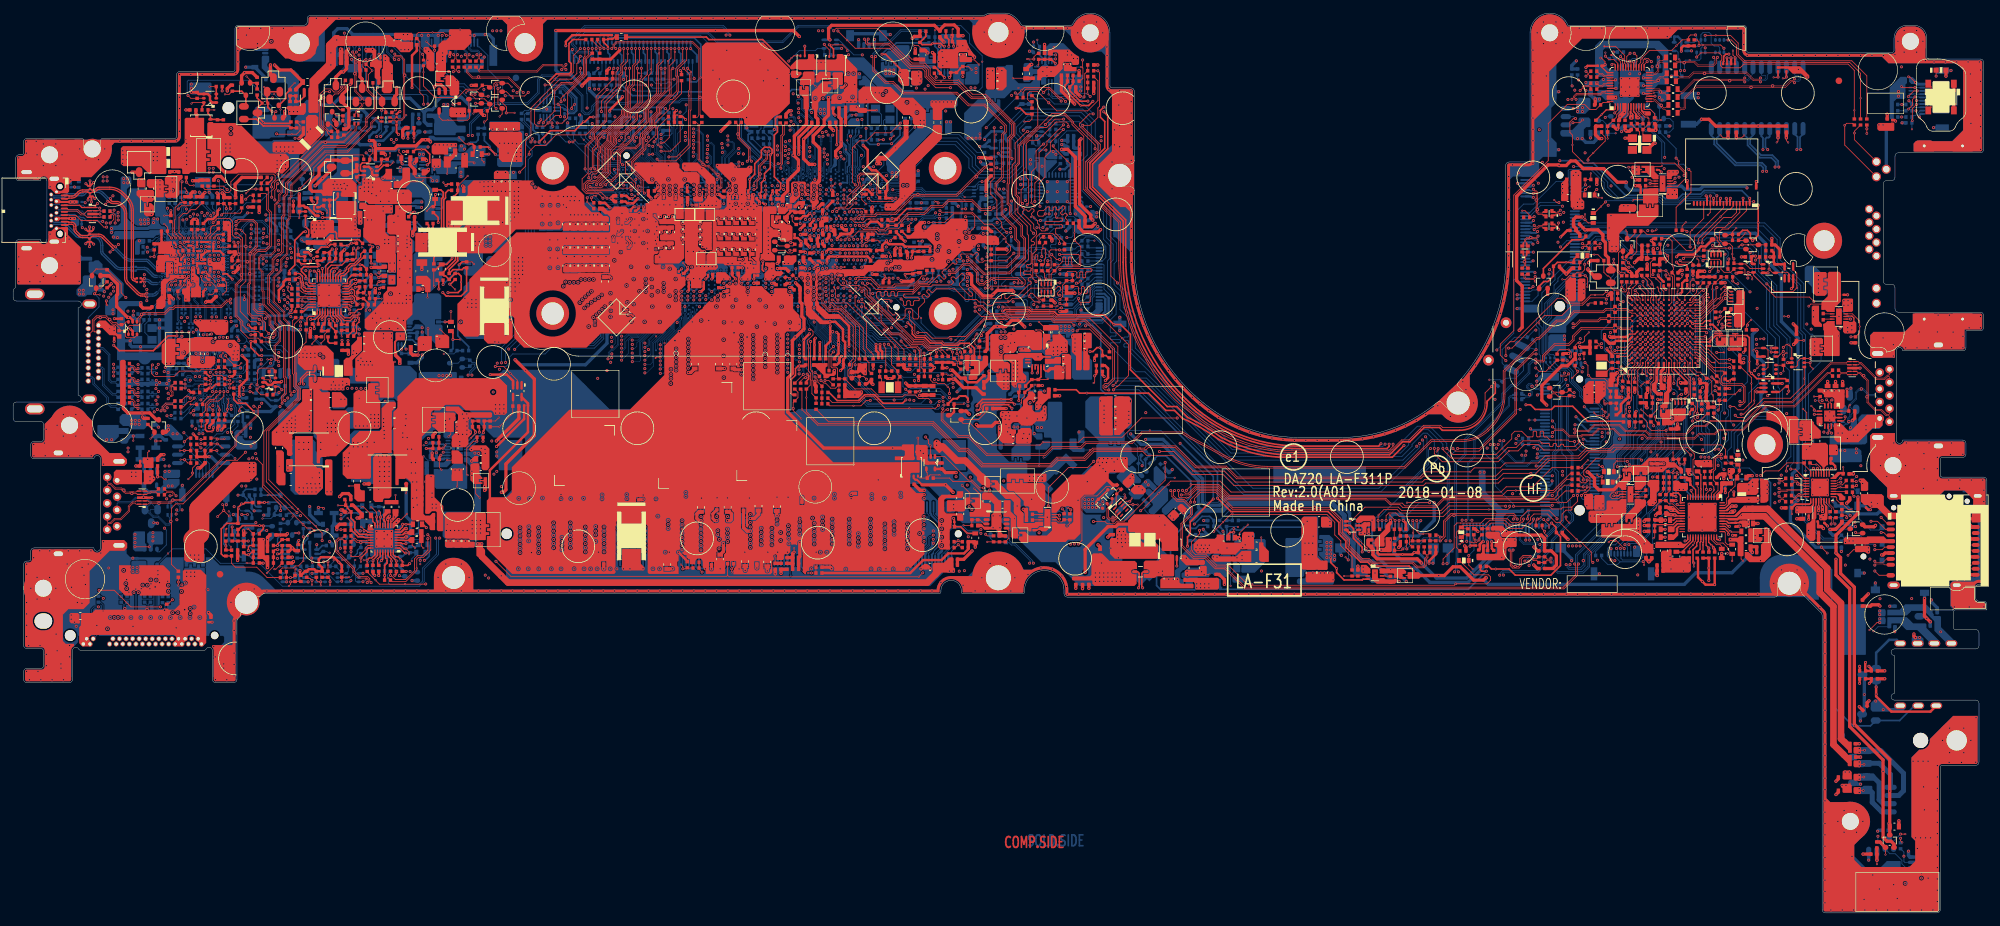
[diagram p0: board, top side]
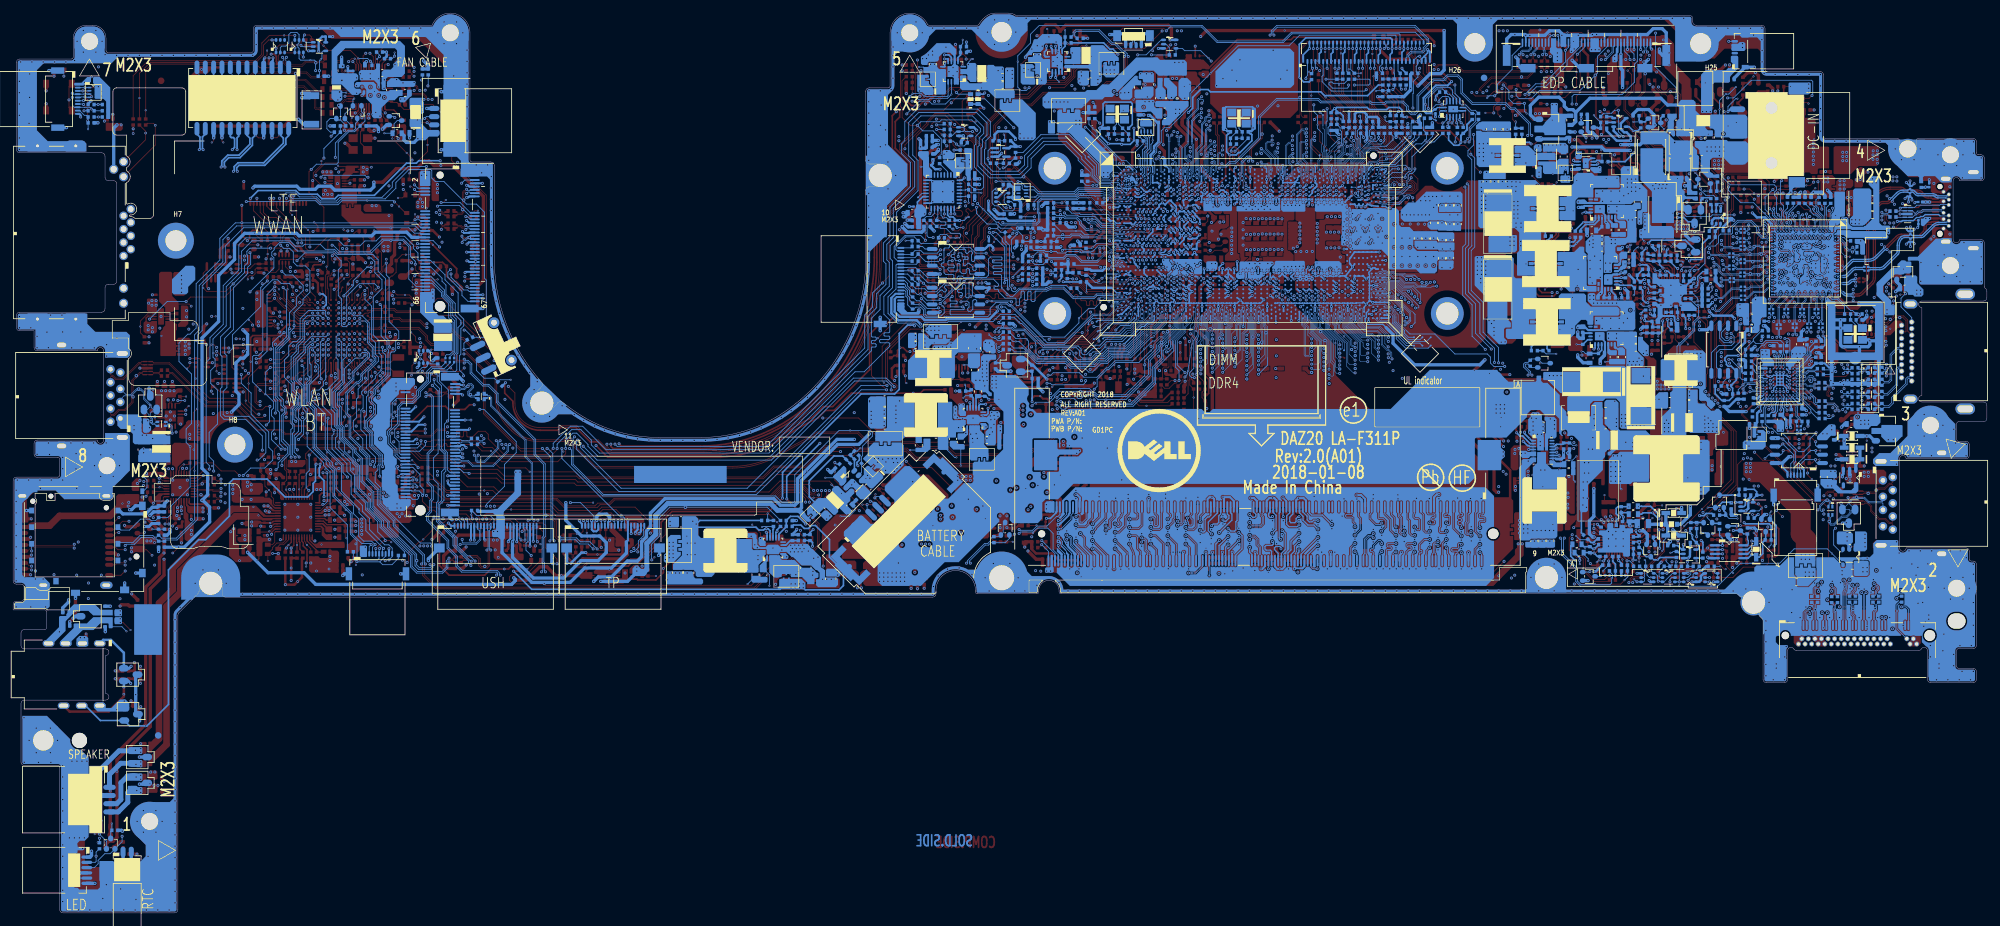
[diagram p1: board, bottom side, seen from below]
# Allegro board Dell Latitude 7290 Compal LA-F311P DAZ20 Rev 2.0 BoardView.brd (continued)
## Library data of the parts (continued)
PH601-PH605 PR1-PR8 PR10-PR12 PR14-PR18 PR24 PR27 PR28 PR30 PR102 PR103 PR107 PR108 PR113 PR116 PR117 PR204-PR207 PR209 PR212 PR302 PR306-PR308 PR310 PR311 PR403 PR404 PR407 PR408 PR410-PR422 PR424 PR427 PR428 PR501 PR505 PR506 PR514-PR517 PR601 PR604 PR605 PR608 PR610-PR613 PR615 PR617 PR618 PR621-PR623 PR626 PR628-PR636 PR638-PR653 PR656-PR658 PR666 PR668 PR670 PR671 PR673 PR675 PR677 PR678 PR681 PR686 PR689 PR692 PR918 PR919 PR925 PR927 PR930-PR934 PR940 PR944 PR945 PR948 PR950 PR953 PR961 PR1201-PR1203 PR1205-PR1210 PR1212-PR1214 PR1217 PR1219 PR1222 PR1224 PR1226-PR1237 PR1239 PR1240 PR1246-PR1249 PR1251-PR1255 PR1258-PR1262 RA5-RA9 RA12-RA14 RA17 RA18 RA44 RA45 RA50-RA53 RA57-RA61 RC1-RC7 RC10-RC12 RC14-RC17 RC19-RC23 RC25 RC27-RC32 RC39 RC42-RC48 RC50-RC52 RC54 RC56 RC57 RC59 RC60 RC65 RC67-RC69 RC71-RC75 RC77-RC84 RC86-RC96 RC109 RC110 RC112-RC115 RC120-RC124 RC126 RC128-RC141 RC152 RC153 RC157 RC161 RC163 RC165-RC168 RC175-RC178 RC183 RC184 RC186 RC187 RC189 RC190 RC211 RC214 RC215 RC217-RC220 RC222-RC225 RC227 RC234 RC237 RC239-RC241 RC243 RC267 RC268 RC272 RC278 RC279 RC282 RC283 RC287 RC288 RC291 RC292 RC297 RC298 RC311 RC313 RC316-RC319 RC323 RC324 RC330 RC331 RC338 RC344-RC349 RC362 RC363 RC366-RC369 RC371 RC372 RC387 RC400-RC403 RC405 RC407-RC415 RC417-RC420 RC431-RC433 RC436-RC438 RC440 RC442 RC443 RC445 RC550 RC553-RC556 RC560 RC561 RD4 RD6 RD8 RD11 RD14-RD19 RE5 RE8 RE10-RE12 RE20 RE21 RE25 RE26 RE31 RE33 RE35 RE37 RE38 RE43 RE48 RE51 RE55-RE58 RE60 RE63-RE65 RE67-RE75 RE77 RE79 RE83-RE86 RE91 RE92 RE94 RE95 RE274 RE280 RE288 RE292 RE300-RE304 RE306 RE308 RE312-RE314 RE324 RE340 RE342 RE343 RE349 RE350 RE362 RE365 RE375 RE505 RE507 RE508 RE526 RE532 RE539 RE541 RE543 RE546 RE547 RE549-RE551 RE560 RE561 RE565 RI13 RI14 RL1 RL2 RL4-RL6 RL9 RL11-RL20 RL29 RL30 RL70 RN37 RN100 RR3 RR4 RR19 RT1-RT8 RT10-RT39 RT41 RT42 RT50-RT53 RT64-RT69 RT71 RT74-RT76 RT81 RT82 RT84-RT86 RT89 RT90 RT95-RT98 RT100 RT101 RT103 RT106 RT107 RT110 RT111 RT124-RT129 RT336-RT339 RT371 RT372 RT377 RT391 RT393 RT400 RT401 RV1-RV8 RV10-RV23 RV26 RV29 RV32 RV35 RV324 RV326 RV400 RZ8-RZ10 RZ18-RZ23 RZ25 RZ28 RZ32 RZ38 RZ40 RZ43 RZ58-RZ60 RZ62 RZ63 RZ65 RZ69-RZ71 RZ76-RZ81 RZ114 RZ116 RZ117 RZ119 RZ132 RZ320 RZ326 RZ334 RZ335 RZ361-RZ364 RZ366 RZ367 RZ369 RZ380 RZ518 = R_0402
PJP1 PJP2 PJP4 PJP6 PJP7 PJP13 PJP15 PJP16 PJP18-PJP22 PJP35 PJP37 PJP38 PJP42 PJP201 PJP391 PJP403 PJP404 PJP501 PJP502 PJP505 PJP506 PJP603 = JUMP_43X39
PJP3 PJP8 PJP31 PJP39 PJP41 PJP102 PJP103 PJP200 PJP302 PJP601 PJP1202 = JUMP_43X118
PJP5 PJP14 PJP17 PJP36 PJP40 PJP100 PJP101 PJP202 PJP301 PJP401 PJP402 PJP602 = JUMP_43X79
PJP901 = JUMP_43X118-NPM
PJPDC1 = CVILU_CI0805M1HRC-NH_5P-T
PL1 PL2 PL4 = TAIYO_FBMJ4516HS720NT_2P
PL3 = MURAT_BLM15AG102SN1D_2P
PL100 PL101 = CYNTE_PCMC063T-1R5MN_2P
PL201 = CYNTE_PCMB063T-1R0MS_2P
PL301 = L_5X5X3_M_2P
PL402 PL404 PL501 = MAG_MLV-FY12N1R0M-O1L_2P
PL405 PL406 PL502 = 3A_Z120_0603_2P
PL602 = 9A_Z80_1812_2P-NPM
PL610 PL612 PL613 = L_7X7X3_M
PL614 = MAG_MMD05CZR47M_4P
PL901 = MAGLA_MMD-05CZ-1R0M-M7L_2P
PL902 = CYNTE_PCMB103T-2R2MS_2P
PQ1 PQ1201 PQ1204 PQ1209 PQ1214 QC2 QE2 QL1 QL2 QV3 QZ2 QZ7 = DMN65D8LDW-7_SOT363-6
PQ2 = FDV301N-G_SOT23-3
PQ3 = MMST3904-7-F_SOT323-3
PQ4 PQ9 PQ1202 PQ1206 PQ1213 = FDMC6679AZ_MLP8-5
PQ5 PQ1203 PQ1215 = NTR4502PT1G_SOT23-3
PQ6-PQ8 PQ909 PQ1205 PQ1212 PQ1216 = DMN65D8LW-7_SOT323-3
PQ614 = AON7934_DFN3X3A8-10
PQ904 = AON6970_DFN5X6D-8-7
PQ905 = AON6992_DFN5X6D-8-7
PQ906 = AON7409_DFN8-5
PQ1207 PQ1208 PQ1210 PQ1211 QT1 = DMN66D0LDW-7_SOT363-6
PR13 PR916 = R_0805
PR19-PR23 PR25 PR26 PR29 PR104 PR105 PR114 PR119 PR120 PR208 PR210 PR312 PR402 PR406 PR423 PR425 PR426 PR504 PR513 PR602 PR603 PR606 PR614 PR616 PR620 PR625 PR659 PR662 PR664 PR679 PR687 PR920 PR922 PR926 PR928 PR929 PR935 PR936 PR939 PR941 PR942 PR946 PR947 PR951 PR960 PR1211 PR1215 PR1216 PR1218 PR1220 PR1221 PR1223 PR1225 PR1238 PR1241-PR1245 PR1250 PR1257 RA35-RA39 RA48 RA54-RA56 RC33-RC38 RC40 RC41 RC62 RC170 RC171 RC173 RC212 RC221 RC228-RC231 RC235 RC244 RC290 RC296 RC300-RC308 RC325 RC328 RC337 RC373 RC374 RC376-RC378 RC439 RC441 RC444 RD5 RD7 RD9 RD12 RE30 RE32 RE59 RE90 RE275 RE290 RE318 RE506 RE536 RE548 RE552 RL3 RL7 RL34 RN99 RR5-RR10 RT9 RT40 RT54-RT60 RT63 RT70 RT72 RT73 RT83 RT87 RT88 RT92 RT93 RT99 RT104 RT105 RT108 RT109 RT120-RT123 RT341 RT342 RT392 RT394 RT402 RT403 RV323 RZ26 RZ29 RZ56 RZ61 RZ64 RZ85 RZ87 RZ89 RZ112 RZ120 RZ345-RZ347 RZ365 RZ368 = R0402_0OHM
PR100 PR111 PR203 PR304 RA3 RC143 RC169 RC216 RC299 RC309 RC310 RD10 RL8 RR274 = R0603_0OHM
PR106 PR112 PR202 PR303 PR627 PR663 PR669 PR676 PR923 PR924 = R_1206
PR405 PR409 PR502 PR619 PR624 PR660 PR661 PR665 PR667 PR672 PR674 PR680 PR688 PR691 PR909 PR910 PR914 PR915 PR921 PR937 PR938 PR943 RL71-RL78 RT48 RT49 RZ151 RZ370 = R_0603
PR682-PR684 = SOLDER_PREFORMS_0603
PR901 PR917 = R_1206_4P-D
PRP1 RPC1 RPC3 RPC4 RPE7 RPE9-RPE12 = RP_0804_8P4R
PT1 T1-T4 T9-T17 T50 T51 T88 T89 T113-T115 T120 T122 T123 T126 T127 T130 T132 T141-T144 T147 T219 T220 T225 T226 T258 T262 T264 T268 T269 T283 = TPC12
PU1 PU903 PU1200 UC7 UE3 UE5 UL2 UZ6 UZ10 UZ34 UZ35 = TC7SH08FU_SSOP5
PU2 UT8 = AP2204R-5P0TRG1_SOT89-3
PU100 = SY8288BRAC_QFN20_3X3
PU102 = SY8288CRAC_QFN20_3X3
PU200 = SY8210AQVC_QFN19_4X3
PU301 = SY8288RAC_QFN20_3X3
PU401 PU402 = SY8057QDC_QFN16_3X3
PU501 = RT8097ALGE_SOT23-6
PU503 = AP7361C-FGE-7_U-DFN3030-8_3X3
PU602 = ISL62883CHRTZ-T_TQFN40_5X5-S
PU610 PU612 PU613 = NCP302045MNTWG_PQFN33_5X5
PU614 = ISL95808HRZ-TS2378_DFN8_2X2-S
PU901 = ISL88738HRTZ-T_TQFN32_4X4
PU1201 = LM393DGKR_VSSOP8
QC6 QE11 QE12 QE17 QR1 QV2 QV4 QV5 QV7 QZ4 QZ15 = L2N7002WT1G_SC-70-3
QC7 QE15 QV8 QZ1 = LP2301ALT1G_SOT23-3
QE3-QE7 = MMBT3904WT1G_SC70-3
QV1 = AO6405_TSOP6
QZ3 = DDTA114EUA-7-F_SOT323-3
RE93 RZ128-RZ130 = R_0201
RI27-RI30 RI47-RI50 = R_0402-NPM
SHDCAN = SION_SUS304_1P-T
SW1 = SW_SS3-CMFTQR9_3P
SW3 = SW_SKRBAAE010_4P
TL1 = MHPC_NS692417_24P
UA1 = ALC3246-CG_MQFN48_6X6
UC1 = KBL-RU42_BGA_1356P-T
UC5 = W25Q128FVSIQ_SO8
UC6 = W25Q128FVSIQ_SO8-NPM
UC8 = 74CBTLV3126BQ_DHVQFN14_2P5X3-S
UC12 = 74AHC1G09GW_TSSOP5
UD1 UE4 UE6 = 74AUP1G07GW_TSSOP5
UE1 = MEC5105_WFBGA_169P
UI1 = SY6288D20AAC_SOT23-5
UI3 = SLGC55544CVTR_TQFN16_3X3
UL1 = WGI217LM-QPN9-A2_QFN48_6X6-S
UR1 = RTS5242-GR_QFN32_4X4-S
UT1 = ALPINE-RIDGE_BGA_337P
UT2 UT6 = W25Q80DVSSIG_SO8
UT5 = TPS65982_BGA_96P
UT7 = AP2112K-3P3TRG1_SOT23-5
UV2 = AP2330W-7_SC59-3
UV24 = G524B1T11U_SOT23-5
UZ2-UZ5 = TPS22966DPUR_SON14_2X3
UZ8 = AOZ1336_DFN8_2X2
UZ12 = NPCT650JB2YX_QFN32_5X5
UZ19 UZ21 UZ26 = TPS22961DNYR_WSON8
YC1 YC3 = Y_X3G024000DC1H_4P
YC2 = Y_9H03200042_2P
YE1 = Y_X1A000141000200_2P
YL1 YT1 = Y_7V25000034_4P

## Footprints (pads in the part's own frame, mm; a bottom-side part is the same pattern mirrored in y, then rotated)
1N4148WS-7-F_SOD323-2
  rect 1.346x0.66 smd: 1(0,0) 2(2.4,0)
3A_Z120_0603_2P
  rect 0.991x0.787 smd: 1(0,0) 2(1.6,0)
9A_Z80_1812_2P-NPM
  rect 1.803x3.404 smd: 1(0,0) 2(3.8,0)
74AHC1G09GW_TSSOP5
  oval 0.381x1.346 smd: 1(0,0) 2(0.65,0) 3(1.3,0) 4(1.3,1.79) 5(0,1.79)
74AUP1G07GW_TSSOP5
  oval 0.381x1.346 smd: 1(0,0) 2(0.65,0) 3(1.3,0) 4(1.3,1.79) 5(0,1.79)
74CBTLV3126BQ_DHVQFN14_2P5X3-S
  oval 1.041x0.254 smd: 1(0,0) 7(2.95,0) 8(2.95,0.5) 14(0,0.5)
  oval 0.254x1.041 smd: 2(0.475,-0.975) 3(0.975,-0.975) 4(1.475,-0.975) 5(1.975,-0.975) 6(2.475,-0.975) 9(2.475,1.475) 10(1.975,1.475) 11(1.475,1.475) 12(0.975,1.475) 13(0.475,1.475)
  rect 1.499x0.991 smd: 15(1.475,0.25)
ACES_50209-0060N-P01_6P
  oval 0.508x1.651 smd: 1(0,0) 2(0.8,0) 3(1.6,0) 4(2.4,0) 5(3.2,0) 6(4,0)
  rect 1.194x1.702 smd: 7(-1.3,-2.275) 8(5.3,-2.275)
ACES_50271-0020N-001_2P
  oval 0.787x1.6 smd: 1(0,0) 2(1.25,0)
  rect 2.108x2.997 smd: 3(3.8,-2.9) 4(-2.55,-2.9)
ACES_50271-0040N-001_4P
  oval 0.787x1.6 smd: 1(0,0) 2(-1.25,0) 3(-2.5,0) 4(-3.75,0)
  rect 2.108x2.997 smd: 5(2.55,-2.9) 6(-6.3,-2.9)
ACES_50278-0040N-001_4P
  oval 0.787x1.905 smd: 1(0,0) 2(1.25,0) 3(2.5,0) 4(3.75,0)
  rect 1.295x3.353 smd: 5(-2.85,-4.925) 6(6.6,-4.925)
ACES_50398-04041-001_40P
  oval 0.254x1.295 smd: 1(0,0) 2(0.5,0) 3(1,0) 4(1.5,0) 5(2,0) 6(2.5,0) 7(3,0) 8(3.5,0) 9(4,0) 10(4.5,0) 11(5,0) 12(5.5,0) 13(6,0) 14(6.5,0) 15(7,0) 16(7.5,0) 17(8,0) 18(8.5,0) 19(9,0) 20(9.5,0) 21(10,0) 22(10.5,0) 23(11,0) 24(11.5,0) 25(12,0) 26(12.5,0) 27(13,0) 28(13.5,0) 29(14,0) 30(14.5,0) 31(15,0) 32(15.5,0) 33(16,0) 34(16.5,0) 35(17,0) 36(17.5,0) 37(18,0) 38(18.5,0) 39(19,0) 40(19.5,0)
  rect 1.194x3.2 smd: 41(-2.4,1.95) 45(21.9,1.95)
  rect 2.311x1.295 smd: 42(0.85,3.9) 43(9.75,3.9) 44(18.65,3.9)
ACES_50506-00641-P01_6P
  oval 0.305x0.889 smd: 1(0,0) 2(0.5,0) 3(1,0) 4(1.5,0) 5(2,0) 6(2.5,0)
  rect 0.991x2.007 smd: 7(-2.1,-3.05) 8(4.6,-3.05)
ACES_50506-01041-P01_10P
  oval 0.305x0.889 smd: 1(0,0) 2(0.5,0) 3(1,0) 4(1.5,0) 5(2,0) 6(2.5,0) 7(3,0) 8(3.5,0) 9(4,0) 10(4.5,0)
  rect 0.991x2.007 smd: 11(-2.1,-3.05) 12(6.6,-3.05)
ACON_HMRBL-A41L0F_19P-T
  round 0.813 hole 0.559: 1(0,0) 2(0.5,1.55) 3(1,0) 4(1.5,1.55) 5(2,0) 6(2.5,1.55) 7(3,0) 8(3.5,1.55) 9(4,0) 10(4.5,1.55) 11(5,0) 12(5.5,1.55) 13(6,0) 14(6.5,1.55) 15(7,0) 16(7.5,1.55) 17(8,0) 18(8.5,1.55) 19(9,0)
  oval 1.397x2.21 hole 0.787x1.6: 20(11.75,0.2) 22(-2.75,0.2)
  oval 1.702x2.997 hole 1.092x2.388: 21(13.25,-8.15) 23(-4.25,-8.15)
ACON_TCRA2-9U1U93_9P-T
  round 1.295 hole 0.711: 1(0,0) 2(-2.5,0) 3(-4.5,0) 4(-7,0) 5(-7.5,-1.5) 6(-5.5,-1.5) 7(-3.5,-1.5) 8(-1.5,-1.5) 9(0.5,-1.5)
  oval 1.295x2.311 hole 0.711x1.702: 10(2.9,0.3) 12(-9.9,0.3)
  oval 1.295x2.007 hole 0.711x1.397: 11(4.2,-8.95) 13(-11.2,-8.95)
ALC3246-CG_MQFN48_6X6
  oval 0.889x0.203 smd: 1(0,0) 2(0,-0.4) 3(0,-0.8) 4(0,-1.2) 5(0,-1.6) 6(0,-2) 7(0,-2.4) 8(0,-2.8) 9(0,-3.2) 10(0,-3.6) 11(0,-4) 12(0,-4.4) 25(6.1,-4.4) 26(6.1,-4) 27(6.1,-3.6) 28(6.1,-3.2) 29(6.1,-2.8) 30(6.1,-2.4) 31(6.1,-2) 32(6.1,-1.6) 33(6.1,-1.2) 34(6.1,-0.8) 35(6.1,-0.4) 36(6.1,0)
  oval 0.203x0.889 smd: 13(0.85,-5.25) 14(1.25,-5.25) 15(1.65,-5.25) 16(2.05,-5.25) 17(2.45,-5.25) 18(2.85,-5.25) 19(3.25,-5.25) 20(3.65,-5.25) 21(4.05,-5.25) 22(4.45,-5.25) 23(4.85,-5.25) 24(5.25,-5.25) 37(5.25,0.85) 38(4.85,0.85) 39(4.45,0.85) 40(4.05,0.85) 41(3.65,0.85) 42(3.25,0.85) 43(2.85,0.85) 44(2.45,0.85) 45(2.05,0.85) 46(1.65,0.85) 47(1.25,0.85) 48(0.85,0.85)
  rect 4.394x4.394 smd: 49(3.05,-2.2)
ALPINE-RIDGE_BGA_337P
  round 0.254 smd: A1(0,0) A23(10.12,0) AA2(0.46,-9.2) AA22(9.66,-9.2) AB2(0.46,-9.66) AB3(0.92,-9.66) AB4(1.38,-9.66) AB5(1.84,-9.66) AB6(2.3,-9.66) AB7(2.76,-9.66) AB8(3.22,-9.66) AB9(3.68,-9.66) AB10(4.14,-9.66) AB11(4.6,-9.66) AB12(5.06,-9.66) AB13(5.52,-9.66) AB14(5.98,-9.66) AB15(6.44,-9.66) AB16(6.9,-9.66) AB17(7.36,-9.66) AB18(7.82,-9.66) AB19(8.28,-9.66) AB20(8.74,-9.66) AB21(9.2,-9.66) AB22(9.66,-9.66) AC1(0,-10.12) AC23(10.12,-10.12) B2(0.46,-0.46) B3(0.92,-0.46) B4(1.38,-0.46) B5(1.84,-0.46) B6(2.3,-0.46) B7(2.76,-0.46) B8(3.22,-0.46) B9(3.68,-0.46) B10(4.14,-0.46) B11(4.6,-0.46) B12(5.06,-0.46) B13(5.52,-0.46) B14(5.98,-0.46) B15(6.44,-0.46) B16(6.9,-0.46) B17(7.36,-0.46) B18(7.82,-0.46) B19(8.28,-0.46) B20(8.74,-0.46) B21(9.2,-0.46) B22(9.66,-0.46) C2(0.46,-0.92) C22(9.66,-0.92) D2(0.46,-1.38) D4(1.16,-1.16) D5(1.81,-1.16) D6(2.46,-1.16) D8(3.11,-1.16) D9(3.76,-1.16) D11(4.41,-1.16) D12(5.06,-1.16) D13(5.71,-1.16) D15(6.36,-1.16) D16(7.01,-1.16) D18(7.66,-1.16) D19(8.31,-1.16) D20(8.96,-1.16) D22(9.66,-1.38) E2(0.46,-1.84) E4(1.16,-1.81) E5(1.81,-1.81) E6(2.46,-1.81) E8(3.11,-1.81) E9(3.76,-1.81) E11(4.41,-1.81) E12(5.06,-1.81) E13(5.71,-1.81) E15(6.36,-1.81) E16(7.01,-1.81) E18(7.66,-1.81) E19(8.31,-1.81) E20(8.96,-1.81) E22(9.66,-1.84) F2(0.46,-2.3) F4(1.16,-2.46) F5(1.81,-2.46) F6(2.46,-2.46) F8(3.11,-2.46) F9(3.76,-2.46) F11(4.41,-2.46) F12(5.06,-2.46) F13(5.71,-2.46) F15(6.36,-2.46) F16(7.01,-2.46) F18(7.66,-2.46) F19(8.31,-2.46) F20(8.96,-2.46) F22(9.66,-2.3) G2(0.46,-2.76) G22(9.66,-2.76) H2(0.46,-3.22) H4(1.16,-3.11) H5(1.81,-3.11) H6(2.46,-3.11) H8(3.11,-3.11) H9(3.76,-3.11) H11(4.41,-3.11) H12(5.06,-3.11) H13(5.71,-3.11) H15(6.36,-3.11) H16(7.01,-3.11) H18(7.66,-3.11) H19(8.31,-3.11) H20(8.96,-3.11) H22(9.66,-3.22) J2(0.46,-3.68) J4(1.16,-3.76) J5(1.81,-3.76) J6(2.46,-3.76) J8(3.11,-3.76) J9(3.76,-3.76) J11(4.41,-3.76) J12(5.06,-3.76) J13(5.71,-3.76) J15(6.36,-3.76) J16(7.01,-3.76) J18(7.66,-3.76) J19(8.31,-3.76) J20(8.96,-3.76) J22(9.66,-3.68) K2(0.46,-4.14) K22(9.66,-4.14) L2(0.46,-4.6) L4(1.16,-4.41) L5(1.81,-4.41) L6(2.46,-4.41) L8(3.11,-4.41) L9(3.76,-4.41) L11(4.41,-4.41) L12(5.06,-4.41) L13(5.71,-4.41) L15(6.36,-4.41) L16(7.01,-4.41) L18(7.66,-4.41) L19(8.31,-4.41) L20(8.96,-4.41) L22(9.66,-4.6) M2(0.46,-5.06) M4(1.16,-5.06) M5(1.81,-5.06) M6(2.46,-5.06) M8(3.11,-5.06) M9(3.76,-5.06) M11(4.41,-5.06) M12(5.06,-5.06) M13(5.71,-5.06) M15(6.36,-5.06) M16(7.01,-5.06) M18(7.66,-5.06) M19(8.31,-5.06) M20(8.96,-5.06) M22(9.66,-5.06) N2(0.46,-5.52) N4(1.16,-5.71) N5(1.81,-5.71) N6(2.46,-5.71) N8(3.11,-5.71) N9(3.76,-5.71) N11(4.41,-5.71) N12(5.06,-5.71) N13(5.71,-5.71) N15(6.36,-5.71) N16(7.01,-5.71) N18(7.66,-5.71) N19(8.31,-5.71) N20(8.96,-5.71) N22(9.66,-5.52) P2(0.46,-5.98) P22(9.66,-5.98) R2(0.46,-6.44) R4(1.16,-6.36) R5(1.81,-6.36) R6(2.46,-6.36) R8(3.11,-6.36) R9(3.76,-6.36) R11(4.41,-6.36) R12(5.06,-6.36) R13(5.71,-6.36) R15(6.36,-6.36) R16(7.01,-6.36) R18(7.66,-6.36) R19(8.31,-6.36) R20(8.96,-6.36) R22(9.66,-6.44) T2(0.46,-6.9) T4(1.16,-7.01) T5(1.81,-7.01) T6(2.46,-7.01) T8(3.11,-7.01) T9(3.76,-7.01) T11(4.41,-7.01) T12(5.06,-7.01) T13(5.71,-7.01) T15(6.36,-7.01) T16(7.01,-7.01) T18(7.66,-7.01) T19(8.31,-7.01) T20(8.96,-7.01) T22(9.66,-6.9) U2(0.46,-7.36) U22(9.66,-7.36) V2(0.46,-7.82) V4(1.16,-7.66) V5(1.81,-7.66) V6(2.46,-7.66) V8(3.11,-7.66) V9(3.76,-7.66) V11(4.41,-7.66) V12(5.06,-7.66) V13(5.71,-7.66) V15(6.36,-7.66) V16(7.01,-7.66) V18(7.66,-7.66) V19(8.31,-7.66) V20(8.96,-7.66) V22(9.66,-7.82) W2(0.46,-8.28) W4(1.16,-8.31) W5(1.81,-8.31) W6(2.46,-8.31) W8(3.11,-8.31) W9(3.76,-8.31) W11(4.41,-8.31) W12(5.06,-8.31) W13(5.71,-8.31) W15(6.36,-8.31) W16(7.01,-8.31) W18(7.66,-8.31) W19(8.31,-8.31) W20(8.96,-8.31) W22(9.66,-8.28) Y2(0.46,-8.74) Y4(1.16,-8.96) Y5(1.81,-8.96) Y6(2.46,-8.96) Y8(3.11,-8.96) Y9(3.76,-8.96) Y11(4.41,-8.96) Y12(5.06,-8.96) Y13(5.71,-8.96) Y15(6.36,-8.96) Y16(7.01,-8.96) Y18(7.66,-8.96) Y19(8.31,-8.96) Y20(8.96,-8.96) Y22(9.66,-8.74)
  oval 0.178x0.33 smd: A2(0.46,0) A3(0.92,0) A4(1.38,0) A5(1.84,0) A6(2.3,0) A7(2.76,0) A8(3.22,0) A9(3.68,0) A10(4.14,0) A11(4.6,0) A12(5.06,0) A13(5.52,0) A14(5.98,0) A15(6.44,0) A16(6.9,0) A17(7.36,0) A18(7.82,0) A19(8.28,0) A20(8.74,0) A21(9.2,0) A22(9.66,0) AC2(0.46,-10.12) AC3(0.92,-10.12) AC4(1.38,-10.12) AC5(1.84,-10.12) AC6(2.3,-10.12) AC7(2.76,-10.12) AC8(3.22,-10.12) AC9(3.68,-10.12) AC10(4.14,-10.12) AC11(4.6,-10.12) AC12(5.06,-10.12) AC13(5.52,-10.12) AC14(5.98,-10.12) AC15(6.44,-10.12) AC16(6.9,-10.12) AC17(7.36,-10.12) AC18(7.82,-10.12) AC19(8.28,-10.12) AC20(8.74,-10.12) AC21(9.2,-10.12) AC22(9.66,-10.12)
  oval 0.33x0.178 smd: AA1(0,-9.2) AA23(10.12,-9.2) AB1(0,-9.66) AB23(10.12,-9.66) B1(0,-0.46) B23(10.12,-0.46) C1(0,-0.92) C23(10.12,-0.92) D1(0,-1.38) D23(10.12,-1.38) E1(0,-1.84) E23(10.12,-1.84) F1(0,-2.3) F23(10.12,-2.3) G1(0,-2.76) G23(10.12,-2.76) H1(0,-3.22) H23(10.12,-3.22) J1(0,-3.68) J23(10.12,-3.68) K1(0,-4.14) K23(10.12,-4.14) L1(0,-4.6) L23(10.12,-4.6) M1(0,-5.06) M23(10.12,-5.06) N1(0,-5.52) N23(10.12,-5.52) P1(0,-5.98) P23(10.12,-5.98) R1(0,-6.44) R23(10.12,-6.44) T1(0,-6.9) T23(10.12,-6.9) U1(0,-7.36) U23(10.12,-7.36) V1(0,-7.82) V23(10.12,-7.82) W1(0,-8.28) W23(10.12,-8.28) Y1(0,-8.74) Y23(10.12,-8.74)
AO6405_TSOP6
  oval 0.508x1.473 smd: 1(0,0) 2(0.95,0) 3(1.9,0) 4(1.9,2.35) 5(0.95,2.35) 6(0,2.35)
AON6970_DFN5X6D-8-7
  oval 0.66x0.635 smd: 1(0,0) 3(3.81,5.67) 4(2.54,5.67) 5(1.27,5.67) 6(0,5.67)
  custom 0.485x0.485 smd: 2(1.905,0.655)
  rect 3.988x2.667 smd: 7(1.905,3.62)
AON6992_DFN5X6D-8-7
  oval 0.66x0.635 smd: 1(0,0) 3(3.81,5.67) 4(2.54,5.67) 5(1.27,5.67) 6(0,5.67)
  custom 0.485x0.485 smd: 2(1.905,0.655)
  rect 3.988x2.667 smd: 7(1.905,3.62)
AON7409_DFN8-5
  oval 0.406x0.991 smd: 1(0,0) 2(0.66,0) 3(1.32,0) 4(1.98,0)
  custom 0.559x0.559 smd: 5(0.99,2.247)
AON7934_DFN3X3A8-10
  oval 0.457x0.508 smd: 1(0,0) 2(0.65,0) 3(1.3,0) 4(1.95,0) 5(1.95,2.76) 6(1.3,2.76) 7(0.65,2.76) 8(0,2.76)
  rect 2.54x1.041 smd: 9(0.975,1.813)
  rect 2.54x0.559 smd: 10(0.975,0.708)
AOZ1336_DFN8_2X2
  oval 0.254x0.787 smd: 1(0,0) 2(0.5,0) 3(1,0) 4(1.5,0) 5(1.5,2.2) 6(1,2.2) 7(0.5,2.2) 8(0,2.2)
  rect 1.499x0.889 smd: 9(0.75,1.1)
AP2112K-3P3TRG1_SOT23-5
  oval 0.508x0.965 smd: 1(0,0) 2(0.95,0) 3(1.9,0) 4(1.9,2.375) 5(0,2.375)
AP2204R-5P0TRG1_SOT89-3
  oval 0.889x1.295 smd: 1(0,0) 3(3,0)
  custom 0.433x0.433 smd: 2(1.5,1.775)
AP2330W-7_SC59-3
  oval 0.787x0.991 smd: 1(0,0) 2(-0.95,-2.4) 3(0.95,-2.4)
AP7361C-FGE-7_U-DFN3030-8_3X3
  oval 0.457x0.94 smd: 1(0,0) 2(0.65,0) 3(1.3,0) 4(1.95,0) 5(1.95,3.05) 6(1.3,3.05) 7(0.65,3.05) 8(0,3.05)
  rect 2.261x1.499 smd: 9(0.975,1.525)
AZ5125-01HPR7G_SOD523-2
  rect 0.61x0.787 smd: 1(0,0) 2(1.5,0)
AZC199-02SPR7G_SOT23-3
  oval 1.016x1.524 smd: 1(0,0) 2(0.965,2.083) 3(-0.965,2.083)
BAT54CW_SOT323-3
  oval 0.711x0.889 smd: 1(0,0) 2(-0.65,-1.9) 3(0.65,-1.9)
BELLW_80149-3221_67P
  round 1.092 hole 1.092 unplated: (-0.75,-5.275)
  round 1.6 hole 1.6 unplated: (19.25,-5.275)
  oval 0.305x1.549 smd: 1(0,0) 2(0.25,-7.55) 3(0.5,0) 4(0.75,-7.55) 5(1,0) 6(1.25,-7.55) 7(1.5,0) 8(1.75,-7.55) 9(2,0) 10(2.25,-7.55) 11(2.5,0) 12(4.75,-7.55) 13(5,0) 14(5.25,-7.55) 15(5.5,0) 16(5.75,-7.55) 17(6,0) 18(6.25,-7.55) 19(6.5,0) 20(6.75,-7.55) 21(7,0) 22(7.25,-7.55) 23(7.5,0) 24(7.75,-7.55) 25(8,0) 26(8.25,-7.55) 27(8.5,0) 28(8.75,-7.55) 29(9,0) 30(9.25,-7.55) 31(9.5,0) 32(9.75,-7.55) 33(10,0) 34(10.25,-7.55) 35(10.5,0) 36(10.75,-7.55) 37(11,0) 38(11.25,-7.55) 39(11.5,0) 40(11.75,-7.55) 41(12,0) 42(12.25,-7.55) 43(12.5,0) 44(12.75,-7.55) 45(13,0) 46(13.25,-7.55) 47(13.5,0) 48(13.75,-7.55) 49(14,0) 50(14.25,-7.55) 51(14.5,0) 52(14.75,-7.55) 53(15,0) 54(15.25,-7.55) 55(15.5,0) 56(15.75,-7.55) 57(16,0) 58(16.25,-7.55) 59(16.5,0) 60(16.75,-7.55) 61(17,0) 62(17.25,-7.55) 63(17.5,0) 64(17.75,-7.55) 65(18,0) 66(18.25,-7.55) 67(18.5,0)
  rect 1.194x2.743 smd: 68(-1.1,-0.775) 69(19.6,-0.775)
BZV55-B5V1_SOD80C2
  rect 0.889x1.6 smd: 1(0,0) 2(3.3,0)
C_0201
  rect 0.381x0.356 smd: 1(0,0) 2(0.584,0)
C_0402
  rect 0.508x0.559 smd: 1(0,0) 2(0.914,0)
C_0603
  rect 0.635x0.889 smd: 1(0,0) 2(1.397,0)
C_0805
  rect 0.813x1.397 smd: 1(0,0) 2(1.702,0)
C_1206
  rect 1.016x1.778 smd: 1(0,0) 2(2.667,0)
C_1808
  rect 1.041x2.311 smd: 1(0,0) 2(4.35,0)
C_B2
  rect 1.346x2.692 smd: 1(0,0) 2(-2.75,0)
C_D
  rect 2.388x2.896 smd: 1(0,0) 2(6.1,0)
C_D2
  rect 2.388x2.794 smd: 1(0,0) 2(6.4,0)
C_D3
  rect 2.388x2.794 smd: 1(0,0) 2(6.4,0)
C_D7
  rect 1.803x2.794 smd: 1(0,0) 2(6.5,0)
CLIP_7P7X4P2
  rect 7.696x4.191 smd: 1(0,0)
CLIP_14P0X2P6
  rect 13.995x2.591 smd: 1(0,0)
CVILU_CF4218FH0R0-05-NH_18P-T
  oval 0.305x0.787 smd: 1(0,0) 2(0.5,0) 3(1,0) 4(1.5,0) 5(2,0) 6(2.5,0) 7(3,0) 8(3.5,0) 9(4,0) 10(4.5,0) 11(5,0) 12(5.5,0) 13(6,0) 14(6.5,0) 15(7,0) 16(7.5,0) 17(8,0) 18(8.5,0)
  rect 0.406x0.787 smd: 19(-1,-2.5) 20(9.5,-2.5)
CVILU_CF5020FD0R0-05-NH_20P
  oval 0.305x1.092 smd: 1(0,0) 2(0.5,0) 3(1,0) 4(1.5,0) 5(2,0) 6(2.5,0) 7(3,0) 8(3.5,0) 9(4,0) 10(4.5,0) 11(5,0) 12(5.5,0) 13(6,0) 14(6.5,0) 15(7,0) 16(7.5,0) 17(8,0) 18(8.5,0) 19(9,0) 20(9.5,0)
  rect 0.991x2.007 smd: 21(-2.1,-3.15) 22(11.6,-3.15)
CVILU_CF5020FD0RK-05-NH_20P-T
  oval 0.305x0.94 smd: 1(0,0) 2(0.5,0) 3(1,0) 4(1.5,0) 5(2,0) 6(2.5,0) 7(3,0) 8(3.5,0) 9(4,0) 10(4.5,0) 11(5,0) 12(5.5,0) 13(6,0) 14(6.5,0) 15(7,0) 16(7.5,0) 17(8,0) 18(8.5,0) 19(9,0) 20(9.5,0)
  rect 1.651x1.397 smd: 21(-2.325,-3.375) 22(11.825,-3.375)
CVILU_CF5026FD0RK-05-NH_26P-T
  oval 0.305x0.94 smd: 1(0,0) 2(0.5,0) 3(1,0) 4(1.5,0) 5(2,0) 6(2.5,0) 7(3,0) 8(3.5,0) 9(4,0) 10(4.5,0) 11(5,0) 12(5.5,0) 13(6,0) 14(6.5,0) 15(7,0) 16(7.5,0) 17(8,0) 18(8.5,0) 19(9,0) 20(9.5,0) 21(10,0) 22(10.5,0) 23(11,0) 24(11.5,0) 25(12,0) 26(12.5,0)
  rect 1.651x1.397 smd: 27(14.825,-3.375) 28(-2.325,-3.375)
CVILU_CI0805M1HRC-NH_5P-T
  round 1.803 hole 1.803 unplated: (-0.2,5.2) (8.2,5.2)
  oval 0.889x2.388 smd: 1(0,0) 2(2,0) 3(4,0) 4(6,0) 5(8,0)
  rect 1.6x2.489 smd: 6(11.15,9.05) 7(-3.15,9.05)
CVILU_CI1804M1VRA-NH_4P
  oval 0.508x0.991 smd: 1(0,-0.05) 2(-0.8,-0.05) 3(-1.6,-0.05) 4(-2.4,-0.05)
  rect 1.194x1.702 smd: 5(-3.7,1.4) 6(1.3,1.4)
CYNTE_PCMB063T-1R0MS_2P
  rect 2.362x3.505 smd: 1(0,0) 2(6.05,0)
CYNTE_PCMB103T-2R2MS_2P
  rect 3.81x3.988 smd: 1(0,0) 2(9.2,0)
CYNTE_PCMC063T-1R5MN_2P
  rect 2.159x3.505 smd: 1(0,0) 2(5.85,0)
DB3J315E0L_SMINI3-F2-B3
  oval 0.889x0.787 smd: 1(0,0) 2(-0.65,-1.9) 3(0.65,-1.9)
DDTA114EUA-7-F_SOT323-3
  oval 0.813x0.914 smd: 1(0,0) 2(0.65,1.6) 3(-0.65,1.6)
DEREN_40-42251-01001RHF_10P-T
  oval 0.838x2.21 smd: 1(0,0.1) 2(1.5,0.1) 3(3,0.1) 4(4.5,0.1) 5(6,0.1) 6(7.5,0.1) 7(9,0.1) 8(10.5,0.1) 9(12,0.1) 10(13.5,0.1)
  custom 0.75x0.75 smd: 11(-3.4,-3.15) 12(16.9,-3.15)
DFLS160-7_POWERDI123-2
  rect 2.21x1.397 smd: 1(0,0)
  rect 0.889x1.397 smd: 2(-2.55,0)
DMN65D8LDW-7_SOT363-6
  oval 0.432x0.61 smd: 1(0,0) 2(0.65,0) 3(1.3,0) 4(1.3,1.9) 5(0.65,1.9) 6(0,1.9)
DMN65D8LW-7_SOT323-3
  oval 0.711x0.889 smd: 1(0,0) 2(-0.65,-1.9) 3(0.65,-1.9)
DMN66D0LDW-7_SOT363-6
  oval 0.432x0.61 smd: 1(0,0) 2(0.65,0) 3(1.3,0) 4(1.3,1.9) 5(0.65,1.9) 6(0,1.9)
E-T_4251K-F06N-40L_6P
  oval 0.406x0.991 smd: 1(0,0) 2(0.6,0) 3(1.2,0) 4(1.8,0) 5(2.4,0) 6(3,0)
  rect 0.711x1.041 smd: 7(3.95,-1.575) 8(-0.95,-1.575)
ESD8011MUT5G_X3DFN2-2-S
  rect 0.33x0.356 smd: 1(0,0) 2(0.43,0)
FDMC6679AZ_MLP8-5
  oval 0.432x0.711 smd: 1(0,0) 2(0.65,0) 3(1.3,0) 4(1.95,0)
  custom 0.537x0.537 smd: 5(0.975,2.075)
FDV301N-G_SOT23-3
  oval 1.016x1.524 smd: 1(0,0) 2(0.965,2.083) 3(-0.965,2.083)
FIDUCIAL_C40M80
  round 1.016 smd: 1(0,0)
G524B1T11U_SOT23-5
  oval 0.533x1.194 smd: 1(0,0) 2(0.95,0) 3(1.9,0) 4(1.9,3) 5(0,3)
H_1P0N
  round 0.991 hole 0.991 unplated: (0,0)
H_2P3N
  round 2.311 hole 2.311 unplated: (0,0)
H_2P3X2P7N
  oval 2.311x2.692 hole 2.311x2.692 unplated: (0,0)
H_2P6-G
  round 3.099 hole 2.591: 1(0,0)
H_3P1-G
  round 3.607 hole 3.099: 1(0,0)
H_3P2
  round 3.708 hole 3.2: 1(0,0)
H_3P4
  round 3.912 hole 3.404: 1(0,0)
H_3P5-G
  round 4.013 hole 3.505: 1(0,0)
H_3P8-G
  round 4.318 hole 3.81: 1(0,0)
HB_A531015-SCHR21_10P
  oval 0.305x0.889 smd: 1(0,0) 2(0.5,0) 3(1,0) 4(1.5,0) 5(2,0) 6(2.5,0) 7(3,0) 8(3.5,0) 9(4,0) 10(4.5,0)
  rect 0.991x2.007 smd: 11(6.6,-3.05) 12(-2.1,-3.05)
INPAQ_HCM1012GH900BP_4P
  rect 0.711x0.305 smd: 1(0,0) 2(1.25,0) 3(1.25,-0.5) 4(0,-0.5)
INPAQ_MCM1012B900F06BP_4P
  rect 0.711x0.305 smd: 1(0,0) 2(1.25,0) 3(1.25,-0.5) 4(0,-0.5)
ISL62883CHRTZ-T_TQFN40_5X5-S
  oval 0.203x0.991 smd: 1(0,0) 2(0.4,0) 3(0.8,0) 4(1.2,0) 5(1.6,0) 6(2,0) 7(2.4,0) 8(2.8,0) 9(3.2,0) 10(3.6,0) 21(3.6,4.95) 22(3.2,4.95) 23(2.8,4.95) 24(2.4,4.95) 25(2,4.95) 26(1.6,4.95) 27(1.2,4.95) 28(0.8,4.95) 29(0.4,4.95) 30(0,4.95)
  oval 0.991x0.203 smd: 11(4.275,0.675) 12(4.275,1.075) 13(4.275,1.475) 14(4.275,1.875) 15(4.275,2.275) 16(4.275,2.675) 17(4.275,3.075) 18(4.275,3.475) 19(4.275,3.875) 20(4.275,4.275) 31(-0.675,4.275) 32(-0.675,3.875) 33(-0.675,3.475) 34(-0.675,3.075) 35(-0.675,2.675) 36(-0.675,2.275) 37(-0.675,1.875) 38(-0.675,1.475) 39(-0.675,1.075) 40(-0.675,0.675)
  rect 3.505x3.505 smd: 41(1.8,2.475)
ISL88738HRTZ-T_TQFN32_4X4
  oval 0.889x0.203 smd: 1(0,0) 2(0,-0.4) 3(0,-0.8) 4(0,-1.2) 5(0,-1.6) 6(0,-2) 7(0,-2.4) 8(0,-2.8) 17(4.1,-2.8) 18(4.1,-2.4) 19(4.1,-2) 20(4.1,-1.6) 21(4.1,-1.2) 22(4.1,-0.8) 23(4.1,-0.4) 24(4.1,0)
  oval 0.203x0.889 smd: 9(0.65,-3.45) 10(1.05,-3.45) 11(1.45,-3.45) 12(1.85,-3.45) 13(2.25,-3.45) 14(2.65,-3.45) 15(3.05,-3.45) 16(3.45,-3.45) 25(3.45,0.65) 26(3.05,0.65) 27(2.65,0.65) 28(2.25,0.65) 29(1.85,0.65) 30(1.45,0.65) 31(1.05,0.65) 32(0.65,0.65)
  rect 2.692x2.692 smd: 33(2.05,-1.4)
ISL95808HRZ-TS2378_DFN8_2X2-S
  oval 0.254x0.787 smd: 1(0,0) 2(0.5,0) 3(1,0) 4(1.5,0) 5(1.5,2.2) 6(1,2.2) 7(0.5,2.2) 8(0,2.2)
  rect 1.549x0.889 smd: 9(0.75,1.1)
JAE_DX07B024XJ1R1300_24P
  round 0.787 hole 0.787 unplated: (-0.85,-0.66)
  oval 0.94x0.787 hole 0.94x0.787 unplated: (6.35,-0.66)
  oval 1.092x1.956 hole 0.61x1.448: 1(-2.05,-1.535) 2(7.55,-1.535)
  oval 1.092x2.388 hole 0.61x1.6: 3(-3.05,-5.76) 4(8.55,-5.76)
  oval 0.305x1.092 smd: A1(0,0) A2(0.5,0) A3(1,0) A4(1.5,0) A5(2,0) A6(2.5,0) A7(3,0) A8(3.5,0) A9(4,0) A10(4.5,0) A11(5,0) A12(5.5,0)
  round 0.61 hole 0.406: B1(5.55,-1.21) B2(5.15,-2.01) B3(4.35,-2.01) B4(4.1,-1.21) B5(3.55,-2.01) B6(3.15,-1.21) B7(2.35,-1.21) B8(1.95,-2.01) B9(1.4,-1.21) B10(1.15,-2.01) B11(0.35,-2.01) B12(-0.05,-1.21)
JAE_SF51S006V4DR1000Q_8P
  round 0.762 hole 0.762 unplated: (-2.19,-10.215)
  round 0.889 hole 0.889 unplated: (7.01,2.835)
  rect 0.991x0.838 smd: 1(10.765,-9.44)
  rect 0.889x0.61 smd: 2(-2.94,3.715)
  custom 0.311x0.311 smd: 3(-3.39,-13.165)
  rect 1.245x1.397 smd: 4(-3.39,-5.165)
  rect 1.295x1.016 smd: 5(-0.715,3.725) 6(9.535,3.725)
  rect 1.041x1.397 smd: 7(12.1,1.025)
  rect 0.94x1.397 smd: 8(12.55,-6.465)
  rect 1.219x1.143 smd: 9(10.795,-13.49)
  rect 0.889x0.762 smd: C1(0,0) C2(2.54,0) C3(5.08,0) C4(7.62,0) C5(0,-13.15) C6(2.54,-13.15) C7(5.08,-13.15) C8(7.62,-13.15)
JUMP_43X39
  custom 0.191x0.191 smd: 1(0,0) 2(0.914,0)
JUMP_43X79
  custom 0.188x0.188 smd: 1(0,0) 2(1.1,0)
JUMP_43X118
  custom 0.187x0.187 smd: 1(0,0) 2(1.1,0)
JUMP_43X118-NPM
  custom 0.187x0.187 smd: 1(0,0) 2(1.1,0)
JXT_FP270H-061G1AM_61P
  oval 0.305x0.787 smd: 1(0,0) 3(0.6,0) 5(1.2,0) 7(1.8,0) 9(2.4,0) 11(3,0) 13(3.6,0) 15(4.2,0) 17(4.8,0) 19(5.4,0) 21(6,0) 23(6.6,0) 25(7.2,0) 27(7.8,0) 29(8.4,0) 31(9,0) 33(9.6,0) 35(10.2,0) 37(10.8,0) 39(11.4,0) 41(12,0) 43(12.6,0) 45(13.2,0) 47(13.8,0) 49(14.4,0) 51(15,0) 53(15.6,0) 55(16.2,0) 57(16.8,0) 59(17.4,0) 61(18,0)
  oval 0.305x0.66 smd: 2(0.3,2.875) 4(0.9,2.875) 6(1.5,2.875) 8(2.1,2.875) 10(2.7,2.875) 12(3.3,2.875) 14(3.9,2.875) 16(4.5,2.875) 18(5.1,2.875) 20(5.7,2.875) 22(6.3,2.875) 24(6.9,2.875) 26(7.5,2.875) 28(8.1,2.875) 30(8.7,2.875) 32(9.3,2.875) 34(9.9,2.875) 36(10.5,2.875) 38(11.1,2.875) 40(11.7,2.875) 42(12.3,2.875) 44(12.9,2.875) 46(13.5,2.875) 48(14.1,2.875) 50(14.7,2.875) 52(15.3,2.875) 54(15.9,2.875) 56(16.5,2.875) 58(17.1,2.875) 60(17.7,2.875)
  rect 0.305x1.143 smd: 62(-0.65,0.375) 63(18.65,0.375)
KBL-RU42_BGA_1356P-T
  round 0.356 smd: A3(-0.965,0) A70(-40.166,0) B2(-0.483,0.483) B71(-40.629,0.462) BA1(0,22.166) BA71(-40.629,22.166) BB2(-0.462,22.628) BB70(-40.166,22.628) C1(0,0.965)
  round 0.33 smd: A4(-1.615,0) A69(-39.516,0) AY1(0,21.516) AY71(-40.629,21.516) B3(-1.118,0.635) B70(-39.999,0.63) BA2(-0.629,21.999) BA70(-39.999,21.999) BB3(-1.113,22.628) BB69(-39.516,22.628) C2(-0.635,1.118) C71(-40.629,1.113) D1(0,1.615)
  round 0.305 smd: A5(-2.266,0) A68(-38.866,0) AA2(-0.975,10.804) AA4(-1.951,10.804) AA63(-35.427,10.719) AA64(-36.077,10.719) AA65(-36.727,10.719) AA66(-37.377,10.719) AA67(-38.028,10.719) AA68(-38.678,10.719) AA69(-39.328,10.719) AA70(-39.978,10.719) AA71(-40.629,10.719) AB4(-1.951,11.467) AB6(-2.729,11.181) AB7(-3.379,11.181) AB8(-4.029,11.181) AB9(-4.679,11.181) AB10(-5.33,11.181) AB11(-5.98,11.181) AB12(-6.63,11.181) AB13(-7.28,11.181) AB15(-8.126,11.305) AB16(-8.776,11.305) AB17(-9.426,11.305) AB18(-10.077,11.305) AB19(-10.727,11.305) AB20(-11.377,11.305) AB21(-12.027,11.305) AB62(-34.958,11.176) AC3(-1.626,12.13) AC63(-35.427,11.633) AC64(-36.077,11.633) AC65(-36.727,11.633) AC66(-37.377,11.633) AC67(-38.028,11.633) AC68(-38.678,11.633) AC69(-39.328,11.633) AC70(-39.978,11.633) AC71(-40.629,11.633) AD4(-1.951,12.792) AD6(-2.729,12.248) AD7(-3.379,12.248) AD8(-4.029,12.248) AD9(-4.679,12.248) AD10(-5.33,12.248) AD11(-5.98,12.248) AD12(-6.63,12.248) AD13(-7.28,12.248) AD15(-8.126,12.143) AD16(-8.776,12.143) AD17(-9.426,12.143) AD18(-10.077,12.143) AD19(-10.727,12.143) AD20(-11.377,12.143) AD21(-12.027,12.143) AD62(-34.958,12.09) AE62(-34.958,13.005) AE63(-35.427,12.547) AE64(-36.077,12.547) AE65(-36.727,12.547) AE66(-37.377,12.547) AE67(-38.028,12.547) AE68(-38.678,12.547) AE69(-39.328,12.547) AF2(-0.975,13.455) AF4(-1.951,13.455) AF6(-2.729,13.315) AF7(-3.379,13.315) AF8(-4.029,13.315) AF9(-4.679,13.315) AF10(-5.33,13.315) AF11(-5.98,13.315) AF12(-6.63,13.315) AF13(-7.28,13.315) AF15(-8.126,12.982) AF16(-8.776,12.982) AF17(-9.426,12.982) AF18(-10.077,12.982) AF19(-10.727,12.982) AF20(-11.377,12.982) AF21(-12.027,12.982) AF63(-35.427,13.462) AF64(-36.077,13.462) AF65(-36.727,13.462) AF66(-37.377,13.462) AF67(-38.028,13.462) AF68(-38.678,13.253) AF69(-39.328,13.253) AG4(-1.951,14.118) AG15(-8.126,13.82) AG16(-8.776,13.82) AG17(-9.426,13.82) AG18(-10.077,13.82) AG19(-10.727,13.82) AG20(-11.377,13.82) AG21(-12.027,13.82) AG62(-34.958,13.919) AG69(-39.003,13.916) AH3(-1.626,14.781) AH6(-2.729,14.381) AH7(-3.379,14.381) AH8(-4.029,14.381) AH9(-4.679,14.381) AH10(-5.33,14.381) AH11(-5.98,14.381) AH12(-6.63,14.381) AH13(-7.28,14.381) AH63(-35.427,14.376) AH64(-36.077,14.376) AH65(-36.727,14.376) AH66(-37.377,14.376) AH67(-38.028,14.376) AJ4(-1.951,15.444) AJ15(-8.126,14.658) AJ16(-8.776,14.658) AJ17(-9.426,14.658) AJ18(-10.077,14.658) AJ19(-10.727,14.658) AJ20(-11.377,14.658) AJ21(-12.027,14.658) AJ62(-34.958,14.833) AK6(-2.729,15.321) AK7(-3.379,15.321) AK8(-4.029,15.321) AK9(-4.679,15.321) AK10(-5.33,15.321) AK11(-5.98,15.321) AK12(-6.63,15.321) AK13(-7.28,15.321) AK15(-8.126,15.496) AK16(-8.776,15.496) AK17(-9.426,15.496) AK18(-10.077,15.496) AK19(-10.727,15.496) AK20(-11.377,15.496) AK21(-12.027,15.496) AK22(-12.719,15.323) AK23(-13.633,15.323) AK25(-14.547,15.323) AK27(-15.462,15.323) AK28(-16.376,15.323) AK30(-17.291,15.323) AK32(-18.205,15.323) AK33(-19.119,15.323) AK35(-20.034,15.323) AK37(-20.948,15.323) AK38(-21.863,15.323) AK40(-22.777,15.323) AK42(-23.691,15.323) AK43(-24.606,15.323) AK45(-25.52,15.323) AK46(-26.435,15.323) AK48(-27.349,15.323) AK50(-28.263,15.323) AK52(-29.178,15.323) AK53(-30.092,15.323) AK55(-31.007,15.323) AK56(-31.921,15.323) AK58(-32.835,15.323) AK60(-33.75,15.323) AK62(-34.774,15.458) AK63(-35.427,15.291) AK64(-36.077,15.291) AK65(-36.727,15.291) AK66(-37.377,15.291) AK67(-38.028,15.291) AK68(-38.678,15.143) AK69(-39.653,15.143) AL2(-0.975,16.107) AL4(-1.951,16.107) AL23(-13.176,15.788) AL25(-14.09,15.788) AL27(-15.005,15.788) AL28(-15.919,15.788) AL30(-16.833,15.788) AL32(-17.748,15.788) AL33(-18.662,15.788) AL35(-19.577,15.788) AL37(-20.491,15.788) AL38(-21.405,15.788) AL40(-22.32,15.788) AL42(-23.234,15.788) AL43(-24.149,15.788) AL45(-25.063,15.788) AL46(-25.977,15.788) AL48(-26.892,15.788) AL50(-27.806,15.788) AL52(-28.721,15.788) AL53(-29.635,15.788) AL55(-30.549,15.788) AL56(-31.464,15.788) AL58(-32.378,15.788) AL60(-33.293,15.788) AL61(-34.207,15.788) AL63(-35.427,16.159) AL64(-36.077,16.159) AL65(-36.727,16.159) AL66(-37.377,16.159) AM4(-1.951,16.77) AM5(-2.66,16.261) AM7(-3.575,16.261) AM8(-4.489,16.261) AM10(-5.403,16.261) AM11(-6.318,16.261) AM13(-7.232,16.261) AM15(-8.147,16.261) AM16(-9.061,16.261) AM18(-9.975,16.261) AM20(-10.89,16.261) AM21(-11.804,16.261) AM22(-12.719,16.261) AM23(-13.633,16.261) AM25(-14.547,16.261) AM27(-15.462,16.261) AM28(-16.376,16.261) AM30(-17.291,16.261) AM32(-18.205,16.261) AM33(-19.119,16.261) AM35(-20.034,16.261) AM37(-20.948,16.261) AM38(-21.863,16.261) AM40(-22.777,16.261) AM42(-23.691,16.261) AM43(-24.606,16.261) AM45(-25.52,16.261) AM46(-26.435,16.261) AM48(-27.349,16.261) AM50(-28.263,16.261) AM52(-29.178,16.261) AM53(-30.092,16.261) AM55(-31.007,16.261) AM56(-31.921,16.261) AM58(-32.835,16.261) AM60(-33.75,16.261) AM61(-34.664,16.261) AM68(-38.353,16.37) AM69(-39.003,16.37) AN3(-1.626,17.433) AN5(-2.66,16.911) AN7(-3.575,16.911) AN8(-4.489,16.911) AN10(-5.403,16.911) AN11(-6.318,16.911) AN13(-7.232,16.911) AN15(-8.147,16.911) AN16(-9.061,16.911) AN18(-9.975,16.911) AN20(-10.89,16.911) AN21(-11.804,16.911) AN22(-12.719,16.911) AN23(-13.633,16.911) AN25(-14.547,16.911) AN27(-15.462,16.911) AN28(-16.376,16.911) AN30(-17.291,16.911) AN32(-18.205,16.911) AN33(-19.119,16.911) AN35(-20.034,16.911) AN37(-20.948,16.911) AN38(-21.863,16.911) AN40(-22.777,16.911) AN42(-23.691,16.911) AN43(-24.606,16.911) AN45(-25.52,16.911) AN46(-26.435,16.911) AN48(-27.349,16.911) AN50(-28.263,16.911) AN52(-29.178,16.911) AN53(-30.092,16.911) AN55(-31.007,16.911) AN56(-31.921,16.911) AN58(-32.835,16.911) AN60(-33.75,16.911) AN61(-34.664,16.911) AN63(-35.579,16.911) AN65(-36.493,16.911) AN66(-37.407,16.911) AN68(-38.678,17.033) AN69(-39.328,17.033) AP4(-1.951,18.096) AP5(-2.66,17.561) AP7(-3.575,17.561) AP8(-4.489,17.561) AP10(-5.403,17.561) AP11(-6.318,17.561) AP13(-7.232,17.561) AP15(-8.147,17.561) AP16(-9.061,17.561) AP18(-9.975,17.561) AP20(-10.89,17.561) AP21(-11.804,17.561) AP22(-12.719,17.561) AP23(-13.633,17.561) AP25(-14.547,17.561) AP27(-15.462,17.561) AP28(-16.376,17.561) AP30(-17.291,17.561) AP32(-18.205,17.561) AP33(-19.119,17.561) AP35(-20.034,17.561) AP37(-20.948,17.561) AP38(-21.863,17.561) AP40(-22.777,17.561) AP42(-23.691,17.561) AP43(-24.606,17.561) AP45(-25.52,17.561) AP46(-26.435,17.561) AP48(-27.349,17.561) AP50(-28.263,17.561) AP52(-29.178,17.561) AP53(-30.092,17.561) AP55(-31.007,17.561) AP56(-31.921,17.561) AP58(-32.835,17.561) AP60(-33.75,17.561) AP61(-34.664,17.561) AP63(-35.579,17.561) AP65(-36.493,17.561) AP66(-37.407,17.561) AP68(-38.353,17.646) AP70(-39.572,17.646) AR5(-2.66,18.211) AR7(-3.575,18.211) AR8(-4.489,18.211) AR10(-5.403,18.211) AR11(-6.318,18.211) AR13(-7.232,18.211) AR15(-8.147,18.211) AR16(-9.061,18.211) AR18(-9.975,18.211) AR20(-10.89,18.211) AR21(-11.804,18.211) AR22(-12.719,18.211) AR23(-13.633,18.211) AR25(-14.547,18.211) AR27(-15.462,18.211) AR28(-16.376,18.211) AR30(-17.291,18.211) AR32(-18.205,18.211) AR33(-19.119,18.211) AR35(-20.034,18.211) AR37(-20.948,18.211) AR38(-21.863,18.211) AR40(-22.777,18.211) AR42(-23.691,18.211) AR43(-24.606,18.211) AR45(-25.52,18.211) AR46(-26.435,18.211) AR48(-27.349,18.211) AR50(-28.263,18.211) AR52(-29.178,18.211) AR53(-30.092,18.211) AR55(-31.007,18.211) AR56(-31.921,18.211) AR58(-32.835,18.211) AR60(-33.75,18.211) AR61(-34.664,18.211) AR63(-35.579,18.211) AR65(-36.493,18.211) AR66(-37.407,18.211) AR68(-38.678,18.26) AR69(-39.328,18.26) AT2(-0.975,18.759) AT4(-1.951,18.759) AT5(-2.66,18.862) AT7(-3.575,18.862) AT8(-4.489,18.862) AT10(-5.403,18.862) AT11(-6.318,18.862) AT13(-7.232,18.862) AT15(-8.147,18.862) AT16(-9.061,18.862) AT18(-9.975,18.862) AT20(-10.89,18.862) AT21(-11.804,18.862) AT22(-12.719,18.862) AT23(-13.633,18.862) AT25(-14.547,18.862) AT27(-15.462,18.862) AT28(-16.376,18.862) AT30(-17.291,18.862) AT32(-18.205,18.862) AT33(-19.119,18.862) AT35(-20.034,18.862) AT37(-20.948,18.862) AT38(-21.863,18.862) AT40(-22.777,18.862) AT42(-23.691,18.862) AT43(-24.606,18.862) AT45(-25.52,18.862) AT46(-26.435,18.862) AT48(-27.349,18.862) AT50(-28.263,18.862) AT52(-29.178,18.862) AT53(-30.092,18.862) AT55(-31.007,18.862) AT56(-31.921,18.862) AT58(-32.835,18.862) AT60(-33.75,18.862) AT61(-34.664,18.862) AT63(-35.579,18.862) AT65(-36.493,18.862) AT66(-37.407,18.862) AT68(-38.353,18.823) AT69(-39.003,18.823) AU4(-1.951,19.422) AU5(-2.66,19.512) AU7(-3.575,19.512) AU8(-4.489,19.512) AU10(-5.403,19.512) AU11(-6.318,19.512) AU13(-7.232,19.512) AU15(-8.147,19.512) AU16(-9.061,19.512) AU18(-9.975,19.512) AU20(-10.89,19.512) AU21(-11.804,19.512) AU22(-12.719,19.512) AU23(-13.633,19.512) AU25(-14.547,19.512) AU27(-15.462,19.512) AU28(-16.376,19.512) AU30(-17.291,19.512) AU32(-18.205,19.512) AU33(-19.119,19.512) AU35(-20.034,19.512) AU37(-20.948,19.512) AU38(-21.863,19.512) AU40(-22.777,19.512) AU42(-23.691,19.512) AU43(-24.606,19.512) AU45(-25.52,19.512) AU46(-26.435,19.512) AU48(-27.349,19.512) AU50(-28.263,19.512) AU52(-29.178,19.512) AU53(-30.092,19.512) AU55(-31.007,19.512) AU56(-31.921,19.512) AU58(-32.835,19.512) AU60(-33.75,19.512) AU61(-34.664,19.512) AU63(-35.579,19.512) AU65(-36.493,19.512) AU66(-37.407,19.512) AV3(-1.626,20.113) AV68(-38.343,20.026) AV69(-39.328,20.215) AV70(-39.978,20.215) AW1(0,20.866) AW5(-2.534,20.226) AW6(-3.184,20.353) AW7(-3.75,20.678) AW8(-4.328,20.353) AW9(-4.898,20.678) AW10(-5.561,20.353) AW11(-6.171,20.678) AW12(-6.749,20.353) AW13(-7.319,20.678) AW14(-7.982,20.353) AW15(-8.592,20.678) AW16(-9.17,20.353) AW17(-9.74,20.678) AW18(-10.403,20.353) AW20(-11.012,20.678) AW21(-11.59,20.353) AW22(-12.16,20.678) AW23(-12.849,20.353) AW25(-13.486,20.678) AW26(-14.05,20.353) AW27(-14.713,20.678) AW28(-15.326,20.353) AW29(-15.94,20.678) AW30(-16.603,20.353) AW31(-17.167,20.678) AW32(-17.83,20.353) AW33(-18.467,20.678) AW34(-19.031,20.353) AW35(-19.694,20.678) AW36(-20.307,20.353) AW37(-20.921,20.678) AW38(-21.584,20.353) AW39(-22.148,20.678) AW41(-22.785,20.353) AW42(-23.423,20.678) AW43(-23.986,20.353) AW44(-24.649,20.678) AW45(-25.263,20.353) AW46(-25.876,20.678) AW47(-26.477,20.353) AW48(-27.041,20.678) AW49(-27.669,20.353) AW50(-28.298,20.678) AW51(-28.862,20.353) AW52(-29.463,20.678) AW53(-30.076,20.353) AW54(-30.69,20.678) AW55(-31.352,20.353) AW56(-31.916,20.678) AW57(-32.554,20.353) AW59(-33.191,20.678) AW60(-33.755,20.353) AW61(-34.418,20.678) AW62(-35.032,20.353) AW63(-35.645,20.678) AW64(-36.308,20.353) AW65(-36.872,20.678) AW66(-37.407,20.215) AW67(-38.332,20.685) AW68(-38.936,20.936) AW69(-39.581,20.85) AW70(-39.999,21.349) AW71(-40.629,20.866) AY2(-0.629,21.348) AY3(-1.286,21.342) AY4(-2.04,21.357) AY5(-2.649,21.003) AY8(-4.328,21.003) AY12(-6.749,21.003) AY16(-9.17,21.003) AY21(-11.59,21.003) AY26(-14.05,21.003) AY27(-14.713,21.328) AY29(-15.94,21.328) AY30(-16.603,21.003) AY34(-19.031,21.003) AY35(-19.694,21.328) AY37(-20.921,21.328) AY38(-21.584,21.003) AY43(-23.986,21.003) AY44(-24.649,21.328) AY46(-25.876,21.328) AY47(-26.477,21.003) AY51(-28.862,21.003) AY52(-29.463,21.328) AY54(-30.69,21.328) AY55(-31.352,21.003) AY60(-33.755,21.003) AY61(-34.418,21.328) AY63(-35.645,21.328) AY64(-36.308,21.003) AY66(-37.535,21.003) AY68(-38.85,21.581) B5(-2.266,0.65) B6(-2.847,0.975) B10(-5.325,0.975) B14(-7.803,0.975) B18(-10.281,0.975) B22(-12.759,0.975) B26(-15.237,0.975) B30(-17.715,0.975) B34(-20.194,0.975) B39(-22.672,0.975) B44(-25.15,0.975) B48(-27.628,0.975) B53(-30.106,0.975) B58(-32.584,0.975) B62(-35.062,0.975) B66(-37.54,0.975) B69(-39.349,0.63) BA3(-1.279,21.999) BA5(-2.599,21.94) BA8(-4.328,21.653) BA12(-6.749,21.653) BA16(-9.17,21.653) BA21(-11.59,21.653) BA23(-12.849,21.572) BA28(-15.326,21.572) BA32(-17.83,21.572) BA36(-20.307,21.572) BA41(-22.785,21.572) BA45(-25.263,21.572) BA49(-27.669,21.653) BA53(-30.076,21.572) BA57(-32.554,21.572) BA62(-35.032,21.572) BA68(-39.349,21.999) BB4(-1.763,22.628) BB68(-38.866,22.628) C4(-1.699,0.978) C5(-2.266,1.3) C7(-3.523,1.3) C8(-4.086,0.975) C9(-4.65,1.3) C11(-6.001,1.3) C12(-6.564,0.975) C13(-7.128,1.3) C15(-8.479,1.3) C16(-9.042,0.975) C17(-9.606,1.3) C19(-10.957,1.3) C20(-11.52,0.975) C21(-12.084,1.3) C23(-13.435,1.3) C24(-13.998,0.975) C25(-14.562,1.3) C27(-15.913,1.3) C28(-16.476,0.975) C29(-17.04,1.3) C31(-18.391,1.3) C32(-18.954,0.975) C33(-19.518,1.3) C36(-20.869,1.3) C37(-21.433,0.975) C38(-21.996,1.3) C40(-23.347,1.3) C41(-23.911,0.975) C42(-24.474,1.3) C45(-25.825,1.3) C46(-26.389,0.975) C47(-26.952,1.3) C50(-28.303,1.3) C51(-28.867,0.975) C52(-29.43,1.3) C54(-30.781,1.3) C55(-31.345,0.975) C56(-31.908,1.3) C59(-33.259,1.3) C60(-33.823,0.975) C61(-34.386,1.3) C63(-35.737,1.3) C64(-36.301,0.975) C65(-36.864,1.3) C67(-38.799,1.015) C68(-38.936,1.693) C70(-39.999,1.28) D3(-0.975,1.706) D4(-1.624,1.646) D5(-2.224,1.951) D6(-2.873,1.991) D7(-3.523,1.951) D8(-4.086,1.626) D9(-4.65,1.951) D10(-5.325,1.991) D11(-6.001,1.951) D12(-6.564,1.626) D13(-7.128,1.951) D14(-7.803,1.991) D15(-8.479,1.951) D16(-9.042,1.626) D17(-9.606,1.951) D18(-10.281,1.991) D19(-10.957,1.951) D20(-11.52,1.626) D21(-12.084,1.951) D22(-12.759,1.991) D23(-13.435,1.951) D24(-13.998,1.626) D25(-14.562,1.951) D26(-15.237,1.991) D27(-15.913,1.951) D28(-16.476,1.626) D29(-17.04,1.951) D30(-17.715,1.991) D31(-18.391,1.951) D32(-18.954,1.626) D33(-19.518,1.951) D34(-20.194,1.991) D36(-20.869,1.951) D37(-21.433,1.626) D38(-21.996,1.951) D39(-22.672,1.991) D40(-23.347,1.951) D41(-23.911,1.626) D42(-24.474,1.951) D44(-25.15,1.991) D45(-25.825,1.951) D46(-26.389,1.626) D47(-26.952,1.951) D48(-27.628,1.991) D50(-28.303,1.951) D51(-28.867,1.626) D52(-29.43,1.951) D53(-30.106,1.991) D54(-30.781,1.951) D55(-31.345,1.626) D56(-31.908,1.951) D58(-32.584,1.991) D59(-33.259,1.951) D60(-33.823,1.626) D61(-34.386,1.951) D62(-35.062,1.991) D63(-35.737,1.951) D64(-36.301,1.626) D65(-36.864,1.951) D66(-37.54,1.991) D67(-38.213,1.3) D68(-39.582,1.779) D69(-38.876,2.343) D71(-40.629,1.763) E1(0,2.274) E2(-0.65,2.274) E3(-1.3,2.274) E5(-2.66,2.723) E6(-3.575,2.723) E8(-4.489,2.723) E10(-5.403,2.723) E11(-6.318,2.723) E13(-7.232,2.723) E15(-8.147,2.723) E16(-9.061,2.723) E18(-9.975,2.723) E20(-10.89,2.723) E21(-11.804,2.723) E22(-12.719,2.723) E23(-13.633,2.723) E25(-14.547,2.723) E27(-15.462,2.723) E28(-16.376,2.723) E30(-17.291,2.723) E32(-18.205,2.723) E33(-19.119,2.723) E35(-20.034,2.723) E37(-20.948,2.723) E38(-21.863,2.723) E40(-22.777,2.723) E42(-23.691,2.723) E43(-24.606,2.723) E45(-25.52,2.723) E46(-26.435,2.723) E48(-27.349,2.723) E50(-28.263,2.723) E52(-29.178,2.723) E53(-30.092,2.723) E55(-31.007,2.723) E56(-31.921,2.723) E58(-32.835,2.723) E60(-33.75,2.723) E61(-34.664,2.723) E63(-35.629,2.659) E65(-36.645,2.659) E66(-37.661,2.659) E68(-38.213,1.951) F2(-0.975,2.848) F4(-1.951,2.848) F5(-2.66,3.373) F6(-3.575,3.373) F8(-4.489,3.373) F10(-5.403,3.373) F11(-6.318,3.373) F13(-7.232,3.373) F15(-8.147,3.373) F16(-9.061,3.373) F18(-9.975,3.373) F20(-10.89,3.373) F21(-11.804,3.373) F22(-12.719,3.373) F23(-13.633,3.373) F25(-14.547,3.373) F27(-15.462,3.373) F28(-16.376,3.373) F30(-17.291,3.373) F32(-18.205,3.373) F33(-19.119,3.373) F35(-20.034,3.373) F37(-20.948,3.373) F38(-21.863,3.373) F40(-22.777,3.373) F42(-23.691,3.373) F43(-24.606,3.373) F45(-25.52,3.373) F46(-26.435,3.373) F48(-27.349,3.373) F50(-28.263,3.373) F52(-29.178,3.373) F53(-30.092,3.373) F55(-31.007,3.373) F56(-31.921,3.373) F58(-32.835,3.373) F60(-33.75,3.373) F61(-34.664,3.373) F63(-35.629,3.31) F65(-36.645,3.31) F66(-37.661,3.31) F68(-38.876,2.994) G4(-1.951,3.511) G5(-2.66,4.023) G6(-3.575,4.023) G8(-4.489,4.023) G10(-5.403,4.023) G11(-6.318,4.023) G13(-7.232,4.023) G15(-8.147,4.023) G16(-9.061,4.023) G18(-9.975,4.023) G20(-10.89,4.023) G21(-11.804,4.023) G22(-12.719,4.023) G23(-13.633,4.023) G25(-14.547,4.023) G27(-15.462,4.023) G28(-16.376,4.023) G30(-17.291,4.023) G32(-18.205,4.023) G33(-19.119,4.023) G35(-20.034,4.023) G37(-20.948,4.023) G38(-21.863,4.023) G40(-22.777,4.023) G42(-23.691,4.023) G43(-24.606,4.023) G45(-25.52,4.023) G46(-26.435,4.023) G48(-27.349,4.023) G50(-28.263,4.023) G52(-29.178,4.023) G53(-30.092,4.023) G55(-31.007,4.023) G56(-31.921,4.023) G58(-32.835,4.023) G60(-33.75,4.023) G61(-34.664,4.023) G63(-35.629,3.96) G65(-36.645,3.96) G66(-37.661,3.96) G68(-38.678,3.655) G69(-39.328,3.655) H3(-1.626,4.174) H5(-2.66,4.674) H6(-3.575,4.674) H8(-4.489,4.674) H10(-5.403,4.674) H11(-6.318,4.674) H13(-7.232,4.674) H15(-8.147,4.674) H16(-9.061,4.674) H18(-9.975,4.674) H20(-10.89,4.674) H21(-11.804,4.674) H63(-35.629,4.61) H65(-36.645,4.61) H66(-37.661,4.61) H69(-39.003,4.218) J4(-1.951,4.837) J5(-2.66,5.324) J6(-3.575,5.324) J8(-4.489,5.324) J10(-5.403,5.324) J11(-6.318,5.324) J13(-7.232,5.324) J22(-13.176,4.488) J23(-14.09,4.488) J25(-15.005,4.488) J27(-15.919,4.488) J28(-16.833,4.488) J30(-17.748,4.488) J32(-18.662,4.488) J33(-19.577,4.488) J35(-20.491,4.488) J37(-21.405,4.488) J38(-22.32,4.488) J40(-23.234,4.488) J42(-24.149,4.488) J43(-25.063,4.488) J45(-25.977,4.488) J46(-26.892,4.488) J48(-27.806,4.488) J50(-28.721,4.488) J52(-29.635,4.488) J53(-30.549,4.488) J55(-31.464,4.488) J56(-32.378,4.488) J58(-33.293,4.488) J60(-34.207,4.488) J68(-38.676,4.794) K15(-8.126,5.438) K16(-8.776,5.438) K17(-9.426,5.438) K18(-10.077,5.438) K19(-10.727,5.438) K20(-11.377,5.438) K21(-12.027,5.438) K22(-12.719,4.952) K23(-13.633,4.952) K25(-14.547,4.952) K27(-15.462,4.952) K28(-16.376,4.952) K30(-17.291,4.952) K32(-18.205,4.952) K33(-19.119,4.952) K35(-20.034,4.952) K37(-20.948,4.952) K38(-21.863,4.952) K40(-22.777,4.952) K42(-23.691,4.952) K43(-24.606,4.952) K45(-25.52,4.952) K46(-26.435,4.952) K48(-27.349,4.952) K50(-28.263,4.952) K52(-29.178,4.952) K53(-30.092,4.952) K55(-31.007,4.952) K56(-31.921,4.952) K58(-32.835,4.952) K60(-33.75,4.952) K61(-34.664,4.952) K63(-35.447,5.26) K64(-36.097,5.26) K65(-36.747,5.26) K66(-37.398,5.26) K67(-38.048,5.26) K68(-38.666,5.468) K70(-39.653,5.57) L2(-0.975,5.5) L4(-1.951,5.5) L6(-2.729,5.974) L7(-3.379,5.974) L8(-4.029,5.974) L9(-4.679,5.974) L10(-5.33,5.974) L11(-5.98,5.974) L12(-6.63,5.974) L13(-7.28,5.974) L15(-8.126,6.276) L16(-8.776,6.276) L17(-9.426,6.276) L18(-10.077,6.276) L19(-10.727,6.276) L20(-11.377,6.276) L21(-12.027,6.276) L62(-34.958,5.689) L63(-35.427,6.147) L64(-36.077,6.147) L65(-36.727,6.147) L66(-37.377,6.147) L67(-38.028,6.147) L68(-38.678,6.147) L69(-39.328,6.147) L70(-39.978,6.147) L71(-40.629,6.147) M4(-1.951,6.163) M62(-34.958,6.604) N3(-1.626,6.826) N6(-2.729,6.914) N7(-3.379,6.914) N8(-4.029,6.914) N9(-4.679,6.914) N10(-5.33,6.914) N11(-5.98,6.914) N12(-6.63,6.914) N13(-7.28,6.914) N15(-8.126,7.114) N16(-8.776,7.114) N17(-9.426,7.114) N18(-10.077,7.114) N19(-10.727,7.114) N20(-11.377,7.114) N21(-12.027,7.114) N63(-35.427,7.061) N64(-36.077,7.061) N65(-36.727,7.061) N66(-37.377,7.061) N67(-38.028,7.061) N68(-38.678,7.061) N69(-39.328,7.061) N70(-39.978,7.061) N71(-40.629,7.061) P4(-1.951,7.489) P15(-8.126,7.952) P16(-8.776,7.952) P17(-9.426,7.952) P18(-10.077,7.952) P19(-10.727,7.952) P20(-11.377,7.952) P21(-12.027,7.952) P62(-34.958,7.518) R6(-2.729,7.981) R7(-3.379,7.981) R8(-4.029,7.981) R9(-4.679,7.981) R10(-5.33,7.981) R11(-5.98,7.981) R12(-6.63,7.981) R13(-7.28,7.981) R63(-35.427,7.975) R64(-36.077,7.975) R65(-36.727,7.975) R66(-37.377,7.975) R67(-38.028,7.975) R68(-38.678,7.975) R69(-39.328,7.975) R70(-39.978,7.975) R71(-40.629,7.975) T2(-0.975,8.152) T4(-1.951,8.152) T15(-8.126,8.791) T16(-8.776,8.791) T17(-9.426,8.791) T18(-10.077,8.791) T19(-10.727,8.791) T20(-11.377,8.791) T21(-12.027,8.791) T62(-34.958,8.433) U4(-1.951,8.815) U6(-2.729,9.047) U7(-3.379,9.047) U8(-4.029,9.047) U9(-4.679,9.047) U10(-5.33,9.047) U11(-5.98,9.047) U12(-6.63,9.047) U13(-7.28,9.047) U63(-35.427,8.89) U64(-36.077,8.89) U65(-36.727,8.89) U66(-37.377,8.89) U67(-38.028,8.89) U68(-38.678,8.89) U69(-39.328,8.89) U70(-39.978,8.89) U71(-40.629,8.89) V3(-1.626,9.478) V15(-8.126,9.629) V16(-8.776,9.629) V17(-9.426,9.629) V18(-10.077,9.629) V19(-10.727,9.629) V20(-11.377,9.629) V21(-12.027,9.629) V62(-34.958,9.347) W4(-1.951,10.141) W6(-2.729,10.114) W7(-3.379,10.114) W8(-4.029,10.114) W9(-4.679,10.114) W10(-5.33,10.114) W11(-5.98,10.114) W12(-6.63,10.114) W13(-7.28,10.114) W63(-35.427,9.804) W64(-36.077,9.804) W65(-36.727,9.804) W66(-37.377,9.804) W67(-38.028,9.804) W68(-38.678,9.804) W69(-39.328,9.804) W70(-39.978,9.804) W71(-40.629,9.804) Y15(-8.126,10.467) Y16(-8.776,10.467) Y17(-9.426,10.467) Y18(-10.077,10.467) Y19(-10.727,10.467) Y20(-11.377,10.467) Y21(-12.027,10.467) Y62(-34.958,10.261)
  oval 0.254x0.343 smd: A6(-2.847,0.325) A7(-3.523,0) A9(-4.65,0) A10(-5.325,0.325) A11(-6.001,0) A13(-7.128,0) A14(-7.803,0.325) A15(-8.479,0) A17(-9.606,0) A18(-10.281,0.325) A19(-10.957,0) A21(-12.084,0) A22(-12.759,0.325) A23(-13.435,0) A25(-14.562,0) A26(-15.237,0.325) A27(-15.913,0) A29(-17.04,0) A30(-17.715,0.325) A31(-18.391,0) A33(-19.518,0) A34(-20.194,0.325) A36(-20.869,0) A38(-21.996,0) A39(-22.672,0.325) A40(-23.347,0) A42(-24.474,0) A44(-25.15,0.325) A45(-25.825,0) A47(-26.952,0) A48(-27.628,0.325) A50(-28.303,0) A52(-29.43,0) A53(-30.106,0.325) A54(-30.781,0) A56(-31.908,0) A58(-32.584,0.325) A59(-33.259,0) A61(-34.386,0) A62(-35.062,0.325) A63(-35.737,0) A65(-36.864,0) A66(-37.54,0.325) A67(-38.215,0) AY7(-3.763,21.328) AY9(-4.898,21.328) AY11(-6.184,21.328) AY13(-7.319,21.328) AY15(-8.604,21.328) AY17(-9.74,21.328) AY20(-11.025,21.328) AY22(-12.16,21.328) AY25(-13.486,21.328) AY31(-17.167,21.328) AY33(-18.467,21.328) AY39(-22.148,21.328) AY42(-23.423,21.328) AY48(-27.103,21.328) AY50(-28.236,21.328) AY56(-31.916,21.328) AY59(-33.191,21.328) AY65(-36.872,21.328) AY67(-38.216,21.328) B7(-3.523,0.65) B9(-4.65,0.65) B11(-6.001,0.65) B13(-7.128,0.65) B15(-8.479,0.65) B17(-9.606,0.65) B19(-10.957,0.65) B21(-12.084,0.65) B23(-13.435,0.65) B25(-14.562,0.65) B27(-15.913,0.65) B29(-17.04,0.65) B31(-18.391,0.65) B33(-19.518,0.65) B36(-20.869,0.65) B38(-21.996,0.65) B40(-23.347,0.65) B42(-24.474,0.65) B45(-25.825,0.65) B47(-26.952,0.65) B50(-28.303,0.65) B52(-29.43,0.65) B54(-30.781,0.65) B56(-31.908,0.65) B59(-33.259,0.65) B61(-34.386,0.65) B63(-35.737,0.65) B65(-36.864,0.65) B67(-38.215,0.65) BA4(-1.948,22.004) BA6(-3.141,21.572) BA7(-3.705,21.978) BA9(-4.898,21.978) BA10(-5.561,21.572) BA11(-6.125,21.978) BA13(-7.319,21.978) BA14(-7.982,21.572) BA15(-8.546,21.978) BA17(-9.74,21.978) BA18(-10.403,21.572) BA20(-10.966,21.978) BA22(-12.16,21.978) BA25(-13.486,21.978) BA26(-14.149,21.653) BA27(-14.812,21.978) BA29(-15.841,21.978) BA30(-16.504,21.653) BA31(-17.167,21.978) BA33(-18.467,21.978) BA34(-19.13,21.653) BA35(-19.793,21.978) BA37(-20.822,21.978) BA38(-21.485,21.653) BA39(-22.148,21.978) BA42(-23.423,21.978) BA43(-24.086,21.653) BA44(-24.748,21.978) BA46(-25.777,21.978) BA47(-26.44,21.653) BA48(-27.103,21.978) BA50(-28.236,21.978) BA51(-28.899,21.653) BA52(-29.562,21.978) BA54(-30.59,21.978) BA55(-31.253,21.653) BA56(-31.916,21.978) BA59(-33.191,21.978) BA60(-33.854,21.653) BA61(-34.517,21.978) BA63(-35.546,21.978) BA64(-36.209,21.653) BA65(-36.872,21.978) BA66(-37.535,21.653) BA67(-38.216,21.978) BB5(-2.529,22.628) BB6(-3.141,22.303) BB7(-3.705,22.628) BB9(-4.898,22.628) BB10(-5.561,22.303) BB11(-6.125,22.628) BB13(-7.319,22.628) BB14(-7.982,22.303) BB15(-8.546,22.628) BB17(-9.74,22.628) BB18(-10.403,22.303) BB20(-10.966,22.628) BB22(-12.16,22.628) BB23(-12.849,22.222) BB25(-13.486,22.628) BB26(-14.149,22.303) BB27(-14.812,22.628) BB29(-15.841,22.628) BB30(-16.504,22.303) BB31(-17.167,22.628) BB32(-17.83,22.222) BB33(-18.467,22.628) BB34(-19.13,22.303) BB35(-19.793,22.628) BB37(-20.822,22.628) BB38(-21.485,22.303) BB39(-22.148,22.628) BB41(-22.785,22.222) BB42(-23.423,22.628) BB43(-24.086,22.303) BB44(-24.748,22.628) BB46(-25.777,22.628) BB47(-26.44,22.303) BB48(-27.103,22.628) BB50(-28.236,22.628) BB51(-28.899,22.303) BB52(-29.562,22.628) BB54(-30.59,22.628) BB55(-31.253,22.303) BB56(-31.916,22.628) BB57(-32.554,22.222) BB59(-33.191,22.628) BB60(-33.854,22.303) BB61(-34.517,22.628) BB63(-35.546,22.628) BB64(-36.209,22.303) BB65(-36.872,22.628) BB66(-37.535,22.303) BB67(-38.216,22.628)
  oval 0.343x0.254 smd: AA1(-0.325,10.804) AB1(0,11.467) AB2(-0.65,11.467) AB3(-1.3,11.467) AC1(-0.325,12.13) AC2(-0.975,12.13) AD1(0,12.792) AD2(-0.65,12.792) AD3(-1.3,12.792) AF1(-0.325,13.455) AF70(-39.978,13.154) AF71(-40.629,13.154) AG1(0,14.118) AG2(-0.65,14.118) AG3(-1.3,14.118) AG70(-39.653,13.817) AG71(-40.303,13.817) AH1(-0.325,14.781) AH2(-0.975,14.781) AH68(-38.678,14.48) AH69(-39.328,14.48) AH70(-39.978,14.48) AH71(-40.629,14.48) AJ1(0,15.444) AJ2(-0.65,15.444) AJ3(-1.3,15.444) AK70(-40.303,15.143) AL1(-0.325,16.107) AL68(-38.678,15.806) AL69(-39.328,15.806) AL70(-39.978,15.806) AL71(-40.629,15.806) AM1(0,16.77) AM2(-0.65,16.77) AM3(-1.3,16.77) AM70(-39.653,16.469) AM71(-40.303,16.469) AN1(-0.325,17.433) AN2(-0.975,17.433) AN70(-39.978,17.132) AN71(-40.629,17.132) AP1(0,18.096) AP2(-0.65,18.096) AP3(-1.3,18.096) AR70(-39.978,18.16) AR71(-40.629,18.16) AT1(-0.325,18.759) AT70(-39.653,18.823) AT71(-40.303,18.823) AU1(0,19.422) AU2(-0.65,19.422) AU3(-1.3,19.422) AU68(-38.678,19.461) AU69(-39.328,19.486) AU70(-39.978,19.486) AU71(-40.629,19.486) AV1(0,20.142) AV2(-0.95,20.113) AV71(-40.629,20.215) AW2(-0.625,20.677) AW3(-1.275,20.677) E70(-39.978,2.305) E71(-40.629,2.413) F1(-0.325,2.848) F70(-39.526,2.994) F71(-40.176,2.931) G1(0,3.511) G2(-0.65,3.511) G3(-1.3,3.511) G70(-39.978,3.555) G71(-40.629,3.555) H1(-0.325,4.174) H2(-0.975,4.174) H70(-39.653,4.218) H71(-40.303,4.218) J1(0,4.837) J2(-0.65,4.837) J3(-1.3,4.837) J69(-39.328,4.881) J70(-39.978,4.881) J71(-40.629,4.881) K71(-40.303,5.57) L1(-0.325,5.5) M1(0,6.163) M2(-0.65,6.163) M3(-1.3,6.163) N1(-0.325,6.826) N2(-0.975,6.826) P1(0,7.489) P2(-0.65,7.489) P3(-1.3,7.489) T1(-0.325,8.152) U1(0,8.815) U2(-0.65,8.815) U3(-1.3,8.815) V1(-0.325,9.478) V2(-0.975,9.478) W1(0,10.141) W2(-0.65,10.141) W3(-1.3,10.141)
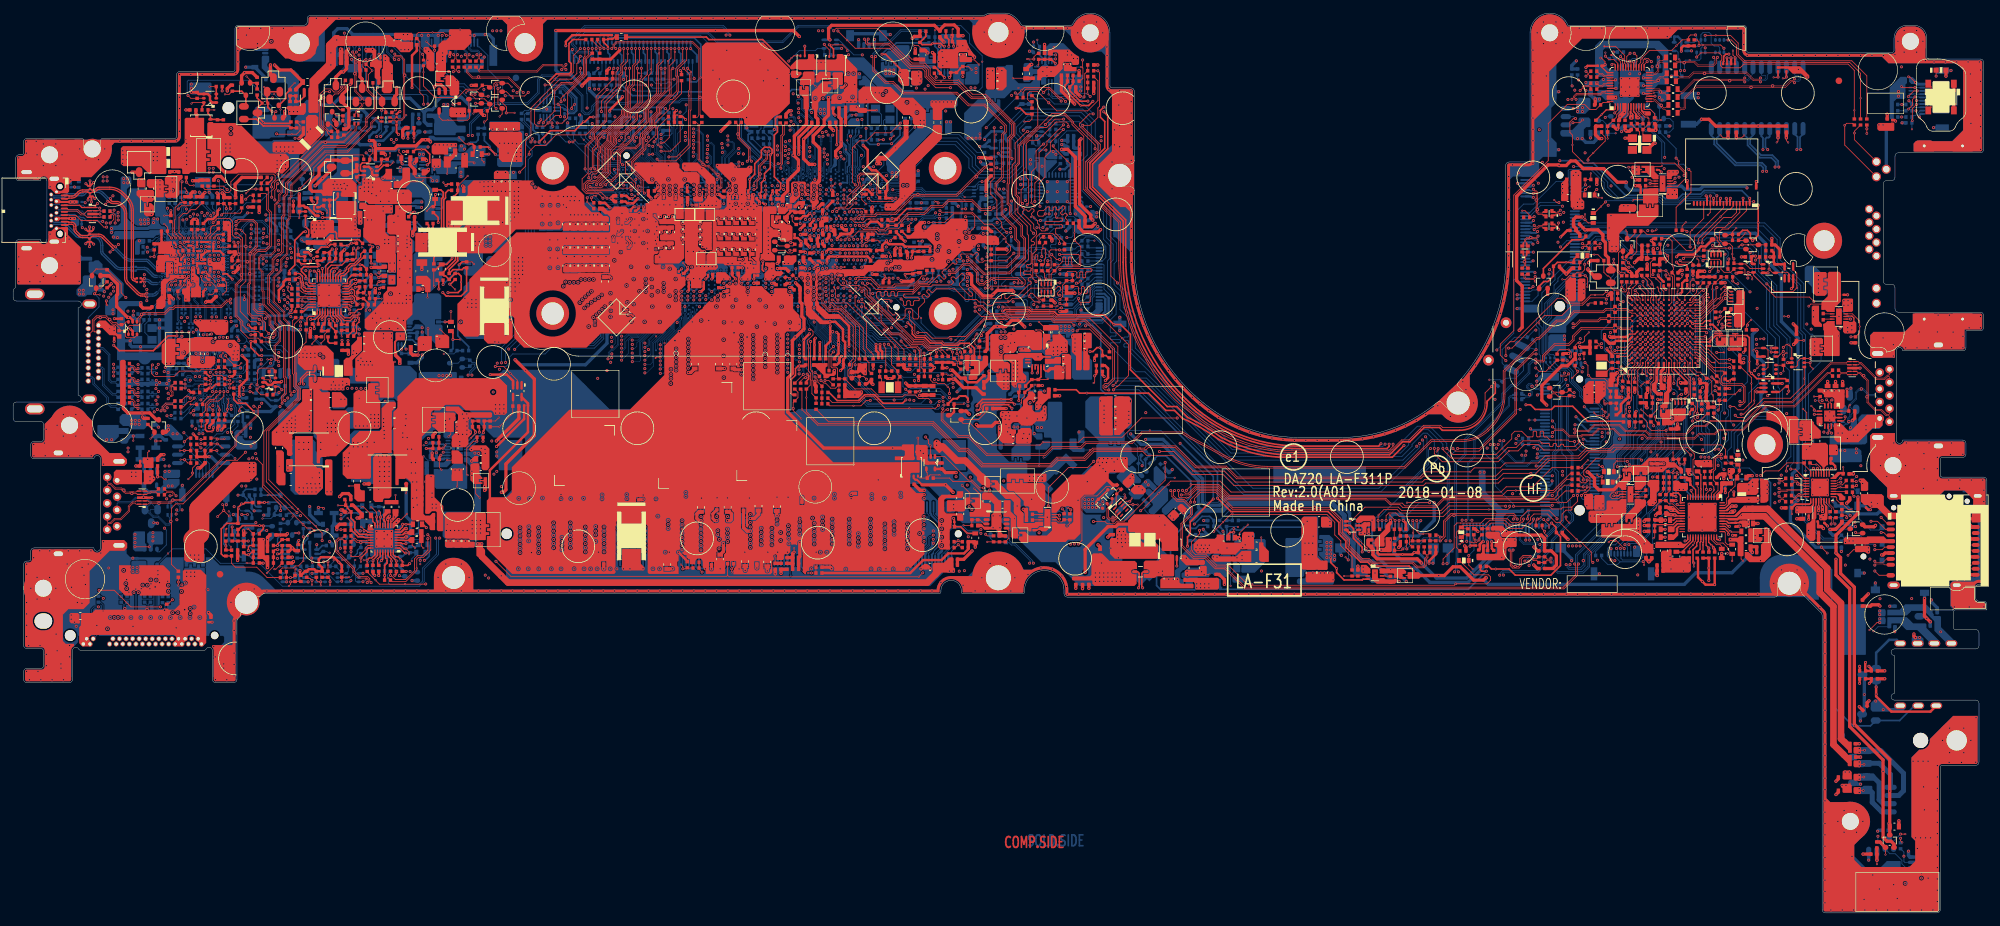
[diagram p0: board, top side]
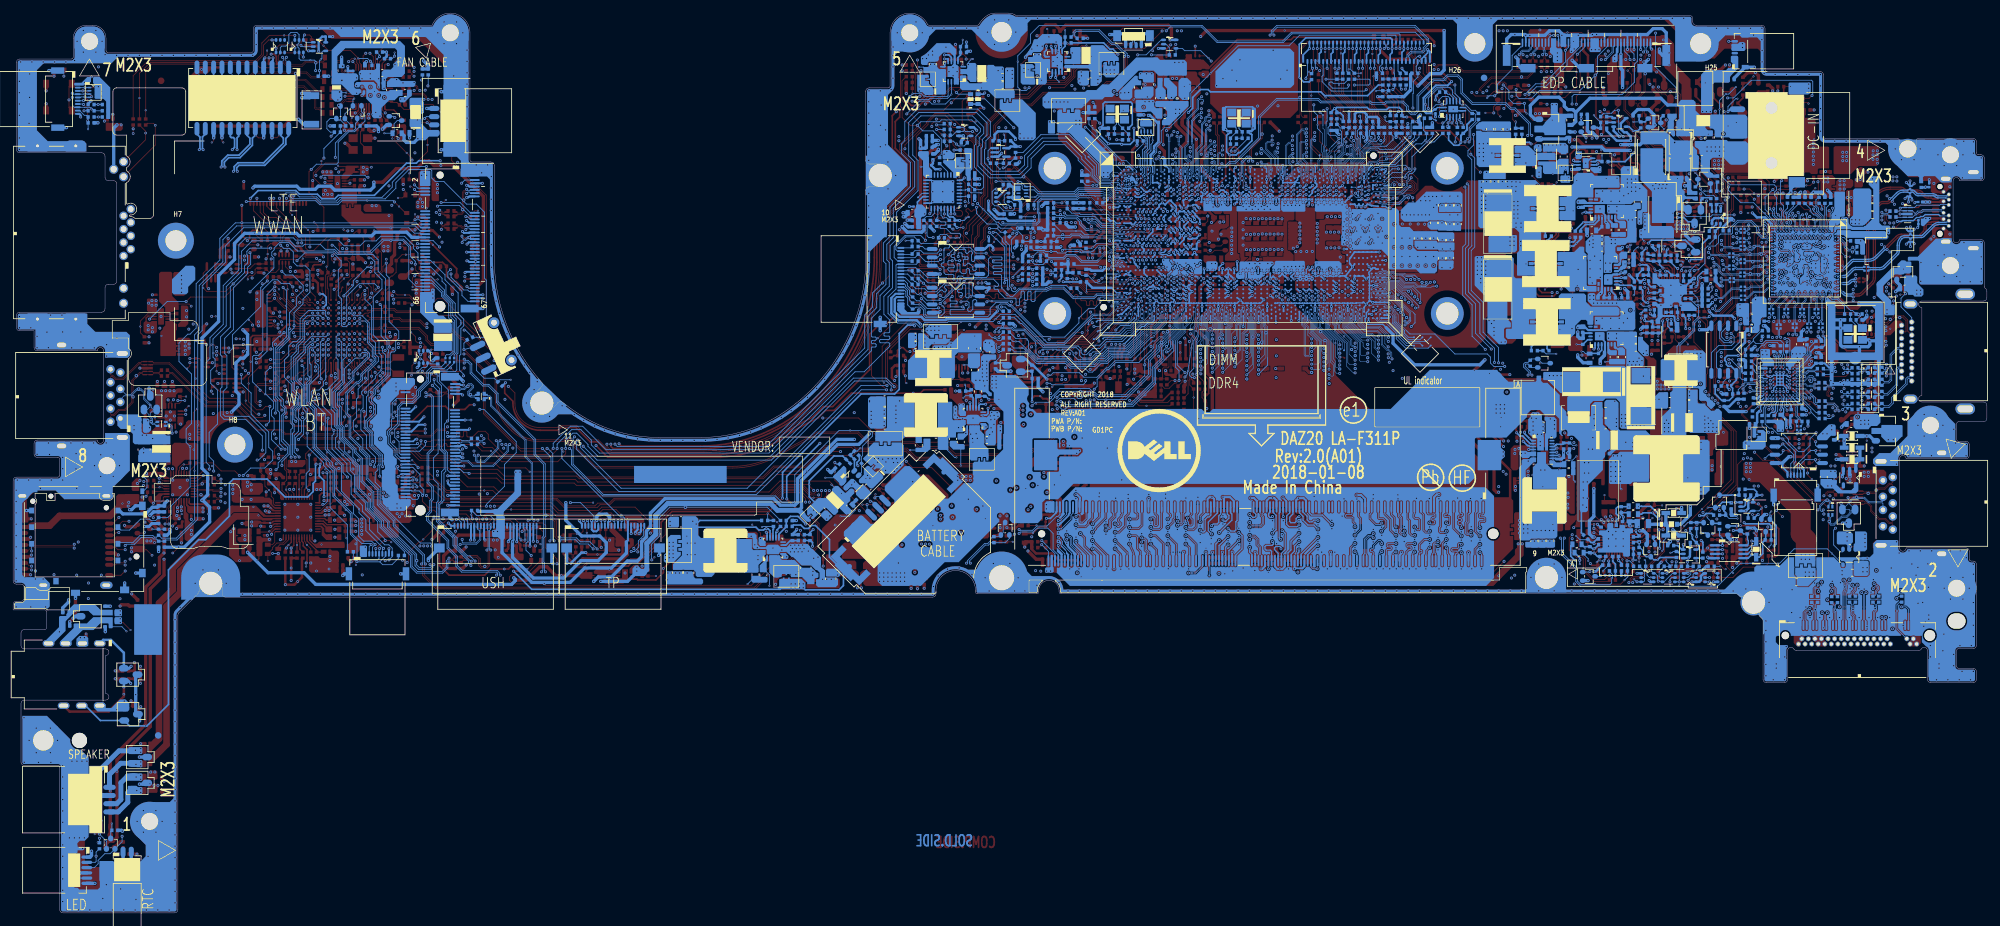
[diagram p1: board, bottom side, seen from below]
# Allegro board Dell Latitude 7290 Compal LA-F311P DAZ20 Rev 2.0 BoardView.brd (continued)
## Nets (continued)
SML0_SMBCLK: CC318.1 RC19.1 RC347.1 UC1.R9 UL1.28
SML0_SMBDATA: RC20.1 RC348.1 UC1.W2 UL1.31
SML1_SMBCLK: CC319.1 RC15.1 UC1.W3 UE1.D8
SML1_SMBDATA: RC17.1 UC1.V3 UE1.E11
SNB_+1VALWP: PC302.1 PR303.2
SNK0_CONFIG1: RT129.1 RT337.1 UT1.N4
SNU_DDR: PC204.1 PR202.2
SNUB_1.8VALW: PC506.1 PR502.2
SNUB_1V_PRIM: PC419.1 PR409.2
SNUB_1VS_VCCIO: PC401.1 PR405.2
SNUB_CHG1: PC940.1 PR923.2
SNUB_CHG2: PC941.1 PR924.2
SPKR: RA12.2 RC183.1 UC1.AW5
SPKR_R: CA27.1 CA72.1 RA12.1 RA51.1
SRTCRST#: CC24.1 RC56.1 UC1.AN18
SS_1V_PRIM: PC420.1 PR428.1 PU402.7
SS_1VS_VCCIO: PC410.1 PR427.1 PU401.7
SUSACK#: RC443.1 UE1.K12
SUSACK#_R: RC443.2 RC550.1 UC1.AP11
SUSCLK: RC48.1 RN99.2 RZ56.2 UC1.BA17
SUSCLK_R: JNGFF3.68 RN99.1
SW_+1VALWP: PL301.1 PR303.1 PR304.2 PU301.6 PU301.19 PU301.20
SW_USB20_N9: LI7.1 UI3.11
SW_USB20_P9: LI7.4 UI3.10
SYS_PWROK: RC129.1 RE56.1 RE548.1 UC1.B6
SYS_RESET#: CC302.1 JAPS1.13 RC224.2 RC291.1 UC1.B5
SYS_RESET#_R: RC224.1 RC290.2 UC12.4
SYSTEM_ID: CE47.1 RE300.1 UE1.J10
TACH_FAN1: JFAN1.3 RE51.2 UE1.E3
TBT_CIO_PLUG_EVENT#: RT371.1 RT391.1 UC1.AB12 UT1.W2
TBT_DP_RBIAS: RT35.1 UT1.N6
TBT_FORCE_PWR: RT27.1 UC1.B7 UT1.H4
TBT_I2C_SCL: RT19.1 UT1.U2 UT5.D2
TBT_I2C_SDA: RT18.1 UT1.U1 UT5.D1
TBT_JTAG_TCK: RT6.1 UT1.T4
TBT_JTAG_TDI: RT8.1 UT1.Y4
TBT_JTAG_TDO: RT5.1 UT1.W4
TBT_JTAG_TMS: RT7.1 UT1.V4
TBT_PCIE_RBIAS: RT34.1 UT1.N16
TBT_PWR_EN: T269.1(TP-1) UC1.D7
TBT_RBIAS: RT39.2 UT1.H6
TBT_RESET_N_EC: RE506.1 RT11.1 RT110.2 UT1.F4
TBT_RESET_N_EC_R: RE95.1 RE506.2 UE1.L8
TBT_ROM_CLK: UT1.AB4 UT2.6
TBT_ROM_CS#: RT2.1 UT1.AC3 UT2.1
TBT_ROM_DI: UT1.AB3 UT2.5
TBT_ROM_DO: RT3.1 UT1.AC4 UT2.2
TBT_ROM_HOLD#: RT1.1 UT2.7
TBT_ROM_WP#: RT4.1 UT1.V1 UT2.3
TBT_RSENSE: RT39.1 UT1.J6
TBT_SRC_CFG1: RT30.1 RT338.1 UT1.AA1
TBT_TMU_CLK_OUT: RT28.1 UT1.V2
TBTA_AUXN: CT81.1 UT1.W15
TBTA_AUXN_C: CT81.2 RT95.1 UT5.J2
TBTA_AUXP: CT80.1 UT1.Y15
TBTA_AUXP_C: CT80.2 RT96.1 UT5.J1
TBTA_BOT_N: RT122.2 UT5.L7
TBTA_BOT_N_R: DT40.2 DT40.8 JUSBC1.B7 RT122.1
TBTA_BOT_P: RT123.2 UT5.K7
TBTA_BOT_P_R: DT40.4 DT40.7 JUSBC1.B6 RT123.1
TBTA_CC1: CT86.1 DT39.1 DT39.9 JUSBC1.A5 RT104.2 UT5.L9
TBTA_CC2: CT85.1 DT40.5 DT40.6 JUSBC1.B5 RT105.2 UT5.L10
TBTA_DBG_CTL1: RT106.1 UT5.E4
TBTA_DBG_CTL2: RT107.1 UT5.D5
TBTA_DEBUG1: RT92.2 UT5.L2
TBTA_DEBUG2: RT93.2 UT5.K2
TBTA_DEBUG3: RT89.2 UT5.L3
TBTA_DEBUG4: RT90.2 UT5.K3
TBTA_HPD: RT23.1 RT73.1 UT1.M4
TBTA_HPD_R: RT73.2 UT5.C10
TBTA_I2C_INT: RT16.1 UT1.J4 UT5.C1
TBTA_LSRX: RT21.1 RT88.1 RT90.1 UT1.A4
TBTA_LSRX_R: RT88.2 UT5.K4
TBTA_LSTX: RT22.1 RT87.1 RT89.1 UT1.A5
TBTA_LSTX_R: RT87.2 UT5.L4
TBTA_MRESET: RT86.1 UT5.E11
TBTA_RESET_N_EC_R: RT110.1 UT5.F11
TBTA_ROM_CLK_PD: RT54.2 UT5.A3
TBTA_ROM_CLK_PD_R: JDB1.2 RT54.1 UT6.6
TBTA_ROM_CS#_PD: RT57.2 UT5.B3
TBTA_ROM_CS#_PD_R: JDB1.5 RT51.1 RT57.1 UT6.1
TBTA_ROM_DI_PD: RT55.2 UT5.B4
TBTA_ROM_DI_PD_R: JDB1.3 RT55.1 UT6.5
TBTA_ROM_DO_PD: RT56.2 UT5.A4
TBTA_ROM_DO_PD_R: JDB1.4 RT52.1 RT56.1 UT6.2
TBTA_ROM_HOLD#_PD: RT50.1 UT6.7
TBTA_ROM_WP#_PD: RT53.1 UT6.3
TBTA_ROSC: RT100.1 UT5.G2
TBTA_RX1N: DT14.1 JUSBC1.B10 UT1.A21
TBTA_RX1P: DT13.1 JUSBC1.B11 UT1.B21
TBTA_RX2N: DT9.1 JUSBC1.A10 UT1.B15
TBTA_RX2P: DT10.1 JUSBC1.A11 UT1.A15
TBTA_SBU1: DT39.5 DT39.6 JUSBC1.A8 RT108.2
TBTA_SBU1_R: RT108.1 UT5.K8
TBTA_SBU2: DT40.1 DT40.9 JUSBC1.B8 RT109.2
TBTA_SBU2_R: RT109.1 UT5.L8
TBTA_TOP_N: RT121.1 UT5.L6
TBTA_TOP_N_R: DT39.4 DT39.7 JUSBC1.A7 RT121.2
TBTA_TOP_P: RT120.1 UT5.K6
TBTA_TOP_P_R: DT39.2 DT39.8 JUSBC1.A6 RT120.2
TBTA_TX1N: CT96.1 UT1.B19
TBTA_TX1N_C: CT96.2 DT6.1 JUSBC1.A3
TBTA_TX1P: CT95.1 UT1.A19
TBTA_TX1P_C: CT95.2 DT5.1 JUSBC1.A2
TBTA_TX2N: CT98.1 UT1.B17
TBTA_TX2N_C: CT98.2 DT18.1 JUSBC1.B3
TBTA_TX2P: CT97.1 UT1.A17
TBTA_TX2P_C: CT97.2 DT17.1 JUSBC1.B2
TBTA_USB2_RBIAS: RT41.1 UT1.H19
TBTA_USB20_N: RT403.1 UT1.D20
TBTA_USB20_N_R: RT401.2 RT403.2 UT5.K5
TBTA_USB20_P: RT402.1 UT1.E20
TBTA_USB20_P_R: RT400.2 RT402.2 UT5.L5
TBTB_HPD: RT33.1 UT1.G2
TBTB_I2C_INT: RT17.1 UT1.E2
TBTB_LSRX: RT32.1 UT1.B5
TBTB_LSTX: RT31.1 UT1.B4
TBTB_USB2_RBIAS: RT42.1 UT1.F19
TDI_XDP: JXDP1.56 RC229.1 UC8.5
TDO_XDP: CC306.1 JXDP1.52 RC230.1 UC8.2
TDOCK_BATLOW#: RT20.1 UT1.F2
TEST_EN: RT36.1 UT1.E1
TEST_PWRGD: RT37.1 UT1.AB5
THERMDA: UT1.AB23 UT1.AC23
THERMTRIP1#: RE301.1 UE1.B12
THERMTRIP2#: CE36.1 QE4.1 RE69.2 UE1.H3
TOUCH_SCREEN_DET#: JEDP1.32 RV8.1 UC1.AY5
TOUCH_SCREEN_PD#: JEDP1.5 RC272.1 UC1.A7
TOUCHPAD_INTR#: JKBTP1.5 RC414.1 RE318.2 UC1.BA5
TP_LAN_JTAG_TCK: RL2.1 UL1.35
TP_LAN_JTAG_TDI: T88.1(TP-1) UL1.32
TP_LAN_JTAG_TDO: T89.1(TP-1) UL1.34
TP_LAN_JTAG_TMS: RL1.1 UL1.33
TPM_GPIO0: RZ112.2 UZ12.29
TPM_GPIO4: T283.1(TP-1) UZ12.13
TPM_LPM#: RZ363.2 UZ12.3
TPM_PIRQ#: RC560.1 RC561.1 RZ69.2 UZ12.18
TPM_PIRQ#_R: RC560.2 UC1.AP8
TPM_TYPE: RC349.1 UC1.AY7
TRST#_XDP: JXDP1.54 UC8.12
TYPEC_CON_SEL1: RC555.1 RC556.1 UC1.W4
TYPEC_CON_SEL2: RC553.1 RC554.1 UC1.AB3
TYPEC_ID: CE62.1 RE343.1 UE1.F2
UART_MISO: RT82.1 RT83.1 UT5.F2
UART_MOSI: RT81.1 RT83.2 UT5.E2
UG1_ISL9538: PQ905.1 PU901.11
UG2_ISL9538: PQ904.1 PU901.5
UIM_CLK: CZ38.1 JNGFF2.24 JSIM1.C3
UIM_DATA: CZ39.1 JNGFF2.26 JSIM1.C7 RZ335.2
UIM_RESET: CZ40.1 JNGFF2.22 JSIM1.C2
UPD1_SMBCLK: QT1.1 RE303.1 RT58.1 UE1.C3
UPD1_SMBCLK_Q: QT1.6 RT58.2 RT67.1 RT92.1 UT5.B5
UPD1_SMBDAT: QT1.4 RE302.1 RT59.1 UE1.B4
UPD1_SMBDAT_Q: QT1.3 RT59.2 RT66.1 RT93.1 UT5.A5
UPD1_SMBINT#: RE91.1 RT60.1 UE1.F10
UPD1_SMBINT#_R: RT60.2 RT68.1 UT5.B6
UPD2_SMBCLK: RPE12.3 UE1.D7
UPD2_SMBDAT: RPE12.4 UE1.E7
UPD2_SMBINT#: RE92.1 UE1.F5
USB2_ID: RC337.1 UC1.AG3
USB2_VBUSSENSE: RC338.1 UC1.AG4
USB3_PRX_DTX_N2: LI16.4 RI28.1 UC1.J6
USB3_PRX_DTX_N3: DI1.1 DI1.9 JUSB2.5 UC1.J10
USB3_PRX_DTX_N6: DI4.1 DI4.9 JUSB1.5 UC1.G11
USB3_PRX_DTX_P2: LI16.1 RI27.1 UC1.H6
USB3_PRX_DTX_P3: DI1.2 DI1.8 JUSB2.6 UC1.H10
USB3_PRX_DTX_P6: DI4.2 DI4.8 JUSB1.6 UC1.F11
USB3_PRX_L_DTX_N2: JNGFF2.21 LI16.3 RI28.2
USB3_PRX_L_DTX_P2: JNGFF2.23 LI16.2 RI27.2
USB3_PTX_C_DRX_N2: CI29.1 LI17.1 RI30.1
USB3_PTX_C_DRX_N3: CI5.1 DI1.4 DI1.7 JUSB2.8
USB3_PTX_C_DRX_N6: CI13.1 DI4.4 DI4.7 JUSB1.8
USB3_PTX_C_DRX_P2: CI30.1 LI17.4 RI29.1
USB3_PTX_C_DRX_P3: CI4.1 DI1.5 DI1.6 JUSB2.9
USB3_PTX_C_DRX_P6: CI16.1 DI4.5 DI4.6 JUSB1.9
USB3_PTX_DRX_N2: CI29.2 UC1.B13
USB3_PTX_DRX_N3: CI5.2 UC1.B15
USB3_PTX_DRX_N6: CI13.2 UC1.D16
USB3_PTX_DRX_P2: CI30.2 UC1.A13
USB3_PTX_DRX_P3: CI4.2 UC1.A15
USB3_PTX_DRX_P6: CI16.2 UC1.C16
USB3_PTX_L_DRX_N2: JNGFF2.27 LI17.2 RI30.2
USB3_PTX_L_DRX_P2: JNGFF2.29 LI17.3 RI29.2
USB20_N1: RT401.1 UC1.AB9
USB20_N2: LI3.1 UC1.AD6
USB20_N2_R: DI2.3 JUSB2.2 LI3.2
USB20_N4: LI8.1 RI48.1 UC1.AD9
USB20_N4_L: JNGFF2.9 LI8.2 RI48.2
USB20_N5: LZ1.1 UC1.AJ1
USB20_N5_R: DV8.1 JEDP1.12 LZ1.2
USB20_N7: LI9.1 RI50.1 UC1.AH1
USB20_N7_L: JNGFF1.5 LI9.2 RI50.2
USB20_N8: LV27.3 UC1.AF8
USB20_N8_R: DV4.2 JEDP1.2 LV27.4
USB20_N9: UC1.AG1 UI3.2
USB20_N9_R: DI5.2 JUSB1.2 LI7.2
USB20_N10: JUSH1.8 UC1.AH7
USB20_P1: RT400.1 UC1.AB10
USB20_P2: LI3.4 UC1.AD7
USB20_P2_R: DI2.2 JUSB2.3 LI3.3
USB20_P4: LI8.4 RI47.1 UC1.AD10
USB20_P4_L: JNGFF2.7 LI8.3 RI47.2
USB20_P5: LZ1.4 UC1.AJ2
USB20_P5_R: DV7.1 JEDP1.13 LZ1.3
USB20_P7: LI9.4 RI49.1 UC1.AH2
USB20_P7_L: JNGFF1.3 LI9.3 RI49.2
USB20_P8: LV27.2 UC1.AF9
USB20_P8_R: DV4.3 JEDP1.3 LV27.1
USB20_P9: UC1.AG2 UI3.3
USB20_P9_R: DI5.3 JUSB1.3 LI7.3
USB20_P10: JUSH1.9 UC1.AH8
USB_OC0#: RPC3.3 UC1.A9 UI3.13
USB_OC1#: RPC3.2 UC1.C9 UI1.3
USB_OC2#: RPC3.1 UC1.D9
USB_OC3#: RPC3.4 UC1.B9
USB_POWERSHARE_EN#: RPE11.2 UE1.J3 UI3.6
USB_POWERSHARE_VBUS_EN: RPE11.1 UE1.J2 UI3.5
USB_PWR_EN1#: RPE11.3 UE1.K3 UI1.4
USB_PWR_EN2#: RPE11.4 UE1.G5
USBCOMP: RC44.1 UC1.AB6
USH_DET#: DZ7.2 RE526.2 RZ87.1 UE1.C13
USH_DET#_R: DZ7.1 JUSH1.26 RZ87.2
USH_EXPANDER_SMBCLK: CZ62.1 JUSH1.11 RZ8.2 UE1.B3
USH_EXPANDER_SMBDAT: CZ63.1 JUSH1.12 RZ9.2 UE1.E5
USH_PWR_STATE#: JUSH1.22 RZ10.2 UE1.H2
USH_RST#_R: JUSH1.21 RZ114.2
VCI_IN1#: RE507.1 UE1.B5
VCI_IN2#: RE508.1 UE1.D4
VCT_LAN_R1: RL3.1 UL1.6
VGA_IDENTIFY: RE84.1 RE85.1 UE1.L9
VID0_PRIM_CORE: PR408.2 PR418.2 PR420.1 PU402.9
VID0_VCCIO: PR414.2 PR416.1 PU401.9
VID1_PRIM_CORE: PR411.2 PR417.2 PR419.1 PU402.8
VID1_VCCIO: PR413.2 PR415.1 PU401.8
VIDALERT_N: PR604.2 PR625.1 RC152.1 RC153.2
VIDALERT_N_B: PR625.2 PU602.36
VIDSCLK: CC321.1 PR601.2 PR618.1 UC1.A63
VIDSCLK_B: PR618.2 PU602.37
VIDSOUT: PR605.2 PR626.1 RC157.1 UC1.D64
VIDSOUT_B: PR626.2 PU602.35
VRALERT#: RC73.1 UC1.AM11
VSA_SEN+: PC640.2 PC650.1 PC652.1 PR649.2 RC168.2 UC1.H20
VSA_SEN-: PC649.1 PC650.2 PU602.26 RC166.1 UC1.H21
VSET_5105: CE38.1 RE77.1 UE1.C9
WIGIG_32KHZ: JNGFF1.50 RZ56.1
WLAN_COEX1: JNGFF1.48 RZ130.2
WLAN_COEX2: JNGFF1.46 RZ129.2
WLAN_COEX3: JNGFF1.44 RZ128.2
WLAN_PWR_EN: DZ9.1 RZ38.1 RZ70.2 RZ71.2 UZ2.3
WLAN_WIGIG60GHZ_DIS#: DZ1.1 RE8.1 UE1.L13
WLAN_WIGIG60GHZ_DIS#_R: DZ1.2 JNGFF1.56
WWAN_COEX1: JNGFF2.56 RZ130.1
WWAN_COEX2: JNGFF2.54 RZ129.1
WWAN_COEX3: JNGFF2.52 RZ128.1
WWAN_PWR_EN: CZ198.1 JNGFF2.6 RZ43.1
WWAN_RADIO_DIS#: DZ5.1 RE10.1 UE1.F12
WWAN_RADIO_DIS#_R: DZ5.2 JNGFF2.8
WWAN_WAKE#: JNGFF2.15 RE38.1 UE1.M13
XCLK_BIASREF: RC52.1 RC324.1 UC1.E42
XDP_DBRESET#: CC32.1 JXDP1.48 RC137.1 RC290.1 UC12.1
XDP_JTAGX: CC305.1 RC87.1 RC328.2 UC1.A59
XDP_OBS0: JXDP1.21 RC239.2
XDP_OBS0_R: RC239.1 UC1.C55
XDP_OBS1: JXDP1.23 RC240.2
XDP_OBS1_R: RC240.1 UC1.D55
XDP_OBS2_R: T10.1(TP-1) UC1.B54
XDP_OBS3_R: T11.1(TP-1) UC1.C56
XDP_PRSNT_PIN1: JXDP1.1 RC121.1 RC122.1
XDP_TMS: JXDP1.58 RC228.1 UC8.9
XTAL24_IN_U22: CC21.1 RC46.2 RC419.2 YC1.3
XTAL24_IN_U22_CPU: RC419.1 UC1.E37
XTAL24_IN_U42: CC334.1 RC415.2 RC417.2 YC3.3
XTAL24_IN_U42_CPU: RC417.1 UC1.E3
XTAL24_OUT_U22: CC22.1 RC46.1 RC420.2 YC1.1
XTAL24_OUT_U22_CPU: RC420.1 UC1.E35
XTAL24_OUT_U42: CC335.1 RC415.1 RC418.2 YC3.1
XTAL24_OUT_U42_CPU: RC418.1 UC1.C7
XTAL_25_IN: RT394.1 UT1.D22
XTAL_25_IN_R: CT21.1 RT394.2 YT1.1
XTAL_25_OUT: RT40.1 UT1.D23
XTAL_25_OUT_R: CT20.1 RT40.2 YT1.3
XTALI: CL14.1 RL11.2 UL1.10 YL1.1
XTALO: RL11.1 RL34.2 UL1.9
XTALO_R: CL13.1 RL34.1 YL1.3
Z2805: RL18.1 TL1.22
Z2806: RL16.1 TL1.16
Z2807: RL17.1 TL1.21
Z2808: RL15.1 TL1.15
N04748: PC939.1 PR929.1 PU901.3
N16399089: PD901.1 PD903.1 PD904.1 PR916.2
N16400770: PR901.3 PR910.1
N16404606: PD905.3 PR939.2 PR950.1
N16775301: PC208.2 PR204.2 PR206.1 PU200.16
N16775385: PC218.1 PU200.3
N16775517: PR203.1 PU200.12
N16776853: PC207.1 PU200.14
N16783014: PC111.1 PR104.1 PR105.1 PU100.16 PU100.17
N16783095: PC113.2 PR108.1
N16783134: PC127.2 PR117.1
N16783223: PC119.1 PU102.16 PU102.17
N16784595: PC102.1 PR100.2
N16784799: PC114.1 PR111.2
N17185092: PQ1204.6 PR1214.2 PR1218.2
N17188126: PR1211.2 PU1200.1
N17188417: PR1215.2 PU1200.2
N17275961: PR612.2 PR614.2 PU602.39
N17275988: PR616.2 PU602.40
N17335638: PC515.2 PR515.2 PR516.1 PU503.3
N17340170: PQ1205.1 PR1215.1 PR1226.2
N17370862: PC4.2 PQ4.4 PQ5.1 PR11.2 PR16.1
N17370885: PQ5.2 PR10.2 PR15.1
N17370921: PQ1.6 PR15.2
N17370927: PQ7.1 PR16.2
N17370961: PL3.1 PQ2.1 PR3.1 PR6.2
N17370983: PQ2.3 PR3.2 PR5.1
N17370995: PQ3.2 PR6.1 PR8.2
N17370999: PQ2.2 PQ3.1 PR7.2
N17371029: PC6.1 PQ9.4 PR12.2 PR18.1
N17371043: PQ6.1 PR18.2
N17371184: PR23.1 PU1.4
N17371207: PQ8.1 PR22.1 PR27.1
N17372066: PQ1.3 PR17.2 PR19.2
N17372074: PQ1.5 PR25.1
N17372833: PC1206.1 PR1201.2 PR1203.1 PR1219.1 PU1201.3
N17479322: PQ1215.2 PR1251.2 PR1252.1
N17494434: PC1211.1 PD1205.1 PQ1212.1 PR1238.1 PR1239.2 PR1246.1 PR1255.2 PU1201.5
N17509431: PC947.1 PR935.1 PR947.1 PU901.29
N17509921: PD905.2 PR941.2
N17509924: PD905.1 PR961.1 PU903.1
N17522701: PR942.2 PU903.2
N17670003: PR936.1 PR948.1 PU901.30
N17739728: PQ1205.3 PR1221.2 PR1224.1
N17747591: PQ8.3 PR26.2 PR28.1
N17765266: PR933.2 PR951.2 PU901.26
N17768164: PQ1210.5 PR1245.2
N17769037: PQ1207.6 PQ1211.4 PR1230.1 PR1258.2
N17769560: PQ1211.5 PR1233.1 PR1242.2
N17769738: PQ1211.2 PR1235.1 PR1257.2
N17770477: PQ1207.2 PQ1207.3 PR1232.1
N17771093: PQ1207.5 PR1241.2
N17771333: PQ1208.6 PQ1211.1 PR1234.1 PR1261.2
N17771663: PQ1208.2 PQ1208.3 PR1259.1
N17772624: PQ1208.5 PR1244.2 PR1260.2 PR1261.1
N17801240: PC1210.1 PQ1206.4 PR1228.2 PR1229.1
N17802718: PC1202.2 PQ1213.4 PQ1215.1 PR1205.2 PR1212.1
N17804163: PC1203.2 PQ1202.4 PQ1203.1 PR1207.2 PR1213.1
N17890941: PR1216.2 PU1200.4
N17892124: PQ1214.6 PR1252.2
N18265642: PQ1201.2 PR1216.1 PR1262.1
N18265900: PQ1201.5 PR1220.2
N18266224: PC1213.1 PD1205.2 PR1238.2 PR1240.2 PR1243.1 PU1201.7
N18266545: PC1214.1 PQ1209.5 PR1243.2
N18267253: PQ1212.2 PR1248.1 PR1249.1 PR1250.1
N18268286: PQ1205.2 PR1225.1
N18277029: PR404.2 PR425.2 PU401.14
N18277134: PR410.2 PR426.2 PU402.14
N18278782: PC930.1 PR914.1
N18278920: PR920.2 PU901.21
N18278998: PR922.2 PU901.22
N18288083: PR946.1 PU903.4
N18288371: PQ1204.5 PR1218.1
N18288510: PQ1204.2 PR1223.1
N18290420: PR423.1 PR424.1 PU402.5
N18325201: CL16.1 TL1.3
N18325205: CL17.1 TL1.4
N18325209: CL20.1 TL1.9
N18325213: CL21.1 TL1.10
N18490882: RI14.2 UI3.16
N18548164: PQ1.2 PR19.1
N18557857: PR21.2 PU1.1
N18557860: PR22.2 PU1.2
N18557997: PQ6.2 PR23.2 PR30.1
N18558082: PQ7.2 PR20.1
N18559343: PQ8.2 PR29.1
N18617275: PC313.1 PU301.16 PU301.17
N18617445: PC307.2 PR308.1
N18762046: CA33.1 RA17.2
N18762152: CZ127.1 UZ5.10
N18762172: CZ126.1 UZ5.12
N18762349: CA51.1 RA44.1 UA1.27
N18762353: CA53.1 UA1.7
N18762355: CA52.1 UA1.39
N18762401: RA53.1 RA54.1 UA1.20
N18762411: CA29.1 UA1.35
N18762416: CA29.2 UA1.37
N18762426: CA35.1 UA1.28
N18762428: CA49.1 UA1.34
N18762438: CA25.1 UA1.19
N18988038: PR681.2 PU612.17
N18988103: PL612.3 PR661.1
N18988170: PR665.2 PU612.5
N18988180: PC663.1 PR665.1
N18988186: PC663.2 PU612.7
N18988214: PR662.2 PU612.2
N18988216: PR664.2 PU612.1
N18989066: PR692.2 PU613.1
N18989073: PR671.2 PU613.2
N18989156: PC671.2 PU613.7
N18989158: PR672.2 PU613.5
N18989160: PC671.1 PR672.1
N18989202: PR689.2 PU613.17
N18989973: PR687.2 PU610.1
N18989995: PL610.4 PR663.1 PU610.11 PU610.12
N18989999: PR659.2 PU610.2
N18990006: PC655.2 PU610.7
N18990008: PR660.2 PU610.5
N18990010: PC655.1 PR660.1
N18990122: PR686.2 PU610.17
N20151644: PR901.2 PR909.1
N27076067: PC944.1 PR934.2
N27077001: PR917.2 PR937.2
N28424999: T113.1(TP-1) UC1.AW71
N28425002: T114.1(TP-1) UC1.AW70
N28489601: RC222.1 SW1.2
N28769860: PR421.2 PR422.1 PU401.5
N28810563: CZ110.1 UZ2.10
N28811129: CZ114.1 UZ3.10
N28856399: T16.1(TP-1) UC1.BA70
N28856402: T17.1(TP-1) UC1.BA68
N28857231: T12.1(TP-1) UC1.BB68
N28857234: T13.1(TP-1) UC1.BB69
N28857237: T14.1(TP-1) UC1.AK13
N28857240: T15.1(TP-1) UC1.AK12
N28861827: RC120.1 UC1.C64
N28938912: CC8.1 RC29.2
N28938914: CC7.1 RC28.2
N29708559: T126.1(TP-1) UC1.AY4
N29708561: T127.1(TP-1) UC1.BB3
N29708639: T130.1(TP-1) UC1.BB5
N31877076: JEDP1.21 LV1.1
N32590572: CZ117.1 UZ4.12
N32592963: CZ118.1 UZ4.10
N32594166: CZ109.1 UZ2.12
N32817808: CZ113.1 UZ3.12
N32818355: RZ64.2 RZ65.2 UZ3.3
N32819772: CZ121.1 UZ8.6
N33612393: CD31.2 RD18.1
N35551576: PQ1209.2 PQ1209.3 PR1236.1
N35551581: PQ1209.6 PR1229.2
N35551592: PC1212.1 PR1237.2 PR1247.1 PU1201.6
N35551655: PC1205.1 PR1208.2 PR1217.1 PU1201.2
N35551713: PQ1201.6 PR1212.2
N35551785: PQ1203.2 PR1202.2 PR1209.1
N35551806: PQ1204.3 PR1209.2
N35551822: PQ1201.3 PR1213.2
N36307052: RT97.2 RT98.1 RT99.2 UT5.F10
N36307117: RT85.1 UT5.G4
N36307119: RT84.1 UT5.F4
N36307669: RT63.1 UT5.F1
N36307918: RT105.1 UT5.K10
N36307920: RT104.1 UT5.K9
N36307926: RT103.1 UT5.L11
N36626863: CT90.1 RT111.2 UT7.3
N36736352: RT85.2 T220.1(TP-1)
N36736355: RT84.2 T219.1(TP-1)
N36827741: RZ120.2 UZ26.4 UZ34.4
N38312012: CT87.1 UT5.H7
N38327809: RT101.1 UT5.D6
N38749366: QV2.1 RV5.2
N38749387: QV7.1 RV6.1 RV400.1
N38749389: CV635.1 QV8.2 RV400.2
N39469798: PR679.1 PU614.7
N39469818: PC631.1 PR630.2
N39469863: PC632.1 PR636.1 PU602.28
N39469972: PR678.2 PU602.38
N39469996: PC611.2 PU614.2
N39470129: PC640.1 PR646.2
N39470145: PC601.1 PR652.2
N39470173: PC632.2 PR641.1
N39470189: PH604.1 PR642.2
N39470446: PC603.1 PR602.1 PU602.34
N39470448: PC604.1 PR603.1 PU602.33
N39470528: PR608.1 PU602.32
N39470532: PR611.1 PU602.31
N40478997: QV4.2 RV18.2
N41228182: JNGFF2.17 RZ326.1
N41307615: CZ38.2 RZ334.1
N44311288: QE11.3 RE70.1 RE90.2
N44311298: QE4.2 RE70.2
N44321726: RE318.1 UE1.G2
N44321953: CE57.1 RE350.2
N44725169: CZ197.1 RZ345.2 UZ8.3
N44905504: JDIMM1.162 T50.1(TP-1)
N44907662: JDIMM1.165 T51.1(TP-1)
N45108671: JNGFF2.59 T225.1(TP-1)
N45160305: JESPI.8 RE375.1 RE560.1
N45555545: QZ3.1 RZ25.1
N46398406: JNGFF2.50 RZ132.2
N46646690: CZ56.1 RZ63.1
N46814682: PH601.2 PR610.1 PR631.2
N46814700: PC627.1 PR632.2
N46814728: PH602.1 PR628.2
N46814746: PC627.2 PR638.2 PU602.8
N46814769: PC617.2 PR621.1
N46815156: PR620.2 PU602.1
N46815164: PC621.2 PR623.1
N46815166: PR621.2 PR622.2 PR623.2 PU602.5
N46815186: PC616.2 PR617.2 PU602.4
N46815188: PC614.2 PR617.1
N46815204: PR610.2 PU602.3
N46815214: PC613.2 PR613.2 PU602.2
N46816449: PC647.2 PR650.2
N46816463: PC629.2 PR639.1
N46816511: PH603.2 PR635.1 PR647.2
N46816791: PC630.1 PR640.1 PU602.20
N46816817: PC630.2 PR644.1
N46816821: PH605.1 PR657.2
N46816907: PC639.2 PR645.1
N47939817: RC436.2 UC1.F65 UC1.G65
N47967122: RC437.2 UC1.K52
N47967641: RC438.1 UC1.AK52
N47969720: QC6.1 RC433.2
N47969722: CC340.1 QC7.2 RC432.2 RC433.1
N47973654: QE12.1 RE94.1
N47976312: RZ62.1 UZ12.27
N48430893: CE64.1 DE2.1 QE15.2 RE541.2 RE543.2 RE565.1
N48430899: QE17.1 RE546.2
N48704005: PL614.3 PR624.1
N49436611: CZ200.1 QZ1.2 RZ380.2
N119328643: PC938.1 PR930.1 PR931.2 PU901.25
N132000604: PC934.1 PR921.2
N132005053: PR917.3 PR938.2
N4977333418: PR932.1 PU901.27

Pads without a net: CLIP1 1; CLIP2 1; FD1 1; FD2 1; FD3 1; FD4 1; JAPS1 16 17 18; JDIMM1 87 88 91 92 95 97 100 101 104 105; JEDP1 16 20; JHDMI1 14; JIR1 3; JKBTP1 10 17; JNGFF1 6 16 17 19 20 21 22 25 26 27 28 31 32 34 59 61 65 67 68 71 73; JNGFF2 10 12 14 16 20 33 35 36 38 39 40 41 44 45 47 48 51 53 55 57 60; JNGFF3 6 8 20 22 24 26 28 30 32 34 36 40 42 44 46 48 56 58 67; JSD1 16; JSIM1 1 C4 C6 C8; JSPI1 17; JUSH1 2 17; PBATT1 11 12; PD2 2; PRP1 4 5; PU100 10 15; PU102 10; PU200 18 19; PU301 9 10 12; PU401 4; PU402 4; PU503 2 6 7; PU610 6 13 16 19; PU612 6 13 16 19; PU613 6 13 16 19; PU901 13; QL2 3 4 5; QZ7 1 2 6; RC22 2; RC27 2; RC405 2; RPC4 2 7; RT69 2; RT74 2; RT75 2; RT339 2; RZ326 2; UA1 4 11 12 15 23 24 48; UC1 A3 A4 A11 A26 A27 A29 A31 A33 A36 A38 A45 A47 A52 A65 A69 AB4 AB13 AB62 AC63 AD3 AD4 AE62 AE63 AF6 AF7 AF11 AF12 AF13 AF64 AF65 AF66 AF67 AF68 AF69 AF70 AF71 AG62 AG69 AG70 AH3 AH9 AH10 AH11 AH12 AH65 AH66 AH68 AH69 AH70 AH71 AJ3 AJ62 AK6 AK7 AK9 AK10 AK62 AK64 AK65 AK66 AK67 AK70 AL25 AL27 AL61 AL63 AM1 AM2 AM3 AM4 AM5 AN1 AN2 AN3 AN21 AN22 AN25 AN27 AN43 AN45 AN46 AN48 AN50 AN52 AN53 AN55 AN56 AN60 AN61 AN65 AN66 AP1 AP2 AP3 AP4 AP13 AP21 AP22 AP25 AP27 AP30 AP33 AP37 AP40 AP43 AP45 AP46 AP48 AP50 AP52 AP53 AP55 AP56 AP60 AP61 AP65 AP66 AR21 AR22 AR25 AR27 AR30 AR32 AR33 AR37 AR38 AR40 AR56 AR60 AR61 AR65 AR66 AT5 AT21 AT22 AT25 AT27 AT30 AT32 AT33 AT37 AT38 AT40 AT60 AT61 AT65 AT66 AU5 AU21 AU22 AU25 AU27 AU30 AU33 AU37 AU40 AU56 AU58 AU60 AU61 AU63 AU65 AU66 AW1 AW13 AW20 AW42 AW44 AW46 AW48 AW68 AW69 AY1 AY2 AY20 AY21 AY42 AY43 AY44 AY46 AY47 AY48 B2 B3 B11 B26 B27 B29 B31 B33 B36 B38 B45 B47 B52 B69 B70 BA3 BA4 BA7 BA8 BA9 BA42 BA43 BA44 BA46 BA47 BA48 BB2 BB4 BB7 BB9 BB11 BB42 BB44 BB46 BB48 BB57 BB66 C2 C4 C8 C11 C12 C13 C15 C27 C28 C29 C31 C32 C33 C36 C37 C38 C41 C54 C70 C71 D1 D3 D4 D5 D12 D13 D15 D27 D28 D29 D31 D32 D33 D36 D37 D38 D41 D54 D71 E1 E2 E10 E61 F6 F10 F52 F60 F61 G8 G61 H8 H11 H63 J1 J4 J5 J68 J71 K45 K46 L6 M1 M2 M3 M4 N1 N2 N3 N9 N11 P1 P3 P62 U6 U7 V1 V2 V62 W7 W12; UD1 1; UE1 B8 B9; UE4 1; UE6 1; UI3 9 15; UR1 31; UT1 A7 A9 A11 A13 A23 B7 B9 B11 B13 B23 D19 E18 E19 V18 W16 W19 Y16 Y19; UT7 4; UV24 3; UZ12 2 4 5 6 7 10 11 12 15 25 26 28 30 31; YC1 2 4; YC3 2 4

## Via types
v1: diameter 0.305, hole 0.152, TOP to BOTTOM, 766 vias
v2: diameter 0.457, hole 0.203, TOP to BOTTOM, 5851 vias
v3: diameter 0.406, hole 0.203, TOP to BOTTOM, 160 vias
v4: diameter 0.508, hole 0.254, TOP to BOTTOM, 71 vias

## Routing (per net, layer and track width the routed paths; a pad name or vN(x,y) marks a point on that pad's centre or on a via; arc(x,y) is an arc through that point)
0.6V_DDR_VTT_ON: length 6.8
  TOP w0.127: PR210.1 v1(74.08,74.13) 76.13,76.18 RD19.1 76.17,77.31 UD1.4
1.8V_PRIM_PWRGD: length 126.5
  TOP w0.127: UE1.L7 v2(255.08,88.26)
  IN2 w0.122: v2(215.94,70.81) 215.94,70.55 216.47,70.01 220.29,70.01 221.36,71.08 221.36,71.77 222.25,72.66 226.41,72.66 230.16,76.41 234.19,76.41 235.61,77.83 237.93,77.83 238.42,78.32 240.75,78.32 241.33,78.9 243.68,78.9 244.79,80.01 256.29,80.01 257.16,79.14 259.65,79.14 259.82,79.32 259.82,81.69 256.86,84.66 256.23,84.66 255.5,85.39 255.5,87.84 v2(255.08,88.26)
  BOTTOM w0.127: PU501.5 171.44,67.17 PR517.1 171.44,69.57 171.28,69.73 171.28,71.19 169.8,72.67 169.8,73.26 170.1,73.57 v1(173.19,73.57) 174.86,73.57 181.62,66.81 181.62,62.74 181.76,62.61 183.57,62.61 184.54,63.58 210.87,63.58 215.63,68.33 215.63,70.58 215.86,70.81 v2(215.94,70.81)
2.5VSP: length 2.3
  TOP w0.127: 147.17,62.73 147.17,63.95 v1(146.42,64.7)
3.3V_ALW2: length 9
  TOP w0.127: RE57.1 245.72,76.16 v1(245.72,76.8) 245.72,77.35 RE58.1 246.57,78.2 246.57,82.66 247.48,83.58 UE1.B1
3.3V_CAM_EN#: length 159.6
  TOP w0.076: v2(123.88,94.16) 124.18,93.86 124.18,93.11 124.45,92.85
  TOP w0.127: v2(58.25,122.47) 57.84,122.06 RZ380.1 ; RC311.1 128.93,89.38 126.11,92.2 125.21,92.2 v1(125.12,92.29) 124.56,92.85 124.45,92.85
  IN2 w0.122: v2(58.25,122.47) 59.1,123.32 60.28,123.32 61.94,124.97 67.93,124.97 69.64,126.68 72.28,126.68 73.75,125.22 75.56,125.22 76.23,124.55 81.33,124.55 82.55,125.77 82.55,125.78 83.53,126.76 85.22,126.76 85.55,127.09 89.18,127.09 90.2,128.11 101,128.11 101.37,127.74 102.84,127.74 104.03,128.93 115.69,128.93 116.02,129.26 122,129.26 122.23,129.03 124.45,129.03 125.09,129.67 138.51,129.67 140,128.18 140,127.29 142.56,124.72 143.9,124.72 144.62,123.99 144.62,120.37 142.36,118.11 140.68,118.11 137.48,114.9 137.48,112.67 138.39,111.76 138.39,111.58 140.66,109.3 140.88,109.3 141.82,108.36 141.82,105.32 139.42,102.93 139.42,102.07 138.71,101.36 138.71,98.37 137.56,97.23 137.56,95.9 136.5,94.83 129.95,94.83 129.65,95.13 129.03,95.13 128.97,95.11 128.61,94.75 128.18,94.75 127.62,95.31 127.31,95.31 126.85,94.85 125.48,94.85 125.06,95.28 124.41,95.28 124.25,95.12 124.25,94.52 v2(123.88,94.16)
  BOTTOM w0.102: v2(123.88,94.16) 124.18,94.45 UC1.AT15
3.3V_TS_EN: length 309.9
  TOP w0.127: UE1.J7 v2(253.48,88.26) ; v2(47.34,124.31) 47.34,120.02 48.17,119.19 48.2,119.19 48.22,119.16 RV323.1 ; RE547.1 264.06,89.45 v2(264.23,89.63) 264.23,89.87 v1(264.77,90.4)
  IN2 w0.122: v2(253.48,88.26) 253.48,88.4 251.56,90.32 251.56,90.76 251.26,91.07 248.48,91.07 248.28,90.86 248.28,90.42 248.12,90.27 239.32,90.27 237.05,88 237.05,86.88 234.79,84.63 234.79,82.02 235.93,80.88 237.09,80.88 237.32,80.64 237.32,79.9 235.99,78.56 231.74,78.56 231.28,79.02 225.21,79.02 224.85,78.66 224.85,75.55 223,73.7 217.59,73.7 214.2,70.3 208.4,70.3 207.33,71.37 188.96,71.37 187.32,73.01 183.41,73.01 174.37,82.05 174.37,83.79 172.37,85.79 172.37,87.53 171.62,88.29 171.62,89.36 170.34,90.64 170.34,92.77 169.64,93.47 169.64,106.53 164.9,111.26 164.9,114.7 165.28,115.08 165.28,126.64 162.23,129.69 161.51,129.69 161.08,130.12 160.68,130.12 160.08,130.73 160.08,131.72 158.48,133.32 154.75,133.32 152.84,131.41 148.44,131.41 144.39,135.46 107.69,135.46 106.2,133.97 83.96,133.97 82.45,132.46 82.45,132.1 79.46,129.1 76.54,129.1 75.7,129.95 73.78,129.95 71.04,132.69 69.46,132.69 67.78,134.36 50.68,134.36 v2(50.47,134.15)
  IN4 w0.084: v2(253.48,88.26) 253.86,87.88 255.96,87.88 256.32,87.53 260.18,87.53 261.01,88.36 262.96,88.36 v2(264.23,89.63)
  BOTTOM w0.127: v2(47.34,124.31) 47.34,125.83 50.47,128.96 v2(50.47,134.15)
3.3V_TS_EN_R: length 5.4
  TOP w0.127: v1(51.5,119.46) 50.66,118.62 RV326.2 50.04,118.27 RV324.2 RV323.2 49.45,119.24 49.06,119.63 49.03,119.63 48.39,120.27 QV7.2
3.3V_WWAN_EN: length 46.9
  TOP w0.127: UE1.C6 v2(247.88,87.46) ; UZ4.5 280.22,91.34 281.32,90.24 v1(281.32,89.41) 281.32,88.47 RZ40.2 v2(280,87.84)
  IN1 w0.084: v2(265.58,87.46) 267.28,85.76 267.28,85.16 269.44,83.01 274.53,83.01 279.37,87.84 v2(280,87.84)
  IN4 w0.084: v2(265.58,87.46) 265.46,87.59 260.86,87.59 259.98,86.7 259.98,85.03 259.67,84.73 256.93,84.73 255.4,86.26 252.32,86.26 252,86.57 252,86.92 251.87,87.05 249.23,87.05 249.06,87.22 249.06,87.61 248.9,87.77 248.13,87.77 247.88,87.52 v2(247.88,87.46)
3V5V_EN: length 67.8
  TOP w0.254: v2(152.04,78.31) v1(150.51,78.31) 147.67,78.31 146.83,77.47 v2(146.83,77.3)
  IN4 w0.203: v2(184.32,58.19) 184,58.19 183.22,58.97 183.01,58.97 181.45,57.4 179.99,57.4 179.79,57.6 174.44,57.6 173.12,58.91 168.5,58.91 167.66,58.08 159.13,58.08 158.19,59.02 158.19,66.25 157.38,67.07 150.29,67.07 146.01,71.35 146.01,75.13 146.11,75.23 146.11,76.58 v2(146.83,77.3)
  BOTTOM w0.254: v2(152.04,78.31) 152.51,78.77 PR116.1 152.7,78.8 PC128.1 154.01,78.51 PU100.12 ; PU102.12 184.49,58.02 v2(184.32,58.19) 184.32,58.4 PR114.2
3V_FB: length 3.3
  BOTTOM w0.127: PC113.1 155.61,78.86 v1(155.94,78.54)
  BOTTOM w0.254: PC113.1 154.46,78.57 PU100.13
3V_SN: length 1.3
  BOTTOM w0.127: PC112.1 v1(164.07,70.58)
3V_VIN:
  vias: v1(154.49,71.77) v2(153.81,72.35) v2(153.98,73.07) v2(154.53,72.34) v2(154.82,73)
5V_FB: length 3.5
  BOTTOM w0.127: v1(186.59,58.85) 186.51,58.93 PC127.1
  BOTTOM w0.254: PU102.13 184.94,58.46 184.86,58.53 PC127.1
5V_SN: length 1.2
  TOP w0.127: PC125.1 v1(190.14,57.25)
5V_VIN: length 0.8
  TOP w0.127: v1(182.24,51.62) 182.21,51.58 v2(181.45,51.58)
  vias: v2(178.84,52.08) v2(178.9,51.5) v2(181.07,52.02)
+0.6V_DDR_VTT: length 78.6
  TOP w1.016: 140.54,51.65 139.25,50.37 75.4,50.37 v3(74.37,51.4) 71.4,54.37 71.4,55.19
  IN4 w1.016: 72.22,63.23 72.67,62.79 72.67,59.5 72.27,59.1 72.27,57.14
  vias: v2(70.78,56.27) v2(71.41,56.27) v2(71.82,65.02) v2(71.83,64.43) v2(142.64,52.12) v2(143.25,52.12)
+0.6VSP: length 2.9
  TOP w0.127: 70.47,65.95 70.47,63.92 v1(71.08,63.31)
  vias: v2(69.89,67.34) v2(69.89,66.7) v2(70.35,70.1) v2(70.92,70.05)
+0.9V_LAN: length 7.3
  TOP w0.127: v2(242.53,129.36) 242.53,129.8 241.98,130.35 v3(241.86,130.35)
  TOP w0.203: UL1.40 244.04,126.93 v2(244.14,127.03) ; UL1.43 v2(244.19,125.73) ; UL1.22 v2(248.37,127.33) ; UL1.16 248.42,124.93 v2(248.37,124.98) ; UL1.37 242.87,128.13 242,129 CL10.1
  TOP w0.356: v2(242.53,129.36) 242.34,129.17 CL10.1
  vias: v2(244.14,124.34) v2(247.56,121.25) v2(248.58,121.97)
+0.9V_TBT_CIO: length 2.8
  TOP w0.356: CT39.1 28.89,100.34 29.33,100.78 v2(29.33,100.95) 29.37,100.91 CT40.1
  TOP w0.381: CT38.1 28.72,99.62 v2(28.68,99.65) 28.68,100.31 CT39.1
+0.9V_TBT_DP: length 2.8
  TOP w0.305: v2(28.03,101.6) 28.04,101.61 CT25.1 ; CT26.1 27.49,101.49 v2(27.38,101.6) 27.24,101.74 CT30.1
  TOP w0.381: CT27.1 27.43,99.6 v2(27.38,99.65)
  vias: v1(31.94,98.92) v2(29.98,99.65) v2(29.98,99)
+0.9V_TBT_LVR_OUT: length 0.9
  TOP w0.305: CT62.1 25.59,99.77 26.08,100.26 v2(26.08,100.3)
  vias: v1(22.71,94.23) v2(25.44,97.05) v2(26.08,97.05) v2(26.74,99.65)
+0.9V_TBT_PCIE:
  vias: v1(28.01,96.33) v2(27.38,98.35) v2(27.38,97.7) v2(27.38,97.05) v2(27.38,96.4)
+0.9V_TBT_SVR:
  vias: v1(21.99,98.69) v2(19.4,105.66) v2(19.47,105.07) v2(20.01,105.67) v2(20.04,105.09) v2(20.57,105.7) v2(20.6,105.14) v2(24.78,99.65) v2(24.78,99) v2(24.78,98.35) v2(24.78,97.7) v2(26.74,100.3) v2(27.38,100.3)
+0.9V_TBT_USB: length 2.7
  TOP w0.127: v1(30.77,96.21) 30.77,96.34 29.97,97.14 CT32.1
  TOP w0.254: CT32.1 29.88,97.15 v2(29.33,97.7) 28.87,97.7 CT33.1
+1.0V_AMPHYPLL: length 23.3
  TOP w0.381: CC264.1 123.97,107.63 v2(123.97,107.47)
  IN2 w0.254: v2(123.97,107.47) 125.07,108.56 125.07,109.88 125.49,110.3 125.49,112.52 127.05,114.08 127.05,119.5 127.3,119.75 127.3,121.36 128.25,122.31 128.63,122.31 129.06,122.73 129.06,123.63 128.27,124.42 v2(127.89,124.42)
  BOTTOM w0.127: 129.3,124.41 129.61,124.41 v1(130.02,124)
  BOTTOM w0.254: UC1.L15 v2(123.97,107.47) UC1.K15
+1.0V_APLL: length 13.8
  TOP w0.127: v2(128.43,121.68) 127.81,121.68 v1(127.74,121.61)
  IN2 w0.508: 127.02,110.83 127.02,112.31 127.71,113 127.71,116.99 128.39,117.68 128.39,119.45 128.03,119.81 128.03,121.18 128.42,121.57 128.42,121.68 v2(128.43,121.68)
  BOTTOM w0.254: UC1.V15 124.59,103.99 v2(124.59,104.15)
  BOTTOM w0.508: LC2.2 v2(128.43,121.68)
+1.0V_APLLEBB: length 14.7
  TOP w0.254: RC310.2 v1(131.57,122.38)
  TOP w0.381: v2(122.01,105.76) 122.01,105.61 121.43,105.03 CC218.1
  IN2 w0.254: 124.54,114.34 124.54,116.93 125.22,117.62 125.57,117.62 126.32,118.37 126.32,121.53 127.65,122.87 v2(128.46,122.87)
  BOTTOM w0.254: UC1.N18 122.31,106.2 122.01,105.83 v2(122.01,105.76)
+1.0V_CLK1: length 10.7
  TOP w0.508: v2(125.54,115.17) 125.31,115.4 125.31,116.11 126.13,116.94 v1(126.13,117.56) 126.13,121.04 125.82,121.36 RC302.2
  BOTTOM w0.203: 125.09,113.93 124.61,113.45 124.61,113.1 124.61,113.1 UC1.A14
  BOTTOM w0.508: v2(125.54,115.17) 125.25,114.88 125.25,114.08 125.09,113.93
+1.0V_CLK2: length 15.1
  TOP w0.508: v2(124.23,124.33) 124.23,121.66 123.57,120.99 123.57,120.14 121.9,118.47 121.9,117.55 122.86,116.59 v1(122.86,113.02) 122.86,111.66 122.5,111.3
  BOTTOM w0.254: UC1.K19 121.69,107.78 v2(122.01,107.46)
+1.0V_CLK3: length 14.5
  TOP w0.127: v2(120.79,107.46) 120.8,107.46 121.17,107.83 v1(121.39,107.83)
  TOP w0.381: RC303.2 124.93,121.93 v2(125.22,121.64)
  IN2 w0.381: 121.28,112.15 122.67,113.54 122.67,114.74 121.98,115.43 121.98,118.82 124.81,121.64 v2(125.22,121.64)
  BOTTOM w0.254: v2(120.79,107.46) 120.78,107.46 120.7,107.46 120.39,107.06 UC1.L21
+1.0V_CLK4: length 0.6
  BOTTOM w0.229: UC1.N20 120.96,106.2 120.71,105.95 v2(120.71,105.74)
  vias: v1(121.42,126.36) v2(122.2,124.22)
+1.0V_CLK5: length 18.5
  TOP w0.127: v2(121.38,106.66) 121.69,106.36 v1(121.69,106.18)
  TOP w0.356: RC52.2 119.99,105.88 120.36,106.25 120.97,106.25 v2(121.38,106.66)
  IN2 w0.381: 122.91,111.59 122.91,113.08 123.21,113.39 123.21,114.91 122.76,115.36 122.76,116.77 124.02,118.03 125.21,118.03 125.75,118.58 125.75,124.15 v2(125.91,124.3)
  BOTTOM w0.254: UC1.L19 v2(121.38,106.66)
+1.0V_CLK6: length 10.1
  BOTTOM w0.203: UC1.A10 127.09,113.74 127.4,114.06
  BOTTOM w0.381: RC300.2 127.48,121.6 126.41,120.53 CC216.1 126.21,117.57 126.87,116.9 v1(126.87,116.41) 126.87,116.09 127.4,115.56 127.4,114.06
+1.0V_DTS: length 19.8
  IN4 w0.381: v2(133.91,105.9) 134.64,106.64 139.25,106.64 140.33,107.72 142.76,107.72 143.34,108.31 146.45,108.31 v2(148.13,106.63)
  BOTTOM w0.076: v2(133.91,105.9) v1(134.97,105.9)
  BOTTOM w0.203: UC1.T1 132.64,105.16 133.01,105.53 133.53,105.53
  BOTTOM w0.381: 133.53,105.53 v2(133.91,105.9)
  BOTTOM w0.508: RC301.2 148.19,106.56 v2(148.13,106.63)
+1.0V_MPHYAON: length 2.6
  TOP w0.508: CC203.1 123.2,108.1 122.66,107.56 v2(122.66,107.46)
  BOTTOM w0.254: v2(133.03,107.58) 132.32,107.58 UC1.L1 ; v2(122.66,107.46) UC1.K17
  vias: v1(135.43,108.93) v2(133.63,107.58)
+1.0V_MPHYGT: length 8.8
  BOTTOM w0.254: UC1.P16 123.64,105.47 v2(123.33,105.78) 122.99,106.12 UC1.N17 ; UC1.P15 124.6,105.67 v2(124.6,105.78) 124.6,105.89 UC1.N15 ; UC1.N16 v2(123.95,106.59)
  BOTTOM w2.032: 138.15,118.71 138.14,118.71 134.01,114.58 134.01,114.31
  vias: v1(137.53,123.21) v2(130.75,125.09) v2(131.35,125.06) v2(131.95,125.04) v2(133.92,112.87) v2(133.92,112.26) v2(134.56,112.87) v2(134.56,112.26) v2(138.21,120.83) v2(138.2,120.26) v2(138.78,120.83) v2(138.78,120.25)
+1.0V_PRIM: length 34.3
  TOP w0.254: CZ105.1 118.49,128.87 114.19,133.16 106,133.16 105.61,133.55 RC216.1
  TOP w0.508: v2(121.36,101.54) 120.74,102.16 CC206.1
  BOTTOM w0.254: UC1.P18 122.34,105.42 v2(122.67,105.76) ; UC1.AK20 v2(121.36,98.24) ; UC1.AB19 v2(121.36,101.54) UC1.AB20 ; v2(122.01,103.27) 122.34,102.94 UC1.Y18 122.34,102.66 UC1.AB17
  BOTTOM w0.508: RC301.1 150.54,106.56 v2(151.24,107.26)
  vias: v2(122.48,129.72) v2(123.09,129.68) v2(123.72,129.68) v2(127.06,123.71) v2(127.63,123.72) v2(128.26,123.69) v2(140.01,123.65) v2(140.6,123.65) v2(141.18,123.65) v2(141.77,123.65) v2(142.35,123.65) v2(142.93,123.65) v2(143.52,123.65) v2(159.65,89.45) v2(159.65,88.84) v2(160.29,89.45) v2(160.29,88.83) v2(160.9,89.4) v2(160.85,88.81) v2(161.45,88.8) v3(128.22,126.31)
+1.0V_PRIM_CORE: length 3.6
  TOP w0.127: v2(147.29,118.14) v3(147.29,118.81)
  TOP w0.457: CC205.1 121.88,100.62 v2(122.01,100.75)
  BOTTOM w0.254: UC1.AF19 121.69,100.43 v2(122.01,100.75) 122.01,100.66 UC1.AF18 ; UC1.V21 120.39,103.8 v2(120.69,104.11) 120.69,104.06 121.04,103.71 UC1.V20
  vias: v2(145.2,102.98) v2(145.48,118.14) v2(146.08,118.14) v2(146.27,102.97) v2(146.69,118.14) v2(147.07,101.71) v2(147.07,101.15)
+1.0V_PRIM_COREP: length 7.9
  IN4 w0.254: v2(155.46,132.79) 154.63,132.79 152.17,130.33 151.53,130.33 150.64,129.44 v2(150.64,128.43)
  BOTTOM w0.254: PR423.2 v2(155.46,132.79)
  vias: v1(153.16,125.79) v2(149.97,128.68) v2(149.96,127.96) v2(149.96,127.38)
+1.0V_PRIM_XDP: length 29.3
  TOP w0.254: v2(90.61,131.8) 90.61,132.11 89.95,132.77 RC115.2 90.55,133.17 CC28.1 CC29.1 91.36,133.26 91.65,133.55 RC216.2
  BOTTOM w0.254: RC138.2 103.25,126.71 104.08,126.71 v1(104.76,127.39) 104.76,132.43 103.78,133.42 90.87,133.42 90.61,133.16 JXDP1.44 v2(90.61,131.8) 90.61,131.16 90.91,130.86 JXDP1.43
+1.0V_SRAM: length 16.8
  TOP w0.381: CC217.1 120.59,100.83 v2(120.72,100.7)
  TOP w0.762: 131.72,115.07 132.85,115.07 v1(134.43,116.65) 136.04,118.27 RC309.2
  IN4 w0.762: 126.78,111.1 127.35,111.1 129.07,112.82 131.29,112.82 131.77,113.31 131.77,113.32
  BOTTOM w0.254: UC1.AF21 v2(120.72,100.7) UC1.AF20 ; UC1.T19 v2(121.33,104.08) UC1.T20
  vias: v2(131.57,114.23) v2(132.15,114.23)
+1.0V_VCCST: length 538.5
  TOP w0.254: v2(265.86,107.9) v3(265.86,105.24) 265.86,103.34 v2(265.02,102.5) 264.67,102.86 264.67,103.62 264.2,104.09 263.5,104.09 RE90.1 ; v2(253.41,99.22) 253.8,98.84 254.81,98.84 255.04,98.61 RE59.2
  TOP w0.381: v2(92.84,124.46) 92.84,124.35 90.89,122.41 v2(90.89,122.24)
  TOP w0.457: v2(119.98,107.5) 120.2,107.72
  TOP w0.508: CC202.1 119.68,108.24 CC341.1 120.2,107.72 ; RZ151.2 122.26,121.37 122.59,121.04 CC195.1 122.59,120.12 v2(120.44,117.97) 120.44,115 121.29,114.14 v2(122.13,114.14)
  IN1 w0.254: v2(161.11,56.22) 161.02,56.13 148.13,56.13 145.88,53.88 142.16,53.88 141.27,53 130.2,53 127.15,49.95 73.56,49.95 v2(72.44,51.06)
  IN1 w0.508: v2(54.33,116.27) 54.09,116.51 48.85,116.51 45.35,113.01 v2(45.35,112.7)
  IN2 w0.508: v2(63.21,116.79) 62.95,117.04 62.95,118.25 65.14,120.44 76.98,120.44 77.71,119.71 88.43,119.71 90.89,122.17 v2(90.89,122.24) 91.84,122.24 92.72,121.36 v2(94.5,121.36) 94.5,121.77 94.97,122.24 95.98,122.24 96.75,121.47 97.79,121.47 98.26,121.95 98.26,122.4 99.12,123.27 101.37,123.27 103.34,121.29 109.21,121.29 111.75,118.75 119.66,118.75 v2(120.44,117.97) ; v2(45.35,112.7) 45.35,112.67 44.33,111.65 44.33,108.42 42.27,106.36 42.27,102.26 43.09,101.43 43.09,97.67 42.81,97.4 42.81,96.44 43.32,95.93 v2(43.38,95.93)
  IN4 w0.254: v2(161.11,56.22) 161.11,56.62 161.46,56.98 165.18,56.98 166.56,55.6 173.02,55.6 173.59,56.17 177.78,56.17 178.16,56.55 183.95,56.55 185.24,57.84 185.24,58.31 185.5,58.57 195.43,58.57 196.25,57.75 198.65,57.75 199.11,57.29 199.11,54.32 200.1,53.33 203.86,53.33 203.86,53.33 210.18,53.33 210.56,52.94 213.23,52.94 213.94,52.23 218.62,52.23 219.48,53.1 224.34,53.1 224.95,52.49 227.97,52.49 230.49,49.97 247.72,49.97 250.16,52.41 250.16,56.2 249.2,57.16 249.2,62.44 250.75,63.99 254.61,63.99 255.3,63.3 262.13,63.3 263.42,64.59 263.42,67.5 264.06,68.13 264.06,69.43 263.79,69.7 263.79,72.72 265.91,74.84 269.82,74.84 270.74,73.92 278.15,73.92 280.63,76.4 280.63,80.34 275.68,85.29 275.68,93.27 274.47,94.47 274.47,96.23 270.98,99.72 270.98,102.78 v2(265.86,107.9) ; v2(253.41,99.22) 252.82,99.81 252.82,100.17 256.44,103.78 263.74,103.78 v2(265.02,102.5) ; v2(72.44,51.06) 72.44,51.83 71.91,52.36 70.99,52.36 68.78,54.57 65.33,54.57 62.28,51.52 60.88,51.52 60.17,50.81 55.45,50.81 55.24,51.01 52.93,51.01 52.01,50.09 49.77,50.09 48.62,51.24 45.16,51.24 44.85,50.94 43.2,50.94 42.41,51.74 37.83,51.74 31.27,58.3 31.27,66.41 34.82,69.97 34.82,70.45 36.77,72.4 36.77,75.55 38.36,77.14 38.36,81.47 39.85,82.96 39.85,85.49 42.82,88.46 44.11,88.46 44.32,88.67 44.32,89.21 44.31,89.22 44.31,91.29 43.38,92.21 v2(43.38,95.93)
  BOTTOM w0.152: UC1.A18 122.13,113.15 122.17,113.19 122.17,114.1 v2(122.13,114.14)
  BOTTOM w0.254: v2(119.98,107.5) 120.09,107.5 120.11,107.52 120.11,107.6 UC1.K21 120.5,107.98 120.88,107.98 120.98,107.88 UC1.K20
  BOTTOM w0.381: RC79.2 96.29,121.83 96.01,122.11 94.87,122.11 94.5,121.74 v2(94.5,121.36) ; RC120.2 RC157.2 92.67,120.65 RC152.2 92.66,121.07 92.95,121.36 v2(94.5,121.36) ; RC218.2 v2(92.84,124.46) ; RC71.2 v2(90.89,122.24) ; v2(94.5,121.36) RC80.2
  BOTTOM w0.508: v2(63.21,116.79) 58.72,116.79 58.2,116.27 v2(54.33,116.27) ; v2(43.38,95.93) 43.38,95.21 PR605.1 PR604.1 PR601.1 PC602.1
+1.0V_VCCSTG: length 79.6
  TOP w0.254: v2(80.13,117.55) 81.84,119.27 85.54,119.27 v3(86.91,120.64) 87.13,120.64 87.85,121.36 v2(88.38,121.36) ; v2(102.45,120.98) 101.99,121.44 RC130.2
  TOP w0.508: CC199.1 117.11,108.86 RC143.2 117.24,109.33 118.01,110.09 118.01,111.65 119.64,113.28 v2(119.64,113.86) 119.64,114.81 119.02,115.43 119.02,118.45 120.86,120.29 RZ151.1
  IN2 w0.254: v2(119.64,113.86) 120.45,114.67 120.45,116.87 119.12,118.21 111.61,118.21 109.01,120.81 102.62,120.81 v2(102.45,120.98) 101.05,120.98 v2(99.39,122.64)
  BOTTOM w0.203: v2(119.64,113.86) 119.65,113.84 UC1.A22
  BOTTOM w0.254: v2(99.39,122.64) 99.02,122.27 RC81.2 98.53,122.01 98.07,121.55 RC87.2 ; v2(99.39,122.64) 99.91,122.12 RC82.2 ; v2(99.39,122.64) 99.19,122.64 99.02,122.82 94.41,122.82 94.09,122.49 91.44,122.49 91.12,122.82 89.51,122.82 89.11,122.43 RC83.2 88.91,121.36 v2(88.38,121.36) ; RC135.2 82,117.85 81.2,117.05 80.48,117.05 80.13,117.41 v2(80.13,117.55)
  BOTTOM w0.305: v2(80.13,117.55) 80.13,118.52 RC134.2 79.74,118.87 79.21,119.4 79.21,120.19 RC131.2
+1.0V_VCCSTG_C: length 1
  TOP w0.127: v1(122.27,126.01) 121.91,126.37 CZ106.1
+1.0V_VCCSTG_R: length 0.5
  BOTTOM w0.254: v2(121.07,109.54) UC1.G20
  vias: v1(119.72,111.36)
+1.0VO_DSW: length 2.4
  TOP w0.127: v1(132.7,97.32) 132.87,97.15 v2(132.87,96.78)
  TOP w0.381: CC204.1 132.54,96.45 v2(132.87,96.78)
  BOTTOM w0.203: v2(132.87,96.78) 132.64,97.01 132.29,97.01 UC1.AL1
+1.0VS_VCCIO: length 248.2
  TOP w0.254: v2(166.15,122.87) 165.63,122.35 165.63,121.34 166.31,120.67 166.31,116.59 164.06,114.34 164.06,110.58 169.11,105.52 169.11,99.23 arc(169.54,94.27) 170.83,89.46 arc(173.59,83.84) 177.51,78.95 178.35,78.11 arc(186.44,72.7) 195.99,70.8 209.3,70.8 209.64,71.14 v2(209.64,71.47)
  TOP w0.381: v2(253.41,100.04) 253.76,100.38 256.03,100.38 256.84,101.18 256.84,101.31 257.15,101.62 257.85,101.62 QE11.1
  TOP w0.508: RC2.2 v2(102.75,107.96)
  IN1 w0.254: v2(132.96,125.27) 133.19,125.05 139.06,125.05 140.32,126.31 157.69,126.31 158.65,125.36 158.65,124.01 159.95,122.71 165.99,122.71 v2(166.15,122.87)
  IN2 w0.254: v2(209.64,71.47) 209.64,71.55 210.74,72.65 212.88,72.65 214.53,74.31 222.73,74.31 224.33,75.91 224.33,78.95 225.07,79.69 232.09,79.69 232.69,80.29 232.69,86.61 241.77,95.69 243.1,95.69 244.23,96.82 246.37,96.82 248.08,98.53 248.08,99.13 248.39,99.44 250.07,99.44 250.56,98.94 252.32,98.94 v2(253.41,100.04)
  IN4 w0.508: v2(102.75,107.96) 102.75,108.23 103.09,108.57 107.27,108.57 107.67,108.16 107.67,107.15 106.6,106.08 106.6,100.19 107.71,99.08 107.71,97.22 v2(108.27,96.66)
  BOTTOM w0.203: UC1.AK30 115.35,98.22 v2(115.58,98.22) ; v2(115.58,98.22) UC1.AL30 ; v2(115.58,98.22) 115.81,98.22 UC1.AK28 ; UC1.AL30 115.12,97.07 UC1.AM30 ; UC1.AL30 v2(115.58,96.66)
  BOTTOM w0.254: v2(114.67,96.66) UC1.AM30 ; v2(121.65,122.04) 120.99,122.7 120.99,124.35 119.8,125.54 118.64,125.54 118.3,125.2 101.48,125.2 100.89,124.61 94.34,124.61 92.72,126.24 RC132.2 ; UC1.AL42 v2(109.18,96.66) UC1.AM42 v2(108.27,96.66) ; UC1.AM28 v2(115.58,96.66)
  vias: v2(132.95,127.97) v2(132.96,128.54) v2(133.53,127.96) v2(133.58,128.53) v2(134.13,127.96) v2(134.18,128.53) v3(115.78,97.19)
+1.2V_DDR_B+: length 1.6
  TOP w0.127: PC200.1 66.67,73 v1(66.32,72.64)
  vias: v2(65.87,75.07) v2(65.87,74.43) v2(65.87,73.8) v2(66.51,75.32)
+1.2V_DDRP: length 22.5
  TOP w0.254: PR204.1 PC208.1 v2(62.94,70.81)
  TOP w0.508: v2(69.88,68.89) 70.21,69.23 PC209.1
  IN1 w0.254: v2(62.94,70.81) 62.94,60.2 64.31,58.83 65.47,58.83 v2(66,58.3)
  BOTTOM w1.016: 70.76,61.09 70.76,66.42
  vias: v1(66.13,59.24) v2(66.64,58.3) v2(67.27,58.3) v2(67.91,58.3) v2(68.54,58.3) v2(69.18,58.3) v2(69.94,59.83) v2(69.94,59.19) v2(69.94,58.56) v2(69.94,57.92) v2(70.57,59.83) v2(70.57,59.19) v2(70.57,58.56) v2(70.57,57.92) v2(71.21,59.83) v2(71.21,59.19) v2(71.21,58.56) v2(71.21,57.92)
+1.2V_LDO: length 0.8
  TOP w0.127: v2(275.77,60.59) 275.25,60.59 v1(275.02,60.81)
  vias: v2(271.78,61.73) v2(271.78,61.15) v2(275.41,60.11)
+1.2V_MEM: length 75
  TOP w0.381: 72.92,62.43 72.63,62.72 72.63,67.49 78.44,73.3 CD32.1 78.44,77.69 UD1.5
  BOTTOM w0.152: v2(114.59,90.14) 114.58,90.15 UC1.BB32
  BOTTOM w0.178: v2(105.97,90.33) UC1.BB47 ; v2(119.75,89.76) 119.61,89.9 119.61,91.05 UC1.BB23
  BOTTOM w0.203: v2(109.52,90.1) 109.52,90.99 UC1.BB41 ; v2(103.47,90.11) 103.52,90.16 UC1.BB51
  BOTTOM w0.254: UC1.AU35 v2(111.93,94.12) ; UC1.AU28 v2(115.58,94.15) ; JDIMM1.123 106.72,62.77 v2(107.25,63.3) ; UC1.AU23 v2(118.32,94.16) ; UC1.AU42 v2(109.17,94.12)
  BOTTOM w0.305: v2(132.97,52.46) 132.98,52.46 JDIMM1.220 ; JDIMM1.153 116.23,63.25 v2(116.37,63.39) 115.31,63.39 114.72,62.81 JDIMM1.147 ; JDIMM1.118 105.47,52.63 v2(105.47,52.46) 105.4,52.54 104.28,52.54 103.97,52.84 JDIMM1.112 ; JDIMM1.154 v2(116.48,55) ; JDIMM1.130 108.48,52.84 108.1,52.46 v2(107.72,52.46) 107.31,52.46 106.97,52.8 JDIMM1.124 ; JDIMM1.75 94.72,63.1 95.34,63.71 v2(95.98,63.71) ; v2(122.35,55) 122.47,54.87 JDIMM1.178 ; JDIMM1.111 103.72,62.87 104.1,63.24 v2(104.88,63.24) 104.92,63.24 105.22,62.94 JDIMM1.117 ; JDIMM1.159 117.72,63.12 117.99,63.38 v2(118.06,63.38) 118.44,63.38 118.72,63.1 JDIMM1.163 ; JDIMM1.141 111.22,62.82 111.66,63.26 v2(112.16,63.26) ; JDIMM1.135 109.72,62.86 109.31,63.27 v2(108.83,63.27) 108.58,63.27 108.22,62.92 JDIMM1.129 ; JDIMM1.96 v2(99.97,55) ; v2(111.48,55) JDIMM1.142 ; JDIMM1.241 138.23,62.83 138.17,62.88 138.17,63.31 138.63,63.78 v2(138.79,63.78) ; v2(127.68,63.18) 127.72,63.13 JDIMM1.199 ; JDIMM1.160 117.97,53.7 v2(117.97,55) ; v2(78.97,54.94) JDIMM1.12 ; JDIMM1.136 109.97,52.86 110.38,52.45 v2(110.59,52.45) ; v2(89.18,55) 89.18,54.85 89.47,54.55 JDIMM1.54 ; JDIMM1.148 v2(114.98,55) ; v2(83.47,63.8) 83.81,63.8 84.22,63.38 JDIMM1.33
  vias: v3(131.8,66.03)
+1.2V_MEM_CPUCLK: length 3.2
  TOP w0.127: v2(110.09,96.66) 109.96,96.66 v1(109.62,96.33)
  TOP w0.305: v2(110.09,96.66) 109.55,97.21 RC231.1 109.55,98.37 CC297.1
  BOTTOM w0.152: UC1.AM40 110.03,96.66 v2(110.09,96.66)
+1.8V_3.3V_ALW_VTR3: length 33.8
  TOP w0.254: v2(255.43,76.07) 255.43,76.39 RE549.1 ; RE340.2 270,81.45 265.66,81.45 v2(264.84,82.28) 264.51,82.61 v1(264.51,84.06) 264.51,87.7 264.18,88.03 PJP20.2 PJP21.2 259.37,88.03 258.53,87.2 CE21.1 258.52,87.06 UE1.N5
  IN4 w0.254: v2(264.84,82.28) 260.56,82.28 255.43,77.15 v2(255.43,76.07)
+1.8V_PGPPF: length 7.7
  TOP w0.381: v2(123.9,100.75) 123.9,100.86 124.26,101.22 124.82,101.22 124.86,101.19 v1(126.26,101.19) 126.31,101.19 126.34,101.16 130.5,101.16 RC304.2
  BOTTOM w0.254: UC1.AF16 123.89,100.59 123.89,100.68 123.87,100.7 123.87,100.72 v2(123.9,100.75)
+1.8V_PRIM: length 232.6
  TOP w0.381: RC304.1 131.56,101.05 CC212.1 132.42,101.8 133.06,102.43 v2(133.06,102.49) 133.08,102.47 133.08,102.32 133.43,101.96 135.51,101.96 135.88,101.59 139.62,101.59 v2(139.68,101.65) 139.7,101.64 139.7,100.87 RC234.1
  TOP w0.508: RC212.1 148.4,85.91 148.4,88.3 149.5,89.41 v3(149.93,89.41) 151.21,89.41 152.16,90.37 153.09,90.37 v2(154.12,89.34)
  IN1 w0.508: v2(154.12,89.34) 154.27,89.49 154.27,91.53 v2(155.5,92.76) ; v2(263.59,87.13) 263.59,86.69 266.83,83.45 266.83,79.36 v2(267.31,78.88)
  IN2 w0.508: v2(247.51,51.53) 245.54,49.57 212.14,49.57 v2(211.16,50.54)
  IN4 w0.508: v2(267.31,78.88) 267.31,78.19 261.02,71.9 261.02,69.44 262.17,68.29 262.17,66.32 261.26,65.41 260.26,65.41 259.84,65.83 251.39,65.83 247.29,61.72 247.29,60.72 246.85,60.27 246.85,57.62 248.23,56.24 248.23,54.31 247.51,53.59 v2(247.51,51.53) ; v2(139.68,101.65) 139.68,103.25 143.16,106.73 147.06,106.73 151.28,102.51 153.35,102.51 155,100.86 155,96.28 155.5,95.78 v2(155.5,92.76) ; v2(154.12,89.34) 155.32,88.14 162.4,88.14 162.96,88.71 163.47,88.71 166.95,85.23 166.95,82.11 171.16,77.9 171.16,73.94 v2(170.25,73.04)
  BOTTOM w0.203: UC1.AA1 132.11,102.49 133.06,102.49 v2(133.06,102.49)
  BOTTOM w0.508: v2(139.68,101.65) 139.53,101.8 RC313.1 ; 180.96,61.39 180.59,61.76 180.59,65.93 175.08,71.44 171.85,71.44 v2(170.25,73.04) ; 206.03,51.61 207.1,50.54 v2(211.16,50.54)
  BOTTOM w0.762: 204.53,51.98 204.16,52.35 204.16,56.33 202.8,57.7 202.8,60.6 200.98,62.42 185.3,62.42 184.27,61.39 180.96,61.39 180.36,60.79
  vias: v2(205.67,52.72) v2(205.68,52.12)
+1.8V_RUN: length 166.6
  TOP w0.254: 213.41,51.55 213.41,52.16 212.67,52.89 206.97,52.89 206.37,53.49 205.29,53.49 203.03,55.75 203.03,56.74 201.98,57.8 201.98,59.55 200.32,61.2 185.52,61.2 v2(183.48,63.24)
  TOP w0.508: v2(224.43,51.09) 224.35,51.09 224,50.73 222.51,50.73 220.47,52.77 219.37,52.77 218.03,51.44 v3(217.2,51.44) 213.93,51.44 ; CA66.1 CA65.1 264.76,55.83 RA3.2 264.69,55.28 v2(264.98,54.99)
  IN2 w0.254: v2(163.38,89.52) 163.38,89.9 162.38,90.9 158.66,90.9 158.32,91.23 150.49,91.23 149.51,92.21 149.51,92.98 150.19,93.66 150.19,96.44 148.91,97.72 147.6,97.72 146.4,98.92 142.91,98.92 141.35,97.36 v2(141.35,96.33)
  BOTTOM w0.254: v2(141.35,96.33) 141.35,96.43 140.98,96.8 RC362.2 RC363.2 ; v2(183.48,63.24) 183.48,67.16 171.52,79.12 166.4,79.12 165.7,79.82 165.7,88.36 164.43,89.63 163.48,89.63 v2(163.38,89.52)
  BOTTOM w0.508: v2(264.98,54.99) 261.86,51.87 256.37,51.87 254.6,50.09 224.75,50.09 224.19,50.66 224.19,50.85 v2(224.43,51.09)
+1.8V_RUN_AUDIO: length 7.8
  TOP w0.127: v1(263.54,53.69) 263.26,53.97 CA69.1
  TOP w0.203: UA1.36 259.53,56.99 259.61,56.91 v2(259.99,56.91) ; v2(261.47,58.94) 261.31,58.94 260.92,59.34 UA1.40
  IN2 w0.508: v2(261.67,56.96) 261.62,56.91 v2(259.99,56.91) 259.99,57.97 260.96,58.94 v2(261.47,58.94)
+1.8V_RUN_CARD: length 20.9
  TOP w1.016: 297.71,59.04 295.13,59.04 293.64,60.54 285.93,60.54 v1(284.05,62.42)
  IN2 w1.016: 276.27,61.56 281.61,61.56 281.98,61.92
  vias: v2(275.66,61.78) v2(275.66,61.2) v2(283.09,62.6) v2(283.17,62.03)
+1.8V_RUN_UZ8:
  vias: v1(209.85,52.36)
+1.8VALWP: length 12.4
  BOTTOM w0.254: PR501.1 PC503.1 174.31,69.66 175.65,69.66 179.41,65.9 v1(179.41,65.36) 179.41,63.45 178.2,62.24
  vias: v2(178.28,61) v2(178.75,61.42)
+1VALWP: length 25
  TOP w0.254: PR306.1 153.35,79.51 PC307.1 v2(153.21,78.11)
  IN1 w0.254: v2(161.78,86.26) 164.35,86.26 165.4,85.22 165.4,80.82 164.71,80.13 158.05,80.13 157.3,80.88 155.42,80.88 153.21,78.68 v2(153.21,78.11)
  vias: v1(161.4,87.93) v2(161.74,85.65) v2(161.78,87.51) v2(161.78,86.9)
+1VALWP_B+:
  vias: v1(154.2,87.96) v2(151.59,86.36) v2(151.96,86.89) v2(152.58,86.98)
+1VS_VCCIOP: length 12.1
  TOP w0.254: v2(132.37,130.93) 132.92,130.93 v1(134.52,129.33) 135.13,128.72 v2(135.13,128.14)
  BOTTOM w0.254: v2(132.37,130.93) 132.37,130.95 133.14,131.71 133.61,131.71 134.56,132.66 PR421.1
  vias: v2(135.11,127.55) v2(135.43,127.07) v2(135.44,126.5)
+2.5V_MEM: length 2.8
  TOP w0.127: v3(144.58,65.18) 145.74,64.02 PJP506.2
  vias: v2(143.28,62.24) v2(143.28,61.61)
+2.5V_VIN:
  vias: v1(152.58,60.11)
+3.3V_1.8V_PGPPA: length 32.1
  TOP w0.254: 146.28,84.71 146.45,84.88 146.45,86.08 145.67,86.85 144.24,86.85 143.95,86.56 141.75,86.56 141.42,86.89 139.73,86.89 138.88,87.74 137.51,87.74 136.99,88.26 v1(136.99,88.8) 136.99,89.29 v2(136.29,89.99)
  IN1 w0.254: v2(136.29,89.99) 135.65,90.64 129.48,90.64 127.02,93.09 127.02,96.46 127.02,96.46 127.02,96.92 126.13,97.8 125.28,97.8 v2(124.73,97.25)
  BOTTOM w0.254: UC1.AK15 124.73,97.38 v2(124.73,97.25)
+3.3V_1.8V_PGPPG: length 18.1
  TOP w0.254: RC234.2 137.9,100.85 RC235.2 137.02,100.86 CC326.1 137.01,100.33 136.87,100.19 v2(136.87,99.86)
  IN2 w0.254: v2(136.87,99.86) 136.87,99.39 135.15,97.68 132.39,97.68 130.4,99.67 130.01,100.06 125.25,100.06 v2(124.6,100.7)
  BOTTOM w0.254: UC1.AD15 124.29,101.12 124.6,100.8 v2(124.6,100.7)
+3.3V_ALW: length 386.6
  TOP w0.127: CE61.1 v3(272.81,87.3)
  TOP w0.254: RE561.2 261.79,81.38 v2(261.49,81.09) 261.14,81.09 RE37.2 ; 157.68,82.63 157.3,82.63 157.04,82.89 PU301.15 ; v2(258.8,81.71) RE43.2
  TOP w0.305: JAPS1.7 261.56,108.9 v2(261.62,108.96) ; JAPS1.3 v2(263.56,108.96)
  TOP w0.356: UZ10.5 265.72,84.83 CZ93.1 265.71,85.55 v2(265.62,85.63)
  TOP w0.381: RE12.2 v2(261.52,79.96) ; RC68.2 142.63,81.39 v2(143.2,81.39) ; UZ34.5 141.49,67.7 CZ104.1 ; RE84.2 249.99,102.07 v2(249.56,102.5) 249.87,102.81 RE79.2 ; QZ2.2 v2(270.34,83.89) ; RE25.1 258.42,96.98 RE35.2 RE38.2 RE8.2 ; PR933.1 54.82,51.74 v2(55.09,51.47) ; v2(246.28,97.8) 246.06,97.8 245.64,98.23 RE10.2 ; UE4.5 269.88,98.83 269.82,98.9 UE3.5 268.24,99.16 CE53.1 268.24,100.68 RE69.1 ; UE6.5 v2(269.52,80.73) ; UE5.5 264.99,98.96 264.83,99.12 CE52.1 264.96,100.15 v2(265.45,100.15) ; PR307.1 165.96,82.04 v2(166.21,81.78) ; RE91.2 RE83.2 ; PR1231.2 50.06,53.03 v2(49.62,53.48) 48.86,54.24 46.89,54.24 46.57,53.92 46.57,53.16 47.08,52.65 PR1233.2 PR1230.2 45.88,52.4 45.03,52.4 PR1232.2 44.47,52.09 PR1234.2 43.71,51.59 v2(43.71,52.21)
  TOP w0.508: CE53.1 v2(267.65,100.02) ; 157.68,82.63 158.04,82.99 PC312.1 ; v2(162.56,124.53) 161.89,125.2 PR417.1 ; v2(257.71,97.8) 257.66,97.85 RE300.2 256.63,97.66 RE8.2 ; RE303.2 RE68.2 ; RE303.2 RE302.2 ; RE303.2 238.77,86.24 v2(238.66,86.36) ; v2(140.05,131.19) 140.36,130.88 PR404.1 ; RC214.2 147.7,79.11 146.73,80.08 144.79,80.08 143.48,81.39 v2(143.2,81.39) ; PR4.2 44.22,118.74 v2(43.54,118.06) ; v2(124.44,133.12) 124.23,133.33 124.23,134.86 124.71,135.34 140.34,135.34 PR413.1 141.2,134.68 141.92,135.39 143.38,135.39 143.98,134.8 PR414.1 v2(144.71,133.75) ; 166.72,66.06 167.55,65.23 PR1.1 ; PR418.1 v2(157.14,132.43) ; v2(271.26,86.66) 271.69,87.09 CE61.1 ; PR410.1 v2(165.25,129.3) ; 228.85,57.92 229.17,57.61 232.81,57.61 233.32,57.1 RZ8.1 234.34,55.21 235.11,54.43 235.11,53.02 234.61,52.51 RZ9.1 ; v2(246.28,97.8) 246.59,97.48 RE21.2 RE301.2 247.36,97.69 247.8,98.13 RE5.2 ; CZ104.1 142.05,67.14 v2(143.66,67.14) ; v2(59.43,118.18) 59.35,118.27 59.35,119.35 59.71,119.71 PR28.2 ; RE526.1 221.33,55.75 v2(221.13,55.95) ; RC431.2 v2(151.27,76.91) ; v2(261.44,85.96) CE60.1 ; RE11.2 v2(247.04,79.41) ; v2(248.92,77.03) 248.8,77.14 RE343.2 248.75,77.79 RE362.1 ; RE83.2 250.85,99.67 RE63.2 251.63,99.75 v2(251.67,99.71)
  IN1 w0.381: v2(226.91,58.16) 226.17,57.41 222.36,57.41 222.03,57.75 220.77,57.75 220.05,57.03 220.05,56.27 220.37,55.95 v2(221.13,55.95)
  IN1 w0.508: v2(38.19,60.65) 39.31,61.78 39.31,73.76 42.07,76.52 46.49,76.52 47.29,75.72 49.04,75.72 51.98,72.78 54.35,72.78 55.42,71.71 v2(62.92,71.71) ; v2(144.71,133.75) 141.21,133.75 140.05,132.59 v2(140.05,131.19)
  IN2 w0.381: v2(49.62,53.48) 50.68,52.41 54.15,52.41 v2(55.09,51.47)
  IN2 w0.508: v2(137.22,78.13) 137.22,75.83 140.03,73.02 140.03,70.77 v2(143.66,67.14) ; v2(288.25,4.51) 288.25,6.96 285.32,9.89 285.32,23.4 277.98,30.74 277.98,52.74 278.94,53.71 278.94,54.11 283.18,58.35 283.92,58.35 285.24,59.68 285.24,60.57 284.23,61.58 284.23,62.84 282.58,64.49 282.58,70.15 281.15,71.58 279.85,71.58 279.12,72.32 275.61,72.32 272.41,75.52 272.41,79.08 270.76,80.73 v2(269.52,80.73)
  IN4 w0.508: v2(43.71,52.21) 43.71,52.24 42.98,52.97 40.28,52.97 39.44,53.8 39.44,59.4 v2(38.19,60.65) ; v2(162.24,62.91) 162.24,61.75 162.82,61.16 165.56,61.16 166.01,61.62 171,61.62 171.5,62.12 172.24,62.12 173.15,61.21 176.7,61.21 177.63,60.28 178.87,60.28 179.07,60.48 181.7,60.48 182.04,60.13 182.04,59.55 181.31,58.82 v2(181.31,58.5)
  BOTTOM w0.254: 65.59,69.2 65.7,69.31 PU200.13 ; RT68.2 37.09,82.29 37.32,82.52 37.32,83.23 v2(37.78,83.7)
  BOTTOM w0.305: 207.04,59.01 JKBTP1.15 ; 207.04,59.01 v2(207.04,59.89) ; 207.04,59.01 207.04,56.83 207.27,56.59
  BOTTOM w0.381: PR1259.2 42.77,52.84 43.41,52.21 v2(43.71,52.21) ; v2(143.2,81.39) 145.34,83.53 RC432.1 146.43,84.45 QC7.3 ; v2(124.44,133.12) 124.44,133.12 UZ35.5 ; v2(181.31,58.5) 181.31,58.39 181.96,57.74 PR113.1 181.1,57.68 PR107.1 ; PR1235.2 50.07,53.02 v2(49.62,53.48)
  BOTTOM w0.457: PR205.2 64.48,70.17 v2(64.49,70.15) PC206.1 64.79,69.2 65.59,69.2
  BOTTOM w0.508: PR1225.2 38.95,60.73 PR1224.2 v2(38.19,60.65) ; RE505.2 v2(252.63,127.58) ; 227.48,61.22 229.82,61.22 RE532.1 ; PR29.2 60.86,121.73 60.86,119.26 60.6,119.01 60.09,119.01 59.43,118.35 v2(59.43,118.18) ; RZ518.1 245.34,120 245.04,119.7 v2(245.04,119.13) ; 226.21,57.25 226.21,54.93 221.68,50.39 215.83,50.39 213.64,52.59 209.55,52.59 207.27,54.86 207.27,56.59 ; RE74.1 v2(287.78,120.47) ; JLED1.6 v2(288.25,4.51)
  BOTTOM w1.016: 226.46,61.35 223.82,63.99 223.82,66.33
  vias: v2(19.3,111.82) v2(19.89,111.8) v2(33.18,119.61) v2(33.18,118.8) v2(42.95,118.12) v2(63.28,72.35) v2(67.55,121.87) v2(68.16,121.87) v2(68.77,121.87) v2(155,114.84) v2(154.97,114.19) v2(159.93,82.54) v2(159.96,83.1) v2(165.3,68.73) v2(165.49,69.26) v2(165.54,68.2) v2(165.76,118.37) v2(165.76,117.74) v2(165.94,68.67) v2(166.04,67.73) v2(166.13,69.26) v2(166.45,67.31) v2(166.57,68.67) v2(166.76,69.26) v2(167.4,69.26) v2(167.73,68.76) v2(168.23,69.19) v2(168.88,69.29) v2(169.01,68.72) v2(169.45,69.29) v2(223.48,67.2) v2(224.12,67.2) v2(227.49,58.16) v2(252.14,109.56) v2(252.27,112.99) v2(252.78,109.56) v2(252.91,112.99) v2(253.13,110.17) v2(253.41,109.56) v2(253.52,112.99) v2(253.54,75.93) v2(254.13,75.93) v2(260.74,86.71) v2(263.32,90.12) v2(263.32,89.54) v2(263.56,94.52) v2(263.56,93.52) v2(278.92,93.36) v2(278.92,92.66) v2(279.55,93.36) v2(279.55,92.66) v2(280.06,92.97) v2(287.23,125.23) v2(287.23,124.53) v3(163.65,65.75) v3(167.78,67.47)
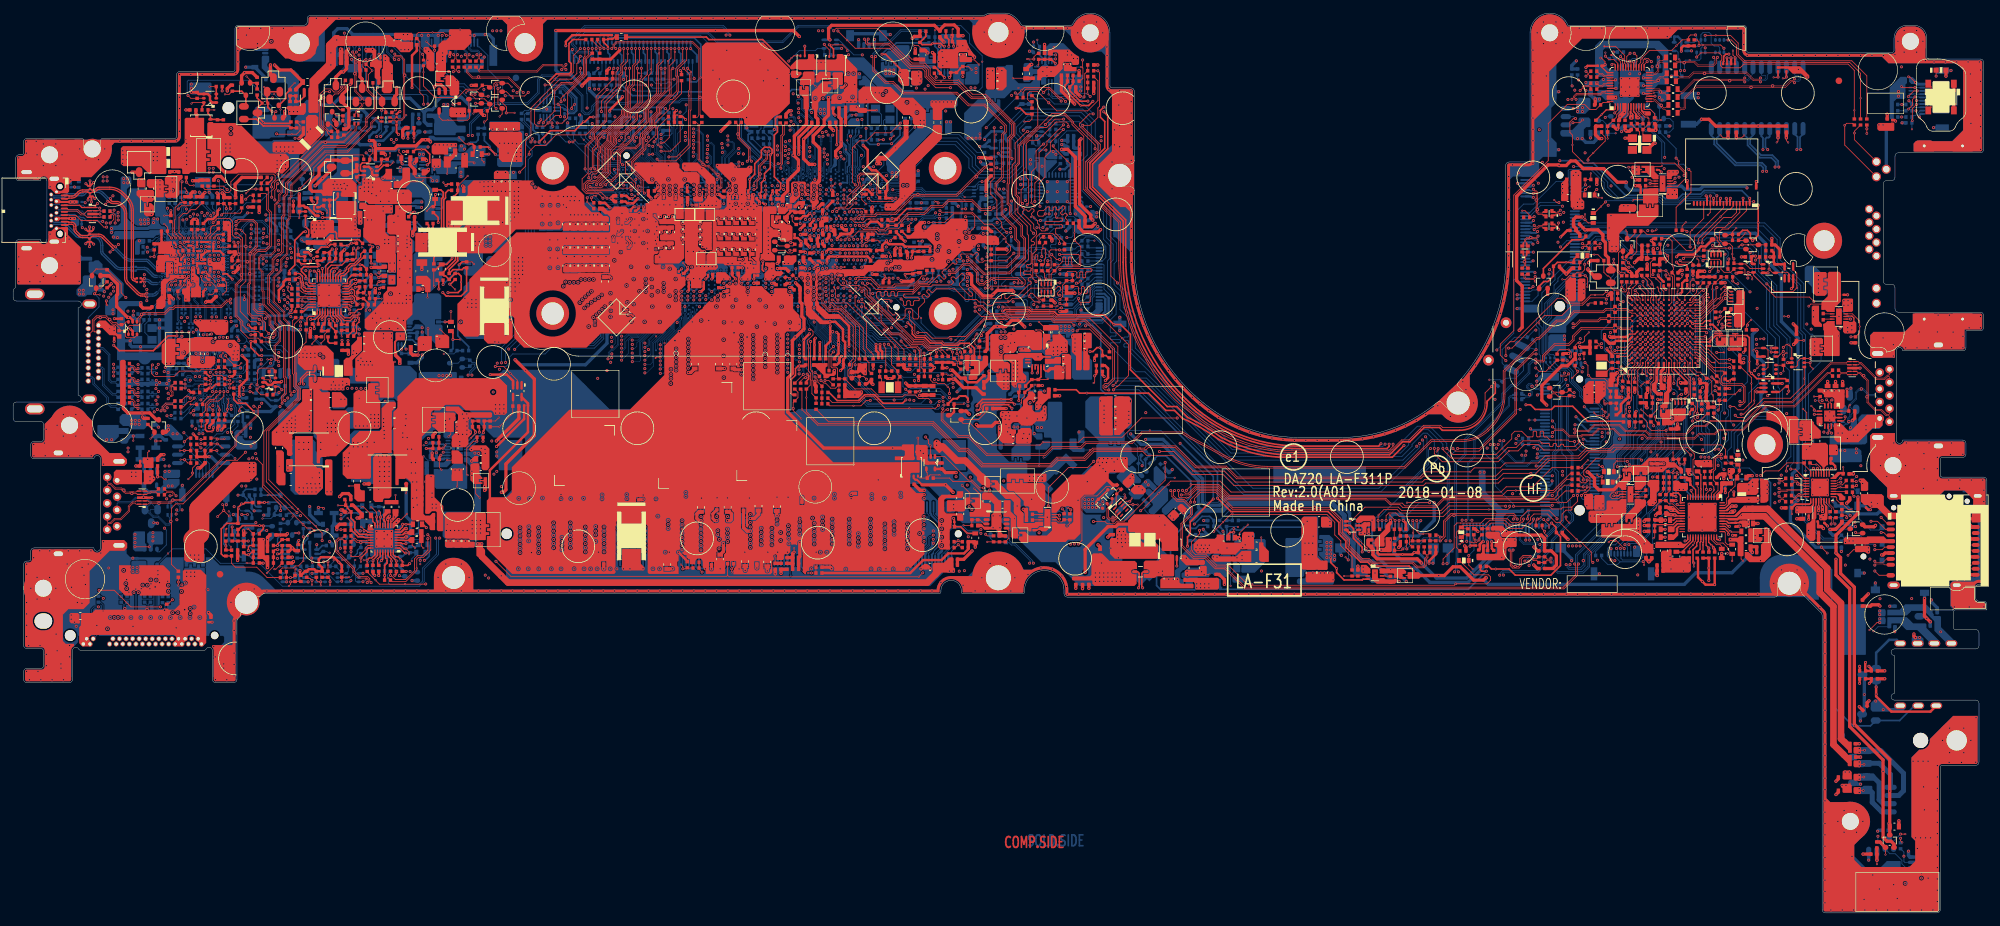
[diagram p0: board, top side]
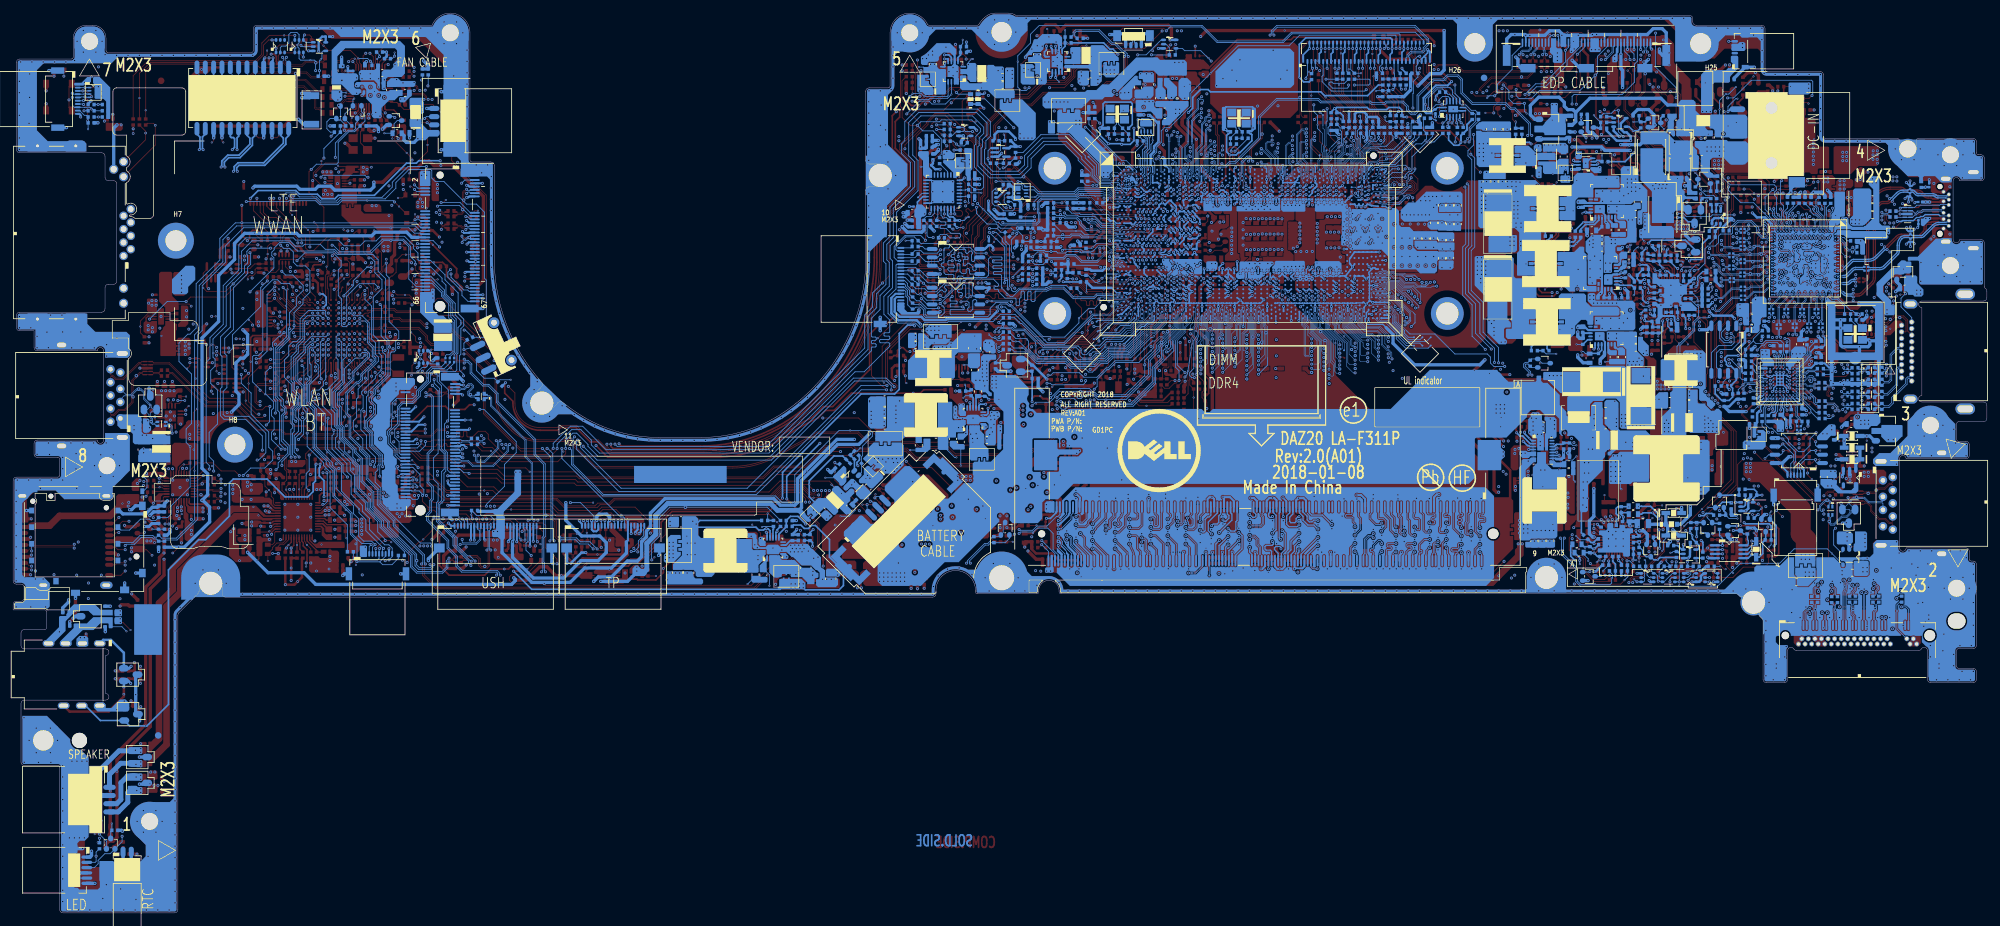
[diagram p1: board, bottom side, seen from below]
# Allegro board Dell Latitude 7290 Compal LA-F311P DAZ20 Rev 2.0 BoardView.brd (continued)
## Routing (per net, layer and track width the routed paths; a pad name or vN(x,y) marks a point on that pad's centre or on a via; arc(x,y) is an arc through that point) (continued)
+3.3V_ALW2: length 95.1
  TOP w0.254: v2(211.89,71.26) 210.12,69.48 192.94,69.48 arc(188.15,70.32) 183.67,72.2 arc(180.98,73.97) 178.11,75.43 176.93,76.61 175.62,76.61 172.97,79.26 v3(163.57,79.26) 162.48,79.26 161.97,79.77 PR104.2 ; v2(230.47,77.48) 231.18,77.48 231.89,76.77 234.36,76.77 234.84,77.25 237.59,77.25 239.87,74.97 245.23,74.97 RE57.2
  IN4 w0.254: v2(230.47,77.48) 225.4,77.48 220.24,72.32 216.43,72.32 214.76,70.66 212.49,70.66 v2(211.89,71.26)
+3.3V_ALW_DSW: length 187.9
  TOP w0.381: v2(127.34,86.37) 127.34,89.48 126.05,90.77 ; RC72.2 v2(131.02,82.94)
  TOP w0.508: RC214.1 147.9,81 RC440.1 148.19,81 148.7,81.51 v2(148.7,82.6) ; RC241.2 87.7,127.2 86.68,126.18 v2(86.68,126.09) ; v2(135.98,80.78) 136.41,80.35 RC67.2 RC243.2 137.51,80.36 CC279.1 CC280.1 ; v2(82.69,134.55) v1(106.98,134.55) 118.86,134.55 v2(119.77,133.63)
  IN1 w0.508: v2(119.77,133.63) 121,133.63 125.99,128.64 125.99,127.94 127.94,125.99 128.95,125.99 130.76,124.19 132.84,124.19 133.1,124.45 139.38,124.45 139.99,125.05 151.72,125.05 v2(152.12,124.65) ; v2(147.22,91.97) 147.22,94.14 146.91,94.46 146.91,99.8 148.13,101.03 v2(148.13,101.41) ; v2(135.98,80.78) 135.98,81.02 134.49,82.51 131.46,82.51 v2(131.02,82.94)
  IN2 w0.508: v2(127.34,86.37) 130.77,82.94 v2(131.02,82.94) 131.46,83.38 131.46,84.1 132.77,85.42 134.39,85.42 136.45,87.48 v2(142.87,87.48) 142.87,87.48 143.28,87.48 143.51,87.71 145.85,87.71 147.95,85.62 147.95,83.66 148.7,82.91 v2(148.7,82.6) ; v2(122.65,100.73) 122.66,100.71 v2(122.66,98.24) ; v2(148.13,101.41) 149.12,102.4 149.12,104.46 148.87,104.71 148.87,105.84 150.05,107.02 150.05,108.31 149.14,109.21 149.14,118.86 148.85,119.15 148.85,121.39 v2(152.12,124.65)
  IN4 w0.508: v2(142.87,87.48) 143.17,87.48 147.22,91.53 v2(147.22,91.97)
  BOTTOM w0.254: UC1.AJ17 122.66,98.33 v2(122.66,98.24) ; UC1.AD18 122.62,100.89 122.62,100.75 v2(122.65,100.73)
  BOTTOM w0.305: UC1.AD17 122.65,100.83 v2(122.65,100.73)
  BOTTOM w0.508: v2(82.69,134.55) 82.69,128.5 83.21,127.98 84.79,127.98 v2(86.68,126.09) ; v2(148.13,101.41) 147.8,101.74 RC323.2 ; v2(148.7,82.6) 148.7,82.59 150.67,82.59 RC439.1
+3.3V_ALW_DSW_R: length 3.3
  BOTTOM w0.127: v1(150.34,85) 150.34,84.76 151.03,84.07 RC439.2
  BOTTOM w0.254: QC7.1 149.65,83.87 RC439.2
+3.3V_ALW_PCH: length 340.7
  TOP w0.254: v2(138.31,107.39) 136.16,107.39 RC12.2 134.19,105.42 133.51,105.42 RC23.2 ; v2(136.01,78.22) 135.52,77.72 132.53,77.72 131.24,79.01 129.71,79.01 128.95,78.24 128.94,78.24 128.82,78.12 125.54,78.12 124.3,79.36 RC187.2 ; RC308.1 136.27,103.06 RC14.2 ; v2(225.7,80.84) 225.8,80.73 225.8,79.26 224.56,78.01 224.56,77.78 arc(223.33,74.81) 220.36,73.59 217.73,73.59 217.31,74.01 214.97,74.01 212.78,71.82 211.66,71.82 209.7,69.86 193.25,69.86 arc(188.53,70.73) 184.07,72.5 arc(181.57,74.15) 178.93,75.57 177.29,77.2 175.84,77.2 170.21,82.83 170.21,88.23 168.71,89.72 v3(167.69,89.72) 166.21,91.2 159.1,91.2 158.62,91.68 155.09,91.68 154.78,91.99 151.12,91.99 150.92,91.79 v2(150.71,91.79)
  TOP w0.305: JAPS1.1 v2(264.56,108.96)
  TOP w0.381: v2(142.29,83.15) 142.23,83.08 RC344.2 RC73.2 ; RC74.2 143.06,83.95 RC387.2 RC73.2 ; RC73.2 RC183.2 ; RC440.2 147.84,81.92 146.84,80.91 145.43,80.91 145.05,81.29 RC211.1
  TOP w0.457: CC209.1 121.39,102.8 v2(121.39,103.26)
  TOP w0.508: v2(142.8,82.76) 143.1,82.76 144.32,81.54 RC211.1
  TOP w1.016: 147.47,66.56 145.06,68.97 143.79,68.97 141.63,71.13
  IN2 w0.254: v2(235.63,114.69) 234.42,114.69 229.74,110.02 229.74,90.23 228.54,89.03 228.54,83.69 v2(225.7,80.84)
  IN2 w0.508: v2(152.11,108.55) 152.11,112.09 151.36,112.84 151.36,116.8 v2(153.9,119.34) ; v2(138.87,105.24) 138.87,107.02 138.5,107.39 v2(138.31,107.39) 138.31,107.39 136.84,108.87 136.84,111.12 135.91,112.04 135.91,115.67 142.08,121.83 v2(142.08,122.28)
  IN3 w0.508: v2(165.24,104.66) 166.06,105.48 166.06,108.23 163.88,110.41 163.88,113.7 166.65,116.46 166.65,119.3 166.05,119.89 163.64,119.89 160.9,117.15 v2(159.76,117.15)
  IN4 w0.508: v2(142.08,122.28) 141.81,122.01 138.38,122.01 138.35,122.03 v2(137.69,122.03) 137.69,123.29 136.71,124.27 133.35,124.27 133.04,123.96 130.43,123.96 129.92,123.45 129.92,120.75 129.52,120.34 128.96,120.34 128.67,120.64 v2(128.67,120.94) ; v2(153.9,119.34) 153.9,119.59 154.33,120.03 155.85,120.03 158.14,117.74 158.57,117.74 159.17,117.15 v2(159.76,117.15)
  BOTTOM w0.254: v2(119.8,99.02) 120.17,98.66 UC1.AJ21 ; UC1.AK17 123,97.8 123,97.36 v2(122.93,97.28) ; v2(264.56,108.96) 263.37,110.15 257.64,110.15 257.08,109.59 254.35,109.59 253.67,108.9 251.69,108.9 251.17,109.42 245.66,109.42 240.76,114.32 239.28,114.32 238.9,114.69 v2(235.63,114.69) ; v2(225.7,80.84) RC222.2 ; v2(121.39,103.26) 121.39,103.39 UC1.V19
  BOTTOM w0.305: 166.39,93.61 166.1,93.91 JSPI1.16
  BOTTOM w0.381: RC283.2 v2(144.11,101.48) RC347.2 ; 166.39,93.61 166.39,91.65 165.63,90.89 162.33,90.89 161.85,90.41 158.62,90.41 158.49,90.54 151.97,90.54 v2(150.71,91.79) ; UC7.5 154.34,119.79 v2(153.9,119.34) ; v2(145.08,105.56) 145.11,105.53 149.11,105.53 149.44,105.85 150.82,105.85 152.11,107.14 v2(152.11,108.55)
  BOTTOM w0.508: RC371.2 v2(138.31,107.39) RC400.2 ; RC331.2 RC330.2 146.91,100.44 146.36,100.99 v2(146.36,101.65) ; v2(165.24,104.66) 165.24,104.58 164.46,103.81 162.27,103.81 161.94,104.14 RZ69.1 ; RC346.2 v2(137.69,122.03) ; RC346.2 136.83,122.06 RT391.2 ; RC346.2 RC288.2 ; v2(159.76,117.15) 160.02,117.15 160.25,116.92 160.48,116.92 RZ368.1 ; RC553.2 144.02,104.38 v2(143.79,104.15) RC348.2 RC25.2 RC15.2 RC17.2 143.1,107.48 RC555.2
  vias: v2(136.6,78.22) v2(140.69,71.91) v2(140.69,71.31)
+3.3V_ALW_PCH_UZ3: length 6.8
  TOP w1.016: 150.46,64.59 151.41,63.64 152.17,63.64 152.96,62.85 v3(152.96,62.04) 152.96,61.2 153.44,60.72 153.44,59.51
+3.3V_ALW_UE1: length 42.2
  TOP w0.203: UE1.B7 247.08,88.26 246.26,88.26 245.97,87.97 ; CE13.1 257.8,90.3 257.36,89.86 v2(255.88,89.86)
  TOP w0.254: v2(254.28,84.23) 253.88,84.63 UE1.K2 ; UE1.H1 252.25,83.82 252.25,81.95 v2(252.22,81.93) ; UE1.G8 v2(251.08,89.86) ; UE1.M9 v2(255.88,89.86)
  TOP w0.356: v2(251.79,95.08) 251.46,95.41 CE19.1
  TOP w0.381: CE14.1 243.89,87.81 CE23.1 245.81,87.81 245.97,87.97
  TOP w0.508: CE14.1 243.37,87.78 v2(243.23,87.92)
  IN2 w0.381: v2(243.23,87.92) 245.36,87.92 246.32,88.88 250.69,88.88 251.08,89.27 v2(251.08,89.86)
  IN2 w0.457: v2(254.28,84.23) 254.28,83.98 v2(252.22,81.93)
  IN3 w0.457: v2(252.22,81.93) 252.22,84.42 252.09,84.54 252.09,89.01 ; v2(255.88,89.86) 255.04,89.01 252.09,89.01 ; v2(251.79,95.08) 251.79,90.56 v2(251.08,89.86) 251.93,89.01 252.09,89.01
  vias: v1(252.5,80.02)
+3.3V_ALW_UZ12:
  vias: v2(156.75,113.85)
+3.3V_ALWP: length 28.1
  IN1 w0.254: v2(166.2,76.66) 166.43,76.66 166.7,76.92 166.7,78.76 165.68,79.78 157.46,79.78 157.26,79.57 v2(157.11,79.57) ; v2(154.94,77.8) 154.94,78.53 155.19,78.78 157.73,78.78 158.29,79.34 165.53,79.34 166.34,78.53 166.34,77.43 v2(166.2,77.29)
  BOTTOM w0.254: PR108.2 v2(157.11,79.57) ; PU100.14 154.91,77.71 154.94,77.74 v2(154.94,77.8)
  vias: v2(166.2,76.02) v2(166.2,75.39) v2(166.2,74.75) v3(165.66,78.07)
+3.3V_CAM:
  vias: v2(56.7,130.58) v2(56.69,129.98) v3(57.68,127.97)
+3.3V_EC_PLL: length 1.8
  TOP w0.508: RE314.1 250.56,79.13 250.02,79.67 CE17.1
  vias: v1(250.4,81.99)
+3.3V_HDD_M2:
  vias: v2(26.44,51.95) v2(26.44,51.32) v2(27.07,51.95) v2(27.07,51.32) v2(27.65,51.95) v2(27.65,51.32) v3(12.75,43.83) v3(18.26,43.67) v3(24.84,43.47)
+3.3V_LAN: length 341
  TOP w0.127: v3(246.12,113.7) 246.65,113.7
  TOP w0.254: v2(166.15,122.16) 166.76,121.55 166.76,116.51 164.44,114.18 164.44,110.73 169.49,105.67 169.49,99.95 arc(169.56,97.97) 169.75,95.99 arc(172.6,86.64) 178.29,78.7 178.62,78.38 arc(186.59,73.05) 195.99,71.18 208.03,71.18 v2(208.39,71.54)
  TOP w0.381: v2(254.15,131.39) 254.15,131.9 254.46,132.21 RL29.1 RL30.1
  TOP w0.508: v2(242.03,118.07) 241.65,118.07 241.07,118.66 241.07,119.89 RL6.2 241.15,119.96 RL5.2 ; v2(241.03,124.09) 241.03,123.3 RL4.2
  IN1 w0.254: v2(146.55,125.8) 157.45,125.8 158.14,125.11 158.14,123.94 159.73,122.36 165.96,122.36 v2(166.15,122.16)
  IN2 w0.254: 241.17,119.42 v2(232.51,119.42) ; v2(144.11,102.37) 143.25,103.23 143.25,107.91 145.11,109.77 145.11,115.25 144.78,115.58 144.78,118.62 146.55,120.39 v2(146.55,125.8)
  IN2 w0.508: 253.34,129.12 253.34,126.22 251.81,124.7 251.81,123.01 251.12,122.31 251.12,116.19 250.29,115.36 250.29,109.75 251.06,108.98 256.44,108.98 257.8,107.62 262.24,107.62 264.82,105.04 267.08,105.04 274.12,98 275.34,98 276.72,96.62 276.72,86.13 277.53,85.32 280.45,85.32 281.9,86.76 281.9,88.66 285.29,92.05 285.29,93.83 JLOM1.9
  IN2 w1.016: 254.1,129.49 282.64,129.49 284.58,127.54 284.58,120.99
  IN4 w0.254: v2(208.39,71.54) 208.8,71.95 212.25,71.95 213.72,73.43 220.68,73.43 224.86,77.61 224.86,78.4 228.9,82.43 228.9,89.11 229.61,89.83 229.61,110.17 232.51,113.07 v2(232.51,119.42)
  BOTTOM w0.254: RC20.2 143.48,102.88 RC19.2 v2(144.11,102.37) RL70.2
  BOTTOM w0.356: v2(254.15,131.39) 254.15,133.09 253.62,133.61 CL15.1 253.07,133.58 UL2.5
  BOTTOM w0.381: RL2.2 243.8,130.58 v2(243.8,131.27) RL1.2
  BOTTOM w0.508: v2(284.88,120.15) 285.38,119.66 JLOM1.12
  vias: v2(241.67,124.09) v2(246.78,113.36) v2(247.36,113.68) v2(247.36,112.98) v2(284.25,120.15)
+3.3V_LAN_OUT: length 3.4
  TOP w0.203: UL1.29 246.89,128.92 v2(246.89,129.79) ; UL1.15 v2(250.14,124.53) ; UL1.19 v2(248.39,126.13)
  BOTTOM w0.508: v2(246.89,129.79) 247.14,129.54 247.14,129.22 CL29.1
  vias: v1(245.64,125.26) v2(244.82,121.49) v2(245.45,122.06)
+3.3V_LAN_UZ2: length 1.4
  TOP w0.127: v1(251.2,113.94) 251.05,113.79 249.84,113.79
+3.3V_M_TPM: length 26.5
  TOP w0.508: v2(162.69,118.02) 162.46,117.79 v3(162.46,116.81) 162.46,108.12 164.18,106.4 164.18,105.94 v2(164.48,105.64)
  IN4 w0.508: v2(162.69,118.02) 159.74,115.07 158.27,115.07 157.35,115.99 v2(157.35,116.32)
  BOTTOM w0.254: RZ369.2 v2(157.35,116.32)
  BOTTOM w0.508: v2(164.48,105.64) 163.8,105.64 RZ366.2 ; v2(162.69,118.02) 162.46,117.79 RZ367.1 161.72,116.6 RZ368.2 161.57,116.75 CZ59.1 CZ60.1
+3.3V_MMI_AUX:
  vias: v1(273.2,70.64)
+3.3V_MMI_IN: length 3.2
  TOP w0.127: 273.26,73.88 273.26,76.28 v1(272.67,76.86)
  vias: v2(273.54,58.33) v2(273.55,57.73) v2(273.8,72.97) v2(273.8,72.34)
+3.3V_PDA_VOUT: length 2.5
  BOTTOM w0.076: UT5.H2 30.27,78.72 30.27,77.86 30.09,77.68
  BOTTOM w0.112: 30.09,77.68 30.06,77.65
  BOTTOM w0.254: 30.06,77.65 29.81,77.39 CT83.1
+3.3V_PGPPB: length 8.4
  TOP w0.381: v2(123.98,99.08) 123.98,99.69 CC265.1 124.37,100.09 v1(125.58,100.09) 125.6,100.09 125.6,100.09 130.17,100.09 130.64,99.62 RC305.2
  BOTTOM w0.254: v2(123.98,99.08) 124.29,99.39 UC1.AG15
+3.3V_PGPPC: length 17.5
  TOP w0.457: v2(123.33,102.43) 123.33,101.95 CC207.1
  TOP w0.508: RC306.2 135.22,100.47 135.14,100.55 v2(135.14,101.35)
  IN4 w0.457: v2(123.33,102.43) 123.33,102.75 123.9,103.33 124.59,103.33 125.15,103.88 133.93,103.88 135.14,102.67 v2(135.14,101.35)
  BOTTOM w0.076: v2(135.14,101.35) 135.14,100.81 v1(135.1,100.77)
  BOTTOM w0.254: v2(123.33,102.43) 123.64,102.74 UC1.Y16
+3.3V_PGPPD: length 13.2
  TOP w0.508: RC307.2 134.33,101.18 134.53,101.38 v2(134.53,101.38)
  IN4 w0.457: v2(134.53,101.38) 134.53,102.45 133.68,103.29 125.39,103.29 v2(124.68,102.58)
  BOTTOM w0.254: UC1.Y15 124.41,102.85 v2(124.68,102.58)
+3.3V_PGPPE: length 16.6
  TOP w0.127: v2(136.42,104.66) 136.42,104.82 v1(136.78,105.18)
  TOP w0.508: CC208.1 123.33,103.46 v2(123.33,104.1) ; RC308.2 v2(136.42,104.66)
  IN2 w0.254: v2(123.33,104.1) 123.33,104.06 124,103.39 130.51,103.39 131.52,104.4 136.17,104.4 v2(136.42,104.66)
  BOTTOM w0.254: v2(123.33,104.1) 123.33,104.21 UC1.T16
+3.3V_RTC_LDO: length 193.4
  TOP w0.508: v2(277.71,53.92) 277.71,51.51 279.8,49.41 279.8,28.41 284.88,23.33 v3(284.88,21.56) 284.88,11.5 285.46,10.93 286.09,10.93 286.55,10.47 PD3.3 ; PR105.2 v2(159.43,78.85)
  IN1 w0.508: v2(241.38,53.78) 241.38,53.17 238.31,50.1 212.68,50.1 212.24,50.53 v2(212.24,50.54)
  IN2 w0.508: v2(241.38,53.78) 242.28,52.88 251.11,52.88 252.2,51.79 265.93,51.79 270.22,56.07 272.31,56.07 274.46,53.92 v2(277.71,53.92)
  IN4 w0.508: v2(159.43,78.85) 167.85,78.85 168.91,77.8 168.91,72.56 169.27,72.2 v2(172.54,72.2)
  BOTTOM w0.508: v2(212.24,50.54) 212.23,50.54 211.56,51.22 209.55,51.22 207.11,53.66 205.59,53.66 204.95,54.29 204.95,56.59 204.2,57.34 204.2,58.24 203.6,58.84 203.6,60.96 201.4,63.16 184.81,63.16 183.82,62.16 181.61,62.16 181.2,62.57 181.2,66.18 175.18,72.2 v2(172.54,72.2)
+3.3V_RUN: length 445.3
  TOP w0.254: v2(81.56,126.76) 82.73,127.93 84.69,127.93 85.01,128.25 85.01,129.53 84.69,129.85 84.69,132.56 85.29,133.17 RC137.2 ; RC282.2 145.9,85.96 v2(145.54,86.32) ; PR612.1 42.47,91.98 v2(42.3,91.81)
  TOP w0.356: CA7.1 55.97,130.71 v2(55.75,130.92) ; CZ72.1 224.66,55.31 CZ67.1 224.66,56.52 v2(224.62,56.56)
  TOP w0.381: QV3.5 18.22,90.39 17.79,90.81 v2(17.59,90.81) ; v2(60.77,125.84) 60.77,130.73 61.49,131.46 RV8.2 ; v2(17.85,89.06) 18.22,88.69 QV3.2 ; v2(133.91,108.98) 133.02,108.98 RC178.2 RC175.2 133.17,110.17 133.17,111.51 131.45,113.23 130.81,113.23 130.19,113.85 130.19,116.36 v2(129.5,117.05) ; RD8.1 136.68,51.83 138.64,53.8 141.44,53.8 142.45,54.81 144.87,54.81 145.52,55.46 RD6.1 ; RC413.2 134.55,103.76 135.28,103.03 RC287.2 135.28,102.92 135.77,102.42 v2(135.91,102.42) ; RC190.2 139.91,82.69 v2(140.36,83.13) 139.91,83.58 RC59.2
  TOP w0.457: RC186.2 RC414.2
  TOP w0.508: v2(214.55,53.35) 213.92,53.99 207.8,53.99 207.16,54.62 207.16,55.13 ; v2(58.44,125.86) 58.44,124.8 58.13,124.48 QZ1.3 ; RC414.2 135.72,83.12 135.96,82.88 v2(136.61,82.88) ; v2(159.74,116.43) 160.64,116.43 161.83,115.24 161.83,107.72 163.31,106.23 CZ76.1 CZ77.1 164.36,104.65 v2(164.85,105.13) ; RV18.1 19.91,75.4 v2(19.7,75.61) ; RV326.1 50.8,119.53 51.15,119.88 51.15,120.78 RV6.2 51.14,122.64 50.14,123.64 QV8.3 50.14,124.8 50.85,125.51 v2(50.85,125.93) ; v2(239.81,67.23) 239.95,67.23 240.92,66.25 240.92,65.16 241.57,64.51 243.85,64.51 244.56,65.23 244.56,65.41 ; v2(147.12,115.16) 148.1,115.16 148.17,115.09 RC177.2 ; RC176.2 148.23,111.63 v2(148.23,109.99) ; RD19.2 77.05,75.38 v2(73.62,71.96) ; v2(146.58,55.78) RD10.1 146.45,56.59 RD4.1 RD6.1 ; RE547.2 v2(265.69,88.91) ; QV5.2 14.3,97.16 RV20.2 14.63,97.15 15.91,95.88 15.91,94.33 15.78,94.2 15.78,92.45 17.41,90.81 v2(17.59,90.81)
  TOP w3.048: 27.46,56.92 28.36,57.82 28.36,61.56 33.9,67.1
  IN1 w0.305: v2(17.85,89.06) 17.85,90.55 v2(17.59,90.81)
  IN1 w0.508: v2(236.75,84.19) 237.56,83.38 237.56,80.95 239.01,79.5 239.01,78.52 239.98,77.55 239.98,74.37 241.73,72.62 v2(242.09,72.62) ; v2(144.77,99.41) 144,98.65 144,97.45 142.85,96.29 142.77,96.21 v2(142.57,96.21) ; v2(239.49,115.9) 239.83,115.9 241.28,117.34 241.28,122.34 242.64,123.7 242.64,125.04 241.46,126.21 241.46,128.82 240.37,129.92 v2(238.16,129.92) ; v2(19.7,75.61) 20.45,74.86 31,74.86 31.43,74.44 34.24,74.44 v2(36.16,72.52) ; v2(156.3,57.96) 155.21,56.87 147.67,56.87 v2(146.58,55.78)
  IN2 w0.508: 154.15,66.36 152.8,65.01 150.58,65.01 149.52,66.06 149.52,66.99 143.52,72.99 143.52,73.49 140.4,76.61 140.4,77.65 140.4,77.65 140.4,79.4 141.71,80.71 141.71,82.21 140.78,83.13 v2(140.36,83.13) ; v2(153.5,111.05) 153.61,111.05 155.62,113.06 155.62,113.58 156.82,114.78 158.97,114.78 159.74,115.55 v2(159.74,116.43)
  IN4 w0.381: v2(19.7,75.61) 19.07,75.61 17.14,77.54 17.14,88.35 v2(17.85,89.06)
  IN4 w0.508: v2(147.26,116.86) 150.11,116.86 150.72,116.25 150.72,114.43 151.86,113.29 152.95,113.29 154.07,112.16 154.07,111.62 v2(153.5,111.05) ; v2(236.75,84.19) 237.52,84.19 237.96,84.63 237.96,88.45 241.17,91.66 241.17,96.22 242.84,97.89 243.67,97.89 244.81,99.03 244.81,99.68 245.36,100.23 245.36,106.82 242.96,109.21 241.4,109.21 240.64,109.96 240.64,112.18 241.26,112.8 241.26,114.72 240.09,115.9 v2(239.49,115.9) ; v2(156.3,57.96) 156.3,64.01 156.79,64.49 v2(156.79,65.97) ; v2(224.62,56.56) 224.62,56.08 226.58,54.12 228.59,54.12 231.07,51.64 239.74,51.64 240.47,52.36 244.46,52.36 247.04,54.94 v2(247.04,55.76)
  BOTTOM w0.203: CC30.1 83.71,122.8 UC8.14
  BOTTOM w0.254: RC345.2 134.5,108.47 134.16,108.47 133.91,108.72 v2(133.91,108.98) ; JEDP1.10 v2(55.75,130.92) ; 149,110.98 149,110.8 150.7,109.1 QC2.2
  BOTTOM w0.305: CC30.1 84.2,122.51 84.78,121.93 85.43,121.93 85.83,122.34 85.83,124.28 83.93,126.18 82.13,126.18 v2(81.56,126.76) ; JUSH1.19 224.45,56.88 224.62,56.7 v2(224.62,56.56)
  BOTTOM w0.381: RC402.2 RC403.2 144.74,99.39 v2(144.77,99.41) ; RC291.2 v2(147.26,116.86) ; RC291.2 147.98,117.03 148.69,117.74 RC225.2 ; RC291.2 148.72,116.86 148.97,116.61 UC12.5 ; RC267.2 139.24,97.62 RC237.2 139.99,97.74 RC292.2 ; v2(42.3,91.81) 42.3,91.71 41.66,91.07 38.87,91.07 v2(38.46,90.66) ; v2(129.5,117.05) 129.45,117.1 RC272.2
  BOTTOM w0.457: v2(139.99,99.64) RC292.2 RC278.2
  BOTTOM w0.508: v2(267.45,76.36) 266.29,77.51 266.29,79.07 266.76,79.54 266.76,83.87 266.04,84.58 265.57,84.58 264.98,85.18 264.98,88.2 v2(265.69,88.91) ; RE67.2 236.32,84.62 v2(236.75,84.19) ; v2(238.16,129.92) 237.46,129.22 RE48.1 RE51.1 ; v2(164.85,105.13) 164.32,104.61 RZ365.2 ; v2(159.74,116.43) 159.74,116.24 160.25,115.73 RZ89.1 ; RC318.2 147.22,107.95 RC279.2 ; RZ362.1 154.19,111.08 153.53,111.08 v2(153.5,111.05) ; RC51.2 RC189.2 RC47.2 143.84,95.84 RC50.2 143.31,95.84 142.94,96.21 v2(142.57,96.21) ; v2(216.5,62.56) 216.5,59.87 214.1,57.47 211.34,57.47 210.34,56.46 210.34,54.95 211.58,53.71 214.2,53.71 v2(214.55,53.35) 216.85,51.06 221.44,51.06 224.62,54.24 v2(224.62,56.56) ; v2(55.5,125.84) 55.5,128.47 55.75,128.72 v2(55.75,130.92)
  vias: v2(24.23,112.03) v2(24.24,111.46) v2(24.8,112.05) v2(24.81,111.45) v2(27.01,54.56) v2(27.01,53.92) v2(27.65,54.56) v2(27.65,53.92) v2(28.28,54.56) v2(28.28,53.92) v2(29.88,113.53) v2(29.86,112.97) v2(30.49,113.53) v2(30.49,112.96) v2(36.03,68.54) v2(36.03,67.91) v2(36.03,67.27) v2(36.66,68.54) v2(36.66,67.91) v2(36.66,67.27) v2(148.23,109.36) v2(154.87,66.56) v2(154.88,65.97) v2(155.51,66.56) v2(155.52,65.97) v2(156.14,66.56) v2(156.15,65.97) v2(156.78,66.56) v2(268.1,76.29) v3(36.22,66.08)
+3.3V_RUN_AUDIO: length 0.8
  TOP w0.127: 250.47,69.02 v3(250.47,69.84)
  vias: v2(248.93,67.68) v2(251.08,67.77) v2(261.49,67.6) v2(261.45,67)
+3.3V_RUN_AUDIO_IO: length 4.4
  TOP w0.203: UA1.9 256.33,64.53 255.57,65.29 CA55.1
  TOP w0.356: CA55.1 255.52,65.82 CA56.1
  TOP w0.381: LA12.1 254.96,66.39 CA56.1
+3.3V_RUN_CARD: length 7.2
  IN2 w1.016: 278.85,56.84 276.19,56.84 274.52,58.51 274.52,60.67
  vias: v2(275.08,61.91) v2(275.08,61.33) v2(279.73,56.72) v2(280.31,56.72) v3(279.16,56.48)
+3.3V_RUN_DIMM1: length 7.7
  TOP w0.254: RD10.2 145.38,57.86 v1(145.32,57.91) 144.36,58.88 CD27.1 143.42,59.6 CD28.1 143.38,60.06 v2(143.28,60.16)
  BOTTOM w0.254: JDIMM1.255 141.73,61.18 141.81,61.09 141.81,61.01 142.66,60.16 v2(143.28,60.16)
+3.3V_RUN_UZ3:
  vias: v3(155.17,63.08)
+3.3V_SPI: length 78.3
  TOP w0.508: RC30.2 RC31.2 161.72,94.51 v2(161.75,94.48) ; v2(151.4,101.09) 151.28,101.22 RC41.1 ; v2(152.44,94.69) 152.2,94.93 149.92,94.93 v3(149.29,94.3) 149.06,94.07 147.79,94.07 146.03,95.83 146.03,97.18 145.74,97.46 v2(145.36,97.46)
  IN1 w0.508: v2(162.46,89.78) 162.46,90.29 161.48,91.28 161.48,94.2 v2(161.75,94.48)
  IN2 w0.508: v2(151.4,101.09) 151.4,100.78 153.32,98.87 160.2,98.87 161.22,97.85 161.22,95.81 161.75,95.27 v2(161.75,94.48)
  IN4 w0.254: v2(123.94,98.29) 124.29,97.94 131.06,97.94 132.7,96.3 134.38,96.3 134.76,95.92 139.26,95.92 140.14,96.8 144.47,96.8 145.14,97.46 v2(145.36,97.46)
  IN4 w0.508: v2(151.4,101.09) 151.47,101.03 151.47,95.66 v2(152.44,94.69)
  BOTTOM w0.254: v2(123.94,98.29) 123.64,98.59 UC1.AJ16
  BOTTOM w0.305: 166.9,93.77 166.26,94.41 JSPI1.15
  BOTTOM w0.356: v2(152.44,94.69) 151.98,95.15 CC10.1 152,95.32 UC5.8 ; v2(151.4,101.09) 151.4,101.48 151.75,101.83 CC9.1 152.64,101.23 UC6.8
  BOTTOM w0.381: 166.9,93.77 166.9,91.42 165.84,90.36 163.05,90.36 v2(162.46,89.78)
+3.3V_TBT: length 19.7
  TOP w0.127: RT11.2 v1(23.04,106.34)
  TOP w0.254: CT43.1 25.14,100.7 25.44,100.41 v2(25.44,100.3)
  TOP w0.381: v2(24.03,107.07) RT11.2 ; v2(31.44,107.33) 31.14,107.03 31.14,106.48 30.46,105.8 29.65,105.8 28.98,105.12 RT337.2
  TOP w0.508: RT336.2 34.26,98.15 33.76,97.64 v2(33.52,97.64) ; RT14.2 34.86,112.15 33.82,111.11 v2(33.82,110.42) 33.89,110.35 RT13.2 ; RT12.2 31.22,109.61 v2(31.06,109.77) ; RT15.2 v2(37.49,106.79)
  BOTTOM w0.203: v2(25.44,100.3) UT1.H9
  BOTTOM w0.381: v2(37.83,85.84) 37.83,85.99 36.85,86.97 36.85,88.54 LT2.2
  vias: v2(15.28,103.05) v2(15.88,102.97) v2(21.74,111.64) v2(21.74,111.01) v2(21.74,110.37) v2(22.38,111.64) v2(22.38,111.01) v2(22.38,110.37)
+3.3V_TBT_FLASH_R: length 22.5
  TOP w0.254: v2(35.84,89.67) 36.35,89.16 RT2.2 ; RT4.2 v2(36.22,87.13) 36.22,86.2 v1(36.9,85.52) 37.43,84.99 v2(37.88,84.99) ; RT3.2 v2(36.22,88.15)
  IN1 w0.254: v2(35.84,89.67) 36.22,89.29 v2(36.22,88.15) v2(36.22,87.13)
  BOTTOM w0.254: RT1.2 41.39,79.15 40.38,78.14 RT10.2 39.26,78.14 38.73,78.66 RT9.1 38.73,80.01 38.96,80.23 CT1.1 38.16,81.25 UT2.8 38.16,82.58 38.95,83.36 39.42,83.36 39.68,83.62 39.68,84.01 39.92,84.24 39.92,84.6 39.53,84.99 v2(37.88,84.99)
+3.3V_TBT_LC: length 45.5
  TOP w0.127: v1(36.42,106.72) 36.4,106.74 v2(35.72,106.74)
  TOP w0.254: v2(29.34,101.59) CT41.1
  IN3 w0.508: v2(40.5,79.35) 39.96,79.9 39.96,81.85 41.15,83.05 41.15,88.72 39.05,90.83 39.05,97.73 39.45,98.13 39.45,99.69 39.82,100.05 39.82,104.42 39.32,104.92 37.54,104.92 v2(35.72,106.74)
  IN4 w0.508: v2(32.77,104.88) 31.88,103.99 31.88,101.19 31.6,100.91 30.44,100.91 29.76,101.59 v2(29.34,101.59)
  BOTTOM w0.203: UT1.R6 v2(29.34,101.59)
  BOTTOM w0.381: v2(32.77,104.88) 32.77,105.02 33.8,106.05 35.03,106.05 v2(35.72,106.74)
  BOTTOM w0.508: RT9.2 40.27,79.12 v2(40.5,79.35)
+3.3V_TBT_S0: length 1.1
  TOP w0.127: v2(35.23,93.51) v1(35.23,94.15)
  BOTTOM w0.203: UT1.R13 29.02,98.67 v2(29.34,98.35)
+3.3V_TBT_SX: length 15.8
  TOP w0.127: v1(26.14,110.5) 26.43,110.2 v2(26.43,109.87)
  TOP w0.254: v2(24.78,101.6) 24.78,101.98 CT42.1
  TOP w0.508: RT371.2 v2(34.82,109.36) ; RT338.2 30.59,111.91 30.98,112.3 31.63,112.3 v2(32.38,111.55) ; v2(29.22,109.85) 28.85,109.49 RT16.2 RT372.2
  IN2 w0.508: v2(34.82,109.36) 34.82,110.34 33.62,111.55 v2(32.38,111.55)
  BOTTOM w0.203: UT1.F8 v2(24.78,101.6)
  BOTTOM w0.508: RT19.2 RT18.2 28.6,109.66 v2(28.37,109.89) ; RT17.2 24.68,109.39 25.2,109.9 26.4,109.9 v2(26.43,109.87) 26.78,109.52 RT20.2
  vias: v2(20.67,109.08) v2(21.26,109.08)
+3.3V_TBTA_FLASH: length 32.7
  TOP w0.254: v2(30.5,73.99) 30.5,73.61 v1(30.31,73.42) 29.55,73.42 29.28,73.69 29.28,74.42 29.55,74.69 RT106.2 ; RT107.2 33.62,78.28 34.19,77.71 35.42,77.71 v2(36.69,76.44)
  TOP w0.381: RT76.2 27.09,79.36 v2(26.75,79.7) ; RT52.2 RT51.2 27.99,69.56 CT70.1 ; CT70.1 29.23,70.48 RT50.2 ; CT70.1 v2(29.87,69.56) ; v2(27.42,73.03) 27.98,72.48 RT53.2
  BOTTOM w0.203: CT84.1 30.96,76.33 30.96,76.85 31.16,77.05 31.16,77.79 31.02,77.93 UT5.G1
  BOTTOM w0.305: 31.14,68.59 31.14,67.99 30.38,67.23 JDB1.1
  BOTTOM w0.381: RT10.1 39.26,77.23 38.15,78.34 RT66.2 RT67.2 ; RT95.2 v2(27.25,74.23) ; CT84.1 30.55,75.18 30.55,74.04 v2(30.5,73.99)
  BOTTOM w0.508: RT10.1 39.24,76.44 v2(36.69,76.44) ; v2(29.87,69.56) 30.17,69.56 31.14,68.59 UT6.8 ; RT98.2 33.29,89.02 33.79,89.52 v2(34.05,89.52)
+3.3V_TP: length 20.2
  TOP w0.381: 207.86,56.08 207.86,54.87 208.09,54.65 v1(211.68,54.65) 213.16,54.65 v2(213.45,54.94) RZ20.1 214.08,54.95 RZ116.1 ; v2(215.72,53.33) 215.72,53.66 216.76,54.7 RZ21.1 216.75,54.95 RZ117.1 ; RZ19.1 212.19,59.44 v2(211.78,59.85)
  BOTTOM w0.305: v2(209.82,59.84) 210.05,59.61 JKBTP1.9
  BOTTOM w0.381: v2(215.72,53.33) 214.11,54.94 v2(213.45,54.94)
  BOTTOM w0.508: v2(209.82,59.84) 209.82,60.34 210.28,60.8 211.42,60.8 211.78,60.44 v2(211.78,59.85)
+3.3V_TSP: length 5.4
  TOP w0.508: QV8.1 49.17,127.46 49.95,128.23 v3(50.32,128.23) 50.79,128.71 CV19.1
  BOTTOM w0.254: JEDP1.1 51.25,131.88 v2(51.08,131.71)
+3.3V_VCCHDA: length 19
  TOP w0.127: v2(135.89,97.37) 135.89,97.09 v1(136.12,96.86)
  TOP w0.254: CC313.1 122.41,98.82 122.01,98.42 v2(122.01,98.24) ; LC1.2 137.29,97.62 137.11,97.43 CC324.1 135.96,97.43 v2(135.89,97.37)
  IN2 w0.254: v2(122.01,98.24) 122.01,98.09 122.36,97.74 124.13,97.74 124.37,97.98 131,97.98 131.71,97.27 135.79,97.27 v2(135.89,97.37)
  BOTTOM w0.254: UC1.AJ19 v2(122.01,98.24)
+3.3V_VDD_DCIN: length 112.2
  TOP w0.508: PC12.1 38.76,57.26 v2(38.76,56.91) 38.75,56.89 PR1206.1 PR1208.1 ; v2(63.59,117.57) 63.27,117.89 v3(62.83,117.89) 62.29,117.89 61.36,116.96 58.55,116.96 58.13,116.53 55.31,116.53 55.19,116.42 ; 55.19,116.42 55.19,116.86 55.12,116.93 55.12,117.5 54.86,117.75 v2(54.27,117.75) ; 55.19,116.42 PC9.1 PR17.1
  IN2 w0.508: v2(54.27,117.75) 53.64,118.37 50.51,118.37 47.14,115 47.14,108.73 43.5,105.09 43.5,103.72 45.49,101.73 v2(45.49,101.18)
  IN4 w0.508: v2(38.76,56.91) 38.76,57.2 37.83,58.12 37.35,58.12 36.09,59.38 36.09,62.65 38.01,64.57 38.01,70.38 37.61,70.78 37.61,75.21 39.2,76.79 39.2,78.43 39.9,79.13 39.9,79.64 40.66,80.4 41.14,80.4 41.64,80.9 41.64,85.86 43.41,87.63 44.46,87.63 44.47,87.64 45.6,87.64 46.68,88.72 46.68,89.84 46.33,90.19 46.33,91.56 45.63,92.26 45.63,95.69 46.6,96.66 47.68,96.66 48.31,97.28 48.31,99.68 46.8,101.18 v2(45.49,101.18)
  BOTTOM w0.381: PU1.5 55.78,120.36 55.78,119.52 55.28,119.02 54.88,119.02 54.27,118.4 v2(54.27,117.75) 56.4,117.75 57.92,119.28 PR27.2
  BOTTOM w0.508: v2(38.76,56.91) 39.08,56.91 39.45,57.29 PD1801.3 ; PU2.3 64.2,118.02 63.98,118.24 PC10.1 v2(63.59,117.57)
+3.3V_VDD_PIC: length 93.5
  TOP w0.254: v2(45.31,99.41) 45.34,99.38 45.34,99.24 45.07,98.97 43.9,98.97 PR1253.1 ; PR1237.1 37.5,57.94 38.12,58.56 v2(38.12,59) 38.07,59.05 v3(37.54,59.05) 34.94,59.05 34.36,58.48 PR1254.2 PR1240.1 ; v2(31.85,125.33) PR1236.2
  TOP w0.381: QT1.5 38.43,80.91 38.82,80.52 39.36,80.52 39.76,80.91 QT1.2 40.78,80.91 v2(40.91,81.04)
  IN1 w0.254: v2(34.26,63.7) 34.26,62.08 35.99,60.34 37.3,60.34 38.12,59.51 v2(38.12,59)
  IN2 w0.254: v2(31.85,125.33) 31.27,125.33 26.98,121.05 26.98,113.82 25.72,112.56 23.76,112.56 23.22,112.02 23.22,109.31 v2(21.06,107.15)
  IN4 w0.254: v2(36.72,71.66) 37.13,72.07 37.13,75.41 38.71,76.99 38.71,81.32 39.16,81.77 40.31,81.77 40.91,81.18 v2(40.91,81.04) 40.98,81.11 40.98,86.09 42.99,88.11 44.25,88.11 44.69,88.54 44.69,95.16 45.11,95.58 45.11,96.16 46.13,97.18 47.15,97.18 47.6,97.63 47.6,99.04 47.36,99.28 45.44,99.28 v2(45.31,99.41)
  BOTTOM w0.254: PD1801.2 39.41,59 v2(38.12,59) ; PR1226.1 35.44,64.59 35.06,64.21 PC1204.1 ; PC1204.1 v2(34.26,63.7) ; PC1204.1 35.06,63.68 35.61,63.13 PU1200.5 ; v2(45.31,99.41) 45.08,99.64 43.53,99.64 43.34,99.82 43.34,102.02 PR1214.1
  vias: v2(21.06,106.49) v2(23.65,65.09) v2(24.23,65.1) v2(36.24,71.18)
+3.3V_VDD_PIC_PDA: length 12.1
  TOP w0.127: v1(34.81,77.18) 34.48,76.85 v2(34.48,76.53)
  IN1 w0.508: v2(34.48,76.53) 34.48,76.38 34.05,75.95 32.51,75.95 32.04,76.42 32.04,77.07 31.68,77.43 30.5,77.43 v2(30.43,77.35)
  BOTTOM w0.203: v2(30.43,77.35) 30.52,77.45 UT5.H1 ; UT5.B1 33.52,78.25 34.46,77.31 34.46,76.54 v2(34.48,76.53)
  BOTTOM w0.381: CT74.1 35,74.81 35,76.19 34.66,76.53 v2(34.48,76.53)
+3.3V_WLAN: length 14.4
  IN3 w2.032: 240.51,86.31 240.51,90.54 241.35,91.37 241.35,95.84 241.7,96.18 241.7,99.38 242.32,100
  vias: v2(241.63,61.73) v2(242.21,62.37) v2(242.21,61.73) v2(242.37,80.78) v2(242.37,80.2) v2(242.37,79.59) v2(243.58,101.63) v2(243.6,100.95) v2(244.22,101.63) v2(244.23,100.95) v3(243.15,104.44) v3(243.15,102.5) v3(243.43,106.32)
+3.3V_WLAN_UZ2: length 2.3
  TOP w0.127: v1(246.76,108.62) 246.91,108.77 249.02,108.77
+3.3V_WWAN:
  vias: v2(236.76,94.95) v2(236.76,94.35) v2(236.76,93.76) v2(237.7,112.47) v2(238.09,112.91) v2(238.34,108.34) v2(238.34,107.71) v2(238.47,112.47) v2(238.66,108.85) v2(239.04,108.34) v2(239.04,107.71) v2(275.04,97.17) v2(275.04,96.53) v2(275.04,95.9) v2(275.04,95.26) v2(275.04,94.63) v3(237.76,107.47)
+3.3V_WWAN_UZ4: length 2.3
  TOP w0.127: v3(273.57,92.52) 273.89,92.84 275.78,92.84
+5V_ALW: length 334.3
  TOP w0.127: v2(124.35,132.36) 126.34,132.36 127.09,131.62 v3(127.09,131.46)
  TOP w0.203: UZ3.4 159,60.34 159.29,60.04 v2(159.41,60.04) ; UZ4.4 279.49,90.94 279.55,91.01 280.15,91.01 280.44,90.71 280.44,90.12 ; UZ2.4 253.01,111.2 v2(253.2,111.39) ; v2(243.86,63.6) 244.57,63.6 244.81,63.83 UZ5.4
  TOP w0.254: UZ21.3 124.99,131.73 v2(124.35,132.36) ; UZ19.3 v2(120.6,132.16) ; v2(200.74,54.16) 200.74,53.43 v3(201.64,52.53) 201.64,51.89 202.77,50.76 205.54,50.76 205.66,50.89 UZ8.4
  TOP w0.305: 138.48,65.26 137.69,66.05 137.44,66.05 137.19,66.3 UZ26.3
  TOP w0.381: PR602.2 41.58,96.59 41.2,96.21 41.2,95.68 40.47,94.96 40.47,93.5 40.58,93.39 v2(40.58,93.23) ; v2(225.26,56.59) 225.28,56.56 CZ64.1 225.28,55.56 CZ69.1
  TOP w0.508: PR634.2 PR615.2 51.08,85.71 v2(51.08,85.19) ; v2(32.62,125.33) 32.62,125.7 33.13,126.21 PR7.1 ; PC685.1 62.78,114.95 v2(62.98,114.75) ; PR691.1 56.44,98.42 v2(54.54,98.42) ; v2(248.5,58.18) RA53.2 ; LED3.2 v2(294.47,127.59) ; v2(143.2,64.12) v3(142.06,65.26) 138.48,65.26 ; PR686.1 61.14,106.11 PC701.1 61.17,105.19 PC700.1 61.17,104.16 60.88,103.86 v2(60.88,103.26)
  IN1 w0.508: v2(54.33,91.91) 53.35,90.93 53.35,90.55 52.48,89.67 46.99,89.67 46.49,90.18 46.49,90.68 46.01,91.16 43.87,91.16 43.01,90.3 42.07,90.3 40.39,91.97 40.39,93.04 v2(40.58,93.23) ; v2(143.2,64.12) 144.6,64.12 147.32,61.4 152.17,61.4 152.62,60.95 158.16,60.95 159.07,60.04 v2(159.41,60.04)
  IN2 w0.508: v2(62.98,114.75) 62.75,114.75 61.59,113.59 61.59,108.22 v2(62.23,107.58) 62.23,105.84 60.88,104.49 v2(60.88,103.26) 61.56,102.59 61.56,95.71 61.11,95.26 ; v2(278.34,89.16) 277.33,90.18 277.33,96.87 275.59,98.61 274.37,98.61 267.33,105.65 265.74,105.65 263.07,108.32 258.12,108.32 255.88,110.56 255.88,111.05 ; v2(62.32,88.57) 62.31,88.56 61.77,88.56 61.17,89.17 61.17,95.19 61.11,95.26 ; v2(51.08,85.19) 51.08,85.74 53.71,88.37 53.71,91.29 v2(54.33,91.91) ; v2(57.5,94.41) 57.5,94.83 57.94,95.26 61.11,95.26 ; v2(41.14,60.06) 41.14,54.67 40.54,54.06 v2(40.27,54.06) ; 255.88,111.05 253.54,111.05 v2(253.2,111.39) ; 255.88,111.05 255.88,113.9 253.01,116.76 253.01,123.35 257.85,128.18 282.51,128.18 283.55,127.14 283.55,119.9 284.01,119.44 290.88,119.44 294.47,123.03 v2(294.47,127.59) ; v2(288.76,9.41) 287.04,9.41 285.98,10.48 285.98,23.76 278.64,31.1 278.64,52.53 v2(279.14,53.03)
  IN3 w0.508: v2(40.58,93.23) 40.58,91.58 42.68,89.48 42.68,80.59 43.52,79.76 43.52,78.8 ; v2(54.54,98.42) 56.02,98.42 56.68,97.76 56.68,95.57 57.5,94.74 v2(57.5,94.41) 56.89,93.8 56.22,93.8 v2(54.33,91.91)
  IN4 w0.508: v2(62.34,85.08) 62.34,88.43 62.32,88.44 v2(62.32,88.57)
  BOTTOM w0.254: v2(62.98,114.75) 62.79,114.56 PU614.6
  BOTTOM w0.305: v2(225.26,56.59) 225.26,56.75 224.95,57.06 JUSH1.18 ; PU612.15 61.39,88.4 61.51,88.53 PC668.1 ; v2(57.5,94.41) PR689.1 57.52,93.81 PC697.1 58.34,94.17 58.19,94.32 PU613.15 ; PU610.15 60.34,107.8 61.31,107.8 PC661.1
  BOTTOM w0.508: v2(62.32,88.57) 62.32,87.9 62.02,87.6 PR681.1 61.51,87.65 61.51,88.45 PC668.1 ; v2(60.88,103.26) 60.92,103.31 PR688.1 ; DT1.2 v2(22.95,69.16) ; v2(62.34,85.08) 62.34,84.72 61.5,83.88 PR680.1 ; v2(288.76,9.41) 288.76,8.77 289.03,8.51 JLED1.1 ; PC661.1 v2(62.23,107.58) ; JUART1.4 v2(131.21,133.19)
  vias: v2(18.25,52.65) v2(18.25,52.02) v2(18.88,52.65) v2(18.88,52.02) v2(23.39,83.79) v2(23.97,83.79) v2(73.05,134.5) v2(73.68,134.5) v2(74.32,134.5) v2(146.7,128.78) v2(146.7,128.14) v2(162.62,125.33) v2(162.66,125.94) v2(200.15,54.18) v2(200.15,56.49) v2(200.15,55.9) v2(200.15,55.32) v2(200.16,54.75) v2(200.73,56.49) v2(200.73,55.9) v2(200.73,55.32) v2(200.73,54.73) v2(201.32,54.51) v2(201.31,53.87) v2(275.18,74.53) v2(276.19,79.61) v2(276.82,79.61) v2(277.46,79.61) v2(278.09,79.61) v2(279.49,89.23) v2(279.49,88.59) v2(280.12,89.55) v2(280.12,88.91)
+5V_ALW2: length 3
  TOP w0.127: v2(185.96,58.04) v3(185.96,58.63)
  TOP w0.254: v2(185.96,58.04) 185.44,58.04 185.13,57.73 PC126.1
  BOTTOM w0.254: v2(185.96,58.04) 185.84,57.91 PU102.15
+5V_ALW_PDA: length 7.2
  IN4 w0.508: v2(30.05,82.43) 29.43,82.43 26.73,85.13 v2(26.73,87.11)
  BOTTOM w0.203: v2(30.05,82.43) 30.52,82.91 UT5.H10
  vias: v1(33.88,86.36) v2(33.51,85.11) v2(33.51,84.48) v2(33.67,85.68) v2(34.15,85.11) v2(34.15,84.48) v2(34.27,85.74)
+5V_ALWP: length 22.8
  BOTTOM w0.254: 196.52,58.81 187.52,58.81 187.09,58.38 186.37,58.38 186.19,58.56 185.67,58.56 185.39,58.28 PU102.14 ; PR117.2 196.08,59.84 v2(196.64,59.28)
  vias: v1(198.06,57.45) v2(196.81,56.38) v2(196.81,54.63) v2(197.15,59.71) v2(197.4,56.38) v2(197.4,54.63) v2(197.98,56.38) v2(197.98,54.63)
+5V_PD_VDD: length 6.1
  TOP w0.127: v2(20.5,69.16) 20.5,70.2 v1(20.7,70.41)
  BOTTOM w0.508: DT1.1 19.97,68.53 UT7.1 ; DT1.1 v2(20.5,69.16) ; DT1.1 DT2.1
+5V_RUN: length 147.6
  TOP w0.356: v2(206.54,57.83) 206.51,57.86 CZ92.1
  TOP w0.381: v2(223.99,56.59) 223.83,56.59 223.45,56.21 CZ66.1 223.45,55.5 CZ71.1
  IN1 w0.508: 223.99,55.17 218.41,55.17 217.78,55.8 214.04,55.8 213.24,56.61 210.61,56.61 210.25,56.25 208.13,56.25 v2(206.54,57.83) ; 223.99,55.17 224.6,54.56 226.76,54.56 228.97,52.36 232.46,52.36 233.05,52.95 233.05,54.22 236.6,57.77 239.65,57.77 240.31,58.43 v2(240.31,60.51) ; 223.99,55.17 v2(223.99,56.59)
  IN2 w1.016: 33.68,65.23 27.14,65.23 25.17,67.19 ; 17.55,71.77 17.55,71.82 14.18,75.2 14.18,91.46 ; 239.61,117.36 240.99,115.97 240.99,113.36 242.65,111.71 244.04,111.71 247.64,108.11 255.74,108.11 257.28,106.58 261.66,106.58 264.44,103.8 265.2,103.8 273.26,95.73 v2(273.26,89.79) 273.26,89.69 v2(273.94,89.01)
  IN4 w1.016: 18.31,70.62 20.95,70.62 21.8,69.76 21.8,68.91 22.31,68.4
  BOTTOM w0.305: JUSH1.20 223.95,56.63 v2(223.99,56.59) ; JKBTP1.16 206.55,57.97 206.54,57.96 v2(206.54,57.83)
  BOTTOM w0.508: RZ370.1 241.14,118.52 241.14,117.85 240.78,117.49 239.61,117.49 v2(239.04,118.06)
  BOTTOM w1.016: 13.14,97.86 14.25,97.86 16.31,95.81 16.31,94.4 15.07,93.17 15.07,92.42
  vias: v2(15.21,91.95) v2(15.21,91.36) v2(17.51,70.88) v2(17.5,70.3) v2(23.14,68.15) v2(23.77,68.15) v2(34.82,65.09) v2(35.46,65.09) v2(73.25,66.9) v2(73.68,67.32) v2(238.34,118.06) v2(240.89,60.51) v2(241.46,60.85) v2(241.83,60.42) v2(242.19,60.87) v2(273.9,86.75) v2(273.9,86.12) v2(274.47,87.07) v2(274.47,86.43) v2(274.47,85.8) v2(274.47,85.16) v3(243.61,61.75)
+5V_RUN_AUDIO:
  vias: v2(247.6,60.03) v2(247.6,59.44) v2(247.6,58.87) v2(247.6,58.3) v2(247.59,57.73) v2(264.43,65.28) v2(264.43,64.47) v2(265,65.67) v2(265,65.05) v3(248.49,56.27)
+5V_RUN_AUDIO_UZ5:
  vias: v1(248,61.58)
+5V_RUN_CHG: length 4.2
  BOTTOM w0.127: v1(244.15,118.88) RZ370.2 242.66,119.12 242.66,120.34 242.18,120.81 QZ4.1
+5V_RUN_PVDD_L:
  vias: v1(261.54,59.47) v2(264.44,63.05) v2(264.36,59.6) v2(264.36,59.02) v2(265.81,63.05)
+5V_RUN_UZ4:
  vias: v1(278.1,87.97)
+5V_TBT_VBUS: length 4.4
  TOP w0.127: v2(21.73,71.96) v1(22.49,71.96)
  BOTTOM w0.508: CT93.1 23.04,72.13 22.45,72.72 DT3.1 v2(21.73,71.96) DT2.2
+5V_TBTA_VBUS_D: length 3.4
  TOP w0.127: v2(18.3,72.72) v1(18.3,72.01)
  BOTTOM w0.508: UT8.3 17.12,71.98 17.85,72.72 v2(18.3,72.72) DT3.2
+5V_USB_CHG_PWR:
  vias: v2(278.03,73.16) v2(278.66,73.16) v2(280.38,72.85) v2(281.01,72.85) v2(282.28,74.31) v2(282.28,73.67) v3(279.45,72.32)
+GND_CHASSIS: length 15.7
  TOP w0.508: RL15.2 RL16.2 v3(265.86,119.98) 262.55,119.98 RL17.2 RL18.2 259.4,119.96 258.35,121.02 v2(257.22,121.02)
  BOTTOM w0.508: v2(257.22,121.02) 256.47,120.26 CL22.2
+VBUS_DC_SS: length 73.8
  IN4 w0.508: v2(52.68,103.99) 61.33,103.99 62.32,103.01 62.32,101.04 63.56,99.8 63.56,84.05 57.11,77.61 54.44,77.61 49.24,72.4 42.19,72.4 40.85,71.07 40.85,65.23 44.11,61.97 v2(45.18,61.97)
  BOTTOM w0.127: 52.47,103.06 52.47,102.69 v1(52.17,102.39)
  BOTTOM w0.508: PD903.2 46.63,59.26 45.18,60.71 v2(45.18,61.97)
  vias: v2(52.09,106.52) v2(52.09,105.93) v2(52.09,105.35) v2(52.09,104.77) v2(52.09,104.18) v2(52.68,103.41)
+VCC1V8A_TBTA_LDO: length 3.8
  TOP w0.127: v2(27.51,76.59) 27.43,76.59 v1(27.02,76.19)
  BOTTOM w0.203: 28.15,77.42 28.42,77.68 28.73,77.68 UT5.K1
  BOTTOM w0.457: v2(27.51,76.59) 27.77,76.86 CT73.1
  BOTTOM w0.508: 28.15,77.42 CT73.1
+VCC1V8D_TBTA_LDO: length 9.8
  TOP w0.381: v2(34.46,78.78) 34.46,80.23 34.78,80.54 34.79,80.54 35.09,80.85 35.09,80.86 35.65,81.41 v1(35.65,82.74) 35.65,84.2 v2(34.88,84.97)
  BOTTOM w0.203: UT5.A2 34.22,78.78 v2(34.46,78.78)
  BOTTOM w0.381: CT72.1 35.48,78.47 34.9,78.47 34.59,78.78 v2(34.46,78.78)
  BOTTOM w0.508: RT97.1 34.91,85.01 v2(34.88,84.97)
+VCC3V3_ANA_PCIE: length 1.4
  TOP w0.254: v2(26.74,97.05) 26.09,96.4 CT63.1
  BOTTOM w0.203: UT1.L16 v2(26.74,97.05)
+VCC3V3_ANA_USB2: length 1.1
  TOP w0.254: v2(26.74,97.7) 26.71,97.68 CT64.1
  BOTTOM w0.203: UT1.J16 26.43,97.37 26.74,97.68
+VCC_1P8: length 23.8
  TOP w0.127: v2(138.52,102.44) v1(137.87,102.44)
  TOP w0.457: v2(126.24,104.82) 126.24,104.53 126.62,104.15 CC222.1
  IN4 w0.254: 131.47,105.05 131.47,104.6 131.23,104.36 126.48,104.36 126.24,104.61 v2(126.24,104.82) 126.24,105.1 126.48,105.34 131.18,105.34 131.47,105.05
  IN4 w0.508: 131.47,104.85 134.81,104.85 136.25,103.41 137.55,103.41 v2(138.52,102.44)
  BOTTOM w0.254: v2(126.24,104.82) 126.24,104.63 126.43,104.44 UC1.U11 UC1.U12
  BOTTOM w0.508: v2(138.52,102.44) 138.12,102.04 RC313.2
+VCC_CORE: length 37.7
  TOP w0.381: PC1050.1 114.49,109.42 v2(114.69,109.62)
  TOP w0.508: RC140.2 109.14,120.53 v2(107.81,119.2)
  BOTTOM w0.127: 110.09,97.2 UC1.AL40 ; UC1.AL40 110.09,97.88 ; UC1.AL40 109.77,97.53 109.77,97.53 ; UC1.AL40 110.42,97.53 110.42,97.53 ; UC1.J33 113.14,108.83 ; UC1.J33 112.49,108.83 ; UC1.J33 112.84,108.5 ; UC1.J33 112.84,109.13 ; UC1.AL33 113.75,97.87 ; UC1.AL33 114.06,97.53 ; UC1.AL33 113.75,97.2 ; UC1.AL33 113.41,97.53 ; UC1.K38 110.55,108.68 ; UC1.K38 110.86,108.36 ; UC1.K38 110.55,108 ; 111.16,108.36 UC1.K37 ; UC1.K37 111.47,108.66 ; UC1.K37 111.47,108.02 ; UC1.J40 109.18,108.52 ; UC1.J40 108.86,108.83 ; UC1.J40 109.49,108.83 ; UC1.J40 109.18,109.16 ; 111.93,97.83 111.92,97.83 UC1.AL37 ; 107.81,107.94 107.81,107.95 UC1.K43 107.81,108.69 ; 109.33,108.36 UC1.K40 ; UC1.K40 109.64,108.68 ; UC1.K40 109.64,107.97 ; 110.55,97.65 110.55,97.65 UC1.AK38 ; 112.23,97.53 UC1.AL37 ; UC1.AL37 111.92,97.18 111.93,97.17 ; UC1.AL37 111.6,97.53 111.6,97.53 ; UC1.AK40 109.64,98.37 ; UC1.AK40 109.64,97.64 ; UC1.AK40 109.95,97.99 ; UC1.AK40 109.33,97.99 ; 112.38,107.97 UC1.K35 ; UC1.K35 112.69,108.36 ; UC1.K35 112.38,108.69 ; UC1.J37 111.01,109.16 ; UC1.J37 111.31,108.83 ; UC1.J37 111.01,108.52 ; UC1.J37 110.68,108.83 ; 108.67,108.74 108.72,108.69 UC1.K42 ; UC1.AK35 112.69,97.99 ; UC1.AK35 112.38,98.34 ; UC1.AK35 112.38,97.66 ; UC1.AK35 112.04,97.99 ; UC1.K33 113.29,107.92 ; UC1.K33 113.29,108.69 ; UC1.K33 112.99,108.36 ; 111.85,97.96 111.5,97.96 UC1.AK37 ; 110.55,98.4 UC1.AK38 ; UC1.AK38 110.23,97.99 ; 109.03,108.36 UC1.K42 ; UC1.K42 108.72,107.98 ; UC1.AK37 111.47,97.64 111.47,97.63 ; UC1.AK37 111.52,98.05 111.52,98.32 ; UC1.AK33 113.29,98.34 ; UC1.AK33 113.29,97.63 ; UC1.AK33 113.63,97.99 ; UC1.AK33 112.99,97.99 ; 114.67,109.12 UC1.J30 114.36,108.83
  BOTTOM w0.203: UC1.A39 109.74,113.49 v2(109.98,113.73) ; v2(112.22,113.7) UC1.A34 ; UC1.A30 114.7,113.45 v2(114.45,113.7) ; UC1.A44 107.26,113.93 v2(107.29,113.96)
  BOTTOM w0.254: UC1.G40 109.39,109.54 v2(109.17,109.54) 108.97,109.54 UC1.G42 ; UC1.AM35 v2(111.92,96.66) UC1.AM37 v2(111.01,96.66) UC1.AM38 ; UC1.G37 111.22,109.54 v2(111,109.54) 110.8,109.54 UC1.G38 ; UC1.G33 113.09,109.5 v2(112.83,109.5) 112.59,109.5 UC1.G35 ; UC1.G32 114.54,109.62 v2(114.69,109.62) 114.79,109.62 UC1.G30
  BOTTOM w0.508: PC1070.1 v2(81.81,106.44) ; PC1010.1 v2(81.81,109.29) ; PC1069.1 v2(80.61,106.44) ; PC1009.1 v2(83.02,109.29) ; PC1071.1 v2(80.61,109.29)
  vias: v2(69.7,105.18) v2(69.7,104.55) v2(70.34,105.18) v2(70.34,104.55) v2(70.38,102.37) v2(70.38,101.74) v2(70.97,105.18) v2(70.97,104.55) v2(71.02,102.37) v2(71.02,101.74) v2(71.46,108.48) v2(71.46,107.84) v2(71.46,107.21) v2(71.46,106.57) v2(71.46,105.94) v2(71.74,111.47) v2(71.73,110.74) v2(71.73,105.18) v2(71.73,104.55) v2(71.78,110.04) v2(72.04,108.47) v2(72.04,107.83) v2(72.04,107.2) v2(72.04,106.56) v2(72.04,105.93) v2(72.37,111.49) v2(72.36,110.76) v2(72.41,110.06) v2(72.54,105.29) v2(72.99,110.75) v2(73.07,111.53) v2(73.14,110.05) v2(73.18,105.29) v2(73.81,111.52) v2(73.78,110.05) v2(73.94,105.29) v2(74.45,111.52) v2(74.39,110.04) v2(74.57,105.29) v2(75.02,111.52) v2(75.01,110.02) v2(75.14,106.75) v2(75.14,106.12) v2(75.21,105.29) v2(75.6,111.5) v2(75.67,110) v2(75.75,106.75) v2(75.75,106.12) v2(75.82,105.52) v2(76.22,111.52) v2(76.35,110) v2(76.35,109.29) v2(76.35,108.66) v2(76.35,108.02) v2(76.35,107.39) v2(76.35,106.75) v2(76.38,106.1) v2(76.98,111.45) v2(77.02,110.62) v2(76.98,109.98) v2(76.99,109.29) v2(76.99,108.66) v2(76.99,108.02) v2(76.99,107.39) v2(76.99,106.75) v2(83.84,109.23) v2(83.84,107.96) v2(84.28,107.57) v2(84.43,109.24) v2(84.86,108.6) v2(84.94,106.44) v2(85.02,109.25) v2(85.49,108.6) v2(85.51,106.44) v2(85.62,109.23) v2(86.08,106.44) v2(86.26,108.6) v2(86.64,106.44) v2(87.27,106.44) v2(87.84,106.44) v2(88.42,106.44) v2(89.05,106.44) v2(108,105.85) v2(107.99,103.52) v2(107.98,101.16) v2(108.91,99.02) v2(109.18,108.14) v2(109.18,107.28) v2(109.21,105.86) v2(109.21,103.51) v2(109.19,101.17) v2(109.55,99.02) v2(109.62,107.71) v2(110.09,107.28) v2(110.4,105.87) v2(110.39,103.53) v2(110.39,101.17) v2(110.54,107.71) v2(110.77,99.02) v2(111.01,108.14) v2(111.01,107.28) v2(111.45,107.71) v2(111.5,99.02) v2(111.6,105.87) v2(111.59,103.5) v2(111.59,101.16) v2(111.92,107.28) v2(111.91,98.32) v2(112.34,99.02) v2(112.39,107.71) v2(112.84,108.14) v2(112.81,103.48) v2(112.81,101.14) v2(112.84,98.32) v2(112.85,107.28) v2(112.85,105.88) v2(113.31,107.71) v2(113.32,105.27) v2(113.31,104.16) v2(113.31,102.9) v2(113.31,101.82) v3(71.12,111.43)
+VCC_CORE_G0: length 1.1
  TOP w0.254: v2(114.62,108.07) 114.38,108.07 T122.1
  BOTTOM w0.254: UC1.K32 114.33,108.36 v2(114.62,108.07)
+VCC_CORE_G1: length 2.9
  TOP w0.254: v2(114.22,99.29) 114.22,98.84 114.12,98.74 114.12,98.08 T123.1
  BOTTOM w0.254: v2(114.22,99.29) 114.22,98.84 114.21,98.83 UC1.AK32
+VCC_GT: length 23.5
  BOTTOM w0.127: UC1.K56 100.49,108 ; UC1.K56 100.49,108.7 ; UC1.K56 100.19,108.36 ; UC1.K56 100.8,108.36 ; 97.29,105.34 UC1.R63 ; UC1.R63 96.68,105.34 ; UC1.R63 96.99,105.02 ; UC1.R63 96.99,105.68 ; UC1.K55 101.71,108.36 ; UC1.K55 101.41,108.67 ; UC1.K55 101.1,108.36 ; UC1.K55 101.41,108.01 101.4,108.01 ; 98.21,108.52 UC1.J60 98.55,108.83 ; 97.46,102.72 UC1.Y62 ; UC1.Y62 97.77,103.05 ; UC1.Y62 97.18,103.05 ; 100.95,108.52 UC1.J55 ; UC1.J55 100.58,108.83 ; UC1.J55 101.32,108.83 ; UC1.K58 99.58,107.99 ; UC1.K58 99.27,108.36 ; UC1.K58 99.88,108.36 ; UC1.K58 99.58,108.67 ; UC1.J53 101.56,108.83 ; UC1.J53 102.27,108.83 ; UC1.J53 101.86,108.52 ; 97.46,105.19 UC1.T62 ; UC1.T62 97.46,104.59 ; UC1.T62 97.17,104.88 ; UC1.T62 97.76,104.88 ; UC1.N63 96.69,106.25 ; UC1.N63 96.99,105.91 ; UC1.N63 97.27,106.25 ; UC1.N63 96.99,106.56 ; 102.02,108.36 UC1.K53 ; UC1.K53 102.32,108.7 ; UC1.K53 102.32,108.06 ; UC1.M62 97.46,107.02 ; UC1.M62 97.17,106.71 ; UC1.M62 97.77,106.71 ; UC1.M62 97.46,106.44 ; UC1.L63 96.68,107.17 ; UC1.L63 96.99,106.86 ; UC1.L63 96.99,107.46 ; UC1.L63 97.31,107.17 ; UC1.J56 99.69,108.83 99.69,108.83 ; UC1.J56 100.04,108.52 ; UC1.J56 100.37,108.83 ; 96.99,102.9 UC1.AA63 ; UC1.AA63 96.73,102.6 ; UC1.AA63 96.99,102.29 ; UC1.AA63 97.27,102.6 ; 98.76,108.8 98.79,108.83 UC1.J58 ; 98.66,108.01 UC1.K60 ; UC1.K60 98.36,108.36 ; UC1.K60 98.97,108.36 ; UC1.K60 98.66,108.67 ; UC1.J58 99.45,108.83 99.46,108.83 ; UC1.J58 99.12,108.52 ; 97.84,107.62 UC1.L62 97.46,107.95 97.48,107.97 ; 96.99,103.21 UC1.W63 ; UC1.W63 96.68,103.51 ; UC1.W63 97.27,103.51
  BOTTOM w0.203: v2(94.87,113.98) UC1.A66 ; v2(97.35,113.92) UC1.A62 ; v2(99.83,113.93) UC1.A58
  vias: v2(69.23,92.36) v2(69.29,92.99) v2(69.88,93.5) v2(69.88,92.92) v2(69.88,92.35) v2(70.52,93.5) v2(70.52,92.92) v2(70.51,92.35) v2(75.21,96.72) v2(75.21,96.09) v2(75.21,95.45) v2(75.21,94.82) v2(75.84,96.72) v2(75.84,96.09) v2(75.84,95.45) v2(75.84,94.82) v2(76.35,99.26) v2(76.35,98.63) v2(76.35,97.99) v2(76.35,97.36) v2(76.48,96.72) v2(76.48,96.09) v2(76.48,95.45) v2(76.48,94.82) v2(76.99,99.9) v2(76.99,99.26) v2(76.99,98.63) v2(76.99,97.99) v2(76.99,97.36) v2(77.11,96.72) v2(77.11,96.09) v2(77.62,99.9) v2(77.62,99.26) v2(77.62,98.63) v2(77.62,97.99) v2(77.62,97.36) v2(81.77,102.63) v2(81.81,99.87) v2(82.98,102.63) v2(82.96,99.84) v2(84.29,102.88) v2(84.29,100.09) v2(85.49,102.88) v2(85.49,100.09) v2(86.7,102.88) v2(86.7,100.09) v2(87.91,102.88) v2(87.91,100.09) v2(89.11,102.88) v2(89.11,100.09) v2(90.32,102.88) v2(90.32,100.09) v2(92.11,103.97) v2(92.11,102.14) v2(92.76,106.65) v2(92.76,104.88) v2(92.76,103.05) v2(93.41,105.8) v2(93.41,102.14) v2(94.06,104.88) v2(94.06,103.97) v2(94.06,103.05) v2(94.71,105.8) v2(94.71,102.14) v2(95.36,106.65) v2(95.36,104.88) v2(95.36,103.05) v2(96.01,103.97) v2(96.64,106.65) v2(96.61,105.78) v2(96.64,102.15) v2(96.66,101.26) v2(97.72,103.51) v2(97.91,105.38) v2(97.86,102.53) v2(98.01,101.99) v2(98.06,104.62) v2(98.07,104.03) v2(98.22,107.96) v2(98.2,103.05) v2(98.61,106.17) v2(98.71,101.41) v2(98.75,103.81) v2(99.13,107.96) v2(99.85,106.17) v2(99.95,101.41) v2(100.05,107.96) v2(99.99,103.8) v2(100.96,107.96) v2(101.88,107.96) v3(68.82,93.71)
+VCC_GT_+VCC_CORE: length 22.8
  BOTTOM w0.127: UC1.J46 105.52,108.52 ; UC1.J46 105.18,108.83 ; UC1.J46 105.9,108.83 105.91,108.83 ; UC1.AL50 104.28,97.53 ; UC1.AL50 104.61,97.86 ; UC1.AL50 104.61,97.18 ; UC1.AL50 104.95,97.53 ; UC1.J45 106.09,108.83 106.09,108.83 ; UC1.J45 106.44,108.52 ; UC1.J45 106.79,108.83 ; UC1.K50 104.15,108.05 ; UC1.K50 104.15,108.67 ; UC1.K50 103.85,108.36 ; UC1.K50 104.46,108.36 ; UC1.AL46 106.44,97.9 ; UC1.AL46 106.75,97.53 ; UC1.AL46 106.08,97.53 ; 104.96,108.83 UC1.J48 ; UC1.J48 104.61,108.52 ; UC1.J48 104.26,108.83 104.26,108.83 ; UC1.AK45 106.89,97.64 ; UC1.AK45 107.22,97.99 ; UC1.AK45 106.6,97.99 ; UC1.AK45 106.89,98.26 ; UC1.AM52 103.24,97.41 ; UC1.AM52 102.93,97.05 ; UC1.AM52 103.59,97.05 ; UC1.AK42 108.42,97.99 ; UC1.AK42 108.72,98.34 ; UC1.AK42 108.72,97.72 ; UC1.AK46 105.58,97.99 ; UC1.AK46 105.98,98.31 ; UC1.AK46 105.98,97.62 ; UC1.AK46 106.31,97.99 ; UC1.AK43 107.81,98.31 ; UC1.AK43 108.14,97.99 ; UC1.AK43 107.44,97.99 ; UC1.AK43 107.81,97.66 ; 103.35,108.83 UC1.J50 ; UC1.J50 103.69,108.52 ; UC1.J50 103.99,108.83 ; UC1.AK50 104.15,97.65 ; UC1.AK50 104.51,97.99 ; UC1.AK50 104.15,98.32 ; UC1.AM50 104.15,97.41 ; UC1.AM50 103.79,97.05 ; UC1.AM50 104.5,97.05 ; UC1.AK48 105.07,97.69 ; UC1.AK48 104.75,97.99 ; UC1.AK48 105.42,97.99 ; UC1.AK48 105.07,98.3 ; 107.05,108.83 UC1.J43 107.35,108.46 ; 104.76,108.36 UC1.K48 ; UC1.K48 105.07,108.63 ; UC1.K48 105.07,107.99 ; UC1.K48 105.37,108.36 ; 108.27,97.88 UC1.AL43 107.92,97.53 ; UC1.AM48 104.7,97.05 ; UC1.AM48 105.07,97.42 ; UC1.AM48 105.42,97.05 ; 102.78,108.52 UC1.J52 103.14,108.83
  BOTTOM w0.203: v2(104.93,113.47) 104.93,113.13 UC1.A48 ; v2(102.34,113.9) 102.31,113.88 UC1.A53
  vias: v1(107.15,108.52) v2(102.01,105.13) v2(102.01,103.92) v2(102.01,102.73) v2(102.77,100.86) v2(102.8,96.69) v2(103.63,100.85) v2(103.68,96.72) v2(104.16,98.61) v2(104.51,100.85) v2(104.59,96.69) v2(104.71,107.89) v2(104.66,105.17) v2(104.66,103.98) v2(104.66,102.77) v2(104.72,98.59) v2(105.33,107.89) v2(105.31,100.83) v2(105.31,98.56) v2(105.92,107.88) v2(105.92,98.56) v2(106.5,107.88) v2(106.5,98.54) v2(107.08,107.86) v2(107.07,98.54)
+VCC_GTUS: length 11.2
  BOTTOM w0.127: UC1.AK56 100.49,98.4 ; UC1.AK56 100.49,97.7 ; UC1.AK56 100.49,97.99 100.86,97.99 ; UC1.AL60 99.12,97.86 ; UC1.AL60 99.12,97.2 ; UC1.AL60 98.8,97.53 ; UC1.AL60 99.48,97.53 ; 101.41,97.64 UC1.AK55 ; UC1.AK55 101.05,97.99 101.05,97.99 ; UC1.AK55 101.41,98.35 ; UC1.AK53 102.32,98.31 ; UC1.AK53 102.65,97.99 ; UC1.AK53 102.32,97.66 ; 99.58,97.66 UC1.AK58 ; UC1.AK58 99.58,98.32 ; UC1.AK58 99.26,97.99 ; 98.66,97.62 UC1.AK60 ; UC1.AK60 98.99,97.99 ; UC1.AK60 98.37,97.99 ; 102.43,97.53 UC1.AL53 102.78,97.86 ; UC1.AL56 100.53,97.53 ; UC1.AL56 100.95,97.8 ; UC1.AL56 101.31,97.53 ; UC1.AL56 100.95,97.2 ; UC1.AM58 99.26,97.05 ; UC1.AM58 99.58,97.36 ; UC1.AM58 99.91,97.05 ; UC1.AM56 100.49,97.38 ; UC1.AM56 100.14,97.05 ; UC1.AM56 100.87,97.05 ; 101.96,97.05 UC1.AM53 102.32,97.38
  vias: v2(99.02,98.5)
+VCC_SA: length 25.6
  TOP w0.254: RC168.1 116.4,121.37 116.15,121.12 116.15,120.11 116.44,119.81 116.44,119.08 115.97,118.62 115.97,112.23 116.93,111.27 116.93,110.42 116.68,110.17 PC1147.1
  TOP w0.381: v2(116.52,109.57) 116.31,109.78 PC1147.1
  BOTTOM w0.127: UC1.J27 116.5,108.52 ; UC1.J27 116.19,108.83 ; UC1.J27 116.8,108.83 ; UC1.K27 116.95,108.67 ; UC1.K27 116.95,108.2 116.84,108.09 ; UC1.K27 116.65,108.36 ; 118.17,108.36 UC1.K25 ; UC1.K25 117.87,108.67 ; UC1.K25 117.87,108.06 ; UC1.AK25 117.87,98.34 ; UC1.AK25 118.22,97.99 118.22,97.99 ; UC1.AK25 117.56,97.99 117.55,98 ; 118.93,108.83 UC1.J22 119.24,108.52 ; UC1.K28 116.04,108.67 ; UC1.K28 116.04,108.06 ; UC1.K28 116.34,108.36 ; 118.78,98.36 118.78,98.36 UC1.AK23 118.44,97.99 118.43,97.99 ; UC1.K23 118.78,108.67 ; UC1.K23 118.78,108.06 ; UC1.K23 119.09,108.36 ; UC1.K23 118.48,108.36 ; 118.32,108.52 UC1.J23 ; UC1.J23 118.02,108.83 ; UC1.J23 118.63,108.83 ; 115.12,108.67 UC1.K30 115.12,108.06
  BOTTOM w0.203: UC1.G27 UC1.G25
  BOTTOM w0.254: UC1.G27 116.67,109.57 v2(116.52,109.57) 116.32,109.57 UC1.G28 ; UC1.G23 118.53,109.54 v2(118.3,109.54) 118.12,109.54 UC1.G25
  vias: v2(74.13,117.36) v2(74.83,117.36) v2(75.46,117.35) v2(76.06,117.35) v2(76.71,117.28) v2(76.71,116.58) v2(76.71,115.95) v2(76.71,115.31) v2(76.71,114.68) v2(77.34,117.28) v2(77.34,116.58) v2(77.34,115.95) v2(77.34,115.31) v2(116.61,107.97) v2(116.86,105.33) v2(117.08,102.74) v2(117.53,99.01) v2(117.87,107.64) v2(118.06,103.96) v2(118.1,99.01) v3(75.41,115.86)
+VCC_SFR_OC: length 42
  TOP w0.508: 135.74,70.88 v3(134,70.88) 123.49,70.88 118.01,76.36 118.01,81.56 118.71,82.26 118.71,87.26 120.48,89.04 120.48,90.63 120.17,90.94 120.17,92.9 119.89,93.18 CC288.1 119.89,95.39 v2(119.2,96.07)
  BOTTOM w0.254: v2(119.24,98.22) UC1.AL23
+VDDA_AVDD1: length 1.3
  TOP w0.203: 254.93,56.21 255.53,56.81 UA1.26
  vias: v1(253.72,56.17)
GND: length 3365.3
  TOP w0.127: v2(67.02,123.3) 67.02,123.33 67.09,123.4 CV17.2 ; CR18.1 280.39,55.38 v3(279.54,54.53) ; CC322.2 137.87,72.36 v3(137.83,72.4) ; v2(21.99,59.42) 21.92,59.5 v3(21.41,59.5)
  TOP w0.203: UZ2.11 249.45,111.2 v2(249.39,111.26) ; UZ3.11 v2(157.57,60.34) ; UZ4.11 v2(278.17,90.94) ; UZ5.11 v2(246.4,63.83)
  TOP w0.254: DT6.2 11.41,108.98 v2(11.41,108.7) ; DT6.2 12.13,109.27 v2(12.46,108.94) ; DT6.2 11.93,109.05 v2(11.93,108.41) ; v2(30.05,80.05) 30.3,80.05 30.85,80.59 RT101.2 ; DT5.2 11.74,110.84 v2(12.26,111.37) ; DT5.2 11.43,110.84 v2(11.08,111.19) ; DT5.2 v2(11.71,111.62) ; v2(29.33,97.05) 29.33,96.91 29.69,96.56 CT32.2 ; DT10.2 11.37,102.35 v2(11.06,102.04) ; DT10.2 11.89,102.35 v2(12.27,101.97) ; DT10.2 v2(11.64,101.59) ; UE1.A13 v2(246.28,93.86) ; v2(247.88,85.86) UE1.C4 ; v2(251.1,112.96) 250.77,113.29 CZ111.2 ; CT31.2 32.57,97.45 v2(33.39,96.63) ; v2(12.22,104.49) 12.22,104.19 11.95,103.92 DT9.2 ; v2(46.62,98.77) 46.39,98.53 44.3,98.53 43.91,98.14 43.91,97.83 44.6,97.14 v2(44.6,96.75) ; CC27.2 118.78,78.99 118.55,79.22 118.55,81.35 119.19,81.99 119.19,82.98 119.59,83.39 v2(119.78,83.39) ; v2(105.52,96.66) 105.85,96.99 PC1334.2 ; DT39.3 13.22,106.57 v2(13.22,106.56) ; v2(258.01,86.46) CE21.2 ; CT63.2 25.5,95.84 v2(25.42,95.75) ; RPE10.7 259.18,100.71 v2(258.96,100.93) 258.68,100.65 RPE10.8 ; UE1.E6 v2(249.48,87.46) ; DT9.2 v2(11.64,104.6) ; DT9.2 11.4,103.92 v2(11.06,104.25) ; v2(30.05,81.8) 29.88,81.8 CT87.2 ; CC332.2 120.85,81.07 121.19,81.41 121.19,81.93 v2(120.97,82.15) ; v2(39.41,112.08) 39.41,111.78 38.89,111.26 RT126.2 ; v2(261.39,130.95) 260.94,130.95 260.6,130.61 260.6,129.81 260.53,129.73 CL16.2 ; PD1.1 PD2.1 165.02,62.75 v2(165.02,62.42) ; PC1049.2 101.44,97.79 v2(101.86,98.22) ; PC1014.2 98.56,105.45 97.73,106.28 PC1329.2 ; CT64.2 25.43,97.73 CT48.2 26.04,98.3 v2(26.08,98.35) ; RPE10.6 259.68,100.74 v2(259.89,100.95) 260.18,100.66 RPE10.5 ; UI3.14 277.63,75.52 v2(277.38,75.77) ; PC1085.2 112.22,110.37 v2(112.22,111.85) 112.98,112.62 112.98,114.24 113.99,115.25 113.99,116.27 114.48,116.75 115.26,116.75 115.62,116.39 115.62,115.84 v2(115.35,115.57) 115.35,113.61 114.47,112.73 v2(114.47,111.82) 113.99,111.34 113.99,109.93 v2(113.66,109.6) ; UE1.A6 246.46,87.63 ; PC1088.2 112.94,99.23 112.51,99.67 PC1097.2 112.26,100.19 PC1004.2 ; UE1.H4 v2(252.68,85.86) ; v2(101.65,128.44) 101.82,128.27 RC436.1
  TOP w0.305: DV7.2 58.42,119.01 v2(58.72,118.71) ; DV8.2 58.83,122.19 v2(58.94,122.19) ; JAPS1.8 261.06,108.9 v2(261,108.96) ; v2(260.07,88.56) 258.91,89.71 CE13.2 ; CT30.2 26.16,102.33 v2(26.09,102.25) ; CT39.2 28.13,99.74 v2(28.03,99.65) ; CT62.2 26.17,99.09 v2(26.08,99) ; CC199.2 115.43,109.39 v2(115.67,109.63) 115.67,109.81 115.7,109.84 115.7,110.15 PC1147.2 ; CT25.2 29.93,102.3 v2(29.98,102.25) ; CT26.2 28.65,100.91 v2(28.68,100.95) ; JAPS1.12 v2(259.06,108.96) ; v2(270.91,95.18) 271.18,95.45 UE4.3 ; v2(260.12,108.96) 260.06,108.9 JAPS1.10 ; CT29.2 31.52,100.91 CT40.2 30.5,100.92 CT41.2 30.5,102.11 v2(30.63,102.25) ; v2(257.93,109.33) 258.06,109.21 JAPS1.14 ; PC1052.2 110.29,109.35 v2(110.09,109.54) 109.91,109.54 109.66,109.3 PC1053.2
  TOP w0.356: v2(239.61,128.92) 239.86,129.17 CL10.2 ; PC1056.2 94.92,107.05 95.34,107.47 v2(95.34,107.65) ; PC1043.2 92.19,105.77 v2(92.14,105.83) ; PC1098.2 111.09,99.68 v2(111.11,99.66) ; PC1328.2 94.09,107.23 94.51,107.65 v2(94.75,107.65) ; PC1044.2 92.34,103.43 92.76,103.85 v2(92.76,103.97) ; CA10.2 v2(260.86,64.07) ; CN61.2 v2(30.31,44.33) ; CR26.2 274.98,58.99 274.98,59.61 CR3.2 ; CE22.2 263.9,85.75 v2(263.64,85.48) ; v2(123.33,99.08) 123.15,99.08 122.82,99.4 CC313.2 ; v2(94.06,105.8) 94.06,105.7 93.56,105.2 PC1047.2 ; v2(221.95,55.92) 222.05,56.02 CZ66.2 ; CE14.2 244.22,87.22 CE23.2 246.05,87.22 246.46,87.63 ; CZ93.2 v2(265.71,83.7) ; CT36.2 CT35.2 28.96,94.74 v2(29.32,95.11) ; v2(244.43,119.52) 244.56,119.65 CL7.2 ; CE20.2 250.62,78.24 v2(250.54,78.32) ; v2(277.6,67.73) 277.6,68.13 277.19,68.54 CR2.2 276.9,69.23 CR1.2 ; CA47.2 v2(262.15,64.2) ; CZ109.2 247.95,110.72 CZ122.2 ; CZ119.2 v2(279.49,94.24) ; PC1055.2 94.06,101.69 v2(94.06,102.14) 94.06,102.22 93.52,102.76 PC1048.2 ; PC1152.2 PC1153.2 119.53,102.91 v2(120.03,102.4) ; v2(125.63,97.3) 125.72,97.22 CC223.2 ; v2(112.84,96.66) 112.89,96.72 PC1089.2 PC1087.2 ; CR7.2 275.96,59.46 v2(276.43,58.99) ; CT88.2 19.35,68.18 CT89.2 ; v2(29.98,97.7) 30.02,97.74 CT28.2 ; PC1045.2 v2(91.46,103.09) ; CC29.2 CC28.2 85.19,133.84 84.2,132.85 v2(84.2,132.22) ; CR6.2 v2(273.56,60.01) ; CR19.1 282.61,61.48 v2(282.95,61.48) ; CT38.2 28.05,99.03 CT27.2 28.01,98.37 v2(28.03,98.35) 28.19,98.19 CT33.2 ; v2(95.99,107.65) 96.04,107.61 PC1046.2 ; CE19.2 250.62,97.08 v2(250.62,97.27) ; CE25.2 v2(255.04,95.29)
  TOP w0.381: v2(112.18,105.85) 112.18,105.54 PC1082.2 ; UZ10.3 v2(267.84,86.13) ; PC1051.2 113.28,108.86 113.71,108.43 v2(113.71,108.14) ; PC1068.2 109.79,103.19 v2(109.79,103.5) ; v2(108.58,101.15) 108.58,100.84 PC1002.2 ; v2(108.59,103.5) 108.59,103.19 PC1073.2 ; v2(112.18,103.46) 112.18,103.15 PC1076.2 ; v2(132.07,86.69) 132.07,85.89 132.4,85.57 CC214.2 ; PC1330.2 PC1332.2 105.22,95.12 104.84,94.74 v2(104.61,94.74) ; DI1.3 v2(21.14,63.32) ; PQ1209.1 30.33,123.57 30,123.9 30,124.53 29.66,124.87 PQ1209.4 28.28,124.87 PC1214.2 v2(27.15,125.12) ; v2(116.27,105.37) 116.27,105.78 PC1140.2 ; CA45.2 262.7,58.9 262.77,58.98 v2(262.98,58.98) ; 280.19,83.07 v2(281.39,83.07) ; PC937.1 v2(59.88,52.07) ; RE93.2 245.75,100.11 QE12.3 v2(246.55,101.72) ; CC320.2 132.28,104.79 131.66,105.4 130.64,105.4 v2(130.08,104.85) ; v2(100.95,109.54) 100.93,109.53 PC1042.2 ; v2(125.54,102.65) 125.54,102.87 126.08,103.41 CC323.2 ; v2(14.95,95.93) 14.95,95.88 14.38,95.31 RV21.2 ; v2(32.99,81.8) 33.42,81.8 33.74,82.12 RT71.2 ; UZ6.3 203.11,58.42 v2(203.62,57.91) ; CE12.2 244.35,75.94 244.95,76.55 244.95,77.57 245.69,78.31 245.76,78.31 RE58.2 246.09,79.34 v2(246.14,79.39) ; PC1067.2 108.59,105.54 v2(108.59,105.85) ; PC1081.2 109.78,100.84 v2(109.78,101.15) ; PC1084.2 112.08,109.45 v2(111.97,109.56) 111.97,109.56 PC1085.2 ; 22.55,102.04 22.6,102.09 RT26.2 ; v2(261.71,130.38) 261.73,130.35 CL17.2 ; JAPS1.20 v2(255.06,111.67) ; PR302.2 164.75,84.69 v2(164.75,84.23) ; v2(126.8,126.26) 126.41,125.87 CZ101.2 ; RC349.2 v2(137.95,81.16) ; v2(31.71,73.64) 32.22,74.15 RT81.2 ; v2(45.37,100.3) 44.92,100.74 PQ1214.1 ; RT82.2 31.14,74.04 v2(31.14,73.61) ; PC1050.2 113.9,109.36 v2(113.66,109.6) ; v2(106.44,96.66) 106.58,96.8 CC250.2 ; v2(107.39,105.84) 107.39,105.53 PC1078.2 ; UE6.3 v2(265.65,79.43) ; PC1333.2 PC1331.2 102.94,94.94 v2(102.78,94.78) ; v2(107.39,103.5) 107.39,103.19 PC1003.2 ; v2(109.79,105.85) 109.79,105.54 PC1007.2 ; v2(110.99,105.85) 110.99,105.54 PC1077.2 ; v2(29.88,73.99) 29.88,74.19 30.44,74.75 RT100.2 ; CC251.2 108.23,95.34 v2(108.27,95.37) ; CE29.2 243.61,85.09 242.82,85.88 v2(242.82,86.03) ; UE3.3 v2(267.36,97.6) ; v2(73.64,71.11) 77.85,75.32 CD32.2 ; PC1004.2 112.18,100.82 v2(112.18,101.13) ; CE57.2 247.1,76.16 247.13,76.18 247.13,76.34 v2(247.27,76.49) ; PQ1.4 54.18,113.78 v2(54.68,113.28) 54.68,112.65 54.85,112.48 PQ1.1 ; PR932.2 55.71,51.46 v2(55.7,51.45) ; RE20.2 257.82,80.78 CE3.2 ; v2(262.48,97.55) 262.72,97.55 262.84,97.66 UE5.3 ; v2(30.05,80.05) 29.83,80.05 29.48,79.69 RT377.2 ; PC644.2 47.06,99.46 46.34,99.46 PQ1214.4 46.32,99.06 v2(46.62,98.77) ; v2(111.13,98.34) 111.07,98.4 CC297.2 ; CL19.2 286.62,120.89 286.78,120.73 v2(286.79,120.73) ; PR310.2 166.35,83.48 166.82,83.01 166.82,81.59 v2(166.41,81.18) ; CC202.2 118.92,107.03 PC1148.2 118.39,106.82 117.75,106.18 PC1060.2 ; v2(251.62,81.67) 251.64,81.66 CE15.2 ; v2(72.68,82.08) 75.22,82.08 76.17,81.13 UD1.3 ; JAPS1.19 v2(265.56,111.54) ; CC314.2 123.94,104.14 v2(123.98,104.1) ; v2(90.94,107.49) 90.15,108.28 RC163.2 ; PR1262.2 45.41,108.67 v2(45.72,108.37) ; RC86.2 CC308.2 100.75,122.05 v2(101.05,122.35) ; PC218.2 v2(71.59,71.91) ; v2(98.26,109.59) 97.81,109.14 PC1041.2 ; CI19.2 v2(279.4,79.86) ; PC1066.2 110.99,103.17 v2(110.99,103.48) ; v2(110.99,101.14) 110.99,100.83 PC1001.2 ; RC89.2 125.49,83.56 125.91,83.98 CC270.2 125.91,84.59 v2(126.19,84.87) ; CE63.2 236.78,104.07 v2(235.76,103.06) ; PQ1201.1 46.1,106.29 44.8,107.59 PQ1201.4 44.3,107.83 PR1222.2 ; v2(107.38,101.15) 107.38,100.84 PC1080.2 ; CD29.2 102.7,53.65 v2(101.35,55) ; PR311.2 v2(156.81,80.41) ; CV40.2 v2(15.39,87.14) ; v2(66.52,130.59) 66.52,130.92 66.58,130.99 CV12.2 ; CC204.2 v2(133.45,96.78) ; PC1040.2 v2(99.12,109.54)
  TOP w0.457: RC5.2 120.56,83.39 v2(119.78,83.39) ; RE56.2 236.21,85.29 v2(236.97,85.29) ; v2(118.32,95.37) 118.6,95.37 CC288.2 ; CE47.2 v2(255.93,97.23) ; v2(120.03,102.4) 120.03,101.82 CC217.2 ; v2(280.2,75.04) 280.58,75.42 RI14.1 ; CC208.2 124.31,103.07 123.98,102.74 v2(123.98,102.43) ; v2(63.84,70.11) 63.84,69.34 PC207.2 ; v2(251.48,68.48) CA68.2 CA67.2 ; CC179.2 112.86,96.04 v2(112.84,96.01) ; v2(267.94,102.86) CE36.2 268.45,101.86 269.15,101.17 CE53.2 ; CD14.2 106.6,60.86 106.6,60.12 106.92,59.8 v2(107.19,59.8) ; CC306.2 CC32.2 91.05,130.17 92.43,131.55 v2(92.43,131.8) ; CE52.2 v2(263.29,100.02) ; v2(31.27,95.75) 31.33,95.69 RT38.2 ; v2(24.41,93.61) 23.91,94.11 RT42.2 23.77,93.11 CT60.2 ; PC1060.2 117.75,105.66 v2(118.13,105.28) ; v2(115.58,96.01) 116,96.01 CC177.2 ; CC203.2 123.31,107.15 v2(123.31,106.57) ; v2(97.2,108.98) 96.77,109.41 RC114.2 ; CC323.2 126.15,103.52 127.47,103.52 127.86,103.91 CC222.2 ; v2(133.06,100.13) 133.05,100.13 132.43,100.13 CC212.2 ; CC26.2 133.2,81.48 v2(133.58,81.48) 133.93,81.48 CC23.2 ; v2(50.49,101.1) 50.45,101.1 49.97,100.61 PC652.2 ; v2(118.32,96.01) 117.85,96.01 CC176.2 ; RT23.2 27.2,105.48 27.49,105.77 v2(27.91,105.77) 28.09,105.59 RT129.2 ; CC207.2 122.67,101.96 122.53,102.11 CC209.2 122.53,102.77 122.7,102.94 v2(122.7,103.24) ; RC324.2 108.02,109.15 107.61,109.57 v2(107.33,109.57) ; CC265.2 123.28,99.94 v2(123.28,100.73) ; CC211.2 122.27,104.59 121.99,104.31 v2(121.99,104.08) ; PC1013.2 84.22,104.48 84.8,105.06 v2(84.95,105.06) ; v2(261.03,91.46) 261.25,91.46 261.71,91.92 RE95.2 ; RC316.2 160.36,91.69 v2(159.47,91.69) ; RC167.2 117.72,98.26 v2(116.42,98.26) ; CC213.2 120.55,98.35 v2(120.71,98.19) ; v2(223.16,58.15) 222.73,58.57 RZ10.1 ; CC195.2 121.68,120.21 119.68,118.22 v2(119.68,115.68) ; CC206.2 120,103.48 v2(119.92,103.4) ; v2(130.89,97.45) 130.99,97.34 CC224.2 ; CC218.2 119.9,104.26 v2(119.9,104.18) ; PC1212.2 v2(38.12,56.91) ; UV24.2 65.85,125.64 65.2,126.29 64.51,126.29 v2(64.16,125.93) ; PC1207.2 42.18,56.01 v2(42.54,55.64) 42.04,55.13 PC1206.2 ; RL9.2 244.23,119.52 v2(244.43,119.52) ; PR1219.2 v2(42.54,54.24) ; CC205.2 121.39,99.71 v2(122.03,99.08) ; v2(108.27,94.74) 108.74,94.74 CC178.2 ; CD13.2 95.87,62.99 v2(95.98,63.1) ; PR1227.2 v2(26.31,122.44)
  TOP w0.508: v2(136.26,99.87) 136.26,100.68 CC326.2 ; v2(254.28,97.98) 254.01,97.98 CE40.2 ; CD1.2 109.13,61.16 109.45,60.84 109.45,60.03 109.22,59.8 v2(108.83,59.8) ; RT32.2 22.53,102.02 22.55,102.04 ; CD10.2 v2(113.31,52.59) ; v2(29.74,45.79) 30.14,45.4 CN60.2 ; QC6.3 145.17,76.53 v2(145.67,76.03) ; CZ102.2 138.19,64.42 v2(138.8,64.42) ; v2(102.87,82.41) 103.25,82.41 CC294.2 ; CA19.2 278.08,20.45 v2(277.71,20.08) ; v2(28.15,67.86) 28.51,67.86 29.23,68.58 CT70.2 ; v2(108.21,56.29) 108.2,56.29 108.2,55.1 CD6.2 ; CD11.2 111.28,58.75 111.81,58.21 v2(112.31,58.21) ; v2(22.97,69.87) 22.53,69.87 22.01,69.35 RT393.2 ; v2(248.5,59.7) 248.5,59.73 248.73,59.95 RA37.2 ; PC1057.2 116.65,99.27 v2(116.41,99.03) ; JSD1.23 v2(298.04,51.55) ; PR1217.2 PC1205.2 v2(38.75,52.67) ; PC1130.2 v2(90.32,101.48) ; v2(161.72,123.33) 159.71,125.35 PC420.2 PR428.2 ; RA39.2 v2(281.27,31.43) ; v2(90.84,128.79) 90.44,128.39 CC269.2 ; v2(276.81,58.48) 277.64,58.48 278.62,59.46 CR21.2 ; PC685.2 61.45,114.65 v2(61.11,114.31) ; v2(260.63,66.2) CA61.2 260.04,66.88 RA52.1 ; v2(130.93,107.64) 130.83,107.54 RC1.2 ; JSD1.14 v2(297.94,60.08) ; PC3.2 v2(287.3,14.04) ; CR22.2 279.81,62.94 v2(279.34,62.47) ; PC1137.2 v2(85.49,101.48) ; CZ110.2 v2(247.17,111.77) ; SW3.3 v2(295.67,123.38) ; CD8.2 113.56,60.78 112.92,60.14 v2(112.31,60.14) ; RZ40.1 v2(280.01,86.93) ; CD9.2 89.98,52.46 v2(89.97,52.46) ; RC141.2 111.75,120.65 v2(111.75,121.28) ; CE60.2 RE342.2 263.28,83.89 v2(263.65,83.89) ; CZ62.2 232.28,55.21 v2(231.69,55.79) ; CD24.2 CD23.2 144.83,53.92 v2(146.09,55.18) ; v2(158.26,102.45) 158.26,102.74 CC7.2 ; v2(249.88,101.27) 249.88,100.75 RE85.2 ; v2(120.19,63.37) 120.18,63.36 CD16.2 ; v2(136.99,133.36) 137.28,133.65 PC410.2 138.15,133.65 PR427.2 ; QV4.3 23.27,73.29 v2(23.65,73.67) ; CR5.2 v2(271.74,60.09) ; QV2.3 41.38,121.49 v2(41.38,122.24) ; v2(29.33,93.12) 29.45,93.23 30.18,93.23 RT34.2 ; v2(54.51,97.29) 54.52,97.28 PC654.1 PC651.1 ; CZ76.2 CZ77.2 162.4,104.49 163.06,103.83 165.32,103.83 v2(165.67,104.18) ; JSD1.17 298.3,57.01 v2(298.04,57.27) ; CZ78.1 236.02,57.82 v2(236.89,56.95) ; CE54.2 v2(249.01,79.35) 248.8,79.14 CE62.2 ; PC1072.2 85.66,104.57 v2(85.66,105.01) ; CMOS1.2 128.68,82.49 CC25.2 ; PQ3.3 34.81,127.66 v2(35.28,128.13) 36.45,128.13 PR8.1 ; v2(255.42,66.85) 255.23,67.04 CA56.2 ; CD2.2 104.48,61.16 104.16,60.84 104.16,60.15 104.51,59.8 v2(104.79,59.8) ; PC12.2 41.59,57.63 v2(41.78,57.82) ; QE17.3 v2(233.78,94.32) ; v2(110.97,82.81) 109.95,82.81 CC296.2 ; CA78.2 248.77,53.99 v2(249.21,53.54) 249.64,53.97 CA64.2 ; CT59.2 20.97,92.22 19.79,92.22 19.45,92.56 v2(19.45,93.03) ; v2(64.32,73.19) 63.96,72.83 PR206.2 ; QR1.3 282.1,58.88 283.52,58.88 v2(283.73,59.09) ; PC1131.2 v2(89.11,101.48) ; v2(277.71,18.04) 278.08,18.41 CA24.2 ; RT128.2 33.35,99.94 v2(33.53,100.12) 33.81,100.4 RT35.2 RT29.2 ; v2(87.91,98.69) 87.92,98.68 PC1134.2 ; CC202.2 119.19,106.85 CC341.2 ; CE38.2 RE77.2 243.31,94.5 v2(242.94,94.12) ; PC678.2 v2(62.42,95.12) ; CT89.2 v2(18.69,68.15) ; v2(147.67,104.42) 148.49,104.42 148.99,103.91 CC215.2 ; JSD1.6 285.19,54.87 284.9,54.58 v2(284.67,54.58) ; CD4.2 v2(114.9,52.14) ; v2(166.78,57.3) 167.16,57.68 PC1.2 ; CD5.2 116.36,60.59 v2(116.39,60.56) ; CC8.2 158.33,93.43 v2(158.74,93.02) ; RD9.2 124.47,52.72 v2(124.71,52.48) ; DV4.1 53.17,127.14 52.84,127.47 CA6.2 52.75,128.62 v2(52.75,130.12) ; PC1136.2 v2(86.7,98.69) ; PC1129.2 v2(90.32,98.69) ; CV23.2 55.73,127.39 CZ200.2 ; CC264.2 124.86,110.05 v2(124.71,110.21) ; v2(27.71,109.92) 27.33,109.92 27.08,109.67 RT25.2 RT27.2 ; CC324.2 136.85,96.32 135.38,96.32 v2(135.28,96.41) ; v2(68.48,110.83) 68.65,110.67 PC696.1 ; v2(61.69,85.06) 60.89,85.06 60.58,85.38 PC670.2 ; PC133.2 183.74,51.62 184.53,50.83 v2(184.53,50.1) ; RV3.1 RV2.2 71.32,121.93 71.64,121.61 v2(71.82,121.61) ; DT4.1 v2(18.11,112.95) ; v2(39.2,129.3) 39.2,127.75 PD4.1 ; PR407.2 PC411.2 v2(164.63,124.94) ; CZ63.2 232.21,52.51 v2(231.67,53.05) ; PR960.1 49.72,59.26 49.33,58.86 v2(49.33,58.43) ; CC325.2 v2(126.82,120.15) ; CD7.2 v2(100.47,52.46) ; v2(91.02,96.79) 90.85,96.96 PC1029.2 ; v2(51.34,126.34) 51.54,126.53 CV635.2 ; v2(35.09,58.24) 35.14,58.2 PC1213.2 ; CZ104.2 139.14,68.6 ; PR945.2 50.49,61.14 50.19,61.44 v2(49.95,61.44) ; RC44.2 130.25,103.49 RC96.2 130.22,102.97 v2(129.96,102.71) ; v2(89.11,98.69) PC1132.2 ; CE14.2 243.16,86.87 242.46,87.56 v2(242.46,88.18) ; CL13.2 246.26,119.19 245.81,119.19 v2(245.71,119.3) 245.58,119.43 RL3.2 ; v2(260.31,54.81) 260.31,54.11 ; v2(124.99,119.29) 124.41,119.87 RC3.2 ; CD12.2 v2(106.4,52.45) ; PR953.2 42.94,55.24 v2(42.54,55.64) ; CC295.2 v2(108.35,83.01) ; CR25.2 CR4.2 v2(275.06,56.42) ; v2(240.01,99.14) 240.33,99.46 RE541.1 ; v2(56.73,115.59) 56.46,115.86 PC9.2 ; PC1133.2 v2(87.91,101.48) ; v2(138.31,52.47) 138.63,52.78 CD22.2 139.41,52.78 v2(139.72,52.46) ; QV7.3 49.25,120.51 v2(48.85,120.91) ; CA23.2 v2(281.27,25.79) ; v2(165.29,56.12) 165.59,55.81 PC137.2 ; v2(254.79,79.26) 254.86,79.34 CE31.2 ; RD16.2 CD25.2 CD26.2 119.85,54.35 v2(119.85,56.46) ; CA46.2 v2(265.83,59.38) ; v2(292.07,44.38) v2(291.55,44.91) 291.2,45.26 v2(291.2,47.95) ; CE61.2 271.69,89.06 271.7,89.08 271.7,89.32 v2(271.21,89.81) ; v2(27.33,111.64) 28.29,111.64 28.39,111.74 RT24.2 RT30.2 ; PC1064.2 v2(89.05,105.04) ; PC1027.2 v2(84.29,101.48) ; RT125.2 RT124.2 32.11,109.49 31.86,109.74 v2(31.86,109.77) ; v2(141.82,132.8) 141.2,133.41 PR415.2 ; YL1.4 249.72,117.15 249.76,117.15 249.96,117.36 v2(250.15,117.36) ; PC1217.2 v2(248.94,98.94) ; v2(34.2,53.74) PR1210.2 PR1249.2 ; v2(250.47,51.45) 250.47,51.51 250.46,51.52 RA36.2 RA35.2 ; v2(118.53,122.3) 118.24,122.3 117.75,121.82 RC166.2 ; v2(120.68,99.02) 120.41,99.3 PC1058.2 ; v2(246.14,79.39) 246.09,79.44 RE55.2 ; v2(285.52,121.78) CL18.2 ; CC331.2 122.31,79.46 CC333.2 122.15,80.48 v2(122.15,81.07) ; JSD1.20 298.18,54.28 v2(297.9,54.56) ; CE59.2 253.5,73.79 CE16.2 v2(253.58,74.55) ; CI34.2 v2(276.44,81.04) ; v2(264.95,66.67) 264.35,66.67 CA31.2 ; v2(280.36,66.97) 280.34,66.94 CR15.2 ; CI33.2 v2(277.65,81.04) ; PC140.2 v2(161.9,49.5) ; CE3.2 257.02,81.27 v2(256.89,81.39) ; PC1075.2 v2(86.64,105.04) ; PC621.1 45.26,88.33 45.29,88.37 v2(45.29,89.11) ; v2(211.1,55.74) 211.34,55.98 CZ81.2 ; PC139.2 v2(162.93,49.44) ; v2(247.01,99.15) 247.65,99.79 JTAG1.2 248.01,99.79 248.15,99.93 CE30.2 RE65.2 ; PC1208.2 23.93,113.04 v2(24.58,113.04) 25.17,113.04 PC1216.2 ; CR26.2 275.49,58.91 v2(275.79,58.61) ; v2(138.11,78.92) 138.83,78.92 CC279.2 CC280.2 ; CE8.2 v2(260.82,96.09) ; PC1012.2 v2(75.02,112.91) ; PC1008.2 v2(73.81,112.91) ; v2(49.74,63.47) 50.21,63.94 51.09,63.94 51.45,63.58 PC955.2 ; v2(39.83,129.28) 40.59,128.52 42.33,128.52 CV15.2 43.08,125.61 CV14.2 ; RD18.2 v2(116.1,51.7) ; CL14.2 249.32,119.35 v2(250.22,119.35) 250.26,119.39 250.26,120.15 RL13.2 ; YL1.2 v2(245.58,118.13) ; CE64.2 237.51,98.31 v2(236.62,97.42) 235.59,98.45 CE65.2 ; RC90.2 91.48,109.36 v2(91.1,108.98) 91.62,108.47 RC91.2 ; PC2.1 v2(281.84,8.96) ; RV1.2 v2(69.79,126.19) ; v2(282.64,48.64) 281.75,47.75 RA38.2 ; PC1065.2 v2(90.28,105) ; PC138.2 v2(163.89,49.48) ; PC647.1 v2(55.17,95.2) ; CZ198.2 v2(241.27,111.07) ; v2(43.6,109.64) PR1222.2 ; CI31.2 v2(278.73,81.04) ; v2(127.68,63.79) 127.86,63.97 CD15.2 ; PC401.2 v2(137.44,131.77) ; CD3.2 v2(111.53,52.21) ; RE20.2 258.01,79.58 CE4.2 RE313.2 257.94,78.04 v2(258.04,77.94) 258.22,77.76 RE550.2 258.31,77.13 CE66.2 ; PC652.2 PC649.2 ; CZ109.2 v2(247.17,110.88) ; CZ197.2 v2(204.87,52.87) ; PC1135.2 v2(86.7,101.48) ; PC1138.2 v2(85.49,98.69) ; RT127.2 v2(35.76,107.63) ; RR4.2 v2(269.39,61.76) ; CA22.2 v2(281.46,23.76) ; PC1011.2 v2(87.84,105.04) ; SW3.1 v2(295.67,125.35) ; PC1028.2 v2(84.29,98.69) ; PR419.2 v2(162.4,128.43)
  GND1 w0.203: 232.83,132.93 H9.1 ; H9.1 232.83,135.47 ; H9.1 235.83,134.2 ; H9.1 235.37,132.93 ; H9.1 232.37,134.2 ; H9.1 234.1,135.93 ; H9.1 235.37,135.47 ; H9.1 234.1,132.47 ; 1.62,76.85 JHDMI1.23 ; JHDMI1.23 4.98,75.82 ; JHDMI1.23 3.3,75.82 ; JHDMI1.23 1.62,75.82 ; JHDMI1.23 4.98,76.85 ; 16.13,68.02 JUSB2.10 ; JUSB2.10 16.13,69.68 ; JUSB2.10 17.47,68.85 ; JUSB2.10 14.8,68.85 ; JUSB2.10 17.47,68.02 ; JUSB2.10 17.47,69.68 ; JUSB2.10 14.8,69.68 ; JUSB2.10 14.8,68.02 ; 142,111.42 H2.1 ; H2.1 143.56,115.11 ; H2.1 144.13,113.55 ; H2.1 142,115.68 ; H2.1 140.44,115.11 ; H2.1 139.87,113.55 ; H2.1 140.44,111.99 ; H2.1 143.56,111.99 ; JUSBC1.4 3.27,100.63 ; JUSBC1.4 0.83,101.35 ; JUSBC1.4 3.27,102.07 ; JUSBC1.4 0.83,102.07 ; JUSBC1.4 3.27,101.35 ; JUSBC1.4 0.83,100.63 ; JUSBC1.4 2.05,100.63 ; JUSBC1.4 2.05,102.07 ; H3.1 142,93.53 ; H3.1 140.44,89.84 ; H3.1 142,89.27 ; H3.1 140.44,92.96 ; H3.1 144.13,91.4 ; H3.1 143.56,92.96 ; H3.1 143.56,89.84 ; H3.1 139.87,91.4 ; JUSB2.4 16.66,58.95 ; JUSB2.4 15.83,58.12 ; JUSB2.4 15.83,59.78 ; JUSB2.4 16.47,59.58 ; JUSB2.4 16.47,58.31 ; JUSB2.4 15.2,59.58 ; JUSB2.7 15.16,62.45 ; JUSB2.7 13.7,63.08 ; JUSB2.7 14.33,63.28 ; JUSB2.7 14.97,61.81 ; JUSB2.7 13.7,61.81 ; JUSB2.7 14.33,61.62 ; JUSB2.7 14.97,63.08 ; 285.37,49.25 JSD1.10 ; JSD1.10 287.63,49.25 ; JSD1.10 285.37,49.97 ; JSD1.10 286.5,49.25 ; JSD1.10 287.63,49.97 ; JSD1.10 287.63,50.7 ; JSD1.10 285.37,50.7 ; JSD1.10 286.5,50.7 ; 5.55,113.87 H14.1 ; H14.1 4.28,114.33 ; H14.1 7.28,115.6 ; H14.1 3.82,115.6 ; H14.1 5.55,117.33 ; H14.1 6.82,116.87 ; H14.1 6.82,114.33 ; H14.1 4.28,116.87 ; JHDMI1.21 4.98,94.35 ; JHDMI1.21 1.62,95.38 ; JHDMI1.21 4.98,95.38 ; JHDMI1.21 3.3,95.38 ; JHDMI1.21 1.62,94.35 ; JUSB1.10 284.06,73.33 ; JUSB1.10 285.4,72.5 ; JUSB1.10 282.73,72.5 ; JUSB1.10 282.73,71.67 ; JUSB1.10 284.06,71.67 ; JUSB1.10 285.4,71.67 ; JUSB1.10 285.4,73.33 ; JUSB1.10 282.73,73.33 ; JHDMI1.17 12.03,89.1 ; JHDMI1.17 10.99,89.56 ; JHDMI1.17 10.99,88.64 ; JHDMI1.17 11.91,89.56 ; JHDMI1.17 11.91,88.64 ; JHDMI1.17 10.87,89.1 ; 283.73,83.03 JUSB1.4 ; JUSB1.4 284.36,81.57 ; JUSB1.4 285,81.76 ; JUSB1.4 284.36,83.23 ; JUSB1.4 283.73,81.76 ; JUSB1.4 283.54,82.4 ; 296.1,24.32 H20.1 ; H20.1 296.1,28.28 ; H20.1 298.08,26.3 ; H20.1 294.12,26.3 ; H20.1 294.65,24.85 ; H20.1 297.55,24.85 ; H20.1 294.65,27.75 ; H20.1 297.55,27.75 ; 6.27,101.63 JUSBC1.2 ; JUSBC1.2 5.12,101.63 ; JUSBC1.2 7.43,101.63 ; JUSBC1.2 6.27,103.07 ; JUSBC1.2 7.43,102.35 ; 295.32,90.55 JLOM1.15 ; JLOM1.15 297,89.72 ; JLOM1.15 295.32,89.72 ; JLOM1.15 298.68,89.72 ; JLOM1.15 298.68,90.55 ; H1.1 83.76,111.99 ; H1.1 80.64,111.99 ; H1.1 84.33,113.55 ; H1.1 80.64,115.11 ; H1.1 80.07,113.55 ; H1.1 82.2,115.68 ; H1.1 82.2,111.42 ; H1.1 83.76,115.11 ; 148.65,132.85 H37.1 ; H37.1 148.12,134.3 ; H37.1 148.65,135.75 ; H37.1 152.08,134.3 ; H37.1 150.1,136.28 ; H37.1 151.55,135.75 ; H37.1 150.1,132.32 ; H37.1 151.55,132.85 ; 298.17,64.3 JSD1.12 ; JSD1.12 299.3,64.3 ; JSD1.12 299.3,62.85 ; JSD1.12 298.17,63.57 ; 5.55,96.97 H15.1 ; H15.1 5.55,100.43 ; H15.1 4.28,99.97 ; H15.1 4.28,97.43 ; H15.1 7.28,98.7 ; H15.1 6.82,99.97 ; H15.1 3.82,98.7 ; H15.1 6.82,97.43 ; H38.1 165.37,132.93 ; H38.1 162.83,132.93 ; H38.1 165.37,135.47 ; H38.1 165.83,134.2 ; H38.1 162.37,134.2 ; H38.1 164.1,135.93 ; H38.1 164.1,132.47 ; H38.1 162.83,135.47 ; JHDMI1.22 12.93,78.35 ; JHDMI1.22 10.37,79.23 ; JHDMI1.22 12.93,79.23 ; JHDMI1.22 11.65,79.23 ; JHDMI1.22 11.65,77.47 ; JHDMI1.22 10.37,77.47 ; JHDMI1.22 12.93,77.47 ; H33.1 287.67,66.93 ; H33.1 285.13,69.47 ; H33.1 288.13,68.2 ; H33.1 287.67,69.47 ; H33.1 284.67,68.2 ; H33.1 286.4,69.93 ; H33.1 285.13,66.93 ; H33.1 286.4,66.47 ; JSD1.11 286.5,64.3 ; JSD1.11 285.37,64.3 ; JSD1.11 287.63,62.85 ; JSD1.11 287.63,63.57 ; JSD1.11 287.63,64.3 ; JSD1.11 286.5,62.85 ; JSD1.11 285.37,62.85 ; JSD1.11 285.37,63.57 ; H10.1 151.8,49.4 ; H10.1 147.76,51.1 ; H10.1 148.4,52.8 ; H10.1 151.8,52.8 ; H10.1 148.4,49.4 ; H10.1 150.1,53.44 ; H10.1 152.44,51.1 ; H29.1 290.32,131.63 ; H29.1 290.32,134.17 ; H29.1 287.78,134.17 ; H29.1 290.78,132.9 ; H29.1 287.78,131.63 ; H29.1 289.05,134.63 ; H29.1 289.05,131.17 ; H29.1 287.32,132.9 ; 42.11,134.04 H25.1 ; H25.1 45.09,131.06 ; H25.1 41.57,132.55 ; H25.1 45.09,134.04 ; H25.1 45.63,132.55 ; H25.1 43.6,134.58 ; H25.1 42.11,131.06 ; H25.1 43.6,130.52 ; JUSB1.11 294.5,70.37 ; JUSB1.11 293.31,70.37 ; JUSB1.11 292.13,70.37 ; JUSB1.11 292.13,71.2 ; JUSB1.11 294.5,71.2 ; 10.99,83.56 JHDMI1.5 ; JHDMI1.5 12.03,83.1 ; JHDMI1.5 11.91,82.64 ; JHDMI1.5 11.91,83.56 ; JHDMI1.5 10.99,82.64 ; JHDMI1.5 10.87,83.1 ; 16.13,55.22 JUSB2.12 ; JUSB2.12 16.13,56.88 ; JUSB2.12 14.8,56.88 ; JUSB2.12 14.8,56.05 ; JUSB2.12 17.47,55.22 ; JUSB2.12 14.8,55.22 ; JUSB2.12 17.47,56.88 ; JUSB2.12 17.47,56.05 ; 274.41,101.01 H7.1 ; H7.1 275.9,100.47 ; H7.1 274.41,103.99 ; H7.1 273.87,102.5 ; H7.1 277.39,103.99 ; H7.1 277.39,101.01 ; H7.1 277.93,102.5 ; H7.1 275.9,104.53 ; JUSBC1.1 7.43,111.95 ; JUSBC1.1 5.12,112.67 ; JUSBC1.1 6.27,112.67 ; JUSBC1.1 7.43,112.67 ; JUSBC1.1 6.27,111.23 ; 76.51,131.06 H26.1 ; H26.1 76.51,134.04 ; H26.1 79.49,131.06 ; H26.1 75.97,132.55 ; H26.1 79.49,134.04 ; H26.1 78,134.58 ; H26.1 78,130.52 ; H26.1 80.03,132.55 ; 0.83,112.95 JUSBC1.3 ; JUSBC1.3 0.83,112.23 ; JUSBC1.3 2.05,112.23 ; JUSBC1.3 0.83,113.67 ; JUSBC1.3 3.27,112.95 ; JUSBC1.3 3.27,113.67 ; JUSBC1.3 3.27,112.23 ; JUSBC1.3 2.05,113.67 ; 8.6,72.62 H23.1 ; H23.1 7.33,75.62 ; H23.1 9.87,73.08 ; H23.1 8.6,76.08 ; H23.1 6.87,74.35 ; H23.1 7.33,73.08 ; H23.1 10.33,74.35 ; H23.1 9.87,75.62 ; JUSB1.7 286.5,79.54 ; JUSB1.7 285.87,79.73 ; JUSB1.7 285.04,78.9 ; JUSB1.7 285.87,78.07 ; JUSB1.7 285.23,78.27 ; JUSB1.7 285.23,79.54 ; JUSB1.7 286.5,78.27 ; H16.1 281.63,13.95 ; H16.1 279.9,12.22 ; H16.1 281.17,12.68 ; H16.1 278.17,13.95 ; H16.1 281.17,15.22 ; H16.1 278.63,15.22 ; H16.1 278.63,12.68 ; H16.1 279.9,15.68 ; JUSB1.12 285.4,85.3 ; JUSB1.12 282.73,84.47 ; JUSB1.12 285.4,86.13 ; JUSB1.12 284.06,84.47 ; JUSB1.12 284.06,86.13 ; JUSB1.12 285.4,84.47 ; JUSB1.12 282.73,85.3 ; JUSB1.12 282.73,86.13 ; JHDMI1.11 11.91,85.64 ; JHDMI1.11 10.99,85.64 ; JHDMI1.11 10.99,86.56 ; JHDMI1.11 10.87,86.1 ; JHDMI1.11 11.91,86.56 ; JHDMI1.11 12.03,86.1 ; JLOM1.16 291.15,117.78 ; JLOM1.16 292.83,117.78 ; JLOM1.16 292.83,116.95 ; 5.7,70.15 JUSB2.11 ; JUSB2.11 5.7,70.98 ; JUSB2.11 6.88,70.98 ; JUSB2.11 8.07,70.98 ; JUSB2.11 8.07,70.15 ; 12.42,81.6 JHDMI1.2 ; JHDMI1.2 13.46,81.14 ; JHDMI1.2 12.54,81.14 ; JHDMI1.2 13,81.02 ; JHDMI1.2 13.46,82.06 ; JHDMI1.2 13.58,81.6 ; JHDMI1.2 12.54,82.06 ; H4.1 82.2,93.53 ; H4.1 80.64,92.96 ; H4.1 82.2,89.27 ; H4.1 83.76,89.84 ; H4.1 80.07,91.4 ; H4.1 83.76,92.96 ; H4.1 80.64,89.84 ; H4.1 84.33,91.4 ; 12.54,84.14 JHDMI1.8 ; JHDMI1.8 13.46,84.14 ; JHDMI1.8 13.46,85.06 ; JHDMI1.8 13.58,84.6 ; JHDMI1.8 12.42,84.6 ; JHDMI1.8 12.54,85.06 ; JSD1.13 297.23,50.7 ; JSD1.13 296.1,50.7 ; JSD1.13 294.97,49.25 ; JSD1.13 297.23,49.25 ; JSD1.13 297.23,49.97 ; JSD1.13 294.97,49.97 ; JSD1.13 294.97,50.7 ; JSD1.13 296.1,49.25 ; 65.5,52.75 H28.1 ; H28.1 69.28,51.15 ; H28.1 68.7,52.75 ; H28.1 67.1,53.33 ; H28.1 68.7,49.55 ; H28.1 67.1,48.97 ; H28.1 64.92,51.15 ; H28.1 65.5,49.55 ; JHDMI1.20 11.65,93.73 ; JHDMI1.20 10.37,91.97 ; JHDMI1.20 12.93,92.85 ; JHDMI1.20 10.37,93.73 ; JHDMI1.20 12.93,93.73 ; JHDMI1.20 12.93,91.97 ; JHDMI1.20 11.65,91.97 ; 289.47,89.72 JLOM1.14 ; JLOM1.14 292.83,90.55 ; JLOM1.14 292.83,89.72 ; JLOM1.14 291.15,89.72 ; JLOM1.14 289.47,90.55 ; H24.1 5.87,48.23 ; H24.1 3.33,50.77 ; H24.1 2.87,49.5 ; H24.1 5.87,50.77 ; H24.1 4.6,47.77 ; H24.1 3.33,48.23 ; H24.1 6.33,49.5 ; H24.1 4.6,51.23 ; JUSB1.13 293.31,87.43 ; JUSB1.13 292.13,86.6 ; JUSB1.13 292.13,87.43 ; JUSB1.13 294.5,86.6 ; JUSB1.13 294.5,87.43 ; H8.1 266.9,73.43 ; H8.1 265.41,69.91 ; H8.1 268.93,71.4 ; H8.1 268.39,72.89 ; H8.1 264.87,71.4 ; H8.1 265.41,72.89 ; H8.1 266.9,69.37 ; H8.1 268.39,69.91 ; 295.32,116.95 JLOM1.17 ; JLOM1.17 297,117.78 ; JLOM1.17 298.68,117.78 ; JLOM1.17 298.68,116.95 ; JLOM1.17 295.32,117.78
  IN1 w0.203: JUSBC1.4 2.05,102.07 ; JUSBC1.4 3.27,102.07 ; JUSBC1.4 3.27,100.63 ; JUSBC1.4 0.83,101.35 ; JUSBC1.4 0.83,102.07 ; JUSBC1.4 0.83,100.63 ; JUSBC1.4 2.05,100.63 ; JUSBC1.4 3.27,101.35 ; 6.6,104.83 JUSBC1.B1 6.99,104.74 ; JUSBC1.2 7.43,102.35 ; JUSBC1.2 6.27,101.63 ; JUSBC1.2 5.12,101.63 ; JUSBC1.2 7.43,101.63 ; 6.6,109.47 JUSBC1.B12 ; JUSBC1.B12 7.08,109.95 ; JUSBC1.B12 6.99,109.56
  GND2 w0.203: 4.28,116.87 H14.1 ; H14.1 3.82,115.6 ; H14.1 5.55,117.33 ; H14.1 6.82,116.87 ; H14.1 6.82,114.33 ; H14.1 5.55,113.87 ; H14.1 4.28,114.33 ; H14.1 7.28,115.6 ; 13.7,61.81 JUSB2.7 ; JUSB2.7 14.33,63.28 ; JUSB2.7 14.97,63.08 ; JUSB2.7 13.7,63.08 ; JUSB2.7 15.16,62.45 ; JUSB2.7 14.33,61.62 ; JUSB2.7 14.97,61.81 ; H2.1 144.13,113.55 ; H2.1 142,115.68 ; H2.1 143.56,115.11 ; H2.1 140.44,111.99 ; H2.1 143.56,111.99 ; H2.1 140.44,115.11 ; H2.1 142,111.42 ; H2.1 139.87,113.55 ; H33.1 288.13,68.2 ; H33.1 286.4,66.47 ; H33.1 287.67,66.93 ; H33.1 287.67,69.47 ; H33.1 285.13,66.93 ; H33.1 284.67,68.2 ; H33.1 286.4,69.93 ; H33.1 285.13,69.47 ; H9.1 235.37,132.93 ; H9.1 232.37,134.2 ; H9.1 235.37,135.47 ; H9.1 232.83,132.93 ; H9.1 234.1,132.47 ; H9.1 234.1,135.93 ; H9.1 235.83,134.2 ; H9.1 232.83,135.47 ; 148.65,135.75 H37.1 ; H37.1 150.1,132.32 ; H37.1 148.12,134.3 ; H37.1 150.1,136.28 ; H37.1 151.55,132.85 ; H37.1 151.55,135.75 ; H37.1 148.65,132.85 ; H37.1 152.08,134.3 ; JSD1.11 286.5,64.3 ; JSD1.11 285.37,62.85 ; JSD1.11 287.63,62.85 ; JSD1.11 285.37,63.57 ; JSD1.11 285.37,64.3 ; JSD1.11 287.63,64.3 ; JSD1.11 287.63,63.57 ; JSD1.11 286.5,62.85 ; 278.17,13.95 H16.1 ; H16.1 279.9,12.22 ; H16.1 278.63,15.22 ; H16.1 278.63,12.68 ; H16.1 281.17,15.22 ; H16.1 279.9,15.68 ; H16.1 281.63,13.95 ; H16.1 281.17,12.68 ; JUSB1.7 286.5,79.54 ; JUSB1.7 285.87,79.73 ; JUSB1.7 285.87,78.07 ; JUSB1.7 285.23,79.54 ; JUSB1.7 285.04,78.9 ; JUSB1.7 285.23,78.27 ; JUSB1.7 286.5,78.27 ; 287.78,131.63 H29.1 ; H29.1 287.78,134.17 ; H29.1 290.32,131.63 ; H29.1 287.32,132.9 ; H29.1 290.78,132.9 ; H29.1 289.05,131.17 ; H29.1 290.32,134.17 ; H29.1 289.05,134.63 ; 4.28,99.97 H15.1 ; H15.1 3.82,98.7 ; H15.1 4.28,97.43 ; H15.1 6.82,97.43 ; H15.1 7.28,98.7 ; H15.1 6.82,99.97 ; H15.1 5.55,96.97 ; H15.1 5.55,100.43 ; 6.27,101.63 JUSBC1.2 ; JUSBC1.2 5.12,101.63 ; JUSBC1.2 6.27,103.07 ; JUSBC1.2 7.43,101.63 ; JUSBC1.2 7.43,102.35 ; JUSB2.11 6.88,70.98 ; JUSB2.11 5.7,70.15 ; JUSB2.11 8.07,70.15 ; JUSB2.11 5.7,70.98 ; JUSB2.11 8.07,70.98 ; 3.33,50.77 H24.1 ; H24.1 4.6,47.77 ; H24.1 4.6,51.23 ; H24.1 2.87,49.5 ; H24.1 5.87,48.23 ; H24.1 6.33,49.5 ; H24.1 3.33,48.23 ; H24.1 5.87,50.77 ; 10.99,88.64 JHDMI1.17 ; JHDMI1.17 12.03,89.1 ; JHDMI1.17 10.99,89.56 ; JHDMI1.17 11.91,88.64 ; JHDMI1.17 11.91,89.56 ; JHDMI1.17 10.87,89.1 ; JUSB1.13 294.5,87.43 ; JUSB1.13 292.13,87.43 ; JUSB1.13 292.13,86.6 ; JUSB1.13 293.31,87.43 ; JUSB1.13 294.5,86.6 ; 3.3,75.82 JHDMI1.23 ; JHDMI1.23 4.98,75.82 ; JHDMI1.23 1.62,76.85 ; JHDMI1.23 1.62,75.82 ; JHDMI1.23 4.98,76.85 ; 10.99,82.64 JHDMI1.5 ; JHDMI1.5 10.87,83.1 ; JHDMI1.5 12.03,83.1 ; JHDMI1.5 11.91,82.64 ; JHDMI1.5 10.99,83.56 ; JHDMI1.5 11.91,83.56 ; 148.4,49.4 H10.1 ; H10.1 150.1,53.44 ; H10.1 151.8,52.8 ; H10.1 147.76,51.1 ; H10.1 152.44,51.1 ; H10.1 151.8,49.4 ; H10.1 148.4,52.8 ; JSD1.10 287.63,50.7 ; JSD1.10 286.5,50.7 ; JSD1.10 285.37,49.97 ; JSD1.10 285.37,50.7 ; JSD1.10 285.37,49.25 ; JSD1.10 287.63,49.97 ; JSD1.10 287.63,49.25 ; JSD1.10 286.5,49.25 ; 5.12,112.67 JUSBC1.1 ; JUSBC1.1 7.43,111.95 ; JUSBC1.1 6.27,111.23 ; JUSBC1.1 7.43,112.67 ; JUSBC1.1 6.27,112.67 ; H26.1 79.49,134.04 ; H26.1 78,130.52 ; H26.1 76.51,134.04 ; H26.1 78,134.58 ; H26.1 76.51,131.06 ; H26.1 80.03,132.55 ; H26.1 79.49,131.06 ; H26.1 75.97,132.55 ; 283.54,82.4 JUSB1.4 ; JUSB1.4 283.73,83.03 ; JUSB1.4 283.73,81.76 ; JUSB1.4 285,81.76 ; JUSB1.4 284.36,81.57 ; JUSB1.4 284.36,83.23 ; JLOM1.16 292.83,117.78 ; JLOM1.16 292.83,116.95 ; JLOM1.16 291.15,117.78 ; JUSBC1.3 3.27,112.23 ; JUSBC1.3 0.83,112.95 ; JUSBC1.3 3.27,113.67 ; JUSBC1.3 0.83,113.67 ; JUSBC1.3 3.27,112.95 ; JUSBC1.3 2.05,113.67 ; JUSBC1.3 0.83,112.23 ; JUSBC1.3 2.05,112.23 ; 162.83,135.47 H38.1 ; H38.1 164.1,135.93 ; H38.1 165.37,132.93 ; H38.1 165.37,135.47 ; H38.1 162.37,134.2 ; H38.1 165.83,134.2 ; H38.1 164.1,132.47 ; H38.1 162.83,132.93 ; 15.83,58.12 JUSB2.4 ; JUSB2.4 15.83,59.78 ; JUSB2.4 16.66,58.95 ; JUSB2.4 15.2,59.58 ; JUSB2.4 16.47,59.58 ; JUSB2.4 16.47,58.31 ; 14.8,56.88 JUSB2.12 ; JUSB2.12 16.13,56.88 ; JUSB2.12 17.47,55.22 ; JUSB2.12 17.47,56.88 ; JUSB2.12 16.13,55.22 ; JUSB2.12 17.47,56.05 ; JUSB2.12 14.8,55.22 ; JUSB2.12 14.8,56.05 ; 42.11,134.04 H25.1 ; H25.1 42.11,131.06 ; H25.1 43.6,130.52 ; H25.1 45.63,132.55 ; H25.1 45.09,134.04 ; H25.1 43.6,134.58 ; H25.1 45.09,131.06 ; H25.1 41.57,132.55 ; JUSBC1.B12 7.08,109.95 ; JUSBC1.B12 6.99,109.56 ; JUSBC1.B12 6.21,110.34 ; JUSBC1.B12 6.6,109.47 ; 11.65,77.47 JHDMI1.22 ; JHDMI1.22 12.93,77.47 ; JHDMI1.22 10.37,77.47 ; JHDMI1.22 11.65,79.23 ; JHDMI1.22 12.93,78.35 ; JHDMI1.22 10.37,79.23 ; JHDMI1.22 12.93,79.23 ; 65.5,49.55 H28.1 ; H28.1 67.1,53.33 ; H28.1 64.92,51.15 ; H28.1 68.7,49.55 ; H28.1 65.5,52.75 ; H28.1 69.28,51.15 ; H28.1 67.1,48.97 ; H28.1 68.7,52.75 ; H23.1 9.87,73.08 ; H23.1 7.33,73.08 ; H23.1 9.87,75.62 ; H23.1 10.33,74.35 ; H23.1 8.6,72.62 ; H23.1 6.87,74.35 ; H23.1 8.6,76.08 ; H23.1 7.33,75.62 ; JHDMI1.2 13.58,81.6 ; JHDMI1.2 12.54,82.06 ; JHDMI1.2 12.42,81.6 ; JHDMI1.2 13.46,81.14 ; JHDMI1.2 13,81.02 ; JHDMI1.2 12.54,81.14 ; JHDMI1.2 13.46,82.06 ; 140.44,89.84 H3.1 ; H3.1 142,93.53 ; H3.1 144.13,91.4 ; H3.1 143.56,92.96 ; H3.1 140.44,92.96 ; H3.1 139.87,91.4 ; H3.1 143.56,89.84 ; H3.1 142,89.27 ; 292.13,71.2 JUSB1.11 ; JUSB1.11 294.5,71.2 ; JUSB1.11 292.13,70.37 ; JUSB1.11 293.31,70.37 ; JUSB1.11 294.5,70.37 ; 0.83,100.63 JUSBC1.4 ; JUSBC1.4 3.27,100.63 ; JUSBC1.4 0.83,101.35 ; JUSBC1.4 2.05,100.63 ; JUSBC1.4 0.83,102.07 ; JUSBC1.4 2.05,102.07 ; JUSBC1.4 3.27,101.35 ; JUSBC1.4 3.27,102.07 ; 80.07,113.55 H1.1 ; H1.1 80.64,111.99 ; H1.1 83.76,111.99 ; H1.1 84.33,113.55 ; H1.1 82.2,111.42 ; H1.1 83.76,115.11 ; H1.1 80.64,115.11 ; H1.1 82.2,115.68 ; JHDMI1.8 13.46,85.06 ; JHDMI1.8 12.42,84.6 ; JHDMI1.8 12.54,84.14 ; JHDMI1.8 12.54,85.06 ; JHDMI1.8 13.46,84.14 ; JHDMI1.8 13.58,84.6 ; JLOM1.15 298.68,90.55 ; JLOM1.15 298.68,89.72 ; JLOM1.15 295.32,90.55 ; JLOM1.15 295.32,89.72 ; JLOM1.15 297,89.72 ; 294.97,49.25 JSD1.13 ; JSD1.13 294.97,49.97 ; JSD1.13 297.23,49.97 ; JSD1.13 296.1,49.25 ; JSD1.13 296.1,50.7 ; JSD1.13 294.97,50.7 ; JSD1.13 297.23,49.25 ; JSD1.13 297.23,50.7 ; JUSB1.12 285.4,85.3 ; JUSB1.12 285.4,86.13 ; JUSB1.12 282.73,84.47 ; JUSB1.12 284.06,84.47 ; JUSB1.12 285.4,84.47 ; JUSB1.12 282.73,86.13 ; JUSB1.12 284.06,86.13 ; JUSB1.12 282.73,85.3 ; H7.1 275.9,104.53 ; H7.1 274.41,103.99 ; H7.1 275.9,100.47 ; H7.1 273.87,102.5 ; H7.1 277.39,103.99 ; H7.1 277.93,102.5 ; H7.1 274.41,101.01 ; H7.1 277.39,101.01 ; JUSBC1.B1 6.6,104.83 ; JUSBC1.B1 6.21,103.96 ; JUSBC1.B1 6.99,104.74 ; 10.99,85.64 JHDMI1.11 ; JHDMI1.11 11.91,86.56 ; JHDMI1.11 10.87,86.1 ; JHDMI1.11 12.03,86.1 ; JHDMI1.11 10.99,86.56 ; JHDMI1.11 11.91,85.64 ; 295.32,116.95 JLOM1.17 ; JLOM1.17 297,117.78 ; JLOM1.17 295.32,117.78 ; JLOM1.17 298.68,116.95 ; JLOM1.17 298.68,117.78 ; 284.06,71.67 JUSB1.10 ; JUSB1.10 282.73,71.67 ; JUSB1.10 284.06,73.33 ; JUSB1.10 282.73,72.5 ; JUSB1.10 282.73,73.33 ; JUSB1.10 285.4,73.33 ; JUSB1.10 285.4,71.67 ; JUSB1.10 285.4,72.5 ; 289.47,90.55 JLOM1.14 ; JLOM1.14 292.83,90.55 ; JLOM1.14 292.83,89.72 ; JLOM1.14 289.47,89.72 ; JLOM1.14 291.15,89.72 ; 298.17,64.3 JSD1.12 ; JSD1.12 299.3,64.3 ; JSD1.12 298.17,63.57 ; JSD1.12 299.3,62.85 ; 294.65,24.85 H20.1 ; H20.1 294.65,27.75 ; H20.1 296.1,28.28 ; H20.1 297.55,24.85 ; H20.1 294.12,26.3 ; H20.1 296.1,24.32 ; H20.1 298.08,26.3 ; H20.1 297.55,27.75 ; JUSB2.10 16.13,69.68 ; JUSB2.10 17.47,68.85 ; JUSB2.10 14.8,69.68 ; JUSB2.10 17.47,69.68 ; JUSB2.10 16.13,68.02 ; JUSB2.10 14.8,68.02 ; JUSB2.10 17.47,68.02 ; JUSB2.10 14.8,68.85 ; 265.41,72.89 H8.1 ; H8.1 264.87,71.4 ; H8.1 268.39,72.89 ; H8.1 266.9,73.43 ; H8.1 265.41,69.91 ; H8.1 268.39,69.91 ; H8.1 268.93,71.4 ; H8.1 266.9,69.37 ; 80.64,89.84 H4.1 ; H4.1 83.76,92.96 ; H4.1 83.76,89.84 ; H4.1 80.64,92.96 ; H4.1 80.07,91.4 ; H4.1 84.33,91.4 ; H4.1 82.2,93.53 ; H4.1 82.2,89.27 ; JHDMI1.21 3.3,95.38 ; JHDMI1.21 4.98,94.35 ; JHDMI1.21 1.62,95.38 ; JHDMI1.21 4.98,95.38 ; JHDMI1.21 1.62,94.35 ; JHDMI1.20 12.93,93.73 ; JHDMI1.20 11.65,91.97 ; JHDMI1.20 11.65,93.73 ; JHDMI1.20 12.93,91.97 ; JHDMI1.20 12.93,92.85 ; JHDMI1.20 10.37,91.97 ; JHDMI1.20 10.37,93.73
  IN2 w0.254: 129.13,111.31 129.73,111.31 130.78,110.25 v2(130.93,110.25) 131.18,110.5 v2(131.18,112.01) 131.18,113.68 v2(131.09,113.77) 131.09,114.59 133.79,117.29 v2(133.84,117.29) 134.22,117.68 134.22,118.49 133.82,118.89 132.63,118.89 131.81,118.07 v2(131.81,117.19) 129.53,114.9 v2(129.53,113.78) 129.53,112.77 128.81,112.05 128.81,111.63 129.13,111.31
  VCC w0.203: JSD1.13 296.1,50.7 ; JSD1.13 296.1,49.25 ; JSD1.13 294.97,49.97 ; JSD1.13 297.23,50.7 ; JSD1.13 297.23,49.25 ; JSD1.13 297.23,49.97 ; JSD1.13 294.97,50.7 ; JSD1.13 294.97,49.25 ; H23.1 9.87,73.08 ; H23.1 10.33,74.35 ; H23.1 9.87,75.62 ; H23.1 8.6,76.08 ; H23.1 6.87,74.35 ; H23.1 8.6,72.62 ; H23.1 7.33,75.62 ; H23.1 7.33,73.08 ; 298.17,63.57 JSD1.12 ; JSD1.12 299.3,64.3 ; JSD1.12 299.3,62.85 ; JSD1.12 298.17,64.3 ; 6.6,104.83 JUSBC1.B1 6.99,104.74 ; 14.8,55.22 JUSB2.12 ; JUSB2.12 16.13,56.88 ; JUSB2.12 14.8,56.05 ; JUSB2.12 16.13,55.22 ; JUSB2.12 14.8,56.88 ; 292.13,87.43 JUSB1.13 ; JUSB1.13 294.5,87.43 ; JUSB1.13 293.31,87.43 ; JUSB1.7 285.87,79.73 ; JUSB1.7 285.87,78.07 ; JUSB1.7 285.04,78.9 ; JUSB1.7 285.23,78.27 ; JUSB1.7 285.23,79.54 ; JHDMI1.2 13.46,81.14 ; JHDMI1.2 13.46,82.06 ; JHDMI1.2 12.54,82.06 ; JHDMI1.2 13.58,81.6 ; JHDMI1.2 13,81.02 ; JHDMI1.2 12.42,81.6 ; JHDMI1.2 12.54,81.14 ; 282.73,84.47 JUSB1.12 ; JUSB1.12 285.4,84.47 ; JUSB1.12 284.06,84.47 ; JUSB1.12 282.73,86.13 ; JUSB1.12 284.06,86.13 ; JUSB1.12 285.4,85.3 ; JUSB1.12 285.4,86.13 ; JUSB1.12 282.73,85.3 ; JHDMI1.20 12.93,93.73 ; JHDMI1.20 12.93,91.97 ; JHDMI1.20 11.65,91.97 ; JHDMI1.20 12.93,92.85 ; JHDMI1.20 11.65,93.73 ; 14.8,68.02 JUSB2.10 ; JUSB2.10 14.8,68.85 ; JUSB2.10 14.8,69.68 ; JUSB2.10 16.13,69.68 ; JUSB2.10 16.13,68.02 ; H15.1 6.82,99.97 ; H15.1 6.82,97.43 ; H15.1 4.28,97.43 ; H15.1 7.28,98.7 ; H15.1 5.55,96.97 ; H15.1 5.55,100.43 ; H15.1 3.82,98.7 ; H15.1 4.28,99.97 ; 285.13,66.93 H33.1 ; H33.1 287.67,69.47 ; H33.1 284.67,68.2 ; H33.1 285.13,69.47 ; H33.1 287.67,66.93 ; H33.1 286.4,69.93 ; H33.1 288.13,68.2 ; H33.1 286.4,66.47 ; JSD1.10 287.63,49.25 ; JSD1.10 286.5,49.25 ; JSD1.10 287.63,50.7 ; JSD1.10 285.37,50.7 ; JSD1.10 285.37,49.25 ; JSD1.10 287.63,49.97 ; JSD1.10 285.37,49.97 ; JSD1.10 286.5,50.7 ; H4.1 83.76,89.84 ; H4.1 80.07,91.4 ; H4.1 84.33,91.4 ; H4.1 80.64,89.84 ; H4.1 80.64,92.96 ; H4.1 82.2,93.53 ; H4.1 83.76,92.96 ; H4.1 82.2,89.27 ; 286.5,62.85 JSD1.11 ; JSD1.11 285.37,62.85 ; JSD1.11 285.37,64.3 ; JSD1.11 285.37,63.57 ; JSD1.11 286.5,64.3 ; JSD1.11 287.63,64.3 ; JSD1.11 287.63,63.57 ; JSD1.11 287.63,62.85 ; 294.65,27.75 H20.1 ; H20.1 296.1,24.32 ; H20.1 297.55,24.85 ; H20.1 296.1,28.28 ; H20.1 298.08,26.3 ; H20.1 297.55,27.75 ; H20.1 294.12,26.3 ; H20.1 294.65,24.85 ; 12.42,84.6 JHDMI1.8 ; JHDMI1.8 13.46,84.14 ; JHDMI1.8 12.54,84.14 ; JHDMI1.8 13.46,85.06 ; JHDMI1.8 13.58,84.6 ; JHDMI1.8 12.54,85.06 ; 278.63,12.68 H16.1 ; H16.1 278.63,15.22 ; H16.1 279.9,12.22 ; H16.1 281.17,15.22 ; H16.1 281.17,12.68 ; H16.1 279.9,15.68 ; H16.1 281.63,13.95 ; H16.1 278.17,13.95 ; 282.73,73.33 JUSB1.10 ; JUSB1.10 285.4,73.33 ; JUSB1.10 285.4,72.5 ; JUSB1.10 282.73,71.67 ; JUSB1.10 284.06,71.67 ; JUSB1.10 285.4,71.67 ; JUSB1.10 284.06,73.33 ; JUSB1.10 282.73,72.5 ; JHDMI1.5 11.91,82.64 ; JHDMI1.5 12.03,83.1 ; JHDMI1.5 11.91,83.56 ; 1.62,76.85 JHDMI1.23 ; JHDMI1.23 4.98,76.85 ; JHDMI1.23 4.98,75.82 ; 1.62,94.35 JHDMI1.21 ; JHDMI1.21 4.98,95.38 ; JHDMI1.21 1.62,95.38 ; JHDMI1.21 4.98,94.35 ; JHDMI1.21 3.3,95.38 ; JHDMI1.17 11.91,89.56 ; JHDMI1.17 12.03,89.1 ; JHDMI1.17 11.91,88.64 ; JLOM1.14 292.83,90.55 ; JLOM1.14 289.47,90.55 ; JLOM1.14 291.15,89.72 ; JLOM1.14 289.47,89.72 ; JLOM1.14 292.83,89.72 ; JUSB2.4 15.83,59.78 ; JUSB2.4 16.47,59.58 ; JUSB2.4 16.47,58.31 ; JUSB2.4 15.2,59.58 ; JUSB2.4 16.66,58.95 ; JUSB2.4 15.83,58.12 ; JHDMI1.22 12.93,77.47 ; JHDMI1.22 11.65,77.47 ; JHDMI1.22 11.65,79.23 ; JHDMI1.22 12.93,79.23 ; JHDMI1.22 12.93,78.35 ; 2.87,49.5 H24.1 ; H24.1 5.87,50.77 ; H24.1 3.33,50.77 ; H24.1 4.6,47.77 ; H24.1 4.6,51.23 ; H24.1 5.87,48.23 ; H24.1 6.33,49.5 ; H24.1 3.33,48.23 ; JUSB2.7 14.97,61.81 ; JUSB2.7 14.97,63.08 ; JUSB2.7 14.33,63.28 ; JUSB2.7 14.33,61.62 ; JUSB2.7 15.16,62.45 ; 283.73,81.76 JUSB1.4 ; JUSB1.4 285,81.76 ; JUSB1.4 284.36,81.57 ; JUSB1.4 283.73,83.03 ; JUSB1.4 283.54,82.4 ; JUSB1.4 284.36,83.23 ; JUSB2.11 8.07,70.98 ; JUSB2.11 6.88,70.98 ; JUSB2.11 5.7,70.98 ; JHDMI1.11 11.91,86.56 ; JHDMI1.11 12.03,86.1 ; JHDMI1.11 11.91,85.64 ; JUSB2.13 6.88,53.57 ; JUSB2.13 5.77,53.95 ; JUSB2.13 7.86,53.89 ; JUSBC1.2 7.43,102.35 ; JUSBC1.2 7.43,101.63 ; JUSBC1.2 6.27,101.63 ; JUSBC1.4 3.27,100.63 ; JUSBC1.4 3.27,101.35 ; JUSBC1.4 2.05,100.63 ; 295.32,90.55 JLOM1.15 295.32,89.72
  IN4 w0.203: JUSBC1.1 7.43,112.67 ; JUSBC1.1 6.27,112.67 ; JUSBC1.1 6.27,111.23 ; JUSBC1.1 7.43,111.95 ; JUSBC1.B1 6.99,104.74 ; JUSBC1.B1 6.21,103.96 ; JUSBC1.B1 6.6,104.83 ; JUSBC1.B12 6.99,109.56 ; JUSBC1.B12 7.08,109.95 ; JUSBC1.B12 6.21,110.34 ; JUSBC1.B12 6.6,109.47
  GND3 w0.203: H33.1 287.67,69.47 ; H33.1 288.13,68.2 ; H33.1 285.13,66.93 ; H33.1 285.13,69.47 ; H33.1 287.67,66.93 ; H33.1 286.4,66.47 ; H33.1 284.67,68.2 ; H33.1 286.4,69.93 ; JUSBC1.3 3.27,112.23 ; JUSBC1.3 0.83,112.95 ; JUSBC1.3 2.05,112.23 ; JUSBC1.3 3.27,112.95 ; JUSBC1.3 0.83,113.67 ; JUSBC1.3 0.83,112.23 ; JUSBC1.3 2.05,113.67 ; JUSBC1.3 3.27,113.67 ; 14.8,55.22 JUSB2.12 ; JUSB2.12 14.8,56.88 ; JUSB2.12 17.47,56.05 ; JUSB2.12 16.13,55.22 ; JUSB2.12 14.8,56.05 ; JUSB2.12 17.47,56.88 ; JUSB2.12 17.47,55.22 ; JUSB2.12 16.13,56.88 ; H15.1 6.82,99.97 ; H15.1 5.55,100.43 ; H15.1 5.55,96.97 ; H15.1 7.28,98.7 ; H15.1 6.82,97.43 ; H15.1 4.28,99.97 ; H15.1 3.82,98.7 ; H15.1 4.28,97.43 ; 295.32,89.72 JLOM1.15 ; JLOM1.15 298.68,90.55 ; JLOM1.15 298.68,89.72 ; JLOM1.15 297,89.72 ; JLOM1.15 295.32,90.55 ; 294.65,24.85 H20.1 ; H20.1 298.08,26.3 ; H20.1 294.65,27.75 ; H20.1 297.55,27.75 ; H20.1 294.12,26.3 ; H20.1 297.55,24.85 ; H20.1 296.1,28.28 ; H20.1 296.1,24.32 ; JHDMI1.22 12.93,77.47 ; JHDMI1.22 12.93,78.35 ; JHDMI1.22 10.37,77.47 ; JHDMI1.22 12.93,79.23 ; JHDMI1.22 11.65,77.47 ; JHDMI1.22 10.37,79.23 ; JHDMI1.22 11.65,79.23 ; 76.51,134.04 H26.1 ; H26.1 78,130.52 ; H26.1 79.49,131.06 ; H26.1 80.03,132.55 ; H26.1 76.51,131.06 ; H26.1 75.97,132.55 ; H26.1 79.49,134.04 ; H26.1 78,134.58 ; H29.1 290.32,131.63 ; H29.1 289.05,134.63 ; H29.1 287.32,132.9 ; H29.1 287.78,134.17 ; H29.1 287.78,131.63 ; H29.1 290.32,134.17 ; H29.1 289.05,131.17 ; H29.1 290.78,132.9 ; H28.1 69.28,51.15 ; H28.1 65.5,52.75 ; H28.1 67.1,48.97 ; H28.1 64.92,51.15 ; H28.1 68.7,49.55 ; H28.1 67.1,53.33 ; H28.1 65.5,49.55 ; H28.1 68.7,52.75 ; 12.54,82.06 JHDMI1.2 ; JHDMI1.2 12.42,81.6 ; JHDMI1.2 12.54,81.14 ; JHDMI1.2 13.46,81.14 ; JHDMI1.2 13.46,82.06 ; JHDMI1.2 13.58,81.6 ; JHDMI1.2 13,81.02 ; H8.1 268.39,72.89 ; H8.1 268.39,69.91 ; H8.1 265.41,72.89 ; H8.1 266.9,73.43 ; H8.1 268.93,71.4 ; H8.1 264.87,71.4 ; H8.1 266.9,69.37 ; H8.1 265.41,69.91 ; JHDMI1.5 12.03,83.1 ; JHDMI1.5 11.91,82.64 ; JHDMI1.5 10.87,83.1 ; JHDMI1.5 10.99,82.64 ; JHDMI1.5 10.99,83.56 ; JHDMI1.5 11.91,83.56 ; JHDMI1.20 12.93,92.85 ; JHDMI1.20 12.93,93.73 ; JHDMI1.20 10.37,91.97 ; JHDMI1.20 10.37,93.73 ; JHDMI1.20 11.65,93.73 ; JHDMI1.20 11.65,91.97 ; JHDMI1.20 12.93,91.97 ; 285.37,50.7 JSD1.10 ; JSD1.10 286.5,50.7 ; JSD1.10 285.37,49.97 ; JSD1.10 287.63,49.25 ; JSD1.10 285.37,49.25 ; JSD1.10 287.63,49.97 ; JSD1.10 286.5,49.25 ; JSD1.10 287.63,50.7 ; JHDMI1.21 3.3,95.38 ; JHDMI1.21 4.98,94.35 ; JHDMI1.21 1.62,94.35 ; JHDMI1.21 1.62,95.38 ; JHDMI1.21 4.98,95.38 ; H37.1 151.55,132.85 ; H37.1 150.1,136.28 ; H37.1 148.12,134.3 ; H37.1 150.1,132.32 ; H37.1 152.08,134.3 ; H37.1 148.65,135.75 ; H37.1 151.55,135.75 ; H37.1 148.65,132.85 ; JUSB1.10 285.4,73.33 ; JUSB1.10 285.4,71.67 ; JUSB1.10 282.73,71.67 ; JUSB1.10 282.73,73.33 ; JUSB1.10 285.4,72.5 ; JUSB1.10 282.73,72.5 ; JUSB1.10 284.06,71.67 ; JUSB1.10 284.06,73.33 ; H9.1 235.37,135.47 ; H9.1 235.37,132.93 ; H9.1 234.1,135.93 ; H9.1 232.83,132.93 ; H9.1 232.37,134.2 ; H9.1 235.83,134.2 ; H9.1 234.1,132.47 ; H9.1 232.83,135.47 ; 292.13,87.43 JUSB1.13 ; JUSB1.13 293.31,87.43 ; JUSB1.13 294.5,87.43 ; JUSB1.13 294.5,86.6 ; JUSB1.13 292.13,86.6 ; JUSBC1.2 7.43,102.35 ; JUSBC1.2 6.27,103.07 ; JUSBC1.2 7.43,101.63 ; JUSBC1.2 5.12,101.63 ; JUSBC1.2 6.27,101.63 ; H2.1 142,115.68 ; H2.1 144.13,113.55 ; H2.1 140.44,111.99 ; H2.1 143.56,111.99 ; H2.1 139.87,113.55 ; H2.1 140.44,115.11 ; H2.1 143.56,115.11 ; H2.1 142,111.42 ; 8.6,72.62 H23.1 ; H23.1 8.6,76.08 ; H23.1 7.33,73.08 ; H23.1 6.87,74.35 ; H23.1 9.87,75.62 ; H23.1 10.33,74.35 ; H23.1 9.87,73.08 ; H23.1 7.33,75.62 ; 5.7,70.98 JUSB2.11 ; JUSB2.11 8.07,70.15 ; JUSB2.11 8.07,70.98 ; JUSB2.11 6.88,70.98 ; JUSB2.11 5.7,70.15 ; 0.83,102.07 JUSBC1.4 ; JUSBC1.4 3.27,100.63 ; JUSBC1.4 3.27,102.07 ; JUSBC1.4 2.05,100.63 ; JUSBC1.4 3.27,101.35 ; JUSBC1.4 0.83,101.35 ; JUSBC1.4 2.05,102.07 ; JUSBC1.4 0.83,100.63 ; 14.8,68.85 JUSB2.10 ; JUSB2.10 14.8,69.68 ; JUSB2.10 17.47,68.02 ; JUSB2.10 14.8,68.02 ; JUSB2.10 16.13,69.68 ; JUSB2.10 17.47,69.68 ; JUSB2.10 16.13,68.02 ; JUSB2.10 17.47,68.85 ; JHDMI1.23 4.98,76.85 ; JHDMI1.23 3.3,75.82 ; JHDMI1.23 1.62,76.85 ; JHDMI1.23 4.98,75.82 ; JHDMI1.23 1.62,75.82 ; JLOM1.14 292.83,90.55 ; JLOM1.14 289.47,89.72 ; JLOM1.14 292.83,89.72 ; JLOM1.14 289.47,90.55 ; JLOM1.14 291.15,89.72 ; JSD1.11 286.5,64.3 ; JSD1.11 287.63,63.57 ; JSD1.11 285.37,62.85 ; JSD1.11 287.63,64.3 ; JSD1.11 285.37,64.3 ; JSD1.11 286.5,62.85 ; JSD1.11 287.63,62.85 ; JSD1.11 285.37,63.57 ; 162.83,135.47 H38.1 ; H38.1 164.1,135.93 ; H38.1 162.83,132.93 ; H38.1 165.37,132.93 ; H38.1 162.37,134.2 ; H38.1 164.1,132.47 ; H38.1 165.37,135.47 ; H38.1 165.83,134.2 ; H1.1 84.33,113.55 ; H1.1 83.76,111.99 ; H1.1 80.64,111.99 ; H1.1 80.07,113.55 ; H1.1 83.76,115.11 ; H1.1 80.64,115.11 ; H1.1 82.2,111.42 ; H1.1 82.2,115.68 ; 295.32,116.95 JLOM1.17 ; JLOM1.17 297,117.78 ; JLOM1.17 298.68,117.78 ; JLOM1.17 295.32,117.78 ; JLOM1.17 298.68,116.95 ; JHDMI1.8 13.58,84.6 ; JHDMI1.8 12.42,84.6 ; JHDMI1.8 12.54,84.14 ; JHDMI1.8 12.54,85.06 ; JHDMI1.8 13.46,85.06 ; JHDMI1.8 13.46,84.14 ; 273.87,102.5 H7.1 ; H7.1 274.41,101.01 ; H7.1 274.41,103.99 ; H7.1 275.9,100.47 ; H7.1 277.39,103.99 ; H7.1 277.93,102.5 ; H7.1 277.39,101.01 ; H7.1 275.9,104.53 ; JUSB2.4 16.66,58.95 ; JUSB2.4 15.2,59.58 ; JUSB2.4 16.47,59.58 ; JUSB2.4 16.47,58.31 ; JUSB2.4 15.83,59.78 ; JUSB2.4 15.83,58.12 ; JUSB2.7 14.33,63.28 ; JUSB2.7 13.7,63.08 ; JUSB2.7 13.7,61.81 ; JUSB2.7 15.16,62.45 ; JUSB2.7 14.97,61.81 ; JUSB2.7 14.97,63.08 ; JUSB2.7 14.33,61.62 ; H24.1 4.6,51.23 ; H24.1 3.33,48.23 ; H24.1 3.33,50.77 ; H24.1 6.33,49.5 ; H24.1 4.6,47.77 ; H24.1 5.87,50.77 ; H24.1 2.87,49.5 ; H24.1 5.87,48.23 ; H4.1 84.33,91.4 ; H4.1 83.76,92.96 ; H4.1 80.64,89.84 ; H4.1 80.64,92.96 ; H4.1 82.2,93.53 ; H4.1 83.76,89.84 ; H4.1 80.07,91.4 ; H4.1 82.2,89.27 ; JHDMI1.17 11.91,89.56 ; JHDMI1.17 10.87,89.1 ; JHDMI1.17 10.99,89.56 ; JHDMI1.17 12.03,89.1 ; JHDMI1.17 11.91,88.64 ; JHDMI1.17 10.99,88.64 ; H14.1 5.55,117.33 ; H14.1 6.82,114.33 ; H14.1 6.82,116.87 ; H14.1 4.28,114.33 ; H14.1 7.28,115.6 ; H14.1 5.55,113.87 ; H14.1 4.28,116.87 ; H14.1 3.82,115.6 ; JHDMI1.11 11.91,86.56 ; JHDMI1.11 10.99,85.64 ; JHDMI1.11 11.91,85.64 ; JHDMI1.11 10.87,86.1 ; JHDMI1.11 12.03,86.1 ; JHDMI1.11 10.99,86.56 ; 294.97,49.25 JSD1.13 ; JSD1.13 294.97,50.7 ; JSD1.13 297.23,49.97 ; JSD1.13 297.23,50.7 ; JSD1.13 296.1,50.7 ; JSD1.13 296.1,49.25 ; JSD1.13 297.23,49.25 ; JSD1.13 294.97,49.97 ; JUSB1.4 285,81.76 ; JUSB1.4 283.73,81.76 ; JUSB1.4 284.36,83.23 ; JUSB1.4 283.54,82.4 ; JUSB1.4 283.73,83.03 ; JUSB1.4 284.36,81.57 ; JUSB1.12 285.4,84.47 ; JUSB1.12 284.06,86.13 ; JUSB1.12 282.73,85.3 ; JUSB1.12 285.4,85.3 ; JUSB1.12 285.4,86.13 ; JUSB1.12 282.73,84.47 ; JUSB1.12 284.06,84.47 ; JUSB1.12 282.73,86.13 ; JUSB1.11 294.5,71.2 ; JUSB1.11 294.5,70.37 ; JUSB1.11 292.13,71.2 ; JUSB1.11 293.31,70.37 ; JUSB1.11 292.13,70.37 ; 147.76,51.1 H10.1 ; H10.1 152.44,51.1 ; H10.1 151.8,52.8 ; H10.1 148.4,52.8 ; H10.1 150.1,53.44 ; H10.1 148.4,49.4 ; H10.1 151.8,49.4 ; H3.1 143.56,92.96 ; H3.1 143.56,89.84 ; H3.1 142,89.27 ; H3.1 140.44,89.84 ; H3.1 139.87,91.4 ; H3.1 144.13,91.4 ; H3.1 142,93.53 ; H3.1 140.44,92.96 ; JUSB1.7 285.87,79.73 ; JUSB1.7 285.23,78.27 ; JUSB1.7 286.5,78.27 ; JUSB1.7 285.87,78.07 ; JUSB1.7 286.5,79.54 ; JUSB1.7 285.23,79.54 ; JUSB1.7 285.04,78.9 ; 278.63,12.68 H16.1 ; H16.1 281.63,13.95 ; H16.1 278.63,15.22 ; H16.1 279.9,15.68 ; H16.1 278.17,13.95 ; H16.1 279.9,12.22 ; H16.1 281.17,12.68 ; H16.1 281.17,15.22 ; 299.3,62.85 JSD1.12 ; JSD1.12 299.3,64.3 ; JSD1.12 298.17,63.57 ; JSD1.12 298.17,64.3 ; 6.27,111.23 JUSBC1.1 ; JUSBC1.1 7.43,112.67 ; JUSBC1.1 7.43,111.95 ; JUSBC1.1 5.12,112.67 ; JUSBC1.1 6.27,112.67 ; JLOM1.16 292.83,116.95 ; JLOM1.16 292.83,117.78 ; JLOM1.16 291.15,117.78 ; 42.11,131.06 H25.1 ; H25.1 45.09,134.04 ; H25.1 42.11,134.04 ; H25.1 45.63,132.55 ; H25.1 43.6,130.52 ; H25.1 43.6,134.58 ; H25.1 41.57,132.55 ; H25.1 45.09,131.06
  BOTTOM w0.127: v2(231.85,75.15) v3(230.95,75.15) ; v2(156.88,104.49) v3(155.96,104.49) ; v2(275.61,78.12) v3(274.55,78.12) ; UT1.A22 UT1.B22 ; v2(260.31,54.81) v3(261.17,54.81)
  BOTTOM w0.152: UT1.M1 UT1.M2 ; UT1.L22 UT1.L23 ; UT1.AC16 32.77,97.49 32.31,97.49 UT1.AB16 ; UT1.N22 UT1.N23 ; UT1.A18 UT1.B18 ; UT1.AC10 UT1.AB10 ; UT1.J23 UT1.J22 ; UT1.E22 UT1.E23 ; UT1.T2 29.55,103.93 29.55,104.38 UT1.T1 ; UT1.AB20 UT1.AC20 ; UT1.K2 UT1.K1 ; UT1.A8 UT1.B8 ; UT1.AC8 UT1.AB8 ; UT1.A10 UT1.B10 ; UT1.B22 UT1.C22 UT1.C23 ; UT1.H1 UT1.H2 ; UT1.AC12 32.77,99.33 32.31,99.33 UT1.AB12 ; UT1.AC1 UT1.AB1 32.31,103.93 UT1.AB2 UT1.AC2 ; UT1.A6 UT1.B6 ; UT1.A12 UT1.B12 ; UT1.G23 UT1.G22 ; UC1.AW8 128.05,92.99 126.89,92.99 UC1.AW10 ; UT1.R23 UT1.R22 ; UT1.B20 23.11,95.64 22.65,95.64 UT1.A20 ; UT1.AC18 UT1.AB18 ; UT1.U22 UT1.U23 ; UT1.W23 UT1.W22 ; UT1.AA22 UT1.AA23 ; UT1.AC22 UT1.AB22 ; UT1.B14 UT1.A14 ; UT1.AC14 UT1.AB14 ; UT1.P1 UT1.P2 ; UT1.B16 UT1.A16 ; UT1.AC6 UT1.AB6
  BOTTOM w0.178: UC1.BB30 115.91,90.36 115.91,89.97 v2(116.04,89.84) ; v2(91.01,94.49) 91.02,94.49 91.53,94.49 UC1.AT71 ; v2(96.21,90.13) 96.21,90.48 UC1.BB64 ; UC1.BB60 98.56,90.14 v2(98.52,90.1) ; v2(108.3,90.06) 108.33,90.08 UC1.BB43 ; v2(101.16,90.03) 101.16,90.62 UC1.BB55 ; UC1.H71 91.22,109.1 v2(91.1,108.98) ; UC1.BB26 118.26,90.61 118.26,90.1 v2(118.32,90.05) ; v2(91.02,96.79) 91.08,96.84 91.83,96.84 UC1.AM71 ; UC1.BB38 110.94,91 110.94,90.05 v2(110.97,90.03) ; UC1.BB34 113.28,90.74 113.28,89.43 v2(113.31,89.4)
  BOTTOM w0.203: v2(94.55,92.83) UC1.AY66 UC1.BA66 ; v2(94.55,92.83) 94.1,93.29 UC1.AV68 ; v2(94.55,92.83) 94.66,92.83 94.93,93.1 UC1.AW66 95.09,93.01 96.06,93.01 UC1.AW64 96.59,92.96 96.62,92.99 96.92,92.99 96.95,92.96 UC1.AW62 97.82,92.96 97.85,92.99 98.14,92.99 98.17,92.96 UC1.AW60 99.04,92.96 99.08,92.99 99.37,92.99 99.4,92.96 UC1.AW57 100.32,92.96 100.35,92.99 100.64,92.99 100.68,92.96 UC1.AW55 101.55,92.96 101.58,92.99 101.87,92.99 101.9,92.96 UC1.AW53 102.77,92.96 102.8,92.99 103.1,92.99 103.13,92.96 UC1.AW51 103.94,92.96 103.97,92.99 104.26,92.99 104.29,92.96 UC1.AW49 105.2,92.96 105.23,92.99 105.52,92.99 105.55,92.96 UC1.AW47 106.36,92.96 106.39,92.99 106.69,92.99 106.72,92.96 UC1.AW45 107.59,92.96 107.64,93.01 108.05,93.01 108.1,92.96 108.43,92.96 UC1.AW43 ; UC1.AL66 95.13,97.16 95.18,97.11 95.56,97.11 95.6,97.16 UC1.AL65 95.77,97.16 95.81,97.11 96.19,97.11 96.24,97.16 UC1.AL64 ; UC1.J28 115.61,108.8 115.61,108.14 v2(115.65,108.1) ; UC1.AF15 124.37,100.25 124.8,100.25 124.95,100.4 125.77,100.4 v2(125.99,100.62) 125.91,100.7 125.39,100.7 125.13,100.96 UC1.AD13 ; UC1.J32 113.75,108.17 v2(113.71,108.14) ; UC1.AV1 132.96,93.17 v2(133.05,93.09) ; UT5.F5 UT5.F6 ; UT5.F5 UT5.E5 ; UT5.F5 UT5.G5 ; UT5.F6 UT5.F7 ; UT5.F6 UT5.G6 ; UT5.F6 UT5.E6 ; UC1.D39 v2(109.74,111.85) UC1.B39 ; UT5.F7 UT5.E7 ; UT5.F7 UT5.F8 ; UT5.F7 UT5.G7 ; v2(111.92,108.14) UC1.J35 ; UT5.G7 UT5.G8 ; UT5.G7 UT5.G6 ; UT5.G8 31.02,82.35 v2(30.94,82.43) ; UT5.G8 UT5.H8 30.34,81.8 v2(30.05,81.8) ; UT5.G8 UT5.F8 ; UC1.AU10 126.99,93.7 v2(126.55,93.42) ; UT5.G6 UT5.G5 ; UT5.E5 32.49,80.01 32.49,79.69 v2(32.69,79.49) ; UT5.E5 UT5.E6 ; UC1.AG71 v2(91.59,99.5) ; v2(126.55,93.42) 126.1,92.96 UC1.AW12 125.27,92.96 125.24,92.99 124.95,92.99 124.92,92.96 UC1.AW14 124.25,93.14 v2(123.78,93.14) 123.6,92.97 UC1.AW16 123,92.96 122.95,93.01 122.06,93.01 UC1.AW18 121.58,92.96 121.55,92.99 121.25,92.99 121.22,92.96 UC1.AW21 120.43,92.96 120.4,92.99 120.11,92.99 120.08,92.96 UC1.AW23 119.11,92.96 119.08,92.99 118.78,92.99 118.75,92.96 UC1.AW26 117.88,92.96 117.85,92.99 117.55,92.99 117.52,92.96 UC1.AW28 116.65,92.96 116.62,92.99 116.33,92.99 116.3,92.96 UC1.AW30 115.43,92.96 115.39,92.99 115.1,92.99 115.07,92.96 UC1.AW32 114.24,92.96 v2(113.75,93.45) 113.38,93.09 UC1.AW34 112.9,92.96 112.87,92.99 112.57,92.99 112.54,92.96 UC1.AW36 111.67,92.96 111.64,92.99 111.35,92.99 111.32,92.96 UC1.AW38 110.65,92.96 v2(110.14,93.47) ; v2(126.55,93.42) 126.79,92.98 UC1.AW10 126.86,92.96 126.86,92.7 v2(126.86,92.47) 126.86,91.75 UC1.BA10 ; UC1.G43 107.61,109.29 v2(107.33,109.57) ; UC1.C1 132.98,112.35 v2(133.06,112.42) ; v2(110.09,108.14) UC1.J38 ; v2(132.58,110.54) 132.5,110.47 UC1.F1 ; v2(30.35,79.49) 30.52,79.66 UT5.H4 UT5.G5 ; UC1.D48 UC1.D47 105.85,111.36 105.88,111.33 106.17,111.33 106.2,111.36 106.58,111.36 UC1.D45 UC1.D44 ; UC1.J25 117.41,108.09 v2(117.23,107.91) ; UC1.AH63 97.09,99.04 97.09,99.75 UC1.AF63 ; UC1.F40 v2(110.09,109.54) UC1.F38 ; UT5.E8 32.02,82.35 v2(32.1,82.43) ; UT5.E8 UT5.E7 ; UT5.E8 UT5.D8 32.69,81.8 v2(32.99,81.8) 33.35,81.8 UT5.B8 ; UT5.E8 UT5.F8 ; UT5.E7 UT5.E6 ; UC1.BA2 131.96,91.32 132.35,91.21 UC1.BA1 ; UT5.A6 34.48,80.97 v2(34.57,81.06) ; UT5.F8 v2(31.52,82.43) ; UT5.A8 34.47,81.97 v2(34.64,81.8) 34.5,81.67 34.21,81.67 UT5.A7 UT5.B7 ; UC1.AM68 94.06,96.46 94.09,96.43 94.09,96.13 94.06,96.1 UC1.AP68 94.06,95.23 94.09,95.2 94.09,94.91 94.06,94.88 UC1.AT68 94.06,94.07 94.11,93.9 94.11,93.72 94.06,93.67 94.06,93.3 UC1.AV68 ; UC1.AM68 94.06,97.33 94.15,97.42 94.15,97.69 93.74,98.1 UC1.AK68 93.8,98.17 v2(94.14,98.51) 94.14,98.63 94.39,98.87 UC1.AH67 ; UC1.AM68 94.25,96.94 v2(94.55,96.64) ; UT5.H5 30.09,80.05 v2(30.05,80.05) ; UC1.AF1 132.23,100 132.94,100 v2(133.06,100.13) ; UC1.AV68 93.87,93.29 93.68,93.1 ; v2(34.45,78.17) 34.32,78.17 UT5.A1 ; v2(90.94,107.49) 91.36,107.49 91.61,107.74 UC1.K71 ; UC1.AL52 103.69,98.1 103.39,98.4 v2(103.39,98.49) ; UT5.L1 28.85,78.47 v2(28.6,78.22) ; UC1.P20 120.93,105.26 120.49,105.26 UC1.P21 ; v2(101.86,98.22) UC1.AL55 ; v2(100.04,98.22) UC1.AL58
  BOTTOM w0.254: v2(109.16,110.2) 108.98,110.2 UC1.F42 ; UC1.B53 v2(102.31,111.84) UC1.D53 102.1,111.11 102.1,110.79 102.29,110.59 UC1.E53 102.78,110.13 102.78,109.75 UC1.G52 ; DT9.2 11.95,103.92 12.22,104.19 v2(12.22,104.49) ; DT9.2 11.4,103.92 v2(11.06,104.25) ; DT9.2 v2(11.64,104.6) ; JEDP1.39 v2(70.25,133.81) ; JXDP1.7 101.71,131 101.43,131.29 v2(101.43,131.8) 101.41,131.82 JXDP1.8 ; v2(99.12,109.54) UC1.G58 ; v2(239.2,72.23) 239.43,72.23 239.76,71.9 JNGFF1.36 ; UC1.BB70 91.21,90.69 v2(91.01,90.88) 91.28,91.15 UC1.BA71 ; UC1.AW14 v2(124.43,92.44) UC1.BA14 ; UC1.R13 125.42,105.62 v2(125.42,105.85) 125.42,106.11 UC1.N13 ; v2(119.28,109.6) 119.58,109.29 UC1.G22 119.63,109.22 119.63,108.43 UC1.K22 ; v2(119.28,109.6) UC1.F22 ; v2(119.28,109.6) 119.13,109.6 UC1.F23 ; DT5.2 v2(11.71,111.62) ; DT5.2 11.43,110.84 v2(11.08,111.19) ; DT5.2 11.74,110.84 v2(12.26,111.37) ; UC1.AR45 v2(106.44,94.74) UC1.AR46 ; v2(104.82,90.33) 104.74,90.41 UC1.BA49 ; JXDP1.61 85.51,130.39 85.73,130.61 ; UC1.AW53 v2(102.34,92.45) UC1.BA53 ; PU200.4 v2(69.81,70.66) ; UC1.AN20 121.52,96.39 v2(121.08,95.94) 121.1,95.94 UC1.AP20 v2(121.98,95.37) ; UC1.D14 v2(124.61,111.81) UC1.B14 ; v2(96.38,96.01) 96.56,96.16 96.58,96.16 96.72,96.31 UC1.AN63 ; v2(96.01,105.8) UC1.N65 ; v2(129.94,119.64) 129.94,117.75 130.51,117.19 v2(131.81,117.19) 131.92,117.29 v2(133.84,117.29) 135.12,118.58 v2(135.12,119.66) 134.65,120.14 134.65,123.36 134.37,123.64 130.44,123.64 130.2,123.4 130.2,120.2 CC335.2 ; JXDP1.2 103.2,132.69 103.2,131.8 v2(103.21,131.79) 104.16,130.84 JXDP1.62 ; UC1.C25 117.69,111.86 117.29,111.86 ; UZ12.32 156.15,111.72 v2(155.79,112.08) ; UC1.AM60 98.52,97.05 98.45,97.12 97.82,97.12 UC1.AM61 ; UC1.D26 117.22,111.36 ; 117.22,111.36 117.29,111.44 117.29,111.86 ; 117.22,111.36 UC1.D25 ; UC1.AW6 129.27,92.92 v2(129.27,92.42) UC1.BA6 UC1.BB6 ; UC1.AB18 122.34,101.89 v2(122.01,101.57) 122.01,101.5 UC1.AD19 ; v2(121.99,104.08) 121.99,104.17 UC1.T18 122.34,104.71 UC1.P19 ; UC1.AL38 111.01,98.22 v2(111.13,98.34) ; v2(160.6,111.49) 160.83,111.72 UZ12.9 ; v2(122.04,90.09) 121.94,90.19 121.94,90.94 UC1.BB18 ; v2(127.47,110.18) UC1.F8 128.19,109.94 UC1.E6 ; UC1.F33 113.33,109.94 v2(113.66,109.6) 114,109.94 UC1.F32 ; UC1.D66 v2(94.87,111.84) UC1.B66 ; UC1.E71 91.24,110.9 v2(91.1,111.03) ; UC1.L4 130.64,107.64 v2(130.93,107.64) 131.26,107.64 UC1.L2 ; UC1.AL66 95.04,97.13 v2(94.55,96.64) ; UC1.B22 UC1.D22 v2(120.15,110.83) 120.35,110.83 120.59,110.59 UC1.E21 ; UC1.F68 UC1.D69 93.01,110.97 v2(93.01,110.97) ; UC1.E56 v2(100.03,110.81) ; UC1.AP70 v2(93.45,95.67) UC1.AP68 ; JXDP1.14 99.61,131.82 v2(99.63,131.8) 99.63,131.24 99.91,130.96 JXDP1.13 ; UC1.K70 UC1.K68 UC1.K67 v2(94.75,107.65) ; 114.67,92.45 114.58,92.54 UC1.AW32 ; 114.67,92.45 114.58,92.36 UC1.BA32 ; 114.67,92.45 v2(114.67,92.46) ; 85.73,130.61 86.11,130.23 JXDP1.59 ; 85.73,130.61 85.21,131.13 v2(85.21,131.65) ; UC1.G10 127.01,109.27 v2(127.47,108.81) ; UC1.AM61 UC1.AK63 v2(96.64,98.48) ; UC1.AM61 v2(97.29,96.66) ; UC1.AP18 122.41,95.73 v2(121.98,95.37) ; UC1.AR55 v2(100.95,94.78) ; UC1.AW41 v2(109.63,92.45) UC1.BA41 ; v2(94.06,102.14) UC1.AA68 ; UC1.F35 112.37,109.94 111.99,109.56 v2(111.97,109.56) 111.85,109.56 111.47,109.94 UC1.F37 ; v2(128.69,100.61) 128.69,100.65 128.38,100.96 UC1.AD8 128.38,101.18 128.7,101.49 v2(128.7,101.73) 128.7,101.85 128.41,102.13 UC1.AB8 ; UC1.K66 v2(95.34,107.65) UC1.K65 v2(95.99,107.65) UC1.K64 UC1.K63 ; UC1.AR63 v2(96.38,94.74) UC1.AT63 ; v2(55.73,97.6) 55.95,97.37 56.44,97.37 ; UC1.AF17 123.28,100.62 v2(123.28,100.73) 123.28,100.81 UC1.AD16 ; v2(114.67,98.22) UC1.AL32 ; RC4.2 138.1,96.2 140.67,96.2 v2(140.72,96.25) ; UC1.B62 97.35,111.85 v2(97.36,111.85) 97.36,111.33 UC1.D62 ; RC122.2 98.11,128.06 JXDP1.19 98.11,130.98 97.83,131.26 97.83,131.8 v2(97.83,131.8) 97.81,131.82 JXDP1.20 ; UC1.B18 v2(122.13,111.81) UC1.D18 ; JNGFF1.51 v2(232.04,68.15) ; CT67.2 33.28,90.23 v2(33.21,90.17) ; v2(122.03,110.86) 122.41,110.68 UC1.E18 ; UC1.B10 UC1.D10 UC1.D11 126.34,111.36 v2(125.99,111.12) 125.99,110.87 126.1,110.77 UC1.E11 ; UC1.AM55 101.41,97.02 100.99,96.66 v2(100.95,96.66) ; v2(100.95,109.54) UC1.G55 ; UC1.AB16 123.64,102.09 v2(123.98,102.43) 124.29,102.12 UC1.AB15 ; UC1.D30 114.47,111.55 v2(114.47,111.82) 114.47,112.11 UC1.B30 ; JXDP1.32 94.23,132.69 v2(94.23,131.8) 94.23,131.16 94.51,130.87 JXDP1.31 ; UC1.AU15 123.83,93.48 v2(123.78,93.14) ; UC1.U69 v2(92.76,103.97) UC1.U70 ; UC1.N6 129.69,106.09 v2(129.41,105.81) ; UC1.AW28 v2(117.09,92.45) UC1.BA28 ; v2(92.58,100.77) UC1.AE69 UC1.AE68 UC1.AE67 UC1.AE66 UC1.AE65 UC1.AE64 96.91,99.96 UC1.AF63 ; v2(61.11,114.31) 60.36,115.06 PU614.4 ; v2(111.78,119.7) 111.75,119.73 v2(111.75,121.28) 111.75,122.77 111.87,122.9 115.92,122.9 116.08,122.74 116.08,119.57 v2(115.97,119.47) ; UC1.AL28 116.5,98.19 v2(116.42,98.26) ; v2(110.14,93.47) 110.55,93.77 UC1.AU38 ; v2(104.61,109.54) UC1.G48 ; JEDP1.25 v2(63.25,133.81) ; v2(91.06,91.8) UC1.AY71 ; v2(99.12,96.01) UC1.AN58 ; 117.29,111.86 v2(117.29,111.86) ; CC33.2 89.11,128.67 v2(89.11,128.79) ; UC1.AT42 v2(108.27,94.74) UC1.AR42 ; DT6.2 12.13,109.27 v2(12.46,108.94) ; DT6.2 11.41,108.98 v2(11.41,108.7) ; DT6.2 11.93,109.05 v2(11.93,108.41) ; UC1.AW18 v2(122.01,92.27) UC1.BA18 ; UC1.AF2 UC1.AF1 ; v2(120.03,102.4) 120.39,102.05 UC1.AB21 ; UC1.V16 123.98,104.02 v2(123.98,104.1) 123.98,104.21 UC1.T15 ; UC1.AN37 v2(111.01,96.01) UC1.AN38 ; v2(112.84,96.01) UC1.AN33 ; v2(126.79,100.61) 126.79,100.3 UC1.AF10 ; UC1.AH63 v2(96.64,98.48) ; v2(96.64,98.48) UC1.AH64 ; PR506.2 171.76,69.64 171.76,69.07 172.14,68.69 172.14,68.33 v2(172,68.19) ; CC21.2 115.52,118.8 115.57,118.8 115.82,118.55 115.82,116.05 v2(115.35,115.57) 114.38,115.57 114.02,115.94 113.78,115.94 111.97,117.74 111.97,118.67 112.11,118.81 112.24,118.81 CC22.2 ; UC1.AM13 125.22,97.05 125.47,97.3 v2(125.63,97.3) 125.74,97.3 UC1.AK11 ; UC1.P17 UC1.T17 122.67,104.21 v2(122.67,104.08) ; UC1.E15 v2(124.71,110.21) UC1.F13 ; UC1.BA62 v2(97.38,92.45) UC1.AW62 ; v2(106.47,109.55) 106.63,109.55 UC1.G45 ; v2(103.69,111) 104.1,110.59 UC1.E50 ; v2(160.6,108.44) 160.83,108.22 UZ12.16 ; CT99.2 10.86,108.41 v2(10.98,108.29) ; UC1.AP38 v2(110.09,96.02) ; v2(119.92,103.4) 120.39,102.94 UC1.Y21 UC1.Y20 121.15,102.74 121.58,102.74 UC1.Y19 ; v2(100.04,94.1) UC1.AT56 ; UC1.A67 94.2,113.49 93.78,113.91 v2(93.78,114.09) ; v2(107.15,92.45) UC1.BA45 ; v2(129.28,98.47) 129.69,98.87 UC1.AH6 129.88,99.12 v2(129.88,99.54) 130.2,99.86 UC1.AF4 ; v2(118.32,96.01) UC1.AN23 ; UC1.U66 v2(94.71,103.97) UC1.U67 ; JXDP1.38 92.43,132.69 v2(92.43,131.8) 92.43,131.08 92.71,130.79 JXDP1.37 ; v2(232.1,80.48) 232.51,80.48 232.68,80.65 JNGFF1.1 ; 58.3,133.93 58.25,133.88 JEDP1.15 ; UC1.AK27 116.95,98.45 116.41,98.99 v2(116.41,99.03) ; DT10.2 11.89,102.35 v2(12.27,101.97) ; DT10.2 11.34,102.35 11.06,102.07 v2(11.06,102.04) ; DT10.2 v2(11.64,101.59) ; v2(111.92,96.01) UC1.AN35 ; UC1.V17 122.99,103.53 v2(122.7,103.24) ; UC1.G5 129.6,109.13 129,109.13 UC1.G6 128.4,109.52 v2(128.39,109.53) ; UC1.BA2 UC1.AY3 130.75,92.35 v2(130.66,92.35) ; UC1.G63 96.83,109.35 v2(97.2,108.98) 97.75,108.43 UC1.K61 ; JXDP1.50 88.83,132.69 v2(88.83,131.8) 88.83,131.51 89.11,131.22 JXDP1.49 ; UC1.AL48 105.98,97.07 UC1.AM46 105.98,96.97 105.62,96.66 v2(105.52,96.66) ; v2(232.23,78.97) 232.41,79.15 JNGFF1.7 ; v2(98.26,109.59) 98.36,109.59 UC1.G60 ; JXDP1.25 96.31,130.85 96.03,131.14 v2(96.03,131.8) 96.03,132.69 JXDP1.26 ; UC1.AT58 v2(99.12,94.74) UC1.AR58 ; UC1.AN28 v2(115.58,96.01) UC1.AN30 ; UC1.AR35 v2(111.92,94.74) UC1.AT35 ; UC1.AK68 93.56,98.35 93.25,98.35 93.07,98.17 UC1.AK69 ; UC1.F2 131.14,110.47 v2(130.93,110.25) 130.72,110.47 UC1.F4 ; UC1.AT4 130.59,94.43 v2(130.95,94.43) 131.08,94.56 UC1.AT2 ; UC1.AW57 v2(99.86,92.45) UC1.BA57 ; v2(106.44,96.66) UC1.AM45 106.96,97.05 107.35,97.45 ; UC1.AL2 131.2,97.45 v2(130.89,97.45) ; v2(104.61,94.74) UC1.AR48 ; UC1.AA65 v2(96.01,102.14) ; UC1.D34 v2(112.22,111.85) UC1.B34 ; UC1.AL4 130.65,97.21 v2(130.89,97.45) ; UC1.A5 130.6,113.77 v2(131.09,113.77) ; CT101.2 CT102.2 10.43,104.61 v2(10.55,104.49) ; v2(130.89,97.45) UC1.AJ4 ; UC1.U64 v2(96.66,103.97) UC1.U63 ; v2(94.24,109.54) UC1.G66 ; UC1.E46 105.73,110.84 105.6,110.84 v2(105.58,110.86) 105.58,110.99 105.46,111.11 UC1.D47 105.02,111.81 105.02,112.11 104.82,112.31 104.81,112.31 UC1.B48 ; UC1.B44 v2(107.26,111.84) UC1.D44 ; CZ54.2 157.25,104.86 v2(156.88,104.49) ; UC1.AN32 v2(114.67,96.02) ; v2(115.58,95.37) UC1.AP28 ; v2(113.75,93.45) UC1.AU32 ; v2(53.75,131.65) JEDP1.6 53.75,133.91 53.73,133.93 ; UC1.AL35 v2(112.84,96.66) ; UC1.V18 122.34,103.6 v2(122.7,103.24) ; UC1.AM8 128.38,97.51 UC1.AK8 128.38,98.19 v2(128.13,98.45) ; UC1.AP42 v2(108.27,95.37) UC1.AR43 ; v2(122.7,103.24) 122.99,102.95 UC1.Y17 ; UC1.W6 v2(129.96,102.71) 130.16,102.51 UC1.AA4 UC1.AA2 ; UC1.AT28 v2(115.58,94.74) UC1.AR28 ; v2(13.22,106.56) DT40.3 ; UZ12.23 v2(157.83,106.58) ; UC1.AW36 v2(112.11,92.45) UC1.BA36 ; v2(111.92,95.37) UC1.AP35 ; UC8.7 81.05,122.3 v2(81.3,122.55) ; UC1.L8 v2(128.67,106.86) ; v2(116.5,96.66) UC1.AM27 UC1.AM25 ; UC1.T21 120.25,104.52 v2(119.9,104.18) ; UC1.T2 UC1.T4 130.4,105.16 130.08,104.85 v2(130.08,104.85) UC1.R6 ; UC1.BA23 v2(119.57,92.45) UC1.AW23 ; UC1.AR53 v2(101.86,94.78) ; UC1.AR15 v2(123.81,94.74) 123.72,94.74 UC1.AR16 ; UC1.D58 v2(99.83,111.84) UC1.B58 ; v2(96.38,95.37) UC1.AP63 ; PU200.15 65.57,70.21 v2(65.53,70.25) ; 54.84,133.93 54.75,133.85 JEDP1.8 v2(54.75,131.65) ; v2(121.98,95.37) 121.8,95.37 UC1.AR20 v2(121.07,94.74) 121.35,94.45 UC1.AT20 UC1.AU20 121.52,93.02 121.55,92.99 ; UC1.B71 91.59,113.05 v2(91.59,113.37) 92.19,113.37 UC1.A70 ; v2(39.24,79.8) 39.54,80.1 CT1.2 ; RC136.2 83.99,124.54 v2(83.99,123.96) ; 107.35,97.45 107.35,97.43 107.72,97.05 UC1.AM43 ; 107.35,97.45 UC1.AL45 ; UC1.P20 121.08,105.36 121.35,105.63 v2(121.35,105.76) 121.69,106.09 UC1.N19 121.69,106.25 v2(122.02,106.67) 122.3,107.04 UC1.L18 122.43,106.94 122.89,106.94 UC1.L17 v2(123.31,106.57) UC1.L16 123.49,107.18 123.49,107.73 UC1.K16 124.27,108.51 UC1.H15 124.53,108.64 UC1.J13 125.18,108.01 v2(125.61,108.27) 126.07,107.99 UC1.J11 126.1,107.68 UC1.L11 126.71,107.07 v2(126.71,106.8) 127.08,106.43 UC1.N10 ; UC1.AP32 v2(114.67,95.37) ; v2(52.75,131.65) JEDP1.4 52.75,133.93 52.75,133.93 ; v2(95.26,110.81) UC1.E65 ; v2(120.15,96.81) 120.4,97.05 UC1.AM21 ; UC1.J42 v2(108.27,108.14) ; UC1.AR23 v2(118.32,94.74) UC1.AT23 ; v2(125.54,102.65) 125.54,102.79 UC1.W13 ; v2(91.06,92.92) 91.24,93.1 UC1.AV71 UC1.AV70 UC1.AV69 v2(93.57,93.1) 93.68,93.1 ; v2(94.06,105.8) UC1.N68 ; v2(119.91,105.1) 119.91,105.73 UC1.N21 120.59,106.41 120.59,106.54 121.04,106.98 UC1.L20 ; UC1.AR50 v2(103.71,94.78) UC1.AR52 v2(102.78,94.78) ; UC1.U10 127.08,103.85 UC1.W9 v2(128.07,102.7) ; v2(115.67,109.63) 115.67,109.69 115.93,109.94 UC1.F28 116.3,110.2 116.69,110.2 UC1.F27 ; UC1.AR11 126.24,95.25 v2(126.55,95.25) 127.01,95.63 UC1.AP10 127.33,95.44 127.59,95.44 UC1.AR8 ; JEDP1.23 v2(62.25,133.81) ; v2(127.47,108.23) UC1.J8 ; CZ53.2 v2(164.15,107.71) ; v2(99.12,95.37) UC1.AP58 ; v2(97.94,101.22) UC1.AD62 ; v2(121.92,108.93) UC1.H18 UC1.K18 ; v2(109.18,96.01) UC1.AN40 ; v2(129.3,94.74) UC1.AR5 ; v2(118.32,95.37) UC1.AP23 ; v2(108.27,96.01) UC1.AN42 ; v2(94.2,90.16) UC1.BB67
  BOTTOM w0.305: v2(231.55,101.97) 231.28,102.25 JNGFF2.31 ; JNGFF2.65 229.26,93.75 v2(229.14,93.62) ; v2(230.45,56.85) JUSH1.7 ; PR412.1 v2(136.99,133.36) ; v2(212.6,59.83) 212.55,59.78 JKBTP1.4 212.55,58.45 212.28,58.18 212.28,58.18 211.83,58.18 211.55,58.46 JKBTP1.6 ; v2(96.38,96.64) 96.34,96.69 UC1.AL64 ; v2(231.17,73.81) 231.33,73.65 JNGFF1.29 ; JNGFF3.51 16.45,44.63 16.63,44.81 v2(16.63,45.03) ; UC1.AB21 UC1.AD21 120.48,101.26 120.95,101.26 UC1.AD20 ; JNGFF1.24 238.85,74.9 v2(238.1,75.65) ; JNGFF2.43 231.22,99.25 231.39,99.43 v2(231.57,99.43) ; JNGFF3.9 v2(26.95,45.03) ; JDB1.6 27.88,67.59 v2(28.15,67.86) ; JNGFF1.18 240.14,76.4 v2(239.37,77.18) ; JNGFF1.63 234.14,65.15 234.47,65.48 v2(234.47,65.87) ; JNGFF3.21 v2(23.95,45.03) ; JXDP1.63 84.86,131.3 v2(85.21,131.65) ; JNGFF3.33 v2(20.95,45.03) ; JNGFF3.15 v2(25.45,45.03) ; JNGFF2.5 231.21,110.75 231.41,110.95 v2(231.61,110.95) ; v2(231.85,97.62) 231.72,97.75 JNGFF2.49 ; v2(221.95,55.92) 221.95,55.92 JUSH1.24 ; JNGFF2.11 231.21,109.25 231.35,109.1 v2(231.61,109.1) ; v2(232.17,69.4) 232.36,69.4 232.61,69.65 JNGFF1.45 ; JNGFF1.75 v2(234.49,62.15) ; JKBTP1.18 205.55,58.44 205.92,58.08 v2(205.92,57.87) ; v2(205.34,57.86) 205.05,58.15 JKBTP1.19 ; JNGFF3.1 28.95,44.73 28.64,45.03 v2(28.45,45.03) JNGFF3.3 ; JKBTP1.1 214.05,59.33 214.45,59.73 v2(214.45,59.82) ; v2(237.95,74.43) 238.97,74.43 240,73.4 JNGFF1.30 ; JNGFF2.3 v2(229.21,111.25) ; JUSH1.6 230.95,56.93 v2(231.04,56.85) ; JNGFF1.33 v2(234.5,72.65) ; JNGFF3.57 14.95,44.71 14.8,44.86 v2(14.8,45.03) ; JNGFF3.45 v2(17.95,45.03) ; JNGFF2.19 231.28,105.25 v2(231.61,105.57) ; v2(228.8,56.85) 228.95,57 JUSH1.10 ; JKBTP1.12 v2(208.55,59.84) ; JNGFF2.63 v2(229.14,94.25) ; JUSH1.25 v2(221.45,56.66) ; v2(243.45,55.54) JESPI.9 ; JNGFF3.27 v2(22.45,45.03) ; JNGFF3.39 v2(19.45,45.03) ; JNGFF2.37 v2(231.61,100.75) ; v2(231.68,70.96) 232.07,71.35 232.43,71.35 232.62,71.15 JNGFF1.39 ; JNGFF1.57 v2(234.5,66.65) ; v2(232.24,103.91) 232.02,103.69 231.26,103.69 231.2,103.75 JNGFF2.25 ; v2(290.41,121.36) 290.41,121.61 290.64,121.84 JDEG1.10 ; JNGFF1.23 v2(231.85,75.15) ; v2(234.49,63.65) JNGFF1.69
  BOTTOM w0.356: CC30.2 v2(84.01,121.38) ; CC9.2 152.04,103.04 v2(152.11,103.1) ; v2(8.77,111.8) 8.79,111.78 CT100.2 ; UL2.3 v2(255.7,131.44) ; CL15.2 v2(252,133.61) ; v2(152.51,96.14) 152.3,95.93 CC10.2 ; v2(159.47,113.4) 160.22,113.4 CZ50.2 160.56,114.27 CZ75.2
  BOTTOM w0.381: v2(247.55,124.66) 247.25,124.95 CL9.2 ; RT86.2 33.03,86.48 v2(33.08,86.52) ; PU1201.4 42.39,54.09 v2(42.54,54.24) ; RC227.2 151.18,117.98 151.18,118.67 150.68,119.16 149.02,119.16 148,118.15 v2(148,117.92) ; CC312.2 CC321.2 94.5,118.54 94.42,118.46 94.42,117.96 v2(94.7,117.68) ; v2(51.46,50.68) 51.25,50.48 PQ1210.4 ; PQ1207.4 v2(45.53,51.78) ; v2(288.82,123.84) 289.28,123.38 RE86.2 ; PR653.1 53.72,96.51 v2(54.51,97.29) ; PC602.2 42.35,92.53 v2(41.8,93.08) ; v2(150.08,115.84) 150.61,115.31 UC12.3 ; v2(55.99,118.39) 56.85,119.25 PU1.3 ; PC944.2 55.7,52.11 v2(55.7,51.45) ; v2(115.97,119.47) 115.71,119.2 115.33,119.2 CC21.2 ; PC677.2 55.23,97.6 v2(55.73,97.6) ; CL8.2 CL3.2 v2(249.71,129.04) ; PC949.1 45.25,54.35 v2(45.5,54.1) PU903.3 ; CT83.2 29.95,75.68 RT96.2 29.95,74.05 v2(29.88,73.99) ; v2(34.45,78.17) 34.98,77.63 CT72.2 ; v2(40.54,107.76) 40.54,107.05 PQ1204.1 ; PU1200.3 v2(36.73,61.3) 36.35,61.68 36.35,63.07 35.98,63.43 PC1204.2 ; RT37.2 40.18,104.6 39.16,105.62 v2(38.56,105.62) 38.87,105.94 41.51,105.94 41.89,105.57 PQ1204.4 ; v2(111.78,119.7) 111.78,119.49 112.08,119.2 112.43,119.2 CC22.2 ; PR948.2 58.61,53.03 59.57,52.07 v2(59.88,52.07) ; v2(44.94,50.48) PQ1207.1 43.83,50.48 43.56,50.75 43.56,51.37 43.15,51.78 PQ1208.4 ; RC268.2 136.63,98.13 136.42,97.93 134.76,97.93 134.42,98.28 v2(134.42,98.45) ; v2(40.32,95.6) 40.65,95.6 41.33,96.28 PC603.2 PC604.2 ; v2(97.18,122.14) CC305.2 ; PQ1208.1 v2(41.68,50.48) ; v2(236.97,85.29) 237.41,85.73 QE2.4 ; v2(239.15,83.15) 238.86,83.43 QE2.1 ; PQ1210.1 v2(53.3,51.78) ; UZ35.3 v2(126.23,131.82) ; CI7.2 v2(18.24,54.09)
  BOTTOM w0.406: UC7.3 v2(155.93,118.49)
  BOTTOM w0.457: PC1201.1 35.41,58.7 35.09,58.39 v2(35.09,58.24) ; CC318.2 141.21,101.47 v2(141.08,101.6) ; v2(50.49,101.1) 50.96,101.57 PC601.2 ; CC310.2 CC301.2 v2(90,118.25) ; v2(63.84,70.11) 63.59,70.37 PR207.1 ; v2(55.53,101.49) 55.8,101.22 PC679.2 ; RC65.2 156.25,117.73 155.93,118.04 v2(155.93,118.49) ; PR424.2 155.27,131.39 v2(154.84,131.39) ; v2(25.7,87.93) 25.7,87.88 25.21,87.38 CT85.2 ; UC5.4 159.65,91.51 v2(159.47,91.69) ; CC303.2 CC304.2 99.02,119 v2(98.71,118.69) ; v2(280.69,58.9) 280.03,58.9 279.56,59.37 CZ40.2 ; CT73.2 v2(27.52,75.94)
  BOTTOM w0.508: v2(168.6,88.78) JSPI1.22 v2(168.6,90.82) ; JFAN1.1 v2(237.68,122.66) ; JLED1.7 v2(290.11,9.81) ; PC1079.2 84.41,104.52 v2(84.95,105.06) ; PQ909.3 51.73,56.34 PR927.2 51.73,57.7 52.28,58.26 v2(52.88,58.26) ; v2(49.87,131.71) 49.87,131.23 49.39,130.75 JEDP1.41 48.85,134.22 49.46,134.83 50.84,134.83 51.74,133.93 v2(59.46,133.93) v2(60.09,133.93) 60.22,133.81 v2(62.25,133.81) v2(63.25,133.81) v2(64.75,133.81) 64.75,134.07 65.19,134.5 66.64,134.5 67.33,133.81 v2(70.25,133.81) 70.37,133.93 v2(71.91,133.93) 72.48,133.93 73.15,133.26 JEDP1.45 ; v2(232.13,81.07) 232.81,81.75 JNGFF1.77 ; v2(71.77,130.5) 71.45,130.18 71.45,129.31 70.93,128.8 JEDP1.44 ; CE32.2 v2(240.31,118.17) ; JRTC1.4 v2(286.5,4.3) ; PC1024.2 v2(83.01,98.39) ; v2(84.48,120.47) RC109.2 CC300.2 ; YT1.2 v2(22.29,89.18) ; v2(22.29,89.18) 22.29,86.59 22.03,86.33 v2(19.42,86.33) ; v2(22.29,89.18) 23.71,89.18 23.71,89.18 ; v2(22.29,89.18) 22.3,89.19 v2(22.3,90.42) ; PC1023.2 v2(81.77,98.37) ; v2(148.02,89.48) 148.4,89.86 CC316.2 ; v2(17.83,87.23) 17.83,86.6 18.1,86.33 v2(19.42,86.33) ; v2(17.83,87.23) 17.97,87.38 YT1.4 ; v2(17.83,87.23) 16.44,87.23 ; RT28.2 30.38,109.37 v2(29.87,109.88) 29.87,110.48 PJPDC1.6 ; v2(13.89,94.73) 13.42,95.2 CV41.2 13.23,95.72 13.74,96.22 UV2.2 ; CT20.2 v2(22.3,90.42) ; v2(22.3,90.42) 23.71,90.42 ; RC554.2 147.05,104.42 v2(147.67,104.42) ; v2(282.95,61.48) 282.66,61.48 282.07,62.07 JSIM1.5 ; RC139.2 87.8,127.83 v2(87.8,125.73) 87.8,125.48 88.82,124.46 RC219.2 ; PR103.2 v2(181.38,59.83) ; RT99.1 35.8,85.9 v2(35.33,86.37) ; PQ6.3 50.9,119.82 v2(50.57,120.15) 50.73,120.32 50.73,121.71 51.52,122.5 53.21,122.5 53.9,121.8 PR30.2 ; CZ3.2 38.49,127.29 JIR1.8 v2(35.43,128.95) ; v2(26,85.42) 25.55,85.42 25.23,85.1 CT86.2 ; v2(218.45,53.26) 218.62,53.44 JUSH1.27 ; DI5.1 279.8,79.27 279.98,79.45 v2(279.98,80.01) ; PC1070.2 v2(81.81,105.04) ; v2(256.73,124.29) 255.55,124.29 CL22.1 255.57,124.95 v2(256.74,124.95) ; JSIM1.6 v2(282.02,51.82) ; JEDP1.43 61.97,128.8 v2(63.18,130.01) ; v2(292.25,47.71) 292.25,47.41 293.14,46.52 CA13.1 ; PC1061.2 v2(76.22,112.91) ; DA6.1 v2(281.46,23.76) ; v2(18.3,91.14) 18.3,90.9 18.78,90.43 CT21.2 ; RC556.2 143.47,108.27 v2(143.99,107.75) ; RT33.2 v2(27.71,109.92) ; JESPI.11 250.21,51.7 v2(250.47,51.45) ; RC401.2 v2(138.36,108.28) RC372.2 ; v2(22.16,74.06) 21.68,74.55 CT94.2 ; v2(24.3,110.2) 23.79,109.68 RT36.2 ; PQ1212.3 34.35,60.26 33.87,60.74 v2(33.54,60.74) ; DA3.1 291.23,45.22 v2(291.55,44.91) ; v2(159.76,117.79) 160.48,117.79 CZ59.2 CZ60.2 ; RC110.2 RC112.2 86.32,120.42 RC113.2 86.56,121.42 v2(86.31,121.67) ; PC1009.2 v2(83.02,107.9) ; CZ56.2 160.96,104.56 v2(160.38,103.98) ; JDB1.7 v2(32.48,62.24) ; PC1071.2 v2(80.61,107.9) ; v2(83.02,105.21) 83.01,105.2 PC1006.2 ; RC338.2 RC337.2 v2(137.88,113.17) ; v2(244.43,119.52) 243.79,120.16 QZ4.3 ; v2(152.67,80.36) PR116.2 152.48,79.69 PC692.2 ; UT2.4 42.57,88.92 v2(43.78,88.92) ; v2(276.81,58.48) 276.81,58.02 277.24,57.59 RZ334.2 ; v2(20.85,66.5) 20.85,66.81 20.92,66.88 UT7.2 ; DI2.1 v2(21.99,59.42) ; JSIM1.C5 v2(298.67,61.35) ; v2(19.42,86.33) 19.42,84.9 ; v2(176.59,67.6) 176.17,67.19 PC505.2 PR505.2 ; JESPI.12 v2(241.67,51.7) ; v2(281.46,19.63) 280.95,19.63 280.76,19.82 DA7.1 ; PC690.2 57.43,70.04 56.72,70.75 56.72,70.83 ; RT103.2 27.57,87.39 28.47,87.39 28.47,87.74 28.27,87.95 28.27,88.56 v2(27.91,88.91) ; v2(147.37,114.51) 147.71,114.17 CC302.2 ; PC1069.2 v2(80.61,105.04) ; v2(63.84,70.11) 63.57,69.85 PC206.2 ; RT64.2 RT65.2 37,84.35 v2(37.81,84.35) ; JKBTP1.22 202.22,54.65 v2(202.36,54.51) ; v2(159.47,97.42) UC6.4 ; v2(153.45,111.93) CZ58.2 CZ57.2 ; JNGFF1.76 234.15,60.27 v2(233.83,59.95) ; JDEG1.12 v2(295.24,128.44) ; v2(165.11,106.76) CZ55.2 164.41,106.56 164.83,106.14 v2(165.09,106.14) ; CA12.2 v2(292.07,44.38) ; JUSH1.28 237.44,53.99 v2(237.44,53.7) ; v2(55.17,95.2) 54.71,94.73 PH601.1 ; CT74.2 v2(36.17,73.9) ; v2(135.12,119.66) 135.11,119.64 CC334.2 ; RC412.1 v2(146.09,107.33) ; v2(48.22,56.63) 48.63,56.22 PR961.2 ; PC1012.2 v2(75.02,112.91) ; CC340.2 144.54,80.18 v2(143.81,79.45) ; JSIM1.7 v2(283.71,50.3) ; JSIM1.8 v2(291.2,47.95) ; v2(291.75,5.29) JLED1.8 ; RZ25.2 284.19,12.58 v2(284.06,12.46) ; PQ1216.3 v2(60.77,50.67) ; JFAN1.5 v2(235.48,125.21) ; v2(62.74,119.07) 63.51,119.07 PC10.2 ; v2(278.53,55.1) CZ39.2 ; v2(281.43,29.27) 281.43,30.05 DA2.1 282.03,30.64 v3(282.03,33.28) 282.03,36.05 DA1.1 ; v2(216.3,53.33) 216.36,53.38 216.36,55.64 JKBTP1.21 ; JSIM1.4 v2(291.02,64.74) ; JFAN1.6 v2(235.48,116.36) ; v2(51.57,130.15) 52.1,129.62 JEDP1.42 ; JUART1.1 v2(128.81,133.15) ; JDEG1.11 v2(292.57,119.74) ; CC307.2 v2(93,127.09) ; JLED1.4 v2(290.73,6.11) ; CL4.2 v2(250.66,130.48) ; v2(138.87,104.58) 139.85,104.58 140.28,105.02 CC319.2 ; JSIM1.3 v2(296.54,64.74) ; v2(52.74,89) 52.4,89.34 PR658.1 ; JRTC1.3 v2(280.15,8.61) ; PC1008.2 v2(73.81,112.91) ; v2(279.87,60.58) 279.3,61.15 CZ37.2 CZ41.2 ; CN64.2 v2(29.68,49.29) ; RZ62.2 v2(154.21,108.64) ; JIR1.7 v2(35.55,133.85) ; v2(133.63,133.93) 132.69,133.93 JUART1.5 132.2,134.06 127.81,134.06 JUART1.6 ; PC1010.2 v2(81.81,107.9) ; JNGFF2.69 v2(229.13,92.15) ; JDB1.8 v2(25.78,65.2) ; JRTC1.2 v2(282.7,8.05) ; RZ38.2 v2(252.42,120)
  vias: v2(0.85,115.12) v2(0.84,98.21) v2(0.87,112.08) v2(0.86,102.22) v2(0.86,100.04) v2(0.86,96.24) v2(2.04,117.57) v2(2.03,115.85) v2(2.04,51.65) v2(2.07,53.16) v2(2.06,47.32) v2(2.06,45.59) v2(2.06,43.86) v2(2.06,42.14) v2(2.06,36.83) v2(2.37,40.75) v2(2.54,96.24) v2(2.49,35.55) v2(2.69,49.5) v2(3.14,71.41) v2(3.12,54.15) v2(3.16,69.71) v2(3.52,117.65) v2(3.49,102.22) v2(3.64,115.6) v2(3.64,98.7) v2(3.65,51.15) v2(3.65,47.85) v2(3.73,112.08) v2(3.78,36.83) v2(4.05,55.22) v2(4.1,96.23) v2(4.1,40.75) v2(4.21,35.55) v2(4.6,117.25) v2(4.6,113.95) v2(4.6,100.35) v2(4.6,97.05) v2(4.77,71.64) v2(4.89,69.71) v2(5.04,73.75) v2(5.05,39.42) v2(5.05,37.69) v2(5.64,110.72) v2(5.64,103.5) v2(5.57,55.21) v2(5.55,51.15) v2(5.55,47.85) v2(5.94,35.55) v2(6.5,117.25) v2(6.5,113.95) v2(6.5,100.35) v2(6.5,97.05) v2(6.5,49.5) v2(6.55,42.51) v2(6.69,74.35) v2(6.7,39.97) v2(7.29,37.96) v2(7.29,37.32) v2(7.45,115.6) v2(7.45,98.7) v2(7.65,76) v2(7.65,72.7) v2(7.67,35.55) v2(8.07,111.24) v2(8.08,103.16) v2(8.23,53.2) v2(8.44,69.71) v2(8.41,55.21) v2(8.53,102.74) v2(8.61,40.77) v2(8.61,39.04) v2(8.9,49.66) v2(8.85,45.41) v2(8.85,44.78) v2(8.99,53.22) v2(9.36,44.33) v2(9.55,76) v2(9.55,72.7) v2(9.61,43.7) v2(10.04,99.17) v2(10.14,116.5) v2(10.07,96.3) v2(10.13,55.21) v2(10.17,69.71) v2(10.5,74.35) v2(10.49,47.2) v2(10.79,51.48) v2(11.01,50.07) v2(11.1,114.85) v2(11.44,53.2) v2(11.9,69.71) v2(11.86,55.21) v2(13,114.85) v2(13.36,54.87) v2(13.77,68.43) v2(13.77,56.59) v2(13.95,116.5) v2(14.09,108.05) v2(14.18,105.2) v2(14.25,72.15) v2(14.78,100.77) v2(14.98,104.35) v2(15.01,103.77) v2(15.01,72.15) v2(15.21,109.34) v2(15.3,83.65) v2(15.31,81.88) v2(15.38,107.16) v2(16,105.65) v2(16.04,101.93) v2(16.27,117.66) v2(16.84,111.95) v2(16.86,111.34) v2(17.29,50.82) v2(17.42,111.92) v2(17.45,111.31) v2(17.64,48.91) v2(17.99,117.66) v2(18.69,49.37) v2(19.04,83.6) v2(19.03,79.96) v2(19.03,78.13) v2(19.23,102.47) v2(19.51,49.44) v2(19.72,117.66) v2(19.98,97.32) v2(19.98,95.61) v2(20.37,95.06) v2(20.37,93.35) v2(20.83,49.43) v2(20.85,65.9) v2(21,50.18) v2(21.3,57.99) v2(21.3,57.35) v2(21.3,56.72) v2(21.45,117.66) v2(21.44,105.85) v2(21.38,105.25) v2(21.42,66.24) v2(21.5,76.39) v2(21.75,79.94) v2(21.75,78.17) v2(22,105.79) v2(22.11,83.64) v2(22.06,52.17) v2(22.06,51.57) v2(22.33,80.89) v2(22.3,50.36) v2(23.14,67.32) v2(23.18,117.66) v2(23.39,63.13) v2(23.47,77.02) v2(23.65,74.27) v2(23.55,50.56) v2(23.77,81.18) v2(23.77,67.32) v2(24.13,101.6) v2(24.14,100.3) v2(24.14,99) v2(24.15,98.36) v2(24.14,97.7) v2(24.35,73.06) v2(24.78,100.3) v2(24.83,60.81) v2(24.9,117.73) v2(24.99,73.06) v2(25.35,127.82) v2(25.35,126.1) v2(25.35,124.37) v2(25.35,122.64) v2(25.35,120.91) v2(25.35,119.19) v2(26.14,90.2) v2(26.24,50.3) v2(26.31,93.58) v2(26.74,99) v2(26.74,98.35) v2(26.74,96.4) v2(26.74,95.75) v2(26.73,84.11) v2(27.07,127.82) v2(27.06,83.61) v2(27.15,126.38) v2(27.15,125.74) v2(27.38,102.25) v2(27.39,95.75) v2(27.56,46.64) v2(27.81,90.3) v2(28.52,90.3) v2(28.8,127.82) v2(29.33,103.53) v2(30.08,90.23) v2(30.23,88.27) v2(30.53,127.82) v2(30.64,97.06) v2(30.57,40.61) v2(30.8,39.04) v2(30.82,35.56) v2(30.9,90.21) v2(31.3,96.4) v2(32.09,37.96) v2(32.09,37.33) v2(32.26,127.82) v2(32.47,90.18) v2(32.55,35.56) v2(32.67,87.74) v2(33.19,47.35) v2(33.65,44.51) v2(33.67,43.06) v2(33.67,41.34) v2(33.67,39.61) v2(33.67,37.88) v2(33.67,36.16) v2(33.93,128) v2(34.24,131.49) v2(34.24,129.77) v2(34.28,134.88) v2(34.28,133.16) v2(34.37,49.4) v2(36,134.88) v2(36.1,101.57) v2(36.29,104.91) v2(36.73,49.4) v2(37.23,132.54) v2(37.23,131.96) v2(37.61,92.73) v2(37.61,92.14) v2(37.73,134.88) v2(37.87,77.72) v2(38.58,99.38) v2(38.66,103.1) v2(38.68,102.03) v2(38.66,49.08) v2(39.46,134.88) v2(40.09,116.79) v2(40.09,116.15) v2(40.32,99.48) v2(40.44,102.54) v2(40.46,85.44) v2(40.47,83.45) v2(40.73,116.79) v2(40.73,116.15) v2(40.66,77.21) v2(40.92,49.08) v2(41.18,134.88) v2(41.2,94.89) v2(41.15,74.03) v2(41.16,73.45) v2(41.36,116.79) v2(41.36,116.15) v2(41.73,74.58) v2(41.72,74.02) v2(41.77,99.77) v2(41.84,78.51) v2(41.79,73.45) v2(42,116.79) v2(42,116.15) v2(42.06,75.05) v2(42.25,101.29) v2(42.42,74.62) v2(42.38,74.03) v2(42.38,73.43) v2(42.46,75.46) v2(42.51,49.08) v2(42.63,116.79) v2(42.63,116.15) v2(42.98,75.74) v2(42.98,75.16) v2(42.99,74.56) v2(42.96,73.97) v2(42.96,73.41) v2(44.23,49.08) v2(45.12,75.87) v2(45.14,75.28) v2(45.12,74.7) v2(45.12,74.11) v2(45.12,73.52) v2(45.31,79.43) v2(45.3,78.86) v2(45.96,49.08) v2(46.19,136.41) v2(46.61,95.69) v2(46.61,94.17) v2(46.61,92.64) v2(47.69,49.08) v2(47.92,136.41) v2(48.13,95.69) v2(48.13,94.17) v2(48.13,92.64) v2(49.41,49.08) v2(49.64,136.41) v2(49.66,95.69) v2(49.66,94.17) v2(49.66,92.64) v2(49.95,78.31) v2(50.54,78.32) v2(50.47,69.41) v2(50.47,68.78) v2(50.47,68.14) v2(50.95,79.97) v2(51.06,69.41) v2(51.06,68.78) v2(51.06,68.14) v2(51.14,49.08) v2(51.37,136.41) v2(51.43,130.76) v2(51.63,80) v2(51.76,85.16) v2(51.84,71.7) v2(51.84,71.07) v2(51.89,85.71) v2(52.33,85.3) v2(52.3,79.98) v2(52.54,71.7) v2(52.54,71.07) v2(52.7,130.81) v2(52.95,105.78) v2(52.95,105.19) v2(52.87,49.08) v2(53.01,79.98) v2(53.1,136.41) v2(53.24,71.7) v2(53.24,71.07) v2(53.5,111.89) v2(53.5,111.3) v2(53.5,110.67) v2(53.5,110.03) v2(53.7,79.97) v2(53.94,71.7) v2(53.94,71.07) v2(54.14,111.89) v2(54.14,111.3) v2(54.14,110.67) v2(54.14,110.03) v2(54.63,109.68) v2(54.6,49.08) v2(54.82,136.41) v2(54.77,111.89) v2(54.77,111.3) v2(54.77,110.67) v2(54.76,90.67) v2(55.01,130.12) v2(55.21,91.45) v2(55.31,109.36) v2(55.36,89.97) v2(55.4,58.15) v2(55.4,57.04) v2(55.4,55.92) v2(55.96,110.07) v2(55.96,108.5) v2(56.01,90.67) v2(56.01,89.11) v2(56.32,49.08) v2(56.41,92.97) v2(56.43,75.34) v2(56.44,74.77) v2(56.44,74.19) v2(56.52,73.54) v2(56.53,72.93) v2(56.54,72.36) v2(56.52,58.15) v2(56.52,57.04) v2(56.52,55.92) v2(56.55,136.41) v2(57.05,92.97) v2(57.26,110.07) v2(57.26,108.5) v2(57.31,90.67) v2(57.31,89.11) v2(57.62,92.97) v2(57.64,58.15) v2(57.64,57.04) v2(57.64,55.92) v2(57.69,131.42) v2(57.75,96.52) v2(58.01,105.28) v2(58.05,49.08) v2(58.19,92.97) v2(58.28,136.41) v2(58.56,110.07) v2(58.56,108.5) v2(58.63,103.01) v2(58.63,102.35) v2(58.63,101.69) v2(58.61,90.67) v2(58.61,89.11) v2(58.75,130.11) v2(58.76,92.97) v2(58.94,107.36) v2(58.9,99.49) v2(58.9,98.2) v2(58.9,96.9) v2(58.89,94.44) v2(58.9,83.8) v2(58.99,87.97) v2(59.33,92.97) v2(59.41,109.72) v2(59.46,90.33) v2(59.75,100.14) v2(59.78,49.08) v2(59.9,94.12) v2(59.9,93.55) v2(59.9,92.97) v2(60.01,136.41) v2(60.03,103.2) v2(59.99,102.63) v2(59.99,102.06) v2(60.03,101.48) v2(60.11,96.05) v2(60.54,102.44) v2(60.54,101.86) v2(60.46,99.49) v2(60.46,98.2) v2(60.46,96.9) v2(60.48,94.12) v2(60.48,93.55) v2(61.5,49.08) v2(61.73,136.41) v2(62.25,108.41) v2(62.32,89.23) v2(62.86,131.74) v2(63.23,49.08) v2(63.3,131.37) v2(63.46,136.41) v2(63.52,102.94) v2(63.68,66.53) v2(63.83,64.01) v2(63.8,63.36) v2(63.85,62.32) v2(63.85,61.73) v2(64.29,117.1) v2(64.44,62.32) v2(64.44,61.73) v2(64.74,51.15) v2(64.92,117.1) v2(64.88,81.93) v2(65.19,136.41) v2(65.47,81.93) v2(65.61,123.25) v2(65.56,117.1) v2(65.92,53.2) v2(65.92,49.1) v2(66,56.69) v2(66.13,117.1) v2(66.05,81.93) v2(66.22,123.25) v2(66.35,104.74) v2(66.35,128.29) v2(66.39,105.34) v2(66.64,81.93) v2(66.58,56.69) v2(66.76,117.1) v2(66.91,136.41) v2(67.07,105.34) v2(67.08,104.76) v2(67.17,56.69) v2(67.4,117.1) v2(67.61,74.75) v2(67.61,74.14) v2(67.61,73.54) v2(67.84,72.97) v2(67.75,56.69) v2(68.04,71.85) v2(68.04,71.27) v2(68.29,130.62) v2(68.34,56.69) v2(68.28,53.2) v2(68.28,49.1) v2(68.46,76.06) v2(68.48,72.97) v2(68.64,136.41) v2(68.67,75.39) v2(68.92,56.69) v2(69.12,76.08) v2(69.14,74.88) v2(69.14,74.24) v2(69.14,73.61) v2(69.11,72.97) v2(69.37,75.45) v2(69.46,51.15) v2(69.66,73.31) v2(70.06,130.62) v2(70.37,136.41) v2(70.9,49.08) v2(71.31,70.83) v2(71.89,70.67) v2(71.92,70.06) v2(72.04,103.05) v2(72.04,102.42) v2(72.04,101.78) v2(72.1,136.41) v2(72.65,103.05) v2(72.65,102.42) v2(72.65,101.78) v2(72.63,49.08) v2(73.07,119.5) v2(73.39,87.07) v2(73.68,70.29) v2(73.68,69.66) v2(73.82,136.41) v2(73.92,119.49) v2(73.99,87.02) v2(74.36,49.08) v2(75.08,90.31) v2(75.09,89.26) v2(75.1,88.66) v2(75.08,88.09) v2(75.17,119.5) v2(75.16,93.49) v2(75.46,89.86) v2(75.55,136.41) v2(75.8,93.47) v2(75.84,90.31) v2(76.08,49.08) v2(76.19,125.36) v2(76.34,119.49) v2(77.04,63.2) v2(76.97,52.46) v2(77.23,58.1) v2(77.23,56.83) v2(77.23,55.56) v2(77.28,136.41) v2(77.81,49.08) v2(78.54,56.72) v2(78.47,52.46) v2(78.56,58.88) v2(78.67,63.18) v2(79.01,136.41) v2(79.54,49.08) v2(80.06,58.1) v2(80.06,56.83) v2(80.06,55.56) v2(80.07,52.45) v2(80.64,63.26) v2(80.73,136.41) v2(81.27,49.08) v2(81.75,101.24) v2(82,52.46) v2(82.35,58.85) v2(82.35,57.58) v2(82.35,56.31) v2(82.46,136.41) v2(82.95,101.24) v2(82.99,49.08) v2(83.48,63.15) v2(83.47,52.46) v2(83.58,128.59) v2(83.61,57.26) v2(83.61,55.35) v2(84.19,136.41) v2(84.17,96.2) v2(84.72,49.08) v2(84.94,63.19) v2(84.89,58.85) v2(84.89,57.58) v2(84.89,56.31) v2(85.47,52.46) v2(85.91,136.41) v2(86.05,96.15) v2(86.45,49.08) v2(86.9,63.22) v2(86.97,52.46) v2(87.17,93.94) v2(87.17,58.21) v2(87.17,56.94) v2(87.17,55.67) v2(87.64,136.41) v2(87.78,96.58) v2(87.97,52.46) v2(88.09,93.1) v2(88.17,49.08) v2(88.42,90.79) v2(88.75,58.91) v2(88.76,56.62) v2(88.97,52.46) v2(89.06,81.51) v2(89.2,93.81) v2(89.37,136.41) v2(89.71,92.01) v2(89.73,63.74) v2(89.72,63.13) v2(89.9,49.08) v2(90.02,58.21) v2(90.02,56.94) v2(90.02,55.67) v2(90.47,82.69) v2(91.03,83.96) v2(90.97,52.46) v2(91.1,136.41) v2(91.21,85.24) v2(91.63,49.08) v2(91.97,52.46) v2(92.21,58.81) v2(92.19,57.56) v2(92.19,55.74) v2(92.33,117.77) v2(92.7,86.73) v2(92.7,84.9) v2(92.82,136.41) v2(92.97,52.46) v2(93.36,49.08) v2(93.49,63.78) v2(93.5,63.14) v2(93.48,58.47) v2(93.48,56.57) v2(93.97,52.46) v2(94.33,86.68) v2(94.33,84.65) v2(94.55,136.41) v2(95.08,49.08) v2(95.43,94.78) v2(95.97,52.46) v2(96.24,84.97) v2(96.24,83) v2(96.28,136.41) v2(96.27,58.24) v2(96.27,56.97) v2(96.27,55.7) v2(96.78,85.91) v2(96.81,49.08) v2(97.31,95.42) v2(97.31,94.18) v2(97.47,52.46) v2(97.94,63.13) v2(98,136.41) v2(98.21,94.77) v2(98.22,60.5) v2(98.51,99.99) v2(98.47,52.46) v2(98.54,49.08) v2(98.59,85.35) v2(98.59,82.94) v2(99.25,106.16) v2(99.35,101.4) v2(99.35,55) v2(99.39,103.8) v2(99.73,136.41) v2(99.79,59.86) v2(99.79,58.59) v2(100.22,81.51) v2(100.19,80.72) v2(100.26,49.08) v2(100.49,106.16) v2(100.61,103.8) v2(100.58,101.4) v2(101.02,84.69) v2(101,82.75) v2(101.46,136.41) v2(101.91,59.16) v2(101.91,57.89) v2(101.91,56.62) v2(101.91,55.35) v2(102.03,104.54) v2(102.02,103.34) v2(102.02,102.14) v2(101.99,49.08) v2(102.42,118.98) v2(102.49,64.11) v2(102.5,63.51) v2(102.87,86.24) v2(102.87,84.34) v2(103.19,136.41) v2(103.65,118.37) v2(103.65,116.62) v2(103.72,49.08) v2(104.68,104.59) v2(104.68,103.39) v2(104.68,102.19) v2(104.79,58.53) v2(104.79,57.26) v2(104.79,55.99) v2(104.91,136.41) v2(105.06,101.59) v2(105.45,49.08) v2(105.72,114.54) v2(105.67,101.35) v2(105.79,118.45) v2(105.8,116.4) v2(106.64,136.41) v2(106.62,128.49) v2(107.17,49.08) v2(107.35,57.67) v2(107.6,127.15) v2(108,123.07) v2(107.98,117.29) v2(108.25,87.4) v2(108.25,84.93) v2(108.28,81.62) v2(108.37,136.41) v2(108.83,58.53) v2(108.83,57.26) v2(108.88,118.47) v2(108.9,49.08) v2(110.09,136.41) v2(110.63,49.08) v2(110.97,86.81) v2(110.97,84.84) v2(111.11,123.03) v2(111.12,114.23) v2(111.25,115.72) v2(111.82,136.41) v2(112.31,56.33) v2(112.36,49.08) v2(112.75,87.45) v2(112.75,85.48) v2(112.75,83.45) v2(112.75,81.41) v2(113.55,136.41) v2(113.97,58.66) v2(113.97,57.39) v2(113.97,56.12) v2(114.08,49.08) v2(114.58,86.43) v2(114.58,84.53) v2(115,128.51) v2(115.03,104.43) v2(115.03,103.81) v2(115.04,103.15) v2(115.04,101.15) v2(115.05,102.51) v2(115.06,101.82) v2(115.06,100.55) v2(115.28,136.41) v2(115.6,58.02) v2(115.6,56.75) v2(115.81,49.08) v2(116.39,127.22) v2(116.44,116.93) v2(116.42,86.88) v2(116.42,84.97) v2(116.42,83.07) v2(116.39,59.29) v2(116.68,103.5) v2(117,136.41) v2(117.35,126.15) v2(117.54,49.08) v2(117.65,116.25) v2(117.63,115.49) v2(118.01,87.51) v2(118.01,85.61) v2(118.01,83.7) v2(118.11,58.43) v2(118.17,57.11) v2(118.18,56.27) v2(118.3,117.73) v2(118.73,136.41) v2(118.9,120.18) v2(119.26,49.08) v2(119.4,127.83) v2(119.68,122.62) v2(119.78,85.29) v2(119.85,59) v2(119.85,57.73) v2(119.91,120.71) v2(120.46,136.41) v2(120.99,49.08) v2(121.36,116.73) v2(121.62,52.46) v2(121.98,97.28) v2(122.03,63.25) v2(122.04,59.42) v2(122.04,58.15) v2(122.04,56.88) v2(122.19,136.41) v2(122.72,49.08) v2(122.99,122.53) v2(123.01,121.92) v2(122.98,55) v2(123.29,118.99) v2(123.33,98.24) v2(123.32,60.37) v2(123.32,58.47) v2(123.44,127.24) v2(123.58,122.54) v2(123.6,121.9) v2(123.59,115.28) v2(123.91,136.41) v2(123.86,119.15) v2(123.98,55) v2(124.08,127.24) v2(124.08,115.59) v2(124.45,49.08) v2(124.78,59.42) v2(124.78,58.15) v2(124.78,56.88) v2(124.91,98.48) v2(125.12,82.69) v2(125.13,63.85) v2(125.13,63.23) v2(125.42,99.53) v2(125.64,136.41) v2(126.02,115.95) v2(126.17,49.08) v2(126.68,99.55) v2(126.85,52.43) v2(127.23,127.96) v2(127.37,136.41) v2(127.37,59.42) v2(127.37,58.15) v2(127.37,56.88) v2(127.9,49.08) v2(128.04,127.95) v2(128.77,57.82) v2(128.77,55.91) v2(128.93,127.95) v2(129.09,136.41) v2(129.26,79.44) v2(129.63,49.08) v2(129.82,82.92) v2(129.82,82.31) v2(130.62,59.42) v2(130.62,58.15) v2(130.62,56.88) v2(130.71,52.45) v2(130.82,136.41) v2(130.82,63.8) v2(130.82,63.19) v2(131.35,49.08) v2(131.95,52.41) v2(132.55,136.41) v2(132.74,63.23) v2(132.81,58.68) v2(132.81,57.41) v2(132.81,56.14) v2(133.08,49.08) v2(134.08,52.44) v2(134.21,59.64) v2(134.21,57.73) v2(134.28,136.41) v2(134.81,49.08) v2(135.21,64.01) v2(135.25,63.46) v2(136,136.41) v2(136.26,58.68) v2(136.26,57.41) v2(136.26,56.14) v2(136.29,52.43) v2(136.54,49.08) v2(137.73,136.41) v2(137.94,127.64) v2(137.96,128.22) v2(138.16,126.57) v2(138.23,70.47) v2(138.3,127.17) v2(138.26,49.08) v2(138.66,70.06) v2(138.79,63.19) v2(138.77,59.83) v2(138.77,58.56) v2(138.77,57.29) v2(139.46,136.41) v2(139.99,49.08) v2(140.19,58.24) v2(140.19,56.37) v2(141.01,129.8) v2(141.12,132.11) v2(141.18,136.41) v2(141.35,50.39) v2(141.46,59.2) v2(141.46,57.94) v2(141.46,56.65) v2(141.63,130.43) v2(141.63,129.18) v2(142.18,120.61) v2(142.25,129.8) v2(142.82,120.61) v2(142.91,136.41) v2(143.19,98.14) v2(143.91,132.15) v2(144.64,136.41) v2(144.68,132.24) v2(144.73,49.95) v2(145.5,131.71) v2(146.37,136.41) v2(146.45,130.49) v2(146.56,49.1) v2(147.59,51.1) v2(147.94,134.3) v2(148.12,49.08) v2(148.49,128.45) v2(148.49,127.86) v2(148.49,127.25) v2(148.84,53.28) v2(149.02,136.17) v2(149.02,132.43) v2(149.22,128.42) v2(149.3,60.54) v2(149.3,58.74) v2(150.31,74.12) v2(150.3,73.53) v2(150.34,60.54) v2(150.34,58.74) v2(150.66,75.72) v2(150.78,76.28) v2(151.14,75.27) v2(151.18,136.17) v2(151.18,132.43) v2(151.25,75.85) v2(151.36,53.28) v2(151.51,73.34) v2(151.61,76.32) v2(151.74,75.21) v2(151.72,73.97) v2(151.82,75.78) v2(151.91,72.93) v2(152,49.08) v2(152.26,134.3) v2(152.31,81.19) v2(152.36,84.11) v2(152.39,83.53) v2(152.38,82.96) v2(152.37,82.34) v2(152.36,81.77) v2(152.36,72.35) v2(152.61,51.1) v2(152.87,81.11) v2(153.03,84.09) v2(153.03,83.52) v2(153.03,82.92) v2(153.04,82.31) v2(153.04,81.74) v2(153.42,81.21) v2(153.71,134.91) v2(153.88,61.54) v2(154.03,81.21) v2(154.46,75.45) v2(154.62,51.6) v2(155.43,134.91) v2(155.49,78.14) v2(156.14,84.8) v2(156.58,52.6) v2(156.84,75.5) v2(156.88,128.28) v2(157.15,77.12) v2(157.12,76.53) v2(157.16,134.91) v2(157.22,75.93) v2(157.5,128.9) v2(157.5,127.66) v2(157.55,111.49) v2(157.55,109.97) v2(157.55,108.44) v2(158.13,128.28) v2(158.34,52.41) v2(158.45,116.09) v2(158.89,134.91) v2(158.86,115.67) v2(159.08,111.49) v2(159.08,109.97) v2(159.08,108.44) v2(159.78,51.37) v2(160.05,84.91) v2(160.01,84.33) v2(160.01,83.75) v2(160.49,49.77) v2(160.62,134.91) v2(160.64,131.39) v2(160.62,130.82) v2(160.6,109.97) v2(160.62,48.6) v2(161.25,130.82) v2(161.55,130.29) v2(162.14,130.25) v2(162.2,134.2) v2(162.34,48.6) v2(162.39,73.33) v2(162.69,91.93) v2(163.15,135.85) v2(163.15,132.55) v2(163.24,88.04) v2(163.25,87.45) v2(163.25,86.86) v2(163.27,63) v2(163.27,62.42) v2(163.27,61.83) v2(163.4,85.76) v2(163.85,63) v2(163.85,62.42) v2(163.85,61.83) v2(164.07,48.6) v2(164.44,63.05) v2(164.44,62.42) v2(164.44,61.83) v2(165.02,61.81) v2(165.05,135.85) v2(165.05,132.55) v2(165.58,62.24) v2(165.8,48.6) v2(166.01,134.2) v2(166.01,62.7) v2(166.24,112.45) v2(166.64,132.04) v2(166.66,130.73) v2(166.66,129) v2(166.66,127.28) v2(166.93,125.54) v2(167.42,114.5) v2(167.42,110.4) v2(167.52,48.6) v2(167.99,77.23) v2(167.99,76.64) v2(167.99,76.06) v2(167.99,75.47) v2(167.99,74.89) v2(167.99,74.31) v2(168.45,123.18) v2(168.58,125.35) v2(168.55,120.1) v2(168.58,116.83) v2(169.25,48.6) v2(169.98,76.46) v2(169.98,75.88) v2(169.98,75.25) v2(169.98,74.66) v2(170.31,125.35) v2(170.34,123.68) v2(170.34,121.96) v2(170.34,120.23) v2(170.34,118.5) v2(170.34,116.77) v2(170.34,114.74) v2(170.34,109.71) v2(170.36,107.81) v2(170.36,106.08) v2(170.36,104.35) v2(170.36,102.63) v2(170.36,100.9) v2(170.36,99.17) v2(170.46,97.43) v2(170.64,95.81) v2(170.93,94.12) v2(170.98,48.6) v2(171.3,92.56) v2(171.51,64.99) v2(171.73,91.04) v2(172.02,64.51) v2(172.26,89.53) v2(172.52,65.71) v2(172.71,48.6) v2(172.85,88.1) v2(172.93,65.27) v2(173.51,86.71) v2(174.26,85.33) v2(174.43,48.6) v2(175.18,83.86) v2(175.41,50.87) v2(176.01,82.68) v2(176.05,50.87) v2(176.16,48.6) v2(176.29,60.53) v2(176.74,50.87) v2(176.76,60.06) v2(177.05,81.35) v2(177.38,50.87) v2(177.89,48.6) v2(178.08,54.24) v2(178.28,79.98) v2(178.74,54.07) v2(179.61,48.6) v2(179.67,78.62) v2(180.2,55.56) v2(180.42,56.09) v2(180.51,55.07) v2(180.81,77.63) v2(180.81,55.54) v2(181.02,56.07) v2(181.1,55.05) v2(181.34,48.6) v2(181.39,55.54) v2(181.61,56.08) v2(181.69,55.05) v2(181.98,55.56) v2(182.17,76.58) v2(182.24,56.06) v2(182.27,55.05) v2(183.07,48.6) v2(183.68,75.55) v2(184.8,48.6) v2(184.94,55.64) v2(185.09,74.74) v2(186.52,48.6) v2(186.74,73.95) v2(187.32,55.69) v2(187.7,56.12) v2(188.26,57.42) v2(188.25,48.6) v2(188.35,73.32) v2(188.85,57.43) v2(190.04,72.81) v2(189.98,48.6) v2(191.7,48.6) v2(191.78,72.41) v2(193.43,48.6) v2(193.46,72.19) v2(195.21,72.05) v2(195.16,48.6) v2(196.94,72.05) v2(196.89,48.6) v2(198.02,51.83) v2(198.6,51.83) v2(198.61,48.6) v2(198.66,72.05) v2(199.19,51.83) v2(199.77,51.83) v2(200.34,48.6) v2(200.39,72.05) v2(200.36,51.83) v2(200.61,59.67) v2(200.61,59.07) v2(200.94,51.83) v2(202.09,72.06) v2(202.07,48.6) v2(203.83,72.11) v2(203.8,48.6) v2(205.52,48.6) v2(205.57,72.29) v2(207.25,48.6) v2(207.28,72.59) v2(207.48,51.83) v2(208.43,55.32) v2(208.98,73.04) v2(208.98,48.6) v2(209.83,56.84) v2(210.6,73.59) v2(210.7,48.6) v2(212.11,74.24) v2(212.43,48.6) v2(213.76,75.09) v2(214.16,48.6) v2(215.21,75.98) v2(215.89,48.6) v2(217.05,77.33) v2(217.61,48.6) v2(218.97,75.7) v2(219.34,48.6) v2(220.75,59.89) v2(220.85,81) v2(221.07,48.6) v2(221.33,79.8) v2(221.33,75.7) v2(221.99,82.42) v2(222.51,77.75) v2(222.81,83.54) v2(222.79,48.6) v2(223.79,85.06) v2(224.52,48.6) v2(224.56,70.88) v2(224.66,86.64) v2(225.45,88.3) v2(225.97,70.86) v2(226.1,89.97) v2(226.25,71.44) v2(226.25,48.6) v2(226.59,91.44) v2(226.94,56.85) v2(227.1,93.29) v2(227.25,55.34) v2(227.44,94.98) v2(227.53,56.85) v2(227.68,96.68) v2(227.85,112.28) v2(227.85,110.55) v2(227.85,108.82) v2(227.85,107.1) v2(227.85,105.37) v2(227.85,103.64) v2(227.85,101.92) v2(227.85,100.19) v2(227.81,98.45) v2(227.98,48.6) v2(228.42,114.06) v2(228.45,63.92) v2(229.32,112.85) v2(229.35,72.76) v2(229.7,48.6) v2(230.15,114.06) v2(230.49,70.42) v2(231.43,48.6) v2(231.54,131.56) v2(231.54,129.83) v2(231.54,128.1) v2(231.54,126.38) v2(231.54,124.65) v2(231.54,122.92) v2(231.54,121.19) v2(231.54,119.47) v2(231.54,117.74) v2(231.54,116.01) v2(231.54,114.29) v2(232.19,134.2) v2(233.15,135.85) v2(233.15,132.55) v2(233.16,48.6) v2(233.58,127.62) v2(234.88,48.6) v2(235.05,135.85) v2(235.05,132.55) v2(236,134.2) v2(236.05,111.07) v2(236.05,110.44) v2(236.05,109.8) v2(236.23,106.81) v2(236.18,105.32) v2(236.35,87.97) v2(236.35,87.41) v2(236.61,48.6) v2(236.87,124.03) v2(237.92,125.45) v2(238.34,122.2) v2(238.34,48.6) v2(238.36,122.79) v2(238.59,134.91) v2(239.1,122.78) v2(239.08,122.19) v2(239.27,96.1) v2(239.29,95.07) v2(239.29,94.5) v2(239.4,80.13) v2(239.55,63.65) v2(239.61,126.63) v2(239.75,62.09) v2(239.79,79.04) v2(240.07,48.6) v2(240.32,134.91) v2(241.79,48.6) v2(242.05,134.91) v2(242.28,127.07) v2(243.52,48.6) v2(243.77,134.91) v2(244.02,53.71) v2(244.4,82.36) v2(245.01,127.2) v2(245.01,125.93) v2(245.01,124.66) v2(245.25,48.6) v2(245.39,107.83) v2(245.5,134.91) v2(246.02,107.83) v2(246.3,127.95) v2(246.28,127.2) v2(246.28,125.93) v2(246.28,124.66) v2(246.98,48.6) v2(247.23,134.91) v2(247.55,127.2) v2(247.55,125.93) v2(247.8,127.95) v2(248.7,48.6) v2(248.96,134.91) v2(249.81,62.27) v2(250.19,62.72) v2(250.43,48.6) v2(250.68,134.91) v2(251.29,111.2) v2(252.16,48.6) v2(252.41,134.91) v2(253.86,64.57) v2(253.88,48.6) v2(254.14,134.91) v2(254.44,64.57) v2(255.36,62.3) v2(255.36,60.34) v2(255.36,58.37) v2(255.61,48.6) v2(255.87,134.91) v2(257.33,62.3) v2(257.33,60.34) v2(257.33,58.37) v2(257.34,48.6) v2(257.59,134.91) v2(257.65,68.81) v2(258.26,68.82) v2(259.07,48.6) v2(259.32,134.91) v2(259.29,62.3) v2(259.29,60.34) v2(259.29,58.37) v2(260.79,48.6) v2(261.05,134.91) v2(262.52,48.6) v2(262.77,134.91) v2(263.66,134.15) v2(263.66,132.42) v2(264.2,130.76) v2(264.25,48.6) v2(264.29,96.81) v2(265.76,48.6) v2(265.92,130.76) v2(267.1,58.56) v2(267.23,65.23) v2(267.23,64.59) v2(267.23,63.96) v2(267.55,58.11) v2(267.65,130.76) v2(268.24,50.25) v2(268.38,65.28) v2(268.4,63.89) v2(268.41,62.54) v2(269.38,130.76) v2(269.37,66.74) v2(269.42,52.3) v2(271.11,130.76) v2(271.78,52.3) v2(272.83,130.76) v2(272.96,50.25) v2(273.33,127.46) v2(274.15,65.99) v2(274.15,63.75) v2(274.28,91.83) v2(274.28,90.88) v2(274.56,130.76) v2(275.27,64.87) v2(275.26,46.57) v2(275.87,73.32) v2(276.03,44.71) v2(276.03,42.99) v2(276.03,41.26) v2(276.03,39.53) v2(276.03,37.81) v2(276.03,36.08) v2(276.03,34.35) v2(276.03,32.62) v2(276.03,30.9) v2(276.03,29.17) v2(276.03,27.44) v2(276.03,25.72) v2(276.03,23.99) v2(276.03,22.26) v2(276.03,20.53) v2(276.03,18.81) v2(276.03,17.08) v2(276.03,15.35) v2(276.03,13.63) v2(276.03,11.9) v2(276.03,10.17) v2(276.03,8.44) v2(276.03,6.72) v2(276.03,4.99) v2(276.03,3.26) v2(276.03,1.53) v2(276.13,75.77) v2(276.29,130.76) v2(276.39,65.99) v2(276.39,63.75) v2(276.76,76.39) v2(276.76,75.14) v2(276.93,0.44) v2(277.79,70.5) v2(278.01,130.76) v2(277.99,13.95) v2(278.42,70.5) v2(278.66,0.44) v2(278.95,15.6) v2(278.95,12.3) v2(279.06,70.5) v2(279.74,130.76) v2(279.92,73.98) v2(280.39,0.44) v2(280.82,70.75) v2(280.82,70.17) v2(280.85,15.6) v2(280.85,12.3) v2(281.39,65.92) v2(281.47,130.76) v2(281.77,65.48) v2(281.8,13.95) v2(281.99,2.04) v2(282.12,0.44) v2(282.66,55.66) v2(282.66,55.07) v2(282.88,53.95) v2(283.2,130.76) v2(283.31,5.78) v2(283.84,0.44) v2(284.33,3.64) v2(284.41,47.9) v2(284.49,68.2) v2(284.94,130.76) v2(284.88,87.67) v2(285.45,69.85) v2(285.45,66.55) v2(285.57,0.44) v2(286.46,86.64) v2(286.46,84.91) v2(286.52,71.66) v2(286.69,130.87) v2(287.04,2.2) v2(287.14,132.9) v2(287.26,51.5) v2(287.3,0.44) v2(287.35,69.85) v2(287.35,66.55) v2(288.1,134.55) v2(288.1,131.25) v2(288.33,86.16) v2(288.3,68.2) v2(288.43,71.65) v2(289.03,0.44) v2(289.22,50.3) v2(289.24,47.93) v2(289.46,23.12) v2(289.84,11.44) v2(290,134.55) v2(290,131.25) v2(290.05,86.16) v2(290.16,71.65) v2(290.22,23.12) v2(290.4,88.58) v2(290.6,11.44) v2(290.77,56.55) v2(290.75,0.44) v2(290.95,132.9) v2(291.02,51.5) v2(290.98,23.12) v2(291.11,70.04) v2(291.13,67.7) v2(291.06,19.21) v2(291.18,15.71) v2(291.34,129.97) v2(291.36,11.44) v2(291.74,23.12) v2(291.78,86.16) v2(291.89,71.65) v2(292.12,11.44) v2(292.48,0.44) v2(292.66,129.75) v2(293.17,88.58) v2(293.15,69.45) v2(293.15,67.73) v2(293.15,66) v2(293.15,22.45) v2(293.15,20.72) v2(293.15,19) v2(293.15,17.27) v2(293.15,15.54) v2(293.15,13.82) v2(293.15,12.09) v2(293.15,10.36) v2(293.15,8.63) v2(293.15,6.91) v2(293.15,5.18) v2(293.15,3.45) v2(293.15,1.73) v2(293.27,91.15) v2(293.94,26.3) v2(294.38,129.75) v2(294.47,51.57) v2(294.88,66) v2(294.99,91.15) v2(295.02,28.17) v2(295.02,24.43) v2(294.96,22.95) v2(295.16,69.9) v2(295.32,86.18) v2(295.31,71.65) v2(295.55,88.56) v2(295.74,46.65) v2(296.11,129.75) v2(296.12,50.91) v2(296.61,66) v2(296.84,22.95) v2(297.04,69.92) v2(297.05,87.91) v2(297.05,86.18) v2(297.18,28.17) v2(297.18,24.43) v2(297.29,52.14) v2(297.31,50.91) v2(297.84,129.75) v2(298,89.22) v2(298.02,46.65) v2(298.19,127.93) v2(298.19,124.34) v2(298.27,120.38) v2(298.33,66) v2(298.26,26.3) v2(299.05,29.77) v2(299.01,22.97) v2(299.57,129.75) v2(299.74,128.52) v2(299.74,126.8) v2(299.74,125.07) v2(299.74,123.34) v2(299.74,121.61) v2(299.74,119.89) v2(299.74,118.16) v2(299.74,116.43) v2(299.73,90.94) v2(299.73,89.22) v2(300.06,66) v2(300.24,64.45) v2(300.24,62.72) v2(300.24,61) v2(300.24,59.27) v2(300.24,57.54) v2(300.24,55.81) v2(300.24,54.09) v2(300.24,52.36) v2(300.24,50.63) v2(300.24,46.66) v3(9.78,47.33) v3(10.51,52.68) v3(14.57,52.59) v3(40.15,73.29) v3(40.76,115.47) v3(51.2,70.11) v3(52.88,110.45) v3(55.01,71.77) v3(56.68,78.03) v3(57.01,57.64) v3(58.63,106.25) v3(108.73,131.53) v3(113.8,130.09) v3(114.31,126.87) v3(128.24,78.98) v3(141.53,131.33) v3(142.9,133.58) v3(151.27,74.48) v3(152.93,75.77) v3(156.06,75.32) v3(158.59,132) v3(167.79,119.39) v3(167.79,117.1) v3(170.23,78.09) v3(170.23,77.94) v3(179.55,55.17) v3(183.59,55.34) v3(201.09,50.79) v3(226.8,54.21) v3(241.3,126.57) v3(266.22,53.71) v3(271.98,128.61)
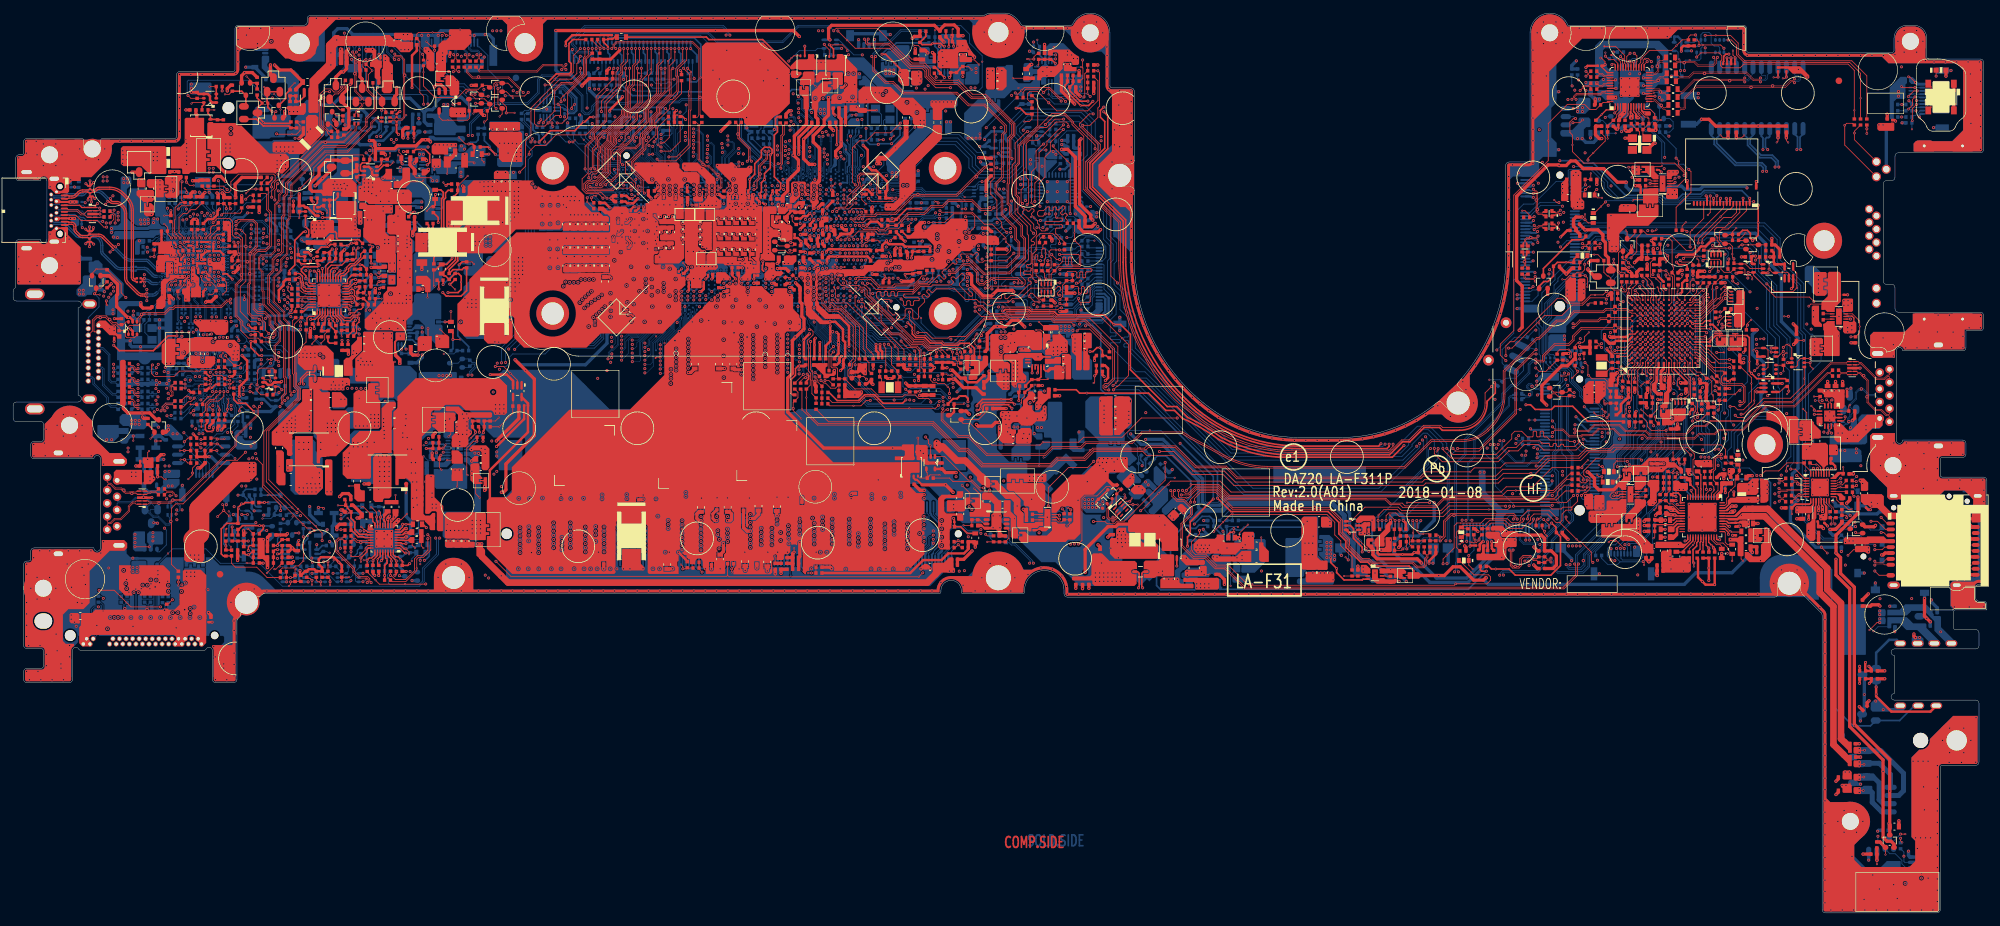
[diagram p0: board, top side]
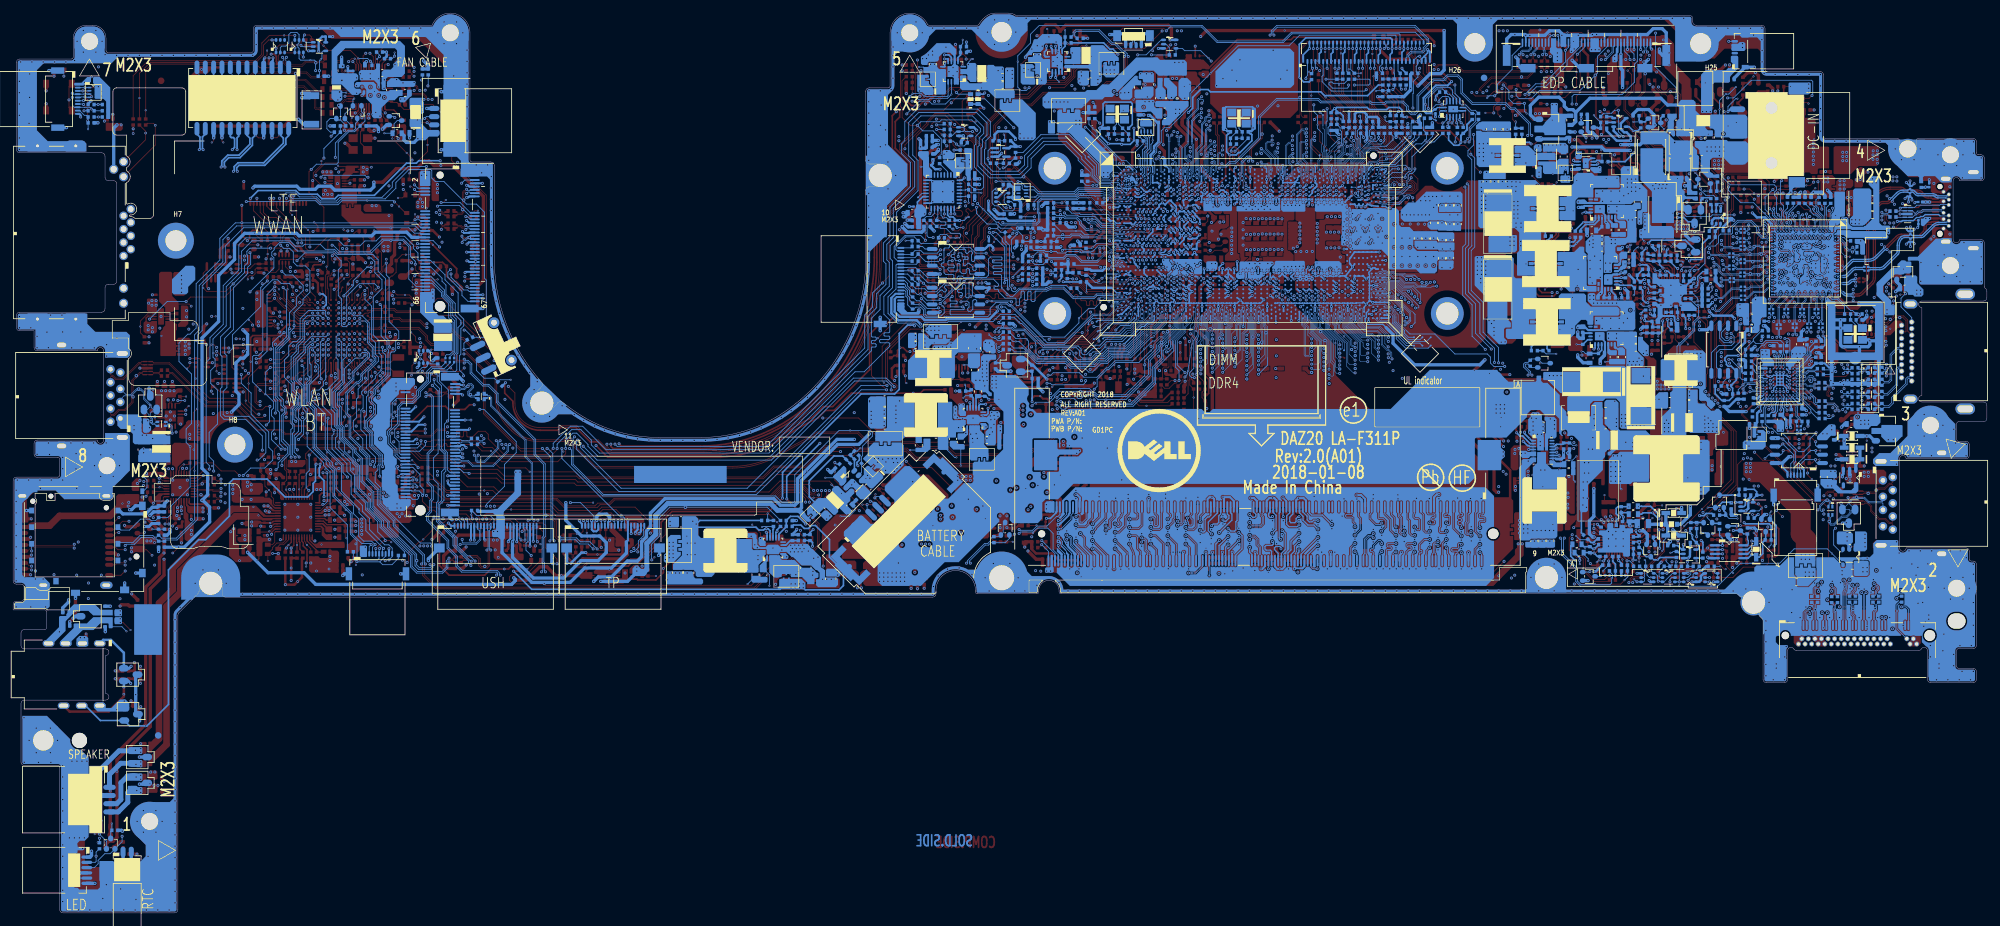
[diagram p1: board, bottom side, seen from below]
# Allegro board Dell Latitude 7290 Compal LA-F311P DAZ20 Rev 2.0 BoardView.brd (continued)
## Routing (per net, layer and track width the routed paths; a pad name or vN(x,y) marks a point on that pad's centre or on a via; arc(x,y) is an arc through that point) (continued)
GNDA: length 52.1
  TOP w0.203: v2(254.72,56.72) 254.93,56.72 255.13,56.92 UA1.25 ; v2(261.33,57.73) 261.33,58.01 260.8,58.54 UA1.38
  TOP w0.381: CA57.2 v2(261.96,57.58) ; v2(253.34,62.88) 252.7,62.88 CA41.2
  TOP w0.508: RA39.1 282.45,32.05 v2(282.74,32.33) ; CA3.2 v2(285.14,36.9) ; v2(289.84,41.97) 289.8,41.97 289.58,42.19 v3(289.58,42.53) ; RA37.1 250.16,59.89 CA25.2 v2(251.74,59.89) ; CA2.2 v2(285.14,35.7) ; RA38.1 282.98,46.79 283.17,46.98 284.21,46.98 v2(284.4,46.79)
  GND1 w0.203: 286.42,30.92 JHP1.5 ; JHP1.5 288.58,30.92 ; JHP1.5 287.5,30.92 ; JHP1.5 286.42,31.6 ; JHP1.5 288.58,31.6 ; JHP1.7 291.23,41.77 ; JHP1.7 289.07,41.1 ; JHP1.7 290.15,41.77 ; JHP1.7 291.23,41.1 ; JHP1.7 289.07,41.77
  GND2 w0.203: JHP1.5 288.58,30.92 ; JHP1.5 288.58,31.6 ; JHP1.5 287.5,30.92 ; JHP1.5 286.42,31.6 ; JHP1.5 286.42,30.92 ; JHP1.7 290.15,41.77 ; JHP1.7 289.07,41.77 ; JHP1.7 291.23,41.1 ; JHP1.7 289.07,41.1 ; JHP1.7 291.23,41.77
  VCC w0.203: JHP1.5 288.58,30.92 ; JHP1.5 286.42,30.92 ; JHP1.5 287.5,30.92 ; JHP1.7 290.15,41.77 ; JHP1.7 289.07,41.77 ; JHP1.7 291.23,41.77
  GND3 w0.203: 289.07,41.77 JHP1.7 ; JHP1.7 291.23,41.77 ; JHP1.7 289.07,41.1 ; JHP1.7 290.15,41.77 ; JHP1.7 291.23,41.1 ; 287.5,30.92 JHP1.5 ; JHP1.5 286.42,30.92 ; JHP1.5 288.58,30.92 ; JHP1.5 286.42,31.6 ; JHP1.5 288.58,31.6
  BOTTOM w0.508: CA1.1 286.66,43.58 v2(286.66,42.87) ; CA4.2 v2(285.9,46.76)
  vias: v2(252.44,54.37) v2(252.44,53.73) v2(255.36,53.35) v2(265.39,57.54) v2(265.39,56.91) v2(283.77,32.29) v2(284.91,30.97) v2(290.45,41.97) v3(252.58,52.44) v3(254.48,52.13)
VBAT1_ISL9538: length 4.3
  TOP w0.203: v2(58.38,53.67) 57.52,54.53 PU901.31
  TOP w0.254: PR940.2 v2(58.38,53.67)
  BOTTOM w0.127: v1(59.43,53.47) 59.23,53.67 v2(58.38,53.67)
  BOTTOM w0.203: v2(58.38,53.67) 58.19,53.86 58.19,54.23 PC950.2
VBUS1_ECOK: length 404.2
  TOP w0.127: UE1.M6 255.85,87.49 258.36,87.49 259.38,88.51 v2(259.43,88.51)
  TOP w0.254: PR1220.1 PR1222.1 42.7,107.85 v2(42.7,108.56)
  IN2 w0.122: v2(260.75,76.22) 260.67,76.14 258.77,76.14 257.51,77.4 252.59,77.4 251.86,76.66 249.14,76.66 248.25,75.77 245.94,75.77 244.51,77.2 241.4,77.2 240.71,76.51 237.52,76.51 234.69,73.69 234.22,73.69 233.83,73.3 228.98,73.3 228.25,72.58 228.25,71.25 226.72,69.71 226.08,69.71 225.78,69.41 225.08,69.41 225.07,69.4 222.07,69.4 221.11,68.44 207.76,68.44 206.41,69.8 188.18,69.8 186.54,71.44 182.41,71.44 172.78,81.08 172.78,83.17 170.78,85.16 170.78,86.9 170.01,87.68 170.01,88.76 168.17,90.59 168.17,92.72 167.16,93.74 167.16,106.63 163.27,110.52 163.27,117.19 163.74,117.66 163.74,120.36 161.05,123.05 161.05,126.7 156.61,131.14 155.22,131.14 154.53,130.45 147.83,130.45 145.28,133 143.13,133 141.69,134.44 136.17,134.44 135.13,133.4 132.36,133.4 131.56,134.2 127.11,134.2 126.51,133.6 123.96,133.6 123.25,132.89 115.89,132.89 115.03,132.03 109.37,132.03 109.12,132.28 86.12,132.28 85.75,131.91 85.75,131.42 85.49,131.16 83.76,131.16 80.06,127.47 75.74,127.47 75.11,128.1 69.25,128.1 68.05,126.9 61.85,126.9 61.75,126.8 47.61,126.8 46.17,125.36 41.52,125.36 39.63,123.47 36.02,123.47 31.37,118.82 31.37,114.04 32.46,112.96 36.32,112.96 39.48,109.79 39.84,109.79 40.06,109.58 41.68,109.58 v2(42.7,108.56) 41.23,107.09 41.23,101.2 40.5,100.47 40.25,100.47 39.34,99.55 39.34,91.39 40.66,90.07 40.66,86.78 39.76,85.88 39.76,81.04 38.79,80.06 38.79,79.04 38.03,78.27 37.03,78.27 36.07,77.32 36.07,75.57 35.37,74.87 35.37,71.06 35.92,70.52 v2(35.92,69.23)
  IN4 w0.084: v2(35.92,69.23) 35.39,68.71 35.39,67.13 35.96,66.57 35.96,64.27 34.26,62.57 34.26,59.71 36.32,57.64 36.32,55.7 39.98,52.04 42.48,52.04 43.27,51.26 44.41,51.26 45.49,52.33 46.12,52.33 v2(47.32,53.53)
  BOTTOM w0.127: v2(260.75,76.22) 260.68,76.3 260.68,78 261.02,78.34 261.02,86.24 261.17,86.39 261.17,86.94 260.16,87.94 259.99,87.94 v2(259.43,88.51) ; PR1257.1 47.38,53.47 v2(47.32,53.53)
VBUS2_ECOK: length 352.7
  TOP w0.127: v2(47.97,53.54) v1(47.97,53.02) PR1242.1 ; UE1.N3 256.55,85.46 256.73,85.28 256.92,85.28 259.03,83.17 v2(261.52,83.17)
  IN1 w0.084: v2(259.87,70.7) 260.35,70.7 260.95,70.1 260.95,69.82 262.04,68.73 262.04,66.92 261.55,66.42 261.26,66.42 261.11,66.58 259.97,66.58 259.82,66.43 251.76,66.43 250.25,64.92 248.24,64.92 241.65,58.32 241.65,55.57 237.6,51.53 228.39,51.53 226.74,53.18 219.5,53.18 218.31,52 210.44,52 209.29,50.85 187.57,50.85 185.5,52.92 185.5,55.96 184.92,56.54 173.81,56.54 169.43,60.92 167.5,60.92 166.33,59.76 165.22,59.76 164.91,60.07 161.89,60.07 160.48,61.48 160.48,61.75 160.18,62.06 159.05,62.06 158.52,61.53 157.38,61.53 156.92,61.98 147.59,61.98 144.52,65.05 141.71,65.05 140.37,66.39 73.65,66.39 72.59,65.33 72.59,63.4 73,63 73,56.55 72.04,55.59 69.99,55.59 69.46,56.13 64.04,56.13 62.85,54.93 62.37,54.93 61.19,53.75 61.19,52.85 60.99,52.64 59.56,52.64 59.31,52.39 48.88,52.39 47.97,53.31 v2(47.97,53.54)
  IN2 w0.122: v2(36.49,69.39) 36.42,69.45 36.42,70.33 35.6,71.16 35.6,74.66 38.44,77.5 38.44,78.29 39.66,79.51 39.66,80.08 40.03,80.44 40.03,85.73 40.91,86.62 40.91,90.19 39.61,91.49 39.61,99.46 40.4,100.24 40.59,100.24 41.53,101.18 41.53,106.61 43.1,108.18 43.1,108.91 41.92,110.09 v2(40.39,110.09)
  IN4 w0.084: v2(36.49,69.39) 36.49,69.31 37.2,68.6 37.2,67.01 36.27,66.08 36.27,64.05 35.33,63.11 35.33,59.09 36.68,57.74 36.68,55.7 40.12,52.27 42.62,52.27 43.37,51.51 44.31,51.51 45.38,52.59 45.71,52.59 47.05,53.93 47.58,53.93 v2(47.97,53.54)
  BOTTOM w0.127: PR20.2 40.43,110.06 v2(40.39,110.09) ; v2(261.52,83.17) 262.22,82.47 262.22,79.13 261.04,77.94 261.04,76.96 261.33,76.67 261.33,75.8 260.94,75.42 260.94,73.68 261.33,73.3 261.33,72.16 v2(259.87,70.7)
  BOTTOM w0.254: PR24.1 41.16,111.33 PR20.2
VBUS3_ECOK: length 2.2
  TOP w0.127: UE1.F13 250.92,93.7 250.92,94.57 250.68,94.8 250.68,95.22 T264.1
VCC_GT: length 4.3
  BOTTOM w0.127: v1(61.75,85.59) 61.45,85.59 61.13,85.28 PR680.2
  BOTTOM w0.254: PU612.3 58.69,85.8 PC669.1 60.49,85.32 PR680.2
VCC_GT_SENSE: length 62.6
  TOP w0.127: RC161.1 v1(87.47,108.39) v2(87.47,109.04)
  TOP w0.203: PC651.2 53.61,94.79 PC639.1 52.55,94.56 PR648.1 52.5,94.9 52.76,95.17 PC653.1 52.2,95.47 v2(52.12,95.39)
  IN1 w0.084: v2(87.47,109.04) 87.68,108.83 87.68,108.73 87.59,108.64 87.2,108.64 86.91,108.93 86.91,109.09 86.02,109.98 81.3,109.98 77.12,114.16 71.94,114.16 69.02,111.24 69.02,109.67 65.48,106.12 57.06,106.12 53.02,102.08 53.02,99.97 51.43,98.39 51.43,95.84 51.68,95.59 51.86,95.59 51.94,95.59 v2(52.12,95.39)
  BOTTOM w0.076: 90.4,108.28 91.35,108.28 91.46,108.17 91.97,108.17 92.15,108.29 92.29,108.43 UC1.J70
  BOTTOM w0.127: v2(87.47,109.04) 87.9,109.48 88.42,109.48 89.62,108.28 90.4,108.28
VCC_IA1: length 2.6
  BOTTOM w0.254: PR688.2 59.2,104.07 PC676.1 58.64,104.63 PU610.3
VCC_IA2: length 3.2
  TOP w0.127: v1(55.21,97.41) 55.21,97.38 v2(55.71,96.87)
  TOP w0.254: v2(55.71,96.87) 55.98,97.14 PR691.2
  BOTTOM w0.254: PU613.3 55.74,96.82 55.71,96.85 v2(55.71,96.87) 55.68,96.91 55.64,96.91 55.57,96.84 PC677.1
VCCDSW_EN: length 174.7
  TOP w0.127: CE66.1 v2(259.1,75.58) ; v2(160.33,123.74) 159.73,124.34 159.44,124.34 157.92,125.87 154.07,125.87 v1(153.6,125.39) 152.95,124.74 RC445.1 ; UE1.M7 v2(255.87,88.27)
  IN2 w0.122: v2(160.33,123.74) 160.33,123.45 163.52,120.27 163.52,117.75 163.04,117.27 163.04,110.44 166.89,106.59 166.89,93.57 167.94,92.51 167.94,90.51 169.34,89.11 169.34,88.01 170.53,86.81 170.53,85.1 172.55,83.07 172.55,80.97 182.31,71.22 186.44,71.22 188.08,69.58 206.31,69.58 207.68,68.22 221.81,68.22 222.49,68.89 225.61,68.89 226.2,69.48 227.49,69.48 230.51,72.5 233.55,72.5 233.84,72.21 234.81,72.21 235.63,73.03 235.63,74.31 237.61,76.29 241.02,76.29 241.71,76.97 244.34,76.97 245.81,75.5 248.3,75.5 249.24,76.44 252.03,76.44 252.76,77.17 257.13,77.17 258.72,75.58 v2(259.1,75.58) 260.67,75.58 262.15,77.06 262.15,78.15 260.42,79.88 260.42,81.49 256.85,85.06 256.48,85.06 255.85,85.69 255.85,88.26 v2(255.87,88.27)
VCCDSW_EN_GPIO: length 107.4
  TOP w0.127: v2(159.68,123.79) 157.85,125.61 157.5,125.61 v2(157,125.11) 156.49,125.61 154.33,125.61 153.86,125.15 RC445.2 ; RC431.1 148.34,76.47 147.09,75.23 QC6.2 144.43,74.93 144.73,74.64 145.82,74.64 149.13,71.33 156.44,71.33 v1(156.87,71.77) 162.33,71.77 163.09,72.52 168.94,72.52 171.88,75.46 v2(177.35,75.46)
  IN2 w0.122: v2(177.35,75.46) 177.2,75.61 177.2,75.9 172.3,80.81 172.3,82.95 170.31,84.94 170.31,86.61 169.09,87.83 169.09,88.97 167.72,90.35 167.72,92.42 166.66,93.47 166.66,106.4 162.81,110.25 162.81,117.44 163.09,117.71 163.09,118.83 162.49,119.42 162.49,120.73 159.68,123.54 v2(159.68,123.79)
  BOTTOM w0.127: v2(157,125.11) 156.73,124.84 DC1.2
VCCDSW_EN_Q: length 7.2
  TOP w0.127: RC442.1 155.22,121.04 154.85,120.67 v1(154.05,120.67)
  TOP w0.254: RC442.1 154.33,121.8 153.44,122.69 v2(152.8,122.69)
  BOTTOM w0.254: DC1.1 DC2.2 153.45,123.34 v2(152.8,122.69)
VCCIO_SENSE: length 101.1
  TOP w0.127: v2(130.81,130.59) 130.97,130.42 130.97,128.39 132.85,126.51 134,126.51 135.64,124.87 143.69,124.87 145.49,123.07 147.95,123.07 151.05,119.97 151.05,119.17 150.6,118.72 150.6,112.24 149.59,111.23 149.59,109.86 150.53,108.92 150.53,106.43 152.61,104.34 152.61,102.65 153.1,102.17 153.1,100.33 151.41,98.64 148.42,98.64 v2(148.26,98.8) ; RC165.1 118.14,96.89 v2(118.32,96.71)
  IN4 w0.084: v2(148.26,98.8) 148.11,98.65 146.53,98.65 146.19,99 145.03,99 144.87,98.84 142.93,98.84 142.72,98.63 142.12,98.63 141.32,97.83 137.88,97.83 137,96.94 135.71,96.94 135.01,97.64 132.74,97.64 131.39,98.99 130.4,98.99 130.27,99.13 125.12,99.13 124.26,99.99 119.17,99.99 118.54,99.36 118.54,97.55 118.73,97.37 118.73,96.88 118.55,96.71 v2(118.32,96.71)
  BOTTOM w0.076: UC1.AM23 v2(118.32,96.71)
  BOTTOM w0.127: PR422.2 139.22,133.86 139.22,134.28 138.84,134.65 135.2,134.65 133.22,132.67 132.75,132.67 131.42,131.34 131.29,131.34 130.97,131.02 130.97,130.75 v2(130.81,130.59)
VCCSA_B+: length 0.5
  TOP w0.127: v2(64.16,113.85) v1(64.16,113.31)
  vias: v2(64.77,113.85)
VCCSENSE: length 105.4
  TOP w0.127: RC140.1 110.42,120.2 v4(110.42,118.76) 110.42,118.11 112.02,116.51 112.02,114.79 v2(111.85,114.61)
  TOP w0.254: PC617.1 49.15,87.8 PC620.1 49.15,88.69 48.27,89.58 PR622.1 48.11,89.95 v2(48.11,90.51)
  IN1 w0.084: v2(111.85,114.61) 111.72,114.74 111.46,114.74 110.89,115.31 109.38,115.31 107.78,113.71 107.78,109.47 107.47,109.15 97.98,109.15 96.92,110.22 96.92,111.42 95.73,112.6 93.44,112.6 90.8,109.96 89.97,109.96 88.76,108.76 88.76,108.51 88.09,107.84 84.97,107.84 84.24,108.57 79.97,108.57 78.74,107.34 78.74,106.49 76.34,104.09 71.45,104.09 70.9,103.54 64.51,103.54 64.07,103.97 62.1,103.97 61.88,104.19 56.35,104.19 53.85,101.7 53.85,94.15 52.01,92.32 52.01,91.47 51.33,90.78 50.07,90.78 49.48,91.37 48.55,91.37 48.3,91.12 48.3,90.7 v2(48.11,90.51)
  BOTTOM w0.076: UC1.E32 113.71,111.09 113.71,111.52 113.78,111.6 113.78,111.84 113.68,111.94 113.68,112.09 113.78,112.19 113.78,112.53 113.61,112.71 113.61,112.94
  BOTTOM w0.127: 113.61,112.94 113.61,114.52 112.73,115.4 112.31,115.4 112.03,115.12 112.03,114.8 v2(111.85,114.61)
  BOTTOM w0.254: PC618.2 48.09,90.49 v2(48.11,90.51)
VCCST_PWRGD: length 335.4
  TOP w0.127: v2(267.18,95.91) 268.33,94.76 271.2,94.76 v1(271.74,95.3) 271.74,97.55 271.18,98.1 UE4.4 ; RE308.1 258.42,101.05 258.72,101.36 v2(261.49,101.36)
  IN1 w0.084: v2(74.38,65) 74.43,65.05 138.94,65.05 140.69,63.3 140.69,61.94 143.42,59.21 146.05,59.21 146.6,59.75 148.5,59.75 148.83,59.42 156.87,59.42 158.44,57.85 165.01,57.85 167.57,55.28 179.39,55.28 180.65,54.03 182.31,54.03 184.63,51.71 185.91,51.71 187.3,50.33 209.32,50.33 210.6,51.61 218.48,51.61 219.66,52.79 226.58,52.79 228.23,51.14 237.76,51.14 242.04,55.41 242.04,58.16 248.41,64.53 250.41,64.53 251.89,66 260.07,66 260.3,65.77 261.45,65.77 262.91,67.23 262.91,70.39 v2(262.73,70.56)
  IN4 w0.084: v2(74.38,65) 74.52,65.14 74.52,74.77 75.5,75.74 v2(75.5,85.97) ; v2(91.69,121.4) 91.64,121.4 88.86,118.62 88.86,118.34 87.63,117.1 80.77,117.1 78.64,114.97 78.64,111.69 v2(79.17,111.16)
  BOTTOM w0.127: v2(91.69,121.4) 91.69,120.88 91.45,120.65 RC71.1 RC123.1 CC301.1 RC78.1 ; v2(75.5,85.97) 77.91,88.38 77.91,92.88 79.43,94.4 79.43,101.35 78.94,101.84 78.94,110.93 v2(79.17,111.16) ; v2(261.49,101.36) 264.6,101.36 265.09,100.87 265.09,100.38 264.98,100.28 264.98,99.1 265.44,98.65 265.44,97.65 v2(267.18,95.91) 267.61,95.47 267.61,89.32 269.09,87.85 269.09,85.08 268.88,84.87 268.88,80.16 269.13,79.92 269.13,75.82 268.57,75.26 265.27,75.26 262.73,72.73 v2(262.73,70.56)
VCCST_PWRGD_CPU: length 10.2
  BOTTOM w0.076: 93.56,116.9 93.93,116.9 94.97,115.86 94.97,115 95.85,114.12 95.85,112.96 UC1.B65
  BOTTOM w0.112: 93.56,116.9 92.34,116.9
  BOTTOM w0.127: RC78.2 90.46,118.44 v1(90.46,117.93) 91.49,116.9 92.34,116.9
VCCST_PWRGD_EC: length 19.4
  TOP w0.127: UE1.K10 v2(254.28,91.46) ; v2(255.01,103.9) 254.81,104.09 RE552.2 254.27,104.74 v1(254.84,105.31) ; v2(254.47,99.78) 254.69,100 256.16,100 256.29,100.14 RE308.2
  IN1 w0.084: v2(255.01,103.9) 254.47,103.36 v2(254.47,99.78) 254.47,98.83 253.85,98.21 253.85,96.12 253.57,95.85 253.57,94.12 253.89,93.8 253.89,91.86 v2(254.28,91.46)
VCCSTG_EN: length 124.1
  TOP w0.127: UZ19.4 118.92,130.69 v1(118.57,130.34) 118.17,129.94 v2(118.17,129.88) ; v2(148.77,64.48) 148.62,64.33 147.39,64.33 145.94,65.78 143.17,65.78 142.64,66.3 RZ120.1
  IN1 w0.084: v2(138.68,96.67) 140.22,95.13 143.6,95.13 145.68,93.05 145.68,87.87 146.58,86.97 146.58,78.37 147.25,77.71 147.25,69.54 v2(150.91,65.87)
  IN2 w0.122: v2(118.17,129.88) 121.7,129.88 122.33,129.26 124.36,129.26 125,129.89 138.93,129.89 141.18,127.64 141.18,126.74 142.75,125.17 144.08,125.17 145.07,124.18 145.07,120.19 142.55,117.66 140.87,117.66 138.51,115.3 138.51,112.28 138.84,111.95 138.84,111.76 140.85,109.75 141.06,109.75 142.27,108.54 142.27,103.36 139.19,100.28 139.19,98.15 138.68,97.64 v2(138.68,96.67)
  IN4 w0.084: v2(148.77,64.48) 150.16,65.87 v2(150.91,65.87)
  BOTTOM w0.127: RZ320.2 123.53,130.93 UZ35.4 122.56,131.82 122.21,131.47 119.76,131.47 v2(118.17,129.88)
VDD_ISL9538: length 21.6
  TOP w0.127: v1(53.03,58.89) 53.47,58.45 v2(53.47,58.29) ; v2(49.93,58.43) 50.49,58.43 PR919.1
  TOP w0.203: PU901.18 54.02,58.04 53.77,58.29 v2(53.47,58.29)
  TOP w0.254: v2(62.95,58.75) 62.44,59.26 PR915.2
  IN1 w0.254: v2(49.93,58.43) 51.27,58.43 51.78,58.94 52.92,58.94 53.47,58.39 v2(53.47,58.29)
  IN2 w0.254: v2(53.47,58.29) 53.47,59.26 55.39,61.18 59.25,61.18 61.17,59.26 62.44,59.26 v2(62.95,58.75)
  BOTTOM w0.203: v2(53.47,58.29) 53.47,58.03 52.98,57.54 PR918.2
  BOTTOM w0.254: PR918.2 53.14,57.34 PC933.1
VDDP_ISL9538: length 3.6
  TOP w0.203: PU901.8 58.89,58.44 59.33,58.88 v2(59.33,59.26)
  TOP w0.254: PR915.1 v1(59.84,59.26) v2(59.33,59.26)
  BOTTOM w0.254: v2(59.33,59.26) 58.9,58.82 PC932.2
VIN_1.8VALW:
  vias: v1(170.78,66.24) v2(170.17,66.27) v2(170.54,66.7)
VIN_1V_PRIM: length 1.1
  BOTTOM w0.127: v1(162.68,128.97) 162.01,128.97 PC418.1
  vias: v2(160.3,129.4) v2(160.93,129.4)
VIN_1VS_VCCIO: length 2
  TOP w0.127: 145.47,130.08 146.44,130.08 v1(147.17,129.35)
  vias: v2(144.42,130.86) v2(145.06,130.86)
VSS_GT_SENSE: length 61.7
  TOP w0.127: RC163.1 88.1,108.64 v2(88.1,109.04) 88.42,109.36 v1(88.82,109.36)
  TOP w0.203: PU602.18 51.08,95.17 51.89,95.98 v2(52.15,95.98) 52.28,95.98 52.68,96.38 PC653.2 52.77,96.38 PC654.2
  IN1 w0.084: v2(52.15,95.98) 51.95,95.8 51.87,95.8 51.77,95.8 51.64,95.93 51.64,98.3 53.23,99.88 53.23,101.99 57.15,105.91 65.56,105.91 69.23,109.58 69.23,111.15 72.03,113.95 77.04,113.95 81.21,109.77 85.93,109.77 86.7,109 86.7,108.84 87.11,108.43 87.67,108.43 87.89,108.64 87.89,108.83 v2(88.1,109.04)
  BOTTOM w0.076: 90.48,108.04 91.3,108.04 91.34,108 92.07,108 92.33,108.17 92.62,108.17 92.88,108.43 UC1.J69
  BOTTOM w0.127: 90.48,108.04 89.5,108.04 89.44,108.1 89.44,108.1 88.5,109.04 v2(88.1,109.04)
VSSIO_SENSE: length 100.3
  TOP w0.127: v2(119.31,96.71) 118.8,97.22 RC167.1 ; v2(148.26,98.22) 148.42,98.38 151.51,98.38 153.35,100.22 153.35,102.27 152.87,102.76 152.87,104.45 150.78,106.53 150.78,109.03 149.84,109.97 149.84,111.12 150.86,112.13 150.86,118.62 151.3,119.07 151.3,120.08 148.06,123.32 145.6,123.32 143.8,125.13 135.74,125.13 134.1,126.77 132.96,126.77 131.23,128.5 131.23,130.42 v2(131.39,130.59)
  IN4 w0.084: v2(148.26,98.22) 148.09,98.39 146.42,98.39 146.08,98.73 145.14,98.73 144.98,98.58 143.04,98.58 142.83,98.37 142.23,98.37 141.43,97.56 137.99,97.56 137.1,96.68 135.61,96.68 134.9,97.38 132.63,97.38 131.28,98.73 130.29,98.73 130.16,98.87 125.02,98.87 124.15,99.73 119.28,99.73 118.8,99.26 118.8,97.66 118.99,97.48 118.99,96.85 119.12,96.71 v2(119.31,96.71)
  BOTTOM w0.076: UC1.AM22 v2(119.31,96.71)
  BOTTOM w0.127: PR412.2 138.96,133.73 138.96,134.18 138.74,134.4 135.3,134.4 133.32,132.42 132.85,132.42 131.52,131.08 131.4,131.08 131.23,130.91 131.23,130.75 v2(131.39,130.59)
VSSSENSE: length 105.4
  TOP w0.127: v2(112.48,114.62) 112.27,114.83 112.27,116.62 110.67,118.22 110.67,120.26 RC141.1
  TOP w0.203: PU602.6 48.33,90.97 48.7,90.61 v2(48.7,90.51) 48.7,90.3 49.02,89.98 49.02,89.69 PC620.2
  IN1 w0.084: v2(48.7,90.51) 48.51,90.7 48.51,91.03 48.63,91.16 49.4,91.16 49.99,90.57 51.41,90.57 52.22,91.38 52.22,92.23 54.06,94.07 54.06,101.61 56.44,103.98 61.79,103.98 62.02,103.76 63.99,103.76 64.42,103.33 70.98,103.33 71.53,103.88 76.43,103.88 78.95,106.4 78.95,107.25 80.06,108.36 84.15,108.36 84.89,107.63 88.18,107.63 88.98,108.42 88.98,108.67 90.05,109.75 90.94,109.75 93.55,112.36 95.63,112.36 96.67,111.31 96.67,110.12 97.88,108.91 107.58,108.91 107.99,109.33 107.99,113.62 109.47,115.09 110.8,115.09 111.68,114.22 112.08,114.22 v2(112.48,114.62)
  BOTTOM w0.076: 113.35,112.94 113.35,112.76 113.16,112.57 113.16,112.22 113.23,112.16 113.23,111.87 113.15,111.79 113.15,111.54 113.29,111.39 UC1.E33
  BOTTOM w0.127: 113.35,112.94 113.35,114.42 112.62,115.14 112.41,115.14 112.29,115.02 112.29,114.82 v2(112.48,114.62)
  BOTTOM w0.203: PC619.2 48.61,89.46 48.61,90.43 v2(48.7,90.51)
32KHZ_OUT: length 6.4
  TOP w0.127: v2(249.5,81.6) 249.5,81.42 CE54.1 248.55,80.92 v1(248.03,80.4) ; UE1.F3 v2(250.28,85.06)
  IN2 w0.122: v2(250.28,85.06) 250.28,82.38 v2(249.5,81.6)
+AC_IN: length 70.3
  TOP w0.254: PR1251.1 52.68,102.65 49.48,102.65 49.27,102.86 49.27,103.64 49.03,103.89 PQ1213.3
  IN4 w0.254: v2(36.98,59.51) 36.98,60 37.21,60.22 37.21,63.05 38.63,64.48 38.63,70.44 38.1,70.98 38.1,75.01 39.71,76.62 39.71,77.68 42.19,80.17 42.19,85.73 43.61,87.14 47.89,87.14 50.3,89.55 50.3,100.4 49.91,100.79 49.91,101.76 v2(47.37,104.3)
  BOTTOM w0.127: v1(33.17,55.83) 32.87,56.13 PR1255.1
  BOTTOM w0.254: v2(36.98,59.51) 36.79,59.32 33.17,59.32 32.87,59.02 PR1255.1
  BOTTOM w0.508: v2(45.9,103.8) 45.9,103.34 45.24,102.68 PQ1215.3
  vias: v2(32.41,117.23) v2(32.41,116.62) v2(32.41,116.03) v2(33.04,117.23) v2(33.04,116.62) v2(33.04,116.03) v2(40.22,114.69) v2(40.22,114.08) v2(40.22,113.49) v2(40.85,114.69) v2(40.85,114.08) v2(40.85,113.49) v2(41.49,114.69) v2(41.49,114.08) v2(41.49,113.49) v2(45.59,104.89) v2(45.59,104.3) v2(46.2,104.89) v2(46.2,104.3) v2(46.6,105.42) v2(46.79,104.89) v2(46.79,104.3) v2(47.19,105.42) v2(47.37,104.89)
+BL_PWR_SRC: length 14.2
  TOP w1.524: 56.92,133.11 56.77,132.96 49.45,132.96 v3(49.3,133.11) 48.41,132.22 v3(48.41,131.14) v3(48.41,129.3) 46.82,127.71
  vias: v2(59.09,131.62) v2(59.66,131.62) v2(60.23,131.62)
+CHARGER_SRC:
  vias: v1(49.37,71.31) v2(46.87,71.74) v2(46.87,70.67) v2(47.87,74.67) v2(47.9,74.02) v2(47.86,73.34) v2(48.49,74.63) v2(48.49,74) v2(48.49,73.36) v2(48.8,75.13) v2(49.12,74.63) v2(49.12,74) v2(49.12,73.36)
+COINCELL: length 3.8
  TOP w0.127: v2(283.95,8.03) v1(283.95,7.43)
  TOP w0.508: v2(283.95,8.03) 283.95,8.03 PC2.2 283.93,8.98 PR2.1
  BOTTOM w0.508: JRTC1.1 v2(283.95,8.03)
+DC_IN: length 97
  TOP w0.127: v2(32.08,61.35) v3(32.92,60.52) ; v2(32.08,61.35) 32.08,62.09 v3(31.92,62.25) ; v2(32.08,61.35) v3(31.15,60.42)
  TOP w0.508: v2(42.71,53.56) 42.5,53.35 PR1201.1
  IN1 w0.508: v2(32.08,61.35) 32.08,58.89 34.95,56.03 37.22,56.03 39.87,53.38 42.53,53.38 v2(42.71,53.56)
  IN3 w0.508: v2(44.84,119.08) 44.84,115.92 41.3,112.38 41.3,100.45 40.94,100.1 40.94,97.73 40.66,97.45 40.17,97.45 39.66,96.94 39.66,91.22 42.08,88.8 42.08,80.12 ; v2(32.08,61.35) 35.37,61.35
  BOTTOM w0.508: 62.63,122.06 63.05,122.47 63.84,122.47 64.38,123.01 64.38,123.59 65.17,124.38 68.27,124.38 69.55,123.1 69.55,121.71 68.86,121.02 PU2.1 ; 62.63,122.06 60.48,124.22 49.67,124.22 48.64,123.19 46.62,123.19 ; 62.63,122.06 62.63,120.66 63.14,120.15 PC11.1
  vias: v2(45.28,119.52) v2(46.51,119.52)
+DC_IN_SS: length 82.2
  TOP w0.127: v3(47.31,61.67) 47.16,61.82 v2(46.51,61.82)
  IN3 w0.508: v2(46.51,61.82) 46.86,62.17 56.46,62.17 59.19,64.9 59.19,70.41 58.37,71.24 58.37,78.37 63.82,83.83 63.82,89.47 67.74,93.38 67.74,96.63 65.76,98.6 65.76,106.48 61.92,110.33 60.31,110.33 55.79,114.85 v2(55.79,117.14)
  BOTTOM w0.508: PD904.2 v2(46.51,61.82) ; v2(55.79,117.14) 52.85,117.14 52,117.99
+DCIN_JACK: length 6.6
  BOTTOM w0.127: v1(38.25,125.93) 39.33,124.85 v1(39.77,124.85) 40.73,123.9 v1(40.73,122.5) 40.73,121.29 PL4.1
+DCPRTC: length 9
  TOP w0.381: CC214.1 131.81,85.39 131.47,85.74 v2(131.47,86.69)
  BOTTOM w0.203: v2(131.47,86.69) 128.74,89.42 128.37,89.42 127.81,89.98 127.23,89.98 126.85,90.35 UC1.BB10
+DDR_VREF_A_CA: length 6.3
  TOP w0.127: v1(118.97,55.61) v2(118.97,55)
  TOP w0.508: CD25.1 117.89,53.29 RD17.1 ; CD25.1 CD26.1 ; CD25.1 RD16.1 ; CD26.1 RD15.2 ; CD26.1 118.76,54.78 v2(118.97,55)
  BOTTOM w0.254: v2(118.97,55) 118.98,55 JDIMM1.164
+DDR_VREF_A_DQ: length 1.1
  TOP w0.254: T132.1 v2(93.09,91.98)
  BOTTOM w0.203: UC1.AY68 93.34,91.73 v2(93.09,91.98)
+DDR_VREF_B_DQ: length 1.4
  TOP w0.254: T226.1 94.21,91.22 v2(93.7,91.22)
  BOTTOM w0.203: UC1.BA67 93.81,91.34 v2(93.7,91.22)
+DDR_VREF_CA: length 102.3
  TOP w0.508: v2(76.48,84.34) v1(78.08,82.74) 79.4,81.42 79.4,72.78 75.08,68.46 75.08,64.53 74.7,64.15 v2(74.38,64.15) ; v2(116.99,51.76) CD31.1 RD17.2
  IN1 w0.508: v2(116.99,51.76) 116.99,53.22 116.36,53.86 77.24,53.86 76.54,54.56 76.54,61.99 v2(74.38,64.15)
  BOTTOM w0.203: UC1.AY67 94.2,91.85 94.55,91.51 94.55,90.8 94.72,90.63 94.72,90.05 94.4,89.74 92.01,89.74 91.53,89.25
  BOTTOM w0.508: 91.53,89.25 90.47,88.2 90.47,86.85 87.2,83.58 77.24,83.58 v2(76.48,84.34)
+EC_DEBUG_VCC: length 1.4
  TOP w0.127: v2(289.82,126.63) 288.96,127.48 v3(288.76,127.48)
+EDP_VDD:
  vias: v1(67.55,126.95)
+LCDVDD:
  vias: v2(65.43,131.13) v2(65.43,130.55) v2(65.43,129.98) v3(66.57,133.81) v3(68.1,134.63) v3(69.62,133.81)
+LINE1-VREFO-L: length 2.3
  TOP w0.203: RA57.1 v1(257.45,56.07) 257.45,56.47 257.53,56.55 UA1.31
+LINE1-VREFO-R: length 2.5
  TOP w0.203: RA58.1 257.01,55.46 257.01,56.5 257.13,56.61 UA1.30
+MIC2-VREFO: length 16.7
  TOP w0.127: v2(256.06,53.35) v1(256.06,52.82)
  TOP w0.203: 256.5,55.95 256.5,56.46 256.73,56.69 UA1.29
  TOP w0.254: 256.5,55.95 255.93,55.38 255.93,53.48 v2(256.06,53.35)
  TOP w0.508: v2(250.22,60.63) 250.56,60.97 RA6.1 RA5.1
  IN2 w0.508: v2(250.22,60.63) 250.22,60.06 251.08,59.19 251.86,59.19 252.82,58.24 252.82,57.22 256.06,53.99 v2(256.06,53.35)
+PBATT: length 126.7
  TOP w0.254: v2(58.15,51.48) 58.38,51.71 PR940.1
  TOP w0.508: v2(163.32,51.93) 163.32,55.42 166.81,58.91 167.97,58.91 168.35,59.28 170.75,59.28 171.16,58.88
  IN1 w0.508: v2(144.14,52.11) 144.16,51.96 144.76,51.47 145.54,51.47 148.68,54.61 159.27,54.61 161.95,51.93 v2(163.32,51.93)
  IN4 w0.508: v2(58.15,51.48) 58.15,51.9 58.92,52.68 62.57,52.68 64.95,55.06 69.18,55.06 71.22,53.02 72.06,53.02 74.8,50.28 138.99,50.28 141.5,52.79 143.46,52.79 v2(144.14,52.11)
  vias: v3(175.47,59.14)
+PECI_VREF: length 7.1
  TOP w0.254: UE1.J11 v2(253.48,92.26)
  TOP w0.356: v2(253.96,94.37) 254.26,94.67 254.26,96.02 254.68,96.44 CE25.1 254.99,96.49 254.99,97.17 RE59.1
  BOTTOM w0.254: v2(253.96,94.37) 253.49,94.37 253.01,93.89 253.01,92.73 v2(253.48,92.26)
+PWR_SRC: length 145.8
  TOP w0.254: v2(224.46,52.11) 223.72,52.11 223.53,52.3 RZ85.1
  IN2 w0.508: v2(61,61.84) 60.89,61.96 55.21,61.96 52.6,59.35 48.77,59.35 v2(47.84,58.42)
  IN2 w1.524: 43.74,120.95 46.62,120.95 47.99,122.32 52.92,122.32 55.29,119.95 56.51,119.95 57.17,119.29
  IN4 w1.27: 57.86,116.11 57.86,112.37 59.39,110.84 61.4,110.84 64.07,108.17 66.33,108.17 68.45,106.06 68.45,102.19 69.31,101.33 69.31,95.96 67.03,93.68 67.03,89.15 71.06,85.12 71.06,80.81
  BOTTOM w0.254: 61.57,61.45 61.78,61.25 61.78,57.95 PR929.2 ; 183.72,49.49 183.87,49.34 221.69,49.34 v2(224.46,52.11) ; PR102.2 181.8,59.14 180.69,59.14 180.17,58.62 179.52,58.62 179.08,59.07 178.46,59.07 176.33,56.94 176.33,54.25 174.21,52.12 174.21,49.91 174.86,49.26 180.01,49.26 v2(180.32,49.58)
  BOTTOM w0.508: v2(47.84,58.42) 46.96,57.54 PD901.2
  vias: v2(42.13,122.17) v2(42.73,122.17) v2(43.31,122.17) v2(57.62,117.93) v2(58,117.49) v2(58.38,117.93) v2(59.37,73.17) v2(59.37,72.52) v2(59.83,75.98) v2(59.75,74.32) v2(59.86,75.34) v2(60.03,72.47) v2(60.08,70.71) v2(60.72,70.71) v2(60.67,68.65) v2(60.67,67.07) v2(60.87,65.71) v2(60.88,63.22) v2(61.3,68.65) v2(61.3,67.07) v2(61.5,65.71) v2(61.48,64.48) v2(61.49,63.28) v2(61.55,62.2) v2(73.49,77.48) v2(73.49,76.85) v2(73.49,76.21) v2(74.13,77.48) v2(74.13,76.85) v2(74.13,76.21) v2(74.76,77.48) v2(74.76,76.85) v2(74.76,76.21) v2(150.94,81.76) v2(150.94,80.64) v2(150.93,80.07) v2(150.96,81.2) v2(151.52,81.74) v2(151.53,81.18) v2(151.57,80.62) v2(151.56,80.04) v2(164.89,51.83) v2(164.89,51.2) v2(164.89,50.56) v2(165.52,51.83) v2(165.52,51.2) v2(165.52,50.56) v2(166.16,51.83) v2(166.16,51.2) v2(166.16,50.56) v2(166.79,51.83) v2(166.79,51.2) v2(166.79,50.56) v2(167.43,51.83) v2(167.43,51.2) v2(167.43,50.56) v2(168.06,51.83) v2(168.06,51.2) v2(168.06,50.56) v2(168.7,51.83) v2(168.7,51.2) v2(168.7,50.56) v2(180.32,50.17) v2(180.9,50.17) v2(180.9,49.57) v2(181.54,50.17) v2(181.54,49.57) v2(182.17,50.17) v2(182.17,49.57) v3(165.82,53.35)
+PWR_SRC_AC:
  vias: v1(44.47,85.8) v2(43.58,85.29) v2(43.59,84.72) v2(44.15,85.31) v2(44.17,84.73) v2(44.74,84.7) v2(44.77,85.29) v2(45.33,85.33) v2(45.35,84.68) v2(45.97,85.33) v2(45.98,84.72)
+PWR_SRC_R: length 20.6
  TOP w0.254: v2(234.39,59.45) 235.06,58.78 235.06,58.04 CZ78.2 235.74,57.36 235.74,52.96 234.28,51.5 228.85,51.5 227.91,52.44 v3(225.88,52.44) 225.22,52.44 224.81,52.84 RZ85.2
  BOTTOM w0.305: v2(234.39,59.45) 233.97,59.02 JUSH1.1
+REGCTL_PNP10: length 1.5
  BOTTOM w0.127: LL1.1 v1(249.96,125.07)
  vias: v2(246.53,121.78) v2(246.53,121.2) v2(250.82,124.34) v2(251.23,123.95)
+RREF: length 4.4
  TOP w0.127: v1(270.99,60.82) RR4.1
  TOP w0.203: 273.68,62.32 273.87,62.5 UR1.9
  TOP w0.305: 273.68,62.32 271.55,62.32 RR4.1
+RSVD_VCC3P3_1: length 4
  TOP w0.203: UL1.1 244.08,122.64 243.87,122.44 242.71,122.44 v1(242.02,121.75) RL6.1
+RTC_CELL: length 298.7
  TOP w0.508: v2(281.06,63.41) 281.06,60.93 277.72,57.59 v2(277.72,54.88) 278.41,54.18 278.41,51.76 280.5,49.67 280.5,28.78 285.9,23.38 v3(285.9,18.58) PC3.1 PD3.1 ; RE508.2 RE507.2 237.78,84.39 236.82,83.42 235.93,83.42 232.9,80.4 232.9,78.17 v2(233.64,77.43) ; RE32.1 RE31.1 v2(245.07,78.64) ; RE324.2 v2(246.21,74.22) ; RE551.2 238.64,105 v2(239.48,104.16) 241.44,104.16 242.2,103.4 242.2,102.6 242.59,102.21 242.59,100.34 243.05,99.88 243.05,98.99 243.41,98.64 QE15.3 ; v2(248.5,59.07) RA54.2 ; v2(229.45,88.83) 229.91,89.29 229.91,95.57 229.06,96.41 229.06,109.27 233.86,114.06 235.43,114.06 v2(235.53,113.96) 236.6,113.96 237.28,114.65 238.04,114.65 239.2,113.48 242.34,113.48 244.41,111.42 v2(245.74,111.42)
  IN1 w0.508: v2(245.07,78.64) 245.07,76.5 246.21,75.36 v2(246.21,74.22) 244.61,74.22 243.64,73.24 243.64,71.92 242.96,71.25 242,71.25 240.18,73.07 239.24,73.07 238.73,73.58 238.73,76.52 237.82,77.43 v2(233.64,77.43) ; v2(225.77,78.31) 225.77,79.4 229.45,83.08 v2(229.45,88.83)
  IN2 w0.508: v2(233.64,77.43) 231.6,77.43 230.72,78.31 v2(225.77,78.31) ; v2(248.5,59.07) 248.63,59.07 250.5,57.19 250.5,54.38 252.46,52.42 264.66,52.42 268.95,56.7 272.58,56.7 274.4,54.88 v2(277.72,54.88) ; v2(235.35,102.27) 236.24,102.27 238.03,104.06 239.38,104.06 v2(239.48,104.16) ; v2(281.5,68.18) 280.3,68.18 279.66,67.55 279.66,65.1 280.19,64.57 280.7,64.57 281.06,64.21 v2(281.06,63.41)
  IN4 w0.508: v2(235.35,102.27) 235.1,102.27 233.62,103.76 233.62,112.05 v2(235.53,113.96) ; v2(264.16,110.55) 271.74,102.97 271.74,99.9 273.61,98.03 275.33,98.03 276.29,97.07 276.29,85.5 281.65,80.15 281.65,72.21 282.43,71.43 282.43,68.98 281.62,68.18 v2(281.5,68.18)
  BOTTOM w0.508: v2(264.16,110.55) 263.9,110.81 257.49,110.81 257.02,110.33 254.68,110.33 254.2,110.81 252.3,110.81 251.71,110.21 246.25,110.21 245.74,110.72 v2(245.74,111.42)
+RTC_CELL_PCH: length 196.1
  TOP w0.381: v2(124.43,90.14) 125.26,90.14 126.43,88.97 126.43,87.34 126.76,87.01 126.76,84.66 126.49,84.39 CC270.1 126.49,83.95 RC69.2 126.5,83.15 v2(126.04,82.69) ; RC57.2 130.08,80.66 RC56.2
  TOP w0.508: v2(130.99,80.59) 130.77,80.8 RC56.2 ; v2(150.22,74.78) 149.67,74.78 149.12,74.23 147,74.23 v2(146.75,74.47) ; v2(239.05,106.11) 238.11,106.11 237.72,105.72 RE551.1 237.72,104.73 238.11,104.34 CE63.1 238.69,103.5 RE546.1 ; v2(239.93,98.19) 239.93,98.06 240.95,97.04 QE15.1
  IN1 w0.508: v2(143.22,80.14) 140.55,80.14 137.77,77.36 132.45,77.36 130.77,79.04 130.77,80.37 v2(130.99,80.59) ; v2(239.93,98.19) 238.91,98.19 238.4,98.7 238.4,105.46 v2(239.05,106.11)
  IN2 w0.508: v2(146.75,74.47) 146.75,75.1 146.26,75.59 146.26,76.31 146.25,76.32 146.25,79.23 145.4,80.08 143.28,80.08 v2(143.22,80.14) ; v2(130.99,80.59) 128.79,80.59 126.69,82.69 v2(126.04,82.69)
  IN4 w0.508: v2(150.22,74.78) 150.61,74.78 150.9,74.48 150.9,71.63 151.75,70.78 161.37,70.78 165.53,66.62 166.62,66.62 167.37,67.37 175.03,67.37 175.65,66.75 181.36,66.75 183.02,65.09 188.01,65.09 188.52,64.58 232.02,64.58 232.65,65.21 234.91,65.21 235.27,65.57 235.27,67.83 237.57,70.13 239.5,70.13 240.52,71.14 240.52,73.48 240.07,73.93 240.07,75.53 237.84,77.77 236.86,77.77 234.46,80.17 234.46,89.27 237.25,92.05 237.25,93.1 238.51,94.37 238.51,97.25 239.46,98.19 v2(239.93,98.19)
  BOTTOM w0.203: UC1.BB14 v2(124.43,90.14)
  BOTTOM w0.254: UC1.AK19 v2(121.07,97.34)
  vias: v1(121.44,95.45)
+RTC_CELL_VBAT: length 5.3
  TOP w0.254: v2(246.18,84.28) 246.3,84.28 UE1.A2 ; v2(244.77,81.91) 244.47,81.61 CE11.1 244.47,80.69 RE32.2
  IN1 w0.254: v2(244.77,81.91) 244.91,82.04 244.91,82.47 246.18,83.74 v2(246.18,84.28)
+SDC_IN: length 15.8
  TOP w0.508: PR10.1 51.85,114.96 51.6,114.7 PQ5.3 49.54,114.7 49.46,114.78 47.8,114.78 46.61,113.59 46.61,112.56 45.24,111.19 45.24,110.37 45.58,110.03 46.99,110.03 PC1203.1 ; PR944.1 51.79,62.16 53.11,60.84 PR943.1 52.73,60.21 v2(52.4,60.21)
  vias: v2(48.46,80.49) v2(48.45,79.91) v2(48.76,111.06) v2(48.92,110.5) v2(49.01,111.57) v2(49.05,79.89) v2(49.08,80.46) v2(49.34,111.08) v2(49.5,110.5) v2(49.66,80.49) v2(49.65,79.9) v2(49.91,111.04) v2(50.07,110.48) v2(50.22,81.07) v2(50.22,80.49) v2(50.21,79.9) v2(50.43,111.23) v2(50.64,110.39) v2(50.82,80.72) v2(50.89,110.89) v3(48.79,80.97)
+SDREG2: length 1
  TOP w0.127: 278.81,66.97 v1(278.81,67.96)
+SIM_PWR: length 100
  TOP w0.127: v2(275.49,55.76) v3(276.38,54.87)
  IN4 w0.508: v2(277.21,62.81) 272.11,62.81 272.06,62.86 271.97,62.86 v2(271.92,62.91)
  BOTTOM w0.305: JNGFF2.28 239,103
  BOTTOM w0.508: 239,103 239.95,103 240.74,103.79 245.52,103.79 246.07,103.24 257.14,103.24 257.52,103.62 265.44,103.62 266.97,102.1 266.97,99.63 269.39,97.2 269.39,90.18 271.92,87.65 271.92,67.8 271.06,66.94 271.06,63.77 v2(271.92,62.91) 271.88,62.86 271.74,62.86 270.76,61.89 270.76,59.61 274.61,55.76 v2(275.49,55.76) RZ335.1 ; JSIM1.C1 284.51,61.35 284,60.84 280.5,60.84 279.48,61.86 278.74,61.86 CZ37.1 CZ41.1 277.65,62.38 v2(277.21,62.81)
+TBTA_LDO_BMC: length 3.4
  BOTTOM w0.203: CT71.1 32.8,76.34 32.43,76.34 32.21,76.57 32.21,77.61 32.02,77.79 UT5.E1
+TBTA_VBUS: length 1.2
  BOTTOM w0.356: CT100.1 9.33,110.67 v2(9.35,110.68)
  BOTTOM w0.381: v2(9.35,110.68) 9.41,110.62 CT189.1
  vias: v2(8.74,108.39) v2(8.74,105.88) v2(9.32,108.39) v2(9.3,105.89) v2(13.72,112.24) v2(13.71,111.6) v2(14.3,112.22) v2(14.32,111.62) v2(16.69,116.2) v2(16.73,115.62) v2(16.72,114.91) v2(17.32,116.2) v2(17.34,115.58) v2(17.35,114.91) v2(21.37,115.97) v2(21.37,115.34) v2(21.37,114.7) v2(21.95,115.97) v2(21.95,115.34) v2(21.95,114.7) v3(16.66,114.31)
+TBTA_VBUS_1: length 32
  TOP w0.381: PR1239.1 38.07,53.35 v2(38.1,53.32)
  TOP w0.508: PR1227.1 27.85,121.81 27.99,121.68 PQ1206.5
  IN1 w0.508: v2(38.1,53.32) 35.78,53.32 33.83,55.27 31.01,55.27 26.34,59.95 v2(24.94,59.95)
  IN2 w0.508: 21.27,71.23 21.27,68.13 22.64,66.75 22.64,61.86 24.55,59.95 v2(24.94,59.95)
  vias: v1(26.31,117.94) v2(18.03,75.11) v2(18.03,74.53) v2(18.6,75.11) v2(18.6,74.53) v2(19.2,75.07) v2(19.2,74.5) v2(26.44,117.3) v2(26.44,116.66) v2(26.44,116.03) v2(26.44,115.39) v2(26.44,114.76) v2(26.44,114.12) v2(27.86,85.28) v2(28.46,85.26) v2(28.88,84.64) v2(28.85,84.08) v2(29.03,85.23) v2(29.61,85.25) v2(34.66,83.09)
+USB_EX2_PWR: length 2.2
  TOP w0.127: v2(18.57,55.83) v3(20.75,55.83)
  vias: v2(18.06,67.19) v2(18.06,66.56) v2(18.57,57.73) v2(18.57,57.1) v2(18.57,56.46) v2(18.69,67.19) v2(18.69,66.56)
+UZ12_TPM: length 0.5
  BOTTOM w0.127: 161.92,113.76 v1(162.43,113.76)
+UZ12_VHIO: length 13.3
  IN2 w0.508: v2(161.82,106.57) 161.82,106.08 161.33,105.59 v2(156.49,105.59)
  BOTTOM w0.127: v1(155.09,106.12) 155.27,106.12 155.8,105.59 v2(156.49,105.59)
  BOTTOM w0.254: UZ12.14 162.1,109.22 162.93,108.39 CZ53.1 ; UZ12.22 158.33,106.4 158.05,106.12 157.5,106.12 157.25,105.87 CZ54.1
  BOTTOM w0.381: CZ54.1 v2(156.49,105.59)
+VCHGR:
  vias: v1(174.53,51.88) v2(175.1,52.11) v2(175.1,51.52)
+VHDMI_VCC: length 1.1
  TOP w0.381: RV22.2 v2(15.43,90.6)
  vias: v1(14.72,89.08) v2(10.09,94.94) v2(10.09,94.36) v2(10.68,94.94) v2(10.68,94.36) v2(15.38,89.36) v2(15.38,88.79)
+VR_CAP: length 26.5
  TOP w0.254: UE1.C10 v2(247.88,91.46) ; UE1.J1 253.08,82.87 254.86,81.09 CE31.1
  TOP w0.508: CE31.1 254.09,80.8 v2(254.02,80.86)
  IN2 w0.381: v2(249.5,82.76) 249.17,83.09 245.13,83.09 v2(244.97,83.26)
  IN4 w0.381: v2(244.97,83.26) 244.91,83.32 244.91,84.41 245.77,85.28 245.77,90.24 246.99,91.46 v2(247.88,91.46) ; v2(254.02,80.86) 254.33,81.16 254.33,82.08 253.52,82.89 249.63,82.89 v2(249.5,82.76)
+Z4012: length 2.8
  TOP w0.127: v1(285.25,8.89) PD3.2
  TOP w0.508: PD3.2 284.42,10.82 PR2.2
AC1_DISC#: length 62.9
  TOP w0.127: PR1244.1 40.71,52.3 41.01,52.59 42.7,52.59 43.01,52.91 43.46,52.91 v1(44.22,53.67) v2(44.22,57.35)
  IN1 w0.084: v2(44.22,57.35) 37.56,57.35 33.68,61.24 v2(33.68,61.95)
  IN2 w0.122: v2(33.68,61.95) 35.94,64.22 35.94,65.47 32.23,69.18 32.23,73.66 34.95,76.38 34.95,77.78 36.57,79.4 37.45,79.4 37.62,79.56 37.62,80.9 36.8,81.72 36.8,88.39 36.11,89.08 31.69,89.08 30.24,87.64 30.24,87.29 v2(30.45,87.09)
  BOTTOM w0.127: v2(30.45,87.09) 30.49,87.04 RT72.1
  BOTTOM w0.254: PR939.1 v2(44.22,57.35)
AC1_DISC#_R: length 2.3
  BOTTOM w0.076: 30.49,84.56 31.02,84.04 UT5.G11
  BOTTOM w0.127: RT72.2 30.49,84.56
AC_DIS: length 310.5
  TOP w0.127: RE83.1 v2(251.8,97.92) 252.25,97.47 252.25,97.27 252.4,97.12 252.65,97.12 252.82,96.95 252.82,95.25 252.7,95.13 252.7,93.08 UE1.H12 ; v2(270.46,90.96) v1(269.84,90.96)
  IN2 w0.122: v2(49.85,55.6) 52.38,55.6 53.16,54.82 58.42,54.82 59.29,53.95 60.53,53.95 62.15,55.57 69.27,55.57 70.25,54.59 71.29,54.59 74.8,51.08 138.65,51.08 142.24,53.87 146.67,53.87 148.14,55.35 158.82,55.35 160.87,53.3 169.92,53.3 173.28,49.95 178.94,49.95 179.95,50.95 182.52,50.95 184.02,49.45 208.88,49.45 210.63,51.2 213.3,51.2 214.17,50.33 237.41,50.33 239.77,52.68 239.77,54.17 240.16,54.57 246.93,54.57 247.45,55.08 247.45,56.53 246.75,57.23 246.75,60.19 249.95,63.39 250.47,63.39 251.25,64.17 254.71,64.17 255.2,63.68 257.07,63.68 257.36,63.39 260.95,63.39 261.47,63.92 261.47,64.98 263.8,67.31 269.15,67.31 271.27,69.43 271.27,76.95 267.99,80.24 267.99,83.61 266.94,84.66 266.94,86.55 270.46,90.08 v2(270.46,90.96)
  IN4 w0.084: v2(251.8,97.92) 253.61,97.92 258.55,102.86 263.22,102.86 264.16,101.92 266.83,101.92 268.37,100.37 268.37,98.94 270.46,96.86 v2(270.46,90.96)
  BOTTOM w0.203: PQ909.2 50.55,56.69 50.81,56.95 PR927.1 50.24,57.29 49.85,56.9 v2(49.85,55.6)
AC_DISC#: length 399.5
  TOP w0.127: v1(51.19,51.18) PR1231.1 v2(50.06,50.57) ; PC1217.1 248.94,96.95 249.66,96.23 v2(249.66,95.89) 249.88,95.68 UE1.E13 ; PR25.2 53.41,115.45 53.29,115.58 47.77,115.58 45.81,113.61 45.81,112.57 v2(43.65,110.41)
  IN2 w0.122: v2(50.06,50.57) 50.06,50.48 50.57,49.97 59.16,49.97 61.05,51.87 61.05,53.66 62.73,55.35 69.17,55.35 70.15,54.36 71.2,54.36 74.71,50.86 138.72,50.86 142.29,53.62 146.77,53.62 148.27,55.12 158.73,55.12 160.77,53.08 169.79,53.08 173.18,49.69 179.06,49.69 180.09,50.73 182.42,50.73 183.93,49.22 208.97,49.22 210.72,50.98 213.2,50.98 214.12,50.06 237.5,50.06 239.99,52.55 239.99,54.08 240.26,54.34 247.02,54.34 247.67,54.99 247.67,56.63 247.03,57.26 247.03,60.14 250.05,63.16 250.56,63.16 251.34,63.94 254.62,63.94 255.11,63.45 256.98,63.45 257.27,63.17 261.04,63.17 261.7,63.82 261.7,64.89 263.02,66.21 265.17,66.21 v2(265.65,66.69) ; v2(249.66,95.89) 249.72,95.84 250.97,95.84 251.77,96.65 254.68,96.65 256.95,98.92 257.53,98.92 257.7,99.09 258.85,99.09 259.15,98.79 259.15,94.74 260.57,93.32 261.49,93.32 262.85,91.96 262.85,89.22 264.43,87.64 264.43,86.55 264.77,86.21 264.77,83.54 265.24,83.07 265.63,83.07 265.94,82.75 v2(265.94,82.09) ; v2(43.65,110.41) 43.06,109.83 43.06,109.33 43.36,109.04 43.36,108.04 41.85,106.53 41.85,101.01 41.05,100.22 41.05,97.98 39.9,96.82 39.9,91.51 41.15,90.27 41.15,83.51 40.27,82.63 40.27,80.37 39.88,79.98 39.88,79.34 38.67,78.13 38.67,77.41 37.14,75.88 37.14,70.22 v2(36.95,70.03)
  IN4 w0.084: v2(50.06,50.57) 50.3,50.81 50.3,53.46 49.65,54.11 46.91,54.11 45.64,52.84 45.28,52.84 44.2,51.76 43.48,51.76 42.77,52.47 40.17,52.47 36.87,55.78 36.87,57.91 35.58,59.2 35.58,62.93 37.6,64.96 37.6,69.38 v2(36.95,70.03)
  BOTTOM w0.127: v2(265.94,82.09) 265.94,80.77 264.44,79.27 264.44,76.01 261.76,73.33 261.76,71 261.15,70.39 261.15,69.04 262.36,67.83 264.51,67.83 v2(265.65,66.69) ; PQ1211.6 47.89,51.78 49.19,50.48 PQ1211.3 49.52,50.57 v2(50.06,50.57) 50.19,50.7 50.19,51.42 50.55,51.78 PQ1210.6 51.07,52.08 PR1245.1 ; PR1223.2 41.66,109.41 42.81,109.41 43.65,110.25 v2(43.65,110.41)
AC_PRESENT: length 187.3
  TOP w0.127: v2(138.11,79.54) 137.6,79.54 RC243.1 ; UE1.K8 v2(254.28,89.86)
  IN2 w0.122: v2(257.13,69.51) 257.13,69.53 256.72,69.94 256.42,69.94 255.53,70.82 254.08,70.82 253.52,70.26 251.09,70.26 250.07,69.24 249.07,69.24 248.86,69.45 247.83,69.45 246.88,68.5 246.88,67.27 242.67,63.06 241.99,63.06 238.86,59.94 236.35,59.94 235.37,60.92 227.17,60.92 226.84,60.58 218.89,60.58 218.35,60.04 216.4,60.04 215.33,58.98 208.47,58.98 208.02,59.43 205.32,59.43 202.3,62.44 184.95,62.44 183.57,63.83 178.62,63.83 178.14,63.34 173.9,63.34 171.8,65.44 166.04,65.44 165.86,65.62 161,65.62 157.79,68.83 150.98,68.83 145.96,73.85 145.96,75.19 145.21,75.93 145.21,77.07 v2(145.47,77.32)
  BOTTOM w0.076: 125.42,87.3 123.44,89.28 123.44,91.14 123.55,91.25 123.55,91.53 UC1.AY15
  BOTTOM w0.127: v2(257.13,69.51) 257.88,70.27 257.88,72.77 257.21,73.45 257.21,75.12 257.64,75.55 257.64,76.64 256.96,77.32 256.96,78.95 257.82,79.81 257.82,81.01 257.95,81.14 257.95,84.68 257.26,85.37 257.26,86.43 256.29,87.4 256.29,90.07 256.1,90.26 254.69,90.26 v2(254.28,89.86) ; 125.42,87.3 v4(125.74,86.98) 126.26,86.46 126.26,85.88 127.72,84.42 127.72,82.08 131.05,78.75 135.58,78.75 135.93,79.1 136.18,79.1 136.62,79.54 v2(138.11,79.54) 141.31,79.54 142.07,78.78 142.07,78.56 142.77,77.86 144.93,77.86 v2(145.47,77.32)
ACAV_IN: length 253.7
  TOP w0.127: UE1.C7 v2(247.88,88.26)
  TOP w0.254: v2(43.52,56.78) 43.46,56.72 PR953.1
  IN2 w0.122: v2(230.32,53.64) 229.99,53.32 226.49,53.32 225.86,53.95 225.84,53.95 225.79,54 222.58,54 222.22,53.64 219.36,53.64 218.99,54.01 214.25,54.01 213.73,53.49 209.54,53.49 208.75,52.7 207.14,52.7 206.15,51.71 204.09,51.71 203.01,52.79 203.01,54.81 200.92,56.9 198.71,56.9 198.57,57.03 187.46,57.03 187,57.49 185.17,57.49 184.3,56.61 178.31,56.61 177.3,55.6 167.3,55.6 165.73,57.17 145.7,57.17 v2(145.52,57.35) ; v2(247.88,88.26) 246.97,88.26 246.24,87.53 242.92,87.53 242.73,87.71 242.13,87.71 241.27,88.57 238.58,88.57 237.72,87.72 237.72,86.6 236.36,85.24 v2(236.36,82.31)
  IN4 w0.084: v2(43.52,56.78) 44.54,56.78 44.98,57.22 50.33,57.22 53.03,54.52 58.61,54.52 59.07,54.06 60.63,54.06 62.48,55.92 69.77,55.92 71.83,53.86 72.62,53.86 75.26,51.22 135.79,51.22 138.63,54.06 143.86,54.06 145.52,55.72 v2(145.52,57.35)
  BOTTOM w0.127: v2(230.32,53.64) 231.11,54.43 231.47,54.43 233.05,56.02 233.05,57.18 235.71,59.84 235.71,62.25 235.07,62.9 235.07,67.06 234.78,67.34 234.78,70.12 235.42,70.76 235.42,80.36 236.1,81.03 236.1,82.04 v2(236.36,82.31)
  BOTTOM w0.254: v2(43.52,56.78) 43.27,56.53 v1(43.27,56.09) PR946.2
ACAV_IN1: length 8.7
  BOTTOM w0.203: PR925.1 53.72,56.58 PR918.1 PR928.1 52.87,55.71 52.45,55.29 52.45,54.85 51.91,54.31 PQ909.1 50.73,53.83
  BOTTOM w0.254: PR942.1 49.81,54.19 v1(50.16,53.83) 50.73,53.83
ACIN_ISL9538: length 9.2
  TOP w0.127: v1(49.48,62.14) 50.63,62.14 PR944.2
  TOP w0.203: 53.86,57.73 53.95,57.64 PU901.19
  TOP w0.254: PC955.1 50.66,62.9 PR944.2 50.93,61.9 50.93,61.73 51.48,61.17 PR945.1 51.48,60.18 52.06,59.61 52.06,58.41 52.73,57.73 53.86,57.73
ACOK_ISL9538: length 3.6
  TOP w0.127: v1(52.98,53.55) v2(52.98,54.11)
  TOP w0.203: v2(52.98,54.11) 53.91,55.04 53.91,55.42 54.13,55.64 PU901.24
  BOTTOM w0.203: PR928.2 v2(52.98,54.11)
ADP_ISL9538: length 3.8
  TOP w0.127: 54.51,60.59 54.51,60.78 53.35,61.94 v1(53.08,61.94)
  TOP w0.203: 54.51,60.59 54.79,60.31 54.79,59.73 55.12,59.39 PU901.16
ALW_PWRGD_3V_5V: length 125
  TOP w0.254: v2(178.91,55.9) 178.91,57.32 179.33,57.73 179.33,59.61 v1(182.16,62.44) v2(182.84,63.12) ; v2(205.54,55.05) 205.54,55.76 204.21,57.08 204.21,58.58 203.73,59.07 UZ6.2
  IN1 w0.254: v2(190.19,52.13) 190.77,51.55 195.9,51.55 197.23,52.88 203.49,52.88 205.54,54.93 v2(205.54,55.05)
  IN2 w0.254: v2(190.19,52.13) 189.87,52.45 183.96,52.45 183.31,53.1 182.9,53.1 181.82,54.18 179.97,54.18 178.91,55.24 v2(178.91,55.9) ; v2(152.68,125.03) 153.44,125.03 158.11,120.36 158.11,119.8 159.46,118.46 160.02,118.46 160.32,118.16 160.32,113.15 159.83,112.66 159.83,108.25 160.21,107.87 161.25,107.87 162.6,106.53 162.6,103.05 164.17,101.47 164.17,92.82 165.6,91.39 165.6,89.52 166.26,88.87 166.26,87.67 168.21,85.72 168.21,84.09 170.14,82.16 170.14,79.33 171.57,77.89 171.57,75.72 172.01,75.29 174.1,75.29 v2(177.79,71.6)
  BOTTOM w0.254: v2(182.84,63.12) 182.84,66.55 v2(177.79,71.6) ; PR120.2 179.31,56.78 PR119.2 179.2,56.77 178.91,56.48 v2(178.91,55.9) ; v2(152.68,125.03) 152.87,124.84 DC2.1
ALWON: length 104.6
  TOP w0.127: v2(203.4,53.82) v1(203,54.23) ; v2(244.43,86.25) 245.67,86.25 246.47,87.06 UE1.A5
  IN2 w0.122: v2(236.97,55.94) 236.7,55.94 235.5,54.74 233.51,54.74 232.8,54.04 229.95,54.04 229.46,53.54 226.58,53.54 225.95,54.18 225.93,54.18 225.89,54.22 222.49,54.22 222.13,53.86 219.45,53.86 219.08,54.23 214.16,54.23 214.07,54.14 214.06,54.14 213.63,53.71 209.45,53.71 208.66,52.92 207.05,52.92 206.95,52.83 206.12,52.83 205.84,53.11 205.51,53.11 205.28,52.88 205.28,52.73 205.04,52.48 204.28,52.48 203.4,53.35 v2(203.4,53.82)
  BOTTOM w0.127: PR114.1 185.83,61.87 200.67,61.87 202.26,60.29 202.26,57.41 203.46,56.21 203.46,53.88 v2(203.4,53.82) ; v2(236.97,55.94) 236.97,56.23 237.13,56.4 238.66,56.4 244.68,62.42 244.68,64.82 245.55,65.68 245.55,67.14 245.13,67.55 245.13,68.25 244.96,68.42 244.96,69.69 246.37,71.11 246.37,73.09 247.19,73.91 247.19,75.58 246.87,75.9 246.87,78.69 246.62,78.94 246.62,79.47 243.98,82.11 243.98,85.1 244.43,85.55 v2(244.43,86.25)
AR_DET#: length 7.7
  BOTTOM w0.076: RC401.1 RC400.1 136.47,107.2 v1(134.9,107.2) 134.11,107.2 133.25,106.34 132.44,106.34 131.99,106.12 130.76,106.12 UC1.P4
AR_DP1_CTRL_CLK: length 46.4
  TOP w0.127: RT13.1 RT125.1 33,107.46 v2(33.09,107.37) ; v2(33.14,93) 32.94,93.2 32.64,93.2 31.74,92.3 24.69,92.3 24.43,92.04 23.89,92.04 23.15,91.3 19.94,91.3 19.33,90.69 19.33,89.85 19.07,89.58 17.77,89.58 17.42,89.24 17.42,88.86 17.57,88.71 QV3.1
  IN2 w0.122: v2(33.14,93) 33.28,93.14 33.48,93.14 34.09,92.53 35.45,92.53 36.47,93.54 36.47,100.81 37.03,101.37 37.03,105.35 36.22,106.17 33.53,106.17 32.93,106.77 32.93,107.31 32.99,107.37 v2(33.09,107.37)
  BOTTOM w0.076: 32.02,105.53 32.02,105.51 32,105.49 32,105.09 31.63,104.72 31.63,104.17 UT1.Y2
  BOTTOM w0.127: v2(33.09,107.37) 32.64,106.92 32.64,106.33 32.02,105.71 32.02,105.53
AR_DP1_CTRL_DATA: length 42.5
  TOP w0.127: QV3.4 18.87,90.59 v4(19.55,91.28) 19.83,91.55 23.04,91.55 23.79,92.3 24.33,92.3 24.59,92.56 31.64,92.56 32.53,93.45 33.01,93.45 v2(33.14,93.58) ; RT12.1 RT124.1 32.48,107.79 v2(32.48,107.39)
  IN2 w0.122: v2(32.48,107.39) 32.6,107.39 32.68,107.31 32.68,106.66 33.42,105.92 36.11,105.92 36.78,105.25 36.78,101.48 36.22,100.91 36.22,93.65 35.35,92.78 34.19,92.78 33.58,93.39 33.34,93.39 v2(33.14,93.58)
  BOTTOM w0.076: UT1.Y1 31.44,104.44 31.44,104.82 31.8,105.18 31.8,105.49 31.78,105.51 31.78,105.53
  BOTTOM w0.127: v2(32.48,107.39) 32.52,107.34 32.52,107.17 32.38,107.03 32.38,106.41 31.78,105.81 31.78,105.53
AR_DP1_HPD: length 34.3
  TOP w0.127: QV5.3 12.01,97.49 v1(12.69,98.17) 14.21,98.17 RV20.1 16.46,95.92 16.46,94.55 v2(17.17,93.84)
  IN1 w0.084: v2(17.17,93.84) 17.27,93.84 19.02,92.08 21.74,92.08 23.12,93.46 23.12,94.14 23.28,94.31 23.28,102.89 25.21,104.81 25.21,106.16 26.38,107.33 v2(26.4,107.33)
  BOTTOM w0.076: UT1.G1 25.41,104.66 25.3,104.77 25.3,105.94 25.41,106.06
  BOTTOM w0.127: v2(26.4,107.33) 26.4,107.04 25.41,106.06
AR_DP1_N0: length 46.5
  IN2 w0.102: v2(21.94,77.58) 21.86,77.5 21.87,77.26 21.95,77.19 22.31,77.19 22.77,77.65 22.77,81.1 23.48,81.81 23.61,81.81 24.56,82.77 24.56,84.21 25.28,84.92 25.28,86.63 26.73,88.08 27.74,88.08 29.24,89.58 29.24,91.11 27.67,92.69 26.18,92.69 23.53,95.34 23.53,103.21 23.94,103.62 27.5,103.62 28.45,104.56 29.5,105.62 29.5,106.21 29.41,106.31 v2(29.14,106.31)
  BOTTOM w0.076: 29.13,105.43 29.13,105.41 29.17,105.37 29.17,104.76 29.09,104.69 28.94,104.69 28.87,104.62 28.87,104.25 28.93,104.19 29.02,104.19 29.09,104.27 UT1.R1
  BOTTOM w0.114: CV32.1 20.86,77.35 21.06,77.35 CT201.2 21.43,77.31 21.75,77.31 21.94,77.5 v2(21.94,77.58) ; v2(29.14,106.31) 29.35,106.31 29.46,106.2 29.46,106.02 29.13,105.69 29.13,105.43
AR_DP1_N1: length 43.4
  IN2 w0.102: v2(22.15,79.51) 22.15,79.18 22.07,79.1 21.1,79.1 20.01,80.19 20.01,84.12 22.93,87.04 22.93,90.87 21.04,92.76 21.04,100.19 21.3,100.45 21.3,104.2 23.5,106.4 26.32,106.4 27.24,107.32 27.97,107.32 28.34,106.95 28.34,106.51 28.27,106.44 v2(28.07,106.44)
  BOTTOM w0.076: UT1.N1 28.17,104.24 28.09,104.17 28,104.17 27.93,104.24 27.93,104.58 28.07,104.72 28.12,104.72 28.4,105 28.4,105.78 28.36,105.82 28.36,105.84
  BOTTOM w0.114: CV34.1 20.86,79.19 21.06,79.19 CT202.2 21.37,79.21 21.86,79.21 v2(22.15,79.51) ; 28.36,105.84 28.36,106.35 28.28,106.44 v2(28.07,106.44)
AR_DP1_N2: length 34.4
  IN2 w0.102: v2(21.82,83.13) 21.73,83.04 21.73,82.76 21.8,82.69 22.23,82.69 22.53,82.98 22.53,84.62 24.35,86.44 24.35,92.56 22.72,94.18 22.72,103.59 23.56,104.42 26.48,104.42 27.31,105.25 27.31,106.01 27.12,106.19 v2(26.98,106.19)
  BOTTOM w0.076: UT1.L1 27.25,104.23 27.19,104.17 27.07,104.17 27.01,104.23 27.01,104.56 27.29,104.85 27.29,105.43 27.25,105.47 27.25,105.49
  BOTTOM w0.114: v2(26.98,106.19) 27.15,106.19 27.25,106.09 27.25,105.49 ; CV36.1 20.86,82.8 21.06,82.8 CT203.2 21.36,82.83 21.74,82.83 21.82,82.9 v2(21.82,83.13)
AR_DP1_N3: length 34.8
  IN2 w0.102: v2(21.81,81.2) 21.81,81.06 21.61,80.87 21.33,80.87 20.81,81.38 20.81,83.77 23.73,86.69 23.73,92.19 22.11,93.82 22.11,103.84 23.35,105.08 26.07,105.08 26.27,105.27 26.27,105.6 v2(26.44,105.78)
  BOTTOM w0.076: UT1.J1 26.33,104.35 26.39,104.29 26.48,104.29 26.52,104.32 26.52,104.58 26.42,104.68 26.34,104.68 26.26,104.76 26.26,105.16 26.3,105.2 26.3,105.22
  BOTTOM w0.114: 26.3,105.22 26.3,105.63 v2(26.44,105.78) ; CV38.2 20.86,81.03 21.06,81.03 CT204.2 21.43,81 21.71,81 21.81,81.09 v2(21.81,81.2)
AR_DP1_P0: length 46.5
  IN2 w0.102: v2(21.97,76.75) 22.2,77 22.39,77 22.96,77.57 22.96,81.02 23.56,81.62 23.68,81.62 24.75,82.69 24.75,84.13 25.47,84.84 25.47,86.55 26.81,87.88 27.82,87.88 29.44,89.5 29.44,91.19 27.74,92.88 26.26,92.88 23.72,95.42 23.72,103.13 24.02,103.43 27.58,103.43 28.42,104.27 29.69,105.54 29.69,106.29 29.58,106.4 v2(29.58,106.68)
  BOTTOM w0.076: UT1.R2 29.09,103.98 29.33,104.22 29.33,105.37 29.37,105.41 29.37,105.43
  BOTTOM w0.114: v2(21.97,76.75) 21.65,77.07 21.36,77.07 CT201.1 21.06,77.1 20.86,77.1 CV31.1 ; v2(29.58,106.68) 29.58,106.42 29.7,106.3 29.7,105.92 29.37,105.59 29.37,105.43
AR_DP1_P1: length 43.4
  IN2 w0.102: v2(28.75,106.81) 28.05,107.51 27.16,107.51 26.24,106.59 23.42,106.59 21.11,104.28 21.11,100.53 20.85,100.27 20.85,92.68 22.74,90.79 22.74,87.12 19.82,84.2 19.82,80.11 21.03,78.91 21.84,78.91 v2(22.07,78.68)
  BOTTOM w0.076: 28.61,105.84 28.61,105.82 28.6,105.83 28.57,105.8 28.57,104.93 28.4,104.76 28.4,104.15 28.17,103.92 UT1.N2
  BOTTOM w0.114: CV33.1 20.86,78.94 21.06,78.94 CT202.1 21.42,78.97 21.78,78.97 v2(22.07,78.68) ; 28.61,105.84 28.61,106.67 v2(28.75,106.81)
AR_DP1_P2: length 34.4
  IN2 w0.102: v2(21.86,82.26) 22.1,82.5 22.31,82.5 22.72,82.9 22.72,84.55 24.54,86.36 24.54,92.64 22.92,94.26 22.92,103.51 23.64,104.23 26.56,104.23 27.5,105.17 v2(27.5,106.57)
  BOTTOM w0.076: UT1.L2 27.43,104.15 27.48,104.31 27.48,104.65 27.46,104.68 27.46,105.43 27.5,105.47 27.5,105.49
  BOTTOM w0.114: v2(21.86,82.26) 21.86,82.35 21.62,82.58 21.43,82.58 CT203.1 21.06,82.55 20.86,82.55 CV35.1 ; 27.5,105.49 v2(27.5,106.57)
AR_DP1_P3: length 34.8
  IN2 w0.102: v2(25.86,105.66) 26.08,105.45 26.08,105.35 25.99,105.27 23.27,105.27 21.92,103.92 21.92,93.74 23.54,92.11 23.54,86.77 20.62,83.85 20.62,81.3 21.25,80.68 21.7,80.68 v2(21.84,80.53)
  BOTTOM w0.076: UT1.J2 26.33,103.93 26.1,104.16 26.1,105.16 26.05,105.2 26.05,105.22
  BOTTOM w0.114: v2(21.84,80.53) 21.62,80.75 21.36,80.75 CT204.1 21.06,80.78 20.86,80.78 CV37.2 ; v2(25.86,105.66) 26.05,105.47 26.05,105.22
AUD_HP_NB_SENSE: length 73.7
  TOP w0.254: RA60.2 254.67,68.56 v2(254.54,68.43)
  BOTTOM w0.254: JHP1.6 289.67,31.6 287.41,29.34 DA2.3 282.94,28.51 v3(280.5,28.51) 280.31,28.51 277.04,31.79 277.04,52.31 272.44,56.91 271.35,56.91 267.74,60.51 267.74,65.57 267.16,66.15 262,66.15 259.28,63.43 255.8,63.43 254.99,64.25 254.99,65.49 254.63,65.85 254.63,68.33 v2(254.54,68.43)
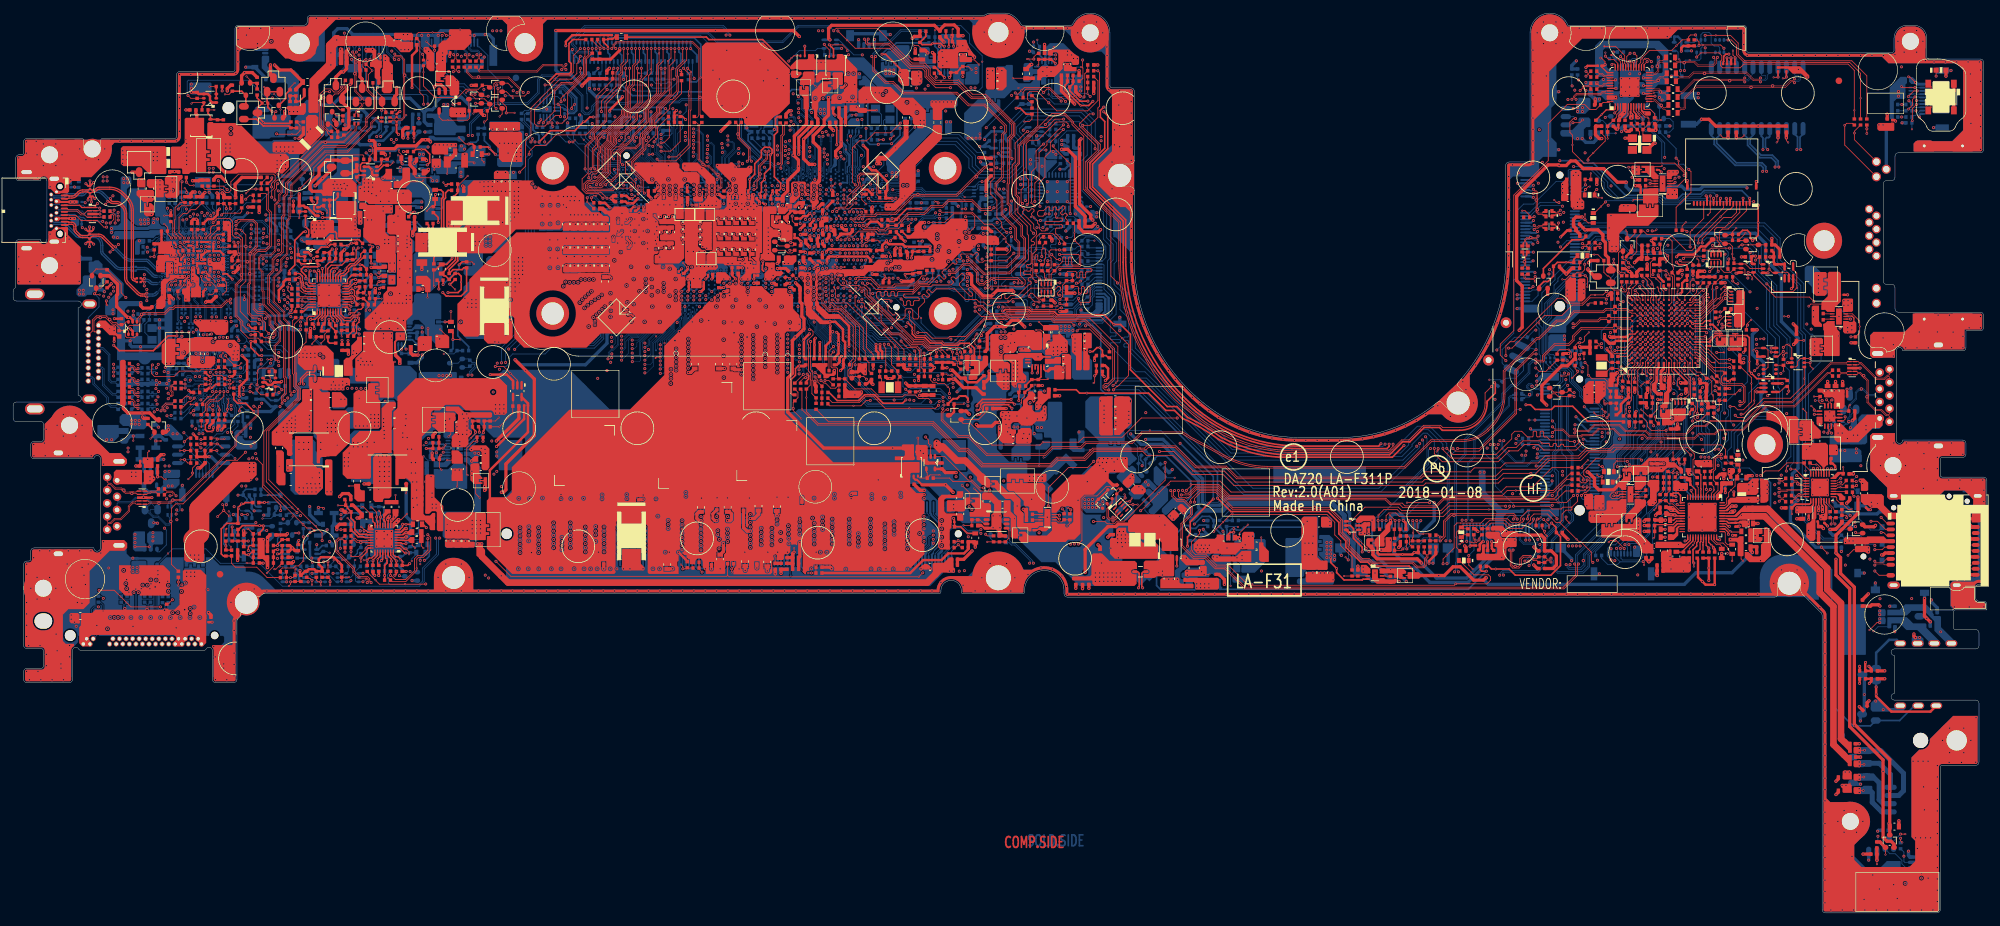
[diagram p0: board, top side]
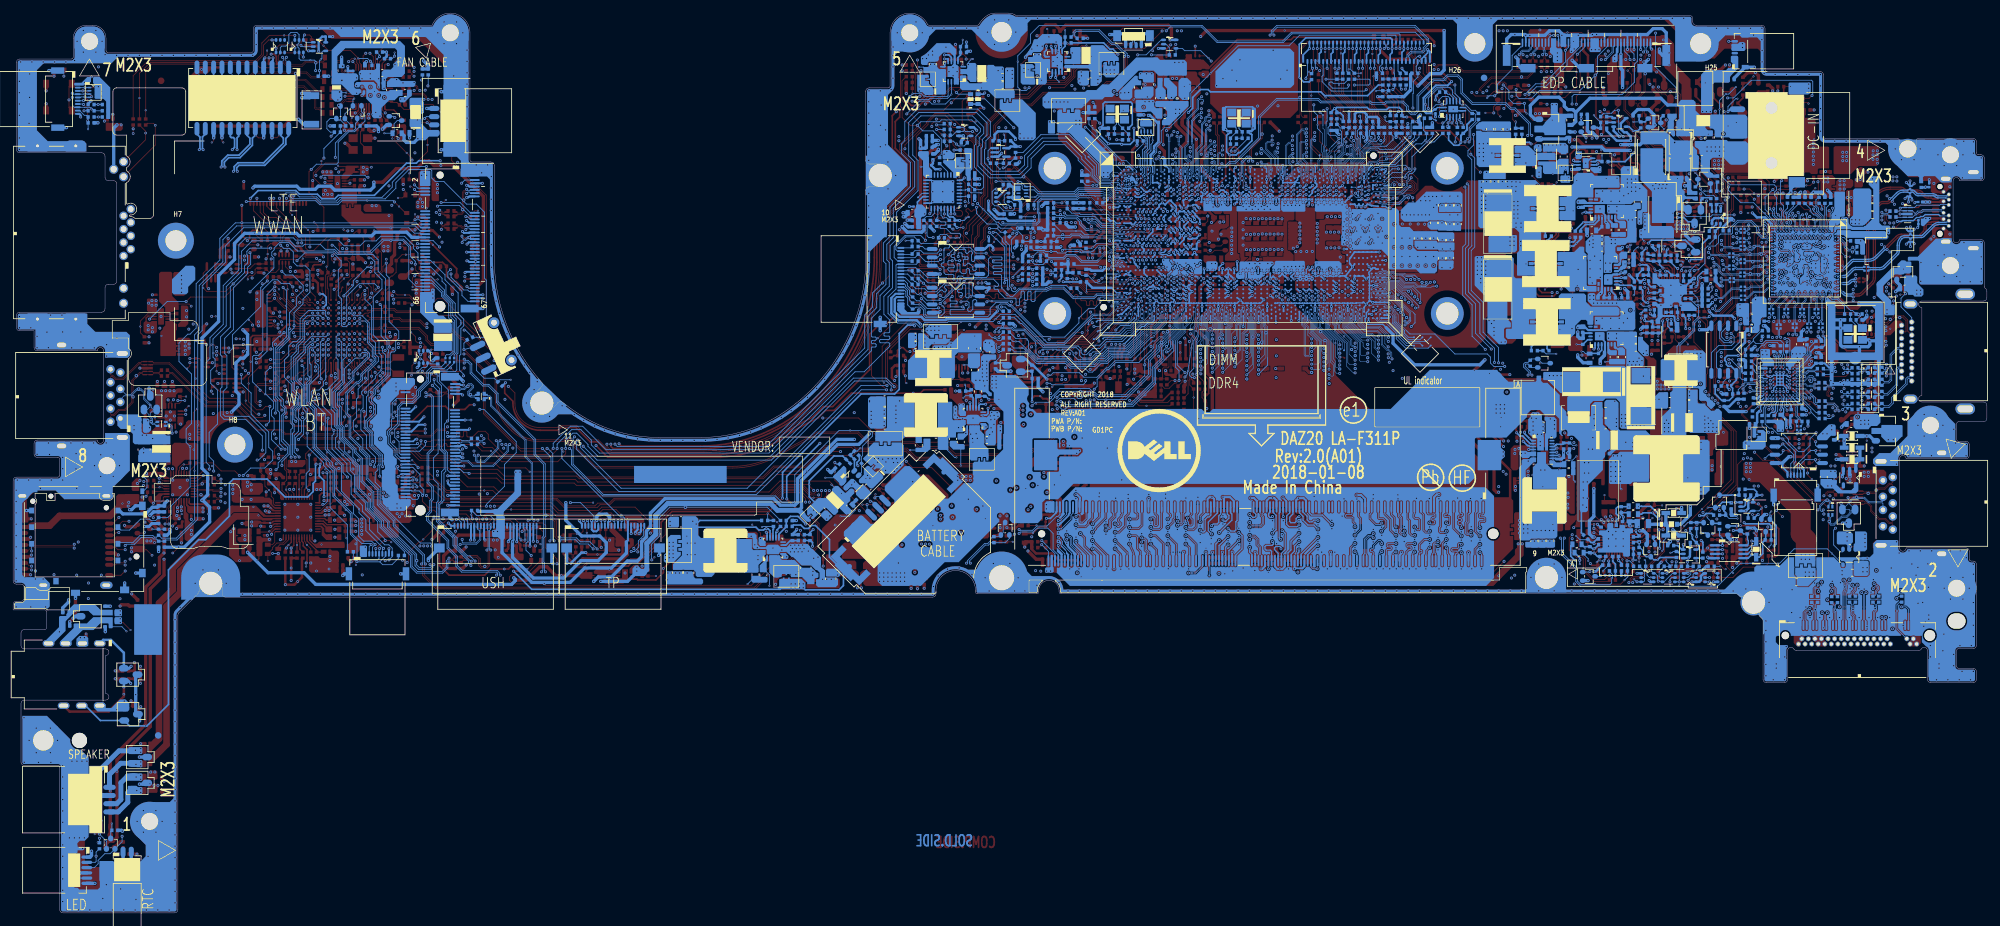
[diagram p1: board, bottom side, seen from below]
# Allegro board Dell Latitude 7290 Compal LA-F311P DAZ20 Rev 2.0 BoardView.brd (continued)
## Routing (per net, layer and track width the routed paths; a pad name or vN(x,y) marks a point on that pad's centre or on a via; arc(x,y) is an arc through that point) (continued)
AUD_HP_OUT_L: length 41.1
  TOP w0.381: RA55.1 v2(281.32,37.6) ; RA57.2 RA7.2 v3(258.34,52.59) v2(258.34,50.68)
  IN4 w0.381: v2(258.34,50.68) 265.25,50.68 269.12,54.56 272.07,54.56 281.32,45.31 v2(281.32,37.6)
AUD_HP_OUT_L1: length 11.4
  TOP w0.381: v3(282.23,38.21) 282.18,38.16 282.18,36.96 RA55.2 CA3.1 283.09,37.23 v2(282.73,37.6)
  BOTTOM w0.381: v2(282.73,37.6) 283.03,37.3 DA1.2 283.83,39.66 285.8,41.63 286.97,41.63 JHP1.1
AUD_HP_OUT_R: length 47.7
  TOP w0.381: RA8.2 v2(259.23,50.05) 257.83,50.05 v3(257.35,50.53) 256.69,51.19 256.69,53.97 RA58.2 ; RA56.1 v2(281.32,35)
  IN4 w0.381: v2(259.23,50.05) 265.57,50.05 269.44,53.92 271.75,53.92 280.6,45.07 280.6,35.71 v2(281.32,35)
AUD_HP_OUT_R1: length 15.7
  TOP w0.381: v2(283.83,34.45) v3(283.83,33.35) 283.83,33.02 286.15,30.69 292.1,30.69 JHP1.2 ; v2(282.79,35) 283.09,35.3 CA2.1 RA56.2
  BOTTOM w0.381: v2(283.83,34.45) DA1.3 283.16,35.37 v2(282.79,35)
AUD_PC_BEEP: length 5.8
  TOP w0.127: v1(250.02,61.43) 250.32,61.73 250.32,62.1 250.91,62.69 CA28.2 CA27.2 252.3,62.37 252.84,62.37 253.87,61.34 UA1.16
AUD_PWR_EN: length 174
  TOP w0.127: UZ5.5 244.89,63.43 244.63,63.17 243.6,63.17 243.33,63.43 v1(243.33,63.56) 243.33,63.82 243.56,64.04 244.24,64.04 v2(244.25,64.03) 244.45,64.23 UZ5.3
  IN2 w0.122: v2(248.18,72.34) 245.64,72.34 245.2,72.78 244.55,72.78 242.7,70.93 241.22,70.93 240.03,69.74 236.21,69.74 235.95,69.48 234.94,69.48 232.04,66.58 227.52,66.58 227.04,66.09 227.02,66.09 226.98,66.06 225.59,66.06 224.91,65.38 206.45,65.38 204.98,66.85 186.95,66.85 185.37,68.43 181.69,68.43 181.69,68.43 181.39,68.43 179.21,70.62 177.38,70.62 173.45,74.55 171.62,74.55 170.7,75.47 170.7,77.61 169.38,78.92 169.38,81.87 167.47,83.79 167.47,85.41 165.52,87.37 165.52,88.56 164.67,89.41 164.67,90.89 162.82,92.74 161.99,92.74 160.69,94.04 160.69,94.7 160.24,95.14 156.07,95.14 153.62,92.69 152.2,92.69 151.74,93.15 151.74,97.97 148.73,100.98 147.72,100.98 147.45,100.7 146.58,100.7 144.8,102.47 144.8,102.7 144.56,102.94 144.56,105.92 144.79,106.14 v2(145.1,106.14)
  IN4 w0.084: v2(128.67,102.71) 128.67,102.69 129.18,102.17 131.37,102.17 131.45,102.09 133.29,102.09 134.43,100.95 135.7,100.95 135.93,101.18 139.78,101.18 144.74,106.14 v2(145.1,106.14) ; v2(244.25,64.03) 244.25,64.05 247.26,67.06 247.26,69.83 248.18,70.75 v2(248.18,72.34)
  BOTTOM w0.076: v2(128.67,102.71) 128.38,102.99 UC1.W8
  BOTTOM w0.127: v2(145.1,106.14) 147.18,106.14 RC279.1
AUD_SENSE_A: length 11.8
  TOP w0.127: RA59.2 v1(252.89,70.22)
  TOP w0.203: 254.02,62.56 254.05,62.54 UA1.13
  TOP w0.254: v2(253.95,68.42) 253.76,68.61 RA60.1 RA59.2 ; v2(253.34,63.46) 253.19,63.61 252.86,63.61 CA41.1 252.93,64.02 253.67,64.02 254.02,63.66 254.02,62.56
  BOTTOM w0.254: v2(253.34,63.46) 253.34,65.92 254.07,66.65 254.07,67.84 253.95,67.96 v2(253.95,68.42)
AUD_SENSE_B: length 7.6
  TOP w0.127: UA1.14 253.67,62.14 v2(253.52,62.29) ; RA61.2 252.31,67.12 v2(252.91,67.12) 252.91,67.41 v1(253.13,67.64)
  BOTTOM w0.127: v2(253.52,62.29) 253.27,62.29 252.85,62.72 252.85,67.06 v2(252.91,67.12)
AUX_EN_WOWL: length 64.9
  TOP w0.127: v2(248.68,85.06) UE1.D3 ; v2(249.71,103.99) 250.16,103.99 v1(250.37,104.2)
  IN1 w0.084: v2(258.91,101.78) 258.92,101.77 259.17,101.77 259.37,101.58 259.37,96.87 259.06,96.56 259.06,88.83 258.99,88.76 258.99,88.15 260.2,86.94 260.2,84.99 259.39,84.17 v2(256.7,84.17) ; v2(249.71,103.99) 249.71,104.69 250.52,105.5 250.52,113.49 252.01,114.98 252.01,118.19 v2(252.25,118.44)
  IN2 w0.122: v2(249.71,103.99) 253.39,103.99 253.9,103.48 258.15,103.48 259,102.62 259,101.88 v2(258.91,101.78)
  IN4 w0.084: v2(248.68,85.06) 248.29,85.45 248.29,86.03 248.51,86.25 251.48,86.25 251.71,86.02 251.71,85.37 252.44,84.64 254.9,84.64 255.37,84.17 v2(256.7,84.17)
  BOTTOM w0.127: v2(252.25,118.44) 251.75,118.93 RZ70.1 252.37,119.05 252.9,119.58 252.9,120.63 252.41,121.12 DZ9.2
BAT1_LED#: length 134.7
  TOP w0.127: v1(287.81,10.74) 287.55,11 v2(287.55,11.38) ; UE1.D10 v2(248.68,91.46)
  IN2 w0.122: v2(255.97,94.94) 255.83,94.8 254.91,94.8 254.56,95.15 252.97,95.15 251.36,93.54 250.19,93.54 249.08,92.44 249.08,91.86 v2(248.68,91.46) ; v2(269.31,82.26) 270.46,82.26 273.05,79.66 273.05,75.79 274.93,73.92 278.46,73.92 279.39,72.99 279.39,72.96 280.12,72.23 281.41,72.23 283.27,70.37 283.27,64.72 285.16,62.83 285.16,61.56 285.94,60.77 285.94,58.25 284.49,56.79 282.61,56.79 280.32,54.5 280.32,52.11 279.34,51.13 279.34,32.3 288.14,23.51 288.14,13.36 287.04,12.27 287.04,11.89 v2(287.55,11.38)
  IN4 w0.084: v2(269.31,82.26) 268.88,82.69 268.88,97.65 265.3,101.23 264.41,101.23 264.11,100.93 260.73,100.93 259.94,100.14 258.9,100.14 256.46,97.7 256.46,95.44 v2(255.97,94.94)
  BOTTOM w0.127: RZ28.1 v2(287.55,11.38)
BAT2_LED#: length 57.2
  TOP w0.127: v2(269.7,86.23) 270.11,86.65 v1(270.47,86.65) 270.98,86.14 QZ2.1 ; RZ361.1 242.71,93 v2(242.73,92.98) ; UE1.D11 v2(248.68,92.26)
  IN2 w0.122: v2(248.68,92.26) 248.68,93.48 249.95,94.75 250.84,94.75 251.79,95.7 v2(255.96,95.7)
  IN4 w0.084: v2(242.73,92.98) 242.89,92.98 243.37,93.46 243.37,94.61 244.82,96.06 247.82,96.06 249.25,94.63 249.25,93.2 248.68,92.64 v2(248.68,92.26) ; v2(255.96,95.7) 255.37,96.29 255.37,98 258.71,101.35 260.46,101.35 260.95,101.84 262.63,101.84 263.09,101.38 264.11,101.38 264.31,101.59 265.35,101.59 269.15,97.79 269.15,86.78 v2(269.7,86.23)
BAT2_LED#_R: length 95.7
  TOP w0.127: v2(273.77,84.53) 273.76,84.54 QZ2.6 272.33,84.54 271.87,84.08 271.87,83.51 271.6,83.24 QZ2.3 ; v2(287.55,12.01) v1(288.28,12.01)
  IN2 w0.122: v2(273.77,84.53) 273.28,84.04 273.28,75.88 275.02,74.14 278.56,74.14 279.61,73.09 279.61,73.05 280.21,72.45 281.51,72.45 283.49,70.47 283.49,65.05 285.38,63.17 285.38,61.65 286.17,60.87 286.17,58.16 284.58,56.57 282.82,56.57 280.54,54.29 280.54,52.01 279.61,51.08 279.61,32.41 288.39,23.63 288.39,12.85 v2(287.55,12.01)
  BOTTOM w0.127: QZ3.2 286.49,10.95 v2(287.55,12.01)
BATT_WHITE#: length 166.8
  TOP w0.127: v2(239.93,92.72) 240.21,93 RZ361.2
  IN1 w0.084: v2(243.44,110.86) 243.58,110.73 243.58,107.86 241.38,105.66 241.38,94.26 239.93,92.81 v2(239.93,92.72)
  IN2 w0.122: v2(243.44,110.86) 243.93,110.86 247.67,107.11 255.06,107.11 256.51,105.67 259.36,105.67 261.91,103.12 263.61,103.12 270.14,96.59 270.14,93.35 272.06,91.43 272.06,89.72 271.45,89.11 270.15,89.11 267.42,86.39 267.42,85.37 268.56,84.24 268.56,80.87 269.11,80.32 270.59,80.32 271.99,78.91 271.99,75.35 275.44,71.9 278.94,71.9 279.68,71.17 280.97,71.17 282.17,69.97 282.17,64.23 283.74,62.66 283.74,61.58 281.61,59.44 281.61,57.37 281.17,56.93 278.52,54.28 278.52,53.88 277.56,52.91 277.56,30.57 284.9,23.23 284.9,11.97 284.61,11.68 v2(284.1,11.68)
  BOTTOM w0.127: v2(284.1,11.68) 284.1,10.84 QZ3.3 285.92,9.02 286.73,9.02 287.75,8.01 287.75,7.48 288.32,6.91 JLED1.3
BATT_YELLOW#: length 3.6
  BOTTOM w0.127: JLED1.2 288.19,7.71 288.06,7.84 v2(288.06,8.65) 288.06,9.27 RZ28.2
BBS_BIT6: length 12.8
  TOP w0.127: RC184.1 140.1,96.83 139.26,95.98 138.05,95.98 137.14,95.07 v1(134.54,95.07) 131.45,95.07 130.52,96 v2(130.16,96)
  BOTTOM w0.076: v2(130.16,96) 129.76,96.4 UC1.AN5
BC_CLK_ECE1117: length 76.1
  TOP w0.127: v2(248.31,96.29) 248.32,96.29 248.32,95.64 249.08,94.88 UE1.D13 ; v2(209.17,59.84) 209.17,60.56 209.6,60.98 210.65,60.98 211.18,60.46 217.9,60.46 218.96,61.51 v1(224.83,61.51) 227.71,61.51 228,61.8 v2(228,62.01)
  IN4 w0.084: v2(248.31,96.29) 248.03,96.57 243.96,96.57 242.19,94.8 242.19,91.18 240.38,89.37 240.38,80.96 241.01,80.34 241.01,79.48 241.89,78.6 241.89,75.43 242.58,74.75 242.58,72.63 243.17,72.04 243.17,71.32 238.63,66.79 238.33,66.79 235.67,64.13 233.31,64.13 232.5,63.31 229.3,63.31 v2(228,62.01)
  BOTTOM w0.127: v2(209.17,59.84) 209.05,59.72 JKBTP1.11
BC_DAT_ECE1117: length 79.4
  TOP w0.127: UE1.D12 248.64,93.1 248.64,94.44 247.81,95.27 v2(247.81,95.5) ; v2(227.39,62.01) 227.34,62.05 218.78,62.05 217.69,60.96 211.39,60.96 210.86,61.49 208.83,61.49 v1(208.04,60.7) 207.95,60.61 v2(207.95,59.84) 207.95,58.73 RE365.1
  IN4 w0.084: v2(247.81,95.5) 247.49,95.82 244.92,95.82 243.61,94.51 243.61,91.87 240.9,89.16 240.9,81.21 241.58,80.53 241.58,79.58 243.24,77.91 243.24,73.66 243.69,73.21 243.69,71.18 240.74,68.24 240.74,66.16 240.1,65.51 237.83,65.51 235.49,63.17 233.01,63.17 232.55,62.71 230.1,62.71 228.79,61.39 227.64,61.39 227.39,61.65 v2(227.39,62.01)
  BOTTOM w0.127: v2(207.95,59.84) 208.05,59.74 JKBTP1.13
BC_INT#_ECE1117: length 57.4
  TOP w0.127: UE1.E2 v2(249.48,84.26) ; v2(217.1,70.8) 217.1,70.56 v1(216.89,70.34)
  IN2 w0.122: v2(249.48,84.26) 248.88,83.65 244.76,83.65 243.85,82.74 243.85,79.63 243.35,79.13 241.18,79.13 240.61,78.57 238.33,78.57 237.88,78.12 236.21,78.12 236.2,78.12 235.56,78.12 234.11,76.67 230.1,76.67 226.34,72.91 218.34,72.91 217.1,71.68 v2(217.1,70.8)
  BOTTOM w0.127: JKBTP1.14 207.55,60.19 207.73,60.37 208.17,60.37 217.1,69.31 v2(217.1,70.8)
BCM5882_ALERT#: length 56.2
  TOP w0.127: v1(230.9,60.72) 230.71,60.53 v2(230.71,60.08) ; UE1.G10 v2(251.08,91.46)
  IN4 w0.084: v2(230.71,60.08) 230.71,60.15 231.95,61.38 236.29,61.38 237.65,60.03 238.96,60.03 242.08,63.15 242.08,63.76 243.76,65.44 243.76,68.38 245.57,70.19 245.57,73.51 244.61,74.48 244.61,79.95 245.25,80.59 245.25,82.06 245.11,82.2 245.11,82.69 245.72,83.3 245.72,84.59 246.13,85.01 246.13,89.73 247.46,91.06 250.68,91.06 v2(251.08,91.46)
  BOTTOM w0.127: JUSH1.13 227.45,60.03 228.03,60.6 230.11,60.6 RE532.2 230.86,60.23 v2(230.71,60.08)
BEEP: length 29.4
  TOP w0.127: UE1.H11 v2(252.66,92.23) ; v2(249.77,66.46) RA13.2
  IN1 w0.084: v2(252.66,92.23) 252.66,92.02 253.08,91.59 253.08,81.28 253.5,80.86 253.5,80.27 252.59,79.36 252.59,78.96 253.07,78.49 253.07,77.7 252.73,77.36 v2(252.73,75.44)
  BOTTOM w0.127: v2(249.77,66.46) 250.44,67.12 250.44,68.35 252.8,70.71 252.8,75.37 v2(252.73,75.44)
BEEP_R: length 2.9
  TOP w0.127: CA28.1 251.43,64.3 CA62.1 RA45.1 RA13.1
BGATE_ISL9538: length 128.9
  TOP w0.203: PC937.2 59.27,53.67 v1(59.03,53.91) 58.63,54.3 58.25,54.3 57.92,54.64 PU901.32
  TOP w0.254: PC937.2 60.13,52.98 v2(60.41,53.26) ; PQ906.4 v2(177.29,52.89)
  IN1 w0.254: v2(144.93,52.18) 145.57,52.18 148.53,55.15 159.72,55.15 161.54,53.33 176.85,53.33 v2(177.29,52.89)
  IN4 w0.254: v2(60.41,53.26) 62.71,55.56 69.59,55.56 71.61,53.54 72.35,53.54 75.05,50.84 136.02,50.84 138.78,53.6 143.52,53.6 v2(144.93,52.18)
BIA_PWM: length 14.8
  TOP w0.127: LV1.2 v1(62.52,128.2) 62.52,126.08 64.26,124.34 67.73,124.34 68.98,125.59 70.88,125.59 RV1.1 72.29,126.19 DV1.1
BIA_PWM_EC: length 243.3
  TOP w0.127: DV1.2 75.15,125.22 75.81,124.56 v1(76.05,124.56) 77.92,124.56 v2(78.47,125.11) ; UE1.N1 v2(256.68,83.46)
  IN2 w0.122: v2(78.47,125.11) 78.81,124.77 81.2,124.77 83.7,127.27 84.32,127.27 86.27,129.22 87.44,129.22 87.6,129.38 115.51,129.38 116.68,130.56 124.3,130.56 124.47,130.39 127.79,130.39 128.75,131.35 135.04,131.35 135.66,130.73 138.76,130.73 141.17,128.32 144.45,128.32 146,126.76 147.02,126.76 147.85,125.93 154.39,125.93 159.73,120.59 160.73,120.59 161.13,120.19 161.13,117.3 161.47,116.96 161.47,108.81 163.33,106.94 163.33,104.98 165.22,103.1 165.22,92.99 166.37,91.84 166.37,89.79 167.06,89.1 167.06,87.92 168.97,86.02 168.97,84.38 170.92,82.43 170.92,80.05 175.23,75.73 175.23,75.42 177.66,72.99 178.57,72.99 181.69,69.88 185.89,69.88 187.53,68.24 205.56,68.24 207.02,66.77 224.33,66.77 225.01,67.45 226.41,67.45 227.08,68.12 228.42,68.12 228.43,68.13 228.74,68.13 229.49,68.88 230.61,68.88 230.74,69.01 232.44,69.01 234.3,70.87 235.37,70.87 235.64,71.14 239.45,71.14 240.84,72.53 240.84,73.06 241.86,74.08 245.33,74.08 246.09,73.32 249.73,73.32 250.95,74.54 252.94,74.54 253.35,74.94 255.79,74.94 v2(255.85,75.01)
  BOTTOM w0.127: v2(255.85,75.01) 255.83,75.03 255.83,76.8 256.27,77.24 256.27,80.54 256.4,80.67 256.4,83.17 v2(256.68,83.46)
BL_PWR_SRC_ON: length 4.8
  TOP w0.254: CV13.1 RV5.1 CV14.1 RV4.1 43.57,123.72 44.35,124.5 QV1.3
BOARD_ID: length 11.1
  TOP w0.127: RE79.1 251.16,102.82 252.34,102.82 252.75,102.41 252.75,98.73 v1(252.94,98.54) 252.96,98.52 252.96,98.09 252.73,97.86 CE40.1 253.08,97.25 UE1.J13
BOOT1_ISL9538:
  vias: v1(56.53,60.16)
BOOT2_ISL9538: length 1.4
  TOP w0.127: v1(61.21,55.66) 60.79,56.08 PC934.2
BREATH_LED#: length 36.6
  TOP w0.127: QZ7.4 266.17,83.53 v1(265.75,83.11) v2(265.31,82.68) ; UE1.C11 v2(247.88,92.26)
  IN2 w0.122: v2(265.31,82.68) 264.55,83.44 264.55,86.12 264.21,86.46 264.21,87.55 262.62,89.13 262.62,91.86 261.41,93.08 260.49,93.08 258.9,94.67 258.9,98.64 258.67,98.87 257.99,98.87 257.73,98.61 257.2,98.61 256.61,98.03 256.61,96.56 256.22,96.16 251.92,96.16 250.8,95.03 249.92,95.03 247.88,93 v2(247.88,92.26)
BREATH_LED#_Q: length 2.1
  TOP w0.127: QZ7.3 268.59,83.5 RZ32.1 v1(269.71,82.59)
BREATH_WHITE_LED_SNIFF#: length 112
  TOP w0.127: LED3.1 v2(292.97,127.59) ; RZ32.2 v2(269.71,85.04) 270.03,85.35 v1(270.19,85.35)
  IN4 w0.084: v2(292.97,127.59) 292.97,122.27 290.6,119.9 286.73,119.9 286.28,120.34 286.28,121.99 285.84,122.44 285.84,128.15 285.18,128.81 259.02,128.81 251.67,121.45 251.67,118.12 257.28,112.51 257.28,106.59 258.95,104.91 266.57,104.91 269.09,102.4 269.09,99.05 272.21,95.92 272.21,86.21 271.04,85.04 v2(269.71,85.04)
BST_3V:
  vias: v2(155.56,73.1)
BST_5V: length 2.9
  BOTTOM w0.127: PR111.1 186.4,52.26 186.19,52.26 185.48,51.55 v1(185.48,49.87)
BST_+1VALWP: length 2.2
  TOP w0.127: v1(155.86,88.88) 156.56,88.88 157.5,87.94 PC304.1
BST_+1VALWP_C: length 1.6
  TOP w0.127: PC304.2 157.14,89.2 157.14,89.26 v1(156.28,90.12)
BST_DDR: length 2.8
  BOTTOM w0.127: v1(62.74,65.76) 63.02,66.04 PC205.1 PR203.2
BST_SA: length 5.7
  TOP w0.127: v1(63.7,112.1) 61.42,112.1 61.17,112.34 PR619.1
  TOP w0.508: PC611.1 60.46,115.01 60.46,114.06 61.17,113.34 PR619.1
BT_RADIO_DIS#: length 22.3
  TOP w0.127: DZ2.1 243.86,68.43 v1(244.31,68.88) 245.89,68.88 v2(245.92,68.85) ; RE11.1 v2(247.04,81.54) 247.04,82.73 247.88,83.57 247.88,84.26 UE1.C2
  IN4 w0.084: v2(247.04,81.54) 247.04,81.11 247.49,80.66 247.49,79.2 247.06,78.78 246.78,78.78 245.55,77.54 245.55,75.89 246.66,74.78 246.66,70.27 246.12,69.74 246.12,69.05 v2(245.92,68.85)
BT_RADIO_DIS#_R: length 3.2
  TOP w0.127: v1(241.57,68.33) 241.85,68.05 v2(242.11,68.05) 242.36,67.8 DZ2.2
  BOTTOM w0.127: JNGFF1.54 241.81,67.4 242.11,67.7 v2(242.11,68.05)
CAM_MIC_CBL_DET#: length 132.3
  TOP w0.127: RC413.1 133.28,103.49 v1(132.59,103.49) 131.8,103.49 131.32,103.97 128.81,103.97 127.91,103.07 127.19,103.07 v2(126.74,102.63)
  IN2 w0.122: v2(126.74,102.63) 127.15,102.22 132.21,102.22 133.09,103.11 136.48,103.11 137.13,103.76 137.13,105.01 136.83,105.32 135.86,105.32 135.38,105.8 135.38,110.17 134.94,110.61 134.94,111.15 135.23,111.44 135.23,116.52 136.66,117.94 136.66,124.03 133.86,126.83 130.86,126.83 129.15,128.55 125.55,128.55 124.88,127.87 120.83,127.87 120.24,127.29 117.18,127.29 115.96,126.07 97.97,126.07 97,125.1 93.73,125.1 93.34,125.49 91.59,125.49 91.08,124.97 82.74,124.97 81.59,123.82 74.46,123.82 72.73,125.55 v2(71.72,125.55)
  BOTTOM w0.102: UC1.AB11 v2(126.74,102.63)
  BOTTOM w0.127: v2(71.72,125.55) 71.72,124.61 71.26,124.16 69.4,124.16 68.14,125.42 61.97,125.42 59.31,128.08 59.31,130.63 57.75,132.19 JEDP1.14
CFG0: length 38
  TOP w0.127: v2(90.5,125.53) v1(89.42,124.46) 89.1,124.14 89.1,120.09 87.91,118.9 v2(87.91,118.25)
  IN2 w0.122: v2(94.55,125.53) 94.14,125.94 90.91,125.94 v2(90.5,125.53)
  BOTTOM w0.076: UC1.E68 94.42,111.69 94.49,111.96 94.53,112.22 94.58,112.4 94.61,112.49 94.63,112.55 94.63,112.59 94.63,112.6 94.63,112.71 94.63,112.77 94.61,112.85 94.6,112.94 94.6,113.1 94.63,113.17 94.63,113.69 94.38,113.93 94.38,114.3 94.07,114.62 92.9,114.62 92.12,115.4 91.72,115.4
  BOTTOM w0.127: 91.72,115.4 90.76,115.4 v2(87.91,118.25) 87.72,118.44 87.72,120.42 RC113.1 ; v2(90.5,125.53) 90.26,125.78 RC126.1 ; JXDP1.9 101.11,127.74 101.27,127.58 101.27,126.75 99.84,125.31 94.77,125.31 v2(94.55,125.53)
CFG1: length 31
  TOP w0.127: v2(92.85,114.08) 92.54,114.39 92.54,115.8 93.25,116.52 94.89,116.52 95.63,117.25 95.63,118.13 95.88,118.39 95.88,118.72 97.23,120.07 97.23,121.06 98.24,122.07 98.24,122.8 100.25,124.81 100.25,128.53 v2(100.51,128.79)
  BOTTOM w0.076: v2(92.85,114.08) 93.19,114.08 93.84,113.44 93.84,113.02 UC1.B67
  BOTTOM w0.127: JXDP1.11 v2(100.51,128.79) ; RC112.1 86.51,118.68 86.51,118.31 v1(86.94,117.88) 90.44,114.39 92.51,114.39 92.81,114.08 v2(92.85,114.08)
CFG2: length 25.5
  TOP w0.127: v2(91.62,115.86) 93,117.24 93.37,117.24 94.3,118.16 94.3,118.47 96.55,120.72 96.55,122.54 99.31,125.3 v1(99.31,128.13) v2(99.31,128.79)
  BOTTOM w0.076: UC1.D65 95.33,111.69 95.26,111.96 95.26,112.07 95.12,112.55 95.12,112.8 95.15,112.89 95.15,113.08 95.12,113.18 95.12,113.54 95.23,113.65 95.23,114.18 94.51,114.9 94.51,115.68 93.88,116.32 92.91,116.32 92.45,115.86 v2(91.62,115.86)
  BOTTOM w0.127: JXDP1.15 v2(99.31,128.79)
CFG3: length 31.2
  TOP w0.127: v2(98.71,128.79) v1(98.71,126.27) 98.71,125.02 96.32,122.63 96.32,121.07 94.82,119.58 94.38,119.58 93.24,118.44 93.24,117.8 92.24,116.8 91.87,116.8 91.21,116.13 91.21,115.23 v2(91.46,114.97)
  BOTTOM w0.076: UC1.D67 94.38,112.32 94.47,112.58 94.47,112.75 94.41,112.94 94.41,113.09 94.47,113.21 94.47,113.62 94.21,113.88 94.21,114.24 94,114.45 92.83,114.45 92.54,114.74 91.69,114.74 v2(91.46,114.97)
  BOTTOM w0.127: RC121.2 99.02,128.48 v2(98.71,128.79) JXDP1.17 ; RC110.1 87.21,118.2 90.44,114.97 v2(91.46,114.97)
CFG4: length 33.7
  TOP w0.127: v2(95.71,128.79) v1(95.71,127.6) 95.71,127.37 95.5,127.16 95.5,123.56 93.84,121.89 93.84,121.29 90.99,118.45 90.99,117.65 90.05,116.71 90.05,113.27 88.95,112.17 v2(88.62,112.17)
  BOTTOM w0.076: UC1.E70 92.16,111.01 91.96,111.21 91.63,111.21 91.34,111.49
  BOTTOM w0.112: 91.34,111.49 90.67,112.17 v2(88.62,112.17)
  BOTTOM w0.127: RC109.1 84.48,118.39 87.58,115.29 87.58,113.27 87.83,113.02 88.11,113.02 88.62,112.51 88.62,112.17 v2(88.62,112.17) ; JXDP1.27 v2(95.71,128.79)
CFG5: length 23.2
  TOP w0.127: v2(89.65,113.45) 89.72,113.52 v1(89.72,115.3) 89.72,116.71 90.77,117.76 90.77,118.54 93.61,121.38 93.61,121.99 95.11,123.49 v2(95.11,128.79)
  BOTTOM w0.076: 91.51,112.53 92.05,112.53 92.23,112.36 92.54,112.36 93.28,111.62 UC1.C68
  BOTTOM w0.127: 91.51,112.53 90.59,113.45 v2(89.65,113.45) ; JXDP1.29 v2(95.11,128.79)
CFG6: length 24
  TOP w0.127: v2(93.91,128.79) 93.91,126.23 93.57,125.89 93.57,122.92 92.92,122.27 92.92,121.67 90.38,119.12 89.92,119.12 89.03,118.22 89.03,116.76 v1(88.72,116.45) 88.47,116.2 88.47,113.6 v2(88.62,113.45)
  BOTTOM w0.076: UC1.D68 92.29,111.54 91.98,111.84 91.59,111.84
  BOTTOM w0.127: v2(88.62,113.45) 89.15,112.91 90.52,112.91 91.59,111.84 ; JXDP1.33 v2(93.91,128.79)
CFG7: length 25.9
  TOP w0.127: v2(93.31,128.79) 93.31,127.7 v1(93.45,127.57) 93.45,126.2 93.34,126.1 93.34,123.02 92.69,122.36 92.69,121.76 90.28,119.35 89.83,119.35 88.8,118.32 88.8,117.09 88.24,116.54 88.24,113.68 v2(88.01,113.45)
  BOTTOM w0.076: 91.77,113.85 92.17,113.85 92.57,113.45 92.57,113.11 92.73,112.95 92.73,112.54 92.97,112.3 UC1.C67
  BOTTOM w0.127: JXDP1.35 v2(93.31,128.79) ; 91.77,113.85 89.89,113.85 89.75,113.99 88.56,113.99 v2(88.01,113.45)
CFG8: length 29.6
  TOP w0.127: v2(90.27,111.03) 90.7,111.47 91.24,111.47 92.31,112.54 92.31,115.89 93.16,116.74 94.79,116.74 95.4,117.35 95.4,118.22 95.59,118.42 95.59,118.75 97,120.16 97,121.16 98.01,122.17 98.01,122.89 100.02,124.9 100.02,129.18 100.81,129.97 v1(100.81,131.28) v2(100.81,131.79)
  BOTTOM w0.076: v2(90.27,111.03) 90.27,110.88 90.7,110.45 92.17,110.45 UC1.F71
  BOTTOM w0.127: JXDP1.10 v2(100.81,131.79)
CFG9: length 34.7
  TOP w0.127: v2(87.88,110.75) 88,110.64 89.7,110.64 89.86,110.81 89.86,111.21 90.42,111.77 91.15,111.77 92.06,112.68 92.06,115.92 92.08,115.94 92.08,115.99 93.06,116.97 93.43,116.97 94.53,118.07 94.53,118.38 96.78,120.62 96.78,122.44 99.78,125.45 v1(99.78,129.89) 100.23,130.34 v2(100.23,131.8)
  BOTTOM w0.076: 89.9,109.62 91.5,109.62 91.63,109.49 91.89,109.49 92.01,109.55 92.15,109.55 92.38,109.48 92.51,109.48 92.73,109.56 92.98,109.56 UC1.G69
  BOTTOM w0.127: JXDP1.12 100.23,132.69 v2(100.23,131.8) ; 89.9,109.62 89.02,109.62 v2(87.88,110.75)
CFG10: length 30.5
  TOP w0.127: v2(99.03,131.8) 99.03,129.87 98.3,129.14 98.3,124.93 96.09,122.73 96.09,121.17 94.73,119.8 94.28,119.8 93.24,118.76 92.6,118.76 91.91,118.07 91.91,117.27 90.97,116.33 90.97,112.75 89.46,111.24 v2(89.46,111.03)
  BOTTOM w0.076: v2(89.46,111.03) 89.89,111.47 90.42,111.47 90.7,111.19 90.7,110.88 90.95,110.63 91.94,110.63 91.96,110.65 92.56,110.65 UC1.F70
  BOTTOM w0.127: JXDP1.16 99.01,131.82 v2(99.03,131.8)
CFG11: length 31.4
  TOP w0.127: v2(88.85,111.03) 90.74,112.92 90.74,116.42 91.68,117.37 91.68,118.16 92.51,118.99 93.14,118.99 95.12,120.97 95.12,122.08 98.04,125 98.04,129.3 98.41,129.67 v1(98.41,131.07) v2(98.41,131.8)
  BOTTOM w0.076: v2(88.85,111.03) 89.61,110.27 91.77,110.27 92.33,110.03 92.59,110.03 92.66,109.95 93.44,109.95 UC1.G68
  BOTTOM w0.127: JXDP1.18 v2(98.41,131.8)
CFG12: length 33.1
  TOP w0.127: v2(90.47,108.98) 89.55,109.9 87.44,109.9 86.94,110.4 86.94,111.16 87.48,111.69 87.91,111.69 88.16,111.95 88.16,112.52 88.32,112.68 88.8,112.68 89.25,113.13 89.25,115.73 89.48,115.96 89.48,116.8 90.54,117.86 90.54,118.64 93.38,121.48 93.38,122.08 94.03,122.73 94.03,125.64 94.64,126.25 94.64,129.07 v1(95.41,129.84) v2(95.41,131.8)
  BOTTOM w0.076: v2(90.47,108.98) 90.85,108.6 91.25,108.6 91.52,108.86 91.92,108.86 92.06,108.81 92.16,108.81 92.29,108.86 92.53,108.86 UC1.H70
  BOTTOM w0.127: JXDP1.28 v2(95.41,131.8)
CFG13: length 29.6
  TOP w0.127: v2(94.81,131.8) 94.81,129.62 94.38,129.2 94.38,126.38 93.8,125.79 93.8,122.83 93.15,122.18 93.15,121.57 90.47,118.89 90.09,118.89 89.61,118.41 89.61,118.26 v1(89.43,118.08) 89.25,117.9 89.25,116.06 89.02,115.83 89.02,113.29 88.74,113 88.12,113 87.7,112.58 v2(87.7,112.1)
  BOTTOM w0.076: UC1.G71 91.72,109.82 89.22,109.82 88.24,110.81 88.24,111.44 87.94,111.74
  BOTTOM w0.127: v2(87.7,112.1) 87.7,111.97 87.94,111.74 ; JXDP1.30 v2(94.81,131.8)
CFG14: length 32.9
  TOP w0.127: v2(89.86,108.98) 89.17,109.68 87.31,109.68 86.69,110.3 86.69,111.92 87.6,112.84 87.6,117.02 88.57,117.98 88.57,118.88 90.26,120.58 90.26,120.59 90.43,120.75 90.43,123.45 92.58,125.6 92.58,127.66 92.86,127.94 92.86,129.13 93.63,129.89 v1(93.63,130.99) v2(93.63,131.8)
  BOTTOM w0.076: v2(89.86,108.98) 90.28,109.39 91.45,109.39 91.52,109.33 91.93,109.33 92.04,109.37 92.16,109.37 92.37,109.31 92.52,109.31 92.68,109.37 93.14,109.37 UC1.H69
  BOTTOM w0.127: v2(93.63,131.8) 93.63,132.69 JXDP1.34
CFG15: length 29.5
  TOP w0.127: v2(87.15,113.45) 87.15,116.88 88.34,118.08 88.34,118.98 90.16,120.81 90.16,123.7 v1(91.44,124.98) 92.28,125.82 92.28,125.82 92.3,125.84 92.3,127.81 92.61,128.12 92.61,129.4 93.03,129.82 v2(93.03,131.8)
  BOTTOM w0.076: UC1.G70 92.29,109.76 92.15,109.9 92.14,109.9 92.14,109.91 91.84,110.05 91.48,110.05 91.46,110.02 89.27,110.02 88.44,110.86 88.44,111.62 88.16,111.9
  BOTTOM w0.127: JXDP1.36 93.03,132.69 v2(93.03,131.8) ; 88.16,111.9 88.16,112.48 87.91,112.74 87.55,112.74 87.15,113.14 v2(87.15,113.45)
CFG16: length 28.9
  TOP w0.127: v2(102.01,131.8) v1(102.01,129.96) 102.01,129.81 100.95,128.75 100.95,127.6 101.11,127.44 101.11,125.35 98.47,122.7 98.47,121.98 97.46,120.97 97.46,119.97 96.12,118.63 96.12,118.3 95.86,118.04 95.86,116.67 93.81,114.62 93.53,114.62 93.27,114.36 93.27,112.86 94.84,111.29 94.84,110.61 v2(95.22,110.23)
  BOTTOM w0.102: v2(95.22,110.23) 95.32,110.33 95.87,110.33 96.2,110.65 UC1.E63
  BOTTOM w0.127: JXDP1.6 v2(102.01,131.8)
CFG17: length 30.1
  TOP w0.127: v2(95.22,109.63) 95.65,110.07 95.65,111.7 94.18,113.17 94.18,114.58 96.08,116.48 96.08,117.94 96.35,118.21 96.35,118.5 97.69,119.84 97.69,120.87 98.7,121.88 98.7,122.61 100.11,124.02 100.41,124.02 v1(100.74,124.35) 101.19,124.8 101.19,125.1 101.34,125.25 101.34,127.54 101.21,127.68 101.21,128.63 102.61,130.03 v2(102.61,131.79)
  BOTTOM w0.102: UC1.F63 96.78,109.79 96.05,109.05 95.65,109.05 95.22,109.48 v2(95.22,109.63)
  BOTTOM w0.127: JXDP1.4 v2(102.61,131.79)
CFG18: length 34.8
  TOP w0.127: v2(94.14,110.81) 93.83,110.5 91.78,110.5 91.41,110.13 87.56,110.13 87.2,110.5 87.2,111.06 87.6,111.47 88.14,111.47 88.35,111.67 88.8,111.67 90.28,113.15 90.28,116.61 91.22,117.56 91.22,118.35 92.68,119.81 92.85,119.81 v1(93.41,120.36) 94.06,121.02 94.06,121.8 95.86,123.59 95.86,127.09 96.61,127.84 v2(96.61,131.8)
  BOTTOM w0.102: UC1.E66 v2(94.14,110.81)
  BOTTOM w0.127: JXDP1.24 v2(96.61,131.8)
CFG19: length 36.5
  TOP w0.127: v2(97.21,131.8) v1(97.21,128.64) 97.21,128.06 96.82,127.67 96.82,124.1 94.89,122.18 94.89,121.06 93.05,119.22 92.41,119.22 91.45,118.26 91.45,117.46 90.51,116.52 90.51,113.02 88.92,111.44 88.53,111.44 88.31,111.21 87.73,111.21 87.45,110.93 87.45,110.58 87.67,110.36 91.2,110.36 92.23,111.39 94.19,111.39 94.54,111.05 94.54,110.6 v2(94.14,110.21)
  BOTTOM w0.102: UC1.F66 v2(94.14,110.21)
  BOTTOM w0.127: JXDP1.22 v2(97.21,131.8)
CFG_RCOMP: length 2.2
  TOP w0.127: v1(97.92,111.34) 98.18,111.07 v2(98.18,110.89)
  TOP w0.381: v2(98.18,110.89) 98.18,110.59 RC114.1
  BOTTOM w0.254: v2(98.18,110.89) 98.26,110.85 98.26,110.8 98.66,110.61 UC1.E60
CLK_ITPXDP_N: length 13.1
  TOP w0.104: RC297.1 104.55,120.15 104.55,114.94 104.89,114.6 104.91,114.6 105.45,114.06 105.45,114.04 105.54,113.96 106.01,113.96 v4(107.37,112.6) 107.99,111.98 107.99,110.65 107.75,110.41 107.55,110.41 v2(107.38,110.25)
  BOTTOM w0.089: UC1.F43 107.69,109.94 v2(107.38,110.25)
CLK_ITPXDP_N_R: length 26.1
  TOP w0.104: v2(91.2,131.8) 91.38,131.98 91.38,132.37 91.85,132.84 103.55,132.84 104.65,131.75 v4(104.65,124.36) 104.65,121.71 RC297.2
  BOTTOM w0.104: v2(91.2,131.8) 91.42,132.02 91.42,132.32 91.21,132.52 JXDP1.42
CLK_ITPXDP_P: length 13.1
  TOP w0.104: v2(107.38,110.83) 107.38,110.75 107.53,110.6 107.67,110.6 107.8,110.73 107.8,111.9 107.51,112.19 107.49,112.19 107,112.68 107,112.7 105.93,113.76 105.46,113.76 v4(105.1,114.12) 104.36,114.86 104.36,120.26 104.1,120.52 RC298.1
  BOTTOM w0.089: UC1.E43 107.62,110.59 v2(107.38,110.83)
CLK_ITPXDP_P_R: length 26.1
  TOP w0.104: RC298.2 103.93,121.29 104.19,121.29 104.46,121.55 104.46,124.03 104.43,124.07 104.43,124.65 104.46,124.68 104.46,131.67 103.47,132.65 91.93,132.65 91.58,132.29 91.58,131.96 91.73,131.8 v2(91.81,131.8)
  BOTTOM w0.104: v2(91.81,131.8) 91.61,132 91.61,132.35 91.81,132.55 JXDP1.40
CLK_PCIE_N0: length 235.7
  TOP w0.104: v2(269.03,64.13) 269.18,64.28 270.25,64.28 270.34,64.37 272.76,64.37 272.86,64.27 UR1.6
  IN1 w0.094: v2(229.85,69.8) 229.85,70.99 231.11,72.25 232.48,72.25 234.48,70.24 243.71,70.24 246.66,73.19 249.67,73.19 250.77,74.29 253.29,74.29 253.42,74.16 254.11,74.16 254.7,74.75 254.7,76.4 255.21,76.91 258.95,76.91 260.53,78.49 262.37,78.49 262.55,78.67 264.11,78.67 265.74,77.04 270.38,77.04 271.53,75.89 271.53,67.45 270.86,66.79 270.86,65.03 269.97,64.13 v2(269.03,64.13) ; v2(227.09,72) 226.89,71.8 226.89,70.59 225.88,69.58 186.19,69.58 171.23,84.54 171.23,87.2 169.82,88.61 169.82,91.32 168.77,92.36 168.77,105.76 160.62,113.92 158.98,113.92 157.88,115.01 156.38,115.01 150.34,121.06 140.6,121.06 138.63,119.08 129.57,119.08 129.29,119.36 126.68,119.36 125.61,120.43 122.21,120.43 119.9,118.12 111.1,118.12 108.94,115.96 v2(108.06,115.96)
  BOTTOM w0.076: v2(108.06,115.96) 108.06,116.06 108.15,116.15 108.33,116.15 108.44,116.04 108.44,115.8 107.9,115.26 107.9,114.09 107.66,113.86 107.66,113.72 107.51,113.56 107.51,113.18 107.55,113.06 107.55,112.91 107.51,112.8 107.51,112.55 107.65,112.07 107.65,111.8 UC1.D42
  BOTTOM w0.104: v2(229.85,69.8) 230.04,69.6 230.04,68.99 229.94,68.89 228.93,68.89 226.9,70.93 226.9,71.81 v2(227.09,72)
CLK_PCIE_N1: length 170.1
  IN1 w0.094: v2(108.9,117.84) 109.17,117.57 109.35,117.57 110.67,118.89 119.5,118.89 121.83,121.22 126.8,121.22 127.66,120.36 130.06,120.36 130.47,119.95 134.26,119.95 134.5,120.19 134.5,120.8 135.14,121.44 137.93,121.44 138.36,121.87 150.77,121.87 156.86,115.78 158.21,115.78 159.12,114.87 161.05,114.87 169.56,106.37 169.56,92.74 170.6,91.7 170.6,89.01 172.04,87.57 172.04,84.95 186.59,70.4 224.83,70.4 225.24,70.81 225.24,71.23 v2(225.06,71.42)
  BOTTOM w0.076: v2(108.9,117.84) 109.1,117.64 109.61,117.64 109.86,117.38 109.86,116.39 108.51,115.03 108.51,113.98 108.21,113.68 108.21,112.93 UC1.B42
  BOTTOM w0.104: JNGFF1.49 232.58,68.65 232.45,68.78 231.41,68.78 230.7,68.07 227.54,68.07 225.25,70.35 225.25,71.22 v2(225.06,71.42)
CLK_PCIE_N3: length 158.6
  IN1 w0.094: v2(43.78,89.52) 43.97,89.71 45.84,89.71 46.67,88.88 51.04,88.88 54.24,85.68 57.03,85.68 57.35,85.36 60.09,85.36 60.9,86.17 70.1,86.17 73.22,89.28 73.22,99.26 79.93,105.97 79.93,106.51 80.26,106.84 88.67,106.84 90.21,108.38 91.46,108.38 93.64,110.56 93.64,110.88 94.01,111.26 95.45,111.26 95.75,110.96 95.75,110.46 95.6,110.31 95.6,109.44 96.64,108.4 107.91,108.4 108.66,109.15 108.66,113.02 109.76,114.11 110.36,114.11 v2(110.56,113.9)
  IN4 w0.094: v2(15.99,45.06) 15.8,45.26 15.8,46.63 16.36,47.19 23.05,47.19 24.25,48.39 24.25,54.04 29.37,59.15 29.37,65.38 34.24,70.26 34.24,70.84 35.67,72.27 35.67,74.18 36.25,74.76 36.25,77.67 37.87,79.28 37.87,82.93 38.59,83.66 38.59,84.94 43.38,89.73 43.57,89.73 v2(43.78,89.52)
  BOTTOM w0.076: UC1.D40 109.28,111.69 109.36,111.96 109.36,112.07 109.49,112.53 109.5,112.55 109.5,112.8 109.45,112.93 109.45,113 109.5,113.2 109.5,113.98 109.63,114.12 110.35,114.12 v2(110.56,113.9)
  BOTTOM w0.104: JNGFF3.53 15.95,44.5 15.8,44.65 15.8,44.87 v2(15.99,45.06)
CLK_PCIE_N4: length 228.3
  TOP w0.104: UL1.45 242.66,124.93 242.55,125.03 242.15,125.03 241.85,124.74 238.21,124.74 237.89,124.42 237.89,124.27 v2(238.11,124.05)
  IN1 w0.094: v2(110.55,116.55) 110.81,116.29 112.97,116.29 114.31,114.95 116.75,114.95 117.79,113.91 118.54,113.91 120.56,115.93 120.56,117.28 123.17,119.89 125.35,119.89 127.37,117.87 130.81,117.87 131.6,118.67 138.97,118.67 139.85,119.55 147.66,119.55 149,118.2 152.55,118.2 156.19,114.56 157.35,114.56 159.02,112.89 161.06,112.89 167.69,106.27 167.69,92.73 169.37,91.05 169.37,88.33 170.72,86.98 170.72,84.33 185.98,69.08 226.55,69.08 227.68,70.21 227.68,72.19 226.23,73.63 226.23,77.61 227.23,78.61 227.23,79.77 230.78,83.31 230.78,97.61 233.32,100.16 233.32,113.99 233.44,114.11 233.44,122.31 235.98,124.84 237.57,124.84 237.87,124.54 237.87,124.27 238.09,124.05 v2(238.11,124.05)
  BOTTOM w0.076: v2(110.55,116.55) 110.35,116.35 110.21,116.35 108.94,115.09 108.94,113.69 108.81,113.55 108.81,113.16 109.07,112.91 UC1.B40
CLK_PCIE_N5: length 118.5
  IN1 w0.076: 108.48,107.26 108.5,107.26 108.51,107.27 108.63,107.27 108.8,107.44 108.8,108.39 109.27,108.86 110.27,108.86 110.63,109.22 110.63,109.81 110.76,109.94 110.76,110.38 110.53,110.61 110.3,110.61 v2(110.09,110.81)
  IN1 w0.094: v2(29.33,95.75) 29.34,95.75 29.59,95.51 29.59,95.4 29.71,95.28 29.71,94.95 29.28,94.52 28.02,94.52 25.01,91.51 25.01,90.09 25.69,89.42 32.86,89.42 33.45,88.83 34.22,88.83 36.54,91.15 39.45,91.15 42.31,88.28 50.75,88.28 53.95,85.09 56.74,85.09 57.06,84.77 60.5,84.77 61.3,85.57 70.36,85.57 73.91,89.13 73.91,98.99 80.65,105.73 89.21,105.73 89.94,106.46 90.83,106.46 92.59,108.23 96.1,108.23 96.69,107.64 97.49,107.64 97.88,107.26 108.48,107.26
  BOTTOM w0.076: UC1.E40 v2(110.09,110.81)
  BOTTOM w0.094: v2(29.33,95.75) UT1.T19
CLK_PCIE_P0: length 235.7
  TOP w0.104: v2(269.03,64.72) 269.27,64.48 270.17,64.48 270.26,64.57 272.74,64.57 272.85,64.67 UR1.5
  IN1 w0.094: v2(226.51,72) 226.71,71.81 226.71,70.66 225.8,69.76 186.27,69.76 171.41,84.62 171.41,87.27 170,88.69 170,91.39 168.95,92.44 168.95,105.84 160.69,114.1 159.06,114.1 157.96,115.2 156.46,115.2 150.41,121.24 140.53,121.24 138.55,119.27 129.64,119.27 129.37,119.54 126.75,119.54 125.68,120.61 122.14,120.61 119.83,118.3 111.03,118.3 108.87,116.14 108.45,116.14 108.06,116.53 v2(108.06,116.67) ; v2(269.03,64.72) 269.03,64.71 269.42,64.32 269.89,64.32 270.68,65.11 270.68,66.86 271.34,67.53 271.34,75.81 270.3,76.86 265.67,76.86 264.04,78.49 262.63,78.49 262.45,78.31 260.6,78.31 259.03,76.73 255.29,76.73 254.88,76.33 254.88,74.68 254.18,73.98 253.35,73.98 253.22,74.1 250.84,74.1 249.75,73.01 246.73,73.01 243.79,70.06 234.41,70.06 232.4,72.07 231.18,72.07 230.03,70.91 230.03,70.2 v2(230.43,69.8)
  BOTTOM w0.076: v2(108.06,116.67) 107.96,116.57 107.96,116.43 108.08,116.31 108.4,116.31 108.61,116.11 108.61,115.73 108.06,115.19 108.06,114.02 107.83,113.79 107.83,113.65 107.67,113.49 107.67,113.21 107.72,113.08 107.72,112.88 107.68,112.77 107.68,112.57 107.8,112.14 UC1.C42
  BOTTOM w0.104: v2(226.51,72) 226.7,71.81 226.7,70.85 228.85,68.7 230.02,68.7 230.24,68.91 230.24,69.6 v2(230.43,69.8)
CLK_PCIE_P1: length 170
  IN1 w0.094: v2(108.9,117.08) 108.9,117.12 109.17,117.39 109.43,117.39 110.75,118.7 119.58,118.7 121.91,121.03 126.72,121.03 127.58,120.18 129.99,120.18 130.4,119.77 134.33,119.77 134.68,120.12 134.68,120.72 135.21,121.25 138.01,121.25 138.44,121.69 150.7,121.69 156.78,115.6 158.13,115.6 159.04,114.69 160.97,114.69 169.37,106.29 169.37,92.67 170.42,91.62 170.42,88.93 171.86,87.49 171.86,84.87 186.51,70.22 224.91,70.22 225.43,70.74 225.43,71.2 v2(225.64,71.42)
  BOTTOM w0.076: UC1.A42 108.04,113.42 108.04,113.75 108.34,114.05 108.34,115.1 109.7,116.45 109.7,117.31 109.54,117.47 108.66,117.47 108.58,117.4 108.58,117.22 108.72,117.08 v2(108.9,117.08)
  BOTTOM w0.104: JNGFF1.47 232.63,69.15 232.45,68.97 231.33,68.97 230.62,68.26 227.62,68.26 225.45,70.43 225.45,71.22 v2(225.64,71.42)
CLK_PCIE_P3: length 158.6
  IN1 w0.094: v2(43.78,90.1) 43.99,89.89 45.91,89.89 46.74,89.06 51.12,89.06 54.31,85.87 57.1,85.87 57.43,85.54 60.02,85.54 60.83,86.35 70.03,86.35 73.03,89.36 73.03,99.34 79.74,106.05 79.74,106.58 80.19,107.03 88.59,107.03 90.13,108.56 91.38,108.56 93.46,110.64 93.46,110.96 93.94,111.44 95.52,111.44 95.93,111.03 95.93,110.38 95.79,110.24 95.79,109.52 96.72,108.59 107.84,108.59 108.48,109.23 108.48,113.09 109.68,114.29 110.37,114.29 v2(110.56,114.48)
  IN4 w0.094: v2(43.78,90.1) 43.59,89.91 43.3,89.91 38.41,85.01 38.41,83.73 37.68,83.01 37.68,79.36 36.07,77.74 36.07,74.84 35.48,74.25 35.48,72.34 34.06,70.92 34.06,70.33 29.18,65.45 29.18,59.23 24.07,54.11 24.07,48.46 22.97,47.37 16.28,47.37 15.61,46.7 15.61,45.27 v2(15.41,45.06)
  BOTTOM w0.076: UC1.C40 109.24,112.26 109.33,112.57 109.33,112.58 109.33,112.77 109.33,112.77 109.28,112.9 109.28,113.02 109.33,113.22 109.33,114.05 109.56,114.28 110.41,114.28 110.42,114.28 110.5,114.28 110.56,114.35 v2(110.56,114.48)
  BOTTOM w0.104: v2(15.41,45.06) 15.61,44.86 15.61,44.65 15.45,44.5 JNGFF3.55
CLK_PCIE_P4: length 228.2
  TOP w0.104: v2(237.48,124.05) 237.7,124.27 237.7,124.5 238.13,124.93 241.77,124.93 242.07,125.23 242.55,125.23 242.66,125.33 UL1.44
  IN1 w0.094: v2(110.51,115.79) 110.82,116.1 112.89,116.1 114.23,114.76 116.67,114.76 117.71,113.73 118.62,113.73 120.75,115.86 120.75,117.2 123.25,119.71 125.28,119.71 127.29,117.69 130.88,117.69 131.68,118.49 139.05,118.49 139.93,119.36 147.58,119.36 148.93,118.02 152.48,118.02 156.12,114.38 157.27,114.38 158.94,112.71 160.99,112.71 167.5,106.19 167.5,92.66 169.19,90.97 169.19,88.25 170.54,86.9 170.54,84.26 185.9,68.9 226.63,68.9 227.86,70.13 227.86,72.26 226.41,73.71 226.41,77.53 227.42,78.54 227.42,79.69 230.96,83.23 230.96,97.54 233.5,100.08 233.5,113.92 233.63,114.04 233.63,122.23 236.05,124.66 237.5,124.66 237.69,124.47 237.69,124.27 v2(237.48,124.05)
  BOTTOM w0.076: UC1.A40 109.07,113.57 109.11,113.62 109.11,115.02 110.28,116.19 110.76,116.19 110.83,116.11 110.83,115.82 110.76,115.74 110.56,115.74 v2(110.51,115.79)
CLK_PCIE_P5: length 117.8
  IN1 w0.076: 108.48,107.44 108.5,107.44 108.51,107.43 108.56,107.43 108.64,107.51 108.64,108.45 109.21,109.02 110.2,109.02 110.46,109.28 110.46,109.88 110.6,110.01 110.6,110.31 110.46,110.44 110.36,110.44 v2(110.09,110.18)
  IN1 w0.094: v2(29.98,95.75) 29.77,95.54 29.77,95.48 29.89,95.35 29.89,94.87 29.36,94.34 28.1,94.34 25.2,91.43 25.2,90.17 25.76,89.6 32.94,89.6 33.53,89.01 34.14,89.01 36.46,91.33 39.52,91.33 42.39,88.47 50.83,88.47 54.03,85.27 56.82,85.27 57.14,84.95 60.42,84.95 61.23,85.75 70.28,85.75 73.73,89.2 73.73,99.07 80.57,105.91 89.13,105.91 89.87,106.64 90.75,106.64 92.52,108.41 96.18,108.41 96.76,107.82 97.57,107.82 97.95,107.44 108.48,107.44
  BOTTOM w0.076: UC1.E38 v2(110.09,110.18)
  BOTTOM w0.094: v2(29.98,95.75) 30.02,95.75 30.31,96.04 UT1.V19
CLK_TP_SIO_I2C_DAT: length 82.4
  TOP w0.127: RZ346.1 213.09,55.81 212.72,56.18 212.72,57.24 212.48,57.48 RZ23.2 CZ81.1 212.25,55.57 v2(212.33,55.5) ; UE1.E10 v2(249.48,91.46) ; v2(217.41,56.72) 217.51,56.72 218.16,57.37 218.16,59.64 219.15,60.63 v4(219.51,60.63) 228.54,60.63 228.68,60.49 228.68,60.16 v2(228.57,60.05)
  IN4 w0.084: v2(249.48,91.46) 249.08,91.87 248.52,91.87 248.26,92.13 248.26,93.25 248.69,93.68 248.69,94.56 248.28,94.97 247.7,94.97 247.29,95.39 245.87,95.39 244.04,93.55 244.04,91.62 241.26,88.84 241.26,85.88 241.71,85.43 243.09,85.43 243.18,85.34 243.18,81.32 243.6,80.9 243.6,73.75 243.99,73.36 243.99,71.05 241.05,68.11 241.05,65.99 240.28,65.23 240.28,64.71 240.12,64.54 237.56,64.54 235.78,62.76 233.44,62.76 232.97,62.29 231.08,62.29 229.43,60.64 228.99,60.64 228.76,60.41 228.76,60.25 v2(228.57,60.05)
  BOTTOM w0.127: v2(212.33,55.5) 213.08,56.25 214.37,56.25 215.02,56.9 217.23,56.9 v2(217.41,56.72)
CLK_TP_SIO_R: length 3.3
  TOP w0.127: RZ23.1 211.28,57.54 RZ19.2 211.15,58.62 v2(211.15,59.85)
  BOTTOM w0.127: JKBTP1.7 211.05,59.75 v2(211.15,59.85)
CLKDET#: length 9.8
  BOTTOM w0.076: UC1.AY8 127.79,92.01 127.79,90.92 128.57,90.13 129.11,90.13 130.46,88.78 130.96,88.78 131.11,88.63
  BOTTOM w0.112: 134.46,87.76 T258.1
  BOTTOM w0.127: 131.11,88.63 131.98,87.76 134.46,87.76
CLKREQ_PCIE#0: length 231.6
  TOP w0.127: v2(146.56,92.37) 146.6,92.41 147.57,92.41 148.82,91.16 151.18,91.16 151.5,91.47 154.57,91.47 154.88,91.16 158.4,91.16 158.88,90.68 164.01,90.68 168.3,86.39 168.3,81.12 v1(168.05,80.86) 167.6,80.41 v2(167.57,80.41) ; v2(271.72,66.69) 271.82,66.69 272.65,65.87 UR1.2
  IN1 w0.084: v2(232.98,114.45) 232.86,114.33 232.86,101.85 232.17,101.16 232.17,100.56 229.86,98.25 229.86,92.15 228.87,91.16 228.87,86.59 227.98,85.7 227.44,85.7 226.53,84.78 226.53,83.6 223.98,81.05 223.98,75.88 221.37,73.27 216.7,73.27 215.53,72.11 v2(214.7,72.11)
  IN2 w0.122: v2(271.72,66.69) 271.5,66.91 271.5,77.05 268.21,80.33 268.21,83.7 267.16,84.75 267.16,86.45 270.05,89.34 271.35,89.34 271.69,89.67 271.69,91.49 269.92,93.25 269.92,96.39 263.42,102.9 261.82,102.9 259.27,105.44 256.41,105.44 254.97,106.89 247.53,106.89 245.41,109 244.4,109 240.32,113.08 240.32,114.95 240.09,115.18 233.71,115.18 v2(232.98,114.45) ; v2(147.6,96.99) 147.99,96.6 147.99,96.15 146.97,95.13 146.97,92.78 v2(146.56,92.37)
  BOTTOM w0.127: v2(167.57,80.41) 171.53,80.41 187.7,64.24 208.4,64.24 214.84,70.69 214.84,71.96 v2(214.7,72.11) ; v2(147.6,96.99) 147.17,97.42 RC373.1
CLKREQ_PCIE#0_R: length 24.8
  TOP w0.127: v1(127.95,94.51) 127.6,94.87 v2(127.49,94.87)
  IN4 w0.084: v2(145.38,96.85) 144.15,95.63 132.04,95.63 130.34,97.32 127.56,97.32 127.09,96.85 127.09,95.88 127.49,95.48 v2(127.49,94.87)
  BOTTOM w0.102: UC1.AR10 127.26,95.1 v2(127.49,94.87)
  BOTTOM w0.127: RC373.2 145.95,97.42 v2(145.38,96.85) 144.81,97.42 RC189.1
CLKREQ_PCIE#1: length 112.6
  TOP w0.127: v2(231.23,67) 231.21,67.02 227.04,67.02 226.09,66.07 215.04,66.07 214.66,65.7 186.19,65.7 184.52,67.36 v1(179.81,67.36) 176.84,70.34 v2(174.65,70.34)
  IN2 w0.122: v2(147.6,96.4) 145.59,94.4 145.59,91.2 149.57,87.22 151.46,87.22 152.24,88 162.05,88 162.18,87.87 162.18,86.96 162.95,86.19 164.09,86.19 165.49,84.79 165.49,79.95 167.09,78.36 167.09,73.86 169.97,70.98 172.84,70.98 173.48,70.34 v2(174.65,70.34)
  BOTTOM w0.127: v2(147.6,96.4) 147.47,96.53 RC374.1 ; JNGFF1.53 232.56,67.65 232.03,67.12 231.34,67.12 231.23,67.01 v2(231.23,67)
CLKREQ_PCIE#1_R: length 20.3
  IN2 w0.122: v2(129.31,93.55) 129.56,93.79 133.93,93.79 134.56,93.16 135.53,93.16 137.31,94.94 144.05,94.94 v2(145.37,96.27)
  BOTTOM w0.097: v2(129.31,93.55) 129.31,93.98 UC1.AT7
  BOTTOM w0.127: RC47.1 144.83,96.53 145.11,96.53 v2(145.37,96.27) 145.64,96.53 RC374.2
CLKREQ_PCIE#2_R: length 22.5
  IN2 w0.122: v2(145.38,95.66) 145.3,95.66 144.31,94.67 140.22,94.67 137.97,92.41 136.79,92.41 135.61,91.24 129.8,91.24 128.02,93.02 128.02,93.52 v2(127.51,94.03)
  BOTTOM w0.076: UC1.AT8 127.93,94.45 v2(127.51,94.03)
  BOTTOM w0.127: RC50.1 144.76,95.78 144.88,95.66 v2(145.38,95.66)
CLKREQ_PCIE#3: length 180.1
  TOP w0.127: v2(139.74,85.29) RC376.1
  IN1 w0.084: v2(14.37,43.32) 12.48,45.21 12.48,46.99 12.9,47.41 21.14,47.41 22.07,48.34 30.21,48.34 33.54,51.66 40.12,51.66 40.61,52.16 43.04,52.16 43.79,52.91 45.88,52.91 47.07,54.1 48,54.1 48.39,53.71 48.39,53.28 49.09,52.58 59.17,52.58 59.42,52.83 60.91,52.83 61,52.92 61,53.82 62.29,55.11 62.77,55.11 63.97,56.31 69.53,56.31 70.02,55.82 72.01,55.82 72.78,56.59 72.78,62.95 72.35,63.39 72.35,65.35 73.85,66.85 140.17,66.85 141.71,65.31 145.28,65.31 v2(145.36,65.23)
  IN4 w0.084: v2(139.74,85.29) 139.94,85.08 139.94,80.59 140.28,80.25 140.28,76.88 143.36,73.8 143.36,70.61 145.36,68.61 v2(145.36,65.23)
  IN4 w0.135: JNGFF3.52 14.68,43.32 v2(14.37,43.32)
CLKREQ_PCIE#3_R: length 19.9
  TOP w0.127: RC59.1 RC376.2 138.82,85.3 v2(138.77,85.35)
  IN4 w0.084: v2(138.77,85.35) 138.52,85.35 133.56,90.31 128.17,90.31 126.07,92.4 126.07,93.59 v2(126.57,94.08)
  BOTTOM w0.097: v2(126.57,94.08) 126.94,94.45 UC1.AT10
CLKREQ_PCIE#4: length 167.1
  TOP w0.127: v2(227.42,84.21) 226.57,85.06 226.57,86.73 228.63,88.79 228.63,109.45 233.88,114.71 v1(233.88,117.74) 233.88,120.38 236.78,123.28 239.41,123.28 240.18,122.52 241.16,122.52 RL4.1 242.23,123.58 243.15,123.58 UL1.48 ; v2(166.46,80.23) 166.66,80.23 167.79,81.36 167.79,86.06 163.39,90.45 158.79,90.45 158.31,90.93 154.78,90.93 154.47,91.25 151.59,91.25 151.28,90.93 147.51,90.93 146.68,91.76 v2(146.56,91.76)
  IN1 w0.084: v2(213.85,71.16) 215.8,71.16 217.06,72.43 222.08,72.43 224.84,75.19 224.84,80.68 227.42,83.26 v2(227.42,84.21)
  IN2 w0.122: v2(146.56,91.76) 146.81,91.5 147.5,91.5 147.68,91.69 147.68,95.51 148.22,96.04 148.22,96.73 v2(148.38,96.9)
  BOTTOM w0.127: v2(148.38,96.9) 148.38,97.02 147.09,98.31 RC377.1 ; v2(213.85,71.16) 211.73,69.04 185.19,69.04 172.68,81.54 167.68,81.54 166.46,80.33 v2(166.46,80.23)
CLKREQ_PCIE#4_R: length 26.4
  IN2 w0.122: v2(127.48,93.4) 127.48,93.13 129.75,90.86 136.74,90.86 140.31,94.44 144.76,94.44 145.85,95.52 145.85,97.77 145.54,98.08 v2(145.36,98.08)
  BOTTOM w0.097: v2(127.48,93.4) 127.48,93.41 127.87,93.8 UC1.AU8
  BOTTOM w0.127: RC51.1 145.13,98.31 v2(145.36,98.08) 145.6,98.31 RC377.2
CLKREQ_PCIE#5: length 145.2
  TOP w0.127: RC378.1 139.74,81.28 140.1,80.91 140.68,80.91 140.87,80.72 141.9,80.72 v1(142.39,80.23) 142.64,79.97 v2(142.64,79.2)
  IN1 w0.084: v2(142.64,79.2) 142.79,79.2 143.08,78.91 143.08,76.49 141.81,75.22 84.49,75.22 80.1,79.6 73.76,79.6 73.57,79.79 71.87,79.79 71.69,79.6 55.55,79.6 54.48,80.68 52.22,80.68 47.74,85.16 46.8,85.16 v2(46.76,85.12) ; v2(42.29,90.94) 42.88,90.94 44.51,92.56 44.51,93.83 43.53,94.81 43.53,95.41 44.02,95.9 44.02,97.27 44.6,97.85 v2(44.6,97.93)
  BOTTOM w0.076: UT1.AC5 33.33,102.54 33.59,102.8 33.7,102.8
  BOTTOM w0.127: v2(46.76,85.12) 46.76,86.52 44.54,88.74 44.54,89.94 43.73,90.74 42.49,90.74 v2(42.29,90.94) ; v2(44.6,97.93) 44.48,98.06 43.96,98.06 42.97,99.05 42.97,101.24 42.53,101.68 41.39,101.68 40.9,102.18 40.9,103.19 40.58,103.52 38.89,103.52 38.74,103.66 38.74,104.49 37.89,105.34 35.98,105.34 35.12,104.48 35.12,103.7 34.22,102.8 33.7,102.8
CLKREQ_PCIE#5_R: length 17.8
  TOP w0.127: RC378.2 RC190.1 138.33,83.18 138.33,85.84 137.74,86.42 136.75,86.42 135.02,88.15 133.82,88.15 133.17,88.8 133.17,88.99 v1(129.91,92.25) 129.68,92.48 129.68,92.89 129.46,93.11 128.95,93.11 v2(128.78,93.28)
  BOTTOM w0.076: v2(128.78,93.28) 128.84,93.33 UC1.AU7
CLKRUN#: length 15.3
  TOP w0.127: v2(136.61,85.1) RC27.1
  BOTTOM w0.076: UC1.AW11 126.24,92.46 126.56,92.15 126.56,90.22 127.05,89.72 127.71,89.72 128.47,88.96 128.62,88.96
  BOTTOM w0.112: 131.32,86.27 v1(134.34,86.27)
  BOTTOM w0.127: v1(134.34,86.27) 135.06,85.55 136.17,85.55 v2(136.61,85.1) ; 128.62,88.96 131.32,86.27
CMOUT: length 13.8
  IN2 w0.122: v2(53.3,50.49) 53.56,50.76 59.18,50.76 v2(60.48,52.06)
  BOTTOM w0.127: v2(60.48,52.06) 60.56,51.97 PQ1216.2 ; 52.28,51.13 52.16,51 52.16,50.62 52.3,50.48 PQ1210.3 53.28,50.48 v2(53.3,50.49) 53.38,50.49 v1(53.73,50.85) ; 52.28,51.13 52.16,51.26 52.16,52.09 PR951.1 ; 52.28,51.13 PQ1210.2
COMP_GT: length 3.6
  TOP w0.203: v2(51.55,94.55) 51.36,94.55 51.18,94.37 PU602.16
  BOTTOM w0.127: v1(51.64,95.24) 51.55,95.15 v2(51.55,94.55)
  BOTTOM w0.203: PC636.2 50.12,94.55 PR639.2 v2(51.55,94.55)
COMP_ISL9538: length 2.9
  TOP w0.203: PU901.28 56.32,53.95 v2(56.09,53.72)
  BOTTOM w0.254: PC943.1 56.12,53.74 v2(56.09,53.72) 55.66,53.29 PR934.1
COMP_VSA: length 3.4
  TOP w0.203: v2(48.96,97.85) 48.73,97.63 PU602.24
  BOTTOM w0.203: PC628.1 47.99,97.23 PR630.1
  BOTTOM w0.229: PC628.1 48,97.26 48.59,97.85 v2(48.96,97.85)
CONTACTLESS_DET#: length 167.9
  TOP w0.127: v2(180.75,58.33) 180.75,57.79 179.53,56.57 179.53,55.23 180.15,54.61 181.76,54.61 183.32,53.04 185.12,53.04 188.21,49.96 219.56,49.96 v3(219.78,50.18) 224.53,50.18 225.08,50.72 225.08,51.25 224.78,51.54 222.55,51.54 220.37,53.73 DZ8.2
  IN1 w0.084: v2(142.49,99.31) 141.77,98.59 140.13,98.59 137.01,101.71 135.99,101.71 134.82,102.88 131.62,102.88 130.96,102.22 127.99,102.22 127.56,102.65 v2(127.38,102.65)
  IN2 w0.122: v2(180.75,58.33) 179.61,58.33 179.02,58.91 178.69,58.91 178.03,58.26 174.9,58.26 173.81,59.35 172.47,59.35 172.34,59.48 171.06,59.48 170.02,60.52 169.73,60.52 169.22,61.02 167.47,61.02 166.31,59.87 165.97,59.87 165.77,60.07 159.98,60.07 159.57,59.65 151.98,59.65 146.68,64.95 146.68,68.07 142.16,72.59 142.16,73.31 138.97,76.5 138.97,78.39 139.08,78.5 139.08,80.06 139.21,80.19 139.21,80.51 139.24,80.54 139.24,81.06 140.08,81.9 v2(140.89,81.9)
  IN4 w0.084: v2(140.89,81.9) 141.2,82.21 141.2,83.27 141.77,83.85 144.36,83.85 144.9,84.39 144.9,88.17 148.47,91.74 148.47,92.51 149.26,93.3 149.26,94.37 148.72,94.92 148.72,95.33 148.89,95.5 149.02,95.63 149.02,99.12 148.61,99.54 148.06,99.54 147.81,99.29 147.33,99.29 146.83,99.79 146.26,99.79 145.61,100.45 145.21,100.45 144.57,99.81 144.27,99.51 142.69,99.51 v2(142.49,99.31)
  BOTTOM w0.076: v2(127.38,102.65) 126.96,102.93 UC1.W11
  BOTTOM w0.127: v2(142.49,99.31) 142.12,98.94 RC278.1
CONTACTLESS_DET#_R: length 7.4
  TOP w0.127: v2(221.77,54.5) DZ8.1 221.77,53.04 v1(222.35,52.45)
  BOTTOM w0.127: JUSH1.23 222.45,58.55 222.27,58.37 222.27,56.64 222.57,56.34 222.57,55.3 v2(221.77,54.5)
CORE_VID0: length 74.4
  TOP w0.127: PR408.1 156.06,131.07 155.51,130.51 v2(155.51,130.19) v1(154.48,130.19)
  IN1 w0.084: v2(155.51,130.19) 155.44,130.12 155.06,130.12 151.57,126.63 139.88,126.63 v2(139.4,126.15)
  IN2 w0.122: v2(139.4,126.15) 138.86,126.15 138.09,125.38 138.09,124.33 139.48,122.94 142.96,122.94 143.3,122.59 143.3,120.31 141.99,119 140.16,119 136.56,115.4 136.56,112.31 137.48,111.39 137.48,110.1 139.63,107.95 139.63,106.06 140.13,105.55 140.13,104.6 138.76,103.23 138.52,103.23 137.91,102.63 137.91,98.72 136.8,97.61 136.8,96.28 136.04,95.51 131.61,95.51 130.04,97.09 127.13,97.09 127.01,96.97 127.01,96.56 v2(126.5,96.05)
  BOTTOM w0.102: UC1.AN11 126.45,96.05 v2(126.5,96.05)
CORE_VID1: length 87
  TOP w0.076: 125.2,96.84 125.2,96.45 v2(124.8,96.06)
  TOP w0.127: v2(162.93,130.05) 162.93,128.87 162.98,128.83 162.98,127.27 162.54,126.83 PR411.1 ; v1(125.2,96.92) 125.2,96.84
  IN1 w0.084: v2(162.93,130.05) 160.26,132.73 158.71,132.73 156.6,130.62 155.06,130.62 151.29,126.85 139.06,126.85 137.99,125.78 v2(137.62,125.78)
  IN2 w0.122: v2(124.8,96.06) 125.82,96.06 126.1,96.34 126.1,97.05 126.44,97.39 130.05,97.39 131.71,95.74 135.88,95.74 136.55,96.4 136.55,97.74 137.69,98.88 137.69,102.72 138.42,103.46 138.67,103.46 139.91,104.69 139.91,105.46 139.4,105.96 139.4,107.86 137.26,110.01 137.26,111.29 136.33,112.22 136.33,115.49 142.7,121.87 142.7,122.48 142.47,122.72 139.38,122.72 137.62,124.48 v2(137.62,125.78)
  BOTTOM w0.102: v2(124.8,96.06) 125.14,96.4 UC1.AN13
CPU_B+: length 20.2
  TOP w0.254: v2(44.54,103.87) 44.25,103.87 42.91,102.53 42.91,98.77 42.08,97.94 PR603.2
  IN2 w0.254: v2(44.54,103.87) 44.54,103.82 45.5,102.87 56.41,102.87 v2(56.62,102.65)
  vias: v1(52.73,78.47) v2(52.22,74.24) v2(52.79,74.24) v2(53.36,74.24) v2(53.94,74.24) v2(54.02,105.66) v2(54.51,75.96) v2(54.51,75.39) v2(54.51,74.81) v2(54.51,74.24) v2(54.6,105.66) v2(55.08,75.96) v2(55.08,75.39) v2(55.08,74.81) v2(55.08,74.24) v2(55.65,75.96) v2(55.65,75.39) v2(55.65,74.81) v2(55.65,74.24) v2(56.37,107.7) v2(56.37,107.02) v2(56.62,102.07) v2(57.21,102.65) v2(57.21,102.07) v2(57.42,99.08) v2(57.42,97.87) v2(57.59,107.7) v2(57.59,107.02) v2(58.09,99.08) v2(58.09,97.87) v2(63.91,111.64) v2(64.55,111.64)
CPU_DP1_AUXN: length 105.9
  IN1 w0.094: v2(38.18,104.3) 38.18,104.18 38,104 37.84,104 37.71,104.13 37.71,105.61 37.08,106.24 37.08,107.64 37.71,108.27 37.71,121.55 39.29,123.13 47.75,123.13 49.77,125.15 51.31,125.15 52.5,126.34 68.62,126.34 68.99,126.71 71.15,126.71 74.02,123.84 75.88,123.84 76.24,123.48 79.06,123.48 79.84,124.26 81.68,124.26 83.64,126.23 85.4,126.23 85.99,126.82 90.88,126.82 91.25,126.45 93.88,126.45 94.25,126.82 97.48,126.82 99.69,124.61 99.97,124.61 102.12,122.46 102.12,121.89 101.56,121.33 101.56,120.61 101.82,120.35 101.82,117.53 102.26,117.08 102.26,114.91 103.1,114.07 103.1,110.12 103.29,109.93 103.75,109.93 103.83,109.85 103.83,109.66 v2(103.71,109.54)
  BOTTOM w0.102: UC1.G50 104.1,109.47 103.89,109.59 v2(103.71,109.54)
  BOTTOM w0.104: CT19.1 37.69,104.1 37.98,104.1 v2(38.18,104.3)
CPU_DP1_AUXN_C: length 9.7
  IN2 w0.076: v2(30.63,100.3) 30.87,100.54 30.87,100.65 31.05,100.83 32.27,100.83 32.29,100.85 32.31,100.85
  IN2 w0.119: 32.31,100.85 33.8,100.85 34.83,101.88 34.83,103.6 35.32,104.09 36.06,104.09 v2(36.27,104.3)
  BOTTOM w0.104: v2(30.63,100.3) 30.96,99.98 UT1.W11 ; v2(36.27,104.3) 36.27,104.23 36.42,104.08 36.75,104.08 36.91,104.24 CT19.2
CPU_DP1_AUXP: length 105.9
  IN1 w0.094: v2(103.71,110.3) 103.52,110.11 103.37,110.11 103.28,110.2 103.28,114.15 102.44,114.99 102.44,117.16 102,117.6 102,120.43 101.75,120.68 101.75,121.25 102.3,121.81 102.3,122.54 100.04,124.8 99.76,124.8 97.56,127 94.17,127 93.8,126.63 91.33,126.63 90.96,127 85.91,127 85.32,126.41 83.57,126.41 81.6,124.44 79.77,124.44 78.98,123.66 76.32,123.66 75.96,124.02 74.09,124.02 71.23,126.89 68.91,126.89 68.55,126.53 52.42,126.53 51.23,125.33 49.69,125.33 47.67,123.31 39.22,123.31 37.53,121.62 37.53,108.35 36.89,107.72 36.89,106.17 37.53,105.53 37.53,104.05 37.76,103.81 37.96,103.81 v2(38.15,103.62)
  BOTTOM w0.102: UC1.F50 103.75,110.16 103.7,110.29 v2(103.71,110.3)
  BOTTOM w0.104: CT18.1 37.68,103.9 37.87,103.9 v2(38.15,103.62)
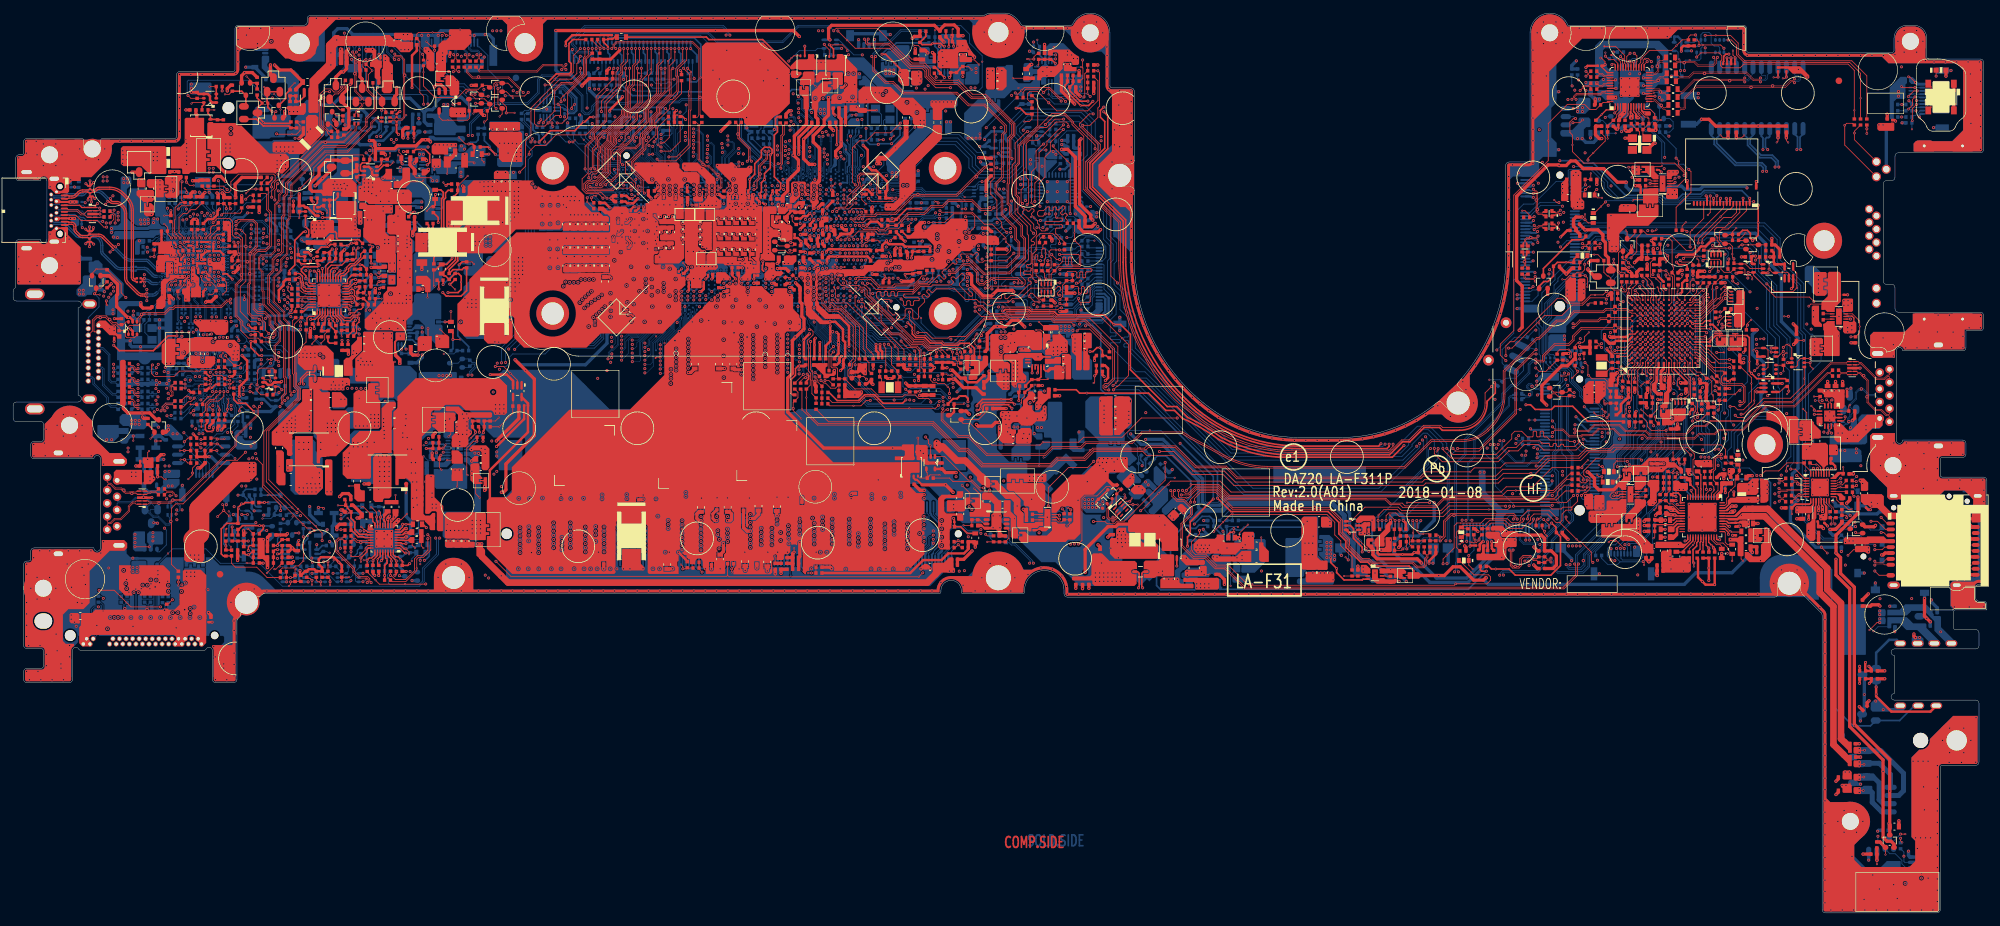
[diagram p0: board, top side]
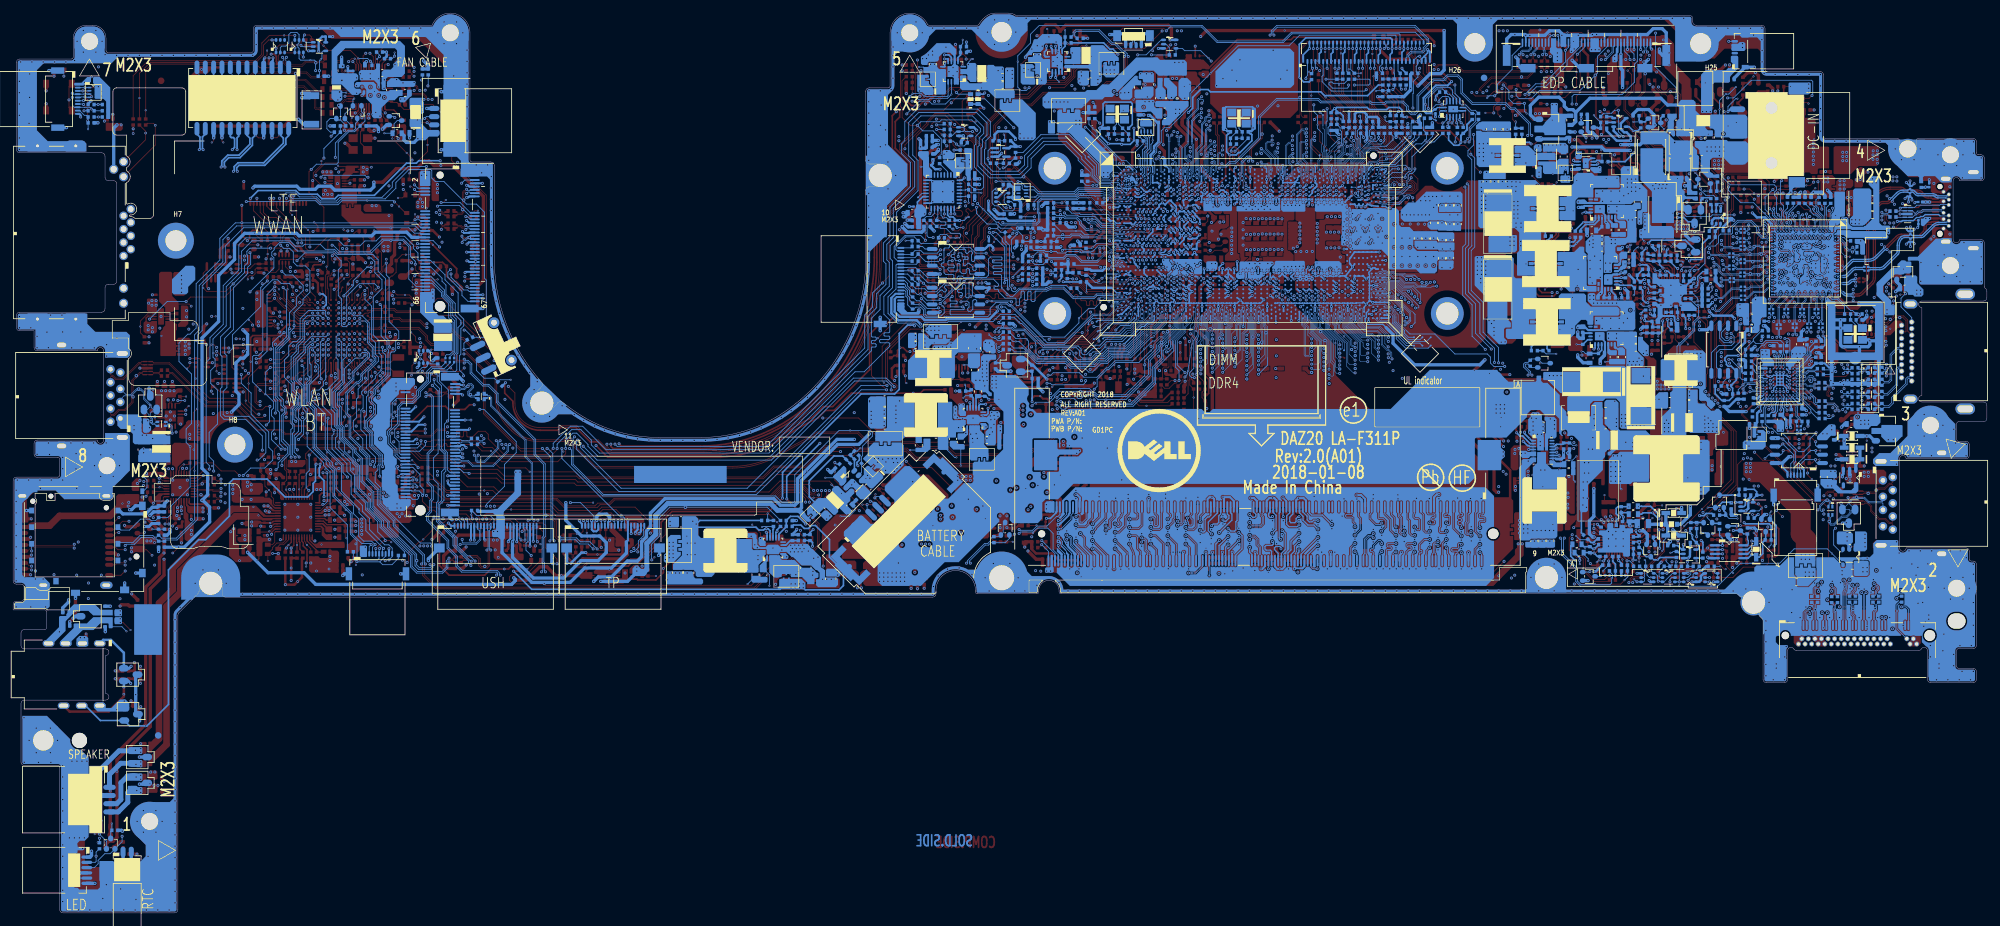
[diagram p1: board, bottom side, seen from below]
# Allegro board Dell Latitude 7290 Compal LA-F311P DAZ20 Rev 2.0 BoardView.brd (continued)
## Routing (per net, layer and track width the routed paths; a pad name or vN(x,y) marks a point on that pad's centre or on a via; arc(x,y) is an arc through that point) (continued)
CPU_DP1_AUXP_C: length 9.7
  IN2 w0.076: 32.31,100.64 32.29,100.64 32.27,100.66 31.12,100.66 31.04,100.58 31.04,100.49 31.23,100.3 v2(31.28,100.3)
  IN2 w0.119: v2(36.28,103.55) 36.28,103.82 36.21,103.88 35.41,103.88 35.04,103.52 35.04,101.8 33.89,100.64 32.31,100.64
  BOTTOM w0.104: UT1.Y11 v2(31.28,100.3) ; CT18.2 36.75,103.89 36.52,103.89 36.28,103.64 v2(36.28,103.55)
CPU_DP1_CTRL_CLK: length 143.4
  TOP w0.127: v2(124.82,106.94) v1(125.35,107.47) 125.69,107.47 125.83,107.61 126.8,107.61 127.06,107.87 127.06,109.19 128.8,110.92 128.8,111.3 128.67,111.43 128.67,112.39 129.09,112.8 131.33,112.8 131.84,112.29 131.84,110.07 131.97,109.94 RC175.1 ; v2(39.6,87.74) 39.71,87.74 40.03,88.06 40.03,88.96 39.26,89.73 39.26,90.82 38.41,91.67 37.28,91.67 36.81,92.15 36.81,100.4 37.28,100.86 38.51,100.86 39.33,101.68 39.33,106.87 38.87,107.33 38.87,110.21 RT341.1
  IN1 w0.084: v2(39.6,87.74) 39.79,87.94 40.24,87.94 41.09,87.08 48.12,87.08 52.36,82.84 58.87,82.84 59.12,83.1 67.02,83.1 68.13,84.21 71.32,84.21 73.17,86.05 73.95,86.05 75.57,87.68 87.88,87.68 90.2,90 91.18,90 91.78,90.6 97.93,90.6 98.69,91.36 98.69,93.37 100.57,95.25 106.01,95.25 107.69,96.92 107.69,98.71 109.24,100.26 114.27,100.26 114.59,99.94 115.47,99.94 119.19,103.66 119.19,104.91 120.6,106.32 120.6,106.45 121.49,107.35 121.49,107.6 121.78,107.89 124.42,107.89 125.01,107.3 125.01,107.13 v2(124.82,106.94)
  BOTTOM w0.127: UC1.L13 v2(124.82,106.94)
CPU_DP1_CTRL_DATA: length 143.5
  TOP w0.127: RT342.1 37.78,109.7 38.49,109.7 38.62,109.57 38.62,107.22 39.08,106.76 39.08,101.79 38.4,101.12 37.17,101.12 36.56,100.5 36.56,92.04 37.18,91.42 38.3,91.42 39,90.72 39,89.62 39.77,88.85 39.77,88.5 v2(39.6,88.32) ; v2(125.47,106.94) 125.88,107.35 127.3,107.35 127.95,108 127.95,109.64 128.32,110.01 128.34,110.01 v1(128.39,110.06) 128.57,110.24 129.05,110.73 129.05,111.41 128.92,111.54 128.92,112.28 129.19,112.55 131.22,112.55 131.59,112.19 131.59,109.5 RC178.1
  IN1 w0.084: v2(39.6,88.32) 39.77,88.15 40.33,88.15 41.18,87.3 48.2,87.3 52.44,83.05 58.78,83.05 59.03,83.31 66.93,83.31 68.04,84.42 71.24,84.42 73.08,86.27 73.86,86.27 75.48,87.89 87.79,87.89 90.11,90.21 91.09,90.21 91.69,90.81 97.84,90.81 98.48,91.45 98.48,93.46 100.48,95.46 105.93,95.46 107.48,97.01 107.48,98.79 109.15,100.47 114.36,100.47 114.68,100.15 115.39,100.15 118.98,103.75 118.98,104.99 120.39,106.4 120.39,106.54 121.28,107.44 121.28,107.69 121.69,108.1 124.51,108.1 125.27,107.35 125.27,107.15 v2(125.47,106.94)
  BOTTOM w0.102: UC1.L12 v2(125.47,106.94)
CPU_DP1_HPD: length 163.3
  TOP w0.127: RT24.1 28.81,110.71 29.23,110.3 v1(31.63,110.3) 31.92,110.3 32.38,109.85 32.86,109.85 33.17,110.16 33.17,111.47 34.36,112.66 39.67,112.66 39.92,112.41 39.92,111.76 39.35,111.19 v2(39.35,110.7)
  IN2 w0.122: v2(128.04,106.88) 128.53,106.39 129.41,106.39 129.75,106.73 129.75,110.52 129.6,110.68 129.01,110.68 128.85,110.51 128.18,110.51 127.92,110.77 127.92,111.97 128.55,112.6 128.55,116.78 129.81,118.04 129.81,118.78 129.49,119.1 129.49,119.81 130.16,120.48 130.16,122.03 129.79,122.4 129.79,124.28 128.53,125.55 126.08,125.55 125.93,125.69 121.06,125.69 121.04,125.67 118.97,125.67 117.69,124.4 99.24,124.4 97.94,123.1 89.4,123.1 88.32,122.03 87.73,122.03 86.87,121.17 85.32,121.17 84.63,121.86 82.45,121.86 81.89,121.3 77.1,121.3 76.89,121.08 73.06,121.08 72.04,122.1 71.03,122.1 69.24,123.89 62.3,123.89 59.51,121.09 55.87,121.09 53.56,123.4 47.5,123.4 46.91,122.81 41.25,122.81 40.94,122.51 40.94,121.02 42.49,119.47 43.71,119.47 45.33,117.84 45.33,115.07 40.91,110.64 39.41,110.64 v2(39.35,110.7)
  BOTTOM w0.076: 33.04,105.8 32.61,105.37 32.54,105.37 32.38,105.21 32.38,104.94 32.07,104.63 32.07,104.15 UT1.AA2 ; v2(128.04,106.88) UC1.L9
  BOTTOM w0.127: v2(39.35,110.7) 39.35,110.17 37.47,108.29 35.53,108.29 33.04,105.8
CPU_DP1_N0: length 102
  IN1 w0.076: v2(100.94,110.86) 100.77,110.69 100.66,110.69 100.56,110.79 100.56,111.39 100.64,111.46 100.64,111.88 100.65,111.89 100.65,111.9
  IN1 w0.094: 100.65,111.9 100.65,112.34 101.18,112.87 101.18,116.64 100.71,117.11 100.71,119.76 95.38,125.1 87.95,125.1 87.76,124.91 83.76,124.91 82.01,123.17 80.16,123.17 79.4,122.41 75.63,122.41 75.29,122.76 74.7,122.76 74.18,122.24 73.11,122.24 70.98,124.37 69.58,124.37 69.37,124.58 52.38,124.58 51.74,123.94 50.06,123.94 47.03,120.91 39.6,120.91 38.73,120.04 38.73,108.36 39.85,107.25 39.85,101.46 40.03,101.27 40.24,101.27 v2(40.43,101.08)
  BOTTOM w0.076: v2(100.94,110.86) 101,110.67 101.26,110.54 UC1.E55
  BOTTOM w0.104: v2(40.43,101.08) 40.12,101.39 38.83,101.39 38.73,101.29 37.67,101.29 CT11.1
CPU_DP1_N0_C: length 5.4
  BOTTOM w0.076: 34.13,101.44 34.11,101.44 34.1,101.46 33.81,101.46 33.76,101.51 33.06,101.51 32.94,101.39 32.63,101.39 32.56,101.46 32.56,101.54 32.64,101.62 UT1.AC7
  BOTTOM w0.104: CT11.2 36.73,101.32 36.68,101.32 36.31,100.95 35.85,100.95 35.56,101.24 35.51,101.24 35.13,101.62 34.69,101.62 34.51,101.44 34.13,101.44
CPU_DP1_N1: length 94.7
  IN1 w0.076: 98.04,111.52 98.02,111.5 98.01,111.5 97.81,111.3 97.81,110.63 98.02,110.42 98.55,110.42 98.8,110.67 98.94,110.67 v2(99.12,110.86)
  IN1 w0.094: v2(42.38,99.9) 42.17,100.11 41.95,100.11 41.65,100.41 41.65,111.37 42.4,112.12 42.4,114.28 47.88,119.76 48.86,119.76 51.6,122.49 52.38,122.49 52.97,123.08 58.92,123.08 59.34,122.66 69.23,122.66 69.56,122.33 70.31,122.33 71.79,120.85 79.52,120.85 79.89,121.21 81.83,121.21 82.91,122.3 83.81,122.3 85.18,123.67 90.92,123.67 91.69,122.9 94.1,122.9 95.14,121.86 95.14,121.3 97.06,119.37 98.96,119.37 99.43,118.91 99.43,112.91 98.04,111.52
  BOTTOM w0.089: UC1.E58 99.39,110.59 v2(99.12,110.86)
  BOTTOM w0.104: CT13.1 39.39,100.15 40.74,100.15 40.82,100.24 42.04,100.24 v2(42.38,99.9)
CPU_DP1_N1_C: length 6.8
  BOTTOM w0.076: 33.91,100.43 33.87,100.43 33.54,100.76 33.19,100.76 33.09,100.66 33.09,100.57 32.99,100.47 32.73,100.47 32.68,100.52 32.68,100.62 UT1.AC9
  BOTTOM w0.104: CT13.2 38.63,100.07 38.53,100.17 37.77,100.17 37.63,100.31 36.43,100.31 36.4,100.27 35.81,100.27 35.78,100.31 34.76,100.31 34.64,100.43 v4(34.38,100.43) 33.91,100.43
CPU_DP1_N2: length 105.7
  IN1 w0.076: 101.82,111.9 101.82,111.89 101.81,111.88 101.81,111.21 101.5,110.91 101.5,110.14 101.59,110.05 101.71,110.05 v2(101.88,110.22)
  IN1 w0.094: 101.82,111.9 101.82,116.91 101.36,117.37 101.36,120.03 95.2,126.18 94.29,126.18 94.08,125.97 91.01,125.97 90.58,126.41 87.67,126.41 86.88,125.62 83.62,125.62 81.85,123.85 80,123.85 79.16,123.01 76.13,123.01 75.72,123.43 72.8,123.43 70.82,125.41 52.25,125.41 51.59,124.75 49.98,124.75 46.79,121.55 39.32,121.55 38.12,120.36 38.12,107.82 39.08,106.86 39.08,101.86 37.31,100.08 37.31,99.42 37.54,99.19 37.84,99.19 v2(38.09,98.94)
  BOTTOM w0.076: UC1.F53 101.9,110.16 v2(101.88,110.22)
  BOTTOM w0.104: v2(38.09,98.94) 38.09,99.13 37.96,99.26 37.67,99.26 CT15.1
CPU_DP1_N2_C: length 5.1
  BOTTOM w0.076: UT1.AC11 32.63,99.78 32.56,99.71 32.56,99.61 32.61,99.56 32.92,99.56 33.09,99.72 33.17,99.72 33.6,99.29 34.58,99.29 34.59,99.28 34.61,99.28
  BOTTOM w0.104: CT15.2 36.73,99.28 v4(35.67,99.28) 34.61,99.28
CPU_DP1_N3: length 102.6
  IN1 w0.076: v2(100.04,110.23) 99.86,110.06 99.73,110.06 99.64,110.15 99.64,111.19 99.35,111.48 99.35,111.59 99.36,111.6 99.36,111.62
  IN1 w0.094: v2(40.15,98.06) 39.93,98.28 39.7,98.28 39.41,98.58 39.41,99.73 39.79,100.11 40.43,100.11 41.04,100.73 41.04,111.09 39.46,112.67 39.46,119.5 40.12,120.16 47.12,120.16 50.22,123.25 51.97,123.25 52.67,123.95 68.99,123.95 69.95,122.99 71.46,122.99 72.96,121.49 79.34,121.49 79.75,121.9 81.65,121.9 82.64,122.88 83.54,122.88 84.94,124.29 91.31,124.29 92.05,123.55 95.02,123.55 98.4,120.17 99.4,120.17 100.07,119.49 100.07,116.84 100.54,116.37 100.54,113.1 99.36,111.93 99.36,111.62
  BOTTOM w0.076: v2(100.04,110.23) 100.03,110.21 100.06,110.09 100.41,109.91 UC1.F56
  BOTTOM w0.104: v2(40.15,98.06) 39.88,98.34 39.42,98.34 CT17.1
CPU_DP1_N3_C: length 7
  BOTTOM w0.076: 33.54,98.74 33.52,98.74 33.51,98.75 33.17,98.75 33.05,98.64 32.61,98.64 32.56,98.69 32.56,98.79 32.63,98.86 UT1.AC13
  BOTTOM w0.104: 33.54,98.74 33.83,98.74 34.14,98.43 34.78,98.43 34.82,98.47 35.46,98.47 35.87,98.07 38.07,98.07 38.33,98.33 38.44,98.33 CT17.2
CPU_DP1_P0: length 102
  IN1 w0.076: v2(100.92,110.18) 100.92,110.41 100.82,110.52 100.59,110.52 100.4,110.72 100.4,111.45 100.47,111.53 100.47,111.88 100.46,111.89 100.46,111.9
  IN1 w0.094: v2(40.46,101.95) 40.46,101.62 40.29,101.46 40.11,101.46 40.03,101.53 40.03,107.32 38.91,108.44 38.91,119.96 39.68,120.73 47.11,120.73 50.13,123.75 51.81,123.75 52.46,124.4 69.3,124.4 69.51,124.19 70.9,124.19 73.04,122.05 74.25,122.05 74.78,122.58 75.21,122.58 75.56,122.23 79.48,122.23 80.23,122.98 82.09,122.98 83.83,124.73 87.84,124.73 88.03,124.91 95.3,124.91 100.53,119.68 100.53,117.03 101,116.56 101,112.95 100.46,112.41 100.46,111.9
  BOTTOM w0.076: UC1.F55 101.35,110.11 101.11,110.24 v2(100.92,110.18)
  BOTTOM w0.104: v2(40.46,101.95) 40.09,101.58 38.75,101.58 38.65,101.48 37.72,101.48 CT10.1
CPU_DP1_P0_C: length 5.4
  BOTTOM w0.076: UT1.AB7 32.53,101.84 33.04,101.84 33.21,101.67 33.83,101.67 33.88,101.62 34.1,101.62 34.11,101.64 34.13,101.64
  BOTTOM w0.104: CT10.2 36.73,101.51 36.6,101.51 36.23,101.14 35.93,101.14 v4(35.47,101.61) 35.26,101.82 34.61,101.82 34.43,101.64 34.13,101.64
CPU_DP1_P1: length 94.7
  IN1 w0.076: 97.91,111.64 97.89,111.63 97.89,111.62 97.64,111.37 97.64,110.56 97.95,110.25 98.61,110.25 98.87,110.51 99.05,110.51 99.21,110.35 99.21,110.23 v2(99.12,110.13)
  IN1 w0.094: 97.91,111.64 99.25,112.98 99.25,118.83 98.89,119.19 96.98,119.19 94.95,121.22 94.95,121.78 94.02,122.71 91.61,122.71 90.84,123.48 85.25,123.48 83.88,122.11 82.99,122.11 81.9,121.03 79.96,121.03 79.6,120.66 71.71,120.66 70.23,122.14 69.48,122.14 69.15,122.47 59.26,122.47 58.84,122.89 53.05,122.89 52.46,122.31 51.67,122.31 48.94,119.58 47.95,119.58 42.58,114.21 42.58,112.04 41.83,111.29 41.83,100.48 42.03,100.29 42.27,100.29 42.41,100.43 v2(42.41,100.72)
  BOTTOM w0.076: v2(99.12,110.13) 99.31,109.94 UC1.F58
  BOTTOM w0.104: CT12.1 39.42,100.35 40.66,100.35 40.74,100.43 42.12,100.43 42.12,100.43 v2(42.41,100.72)
CPU_DP1_P1_C: length 6.7
  BOTTOM w0.076: 34.13,100.66 33.91,100.66 33.65,100.92 32.53,100.92 UT1.AB9
  BOTTOM w0.104: 34.13,100.66 34.69,100.66 34.84,100.5 v4(36.1,100.5) 37.71,100.5 37.85,100.36 38.44,100.36 CT12.2
CPU_DP1_P2: length 105.7
  IN1 w0.076: 101.64,111.9 101.64,111.89 101.65,111.88 101.65,111.28 101.34,110.97 101.34,110.07 101.52,109.89 101.75,109.89 101.95,109.69 101.95,109.63 v2(101.86,109.54)
  IN1 w0.094: v2(38.09,99.75) 38.19,99.65 38.19,99.48 38.08,99.37 37.62,99.37 37.49,99.5 37.49,100 39.27,101.78 39.27,106.94 38.3,107.9 38.3,120.28 39.4,121.37 46.86,121.37 50.05,124.56 51.67,124.56 52.33,125.23 70.75,125.23 72.72,123.25 75.64,123.25 76.06,122.83 79.24,122.83 80.07,123.67 81.93,123.67 83.69,125.43 86.96,125.43 87.75,126.22 90.5,126.22 90.94,125.79 94.15,125.79 94.36,126 95.13,126 101.17,119.95 101.17,117.3 101.64,116.83 101.64,111.9
  BOTTOM w0.076: v2(101.86,109.54) 101.9,109.55 102.31,109.32 UC1.G53
  BOTTOM w0.104: v2(38.09,99.75) 38.09,99.58 37.96,99.45 37.72,99.45 CT14.1
CPU_DP1_P2_C: length 5.1
  BOTTOM w0.076: UT1.AB11 32.32,99.78 32.56,100.02 32.95,100.02 33.07,99.89 33.24,99.89 33.67,99.46 34.58,99.46 34.59,99.47 34.61,99.47
  BOTTOM w0.104: 34.61,99.47 35.34,99.47 35.38,99.51 35.97,99.51 36.01,99.47 36.73,99.47 CT14.2
CPU_DP1_P3: length 102.6
  IN1 w0.076: 99.18,111.62 99.18,111.6 99.19,111.59 99.19,111.41 99.48,111.12 99.48,110.08 99.67,109.89 99.92,109.89 100.04,109.78 v2(100.04,109.54)
  IN1 w0.094: v2(40.2,98.91) 40.2,98.53 40.13,98.47 39.78,98.47 39.59,98.65 39.59,99.66 39.86,99.93 40.5,99.93 41.23,100.65 41.23,111.17 39.65,112.75 39.65,119.42 40.2,119.97 47.2,119.97 50.29,123.07 52.05,123.07 52.74,123.77 68.91,123.77 69.87,122.8 71.39,122.8 72.88,121.31 79.42,121.31 79.82,121.72 81.73,121.72 82.71,122.7 83.61,122.7 85.02,124.11 91.23,124.11 91.97,123.37 94.94,123.37 98.32,119.98 99.32,119.98 99.89,119.42 99.89,116.76 100.36,116.3 100.36,113.18 99.18,112 99.18,111.62
  BOTTOM w0.076: v2(100.04,109.54) 100.2,109.59 100.45,109.46 UC1.G56
  BOTTOM w0.104: v2(40.2,98.91) 39.82,98.53 39.4,98.53 CT16.1
CPU_DP1_P3_C: length 7
  BOTTOM w0.076: 33.54,98.93 33.52,98.93 33.51,98.92 33.18,98.92 33,99.1 32.56,99.1 32.32,98.86 UT1.AB13
  BOTTOM w0.104: 33.54,98.93 33.91,98.93 34.18,98.66 v4(34.49,98.66) 35.54,98.66 35.95,98.26 37.99,98.26 38.25,98.52 38.44,98.52 CT16.2
CPU_DP2_AUXN: length 110.7
  IN1 w0.094: v2(38.11,102.18) 37.89,102.4 37.48,102.4 36.85,103.03 36.85,105.19 36.29,105.75 36.29,108.07 36.85,108.63 36.85,109.32 36.19,109.99 36.19,111.23 36.85,111.89 36.85,122.83 38.93,124.91 46.53,124.91 48.75,127.13 68.01,127.13 68.41,127.53 71.43,127.53 73.73,125.22 75.6,125.22 76.4,124.42 78.88,124.42 79.53,125.07 81.4,125.07 83.41,127.08 84.94,127.08 85.53,127.67 98.19,127.67 100.7,125.16 101.75,125.16 103.58,123.32 103.58,120.45 103.05,119.92 103.05,115.3 104.23,114.11 104.23,110.72 104.31,110.65 104.44,110.65 v2(104.61,110.81)
  BOTTOM w0.076: v2(104.61,110.81) UC1.E48
  BOTTOM w0.104: CT175.1 37.74,102.46 37.95,102.46 38.11,102.3 v2(38.11,102.18)
CPU_DP2_AUXN_C: length 9.7
  IN2 w0.119: v2(36.2,102.15) 36.01,102.34 35.79,102.34 35.68,102.24 35.68,101.18 33.36,98.86 31.05,98.86 30.83,99.09 30.83,99.45 v2(30.62,99.66)
  BOTTOM w0.104: UT1.W12 v2(30.62,99.66) ; v2(36.2,102.15) 36.5,102.45 36.79,102.45 CT175.2
CPU_DP2_AUXP: length 110.6
  IN1 w0.094: v2(104.61,110.18) 104.61,110.34 104.48,110.47 104.23,110.47 104.05,110.65 104.05,114.04 102.87,115.22 102.87,120 103.4,120.53 103.4,123.25 101.67,124.98 100.62,124.98 98.11,127.49 85.61,127.49 85.01,126.89 83.48,126.89 81.48,124.89 79.6,124.89 78.95,124.24 76.33,124.24 75.52,125.04 73.66,125.04 71.35,127.34 68.48,127.34 68.09,126.95 48.82,126.95 46.6,124.73 39.01,124.73 37.03,122.75 37.03,111.81 36.37,111.15 36.37,110.06 37.03,109.4 37.03,108.56 36.47,107.99 36.47,105.82 37.03,105.26 37.03,103.11 37.56,102.59 38.13,102.59 38.21,102.66 38.21,102.86 v2(38.07,102.99)
  BOTTOM w0.076: v2(104.61,110.18) UC1.F48
  BOTTOM w0.104: CT169.1 37.74,102.66 37.91,102.66 38.07,102.82 v2(38.07,102.99)
CPU_DP2_AUXP_C: length 9.7
  IN2 w0.119: v2(36.19,102.92) 36.19,102.67 36.08,102.55 35.7,102.55 35.47,102.32 35.47,101.27 33.28,99.07 31.14,99.07 31.04,99.17 31.04,99.6 31.1,99.66 v2(31.27,99.66)
  BOTTOM w0.104: CT169.2 36.76,102.64 36.47,102.64 v2(36.19,102.92) ; UT1.Y12 v2(31.27,99.66)
CPU_DP2_CTRL_CLK: length 24.2
  TOP w0.127: v2(128.83,105.85) 129.17,106.19 131.39,106.19 131.67,106.48 134.43,106.48 137.25,109.29 143.78,109.29 v4(146.73,112.24) 148.1,113.61 148.28,113.61 148.59,113.31 RC176.1
  BOTTOM w0.102: v2(128.83,105.85) 128.87,105.85 129.04,106.01 UC1.N7
CPU_DP2_CTRL_DATA: length 24.8
  TOP w0.127: v2(128.24,105.83) 128.86,106.45 131.21,106.45 131.5,106.73 134.33,106.73 134.59,107 137.15,109.55 v4(137.85,109.55) 143.68,109.55 146.57,112.44 148,113.87 148.28,113.87 148.59,114.17 RC177.1
  BOTTOM w0.076: UC1.N8 128.38,105.97 v2(128.24,105.83)
CPU_DP2_HPD: length 173.3
  TOP w0.127: RT29.1 32.71,101.48 v1(31.95,101.48) 31.41,101.48 v2(31.29,101.61)
  IN1 w0.084: v2(31.29,101.61) 30.63,101.61 29.56,100.54 28.08,100.54 27.62,101 23.9,101 23.6,101.31 23.6,102.94 25.39,104.73 25.39,106.04 26.23,106.88 26.87,106.88 26.96,106.97 26.96,109.12 27.13,109.29 27.13,110.48 27.94,111.29 30.26,111.29 31.16,112.19 31.16,125.75 31.72,126.31 35.48,126.31 37.72,128.55 44.32,128.55 51.06,135.29 71.14,135.29 74.4,132.03 74.4,131.41 76.6,129.22 79.19,129.22 81.72,131.75 81.72,132.93 83.43,134.64 105.61,134.64 110.06,130.18 114.18,130.18 118.85,125.51 v2(118.85,124.9)
  IN2 w0.122: v2(129.28,106.84) 128.83,107.29 128.83,109.64 128.56,109.92 128.39,109.92 127.69,110.61 127.69,112.06 128.29,112.66 128.29,116.84 129.57,118.12 129.57,118.56 129.21,118.93 129.21,119.85 129.94,120.58 129.94,121.94 129.57,122.3 129.57,124.07 128.32,125.32 125.98,125.32 125.84,125.47 121.15,125.47 121.11,125.43 119.38,125.43 v2(118.85,124.9)
  BOTTOM w0.102: UC1.L7 129.04,107.09 v2(129.28,106.84)
  BOTTOM w0.127: v2(31.29,101.61) 31.6,101.92 UT1.Y6
CPU_DP2_N0: length 103.3
  IN4 w0.094: v2(41.59,98.62) 41.8,98.83 42.16,98.83 43.01,99.68 43.01,101.32 42.33,102.01 42.33,107.91 42.21,108.03 42.21,112.35 44.16,114.3 44.16,116.85 46,118.69 46,119.61 48.55,122.16 49.83,122.16 52.4,124.72 68.9,124.72 69.74,123.88 70.78,123.88 71.53,123.13 75.6,123.13 75.73,123 81.87,123 83.75,124.88 90.99,124.88 91.89,125.78 93.43,125.78 94.33,124.88 97.72,124.88 99.82,122.78 99.82,122.46 103.13,119.14 103.47,119.14 v2(103.65,118.96)
  BOTTOM w0.076: 104.42,114.07 104.41,114.06 104.41,114.05 104.37,114.01 104.37,114 104.27,113.9 104.27,113.78 104.28,113.78 arc(104.3,113.62) 104.36,113.48 arc(104.41,113.34) 104.38,113.2 arc(104.34,113) 104.38,112.79 arc(104.39,112.69) 104.39,112.59 arc(104.35,112.49) 104.29,112.41 arc(104.29,112.4) 104.28,112.4 104.25,112.37 104.06,112.37 104.02,112.32 104.02,112.18 103.99,112.15 103.99,112.09 104.07,112.01 UC1.C50
  BOTTOM w0.089: v2(103.65,118.96) 103.63,118.93 103.63,118.83 103.73,118.72 103.92,118.72 104.01,118.81 104.01,119.27 104.1,119.35 104.29,119.35 104.98,118.66 104.98,114.63 104.42,114.07
  BOTTOM w0.104: CT176.1 37.72,97.26 40.32,97.26 40.83,97.76 40.83,98.41 41.24,98.82 41.39,98.82 v2(41.59,98.62)
CPU_DP2_N0_C: length 5.1
  BOTTOM w0.076: UT1.AC15 32.66,97.84 32.66,97.84 32.66,97.76 32.71,97.7 32.93,97.7 33.25,98.02 33.71,98.02 34.13,97.61 34.13,97.59 34.14,97.57
  BOTTOM w0.104: 34.14,97.57 34.44,97.27 v4(34.77,97.27) 35.71,97.27 35.75,97.24 36.33,97.24 36.37,97.27 36.74,97.27 CT176.2
CPU_DP2_N1: length 99.3
  IN4 w0.094: v2(102.42,118.39) 102.2,118.18 102.07,118.18 101.51,118.74 101.51,119.86 97.31,124.05 94.5,124.05 93.22,125.33 92.16,125.33 90.89,124.05 84.68,124.05 83.45,122.82 82.61,122.82 81.71,121.92 76.13,121.92 75.41,122.63 74.37,122.63 73.96,122.23 70.48,122.23 68.72,123.98 52.51,123.98 50.15,121.62 48.71,121.62 47.23,120.14 47.23,119.31 44.6,116.67 44.6,114.17 42.92,112.5 42.92,109.37 43.18,109.11 43.18,108.18 42.74,107.74 42.74,102.18 43.42,101.5 43.42,99.49 40.98,97.05 40.98,96.72 40.81,96.55 40.71,96.55 v2(40.48,96.78)
  BOTTOM w0.076: UC1.C52 103.09,112.12 103.09,112.3 103.04,112.36 102.81,112.36 102.77,112.4 102.72,112.58 102.72,112.75 102.78,112.94 102.78,113.12 102.73,113.16 102.73,113.47 103,113.74 103,114.67 103.01,114.68 103.01,114.7
  BOTTOM w0.089: 103.01,114.7 103.01,117.9 102.76,118.15 102.49,118.15 102.39,118.25 102.39,118.36 v2(102.42,118.39)
  BOTTOM w0.104: v2(40.48,96.78) 40.29,96.58 39.33,96.58 CT171.1
CPU_DP2_N1_C: length 6.8
  BOTTOM w0.076: 34.6,96.56 34.58,96.56 34.56,96.55 34.45,96.55 33.76,97.24 33.24,97.24 33.15,97.16 33.05,97.16 32.94,97.27 32.67,97.27 32.59,97.19 32.59,97.12 32.68,97.02 UT1.AC17
  BOTTOM w0.104: 34.6,96.56 38.47,96.56 38.56,96.66 CT171.2
CPU_DP2_N2: length 103.4
  IN4 w0.094: v2(103.65,117.79) 102.99,117.79 102.45,117.25 101.81,117.25 100.39,118.67 100.39,119.98 96.9,123.47 86.81,123.47 85.46,122.12 82.86,122.12 81.95,121.2 70.36,121.2 68.91,122.66 60.33,122.66 59.74,123.25 52.78,123.25 49.76,120.23 49.12,120.23 45.24,116.35 45.24,113.92 44.28,112.97 44.28,108.17 43.33,107.22 43.33,102.58 44,101.91 44,99.22 41.87,97.09 41.87,96.75 41.23,96.1 41.23,95.78 40.61,95.16 40.61,93.92 40.81,93.72 41.17,93.72 v2(41.39,93.51)
  BOTTOM w0.076: UC1.A50 104.11,113.12 104.03,113.05 103.96,113.05 103.84,113.17 103.84,113.79 104.66,114.61 104.66,117.45 104.47,117.64 103.79,117.64 v2(103.65,117.79)
  BOTTOM w0.104: v2(41.39,93.51) 41.22,93.67 40.23,93.67 38.8,95.1 37.66,95.1 CT168.1
CPU_DP2_N2_C: length 5.2
  BOTTOM w0.076: UT1.AC19 32.77,96.1 32.63,96.1 32.58,96.05 32.58,95.95 32.66,95.88 32.96,95.88 33.13,96.05 33.68,96.05 34.09,95.64 34.09,95.62 34.1,95.6
  BOTTOM w0.104: CT168.2 36.69,95.1 36.24,95.1 35.94,95.4 34.31,95.4 34.1,95.6
CPU_DP2_N3: length 101.8
  IN4 w0.094: v2(41.77,92.14) 41.77,92.47 41.81,92.52 42.21,92.52 42.52,92.82 42.79,93.1 42.79,96.88 44.77,98.86 44.77,102.23 44.11,102.89 44.11,106.72 45.15,107.76 45.15,110.97 46.15,111.97 46.15,116.09 49.01,118.95 50.62,118.95 52.67,121 59.89,121 60.46,120.43 78.88,120.43 79.77,119.55 85.26,119.55 88.42,122.7 95.27,122.7 99.52,118.45 99.52,117.98 101.75,115.75 103.26,115.75 v2(103.63,115.37)
  BOTTOM w0.076: v2(103.63,115.37) 103.86,115.6 104.03,115.6 104.12,115.52 104.12,114.99 103.44,114.31 103.44,114.14 103.3,114 103.3,112.98 103.47,112.8 103.47,112.72 103.27,112.51 103.27,112.1 103.55,111.82 UC1.D51
  BOTTOM w0.104: v2(41.77,92.14) 41.35,91.72 40.72,91.72 38.74,93.7 37.66,93.7 CT170.1
CPU_DP2_N3_C: length 5.3
  BOTTOM w0.076: 33.48,94.98 33.47,95 33.47,95.02 33.25,95.24 33.15,95.24 33.08,95.17 33.08,95.06 32.98,94.96 32.72,94.96 32.68,95 32.68,95.09 UT1.AC21
  BOTTOM w0.104: 33.48,94.98 33.87,94.6 35.48,94.6 36.38,93.7 36.64,93.7 CT170.2
CPU_DP2_P0: length 103.3
  IN4 w0.094: v2(103.65,119.54) 103.43,119.32 103.21,119.32 100,122.53 100,122.86 97.8,125.07 94.4,125.07 93.5,125.97 91.82,125.97 90.92,125.07 83.68,125.07 81.8,123.19 75.81,123.19 75.67,123.32 71.6,123.32 70.85,124.07 69.82,124.07 68.98,124.91 52.32,124.91 49.75,122.34 48.47,122.34 45.82,119.69 45.82,118.77 43.98,116.93 43.98,114.37 42.03,112.42 42.03,107.95 42.14,107.84 42.14,101.93 42.83,101.24 42.83,99.76 42.09,99.01 41.78,99.01 v2(41.59,99.2)
  BOTTOM w0.076: 104.55,113.94 104.45,113.83 104.45,113.78 arc(104.46,113.67) 104.5,113.57 arc(104.57,113.36) 104.54,113.14 arc(104.51,112.99) 104.53,112.85 arc(104.56,112.7) 104.55,112.56 arc(104.53,112.49) 104.51,112.43 arc(104.51,112.43) 104.51,112.43 arc(104.5,112.41) 104.49,112.39 104.49,112.36 104.49,112.36 arc(104.49,112.36) 104.49,112.35 104.49,112.35 104.49,112.35 104.49,112.14 UC1.D50
  BOTTOM w0.089: v2(103.65,119.54) 104.36,119.54 105.16,118.74 105.16,114.56 104.55,113.95 104.55,113.94
  BOTTOM w0.104: v2(41.59,99.2) 41.39,99.01 41.16,99.01 40.63,98.49 40.63,97.84 40.24,97.45 37.72,97.45 CT177.1
CPU_DP2_P0_C: length 5.1
  BOTTOM w0.076: 34.28,97.71 34.26,97.72 34.24,97.72 33.78,98.18 32.55,98.18 32.49,98.13 UT1.AB15
  BOTTOM w0.104: 34.28,97.71 34.48,97.5 35.06,97.5 35.1,97.47 v4(36.04,97.47) 36.72,97.47 36.9,97.64 CT177.2
CPU_DP2_P1: length 99.3
  IN4 w0.094: v2(102.42,117.79) 102.2,118 102,118 101.33,118.66 101.33,119.78 97.24,123.87 94.42,123.87 93.15,125.15 92.24,125.15 90.96,123.87 84.76,123.87 83.52,122.64 82.69,122.64 81.78,121.73 76.05,121.73 75.34,122.45 74.44,122.45 74.04,122.04 70.4,122.04 68.65,123.8 52.59,123.8 50.23,121.44 48.79,121.44 47.42,120.07 47.42,119.23 44.78,116.6 44.78,114.09 43.11,112.42 43.11,109.44 43.37,109.18 43.37,108.11 42.92,107.66 42.92,102.26 43.6,101.58 43.6,99.41 41.16,96.97 41.16,96.64 40.89,96.37 40.66,96.37 v2(40.48,96.2)
  BOTTOM w0.076: 102.83,114.7 102.83,114.68 102.84,114.67 102.84,113.81 102.56,113.53 102.56,113.1 102.61,113.05 102.61,112.97 102.55,112.77 102.55,112.55 102.69,112.07 102.69,111.96 102.77,111.69 UC1.D52
  BOTTOM w0.089: 102.83,114.7 102.83,117.82 102.68,117.97 102.56,117.97 102.42,117.82 v2(102.42,117.79)
  BOTTOM w0.104: v2(40.48,96.2) 40.29,96.39 39.33,96.39 CT172.1
CPU_DP2_P1_C: length 6.8
  BOTTOM w0.076: UT1.AB17 32.38,97.02 32.59,96.81 33.04,96.81 33.31,97.08 33.69,97.08 34.38,96.39 34.56,96.39 34.58,96.37 34.6,96.37
  BOTTOM w0.104: CT172.2 38.39,96.37 34.6,96.37
CPU_DP2_P2: length 103.4
  IN4 w0.094: v2(41.28,94.3) 41.42,94.3 41.46,94.26 41.46,94.05 41.32,93.9 40.89,93.9 40.79,94 40.79,95.08 41.41,95.7 41.41,96.03 42.06,96.67 42.06,97.02 44.19,99.15 44.19,101.99 43.52,102.66 43.52,107.15 44.47,108.1 44.47,112.89 45.42,113.85 45.42,116.28 49.19,120.05 49.84,120.05 52.85,123.06 59.66,123.06 60.25,122.47 68.84,122.47 70.29,121.02 82.03,121.02 82.94,121.93 85.54,121.93 86.89,123.29 96.83,123.29 100.21,119.91 100.21,118.6 101.74,117.07 102.52,117.07 103.06,117.6 103.25,117.6 v2(103.65,117.2)
  BOTTOM w0.076: v2(103.65,117.2) 103.65,117.3 103.83,117.48 104.4,117.48 104.5,117.38 104.5,114.68 103.68,113.86 103.68,113.1 UC1.B50
  BOTTOM w0.104: CT174.1 37.66,95.29 38.88,95.29 40.31,93.86 40.84,93.86 v2(41.28,94.3)
CPU_DP2_P2_C: length 5.2
  BOTTOM w0.076: 34.24,95.74 34.23,95.75 34.21,95.75 33.75,96.21 33.1,96.21 32.96,96.35 32.55,96.35 32.45,96.24 UT1.AB19
  BOTTOM w0.104: CT174.2 36.69,95.29 36.32,95.29 36.02,95.59 34.39,95.59 34.24,95.74
CPU_DP2_P3: length 101.8
  IN4 w0.094: v2(41.35,92.55) 41.58,92.55 41.74,92.7 42.13,92.7 42.61,93.17 42.61,96.96 44.59,98.94 44.59,102.15 43.93,102.82 43.93,106.79 44.97,107.83 44.97,111.05 45.97,112.05 45.97,116.17 48.94,119.13 50.54,119.13 52.59,121.18 59.97,121.18 60.54,120.61 78.96,120.61 79.84,119.73 85.18,119.73 88.34,122.88 95.34,122.88 99.7,118.52 99.7,118.05 101.82,115.93 103.57,115.93 v2(103.63,116)
  BOTTOM w0.076: v2(103.63,116) 103.86,115.77 104.1,115.77 104.28,115.59 104.28,114.92 103.61,114.24 103.61,114.07 103.46,113.93 103.46,113.05 103.85,112.66 103.85,112.31 103.73,112.18 103.62,112.18 103.55,112.25 UC1.C51
  BOTTOM w0.104: v2(41.35,92.55) 41.35,92 41.27,91.91 40.8,91.91 38.82,93.9 37.66,93.9 CT173.1
CPU_DP2_P3_C: length 5.4
  BOTTOM w0.076: 33.62,95.12 33.61,95.13 33.59,95.13 33.32,95.4 32.6,95.4 32.39,95.18 UT1.AB21
  BOTTOM w0.104: 33.62,95.12 33.95,94.79 35.56,94.79 36.46,93.9 36.64,93.9 CT173.2
CPU_DP3_AUXN: length 1.1
  TOP w0.127: T1.1 105.42,109.41 v2(105.6,109.6)
  BOTTOM w0.102: v2(105.6,109.6) 105.68,109.6 105.98,109.29 UC1.G46
CPU_DP3_AUXP: length 1
  TOP w0.127: v2(105.58,110.23) 105.46,110.35 T2.1
  BOTTOM w0.102: v2(105.58,110.23) 105.69,110.23 UC1.F46
CPU_POPIRCOMP: length 11.9
  TOP w0.381: RC88.1 123.79,86.46 124.48,87.16 v1(124.48,88.07) v2(124.48,89.52)
  IN2 w0.254: v2(122.86,94.25) 122.67,94.25 122.44,94.02 122.44,92.67 122.83,92.28
  IN2 w0.381: v2(124.48,89.52) 124.26,89.52 123.77,90 123.77,91.34 122.83,92.28
  BOTTOM w0.254: UC1.AT16 v2(122.86,94.25)
CPU_XDP_PRDY#: length 21.2
  TOP w0.127: v2(102.13,128.79) 103.05,127.87 103.05,125.5 102.93,125.39 v1(102.93,124.63) 102.96,124.59 102.96,122.47 102.89,122.4 102.89,117.1 101.07,115.28 v2(99.9,115.28)
  BOTTOM w0.076: v2(99.9,115.28) 99.9,114.82 100.22,114.5 100.22,113.69 100.07,113.54 100.07,113.17 100.11,113.1 100.11,112.89 100.06,112.75 100.06,112.61 100.21,112.07 100.21,111.96 100.29,111.69 UC1.D56
  BOTTOM w0.127: v2(102.13,128.79) 102.31,128.97 JXDP1.5
CPU_XDP_PREQ#: length 24
  TOP w0.127: v2(102.74,128.79) v1(103.27,128.26) 103.27,122.44 103.15,122.31 103.15,116.85 100.97,114.67 98.36,114.67 v2(98.1,114.93)
  BOTTOM w0.076: v2(98.1,114.93) 98.32,114.71 98.32,112.48 98.3,112.46 98.3,112.22 98.32,112.2 98.32,111.83 98.3,111.81 98.3,111.63 UC1.D61
  BOTTOM w0.127: JXDP1.3 102.91,128.96 v2(102.74,128.79) 102.74,128.13 RC138.1
CPU_XDP_TCLK: length 26.6
  IN1 w0.084: v2(96.8,118.27) 96.8,118.46 93.45,121.8 91.04,121.8 90.71,121.48 89.47,121.48 88.22,122.73 v2(87.45,122.73)
  BOTTOM w0.076: v2(96.8,118.27) 97.06,118.01 97.06,117.81 96.48,117.24 96.48,116.81 96.85,116.44 96.85,115.38 97.94,114.29 97.94,113.64 97.76,113.47 97.76,113.21 97.82,113.09 97.82,112.87 UC1.B61
  BOTTOM w0.112: v2(96.8,118.27) 96.8,118.68 RC328.1
  BOTTOM w0.127: JXDP1.57 86.71,129.34 86.94,129.11 86.94,128.28 RC139.1 86.69,127.46 87.38,126.77 87.38,124.98 87.45,124.92 v2(87.45,122.73)
CPU_XDP_TDI: length 28.6
  TOP w0.127: v2(80.1,120.48) 80.39,120.77 v3(80.39,120.95)
  IN1 w0.084: v2(97.45,116.88) 97.16,116.6 96.29,116.6 95.59,117.3 95.59,118.33 93.57,120.36 88.96,120.36 88.54,120.77 86.95,120.77 86.21,120.04 80.54,120.04 v2(80.1,120.48)
  BOTTOM w0.076: v2(97.45,116.88) 97.76,116.57 97.76,116.01 98.66,115.11 98.66,112.68 98.88,112.46 98.88,112.22 98.59,111.93 UC1.D60
  BOTTOM w0.127: RC134.1 79.78,120.23 80.03,120.48 v2(80.1,120.48) 80.1,120.54 80.3,120.75 UC8.6
CPU_XDP_TDO: length 23.7
  TOP w0.127: v2(82.09,120.45) 82.09,120.05 v3(82.23,119.91)
  IN1 w0.084: v2(82.09,120.45) 82.6,120.96 88.74,120.96 89.13,120.58 93.66,120.58 95.81,118.42 95.81,117.46 96.24,117.03 v2(96.87,117.03)
  BOTTOM w0.076: UC1.A61 98.11,113.4 98.11,114.37 97.05,115.43 97.05,116.84 v2(96.87,117.03)
  BOTTOM w0.127: RC135.1 82,120.37 v2(82.09,120.45) 82.09,120.52 81.8,120.8 UC8.3
CPU_XDP_TMS: length 30.5
  TOP w0.127: v2(97.43,115.69) 97.38,115.63 v3(96.88,115.63)
  IN1 w0.084: v2(97.43,115.69) 95.55,115.69 94.83,116.4 84.89,116.4 84.4,116.9 80.16,116.9 v2(79.51,117.55)
  BOTTOM w0.076: UC1.C60 98.5,112.43 98.5,115.04 97.85,115.69 v2(97.43,115.69)
  BOTTOM w0.127: UC8.8 79.44,122.8 78.53,121.9 RC131.1 78.07,121.9 77.93,121.77 77.93,120.65 78.87,119.71 78.87,118.25 79.51,117.61 v2(79.51,117.55)
CPU_XDP_TRST#: length 39.7
  TOP w0.127: v2(97.65,117.57) 97.65,117.68 98.16,118.18 98.16,119.74 99.83,121.41 CC308.1 ; v2(85.1,122.66) 85.1,122.85 v3(85.55,123.3)
  IN1 w0.084: v2(85.1,122.66) 86.63,122.66 87.16,122.13 88.16,122.13 89.53,120.76 93.73,120.76 96.05,118.45 96.05,118.2 v2(96.48,117.78) 96.69,117.57 v2(97.65,117.57)
  BOTTOM w0.076: v2(97.65,117.57) 97.65,117.21 98,116.86 98,116 98.83,115.18 98.83,112.99 UC1.B59 ; UC1.C61 98.03,112.08 97.63,112.47 97.63,113.08 97.61,113.14 97.6,113.17 97.6,113.54 97.77,113.71 97.77,114.2 96.67,115.3 96.67,116.34 96.19,116.83 96.19,117.49 v2(96.48,117.78)
  BOTTOM w0.127: UC8.11 81.3,124.27 81.86,124.83 82.13,124.83 RC136.1 82.93,125.63 83.71,125.63 85.1,124.24 v2(85.1,122.66)
CSI2_COMP: length 11.3
  TOP w0.127: v2(124.71,110.84) 124.86,110.84 v1(125.25,111.22)
  TOP w0.254: v2(125.48,117.13) 125.48,119.77 125.32,119.92 RC3.1
  IN2 w0.254: v2(124.71,110.84) 125.07,111.2 125.07,116.72 v2(125.48,117.13)
  BOTTOM w0.254: UC1.E13 v2(124.71,110.84)
CSIN_ISL9538: length 7.4
  TOP w0.127: v2(55.97,60.36) 55.97,61.1 v1(55.74,61.33)
  TOP w0.203: v2(55.97,60.36) 55.92,60.31 PU901.14
  BOTTOM w0.254: PC927.1 56.45,59.88 v2(55.97,60.36) 56.48,60.87 56.48,61.67 56.21,61.94 PC925.2 54.65,61.94 PR910.2
CSIP_ISL9538: length 6
  TOP w0.127: v2(55.38,60.37) 55.38,61.07 v1(54.56,61.9)
  TOP w0.203: PU901.15 55.52,59.68 55.38,59.82 v2(55.38,60.37)
  BOTTOM w0.254: PC926.1 55.38,59.8 v2(55.38,60.37) 55.38,60.42 55.71,60.75 PC925.1 54.77,61.02 PR909.2
CSON_ISL9538: length 5.9
  TOP w0.203: PU901.1 58.89,55.64 59.65,54.87 v2(59.84,54.87)
  BOTTOM w0.127: v1(60.73,53.67) 60.73,54 61.35,54.62 61.35,54.86 PR938.1
  BOTTOM w0.254: PR938.1 60.49,54.94 PC945.1 60.43,54.87 v2(59.84,54.87) 59.32,54.35 PC946.1
CSOP_ISL9538: length 5.7
  TOP w0.127: v1(60.34,54.68) 60.34,55.01 v2(59.84,55.51)
  TOP w0.203: v2(59.84,55.51) 59.52,55.51 59,56.04 PU901.2
  BOTTOM w0.254: PC942.1 59.79,55.51 v2(59.84,55.51) 60.03,55.51 60.36,55.84 PC945.2 61.38,55.84 PR937.1
CV2_ON: length 35.1
  TOP w0.127: v1(234,58.75) 234,59.17 v2(233.17,59.99) ; RE539.2 245.22,79.72 v2(245.08,79.58)
  IN4 w0.084: v2(245.08,79.58) 245.56,79.1 245.56,78.29 245.08,77.81 245.08,74.34 245.81,73.61 245.81,70.09 244,68.28 244,65.34 242.6,63.94 242.6,60.43 242.01,59.84 236.32,59.84 235.59,60.57 233.74,60.57 v2(233.17,59.99)
  BOTTOM w0.127: v2(233.17,59.99) 232.85,59.99 232.45,59.59 JUSH1.3
CV2_ON_R: length 31.5
  TOP w0.127: RE539.1 245.22,82.01 245.56,82.35 v2(245.56,82.43) ; RPE10.1 258.68,98.65 v2(258.47,98.44) ; UE1.H8 v2(252.68,89.86)
  IN2 w0.122: v2(252.68,89.86) 252.2,90.35 252.2,93.8 253.2,94.8 254.39,94.8 254.81,94.38 256.11,94.38 256.55,94.82 256.55,95.82 257.12,96.39 257.12,97.98 257.46,98.31 258.35,98.31 v2(258.47,98.44)
  IN4 w0.084: v2(252.68,89.86) 252.28,90.26 247.29,90.26 246.37,89.33 246.37,84.75 246.68,84.44 246.68,83.34 245.76,82.43 v2(245.56,82.43)
DAT_TP_SIO_I2C_CLK: length 78
  TOP w0.127: v2(247.12,94.9) 247.65,94.37 247.65,93.89 247.86,93.67 247.86,93.08 UE1.C12 ; v2(211.73,55.5) 211.52,55.28 CZ80.1 RZ22.2 ; v2(229.15,60.05) 228.93,60.27 228.93,60.59 228.64,60.88 219.05,60.88 218.72,60.56 217.91,59.75 217.91,57.48 217.74,57.3 v2(217.42,57.3) 217.12,57.61 RZ347.1
  IN4 w0.084: v2(247.12,94.9) 246.96,95.06 245.85,95.06 244.25,93.47 244.25,91.54 241.47,88.75 241.47,85.96 241.79,85.64 243.18,85.64 243.39,85.43 243.39,81.41 243.81,80.99 243.81,73.84 244.2,73.45 244.2,70.96 241.26,68.02 241.26,65.91 240.49,65.14 240.49,64.62 240.21,64.33 237.65,64.33 235.87,62.55 233.53,62.55 233.06,62.08 231.17,62.08 229.52,60.43 229.08,60.43 228.97,60.33 228.97,60.23 v2(229.15,60.05)
  BOTTOM w0.127: v2(211.73,55.5) 212.83,56.59 214.27,56.59 214.86,57.18 217.3,57.18 v2(217.42,57.3)
DAT_TP_SIO_R: length 4.7
  TOP w0.127: v1(209.74,60.64) v2(210.55,59.83) 210.55,58.63 RZ18.2 210.41,57.16 RZ22.1
  BOTTOM w0.127: JKBTP1.8 v2(210.55,59.83)
DCIN1_EN: length 288
  TOP w0.127: UE1.K4 v2(254.28,85.86) ; v2(266.72,87.54) v1(266.17,87.54)
  IN2 w0.122: v2(266.72,87.54) 266.49,87.3 266.49,84.47 267.53,83.42 267.53,80.06 270.82,76.77 270.82,69.62 268.96,67.76 263.62,67.76 259.69,63.84 257.54,63.84 256.52,64.86 255.03,64.86 254.69,65.2 253.53,65.2 252.94,64.61 251.06,64.61 250.28,63.83 249.75,63.83 246.25,60.33 246.25,57.85 244.46,56.06 241.02,56.06 239.32,54.36 239.32,52.91 237.18,50.77 225.62,50.77 224.83,51.56 223.94,51.56 223.23,50.84 214.3,50.84 213.48,51.66 210.44,51.66 208.69,49.9 187.38,49.9 186.46,50.82 183.28,50.82 182.7,51.4 182.27,51.4 181.15,52.52 178.64,52.52 178.13,52.01 176.35,52.01 174.6,53.76 161.05,53.76 159.01,55.8 147.94,55.8 146.5,54.35 142.12,54.35 141.17,53.64 140.64,53.25 114.97,53.25 113.27,51.54 74.99,51.54 71.48,55.04 70.44,55.04 69.45,56.03 61.93,56.03 60.33,54.43 59.46,54.43 58.56,55.33 53.29,55.33 51.22,57.4 47.17,57.4 46.65,57.92 46.65,58.68 44.75,60.58 v2(43.78,60.58)
  IN4 w0.084: v2(254.28,85.86) 254.28,85.83 254.65,85.46 255.93,85.46 256.85,84.54 259.92,84.54 260.26,84.88 260.26,85.66 261.27,86.67 264.86,86.67 265.26,87.08 266.26,87.08 v2(266.72,87.54)
  BOTTOM w0.254: PR1221.1 41.88,60.91 42.76,60.91 43.09,60.58 v2(43.78,60.58)
DCIN2_EN: length 372.3
  TOP w0.127: v2(257.54,94.9) 257.25,94.9 255.93,93.58 255.93,93.27 255.75,93.1 255.12,93.1 UE1.L12 ; v2(40.76,61.35) v1(40.76,61.92) 40.76,62.17 37.97,64.96 37.97,68.38 v2(37.1,69.25)
  TOP w0.254: PR26.1 v2(60.15,118.12)
  IN2 w0.122: v2(37.1,69.25) 37.38,69.52 37.38,75.8 38.94,77.36 38.94,78.08 40.11,79.25 40.11,79.89 40.49,80.28 40.49,81.33 41.68,82.52 41.68,89.45 44.45,92.22 44.45,94.93 47.54,98.02 47.54,98.54 46.9,99.19 45.85,99.19 45.68,99.01 44.9,99.01 44.24,99.68 44.24,101.31 42.86,102.69 42.86,106.26 44.75,108.14 44.75,110.77 46.5,112.52 46.5,115.27 50.45,119.22 54.47,119.22 54.95,118.74 54.95,118.25 55.29,117.91 56.24,117.91 57.43,116.71 58.99,116.71 60.15,117.87 v2(60.15,118.12) ; v2(40.76,61.35) 41.12,61.71 43.93,61.71 46.99,58.66 46.99,57.9 47.27,57.62 51.97,57.62 53.09,56.51 58.56,56.51 59.15,55.91 60.46,55.91 60.8,56.25 69.55,56.25 70.53,55.27 72.53,55.27 76.04,51.77 102.55,51.77 104.3,53.52 140.55,53.52 142.02,54.62 146.44,54.62 147.85,56.03 159.12,56.03 161.15,53.99 174.69,53.99 176.44,52.23 178.04,52.23 178.55,52.74 181.25,52.74 182.36,51.63 182.79,51.63 183.37,51.05 186.55,51.05 187.47,50.13 208.56,50.13 210.32,51.88 213.58,51.88 213.92,51.54 223.08,51.54 224.2,52.66 225.24,52.66 225.93,51.96 229.45,51.96 229.67,51.74 237.83,51.74 239.1,53.01 239.1,54.45 240.95,56.3 244.25,56.3 246.02,58.07 246.02,60.42 249.66,64.06 250.19,64.06 250.97,64.84 252.85,64.84 253.44,65.43 254.78,65.43 255.13,65.08 256.61,65.08 257.64,64.06 259.6,64.06 263.53,67.99 268.87,67.99 270.6,69.72 270.6,76.67 267.3,79.97 267.3,83.34 266.24,84.4 266.24,89.24 265.7,89.78 v2(265.7,92.18)
  IN4 w0.084: v2(265.7,92.18) 261.2,92.18 258.48,94.9 v2(257.54,94.9)
DCIN3_EN: length 8.6
  TOP w0.127: v2(253.77,81.43) 253.58,81.24 253.58,80.43 253.87,80.14 T262.1 ; UE1.J6 v2(253.48,87.46)
  BOTTOM w0.127: v2(253.48,87.46) 253.48,87.43 253.88,87.03 253.88,81.54 v2(253.77,81.43)
DCIN_ISL9538: length 2.1
  BOTTOM w0.508: PR916.1 53.61,59.7 PC931.2 54.44,59.13 v2(54.33,59.02)
DDR_A_ACT#: length 44.4
  IN4 w0.076: v2(98.59,84.15) 98.41,84.15 97.71,83.44 97.71,81.21 95.94,79.45 95.94,77.35
  IN4 w0.132: v2(101.91,57.26) 101.68,57.49 100.7,57.49 100.24,57.95 100.24,60.05 99.31,60.98 99.31,64.4 96.63,67.08 96.63,67.73 95.94,68.42 95.94,77.35
  BOTTOM w0.076: v2(98.59,84.15) 99.25,84.81 v1(99.25,86.88) 99.25,87.35 100.8,88.9 100.8,89.86 100.79,89.88 100.79,90.27 100.93,90.41 100.93,90.82 100.88,90.96 100.88,91.07 100.93,91.2 100.93,91.43 UC1.BA55
  BOTTOM w0.196: JDIMM1.114 104.47,54.7 v2(101.91,57.26)
DDR_A_ALERT#: length 53.1
  IN4 w0.076: 98.65,81.16 98.96,81.48 98.96,82.58 100.4,84.01 100.4,94.14 100.67,94.41 103.92,94.41 104.21,94.12 104.21,92.78 v2(104.56,92.42)
  IN4 w0.132: v2(104.79,55.35) 104.31,54.87 102.9,54.87 102.72,55.06 102.72,60.86 101.58,62 101.58,64.39 98.04,67.92 98.04,68.31 97.33,69.02 97.33,79.85 98.65,81.16
  BOTTOM w0.076: v2(104.56,92.42) 104.35,92.64 UC1.AW50
  BOTTOM w0.196: JDIMM1.116 104.97,54.86 104.79,55.04 v2(104.79,55.35)
DDR_A_BA0: length 45.6
  IN4 w0.076: 107.11,78.5 107.11,78.68 106.15,79.64 106.15,87.73 104.11,89.76 104.11,91.58 102.78,92.91 v2(102.78,93.46)
  IN4 w0.132: v2(113.97,56.75) 113.96,56.75 113.06,57.65 113.06,64.98 107.11,70.93 107.11,78.5
  BOTTOM w0.076: UC1.AU52 102.78,93.47 v2(102.78,93.46)
  BOTTOM w0.196: JDIMM1.150 115.48,55.25 v2(113.97,56.75)
DDR_A_BA1: length 45.8
  IN4 w0.076: v2(104.61,94.1) 104.91,94.1 104.98,94.04 104.98,93.1 107.16,90.92 107.16,80.53 108.95,78.74 108.95,78.38
  IN4 w0.132: v2(115.6,58.66) 115.6,58.97 114.95,59.62 114.95,65.74 108.95,71.74 108.95,78.38
  BOTTOM w0.076: v2(104.61,94.1) UC1.AT48
  BOTTOM w0.196: v2(115.6,58.66) 115.16,58.22 114.6,58.22 114.42,58.4 114.42,59.64 114.22,59.84 114.22,61.9 JDIMM1.145
DDR_A_BG0: length 46.7
  IN4 w0.076: v2(98.6,83.57) 98.6,83.7 98.52,83.78 98.28,83.78 97.87,83.38 97.87,81.14 96.41,79.67 96.41,77.35
  IN4 w0.132: 96.41,77.35 96.41,68.62 97.1,67.93 97.1,67.27 99.77,64.59 99.77,61.17 100.92,60.03 100.92,59.4 100.7,59.18 100.7,58.22 100.95,57.98 101.36,57.98 101.91,58.53 v2(101.91,58.53)
  BOTTOM w0.076: v2(98.6,83.57) 98.6,83.44 98.84,83.2 99.16,83.2 99.24,83.28 99.24,84.14 99.58,84.48 99.58,87.43 101.53,89.39 101.53,90.19 101.39,90.33 101.39,90.83 101.4,90.86 101.44,90.94 101.44,91.06 101.37,91.28 101.37,91.42 101.43,91.58 101.43,91.76 101.4,91.83 101.27,91.96 101.08,91.96 100.99,92.05 100.99,92.24 UC1.AY55
  BOTTOM w0.196: JDIMM1.115 104.72,61 104.18,60.45 104.18,59.88 103.44,59.14 102.52,59.14 v2(101.91,58.53)
DDR_A_BG1: length 45.2
  IN4 w0.076: v2(98.6,82.27) 98.58,82.28 98.17,82.28 98.07,82.19 98.07,81.02 96.87,79.81 96.87,77.35
  IN4 w0.132: 96.87,77.35 96.87,68.81 97.56,68.12 97.56,67.55 100.24,64.87 100.24,64.27 100.42,64.09 100.93,64.09 101.12,63.9 101.12,63.54 100.93,63.36 100.42,63.36 100.24,63.17 100.24,62.81 100.42,62.62 100.93,62.62 101.12,62.44 101.12,62.08 100.93,61.89 100.42,61.89 100.24,61.71 100.24,61.43 100.67,61 100.93,61 101.32,61.39 101.58,61.39 101.82,61.15 101.82,60.89 101.41,60.49 101.41,60.3 v2(101.91,59.8)
  BOTTOM w0.076: UC1.AY54 101.62,91.89 101.62,91.63 101.55,91.41 101.55,91.28 101.61,91.05 101.61,90.91 101.56,90.79 101.56,90.45 101.7,90.31 101.7,89.31 99.79,87.4 99.79,84.21 99.4,83.82 99.4,82.62 99.04,82.27 v2(98.6,82.27)
  BOTTOM w0.196: JDIMM1.113 104.22,61.16 103.55,60.49 103.55,59.95 103.23,59.62 102.8,59.62 102.54,59.89 102,59.89 v2(101.91,59.8)
DDR_A_CKE0: length 46
  IN4 w0.076: 95.48,77.35 95.48,79.47 97.27,81.26 97.27,84.86 98.39,85.98 v2(98.6,85.98)
  IN4 w0.132: v2(99.79,59.23) 99.63,59.23 99.35,58.95 99.35,57.75 99.16,57.57 98.48,57.57 98.3,57.75 98.3,59.94 98.85,60.49 98.85,64.23 96.17,66.9 96.17,67.54 95.48,68.23 95.48,77.35
  BOTTOM w0.076: v2(98.6,85.98) 98.28,85.98 98.21,86.05 98.21,87.04 100.31,89.13 100.31,89.69 100.29,89.7 100.29,90.42 100.23,90.49 100.23,90.79 100.23,90.79 100.35,91.04 100.35,91.04 100.36,91.05 100.5,91.19 UC1.BA56
  BOTTOM w0.196: JDIMM1.109 103.22,61.01 102.88,60.67 101.23,60.67 99.79,59.23 v2(99.79,59.23)
DDR_A_CKE1: length 45
  IN4 w0.076: 95.02,77.35 95.02,79.33 97.11,81.42 97.11,85.14 v2(98.59,86.62)
  IN4 w0.132: v2(101.91,55.99) 99.11,55.99 97.78,57.33 97.78,60.96 98.39,61.57 98.39,64.07 95.71,66.75 95.71,67.35 95.02,68.04 95.02,77.35
  BOTTOM w0.076: UC1.BB56 100.46,90.65 100.46,89.76 100.47,89.75 100.47,89.05 98.59,87.17 v2(98.59,86.62)
  BOTTOM w0.196: v2(101.91,55.99) 102.08,55.99 103.47,54.6 JDIMM1.110
DDR_A_CKE2: length 9.7
  TOP w0.107: v2(98.58,84.75) 98,84.75 T3.1
  BOTTOM w0.076: v2(98.58,84.75) 98.97,85.14 98.97,87.31 100.64,88.98 100.64,89.8 100.62,89.82 100.62,90.35 100.76,90.49 100.76,90.79 100.71,90.9 100.71,91.12 100.76,91.23 100.76,91.44 100.73,91.52 100.73,91.8 100.74,91.8 100.76,91.86 100.76,92.17 100.71,92.22 100.71,92.42 UC1.AW56
DDR_A_CKE3: length 7.3
  BOTTOM w0.076: T4.1 97.89,85.84 97.89,86.95 100.13,89.19 100.13,89.62 100.07,89.68 100.07,90.82 100.09,90.87 100.09,90.87 100.23,91.23 100.23,91.52 100.5,91.78 UC1.AY56
DDR_A_CLK0: length 47.4
  IN4 w0.076: 102.82,89.86 102.81,89.88 102.81,89.89 102.35,90.35 102.35,90.6 102.65,90.9 102.65,91.01 102.43,91.22 102.32,91.22 102.02,90.92 101.78,90.92 101.51,91.19 101.51,93.69 v2(101.86,94.04)
  IN4 w0.094: 102.82,89.86 105.12,87.57 105.12,78.99 105.71,78.4 105.71,70.47 111.47,64.71 111.47,64.25 111.33,64.1 111.33,63.39 111.5,63.22 111.5,62.54 111.33,62.36 111.33,61.74 111.48,61.59 111.48,60.13 111.31,59.95 111.31,59.32 111.53,59.11 112.05,59.11 v2(112.31,58.85)
  BOTTOM w0.076: UC1.AT53 102.04,94.45 101.86,94.28 v2(101.86,94.04)
  BOTTOM w0.104: JDIMM1.137 110.22,61.06 110.39,60.89 110.39,60.62 110.19,60.42 110.19,59.31 110.65,58.85 v2(112.31,58.85)
DDR_A_CLK1: length 47.5
  IN4 w0.076: v2(100.95,94.04) 100.95,94.04 101.31,93.69 101.31,92.83 101.11,92.63 101.11,90.98 102.32,89.77 102.33,89.77 102.34,89.76
  IN4 w0.094: 102.34,89.76 104.69,87.41 104.69,78.65 105.12,78.23 105.12,69.98 110.8,64.31 110.8,58.27 111.55,57.52 112.26,57.52 v2(112.31,57.58)
  BOTTOM w0.076: UC1.AT55 100.95,94.1 v2(100.95,94.04)
  BOTTOM w0.104: JDIMM1.138 110.48,54.48 110.65,54.65 110.65,55.78 111.03,56.16 111.03,56.96 111.54,57.47 112.21,57.47 v2(112.31,57.58)
DDR_A_CLK#0: length 47.4
  IN4 w0.076: 102.95,89.99 102.94,90.01 102.93,90.01 102.51,90.42 102.51,90.53 102.81,90.83 102.81,91.07 102.5,91.39 102.26,91.39 101.96,91.09 101.85,91.09 101.67,91.26 101.67,92.86 101.81,93 102.14,93 102.21,93.07 102.21,93.38 102.14,93.46 v2(101.86,93.46)
  IN4 w0.094: v2(112.31,59.53) 112.07,59.29 111.6,59.29 111.49,59.4 111.49,59.88 111.67,60.05 111.67,61.66 111.51,61.82 111.51,62.29 111.69,62.46 111.69,63.29 111.51,63.47 111.51,64.03 111.65,64.17 111.65,64.78 105.89,70.55 105.89,78.48 105.31,79.06 105.31,87.64 102.95,89.99
  BOTTOM w0.076: v2(101.86,93.46) 101.86,93.43 102.02,93.28 102.26,93.28 102.42,93.44 102.42,93.7 UC1.AU53
  BOTTOM w0.104: JDIMM1.139 110.72,61.03 110.58,60.89 110.58,60.54 110.38,60.34 110.38,59.39 110.73,59.04 111.93,59.04 112.31,59.42 v2(112.31,59.53)
DDR_A_CLK#1: length 47.5
  IN4 w0.076: 102.21,89.63 102.2,89.64 102.2,89.65 100.95,90.91 100.95,92.7 101.14,92.9 101.14,93.04 101.08,93.1 100.87,93.1 100.79,93.18 100.79,93.41 100.85,93.47 100.94,93.47 v2(100.95,93.46)
  IN4 w0.094: v2(112.31,56.94) 112.31,57.04 112.01,57.34 111.47,57.34 110.62,58.19 110.62,64.23 104.94,69.91 104.94,78.15 104.51,78.58 104.51,87.33 102.21,89.63
  BOTTOM w0.076: UC1.AU55 101.23,93.8 100.95,93.6 v2(100.95,93.46)
  BOTTOM w0.104: v2(112.31,56.94) 112.31,57 112.03,57.28 111.62,57.28 111.23,56.88 111.23,56.08 110.84,55.7 110.84,54.65 110.97,54.52 JDIMM1.140
DDR_A_CS#0: length 50.3
  IN4 w0.076: 110.34,78.37 110.34,78.79 107.83,81.3 107.83,91.13 105.88,93.09 105.88,93.98 105.99,94.09 106.36,94.09 106.44,94.02 v2(106.44,93.47)
  IN4 w0.132: 110.34,78.37 110.34,72.31 116.82,65.83 116.82,65.55 116.64,65.37 116.52,65.37 116.34,65.18 116.34,64.82 116.52,64.64 116.64,64.64 116.82,64.45 116.82,62.95 116.64,62.77 116.52,62.77 116.34,62.58 116.34,62.22 116.52,62.03 116.64,62.03 116.82,61.85 116.82,61.41 117.35,60.89 117.35,59.15 117.67,58.83 117.67,57.98 117.48,57.79 117.15,57.79 v2(116.94,58)
  BOTTOM w0.076: v2(106.44,93.47) 106.32,93.47 106.26,93.53 106.26,93.89 106.44,94.07 106.71,94.07 106.89,93.89 UC1.AU45
  BOTTOM w0.196: v2(116.94,58) 116.9,58 115.02,59.88 115.02,60.82 115.22,61.02 115.22,61.9 JDIMM1.149
DDR_A_CS#1: length 52
  IN4 w0.076: v2(107.35,93.46) 107.35,93.46 109.17,91.64 109.17,80.78 111.27,78.68 111.27,78.34
  IN4 w0.132: 111.27,78.34 111.27,72.7 117.75,66.22 117.75,64.48 119.29,62.94 119.29,60.42 118.59,59.72 118.59,57.63 119.12,57.09 119.12,55.94 118.92,55.74 117.92,55.74 117.71,55.95 117.71,57.37 v2(118.11,57.77)
  BOTTOM w0.102: UC1.AU43 v2(107.35,93.46)
  BOTTOM w0.196: v2(118.11,57.77) 118.62,58.27 118.62,59.58 117.22,60.97 117.22,61.9 JDIMM1.157
DDR_A_D0: length 62.9
  IN4 w0.084: v2(77.23,57.47) 76.82,57.88 76.82,59.28 76.49,59.61 76.37,59.61 75.81,59.06 75.69,59.06 75.48,59.27 75.48,59.39 76.04,59.94 76.04,60.06 75.63,60.47 75.63,66.34 76.42,67.13 76.42,67.59 76.34,67.67 75.72,67.67 75.63,67.76 75.63,68.05 75.72,68.14 76.74,68.14 76.83,68.22 76.83,83.8 77.29,84.26 77.29,93.75 81.02,97.48 88.13,97.48 88.42,97.2 v2(88.42,96.58)
  BOTTOM w0.076: 89.14,97.14 90.14,97.14 90.49,97.49 91.76,97.49 UC1.AL71
  BOTTOM w0.127: v2(77.23,57.47) 77.93,58.17 77.93,60.97 77.73,61.17 JDIMM1.7 ; v2(88.42,96.58) 88.98,97.14 89.14,97.14
DDR_A_D1: length 64.2
  IN4 w0.084: v2(83.82,95.57) 82.38,95.57 81.75,94.94 79.94,94.94 78.29,93.28 78.29,76.33 77.83,75.87 77.83,64.57 76.63,63.37 76.63,62.9 76.74,62.78 77.25,62.78 77.34,62.7 77.34,60.17 77.93,59.58 77.93,56.25 78.01,56.17 79.18,56.17 79.26,56.08 79.26,55.8 79.17,55.7 78.01,55.7 77.93,55.62 77.93,53.98 77.79,53.84 77.37,53.84 77.23,53.98 v2(77.23,54.93)
  BOTTOM w0.076: 84.24,95.57 84.5,95.57 84.75,95.32 86.93,95.32 87.33,95.71 88.71,95.71 89.43,96.43 91.23,96.43 91.41,96.61 91.93,96.61 91.96,96.6 92.04,96.57 92.16,96.57 92.37,96.63 92.52,96.63 92.68,96.58 92.86,96.58 93.04,96.67 93.53,96.67 93.69,96.83 93.69,97.46 UC1.AL68
  BOTTOM w0.127: 84.24,95.57 v2(83.82,95.57) ; v2(77.23,54.93) 76.97,54.67 JDIMM1.4
DDR_A_D2: length 64.8
  IN4 w0.084: v2(88.11,94.77) 87.97,94.92 87.28,94.92 87.19,95 87.19,96.04 87.11,96.12 86.82,96.12 86.73,96.03 86.73,95 86.64,94.92 86.31,94.92 85.23,93.83 85.23,93.36 85.14,93.28 84.05,93.28 83.96,93.19 83.96,92.91 84.06,92.81 84.74,92.81 84.83,92.73 84.83,89.95 83.95,89.08 83.84,89.08 83.45,89.46 83.34,89.46 83.13,89.26 83.13,89.13 83.51,88.75 83.51,88.63 83.07,88.19 82.95,88.19 81.84,89.3 81.73,89.3 81.51,89.09 81.51,88.97 82.62,87.86 82.62,87.75 82.41,87.54 82.29,87.54 81.19,88.63 81.08,88.63 80.87,88.43 80.87,88.3 81.96,87.21 81.96,87.09 79.86,84.99 79.86,74.87 79.39,74.4 79.39,63.29 78.91,62.81 78.91,60.94 80.06,59.79 v2(80.06,58.74)
  BOTTOM w0.076: UC1.AN68 93.74,96.36 93.64,96.46 93.49,96.46 93.39,96.36 93.39,96.14 93.19,95.93 93.09,95.93 93.01,95.96 92.91,95.99 92.8,96.01 92.63,95.96 92.43,95.75 91.49,95.75 91.49,95.75 89.83,95.75 88.98,94.91 88.24,94.91 v2(88.11,94.77)
  BOTTOM w0.127: JDIMM1.17 80.22,61.02 80.13,60.93 80,60.93 79.88,60.82 79.88,60.64 80,60.53 80.43,60.53 80.54,60.42 80.54,60.24 80.43,60.13 80.17,60.13 80.06,60.01 80.06,59.8 80.17,59.69 80.43,59.69 80.54,59.58 80.54,59.35 80.43,59.24 80.17,59.24 80.06,59.13 v2(80.06,58.74)
DDR_A_D3: length 63.8
  IN4 w0.084: v2(86.35,93.05) 86.35,92.44 85.89,91.98 85.89,89.61 81.21,84.93 81.21,74.17 81.09,74.05 80.87,74.05 80.76,73.93 80.76,73.7 80.87,73.58 81.09,73.58 81.21,73.46 81.21,73.23 81.09,73.11 80.87,73.11 80.76,73 80.76,72.76 80.87,72.65 81.09,72.65 81.21,72.53 81.21,72.3 81.09,72.18 80.87,72.18 80.76,72.06 80.76,71.83 80.87,71.71 81.09,71.71 81.21,71.59 81.21,71.36 81.09,71.24 80.87,71.24 80.76,71.13 80.76,70.89 80.87,70.78 81.09,70.78 81.21,70.66 81.21,70.43 81.09,70.31 80.87,70.31 80.76,70.19 80.76,69.96 80.87,69.84 81.09,69.84 81.21,69.73 81.21,69.49 81.09,69.37 80.87,69.37 80.76,69.26 80.76,69.02 80.87,68.91 81.09,68.91 81.21,68.79 81.21,68.56 81.09,68.44 80.87,68.44 80.76,68.32 80.76,68.09 80.87,67.97 81.09,67.97 81.21,67.86 81.21,67.62 81.09,67.51 80.87,67.51 80.76,67.39 80.76,67.15 80.87,67.04 81.09,67.04 81.21,66.92 81.21,66.7 80.76,66.25 80.76,64.1 81.43,63.43 81.43,55.47 82.94,53.96 82.94,53.58 82.69,53.34 79.74,53.34 79.37,53.71 79.37,54.77 79.53,54.93 v2(80.06,54.93)
  BOTTOM w0.076: UC1.AN69 92.98,96.38 92.73,96.38 92.51,96.46 92.38,96.46 92.15,96.39 92.05,96.39 92.04,96.39 92.03,96.39 92.01,96.39 91.89,96.45 91.49,96.45 91.29,96.24 89.5,96.24 88.79,95.53 87.44,95.53
  BOTTOM w0.102: 87.44,95.53 86.26,94.35 86.26,93.14 v2(86.35,93.05)
  BOTTOM w0.127: v2(80.06,54.93) 79.97,54.84 JDIMM1.16
DDR_A_D4: length 64.2
  IN4 w0.084: v2(77.23,58.74) 77.23,59.34 75.96,60.61 75.96,66.01 76.27,66.32 76.95,66.32 77.16,66.53 77.16,77.44 77.28,77.56 77.5,77.56 77.62,77.67 77.62,77.91 77.5,78.02 77.28,78.02 77.16,78.14 77.16,78.37 77.28,78.49 77.5,78.49 77.62,78.61 77.62,78.84 77.5,78.96 77.28,78.96 77.16,79.07 77.16,79.31 77.28,79.43 77.5,79.43 77.62,79.54 77.62,79.78 77.5,79.89 77.28,79.89 77.16,80.01 77.16,80.24 77.28,80.36 77.5,80.36 77.62,80.48 77.62,80.71 77.5,80.83 77.28,80.83 77.16,80.94 77.16,81.18 77.28,81.29 77.5,81.29 77.62,81.41 77.62,81.64 77.5,81.76 77.28,81.76 77.16,81.88 77.16,82.11 77.28,82.23 77.5,82.23 77.62,82.35 77.62,82.56 77.5,82.68 77.28,82.68 77.16,82.8 77.16,83.03 77.28,83.15 77.5,83.15 77.62,83.27 77.62,93.57 80.52,96.47 80.64,96.47 81.06,96.05 81.18,96.05 81.39,96.26 81.39,96.38 80.97,96.8 80.97,96.92 81.15,97.1 87.06,97.1 87.15,97.02 v2(87.15,96.58)
  BOTTOM w0.076: 88.47,97.01 88.81,97.36 90.1,97.36 90.4,97.65 91.51,97.65 91.63,97.78 91.87,97.78 91.99,97.74 92.11,97.68 92.29,97.51 UC1.AL70
  BOTTOM w0.127: 88.47,97.01 87.58,97.01 v2(87.15,96.58) ; JDIMM1.3 76.73,60.92 76.83,60.82 77.2,60.82 77.3,60.72 77.3,60.36 77.2,60.26 76.59,60.26 76.48,60.15 76.48,59.77 76.59,59.65 77.2,59.65 77.3,59.55 77.3,58.81 v2(77.23,58.74)
DDR_A_D5: length 64.5
  IN4 w0.084: v2(77.23,56.2) 77.4,56.03 77.52,56.03 77.61,56.11 77.61,59.43 76.29,60.75 76.29,60.94 76.38,61.03 76.79,61.03 76.88,61.11 76.88,61.41 76.79,61.49 76.38,61.49 76.29,61.57 76.29,61.87 76.38,61.96 76.79,61.96 76.88,62.04 76.88,62.34 76.79,62.42 76.38,62.42 76.29,62.5 76.29,63.51 76.92,64.13 76.92,64.51 76.82,64.6 76.41,64.6 76.29,64.72 76.29,64.95 76.41,65.07 77.37,65.07 77.49,65.19 77.49,65.41 77.37,65.52 76.41,65.52 76.29,65.64 76.29,65.87 76.41,65.99 77.38,65.99 77.49,66.11 77.49,76.49 77.95,76.95 77.95,93.42 79.84,95.31 81.33,95.31 82.8,96.78 86.31,96.78 v2(86.51,96.58)
  BOTTOM w0.076: UC1.AL69 92.88,97.51 92.62,97.78 92.45,97.78 92.26,97.85 92.26,97.85 92.13,97.89 92.05,97.9 91.98,97.91 91.92,97.93 91.85,97.95 91.55,97.95 91.41,97.82 90.33,97.82 90.03,97.53 88.67,97.53 88.39,97.24
  BOTTOM w0.127: JDIMM1.8 77.97,55.46 v2(77.23,56.2) ; 88.39,97.24 87.17,97.24 v2(86.51,96.58)
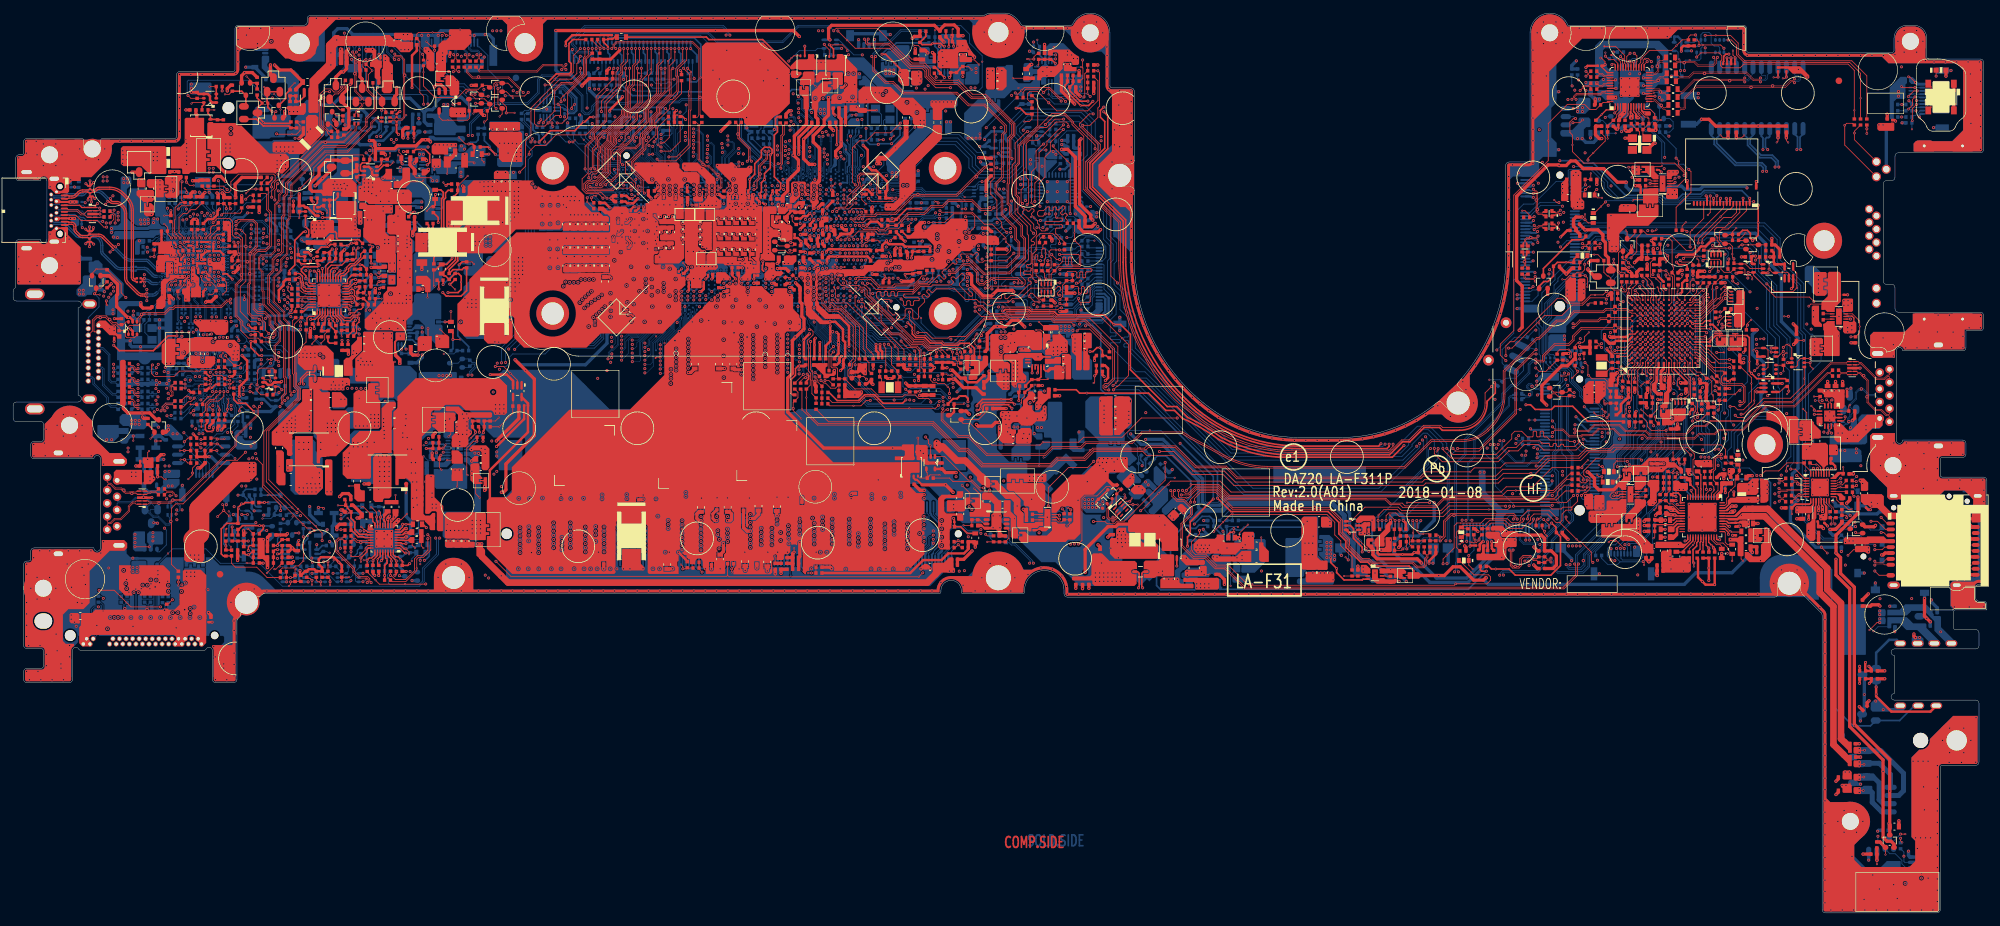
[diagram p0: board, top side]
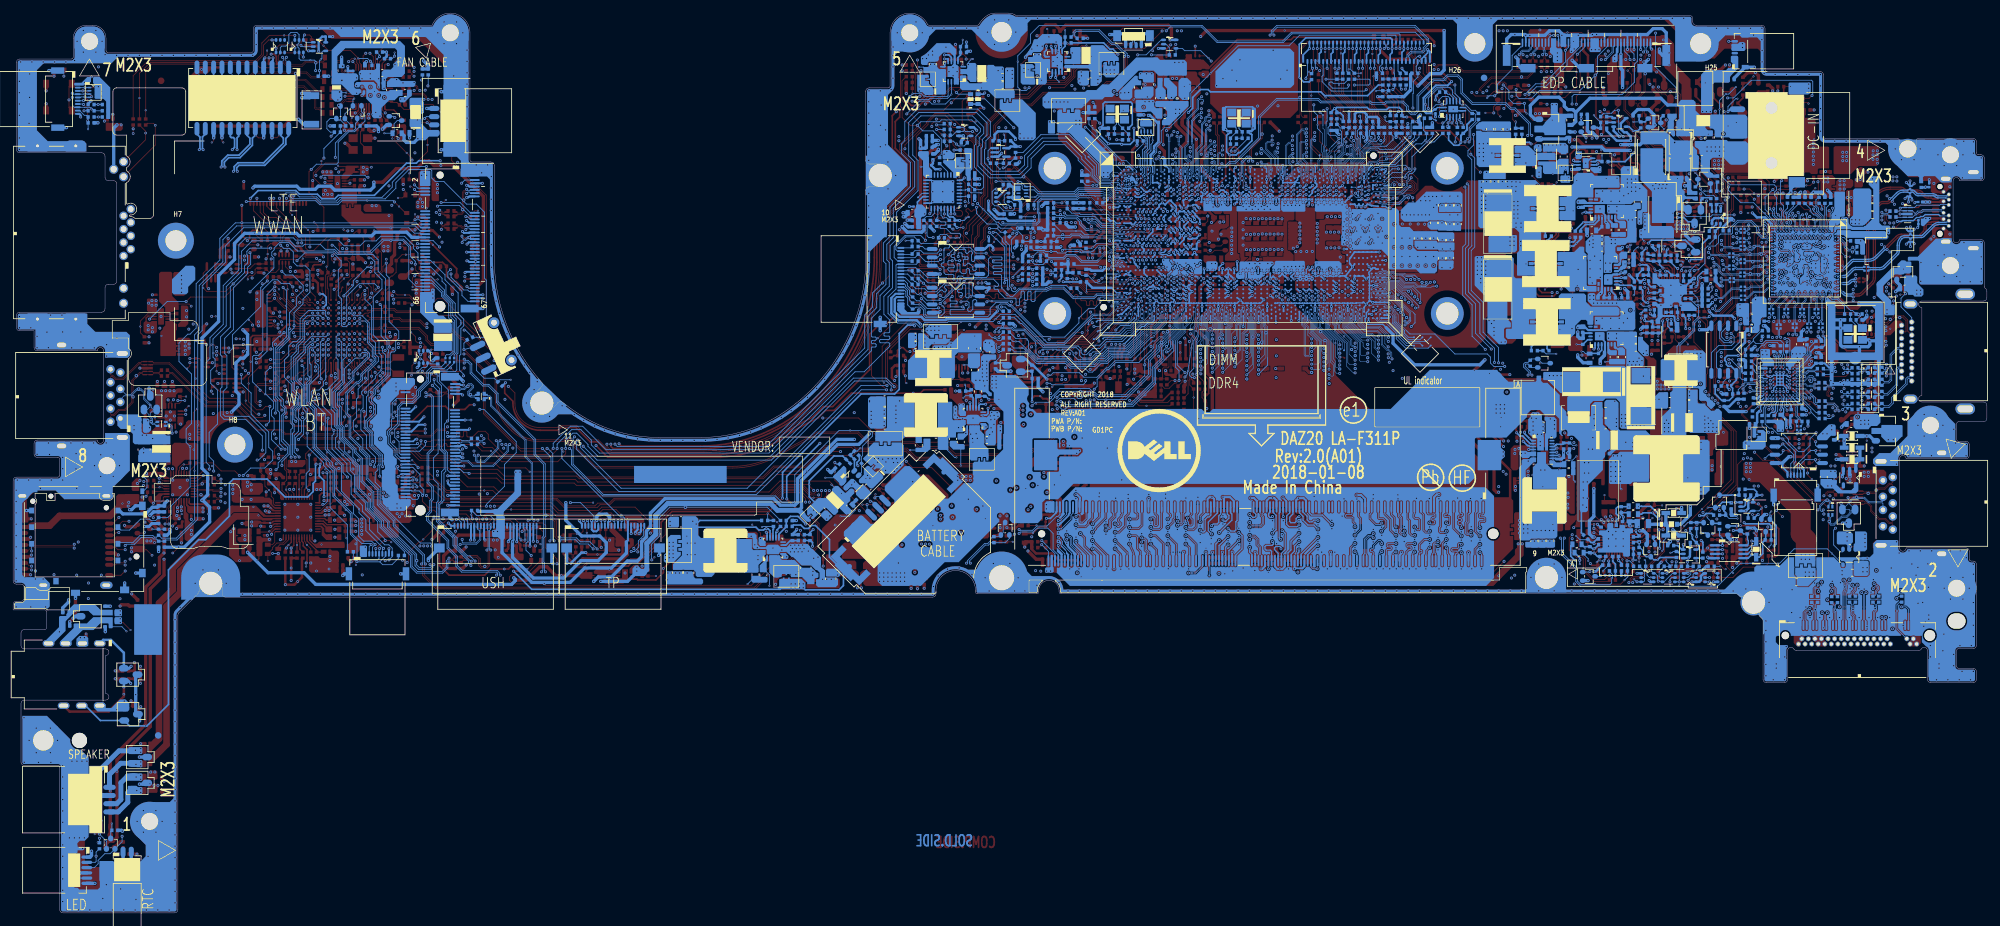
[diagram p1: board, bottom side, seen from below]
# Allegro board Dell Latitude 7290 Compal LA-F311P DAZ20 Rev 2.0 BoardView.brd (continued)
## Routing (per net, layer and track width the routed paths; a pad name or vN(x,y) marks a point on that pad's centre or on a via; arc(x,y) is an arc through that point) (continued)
DDR_A_D6: length 63.2
  IN4 w0.084: v2(80.06,57.47) 80.48,57.05 80.68,57.05 80.77,57.13 80.77,57.66 80.68,57.74 80.54,57.74 80.46,57.83 80.46,58.12 80.54,58.21 80.68,58.21 80.77,58.29 80.77,58.59 80.68,58.67 80.54,58.67 80.46,58.76 80.46,59.05 80.54,59.14 80.68,59.14 80.77,59.22 80.77,59.6 80.09,60.28 80.09,61.03 80.01,61.11 79.32,61.11 79.23,61.2 79.23,61.49 79.32,61.58 80.01,61.58 80.09,61.66 80.09,61.96 80.01,62.04 79.32,62.04 79.23,62.13 79.23,62.42 79.32,62.51 80.01,62.51 80.09,62.59 80.09,63.36 80.01,63.45 79.82,63.45 79.74,63.53 79.74,63.83 79.82,63.91 80.01,63.91 80.09,63.99 80.09,64.29 80.01,64.38 79.82,64.38 79.74,64.46 79.74,64.76 79.82,64.84 80.01,64.84 80.09,64.92 80.09,65.22 80.01,65.3 79.82,65.3 79.74,65.39 79.74,65.69 79.82,65.77 80.01,65.77 80.09,65.85 80.09,66.15 80.01,66.23 79.82,66.23 79.74,66.32 79.74,66.62 79.82,66.7 80.01,66.7 80.09,66.78 80.09,67.08 80.01,67.16 79.82,67.16 79.74,67.25 79.74,67.54 79.82,67.63 80.01,67.63 80.09,67.71 80.09,68.01 80.01,68.09 79.82,68.09 79.74,68.18 79.74,68.47 79.82,68.56 80.01,68.56 80.09,68.64 80.09,68.94 80.01,69.02 79.82,69.02 79.74,69.11 79.74,69.4 79.82,69.49 80.01,69.49 80.09,69.57 80.09,69.87 80.01,69.95 79.82,69.95 79.74,70.04 79.74,70.33 79.82,70.42 80.01,70.42 80.09,70.5 80.09,70.8 80.01,70.88 79.82,70.88 79.74,70.97 79.74,71.26 79.82,71.35 80.01,71.35 80.09,71.43 80.09,71.73 80.01,71.81 79.82,71.81 79.74,71.9 79.74,72.19 79.82,72.28 80.01,72.28 80.09,72.36 80.09,72.66 80.01,72.74 79.82,72.74 79.74,72.83 79.74,73.12 79.82,73.21 80.01,73.21 80.09,73.29 80.09,73.59 80.01,73.67 79.82,73.67 79.74,73.76 79.74,74.05 79.82,74.14 80.01,74.14 80.09,74.22 80.09,74.49 80.41,74.81 80.41,85.06 85.16,89.81 85.16,92.22 85.56,92.62 85.56,93.41 86.75,94.6 87.4,94.6 v2(87.63,94.37)
  BOTTOM w0.076: UC1.AN70 92.17,95.92 91.43,95.92 91.42,95.91 89.75,95.91 88.97,95.13 87.86,95.13 87.63,94.91
  BOTTOM w0.102: 87.63,94.91 v2(87.63,94.37)
  BOTTOM w0.127: v2(80.06,57.47) 81.22,58.63 JDIMM1.21
DDR_A_D7: length 62.3
  IN4 w0.084: v2(86.71,93.51) 86.18,93.51 85.9,93.22 85.9,92.43 85.54,92.07 85.54,89.73 80.88,85.06 80.88,74.73 80.42,74.28 80.42,64.01 81.1,63.34 81.1,62.81 81.02,62.73 80.51,62.73 80.43,62.65 80.43,62.35 80.51,62.27 81.02,62.27 81.1,62.18 81.1,61.88 81.02,61.8 80.51,61.8 80.43,61.72 80.43,61.42 80.51,61.34 81.02,61.34 81.1,61.25 81.1,60.95 81.02,60.87 80.51,60.87 80.43,60.79 80.43,60.49 80.51,60.41 81.02,60.41 81.1,60.32 81.1,55.24 82.02,54.32 82.02,54.06 81.94,53.98 80.59,53.98 80.48,54.09 80.48,56.27 80.39,56.36 80.22,56.36 v2(80.06,56.2)
  BOTTOM w0.076: UC1.AN71 91.46,96.18 91.36,96.08 89.61,96.08 88.87,95.34 87.65,95.34 86.71,94.4 v2(86.71,93.51)
  BOTTOM w0.127: v2(80.06,56.2) 80.19,56.33 80.39,56.33 80.52,56.2 80.52,55.68 80.65,55.55 81.42,55.55 81.53,55.44 81.53,55.28 81.42,55.17 80.79,55.17 80.69,55.07 80.69,54.86 80.79,54.76 80.9,54.76 80.97,54.69 JDIMM1.20
DDR_A_D8: length 49.9
  IN4 w0.084: v2(87.55,92.67) 87.55,91.36 87.43,91.24 87.43,90.47 86.92,89.97 86.92,89.3 82.17,84.54 82.17,63.95 82.39,63.73 82.39,61.87 82.47,61.79 82.73,61.79 82.81,61.7 82.81,61.41 82.73,61.32 82.47,61.32 82.39,61.24 82.39,60.94 82.47,60.86 82.73,60.86 82.81,60.77 82.81,60.48 82.73,60.39 82.47,60.39 82.39,60.31 82.39,60.07 82.73,59.73 82.73,58.59 v2(82.35,58.21)
  BOTTOM w0.076: 88.82,94.45 89.05,94.45 90.02,95.42 91.63,95.42 91.63,95.42 92.02,95.42 92.29,95.15 UC1.AR70
  BOTTOM w0.102: v2(87.55,92.67) 87.55,93.18 88.82,94.45
  BOTTOM w0.127: v2(82.35,58.21) 82.57,57.99 83.26,57.99 83.41,58.14 83.41,58.72 83.22,58.91 JDIMM1.29
DDR_A_D9: length 50.8
  IN4 w0.084: v2(82.35,59.48) 82.05,59.78 82.05,63.65 81.84,63.86 81.84,64.3 81.75,64.39 81.44,64.39 81.36,64.47 81.36,64.77 81.44,64.85 81.75,64.85 81.84,64.94 81.84,65.24 81.75,65.32 81.44,65.32 81.35,65.41 81.35,65.69 81.45,65.79 81.75,65.79 81.84,65.87 81.84,84.67 86.51,89.34 86.51,90.31 86.78,90.58 86.78,90.89 86.51,91.16 86.51,91.7 v2(87.04,92.24)
  BOTTOM w0.076: 88.64,94.65 89.02,94.65 89.95,95.58 91.56,95.58 91.56,95.59 92.43,95.59 92.71,95.35 92.86,95.32 92.92,95.33 93.03,95.38 93.09,95.39 93.18,95.38 93.21,95.35 93.21,95.34 93.33,95.21 93.48,95.21 93.59,95.33 93.72,95.33 93.81,95.24 93.81,95.12 UC1.AR68
  BOTTOM w0.102: v2(87.04,92.24) 87.03,92.25 86.62,92.25 86.54,92.33 86.54,92.55 88.64,94.65
  BOTTOM w0.127: JDIMM1.25 82.22,60.9 82.33,60.8 82.51,60.8 82.61,60.7 82.61,60.51 82.53,60.43 81.9,60.43 81.83,60.36 81.83,59.36 81.96,59.23 82.17,59.23 82.35,59.41 v2(82.35,59.48)
DDR_A_D10: length 48.1
  IN4 w0.084: v2(84.89,59.48) 85.38,59.48 85.49,59.59 85.49,59.87 85.41,59.95 85.19,59.95 85.11,60.04 85.11,60.33 85.19,60.42 85.42,60.42 85.51,60.5 85.51,60.8 85.42,60.88 85.19,60.88 85.11,60.97 85.11,61.26 85.19,61.35 85.42,61.35 85.51,61.43 85.51,61.73 85.42,61.81 85.19,61.81 85.11,61.9 85.11,62.19 85.19,62.28 85.42,62.28 85.51,62.36 85.51,63.64 84.63,64.53 84.63,64.98 84.37,65.24 84.37,65.65 84.63,65.91 84.63,66.46 84.38,66.7 84.38,67.22 84.63,67.47 84.63,68.01 84.4,68.24 84.4,68.69 84.63,68.92 84.63,69.35 84.35,69.62 84.35,70.07 84.63,70.34 84.63,70.99 84.37,71.25 84.37,71.65 84.63,71.91 84.63,72.56 84.38,72.81 84.38,73.2 84.63,73.45 84.63,73.95 84.42,74.16 84.42,74.67 84.63,74.88 84.63,75.35 84.46,75.51 84.44,75.57 84.44,76.18 84.63,76.37 84.63,83.63 89.96,88.96 89.96,90.09 v2(88.85,91.2)
  BOTTOM w0.076: v2(88.85,91.2) 88.85,92.05 90.57,93.76 91.72,93.76 UC1.AU71
  BOTTOM w0.127: JDIMM1.37 85.22,60.96 85.1,60.83 84.22,60.83 84.09,60.7 84.09,60.43 84.22,60.3 84.41,60.3 84.56,60.15 84.56,59.94 84.42,59.79 84.25,59.79 84.13,59.67 84.13,59.44 84.25,59.31 84.71,59.31 v2(84.89,59.48)
DDR_A_D11: length 49.8
  IN4 w0.084: v2(87.69,89.41) 87.69,89.16 82.83,84.3 82.83,64.13 83.06,63.91 83.06,62.99 83.55,62.49 83.55,57.8 83.13,57.38 83.13,57.04 82.98,56.89 82.98,56.3 v2(82.35,55.67)
  BOTTOM w0.076: 87.38,91.53 87.61,91.76 87.77,91.76 90.85,94.84 91.39,94.84 91.51,94.72 91.93,94.72 91.96,94.74 92.04,94.77 92.16,94.77 92.37,94.7 92.52,94.7 92.68,94.76 93.07,94.74 93.16,94.74 93.39,94.83 93.63,94.69 93.72,94.59 93.74,94.2 UC1.AU68
  BOTTOM w0.127: v2(87.69,89.41) 87.12,89.98 87.12,91.27 87.38,91.53 ; JDIMM1.24 81.97,54.62 82.17,54.82 82.17,55.49 v2(82.35,55.67)
DDR_A_D12: length 48.6
  IN4 w0.084: v2(82.35,56.94) 82.74,57.34 82.74,57.48 83.22,57.96 83.22,62.11 82.72,62.6 82.72,63.82 82.5,64.04 82.5,84.39 87.29,89.18 87.29,89.78 87.92,90.4 87.92,91.04 88.64,91.77 88.64,91.93 88.56,92.01 88.01,92.01 87.92,92.09 87.92,92.38 88.02,92.47 88.56,92.47 88.64,92.56 v2(88.64,93.48)
  BOTTOM w0.076: UC1.AR71 91.69,95.25 90.16,95.25 89.13,94.22
  BOTTOM w0.102: v2(88.64,93.48) 88.64,93.89 88.97,94.22 89.13,94.22
  BOTTOM w0.127: v2(82.35,56.94) 82.97,56.32 JDIMM1.28
DDR_A_D13: length 49.6
  IN4 w0.084: v2(84.89,55.67) 86.02,55.67 86.49,56.14 86.49,63.93 85.62,64.8 85.62,83.36 91.45,89.18 91.45,91.96 91.07,92.34 90.83,92.34 89.7,93.47 v2(89.7,94.23)
  BOTTOM w0.076: v2(89.7,94.23) 90.55,95.09 91.43,95.09 91.63,94.89 91.89,94.89 92.01,94.94 92.03,94.94 92.04,94.95 92.05,94.94 92.15,94.94 92.38,94.88 92.51,94.88 92.73,94.95 92.98,94.95 UC1.AR69
  BOTTOM w0.127: JDIMM1.38 85.47,54.62 85.34,54.75 85.34,55.22 v2(84.89,55.67)
DDR_A_D14: length 48.4
  IN4 w0.084: v2(84.89,58.21) 85.22,58.21 85.3,58.13 85.3,57.34 85.42,57.22 85.68,57.22 85.82,57.37 85.82,63.75 84.96,64.62 84.96,83.54 90.35,88.93 90.35,90.55 v2(89.32,91.58)
  BOTTOM w0.076: UC1.AU70 92.18,93.57 90.64,93.57 89.32,92.25 v2(89.32,91.58)
  BOTTOM w0.127: v2(84.89,58.21) 85.05,58.05 85.5,58.05 85.79,58.34 85.79,60.72 86.22,61.15 JDIMM1.41
DDR_A_D15: length 48.9
  IN4 w0.084: v2(90.14,92.44) 90.52,92.07 90.52,90.8 90.68,90.64 90.68,88.84 85.29,83.45 85.29,64.71 86.16,63.84 86.16,56.49 86.03,56.37 85.71,56.37 85.14,56.94 v2(84.89,56.94)
  BOTTOM w0.076: v2(90.14,92.44) 90.14,92.62 90.93,93.41 92.42,93.41 92.84,93.83 UC1.AU69
  BOTTOM w0.127: JDIMM1.42 86.47,54.79 86.37,54.89 86.18,54.89 86.08,54.99 86.08,55.19 86.18,55.29 86.37,55.29 86.47,55.4 86.47,56.16 85.69,56.94 v2(84.89,56.94)
DDR_A_D16: length 45.2
  IN4 w0.084: v2(87.17,56.31) 87.92,57.05 87.92,59.55 87.99,59.62 87.99,64.12 86.89,65.22 86.89,75.03 87.22,75.36 87.22,83.19 90.33,86.31 v2(91.21,86.31)
  BOTTOM w0.076: v2(91.21,86.31) 91.72,86.82 91.72,88.17 92.65,89.1 94.74,89.1 95.48,89.84 95.48,90.62 UC1.BB65
  BOTTOM w0.127: v2(87.17,56.31) 88.26,56.31 88.37,56.2 88.37,55.93 88.25,55.82 87.82,55.82 87.72,55.72 87.72,55.51 87.82,55.41 88.05,55.41 88.47,54.98 JDIMM1.50
DDR_A_D17: length 46.7
  IN4 w0.084: v2(87.17,55.04) 87.38,55.04 88.22,55.87 88.22,59.36 88.32,59.46 88.32,64.21 87.19,65.35 87.19,74.78 87.52,75.12 87.52,83.07 90.35,85.89 91.46,85.89 91.91,86.34 91.91,87.16 v2(92.7,87.95)
  BOTTOM w0.076: v2(92.7,87.95) 93.19,87.95 93.64,88.39 94.98,88.39 96.62,90.02 96.62,90.27 96.44,90.45 96.44,90.83 96.48,90.94 96.48,91.06 96.42,91.28 96.42,91.42 96.47,91.58 96.47,91.81 96.44,91.85 96.44,92.45 96.25,92.64 UC1.AW65
  BOTTOM w0.127: JDIMM1.46 87.47,54.74 v2(87.17,55.04)
DDR_A_D18: length 47.8
  IN4 w0.084: v2(90.02,55.04) 90.02,54.66 90.65,54.03 91.15,54.03 91.23,54.11 91.23,54.38 91.32,54.46 91.5,54.46 91.58,54.54 91.58,54.84 91.5,54.92 91.32,54.92 91.23,55.01 91.23,55.31 91.32,55.39 91.5,55.39 91.58,55.47 91.58,55.77 91.5,55.85 91.32,55.85 91.23,55.94 91.23,56.24 91.32,56.32 91.5,56.32 91.58,56.4 91.58,56.7 91.5,56.78 91.32,56.78 91.15,56.95 91.15,64.28 90.8,64.62 90.8,65.22 90.23,65.79 90.23,80.24 92.16,82.17 92.63,82.64 92.63,84.22 v2(92.7,84.29)
  BOTTOM w0.076: UC1.AW63 96.77,92.44 97.08,92.13 97.08,92.13 97.09,92.12 97.09,91.95 97.06,91.83 97.06,91.7 97.08,91.56 97.3,91.34 97.3,89.7 95.33,87.73 94.19,87.73 93.74,87.29 93.74,85.32 92.71,84.29 v2(92.7,84.29)
  BOTTOM w0.127: v2(90.02,55.04) 90.19,55.04 90.47,54.75 JDIMM1.58
DDR_A_D19: length 46.1
  IN4 w0.084: v2(90.02,58.85) 90.09,58.92 90.09,60.15 89.91,60.33 89.91,60.56 90.03,60.68 90.03,60.68 90.15,60.8 90.15,61.03 90.03,61.15 90.03,61.15 89.91,61.26 89.91,61.5 90.03,61.61 90.03,61.61 90.15,61.73 90.15,61.96 90.03,62.08 90.03,62.08 89.91,62.2 89.91,62.43 90.03,62.55 90.03,62.55 90.15,62.67 90.15,63.91 89.84,64.22 89.84,64.91 88.72,66.03 88.72,68.15 88.83,68.26 89.11,68.26 89.23,68.38 89.23,68.61 89.11,68.73 88.83,68.73 88.72,68.85 88.72,69.08 88.83,69.2 89.11,69.2 89.23,69.31 89.23,69.53 89.11,69.65 88.84,69.65 88.72,69.77 88.72,70 88.84,70.12 89.11,70.12 89.23,70.23 89.23,70.47 89.11,70.58 88.84,70.58 88.72,70.7 88.72,70.94 88.84,71.05 89.11,71.05 89.23,71.17 89.23,71.4 89.11,71.52 88.84,71.52 88.72,71.64 88.72,71.87 88.84,71.99 89.11,71.99 89.23,72.1 89.23,72.27 89.12,72.38 88.81,72.38 88.7,72.49 88.7,72.73 88.78,72.81 88.94,72.81 89.11,72.98 89.11,73.49 88.92,73.67 88.92,74.12 89.11,74.31 89.11,80.53 91.62,83.04 91.62,85.58 92.24,86.21 92.24,86.88 v2(92.7,87.34)
  BOTTOM w0.076: v2(92.7,87.34) 92.84,87.34 93.73,88.23 95.05,88.23 96.78,89.96 96.78,90.37 96.6,90.55 96.6,90.79 96.66,90.91 96.66,91.05 96.59,91.28 96.59,91.41 96.67,91.63 96.67,91.89 UC1.AY63
  BOTTOM w0.127: v2(90.02,58.85) 90.13,58.85 90.28,59 90.28,60.29 90.72,60.73 JDIMM1.59
DDR_A_D20: length 45.5
  IN4 w0.084: v2(91.18,87.13) 90.74,87.13 86.67,83.07 86.67,82.33 86.92,82.09 86.92,81.41 86.62,81.11 86.62,80.4 86.92,80.1 86.92,75.77 86.52,75.37 86.52,65.16 87.66,64.03 87.66,59.72 87.59,59.66 87.59,57.5 87.5,57.42 87.33,57.42 v2(87.17,57.58)
  BOTTOM w0.076: UC1.BA65 95.54,91.19 95.4,91.05 95.4,91.04 95.39,91.04 95.29,90.82 95.29,89.88 94.67,89.27 92.53,89.27 91.54,88.27 91.54,87.49 v2(91.18,87.13)
  BOTTOM w0.127: JDIMM1.49 88.22,60.1 87.95,59.82 87.95,57.91 87.62,57.58 v2(87.17,57.58)
DDR_A_D21: length 46.2
  IN4 w0.084: v2(87.17,58.85) 87.17,59.65 87.32,59.8 87.32,60.11 87.09,60.35 87.09,60.57 87.32,60.81 87.32,61.04 87.09,61.28 87.09,61.5 87.32,61.74 87.32,61.97 87.09,62.21 87.09,62.43 87.32,62.67 87.32,63.94 86.22,65.04 86.22,76.35 86.36,76.49 86.37,76.49 86.51,76.63 86.51,76.82 86.37,76.95 86.36,76.95 86.22,77.09 86.22,77.28 86.36,77.42 86.37,77.42 86.51,77.55 86.51,77.75 86.37,77.88 86.36,77.88 86.22,78.02 86.22,78.21 86.36,78.35 86.37,78.35 86.51,78.48 86.51,78.68 86.37,78.81 86.36,78.81 86.22,78.95 86.22,79.14 86.36,79.28 86.37,79.28 86.51,79.41 86.51,79.61 86.37,79.74 86.36,79.74 86.22,79.88 86.22,83.09 90.9,87.77 v2(91.16,87.77)
  BOTTOM w0.076: v2(91.16,87.77) 91.16,88.17 92.44,89.46 94.6,89.46 95.12,89.98 95.12,90.85 95.15,90.92 95.15,92.14 95.23,92.21 95.47,92.21 95.54,92.14 UC1.AY65
  BOTTOM w0.127: JDIMM1.45 87.22,60.89 87.31,60.8 87.31,60.35 87.1,60.14 86.64,60.14 86.4,59.9 86.4,58.52 86.52,58.4 86.73,58.4 v2(87.17,58.85)
DDR_A_D22: length 46.3
  IN4 w0.084: v2(92.7,85.51) 92.28,85.09 92.28,82.76 89.89,80.37 89.89,65.7 90.5,65.09 90.5,64.5 90.81,64.19 90.81,56.89 90.85,56.85 90.85,55.59 90.77,55.5 90.49,55.5 90.41,55.59 90.41,55.92 v2(90.02,56.31)
  BOTTOM w0.076: UC1.BA63 96.87,91.12 97.13,90.86 97.13,89.8 95.23,87.9 94.1,87.9 93.35,87.15 93.35,86.16 v2(92.7,85.51)
  BOTTOM w0.127: v2(90.02,56.31) 91.24,56.31 91.36,56.19 91.36,55.92 91.26,55.82 90.85,55.82 90.73,55.7 90.73,55.53 90.85,55.41 91.37,55.41 91.47,55.31 JDIMM1.62
DDR_A_D23: length 45.2
  IN4 w0.084: v2(90.02,57.58) 90.02,57.49 90.28,57.23 90.4,57.23 90.48,57.32 90.48,64.05 90.17,64.36 90.17,65 89.56,65.61 89.56,66.29 89.44,66.41 89.17,66.41 89.05,66.53 89.05,66.76 89.17,66.88 89.44,66.88 89.56,67 89.56,67.23 89.44,67.35 89.17,67.35 89.05,67.46 89.05,67.7 89.17,67.81 89.44,67.81 89.56,67.93 89.56,80.51 91.95,82.9 91.95,85.44 92.62,86.12 v2(92.7,86.12)
  BOTTOM w0.076: v2(92.7,86.12) 92.81,86 92.96,86 93.19,86.23 93.19,87.45 93.8,88.06 95.13,88.06 96.95,89.88 96.95,90.61 UC1.BB63
  BOTTOM w0.127: v2(90.02,57.58) 90.1,57.58 90.9,58.38 90.9,59.99 91.72,60.82 JDIMM1.63
DDR_A_D24: length 43.6
  IN4 w0.084: v2(94.32,86.04) 93.9,85.62 93.9,85.29 93.59,84.97 93.59,82.24 91.13,79.79 91.13,66.15 91.7,65.59 91.7,64.99 92.1,64.58 92.1,61.97 92.22,61.85 92.81,61.85 92.93,61.73 92.93,61.5 92.81,61.38 92.22,61.38 92.1,61.27 92.1,61.05 92.22,60.93 92.81,60.93 92.93,60.82 92.93,60.58 92.81,60.46 92.22,60.46 92.1,60.35 92.1,60.13 92.23,60.01 92.74,60.01 92.93,59.83 92.93,59.61 92.59,59.27 92.36,59.27 v2(92.19,59.44)
  BOTTOM w0.076: UC1.BA61 97.9,91.11 97.63,90.85 97.63,89.52 95.03,86.92 95.03,86.42 94.65,86.04 v2(94.32,86.04)
  BOTTOM w0.127: v2(92.19,59.44) 92.41,59.22 93.09,59.22 93.98,60.11 93.98,60.77 93.72,61.02 JDIMM1.71
DDR_A_D25: length 45.2
  IN4 w0.084: v2(94.32,87.34) 93.56,86.58 93.56,85.43 93.25,85.12 93.25,82.38 90.83,79.95 90.83,66.03 91.4,65.46 91.4,64.87 91.77,64.49 91.77,57.37 92.2,56.94 v2(92.2,56.32)
  BOTTOM w0.076: v2(94.32,87.34) 95.19,87.34 97.46,89.61 97.46,91.37 97.7,91.6 97.7,91.61 97.7,91.61 97.7,91.83 97.68,91.95 97.68,92.19 98,92.51 UC1.AW61
  BOTTOM w0.127: v2(92.2,56.32) 92.2,56.57 92.41,56.78 92.69,56.78 93.47,55.99 93.47,55.62 93.59,55.51 93.81,55.51 93.92,55.4 93.92,55.19 93.8,55.06 93.59,55.06 93.47,54.95 JDIMM1.70
DDR_A_D26: length 44
  IN4 w0.084: v2(96.25,84.28) 96.3,84.28 96.87,83.7 96.87,81.58 94.36,79.06 94.36,67.54 95.05,66.85 95.05,66.42 97.06,64.41 97.06,64.07 97.18,63.95 97.52,63.95 97.64,63.83 97.64,63.6 97.52,63.48 97.18,63.48 97.06,63.36 97.06,63.13 97.18,63.01 97.34,63.01 97.46,62.9 97.46,62.66 97.34,62.55 97.24,62.55 97.12,62.43 97.12,57.57 96.94,57.39 96.49,57.39 v2(96.27,57.61)
  BOTTOM w0.076: UC1.BB59 99.32,90.58 99.32,89.88 99.08,89.64 99.08,89.04 v1(97.95,87.91) 97.17,87.13 97.17,85.2 v2(96.25,84.28)
  BOTTOM w0.127: v2(96.27,57.61) 95.4,58.48 95.4,60.15 95.72,60.47 JDIMM1.79
DDR_A_D27: length 46.1
  IN4 w0.084: v2(96.25,85.58) 96.25,85.57 95.82,85.14 95.82,81.74 93.36,79.27 93.36,66.93 93.86,66.43 93.86,65.83 95.09,64.6 95.09,56.38 95.2,56.27 95.64,56.27 95.76,56.15 95.76,55.91 95.64,55.8 95.2,55.8 95.09,55.68 95.09,54.65 95.34,54.4 95.6,54.4 v2(96.27,55.07)
  BOTTOM w0.076: v2(96.25,85.58) 95.86,85.97 95.86,87.01 98.13,89.28 98.13,90.26 98.33,90.46 98.33,90.82 98.33,90.82 98.29,90.91 98.29,91.11 98.33,91.2 98.33,91.2 98.33,91.2 98.34,91.21 98.34,91.44 98.29,91.57 98.29,91.82 98.37,91.92 98.37,92.14 98.33,92.17 98.33,92.45 98.52,92.64 UC1.AW59
  BOTTOM w0.127: v2(96.27,55.07) 95.97,54.77 JDIMM1.80
DDR_A_D28: length 43.5
  IN4 w0.084: v2(92.23,58.2) 92.37,58.05 92.53,58.05 92.63,58.15 92.63,58.8 93.24,59.41 93.24,62.09 93.15,62.18 92.52,62.18 92.44,62.27 92.44,62.44 92.66,62.66 92.66,62.83 92.44,63.05 92.44,63.25 92.55,63.36 92.62,63.36 92.74,63.48 92.74,63.77 92.62,63.88 92.55,63.88 92.44,64 92.44,64.67 92,65.12 92,65.71 91.47,66.23 91.47,79.66 93.92,82.1 93.92,84.83 94.32,85.22 v2(94.32,85.36)
  BOTTOM w0.076: UC1.BB61 97.8,90.58 97.8,89.45 95.42,87.08 95.42,85.1 95.34,85.02 94.65,85.02 v2(94.32,85.36)
  BOTTOM w0.127: JDIMM1.67 92.72,60.25 92.6,60.12 91.97,60.12 91.56,59.71 91.56,58.87 v2(92.23,58.2)
DDR_A_D29: length 44.6
  IN4 w0.084: v2(92.19,55.1) 93.48,55.1 93.69,55.31 93.69,55.78 92.94,56.52 92.94,58.61 93.57,59.24 93.57,62.63 93.47,62.73 93.19,62.73 93.07,62.84 93.07,64.46 92.3,65.24 92.3,65.83 91.79,66.34 91.79,79.51 94.33,82.05 v2(94.33,84.05)
  BOTTOM w0.076: UC1.AY61 98.1,91.89 98.1,91.62 98.13,91.52 98.13,91.52 98.16,91.44 98.16,91.23 98.13,91.14 98.13,90.88 98.16,90.79 98.16,90.53 97.96,90.33 97.96,89.38 95.59,87.01 95.59,84.23 95.41,84.05 v2(94.33,84.05)
  BOTTOM w0.127: v2(92.19,55.1) 92.47,54.81 JDIMM1.66
DDR_A_D30: length 45.2
  IN4 w0.084: v2(96.27,58.88) 96.61,58.88 96.73,58.99 96.73,61.24 96.61,61.36 95.87,61.36 95.75,61.47 95.75,61.71 95.87,61.82 96.61,61.82 96.73,61.94 96.73,62.17 96.61,62.29 96.21,62.29 96.1,62.41 96.1,62.64 96.21,62.76 96.61,62.76 96.73,62.88 96.73,63.29 96.61,63.4 96.51,63.4 96.39,63.52 96.39,63.75 96.51,63.87 96.61,63.87 96.73,63.99 96.73,64.27 94.72,66.28 94.72,66.42 93.96,67.18 93.96,79.04 96.67,81.75 96.67,83.21 v2(96.25,83.63)
  BOTTOM w0.076: v2(96.25,83.63) 97.08,83.63 97.36,83.91 97.36,86.93 99.25,88.81 99.25,89.57 99.49,89.81 99.49,90.78 99.43,90.93 UC1.BA59
  BOTTOM w0.127: JDIMM1.83 96.72,61.9 96.72,60.85 96.83,60.74 97.58,60.74 97.7,60.63 97.7,60.46 97.58,60.34 96.69,60.34 96.57,60.22 96.57,59.63 96.27,59.33 v2(96.27,58.88)
DDR_A_D31: length 45.6
  IN4 w0.084: v2(96.27,56.34) 96.04,56.34 95.78,56.6 95.55,56.6 95.42,56.73 95.42,59.39 95.54,59.51 96.17,59.51 96.29,59.62 96.29,59.86 96.17,59.97 95.54,59.97 95.42,60.09 95.42,60.32 95.54,60.44 96.17,60.44 96.29,60.56 96.29,60.79 96.17,60.91 95.54,60.91 95.42,61.02 95.42,64.83 94.27,65.98 94.27,66.45 93.66,67.06 93.66,79.12 96.25,81.71 v2(96.25,82.34)
  BOTTOM w0.076: UC1.AY59 99.22,91.78 99.49,91.52 99.49,91.32 99.62,90.89 99.65,90.82 99.65,89.74 99.41,89.5 99.41,88.71 97.56,86.85 97.56,83.37 96.53,82.34 v2(96.25,82.34)
  BOTTOM w0.127: JDIMM1.84 96.97,55.63 v2(96.27,56.34)
DDR_A_D32: length 47.8
  IN4 w0.084: v2(110.98,82.13) 110.98,80.53 113.05,78.46 113.05,73.45 118.98,67.52 119.21,67.52 119.69,67.99 119.82,67.99 121.23,66.59 121.23,66.15 120.9,65.83 120.9,65.66 121.23,65.33 121.23,59.92 121.31,59.84 121.54,59.84 121.63,59.75 121.63,59.46 121.54,59.37 121.31,59.37 121.23,59.29 121.23,58.02 121.31,57.93 121.56,57.93 121.65,58.02 121.65,58.7 121.73,58.78 v2(122.04,58.78)
  BOTTOM w0.076: 109.59,84.62 109.59,89.36 109.91,89.68 109.91,90.35 109.83,90.43 109.83,90.83 109.9,90.96 109.9,90.98 110,91.23 110,91.52 110.27,91.78 UC1.AY39
  BOTTOM w0.127: v2(122.04,58.78) 121.67,58.41 120.89,58.41 120.47,58.83 120.47,60.74 120.22,60.99 120.22,61.9 JDIMM1.169 ; v2(110.98,82.13) 109.59,83.51 109.59,84.62
DDR_A_D33: length 45.3
  IN4 w0.084: v2(122.04,56.24) 120.58,57.7 120.58,64.97 112.39,73.17 112.39,78.38 110.29,80.48 110.29,87.4 v2(110.98,88.09)
  BOTTOM w0.076: v2(110.98,88.09) 111.36,88.48 111.36,90.25 111.17,90.44 111.17,90.78 111.2,90.89 111.19,91.11 111.17,91.18 111.17,91.5 111.19,91.56 111.21,91.85 111.21,92.35 110.92,92.64 UC1.AW39
  BOTTOM w0.127: JDIMM1.174 121.47,55.68 v2(122.04,56.24)
DDR_A_D34: length 47.8
  IN4 w0.084: v2(124.78,60.05) 124.78,60.82 125.19,61.23 125.19,61.34 125.04,61.5 124.13,61.5 124.03,61.6 124.03,61.86 124.13,61.96 124.86,61.96 124.98,62.08 124.98,62.37 124.86,62.48 124.47,62.48 124.35,62.6 124.35,64.68 124.47,64.8 124.91,64.8 125.02,64.91 125.02,65.14 124.89,65.27 124.15,65.27 124.03,65.38 124.03,65.62 124.15,65.73 125.01,65.73 125.13,65.85 125.13,66.08 125.01,66.2 124.47,66.2 124.35,66.32 124.35,66.85 121.2,70 119.13,70 114.93,74.21 114.93,77.88 111.99,80.81 111.99,87.71 111.87,87.83 111.37,87.83 v2(110.98,87.44)
  BOTTOM w0.076: UC1.AY37 111.39,91.89 111.39,91.63 111.34,91.48 111.34,91.24 111.38,91.08 111.38,90.96 111.34,90.76 111.34,90.51 111.53,90.32 111.53,88.31 111.35,88.14 111.35,87.82 v2(110.98,87.44)
  BOTTOM w0.127: v2(124.78,60.05) 124.37,60.47 124.37,60.72 124.72,61.07 JDIMM1.187
DDR_A_D35: length 48.6
  IN4 w0.084: v2(112.75,84.19) 112.32,84.19 112.18,84.05 112.18,81.02 115.26,77.93 115.26,74.36 119.23,70.39 121.3,70.39 125.46,66.23 125.46,65.96 125.58,65.85 125.79,65.85 125.9,65.73 125.9,65.44 125.73,65.26 125.43,65.26 125.32,65.15 125.32,64.43 125.16,64.26 124.79,64.26 124.69,64.16 124.69,62.95 124.82,62.81 125.11,62.81 125.29,62.63 125.29,61.81 125.42,61.68 125.64,61.68 125.73,61.59 125.73,61.29 125.09,60.65 125.09,60.33 125.38,60.04 125.38,58.48 125.29,58.39 125.08,58.39 124.78,58.69 v2(124.78,58.78)
  BOTTOM w0.076: v2(112.75,84.19) 112.02,84.92 112.02,90.32 112.02,91.34 111.8,91.56 111.8,92.11 111.49,92.42 UC1.AW37
  BOTTOM w0.127: JDIMM1.183 123.72,60.19 123.99,59.93 123.99,59.58 v2(124.78,58.78)
DDR_A_D36: length 46.2
  IN4 w0.084: v2(110.98,84.19) 111.31,84.19 111.39,84.11 111.39,80.46 113.38,78.46 113.38,73.54 118.61,68.31 119.92,68.31 121.53,66.7 121.53,66.17 121.62,66.08 122.41,66.08 122.5,65.99 122.5,65.7 122.42,65.62 121.62,65.62 121.53,65.54 121.53,65.24 121.62,65.16 122.41,65.16 122.5,65.06 122.5,64.77 122.42,64.69 121.62,64.69 121.53,64.61 121.53,64.31 121.62,64.23 122.41,64.23 122.5,64.13 122.5,63.84 122.42,63.76 121.62,63.76 121.53,63.68 121.53,60.47 v2(121.79,60.21)
  BOTTOM w0.076: UC1.BB39 110.25,90.66 110.25,89.43 110.06,89.24 110.06,85.11 v2(110.98,84.19)
  BOTTOM w0.127: JDIMM1.173 121.23,61.11 121.11,60.99 121.11,60.82 121.39,60.54 121.39,60.28 121.08,59.97 121.08,59.27 121.22,59.13 121.51,59.13 121.64,59.26 121.64,59.59 121.79,59.75 v2(121.79,60.21)
DDR_A_D37: length 46.4
  IN4 w0.084: v2(122.04,57.51) 121.7,57.17 121.58,57.17 120.92,57.84 120.92,65.11 120.34,65.68 120.34,65.88 120.49,66.02 120.49,66.21 120.35,66.35 120.16,66.35 120.02,66.2 119.82,66.2 119.69,66.34 119.69,66.48 119.97,66.76 119.97,66.95 119.83,67.09 119.64,67.09 119.41,66.86 119.17,66.86 112.72,73.31 112.72,78.44 110.6,80.56 110.6,83.16 v2(110.98,83.54)
  BOTTOM w0.076: UC1.BA39 110.27,91.19 110.13,91.05 110.12,91.04 110.12,91.04 110,90.79 110,90.5 110.08,90.42 110.08,89.54 109.83,89.29 v4(109.83,88.45) 109.83,84.69 v2(110.98,83.54)
  BOTTOM w0.127: JDIMM1.170 120.47,56.25 121.73,57.51 v2(122.04,57.51)
DDR_A_D38: length 47.2
  IN4 w0.084: v2(112.75,82.76) 112.39,82.4 112.39,81.12 115.6,77.92 115.6,74.51 119.29,70.81 121.35,70.81 126.24,65.92 126.24,65.3 125.64,64.7 125.64,62.19 126.04,61.8 126.04,61.13 125.69,60.78 125.69,57.76 125.3,57.38 124.92,57.38 v2(124.78,57.51)
  BOTTOM w0.076: v2(112.75,82.76) 111.86,83.66 111.86,87.43 111.82,87.46 v4(111.82,87.81) 111.82,88.1 111.86,88.14 111.86,90.39 111.86,90.39 111.86,90.86 111.59,91.12 UC1.BA37
  BOTTOM w0.127: v2(124.78,57.51) 123.47,56.21 JDIMM1.182
DDR_A_D39: length 46.2
  IN4 w0.084: v2(124.78,56.24) 124.95,56.08 125.46,56.08 125.99,56.61 125.99,60.61 126.37,60.99 126.37,61.93 125.97,62.33 125.97,64.57 126.57,65.16 126.57,66.08 121.43,71.22 119.39,71.22 115.93,74.68 115.93,77.98 113.11,80.81 113.11,81.7 v2(112.75,82.05)
  BOTTOM w0.076: 112.39,82.42 111.69,83.11 111.69,87.3 111.64,87.35 111.64,88.18 111.69,88.23 111.69,90.39 111.59,90.49 UC1.BB37
  BOTTOM w0.127: JDIMM1.186 124.47,55.94 v2(124.78,56.24) ; 112.39,82.42 v2(112.75,82.05)
DDR_A_D40: length 49.4
  IN4 w0.084: v2(112.75,86.14) 113.14,86.52 113.36,86.52 113.48,86.4 113.48,81.26 116.87,77.86 116.87,75.11 119.78,72.2 121.78,72.2 127.6,66.38 127.6,64.84 126.93,64.17 126.93,62.74 127.63,62.04 127.63,61.62 127.46,61.44 127.46,61.13 127.63,60.96 127.63,60.63 127.44,60.44 127.18,60.44 126.93,60.2 126.93,59.23 v2(127.37,58.78)
  BOTTOM w0.076: v2(112.75,86.14) 112.75,85.98 112.99,85.75 113.23,85.75 113.31,85.83 113.31,88.34 112.68,88.97 112.68,90.01 112.89,90.22 112.89,90.79 112.85,90.88 112.85,90.89 112.85,91.14 112.89,91.23 112.89,91.44 112.86,91.52 112.82,91.62 112.82,91.89 UC1.AY35
  BOTTOM w0.127: v2(127.37,58.78) 127.02,58.43 126.08,58.43 125.72,58.79 JDIMM1.191
DDR_A_D41: length 50
  IN4 w0.084: v2(112.75,84.84) 113.3,84.29 113.3,81.04 116.54,77.81 116.54,74.95 119.65,71.84 121.66,71.84 127.19,66.3 127.19,64.9 126.6,64.31 126.6,62.59 126.99,62.19 126.99,60.73 126.6,60.34 126.6,58.48 126.72,58.36 126.81,58.36 126.92,58.24 126.92,58.01 126.81,57.89 126.72,57.89 126.6,57.78 126.6,57.18 126.72,57.06 126.92,57.06 v2(127.37,57.51)
  BOTTOM w0.076: v2(112.75,84.84) 112.19,85.41 112.19,90.25 112.19,90.25 112.19,91.37 112.4,91.58 112.4,92.1 112.72,92.42 UC1.AW35
  BOTTOM w0.127: JDIMM1.190 125.47,56.34 126.65,57.51 v2(127.37,57.51)
DDR_A_D42: length 49.7
  IN4 w0.084: v2(130.62,58.78) 130.21,59.2 130.21,64.28 130.33,64.4 130.73,64.4 130.85,64.52 130.85,64.75 130.73,64.87 130.32,64.87 130.21,64.98 130.21,65.21 130.33,65.33 130.76,65.33 130.87,65.44 130.87,65.67 130.74,65.8 130.33,65.8 130.21,65.92 130.21,66.15 130.33,66.27 130.66,66.27 130.77,66.38 130.77,66.62 130.66,66.73 130.33,66.73 130.21,66.85 130.21,67.43 122.83,74.81 120.89,74.81 119.49,76.22 119.49,77.23 115.02,81.69 115.02,83.45 v2(114.58,83.89)
  BOTTOM w0.076: UC1.AY33 113.95,91.78 114.22,91.51 114.22,91.17 114.27,91.06 114.38,90.83 114.38,90.46 114.25,90.34 114.25,90.34 114.2,90.28 114.2,89.96 114.5,89.66 114.5,88.86 115.04,88.32 115.04,84.36 v2(114.58,83.89)
  BOTTOM w0.127: JDIMM1.203 128.72,59.1 129.25,58.58 130.42,58.58 v2(130.62,58.78)
DDR_A_D43: length 48.4
  IN4 w0.084: v2(130.62,56.24) 130.25,56.62 130.25,58.48 129.77,58.95 129.77,67.39 122.69,74.48 120.71,74.48 119.22,75.96 119.22,77.19 114.58,81.83 v2(114.58,83.26)
  BOTTOM w0.076: UC1.AW33 113.29,92.64 113.09,92.43 113.09,91.92 113.02,91.82 113.02,91.57 113.06,91.44 113.06,91.21 113.06,91.2 113.05,91.2 113.05,91.2 113.02,91.11 113.02,90.91 113.05,90.82 113.05,90.82 113.05,90.15 112.96,90.05 112.96,88.93 113.48,88.41 113.48,84.36 v2(114.58,83.26)
  BOTTOM w0.127: v2(130.62,56.24) 129.97,54.83 129.97,53.7 JDIMM1.208
DDR_A_D44: length 47.6
  IN4 w0.076: v2(112.75,86.79) 113.04,86.79 113.12,86.87 113.12,87.56 113.2,87.63 113.47,87.63
  IN4 w0.084: 113.47,87.63 113.55,87.56 113.55,86.84 113.65,86.74 113.65,81.41 117.2,77.85 117.2,75.26 119.89,72.58 121.91,72.58 127.96,66.53 127.96,64.32 127.85,64.22 127.46,64.22 127.27,64.03 127.27,62.88 127.97,62.18 127.97,59.83 127.85,59.71 127.72,59.71 v2(127.37,60.05)
  BOTTOM w0.076: v2(112.75,86.79) 113.03,86.79 113.15,86.91 113.15,88.27 112.52,88.9 112.52,90.12 112.52,90.12 112.52,90.58 UC1.BB35
  BOTTOM w0.127: v2(127.37,60.05) 127.17,60.26 126.99,60.26 126.84,60.1 126.84,59.18 126.71,59.05 126.5,59.05 126.34,59.21 126.34,60.5 126.72,60.89 JDIMM1.195
DDR_A_D45: length 48.4
  IN4 w0.084: v2(127.37,56.24) 127.37,55.64 127.5,55.51 127.96,55.51 128.09,55.64 128.09,58.2 128.27,58.38 128.27,66.73 122.06,72.93 120.04,72.93 117.54,75.44 117.54,77.89 113.82,81.61 113.82,87.63 113.36,88.09 v2(112.75,88.09)
  BOTTOM w0.076: UC1.BA35 112.62,91.11 112.35,90.85 112.35,90.19 112.35,90.18 112.35,88.49 v2(112.75,88.09)
  BOTTOM w0.127: v2(127.37,56.24) 126.47,55.34 JDIMM1.194
DDR_A_D46: length 48.3
  IN4 w0.084: v2(114.58,87.7) 115.54,86.75 115.54,81.83 120.01,77.36 120.01,76.84 121.35,75.5 123.11,75.5 131.7,66.91 131.7,62.8 132.01,62.49 132.01,60.51 131.04,59.53 131.04,57.6 130.95,57.51 v2(130.62,57.51)
  BOTTOM w0.076: v2(114.58,87.7) 114.32,87.96 114.32,89.6 114.04,89.89 114.04,90.35 114.21,90.53 114.21,90.79 114.1,91.04 114.09,91.04 114.09,91.05 113.95,91.19 UC1.BA33
  BOTTOM w0.127: v2(130.62,57.51) 129.63,57.51 129.41,57.3 129.41,55.56 128.97,55.12 128.97,53.7 JDIMM1.204
DDR_A_D47: length 47.5
  IN4 w0.084: v2(114.58,87.07) 115.27,86.38 115.27,81.77 119.69,77.35 119.69,76.51 121.04,75.16 122.97,75.16 131.37,66.76 131.37,62.83 131.27,62.72 130.75,62.72 130.62,62.6 130.62,62.38 130.74,62.26 131.54,62.26 131.68,62.12 131.68,61.91 131.56,61.8 130.74,61.8 130.62,61.68 130.62,61.45 130.74,61.33 131.56,61.33 131.68,61.21 131.68,60.65 131.34,60.3 131.22,60.3 131.11,60.41 131.11,60.85 131.01,60.95 130.75,60.95 130.62,60.83 v2(130.62,60.05)
  BOTTOM w0.076: UC1.BB33 113.95,90.54 113.87,90.46 113.87,89.82 114.12,89.57 114.12,87.53 v2(114.58,87.07)
  BOTTOM w0.127: JDIMM1.207 129.72,61.18 129.35,60.81 129.35,60.24 129.54,60.05 v2(130.62,60.05)
DDR_A_D48: length 50.6
  IN4 w0.084: v2(132.81,59.32) 132.81,59.2 133.01,59 133.19,59 133.28,59.09 133.28,60.23 133.36,60.31 133.83,60.31 133.95,60.44 133.95,60.59 133.84,60.7 133.42,60.7 133.3,60.82 133.3,61.06 133.42,61.17 133.82,61.17 133.9,61.26 133.9,61.56 133.82,61.64 133.42,61.64 133.3,61.76 133.3,61.99 133.42,62.11 133.8,62.11 133.93,62.24 133.93,62.46 133.82,62.58 133.6,62.58 133.49,62.69 133.49,63.44 132.89,64.04 132.89,64.4 133.04,64.54 133.04,64.85 132.89,65 132.89,65.43 133.04,65.57 133.04,65.82 132.89,65.96 132.89,66.17 133.04,66.32 133.04,66.62 132.89,66.76 132.89,66.99 133.03,67.12 133.03,67.47 132.7,67.8 132.57,67.8 132.29,68.07 132.29,68.21 131.87,68.64 131.71,68.64 131.4,68.95 131.4,69.11 131.13,69.37 131,69.37 130.63,69.74 130.63,69.87 123.66,76.85 121.73,76.85 121.28,77.29 121.28,77.36 119.5,79.15 119.24,79.15 116.42,81.97 v2(116.42,82.43)
  BOTTOM w0.076: v2(116.42,82.43) 115.3,83.55 115.3,89.09 114.99,89.41 114.99,90.29 114.82,90.46 114.82,90.82 114.98,91.23 114.98,91.52 115.25,91.78 UC1.AY31
  BOTTOM w0.127: v2(132.81,59.32) 132.41,58.92 132.23,58.92 131.93,59.22 131.93,59.4 132.32,59.79 132.32,60 131.9,60.43 131.9,60.63 131.72,60.8 JDIMM1.215
DDR_A_D49: length 51
  IN4 w0.084: v2(116.42,88.15) 115.74,87.47 115.74,81.98 119.07,78.65 119.32,78.65 120.44,77.54 120.44,77.03 121.33,76.13 123.37,76.13 132.29,67.21 132.29,63.09 132.64,62.75 132.64,60.25 131.66,59.28 131.66,56.77 131.85,56.58 132.62,56.58 v2(132.81,56.78)
  BOTTOM w0.076: UC1.AW31 115.94,92.64 116.16,92.42 116.16,91.85 116.18,91.83 116.18,91.57 116.12,91.42 116.12,91.28 116.19,91.06 116.19,90.94 116.15,90.86 116.14,90.83 116.14,90.3 116.4,90.05 116.4,88.17 v2(116.42,88.15)
  BOTTOM w0.127: JDIMM1.212 130.97,53.7 130.97,54.94 v2(132.81,56.78)
DDR_A_D50: length 50
  IN4 w0.084: v2(116.42,87.51) 117.42,86.51 117.42,82.21 119.28,80.35 119.84,80.35 121.39,78.79 124.32,78.79 135.35,67.75 135.35,64.46 135.82,63.99 135.82,55.61 135.98,55.45 136.21,55.45 v2(136.26,55.51)
  BOTTOM w0.076: UC1.AY29 116.37,91.89 116.37,91.63 116.3,91.41 116.3,91.28 116.36,91.05 116.36,90.91 116.31,90.79 116.31,90.37 116.56,90.11 116.56,88.51 116.79,88.28 116.79,88.01 116.42,87.64 v2(116.42,87.51)
  BOTTOM w0.127: v2(136.26,55.51) 135.88,55.51 134.97,54.61 134.97,53.7 JDIMM1.228
DDR_A_D51: length 50.8
  IN4 w0.084: v2(136.26,59.32) 136.41,59.46 136.41,64.36 136.29,64.47 135.81,64.47 135.69,64.6 135.69,64.8 135.8,64.92 136.29,64.92 136.41,65.04 136.41,65.27 136.29,65.39 135.83,65.39 135.69,65.53 135.69,65.74 135.8,65.86 136.29,65.86 136.41,65.97 136.41,66.22 136.29,66.33 135.85,66.33 135.74,66.45 135.74,66.68 135.85,66.8 136.29,66.8 136.41,66.92 136.41,67.18 136.24,67.35 135.8,67.35 135.69,67.46 135.69,67.89 124.41,79.16 121.35,79.16 119.91,80.61 119.3,80.61 117.63,82.28 117.63,83.96 v2(118.01,84.34)
  BOTTOM w0.076: UC1.AW29 116.47,92.42 116.59,92.3 116.61,92.3 116.79,92.12 116.79,91.95 116.77,91.83 116.77,91.58 117.01,91.34 117.01,90.39 117.1,90.3 117.1,88.98 117.3,88.77 117.3,85.05 v2(118.01,84.34)
  BOTTOM w0.127: v2(136.26,59.32) 135.23,60.36 JDIMM1.229
DDR_A_D52: length 48.9
  IN4 w0.084: v2(116.42,84.34) 116.08,84.34 115.92,84.19 115.92,82.13 119.14,78.91 119.37,78.91 120.89,77.4 120.89,77.17 121.56,76.49 123.43,76.49 132.59,67.33 132.59,63.91 133.12,63.39 133.12,63.02 132.97,62.87 132.97,60.11 132,59.14 132,57.69 132.12,57.56 132.32,57.56 v2(132.81,58.05)
  BOTTOM w0.076: UC1.BB31 115.32,90.61 115.32,89.54 115.63,89.23 115.63,85.13 v2(116.42,84.34)
  BOTTOM w0.127: JDIMM1.211 130.72,60.89 131.27,60.34 131.27,58.97 132.19,58.05 v2(132.81,58.05)
DDR_A_D53: length 49.7
  IN4 w0.084: v2(116.42,83.7) 116.84,83.28 116.84,81.89 119.38,79.35 119.67,79.35 121.82,77.2 123.73,77.2 133.34,67.59 133.34,64.02 133.79,63.57 133.79,63.08 134.27,62.6 134.27,60.28 133.59,59.61 133.59,57.3 133.68,57.21 134.5,57.21 134.58,57.13 134.58,56.7 134.5,56.62 133.64,56.62 133.56,56.54 133.56,56.26 v2(132.81,55.51)
  BOTTOM w0.076: UC1.BA31 115.25,91.19 115.11,91.05 115.1,91.04 115.1,91.04 114.98,90.79 114.98,90.53 115.15,90.36 115.15,89.47 115.47,89.16 115.47,84.66 v2(116.42,83.7)
  BOTTOM w0.127: v2(132.81,55.51) 131.97,54.67 131.97,53.7 JDIMM1.216
DDR_A_D54: length 49.7
  IN4 w0.084: v2(118.01,83.07) 118.72,82.36 118.72,81.86 119.41,81.16 120.04,81.16 121.42,79.78 124.75,79.78 137.07,67.46 137.07,57.59 v2(136.26,56.78)
  BOTTOM w0.076: v2(118.01,83.07) 117.14,83.94 117.14,88.7 116.93,88.91 116.93,90.21 116.84,90.3 116.84,90.84 116.57,91.11 UC1.BA29
  BOTTOM w0.127: JDIMM1.224 133.97,53.7 133.97,54.49 v2(136.26,56.78)
DDR_A_D55: length 48.7
  IN4 w0.084: v2(136.26,58.05) 136.45,57.87 136.65,57.87 136.74,57.95 136.74,67.32 124.59,79.47 121.35,79.47 120.01,80.81 119.41,80.81 118.4,81.82 118.4,82.05 v2(118.01,82.43)
  BOTTOM w0.076: UC1.BB29 116.57,90.34 116.73,90.18 116.73,88.58 116.97,88.33 116.97,87.96 116.91,87.9 v4(116.91,87.63) 116.91,83.53 v2(118.01,82.43)
  BOTTOM w0.127: JDIMM1.225 134.23,60.2 135.77,58.66 135.77,58.54 v2(136.26,58.05)
DDR_A_D56: length 52.9
  IN4 w0.076: 121.05,80.7 121.06,80.68 121.56,80.68
  IN4 w0.084: 121.05,80.7 120.07,81.67 119.63,81.67 119.19,82.12 119.19,85.9 118.85,86.24 v2(118.01,86.24) ; 121.56,80.68 125.22,80.68 138.03,67.87 138.03,60.35 138.15,60.24 138.22,60.24 138.34,60.12 138.34,59.89 138.22,59.77 138.15,59.77 138.03,59.65 138.03,59.43 138.15,59.32 138.24,59.32 138.36,59.2 138.36,58.97 138.24,58.85 138.15,58.85 138.03,58.73 138.03,58.45 138.12,58.35 138.39,58.35 138.57,58.17 138.57,57.92 138.4,57.75 138.21,57.75 v2(138.11,57.85)
  BOTTOM w0.076: v2(118.01,86.24) 118.57,86.81 118.57,88.5 117.76,89.31 117.76,90.42 117.87,90.53 117.87,90.79 117.83,90.89 117.83,91.14 117.87,91.23 117.87,91.44 117.8,91.62 117.8,91.89 UC1.AY27
  BOTTOM w0.127: JDIMM1.232 135.98,54.48 137.44,55.94 137.44,57.17 v2(138.11,57.85)
DDR_A_D57: length 53.8
  IN4 w0.084: v2(138.77,56.65) 138.89,56.54 138.89,55.99 138.76,55.86 138.02,55.86 137.7,56.19 137.7,67.72 125.04,80.38 121.1,80.38 120.06,81.42 119.53,81.42 118.95,82 118.95,84.36 118.34,84.97 v2(118.01,84.97)
  BOTTOM w0.076: v2(118.01,84.97) 117.59,85.39 117.59,88.72 117.26,89.04 117.26,90.37 117.17,90.46 117.17,91.37 117.38,91.58 117.38,91.59 117.41,91.61 117.41,91.83 117.38,91.95 117.38,92.13 117.7,92.45 UC1.AW27
  BOTTOM w0.127: JDIMM1.236 136.98,54.58 138.77,56.38 v2(138.77,56.65)
DDR_A_D58: length 53.3
  IN4 w0.084: v2(138.77,60.46) 138.47,60.46 138.37,60.56 138.37,61.23 138.46,61.31 138.81,61.31 138.89,61.4 138.89,61.69 138.81,61.78 138.46,61.78 138.37,61.86 138.37,62.16 138.46,62.24 138.81,62.24 138.89,62.33 138.89,62.62 138.81,62.71 138.46,62.71 138.37,62.79 138.37,64.87 138.46,64.95 138.86,64.95 138.94,65.03 138.94,65.33 138.86,65.41 138.46,65.41 138.37,65.5 138.37,65.8 138.46,65.88 138.81,65.88 138.89,65.96 138.89,66.25 138.81,66.34 138.46,66.34 138.37,66.43 138.37,66.73 138.46,66.81 138.74,66.81 138.83,66.89 138.83,67.19 138.74,67.27 138.46,67.27 138.37,67.36 138.37,68.01 125.32,81.06 124.41,81.06 123.35,82.13 123.23,82.13 122.9,81.79 122.78,81.79 122.57,82 122.57,82.12 122.9,82.45 122.9,82.57 122.68,82.79 121.94,82.79 121.69,82.54 120.19,82.54 119.84,82.19 v2(119.75,82.19)
  BOTTOM w0.076: v2(119.75,82.19) 120.23,82.68 120.23,86.99 119.77,87.45 119.77,89.23 119.37,89.63 119.37,90.49 119.37,90.49 119.37,90.81 119.29,90.99 119.2,91.17 119.2,91.51 118.93,91.78 UC1.AY25
  BOTTOM w0.127: v2(138.77,60.46) 138.52,60.72 138.29,60.72 138.17,60.59 138.17,59.7 138.04,59.58 137.77,59.58 137.22,60.12 137.22,61.9 JDIMM1.237
DDR_A_D59: length 54.2
  IN4 w0.084: v2(119.73,82.8) 119.98,82.8 120.25,83.08 120.25,83.43 120.33,83.51 120.63,83.51 120.72,83.43 120.72,82.99 120.83,82.88 120.99,82.88 121.24,83.13 122.82,83.13 124.54,81.4 125.41,81.4 126.34,80.47 126.56,80.47 127.09,79.94 127.09,79.72 138.77,68.03 138.77,67.67 138.86,67.58 139.22,67.58 139.44,67.36 139.44,67 139.21,66.76 139.21,66.44 139.44,66.21 139.44,65.95 139.26,65.77 139.26,65.55 139.44,65.37 139.44,64.93 139.28,64.77 139.28,64.5 139.44,64.34 139.44,64.04 139.22,63.81 139.22,63.41 139.44,63.18 139.44,63 139.22,62.77 139.22,62.49 139.44,62.27 139.44,62.09 139.34,61.99 139.34,61.61 139.44,61.5 139.44,61.3 139.22,61.07 139.22,60.77 139.44,60.54 139.44,60.2 139.24,60 139.24,59.88 139.44,59.68 139.44,59.42 139.09,59.07 138.9,59.07 v2(138.77,59.19)
  BOTTOM w0.076: v2(119.73,82.8) 118.76,83.78 118.76,88.65 v4(118.34,89.07) 117.96,89.45 117.96,90.39 118.02,90.44 118.02,90.45 118.03,90.46 118.03,90.81 118,90.92 118,91.11 118.03,91.2 118.03,91.46 118.01,91.53 118.01,92.35 118.29,92.64 UC1.AW25
  BOTTOM w0.127: v2(138.77,59.19) 138.45,58.87 137.32,58.87 136.91,59.28 136.91,59.56 136.23,60.24 JDIMM1.233
DDR_A_D60: length 51.9
  IN4 w0.084: v2(141.47,57.29) 141.86,57.68 141.86,58.44 142.22,58.79 142.22,67.7 139.86,70.05 139.86,70.39 126.36,83.89 125.46,83.89 123.6,85.76 121.81,85.76 120.59,86.98 118.1,86.98 v2(118.01,86.88)
  BOTTOM w0.076: v2(118.01,86.88) 118.37,87.25 118.37,88.46 117.59,89.24 117.59,90.68 UC1.BB27
  BOTTOM w0.127: v2(141.47,57.29) 140.82,56.64 140.82,56.19 139.47,54.84 JDIMM1.246
DDR_A_D61: length 51.8
  IN4 w0.084: v2(141.47,56.02) 142.43,56.98 142.43,58.35 142.58,58.5 142.58,67.8 140.2,70.19 140.2,70.53 126.48,84.25 125.61,84.25 123.77,86.09 121.94,86.09 120.7,87.34 118.82,87.34 v2(118.01,88.15)
  BOTTOM w0.076: UC1.BA27 117.6,91.11 117.34,90.85 117.34,90.53 117.43,90.44 117.43,89.17 118.01,88.59 v2(118.01,88.15)
  BOTTOM w0.127: v2(141.47,56.02) 141.47,55.75 140.47,54.75 JDIMM1.250
DDR_A_D62: length 51.7
  IN4 w0.084: v2(119.78,86.56) 120.44,86.56 120.6,86.4 120.6,86.23 120.39,86.03 120.39,85.86 120.56,85.7 120.72,85.7 120.98,85.95 121.14,85.95 121.67,85.43 121.88,85.43 121.99,85.31 121.99,85.09 122.11,84.97 122.57,84.97 122.69,85.09 122.69,85.31 122.8,85.43 123.04,85.43 123.15,85.31 123.15,85.09 123.27,84.97 123.88,84.97 125.31,83.54 126.25,83.54 139.53,70.25 139.53,69.91 141.33,68.12 141.33,67.84 141.44,67.73 141.7,67.73 141.82,67.61 141.82,67.34 141.7,67.22 141.43,67.22 141.33,67.12 141.33,66.89 141.48,66.74 141.77,66.74 141.89,66.62 141.89,66.28 141.65,66.05 141.65,65.88 141.89,65.64 141.89,58.97 v2(141.47,58.56)
  BOTTOM w0.076: UC1.BA25 118.93,91.19 119.08,91.04 119.14,90.91 119.14,90.91 119.2,90.77 119.2,89.47 119.57,89.1 119.57,87.27 119.78,87.06 v2(119.78,86.56)
  BOTTOM w0.127: v2(141.47,58.56) 141.03,58.56 139.53,60.06 139.53,60.64 139.23,60.95 JDIMM1.245
DDR_A_D63: length 50.7
  IN4 w0.084: v2(141.47,59.83) 141.11,59.83 140.99,59.94 140.99,60.35 141.11,60.46 141.44,60.46 141.55,60.58 141.55,60.81 141.44,60.93 141.11,60.93 140.99,61.05 140.99,61.28 141.11,61.4 141.44,61.4 141.55,61.51 141.55,61.75 141.44,61.86 141.11,61.86 140.99,61.98 140.99,62.21 141.11,62.33 141.44,62.33 141.55,62.45 141.55,62.68 141.44,62.8 141.11,62.8 140.99,62.92 140.99,63.15 141.11,63.27 141.44,63.27 141.55,63.38 141.55,63.62 141.44,63.73 141.11,63.73 140.99,63.85 140.99,64.08 141.11,64.2 141.41,64.2 141.53,64.32 141.53,64.55 141.41,64.67 141.11,64.67 140.99,64.79 140.99,65.02 141.11,65.14 141.41,65.14 141.53,65.25 141.53,65.49 141.41,65.6 141.11,65.6 140.99,65.72 140.99,65.95 141.11,66.07 141.21,66.07 141.33,66.19 141.33,66.42 141.21,66.54 141.11,66.54 140.99,66.65 140.99,67.98 139.2,69.77 139.2,70.12 126.13,83.18 125.14,83.18 123.67,84.65 121.75,84.65 121.11,85.29 120.42,85.29 v2(119.78,85.93)
  BOTTOM w0.076: v2(119.78,85.93) 119.4,86.31 119.4,88.96 119.04,89.33 119.04,90.57 UC1.BB25
  BOTTOM w0.127: v2(141.47,59.83) 141.13,59.83 140.23,60.74 JDIMM1.249
DDR_A_DQS0: length 64.1
  IN4 w0.114: v2(85.42,96.15) 85.3,96.04 85.3,94.8 84.5,94 80.3,94 79.2,92.9 79.2,89.97 79.32,89.85 80.22,89.85 80.51,89.57 80.51,88.94 80.22,88.66 79.32,88.66 79.2,88.54 79.2,87.91 79.28,87.83 80.46,87.83 80.75,87.54 80.75,86.93 80.46,86.63 79.28,86.63 79.2,86.55 79.2,75.8 78.74,75.34 78.74,64.11 78.23,63.59 78.23,60.66 79.39,59.5 79.39,57.97 79.11,57.68 78.65,57.68 78.63,57.66 78.63,57.66 v2(78.56,57.59)
  BOTTOM w0.076: UC1.AM69 93.16,97.16 92.91,97.28 92.62,97.28 92.54,97.24 92.33,97.24 92.22,97.3 92,97.3 91.89,97.24 91.63,97.24 91.55,97.32 90.73,97.32 90.25,96.84 89.36,96.84 88.6,96.09 87.1,96.09 86.73,95.71 86.21,95.71 86.18,95.74 86.16,95.74
  BOTTOM w0.124: v2(85.42,96.15) 85.39,96.12 85.39,95.94 85.59,95.74 86.16,95.74 ; JDIMM1.13 79.22,60.99 79.25,60.97 79.25,59.68 79.42,59.5 79.42,57.91 79.18,57.67 78.64,57.67 v2(78.56,57.59)
DDR_A_DQS1: length 49.6
  IN4 w0.114: v2(83.62,56.62) 83.8,56.44 84.06,56.44 84.17,56.56 84.17,63.71 83.45,64.44 83.45,83.83 89.05,89.43 89.05,89.6 88.94,89.72 88.71,89.72 v2(88.64,89.65)
  BOTTOM w0.076: 87.78,90.75 87.78,90.77 87.81,90.8 87.81,91.52 88.77,92.48 88.77,92.48 90.38,94.09 91.27,94.09 91.43,94.26 91.92,94.26 92.06,94.21 92.16,94.21 92.29,94.26 92.57,94.26 92.65,94.22 92.87,94.22 92.98,94.28 93.01,94.31 93.01,94.47 92.94,94.54 92.81,94.54 UC1.AT70
  BOTTOM w0.124: v2(88.64,89.65) 88.47,89.83 88.22,89.83 87.78,90.26 87.78,90.75 ; v2(83.62,56.62) 83.62,56.49 83.68,56.42 84.12,56.42 84.33,56.22 84.33,54.87 84.47,54.72 JDIMM1.34
DDR_A_DQS2: length 46.2
  IN4 w0.114: v2(90.63,84.48) 90.52,84.58 90.31,84.58 90,84.26 90,83.26 89.58,82.84 88.59,82.84 88.42,82.67 88.42,74.67 88.09,74.34 88.09,65.77 89.22,64.64 89.22,60.13 89.45,59.9 89.45,58.02 89.19,57.77 88.88,57.77 v2(88.75,57.64)
  BOTTOM w0.076: v2(90.63,84.48) 90.63,84.48 90.66,84.51 90.66,85.45 91.16,85.95 91.36,85.95 92.1,86.7 92.1,88.1 92.84,88.83 94.79,88.83 95.66,89.71 95.66,90.4 95.8,90.54 95.8,90.79 95.76,90.89 95.76,91.12 95.81,91.23 95.81,91.44 95.77,91.52 95.77,91.81 95.86,92 95.88,92.03 96.11,92.26 UC1.AY64
  BOTTOM w0.124: JDIMM1.55 89.72,61.08 89.66,61.01 89.66,60.46 89.38,60.18 89.38,58.58 89.52,58.44 89.52,58.03 89.24,57.75 88.86,57.75 v2(88.75,57.64)
DDR_A_DQS3: length 44.9
  IN4 w0.114: v2(93.48,57.84) 93.76,57.56 94.08,57.56 94.19,57.67 94.19,64.21 92.93,65.47 92.93,66.06 92.45,66.54 92.45,79.28 94.97,81.79 94.97,86.25 95.31,86.59 95.96,86.59 v2(96.25,86.88)
  BOTTOM w0.076: v2(96.25,86.88) 96.25,86.73 96.47,86.51 96.64,86.51 96.75,86.62 96.75,87.39 98.64,89.28 98.64,89.66 98.95,89.97 98.95,90.3 98.79,90.46 98.79,90.82 98.84,90.96 98.84,91.07 98.79,91.2 98.79,91.61 98.69,91.71 98.61,91.71 UC1.BA60
  BOTTOM w0.124: JDIMM1.76 94.97,54.59 94.82,54.75 94.82,56.98 94.23,57.57 93.69,57.57 93.48,57.78 v2(93.48,57.84)
DDR_A_DQS4: length 46.9
  IN4 w0.076: v2(110.98,85.49) 110.98,85.66 111.15,85.83 111.48,85.83 111.62,85.69 111.62,80.57 114.09,78.11 114.09,77.43 114.03,77.37 114.03,77.35
  IN4 w0.114: 114.03,77.35 114.03,73.77 118.7,69.09 120.78,69.09 121.18,68.69 121.18,67.95 121.62,67.51 122.41,67.51 123.13,66.79 123.13,62.38 122.96,62.21 122.43,62.21 122.16,61.93 122.16,61.19 122.44,60.91 123.45,60.91 123.88,60.48 123.88,59.59 123.77,59.48 123.5,59.48 123.32,59.65 v2(123.32,59.74)
  BOTTOM w0.076: v2(110.98,85.49) 110.98,85.63 110.74,85.87 110.6,85.87 110.32,86.15 110.32,86.76 110.27,86.81 110.27,87.3 110.32,87.34 110.32,88.59 110.42,88.69 110.42,90.32 110.53,90.43 110.53,90.79 110.48,90.9 110.48,91.12 110.53,91.23 110.53,91.44 110.5,91.52 110.5,91.8 110.54,91.91 110.63,92.05 UC1.AY38
  BOTTOM w0.124: JDIMM1.179 122.72,60.94 122.66,60.88 122.66,59.6 122.79,59.48 123.14,59.48 123.32,59.66 v2(123.32,59.74)
DDR_A_DQS5: length 49.2
  IN4 w0.076: v2(114.58,85.16) 114.38,85.36 114.24,85.36 114.17,85.29 114.17,81.81 118.38,77.61 118.38,77.43 118.44,77.36 118.44,77.35
  IN4 w0.114: v2(128.77,56.55) 128.85,56.63 129.32,56.63 129.64,56.95 129.64,58.23 129.17,58.7 129.17,67.11 122.45,73.83 120.44,73.83 118.44,75.84 118.44,77.35
  BOTTOM w0.076: UC1.BA34 113.28,91.87 113.35,91.93 113.43,91.93 113.47,91.91 113.52,91.83 113.55,91.77 113.55,91.55 113.52,91.47 113.52,91.2 113.57,91.07 113.57,90.96 113.57,90.94 113.51,90.83 113.51,89.71 113.72,89.5 113.72,85.82 114.05,85.49 114.25,85.49 v2(114.58,85.16)
  BOTTOM w0.124: v2(128.77,56.55) 128.77,56.61 128.57,56.81 128.35,56.81 128.25,56.71 128.25,55.3 127.84,54.89 127.84,54.67 127.98,54.54 JDIMM1.200
DDR_A_DQS6: length 49.7
  IN4 w0.076: 122.11,77.89 122.09,77.89 122.03,77.96 121.48,77.96 119.61,79.82 119.27,79.82 117.03,82.06 117.03,84.16 116.96,84.23 116.96,85.22 117.03,85.29 117.03,85.75 116.87,85.91 116.53,85.91 116.42,85.79 v2(116.42,85.61)
  IN4 w0.114: 122.11,77.89 123.89,77.89 134.43,67.36 134.43,66.76 133.94,66.28 133.94,65.76 134.44,65.26 134.44,64.88 134.14,64.58 134.14,64.08 134.54,63.67 134.54,63.2 134.93,62.81 134.93,58.83 134.81,58.72 134.43,58.72 134.21,58.94 v2(134.21,59)
  BOTTOM w0.076: v2(116.42,85.61) 116.13,85.9 116.05,85.9 115.85,86.1 115.85,89.25 115.48,89.61 115.48,90.15 115.51,90.18 115.51,90.79 115.46,90.9 115.46,91.07 arc(115.47,91.12) 115.48,91.16 115.5,91.2 arc(115.51,91.23) 115.51,91.26 115.51,91.8 115.81,92.1 UC1.AY30
  BOTTOM w0.124: v2(134.21,59) 134.01,58.8 133.83,58.8 133.7,58.92 133.7,59.84 133.05,60.5 133.05,60.97 133.23,61.15 JDIMM1.221
DDR_A_DQS7: length 53
  IN4 w0.114: v2(119.78,84.02) 120.13,84.37 120.73,84.37 121.36,83.74 123.07,83.74 124.8,82.01 125.67,82.01 126.52,81.16 126.81,81.16 127.77,80.19 127.77,79.9 140.06,67.62 140.06,59.14 139.21,58.29 139.21,57.51 139.49,57.23 139.99,57.23 140.19,57.03 v2(140.19,56.96)
  BOTTOM w0.076: UC1.BA26 118.26,91.87 118.32,91.93 118.41,91.93 118.45,91.91 118.5,91.83 118.53,91.77 118.53,91.55 118.49,91.47 118.49,91.19 118.54,91.09 118.54,91.08 118.54,90.94 118.54,90.93 118.49,90.83 118.49,90.43 118.7,90.22 118.7,89.04 118.92,88.82 118.92,84.52 119.18,84.25 119.55,84.25 v2(119.78,84.02)
  BOTTOM w0.124: v2(140.19,56.96) 139.95,57.21 139.77,57.21 139.64,57.08 139.64,56.04 138.35,54.74 138.35,54.59 138.47,54.47 JDIMM1.242
DDR_A_DQS#0: length 64.1
  IN4 w0.114: v2(78.59,58.18) 78.59,58.11 78.73,57.97 78.99,57.97 79.11,58.09 79.11,59.38 77.95,60.54 77.95,63.71 78.46,64.22 78.46,75.46 78.92,75.92 78.92,86.67 79.16,86.92 80.34,86.92 80.46,87.05 80.46,87.42 80.34,87.54 79.16,87.54 78.92,87.79 78.92,88.66 79.2,88.95 80.1,88.95 80.22,89.06 80.22,89.45 80.1,89.57 79.2,89.57 78.92,89.85 78.92,93.02 80.19,94.29 84.38,94.29 85.02,94.92 85.02,96.03 84.9,96.15 v2(84.78,96.15)
  BOTTOM w0.076: 86.16,95.52 86.18,95.52 86.21,95.55 86.79,95.55 87.17,95.92 88.67,95.92 89.43,96.68 90.32,96.68 90.8,97.16 91.48,97.16 91.56,97.08 91.92,97.08 92.06,97.13 92.16,97.13 92.29,97.08 92.57,97.08 92.65,97.11 92.87,97.11 92.98,97.06 93.01,97 93.01,96.92 92.94,96.84 UC1.AM70
  BOTTOM w0.124: v2(84.78,96.15) 84.86,96.15 85.49,95.52 86.16,95.52 ; v2(78.59,58.18) 78.87,57.89 79.08,57.89 79.2,58.01 79.2,59.41 79.02,59.59 79.02,60.8 78.89,60.92 78.84,60.92 78.73,61.03 JDIMM1.11
DDR_A_DQS#1: length 49.6
  IN4 w0.114: v2(83.62,55.99) 83.63,55.99 83.8,56.16 84.18,56.16 84.46,56.44 84.46,63.83 83.74,64.56 83.74,83.71 89.34,89.31 89.34,89.72 89.06,90 88.87,90 v2(88.64,90.23)
  BOTTOM w0.076: 88.01,90.75 88.01,90.77 87.98,90.8 87.98,91.45 88.89,92.36 90.46,93.93 91.34,93.93 91.5,94.09 91.89,94.09 92,94.04 92.22,94.04 92.33,94.09 92.54,94.09 92.62,94.06 92.91,94.06 93.1,94.15 93.1,94.15 93.41,94.46 UC1.AT69
  BOTTOM w0.124: JDIMM1.32 83.97,54.74 84.1,54.87 84.1,56.13 84.03,56.2 83.83,56.2 v2(83.62,55.99) ; 88.01,90.75 88.01,90.35 88.31,90.05 88.47,90.05 v2(88.64,90.23)
DDR_A_DQS#2: length 46.2
  IN4 w0.114: v2(88.75,58.22) 88.91,58.05 89.07,58.05 89.16,58.14 89.16,59.78 88.93,60.01 88.93,64.52 87.8,65.66 87.8,74.46 88.13,74.79 88.13,82.79 88.47,83.13 89.46,83.13 89.71,83.38 89.71,84.38 90.19,84.87 90.97,84.87 v2(91.18,84.65)
  BOTTOM w0.076: UC1.BA64 96.21,91.68 96.13,91.76 96.01,91.71 95.94,91.63 95.94,91.55 95.98,91.47 95.98,91.19 95.93,91.08 95.93,90.93 95.97,90.83 95.97,90.47 95.83,90.33 95.83,89.64 94.86,88.66 92.91,88.66 92.27,88.03 92.27,86.63 91.43,85.78 91.23,85.78 90.83,85.38 90.83,84.9 91.07,84.65 v2(91.18,84.65)
  BOTTOM w0.124: JDIMM1.53 89.22,61 89.29,60.94 89.34,60.94 89.43,60.84 89.43,60.55 89.31,60.43 89.15,60.27 89.15,58.48 89.29,58.35 89.29,58.12 89.15,57.98 88.99,57.98 v2(88.75,58.22)
DDR_A_DQS#3: length 44.9
  IN4 w0.114: v2(93.48,57.2) 93.55,57.27 94.19,57.27 94.48,57.55 94.48,64.33 93.22,65.59 93.22,66.18 92.74,66.66 92.74,79.16 95.25,81.68 95.25,86.13 95.43,86.31 96.17,86.31 v2(96.25,86.23)
  BOTTOM w0.076: v2(96.25,86.23) 96.36,86.35 96.71,86.35 96.91,86.55 96.91,87.32 98.8,89.21 98.8,89.59 99.12,89.9 99.12,90.37 98.96,90.53 98.96,90.79 99.01,90.9 99.01,91.12 98.96,91.23 98.96,91.68 98.66,91.98 UC1.AY60
  BOTTOM w0.124: JDIMM1.74 94.47,54.63 94.59,54.75 94.59,56.89 94.14,57.34 93.63,57.34 v2(93.48,57.2)
DDR_A_DQS#4: length 46.9
  IN4 w0.076: 114.32,77.35 114.32,77.37 114.25,77.43 114.25,78.17 111.79,80.64 111.79,85.76 111.55,86 111.12,86 v2(110.98,86.14)
  IN4 w0.114: 114.32,77.35 114.32,73.89 118.82,69.38 120.9,69.38 121.47,68.81 121.47,68.07 121.74,67.8 122.53,67.8 123.42,66.91 123.42,62.26 123.08,61.92 122.55,61.92 122.44,61.81 122.44,61.31 122.56,61.2 123.57,61.2 124.17,60.6 124.17,59.47 123.89,59.19 123.41,59.19 v2(123.32,59.1)
  BOTTOM w0.076: UC1.BA38 110.93,91.68 arc(110.8,91.81) 110.66,91.68 110.66,91.57 arc(110.67,91.55) 110.67,91.53 110.68,91.5 arc(110.69,91.47) 110.7,91.44 110.7,91.2 110.64,91.07 110.64,90.96 110.7,90.82 110.7,90.79 110.7,90.36 110.59,90.25 110.59,88.62 110.49,88.52 v4(110.49,87.03) 110.49,86.22 110.67,86.04 110.87,86.04 v2(110.98,86.14)
  BOTTOM w0.124: JDIMM1.177 122.23,61.13 122.44,60.91 122.44,59.51 122.69,59.25 123.17,59.25 v2(123.32,59.1)
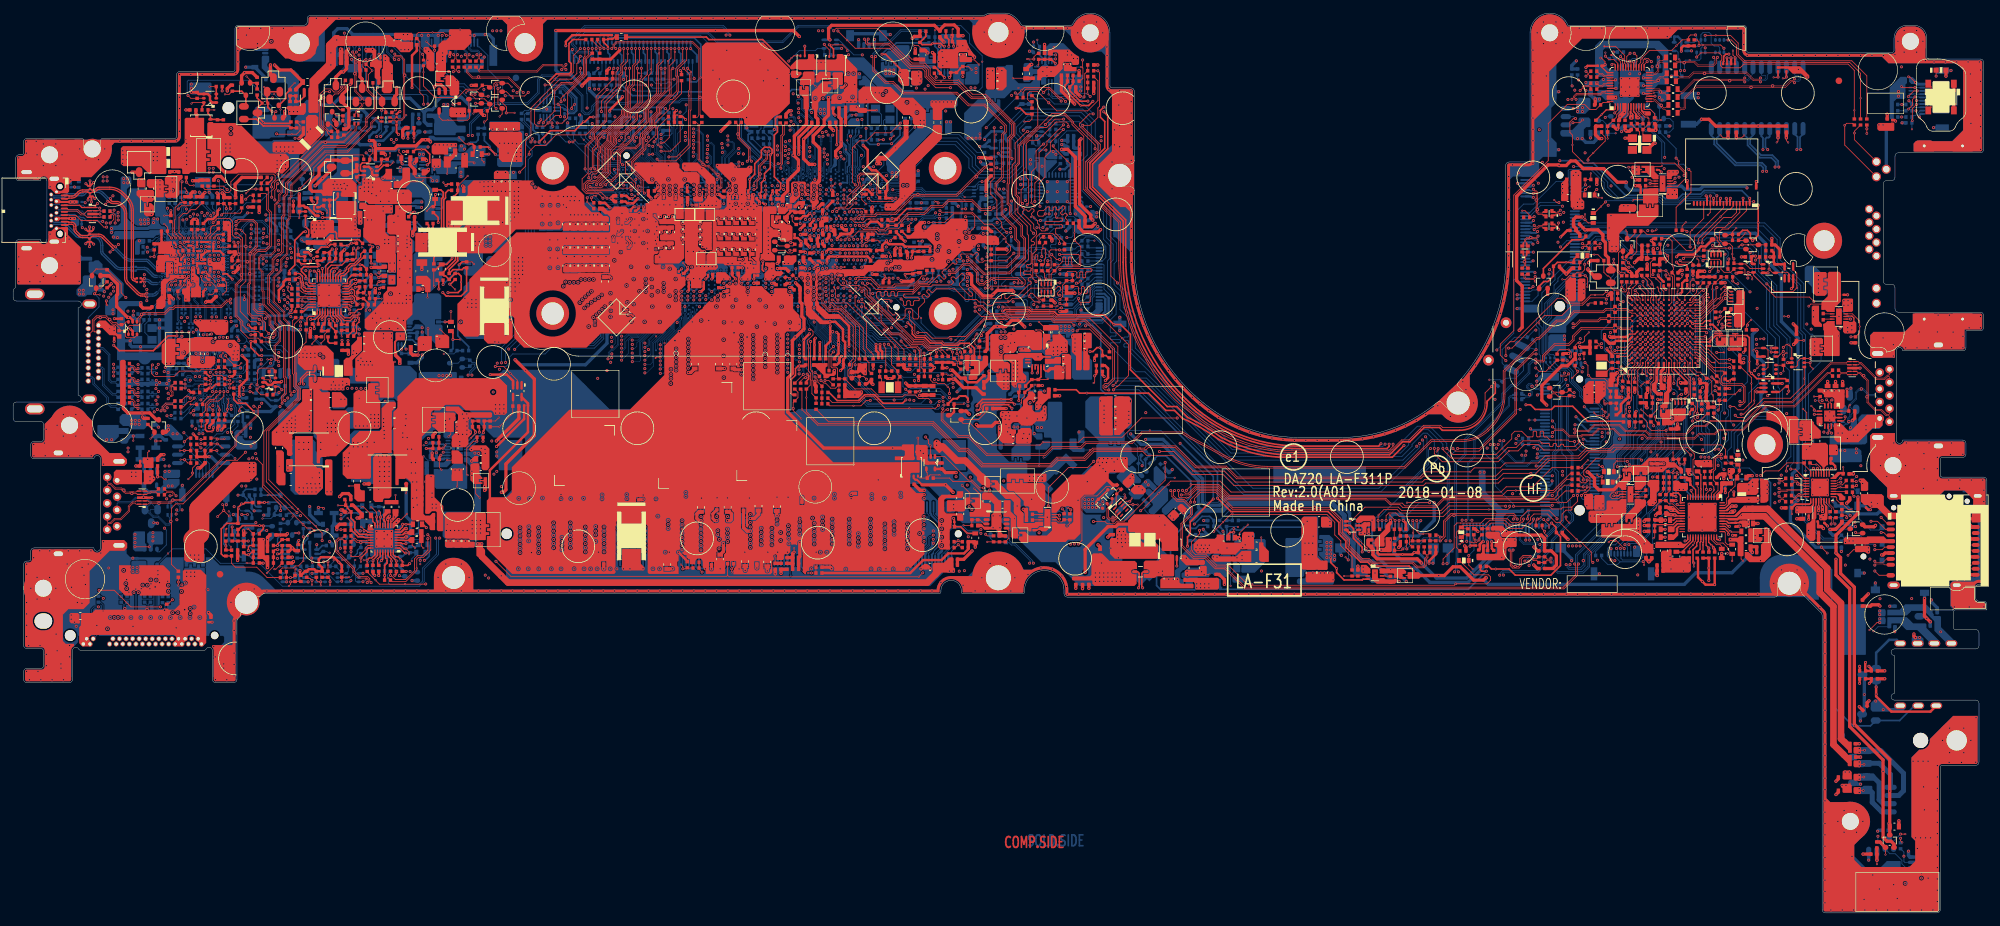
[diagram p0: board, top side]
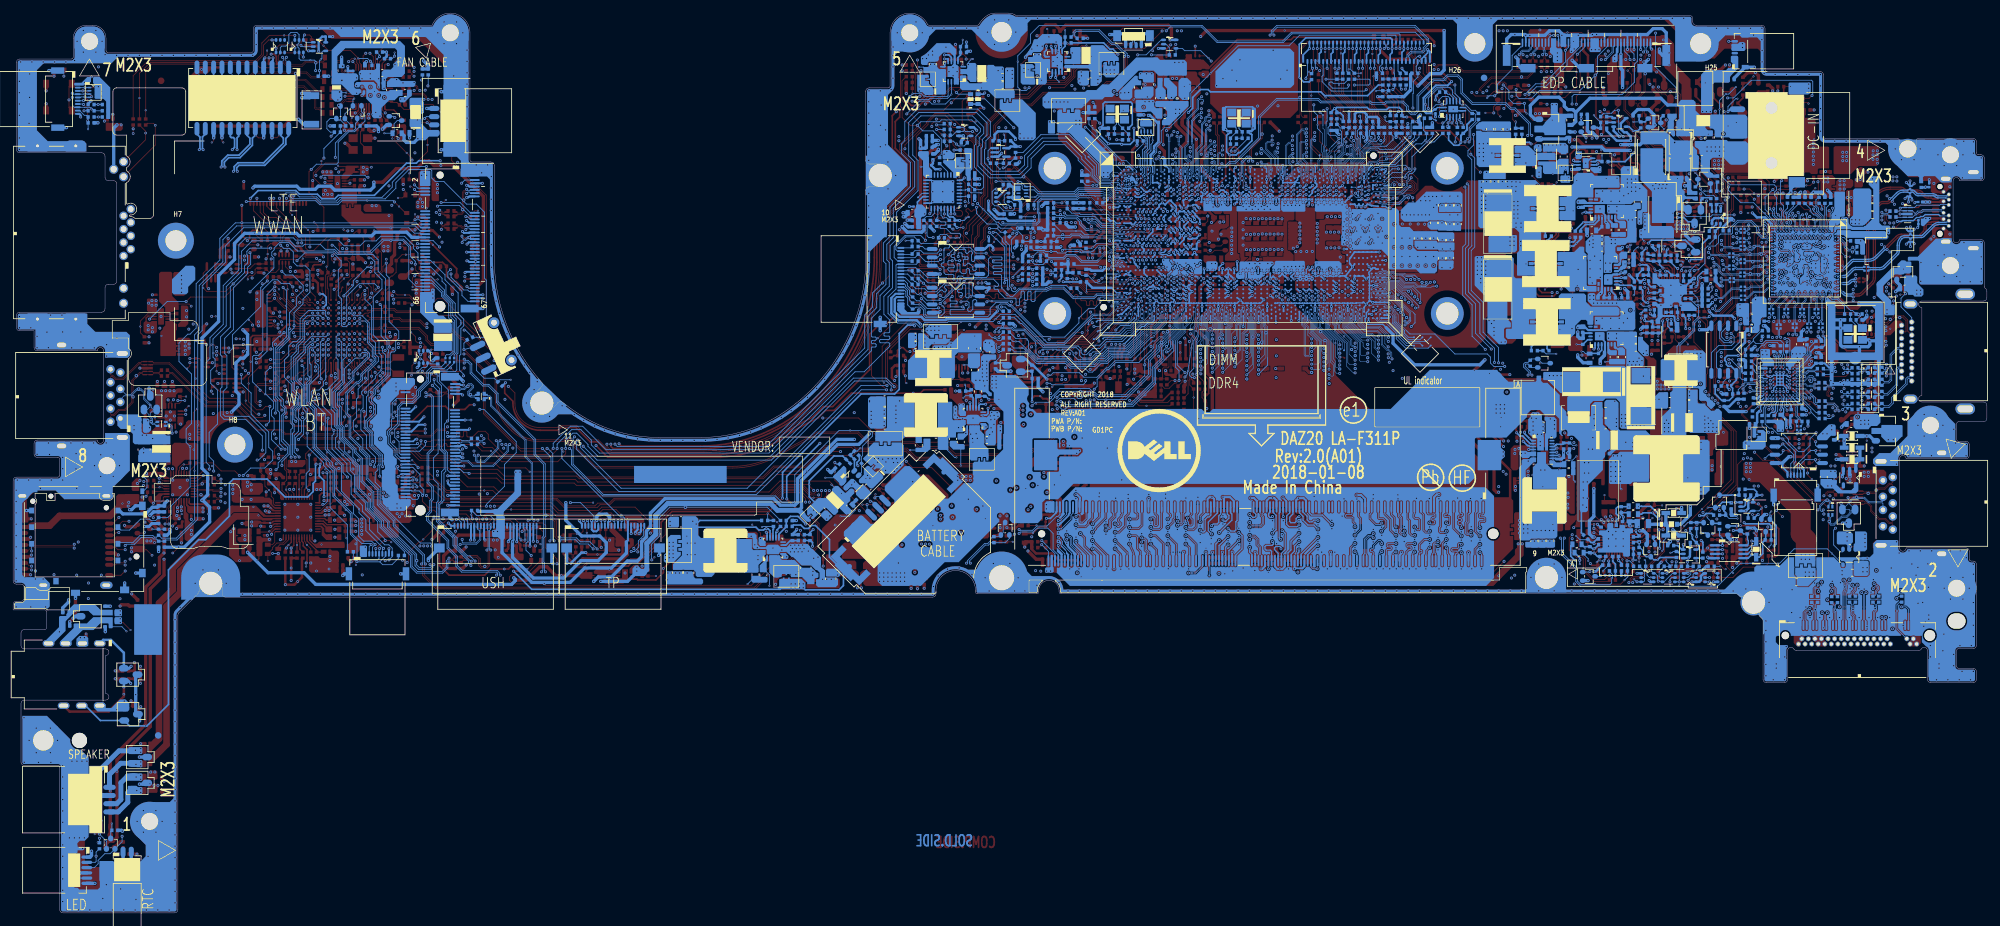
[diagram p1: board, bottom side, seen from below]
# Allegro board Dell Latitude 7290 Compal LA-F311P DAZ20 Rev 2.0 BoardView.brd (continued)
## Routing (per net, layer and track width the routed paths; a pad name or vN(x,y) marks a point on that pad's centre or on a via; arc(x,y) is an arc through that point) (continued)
DDR_A_DQS#5: length 49.2
  IN4 w0.076: 118.15,77.35 118.15,77.37 118.21,77.43 118.21,77.54 114,81.75 114,85.35 114.18,85.53 114.31,85.53 v2(114.58,85.8)
  IN4 w0.114: v2(128.77,57.18) 129.04,56.92 129.2,56.92 129.35,57.06 129.35,58.11 128.88,58.58 128.88,67 122.33,73.54 120.32,73.54 118.15,75.72 118.15,77.35
  BOTTOM w0.076: v2(114.58,85.8) 114.44,85.66 114.12,85.66 113.89,85.89 113.89,89.56 113.68,89.78 113.68,90.79 113.73,90.9 113.73,91.12 113.68,91.23 113.68,91.44 113.72,91.52 113.72,91.8 113.67,91.91 113.59,92.05 113.46,92.1 113.4,92.1 113.38,92.12 UC1.AY34
  BOTTOM w0.124: JDIMM1.198 127.47,54.53 127.47,54.53 127.62,54.67 127.62,54.99 127.81,55.18 128.02,55.39 128.02,56.81 128.25,57.04 128.63,57.04 v2(128.77,57.18)
DDR_A_DQS#6: length 49.8
  IN4 w0.076: 122.11,78.18 122.09,78.18 122.03,78.12 121.54,78.12 119.68,79.99 119.33,79.99 117.19,82.13 117.19,84.23 117.12,84.3 117.12,85.15 117.19,85.22 117.19,85.81 116.94,86.07 116.59,86.07 v2(116.42,86.24)
  IN4 w0.114: 122.11,78.18 124.01,78.18 134.72,67.48 134.72,66.64 134.23,66.16 134.23,65.88 134.73,65.38 134.73,64.76 134.42,64.46 134.42,64.2 134.83,63.79 134.83,63.32 135.21,62.93 135.21,58.71 134.93,58.43 134.27,58.43 v2(134.21,58.37)
  BOTTOM w0.076: v2(116.42,86.24) 116.41,86.24 116.26,86.09 116.09,86.09 116.02,86.17 116.02,89.31 115.65,89.68 115.65,90.08 115.68,90.11 115.68,90.83 115.63,90.94 115.63,90.96 115.63,91.07 115.68,91.2 115.68,91.56 115.78,91.66 UC1.BA30
  BOTTOM w0.124: v2(134.21,58.37) 134.07,58.5 134.04,58.5 133.97,58.57 133.74,58.57 133.48,58.83 133.48,59.75 132.82,60.41 132.82,61.04 132.72,61.14 JDIMM1.219
DDR_A_DQS#7: length 53
  IN4 w0.114: v2(119.78,84.66) 120.85,84.66 121.48,84.03 123.19,84.03 124.92,82.3 125.78,82.3 126.64,81.45 126.93,81.45 128.06,80.31 128.06,80.02 140.34,67.74 140.34,59.02 139.49,58.17 139.49,57.63 139.61,57.52 140.11,57.52 v2(140.19,57.6)
  BOTTOM w0.076: v2(119.78,84.66) 119.55,84.42 119.25,84.42 119.09,84.59 119.09,87.49 119.14,87.54 v4(119.14,87.82) 119.14,88.13 119.1,88.17 119.1,88.89 118.87,89.11 118.87,90.29 118.66,90.5 118.66,90.79 118.7,90.86 118.71,90.91 118.71,91.11 118.69,91.16 118.66,91.23 118.66,91.44 118.7,91.52 118.7,91.8 118.65,91.91 118.57,92.05 118.44,92.1 118.38,92.1 118.36,92.12 UC1.AY26
  BOTTOM w0.124: JDIMM1.240 137.98,54.46 138.12,54.6 138.12,54.83 138.81,55.52 139.42,56.13 139.42,57.18 139.68,57.43 140.03,57.43 v2(140.19,57.6)
DDR_A_MA0: length 43.1
  IN4 w0.076: v2(102.87,87.51) 104.19,86.19 104.19,77.35
  IN4 w0.132: 104.19,77.35 104.19,69.62 109.93,63.88 109.93,57.88 112.09,55.72 v2(112.31,55.72)
  BOTTOM w0.076: v2(102.87,87.51) 103.46,88.1 103.46,89.21 104.04,89.79 104.04,90.42 103.91,90.54 103.91,90.79 103.94,90.87 103.95,90.88 103.97,90.91 103.97,91.05 103.9,91.28 103.9,91.41 103.98,91.63 104.18,91.83 UC1.AY50
  BOTTOM w0.196: v2(112.31,55.72) 112.31,55 111.97,54.67 JDIMM1.144
DDR_A_MA1: length 43.2
  IN4 w0.076: v2(102.87,86.88) 103.27,86.88 103.86,86.29 103.86,80.27 103.73,80.14 103.73,77.39
  IN4 w0.132: v2(108.83,60.43) 108.83,60.41 109.02,60.22 109.29,60.22 109.47,60.4 109.47,61.09 109.29,61.27 108.79,61.27 108.61,61.45 108.61,61.82 108.79,62 109.29,62 109.47,62.18 109.47,62.63 109.27,62.83 108.57,62.83 108.39,63.01 108.39,63.46 108.99,64.06 108.99,64.17 103.73,69.42 103.73,77.39
  BOTTOM w0.076: v2(102.87,86.88) 102.87,86.75 103.22,86.39 103.22,85.08 103.3,85 103.76,85 103.85,85.09 103.85,89.35 104.26,89.77 104.26,90.6 UC1.BB50
  BOTTOM w0.196: v2(108.83,60.43) 108.96,60.3 109.22,60.3 109.43,60.51 109.43,60.89 109.22,61.09 JDIMM1.133
DDR_A_MA2: length 45.3
  IN4 w0.076: 103.27,77.35 103.27,80.4 103.48,80.6 103.48,85 v2(102.87,85.61)
  IN4 w0.132: v2(108.86,56.63) 109.34,57.1 109.34,59.1 109.15,59.28 108.33,59.28 108.14,59.47 108.14,62.5 107.92,62.72 107.92,64.58 103.27,69.23 103.27,77.35
  BOTTOM w0.076: UC1.AY51 103.78,92.08 103.78,91.58 103.73,91.42 103.73,91.28 103.79,91.06 103.79,90.94 103.75,90.83 103.75,90.48 103.87,90.35 103.87,89.91 103.29,89.33 103.29,88.44 102.06,87.2 102.06,86.42 v2(102.87,85.61)
  BOTTOM w0.196: JDIMM1.132 108.97,55.12 109.16,55.31 109.81,55.31 109.99,55.49 109.99,55.86 109.81,56.04 108.9,56.04 108.72,56.22 108.72,56.48 v2(108.86,56.63)
DDR_A_MA3: length 43.9
  IN4 w0.076: v2(102.87,84.97) 103.25,84.59 103.25,81.12 102.79,80.66 102.79,77.35
  IN4 w0.132: v2(108.83,57.89) 108.83,57.89 108.33,57.39 107.99,57.39 107.81,57.57 107.81,59.15 107.68,59.28 107.68,62.22 106.8,63.1 106.8,63.48 107.26,63.94 107.26,64.59 102.79,69.06 102.79,77.35
  BOTTOM w0.076: UC1.BA50 104.43,91.08 104.43,89.67 104.01,89.25 104.01,85 103.81,84.8 103.05,84.8 v2(102.87,84.97)
  BOTTOM w0.196: JDIMM1.131 108.72,61.06 108.28,60.62 108.28,58.45 108.83,57.9 v2(108.83,57.89)
DDR_A_MA4: length 44.2
  IN4 w0.076: v2(101,85.32) 101.44,85.32 101.62,85.14 101.62,82.31 101.14,81.82 101.14,78.67 100.73,78.27 100.73,77.35
  IN4 w0.132: 100.73,77.35 100.73,76.56 99.69,75.52 99.69,69.94 100.36,69.28 100.36,68.88 104.43,64.8 104.43,62.74 105.55,61.62 105.55,57.12 107.15,55.52 v2(107.54,55.52)
  BOTTOM w0.076: UC1.BB52 102.75,90.59 102.75,88.63 101.36,87.24 101.36,85.69 v2(101,85.32)
  BOTTOM w0.196: v2(107.54,55.52) 107.54,55.68 107.73,55.86 108.35,55.86 108.53,55.68 108.53,55.39 107.97,54.84 JDIMM1.128
DDR_A_MA5: length 46.3
  IN4 w0.076: v2(102.87,83.68) 102.31,83.68 102.06,83.43 102.06,78.53 101.7,78.17 101.7,77.35
  IN4 w0.132: v2(107.36,58.28) 107.28,58.2 106.66,58.2 106.47,58.39 106.47,58.71 106.58,58.81 106.73,58.81 106.93,59.02 106.93,59.29 106.75,59.47 106.66,59.47 106.47,59.66 106.47,62.06 105.88,62.65 105.88,64.66 102.33,68.21 102.33,68.21 101.81,68.73 101.81,69.88 101.6,70.09 100.86,70.09 100.64,70.31 100.64,70.99 100.87,71.22 100.87,71.72 100.64,71.95 100.64,72.45 100.87,72.68 100.87,73.18 100.64,73.41 100.64,73.91 100.87,74.14 100.87,74.65 100.64,74.87 100.64,75.16 101.7,76.22 101.7,77.35
  BOTTOM w0.076: UC1.BA51 103.29,91.44 103.29,91.21 103.29,91.2 103.28,91.2 103.28,91.2 103.25,91.11 103.25,90.91 103.28,90.82 103.28,90.46 103.09,90.26 103.09,88.49 101.71,87.11 101.71,83.88 101.9,83.68 v2(102.87,83.68)
  BOTTOM w0.196: v2(107.36,58.28) 107.31,58.28 106.9,57.88 106.9,55.39 107.47,54.82 JDIMM1.126
DDR_A_MA6: length 44.7
  IN4 w0.076: v2(101.01,86.02) 101.88,85.15 101.88,82.03 101.6,81.75 101.6,78.5 101.22,78.12 101.22,77.35
  IN4 w0.132: 101.22,77.35 101.22,76.39 100.18,75.35 100.18,70.11 100.82,69.47 100.82,69.07 105.36,64.53 105.36,62.49 106.01,61.84 106.01,57.98 106.75,57.25 107.3,57.25 v2(107.59,56.96)
  BOTTOM w0.076: v2(101.01,86.02) 101.01,87.12 102.59,88.69 102.59,91.07 UC1.BA52
  BOTTOM w0.196: v2(107.59,56.96) 107.82,57.18 107.82,60.95 107.72,61.04 JDIMM1.127
DDR_A_MA7: length 46
  IN4 w0.076: v2(101.01,84.02) 100.76,84.02 100.64,83.9 100.64,82.74 100.37,82.48 100.06,82.48 99.46,81.88 99.46,80.89 98.26,79.69 98.26,77.35
  IN4 w0.132: v2(104.79,57.89) 104.37,57.47 104.05,57.47 103.87,57.66 103.87,61.34 103.04,62.16 103.04,64.23 98.97,68.3 98.97,68.7 98.26,69.42 98.26,77.35
  BOTTOM w0.076: v2(101.01,84.02) 100.61,84.41 100.61,87.06 v4(100.83,87.27) 102.42,88.86 102.42,91.37 102.63,91.58 102.63,92.24 UC1.AW52
  BOTTOM w0.196: JDIMM1.122 106.47,54.9 106.02,55.36 106.02,56.67 v2(104.79,57.89)
DDR_A_MA8: length 45
  IN4 w0.076: 102.18,77.35 102.18,78.09 102.34,78.24 102.34,83.17 102.44,83.27 102.77,83.27 102.87,83.18 v2(102.87,83.04)
  IN4 w0.132: 102.18,77.35 102.18,75.76 101.98,75.56 101.63,75.56 101.43,75.35 101.43,74.99 101.61,74.8 102.14,74.8 102.32,74.62 102.32,74.25 102.14,74.07 101.43,74.07 101.27,73.91 101.27,73.54 101.46,73.36 102.11,73.36 102.29,73.18 102.29,72.89 102.11,72.71 101.45,72.71 101.26,72.53 101.26,72.16 101.45,71.98 102.09,71.98 102.27,71.8 102.27,71.43 102.11,71.27 101.5,71.27 101.31,71.09 101.31,70.73 101.47,70.57 102.06,70.57 102.27,70.36 102.27,68.92 106.8,64.39 106.8,64.13 106.34,63.67 106.34,62.88 107.22,62 107.22,61.61 106.98,61.37 106.98,60.93 107.2,60.7 107.2,60.44 v2(107.19,60.43)
  BOTTOM w0.076: UC1.AY52 103.18,91.99 103.26,91.91 103.26,91.69 103.15,91.59 103.15,91.58 103.12,91.55 103.12,91.23 103.08,91.14 103.08,90.88 103.12,90.79 103.12,90.53 102.92,90.33 102.92,88.56 101.54,87.18 101.54,83 101.65,82.89 102.72,82.89 v2(102.87,83.04)
  BOTTOM w0.196: v2(107.19,60.43) 107.22,60.47 JDIMM1.125
DDR_A_MA9: length 43.5
  IN4 w0.076: 99.18,79.9 99.18,80.04 99.74,80.61 99.74,81.88 99.97,82.1 v2(100.22,82.1)
  IN4 w0.132: v2(104.79,59.16) 104.51,59.16 104.33,59.35 104.33,61.53 103.5,62.36 103.5,64.42 99.43,68.49 99.43,68.9 98.73,69.6 98.73,78.6 98.95,78.82 99.89,78.82 100.07,79 100.07,79.37 99.89,79.55 99.36,79.55 99.18,79.74 99.18,79.9
  BOTTOM w0.076: v2(100.22,82.1) 99.97,81.85 99.64,81.85 99.57,81.93 99.57,83.55 99.99,83.98 99.99,87.37 101.93,89.3 101.93,90.34 101.82,90.44 UC1.BB54
  BOTTOM w0.196: v2(104.79,59.16) 104.79,59.16 105.07,58.88 106.3,58.88 106.68,59.27 106.68,60.53 106.22,60.99 JDIMM1.121
DDR_A_MA10: length 46.2
  IN4 w0.076: v2(103.69,94.04) 103.31,93.66 103.31,92.74 104.34,91.71 104.34,89.85 106.4,87.79 106.4,79.86 107.57,78.69 107.57,78.46
  IN4 w0.132: v2(113.97,58.02) 113.88,58.02 113.52,58.38 113.52,65.19 107.57,71.15 107.57,78.46
  BOTTOM w0.076: UC1.AT50 104.15,94.41 103.69,94.07 v2(103.69,94.04)
  BOTTOM w0.196: JDIMM1.146 114.48,54.5 113.47,55.51 113.47,57.52 v2(113.97,58.02)
DDR_A_MA11: length 44.7
  IN4 w0.076: 97.79,77.35 97.79,79.81 99.2,81.21 99.2,81.89 v2(100.22,82.91)
  IN4 w0.132: v2(104.79,56.62) 104.79,56.62 104.03,55.86 103.59,55.86 103.41,56.04 103.41,61.14 102.04,62.51 102.04,64.58 98.51,68.11 98.51,68.51 97.79,69.23 97.79,77.35
  BOTTOM w0.076: UC1.BA54 101.82,91.12 102.09,90.86 102.09,89.21 v4(101.51,88.62) 100.22,87.34 100.22,82.9 v2(100.22,82.91)
  BOTTOM w0.196: v2(104.79,56.62) 105.5,55.92 105.5,55.13 105.97,54.65 JDIMM1.120
DDR_A_MA12: length 45
  IN4 w0.076: v2(101.01,83.37) 101.38,83 101.38,82.54 100.67,81.83 100.67,78.82 100.49,78.64 100.49,78.61
  IN4 w0.132: 100.49,78.61 100.21,78.33 99.24,78.33 99.06,78.14 99.06,77.78 99.24,77.6 100.06,77.6 100.24,77.41 100.24,77.15 100.01,76.92 99.36,76.92 99.21,76.77 99.21,69.77 99.9,69.09 99.9,68.68 103.97,64.61 103.97,62.55 105.09,61.43 105.09,60.61 104.9,60.42 v2(104.79,60.42)
  BOTTOM w0.076: v2(101.01,83.37) 100.9,83.37 100.39,83.88 100.39,87.15 102.26,89.02 102.26,91.34 102.03,91.56 102.03,92.23 101.95,92.32 101.43,92.32 101.33,92.42 101.33,92.56 101.4,92.64 UC1.AW54
  BOTTOM w0.196: v2(104.79,60.42) 104.94,60.42 105.24,60.12 105.24,59.68 105.42,59.49 106.02,59.49 106.21,59.69 106.21,60.34 105.72,60.83 JDIMM1.119
DDR_A_MA13: length 48.1
  IN4 w0.076: v2(105.52,93.52) 105.52,93.2 107.64,91.09 107.64,81.05 109.88,78.81 109.88,78.41
  IN4 w0.132: v2(116.94,56.78) 116.94,56.07 116.76,55.89 116.33,55.89 116.05,56.17 116.05,58.32 116.88,59.15 116.88,60.7 115.88,61.7 115.88,66.12 109.88,72.12 109.88,78.41
  BOTTOM w0.076: UC1.AU46 105.7,93.52 v2(105.52,93.52)
  BOTTOM w0.196: JDIMM1.158 117.47,56.24 v2(116.94,56.78)
DDR_A_MA14: length 44.7
  IN4 w0.076: v2(105.52,94.1) 105.23,94.1 105.15,94.03 105.15,93.2 107.39,90.97 107.39,80.8 109.42,78.77 109.42,78.59
  IN4 w0.132: v2(116.39,59.93) 116.39,59.92 115.99,59.53 115.69,59.53 115.42,59.81 115.42,60.25 115.6,60.43 115.76,60.43 115.94,60.61 115.94,60.98 115.76,61.16 115.6,61.16 115.42,61.34 115.42,65.93 109.42,71.93 109.42,78.59
  BOTTOM w0.076: v2(105.52,94.1) 105.52,94.05 105.58,93.99 105.78,93.99 106.04,94.26 106.04,94.39 UC1.AT46
  BOTTOM w0.196: v2(116.39,59.93) 116.39,59.9 116.2,59.71 115.94,59.71 115.48,60.18 115.48,60.59 115.72,60.83 JDIMM1.151
DDR_A_MA15: length 45.6
  IN4 w0.076: v2(104.61,93.47) 104.61,93.06 105.48,92.19 105.48,89.87 106.91,88.45 106.91,80.36 108.49,78.78 108.49,78.49
  IN4 w0.132: 108.49,78.49 108.49,71.53 114.48,65.55 114.48,59.44 115.1,58.82 115.1,57.59 115.3,57.39 v2(115.6,57.39)
  BOTTOM w0.076: v2(104.61,93.47) UC1.AU48
  BOTTOM w0.196: JDIMM1.156 116.98,56.01 115.6,57.38 v2(115.6,57.39)
DDR_A_MA16: length 45.4
  IN4 w0.076: 108.03,78.52 108.03,78.75 106.65,80.12 106.65,88.35 105.26,89.75 105.26,91.15 103.98,92.42 103.98,93.17 v2(103.69,93.46)
  IN4 w0.132: v2(115.6,56.12) 115.59,56.12 114.47,57.24 114.47,58.79 113.95,59.31 113.95,65.43 108.03,71.34 108.03,78.52
  BOTTOM w0.076: UC1.AU50 103.69,93.47 v2(103.69,93.46)
  BOTTOM w0.196: JDIMM1.152 115.97,55.74 v2(115.6,56.12)
DDR_A_ODT0: length 50
  IN4 w0.076: 110.8,78.29 110.8,78.75 108.74,80.82 108.74,91.48 106.91,93.3 106.91,93.75 v2(107.33,94.17)
  IN4 w0.132: 110.8,78.29 110.8,72.51 117.28,66.03 117.28,63.11 117.47,62.93 118.64,62.93 118.82,62.74 118.82,62.38 118.64,62.2 117.47,62.2 117.28,62.01 117.28,61.61 117.6,61.28 118.64,61.28 118.82,61.1 118.82,60.61 118.55,60.34 117.99,60.34 117.81,60.15 117.81,59.34 v2(118.11,59.04)
  BOTTOM w0.076: v2(107.33,94.17) 107.53,94.37 107.53,94.92 107.42,95.03 107.21,95.03 106.89,94.71 UC1.AT45
  BOTTOM w0.196: JDIMM1.155 116.72,60.83 117.02,60.53 117.02,59.55 117.27,59.3 117.85,59.3 v2(118.11,59.04)
DDR_A_ODT1: length 52.5
  IN4 w0.076: v2(108.26,94.04) 108.72,93.58 109.39,93.58 111.8,91.17 111.8,90.12 110.97,89.29 109.9,89.29 109.66,89.06 109.66,80.68 111.77,78.57 111.77,78.31
  IN4 w0.132: v2(119.85,58.37) 119.38,57.9 119.19,57.9 119.05,58.05 119.05,59.53 119.75,60.23 119.75,64.79 119.6,64.94 119.24,64.94 119.12,64.83 119.12,64.48 118.94,64.3 118.57,64.3 118.39,64.48 118.39,66.23 111.77,72.85 111.77,78.31
  BOTTOM w0.102: UC1.AT43 107.75,94.39 107.76,94.24 107.99,94.03 v2(108.26,94.04)
  BOTTOM w0.196: v2(119.85,58.37) 119.57,58.08 119.29,58.08 119.09,58.28 119.09,59.99 118.72,60.37 118.51,60.37 118.22,60.66 118.22,61.9 JDIMM1.161
DDR_A_PARITY: length 42.8
  IN4 w0.076: 106.59,78.5 105.84,79.25 105.84,87.7 103.86,89.68 103.86,91.5 103.5,91.86 103.07,91.86 102.91,92.02 102.91,92.45 102.39,92.97 102.39,94.09 102.47,94.17 102.65,94.17 v2(102.78,94.04)
  IN4 w0.132: 106.59,78.5 106.59,70.85 112.64,64.8 112.64,64.37 112.32,64.05 112.32,63.73 112.64,63.41 112.64,62.8 112.32,62.48 112.32,61.93 112.64,61.61 112.64,60.92 112.48,60.75 v2(112.31,60.75)
  BOTTOM w0.076: v2(102.78,94.04) 102.89,93.93 102.97,93.93 103.31,94.27 103.31,94.38 UC1.AT52
  BOTTOM w0.196: JDIMM1.143 111.72,61.14 111.37,60.78 111.37,60.5 111.56,60.3 111.84,60.3 112.29,60.75 v2(112.31,60.75)
DDR_DRAMRST#: length 91.4
  TOP w0.127: RD11.2 RD12.2 104.49,52.44 v2(104.96,51.97)
  IN1 w0.084: v2(137.31,82.12) 137.31,83.2 134.33,86.18 134.33,87.07 133.06,88.34 129.88,88.34 125.25,92.97 125.25,93.69 v2(124.8,94.13)
  IN4 w0.084: v2(104.96,51.97) 104.96,53 105.68,53.71 137.38,53.71 138.35,54.69 142.27,54.69 143.13,55.55 143.13,58.18 143.68,58.73 143.68,64.28 143.22,64.74 143.22,68.07 141.41,69.87 141.41,73.11 137.82,76.7 137.82,78.57 137.62,78.76 137.62,79.64 136.8,80.47 136.8,81.61 v2(137.31,82.12)
  BOTTOM w0.076: v2(124.8,94.13) 124.86,94.13 UC1.AT13
DDR_DRAMRST#_R: length 4.4
  TOP w0.127: v1(101.76,53.12) 102.03,52.85 v2(102.03,52.46) 102.54,52.46 CD29.1 102.74,52.59 RD12.1
  BOTTOM w0.127: v2(102.03,52.46) 102.65,52.46 102.97,52.78 JDIMM1.108
DDR_VTT_CTRL: length 31
  TOP w0.127: UD1.2 76.82,81.22 v1(75.79,82.25) 74.72,83.32 v2(73.46,83.32)
  BOTTOM w0.084: UC1.AW67 93.77,92.63 93.67,92.73 93.03,92.73 92.97,92.8 91.7,92.8 91.43,92.53 90.76,92.53 90.18,91.95 90.18,91.73 89.7,91.25 89.7,90.07 88.41,88.78
  BOTTOM w0.127: v2(73.46,83.32) 75.1,83.32 75.64,83.86 75.64,84.76 76.11,85.23 81.05,85.23 84.1,88.28 87.91,88.28 88.41,88.78
DDR_XDP_WAN_SMBCLK: length 168.8
  IN1 w0.084: v2(150.26,110.37) 150.46,110.18 150.46,107 152.74,104.72 152.74,101.39 154.21,99.92 154.21,95.85 153.58,95.22 153.58,90.15 152.89,89.45 152.63,89.45 v2(152.46,89.61)
  IN4 w0.084: v2(152.46,89.61) 152.3,89.45 152.14,89.45 151.65,89.94 151.65,90.5 151.17,90.99 149.78,90.99 148.83,90.04 148.83,88.7 147.3,87.17 147.3,86.19 146.16,85.05 146.16,80.08 144.75,78.67 144.75,75.71 145.15,75.31 145.15,71.1 147.31,68.94 147.31,65.83 147.13,65.65 147.13,62.86 147.98,62.01 147.98,58.52 147.75,58.29 147.6,58.29 v2(147.44,58.45) ; v2(150.26,110.37) 150.31,110.37 150.5,110.19 150.5,109.98 150.41,109.89 149.29,109.89 148.49,110.69 146.85,110.69 146.4,110.25 139.85,110.25 134.52,115.58 129.91,115.58 127.26,112.92 123.22,112.92 122.76,113.39 122.76,117.41 122.31,117.86 122.31,120.4 122.47,120.56 122.47,123.34 122.84,123.71 122.84,126.26 115.87,133.23 109.28,133.23 109.01,133.5 109.01,133.66 v2(109.2,133.85)
  BOTTOM w0.127: v2(147.44,58.45) 147.33,58.34 145.37,58.34 144.72,58.98 143.21,58.98 141.75,60.44 141.53,60.44 141.23,60.74 JDIMM1.253 ; RC319.1 149.86,110.77 v2(150.26,110.37) 150.88,109.75 QC2.1 ; JXDP1.53 87.91,130.35 88.08,130.52 88.08,130.7 87.65,131.13 85.92,131.13 85.62,131.43 85.62,131.81 85.04,132.39 85.04,133.28 87.07,135.31 108.21,135.31 109.02,134.49 109.02,134.05 109.2,133.87 v2(109.2,133.85)
DDR_XDP_WAN_SMBDAT: length 177.4
  IN1 w0.084: v2(150.9,110.37) 150.67,110.14 150.67,107.08 152.95,104.81 152.95,101.48 154.42,100.01 154.42,95.76 153.79,95.13 153.79,90.06 152.97,89.24 152.67,89.24 v2(152.46,89.03)
  IN4 w0.084: v2(147.44,57.87) 147.6,58.03 147.86,58.03 148.24,58.41 148.24,62.12 147.39,62.96 147.39,65.54 147.57,65.72 147.57,69.05 145.41,71.21 145.41,75.42 145.01,75.82 145.01,78.56 146.42,79.97 146.42,84.94 147.56,86.08 147.56,87.06 149.09,88.59 149.09,89.93 149.89,90.73 151.06,90.73 151.39,90.4 151.39,89.83 152.03,89.19 152.3,89.19 v2(152.46,89.03) ; v2(150.9,110.37) 150.71,110.19 150.71,109.89 150.5,109.68 149.21,109.68 148.4,110.48 146.93,110.48 146.49,110.03 139.76,110.03 134.43,115.36 130,115.36 127.34,112.71 123.13,112.71 122.55,113.3 122.55,117.32 122.1,117.77 122.1,120.48 122.26,120.65 122.26,123.42 122.63,123.79 122.63,126.17 115.78,133.02 109.19,133.02 108.8,133.41 108.8,133.66 v2(108.62,133.85)
  BOTTOM w0.127: JXDP1.51 88.51,130.35 88.34,130.52 88.34,130.81 87.76,131.39 86.02,131.39 85.87,131.54 85.87,131.92 85.29,132.5 85.29,133.17 87.18,135.05 108.1,135.05 108.77,134.39 108.77,134 v2(108.62,133.85) ; JDIMM1.254 141.47,54.59 142.26,55.38 142.26,57.86 143.08,58.67 144.67,58.67 145.26,58.08 147.22,58.08 v2(147.44,57.87) ; v2(150.9,110.37) 151.15,110.37 151.53,109.99 151.53,108.21 151.14,107.82 150.56,107.82 149.79,107.04 148.44,107.04 148.12,107.36 RC318.1 148.61,108.45 QC2.4
DEBUG_TX: length 3.8
  BOTTOM w0.127: JDEG1.9 290.57,122.34 289.85,121.61 289.53,121.61 RE30.2 RE74.2 v1(289.28,119.49)
DGPU_PWROK: length 4.7
  TOP w0.127: UE1.M4 255.49,86.26 255.88,85.86 256.83,85.86 258.78,83.91 T147.1
DIMM1_SA0: length 5.3
  TOP w0.127: RD5.1 143.8,56.59 v2(143.98,56.77) 144.16,56.59 RD4.2
  BOTTOM w0.127: v2(143.98,56.77) 141.98,54.76 JDIMM1.256
DIMM1_SA1: length 4.5
  TOP w0.127: RD7.1 143.55,55.7 v2(143.99,56.14) 144.44,55.7 RD6.2
  BOTTOM w0.127: JDIMM1.260 142.98,55.13 v2(143.99,56.14)
DIMM1_SA2: length 5.5
  TOP w0.127: RD9.1 RD8.2 v2(121.63,51.83) v1(121.12,51.83)
  BOTTOM w0.127: JDIMM1.166 119.47,52.88 120.53,51.83 v2(121.63,51.83)
DISP_ON: length 18.6
  TOP w0.127: v1(71.77,120.51) 72.24,120.98 RV2.1 72.61,122.68 DV2.1 71.81,124.13 70.45,124.13 v2(69.77,124.82)
  BOTTOM w0.127: JEDP1.22 61.75,132.21 63.96,130.01 63.96,129.26 67.24,125.97 68.61,125.97 v2(69.77,124.82)
DMIC0: length 316.3
  TOP w0.127: UA1.2 259.13,63.81 259.74,64.42 259.74,65.28 RA52.2 259.07,65.95 259.07,67.36 259.36,67.65 259.36,69.23 259.63,69.51 260.07,69.51 v2(260.25,69.33) ; v2(40.98,77.71) 40.98,77.98 40.87,78.09 40.87,78.77 41.36,79.26 41.36,81.48 41.19,81.66 41.19,89.46 40.39,90.26 40.39,91.29 38.8,92.88 38.8,97.23 39.46,97.89 39.46,99.68 40.33,100.55 40.58,100.55 40.9,100.87 40.9,106.17 41.14,106.41 41.14,109.32 41.5,109.68 41.5,111.28 47.23,117 50.66,117 53.66,120.01 53.66,121.13 55.03,122.5 55.03,124.23 53.87,125.39 53.87,128.33 53.76,128.45 CA6.1 53.29,129 53.29,129.86 53.55,130.12 v2(53.76,130.12)
  IN1 w0.084: v2(40.98,77.71) 41.25,77.71 41.35,77.61 47.38,77.61 47.95,77.04 51.14,77.04 51.39,77.29 71.18,77.29 79.8,68.67 145.26,68.67 147.06,66.87 147.06,64.71 148.17,63.61 156.62,63.61 156.87,63.85 161.18,63.85 161.4,63.62 165.87,63.62 167.77,61.72 170.02,61.72 174.05,57.69 181.45,57.69 182.55,58.79 195.17,58.79 196.21,57.75 202.08,57.75 202.78,58.45 206.74,58.45 207.03,58.16 222.62,58.16 223.25,58.78 227.69,58.78 228.02,58.45 228.02,56.46 229.77,54.72 232.5,54.72 236.05,58.27 236.05,60.99 237.87,62.81 242.16,62.81 247.35,68 248.34,68 249.03,68.69 249.95,68.69 251.83,70.56 255.86,70.56 256.47,69.95 258.94,69.95 259.36,69.54 260.04,69.54 v2(260.25,69.33)
  BOTTOM w0.127: v2(53.76,130.12) 53.76,130.96 54.25,131.45 JEDP1.7
DMIC_CLK0: length 313.5
  TOP w0.127: v2(41.4,78.13) 41.2,78.13 41.12,78.2 41.12,78.66 41.61,79.15 41.61,81.59 41.44,81.76 41.44,89.56 40.64,90.36 40.64,91.4 39.05,92.98 39.05,97.12 39.72,97.79 39.72,99.57 40.44,100.29 40.68,100.29 41.15,100.76 41.15,106.06 41.39,106.3 41.39,109.21 41.76,109.58 41.76,111.17 47.33,116.75 50.76,116.75 53.92,119.9 53.92,121.02 55.29,122.39 55.29,124.33 54.13,125.49 54.13,127.83 v1(54.73,128.44) 54.01,129.15 54.01,129.16 CA5.1 53.76,129.51 v2(54.37,130.12) ; RA14.1 CA54.1 258.6,67.43 258.77,67.6 258.95,67.6 259.11,67.75 259.11,69.34 259.53,69.76 260.1,69.76 v2(260.25,69.91)
  IN1 w0.084: v2(260.25,69.91) 260.09,69.75 259.44,69.75 259.03,70.17 256.56,70.17 255.95,70.77 251.74,70.77 249.87,68.9 248.94,68.9 248.25,68.21 247.26,68.21 242.07,63.02 237.78,63.02 235.84,61.08 235.84,58.36 232.41,54.93 229.86,54.93 228.24,56.55 228.24,58.53 227.77,58.99 223.16,58.99 222.53,58.37 207.12,58.37 206.82,58.66 202.69,58.66 201.99,57.96 196.3,57.96 195.26,59 182.47,59 181.36,57.9 174.14,57.9 170.11,61.93 167.86,61.93 165.95,63.84 161.49,63.84 161.26,64.06 156.78,64.06 156.53,63.82 148.25,63.82 147.27,64.8 147.27,66.95 145.34,68.88 79.89,68.88 71.27,77.5 51.31,77.5 51.05,77.25 48.04,77.25 47.47,77.82 41.44,77.82 41.4,77.86 v2(41.4,78.13)
  BOTTOM w0.127: v2(54.37,130.12) 54.48,130.23 54.48,130.66 55.25,131.44 JEDP1.9
DMIC_CLK_CODEC: length 2.4
  TOP w0.127: RA14.2 259.1,64.96 v1(259.1,64.55) 259.1,64.37 258.73,63.99 UA1.3
DPSNK0_DDC_CLK: length 18.9
  TOP w0.127: RT14.1 38.68,112.15 RT126.1 RT341.2 v2(36.98,110.37) 36.14,110.37 v1(35.48,109.71)
  IN2 w0.122: v2(36.98,110.37) 36.98,109.27 35.87,108.16 31.47,108.16 31.04,107.72 31.04,107.17 31.3,106.9 31.3,104.23 31.77,103.76 31.77,102.76 31.29,102.27 v2(31.29,102.25)
  BOTTOM w0.127: v2(31.29,102.25) 31.61,102.57 UT1.Y5
DPSNK0_DDC_DATA: length 15.9
  TOP w0.127: v1(28.36,103.3) 28.68,102.97 v2(28.68,102.9) ; RT15.1 RT127.1 36.6,109.41 RT342.2 36.03,109.42 v2(35.43,108.82)
  IN2 w0.122: v2(28.68,102.9) 28.68,103.5 29.33,104.15 30.03,104.15 31.04,105.15 31.04,106.84 30.67,107.21 30.67,107.94 31.32,108.59 35.2,108.59 v2(35.43,108.82)
  BOTTOM w0.127: UT1.R4 v2(28.68,102.9)
DPSNK1_DDC_CLK: length 11.6
  TOP w0.127: v2(34.27,102.24) 34.29,102.23 34.29,99.48 RT128.1 33.35,98.54 RT336.1
  IN2 w0.122: v2(29.99,100.29) 30.72,101.02 31.72,101.02 32.27,101.57 33.6,101.57 v2(34.27,102.24)
  BOTTOM w0.127: v2(29.99,100.29) 29.99,100.74 30.24,100.99 31.33,100.99 31.61,101.27 UT1.Y8
DPSNK_RBIAS: length 4.1
  TOP w0.127: v1(31.96,94.31) 32.5,94.84 32.5,96.14 RT38.1 31.59,97.05 v2(31.29,97.05)
  BOTTOM w0.127: UT1.Y18 v2(31.29,97.05)
EC_FPM_EN: length 47.2
  TOP w0.127: v2(248.68,87.39) 248.69,87.39 249.08,87.78 UE1.D6 ; v1(231.08,59.27) 231.15,59.27 231.64,59.76 v2(231.64,60.06)
  IN4 w0.084: v2(248.68,87.39) 248.44,87.39 248.11,87.06 247.67,87.06 247.48,86.87 247.48,82.77 247.45,82.74 247.45,81.14 247.76,80.82 247.76,79.12 247.14,78.5 246.89,78.5 245.79,77.4 245.79,75.98 246.91,74.86 246.91,70.19 246.78,70.06 246.78,67.45 242.97,63.64 242.97,60.27 241.6,58.9 234.22,58.9 233.77,59.36 232.95,59.36 232.74,59.57 232.74,60.33 232.6,60.46 232.05,60.46 v2(231.64,60.06)
  BOTTOM w0.127: v2(231.64,60.06) 231.45,59.86 JUSH1.5
EDP_AUXN: length 63.7
  TOP w0.104: CV1.1 67.18,128.74 67.18,128.74 67.33,128.58 67.33,128.33 67.27,128.27 v2(67.06,128.27)
  IN1 w0.076: v2(106.48,110.86) 106.48,110.58 106.43,110.53 106.17,110.53 106.11,110.58 106.11,111.85 106.12,111.86 106.12,111.88
  IN1 w0.094: v2(67.06,128.27) 67.29,128.5 67.29,128.85 67.54,129.11 71.97,129.11 74.71,126.37 80.31,126.37 84.12,130.19 103.6,130.19 107.27,126.52 107.27,114.69 106.12,113.54 106.12,111.88
  BOTTOM w0.089: v2(106.48,110.86) 106.75,110.59 UC1.E45
EDP_AUXN_C: length 3.2
  TOP w0.104: v2(67.11,130.86) 67.29,130.67 67.29,130.22 CV1.2
  BOTTOM w0.104: JEDP1.33 67.25,132.12 67.41,131.96 67.41,131.59 67.3,131.47 67.3,131.05 v2(67.11,130.86)
EDP_AUXP: length 63.7
  TOP w0.104: CV2.1 67.52,128.65 67.52,128.45 67.7,128.27 v2(67.9,128.27)
  IN1 w0.076: 105.94,111.88 105.94,111.86 105.94,111.85 105.94,110.51 106.1,110.36 106.28,110.36 v2(106.47,110.17)
  IN1 w0.094: v2(67.9,128.27) 67.69,128.06 67.59,128.06 67.47,128.18 67.47,128.77 67.62,128.92 71.9,128.92 74.63,126.19 80.38,126.19 84.2,130 103.52,130 107.08,126.44 107.08,114.77 105.94,113.62 105.94,111.88
  BOTTOM w0.089: v2(106.47,110.17) 106.7,109.94 UC1.F45
EDP_AUXP_C: length 3.2
  TOP w0.104: CV2.2 67.49,130.24 67.49,130.66 v2(67.69,130.86)
  BOTTOM w0.104: v2(67.69,130.86) 67.49,131.06 67.49,131.39 67.6,131.51 67.6,131.98 67.75,132.13 JEDP1.34
EDP_BIA_PWM: length 98.9
  TOP w0.127: v1(75.94,125.96) 75.39,126.52 DV1.3 74.35,126.68 73.5,126.68 73.24,126.41 73.24,126.07 73.34,125.97 73.34,122.91 v2(73.58,122.67)
  IN2 w0.122: v2(126.85,105.85) 126.85,105.71 127.21,105.35 127.21,104.54 127.36,104.4 130.34,104.4 131.5,105.56 131.5,111.41 132.06,111.97 132.06,113.07 134.11,115.12 134.11,115.31 134.11,115.31 134.11,116.98 134.66,117.53 134.66,119.82 134.75,119.9 134.75,121.18 134.88,121.32 134.88,124.1 133.75,125.24 133.75,125.24 133.29,125.69 130.21,125.69 129.24,126.67 125.67,126.67 125.15,126.14 120.87,126.14 120.86,126.13 118.79,126.13 117.51,124.85 99.05,124.85 97.76,123.56 85.13,123.56 84,122.43 82.17,122.43 81.5,121.75 76.81,121.75 76.59,121.53 74.72,121.53 v2(73.58,122.67)
  BOTTOM w0.102: v2(126.85,105.85) 126.85,105.75 UC1.R11
EDP_COMP: length 1.6
  TOP w0.381: RC2.1 102.7,110.03 v2(102.7,110.93)
  BOTTOM w0.254: UC1.E52 103.04,110.59 v2(102.7,110.93)
EDP_HPD: length 106.1
  TOP w0.127: v2(64.21,131.53) RV7.1 63.66,132.15 v1(62.96,132.86) ; v2(127.4,106.88) 127.91,107.39 129.45,107.39 RC1.1
  IN2 w0.122: v2(127.4,106.88) 127.27,106.75 127.27,105.61 127.52,105.36 129.6,105.36 130.11,105.87 130.11,108.1 130.75,108.74 130.75,109.25 130.4,109.6 130.4,110.23 129.61,111.02 129.01,111.02 128.52,111.51 128.52,112.23 128.77,112.48 128.77,115.67 130.39,117.28 130.39,122.12 130.02,122.49 130.02,124.37 128.62,125.77 126.17,125.77 126.02,125.92 120.96,125.92 120.95,125.9 118.88,125.9 117.6,124.62 99.14,124.62 97.85,123.33 89.23,123.33 88.16,122.25 85.46,122.25 85.32,122.11 82.18,122.11 81.59,121.52 76.9,121.52 76.68,121.3 74.31,121.3 70.81,124.8 v2(70.37,124.8)
  BOTTOM w0.076: v2(127.4,106.88) UC1.L10
  BOTTOM w0.127: JEDP1.26 63.75,131.99 v2(64.21,131.53) 64.21,129.75 67.54,126.42 68.75,126.42 v2(70.37,124.8)
EDP_TXN0: length 55.4
  TOP w0.104: v2(77.71,125.1) 77.33,125.48 77.33,125.66 75.52,127.47 v4(70.9,127.47) 70.01,127.47 69.27,128.2 69.27,128.71 69.53,128.97 CV4.1
  IN1 w0.094: v2(105.73,115.14) 105.73,115.26 105.56,115.43 105.23,115.43 104.42,116.24 104.42,123.28 101.71,126 100.57,126 98.42,128.15 85.23,128.15 84.68,127.59 83.25,127.59 81.25,125.59 77.23,125.59 77.13,125.5 77.13,125.23 77.38,124.99 77.6,124.99 v2(77.71,125.1)
  BOTTOM w0.076: UC1.C47 105.73,112.28
  BOTTOM w0.089: 105.73,112.28 105.73,113.88 106.18,114.34 106.18,115.29 106.03,115.45 105.81,115.45 105.73,115.37 v2(105.73,115.14)
EDP_TXN0_C: length 3.5
  TOP w0.104: CV4.2 69.28,130.22 69.28,130.67 v2(69.47,130.86)
  BOTTOM w0.104: JEDP1.36 68.75,132.14 68.6,131.99 68.6,131.87 69.26,131.22 69.26,131.07 v2(69.47,130.86)
EDP_TXN1: length 55.2
  TOP w0.104: v2(84.21,129.36) 84.21,129.08 84.13,129 83.98,129 83.62,129.36 80.7,129.36 79.74,128.4 71.18,128.4 71.05,128.52 71.05,128.78 71.24,128.97 CV6.1
  IN1 w0.094: v2(105.81,116.99) 106.02,117.2 106.24,117.2 106.49,117.45 106.49,119.34 105.36,120.48 105.36,127.23 103.14,129.46 85.6,129.46 85.29,129.14 84.43,129.14 v2(84.21,129.36)
  BOTTOM w0.076: v2(105.81,116.99) 106.17,117.35 106.3,117.35 106.66,116.99 106.66,113.82 106.86,113.62 106.86,113.22 106.81,113.08 106.81,112.86 106.87,112.72 106.87,112.64 106.77,112.32 106.74,112.29 106.47,112.29 106.31,112.13 106.31,111.97 UC1.D46
EDP_TXN1_C: length 4.4
  TOP w0.104: CV6.2 71.04,130.24 71.04,130.66 v2(71.25,130.86)
  BOTTOM w0.104: JEDP1.38 69.75,132.17 69.59,132.01 69.59,131.81 69.85,131.55 70.8,131.55 71.05,131.3 71.05,131.06 v2(71.25,130.86)
EDP_TXP0: length 55.4
  TOP w0.104: CV3.1 69.08,128.62 69.08,128.12 69.93,127.28 70.57,127.28 70.61,127.24 71.19,127.24 71.23,127.28 75.44,127.28 77.14,125.58 77.14,125.46 v2(76.76,125.08)
  IN1 w0.094: v2(105.73,115.8) 105.55,115.62 105.31,115.62 104.61,116.32 104.61,123.36 101.79,126.18 100.64,126.18 98.49,128.33 85.16,128.33 84.6,127.78 83.17,127.78 81.17,125.78 77.15,125.78 76.95,125.58 76.95,125.27 v2(76.76,125.08)
  BOTTOM w0.089: v2(105.73,115.8) 105.91,115.62 106.1,115.62 106.36,115.36 106.36,114.27 105.9,113.81 105.9,112.72 105.97,112.65 106.23,112.65 106.34,112.54 106.34,112.4 106.21,112.28 106.09,112.28 UC1.C46
EDP_TXP0_C: length 3.5
  TOP w0.104: CV3.2 69.08,130.23 69.08,130.66 v2(68.88,130.86)
  BOTTOM w0.104: JEDP1.35 68.25,132.14 68.41,131.98 68.41,131.79 69.06,131.14 69.06,131.04 v2(68.88,130.86)
EDP_TXP1: length 55.2
  TOP w0.104: v2(84.21,128.6) 84,128.81 83.9,128.81 83.54,129.17 80.78,129.17 79.82,128.21 71.1,128.21 70.86,128.44 70.86,128.62 CV5.1
  IN1 w0.094: v2(105.79,117.83) 105.79,117.5 105.9,117.39 106.17,117.39 106.31,117.53 106.31,119.27 105.18,120.4 105.18,127.16 103.06,129.27 85.68,129.27 85.36,128.96 84.27,128.96 84.21,128.9 v2(84.21,128.6)
  BOTTOM w0.076: v2(105.79,117.83) 106.11,117.52 106.37,117.52 106.83,117.06 106.83,113.89 107.02,113.69 107.02,113.19 106.98,113.05 106.98,112.89 107.03,112.75 107.03,112.62 106.88,112.11 106.88,112.11 106.88,111.94 106.77,111.83 106.67,111.83 106.59,111.91 UC1.C45
EDP_TXP1_C: length 4.3
  TOP w0.104: CV5.2 70.85,130.22 70.85,130.67 v2(70.66,130.86)
  BOTTOM w0.104: JEDP1.37 69.25,132.16 69.4,132.01 69.4,131.73 69.77,131.36 70.72,131.36 70.85,131.22 70.85,131.05 v2(70.66,130.86)
EDRAM_OPIO_RCOMP: length 3
  TOP w0.127: v1(94.76,109.33) 94.32,108.89 v2(94.24,108.89)
  TOP w0.381: v2(94.24,108.89) 93.89,108.89 93.43,109.36 RC90.1
  BOTTOM w0.254: v2(94.24,108.89) 94.44,108.7 UC1.H66
EMMC_RCOMP: length 7.4
  BOTTOM w0.127: RC4.1 v1(137.17,94.63)
  BOTTOM w0.203: UC1.AT1 132.58,94.56 133.35,95.32
  BOTTOM w0.381: 133.35,95.32 136.28,95.32 RC4.1
EN_0.6V: length 7.6
  TOP w0.127: PC222.1 73.47,75 v1(74,75.54)
  TOP w0.254: PC222.1 PR212.1 71.77,74.99 PR210.2 71.77,73.66 71.64,73.53 v2(71.64,73.21)
  BOTTOM w0.254: PU200.2 69.57,71.56 70.73,72.72 71.15,72.72 v2(71.64,73.21)
EN_1.0V_PRIM_COREP: length 11.5
  TOP w0.127: PR406.2 PR407.1 PC411.1 163.71,124.87 v2(164.09,124.49)
  BOTTOM w0.127: v2(164.09,124.49) v1(163.65,124.93) 162.33,124.93 161.89,124.49 158.4,124.49 158.25,124.64 PU402.13
EN_1.2V: length 6
  TOP w0.127: v1(69.71,72.39) 70.44,73.12 v2(70.44,73.3)
  TOP w0.254: v2(70.44,73.3) 70.44,73.48 69.99,73.94 PR208.2 70,74.14 PC221.1 PR209.1
  BOTTOM w0.254: PU200.1 69.35,72.01 70.44,73.1 v2(70.44,73.3)
EN_1.8VALW: length 1.6
  BOTTOM w0.127: v1(176.97,66.35) 175.62,66.35 175.42,66.54 PC505.1
EN_1VS_VCCIO: length 5.7
  TOP w0.127: PR402.2 145.56,129.06 v1(146.05,128.57)
  TOP w0.254: v2(142.64,127.39) 142.84,127.58 PC402.1 PR403.1 144.27,128.69 144.27,128.79 144.54,129.06 PR402.2
  BOTTOM w0.254: v2(142.64,127.39) 142.38,127.66 PU401.13
EN_2.5V: length 5.2
  TOP w0.127: v1(148.41,56.58) PR513.2 PC513.1 PR514.1 151.71,57.14 151.71,58.3 PU503.5
EN_+1VALWP: length 24.2
  TOP w0.254: PU301.11 v2(155.24,82.35) ; PR312.2 166.85,84.64 166.51,84.99 PR302.1 165.96,85.76 v1(165.53,86.19) 165.12,86.19 164.52,85.59 v2(164.07,85.59)
  IN4 w0.254: v2(155.24,82.35) 155.24,80.28 156.5,79.02 157.76,79.02 158.54,79.8 164.35,79.8 165.35,80.81 165.35,84.67 164.43,85.59 v2(164.07,85.59)
EN_INVPWR: length 274.9
  TOP w0.127: RE55.1 246.09,81.6 246.11,81.63 246.11,81.81 v2(246.09,81.84) 246.09,82.62 247.06,83.6 247.06,84.24 UE1.B2 ; v2(40.03,122.18) 39.82,121.98 QV2.2 ; v1(242.07,76.83) v2(242.54,76.36)
  IN1 w0.084: v2(246.09,81.84) 243.25,79 243.25,77.47 242.54,76.76 v2(242.54,76.36)
  IN2 w0.122: v2(40.03,122.18) 40.03,122.89 41.76,124.61 46.38,124.61 47.61,125.85 48.86,125.85 50.14,124.57 60.86,124.57 61.75,125.46 67.66,125.46 69.34,127.14 74.62,127.14 75.06,126.7 80.28,126.7 83.7,130.12 87.07,130.12 87.32,130.36 115.05,130.36 116.2,131.51 124.69,131.51 126.01,132.82 127.96,132.82 128.53,132.26 135.13,132.26 135.79,132.92 139.74,132.92 141.25,131.41 143.2,131.41 144.74,129.87 154.58,129.87 155.33,130.62 156.5,130.62 158.97,128.15 158.97,123.62 159.54,123.04 159.54,123.04 162.04,120.54 162.04,117.66 162.37,117.33 162.37,110.05 166.12,106.29 166.12,93.38 167.27,92.24 167.27,90.16 167.96,89.47 167.96,88.29 169.86,86.39 169.86,84.75 171.85,82.77 171.85,80.58 176.67,75.76 176.67,75.25 177.49,74.42 178.47,74.42 182.12,70.77 186.26,70.77 187.9,69.13 206.06,69.13 207.44,67.75 222.1,67.75 222.76,68.41 225.83,68.41 226.45,69.03 227.67,69.03 230.67,72.03 233.39,72.03 233.66,71.76 235,71.76 236.08,72.84 236.08,73.99 237.29,75.21 240.66,75.21 241.81,76.36 v2(242.54,76.36)
EN_LCDPWR: length 8.9
  TOP w0.127: UV24.4 64.9,121.35 65.38,120.87 v1(66.22,120.87) 69.23,120.87 69.56,121.2 69.56,122.24 RV3.2 69.43,122.36 DV3.1
EN_PD_HV_1: length 82.8
  TOP w0.127: PR1260.1 38.7,51.13 37.11,52.72 33.87,52.72 33.29,53.3 PR1210.1 ; PQ1214.5 46.05,100.09 v2(45.77,99.81)
  TOP w0.203: PR1250.2 32.42,54.43 PR1210.1
  TOP w0.254: PR1250.2 32.04,54.42 31.71,54.75 31.71,58.56 32.55,59.4 PR1254.1 v1(34.25,61.8) v2(34.82,62.37) 35.14,62.37 35.33,62.56 PR1211.1
  IN1 w0.084: v2(37.12,66.15) 36.77,65.79 36.77,64.31 v2(34.82,62.37)
  IN2 w0.122: v2(33.27,73.28) 33.27,68.5 36.2,65.58 36.2,63.74 v2(34.82,62.37) ; v2(45.77,99.81) 46.07,100.11 46.49,100.11 47.76,98.83 47.76,97.93 44.68,94.84 44.68,92.07 41.91,89.3 41.91,80.18 39.38,77.65 39.38,77.49 37.6,75.71 37.6,66.63 v2(37.12,66.15)
  BOTTOM w0.127: RT70.1 34.25,74.25 v2(33.27,73.28)
EN_PD_HV_1#: length 2.7
  TOP w0.127: PR1253.2 v1(43.44,101.31)
  TOP w0.254: PQ1214.3 PQ1214.2 43.7,100.09 PR1253.2
EN_PD_HV_1_R: length 3.6
  BOTTOM w0.076: UT5.C2 33.27,78.72 33.27,78.14 33.88,77.53 33.88,77.44
  BOTTOM w0.127: RT70.2 34.06,76.03 34.06,77 33.88,77.18 33.88,77.44
ENABLE_DS#: length 12.7
  TOP w0.127: RE550.1 258.05,76.12 256.98,75.04 256.45,75.04 256.07,75.42 256.07,76.23 256.28,76.44 256.28,77.2 RE549.2 255.56,77.93 255.56,81.6 v1(255.41,81.74) 255.14,82.02 255.14,83.98 254.68,84.44 UE1.L2
ENLDO_3V5V: length 65.3
  TOP w0.254: v2(146.85,76.66) 147.1,76.66 v1(147.38,76.93) 147.38,77.51 147.71,77.83 152.27,77.83 v2(152.54,77.56)
  IN4 w0.203: v2(179.96,59.29) 179.44,58.78 179.44,58.31 179.06,57.92 174.7,57.92 173.35,59.27 168.35,59.27 167.54,58.46 159.36,58.46 159.25,58.56 159.18,58.56 158.52,59.22 158.52,66.41 157.55,67.37 150.42,67.37 146.32,71.47 146.32,74.99 146.41,75.08 146.41,76.21 v2(146.85,76.66)
  BOTTOM w0.254: v2(179.96,59.29) 181.13,60.46 182.28,60.46 PR103.1 PR102.1 182.92,58.86 184.04,57.74 PU102.11 ; v2(152.54,77.56) 153.39,77.56 153.56,77.39 PU100.11
ENVDD_PCH: length 100
  TOP w0.127: v2(72.37,124.52) 71.55,124.52 DV3.3 71.25,124.74 70.62,125.36 69.31,125.36 v1(69.01,125.07)
  IN2 w0.122: v2(125.07,104.81) 125.07,104.71 126.1,103.68 130.26,103.68 131.95,105.37 131.95,111.23 132.51,111.79 132.51,112.88 134.56,114.93 134.56,115.12 134.56,115.13 134.56,116.79 135.94,118.17 135.94,121.52 135.35,122.11 135.35,124.36 133.57,126.14 130.54,126.14 129.57,127.11 125.19,127.11 124.66,126.59 118.55,126.59 117.27,125.31 98.87,125.31 97.57,124.01 84.83,124.01 83.7,122.88 82.55,122.88 82.32,123.11 73.79,123.11 v2(72.37,124.52)
  BOTTOM w0.102: v2(125.07,104.81) 125.13,104.75 UC1.U13
EOPIO_RCOMP: length 3.6
  TOP w0.381: RC91.1 93.29,108.47 93.56,108.2 v1(93.99,108.2) 94.48,108.2 v2(95.19,108.91)
  BOTTOM w0.254: UC1.H65 95.4,108.7 v2(95.19,108.91)
ESPI_ALERT#: length 182.9
  TOP w0.127: UE1.H7 v2(252.68,88.26) ; RC21.1 144.53,85.33 v2(144.32,85.53)
  IN2 w0.122: v2(257.4,70.6) 257.4,70.39 257.17,70.17 256.61,70.17 255.61,71.17 254.12,71.17 253.43,70.48 251,70.48 249.98,69.46 249.17,69.46 248.96,69.67 247.74,69.67 246.61,68.54 246.61,67.32 243.13,63.84 241.05,63.84 240.19,62.98 236.35,62.98 234.74,61.37 226.54,61.37 226.4,61.23 218.9,61.23 218.16,60.49 214.86,60.49 214.38,60.97 204.52,60.97 202.6,62.89 185.13,62.89 183.41,64.62 179.67,64.62 178.92,65.37 173.88,65.37 173.06,66.19 170.86,66.19 170.56,65.88 166.22,65.88 165.78,66.33 161.55,66.33 158.16,69.72 150.72,69.72 147.92,72.53 147.92,79.56 144.32,83.15 v2(144.32,85.53)
  BOTTOM w0.076: UC1.AY11 125.97,91.53 125.86,91.42 125.86,90.27 126.94,89.19 127.61,89.19 128.4,88.4 128.46,88.4
  BOTTOM w0.112: 131.05,85.81 133.87,85.81
  BOTTOM w0.127: v2(252.68,88.26) 252.68,88.22 253.05,87.86 255.27,87.86 256.4,86.74 256.4,85.71 257.63,84.48 257.63,81.16 256.73,80.26 256.73,77.21 257.21,76.73 257.21,75.49 256.76,75.03 256.76,73.37 257.66,72.47 257.66,70.85 v2(257.4,70.6) ; 128.46,88.4 131.05,85.81 ; 133.87,85.81 134.64,85.04 135.66,85.04 136.36,84.34 138.45,84.34 139.22,85.1 139.22,85.44 139.72,85.95 140.78,85.95 140.9,85.83 v1(141.42,85.83) 141.69,85.83 141.81,85.95 143.9,85.95 v2(144.32,85.53)
ESPI_CLK: length 29
  BOTTOM w0.076: UC1.AW9 127.34,92.36 127.18,91.84 127.18,91.73 127.07,91.42 127.07,91.28 127.13,91.06 127.13,90.94 127.08,90.83 127.08,90.46 127.34,90.21 127.94,90.21 128.42,89.72 128.83,89.72
  BOTTOM w0.127: 128.83,89.72 130.58,87.97 130.86,87.97 131.72,87.11 134.11,87.11 135.16,86.05 136.24,86.05 137.17,85.12 137.69,85.12 138,85.43 138,85.79 138,85.8 138,85.99 138.44,86.43 143.59,86.43 147.03,89.87 147.27,89.87 v1(147.48,90.08) 148.15,90.75 RC16.1
ESPI_CLK_5105: length 174.2
  TOP w0.127: UE1.G7 v2(251.08,88.26) ; RE350.1 248.98,74.79 248.98,74.17 249.58,73.57 v1(250.7,73.57) 251.81,73.57 v2(251.83,73.59)
  IN4 w0.084: v2(150.54,90.02) 150.53,90.02 149.59,89.08 149.59,88.38 148.73,87.52 148.73,85.89 147.41,84.57 147.41,78.43 147.76,78.09 147.76,71.2 150.68,68.28 160.14,68.28 164.71,63.71 166.02,63.71 166.87,62.87 169.6,62.87 169.95,63.22 170.23,63.22 170.65,62.8 172.56,62.8 173.47,61.89 178.9,61.89 179.24,61.54 212.55,61.54 213.8,60.3 223.38,60.3 225.68,57.99 225.68,56.25 227.11,54.82 229.14,54.82 229.62,54.35 231.36,54.35 233.39,52.31 239.46,52.31 240.19,53.04 242.64,53.04 v2(243.44,53.83)
  BOTTOM w0.127: v2(251.08,88.26) 251.48,87.86 251.48,84.67 251.2,84.39 251.2,81.47 252.89,79.78 253.16,79.78 253.51,79.42 253.51,77.27 252.22,75.97 252.22,73.98 v2(251.83,73.59) 251.83,73.04 252.11,72.76 252.11,70.75 249.85,68.49 249.85,67.28 249.2,66.63 249.2,63.83 247.5,62.13 247.5,61.25 246.4,60.16 246.4,58.44 244.09,56.12 243.45,56.12 242.95,55.62 JESPI.10 242.95,54.32 v2(243.44,53.83) ; CC316.1 150.38,89.86 v2(150.54,90.02) 149.84,90.73 RC16.2
ESPI_CS#: length 194.7
  TOP w0.127: UE1.H6 v2(252.68,87.46)
  IN4 w0.084: v2(150.52,88.59) 149.25,87.32 149.25,85.68 147.88,84.31 147.88,78.62 148.25,78.25 148.25,71.37 150.88,68.74 160.34,68.74 164.9,64.18 166.22,64.18 166.62,63.78 170.33,63.78 170.84,63.26 172.82,63.26 173.67,62.42 179.02,62.42 179.43,62.01 212.74,62.01 213.3,61.45 223.03,61.45 226.2,58.29 226.2,56.94 227,56.13 228.65,56.13 229.97,54.82 234.97,54.82 235.59,54.2 242.88,54.2 v2(244.27,55.59)
  BOTTOM w0.076: 129.13,87.36 127.51,88.99 126.88,88.99 125.69,90.18 125.69,91.63 UC1.BA12
  BOTTOM w0.127: 129.13,87.36 130.91,85.58 133.72,85.58 134.52,84.78 135.53,84.78 136.23,84.08 139.15,84.08 139.9,84.84 144.39,84.84 144.88,85.33 144.88,86.5 v1(144.92,86.54) 144.92,87.03 146.68,88.78 148.31,88.78 148.61,89.08 150.25,89.08 150.52,88.81 v2(150.52,88.59) ; JESPI.7 244.45,55.41 v2(244.27,55.59) 246.96,58.28 246.96,59.97 248,61.01 248,61.65 250.67,64.31 250.67,68.22 253.15,70.7 253.15,76.1 255.28,78.23 255.28,79.45 255.01,79.72 254.1,79.72 253.43,80.39 253.43,81.02 253.08,81.37 253.08,87.06 v2(252.68,87.46)
ESPI_IO0: length 161.2
  TOP w0.127: UE1.K5 v2(254.28,86.66)
  IN4 w0.084: v2(246.15,56.16) 245.13,57.18 243.33,57.18 241.08,54.94 236.15,54.94 234.72,56.36 233.7,56.36 232.14,57.92 228.92,57.92 223.53,63.31 187.14,63.31 186.56,63.89 181.21,63.89 180.24,64.86 175.01,64.86 174.16,64.01 171.15,64.01 170.64,64.52 166.93,64.52 166.51,64.94 165.48,64.94 160.86,69.56 151.24,69.56 148.99,71.81 148.99,79.68 149.47,80.16 149.47,84.4 150.51,85.44 v2(150.51,85.6)
  BOTTOM w0.127: RC366.2 150.14,85.6 v2(150.51,85.6) 150.51,85.69 150.91,86.09 v1(150.91,86.7) ; JESPI.3 246.45,55.86 v2(246.15,56.16) 246.31,56.32 247.57,56.32 249.07,57.81 249.07,60.97 251.74,63.64 251.74,67.57 252.45,68.29 252.45,68.65 254.77,70.96 254.77,76.86 255.81,77.9 255.81,80.58 255.31,81.09 255.31,83.59 255.52,83.81 255.52,86.04 255.31,86.26 254.68,86.26 v2(254.28,86.66)
ESPI_IO0_R: length 30.7
  BOTTOM w0.076: UC1.AY13 125.09,91.83 124.99,91.72 124.89,91.61 124.82,91.4 124.82,91.28 124.88,91.05 124.88,90.91 124.83,90.79 124.83,90.52 124.95,90.39 124.95,89.89 v1(126.94,87.9) 127.1,87.74
  BOTTOM w0.127: RC366.1 148.5,85.9 148.15,85.55 146.54,85.55 144.77,83.77 140.35,83.77 139.65,83.07 137.44,83.07 136.83,82.46 136.27,82.46 134.96,83.77 134.01,83.77 133.13,84.64 130.43,84.64 127.33,87.74 127.1,87.74
ESPI_IO1: length 162.9
  TOP w0.127: UE1.L4 v2(255.08,85.86)
  IN4 w0.084: v2(245.55,56.16) 245.41,56.31 243.19,56.31 241.45,54.57 235.89,54.57 235.17,55.29 230.92,55.29 224.39,61.82 213.45,61.82 212.85,62.43 181.34,62.43 180.42,63.35 178.59,63.35 178.19,62.95 173.8,62.95 173.12,63.63 171,63.63 170.48,64.15 166.78,64.15 166.37,64.55 165.05,64.55 160.49,69.12 151.16,69.12 148.62,71.65 148.62,78.41 148.25,78.78 148.25,84.01 149.81,85.57 149.81,86.4 v2(151.11,87.71)
  BOTTOM w0.127: JESPI.4 245.95,55.76 v2(245.55,56.16) 246.08,56.68 247.29,56.68 248.05,57.44 248.05,60.08 248.84,60.87 248.84,62.07 251.48,64.71 251.48,67.67 252.08,68.28 252.08,68.67 254.52,71.11 254.52,76.93 255.59,78 255.59,80.48 254.21,81.86 254.21,83.53 254.68,83.99 254.68,85.45 v2(255.08,85.86) ; RC367.2 150.22,87.3 150.71,87.3 v2(151.11,87.71) 151.56,87.71 v1(152.05,88.2)
ESPI_IO1_R: length 29.4
  BOTTOM w0.076: UC1.BA13 125.09,91.13 125.36,90.87 125.36,90 126.83,88.53 127.29,88.53 128.65,87.17
  BOTTOM w0.127: RC367.1 148.38,87.13 v1(147.94,87.13) 147.46,87.13 144.64,84.32 140.15,84.32 139.41,83.58 135.98,83.58 135.28,84.28 134.26,84.28 133.41,85.13 130.69,85.13 128.65,87.17
ESPI_IO2: length 159.7
  TOP w0.127: v1(243.09,56.53) 243.34,56.78 v2(244.01,56.78) 244.23,56.78 v2(245.45,55.56) ; UE1.G6 v2(251.08,87.46)
  IN4 w0.084: v2(244.01,56.78) 243.96,56.74 243.25,56.74 241.27,54.75 236.07,54.75 234.65,56.18 233.62,56.18 232.14,57.66 230.31,57.66 230.19,57.53 230.19,57.23 230.06,57.1 229.59,57.1 229.47,57.23 229.47,57.53 229.34,57.66 228.81,57.66 224.47,62.01 213.53,62.01 212.87,62.67 181.56,62.67 180.69,63.54 178.33,63.54 178.1,63.31 173.78,63.31 173.27,63.82 171.07,63.82 170.56,64.33 166.85,64.33 166.45,64.74 165.13,64.74 160.57,69.3 151.24,69.3 148.8,71.73 148.8,81.74 149.28,82.21 149.28,84.7 150.04,85.47 150.04,85.79 v2(150.51,86.26)
  BOTTOM w0.127: v2(150.51,86.26) 149.98,86.79 RC368.2 ; v2(251.08,87.46) 250.69,87.06 250.69,81.26 252.25,79.71 252.25,76.79 251.71,76.25 251.71,74.19 251.32,73.8 251.32,72.7 251.57,72.45 251.57,70.93 249.34,68.7 249.34,67.49 248.69,66.84 248.69,64.17 246.99,62.47 246.99,61.47 245.16,59.64 245.16,58.1 244.01,56.95 v2(244.01,56.78) ; JESPI.5 v2(245.45,55.56)
ESPI_IO2_R: length 28.7
  BOTTOM w0.076: UC1.BB13 125.09,90.5 125.19,90.4 125.19,89.92 126.81,88.3 127.15,88.3 128.45,87.01
  BOTTOM w0.127: 128.45,87.01 130.55,84.9 133.26,84.9 134.14,84.02 135.15,84.02 135.85,83.32 139.53,83.32 140.26,84.05 144.69,84.05 146.78,86.13 v1(147.04,86.13) 148.26,86.13 RC368.1
ESPI_IO3: length 165.6
  TOP w0.127: UE1.L5 v2(255.08,86.66)
  IN4 w0.084: v2(150.51,87.71) 150.46,87.71 149.53,86.78 149.53,85.62 148.06,84.16 148.06,78.7 148.43,78.33 148.43,71.53 151.04,68.93 160.41,68.93 164.98,64.36 166.3,64.36 166.7,63.96 170.41,63.96 170.92,63.45 172.97,63.45 173.75,62.67 178.17,62.67 178.67,63.17 180.34,63.17 181.32,62.19 212.82,62.19 213.38,61.64 223.3,61.64 226.43,58.51 226.43,58.09 226.98,57.55 227.5,57.55 229.99,55.05 235.07,55.05 235.74,54.38 241.64,54.38 243.22,55.96 244.48,55.96 v2(244.85,55.59)
  BOTTOM w0.127: v2(150.51,87.71) 150.51,87.9 RC369.2 ; v2(244.85,55.59) 244.95,55.49 JESPI.6 244.95,54.07 245.21,53.81 247.86,53.81 248.31,54.25 248.31,56.73 249.32,57.75 249.32,60.87 251.97,63.52 251.97,67.41 253,68.44 253,68.87 255,70.88 255,76.65 256.04,77.69 256.04,80.78 255.59,81.24 255.59,81.75 255.8,81.97 255.8,86.23 255.37,86.66 v2(255.08,86.66)
ESPI_IO3_R: length 31.1
  BOTTOM w0.076: 128.88,87.27 127.39,88.76 126.86,88.76 125.53,90.09 125.53,91.23 125.36,91.39 125.36,91.82 125.66,92.12 UC1.AY12
  BOTTOM w0.127: RC369.1 147.93,87.57 146.38,87.57 v1(146.26,87.45) 146.01,87.2 146.01,86.01 144.57,84.57 140.02,84.57 139.28,83.83 136.1,83.83 135.41,84.53 134.39,84.53 133.56,85.35 130.8,85.35 128.88,87.27
ESPI_RESET#: length 199.7
  TOP w0.127: UE1.K6 v2(254.28,87.46)
  IN2 w0.122: v2(257.22,72.2) 257.13,72.29 253.21,72.29 252.72,71.8 v2(251.06,71.8) 249.69,71.8 248.9,71.01 245.72,71.01 244.75,70.04 243.92,70.04 243.33,69.45 242.04,69.45 241.21,68.63 236.68,68.63 236.41,68.36 235.4,68.36 232.5,65.46 231.32,65.46 231.31,65.46 228.02,65.46 227.5,64.94 226.05,64.94 225.22,64.12 205.7,64.12 204.09,65.73 186.41,65.73 184.83,67.31 180.65,67.31 178.45,69.5 176.92,69.5 173.3,73.11 171.55,73.11 171.08,72.64 169.91,72.64 168.77,73.78 168.77,77.95 168.26,78.46 168.26,81.42 166.28,83.39 166.28,85.02 164.4,86.9 164.4,88.1 163.6,88.9 163.02,88.9 162.54,89.38 162.23,89.38 162.05,89.56 162.05,89.89 161.55,90.39 158.44,90.39 158.2,90.63 152.14,90.63 151.13,89.62 v2(151.13,88.58)
  BOTTOM w0.076: 128.53,88.68 128.45,88.68 127.66,89.47 126.91,89.47 126.02,90.36 126.02,91.07 UC1.BA11
  BOTTOM w0.112: 131.17,86.04 134.02,86.04
  BOTTOM w0.127: v2(151.13,88.58) 151.13,88.81 v1(150.88,89.07) 150.64,89.31 148.51,89.31 148.22,89.01 146.58,89.01 143.75,86.18 138.71,86.18 138.23,85.7 138.23,85 137.82,84.59 136.49,84.59 135.79,85.29 134.77,85.29 134.02,86.04 ; 128.53,88.68 131.17,86.04 ; v2(257.22,72.2) 256.44,72.98 256.44,75.11 256.06,75.49 256.06,76.39 256.5,76.84 256.5,80.42 257.33,81.25 257.33,84.24 256.13,85.44 256.13,86.32 255.38,87.07 254.66,87.07 254.28,87.44 v2(254.28,87.46) ; RE560.2 241.09,55.08 244.8,58.79 244.8,59.64 246.76,61.6 246.76,62.56 248.46,64.27 248.46,68.05 249.03,68.62 249.03,68.91 251.06,70.95 v2(251.06,71.8)
FB_1.8VALW: length 4.7
  BOTTOM w0.127: v1(171.63,70.88) 172.09,70.41 PR506.1
  BOTTOM w0.254: PU501.6 172.52,67.43 PR501.2 PC503.2 172.55,70.41 PR506.1
FB_+1VALWP: length 6
  TOP w0.127: v1(157.66,81.45) 157.53,81.33 PR311.1
  TOP w0.254: PR306.2 154.26,80.45 155.14,81.32 PR308.2 155.19,81.33 PR311.1 156.59,81.74 PU301.14
FB_GT: length 6.2
  TOP w0.127: v1(53.72,91.79) 53.72,91.97 54.11,92.37 PR650.1
  TOP w0.203: PU602.17 51.12,94.77 51.42,95.06 51.82,95.06 51.99,94.89 51.99,94.2 PR648.2 53.36,93.7 PR645.2
  TOP w0.254: PR650.1 54.11,92.94 PR645.2
FB_VSA: length 5.6
  TOP w0.203: v2(49.33,98.31) 48.69,98.31 48.33,97.96 PU602.25
  BOTTOM w0.254: v2(49.33,98.31) 49.87,98.85 PR652.1 PR646.1 51.4,99.38 PR649.1
FCCM_GT: length 5.5
  TOP w0.203: PR662.1 53.42,100.02 52.07,98.67 51.54,98.67 51.13,98.26 51.13,97.87 50.42,97.16 50.05,97.16 49.93,97.04 PU602.21
FCCM_IA: length 25.8
  TOP w0.203: v2(51.3,91.94) 50.87,92.37 PU602.11
  TOP w0.254: v2(55.79,95.19) 55.98,95.38 PR671.1
  IN3 w0.254: v2(63.5,101.67) 63.35,101.83 62.08,101.83 60.92,100.66 56.55,100.66 55.76,99.88 54.63,99.88 54.05,99.3 54.05,96.06 54.3,95.81 55.45,95.81 55.79,95.46 v2(55.79,95.19) 55.79,95.12 55.11,94.44 54.42,94.44 51.93,91.94 v2(51.3,91.94)
  BOTTOM w0.254: PR659.1 61.88,102.74 v1(62.55,102.07) 62.95,101.67 v2(63.5,101.67)
FCCM_VSA: length 34.6
  TOP w0.203: v2(46.5,97.97) 46.73,97.74 PU602.29
  TOP w0.254: PR679.2 v2(59.47,116.09)
  IN1 w0.254: v2(46.5,97.97) 46.05,98.42 46.05,98.85 47.18,99.98 47.18,102.44 47.73,102.99 48.27,102.99 48.87,103.59 48.87,107.31 47.38,108.8 47.38,113.35 49.34,115.31 54.6,115.31 55.37,116.09 v2(59.47,116.09)
  BOTTOM w0.127: v1(45.17,98.49) 46.25,98.49 46.5,98.24 v2(46.5,97.97)
FIVR_EN: length 2.8
  BOTTOM w0.127: v1(93.05,125.3) 92.98,125.37 RC218.1 RC219.1 RC217.1
FIVR_EN_R: length 4.5
  BOTTOM w0.127: JXDP1.45 v1(90.31,128.09) 90.24,128.03 90.24,127.16 RC126.2 RC217.2 RC132.1
GPIO011: length 8.1
  TOP w0.127: T143.1 v2(259.54,85.46) ; UE1.K7 253.88,88.65 v2(254.25,88.29)
  IN1 w0.084: v2(254.25,88.29) 254.26,88.29 254.71,87.84 255.72,87.84 258.11,85.46 v2(259.54,85.46)
GPIO051: length 2.2
  TOP w0.127: UE1.D1 249.08,83.42 248.72,83.06 248.72,82.03 T141.1
GPIO054: length 5
  TOP w0.127: T142.1 257.88,93.85 257.67,93.64 257.67,92.73 257.15,92.22 255.04,92.22 UE1.L11
GPIO100: length 2.7
  TOP w0.127: T144.1 256.38,81.92 255.48,82.81 UE1.M1
GPP_B23: length 13.6
  TOP w0.127: RC317.1 139.22,97.37 138.98,97.13 138.45,97.13 138.23,96.91 138.23,96.8 137.32,95.9 134.26,95.9 133.95,95.58 132.01,95.58 130.69,96.91 v1(128.87,96.91) 128.57,96.91 v2(128.35,96.69)
  BOTTOM w0.102: UC1.AM7 128.71,97.05 v2(128.35,96.69)
GPP_C5: length 10.5
  BOTTOM w0.076: UC1.W1 132.79,103.29 135.33,103.29 135.51,103.47 136.85,103.47
  BOTTOM w0.127: 136.85,103.47 137.47,103.47 137.98,103.98 v1(138.76,103.98) 141.12,103.98 RC25.1
GPP_C8: length 5.2
  BOTTOM w0.076: UC1.AB1 132.46,101.89 133.74,101.89 133.89,102.05 135.54,102.05
  BOTTOM w0.127: 135.54,102.05 135.68,102.05 v1(136.26,101.47) 136.38,101.34 RC405.1
GPP_E23: length 1.3
  TOP w0.127: v2(126.15,105.81) 126.15,105.89 T120.1
  BOTTOM w0.102: v2(126.15,105.81) 126.15,106.04 UC1.N12
GPS_DISABLE#: length 70.1
  TOP w0.127: UE1.H5 v2(252.68,86.66) ; DZ6.1 240.9,106.71 v1(241.9,107.71) v2(242.59,108.41) ; v2(259.29,80.32) 259.55,80.32 RE12.1
  IN1 w0.084: v2(265.17,108.47) 264.11,107.41 264.11,99.29 263.41,98.59 263.41,96.49 262.72,95.79 262.72,86.1 262.24,85.62 262.24,81.13 261.57,80.45 259.47,80.45 259.39,80.37 259.35,80.37 259.31,80.32 v2(259.29,80.32)
  IN2 w0.122: v2(259.29,80.32) 259.27,80.32 258.41,81.19 258,81.19 254.53,84.66 253.84,84.66 253.67,84.49 252.47,84.49 252.2,84.77 252.2,86.17 v2(252.68,86.66)
  BOTTOM w0.127: v2(265.17,108.47) 258.79,108.47 258.66,108.6 254.6,108.6 253.99,107.99 251.2,107.99 250.59,108.6 242.78,108.6 v2(242.59,108.41)
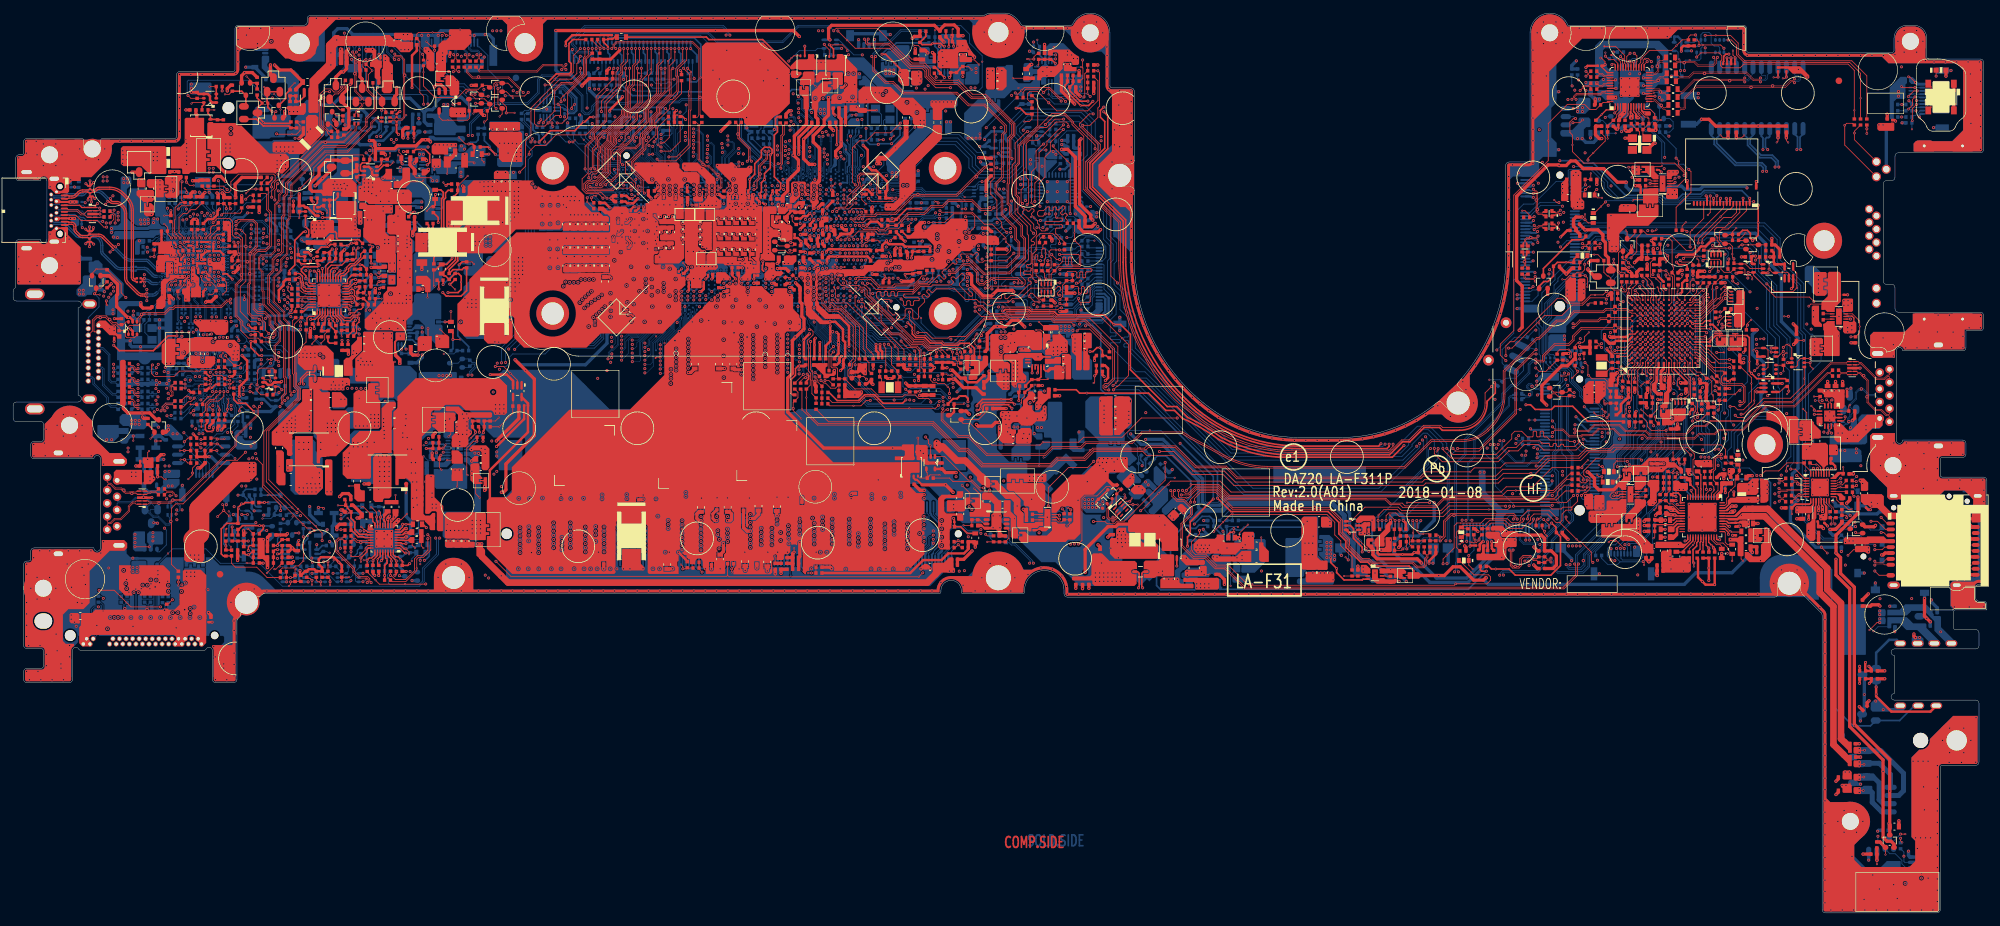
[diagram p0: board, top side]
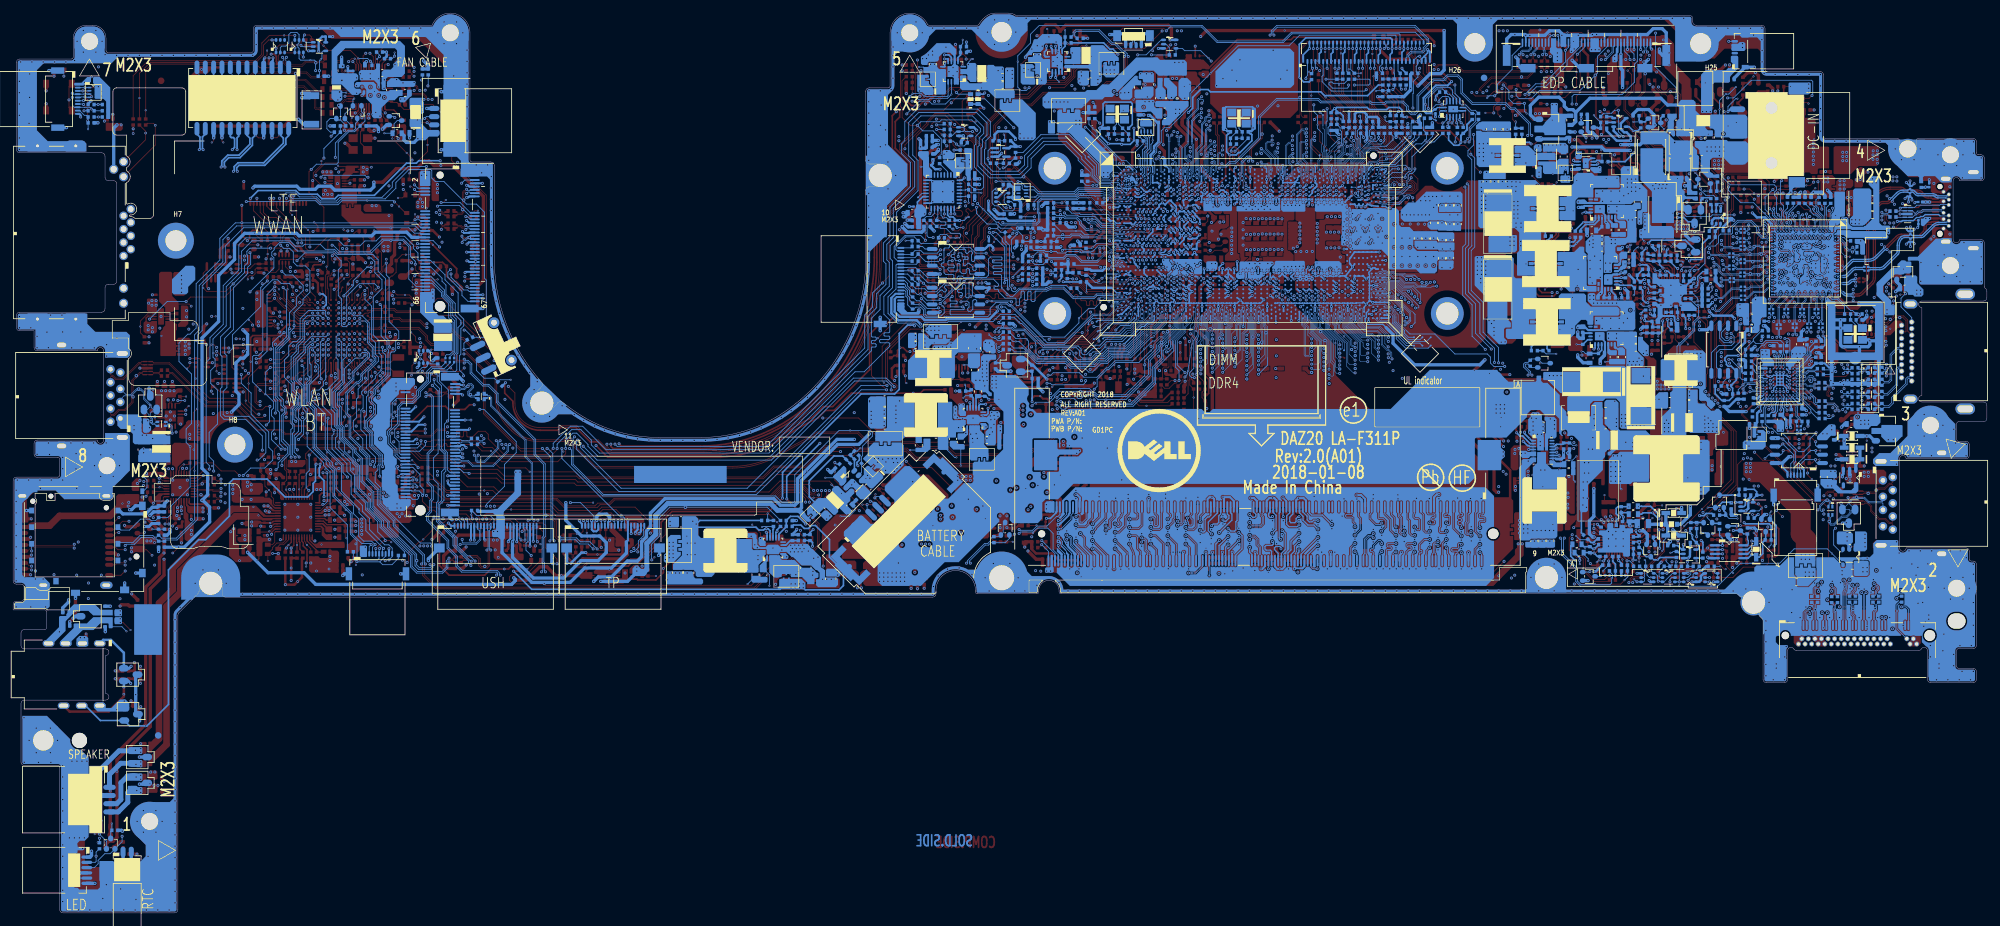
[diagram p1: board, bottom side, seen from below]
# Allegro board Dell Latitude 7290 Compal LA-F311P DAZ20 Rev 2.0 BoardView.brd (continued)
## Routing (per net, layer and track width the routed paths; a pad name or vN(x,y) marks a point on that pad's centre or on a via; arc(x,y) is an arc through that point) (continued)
GPS_DISABLE#_R: length 3.9
  TOP w0.127: DZ6.2 239.96,105.21 v2(239.47,105.7) v1(239.47,106.51)
  BOTTOM w0.127: JNGFF2.18 238.64,105.5 238.84,105.7 v2(239.47,105.7)
GPU_B+:
  vias: v2(52.55,84.21) v2(52.93,83.58) v2(52.99,84.58) v2(53.28,84.08) v2(53.51,83.55) v2(53.86,84.08) v2(54.09,83.55) v2(54.45,84.08) v2(54.7,83.54) v2(56.42,88.3) v2(56.42,87.63) v2(57.64,88.3) v2(57.64,87.63) v3(52.32,81.85)
GPU_PWR_LEVEL: length 5.7
  TOP w0.127: UE1.E12 249.48,93.06 249.48,93.76 249.63,93.91 249.63,95.2 v1(249.08,95.75) 249.03,95.8 249.03,96.31 248.52,96.82 248.18,96.82 248.05,96.95 248.05,97.15 RE5.1
GPU_SMCLK: length 18.5
  TOP w0.127: RPE12.1 260.64,90.93 v2(259.83,90.13) 259.83,89.74 v1(259.7,89.61) ; UE1.F7 v2(250.31,88.28)
  IN4 w0.084: v2(259.83,90.13) 259.5,90.46 257.62,90.46 256.25,89.09 248.58,89.09 248.26,88.77 248.26,88.09 248.4,87.95 248.98,87.95 249.06,87.87 249.9,87.87 v2(250.31,88.28)
GPU_SMDAT: length 17.2
  TOP w0.127: v2(247.11,87.48) 247.48,87.85 UE1.B6 ; RPE12.2 261.05,90.43 v2(260.87,90.25)
  IN4 w0.084: v2(247.11,87.48) 247.11,88.7 247.69,89.27 256.17,89.27 257.55,90.65 259.82,90.65 259.91,90.56 260.56,90.56 v2(260.87,90.25)
GT_SNUB: length 2.1
  TOP w0.127: PR669.2 v3(63.21,89.1)
GT_SW: length 2.3
  TOP w0.127: PR669.1 65.87,88.15 v1(65.05,88.97)
  vias: v2(64.57,87.95) v2(64.98,87.51)
H_CATERR#: length 9.1
  BOTTOM w0.076: UC1.D63 96.89,111.69 96.97,111.96 96.97,112.07 97.11,112.55 97.11,112.8 97.07,112.89 97.07,113.08 97.11,113.18 97.11,113.54 96.94,113.71 96.94,114.76 96.44,115.26 96.44,116.25 95.95,116.74
  BOTTOM w0.102: RC79.1 96.16,119.63 96.16,118.15 v1(96.01,118) 95.95,117.94 95.95,116.74
H_CPU_SVIDALRT#: length 8.2
  BOTTOM w0.076: UC1.B63 96.36,112.98 96.36,113.48 96.44,113.56 96.44,114.41 95.6,115.25 95.6,116.23 94.98,116.85
  BOTTOM w0.127: RC153.1 93.22,118.53 93.22,118.06 v1(93.31,117.96) 93.42,117.85 93.99,117.85 94.98,116.85
H_CPUPWRGD: length 13.5
  BOTTOM w0.127: UC1.A68 93.19,113.67 92.66,113.67 92.22,114.11 90.13,114.11 86.98,117.26 86.12,117.26 v1(85.58,117.79) 85.37,118.01 CC300.1 85.84,119.35 85.84,121.02 RC77.2
H_CPUPWRGD_R: length 1
  BOTTOM w0.127: RC77.1 84.47,121.17 84.24,120.94 84.04,120.94 T9.1
H_THERMTRIP#: length 343.6
  TOP w0.127: v2(264.63,100.67) 264.54,100.67 QE4.3 ; RD14.2 108.85,51.48 ; 108.85,51.48 109.07,51.26 v1(137.98,51.26) v2(138.58,51.85) ; 108.85,51.48 108.85,51.45 108.72,51.32 75.84,51.32 v2(73.56,53.6)
  IN1 w0.084: v2(263.52,69.05) 263.42,68.95 263.42,67.14 261.62,65.34 260.09,65.34 259.88,65.56 252.04,65.56 250.56,64.07 248.55,64.07 242.54,58.06 242.54,53.3 238.72,49.47 186.88,49.47 185.42,50.94 184.1,50.94 181.98,53.06 178.07,53.06 176.94,54.19 161.53,54.19 160.08,55.64 148.33,55.64 145.96,53.27 142.31,53.27 140.89,51.85 v2(138.58,51.85)
  IN4 w0.084: v2(79.53,110.69) 79.73,110.89 79.73,111.69 79.14,112.28 79.14,114.82 80.92,116.6 87.78,116.6 89.3,118.12 89.3,118.45 90.31,119.45 93.5,119.45 v2(95.55,121.5) ; v2(76.41,85.93) 75.94,85.45 75.94,75.46 74.96,74.48 74.96,59.69 74.07,58.8 74.07,54.12 v2(73.56,53.6)
  BOTTOM w0.076: 96.08,116.33 96.26,116.14 96.26,115.15 96.77,114.64 96.77,113.64 96.94,113.47 96.94,113.21 96.89,113.09 96.89,112.94 96.94,112.75 96.94,112.58 96.86,112.32 UC1.C63
  BOTTOM w0.127: v2(95.55,121.5) 95.41,121.36 RC80.1 CC312.1 95.91,119.28 95.91,118.39 95.65,118.13 95.65,116.75 96.08,116.33 ; v2(264.63,100.67) 264.51,100.56 264.51,98.9 264.97,98.44 264.97,97.49 267.14,95.31 267.14,88.93 268.47,87.6 268.47,85.31 268.13,84.97 268.13,80.08 268.69,79.52 268.69,76 268.42,75.72 264.78,75.72 262.2,73.14 262.2,70.15 263.31,69.05 v2(263.52,69.05) ; v2(79.53,110.69) 79.39,110.56 79.39,102 79.86,101.53 79.86,94.16 78.43,92.73 78.43,87.94 v2(76.41,85.93)
H_VCCST_PWRGD_XDP: length 115.9
  TOP w0.127: RC124.2 124.27,81.18 v2(123.69,81.18) ; v2(89.62,122.2) v1(89.62,122.71) 89.62,123.77 91.84,125.99 91.84,128.2 92.11,128.47 v2(92.11,128.79)
  IN1 w0.084: v2(75.02,83.94) 75.79,83.17 80.47,83.17 85.71,77.93 116.92,77.93 117.98,78.99 121.83,78.99 123.69,80.84 v2(123.69,81.18)
  IN4 w0.084: v2(89.62,122.2) 89.62,121.87 88.58,120.83 88.07,120.83 85.91,118.67 78.21,118.67 v2(78.19,118.69)
  BOTTOM w0.127: RC123.2 90,121.82 v2(89.62,122.2) ; v2(78.19,118.69) 78.19,117.09 79.06,116.23 79.06,115.44 78.47,114.86 78.47,101.69 78.99,101.18 78.99,94.68 77.24,92.93 77.24,88.33 75.02,86.11 v2(75.02,83.94) ; JXDP1.39 92.11,129.41 92.54,128.98 92.54,128.48 CC307.1 92.09,128.76 v2(92.11,128.79)
HDA_BIT_CLK: length 12.1
  TOP w0.127: v2(120.38,82.1) 119.09,80.81 RC93.2
  BOTTOM w0.076: 120.11,87.99 120.11,90.09 119.83,90.36 119.83,90.94 119.98,91.09 119.98,91.4 120.05,91.61 120.15,91.72 120.25,91.83 UC1.AY22
  BOTTOM w0.127: v2(120.38,82.1) 120.46,82.19 120.46,87.1 v1(120.39,87.29) 120.11,87.99
HDA_BIT_CLK_R: length 176.4
  TOP w0.127: RC93.1 119.57,79.39 119.57,78.56 CC27.1 118.85,77.84 v2(118.85,76.92) 118.85,76.59 v1(120.07,75.37) ; v2(257.96,64.58) 257.96,65.26 257.76,65.47 RA17.1 257.53,65.29 UA1.6
  IN2 w0.122: v2(118.85,76.92) 120.67,76.92 124.48,80.73 127.14,80.73 130.58,77.29 134.5,77.29 135.89,78.69 136.79,78.69 136.93,78.83 137.51,78.83 137.92,78.42 137.92,76.12 140.73,73.31 140.73,72.57 144.41,68.89 144.41,65.29 148.15,61.55 148.15,59.29 149.27,58.18 154.97,58.18 155.29,58.49 166.85,58.49 167.1,58.74 168.05,58.74 168.38,59.07 170.05,59.07 170.65,58.47 171.92,58.47 172.05,58.34 173.39,58.34 174.58,57.16 184.02,57.16 185.38,58.53 194.81,58.53 195.81,57.53 198.78,57.53 198.92,57.4 201.13,57.4 203.51,55.02 203.51,54.66 204.57,53.61 208.63,53.61 209.3,54.28 213.47,54.28 213.69,54.49 213.7,54.49 214,54.79 219.93,54.79 220.09,54.95 222.05,54.95 222.27,54.73 226.28,54.73 226.8,54.21 229.41,54.21 229.74,54.54 232.59,54.54 233.44,55.38 235.27,55.38 236.4,56.52 237.43,56.52 237.7,56.78 240.82,56.78 241.07,57.03 243.46,57.03 245.51,59.09 245.51,60.62 249.45,64.56 249.98,64.56 250.76,65.34 252.63,65.34 253.24,65.95 254.97,65.95 255.33,65.59 256.95,65.59 v2(257.96,64.58)
HDA_RST#: length 15.7
  TOP w0.127: v2(121.5,87.13) 121.46,87.09 121.46,82.85 v1(121.67,82.65) 121.74,82.58 121.74,81.22 121.69,81.18 121.69,79.16 CC331.1 RC95.2
  BOTTOM w0.076: UC1.AW22 120.54,92.18 120.54,90.59 120.67,90.34 120.67,89.56 120.95,89.28 120.95,87.97 v2(121.5,87.13)
HDA_RST#_R: length 148.6
  TOP w0.127: RA50.1 260.88,70.7 260.21,71.37 243.82,71.37 243.23,70.78 239.57,70.78 238.49,69.7 233.43,69.7 232.34,68.61 227.32,68.61 226.56,67.85 222.6,67.85 v1(222.01,67.25) 215.15,67.25 214.35,66.46 186.5,66.46 184.83,68.13 180.22,68.13 177.14,71.21 172.7,71.21 172.35,70.86 164.46,70.86 163.08,69.48 158.98,69.48 158.02,68.52 147.77,68.52 145.45,70.84 144.28,70.84 140.24,74.88 124.23,74.88 RC95.1
HDA_SDIN0: length 164.7
  TOP w0.127: v2(121.33,88.94) 121.59,88.94 121.87,88.66 121.87,88.14 121.05,87.32 121.05,86.75 121.19,86.62 121.19,82.55 121.5,82.24 121.5,81.31 121.43,81.25 121.43,80.46 CC332.1 v1(120.85,78.58) 120.85,76.45 122.67,74.63 140.13,74.63 144.17,70.59 145.34,70.59 147.66,68.27 158.13,68.27 159.09,69.22 163.19,69.22 164.57,70.61 172.59,70.61 172.94,70.95 177.03,70.95 180.11,67.87 184.73,67.87 186.4,66.2 214.45,66.2 214.85,66.6 225.86,66.6 226.9,67.64 232.13,67.64 233.83,69.34 238.59,69.34 239.77,70.52 243.38,70.52 243.86,71 255.13,71 256.13,69.99 256.13,69.3 255.93,69.1 255.93,66.94 256.49,66.38 RA9.1
  BOTTOM w0.076: UC1.BA21 120.82,90.51 121.03,90.31 121.03,89.9 121.33,89.6 v2(121.33,88.94)
HDA_SDIN0_R: length 2.1
  TOP w0.127: RA9.2 256.56,65.01 256.73,64.85 UA1.8
HDA_SDOUT: length 13.9
  TOP w0.127: RC94.2 RC223.2 RC187.1 123.23,79.37 CC333.1 122.6,80.94 122.6,81.22 122.17,81.65 v2(122.17,81.72)
  BOTTOM w0.076: UC1.BB22 120.48,90.23 120.48,89.46 120.76,89.18 120.76,87.86 121.08,87.35 121.08,86.85
  BOTTOM w0.102: 122.03,81.86 122.03,81.86
  BOTTOM w0.127: 122.03,81.86 121.79,82.21 v1(121.19,86.13) 121.08,86.85 ; 122.03,81.86 v2(122.17,81.72)
HDA_SDOUT_R: length 162.9
  TOP w0.127: v2(130.59,78.14) 129.97,78.14 129.16,77.32 v1(128.03,77.32) 124.44,77.32 RC94.1 ; UA1.5 257.93,63.93 v2(258.57,64.58)
  IN2 w0.122: v2(258.57,64.58) 258.57,64.68 257.16,66.09 255.54,66.09 255.18,66.45 252.8,66.45 252.19,65.84 250.55,65.84 249.77,65.06 249.24,65.06 245.01,60.83 245.01,59.29 243.25,57.53 240.83,57.53 240.69,57.39 236.56,57.39 235.06,55.88 233.23,55.88 232.38,55.04 229.53,55.04 229.2,54.71 227,54.71 226.48,55.23 222.48,55.23 222.26,55.45 219.88,55.45 219.72,55.29 215.83,55.29 215.49,55.63 213.14,55.63 212.29,54.78 209.09,54.78 208.42,54.11 204.77,54.11 204.02,54.87 204.02,55.23 201.34,57.9 199.12,57.9 198.99,58.04 196.02,58.04 195.02,59.03 184.57,59.03 183.2,57.67 174.78,57.67 173.6,58.84 172.26,58.84 172.13,58.97 170.86,58.97 170.26,59.57 168.17,59.57 167.84,59.24 166.89,59.24 166.67,59.03 151.26,59.03 150.71,59.57 149.65,59.57 148.66,60.56 148.66,61.75 146.12,64.29 146.12,65.3 144.91,66.51 144.91,69.1 141.23,72.78 141.23,73.1 141.23,73.52 138.47,76.28 138.47,78.6 138.58,78.71 138.58,79.68 138.09,80.16 137.15,80.16 136.24,79.26 135.67,79.26 135.47,79.06 132.67,79.06 131.75,78.14 v2(130.59,78.14)
HDA_SYNC: length 12.3
  TOP w0.127: v2(120.74,81.61) 120.5,81.61 119.98,81.09 RC92.2
  BOTTOM w0.076: 120.34,88 120.27,88.19 120.27,88.56 v1(120.46,88.75) 120.46,89.16 120.27,89.35 120.27,90.2 120,90.48 120,90.85 120.25,91.11 UC1.BA22
  BOTTOM w0.127: 120.34,88 120.83,87.26 120.83,83.01 121.44,82.4 121.44,81.9 121.16,81.61 v2(120.74,81.61)
HDA_SYNC_R: length 154.9
  TOP w0.127: v2(255.6,69.81) 254.68,70.73 244.24,70.73 243.78,70.27 240.08,70.27 238.81,68.99 233.99,68.99 231.29,66.29 227.03,66.29 226.28,65.54 215.23,65.54 214.87,65.19 185.98,65.19 184.31,66.86 179.6,66.86 176.69,69.77 172.69,69.77 172.11,70.35 164.68,70.35 163.29,68.97 159.19,68.97 158.23,68.01 147.56,68.01 145.23,70.33 144.07,70.33 140.03,74.37 122.56,74.37 v1(120.18,76.76) 120.18,79.67 RC92.1 ; v2(255.65,64.43) 255.65,64.19 255.93,63.92 UA1.10
  BOTTOM w0.127: v2(255.6,69.81) 255.6,67.45 256.06,66.99 256.06,64.83 v2(255.65,64.43)
HDMI_CEC: length 42.6
  TOP w0.127: v1(27.51,110.93) 26.89,110.93 v2(26.39,111.43)
  TOP w0.254: RV19.1 26.38,111.44 v2(26.39,111.43)
  IN1 w0.254: JHDMI1.13 12.2,87.85 12.2,90.03 13.12,90.95 13.12,95.05 14.78,96.71 15.49,96.71 18.15,94.05 18.15,93.67 19.28,92.54 21.55,92.54 22.66,93.65 22.66,94.33 22.83,94.5 22.83,103.08 24.6,104.85 24.6,108.72 26.39,110.51 v2(26.39,111.43)
HDMI_CLKN: length 3.8
  TOP w0.114: v2(19.03,81.17) 18.86,81.01 18.73,81.01 18.58,81.16 18.58,81.44 18.36,81.66 18.04,81.66 RV17.1
  BOTTOM w0.114: LV38.1 18.04,81.35 LV12.1 18.36,81.03 18.88,81.03 v2(19.03,81.17) 19.45,81.17 CV38.1
HDMI_CLKP: length 3.8
  TOP w0.114: v2(19.03,80.59) 18.86,80.76 18.63,80.76 18.33,81.05 18.33,81.34 18.26,81.41 18.04,81.41 RV16.1
  BOTTOM w0.114: CV37.1 19.5,80.59 v2(19.03,80.59) 18.83,80.78 18.36,80.78 LV12.2 18.04,80.47 LV37.1
HDMI_CTRL_CLK: length 9.1
  TOP w0.127: JHDMI1.15 12.06,88.71 12.06,90.41 12.68,91.03 14.19,91.03 v4(14.72,90.5) 15.19,90.03 15.68,90.03 16.02,89.69 RV22.1 16.77,89.69 17.2,90.12 QV3.6
HDMI_CTRL_DATA: length 11.1
  TOP w0.127: JHDMI1.16 12.4,88.6 12.32,88.68 12.32,90.31 12.79,90.78 v4(13.27,90.78) 14.08,90.78 15.09,89.78 15.58,89.78 16.16,89.19 16.16,88.77 RV23.1 16.7,88.77 17.1,88.37 17.1,87.96 17.35,87.7 18.47,87.7 18.87,88.1 QV3.3
HDMI_HPD: length 9.1
  TOP w0.127: RV21.1 13.35,95.26 QV5.1 12.66,94.68 v2(12.39,94.41) 12.53,94.27 v1(13.18,94.27)
  BOTTOM w0.127: v2(12.39,94.41) 13.08,93.72 13.08,92.41 11.45,90.78 JHDMI1.19
HDMI_L_CLKN: length 9.1
  BOTTOM w0.114: JHDMI1.12 13.38,86.22 13.67,86.22 14.74,85.15 14.74,81.32 15.02,81.05 15.68,81.05 RV35.1 16.33,81.03 16.66,81.03 16.81,81.18 LV12.4 17.12,81.35 LV38.2
HDMI_L_CLKP: length 9.1
  BOTTOM w0.114: JHDMI1.10 13.38,85.98 13.57,85.98 14.5,85.05 14.5,81.22 14.91,80.8 15.64,80.8 RV35.2 16.33,80.78 16.67,80.78 16.82,80.63 LV12.3 17.12,80.47 LV37.2
HDMI_L_TX_N0: length 11.2
  IN4 w0.094: JHDMI1.9 11.84,84.71 12.11,84.71 12.34,84.48 12.34,81.24 12.65,80.94 13.8,80.94 14.22,81.35 14.22,82.35 14.74,82.87 15.11,82.87 v2(15.3,83.06)
  BOTTOM w0.114: v2(15.3,83.06) 15.49,82.87 15.66,82.87 RV32.1 16.33,82.87 16.68,82.87 16.83,83.02 LV9.4 17.12,83.19 LV36.2
HDMI_L_TX_N1: length 7.8
  BOTTOM w0.114: JHDMI1.6 13.38,83.22 13.59,83.22 13.85,82.95 13.85,80.54 15.19,79.21 15.68,79.21 RV29.1 16.33,79.19 16.69,79.19 16.84,79.34 LV6.4 17.12,79.5 LV34.2
HDMI_L_TX_N2: length 8.9
  BOTTOM w0.114: JHDMI1.3 11.83,81.72 12.09,81.72 12.39,81.42 12.39,80.72 14.5,78.61 14.5,77.81 14.98,77.33 15.64,77.33 RV26.1 16.33,77.35 16.8,77.35 LV3.4 17.12,77.66 LV32.2
HDMI_L_TX_P0: length 11.2
  IN4 w0.094: v2(15.3,82.47) 15.13,82.64 14.83,82.64 14.45,82.25 14.45,81.26 13.9,80.71 12.55,80.71 12.11,81.15 12.11,84.39 12.02,84.49 11.84,84.49 JHDMI1.7
  BOTTOM w0.114: v2(15.3,82.47) 15.46,82.63 15.66,82.63 RV32.2 16.33,82.63 16.67,82.63 16.82,82.47 LV9.3 17.12,82.31 LV35.2
HDMI_L_TX_P1: length 7.8
  BOTTOM w0.114: LV33.2 17.12,78.63 LV6.3 16.8,78.79 16.65,78.94 16.33,78.94 RV29.2 15.64,78.96 15.09,78.96 13.61,80.44 13.61,82.85 13.48,82.98 13.38,82.98 JHDMI1.4
HDMI_L_TX_P2: length 8.9
  BOTTOM w0.114: LV31.2 17.12,76.79 LV3.3 16.81,77.1 16.33,77.1 RV26.2 15.68,77.08 14.88,77.08 14.26,77.71 14.26,78.51 12.15,80.62 12.15,81.32 11.99,81.48 11.83,81.48 JHDMI1.1
HDMI_OB: length 7
  TOP w0.508: QV4.1 21.85,75.19 20.8,76.24 v1(19.63,76.24) 17.46,76.24 16.8,76.89 RV10.2
HDMI_TX_N0: length 3.9
  TOP w0.114: v2(19.03,83.02) 18.86,82.85 18.67,82.85 18.58,82.94 18.58,83.18 18.32,83.44 18.04,83.44 RV15.1
  BOTTOM w0.114: LV36.1 18.04,83.19 LV9.1 18.36,82.87 18.88,82.87 v2(19.03,83.02) 19.21,82.83 19.47,82.83 19.63,82.99 CV36.2
HDMI_TX_N1: length 4.2
  TOP w0.114: RV13.1 18,79.93 18.33,79.93 18.57,79.69 18.57,79.29 18.7,79.16 18.86,79.16 v2(19.03,79.33)
  BOTTOM w0.114: CV34.2 19.63,79.3 19.49,79.16 19.2,79.16 v2(19.03,79.33) 18.86,79.16 18.38,79.16 LV6.1 18.04,79.5 LV34.1
HDMI_TX_N2: length 4.2
  TOP w0.114: v2(19.03,77.49) 18.86,77.32 18.7,77.32 18.57,77.45 18.57,77.96 18.26,78.27 18.06,78.27 RV11.1
  BOTTOM w0.114: LV32.1 18.04,77.66 LV3.1 18.36,77.35 18.88,77.35 v2(19.03,77.49) 19.18,77.34 19.29,77.34 CV32.2
HDMI_TX_P0: length 4
  TOP w0.114: RV14.1 18.04,83.19 18.22,83.19 18.33,83.08 18.33,82.84 18.57,82.6 18.86,82.6 v2(19.03,82.43)
  BOTTOM w0.114: CV35.2 19.63,82.41 19.45,82.59 19.18,82.59 v2(19.03,82.43) 18.84,82.62 18.35,82.62 LV9.2 18.04,82.31 LV35.1
HDMI_TX_P1: length 4.1
  TOP w0.114: v2(19.03,78.75) 18.86,78.92 18.59,78.92 18.32,79.19 18.32,79.59 18.23,79.68 18,79.68 RV12.1
  BOTTOM w0.114: CV33.2 19.63,78.8 19.51,78.92 19.2,78.92 v2(19.03,78.75) 18.86,78.92 18.33,78.92 LV6.2 18.04,78.63 LV33.1
HDMI_TX_P2: length 4.2
  TOP w0.114: v2(19.03,76.91) 18.86,77.08 18.59,77.08 18.32,77.35 18.32,77.86 18.16,78.02 17.95,78.02 RV10.1
  BOTTOM w0.114: CV31.2 19.32,77.09 19.21,77.09 v2(19.03,76.91) 18.84,77.1 18.36,77.1 LV3.2 18.04,76.79 LV31.1
HOST_DEBUG_TX: length 104.6
  TOP w0.127: UE1.G11 v2(251.08,92.26) ; v1(236.03,96.59) 236.53,96.59 237.16,97.22 RZ132.1 238.26,97.69 239.05,97.69 239.43,98.07 v2(239.43,98.91)
  IN1 w0.084: v2(291.68,124.34) 290.48,124.34 286.41,128.41 258.71,128.41 251.9,121.59 251.9,119.76 252.63,119.03 252.63,115.2 250.7,113.28 250.7,104.94 252.11,103.54 v2(252.11,101.81) 252.11,101.47 250.72,100.08 250.72,98.95 251.31,98.36 251.31,96.02 251.17,95.88 251.17,93.75 251.51,93.41 251.51,92.91 251.08,92.49 v2(251.08,92.26)
  BOTTOM w0.127: v2(252.11,101.81) 251.93,101.81 250.99,100.88 246.29,100.88 244.43,102.74 241.25,102.74 240.14,101.64 240.14,100.07 239.43,99.35 v2(239.43,98.91) ; v2(291.68,124.34) 291.68,123.16 291.36,122.84 JDEG1.8 289.84,122.84 289.78,122.78 288.84,122.78 RE306.2 RE73.2
HOST_SD_WP#: length 204.7
  TOP w0.127: v2(280.69,58.02) 280.81,57.91 QR1.2
  IN1 w0.084: v2(280.69,58.02) 279.7,58.02 277.65,60.08 276.5,60.08 275.63,59.21 270.97,59.21 266.67,63.52 266.67,67.43 263.93,70.17 263.93,70.45 261.37,73.02 v2(260.89,73.02)
  IN2 w0.122: v2(147.62,99.69) 147.81,99.5 148.47,99.5 150.98,96.99 150.98,92.91 151.92,91.97 158,91.97 158.76,91.2 162.53,91.2 163.87,89.85 163.87,89.26 164.85,88.28 164.85,87.09 166.8,85.13 166.8,83.51 168.71,81.6 168.71,78.65 169.22,78.14 169.22,74.55 169.94,73.82 173.23,73.82 177.1,69.95 178.64,69.95 180.83,67.75 185.1,67.75 186.67,66.18 204.59,66.18 206.14,64.63 225.1,64.63 225.87,65.39 227.3,65.39 227.81,65.91 231.5,65.91 232.32,65.91 235.22,68.81 236.23,68.81 236.49,69.07 240.3,69.07 241.36,70.13 242.86,70.13 243.58,70.86 244.58,70.86 245.18,71.46 248.65,71.46 249.6,72.41 250.09,72.41 250.42,72.75 256.21,72.75 256.57,73.11 258.05,73.11 258.14,73.02 v2(260.89,73.02) ; v2(124.76,101.76) 125.37,101.15 130.07,101.15 130.55,100.67 130.55,99.92 130.69,99.79 131.84,98.64 133.88,98.64 134.18,98.94 134.66,98.94 135,98.6 v2(135,98.45)
  IN4 w0.084: v2(135,98.45) 135.06,98.5 140.98,98.5 142.22,99.75 144.17,99.75 145.11,100.68 145.71,100.68 146.36,100.03 147.28,100.03 v2(147.62,99.69)
  BOTTOM w0.076: 135.54,98.75 135.31,98.75 v2(135,98.45) ; UC1.W10 126.79,103.49 124.99,103.49 124.84,103.34 124.84,103.06 125.09,102.81 125.09,102.53 124.76,102.11 v2(124.76,101.76)
  BOTTOM w0.127: RC292.1 138.89,98.75 135.54,98.75
HP_OUT_L: length 11.4
  TOP w0.203: v2(258.34,55.64) 257.93,56.05 UA1.32
  TOP w0.381: v2(258.34,55.64) RA7.1 ; CA43.2 v2(251.69,57.29)
  IN1 w0.381: v2(258.34,55.64) 257.83,55.64 257.58,55.38 253.59,55.38 v2(251.69,57.29)
  BOTTOM w0.127: v2(258.34,55.64) v1(258.34,54.87)
HP_OUT_R: length 12.7
  TOP w0.203: 259.04,55.78 v1(258.76,56.06) 258.33,56.5 UA1.33
  TOP w0.381: RA8.1 259.23,55.45 v2(259.04,55.64) 259.04,55.78 ; CA44.2 v2(251.69,58.49)
  IN1 w0.381: v2(259.04,55.64) 259.04,56.09 258.66,56.47 257.65,56.47 257.2,56.02 253.9,56.02 251.69,58.23 v2(251.69,58.49)
HV_GATE1_A: length 3
  BOTTOM w0.076: 35.11,82.29 35.04,82.22 33.77,82.22 UT5.B9
  BOTTOM w0.127: 35.11,82.29 35.38,82.56 35.38,82.74 RT64.1
HV_GATE2_A: length 2.9
  BOTTOM w0.076: UT5.A9 34.84,82.47 35.11,82.75
  BOTTOM w0.127: 35.11,82.75 35.11,83.37 RT65.1
HW_ACAVIN_NB: length 373.4
  TOP w0.127: UE1.N6 257.73,87.86 v2(257.79,87.92)
  TOP w0.203: PC1207.1 PR1203.2 40.28,56.22 v2(40.28,56.02) PR1206.2
  IN2 w0.122: v2(257.79,87.92) 257.4,87.53 257.4,86.45 257.75,86.1 257.75,85.84 262.6,80.99 262.6,76.78 260.63,74.81 258.6,74.81 256.77,76.64 253.28,76.64 251.67,75.03 241.51,75.03 241.46,74.98 237.39,74.98 236.3,73.9 236.3,72.75 235.09,71.54 233.56,71.54 233.3,71.81 230.76,71.81 227.76,68.81 226.63,68.81 226.01,68.18 222.91,68.18 222.25,67.52 207.31,67.52 205.93,68.91 187.81,68.91 186.17,70.55 181.96,70.55 178.38,74.13 177.47,74.13 176.39,75.21 176.39,75.66 171.62,80.43 171.62,82.68 169.64,84.66 169.64,86.3 167.73,88.2 167.73,89.38 167.04,90.07 167.04,92.15 165.9,93.29 165.9,103.37 164.01,105.26 164.01,107.22 162.14,109.08 162.14,117.24 161.81,117.58 161.81,120.46 159.45,122.82 158.03,124.24 157.07,124.24 154.71,126.6 148.32,126.6 147.44,127.49 146.46,127.49 144.68,129.27 144.68,129.27 142.77,131.18 141.15,131.18 139.68,132.66 135.91,132.66 135.28,132.02 128.45,132.02 127.87,132.6 126.1,132.6 124.73,131.23 116.25,131.23 115.1,130.08 87.36,130.08 87.17,129.89 83.8,129.89 80.38,126.47 74.93,126.47 74.5,126.91 69.43,126.91 67.76,125.24 61.85,125.24 60.15,123.54 57.3,123.54 v2(56.15,122.39)
  IN4 w0.084: v2(55.4,118.37) 55.1,118.08 55.1,116.27 51.46,112.63 51.46,104.09 53.06,102.49 53.06,101.1 50.67,98.72 50.67,89.54 47.92,86.79 43.76,86.79 42.55,85.58 42.55,80.03 40.06,77.54 40.06,76.47 38.47,74.87 38.47,71.11 39.02,70.56 39.02,60.75 40.28,59.48 v2(40.28,56.02) 40.74,56.02 41.96,54.8 43.6,54.8 44.92,53.48 v2(45.6,53.48)
  BOTTOM w0.127: PR1241.1 PR1258.1 v2(45.6,53.48) ; v2(55.4,118.37) 56.15,119.12 v2(56.15,122.39) 56.73,122.39 57.19,121.93 58.38,121.93 58.55,121.77 58.84,121.47 PR21.1
  BOTTOM w0.203: PU1201.1 40.31,56.04 v2(40.28,56.02) 40.28,57.11 v1(40.61,57.44) 40.73,57.55 PR941.1
I2C1_SCK_TP: length 143.8
  TOP w0.127: v2(179.97,62.63) 179.97,63.18 180.93,64.13 183.17,64.13 185.75,61.55 200.5,61.55 202.27,59.78 202.27,57.98 203.35,56.9 203.35,55.88 205.45,53.79 206.52,53.79 207.05,53.25 213.17,53.25 213.79,52.63 214.93,52.63 215.27,52.97 215.27,53.91 215.54,54.17 215.54,54.63 RZ21.2 215.85,55.8 RZ29.1
  IN1 w0.084: v2(179.97,62.63) 179.81,62.8 179.81,64.25 177.44,66.61 176,66.61 171.5,71.11 164.04,71.11 163.42,70.49 151.61,70.49 151.05,71.05 151.05,74.78 150.27,75.56 150.27,84.33 151.18,85.24 151.18,86.69 151.75,87.25 151.75,90.13 153.08,91.47 153.08,95.03 152.06,96.05 152.06,101.62 151.72,101.96 151.72,102.85 150.84,103.72 150.84,105.28 149.85,106.27 149.34,106.27 146.2,109.41 137.95,109.41 135.51,106.97 132.26,106.97 130.73,105.44 128.22,105.44 127.65,104.86 127.63,104.86 v2(127.61,104.84)
  BOTTOM w0.076: v2(127.61,104.84) 127.61,104.39 UC1.U9
I2C1_SCK_TP_R: length 6.6
  TOP w0.127: v2(213.84,59.83) 213.88,59.79 213.88,58.16 214.25,57.8 v1(214.81,57.8) 215.66,57.8 RZ347.2 215.85,56.74 RZ29.2 RZ117.2
  BOTTOM w0.127: v2(213.84,59.83) 213.55,59.54 JKBTP1.2
I2C1_SDA_TP: length 142.8
  TOP w0.127: RZ26.1 214.98,55.8 RZ20.2 215.3,54.63 215.3,54.27 215.03,54.01 215.03,53.07 214.83,52.87 213.89,52.87 213.27,53.49 207.15,53.49 206.61,54.02 205.55,54.02 203.59,55.98 203.59,57 202.51,58.08 202.51,59.88 200.6,61.79 198.64,61.79 198.59,61.84 v4(198.28,61.84) 198,61.84 197.95,61.79 185.85,61.79 183.27,64.37 180.72,64.37 179.39,63.04 v2(179.39,62.63)
  IN1 w0.084: v2(128.32,104.84) 128.71,105.23 130.82,105.23 132.35,106.76 135.59,106.76 138.04,109.2 146.11,109.2 149.25,106.06 149.76,106.06 150.63,105.19 150.63,103.64 151.5,102.76 151.5,101.88 151.85,101.54 151.85,95.91 152.83,94.92 152.83,91.52 151.53,90.22 151.53,87.34 150.97,86.78 150.97,85.33 150.06,84.42 150.06,75.47 150.84,74.69 150.84,70.96 151.56,70.24 163.52,70.24 164.14,70.86 171.45,70.86 175.91,66.4 177.35,66.4 179.56,64.19 179.56,62.8 v2(179.39,62.63)
  BOTTOM w0.076: v2(128.32,104.84) 128.38,104.77 UC1.U8
I2C1_SDA_TP_R: length 5.8
  TOP w0.127: v2(213.23,59.82) 213.3,59.75 v1(213.3,57.96) 213.3,57.3 213.19,57.2 RZ346.2 RZ116.2 RZ26.2
  BOTTOM w0.127: v2(213.23,59.82) 213.05,59.63 JKBTP1.3
I_ADP: length 242.9
  TOP w0.127: PR935.2 57.74,50.51 59.82,50.51 61.49,52.18 v1(61.49,52.54) 61.49,53.94 61.77,54.21 62.51,54.21 63.63,55.33 63.63,57.21 v2(63.18,57.66) ; UE1.B11 v2(247.08,92.26)
  IN2 w0.122: v2(247.08,92.26) 246.39,91.57 238.5,91.57 233.84,86.91 233.84,82.3 235.71,80.44 v2(236.83,80.44) ; v2(63.18,57.66) 63.34,57.83 69.36,57.83 69.8,57.39 71.69,57.39 75.74,53.34 102.77,53.34 103.89,54.46 140.16,54.46 141.71,55.64 144.6,55.64 145.89,56.93 159.5,56.93 161.53,54.89 178.48,54.89 179.74,53.64 181.63,53.64 182.68,52.58 183.1,52.58 183.75,51.94 186.92,51.94 187.4,51.46 196.98,51.46 198.04,52.52 201.55,52.52 203.04,51.03 208.12,51.03 209.87,52.79 214.02,52.79 214.31,52.49 218.42,52.49 219.12,53.19 222.41,53.19 222.77,53.55 225.61,53.55 225.69,53.47 225.69,53.47 225.76,53.4 225.77,53.4 226.3,52.87 230.86,52.87 v2(230.96,52.96)
  BOTTOM w0.127: v2(230.96,52.96) 231.34,53.34 231.34,53.66 233.69,56.01 233.69,57.17 236.19,59.67 236.19,62.56 235.96,62.8 235.96,65.43 236.65,66.12 236.65,69.4 235.96,70.09 235.96,79.56 v2(236.83,80.44)
I_BATT: length 232
  TOP w0.127: v2(256.59,76.18) 256.59,76.28 256.63,76.32 256.63,78 256.12,78.51 RE64.2
  IN2 w0.122: v2(64.37,57.15) 64.79,56.73 65.12,56.73 65.75,57.36 69.19,57.36 69.64,56.91 71.53,56.91 75.56,52.88 103.02,52.88 104.12,53.97 140.34,53.97 141.87,55.13 144.83,55.13 146.18,56.48 159.31,56.48 161.35,54.44 176.66,54.44 177.91,53.19 181.44,53.19 181.94,52.68 181.94,52.68 182.55,52.07 182.98,52.07 183.56,51.49 186.74,51.49 187.65,50.58 208.34,50.58 210.1,52.33 213.83,52.33 214.15,52.02 218.66,52.02 219.38,52.74 222.59,52.74 222.95,53.11 225.42,53.11 225.5,53.03 225.51,53.03 226.12,52.42 229.63,52.42 229.83,52.22 234.47,52.22 238.14,55.9 v2(238.14,55.96)
  IN4 w0.084: v2(238.14,55.96) 239.92,57.73 241.41,57.73 244.83,61.15 244.83,62.15 245.67,62.99 245.67,64.73 247.77,66.83 247.77,67.32 250.35,69.91 250.35,71.92 251.34,72.9 252.49,72.9 254.07,74.48 256.03,74.48 256.23,74.69 256.23,75.21 256.09,75.35 256.09,75.69 v2(256.59,76.18)
  BOTTOM w0.127: PR947.2 57.5,52.06 57.05,51.6 57.05,51.17 v1(57.16,51.05) 57.16,50.3 57.41,50.05 61.82,50.05 62.35,50.58 62.35,52.56 64.49,54.7 64.49,57.03 v2(64.37,57.15)
I_BATT_R: length 8
  TOP w0.127: UE1.J4 v2(253.48,85.86) ; RE64.1 256.11,79.92 CE3.1 256.11,81.28 v2(255.98,81.41)
  IN1 w0.084: v2(255.98,81.41) 255.98,82.64 254.68,83.93 254.68,85.28 254.51,85.46 253.88,85.46 v2(253.48,85.86)
I_SYS: length 279.2
  TOP w0.127: v2(256.6,75.54) 256.6,75.61 257.26,76.27 RE312.2 ; v2(47.08,56.77) 47.08,57.92 v1(43.42,61.58) 38.96,66.04 38.96,73.53 43.75,78.32 43.75,79.93 43.2,80.49 43.2,82.27 43.09,82.38 43.09,85.49 44.63,87.04 PR620.1 ; PR936.2 v2(57.49,51.45) 57.62,51.45 58.24,50.82 59.8,50.82 61.14,52.16 61.14,53.99 61.62,54.47 62.36,54.47 63.18,55.29 v2(63.18,57.06)
  IN2 w0.122: v2(63.18,57.06) 63.74,56.5 65.21,56.5 65.85,57.13 69.09,57.13 70.73,55.49 72.63,55.49 76.13,51.99 102.45,51.99 104.21,53.75 140.44,53.75 141.94,54.87 144.96,54.87 146.33,56.25 159.21,56.25 161.25,54.21 174.78,54.21 176.54,52.46 177.94,52.46 178.45,52.96 181.34,52.96 182.46,51.85 182.89,51.85 183.47,51.27 186.64,51.27 187.56,50.35 208.47,50.35 210.22,52.11 213.74,52.11 214.05,51.79 218.79,51.79 219.49,52.49 222.65,52.49 223.05,52.88 225.33,52.88 226.02,52.19 229.54,52.19 229.76,51.97 234.74,51.97 v2(238.73,55.95)
  IN4 w0.084: v2(57.49,51.45) 56.58,52.36 51.66,52.36 48.75,55.27 47.71,55.27 47.08,55.9 v2(47.08,56.77) ; v2(256.6,75.54) 256.6,74.62 256.2,74.22 254.15,74.22 250.59,70.67 250.59,69.87 248.02,67.29 248.02,66.7 245.92,64.6 245.92,62.91 245.06,62.05 245.06,61.05 241.39,57.37 240.15,57.37 v2(238.73,55.95)
I_SYS_R: length 12.3
  TOP w0.127: v2(257.39,80.15) 257.02,79.78 CE4.1 RE313.1 257.26,78.38 RE312.1 ; UE1.J5 v2(253.48,86.66)
  IN1 w0.084: v2(253.48,86.66) 253.89,86.25 255.35,86.25 255.61,85.99 255.61,83.51 257.39,81.74 v2(257.39,80.15)
IA1N: length 7.6
  TOP w0.127: v1(69.25,112.38) 68.01,111.14 PR677.1
  TOP w0.254: v2(67.16,109.23) 67.73,109.8 PR666.1 PR677.1
  BOTTOM w0.254: PL610.2 67.89,107.39 67.16,108.13 v2(67.16,109.23)
IA1P: length 7.1
  TOP w0.127: PR668.1 63.68,107.69 v1(63.03,107.05)
  TOP w0.254: v2(64.35,109.55) 64.29,109.48 PR667.2 64.29,107.96 PR668.1
  BOTTOM w0.254: PL610.3 65.26,107.39 65.53,107.66 65.53,109.25 65.19,109.59 64.44,109.59 64.4,109.55 v2(64.35,109.55)
IA2N: length 8.8
  TOP w0.127: PR673.1 69.89,99.27 v1(70.2,98.96)
  TOP w0.254: v2(67.95,98.81) 68.42,99.27 PR673.1 ; PR670.2 v2(65.51,95.82)
  BOTTOM w0.254: v2(65.51,95.82) 67.95,98.27 v2(67.95,98.81) 68.15,99.01 PL613.2
IA2P: length 8.4
  TOP w0.127: PR675.1 64.1,95.62 v1(64.2,95.51)
  TOP w0.254: v2(66.88,99.85) 66.88,99.71 66.05,98.88 PR674.2 65.17,98.88 64.34,98.04 PR675.1
  BOTTOM w0.254: v2(66.88,99.85) 66.04,99.01 PL613.3
IA_SNUB1: length 2.8
  TOP w0.127: v1(62.48,111.68) 62.28,111.48 59.82,111.48
IA_SNUB2: length 1.3
  TOP w0.127: PC678.1 v1(63.13,93.85)
IA_SW2: length 1
  TOP w0.508: PR676.1 v2(62.27,98.12)
  vias: v1(62.4,95.65)
ILIM_SEL: length 3.1
  TOP w0.127: UI3.4 276.01,77.62 275.92,77.71 275.35,77.71 275.1,77.96 275.1,78.44 275.3,78.64 RI13.1 v1(274.36,78.74)
ILMT_+1VALWP: length 17.5
  TOP w0.127: v1(164.62,80.79) 164.77,80.94 v2(164.77,81.89)
  TOP w0.254: v2(164.77,81.89) 165.04,82.16 PR307.2 165.03,82.58 PR310.1 ; v2(156.04,82.32) 156.14,82.43 PU301.13
  IN2 w0.254: v2(156.04,82.32) 156.04,79.74 156.72,79.06 157.52,79.06 157.83,79.37 163.78,79.37 164.77,80.36 v2(164.77,81.89)
ILMT_DDR: length 4.1
  BOTTOM w0.127: PR207.2 63.46,71.65 63.1,71.3 v1(62.55,71.3)
  BOTTOM w0.254: PU200.17 65.91,71.11 65.68,71.33 65.67,71.33 65.56,71.45 64.62,71.45 PR205.1 PR207.2
IMON_GT: length 2.8
  TOP w0.203: PU602.14 51.45,93.57 v2(51.51,93.62)
  BOTTOM w0.203: PR629.2 50.35,93.42 PC625.2 51.4,93.73 v2(51.51,93.62)
IMON_VSA: length 4.1
  TOP w0.203: PU602.23 49.13,97.26 v2(49.8,97.93)
  BOTTOM w0.127: v2(49.8,97.93) 50.31,97.93 v1(50.65,98.26)
  BOTTOM w0.203: v2(49.8,97.93) 49.8,97.27 PC643.1 PR651.1
IMVP_VR_ON: length 324.7
  TOP w0.127: UE4.2 270.53,97.48 270.34,97.67 268.58,97.67 UE3.4 268.08,97.6 v2(267.52,98.16) 267.52,98.93 267,99.45 RE304.1 ; PR616.1 43.86,90.78 42.84,89.77 42.84,82.3 42.97,82.17 42.97,80.36 43.52,79.81 43.52,78.42 38.57,73.47 38.57,65.74 v1(40.85,63.47) v2(43.25,61.07)
  IN2 w0.122: v2(267.52,98.16) 268.18,97.5 268.18,88.22 266.71,86.74 266.71,84.56 267.76,83.51 267.76,80.15 271.05,76.86 271.05,69.53 269.05,67.53 263.71,67.53 259.79,63.61 257.45,63.61 257.17,63.9 255.29,63.9 255.12,64.07 255.12,64.46 254.6,64.98 253.63,64.98 253.04,64.39 251.15,64.39 250.37,63.61 249.84,63.61 246.47,60.24 246.47,56.63 246.69,56.41 246.69,56.06 245.48,54.85 240.13,54.85 239.54,54.26 239.54,52.82 237.28,50.55 214.27,50.55 213.8,51.01 213.8,51.02 213.39,51.43 210.54,51.43 208.78,49.68 187.29,49.68 186.37,50.6 183.19,50.6 182.61,51.18 179.78,51.18 178.86,50.26 175.04,50.26 171.77,53.53 160.96,53.53 158.92,55.57 148.04,55.57 146.59,54.13 142.19,54.13 140.72,53.02 115.07,53.02 113.36,51.31 74.89,51.31 71.39,54.82 70.34,54.82 69.36,55.8 62.02,55.8 60.43,54.21 59.37,54.21 58.47,55.1 53.2,55.1 51.13,57.17 47.08,57.17 46.41,57.85 46.41,58.54 44.99,59.95 43.65,59.95 43.25,60.35 v2(43.25,61.07)
IMVP_VR_ON_EC: length 24.9
  TOP w0.127: UE1.N7 257.82,88.66 v2(258.01,88.47) ; RPE10.2 259.18,98.52 v2(258.47,97.8) ; v2(265.45,99.54) 265.48,99.54 265.96,100.02 RE304.2 266.09,98.99 266.19,98.9 UE3.1
  IN1 w0.084: v2(258.01,88.47) 258.01,88.51 257.52,89 257.52,93.74 256.38,94.88 256.38,95.72 v2(258.47,97.8)
  IN4 w0.084: v2(258.47,97.8) 258.92,97.8 261.28,100.16 262.46,100.16 263.08,99.54 v2(265.45,99.54)
INT_SPK_L+: length 43.2
  TOP w1.016: 278.82,24.17 277.33,25.66 277.33,46.75 275.23,48.84 275.23,52.08 266.85,60.46 264.95,60.46
  vias: v1(263.32,60.62)
INT_SPK_L-: length 42.7
  TOP w1.016: 278.92,26.11 278.47,26.55 278.47,47.22 276.38,49.32 276.38,52.55 267.32,61.61 264.95,61.61
  vias: v1(264.08,61.91)
INT_SPK_R+: length 47.5
  IN1 w1.016: 278.47,22.68 278.47,50.18 266.46,62.19 263.47,62.19
  vias: v1(261.49,61.71) v2(261.87,62.06) v2(262.48,62.06) v2(279.11,21.47) v2(279.74,21.47)
INT_SPK_R-: length 48.7
  IN1 w1.016: 263.14,61 266.03,61 277.33,49.7 277.33,21.73 278.66,20.39
  vias: v1(279.86,19.7) v2(261.69,61.15) v2(262.28,61.3) v2(278.64,19.44) v2(279.23,19.44)
INT_SPKR_L+: length 6.8
  TOP w0.127: 281.46,22.64 v3(281.99,22.64)
  BOTTOM w0.762: 282.38,22.81 284.31,22.81 286.02,21.1 JSPK1.1
  vias: v2(281.25,23.01) v2(281.25,22.43)
INT_SPKR_L-: length 12.6
  TOP w0.127: 281.41,24.8 v3(282.07,24.8)
  BOTTOM w0.762: JSPK1.2 287.28,17.9 288,18.62 288,21.28 284.57,24.71 282.38,24.71
  vias: v2(281.25,25.07) v2(281.25,24.48)
INT_SPKR_R+: length 7.4
  TOP w0.127: 281.46,20.71 v3(281.96,20.71)
  BOTTOM w0.762: JSPK1.3 284.91,16.65 284.28,17.28 284.28,19.84 283.34,20.79 DA7.2
  vias: v2(281.25,20.97) v2(281.25,20.38)
INT_SPKR_R-: length 6.4
  TOP w0.127: 281.43,18.65 v3(281.86,18.65)
  BOTTOM w0.762: JSPK1.4 284.69,15.4 283.23,16.85 283.23,18.33 282.7,18.86 DA7.3
  vias: v2(281.25,18.93) v2(281.25,18.35)
INTRUDER#: length 15.6
  TOP w0.076: 123.28,92.71 123.19,92.79 123.19,93.4 123.25,93.45 123.25,94.95 v2(122.92,95.28)
  TOP w0.127: 123.28,92.71 124.24,91.74 125.67,91.74 127.99,89.42 v1(127.99,88.06) 127.99,84.48 127.42,83.91 RC69.1
  BOTTOM w0.102: v2(122.92,95.28) 123.35,95.72 UC1.AP16
IR_CAM_DET#: length 187.6
  TOP w0.127: v2(153.77,108.16) 153.56,108.37 153.56,110.27 153.92,110.63 153.92,117.23 156.46,119.77 157.48,119.77 158.74,121.03 v2(160.04,121.03)
  IN1 w0.084: v2(39.33,132.9) 39.33,130.67 40.93,129.07 44.31,129.07 50.97,135.73 71.29,135.73 74.93,132.09 74.93,131.46 76.77,129.63 79.07,129.63 81.35,131.91 81.35,134.28 82.23,135.16 84.47,135.16 84.62,135.01 105.81,135.01 110.17,130.65 114.33,130.65 121.56,123.42 126.33,123.42 126.5,123.25 128.79,123.25 128.99,123.45 134.91,123.45 135.24,123.11 138.83,123.11 139.85,124.13 156.29,124.13 157.53,122.89 158.19,122.89 v2(160.04,121.03)
  BOTTOM w0.076: 136.75,109.04 136.37,109.04 RC345.1 135.16,107.83 134.14,107.83 133.91,108.06 132.21,108.06 132.06,108.16 130.23,108.16 UC1.H5
  BOTTOM w0.127: JIR1.6 v2(39.33,132.9) ; 136.75,109.04 138.3,109.04 138.59,108.75 144,108.75 144.44,108.31 144.44,106.84 144.27,106.68 144.27,105.37 144.76,104.88 150.17,104.88 150.61,105.32 150.94,105.32 v1(152.89,107.28) v2(153.77,108.16)
ISEN1_IA: length 48.7
  TOP w0.203: PC635.2 51.89,88.05 52.31,88.47 52.31,89.72 v1(52.73,90.14) 52.73,90.6 v2(52.63,90.7) 52.49,90.84 51.9,90.84 51.37,90.31 50.45,90.31 49.53,91.23 PU602.9
  TOP w0.254: PR668.2 64.76,106.04 v2(64.76,105.28) ; v2(64.86,95.13) 64.84,95.15 64.84,96.23 PR670.1 ; PR634.1 v2(50.11,87.3)
  IN2 w0.203: v2(64.86,95.13) 64.67,95.32 64.67,100.85 64.98,101.17 64.98,105.06 v2(64.76,105.28)
  IN2 w0.254: v2(50.11,87.3) 50.11,89.03 52.05,90.97 52.36,90.97 v2(52.63,90.7)
  IN3 w0.203: v2(64.86,95.13) 64.78,95.13 60.29,90.64 60.29,87.37 59.6,86.68 58.99,86.68 58,85.69 54.93,85.69 53.54,87.08 53.54,90.03 52.87,90.7 v2(52.63,90.7)
ISEN2_IA: length 52.5
  TOP w0.127: v2(65.95,110.91) 65.54,111.31 v1(65.54,111.39)
  TOP w0.203: PU602.10 49.93,91.33 50.52,90.74 51.34,90.74 51.75,91.15 52.52,91.15 v2(52.72,91.34)
  TOP w0.254: v2(65.95,110.91) 66.18,111.14 PR677.2 ; PR675.2 64.1,99.96 64.41,100.28 v2(64.41,101.42) ; PR615.1 v2(51.02,87.28)
  IN2 w0.254: v2(51.02,87.28) 51.02,88.41 53.15,90.54 53.15,90.91 v2(52.72,91.34) ; v2(64.41,101.42) 64.6,101.61 64.6,104.55 64.3,104.85 64.3,107.51 65.95,109.16 v2(65.95,110.91)
  IN3 w0.203: v2(52.72,91.34) 53.85,90.21 53.85,87.29 55.13,86 57.85,86 58.84,86.99 59.47,86.99 59.98,87.5 59.98,90.76 64.34,95.12 64.34,101.34 v2(64.41,101.42)
  BOTTOM w0.254: PC638.2 52.17,91.93 52.72,91.38 v2(52.72,91.34)
ISH_I2C2_SCL: length 182.3
  TOP w0.127: v2(153.1,96.05) 153.17,96.11 153.17,96.38 152.95,96.6 v4(149.43,96.6) 149.05,96.6 148.63,96.18 148.34,96.18 148.27,96.11 147.9,95.73 147.2,95.73 146.76,96.17 146.76,97.61 145.62,98.75 144.81,98.75 143.55,97.49 142.79,97.49 v2(142.62,97.32) ; RZ76.1 241.34,101.86 241.61,101.86 v2(241.78,102.03)
  IN1 w0.084: v2(142.62,97.32) 142.45,97.49 140.52,97.49 136.8,101.2 135.84,101.2 135.14,101.9 132.18,101.9 131.33,101.05 126.79,101.05 v2(126.13,101.71)
  IN4 w0.084: v2(153.1,96.05) 153.33,95.82 153.33,92.14 154.99,90.48 163.03,90.48 168.01,85.5 168.01,82.55 174.54,76.03 174.54,73.49 179.39,68.63 180.98,68.63 183.81,65.8 188.7,65.8 189.23,65.27 231.75,65.27 237.35,70.86 239.28,70.86 239.81,71.39 239.81,73.23 239.39,73.65 239.39,75.25 237.56,77.09 236.58,77.09 233.78,79.89 233.78,93.18 237.67,97.07 237.67,97.52 238.49,98.34 238.49,99.76 239.52,100.79 242.1,100.79 242.44,101.14 242.44,101.52 242.15,101.82 242,101.82 v2(241.78,102.03)
  BOTTOM w0.102: v2(126.13,101.71) 125.78,101.37 UC1.AD12
  BOTTOM w0.127: v2(142.62,97.32) 142.44,97.49 142.22,97.49 RC362.1
ISH_I2C2_SCL_R: length 2.4
  TOP w0.127: RZ76.2 239.75,101.85 239.3,101.85 v2(239.1,102.06)
  BOTTOM w0.127: v2(239.1,102.06) 239.05,102 JNGFF2.32
ISH_I2C2_SDA: length 181.2
  TOP w0.127: RZ77.1 241.31,101.61 241.62,101.61 v2(241.78,101.45) ; v2(153.69,96.05) 153.69,96.22 153.05,96.85 148.97,96.85 148.53,96.42 148.25,96.42 148.11,96.28 147.8,95.97 147.29,95.97 147,96.27 147,97.71 145.72,98.99 144.72,98.99 143.45,97.73 142.79,97.73 v2(142.62,97.9)
  IN1 w0.084: v2(142.62,97.9) 142.41,97.7 140.61,97.7 136.89,101.42 135.93,101.42 135.23,102.11 132.1,102.11 131.25,101.26 126.88,101.26 126.77,101.38 v2(126.77,101.71)
  IN4 w0.084: v2(241.78,101.45) 241.94,101.61 242.06,101.61 242.23,101.44 242.23,101.22 242.01,101 239.43,101 238.28,99.85 238.28,98.43 237.46,97.6 237.46,97.15 233.57,93.27 233.57,79.8 236.5,76.88 237.47,76.88 239.18,75.17 239.18,73.56 239.6,73.14 239.6,71.48 239.19,71.07 237.26,71.07 231.66,65.48 189.32,65.48 188.79,66.01 183.9,66.01 181.06,68.84 179.48,68.84 174.75,73.57 174.75,76.12 168.22,82.64 168.22,85.59 163.12,90.69 155.08,90.69 153.54,92.23 153.54,95.9 v2(153.69,96.05)
  BOTTOM w0.102: UC1.AD11 126.43,101.39 126.75,101.71 v2(126.77,101.71)
  BOTTOM w0.127: v2(142.62,97.9) 142.44,97.73 142.22,97.73 RC363.1
ISH_I2C2_SDA_R: length 2.4
  TOP w0.127: RZ77.2 239.78,101.62 239.3,101.62 v2(239.1,101.42)
  BOTTOM w0.127: v2(239.1,101.42) 239.02,101.5 JNGFF2.34
ISH_UART0_CTS#: length 150.2
  TOP w0.127: RZ80.1 236.35,65.23 v1(235.74,64.61) 235.3,64.18 235.3,63.72 234.78,63.21 217.83,63.21 216.68,62.06 212.05,62.06 211.63,62.48 209.87,62.48 209.15,63.21 185.14,63.21 183.52,64.82 180.23,64.82 179.13,63.73 v2(177.98,63.73)
  IN1 w0.084: v2(177.98,63.73) 175.17,63.73 172.66,66.24 171.05,66.24 170.36,65.55 167.55,65.55 167.03,66.06 163.77,66.06 161.52,68.31 151.02,68.31 148.38,70.95 148.38,77.99 147.64,78.72 147.64,85.66 147.99,86 147.99,88.14 147.53,88.6 147.53,90.34 148.49,91.31 148.49,92.47 150.18,94.16 150.18,99.42 149.5,100.1 149.5,101.65 148.07,103.08 147.79,103.08 146.23,104.64 141.14,104.64 140,105.78 v2(137.51,105.78)
  BOTTOM w0.076: 136.85,105.11 136.8,105.07 135.89,105.07 134.97,104.15 133.02,104.15 132.89,104.02 132.46,104.02 132.15,104.11 132.14,104.11 131.77,104.11 131.65,104.23 130.73,104.23 UC1.U4
  BOTTOM w0.127: 136.85,105.11 v2(137.51,105.78)
ISH_UART0_CTS#_R: length 2.9
  TOP w0.127: RZ80.2 238.67,64.97 239.19,64.97 v2(239.2,64.96)
  BOTTOM w0.127: v2(239.2,64.96) 239.2,65.19 239.42,65.4 JNGFF1.62
ISH_UART0_RTS#: length 153
  TOP w0.127: v2(177.54,64.4) 177.54,63.49 177.72,63.31 v1(178.76,63.31) 179.05,63.31 180.34,64.6 183.41,64.6 185.02,62.98 209.05,62.98 209.78,62.25 211.27,62.25 211.7,61.83 216.78,61.83 217.93,62.98 235.12,62.98 236.48,64.34 RZ81.1
  IN1 w0.084: v2(177.54,64.4) 177.54,64.92 176.87,65.59 175.6,65.59 171.04,70.15 164.53,70.15 163.85,69.48 151.33,69.48 149.4,71.41 149.4,81.87 149.24,82.03 149.24,90.36 149.91,91.03 150.97,91.03 151.18,91.25 151.18,99.87 150.52,100.53 150.52,102.8 150.01,103.31 150.01,103.7 147.29,106.42 147.29,107.24 146.06,108.47 144.05,108.47 143.03,107.45 140.92,107.45 140.53,107.06 v2(140.53,106.74)
  BOTTOM w0.076: UC1.U3 131.46,104.84 132.71,104.84
  BOTTOM w0.127: 132.71,104.84 133.03,105.17 134.87,105.17 135.88,106.17 138.31,106.17 138.51,106.37 140.17,106.37 v2(140.53,106.74)
ISH_UART0_RTS#_R: length 2.9
  TOP w0.127: RZ81.2 238.53,64.45 v1(239.46,64.45) 239.79,64.78 v2(239.79,64.96)
  BOTTOM w0.127: JNGFF1.64 239.85,64.9 v2(239.79,64.96)
ISH_UART0_RXD: length 150.4
  TOP w0.127: RZ78.1 237.23,67 234.63,64.41 v1(228.93,64.41) 227.62,64.41 226.88,63.66 185.34,63.66 183.68,65.33 179.65,65.33 v2(178.74,64.43)
  IN1 w0.084: v2(136.35,105.78) 136.35,105.8 137.01,106.47 139.42,106.47 140.77,107.82 142.88,107.82 143.9,108.84 146.22,108.84 147.66,107.39 147.66,106.57 150.38,103.85 150.38,103.57 150.96,102.99 150.96,100.71 151.62,100.05 151.62,91.04 151.25,90.66 150.1,90.66 149.64,90.2 149.64,85.5 149.84,85.3 149.84,71.6 151.5,69.94 163.63,69.94 164.28,70.59 171.29,70.59 175.8,66.08 177.21,66.08 178.74,64.56 v2(178.74,64.43)
  BOTTOM w0.076: 133.38,104.84 133.02,104.84 132.68,104.5 UC1.U1
  BOTTOM w0.127: v2(136.35,105.78) 135.79,105.78 134.85,104.84 133.38,104.84
ISH_UART0_RXD_R: length 3.3
  TOP w0.127: RZ78.2 238.56,67 239.21,66.36 v2(239.21,66.01)
  BOTTOM w0.127: JNGFF1.58 240.06,66.4 240,66.46 239.65,66.46 v2(239.21,66.01)
ISH_UART0_TXD: length 151.1
  TOP w0.127: v2(178.15,64.43) 178.59,63.99 179.06,63.99 180.14,65.08 183.61,65.08 185.25,63.43 233.5,63.43 v1(233.84,63.78) 234.13,64.06 234.67,64.06 236.72,66.11 RZ79.1
  IN1 w0.084: v2(178.15,64.43) 178.15,64.66 176.98,65.83 175.7,65.83 171.16,70.37 164.42,70.37 163.75,69.71 151.42,69.71 149.62,71.51 149.62,81.91 149.45,82.08 149.45,90.3 150,90.85 151.04,90.85 151.4,91.21 151.4,99.96 150.74,100.62 150.74,102.9 150.2,103.44 150.2,103.77 147.48,106.49 147.48,107.31 146.14,108.65 143.97,108.65 142.95,107.63 140.84,107.63 139.42,106.21 137.31,106.21 136.93,105.83 v2(136.93,105.78)
  BOTTOM w0.076: UC1.U2 131.99,104.28 132.17,104.28 132.2,104.27 132.4,104.21 132.76,104.21 132.99,104.44
  BOTTOM w0.127: 132.99,104.44 133.09,104.54 134.96,104.54 135.79,105.37 136.52,105.37 v2(136.93,105.78)
ISH_UART0_TXD_R: length 3.1
  TOP w0.127: v2(239.8,66.01) 239.8,65.8 239.59,65.58 238.95,65.58 RZ79.2
  BOTTOM w0.127: v2(239.8,66.01) 239.91,65.9 JNGFF1.60
ISUMN_GT: length 45.2
  TOP w0.254: v2(52.87,98.82) 53.21,98.82 PR644.2 PR640.2 ; PR656.2 63.97,104.46 v2(63.93,104.42)
  IN2 w0.254: v2(63.93,104.42) 63.93,104.02 62.76,102.85 62.76,101.36 63.75,100.37 63.75,95.06 68.18,90.62 v2(68.18,90.12)
  IN3 w0.254: v2(52.87,98.82) 52.87,99.73 53.5,100.35 53.5,102.15 55.92,104.57 58.91,104.57 59.35,105 63.43,105 63.93,104.5 v2(63.93,104.42)
  BOTTOM w0.254: v2(52.87,98.82) 51.82,98.82 51.56,98.55 PC646.2 51.54,98.12 PC645.1 PC642.2 ; PL612.2 v2(68.18,90.12) 67.74,89.68 67.74,88 69.4,86.35 PH605.2
ISUMN_IA: length 57.2
  TOP w0.203: PC635.1 51.82,88.79 PR632.1 PR638.1
  TOP w0.254: v2(65.46,94.59) 66,94.04 v1(66.27,94.04) 68.25,94.04 69.09,94.88 PR673.2 68.67,98.36 68.39,98.08 67.02,98.08 66.43,97.5 ; 66.43,97.5 66.43,98.11 67.75,99.43 67.75,100.52 67.21,101.07 67.21,102.24 v2(66.92,102.53) 66.53,102.53 65.62,103.44 65.62,108.76 65.87,109.01 65.87,109.78 66.27,110.18 PR666.2 ; 66.43,97.5 PR633.2 ; PR638.1 51.82,90.04 v2(52.15,90.37)
  IN3 w0.254: v2(65.46,94.59) 64.72,94.59 61.2,91.07 61.2,86.14 60.42,85.36 54.68,85.36 53.21,86.84 53.21,89.89 52.87,90.23 52.28,90.23 v2(52.15,90.37)
  BOTTOM w0.254: v2(66.92,102.53) 66.35,103.1 PH602.2 ; PC638.1 52.12,90.87 52.12,90.4 v2(52.15,90.37) 51.97,90.19 PC641.1 50.92,90.08 PC624.2 50.04,89.33 PC626.2
ISUMN_VSA: length 50.9
  TOP w0.254: PR643.1 72.36,116.79 v3(72.62,116.52) v2(73.46,115.68) ; PC637.2 48.17,100.68 PC644.1 ; PC637.2 PC633.2 ; PC637.2 48.23,100.84 v2(48.62,101.23)
  IN1 w0.254: v2(48.62,101.23) 48.62,102.15 49.94,103.47 49.94,108.33 51.85,110.23 51.85,112.57 54.05,114.77 57.36,114.77 58.19,115.6 60.05,115.6 60.54,116.09 60.54,116.71 61.64,117.81 62.26,117.81 62.95,118.5 68.38,118.5 69,117.88 70.06,117.88 70.58,117.36 72.62,117.36 73.46,116.51 v2(73.46,115.68)
  BOTTOM w0.254: PL614.2 73.64,115.5 v2(73.46,115.68) 72.68,116.46 72.68,116.85 71.79,117.74 PH604.2 ; v2(48.62,101.23) 48.8,101.05 48.8,100.47 PR636.2 48.97,100.28 PR641.2
ISUMP_GT: length 46.9
  TOP w0.127: v2(67,87.44) v1(68.1,87.44)
  TOP w0.203: PU602.19 51.04,95.57 51.34,95.87 51.34,96.22 51.7,96.58 v2(52.15,96.58)
  TOP w0.254: PR656.1 63.29,104.87 v2(63.29,104.4) ; PR661.2 67,88.42 v2(67,87.44)
  IN2 w0.254: v2(67,87.44) 67,91.18 63.39,94.79 63.39,100.22 62.38,101.23 62.38,103.01 63.29,103.92 v2(63.29,104.4)
  IN3 w0.254: v2(52.15,96.58) 52.79,96.58 53.34,97.13 53.34,99.69 53.88,100.23 53.88,102.03 56.07,104.21 59.06,104.21 59.5,104.65 63.04,104.65 v2(63.29,104.4)
  BOTTOM w0.254: v2(52.15,96.58) 52.32,96.58 52.69,96.21 PR653.2 53.27,96.68 PC642.1 52.47,98.04 PC646.1 ; v2(67,87.44) 67,86.03 PR657.1
ISUMP_IA: length 53.1
  TOP w0.203: PU602.7 48.73,91.13 49.32,90.55 49.32,90.36 v2(49.4,90.28)
  TOP w0.254: v2(66.24,94.59) 67.78,94.59 68.26,95.07 v1(68.26,96.2) 68.26,97.08 67.84,97.5 PR628.1 67.33,97.48 PR633.1 65.88,97.13 65.66,97.13 PR674.1 67.4,99.58 67.4,100.38 66.84,100.93 66.84,101.68 65.26,103.26 65.26,108.91 65.52,109.16 65.52,109.89 65.16,110.25 PR667.1
  IN3 w0.254: v2(66.24,94.59) 65.72,94.07 64.72,94.07 61.56,90.9 61.56,85.99 60.57,85.01 54.54,85.01 52.72,86.82 v2(52.72,88.27)
  BOTTOM w0.254: v2(49.4,90.28) 49.4,88.77 49.74,88.42 PC626.1 50.04,88.42 PC624.1 51.78,88.42 PR658.2 52.56,88.43 v2(52.72,88.27)
ISUMP_VSA: length 45.2
  TOP w0.127: v2(69.43,117.25) 68.9,117.25 v1(67.9,118.25)
  TOP w0.203: PC633.1 48.64,99.25 48.64,99.24 48.61,99.22 48.17,99.22 47.63,98.67 47.63,97.45 47.53,97.36 PU602.27
  TOP w0.254: v2(49.25,101.24) 49.14,101.13 PC637.1 PC633.1 ; PR624.2 70.24,115.95 PR643.2 70.24,116.99 69.99,117.25 v2(69.43,117.25)
  IN1 w0.254: v2(69.43,117.25) 69.42,117.26 69.08,117.26 68.22,118.12 63.14,118.12 62.39,117.37 61.7,117.37 60.89,116.56 60.89,115.87 60.24,115.22 58.35,115.22 57.51,114.38 54.29,114.38 52.25,112.34 52.25,110.1 50.32,108.17 50.32,103.32 49,102 49,101.49 v2(49.25,101.24)
  BOTTOM w0.254: PR642.1 70.84,117.85 70.48,117.5 69.68,117.5 v2(69.43,117.25)
ITP_PMODE: length 56.7
  TOP w0.127: v2(90.01,131.82) 89.04,132.79 RC115.1
  BOTTOM w0.076: 126.77,112.79 126.9,112.66 127.28,112.66 127.4,112.53 127.4,111.11 UC1.E8
  BOTTOM w0.127: 126.77,112.79 126.77,114.38 127.02,114.64 127.02,115.46 126.48,116.01 126.48,116.8 125.78,117.49 125.78,119.25 125.3,119.72 124.55,119.72 121.28,122.99 121.28,125.01 v1(118.29,128.01) 114.08,132.22 106.31,132.22 104.71,133.82 90.14,133.82 90.01,133.7 JXDP1.46 v2(90.01,131.82)
JDIMM1_EVENT#: length 2.7
  TOP w0.127: RD14.1 109.76,52.75 v2(109.47,52.46) v1(109.47,51.9)
  BOTTOM w0.127: v2(109.47,52.46) 109.47,53.7 JDIMM1.134
JTAG_CLK: length 83.4
  TOP w0.127: UE1.C8 v2(247.88,89.86)
  IN1 w0.084: v2(247.88,89.86) 247.48,90.26 247.48,94.16 247.62,94.3 247.62,95.03 247.08,95.57 247.08,98.58 247.44,98.93 247.44,104.19 248.82,105.57 248.82,113.92 250.95,116.05 250.95,122.21 258.16,129.42 287.27,129.42 v2(287.69,129) 289.09,127.61 289.43,127.61 291.68,125.36 v2(291.68,124.98)
  BOTTOM w0.127: RPE7.3 289.5,124.86 289.53,124.88 289.93,124.88 289.98,124.84 JDEG1.4 291.54,124.84 v2(291.68,124.98)
JTAG_RST#: length 10.8
  TOP w0.127: UE1.G13 251.48,94.73 250.95,95.26 250.95,96.07 v1(250.3,96.72) 250.12,96.9 249.55,96.9 249.43,97.02 249.43,99.16 RE63.1 249,99.75 JTAG1.1 248.97,100.8 CE30.1 RE65.1
JTAG_TDI: length 79.6
  TOP w0.127: UE1.E9 v2(249.48,90.66) ; v2(289.74,125.84) 287.85,125.84 v3(287.7,125.98)
  IN1 w0.084: v2(289.74,125.84) 286.92,128.66 258.58,128.66 251.71,121.79 251.71,115.89 250.13,114.31 250.13,105.83 248.16,103.86 248.16,97.03 248.85,96.34 248.85,95.6 249.09,95.36 249.09,91.05 v2(249.48,90.66)
  BOTTOM w0.127: RPE7.1 289.72,125.86 v2(289.74,125.84) JDEG1.2
JTAG_TDO: length 83
  TOP w0.127: UE1.F6 v2(250.28,87.46) ; v3(288.76,122.56) 289.38,123.19 289.38,124.05 v2(289.75,124.42)
  IN1 w0.084: v2(289.75,124.42) 286.02,128.15 258.84,128.15 252.83,122.14 252.83,114.16 251.84,113.17 251.84,112 252.17,111.67 252.17,110.45 251.69,109.97 251.69,109.08 252.73,108.03 252.73,96.86 252.22,96.35 252.22,92.77 251.97,92.52 251.97,88.35 251.47,87.86 250.68,87.86 v2(250.28,87.46)
  BOTTOM w0.127: JDEG1.5 290.43,124.34 290.35,124.42 v2(289.75,124.42) 289.68,124.36 RPE7.4
JTAG_TMS: length 85.2
  TOP w0.127: UE1.C5 v2(247.88,86.66) ; v2(290.08,125.34) 289.59,125.34 v3(288.72,124.47)
  IN1 w0.084: v2(247.88,86.66) UE1.C5 248.28,93.74 248.57,94.03 248.57,95.29 247.58,96.28 247.58,98.37 247.94,98.73 247.94,103.98 249.85,105.9 249.85,114.29 251.46,115.9 251.46,121.95 258.42,128.92 286.98,128.92 289.65,126.24 289.95,126.24 290.24,125.94 290.24,125.51 v2(290.08,125.34)
  BOTTOM w0.127: JDEG1.3 v2(290.08,125.34) 289.1,125.34 RPE7.2
KB_DET#: length 168
  TOP w0.127: v2(149.47,119.72) 149.46,119.71 149.46,112.02 148.94,111.49 148.94,109.6 149.87,108.67 149.87,106.05 150.61,105.31 v1(150.61,104.56) v2(151.39,103.77) ; v2(135.16,120.42) 133.69,118.95 131.25,118.95 130.02,117.73 128.92,117.73 127.86,116.67 127.86,111.45 v2(128.31,111.01)
  IN2 w0.122: v2(206.54,55.12) 206.04,55.12 205.57,55.58 204.7,55.58 201.6,58.68 199.54,58.68 199.46,58.76 196.32,58.76 195.09,59.98 183.93,59.98 183.68,60.23 179.98,60.23 179.38,59.63 178.45,59.63 177.76,58.93 175.17,58.93 174.09,60.02 172.75,60.02 172.59,60.17 171.38,60.17 170.37,61.19 170.01,61.19 169.5,61.7 166.23,61.7 165.93,61.4 165.27,60.75 160.82,60.75 160.5,61.07 160.5,62.61 159.02,64.09 150.41,64.09 148.41,66.09 148.41,67.2 142.88,72.73 142.88,73.22 139.42,76.69 139.42,78.21 139.53,78.32 139.53,79.88 140.94,81.29 v2(140.94,81.32)
  IN4 w0.084: v2(135.16,120.42) 136,121.26 148.26,121.26 149.47,120.06 v2(149.47,119.72) ; v2(149.12,95.14) 149.5,94.76 149.5,93.08 148.93,92.51 148.93,91.84 145.16,88.07 145.16,84.28 144.46,83.59 141.89,83.59 141.46,83.15 141.46,81.83 v2(140.94,81.32)
  BOTTOM w0.076: v2(128.31,111.01) 128.31,111.67 UC1.D8
  BOTTOM w0.127: v2(149.12,95.14) 149.22,95.24 149.22,96.46 149.42,96.66 149.42,101.8 149.95,102.33 149.95,102.79 150.93,103.77 v2(151.39,103.77) ; RC288.1 135.85,121.12 v2(135.16,120.42) ; v2(206.54,55.12) 206.04,55.12 205.98,55.18 205.45,55.71 205.45,56.73 204.69,57.49 204.69,58.44 204.55,58.57 JKBTP1.20
LAN_ACTLED_YEL#: length 35.5
  TOP w0.127: v2(257.79,133.81) v1(259.41,133.81) 261.64,133.81 262.81,132.64 262.81,130.92 263.8,129.93 280.12,129.93 282.41,127.65 RL14.1
  BOTTOM w0.127: QL1.6 v2(257.79,133.81)
LAN_ACTLED_YEL_R#: length 107
  TOP w0.127: RL14.2 v2(282.41,119.56) v3(282.41,118.84)
  IN4 w0.084: v2(282.41,119.56) 282.41,127.71 281.54,128.57 259.12,128.57 251.87,121.32 251.87,118.24 258.75,111.36 264.04,111.36 272.16,103.24 272.16,100.07 273.78,98.45 275.51,98.45 276.72,97.25 276.72,85.68 277.49,84.9 280.63,84.9 281.47,85.74 281.47,90.55 JLOM1.10
LAN_DISABLE#_R: length 5.7
  TOP w0.127: UL1.3 244.88,122.29 244.31,121.72 244.31,121.37 RL9.1 242.92,119.99 RL5.1 RL7.2 v1(242.92,118.08)
LAN_MDIN0: length 3.7
  TOP w0.089: UL1.14 249.89,124.13 249.98,124.04 250.2,124.04 v4(251.1,123.14) 251.45,122.79 251.77,122.79 RL72.1
LAN_MDIN0_L: length 23.9
  TOP w0.089: RL72.2 254.05,122.73 254.49,122.73 254.58,122.82 254.58,124.32 256.36,126.1 v4(268.06,126.1) 269.93,126.1 270.78,126.96 271.16,126.96 v2(271.38,127.17)
  BOTTOM w0.089: v2(271.38,127.17) 271.56,127 271.95,127 272.09,127.13 272.09,127.56 271.95,127.7 271.51,127.7 271.42,127.79 TL1.11
LAN_MDIN1: length 3.4
  TOP w0.089: UL1.18 249.89,125.73 249.98,125.64 250.8,125.64 251.32,125.12 251.69,125.12 RL74.1
LAN_MDIN1_L: length 14.3
  TOP w0.089: v2(263.81,127.3) 263.62,127.11 256.11,127.11 254.19,125.19 254.02,125.19 254.01,125.2 253.99,125.2 RL74.2
  BOTTOM w0.089: TL1.5 263.8,127.79 263.89,127.7 264.35,127.7 264.46,127.59 264.46,127.28 264.27,127.09 264.03,127.09 v2(263.81,127.3)
LAN_MDIN2: length 3.2
  TOP w0.089: UL1.21 249.89,126.93 249.98,126.84 250.2,126.84 250.46,127.1 250.9,127.54 251.44,127.54 RL76.1
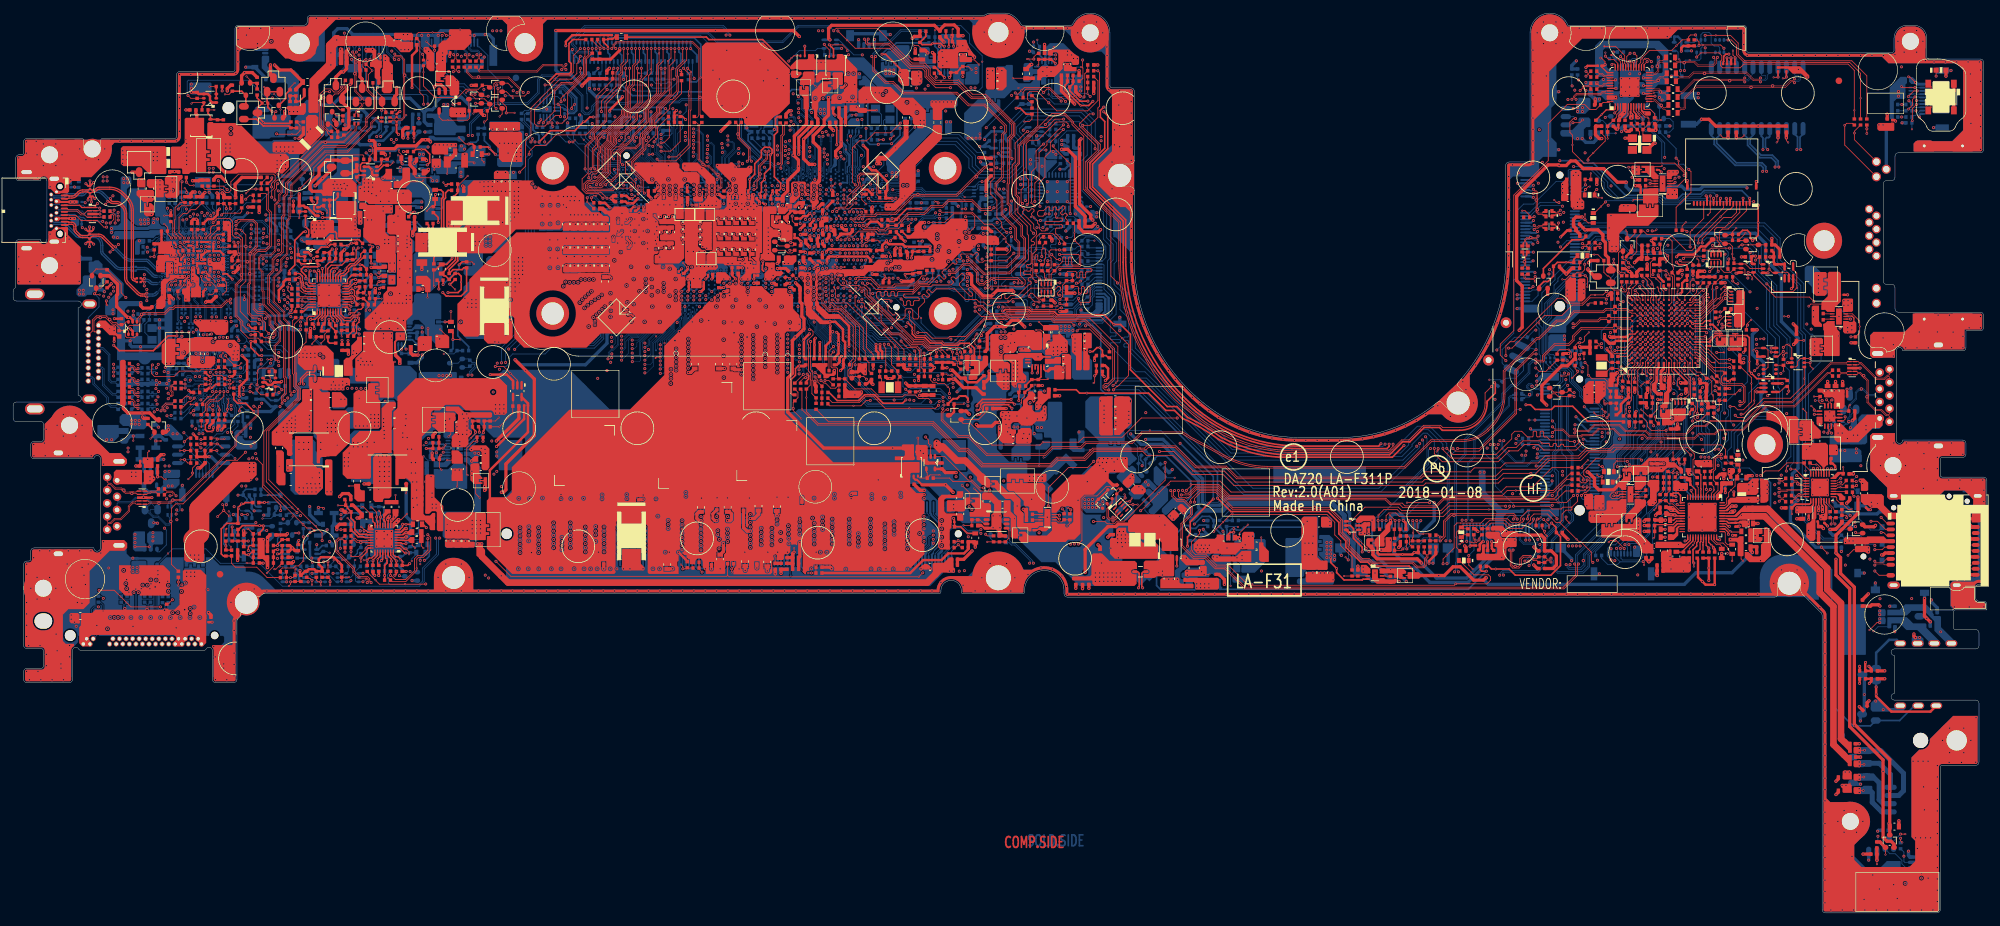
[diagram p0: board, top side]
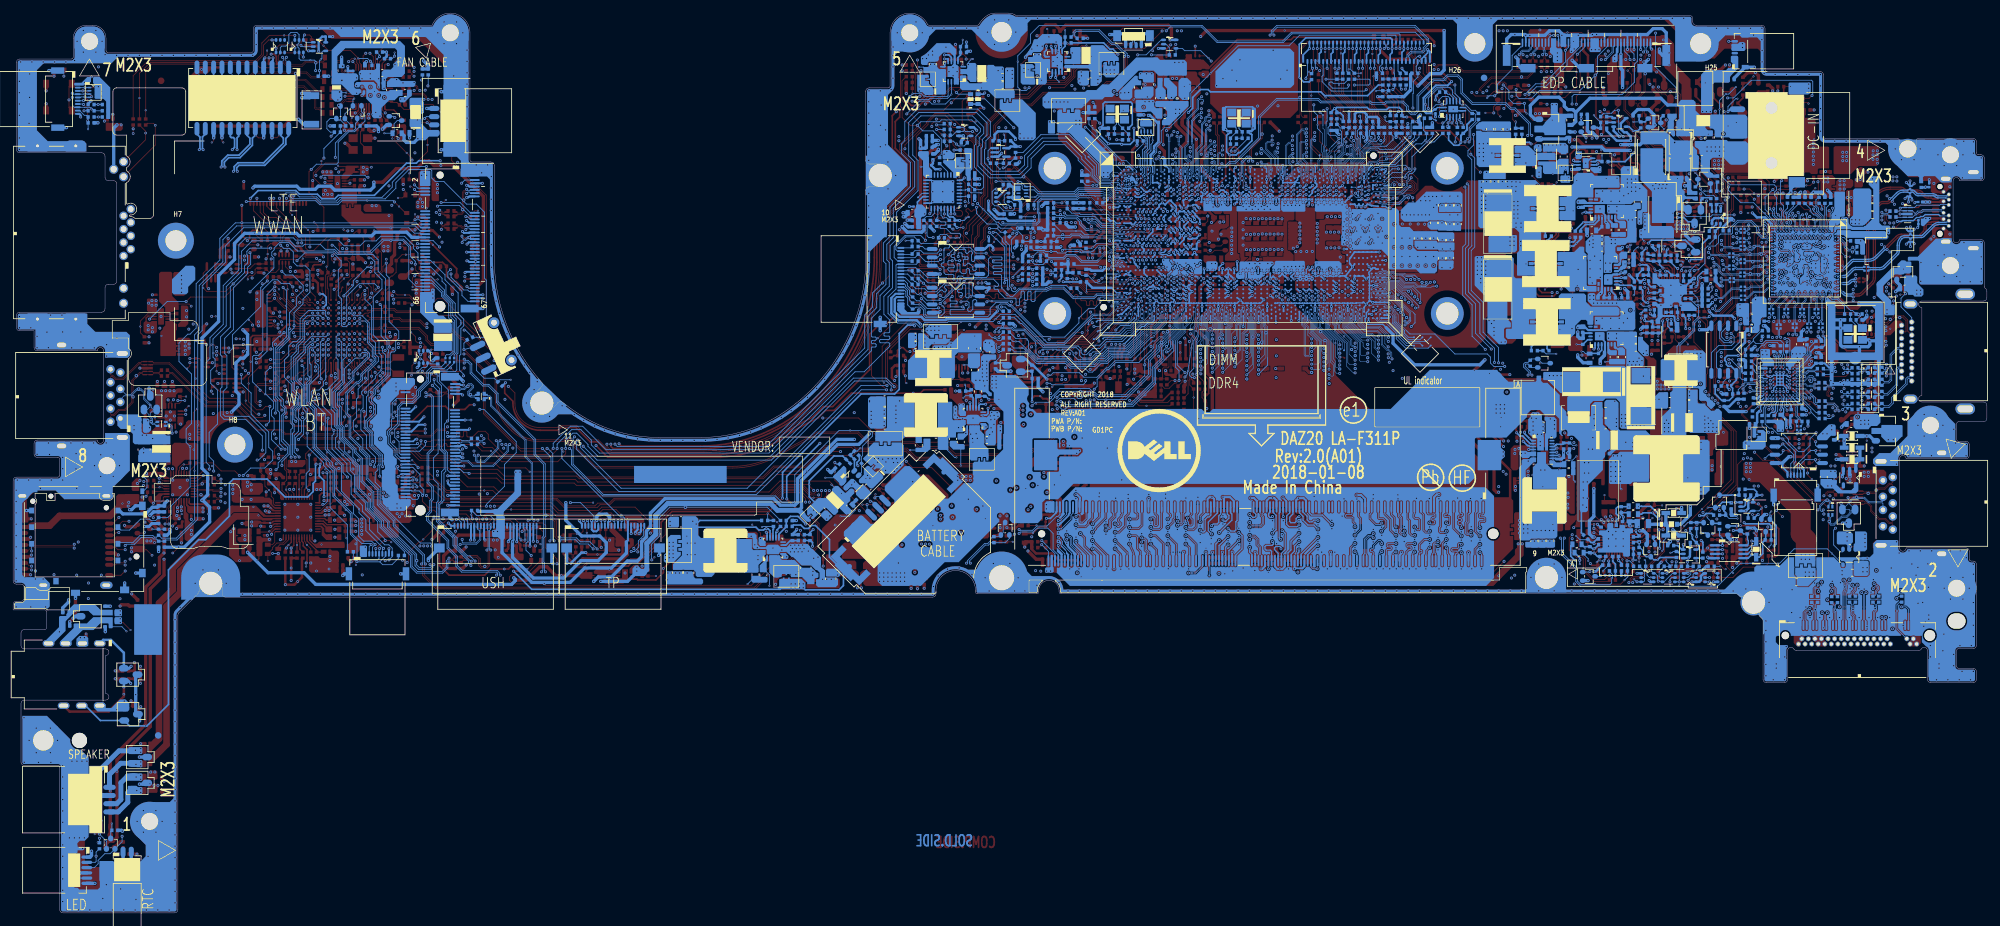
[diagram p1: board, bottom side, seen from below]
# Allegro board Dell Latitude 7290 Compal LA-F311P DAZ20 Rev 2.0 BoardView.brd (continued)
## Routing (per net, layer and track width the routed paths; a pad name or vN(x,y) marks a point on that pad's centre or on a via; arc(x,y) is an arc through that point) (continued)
LAN_MDIN2_L: length 17.1
  TOP w0.089: RL76.2 253.82,127.54 255.27,127.54 255.96,128.23 264.09,128.23 265.19,127.13 266.03,127.13 v2(266.21,127.31)
  BOTTOM w0.089: TL1.7 266.34,127.79 266.43,127.7 266.94,127.7 267.03,127.61 267.03,127.28 266.88,127.12 266.39,127.12 v2(266.21,127.31)
LAN_MDIN3: length 4.3
  TOP w0.089: UL1.24 249.89,128.13 249.98,128.04 250.16,128.04 250.49,128.38 v4(250.49,129.11) 250.49,129.61 250.83,129.95 251.31,129.95 RL78.1
LAN_MDIN3_L: length 9.6
  TOP w0.089: RL78.2 253.2,130.04 253.38,129.86 256.2,129.86 256.75,129.3 258.93,129.3 259.27,129.64 259.27,130.26 v2(259.07,130.46)
  BOTTOM w0.089: TL1.1 258.72,129.55 259.27,130.1 259.27,130.25 v2(259.07,130.46)
LAN_MDIP0: length 3.7
  TOP w0.089: UL1.13 249.89,123.73 249.98,123.82 250.11,123.82 251.36,122.57 251.61,122.57 RL71.1
LAN_MDIP0_L: length 23.9
  TOP w0.089: v2(271.38,126.59) 271.24,126.73 270.87,126.73 270.02,125.88 v4(264.77,125.88) 256.46,125.88 254.81,124.23 254.81,122.73 254.59,122.51 254.09,122.51 RL71.2
  BOTTOM w0.089: v2(271.38,126.59) 271.57,126.77 272.05,126.77 272.31,127.04 272.31,127.74 272.69,128.12 272.69,128.94
LAN_MDIP1: length 3.4
  TOP w0.089: UL1.17 249.89,125.33 249.98,125.42 250.71,125.42 v4(250.96,125.17) 251.23,124.9 251.69,124.9 RL73.1
LAN_MDIP1_L: length 14.3
  TOP w0.089: RL73.2 254.14,124.97 254.28,124.97 256.21,126.89 v4(261.52,126.89) 263.64,126.89 v2(263.81,126.72)
  BOTTOM w0.089: TL1.6 265.07,127.95 264.68,127.56 264.68,127.18 264.36,126.86 263.96,126.86 v2(263.81,126.72)
LAN_MDIP2: length 3.2
  TOP w0.089: UL1.20 249.89,126.53 249.98,126.62 250.29,126.62 v4(250.62,126.94) 250.99,127.32 251.43,127.32 RL75.1
LAN_MDIP2_L: length 17
  TOP w0.089: v2(266.21,126.72) 266.03,126.9 265.09,126.9 264,128 v4(257.68,128) 256.05,128 255.36,127.31 253.82,127.31 RL75.2
  BOTTOM w0.089: v2(266.21,126.72) 266.38,126.9 266.97,126.9 267.26,127.18 267.26,127.75 267.61,128.1 TL1.8
LAN_MDIP3: length 4.3
  TOP w0.089: UL1.23 249.89,127.73 249.98,127.82 250.25,127.82 250.72,128.28 250.72,129.51 250.93,129.72 251.31,129.72 RL77.1
LAN_MDIP3_L: length 9.6
  TOP w0.089: RL77.2 253.6,129.63 v4(254.58,129.63) 256.1,129.63 256.66,129.08 259.02,129.08 259.49,129.55 259.49,130.3 v2(259.65,130.46)
  BOTTOM w0.089: v2(259.65,130.46) 259.5,130.3 259.5,130.05 259.99,129.55 TL1.2
LAN_TEST_EN: length 3.8
  TOP w0.127: v2(246.27,129.86) 246.48,129.66 UL1.30
  BOTTOM w0.127: v1(248.14,130.29) 246.7,130.29 v2(246.27,129.86) 246.04,129.63 RL12.1
LAN_WAKE#: length 257.3
  TOP w0.127: UL1.2 244.48,122.45 v2(244.01,121.98) ; UE1.L3 v2(255.08,85.06) ; v2(139.48,105.28) v1(140.17,105.28) 141.89,105.28 142.37,105.75 142.44,105.75 143.29,106.6 146.06,106.6 146.5,106.16 146.5,104.57 v2(145.64,103.72) ; v2(164.84,116.52) 164.84,117.1 161.55,120.38 161.55,120.62 160.28,121.88 158.25,121.88 153.32,116.96 153.32,114.24 152.87,113.79 152.87,109.53 153.33,109.06 153.33,107.95 153.7,107.58 v2(153.94,107.58)
  IN1 w0.084: v2(244.01,121.98) 243.8,121.77 243.8,111.44 243.86,111.38 243.86,107.74 242.8,106.69 242.8,103.73 242.63,103.55 242.63,99.41 241.9,98.67 241.9,92.56 243.39,91.07 243.39,88.53 v2(243.35,88.49)
  IN2 w0.122: v2(164.84,116.52) 164.64,116.32 164.64,111.21 169.42,106.43 169.42,93.38 170.12,92.67 170.12,90.55 171.39,89.27 171.39,88.19 172.13,87.46 172.13,85.72 174.15,83.69 174.15,81.87 183.24,72.79 187.09,72.79 188.73,71.14 207.24,71.14 208.31,70.08 214.29,70.08 217.62,73.41 223.05,73.41 225.07,75.44 225.07,78.52 225.31,78.76 231.24,78.76 231.65,78.34 236.11,78.34 237.74,79.97 237.74,80.98 236.92,81.8 236.04,81.8 235.24,82.6 235.24,84.45 237.5,86.7 237.5,87.81 238.55,88.86 242.98,88.86 v2(243.35,88.49) 243.39,88.53 243.56,88.53 244.26,89.23 250.36,89.23 250.69,89.56 250.69,90.05 250.91,90.26 251.3,90.26 253.08,88.48 253.08,85.66 253.29,85.46 254.63,85.46 255.03,85.06 v2(255.08,85.06) ; v2(124.74,96.66) 125.2,97.12 125.2,97.57 125.32,97.69 130.07,97.69 131.8,95.96 135.73,95.96 136.29,96.53 136.29,97.86 137.46,99.03 137.46,102.81 138.33,103.68 138.58,103.68 139.48,104.58 v2(139.48,105.28)
  BOTTOM w0.102: v2(124.74,96.66) 124.66,96.66 UC1.AM15
  BOTTOM w0.127: v2(145.64,103.72) RL70.1 RC323.1 146.89,103.24 147.64,103.99 148.21,103.99 148.62,104.4 150.26,104.4 150.89,105.04 152.31,105.04 153.94,106.67 v2(153.94,107.58)
LCD_CBL_DET#: length 108.9
  TOP w0.127: RC287.1 134.13,102.96 v2(133.65,102.49)
  IN2 w0.122: v2(133.65,102.49) 134.05,102.88 136.57,102.88 137.93,104.24 137.93,106.39 135.63,108.68 135.63,110.27 135.19,110.72 135.19,111.08 135.46,111.35 135.46,116.4 136.89,117.83 136.89,124.11 133.95,127.05 130.96,127.05 129.24,128.77 125.46,128.77 124.82,128.14 121.77,128.14 121.54,128.37 116.57,128.37 114.58,126.38 99.08,126.38 98.75,126.71 95.67,126.71 95.3,126.35 93.44,126.35 93.27,126.17 90.46,126.17 89.49,125.2 82.65,125.2 81.55,124.1 75.47,124.1 v2(74.98,124.6)
  BOTTOM w0.076: v2(133.65,102.49) 133.28,102.11 131.58,102.11 131.43,101.95 131.43,101.66 130.95,101.18 UC1.AC3
  BOTTOM w0.127: JEDP1.40 70.75,132.14 70.84,132.05 71.02,132.05 72.33,130.74 72.33,128.61 74.57,126.36 74.57,125 v2(74.98,124.6) 75.79,124.6 v1(76.13,124.26)
LCD_TST: length 263.9
  TOP w0.127: UE1.M2 255.86,84.28 255.86,83.12 256.53,82.45 257.07,82.45 RE20.1 258.33,81.51 258.79,81.05 258.79,79.1 v1(258.98,78.91) 259.01,78.87 v2(259.01,77.89)
  IN2 w0.122: v2(259.01,77.89) 258.52,78.38 257.59,78.38 257.06,77.86 251.92,77.86 251.23,77.16 250.07,77.16 249.13,78.11 244.88,78.11 244.54,78.45 241.56,78.45 240.98,77.86 238.63,77.86 238.1,77.33 235.8,77.33 234.37,75.9 230.47,75.9 227.58,73.01 227.58,71.58 226.38,70.39 225.8,70.39 225.5,70.08 221.79,70.08 221.09,69.38 207.9,69.38 206.8,70.47 188.46,70.47 186.81,72.11 182.84,72.11 173.47,81.48 173.47,83.42 171.46,85.44 171.46,87.18 170.69,87.95 170.69,89.03 169.45,90.27 169.45,92.4 167.84,94 167.84,107.02 163.95,110.91 163.95,116.92 164.41,117.38 164.41,120.64 162.87,122.18 162.87,123.64 161.72,124.79 161.72,127.18 159.85,129.05 159.85,130.31 159.85,130.31 159.85,131.02 158.86,132.01 156.82,132.01 156.5,132.33 154.19,132.33 153.04,131.18 148.35,131.18 144.31,135.23 107.77,135.23 106.29,133.74 84.05,133.74 82.67,132.36 82.67,132 79.55,128.88 76.45,128.88 75.6,129.73 73.64,129.73 71.14,132.23 66.94,132.23 v2(65.37,133.81)
  BOTTOM w0.127: v2(65.37,133.81) 65.25,133.69 JEDP1.29
LCD_VCC_TEST_EN: length 245.3
  TOP w0.127: DV3.2 v2(70.46,123.44) ; v2(249.5,82.18) 249.3,82.18 249.02,82.46 249.02,82.99 UE1.E1
  IN1 w0.084: v2(248.44,74.23) 248.44,75.11 250.01,76.68 250.01,81.88 249.71,82.18 v2(249.5,82.18)
  IN2 w0.122: v2(73.68,126.25) 80.47,126.25 81.94,127.72 84.14,127.72 86.09,129.67 87.26,129.67 87.42,129.83 115.17,129.83 116.34,131 124.82,131 126.19,132.38 127.78,132.38 128.35,131.8 132.2,131.8 132.2,131.8 135.43,131.8 136.04,132.41 139.57,132.41 141.02,130.96 142.67,130.96 146.37,127.26 147.28,127.26 148.16,126.38 154.62,126.38 156.98,124.02 157.94,124.02 159.36,122.6 161.58,120.37 161.58,117.49 161.92,117.15 161.92,108.99 163.78,107.13 163.78,105.17 165.67,103.28 165.67,93.2 166.82,92.05 166.82,89.98 167.51,89.29 167.51,88.11 169.41,86.2 169.41,84.57 171.39,82.59 171.39,80.32 176.03,75.69 176.03,75.25 177.55,73.73 178.46,73.73 181.87,70.33 186.07,70.33 187.71,68.69 205.8,68.69 207.21,67.28 222.33,67.28 222.99,67.93 226.11,67.93 226.76,68.58 227.85,68.58 230.85,71.58 233.21,71.58 233.47,71.32 235.19,71.32 236.64,72.77 238.23,72.77 239.19,73.73 240.53,73.73 241.57,74.77 246.26,74.77 246.8,74.23 v2(248.44,74.23)
  BOTTOM w0.127: v2(73.68,126.25) 72.82,125.38 72.82,124.11 72.15,123.44 v2(70.46,123.44) 70.46,122.24 v1(70.12,121.89)
LED_10_GRN#: length 30.8
  TOP w0.127: v2(261.26,133.1) 261.77,133.1 262.56,132.32 262.56,130.82 263.7,129.68 279.8,129.68 281.46,128.03 v1(281.46,124.24) RL19.1
  BOTTOM w0.127: QL2.6 v2(261.26,133.1)
LED_10_GRN_R#: length 7.4
  TOP w0.127: JLOM1.11 280.52,117.9 v3(280.52,118.91) 280.52,119.2 RL19.2
LED_100_ORG#: length 35.1
  TOP w0.127: RL20.1 v1(280.5,122.39) 280.5,128.47 279.55,129.42 263.68,129.42 263.12,128.87 260.45,128.87 260.12,129.2 260.12,129.86 260.31,130.06 260.31,130.72 259.89,131.14 257.13,131.14 v2(256.49,130.5)
  BOTTOM w0.127: QL1.3 v2(256.49,130.5)
LED_100_ORG_R#: length 11.5
  TOP w0.127: JLOM1.13 279.04,117.08 v3(279.04,120.1) 279.33,120.39 280.25,120.39 RL20.2
LED_MASK#: length 105.4
  TOP w0.127: v2(269.7,85.63) 268.89,84.83 UZ10.1 ; UE1.A12 246.53,92.66 245.87,93.32 245.87,94.3 v2(246.07,94.5) 246.15,94.58 246.15,95.4 246.59,95.85 RE21.1
  IN1 w0.084: v2(246.64,112.17) 246.64,110.65 246.94,110.36 246.94,106.36 245.49,104.92 245.49,96.4 246.07,95.82 v2(246.07,94.5)
  IN2 w0.122: v2(253.8,112.18) 254.08,112.46 254.08,114.94 251.83,117.18 251.83,121.97 252.53,122.66 252.53,124.24 254.62,126.34 v2(254.62,128.43)
  IN4 w0.084: v2(253.8,112.18) 253.8,112.56 254.25,113.02 255.01,113.02 256.92,111.11 256.92,106.39 258.82,104.48 265.71,104.48 266.93,103.26 266.93,103.25 268.81,101.37 268.81,98.92 271.91,95.82 271.91,86.59 270.95,85.63 v2(269.7,85.63)
  BOTTOM w0.127: QL2.2 259.99,131.95 259.78,132.17 259.15,132.17 258.7,132.62 258.7,133.93 258.39,134.24 257.45,134.24 257.14,133.92 QL1.5 257.14,132.66 257.33,132.47 257.33,132.03 257.14,131.84 QL1.2 257.14,130.27 256.9,130.03 v1(255.42,130.03) 254.78,130.03 254.62,129.87 v2(254.62,128.43) ; v2(253.8,112.18) 253.51,112.48 247.1,112.48 246.79,112.17 v2(246.64,112.17)
LG1_ISL9538: length 24.3
  TOP w0.127: v2(58.75,59.95) 59.11,59.95 v1(60.01,60.86)
  IN4 w1.016: 42.16,70.2 42.54,69.81 48.8,69.81 49.28,69.32 49.28,67.82 52.7,64.4 57.04,64.4 59.23,62.21 59.23,60.78
  vias: v2(41.86,68.19) v2(41.87,67.57) v2(58.37,59.52)
LG2_ISL9538: length 12.3
  TOP w0.508: PQ904.6 v2(53.47,65.42)
  IN1 w0.508: v2(59.87,58.61) 60,58.74 60,60.02 59.63,60.39 59.63,61.58 56.15,65.06 53.82,65.06 v2(53.47,65.42)
  BOTTOM w0.127: v2(59.87,58.61) v1(59.87,59.19)
LID_CL#: length 118.3
  TOP w0.127: v3(262.76,95.95) 262.39,95.95 v2(261.97,96.37) RE26.1 ; UZ10.2 267.87,85.48 v2(267.84,85.51)
  IN2 w0.122: v2(267.84,85.51) 268.78,84.57 268.78,82.19 269.2,81.78 270.53,81.78 272.83,79.48 272.83,75.69 275.79,72.74 279.29,72.74 280.03,72 281.32,72 283,70.32 283,64.67 284.93,62.74 284.93,61.47 285.72,60.68 285.72,58.34 284.4,57.02 282.46,57.02 280.04,54.59 280.04,52.14 279.08,51.18 279.08,32.21 287.88,23.4 287.88,13.55 286.73,12.39 286.73,11.23 287.93,10.02 288.9,10.02 289.33,9.59 289.33,6.7 v2(290.73,5.31)
  BOTTOM w0.127: v2(267.84,85.51) 267.29,86.06 267.29,88.15 262.98,92.47 262.98,95.36 v2(261.97,96.37) ; JLED1.5 v2(290.73,5.31)
LID_CL#_PCH: length 10.4
  BOTTOM w0.076: UC1.AW7 128.66,92.45 128.98,92.14 128.98,90.82 130.47,89.32 131.39,89.32 131.54,89.17
  BOTTOM w0.127: 131.54,89.17 132.23,88.48 134.9,88.48 135.89,87.49 T268.1
LID_CL_SIO#: length 8.2
  TOP w0.127: UE1.N11 257.2,91.86 258.9,93.56 v1(258.9,95.1) 258.9,95.71 CE8.1 259.31,96.09 RE25.2 RE26.2
LM393_P: length 16
  IN1 w0.254: v2(38.63,58.3) 39.01,58.68 44.54,58.68 v2(45.24,57.99)
  BOTTOM w0.203: PU1201.8 36.58,56.04 36.35,56.27 36.35,56.78 36.47,56.91 PC1201.2 37.03,57.78 PD1801.1
  BOTTOM w0.254: PR950.2 45.24,58.48 v2(45.24,57.99) 44.87,57.62 v1(44.87,57.5) 44.87,57.06 PC949.2 43.86,56.06 43.86,55.59 44.05,55.4 PU903.5 ; PD1801.1 v2(38.63,58.3)
LOM_ACTLED_YEL#: length 14.3
  TOP w0.127: UL1.26 248.08,129.36 248.35,129.63 248.35,130.03 248.56,130.25 v1(248.66,130.25) 249.13,130.25 v2(249.58,129.8)
  IN1 w0.084: v2(249.58,129.8) 249.58,131.71 250.59,132.73 256.96,132.73 v2(257.79,131.9)
  BOTTOM w0.127: QL1.1 v2(257.79,131.9)
LOM_CABLE_DETECT#: length 58.3
  TOP w0.127: UE1.D2 249.08,84.45 248.69,84.05 248.69,83.35 248.19,82.86 v2(248.19,82.2)
  IN1 w0.084: v2(248.19,82.2) 249.88,83.9 249.88,88.44 250.6,89.16 250.97,89.16 251.69,89.88 251.69,92.64 251.81,92.77 251.81,93.76 251.42,94.16 251.42,95.55 251.67,95.81 251.67,96.52 252.5,97.35 252.5,107.88 251.41,108.98 251.41,110.15 251.89,110.63 251.89,111.54 251.53,111.9 v2(251.53,113.49)
  IN2 w0.122: v2(251.53,113.49) 250.9,114.12 250.9,115.29 251.53,115.92 251.53,121.98 252.23,122.68 252.23,124.38 254.04,126.19 v2(254.04,128.43)
  BOTTOM w0.127: UL2.4 253.45,131.44 253.66,131.24 253.66,130.31 v1(253.83,130.14) 254.04,129.93 v2(254.04,128.43) 254.04,127.77 RE505.1
LOM_SPD10LED_GRN#: length 23.7
  TOP w0.127: v2(248.94,129.8) 248.48,129.34 UL1.25 ; RL30.2 256.55,133.12 256.84,132.83 v2(256.84,132.28) 256.91,132.34 v1(257.43,132.34) 260.14,132.34 v2(260.64,131.84)
  IN1 w0.084: v2(260.64,131.84) 259.38,133.11 250.53,133.11 248.94,131.52 v2(248.94,129.8)
  BOTTOM w0.127: UL2.2 256.65,132.09 v2(256.84,132.28) ; QL2.1 v2(260.64,131.84)
LOM_SPD100LED_ORG#: length 14
  TOP w0.127: UL1.27 247.68,129.37 247.96,129.66 247.96,130.17 249.31,131.52 252.69,131.52 v1(253.41,132.24) 254.29,133.12 RL29.2 255.23,133.55 255.55,133.87 v2(256.31,133.87)
  BOTTOM w0.127: UL2.1 256.12,132.74 QL1.4 256.49,133.69 v2(256.31,133.87)
LPS_PROTECT#: length 1
  TOP w0.127: PT1.1 32.41,58.48 PR1248.2
LPSS_UART2_RXD: length 77.4
  TOP w0.127: v2(145.38,100.05) 145.58,99.84 145.7,99.84 147.98,97.56 148.52,97.56 148.67,97.71 151.74,97.71 153.99,99.96 153.99,102.76 153.54,103.21 153.54,104.7 151.78,106.46 151.78,107.77 151.43,108.11 151.43,111.23 151.52,111.33 151.52,118.17 152.13,118.78 152.13,120.17 148.14,124.16 145.98,124.16 143.81,126.33 140.41,126.33 139.18,127.56 139.18,128.49 138.63,129.04 136.73,129.04 133.42,132.34 130.15,132.34 129.87,132.62 129.87,133.05 v2(129.69,133.23)
  BOTTOM w0.076: 135.53,99.52 135.51,99.54 135.49,99.54 134.33,100.7 132.71,100.7 132.53,100.52 132.42,100.52 UC1.AD1
  BOTTOM w0.127: JUART1.2 129.61,132.51 129.87,132.78 129.87,133.05 v2(129.69,133.23) ; 135.53,99.52 135.6,99.45 137.88,99.45 138.83,100.4 140.25,100.4 140.71,99.94 142.93,99.94 RC402.1 143.76,100.77 144.66,100.77 v2(145.38,100.05) 145.83,100.05 RC330.1
LPSS_UART2_TXD: length 78.7
  TOP w0.127: v2(145.38,99.45) 145.51,99.59 145.6,99.59 147.88,97.31 148.63,97.31 148.78,97.46 151.84,97.46 154.24,99.86 154.24,102.86 153.79,103.31 153.79,104.81 152.03,106.56 152.03,107.87 151.68,108.22 151.68,111.13 151.78,111.22 151.78,118.07 152.39,118.68 152.39,120.27 148.25,124.42 146.08,124.42 143.91,126.59 140.51,126.59 139.43,127.67 139.43,128.59 138.73,129.29 136.83,129.29 133.52,132.6 130.25,132.6 130.13,132.73 130.13,133.05 130.28,133.2 v2(130.28,133.23)
  BOTTOM w0.076: UC1.AD2 132.05,100.24 132.54,100.24 132.79,100.49 134.24,100.49 135.34,99.39 135.34,99.37 135.36,99.35
  BOTTOM w0.127: JUART1.3 130.41,132.49 130.13,132.78 130.13,133.09 v2(130.28,133.23) ; 135.36,99.35 135.5,99.21 137.98,99.21 138.93,100.17 140.15,100.17 140.61,99.71 142.95,99.71 RC403.1 143.78,98.88 145.05,98.88 145.38,99.21 v2(145.38,99.45) 145.87,99.45 RC331.1
LX1_ISL9538: length 13
  IN1 w1.016: 47.92,66.74 49.43,66.74 53,63.18 56.59,63.18 58.5,61.27 58.5,61.07
  vias: v1(45.57,66.34) v2(43.54,71.74) v2(43.55,70.67) v2(43.58,64.84) v2(43.56,64.2) v2(44.21,64.79) v2(44.22,64.19) v2(44.28,71.74) v2(44.28,70.67) v2(44.76,65.44) v2(44.87,64.79) v2(44.88,64.19) v2(45.01,71.73) v2(45.01,70.67) v2(45.35,65.44) v2(45.51,64.79) v2(45.52,64.19) v2(46.01,65.42) v2(46.14,64.79) v2(46.15,64.19) v2(46.65,67.09) v2(46.69,66.36) v2(46.67,65.44) v2(46.76,64.81) v2(57.71,59.9) v2(58.09,60.36)
LX2_ISL9538: length 11.1
  IN1 w0.508: v2(59.87,57.97) 60.24,57.97 60.7,58.43 60.7,60.19 60.24,60.64 60.24,61.84 57.28,64.81 v2(57.28,65.82)
  BOTTOM w0.127: v1(55.69,64.59) 55.85,64.76 v2(55.85,65.82)
  vias: v2(55.68,69.68) v2(55.85,68.77) v2(55.85,68.03) v2(55.85,67.3) v2(55.85,66.56) v2(56.28,69.68) v2(56.56,68.77) v2(56.56,68.03) v2(56.56,67.3) v2(56.56,66.56) v2(56.56,65.82) v2(56.89,69.68) v2(57.28,68.77) v2(57.28,68.03) v2(57.28,67.3) v2(57.28,66.56)
LX_1.8VALW: length 2.1
  BOTTOM w0.127: PL501.1 v1(176.03,65.31)
LX_1V_PRIM: length 2.2
  TOP w0.508: PR409.1 155.03,129.36 v2(155.18,129.36)
  BOTTOM w0.127: v2(155.18,129.36) 155.18,129.69 v1(154.68,130.19)
LX_1VS_VCCIO: length 2.7
  TOP w0.127: PR405.1 138.52,131.64 137.89,132.27 v1(137.18,132.27)
  TOP w0.508: v2(139.34,131.14) 138.96,131.52 PR405.1
LX_3V: length 2.9
  BOTTOM w0.127: PR106.1 158.78,70.98 157.26,69.45 v1(156.99,69.45)
  vias: v2(152.47,74.1) v2(153.06,74.08) v2(156.06,74) v2(156.67,74)
LX_5V:
  vias: v2(182.85,54.29) v2(183.41,54.24) v2(187.22,54.47) v2(187.22,53.86) v3(186.46,54.15)
LX_DDR: length 1.4
  TOP w0.127: PR202.1 v1(67.65,64.98)
  vias: v2(67.33,67.52) v2(67.97,67.52)
M2280_DEVSLP: length 223.4
  TOP w0.127: v2(24.26,47.74) 23.58,47.07 RN37.2 ; v2(130.32,108.96) 130.81,108.47 133.98,108.47 v2(134.49,108.98)
  IN1 w0.084: v2(146.07,61.48) 145.01,61.48 143.74,62.75 142.75,62.75 139.51,65.98 73.87,65.98 73.08,65.19 73.08,63.61 73.56,63.13 73.56,56.12 72.4,54.96 69.8,54.96 69.06,55.71 65.19,55.71 60.94,51.46 59.42,51.46 58.93,51.95 54.76,51.95 54.13,51.32 42.83,51.32 42.45,51.7 40.92,51.7 40.37,51.15 33.72,51.15 30.31,47.74 v2(24.26,47.74) 22.86,47.74 19.7,44.58 JNGFF3.38 ; v2(134.49,108.98) 134.52,108.98 134.62,108.88 136.92,108.88 137.66,109.62 147.22,109.62 147.97,108.88 148.76,108.88 149.86,107.78 149.86,106.92 151.41,105.37 151.41,104.34 v2(151.98,103.77)
  IN4 w0.084: v2(149.66,96.08) 149.97,95.76 149.97,92.88 149.47,92.38 149.47,91.61 146.33,88.47 146.33,86.04 145.65,85.36 145.65,80.22 143.99,78.56 143.99,75.78 144.66,75.11 144.66,70.9 146.56,69 146.56,68.99 146.69,68.86 146.69,66.1 146.43,65.84 146.43,61.84 v2(146.07,61.48)
  BOTTOM w0.102: UC1.J3 130.95,108.48 130.47,108.96 v2(130.32,108.96)
  BOTTOM w0.127: v2(149.66,96.08) 149.66,101.51 v1(150.91,102.77) 150.97,102.77 v2(151.98,103.77)
M2280_PCIE_SATA#: length 228.4
  IN1 w0.084: v2(12.99,46.66) 13.41,47.08 21.12,47.08 22.18,48.13 30.32,48.13 33.59,51.41 40.24,51.41 40.72,51.89 42.53,51.89 42.86,51.55 44.19,51.55 44.85,52.21 59.38,52.21 59.63,52.46 61.06,52.46 61.37,52.77 61.37,53.67 62.29,54.58 62.92,54.58 64.27,55.93 69.15,55.93 69.89,55.18 72.24,55.18 73.3,56.25 73.3,63 72.82,63.48 72.82,65.29 73.73,66.2 139.62,66.2 142.82,63 143.89,63 144.94,61.95 v2(145.66,61.95)
  IN2 w0.122: v2(147.8,103.6) 147.8,103.61 148.45,104.26 148.45,106.3 148.66,106.51 148.66,106.93 148.24,107.36 148.24,107.9 148.73,108.4 148.73,110.4 v2(147.62,111.51)
  IN4 w0.084: v2(148.36,100.05) 149.26,99.15 149.26,95.72 149.74,95.24 149.74,92.98 149.19,92.44 149.19,91.73 146.02,88.56 146.02,86.12 145.39,85.49 145.39,80.23 143.73,78.57 143.73,75.78 144.48,75.03 144.48,70.81 146.51,68.78 146.51,66.18 146.18,65.85 146.18,62.08 146.05,61.95 v2(145.66,61.95)
  BOTTOM w0.076: 135.23,110.55 135.08,110.7 133.75,110.7 133.59,110.54 133.59,110.34 132.71,109.46 131.18,109.46 130.71,109.67 130.71,109.68 UC1.G4
  BOTTOM w0.127: v2(12.99,46.66) 12.31,46.66 11.95,46.29 JNGFF3.69 ; 135.23,110.55 138.47,110.55 139.05,109.97 144.49,109.97 145.26,110.74 RPC4.4 146.42,110.74 147.19,111.51 v2(147.62,111.51) ; v2(147.8,103.6) 147.8,103.42 148.61,102.61 148.61,100.81 v1(148.36,100.56) v2(148.36,100.05)
M3042_DEVSLP: length 179.3
  IN1 w0.084: v2(235.73,101.54) 235.33,101.14 235.33,94.51 238.48,91.36 238.48,88.62 237.84,87.98 237.84,84.39 238.71,83.53 239.36,83.53 239.86,83.02 239.86,81.84 240.73,80.97 240.73,75.5 242.53,73.7 242.53,72.02 v2(242.72,71.83)
  IN2 w0.122: v2(149.92,105.28) 150.37,104.84 150.37,100.77 155.52,95.62 160.4,95.62 161.13,94.88 161.13,94.23 162.09,93.27 162.92,93.27 165.12,91.07 165.12,89.59 165.97,88.75 165.97,87.55 167.92,85.6 167.92,83.97 169.84,82.05 169.84,79.11 171.14,77.8 171.14,75.66 171.81,75 173.63,75 177.57,71.07 179.45,71.07 181.63,68.88 185.55,68.88 187.14,67.29 205.16,67.29 206.63,65.83 224.72,65.83 225.4,66.51 226.8,66.51 227.1,66.81 227.12,66.81 227.48,67.18 228.81,67.18 228.82,67.19 229.13,67.19 229.65,67.7 231.55,67.7 231.62,67.63 231.76,67.48 232.11,67.48 232.31,67.48 234.75,69.92 235.76,69.92 236.03,70.19 239.84,70.19 241.48,71.83 v2(242.72,71.83)
  BOTTOM w0.076: 134.86,109.33 133.7,109.33 133.45,109.08 133.45,108.6 133.08,108.22 132.27,108.22 131.91,108.48 UC1.J2
  BOTTOM w0.127: 134.86,109.33 v1(135.84,109.33) 135.89,109.38 138.28,109.38 138.69,108.98 144.09,108.98 144.66,108.41 144.66,106.74 144.5,106.58 144.5,105.47 144.8,105.17 149.8,105.17 v2(149.92,105.28) ; JNGFF2.30 236.69,102.5 v2(235.73,101.54)
M3042_PCIE#_SATA: length 196.4
  TOP w0.127: v1(144.52,107.35) v2(145.11,107.35) ; v2(253.48,93.06) UE1.J12
  IN2 w0.122: v2(145.11,107.35) 144.24,106.49 144.24,102.91 144.55,102.6 144.55,102.4 146.48,100.47 147.55,100.47 147.8,100.72 148.56,100.72 151.48,97.79 151.48,93.08 152.1,92.46 153.71,92.46 156.17,94.92 160.09,94.92 160.46,94.55 160.46,93.95 161.95,92.46 162.78,92.46 164.44,90.8 164.44,89.32 165.3,88.47 165.3,87.27 167.25,85.32 167.25,83.69 169.16,81.78 169.16,78.83 170.47,77.52 170.47,75.38 171.58,74.27 173.41,74.27 177.29,70.4 179.07,70.4 181.26,68.21 185.28,68.21 186.86,66.62 204.78,66.62 206.31,65.09 224.93,65.09 225.68,65.84 227.1,65.84 227.62,66.35 232.13,66.35 235.03,69.25 236.04,69.25 236.31,69.52 240.12,69.52 241.31,70.71 242.79,70.71 243.49,71.41 244.48,71.41 244.99,71.92 248.4,71.92 249.34,72.86 249.91,72.86 251.14,74.09 252.81,74.09 253.03,73.87 254.33,73.87 254.34,73.87 257.93,73.87 258.33,73.47 260.15,73.47 262.12,75.44 262.61,75.44 262.82,75.66 262.82,76.35 263.49,77.01 263.49,80.15 262.98,80.66 262.98,82.72 261.99,83.71 261.99,86.23 261.01,87.21 259.61,87.21 258.52,88.3 258.52,88.54 257.98,89.08 257.65,89.08 257.21,89.51 257.21,90.88 255.42,92.67 254.07,92.67 253.69,93.06 v2(253.48,93.06)
  BOTTOM w0.076: 134.85,109.69 134.64,109.69 134.54,109.59 133.7,109.59 132.87,108.75 132.33,108.75 132.19,108.71 131.94,108.71 131.85,108.74 131.19,108.74 UC1.H3
  BOTTOM w0.127: 134.85,109.69 138.3,109.69 138.78,109.21 144.4,109.21 145.17,108.43 RC412.2 145.11,107.9 v2(145.11,107.35)
MASK_BASE_LEDS#: length 5.9
  TOP w0.127: QZ7.5 267.04,82.88 267.36,83.2 267.36,85.8 267.03,86.13 UZ10.4 265.49,86.13 v1(265.13,85.78)
MASK_SATA_LED#: length 27.9
  TOP w0.127: UE1.L6 v2(255.07,87.47) ; v1(274.19,82.99) 273.77,83.4 v2(273.77,83.89) QZ2.5
  IN4 w0.084: v2(273.77,83.89) 271.44,81.57 268.95,81.57 267.41,83.11 267.41,87.68 267.17,87.92 260.83,87.92 260.1,87.19 255.35,87.19 v2(255.07,87.47)
ME_FWP: length 46.3
  TOP w0.127: UE1.G12 v2(251.08,93.06)
  IN1 w0.084: v2(251.08,93.06) 250.81,93.33 250.81,96.29 251.12,96.6 251.12,97.87 250.09,98.9 250.09,100.76 250.51,101.18 v2(250.51,101.31)
  IN2 w0.122: v2(231.98,88.87) 232.51,89.39 232.51,94.17 233.35,95.01 236.13,95.01 236.75,95.63 239.75,95.63 243.69,99.58 245.39,99.58 246.68,100.86 250.13,100.86 250.51,101.24 v2(250.51,101.31)
  BOTTOM w0.127: v2(231.98,88.87) 231.78,88.87 RC221.1 228.73,87.77 226.85,85.89 226.85,83.87 227.04,83.61 SW1.1
ME_FWP_PCH: length 148.5
  TOP w0.127: v2(232.02,85.89) 231.95,85.89 228.8,82.73 228.8,76.2 223.42,70.82 v2(220.07,70.82) ; v2(140.98,77.4) 140.52,76.94 v1(136.54,76.94) 132.85,76.94 131.07,78.72 129.83,78.72 129.07,77.95 129.06,77.95 128.94,77.83 124.79,77.83 RC223.1
  IN2 w0.122: v2(140.98,77.4) 140.87,77.29 140.87,76.73 144.06,73.54 144.06,73.22 150.26,67.02 157.06,67.02 160.32,63.77 164.86,63.77 164.98,63.65 168.5,63.65 170.29,61.86 170.66,61.86 171.67,60.84 172.87,60.84 173.03,60.69 174.37,60.69 175.45,59.6 177.48,59.6 178.18,60.3 179.1,60.3 179.71,60.9 183.96,60.9 184.21,60.65 201.54,60.65 204.35,57.84 204.35,57.8 204.35,57.61 205.06,56.9 208.82,56.9 209.52,56.2 210.29,56.2 211.12,57.03 215.82,57.03 216.56,56.29 218.5,56.29 v2(218.93,56.72)
  BOTTOM w0.127: SW1.3 229.93,86.46 v2(232.02,85.89) 232.02,86.88 231.51,87.38 ; v2(220.07,70.82) 218.76,69.51 218.76,56.89 v2(218.93,56.72)
ME_RESET#: length 4.5
  BOTTOM w0.127: UC12.2 150.58,115.96 150.26,116.28 150.26,117.5 RC227.1 RC225.1 149.64,118.57 v1(149.77,118.69)
ME_SUS_PWR_ACK: length 158.7
  TOP w0.127: v1(142.29,85.85) 142.79,85.85 v2(143.13,85.52) 143.13,84.79 RC74.1 143.83,84.08 143.83,83.4 144.02,83.22 144.02,83.21 144.06,83.18 144.06,83.18 144.32,82.92 RC444.1 ; v2(247.1,94.31) 247.37,94.04 247.37,93.57 UE1.B13
  IN2 w0.122: v2(143.13,85.52) 143.29,85.68 143.83,85.68 144.11,85.96 144.51,85.96 145.23,85.25 145.23,82.57 148.14,79.65 148.14,72.62 150.82,69.95 158.25,69.95 161.65,66.55 165.87,66.55 166.25,66.17 168.64,66.17 169.67,67.21 172.36,67.21 173.93,65.64 178.97,65.64 179.77,64.84 183.5,64.84 185.22,63.12 203.06,63.12 204.96,61.21 214.53,61.21 215.03,60.71 218.06,60.71 218.81,61.46 226.31,61.46 226.45,61.59 234.65,61.59 236.26,63.21 240.1,63.21 240.96,64.06 243.04,64.06 246.22,67.25 v2(246.22,68.33)
  BOTTOM w0.127: v2(247.1,94.31) 247.1,93.55 246.09,92.53 246.09,87.51 245.49,86.91 245.49,85.16 245.06,84.73 245.06,84.09 246.63,82.52 246.63,81.39 248.14,79.89 248.14,78.61 248.39,78.36 248.39,75.53 248.87,75.05 248.87,73.72 247.43,72.28 247.43,70.71 246.36,69.64 246.36,68.47 v2(246.22,68.33)
ME_SUS_PWR_ACK_R: length 26.8
  TOP w0.127: RC444.2 144.08,84.12 144.08,84.97 v2(143.79,85.26) v1(143.79,85.82)
  IN4 w0.084: v2(143.79,85.26) 143.79,85.7 143.47,86.02 142.97,86.02 142.18,86.82 137.69,86.82 133.75,90.75 129.14,90.75 126.99,92.9 126.99,94.37 126.78,94.58 125.04,94.58 v2(124.78,94.84)
  BOTTOM w0.076: UC1.AR13 125.05,95.1 v2(124.78,94.84)
MEC_XTAL1: length 5.6
  TOP w0.127: UE1.A1 246.36,83.86 245.19,82.69 244.8,82.69 v1(244.62,82.86) 244.47,83.02 CE28.1 243.25,83.02 242.44,82.2 YE1.1
MEC_XTAL2: length 2.8
  TOP w0.127: RE290.2 CE29.1 243.18,83.95 242.42,84.7 YE1.2
MEC_XTAL2_R: length 2.4
  TOP w0.127: UE1.A3 246.09,84.86 RE290.1
MEDIACARD_IRQ#: length 177.4
  TOP w0.127: v2(266.24,66.7) 266.93,67.39 269,67.39 270.23,68.62 v1(271.73,68.62) RR19.1 272.85,68.36 273.87,67.34 UR1.32
  IN1 w0.084: v2(266.24,66.7) 266.24,67.6 263.74,70.09 263.74,70.38 261.75,72.37 v2(260.64,72.37)
  IN2 w0.122: v2(148.5,95.72) 148.5,95.44 148.65,95.29 148.65,94.97 149,94.63 149,92.18 150.33,90.85 158.3,90.85 158.54,90.61 162.24,90.61 162.97,89.88 162.97,89.27 163.12,89.12 163.69,89.12 164.63,88.19 164.63,86.99 166.51,85.11 166.51,83.49 168.48,81.51 168.48,78.56 168.99,78.05 168.99,74.46 169.85,73.6 173.13,73.6 177.01,69.72 178.55,69.72 180.74,67.53 184.93,67.53 186.5,65.95 204.18,65.95 205.73,64.41 225.2,64.41 225.96,65.17 227.39,65.17 227.91,65.68 231.41,65.68 232.41,65.68 235.31,68.58 236.32,68.58 236.59,68.85 241.12,68.85 241.95,69.68 243.24,69.68 243.83,70.27 244.65,70.27 245.62,71.24 248.75,71.24 249.7,72.19 250.23,72.19 250.56,72.52 256.3,72.52 256.43,72.65 257.63,72.65 258.29,71.99 259.37,71.99 259.74,72.37 v2(260.64,72.37)
  IN4 w0.084: v2(127.51,96.71) 127.89,97.09 130.24,97.09 131.94,95.39 144.75,95.39 144.92,95.22 146.35,95.22 146.85,95.72 v2(148.5,95.72)
  BOTTOM w0.076: UC1.AN8 127.81,96.4 v2(127.51,96.71)
MEM_INTERLEAVED: length 9.8
  BOTTOM w0.076: 133.73,106.34 133.48,106.08 132.3,106.08 UC1.P2
  BOTTOM w0.127: RC372.1 RC371.1 139.42,106.69 138.26,106.69 138.09,106.51 v1(136.17,106.51) 133.91,106.51 133.73,106.34
MEM_SMBCLK: length 26
  TOP w0.127: v2(129.5,104.85) 129.89,104.45 131.75,104.45 131.97,104.23 132.7,104.23 CC320.1 133.31,104.84 RC12.1 134.59,104.84 135.15,105.4 135.15,105.57 136.34,106.76 138.74,106.76 139.83,107.85 141.55,107.85 142.43,108.73 146.15,108.73 147.51,107.37 148.6,107.37 148.79,107.56 v2(148.79,107.56)
  BOTTOM w0.102: v2(129.5,104.85) 129.16,105.31 UC1.R7
  BOTTOM w0.127: QC2.6 149.36,109.75 149.7,109.41 149.7,108.33 149.32,107.95 149.06,107.95 148.79,107.67 v2(148.79,107.56)
MEM_SMBDATA: length 26.5
  TOP w0.127: v2(149.41,107.52) 149.01,107.12 147.4,107.12 146.04,108.47 142.54,108.47 141.65,107.59 139.93,107.59 138.85,106.51 136.45,106.51 135.41,105.47 RC14.1 134.89,104.32 133.26,104.32 132.92,103.98 131.87,103.98 131.65,104.2 129.55,104.2 v2(128.91,104.83)
  BOTTOM w0.102: v2(128.91,104.83) 128.5,105.32 UC1.R8
  BOTTOM w0.127: v2(149.41,107.52) 149.6,107.52 150.53,108.45 QC2.3
MPHYP_PWR_EN: length 22.1
  TOP w0.127: v2(126.5,96.7) 127,96.2 127,95.92 127.27,95.65 128.82,95.65 v1(128.94,95.53) 129.06,95.41 129.64,95.41 130.11,94.94 130.11,94.26 130.33,94.05 130.33,94.05 137.19,87.18 137.19,87.18 137.22,87.16 138.69,87.16 139.62,86.23 141.21,86.23 142.45,84.98 RC387.1
  BOTTOM w0.102: UC1.AM10 126.89,97.05 126.53,96.7 v2(126.5,96.7)
MSCLK: length 87
  TOP w0.127: UE1.H10 v2(252.68,91.46)
  IN4 w0.084: v2(252.68,91.46) 251.92,92.22 251.92,93.66 250.52,95.06 250.52,95.96 248.55,97.94 248.55,111.95 250.36,113.76 250.36,116.31 251.15,117.11 251.15,122.03 258.74,129.61 285.28,129.61 286.4,128.49 286.4,123.22 287.17,122.45 287.17,121.89 v2(287.7,121.36) 289.16,122.82 290.16,122.82 290.41,123.07 290.41,123.43 v2(289.98,123.86)
  BOTTOM w0.127: RE72.2 v2(287.7,121.36) RE30.1 ; JDEG1.6 290,123.84 v2(289.98,123.86)
MSDATA: length 88
  TOP w0.127: v3(289.34,120.8) 289.34,122.64 v2(289.96,123.26) ; UE1.G9 v2(251.08,90.66)
  IN4 w0.084: v2(251.08,90.66) 251.66,91.23 251.66,93.55 250.26,94.95 250.26,95.85 248.28,97.83 248.28,112.05 250.05,113.82 250.05,116.37 250.89,117.21 250.89,122.14 258.63,129.88 285.39,129.88 286.66,128.6 286.66,123.33 286.98,123.01 287.49,123.01 v2(287.74,123.26) v2(289.96,123.26)
  BOTTOM w0.127: JDEG1.7 290.04,123.34 v2(289.96,123.26) ; RE75.2 v2(287.74,123.26) RE86.1
NB_MUTE#: length 74.3
  TOP w0.127: UE1.A4 245.75,85.32 243.88,85.32 243.43,85.77 243.43,86.1 243.35,86.19 v2(243.35,86.28) ; RA48.1 261.95,69.49 262.33,69.11 v2(262.4,69.11) 262.77,69.47 DA8.1
  IN2 w0.122: v2(262.4,69.11) 262.26,69.26 262.26,71.09 266.09,74.92 266.09,78.35 266.82,79.07 266.82,83.18 265.22,84.77 265.22,86.4 264.88,86.74 264.88,94.43 v2(264.61,94.7)
  BOTTOM w0.127: v2(243.35,86.28) 243.35,86.47 243.43,86.56 243.43,87.27 243.95,87.78 243.95,96.7 245.09,97.84 245.09,99.59 245.88,100.38 251.29,100.38 251.83,100.92 257.38,100.92 258.66,102.2 260.1,102.2 260.93,101.37 260.93,101.11 261.29,100.75 261.29,100.21 260.97,99.89 260.97,98.34 v2(264.61,94.7)
NB_PSID: length 9.6
  TOP w0.254: PD4.3 PD4.2 38.7,123.59 PL3.2 38.8,122.83 v2(39.44,122.18)
  BOTTOM w0.127: v1(38,124.15) 38.25,124.15 39.44,122.96 v2(39.44,122.18)
  BOTTOM w0.254: v2(39.44,122.18) 39.08,122.55 PJPDC1.1
NGFF_CONFIG_0: length 52.4
  TOP w0.127: v2(235.49,108.32) 235.18,108.32 v1(234.78,108.71) ; RPE9.4 261.34,93.24 v2(260.87,93.71) 259.36,92.2 259.12,92.2 257.17,90.26 UE1.N9
  IN2 w0.122: v2(235.49,108.32) 236.84,109.66 240.2,109.66 244.81,105.05 255.53,105.05 256.04,104.54 258.52,104.54 260.84,102.23 260.84,101.06 261.22,100.67 261.22,100.1 260.99,99.87 260.99,99.29 261.54,98.74 261.54,96.05 261.75,95.85 261.75,94.24 261.21,93.71 v2(260.87,93.71)
  BOTTOM w0.127: JNGFF2.13 231.03,106.75 232.6,108.32 v2(235.49,108.32)
NGFF_CONFIG_1: length 50.6
  TOP w0.127: UE1.M10 255.88,90.66 257.19,90.66 v1(259.12,92.58) 259.42,92.58 260.4,93.56 260.4,93.86 260.83,94.3 v2(260.86,94.3) 261,94.3 261.55,93.74 RPE9.3
  IN2 w0.122: v2(233.99,97.43) 233.99,96.9 235.28,95.61 236.39,95.61 237.48,96.7 240.08,96.7 243.39,100.01 245.51,100.01 248.47,102.97 254.66,102.97 257.82,99.81 259.13,99.81 260.18,98.75 260.18,97.43 259.95,97.2 259.95,94.77 260.42,94.3 v2(260.86,94.3)
  BOTTOM w0.127: v2(233.99,97.43) 233.99,96.92 232.05,94.98 231.45,94.98 231.22,94.75 JNGFF2.61
NGFF_CONFIG_2: length 52.1
  TOP w0.127: RPE9.2 261.5,94.24 v2(260.86,94.88) 260.74,94.88 260.17,94.31 260.17,93.86 v1(259.98,93.67) 259.71,93.67 257.09,91.06 UE1.N10
  IN2 w0.122: v2(260.86,94.88) 260.53,94.88 260.22,95.18 260.22,97.06 260.48,97.32 260.48,98.94 259.36,100.06 257.89,100.06 254.7,103.25 247.41,103.25 244.53,100.37 243.4,100.37 240.79,97.76 238.1,97.76 236.25,95.91 235.46,95.91 234.96,96.41 234.96,97.2 v2(234.08,98.08)
  BOTTOM w0.127: v2(234.08,98.08) 234.47,97.69 234.47,96.94 232.33,94.8 232.33,94.16 231.41,93.25 JNGFF2.67
NGFF_CONFIG_3: length 76.6
  TOP w0.127: UE1.F4 v2(250.28,85.86) ; RPE9.1 261.57,94.74 v2(260.84,95.46) 260.58,95.46 v1(260.2,95.08)
  IN2 w0.122: v2(232.37,111.26) 234.11,109.52 234.11,106.28 234.32,106.07 236.95,106.07 238.05,107.17 241.81,107.17 244.44,104.54 255.39,104.54 255.85,104.09 258.21,104.09 260.34,101.96 260.34,99.51 261.26,98.59 261.26,95.88 v2(260.84,95.46)
  IN4 w0.084: v2(250.28,85.86) 250.68,85.46 250.68,84.78 251.76,83.7 254.75,83.7 255.41,83.04 258.81,83.04 260.65,84.88 260.65,85.79 261.29,86.43 261.77,86.43 263.66,84.53 v2(263.66,84.5)
  BOTTOM w0.127: v2(260.84,95.46) 262.01,94.29 262.01,85.62 263.14,84.5 v2(263.66,84.5) ; v2(232.37,111.26) 231.88,111.75 JNGFF2.1
NRB_BIT: length 13.6
  TOP w0.127: v2(128.4,94.02) 128.27,93.89 128.27,92.62 v1(134.28,86.61) 134.83,86.05 RC186.1
  BOTTOM w0.076: UC1.AR7 128.84,95.1 128.4,94.66 v2(128.4,94.02)
NTC_GT: length 2.7
  TOP w0.203: PR635.2 52.37,92.96 51.99,93.34 51.99,93.39 51.99,93.39 51.99,93.78 51.69,94.08 51.32,94.08 51.21,93.97 PU602.15
NVME_LED#: length 11.4
  TOP w0.127: RN100.1 v2(25.17,50.44) v1(25.17,49.9)
  IN4 w0.084: v2(25.17,50.44) 25.17,46.99 25.93,46.23 25.93,43.55 26.7,42.78 JNGFF3.10
ONE_DIMM#: length 11.3
  BOTTOM w0.076: 135.54,96.1 135.47,96.02 134.87,96.02 134.69,96.2 130.96,96.2 130.78,96.38 130.78,96.71 130.63,96.86 130.22,96.86 130.1,96.73 129.56,96.73 129.12,96.29 129.12,96.29 128.96,96.12 128.95,96.12 128.84,96.01 UC1.AP7
  BOTTOM w0.127: RC267.1 137.92,97.22 RC268.1 136.94,97.22 135.84,96.11 135.55,96.11 135.54,96.1
OTGEN/CMIN: length 5.5
  TOP w0.127: v1(50.95,60.2) 51.47,59.68 PR960.2
  TOP w0.203: PU901.20 53.5,57.24 53.39,57.35
  TOP w0.254: PR960.2 PR919.2 51.54,58.37 52.55,57.35 53.39,57.35
PANEL_BKEN_EC: length 263
  TOP w0.127: UE1.J9 v2(253.48,90.66) ; v2(73.86,125.69) 73.86,123.32 DV2.2 74.51,121.83 v1(74.12,121.44)
  IN2 w0.122: v2(73.86,125.69) 74.19,126.02 80.21,126.02 80.59,125.65 81.76,125.65 83.61,127.49 84.23,127.49 86.18,129.45 87.35,129.45 87.51,129.61 115.42,129.61 116.59,130.78 125.91,130.78 126.81,131.68 126.81,131.89 127.07,132.15 127.69,132.15 128.26,131.57 135.13,131.57 135.69,131.02 138.8,131.02 141.27,128.54 144.61,128.54 146.14,127.01 147.15,127.01 148.01,126.16 154.52,126.16 158.31,122.37 159.26,122.37 161.36,120.28 161.36,117.4 161.7,117.06 161.7,108.9 163.56,107.04 163.56,105.07 165.45,103.19 165.45,93.08 166.59,91.93 166.59,89.89 167.28,89.2 167.28,88.02 169.19,86.11 169.19,84.48 171.17,82.5 171.17,80.2 175.67,75.7 175.67,75.3 177.59,73.37 178.51,73.37 181.78,70.1 185.98,70.1 187.62,68.46 205.66,68.46 207.08,67.05 222.49,67.05 223.11,67.68 226.31,67.68 226.99,68.36 228.65,68.36 229.4,69.11 230.52,69.11 230.99,69.58 230.99,70.95 231.4,71.36 233.11,71.36 233.38,71.09 235.28,71.09 236.73,72.55 238.32,72.55 239.28,73.51 240.87,73.51 241.67,74.31 245.42,74.31 246.18,73.54 248.39,73.54 249.65,74.81 252.78,74.81 253.2,75.23 255.48,75.23 255.68,75.43 256.11,75.43 256.57,74.97 v2(257.63,74.97)
  BOTTOM w0.127: v2(257.63,74.97) 257.92,75.25 257.92,76.68 257.19,77.42 257.19,78.76 258.06,79.63 258.06,80.81 258.35,81.1 258.35,84.82 257.57,85.59 257.57,86.58 256.55,87.6 256.55,90.39 255.88,91.06 253.88,91.06 v2(253.48,90.66)
PANEL_BKLEN: length 95.1
  TOP w0.127: v1(76.4,121.99) v2(75.13,121.99) 75.17,122.03 75.17,122.89 74.51,123.55 DV2.3
  IN2 w0.122: v2(125.65,104.8) 125.65,104.54 126.29,103.9 130.16,103.9 131.72,105.46 131.72,111.32 132.28,111.88 132.28,112.97 134.33,115.02 134.33,115.22 134.34,115.22 134.34,116.88 135.72,118.26 135.72,121.43 135.11,122.04 135.11,124.2 133.38,125.92 130.3,125.92 129.33,126.89 125.58,126.89 125.06,126.36 120.78,126.36 120.78,126.36 118.7,126.36 117.42,125.08 98.96,125.08 97.67,123.79 85.03,123.79 83.89,122.65 82.08,122.65 81.42,121.99 v2(75.13,121.99)
  BOTTOM w0.076: UC1.R12 125.65,105.2 v2(125.65,104.8)
PBAT_CHARGER_SMBCLK: length 283.6
  TOP w0.127: PR922.1 50.24,56.91 49.68,56.91 49.35,56.58 49.35,55.21 52.03,52.54 52.03,52.08 52.8,51.31 53.98,51.31 54.34,50.95 54.34,50.56 v2(54.54,50.37) ; v2(263.08,77.98) 263.25,77.8 263.4,77.8 263.6,78 263.6,80.15 263.32,80.43 260.43,80.43 260.02,80.84 260.02,81.39 259.55,81.86 RE43.1 259.55,81.9 256.88,84.57 256.87,84.57 256.87,84.57 256.54,84.57 256.54,84.57 256.37,84.57 UE1.N2 ; PRP1.3 168.26,60.7 168.26,60.24 167.95,59.93 167.74,59.93 v2(167.57,59.76) 167.41,59.92 166.99,59.92 166.65,60.26 166.65,61.66 166.84,61.85 166.84,62.03 166.67,62.2 PD2.3
  IN1 w0.084: v2(167.57,59.76) 167.37,59.96 167.25,59.96 166.15,58.86 158.1,58.86 157.06,59.9 149.07,59.9 148.76,60.21 146.41,60.21 145.86,59.67 144.84,59.67 143.65,60.85 142.53,60.85 141.26,62.13 141.26,63.5 139.23,65.53 74.13,65.53 73.55,64.95 73.55,63.76 74.03,63.28 74.03,55.91 72.65,54.53 69.62,54.53 68.9,55.25 65.3,55.25 61.11,51.06 60.36,51.06 59.97,50.67 55.18,50.67 54.97,50.87 54.46,50.87 54.34,50.75 54.34,50.54 54.51,50.37 v2(54.54,50.37)
  IN4 w0.084: v2(167.57,59.76) 167.73,59.92 174.36,59.92 175.39,58.89 178.81,58.89 179.64,59.72 180.26,59.72 180.46,59.52 180.46,59.05 180.09,58.68 180.09,58.11 180.48,57.72 181.42,57.72 182.92,59.22 195.7,59.22 196.52,58.4 200.93,58.4 203.38,55.95 210.17,55.95 210.74,56.53 216.55,56.53 217.11,55.96 217.38,55.96 218.12,55.22 222.27,55.22 223.23,54.26 224.28,54.26 225.39,53.14 228.56,53.14 230.77,50.93 244.25,50.93 247.76,54.44 247.76,55.94 246.28,57.42 246.28,60.4 246.56,60.68 246.56,61.59 252.47,67.5 252.47,70.42 254.48,72.43 256.41,72.43 256.88,72.9 259.69,72.9 261.68,74.9 262.87,74.9 263.83,75.85 263.83,77.24 263.09,77.98 v2(263.08,77.98)
PBAT_CHARGER_SMBDAT: length 285.9
  TOP w0.127: v2(53.95,50.37) 54.08,50.5 54.08,50.84 53.87,51.05 52.69,51.05 51.77,51.98 51.77,52.44 49.1,55.11 49.1,56.69 49.57,57.16 50.24,57.16 PR920.1 ; v2(263.08,77.39) 263.23,77.55 263.5,77.55 263.86,77.9 263.86,80.25 263.42,80.69 260.54,80.69 260.28,80.95 260.28,81.78 RE37.1 260.51,82.62 259.25,82.62 257.04,84.83 256.75,84.83 256.53,85.06 255.88,85.06 UE1.M3 ; PRP1.2 168.16,61.3 168,61.15 168,60.35 167.86,60.2 167.71,60.2 v2(167.57,60.34) 167.39,60.17 167.09,60.17 166.9,60.36 166.9,61.55 167.1,61.75 167.1,62.18 167.42,62.51 PD1.2
  IN1 w0.084: v2(53.95,50.37) 54.13,50.54 54.13,50.84 54.37,51.08 55.06,51.08 55.26,50.88 59.88,50.88 60.28,51.27 61.02,51.27 65.21,55.46 68.99,55.46 69.71,54.74 72.56,54.74 73.82,56 73.82,63.19 73.34,63.67 73.34,65.04 74.04,65.74 139.31,65.74 141.47,63.59 141.47,62.22 142.62,61.06 143.74,61.06 144.92,59.88 145.78,59.88 146.32,60.42 148.84,60.42 149.16,60.11 157.15,60.11 158.19,59.07 166.07,59.07 167.17,60.17 167.39,60.17 v2(167.57,60.34)
  IN4 w0.084: v2(263.08,77.39) 262.78,77.1 262.78,75.42 262.64,75.28 261.76,75.28 259.6,73.11 256.79,73.11 256.32,72.64 254.39,72.64 252.21,70.46 252.21,67.61 246.29,61.69 246.29,60.79 246.02,60.51 246.02,57.35 247.5,55.87 247.5,54.54 244.14,51.19 230.81,51.19 228.64,53.35 225.48,53.35 224.31,54.52 223.34,54.52 222.38,55.48 218.23,55.48 217.49,56.23 217.22,56.23 216.66,56.79 210.64,56.79 210.06,56.21 203.49,56.21 201.04,58.66 196.56,58.66 195.79,59.43 182.83,59.43 181.33,57.93 180.56,57.93 180.3,58.2 180.3,58.59 180.67,58.97 180.67,59.61 180.35,59.93 179.55,59.93 178.73,59.11 175.47,59.11 174.4,60.18 167.73,60.18 v2(167.57,60.34)
PBAT_PRES#: length 265.9
  TOP w0.127: v2(162.3,56.25) 162.84,56.78 162.84,63.13 163.28,63.57 165.1,63.57 166.54,65.01 167.09,65.01 167.52,64.58 168.21,64.58 168.41,64.78 168.62,64.78 PR1.2 168.81,64.56 PD1.3 168.04,63.79 168.04,61.9 PRP1.1 ; v2(62.85,50.15) 62.83,50.13 v1(59.71,50.13) 55.8,50.13 53.94,51.99 PR931.1 ; UE1.F9 v2(250.28,90.66)
  IN1 w0.084: v2(162.3,56.25) 161.57,56.98 158.09,56.98 156.61,58.46 151.37,58.46 150.78,57.87 148.86,57.87 147.82,58.91 147.06,58.91 146.42,58.26 146.42,56.74 144.73,55.05 142.16,55.05 140.89,53.78 129.79,53.78 126.52,50.51 73.99,50.51 71.93,52.57 70.08,52.57 68.4,54.25 65.77,54.25 62.85,51.33 v2(62.85,50.15)
  IN2 w0.122: v2(250.28,90.66) 249.88,90.25 249.88,89.61 249.73,89.46 247.08,89.46 246.6,89.94 239.31,89.94 237.27,87.9 237.27,86.79 235.01,84.54 235.01,82.33 236.03,81.32 v2(236.55,81.32) ; v2(230.9,53.63) 230.37,53.09 226.4,53.09 225.76,53.73 225.75,53.73 225.7,53.78 222.67,53.78 222.31,53.42 219.27,53.42 218.94,53.74 214.3,53.74 213.81,53.25 209.61,53.25 208.84,52.47 207.23,52.47 206.24,51.48 203.23,51.48 201.74,52.97 197.85,52.97 196.79,51.91 191.71,51.91 190.88,52.74 184.08,52.74 183.43,53.39 183.02,53.39 181.94,54.47 180.09,54.47 179.31,55.26 179.31,56.06 179.08,56.29 178.37,56.29 177.43,55.35 163.2,55.35 v2(162.3,56.25)
  BOTTOM w0.127: v2(236.55,81.32) 236.55,80.78 235.71,79.94 235.71,70.7 235.02,70.02 235.02,67.67 235.42,67.28 235.42,62.9 235.94,62.38 235.94,59.75 233.4,57.21 233.4,56.04 230.99,53.63 v2(230.9,53.63)
PBAT_PRES#_C: length 3.6
  TOP w0.127: v1(169.32,63.82) 169.42,63.72 v2(169.42,63.28) 168.62,62.49 168.62,62.48
  BOTTOM w0.127: PBATT1.6 168.5,63.49 169.21,63.49 v2(169.42,63.28)
PBAT_SMBCLK_C: length 4
  TOP w0.127: v1(171.31,62.25) v2(170.6,62.25) 169.81,62.25 PRP1.6
  BOTTOM w0.127: v2(170.6,62.25) 170.6,61.34 PBATT1.4
PBAT_SMBDAT_C: length 3.6
  TOP w0.127: v1(170.44,63.21) 170.34,63.12 170.34,62.99 v2(170.11,62.76) 169.61,62.76 PRP1.7
  BOTTOM w0.127: PBATT1.5 169.9,62.76 v2(170.11,62.76)
PBATT+_C:
  vias: v2(168.27,57.62) v2(168.27,57.04) v2(168.27,56.46) v2(168.56,58.16) v2(168.85,57.62) v2(168.85,57.04) v2(168.85,56.46) v2(169.14,58.16) v2(169.44,57.62) v2(169.44,57.04) v2(169.44,56.46) v2(170.02,57.62) v2(170.02,57.04) v2(170.02,56.46) v2(170.61,57.62) v2(170.61,57.04) v2(170.61,56.46) v2(171.19,57.04) v2(171.24,56.42) v3(167.23,55.61) v3(168.38,54.14) v3(168.97,55.84)
PCH_3.3V_TS_EN: length 179.1
  TOP w0.127: v2(129.39,96.05) 129.79,95.64 129.94,95.64 v1(130.55,95.03) 130.55,94.14 137.28,87.41 138.77,87.41 139.72,86.47 141.41,86.47 141.65,86.22 144.37,86.22 RC282.1 ; RV324.1 47.9,118.91 47.9,119.14 46.94,120.1 46.94,124.56 47.6,125.22 v2(48.21,125.22)
  IN2 w0.122: v2(48.21,125.22) 49.16,124.26 53.68,124.26 56.16,121.78 59.08,121.78 62.05,124.75 68.02,124.75 69.07,125.79 70.55,125.79 70.72,125.97 72.67,125.97 73.65,124.99 75.47,124.99 76.14,124.32 81.42,124.32 83.5,126.4 85.39,126.4 85.8,126.81 89.48,126.81 90.55,127.88 100.91,127.88 101.27,127.52 102.93,127.52 103.29,127.88 115.03,127.88 116.19,129.04 121.86,129.04 122.09,128.81 124.55,128.81 125.18,129.44 138.42,129.44 139.78,128.08 139.78,127.19 142.51,124.46 143.84,124.46 144.4,123.9 144.4,120.46 142.27,118.33 140.59,118.33 137.24,114.98 137.24,112.58 138.16,111.67 138.16,111.49 140.57,109.08 140.78,109.08 141.59,108.27 141.59,105.42 139.2,103.02 139.2,102.17 138.46,101.43 138.46,98.51 137.31,97.36 137.31,96.02 136.35,95.06 130.37,95.06 v2(129.39,96.05)
  BOTTOM w0.076: v2(129.39,96.05) 129.68,95.75 UC1.AP5
PCH_ALW_ON: length 155
  TOP w0.127: v2(259.77,97.83) 259.68,97.92 RPE10.3 ; v1(160.65,61.77) 160.82,61.77 v2(161.14,61.45) 161.14,61 RZ65.1 ; v2(258.61,89.07) 255.86,89.07 255.48,89.44 UE1.M8
  IN2 w0.122: v2(161.14,61.45) 161.34,61.25 165.08,61.25 165.67,61.85 165.74,61.85 165.97,62.08 165.97,62.15 165.97,62.15 169.68,62.15 170.19,61.64 170.55,61.64 171.57,60.62 172.78,60.62 172.93,60.46 174.28,60.46 175.36,59.38 177.57,59.38 178.27,60.08 179.2,60.08 179.8,60.68 183.87,60.68 184.12,60.43 201.24,60.43 202.3,59.37 202.3,58.68 203.23,57.75 203.23,57.75 203.46,57.52 203.46,57.52 204.4,56.58 208.82,56.58 209.43,55.98 210.2,55.98 210.39,55.98 211.21,56.8 215.73,56.8 216.47,56.07 219.01,56.07 220.69,57.74 221.51,57.74 222.28,56.97 222.28,56.68 222.94,56.02 226.1,56.02 226.38,56.3 228.89,56.3 230.64,58.04 232.27,58.04 233.02,57.29 235.4,57.29 236.24,58.14 240.22,58.14 240.5,58.41 242.83,58.41 244.23,59.81 244.23,61.09 247.1,63.96 247.1,64.02 249.13,66.06 249.13,66.38 249.61,66.86 251.61,66.86 252.5,67.74 255.86,67.74 256.72,66.89 259.95,66.89 v2(260.65,67.58)
  BOTTOM w0.127: v2(260.65,67.58) 260.32,67.91 260.32,68.62 258.88,70.07 258.88,71 259.84,71.97 259.84,75.85 259.35,76.35 259.35,76.88 259.9,77.44 259.9,78.1 260.5,78.69 260.5,85.94 258.77,87.67 258.77,88.91 v2(258.61,89.07) 258.61,91.49 257.53,92.58 257.53,93.89 256.51,94.91 256.51,95.68 258.09,97.27 259.21,97.27 v2(259.77,97.83)
PCH_BATLOW#: length 13.2
  TOP w0.127: v2(124.79,93.47) 124.98,93.47 125.45,93.01 127.05,93.01 127.84,92.22 127.86,92.22 130.01,90.07 130.01,86.18 v1(130.64,85.55) 131.02,85.16 RC72.1
  BOTTOM w0.076: UC1.AU13 124.85,93.47 v2(124.79,93.47)
PCH_CL_CLK1: length 176.5
  TOP w0.127: v2(237.89,71.88) 237.11,71.88 236.89,72.1 v1(235.82,72.1) 234.15,72.1 233.66,72.58 233.3,72.58 233.17,72.71 233.17,73.32 233.04,73.45 232.77,73.45 232.64,73.32 232.64,72.71 232.51,72.58 232.23,72.58 232.11,72.71 232.11,73.32 231.98,73.45 231.7,73.45 231.57,73.32 231.57,72.71 231.44,72.58 230.69,72.58 229.83,73.44 228.77,73.44 228.31,72.98 228.31,72.29 225.92,69.9 219.35,69.9 v2(218.42,70.83)
  BOTTOM w0.127: UC1.G3 131.28,109.8 131.76,110.29 131.76,110.58 132.1,110.93 132.1,111.17 132.28,111.35 133.3,111.35 133.37,111.42 134.93,111.42 136,112.49 136,113.76 137.36,115.12 137.36,115.45 140.07,118.16 143.91,118.16 146.63,115.44 146.63,114.04 147.57,113.09 151.47,113.09 152.71,114.33 152.71,116.39 152.5,116.6 152.5,117.74 151.82,118.42 151.82,120.66 153.73,122.57 162.94,122.57 164.86,120.65 164.86,117.74 165.38,117.23 165.38,115.83 163.98,114.44 163.98,110.8 167.12,107.66 167.12,103.15 168.12,102.14 168.12,99.38 167.73,98.99 167.73,95.82 169.14,94.41 169.14,92.28 170.46,90.96 170.46,85.92 185.75,70.63 210.36,70.63 213.93,74.21 215.8,74.21 218.42,71.6 v2(218.42,70.83) ; JNGFF1.42 238.77,70.4 237.89,71.28 v2(237.89,71.88)
PCH_CL_DATA1: length 175.3
  TOP w0.127: v2(217.82,70.8) 217.82,70.63 219.1,69.35 226.09,69.35 227.7,70.96 228.99,70.96 230.01,71.98 232.56,71.98 v1(232.95,71.59) 233.96,71.59 234.09,71.46 234.09,71.24 234.21,71.11 234.49,71.11 234.62,71.24 234.62,71.46 234.75,71.59 235.03,71.59 235.15,71.46 235.15,71.24 235.28,71.11 235.56,71.11 235.69,71.24 235.69,71.34 235.81,71.46 236.13,71.46 236.22,71.37 236.22,71.24 236.35,71.11 237.91,71.11 238.57,71.76 v2(238.57,72)
  BOTTOM w0.127: v2(238.57,72) 238.57,71.46 239.13,70.9 JNGFF1.40 ; v2(217.82,70.8) 217.82,71.47 215.61,73.69 214.21,73.69 212.62,72.1 212.62,71.36 211.37,70.12 185.54,70.12 169.95,85.71 169.95,86.16 169.82,86.28 169.35,86.28 169.22,86.41 169.22,86.66 169.35,86.79 169.82,86.79 169.95,86.92 169.95,87.17 169.82,87.3 169.33,87.3 169.2,87.43 169.2,87.68 169.33,87.81 169.82,87.81 169.95,87.93 169.95,90.67 168.63,91.99 168.63,94.13 167.22,95.54 167.22,99.2 167.59,99.57 167.59,101.95 166.61,102.94 166.61,107.45 163.35,110.71 163.35,114.52 164.26,115.43 164.26,120.53 162.73,122.06 153.94,122.06 152.33,120.45 152.33,118.63 153.01,117.95 153.01,116.81 153.22,116.6 153.22,114.12 151.68,112.58 147.36,112.58 146.12,113.83 146.12,115.23 143.7,117.65 140.28,117.65 137.9,115.27 137.9,114.94 136.31,113.35 136.31,112.42 135.07,111.19 133.53,111.19 132.99,110.65 132.99,110.4 132.74,110.15 132.1,110.15 131.76,109.81 UC1.G2
PCH_CL_RST1#: length 175.6
  TOP w0.127: v2(239.1,71.56) 238.12,70.58 233.19,70.58 232.34,71.43 230.26,71.43 229.27,70.45 v1(227.91,70.45) 226.26,68.8 217.73,68.8 216.52,70.01 v2(216.52,70.82)
  BOTTOM w0.076: UC1.G1 132.8,109.8 133.4,110.4 133.4,110.73 133.6,110.93 135.1,110.93 136.57,112.41 136.57,112.89 136.84,113.16
  BOTTOM w0.127: v2(216.52,70.82) 216.52,72.05 215.42,73.15 214.84,73.15 213.12,71.44 213.12,71.15 211.58,69.61 185.33,69.61 172.43,82.51 171.05,82.51 167.15,86.4 167.15,86.81 167.27,86.94 168.57,86.94 168.69,87.06 168.69,87.32 168.57,87.44 167.27,87.44 167.15,87.57 167.15,87.82 167.27,87.95 167.9,87.95 168.03,88.08 168.03,88.33 167.9,88.46 167.27,88.46 167.15,88.59 167.15,90.4 168.04,91.29 168.04,94 166.71,95.33 166.71,99.41 167.09,99.78 167.09,101.74 166.1,102.73 166.1,106.86 162.84,110.12 162.84,114.73 163.64,115.54 163.64,120.3 162.41,121.53 154.55,121.53 152.84,119.81 152.84,118.84 153.52,118.16 153.52,117.02 153.73,116.81 153.73,113.91 151.89,112.08 147.15,112.08 145.61,113.62 145.61,115.02 143.49,117.14 140.49,117.14 138.44,115.1 138.44,114.76 136.84,113.16 ; v2(239.1,71.56) 239.26,71.4 JNGFF1.38
PCH_DPWROK: length 198.7
  TOP w0.127: v2(123.07,81.18) 123.13,81.18 123.52,80.78 123.78,80.78 124.57,80 125.27,80 125.79,80.52 RC215.1 125.8,80.5 CC266.1 RC220.1 ; RE536.1 245.03,97.14 244.36,97.81 244.36,98.56 v2(243.85,99.08) v3(243.85,99.68)
  IN1 w0.084: v2(123.07,81.18) 123.07,81.65 125.46,84.04 131.51,84.04 v2(132.23,83.32)
  IN2 w0.122: v2(132.23,83.32) 133.75,84.85 134.4,84.85 134.56,85 134.56,85 136.62,87.06 142.69,87.06 143.45,87.06 143.69,87.3 145.54,87.3 146.86,85.98 146.86,82.67 149.37,80.16 149.37,73.14 151.26,71.26 158.68,71.26 159.93,70 172.12,70 174.04,68.08 174.04,68.08 174.08,68.04 178.3,68.04 180.28,66.07 184.18,66.07 185.9,64.35 203.57,64.35 205.47,62.44 215.04,62.44 215.54,61.94 216.77,61.94 217.51,62.68 225.8,62.68 226.42,63.3 229.72,63.3 230.53,64.12 235.06,64.12 236.32,65.37 241.21,65.37 241.28,65.31 242.46,65.31 243.51,66.36 243.51,67.14 v2(244.41,68.03)
  BOTTOM w0.076: 123.59,87.26 122.22,88.63 122.22,89.37 121.56,90.03 121.56,90.57 UC1.BB20
  BOTTOM w0.127: v2(243.85,99.08) 243.85,97.27 243.42,96.84 243.42,90.18 241.95,88.7 241.95,87.61 242.42,87.14 242.42,85.77 242.65,85.54 243.05,85.54 243.25,85.34 243.25,82 245.49,79.76 245.49,79.14 246.1,78.52 246.1,78.01 245.5,77.4 245.5,76.09 246.71,74.88 246.71,74.08 245.91,73.28 245.91,71.32 244.43,69.84 244.43,68.06 v2(244.41,68.03) ; 123.59,87.26 123.59,83.2 123.07,82.68 v2(123.07,81.18)
PCH_DPWROK_EC: length 12.1
  TOP w0.127: RE536.2 245.07,95.39 v2(245.07,95.39) 245.4,95.06 v1(245.48,95.06) ; UE1.F8 v2(250.28,89.86)
  BOTTOM w0.127: v2(245.07,95.39) 245.62,95.93 247.97,95.93 249.88,94.02 249.88,90.26 v2(250.28,89.86)
PCH_JTAG_TCK: length 62.5
  TOP w0.127: v2(77.17,112.95) 78.07,113.85 78.07,117.7 78.89,118.53 78.89,122.74 83.28,127.13 85.02,127.13 85.88,127.99 85.88,129.49 v3(86.3,129.91) 86.3,130.51 v2(86.41,130.62) ; RC86.1 99.97,120.39 99.97,118.25 99.15,117.42 v2(98.71,117.42)
  IN4 w0.084: v2(98.71,117.42) 98.49,117.42 97.04,118.87 91.48,118.87 90.28,117.66 89.64,117.66 88.01,116.04 86.08,116.04 85.27,115.23 85.27,112.28 83.49,110.5 80.35,110.5 79.99,110.14 79.27,110.14 78.07,111.35 78.07,112.05 v2(77.17,112.95)
  BOTTOM w0.076: UC1.B56 100.3,112.87 100.3,113.09 100.24,113.21 100.24,113.47 100.42,113.65 100.42,114.53 100.28,114.68 100.28,115.53 99.91,115.9 99.91,116.22 v2(98.71,117.42)
  BOTTOM w0.127: JXDP1.55 87.31,130.02 86.71,130.62 v2(86.41,130.62)
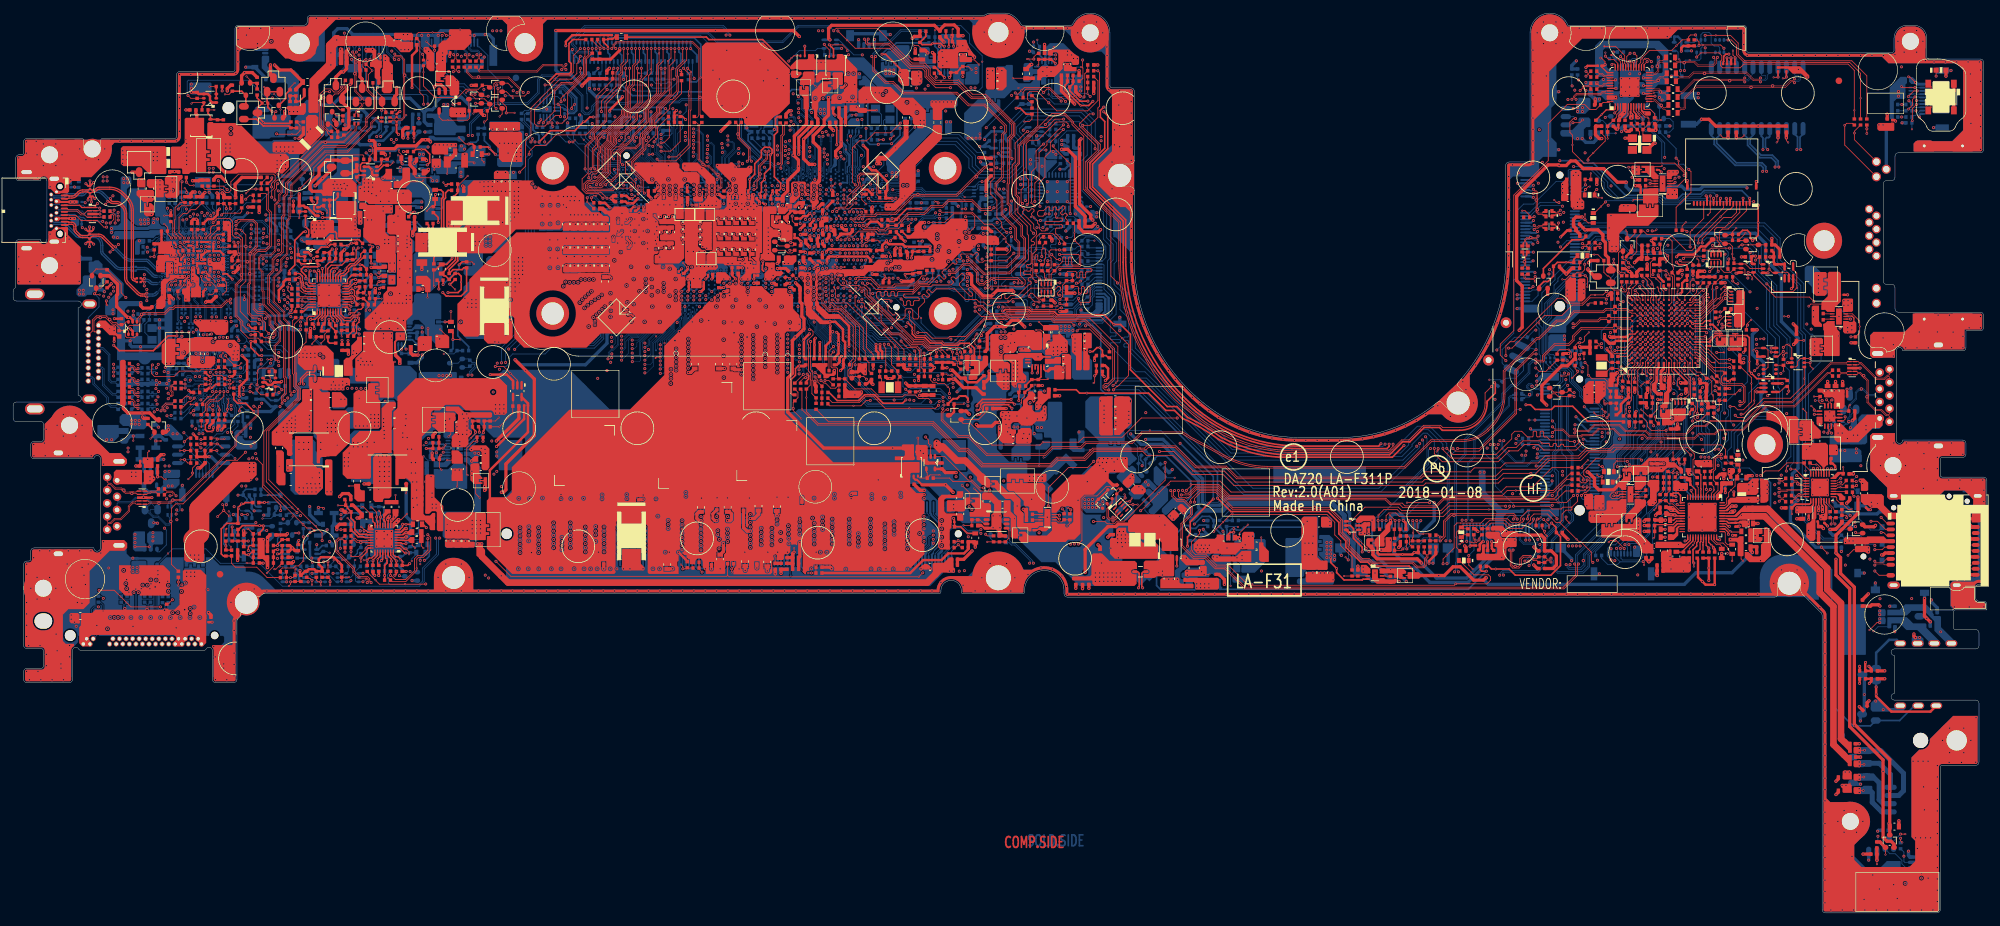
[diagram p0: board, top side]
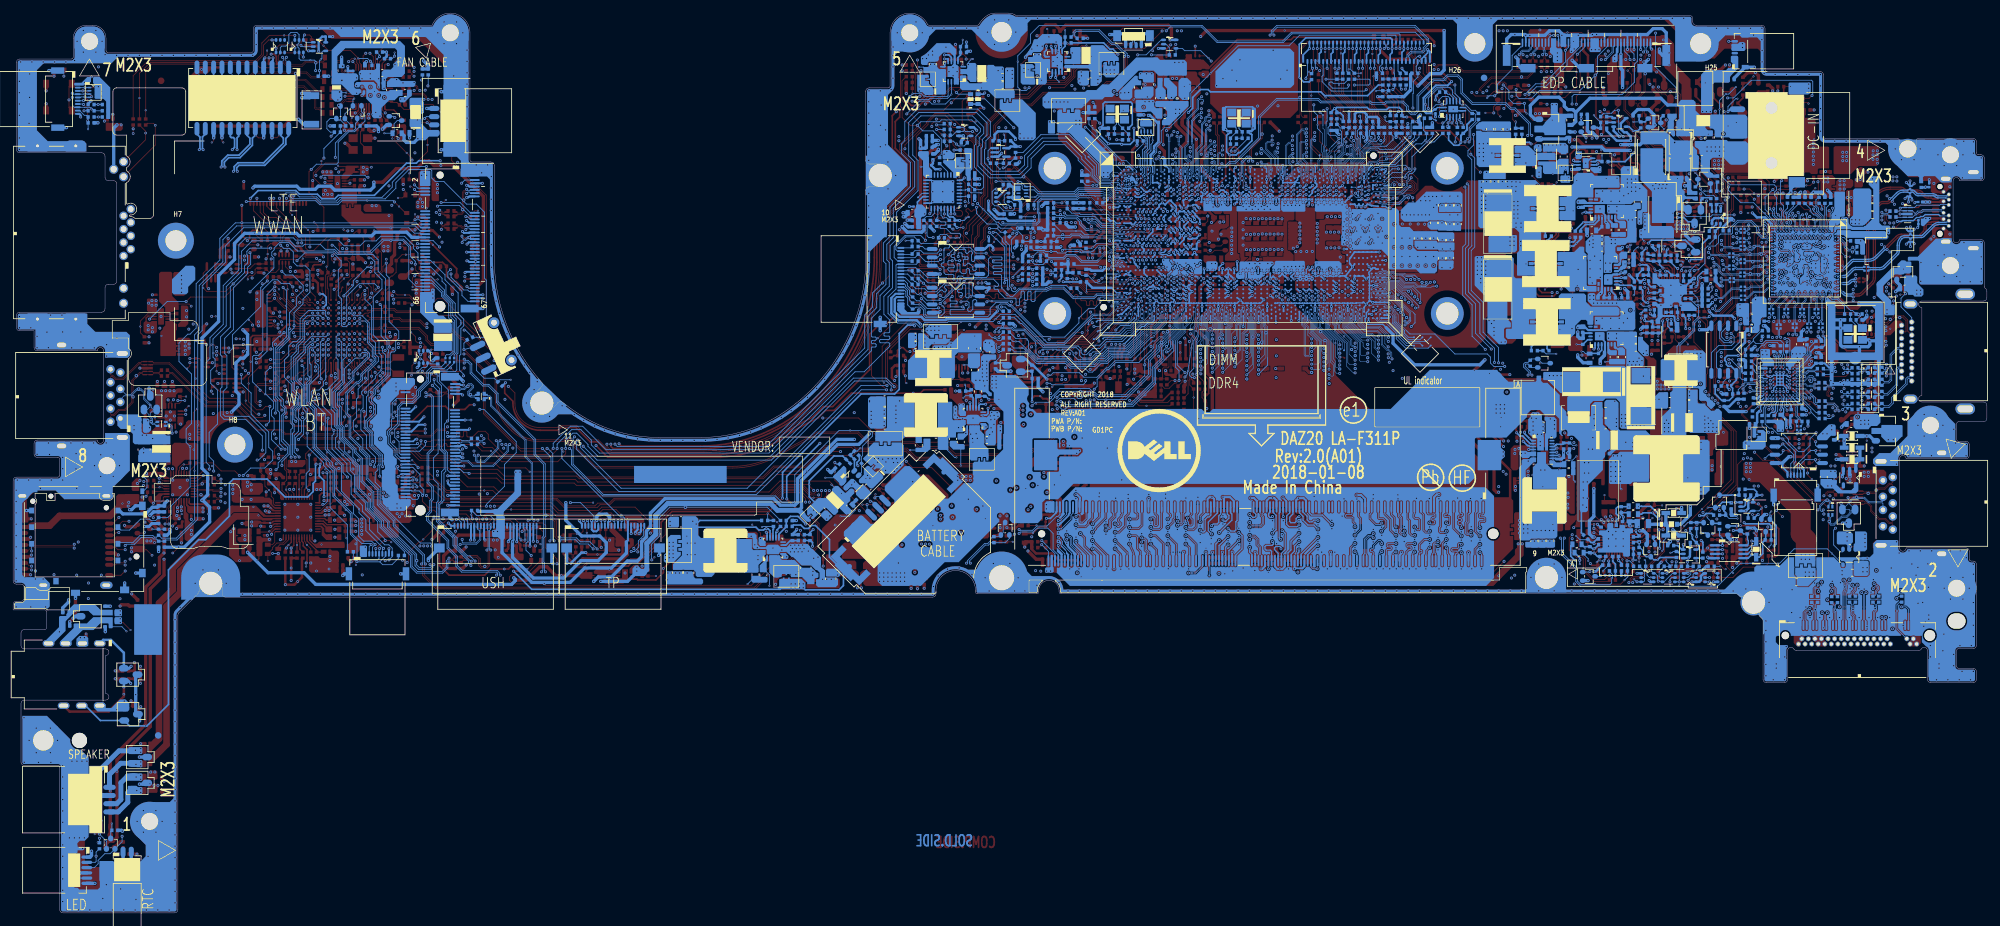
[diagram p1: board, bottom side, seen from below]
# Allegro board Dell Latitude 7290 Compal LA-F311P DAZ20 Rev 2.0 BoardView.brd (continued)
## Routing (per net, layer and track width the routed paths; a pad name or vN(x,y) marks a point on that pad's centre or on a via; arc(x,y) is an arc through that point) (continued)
PCH_JTAG_TDI: length 31.3
  TOP w0.127: v2(98.71,116.79) 98.57,116.79 v3(98.25,117.11)
  IN1 w0.084: v2(98.71,116.79) 98.03,116.1 95.59,116.1 95.05,116.65 84.99,116.65 84.55,117.1 81.44,117.1 v2(80.99,117.55)
  BOTTOM w0.076: v2(98.71,116.79) 99.43,116.07 99.43,113.7 99.59,113.54 99.59,113.18 99.55,113.08 99.55,112.89 99.59,112.8 99.59,112.55 99.57,112.51 99.53,112.35 99.45,112.07 99.45,111.96 99.37,111.69 UC1.D59
  BOTTOM w0.127: v2(80.99,117.55) 80.99,118.25 80.67,118.57 RC229.2 ; RC81.1 CC304.1 98.54,119.75 98.54,119.36 98.31,119.13 98.31,117.18 v2(98.71,116.79)
PCH_JTAG_TDO: length 28.5
  TOP w0.127: v2(84.73,117.55) v3(85.29,117.55)
  IN1 w0.084: v2(84.73,117.55) 85.39,116.9 95.15,116.9 95.69,116.35 97.7,116.35 98.31,116.95 98.31,117.65 v2(98.71,118.06)
  BOTTOM w0.076: 99.85,116.83 100.16,116.53 100.16,116.03 100.44,115.75 100.44,114.75 100.61,114.58 100.61,113.41 UC1.A56
  BOTTOM w0.127: v2(84.73,117.55) 84.21,117.55 RC230.2 ; 99.85,116.83 98.71,117.98 v2(98.71,118.06) 99.22,118.57 100.1,118.57 100.37,118.84 100.37,119.77 CC303.1 RC82.1
PCH_JTAG_TMS: length 39.5
  TOP w0.127: RC130.1 101.62,117.61 100.16,116.15 v2(98.71,116.15) ; v2(78.89,117.55) 79.11,117.78 v3(79.11,118.06)
  IN1 w0.084: v2(98.71,116.15) 98.71,114.07 97.99,113.35 92.38,113.35 89.57,116.16 84.79,116.16 84.3,116.65 79.79,116.65 v2(78.89,117.55)
  BOTTOM w0.076: v2(98.71,116.15) 99.25,115.61 99.25,113.64 99.42,113.47 99.42,113.21 99.36,113.09 99.36,112.94 99.42,112.75 99.42,112.58 99.34,112.32 UC1.C59
  BOTTOM w0.127: v2(78.89,117.55) 78.89,117.61 78.63,117.87 78.63,119.57 77.46,120.74 RC228.2
PCH_PCIE_WAKE#: length 188.6
  TOP w0.127: v2(259.29,79.64) 259.85,79.08 RE274.2 ; RC67.1 136.4,79.44 v2(135.99,79.84) ; UE1.L1 254.68,83.3 v2(254.63,83.25)
  IN1 w0.084: v2(254.63,83.25) 254.74,83.25 255.45,82.54 255.45,80.58 256.39,79.64 v2(259.29,79.64)
  IN2 w0.122: v2(135.99,79.84) 136.47,80.33 136.47,81.39 136.12,81.75 136.12,83.27 136.83,83.98 140.77,83.98 142.45,82.3 142.45,79.94 144.25,78.15 144.25,76.27 145.44,75.07 145.44,73.74 150.8,68.38 157.61,68.38 160.84,65.15 165.38,65.15 165.54,64.99 170.62,64.99 172.72,62.89 178.32,62.89 178.81,63.38 181.24,63.38 182.12,62.5 184.26,62.5 184.77,62 202.11,62 205.13,58.97 207.83,58.97 208.27,58.53 216.12,58.53 216.98,59.38 233.79,59.38 234.16,59 235.21,59 235.69,59.48 239.67,59.48 239.94,59.75 242.27,59.75 242.89,60.37 242.89,61.64 244.89,63.65 244.89,64.57 247.51,67.18 247.51,67.56 248.73,68.79 250.25,68.79 251.28,69.81 255.01,69.81 255.43,69.39 256.23,69.39 257.29,68.33 258.43,68.33 258.72,68.62 258.72,69.1 v2(258.34,69.48)
  BOTTOM w0.076: UC1.BB15 123.79,90.6 123.79,89.41 125.46,87.73 125.86,87.73 126.92,86.66
  BOTTOM w0.127: v2(135.99,79.84) 135.56,80.27 135.56,81.34 134.09,82.81 133.82,82.81 132.7,83.93 129.18,83.93 v1(127.38,85.74) 126.92,86.19 126.92,86.66 ; v2(258.34,69.48) 258.39,69.53 258.39,73.67 258.11,73.95 258.11,74.36 258.38,74.62 258.38,76.96 257.64,77.7 257.64,78.18 259.1,79.64 v2(259.29,79.64)
PCH_PLTRST#: length 62.2
  TOP w0.127: v2(148.11,95.26) 148.64,95.26 148.96,95.58 v1(151.18,95.58) 152.6,95.58 152.7,95.48 153.77,95.48 154.18,95.89 154.18,96.47 153.47,97.19 153.47,98.47 154.67,99.68 154.67,103.34 154.49,103.52 154.49,104.73 152.64,106.59 152.64,108.83 152.21,109.25 152.21,114.06 152.66,114.52 152.66,117.38 154.42,119.14 v2(154.54,119.14)
  IN4 w0.084: v2(148.11,95.26) 147.01,95.26 146.53,94.78 144.71,94.78 144.61,94.88 134.01,94.88 131.86,94.88 130.28,96.45 129.13,96.45 128.87,96.2 128.87,95.87 128.67,95.67 127.89,95.67 v2(127.48,96.07)
  BOTTOM w0.102: UC1.AN10 127.34,96.07 v2(127.48,96.07)
  BOTTOM w0.127: 155.79,119.32 155.61,119.14 v2(154.54,119.14) ; 155.79,119.32 155.98,119.14 UC7.2 157.02,119.14 157.59,118.57 RC60.1 RC62.1 RC244.1 ; 155.79,119.32 155.79,119.68 155.91,119.79 UC7.1
PCH_PLTRST#_5105: length 25.5
  TOP w0.127: UE1.K1 253.88,83.34 254.56,82.66 v2(254.63,82.66) ; v1(270.27,79.11) 270.51,79.35 v2(270.51,79.56) 270.51,80.03 RE340.1 269.98,80.26 269.15,79.43 UE6.4
  IN1 w0.084: v2(270.51,79.56) 269.2,78.26 266.1,78.26 264.09,80.27 262.66,80.27 261.88,79.49 259.94,79.49 259.51,79.07 256.18,79.07 255.01,80.24 255.01,82.28 v2(254.63,82.66)
PCH_PLTRST#_AND: length 611.2
  TOP w0.127: 235.65,59.51 235.98,59.84 235.98,60.8 236.58,61.41 237.36,61.41 237.48,61.52 237.48,61.85 237.46,61.87 ; 235.65,59.51 235.65,59.51 v1(238.21,56.95) 238.57,56.59 238.84,56.59 240.43,55 240.43,53.67 v2(240.67,53.44) ; 235.65,59.51 235.08,59.51 233.76,60.82 231.69,60.82 231.18,60.32 231.18,59.91 229.89,58.62 227.91,58.62 227.09,59.44 225.18,59.44 224.67,58.93 CZ61.1 RZ114.1 ; v2(13.11,49.19) 15.41,49.19 17.94,46.66 v2(22.46,46.66) ; 237.46,61.87 238.33,62.73 v2(238.33,63.65) ; 237.46,61.87 236.14,61.87 235.87,61.59 234.44,61.59 234.03,62.01 v2(228.59,62.01) ; v2(157,117.23) 156.9,117.23 155.84,116.18 155.84,113.67 155.14,112.97 155.14,108.25 v2(155.59,107.8) ; v2(270.81,67.66) 271.51,67.66 272.91,66.27 UR1.1
  IN1 w0.084: v2(229.6,76.78) 229.6,79.43 v2(232.08,81.9) ; v2(13.11,49.19) 12.86,49.19 11.86,48.19 11.86,45.16 14.14,42.87 15.94,42.87 16.7,42.11 JNGFF3.50 ; v2(240.67,53.44) 237.93,50.7 226.18,50.7 225.36,51.53 224.08,51.53 223.49,50.93 217.92,50.93 217.63,51.22 210.76,51.22 209.4,49.86 187.21,49.86 185.75,51.32 184.47,51.32 182.24,53.55 180.43,53.55 179.19,54.79 167.43,54.79 164.81,57.41 158.27,57.41 156.79,58.89 151.2,58.89 150.61,58.29 149.06,58.29 148.02,59.33 146.88,59.33 145.93,58.38 145.93,57 144.52,55.59 141.96,55.59 140.61,54.24 129.59,54.24 126.29,50.94 74.17,50.94 72.11,52.99 70.26,52.99 68.52,54.73 65.6,54.73 60.76,49.9 41.25,49.9 40.48,50.66 33.92,50.66 30.28,47.02 22.83,47.02 v2(22.46,46.66) ; v2(228.59,62.01) 227.49,63.11 184.28,63.11 173.73,73.66 173.73,75.84 166.69,82.89 166.69,85.58 164.66,87.61 164.66,90.25 163.41,91.5 163.41,100.06 161.01,102.46 161.01,103.18 160.67,103.52 160.28,103.52 158.81,104.99 157.7,104.99 156.58,106.11 156.58,106.12 156.2,106.49 156.2,106.79 155.59,107.4 v2(155.59,107.8)
  IN4 w0.084: v2(13.11,49.19) 13.11,49.6 18.06,54.55 19.63,54.55 20.2,55.12 20.2,63.57 23.38,66.75 23.95,66.75 24.76,67.56 24.76,70.71 21.51,73.96 21.51,74.42 20.14,75.79 20.14,78.75 19.76,79.14 19.76,85.06 18.26,86.56 18.26,90.52 19.2,91.46 21.74,91.46 24.39,94.11 24.73,94.11 25.94,95.32 27.7,95.32 28.19,95.82 28.19,97.37 28.81,97.99 28.81,98.79 29.13,99.11 29.13,99.86 28.33,100.67 27.61,100.67 26.74,101.54 v2(26.74,102.9)
  BOTTOM w0.127: JNGFF1.66 240.05,64.4 239.99,64.34 238.83,64.34 238.33,63.83 v2(238.33,63.65) 238.12,63.86 238.12,64.56 238.71,65.15 238.71,66.84 239.77,67.9 JNGFF1.52 ; v2(270.81,67.66) 270.81,68.22 271.29,68.69 271.29,83.96 270.71,84.53 270.71,87.71 268.69,89.72 268.69,95.64 266.32,98.02 266.32,101.85 265.24,102.93 258.01,102.93 257.66,102.59 251.15,102.59 250.29,101.73 247.83,101.73 247.1,102.46 245.4,102.46 244.69,103.17 241.07,103.17 239.71,101.82 239.71,101.31 239.02,100.62 239.02,99.63 238.9,99.5 JNGFF2.42 237.11,99.5 234.9,97.3 234.9,96.54 232.91,94.54 232.91,91.4 232.05,90.54 232.05,89.51 232.49,89.07 232.49,85.18 232.68,84.99 232.68,82.74 232.08,82.14 v2(232.08,81.9) ; v2(229.6,76.78) 228.96,76.78 224.05,71.87 224.05,70.18 225.85,68.39 225.85,65.04 228.59,62.29 v2(228.59,62.01) ; RC325.1 157.44,117.68 v2(157,117.23) 156.72,116.95 155.8,116.95 RC65.1 155.33,118.38 155.22,118.49 UC7.4 ; UT1.L4 v2(26.74,102.9)
PCH_PLTRST#_EC: length 183.7
  TOP w0.127: UE6.2 265.74,80.08 265.26,79.6 v1(265.26,78.12) 265.26,77.67 263.63,76.04 v2(263.26,76.04) ; v2(160.02,120.16) 157.5,117.65 157.5,117.1 156.3,115.9 156.3,111.92 155.66,111.28 v2(155.66,108.46)
  IN1 w0.084: v2(263.26,76.04) 262.47,75.25 261.68,75.25 260.7,74.27 259.44,74.27 258.77,73.61 256.35,73.61 v2(255.9,73.16) 255.19,72.45 250.84,72.45 249.69,71.29 246.58,71.29 244.33,69.05 235.53,69.05 229.87,63.38 228.62,63.38 228.47,63.54 184.41,63.54 174.12,73.82 174.12,76 167.08,83.05 167.08,85.74 165.05,87.77 165.05,90.41 163.8,91.66 163.8,101.34 159.75,105.38 157.86,105.38 156.59,106.65 156.59,106.95 156.02,107.53 156.02,108.1 v2(155.66,108.46)
  BOTTOM w0.127: v2(255.9,73.16) 255.9,71.13 253.43,68.66 253.43,68.26 252.41,67.24 252.41,61.81 249.78,59.18 RE375.2 ; v2(160.02,120.16) 159.03,120.16 RC244.2
PCH_POPIRCOMP: length 11.1
  TOP w0.381: RC89.1 125.12,84.66 125.75,85.29 v1(125.75,86.57) 125.75,88.25 v2(125.47,88.53)
  IN2 w0.381: v2(125.47,88.53) 125.47,90.59 123.21,92.85 123.21,93.33 v2(122.89,93.66)
  BOTTOM w0.254: UC1.AU16 v2(122.89,93.66)
PCH_PRIM_EN: length 151.5
  TOP w0.127: v2(164.59,59.68) 166.34,59.68 166.68,59.34 167.79,59.34 168.18,59.73 169.28,59.73 175.52,65.98 v1(175.52,67.29) v2(175.52,68.69) ; RC442.2 RC441.2 154.9,123.68 154.54,124.04 154.54,124.92 154.89,125.28 156.03,125.28 v2(157.78,123.53) 159.01,122.3 163.7,122.3 165.28,123.87 165.28,126.87 PR406.1 ; v2(162.1,88.75) 162.36,89.02 164.01,89.02 167.02,86 PR312.1 ; v2(147.85,64.81) 147.24,64.81 146.04,66.01 145.51,66.01 141.91,69.6 UZ34.1 ; v2(160.74,119.91) 160.74,120.3 160.44,120.6 158.91,120.6 156.12,117.81 154.83,117.81 154.35,117.33 154.35,112.16 154.71,111.81 154.71,108.23 v2(154.47,108) ; v2(159.84,61.61) 160.11,61.34 RZ64.1
  IN1 w0.084: v2(157.78,123.53) 158.13,123.53 160.74,120.92 v2(160.74,119.91) ; v2(164.59,59.68) 161.77,59.68 v2(159.84,61.61) ; v2(154.47,108) 154.47,107.13 155,106.6 155,101.66 155.43,101.23 155.43,95.52 156.73,94.23 156.73,91.46 v2(154.96,89.69)
  IN2 w0.122: v2(147.85,64.81) 149.14,63.52 158.53,63.52 159.84,62.2 v2(159.84,61.61)
  IN4 w0.084: v2(175.52,68.69) 174.92,68.69 173.95,69.66 173.95,75.67 167.35,82.28 167.35,85.39 163.63,89.11 162.81,89.11 162.45,88.75 v2(162.1,88.75) 162.1,89.34 162,89.44 162,89.83 161.84,89.99 155.26,89.99 v2(154.96,89.69)
  BOTTOM w0.127: v2(175.52,68.69) 175.27,68.44 PR504.1
PCH_PWROK: length 163.6
  TOP w0.127: RC411.1 122.24,82.38 v2(122.16,82.38) ; v2(45.87,58.3) 45.49,58.68 44.73,58.68 v3(44.17,59.24) 38.2,65.22 38.2,73.41 43.29,78.51 43.29,79.69 42.74,80.25 42.74,82.06 42.58,82.22 42.58,90.31 PR614.1
  IN1 w0.084: v2(73.76,83.82) 74.3,84.36 75.71,84.36 76.51,83.56 80.67,83.56 85.89,78.35 116.8,78.35 117.82,79.38 119.86,79.38 121.36,80.87 121.36,81.58 v2(122.16,82.38)
  IN4 w0.084: v2(45.87,58.3) 46.32,57.86 50.15,57.86 53.21,54.8 58.71,54.8 59.19,54.32 60.48,54.32 62.36,56.2 69.95,56.2 70.53,55.61 73.23,55.61 73.63,56.02 73.63,65.37 74.08,65.81 74.08,74.35 72.79,75.63 72.79,78.12 74.7,80.02 74.7,82.88 v2(73.76,83.82)
  BOTTOM w0.076: 123.34,87.13 123.34,87.26 122.04,88.56 122.04,89.32 121.39,89.97 121.39,90.31 121.18,90.51 121.18,91.07 UC1.BA20
  BOTTOM w0.127: 123.34,87.13 123.34,83.56 v2(122.16,82.38)
PCH_RSMRST#: length 82.7
  TOP w0.127: v2(237.74,63.65) 236.66,62.57 v1(235.35,62.57) 218.76,62.57 217.53,61.34 211.55,61.34 211.02,61.87 205.95,61.87 203.8,59.72 UZ6.1 ; RE342.1 261.9,84.37 v2(261.49,84.37) 259.86,84.37 258.26,85.97 257.83,85.97 257.13,86.67 255.87,86.67 UE1.M5
  IN1 w0.084: v2(244.75,72.27) 245.08,72.27 246.58,73.77 248.76,73.77 249.74,74.75 252.73,74.75 253.16,75.18 253.16,75.74 253.08,75.82 253.08,76.96 253.44,77.32 253.44,78.64 253.01,79.07 v2(253.01,79.18)
  IN4 w0.084: v2(261.49,84.37) 261.42,84.3 261.42,84.11 259.47,82.15 258.33,82.15 256.31,80.14 253.96,80.14 v2(253.01,79.18) ; v2(237.74,63.65) 238.15,63.24 239.89,63.24 243.05,66.41 243.05,68.51 244.75,70.21 v2(244.75,72.27)
PCH_RSMRST#_AND: length 114
  TOP w0.127: RC215.2 RC75.1 128.24,79.9 130.77,79.9 131.97,78.7 135.48,78.7 135.76,78.98 137.41,78.98 137.97,78.43 139.46,78.43 139.81,78.08 v2(139.81,77.89) ; RC215.2 RC124.1 ; RC215.2 125.6,81.65 125.6,82.99 125.47,83.11 124.77,83.11 124.61,83.27 124.61,85.16 v2(124.99,85.55) ; v2(206.14,55.57) 206.14,55.74 v1(204.87,57.01) 204.54,57.34 204.54,58.23 204.73,58.42 UZ6.4
  IN2 w0.122: v2(139.81,77.89) 139.81,76.61 143.1,73.32 143.1,72.82 148.74,67.18 148.74,66.07 150.47,64.34 159.15,64.34 160.73,62.76 160.73,61.22 160.98,60.97 165.18,60.97 165.83,61.63 165.84,61.63 166.14,61.93 169.59,61.93 170.1,61.41 170.46,61.41 171.48,60.4 172.68,60.4 172.84,60.24 174.18,60.24 175.27,59.15 177.66,59.15 178.36,59.85 179.29,59.85 179.89,60.46 183.78,60.46 184.02,60.21 201.15,60.21 202.08,59.28 202.08,58.58 203,57.66 203,57.65 203.36,57.29 203.37,57.29 204.76,55.9 205.81,55.9 v2(206.14,55.57)
  BOTTOM w0.076: 124.1,87.19 124.1,87.31 122.6,88.81 122.6,90.34 122.41,90.53 122.41,90.79 122.46,90.91 122.46,91.05 122.4,91.28 122.4,91.4 122.47,91.61 122.57,91.72 122.67,91.83 UC1.AY17
  BOTTOM w0.127: v2(124.99,85.55) 124.67,85.55 124.1,86.12 124.1,87.19
PCH_RTCRST#: length 221
  TOP w0.076: v2(123.86,96.7) 123.86,96.69 123.37,96.2 123.37,95.39 123.45,95.31 123.45,93.39 123.37,93.31 123.37,92.94 123.52,92.79
  TOP w0.127: v2(246.49,99.87) 246.49,99.94 247.36,100.8 247.36,102.93 247.99,103.57 RE94.2 248.38,103.97 248.89,103.46 250.51,103.46 250.54,103.44 252.47,103.44 254.89,101.01 255.77,101.01 256.14,101.39 256.14,103.09 260.56,107.51 JAPS1.9 ; RC57.1 128.9,80.68 CC25.1 ; CC25.1 129.58,81.8 v2(130,81.38) ; CC25.1 128.06,81.8 CMOS1.1 127.57,81.53 127.2,81.89 127.2,82.74 127.49,83.03 127.66,83.03 127.9,83.27 127.9,83.82 128.36,84.28 v1(128.36,86.03) 128.36,89.61 126.01,91.96 125.78,91.96 125.76,91.97 124.34,91.97 123.52,92.79
  IN2 w0.122: v2(245.68,68.01) 245.65,68.01 244.36,66.73 244.36,66.1 242.83,64.57 240.74,64.57 240.24,64.07 236.27,64.07 234.96,62.75 230.2,62.75 230.02,62.58 226.72,62.58 226.1,61.96 217.81,61.96 217.07,61.22 215.24,61.22 214.74,61.72 205.17,61.72 203.26,63.62 185.49,63.62 183.77,65.34 179.97,65.34 179.17,66.14 174.14,66.14 172.57,67.71 169.46,67.71 168.48,66.72 166.41,66.72 166.05,67.08 161.83,67.08 158.46,70.45 151.02,70.45 148.65,72.83 148.65,79.86 145.73,82.77 145.73,85.48 144.74,86.47 143.89,86.47 143.63,86.2 136.86,86.2 132.04,81.38 131.9,81.38 131.9,81.38 v2(130,81.38)
  BOTTOM w0.102: UC1.AM16 123.5,97.05 v2(123.86,96.7)
  BOTTOM w0.127: v2(245.68,68.01) 245.68,68.42 245.49,68.61 245.49,69.49 246.88,70.88 246.88,72.85 247.72,73.69 247.72,76.63 247.38,76.97 247.38,78.89 247.6,79.11 247.6,79.46 245.51,81.54 245.51,81.84 244.55,82.8 244.55,84.94 244.96,85.35 244.96,87.27 245.83,88.14 245.83,93.86 244.51,95.18 244.51,96.54 245.6,97.63 245.6,99.31 246.16,99.87 v2(246.49,99.87)
PCH_RTCX1: length 25.3
  TOP w0.127: YC2.1 134.81,81.45 CC23.1 134.78,82.05 RC54.2 133.83,83.58 v1(133.83,84.54) 133.83,86.22 v2(133.35,86.7)
  IN1 w0.084: v2(121.99,96.64) 122.43,96.2 122.43,93.31 124.03,91.7 125.45,91.7 129.41,87.74 132.52,87.74 133.35,86.91 v2(133.35,86.7)
  BOTTOM w0.102: v2(121.99,96.64) 122.4,97.05 UC1.AM18
PCH_RTCX2: length 23.2
  TOP w0.127: v2(132.71,86.7) 132.71,86.32 132.94,86.09 v1(132.94,83.58) RC296.1 RC54.1
  IN1 w0.084: v2(132.71,86.7) 132.2,87.22 129.06,87.22 124.98,91.3 123.59,91.3 121.54,93.35 121.54,96.29 121.07,96.75 v2(121.07,96.76)
  BOTTOM w0.102: UC1.AM20 121.37,97.05 v2(121.07,96.76)
PCH_RTCX2_R: length 2.6
  TOP w0.127: RC296.2 CC26.1 132.31,81.45 YC2.2
PCH_SMB_ALERT#: length 6
  TOP w0.127: RC23.1 132.23,105.79 v1(130.43,105.79) 130.1,105.79 129.6,105.29 128.21,105.29 v2(127.66,105.85)
  BOTTOM w0.102: UC1.R10 127.14,105.33 v2(127.66,105.85)
PCH_SPI_CLK: length 48
  TOP w0.127: v2(133.29,92.55) 133.29,91.91 134.03,91.17 134.21,91.17 134.48,91.44 134.66,91.44 134.84,91.26 134.84,91.08 134.57,90.81 134.57,90.63 134.75,90.46 135.41,90.46 135.9,90.94 135.9,91.9 136.12,92.12 136.79,92.12 137.06,91.85 137.06,90.76 137.26,90.57 137.76,90.57 137.92,90.73 137.92,92.21 138.87,93.16 138.87,93.54 138.48,93.93 138.48,94.11 138.65,94.29 138.83,94.29 139.23,93.9 139.41,93.9 139.59,94.08 139.59,94.26 139.19,94.65 139.19,94.83 139.37,95.01 139.55,95.01 139.95,94.62 140.11,94.62 140.65,95.16 143.43,95.16 145.06,93.53 146.79,93.53 147.18,93.14 147.87,93.14 148.41,92.6 v1(148.84,92.6) 149.13,92.6 149.63,93.1 151.66,93.1 152.22,93.66 153.45,93.66 155.05,95.26 158.18,95.26 159,96.07 v2(159.47,96.07)
  BOTTOM w0.076: v2(133.29,92.55) 133.05,92.55 132.69,92.91 132.25,92.91 131.95,93.2 UC1.AV2
  BOTTOM w0.127: JSPI1.8 163.76,97.91 RC35.1 163.74,97.66 163.37,97.29 162.53,97.29 161.31,96.07 v2(159.47,96.07)
PCH_SPI_CLK_0_R: length 12.7
  TOP w0.127: v2(156.3,93.17) 155.62,93.17 v3(154.79,94) 154.79,94.26 155.01,94.48 155.28,94.48 156.17,93.6 156.51,93.6 156.66,93.45 RC29.1 157.14,93.63 RPC1.6
  BOTTOM w0.127: v2(156.3,93.17) 156.19,93.27 155.29,93.27 155.07,93.06 155.07,92.38 155.27,92.18 155.27,91.89 155.1,91.72 154.83,91.72 154.5,92.05 154.5,93.33 154.32,93.51 154.04,93.51 153.89,93.36 153.89,92.9 153.78,92.78 UC5.6
PCH_SPI_CLK_1_R: length 13.8
  TOP w0.127: 156.88,101.31 156.88,101.81 RC28.1 ; 156.88,101.31 156.71,101.14 v2(156.71,100.09) ; 156.88,101.31 157.14,101.31 157.3,101.15 v1(157.3,100.6) 157.3,99.86 157.1,99.66 157.1,98.94 156.99,98.83 RC408.2
  BOTTOM w0.127: v2(156.71,100.09) 156.71,100.55 156.62,100.64 156.23,100.64 156.13,100.55 156.13,100.15 156.02,100.05 155.32,100.05 155.21,99.94 155.21,99.73 155.32,99.62 155.86,99.62 155.93,99.55 155.93,98.78 155.84,98.69 155.63,98.69 155.25,99.07 155.04,99.07 154.49,98.52 154.49,98.1 154.37,97.98 154.1,97.98 153.99,98.09 153.99,98.6 153.89,98.69 UC6.6
PCH_SPI_CLK_2_R: length 12.8
  BOTTOM w0.127: RZ60.2 159.72,103.16 159.42,103.46 158.48,103.46 157.95,102.93 v1(157.12,102.93) 156.53,102.93 156.35,103.11 156.35,103.42 156.56,103.63 157.82,103.63 158.53,104.34 159.34,104.34 159.47,104.47 159.47,104.72 159.34,104.85 158.72,104.85 158.6,104.98 158.6,105.23 158.72,105.36 159.34,105.36 159.59,105.6 RZ63.2 159.99,105.95 159.83,106.12 UZ12.19
PCH_SPI_CLK_R1: length 20.8
  TOP w0.127: RPC1.3 157.14,96.42 v2(157.38,96.66) 157.13,96.91 157.13,97.53 RC408.1
  BOTTOM w0.127: JSPI1.7 164.53,98.41 164.5,98.44 163.22,98.44 162.83,98.04 RC35.2 162.44,97.93 161.36,96.85 158.52,96.85 158.33,96.66 v2(157.38,96.66) 157.38,97.2 157.52,97.34 158.62,97.34 158.88,97.61 158.88,98.45 159.01,98.58 159.17,98.58 159.3,98.71 159.3,98.96 159.17,99.09 159.01,99.09 158.88,99.22 158.88,101.26 158.76,101.38 158.19,101.38 158.05,101.53 158.05,101.78 158.16,101.89 158.76,101.89 158.88,102.02 158.88,102.86 RZ60.1
PCH_SPI_CS#0: length 53.7
  BOTTOM w0.076: UC1.AU3 131.42,94.2 131.99,94.2 132.07,94.28 132.28,94.33 133.03,94.33 133.08,94.37
  BOTTOM w0.127: JSPI1.10 164.82,96.91 RC36.1 163.74,95.76 163.16,95.17 161.81,95.17 161.34,94.71 160.05,94.71 158.68,96.08 157.13,96.08 156.87,96.34 156.87,96.91 156.68,97.1 156.11,97.1 155.9,96.9 152.44,96.9 152.09,97.25 152.09,99.73 151.79,100.02 150.15,100.02 150.04,99.91 150.04,99.68 150.15,99.57 151.4,99.57 151.51,99.46 151.51,99.24 151.4,99.12 150.15,99.12 150.04,99.01 150.04,98.79 150.15,98.68 151.32,98.68 151.43,98.57 151.43,98.34 151.32,98.23 150.15,98.23 150.04,98.12 150.04,97.9 150.15,97.78 151.25,97.78 151.36,97.67 151.36,97.45 151.25,97.34 150.25,97.34 150.13,97.22 150.13,95.33 v1(150.04,95.24) 148.77,93.97 148.43,93.97 147.36,95.04 143.33,95.04 142.52,95.42 140.63,95.42 139.16,93.94 136.07,93.94 135.64,94.37 133.08,94.37
PCH_SPI_CS#0_R1: length 3.3
  BOTTOM w0.127: JSPI1.9 164.43,97.41 RC37.1 163.74,96.67 163.35,96.28 163.22,96.28 162.83,95.88 RC36.2
PCH_SPI_CS#0_R2: length 3.5
  TOP w0.127: v3(162.65,96.34) 162.32,96.02 v2(162.01,96.02)
  BOTTOM w0.127: RC37.2 162.71,96.72 v2(162.01,96.02) 161.31,95.32 UC5.1
PCH_SPI_CS#1: length 57.4
  TOP w0.127: v2(159.41,102.06) 159.41,102.56 158.4,103.57 156.41,103.57 155.88,103.03 v1(155.88,101.26) 155.88,101 155.34,100.47 155.34,96.76 v2(155.84,96.27)
  BOTTOM w0.076: 133.27,94.16 132.31,94.16 132.22,94.13 131.98,93.89 UC1.AU2
  BOTTOM w0.127: 133.27,94.16 133.28,94.14 135.54,94.14 136.03,93.66 139.2,93.66 140.66,95.12 142.58,95.12 143.24,94.81 144.87,94.81 145.01,94.67 145.01,93.39 145.16,93.24 145.46,93.24 145.62,93.4 145.62,94.68 145.75,94.81 145.98,94.81 146.13,94.66 146.13,93.52 146.26,93.39 146.52,93.39 146.64,93.51 146.64,94.67 146.77,94.81 147.01,94.81 147.14,94.67 147.14,93.87 147.4,93.61 147.4,92.72 147.52,92.59 147.78,92.59 147.91,92.72 147.91,93.61 148.03,93.74 149.57,93.74 150.58,94.75 150.58,94.98 150.7,95.09 151.15,95.09 151.26,95.2 151.26,95.41 151.13,95.54 150.7,95.54 150.58,95.65 150.58,95.87 151.37,96.65 155.45,96.65 v2(155.84,96.27) ; JSPI1.2 165.98,100.91 166.22,101.14 166.22,101.57 164.71,103.08 163.4,103.08 RC32.2 162.38,102.06 v2(159.41,102.06)
PCH_SPI_CS#1_R1: length 3.7
  BOTTOM w0.127: v1(164.73,102.5) RC32.1 RC42.1 163.94,101.41 JSPI1.1
PCH_SPI_CS#1_R2: length 2.3
  BOTTOM w0.127: UC6.1 161.77,101.23 162.15,101.61 RC42.2
PCH_SPI_CS#2: length 66
  TOP w0.127: v2(157.51,104.27) 157.22,103.99 156.71,103.99 156.33,104.38 156.33,104.92 156.08,105.16 156.08,105.5 v1(155.57,106.01) 155.14,106.44 155.14,106.62 155.54,107.01 155.54,107.19 155.36,107.37 155.18,107.37 154.78,106.98 154.6,106.98 154.38,107.2 154.04,107.2 153.8,106.95 153.8,106.69 155.49,105 155.49,104.38 155.92,103.95 155.92,103.45 155.1,102.63 155.1,102.49 155.23,102.36 155.47,102.36 155.59,102.23 155.59,101.98 155.47,101.85 155.23,101.85 155.1,101.72 155.1,99.01 154.98,98.88 154.5,98.88 154.37,98.75 154.37,98.5 154.49,98.37 154.98,98.37 155.1,98.25 155.1,97.99 154.98,97.86 154.07,97.86 153.92,97.72 153.92,97.47 154.04,97.36 154.98,97.36 155.1,97.23 155.1,96.98 154.98,96.85 154.78,96.85 154.65,96.72 154.65,96.46 154.77,96.34 154.98,96.34 155.1,96.21 155.1,95.98 154.97,95.84 154.79,95.84 153.11,94.17 151.99,94.17 151.48,93.65 151.22,93.65 151.1,93.78 151.1,94.28 150.97,94.4 150.71,94.4 150.59,94.28 150.59,93.78 150.46,93.65 147.62,93.65 145.93,95.34 145.68,95.34 145.52,95.19 145.52,95.03 146.18,94.37 146.18,94.17 146.06,94.04 145.79,94.04 144.18,95.65 144.18,96 144.97,96.78 144.97,97.18 144.67,97.48 144.47,97.48 143.74,96.75 143.56,96.75 143.33,96.97 143.05,96.97 142.89,96.82 142.89,96.62 143.24,96.28 143.24,96.09 142.91,95.76 140.11,95.76 139.87,95.53 138.24,95.53 137.08,94.37 135.82,94.37 135.66,94.21 135.66,93.98 135.79,93.86 137.84,93.86 138.04,93.66 138.04,93.45 137.94,93.35 137.31,93.35 137.19,93.23 137.19,92.73 137.1,92.64 136.78,92.64 136.68,92.74 136.68,93.23 136.55,93.35 136.3,93.35 136.13,93.19 136.13,92.75 136.02,92.64 135.77,92.64 135.63,92.78 135.63,93.26 v2(135.28,93.61)
  BOTTOM w0.076: UC1.AU1 133.77,93.89
  BOTTOM w0.102: 133.77,93.89 135,93.89 v2(135.28,93.61)
  BOTTOM w0.127: RZ61.1 157.65,104.27 v2(157.51,104.27)
PCH_SPI_CS#2_R: length 2.6
  BOTTOM w0.127: RZ61.2 158.47,106 v1(158.97,106) 159.33,106.36 UZ12.20
PCH_SPI_D0: length 53.8
  TOP w0.127: v2(152.46,100.59) v1(151.31,99.44) RC10.2 147.96,99.44 147.74,99.22 147.21,99.22 146.67,99.77 146.67,99.95 147.06,100.34 147.06,100.52 146.88,100.7 146.7,100.7 146.31,100.31 146.13,100.31 145.97,100.47 144.49,100.47 144.36,100.34 144.36,100.16 144.52,100.01 144.52,99.83 144.34,99.65 144.16,99.65 144,99.8 143.82,99.8 143.64,99.63 143.64,99.45 143.8,99.29 143.8,99.11 143.62,98.93 143.44,98.93 143.28,99.09 143.1,99.09 142.09,98.07 141.83,98.07 141.53,97.77 141.53,97.59 142.1,97.01 142.1,96.83 141.92,96.65 141.74,96.65 141.17,97.23 140.99,97.23 139.51,95.76 138.15,95.76 137.16,94.77 134.88,94.77 134.75,94.64 134.75,94.15 134.63,94.02 134.37,94.02 134.25,94.15 134.25,94.64 134.12,94.77 133.86,94.77 133.74,94.64 133.74,94.15 133.61,94.02 133.36,94.02 133.23,94.15 133.23,94.64 133.1,94.77 132.85,94.77 132.72,94.64 132.72,94.15 132.59,94.02 132.34,94.02 132.21,94.15 132.21,94.64 132.09,94.77 131.75,94.77 131.52,94.54 131.52,93.92 131.91,93.52 133.52,93.52 v2(133.75,93.29) ; v2(159.41,99.64) 158.95,99.64 v2(158.23,100.36)
  BOTTOM w0.076: UC1.AV3 131.04,93.46 133.59,93.46 v2(133.75,93.29)
  BOTTOM w0.127: JSPI1.4 163.31,99.91 162.83,100.39 RC33.1 161.68,99.32 159.73,99.32 v2(159.41,99.64) ; v2(158.23,100.36) 158.23,100.41 157.2,101.43 154.88,101.43 154.04,100.59 152.46,100.59 v2(152.46,100.59)
PCH_SPI_D0_0_R: length 14.2
  TOP w0.127: v2(157.63,93.99) 157.64,94 RPC1.7
  BOTTOM w0.127: UC5.5 154.16,91.51 154.47,91.21 157.84,91.21 157.95,91.31 157.95,91.89 157.87,91.98 155.9,91.98 155.8,92.07 155.8,92.29 155.92,92.4 v2(156.03,92.4) 157.87,92.4 157.92,92.45 157.92,92.82 157.87,92.88 156.99,92.88 156.88,92.98 156.88,93.2 156.99,93.3 157.85,93.3 157.96,93.41 157.96,93.76 157.85,93.86 157.76,93.86 v2(157.63,93.99)
PCH_SPI_D0_1_R: length 12.8
  TOP w0.127: RC409.2 v2(157.63,99.45)
  BOTTOM w0.127: v2(157.63,99.45) 158.16,99.45 158.29,99.32 158.29,98.9 158.18,98.79 157.43,98.79 157.33,98.69 157.33,98.47 157.43,98.37 158.18,98.37 158.29,98.26 158.29,98.08 158.06,97.85 156.98,97.85 156.87,97.96 156.87,98.91 156.78,99 156.57,99 156.44,98.88 156.44,97.8 156.13,97.49 155.61,97.49 155.5,97.6 155.5,98.1 155.34,98.26 155.15,98.26 155,98.11 155,97.57 154.85,97.42 UC6.5
PCH_SPI_D0_2_R: length 12.7
  TOP w0.127: v2(158.83,106.58) 158.83,106.08 158.96,105.95 159.74,105.95 159.87,105.83 159.87,105.57 159.74,105.45 157.34,105.45 157.22,105.32 157.22,105.07 157.35,104.94 159.74,104.94 159.87,104.81 159.87,104.56 159.74,104.43 158.96,104.43 158.83,104.3 158.83,103.63 v1(159.5,102.96) 160.17,102.28 RZ59.2
  BOTTOM w0.127: UZ12.21 v2(158.83,106.58)
PCH_SPI_D0_R1: length 14.6
  TOP w0.127: RPC1.2 157.64,96.22 157.82,96.4 157.82,97.72 RC409.1 158.14,98.42 158.14,99.82 157.83,100.13 157.83,100.84 158.09,101.1 v1(158.9,101.1) v2(159.41,101.1) 159.42,101.09 RZ59.1
  BOTTOM w0.127: JSPI1.3 163.8,100.41 RC33.2 163.74,100.56 163.32,100.98 162.39,100.98 162.01,100.59 159.92,100.59 v2(159.41,101.1)
PCH_SPI_D1: length 54
  BOTTOM w0.076: UC1.AW3 131.5,92.28 131.98,92.28 132.14,92.12 132.54,92.12 133.59,91.07 135.54,91.07
  BOTTOM w0.127: RC34.1 162.83,99.19 163.11,98.91 JSPI1.6 166.07,98.91 166.19,98.78 166.19,95.13 167.41,93.91 167.41,91.4 165.94,89.93 163.22,89.93 162.62,89.33 162.29,89.33 162.05,89.57 162.05,89.78 161.8,90.03 158.37,90.03 158.24,90.16 151.41,90.16 v1(151.04,90.53) 150.3,91.27 148.07,91.27 143.49,86.69 140.52,86.69 136.14,91.07 135.54,91.07
PCH_SPI_D1_0_R: length 12.8
  TOP w0.127: v2(159.47,94.18) 159.2,94.18 159.08,94.3 159.08,94.47 159.58,94.97 159.58,95.38 159.42,95.54 159.19,95.54 158.69,95.04 158.69,94.13 158.55,93.99 158.31,93.99 158.14,94.15 RPC1.8
  BOTTOM w0.127: UC5.2 160.27,94.05 159.35,94.98 159.17,94.98 158.88,94.69 158.7,94.69 158.52,94.87 158.52,95.05 158.81,95.34 158.81,95.52 158.6,95.73 157.85,95.73 157.66,95.54 157.66,95.05 158.87,93.84 159.13,93.84 v2(159.47,94.18)
PCH_SPI_D1_1_R: length 13.8
  TOP w0.127: v2(159.41,100.4) 162.3,100.4 162.43,100.28 162.43,98.94 162.27,98.79 161.36,98.79 161.25,98.9 v1(161.25,99.12) 161.25,99.9 161.14,100.01 160.91,100.01 160.8,99.9 160.8,98.9 160.69,98.79 160.47,98.79 160.35,98.9 160.35,99.9 160.24,100.01 160.02,100.01 159.91,99.9 159.91,99.34 159.4,98.83 RC410.2
  BOTTOM w0.127: v2(159.41,100.4) 159.85,99.96 UC6.2
PCH_SPI_D1_2_R: length 12.7
  TOP w0.127: v2(157.24,106.59) 156.9,106.24 156.28,106.24 156.06,106.46 156.06,106.84 156.31,107.09 156.99,107.09 157.56,107.65 157.81,107.65 157.94,107.53 157.94,107.19 158.06,107.06 158.32,107.06 158.45,107.19 158.45,107.53 158.57,107.65 158.83,107.65 158.95,107.53 158.95,107.32 159.08,107.19 159.27,107.19 v1(159.61,107.53) 159.88,107.8 160.06,107.8 160.24,107.62 160.24,107.44 159.61,106.81 159.61,106.63 159.79,106.45 159.97,106.45 160.22,106.69 160.4,106.69 160.58,106.51 160.58,106.33 160.33,106.09 160.33,105.91 160.6,105.64 RZ58.2
  BOTTOM w0.127: UZ12.24 157.33,106.67 v2(157.24,106.59)
PCH_SPI_D1_R1: length 24
  TOP w0.127: RPC1.1 158.14,97.41 RC410.1 159.26,98.53 162.5,98.53 162.66,98.68 162.66,101.6 v2(161.69,102.56) v1(161.69,103.72) 161.69,104.99 RZ58.1
  BOTTOM w0.127: RC34.2 163.76,99.41 JSPI1.5 165.95,99.41 166.47,99.93 166.47,101.64 164.8,103.3 162.44,103.3 v2(161.69,102.56)
PCH_SPI_D2: length 42.5
  TOP w0.127: v2(159.72,92.26) 159.44,92.26 159.16,91.97 155.22,91.97 154.81,92.38 150.79,92.38 v2(150.78,92.38)
  BOTTOM w0.076: UC1.AW2 131.89,92.74 132.54,92.74 132.88,92.4 132.88,92.01 133.59,91.3 135.54,91.3
  BOTTOM w0.127: 135.54,91.3 136.27,91.3 140.62,86.94 143.16,86.94 v1(143.58,87.36) 148.77,92.56 149.02,92.56 149.31,92.84 150.32,92.84 v2(150.78,92.38) 150.72,92.38 150.09,91.75 RC11.2 ; v2(159.72,92.26) 159.82,92.15 161.44,92.15 162.62,93.33 163.07,93.33 163.65,93.91 RC38.1 163.73,93.91 164.13,94.32 164.13,94.93 164.73,95.53 164.73,95.72 164.92,95.91 JSPI1.12
PCH_SPI_D2_0_R: length 13
  TOP w0.127: v2(162.33,93.67) 162.33,93.31 162.53,93.1 163.97,93.1 164.08,93.21 164.08,95.39 163.97,95.5 163.76,95.5 163.65,95.39 163.65,94.53 163.53,94.42 163.31,94.42 163.2,94.53 163.2,95.39 163.09,95.5 162.86,95.5 162.75,95.39 162.75,94.53 162.64,94.42 v3(162.42,94.42) 162.3,94.53 162.3,95.39 162.19,95.5 RC39.2
  BOTTOM w0.127: v2(162.33,93.67) 161.44,92.78 UC5.3
PCH_SPI_D2_1_R: length 14.1
  TOP w0.127: v2(159.47,98.12) 159.61,98.26 164.18,98.26 164.3,98.15 v1(164.3,98.05) 164.3,97.87 164.18,97.76 163.51,97.76 163.4,97.64 163.4,96.95 163.29,96.84 163.07,96.84 162.95,96.95 162.95,97.64 162.84,97.76 162.62,97.76 162.51,97.64 162.51,96.95 162.4,96.84 162.17,96.84 162.06,96.95 162.06,97.64 161.88,97.83 160.66,97.83 160.48,97.64 RC43.2
  BOTTOM w0.127: v2(159.47,98.12) 160.04,98.69 UC6.3
PCH_SPI_D2_R1: length 12.5
  TOP w0.127: v2(159.47,93.55) 159.89,93.97 159.89,95.72 160.25,96.07 160.25,96.18 RC30.1 RC39.1 161.39,96.43 RC43.1
  BOTTOM w0.127: v2(159.47,93.55) 159.6,93.42 161.5,93.42 162.39,94.3 v1(162.59,94.3) 162.96,94.3 163.49,94.83 RC38.2 164.46,95.63 164.46,95.98 164.89,96.41 JSPI1.11
PCH_SPI_D3: length 45.1
  BOTTOM w0.076: 135.54,92.58 134.43,93.69 132.73,93.69 132.66,93.63 130.91,93.63 130.65,93.89 UC1.AU4
  BOTTOM w0.127: JSPI1.14 164.87,94.91 164.69,94.73 164.69,94.02 164.41,93.74 164.41,92.71 163.78,92.07 RC40.1 163.46,92.07 163.17,92.37 162.43,92.37 162.01,91.95 162.01,91.13 161.64,90.77 159,90.77 158.82,90.94 152.2,90.94 151.85,91.29 151.85,92.18 150.96,93.07 149.21,93.07 148.93,92.78 148.68,92.78 143.76,87.87 142.7,87.87 142.64,87.8 140.49,87.8 138.33,89.97 v1(138.33,90.7) 136.84,92.19 135.94,92.19 135.54,92.58
PCH_SPI_D3_0_R: length 12.7
  TOP w0.127: RPC1.5 156.64,94.06 156.58,93.99 v2(156.31,93.99)
  BOTTOM w0.127: v2(156.31,93.99) 156.25,94.05 156.21,94.05 156.09,94.18 156.09,94.46 156.21,94.59 156.68,94.59 156.81,94.72 156.81,94.97 156.68,95.1 156.21,95.1 156.09,95.22 156.09,95.67 155.97,95.79 155.72,95.79 155.58,95.65 155.58,93.93 155.44,93.79 155.19,93.79 155.07,93.91 155.07,96.07 154.95,96.19 154.7,96.19 154.56,96.06 154.56,94.18 154.43,94.05 UC5.7
PCH_SPI_D3_1_R: length 12.8
  TOP w0.127: v2(156.52,99.45) 156.23,99.45 156.1,99.58 156.1,100.24 155.98,100.36 155.79,100.36 155.71,100.27 155.71,99.92 v1(155.69,99.9) 155.66,99.87 155.66,99.03 155.85,98.84 RC407.2
  BOTTOM w0.127: v2(156.52,99.45) 157.07,99.45 157.24,99.62 157.24,99.82 157.37,99.95 157.67,99.95 157.8,100.07 157.8,100.25 157.67,100.38 157.37,100.38 157.24,100.5 157.24,101.02 157.11,101.15 155.65,101.15 155.56,101.06 155.56,100.7 155.43,100.56 155.29,100.56 154.94,100.92 154.72,100.92 154.51,100.71 154.51,100.53 154.7,100.33 154.7,99.46 154.57,99.32 154.35,99.32 154.2,99.47 154.2,99.86 154.09,99.96 UC6.7
PCH_SPI_D3_R1: length 20.8
  TOP w0.127: RPC1.4 156.64,96.44 v2(156.42,96.66) 155.85,97.23 RC407.1 ; v2(159.47,92.91) 159.65,92.73 RC316.1 RC31.1
  BOTTOM w0.127: v2(156.42,96.66) 156.42,95.96 v2(159.47,92.91) 158.85,92.29 158.85,91.5 159.36,90.99 161.49,90.99 161.76,91.26 161.76,92.09 162.46,92.78 v1(162.66,92.78) 163.46,92.78 RC40.2 164.16,93.48 164.16,93.86 164.44,94.14 164.44,94.88 164.97,95.41 JSPI1.13
PCH_SPI_DO2_XDP: length 122.2
  IN2 w0.122: v2(145.92,125.83) 145.92,120.4 142.73,117.21 141.05,117.21 138.96,115.12 138.96,112.51 139.29,112.18 139.29,111.94 141.03,110.2 141.25,110.2 142.75,108.7 142.75,101.74 141.88,100.87 141.88,100.39 142.14,100.14 143.53,100.14 143.91,100.52 145.67,100.52 147.24,98.94 147.75,98.94 148.06,99.25 148.4,99.25 150.72,96.93 150.72,92.98 v2(150.13,92.39)
  BOTTOM w0.127: v2(150.13,92.39) 149.57,92.39 RC11.1 ; v2(145.92,125.83) 146.35,125.4 147.13,125.4 147.64,125.91 v1(147.64,129.79) 147.64,130.7 145.72,132.62 145.72,133.97 144.37,135.32 119.56,135.32 117.19,132.95 107.29,132.95 105.96,134.28 87.09,134.28 85.81,133 JXDP1.60
PCH_SPI_DO_XDP: length 101.6
  TOP w0.127: v2(141.2,107.08) 141.44,106.83 146.15,106.83 147.97,105.01 149.12,105.01 151.25,102.88 v1(151.25,102.31) 151.96,101.6 151.96,101 151.31,100.35 RC10.1 RC133.1
  IN2 w0.122: v2(141.2,107.08) 141.15,107.08 137.93,110.29 137.93,111.57 137.01,112.5 137.01,115.21 140.35,118.55 142.17,118.55 144.18,120.56 144.18,123.81 143.75,124.24 142.41,124.24 139.55,127.1 139.55,127.99 138.32,129.22 125.27,129.22 124.64,128.58 122,128.58 121.77,128.81 116.39,128.81 115.23,127.66 104.15,127.66 104.15,127.65 103.38,127.65 103.02,127.29 101.18,127.29 100.82,127.65 90.65,127.65 v2(88.6,125.61)
  BOTTOM w0.127: RC128.1 88.48,125.73 v2(88.6,125.61)
PCI_CLK_LPC1: length 14.9
  TOP w0.127: RC22.1 137.5,85.55 v2(137.36,85.69)
  BOTTOM w0.076: UC1.AY9 127.31,91.61 127.24,91.4 127.24,91.28 127.3,91.05 127.3,90.91 127.25,90.79 127.25,90.53 127.4,90.38 128.04,90.38 128.5,89.93 128.98,89.93 130.4,88.51 130.81,88.51 130.95,88.36
  BOTTOM w0.127: v2(137.36,85.69) 136.49,86.56 135.13,86.56 134.22,87.47 131.84,87.47 130.95,88.36
PCIE_PRX_C_DTX_N1: length 2.7
  TOP w0.104: CR14.2 271.32,63.06 271.47,63.06 271.69,63.28 271.69,63.37 271.86,63.54 272.39,63.54 272.42,63.57 272.71,63.57 272.81,63.47 UR1.8
PCIE_PRX_C_DTX_N4: length 2.4
  TOP w0.104: UL1.39 242.85,127.33 242.73,127.46 242.39,127.46 242.05,127.8 241.61,127.8 CL2.2
PCIE_PRX_C_DTX_N5: length 5.3
  BOTTOM w0.076: UT1.F22 25.17,94.5 25.17,94.06 25.04,93.93 25.04,93.56 25.18,93.41 25.18,92.31 25.2,92.3 25.2,92.28
  BOTTOM w0.104: 25.2,92.28 25.2,90.49 25.43,90.26 25.43,89.99 CT130.1
PCIE_PRX_C_DTX_N6: length 5.2
  BOTTOM w0.076: UT1.K22 27.01,94.5 27.01,94.06 26.89,93.94 26.89,93.12 27.15,92.86 27.15,92.31 27.17,92.3 27.17,92.28
  BOTTOM w0.104: CT128.1 27.17,90.02 27.17,92.28
PCIE_PRX_C_DTX_N7: length 5.4
  BOTTOM w0.076: 29.39,92.27 29.39,92.29 29.38,92.31 29.38,92.5 28.79,93.09 28.79,93.91 28.86,93.98 28.86,94.49 UT1.P22
  BOTTOM w0.104: 29.39,92.27 29.39,89.98 CT9.1
PCIE_PRX_C_DTX_N8: length 5.8
  BOTTOM w0.076: 31.62,92.28 31.62,92.3 31.64,92.31 31.64,92.45 30.43,93.66 30.43,93.92 30.25,94.1 30.25,94.5 UT1.V22
  BOTTOM w0.104: CT7.1 31.62,89.89 31.62,92.28
PCIE_PRX_C_DTX_P1: length 2.7
  TOP w0.104: UR1.7 272.82,63.87 272.72,63.76 v4(272.08,63.76) 271.81,63.76 271.5,63.45 271.5,63.36 271.39,63.26 271.32,63.26 CR13.2
PCIE_PRX_C_DTX_P4: length 2.4
  TOP w0.104: CL1.2 241.63,127.99 242.13,127.99 242.47,127.65 242.75,127.65 242.83,127.73 UL1.38
PCIE_PRX_C_DTX_P5: length 5.3
  BOTTOM w0.076: UT1.F23 24.95,94.38 24.87,94.46 24.78,94.46 24.72,94.4 24.72,94.09 24.87,93.93 24.87,93.49 25.02,93.34 25.02,92.31 25.01,92.3 25.01,92.28
  BOTTOM w0.104: CT129.1 25.24,90.04 25.24,90.18 25.01,90.41 25.01,92.28
PCIE_PRX_C_DTX_P6: length 5.2
  BOTTOM w0.076: UT1.K23 26.79,94.38 26.71,94.46 26.63,94.46 26.56,94.39 26.56,94.09 26.72,93.92 26.72,93.05 26.99,92.79 26.99,92.31 26.97,92.3 26.97,92.28
  BOTTOM w0.104: 26.97,92.28 26.97,90.01 CT127.1
PCIE_PRX_C_DTX_P7: length 5.4
  BOTTOM w0.076: 29.2,92.27 29.2,92.29 29.21,92.31 29.21,92.44 28.63,93.02 28.63,93.91 28.55,93.98 28.49,93.98 28.39,94.09 28.39,94.32 28.47,94.41 28.58,94.41 28.63,94.36 UT1.P23
  BOTTOM w0.104: 29.2,92.27 29.2,90.03 CT8.1
PCIE_PRX_C_DTX_P8: length 5.8
  BOTTOM w0.076: UT1.V23 30.47,94.41 30.54,94.48 30.65,94.48 30.7,94.42 30.7,94.1 30.59,93.99 30.59,93.73 31.8,92.52 31.8,92.3 31.8,92.29 31.81,92.3 31.81,92.28
  BOTTOM w0.104: 31.81,92.28 31.81,89.89 CT6.1
PCIE_PRX_DTX_N1: length 203.5
  TOP w0.104: CR14.1 269.67,63.06 269.35,63.06 v2(269.07,62.78)
  IN1 w0.094: v2(269.07,62.78) 268.78,63.07 268.05,63.07 267.66,63.46 267.66,66.93 269.87,69.13 269.87,72.58 268.08,74.37 263.41,74.37 262.71,73.67 259.69,73.67 258.97,72.94 256.99,72.94 255.55,71.51 251.72,71.51 250.92,70.71 247.03,70.71 244.78,68.46 235.76,68.46 232.53,65.22 232.53,63.82 230.06,61.35 227.06,61.35 226.39,62.02 219.41,62.02 219.04,61.65 215.6,61.65 214.81,62.45 181.65,62.45 180.71,63.38 180.71,65.63 171.1,75.25 171.1,77.52 166.08,82.54 166.08,85.27 163.93,87.42 163.93,89.69 162.1,91.51 162.1,92.53 162.74,93.17 162.74,99.57 158.82,103.48 157.08,103.48 155.59,104.98 155.59,106.58 154.89,107.29 154.89,109.11 154.41,109.58 152.37,109.58 151.08,110.88 146.44,110.88 145.57,110.01 140.2,110.01 136.3,113.92 133.4,113.92 131.91,112.42 128.16,112.42 126.16,110.43 126.16,109.33 125.96,109.13 125.7,109.13 125.63,109.06 v2(125.63,108.86)
  BOTTOM w0.076: UC1.H13 125.41,108.64 v2(125.63,108.86)
PCIE_PRX_DTX_N3: length 150.3
  IN1 w0.094: v2(122.98,108.92) 123.19,109.13 123.37,109.13 123.55,108.96 124.29,108.96 125.35,110.02 125.35,111.78 126.72,113.15 131.91,113.15 133.37,114.6 138.68,114.6 140.72,116.64 143.28,116.64 147.82,112.11 151.42,112.11 153.12,110.41 155.57,110.41 157.05,108.94 158.11,108.94 158.41,108.64 158.41,107.99 164.58,101.82 164.58,91.99 165.83,90.73 165.83,88.14 167.86,86.11 167.86,83.37 174.9,76.33 174.9,75.19 185.45,64.64 227.2,64.64 231.72,69.15 231.72,70.14 231.93,70.36 232.1,70.36 232.26,70.2 232.26,70.03 v2(232.21,69.98)
  BOTTOM w0.089: v2(122.98,108.92) 122.98,108.93 123.21,108.93 123.35,108.79 UC1.H16
  BOTTOM w0.104: v2(232.21,69.98) 232.5,70.27 232.63,70.27 232.75,70.15 JNGFF1.43
PCIE_PRX_DTX_N4: length 217
  TOP w0.104: CL2.1 239.98,127.84 239.88,127.84 v2(239.62,127.58)
  IN1 w0.094: v2(123.83,109.61) 123.64,109.8 123.53,109.8 123.35,109.99 123.35,112.08 122.87,112.56 122.87,114.68 122.61,114.94 122.61,116.86 122.96,117.22 124.35,117.22 124.96,116.61 126.3,116.61 127.82,115.08 130.06,115.08 131.03,116.04 138.01,116.04 140.08,118.11 143.94,118.11 145.97,116.09 148.29,116.09 150.17,114.21 153.02,114.21 154.56,112.67 157.24,112.67 160.88,109.03 161.57,109.03 163.63,106.97 163.63,105.04 166.1,102.56 166.1,92.5 167.19,91.4 167.19,88.74 169.26,86.67 169.26,84.04 176.51,76.79 176.51,75.64 185.61,66.55 226.74,66.55 228.99,68.8 228.99,71.04 232.31,74.36 232.31,77.6 234.27,79.56 234.27,96.2 234.57,96.5 234.57,113.19 234.79,113.41 234.79,119.18 237.39,121.78 239.35,121.78 240.31,122.74 240.31,127.72 240.09,127.93 239.74,127.93 239.62,127.81 v2(239.62,127.58)
  BOTTOM w0.076: v2(123.83,109.61) 124.15,109.29 UC1.G15
PCIE_PRX_DTX_N5: length 159.6
  IN4 w0.094: v2(25.71,88.59) 25.47,88.59 25.31,88.75 25.31,89.18 25.64,89.51 26.32,89.51 27.29,90.48 27.29,90.95 27.68,91.34 33.48,91.34 34.68,92.55 34.68,94.15 34.93,94.4 34.93,102.66 35.17,102.9 35.17,106.37 35.3,106.5 35.3,108.19 34.4,109.1 34.4,109.52 35.29,110.42 35.29,123.59 39.79,128.09 41.04,128.09 42.05,129.09 44.79,129.09 49.18,133.48 52.05,133.48 52.89,134.31 70.42,134.31 71.7,133.04 72.28,133.04 76.2,129.12 79.66,129.12 84.61,134.07 107.14,134.07 108.81,132.41 113.33,132.41 121,124.73 121,120.99 121.51,120.48 121.51,117.48 121.84,117.15 121.84,115.11 121.4,114.67 121.4,113.4 122.65,112.15 122.65,111.55 122.41,111.32 122.41,110.75 122.58,110.57 122.82,110.57 122.97,110.43 v2(122.97,110.26)
  BOTTOM w0.076: UC1.F16 123.35,109.98 v2(122.97,110.26)
  BOTTOM w0.104: v2(25.71,88.59) 25.41,88.89 25.41,89.06 CT130.2
PCIE_PRX_DTX_N6: length 155.8
  IN4 w0.094: v2(121.98,109.52) 121.98,109.85 121.91,109.93 121.69,109.93 121.47,110.14 121.47,111.83 120.72,112.59 120.72,117.64 120.9,117.82 120.9,119.81 120.4,120.3 120.4,124.28 112.94,131.74 108.11,131.74 106.37,133.47 84.86,133.47 79.9,128.52 75.89,128.52 72.17,132.24 70.79,132.24 70.16,132.86 49.42,132.86 45.01,128.45 44.09,128.45 42.34,126.7 39.49,126.7 35.88,123.09 35.88,109.53 36.4,109.02 36.4,106.33 35.75,105.69 35.75,102.66 35.59,102.5 35.59,94.23 35.85,93.97 35.85,92.89 33.85,90.88 33.85,89.97 33.42,89.54 27.51,89.54 27.18,89.2 27.18,88.64 27.27,88.55 v2(27.44,88.55)
  BOTTOM w0.076: UC1.G18 122.21,109.52 v2(121.98,109.52)
  BOTTOM w0.104: CT128.2 27.2,89.08 27.2,88.79 v2(27.44,88.55)
PCIE_PRX_DTX_N7: length 150.7
  IN4 w0.094: v2(29.56,88.15) 29.3,88.4 29.3,88.56 29.39,88.65 34.01,88.65 34.77,89.41 34.77,90.85 36.45,92.52 36.45,100.65 36.99,101.19 36.99,109.31 36.49,109.81 36.49,121.95 40.58,126.04 44.56,126.04 47.46,128.95 47.46,130.03 49.69,132.26 69.64,132.26 70.28,131.61 71.85,131.61 75.53,127.93 80.21,127.93 83.89,131.61 84.43,131.61 85.57,132.75 105.92,132.75 107.62,131.04 110.49,131.04 118.95,122.57 118.95,120.72 119.42,120.25 119.42,117.51 120.1,116.83 120.1,112.3 120.53,111.88 120.53,110.78 120.72,110.58 120.99,110.58 121.07,110.51 v2(121.07,110.18)
  BOTTOM w0.089: UC1.F20 121.52,110.01 121.36,110.18 v2(121.07,110.18)
  BOTTOM w0.104: v2(29.56,88.15) 29.35,88.35 29.35,89.02 CT9.2
PCIE_PRX_DTX_N8: length 144.9
  IN4 w0.094: v2(120.23,109.57) 120.05,109.75 119.87,109.75 119.59,110.03 119.59,110.52 119.55,110.57 119.55,111.49 118.81,112.22 118.81,117.77 116.78,119.8 116.78,122.56 112.01,127.34 109.75,127.34 105.94,131.14 86.33,131.14 85.8,130.61 83.79,130.61 80.19,127.01 75.56,127.01 73.25,129.32 48.79,129.32 44.89,125.42 41.95,125.42 40.03,123.5 39.17,123.5 37.07,121.4 37.07,111.16 37.62,110.61 37.62,107.65 38.1,107.17 38.1,105.8 37.62,105.32 37.62,100.98 37.05,100.41 37.05,92.1 35.41,90.46 35.41,89.19 34.42,88.21 34.42,88.21 34.04,87.82 33.64,87.82 32.8,86.99 31.91,86.99 31.64,87.26 31.64,87.55 v2(31.42,87.77)
  BOTTOM w0.076: v2(120.23,109.57) 120.41,109.57 120.61,109.37 UC1.G21
  BOTTOM w0.104: CT7.2 31.59,88.95 31.59,87.94 v2(31.42,87.77)
PCIE_PRX_DTX_N9: length 145.3
  IN2 w0.089: 118.84,108.29 118.84,108.32 118.85,108.33 118.85,109.1 118.71,109.24 118.71,109.72 118.62,109.8 118.62,110.4 118.9,110.69 119.07,110.69 119.16,110.77 v2(119.16,110.93)
  IN2 w0.119: 118.84,108.29 118.84,107.68 119.23,107.29 119.23,101.06 118.58,100.41 118.58,98.15 117.52,97.09 117.52,92.1 116.43,91.01 113.91,91.01 111.64,88.73 90.53,88.73 80.68,78.88 72.65,78.88 71.91,78.14 60.09,78.14 58.78,76.83 51.59,76.83 51.34,76.58 47.77,76.58 47.43,76.92 43.07,76.92 40,73.85 40,57.3 34.82,52.12 31.1,52.12 27.96,48.98 27.96,46.45 27.54,46.03 27.2,46.03 26.98,46.26 v2(26.98,46.42)
  BOTTOM w0.102: UC1.E22 119.5,110.59 v2(119.16,110.93)
  BOTTOM w0.104: JNGFF3.5 27.95,44.61 27.87,44.69 27.87,45.79 27.43,46.23 27.17,46.23 v2(26.98,46.42)
PCIE_PRX_DTX_N10: length 145.1
  IN2 w0.089: v2(117.38,110.3) 117.38,110.41 117.26,110.53 117.11,110.53 116.95,110.37 116.95,110.04 117.08,109.91 117.08,109.06 116.23,108.21 116.23,107.75 116.16,107.68 116.16,107.37 116.18,107.35 116.18,107.33
  IN2 w0.119: v2(25.09,45.78) 24.9,45.78 24.7,45.98 24.7,46.97 25,47.27 25,49.24 24.74,49.5 24.74,53.61 27.71,56.58 35.06,56.58 38.92,60.43 38.92,74.61 42.42,78.12 48.4,78.12 48.83,77.69 50.84,77.69 51.14,77.98 58.26,77.98 59.84,79.56 71.41,79.56 72.56,80.72 80.94,80.72 90.42,90.19 93.58,90.19 94.84,91.45 112.69,91.45 114.4,93.17 114.4,94.84 114.16,95.08 114.16,98.34 115.72,99.9 115.72,105.8 116.18,106.26 116.18,107.33
  BOTTOM w0.076: v2(117.38,110.3) 117.74,109.94 UC1.F25
  BOTTOM w0.104: JNGFF3.17 24.95,44.53 24.77,44.71 24.77,45.46 v2(25.09,45.78)
PCIE_PRX_DTX_N11: length 178.6
  IN4 w0.094: v2(115.63,110.89) 115.97,110.89 116.07,110.99 116.07,111.69 115.64,112.12 115.64,114.23 112.44,117.42 111.5,117.42 102.71,126.21 98.81,126.21 97.23,127.79 87.52,127.79 86.93,127.21 83.79,127.21 81.07,124.49 76.09,124.49 75.45,125.13 74.45,125.13 74.27,124.94 73.75,124.94 72.07,126.63 64.96,126.63 64.62,126.96 52.81,126.96 49.3,123.46 47.01,123.46 43.97,120.41 40.58,120.41 39.54,119.37 39.54,112.85 40.07,112.32 40.07,111.82 39.75,111.5 39.75,111.2 39.95,111 39.95,109.88 40.57,109.26 40.57,108.47 40.09,107.99 40.09,107.53 40.54,107.09 40.54,103.26 41.06,102.74 41.06,100.67 40.72,100.33 40.35,100.33 39.74,99.72 39.74,98.61 38.89,97.76 38.89,94.34 39.42,93.81 39.42,91.87 39.86,91.43 39.86,90.08 36.95,87.17 36.95,86.89 36.63,86.57 36.63,85.01 35.68,84.05 35.68,78.84 35.07,78.23 35.07,75.79 34.49,75.21 34.49,72.74 32.48,70.73 32.48,70.14 28.03,65.69 28.03,59.87 21.35,53.19 21.35,50.91 21.52,50.75 v2(21.79,50.75)
  BOTTOM w0.102: v2(115.63,110.89) 115.86,110.89 116.04,110.72 UC1.E28
  BOTTOM w0.104: v2(21.79,50.75) 21.63,50.75 21.5,50.62 21.5,50.5 21.64,50.36 v4(21.64,49.7) 21.64,49.13 21.8,48.98 21.8,44.67 21.95,44.52 JNGFF3.29
PCIE_PRX_DTX_N12: length 176.7
  IN4 w0.094: v2(18.4,48.83) 18.59,48.83 18.68,48.74 18.68,48.35 19.07,47.97 21.17,47.97 22.95,49.74 22.95,53.86 28.68,59.59 28.68,65.52 33.07,69.9 33.07,70.49 35.07,72.49 35.07,72.63 35.09,72.64 35.09,74.51 35.65,75.08 35.65,77.97 36.7,79.01 36.7,84.05 37.33,84.68 37.33,86.08 37.64,86.38 39.21,86.38 40.54,87.72 40.54,91.61 40.07,92.08 40.07,94.08 39.85,94.3 39.85,96.88 41.05,98.07 41.05,99.71 41.66,100.32 41.66,107.43 41.52,107.57 41.52,112.63 43.4,114.52 43.4,117.08 44.17,117.85 44.17,119.59 47.43,122.85 49.52,122.85 53.01,126.33 64.4,126.33 65.31,125.43 70.52,125.43 72.11,123.84 81.3,123.84 83.98,126.51 94.51,126.51 95.48,125.55 102.4,125.55 111.15,116.8 112.19,116.8 115.03,113.95 115.03,110.67 114.95,110.59 114.78,110.59 114.64,110.73 v2(114.64,110.84)
  BOTTOM w0.102: UC1.E30 114.89,110.59 v2(114.64,110.84)
  BOTTOM w0.104: v2(18.4,48.83) 18.46,48.83 18.62,48.67 18.62,44.68 18.45,44.51 JNGFF3.43
PCIE_PRX_DTX_P1: length 203.5
  TOP w0.104: CR13.1 269.64,63.26 269.33,63.26 v2(269.05,63.54)
  IN1 w0.094: v2(125.58,109.56) 125.58,109.41 125.68,109.31 125.89,109.31 125.98,109.4 125.98,110.51 128.08,112.61 131.83,112.61 133.32,114.1 136.37,114.1 140.28,110.2 145.5,110.2 146.37,111.06 151.15,111.06 152.45,109.77 154.48,109.77 155.07,109.18 155.07,107.36 155.77,106.66 155.77,105.05 157.16,103.67 158.9,103.67 162.92,99.64 162.92,93.1 162.29,92.46 162.29,91.59 164.11,89.76 164.11,87.49 166.26,85.34 166.26,82.62 171.28,77.6 171.28,75.32 180.9,65.71 180.9,63.46 181.72,62.63 214.88,62.63 215.68,61.84 218.97,61.84 219.33,62.2 226.47,62.2 227.13,61.53 229.98,61.53 232.34,63.89 232.34,65.3 235.69,68.64 244.7,68.64 246.96,70.9 250.85,70.9 251.65,71.7 255.48,71.7 256.91,73.13 258.89,73.13 259.61,73.85 262.63,73.85 263.33,74.55 268.15,74.55 270.05,72.65 270.05,69.06 267.84,66.85 267.84,63.54 268.13,63.25 268.75,63.25 v2(269.05,63.54)
  BOTTOM w0.076: v2(125.58,109.56) 125.31,109.29 UC1.G13
PCIE_PRX_DTX_P3: length 150.3
  IN1 w0.094: v2(122.92,109.66) 122.92,109.47 123.07,109.32 123.45,109.32 123.63,109.14 124.21,109.14 125.17,110.1 125.17,111.86 126.64,113.33 131.84,113.33 133.29,114.79 138.6,114.79 140.64,116.83 143.36,116.83 147.89,112.29 151.5,112.29 153.2,110.59 155.65,110.59 157.12,109.12 158.18,109.12 158.59,108.72 158.59,108.07 164.76,101.9 164.76,92.06 166.01,90.81 166.01,88.22 168.04,86.19 168.04,83.45 175.09,76.4 175.09,75.26 185.53,64.82 227.13,64.82 231.53,69.22 231.53,70.22 231.85,70.54 232.04,70.54 v2(232.24,70.74)
  BOTTOM w0.076: UC1.G16 123.29,109.29 v2(122.92,109.66)
  BOTTOM w0.104: v2(232.24,70.74) 232.51,70.47 232.63,70.47 232.81,70.65 JNGFF1.41
PCIE_PRX_DTX_P4: length 216.9
  TOP w0.104: v2(239.62,128.32) 239.91,128.03 240.05,128.03 CL1.1
  IN1 w0.094: v2(123.91,110.27) 123.91,110.07 123.83,109.99 123.61,109.99 123.54,110.06 123.54,112.15 123.05,112.64 123.05,114.75 122.79,115.02 122.79,116.78 123.04,117.03 124.27,117.03 124.88,116.42 126.22,116.42 127.75,114.9 130.14,114.9 131.1,115.86 138.09,115.86 140.15,117.93 143.87,117.93 145.89,115.91 148.21,115.91 150.09,114.03 152.94,114.03 154.48,112.49 157.16,112.49 160.8,108.85 161.5,108.85 163.45,106.9 163.45,104.96 165.92,102.49 165.92,92.42 167.01,91.33 167.01,88.66 169.08,86.59 169.08,83.96 176.33,76.71 176.33,75.56 185.53,66.36 226.81,66.36 229.17,68.72 229.17,70.96 232.5,74.29 232.5,77.53 234.46,79.49 234.46,96.12 234.75,96.42 234.75,113.12 234.97,113.33 234.97,119.1 237.47,121.6 239.43,121.6 240.49,122.66 240.49,127.79 240.17,128.11 239.83,128.11 v2(239.62,128.32)
  BOTTOM w0.076: UC1.F15 124.16,109.94 123.91,110.19 v2(123.91,110.27)
PCIE_PRX_DTX_P5: length 159.5
  IN4 w0.094: v2(24.94,88.57) 25.13,88.76 25.13,89.26 25.56,89.69 26.24,89.69 27.11,90.56 27.11,91.03 27.61,91.53 33.4,91.53 34.5,92.62 34.5,94.22 34.75,94.47 34.75,102.74 34.98,102.97 34.98,106.44 35.12,106.58 35.12,108.11 34.21,109.02 34.21,109.6 35.11,110.49 35.11,123.66 39.71,128.27 40.97,128.27 41.97,129.27 44.72,129.27 49.1,133.66 51.98,133.66 52.81,134.5 70.5,134.5 71.77,133.22 72.36,133.22 76.28,129.3 79.58,129.3 84.53,134.25 107.22,134.25 108.89,132.59 113.4,132.59 121.18,124.81 121.18,121.07 121.69,120.56 121.69,117.56 122.02,117.23 122.02,115.04 121.58,114.59 121.58,113.48 122.83,112.23 122.83,111.48 122.59,111.24 122.59,110.82 122.66,110.76 122.84,110.76 122.97,110.88 v2(122.97,110.92)
  BOTTOM w0.076: v2(122.97,110.92) 123.35,110.64 UC1.E16
  BOTTOM w0.104: v2(24.94,88.57) 25.22,88.85 25.22,89.05 CT129.2
PCIE_PRX_DTX_P6: length 155.8
  IN4 w0.094: v2(26.78,88.56) 26.99,88.78 26.99,89.28 27.44,89.72 33.34,89.72 33.66,90.04 33.66,90.95 35.67,92.96 35.67,93.9 35.41,94.16 35.41,102.58 35.57,102.74 35.57,105.76 36.21,106.41 36.21,108.94 35.7,109.45 35.7,123.17 39.41,126.88 42.26,126.88 44.01,128.63 44.93,128.63 49.35,133.05 70.24,133.05 70.86,132.42 72.24,132.42 75.96,128.7 79.83,128.7 84.78,133.66 106.45,133.66 108.18,131.92 113.01,131.92 120.58,124.35 120.58,120.38 121.08,119.88 121.08,117.74 120.9,117.57 120.9,112.66 121.65,111.91 121.65,110.22 121.76,110.11 121.92,110.11 v2(122.08,110.27)
  BOTTOM w0.076: UC1.F18 122.32,109.94 122.08,110.19 v2(122.08,110.27)
  BOTTOM w0.104: v2(26.78,88.56) 26.87,88.56 27,88.7 27,89.03 CT127.2
PCIE_PRX_DTX_P7: length 150.6
  IN4 w0.094: v2(28.97,88.15) 29.12,88.29 29.12,88.64 29.31,88.83 33.93,88.83 34.59,89.49 34.59,90.92 36.27,92.6 36.27,100.73 36.8,101.27 36.8,109.23 36.3,109.73 36.3,122.03 40.5,126.22 44.48,126.22 47.28,129.03 47.28,130.11 49.61,132.44 69.71,132.44 70.36,131.79 71.93,131.79 75.61,128.11 80.13,128.11 83.81,131.79 84.35,131.79 85.49,132.93 105.99,132.93 107.7,131.22 110.57,131.22 119.14,122.65 119.14,120.8 119.61,120.33 119.61,117.59 120.28,116.91 120.28,112.38 120.71,111.95 120.71,110.85 120.8,110.77 120.88,110.77 v2(121.09,110.97)
  BOTTOM w0.089: UC1.E20 121.51,110.59 121.13,110.97 v2(121.09,110.97)
  BOTTOM w0.104: CT8.2 29.16,89.06 29.16,88.33 v2(28.97,88.15)
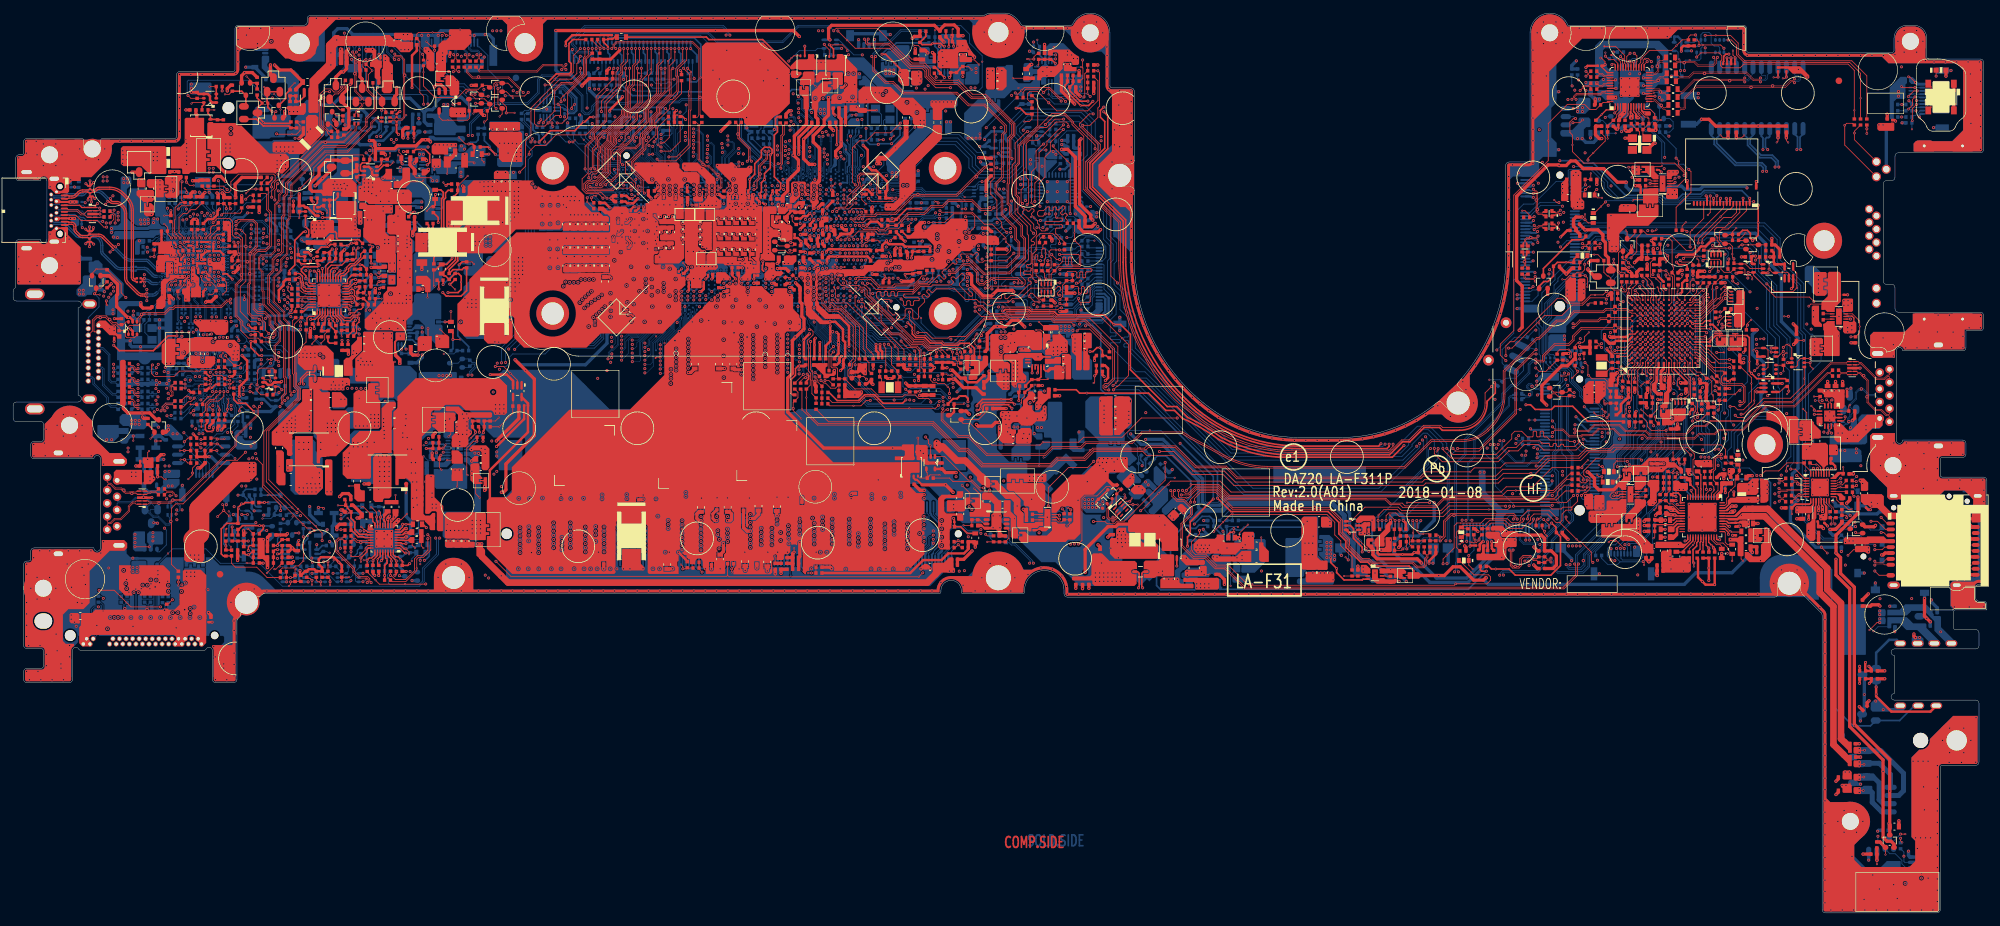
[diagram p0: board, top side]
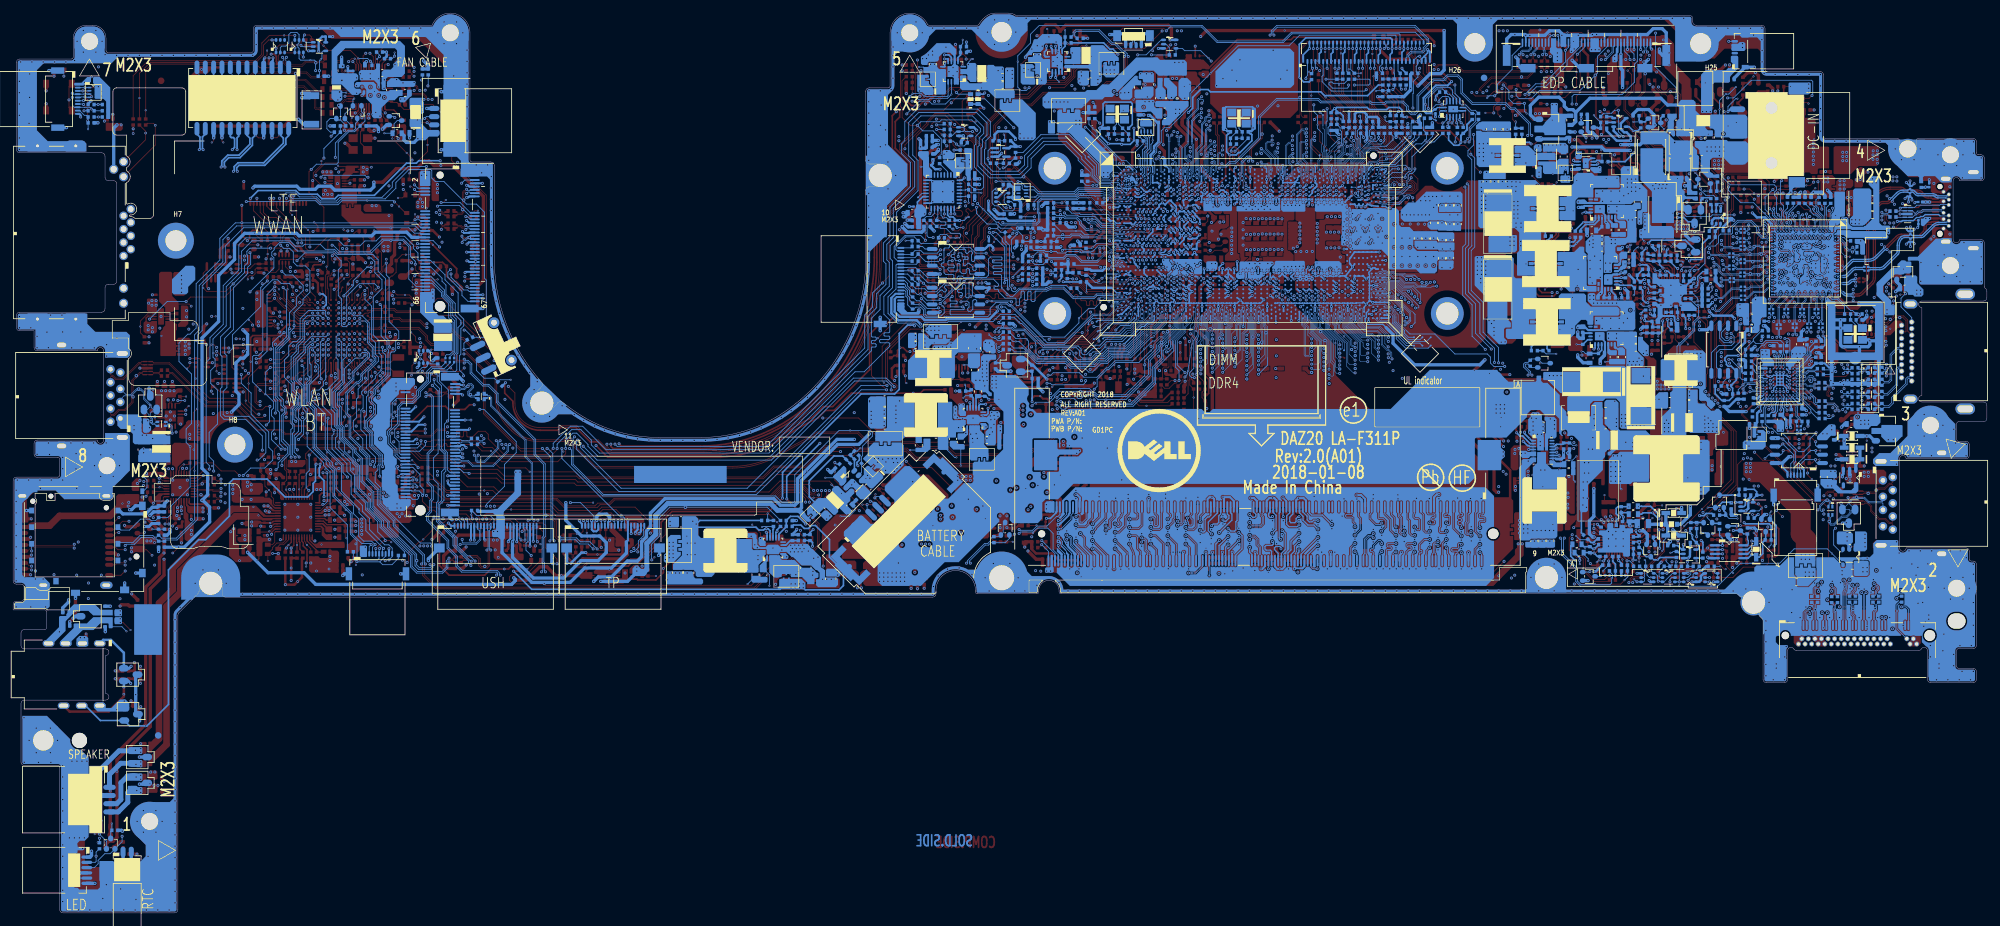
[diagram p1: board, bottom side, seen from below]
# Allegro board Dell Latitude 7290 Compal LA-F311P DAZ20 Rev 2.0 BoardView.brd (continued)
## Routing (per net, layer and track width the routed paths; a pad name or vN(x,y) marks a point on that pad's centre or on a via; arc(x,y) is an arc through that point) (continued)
PCIE_PRX_DTX_P8: length 144.9
  IN4 w0.094: v2(32.01,87.77) 31.88,87.77 31.83,87.72 31.83,87.33 31.99,87.17 32.73,87.17 33.56,88.01 33.96,88.01 35.22,89.27 35.22,90.53 36.86,92.17 36.86,100.49 37.43,101.06 37.43,105.39 37.91,105.88 37.91,107.1 37.43,107.58 37.43,110.53 36.89,111.08 36.89,121.48 39.09,123.69 39.95,123.69 41.87,125.6 44.81,125.6 48.71,129.51 73.32,129.51 75.63,127.2 80.12,127.2 83.71,130.79 85.73,130.79 86.25,131.32 106.02,131.32 109.82,127.52 112.08,127.52 116.97,122.64 116.97,119.87 119,117.84 119,112.3 119.73,111.57 119.73,110.65 119.77,110.6 119.77,110.1 119.95,109.93 120.12,109.93 120.17,109.98 v2(120.17,110.25)
  BOTTOM w0.076: UC1.F21 120.31,110.25 v2(120.17,110.25)
  BOTTOM w0.104: v2(32.01,87.77) 31.78,87.99 31.78,88.9 CT6.2
PCIE_PRX_DTX_P9: length 145.3
  IN2 w0.089: v2(119.21,110.19) 119.21,110.43 119.13,110.51 118.98,110.51 118.8,110.33 118.8,109.88 118.89,109.79 118.89,109.32 119.03,109.17 119.03,108.33 119.05,108.32 119.05,108.29
  IN2 w0.119: v2(26.98,45.62) 27.18,45.83 27.63,45.83 28.17,46.37 28.17,48.89 31.19,51.91 34.91,51.91 40.21,57.21 40.21,73.76 43.16,76.71 47.34,76.71 47.69,76.37 51.42,76.37 51.68,76.62 58.87,76.62 60.18,77.93 71.99,77.93 72.73,78.67 80.77,78.67 90.62,88.52 111.72,88.52 114,90.8 116.51,90.8 117.72,92.01 117.72,97 118.79,98.07 118.79,100.33 119.44,100.98 119.44,107.38 119.05,107.77 119.05,108.29
  BOTTOM w0.102: v2(119.21,110.19) 119.21,110.29 118.91,110.59 UC1.E23
  BOTTOM w0.104: v2(26.98,45.62) 26.98,45.89 27.13,46.04 27.35,46.04 27.68,45.71 27.68,44.7 27.45,44.47 JNGFF3.7
PCIE_PRX_DTX_P10: length 145.1
  IN2 w0.089: 115.97,107.33 115.97,107.35 115.98,107.37 115.98,107.76 116.05,107.82 116.05,108.28 116.9,109.14 116.9,109.84 116.77,109.97 116.77,110.45 117.04,110.71 117.22,110.71 v2(117.39,110.89)
  IN2 w0.119: v2(24.3,45.78) 24.49,45.97 24.49,47.05 24.79,47.35 24.79,49.15 24.53,49.41 24.53,53.7 27.62,56.79 34.98,56.79 38.71,60.52 38.71,74.7 42.33,78.33 48.48,78.33 48.92,77.89 50.75,77.89 51.05,78.19 58.17,78.19 59.75,79.77 71.32,79.77 72.47,80.92 80.85,80.92 90.33,90.4 93.49,90.4 94.75,91.66 112.61,91.66 114.2,93.25 114.2,94.75 113.96,94.99 113.96,98.43 115.51,99.98 115.51,105.89 115.97,106.34 115.97,107.33
  BOTTOM w0.076: UC1.E25 117.61,110.59 117.39,110.81 v2(117.39,110.89)
  BOTTOM w0.104: JNGFF3.19 24.45,44.52 24.58,44.65 24.58,45.5 v2(24.3,45.78)
PCIE_PRX_DTX_P11: length 178.7
  IN4 w0.094: v2(20.97,50.78) 21.17,50.98 21.17,53.27 27.84,59.94 27.84,65.76 32.3,70.22 32.3,70.81 34.31,72.81 34.31,75.28 34.89,75.86 34.89,78.31 35.49,78.91 35.49,84.13 36.45,85.08 36.45,86.65 36.77,86.97 36.77,87.25 39.67,90.15 39.67,91.36 39.24,91.79 39.24,93.73 38.71,94.26 38.71,97.84 39.56,98.68 39.56,99.8 40.27,100.51 40.65,100.51 40.88,100.74 40.88,102.66 40.35,103.19 40.35,107.01 39.91,107.45 39.91,108.06 40.39,108.54 40.39,109.18 39.77,109.8 39.77,110.93 39.57,111.12 39.57,111.58 39.89,111.9 39.89,112.25 39.36,112.78 39.36,119.45 40.5,120.6 43.89,120.6 46.94,123.64 49.23,123.64 52.74,127.15 64.7,127.15 65.03,126.81 72.14,126.81 73.83,125.13 74.19,125.13 74.38,125.31 75.53,125.31 76.17,124.67 80.99,124.67 83.71,127.39 86.86,127.39 87.44,127.97 97.31,127.97 98.89,126.39 102.79,126.39 111.57,117.61 112.52,117.61 115.82,114.3 115.82,112.2 116.26,111.77 116.26,111.08 v2(116.46,110.88)
  BOTTOM w0.102: UC1.E27 116.67,110.88 v2(116.46,110.88)
  BOTTOM w0.104: v2(20.97,50.78) 21.28,50.47 21.28,50.44 21.45,50.28 21.45,50.04 21.41,50.01 21.41,49.35 21.45,49.31 21.45,49.05 21.6,48.9 21.6,44.71 21.45,44.55 JNGFF3.31
PCIE_PRX_DTX_P12: length 176.8
  IN4 w0.094: v2(19.08,48.84) 18.86,48.63 18.86,48.43 19.14,48.15 21.1,48.15 22.77,49.82 22.77,53.94 28.5,59.66 28.5,65.59 32.88,69.98 32.88,70.57 34.89,72.57 34.89,72.7 34.9,72.72 34.9,74.59 35.47,75.16 35.47,78.04 36.51,79.09 36.51,84.13 37.15,84.76 37.15,86.15 37.56,86.56 39.13,86.56 40.36,87.79 40.36,91.53 39.89,92 39.89,94.01 39.67,94.23 39.67,96.96 40.86,98.15 40.86,99.78 41.47,100.39 41.47,107.35 41.34,107.49 41.34,112.71 43.22,114.59 43.22,117.16 43.99,117.93 43.99,119.67 47.35,123.03 49.44,123.03 52.93,126.52 64.48,126.52 65.39,125.61 70.6,125.61 72.19,124.02 81.22,124.02 83.9,126.7 94.59,126.7 95.55,125.73 102.48,125.73 111.23,116.98 112.26,116.98 115.21,114.03 115.21,110.59 115.03,110.41 114.87,110.41 v2(114.67,110.2)
  BOTTOM w0.102: v2(114.67,110.2) 114.93,109.94 UC1.F30
  BOTTOM w0.104: v2(19.08,48.84) 18.82,48.58 18.82,44.7 18.95,44.56 JNGFF3.41
PCIE_PTX_C_DRX_N1: length 2.7
  TOP w0.104: UR1.4 272.81,65.07 272.71,65.17 272.15,65.17 v4(271.9,65.42) 271.64,65.68 271.36,65.68 CR12.2
PCIE_PTX_C_DRX_N3: length 2.7
  BOTTOM w0.104: JNGFF1.37 232.48,71.65 232.32,71.8 231.23,71.8 CZ13.2
PCIE_PTX_C_DRX_N4: length 2.3
  TOP w0.104: UL1.42 242.83,126.13 242.72,126.23 242.41,126.23 242.12,125.95 241.61,125.95 CL6.2
PCIE_PTX_C_DRX_N5: length 3
  BOTTOM w0.076: UT1.H22 26.09,94.5 26.09,94.06 25.94,93.91 25.94,93.38 26.05,93.27 26.05,93.09 26.06,93.07 26.06,93.05
  BOTTOM w0.104: 26.06,93.05 26.06,92.22 CT126.2
PCIE_PTX_C_DRX_N6: length 3.2
  BOTTOM w0.076: 27.65,93.2 27.64,93.22 27.64,93.24 27.49,93.38 27.49,93.63 27.63,93.76 27.63,93.94 27.49,94.08 27.49,94.51 UT1.M22
  BOTTOM w0.104: 27.65,93.2 28.05,92.8 28.05,92.24 CT124.2
PCIE_PTX_C_DRX_N7: length 3.3
  BOTTOM w0.076: UT1.T22 29.55,94.65 29.32,94.43 29.32,94.06 29.43,93.95 29.43,93.65 29.88,93.2 29.88,93.18 29.9,93.16
  BOTTOM w0.104: CT5.2 30.47,92.24 30.47,92.59 29.9,93.16
PCIE_PTX_C_DRX_N8: length 3.4
  BOTTOM w0.076: UT1.Y22 31.62,94.5 31.62,93.86 31.71,93.77 31.75,93.77 32.04,93.48 32.06,93.48 32.07,93.47
  BOTTOM w0.104: CT3.2 32.95,92.24 32.95,92.59 32.07,93.47
PCIE_PTX_C_DRX_N9: length 3.7
  BOTTOM w0.104: CN65.1 26.33,46.99 26.33,46.57 26.36,46.53 26.36,45.95 26.33,45.91 26.33,44.64 26.45,44.51 JNGFF3.11
PCIE_PTX_C_DRX_N10: length 3.7
  BOTTOM w0.104: CN67.1 23.26,46.92 23.26,46.49 23.3,46.45 23.3,45.87 23.26,45.83 23.26,44.72 23.45,44.53 JNGFF3.23
PCIE_PTX_C_DRX_N11: length 3.9
  BOTTOM w0.104: JNGFF3.35 20.45,44.54 20.3,44.69 20.3,45.2 20.59,45.49 20.59,45.94 20.63,45.98 20.63,46.56 20.59,46.6 20.59,47.06 CN69.1
PCIE_PTX_C_DRX_N12: length 3.9
  BOTTOM w0.104: CN71.1 17.02,47.04 v4(17.02,46.4) 17.02,46.14 17.3,45.86 17.3,44.74 17.45,44.58 JNGFF3.47
PCIE_PTX_C_DRX_P1: length 2.7
  TOP w0.104: CR11.2 271.35,65.87 271.77,65.87 272.28,65.36 272.71,65.36 272.82,65.47 UR1.3
PCIE_PTX_C_DRX_P3: length 2.7
  BOTTOM w0.104: CZ12.2 231.21,72 231.51,72 231.55,72.03 232.13,72.03 232.17,72 232.32,72 232.48,72.15 JNGFF1.35
PCIE_PTX_C_DRX_P4: length 2.3
  TOP w0.104: UL1.41 242.83,126.53 242.73,126.43 242.33,126.43 242.04,126.14 241.63,126.14 CL5.2
PCIE_PTX_C_DRX_P5: length 3
  BOTTOM w0.076: 25.87,93.05 25.87,93.07 25.88,93.09 25.88,93.2 25.78,93.31 25.78,93.95 25.64,94.09 25.64,94.39 25.71,94.46 25.81,94.46 25.87,94.4 UT1.H23
  BOTTOM w0.104: 25.87,93.05 25.87,92.22 CT125.2
PCIE_PTX_C_DRX_P6: length 3.2
  BOTTOM w0.076: 27.79,93.34 27.77,93.35 27.75,93.35 27.66,93.45 27.66,93.56 27.79,93.69 27.79,93.95 27.94,94.1 27.94,94.39 27.88,94.45 27.75,94.45 27.71,94.4 UT1.M23
  BOTTOM w0.104: 27.79,93.34 28.25,92.88 28.25,92.24 CT123.2
PCIE_PTX_C_DRX_P7: length 3.3
  BOTTOM w0.076: UT1.T23 29.55,94.33 29.66,94.44 29.72,94.44 29.79,94.38 29.79,94.09 29.6,93.9 29.6,93.72 30,93.31 30.02,93.31 30.03,93.3
  BOTTOM w0.104: CT4.2 30.66,92.24 30.66,92.67 30.03,93.3
PCIE_PTX_C_DRX_P8: length 3.5
  BOTTOM w0.076: 31.93,93.33 31.92,93.35 31.92,93.37 31.68,93.6 31.64,93.6 31.16,94.09 31.16,94.33 31.24,94.42 31.36,94.42 31.39,94.4 UT1.Y23
  BOTTOM w0.104: 31.93,93.33 32.75,92.51 32.75,92.24 CT2.2
PCIE_PTX_C_DRX_P9: length 3.7
  BOTTOM w0.104: JNGFF3.13 25.95,44.53 26.13,44.71 v4(26.13,46.24) 26.13,47.01 CN66.1
PCIE_PTX_C_DRX_P10: length 3.6
  BOTTOM w0.104: JNGFF3.25 22.95,44.55 23.07,44.67 v4(23.07,46.16) 23.07,46.99 CN68.1
PCIE_PTX_C_DRX_P11: length 3.9
  BOTTOM w0.104: JNGFF3.37 19.95,44.55 20.1,44.7 20.1,45.28 20.4,45.57 v4(20.4,46.27) 20.4,47.01 CN70.1
PCIE_PTX_C_DRX_P12: length 3.9
  BOTTOM w0.104: JNGFF3.49 16.95,44.53 17.1,44.68 17.1,45.78 16.79,46.1 16.79,46.69 16.82,46.73 16.82,47.03 CN72.1
PCIE_PTX_DRX_N1: length 203.8
  TOP w0.104: v2(269.03,65.56) 269.22,65.74 269.6,65.74 CR12.1
  IN1 w0.094: v2(269.03,65.56) 268.87,65.72 268.63,65.72 268.43,65.91 268.43,66.84 270.47,68.88 270.47,72.8 268.3,74.97 266.04,74.97 264.56,76.46 261.85,76.46 260.33,74.94 258.73,74.94 258.05,74.26 255.9,74.26 254.5,72.86 250.62,72.86 249.45,71.69 246.38,71.69 244.15,69.47 234.17,69.47 232.28,71.35 231.52,71.35 231.1,70.93 231.1,69.43 227.36,65.69 185.3,65.69 175.62,75.37 175.62,76.54 168.47,83.68 168.47,86.35 166.42,88.41 166.42,91.05 165.18,92.29 165.18,102.07 162.53,104.72 162.53,106.48 161.64,107.37 160.78,107.37 157.77,110.39 156.67,110.39 155.57,111.49 154.49,111.49 153.03,112.95 147.83,112.95 143.53,117.25 140.45,117.25 138.39,115.19 131.93,115.19 130.96,114.22 125.35,114.22 124.47,115.11 124.47,115.74 124.14,116.07 123.61,116.07 123.56,116.02 v2(123.56,115.89)
  BOTTOM w0.076: UC1.B17 122.81,112.8 122.88,112.88 123.06,112.88 123.28,113.09 123.28,113.66 123.16,113.78 123.16,116.03 123.24,116.1 123.35,116.1 v2(123.56,115.89)
PCIE_PTX_DRX_N3: length 150.5
  IN4 w0.094: v2(122.79,118.41) 122.98,118.23 122.98,117.89 124.47,116.39 124.47,115.29 125.43,114.33 126.98,114.33 128.06,115.42 128.06,116.45 129.13,117.52 129.95,117.52 130.92,118.49 134.6,118.49 135.51,117.58 143.33,117.58 147.96,112.95 150.18,112.95 153.2,109.94 156.74,109.94 158.85,107.83 162.11,107.83 163.39,106.56 163.39,105.6 167.13,101.86 167.13,93.24 169.27,91.1 169.27,90.55 170.22,89.6 170.22,87.68 171.51,86.39 171.51,83.57 185.73,69.35 226.88,69.35 227.95,70.42 227.95,71.44 228.28,71.77 228.75,71.77 v2(228.94,71.58)
  BOTTOM w0.076: 123.03,117.61 123.03,117.59 123.04,117.58 123.04,117.2 122.51,116.66 122.51,113.77 122.38,113.65 122.38,113.14 122.41,113.09 122.41,112.9 122.38,112.8 122.38,112.8 122.38,112.55 122.53,112.03 122.53,111.91 122.59,111.69 UC1.D17
  BOTTOM w0.104: v2(122.79,118.41) 123.03,118.18 123.03,117.61 ; v2(228.94,71.58) 229.16,71.8 229.61,71.8 CZ13.1
PCIE_PTX_DRX_N4: length 212.3
  TOP w0.104: v2(239.61,125.41) 239.49,125.41 239.25,125.66 239.25,125.9 239.32,125.97 240.26,125.97 240.36,125.87 CL6.1
  IN1 w0.094: v2(121.36,115.31) 121.36,115.48 121.55,115.66 121.76,115.66 122.07,115.98 122.07,117 122.75,117.68 126.11,117.68 127.34,116.45 129.73,116.45 129.88,116.6 137.99,116.6 140.04,118.65 144.04,118.65 145.41,117.28 150.9,117.28 154.96,113.23 157.49,113.23 158.61,112.11 160.54,112.11 166.77,105.88 166.77,92.42 167.66,91.52 167.66,88.84 169.68,86.82 169.68,84.18 185.57,68.29 226.88,68.29 228.53,69.94 228.53,72.61 227.04,74.1 227.04,77.25 228.09,78.31 228.09,79.41 231.12,82.44 232.2,82.44 232.83,83.07 232.83,94.54 233.42,95.12 233.42,98.91 234.11,99.6 234.11,113.62 234.26,113.76 234.26,121.84 235.68,123.26 238.9,123.26 239.4,123.76 239.4,125.19 239.61,125.41 v2(239.61,125.41)
  BOTTOM w0.076: UC1.B19 121.46,112.88 121.2,113.14 121.2,114.56 121.75,115.11 121.75,115.36 121.61,115.5 121.55,115.5 v2(121.36,115.31)
PCIE_PTX_DRX_N5: length 157.3
  IN1 w0.094: v2(26.55,90.77) 26.15,90.77 26.01,90.92 26.01,91.27 28.28,93.54 31.59,93.54 32.99,94.95 32.99,100.97 32.63,101.33 32.63,103.81 32.28,104.16 32.28,105.42 32.45,105.6 32.45,106.68 32.05,107.09 32.05,107.6 30.62,109.03 30.62,110.15 31.96,111.49 31.96,111.87 32.76,112.67 33.19,112.67 34.47,113.95 34.47,124.08 37.7,127.32 45.68,127.32 48.21,129.85 48.21,130.74 52.18,134.7 70.27,134.7 76.33,128.63 79.42,128.63 82.49,131.7 82.49,132.88 83.66,134.05 105.32,134.05 110,129.38 113.26,129.38 118.79,123.85 119.4,123.85 119.6,123.65 v2(119.6,123.48)
  BOTTOM w0.076: 121.65,117.61 121.65,117.59 121.66,117.58 121.66,117.16 122.11,116.71 122.11,114.98 121.6,114.48 121.6,113.69 121.75,113.54 121.78,113.35 121.7,113.19 121.7,112.87 121.71,112.83 121.71,112.52 121.61,112.33 121.45,112.33 121.38,112.27 121.38,112.09 UC1.C19
  BOTTOM w0.104: 121.65,117.61 121.65,121.01 120.12,122.54 120.12,123.9 119.98,124.04 119.45,124.04 119.34,123.93 119.34,123.74 v2(119.6,123.48) ; CT126.1 26.09,91.29 26.09,91.08 26.39,90.77 v2(26.55,90.77)
PCIE_PTX_DRX_N6: length 149.8
  IN1 w0.094: v2(119.66,122.03) 119.44,121.82 119.25,121.82 119.14,121.93 119.14,122.93 113.18,128.89 109.75,128.89 105.01,133.63 83.9,133.63 83.01,132.75 83.01,131.66 79.58,128.23 76.11,128.23 71.28,133.06 62.44,133.06 58.75,129.37 48.36,129.37 45.86,126.87 37.91,126.87 34.91,123.87 34.91,113.64 33.41,112.14 33.41,110.86 33.23,110.68 33.23,108.91 33.51,108.63 33.51,107.2 33.15,106.83 33.15,105.62 33.36,105.4 33.36,104.44 33.03,104.1 33.03,101.7 34,100.73 34,95.37 31.15,92.51 28.62,92.51 28.06,91.96 28.06,91.14 v2(27.82,90.89)
  BOTTOM w0.076: 121.2,117.61 121.2,117.59 121.18,117.58 121.18,117.24 121,117.06 121,113.08 121.18,112.89 121.18,112.23 UC1.D20
  BOTTOM w0.104: v2(27.82,90.89) 28.06,91.13 28.06,91.27 CT124.1 ; 121.2,117.61 121.2,120.8 120.16,121.83 119.86,121.83 v2(119.66,122.03)
PCIE_PTX_DRX_N7: length 144.3
  IN1 w0.094: v2(30.29,90.86) 30.54,91.11 30.54,91.42 30.72,91.6 31.7,91.6 32.53,92.44 33.29,92.44 33.76,92.91 33.76,93.84 34.72,94.8 34.72,105.37 34.52,105.57 34.52,107.63 34.23,107.92 34.23,111.97 35.56,113.3 35.56,123.53 38.25,126.22 46.07,126.22 48.28,128.43 58.66,128.43 62.59,132.37 70.94,132.37 75.7,127.61 79.79,127.61 83.62,131.45 83.62,132.49 84.03,132.9 104.5,132.9 109.15,128.25 112.5,128.25 117.58,123.16 117.58,121.63 117.8,121.42 118.25,121.42 v2(118.51,121.68)
  BOTTOM w0.076: UC1.B21 120.61,113.19 120.61,116.33 119.66,117.28 119.66,117.58 119.67,117.59 119.67,117.61
  BOTTOM w0.104: v2(118.51,121.68) 118.74,121.46 118.94,121.46 119.16,121.24 119.16,120.8 119.67,120.29 119.67,117.61 ; v2(30.29,90.86) 30.48,91.05 30.48,91.25 CT5.1
PCIE_PTX_DRX_N8: length 139.3
  IN1 w0.094: v2(118.38,119.36) 118.38,119.54 118.32,119.59 117.36,119.59 116.74,120.22 116.74,122.57 111.83,127.48 108.74,127.48 105.16,131.06 84.32,131.06 80.11,126.85 75.01,126.85 72.26,129.6 66.85,129.6 64.89,127.63 48.57,127.63 46.33,125.39 38.73,125.39 36.35,123 36.35,112.65 35.52,111.83 35.52,109.87 36.12,109.27 36.12,108.65 35.3,107.83 35.3,106.2 35.56,105.95 35.56,94.47 34.62,93.54 34.62,92.58 33.61,91.56 33.03,91.56 32.86,91.39 32.86,90.84 32.94,90.76 v2(33.16,90.76)
  BOTTOM w0.076: UC1.D21 120.11,111.69 120.04,111.96 120.04,112.07 119.9,112.55 119.9,112.8 119.93,112.89 119.93,113.1 119.91,113.18 119.91,113.59 120.06,113.74 120.06,115.91 118.86,117.1 118.86,117.58 118.85,117.59 118.85,117.61
  BOTTOM w0.104: 118.85,117.61 118.85,119.36 118.66,119.55 118.52,119.55 118.38,119.41 v2(118.38,119.36) ; CT3.1 32.92,91.25 32.92,90.82 32.98,90.76 v2(33.16,90.76)
PCIE_PTX_DRX_N9: length 151.1
  IN2 w0.119: v2(25.71,50.02) 25.71,49.54 25.88,49.36 26.9,49.36 33.45,55.91 36.11,55.91 37.91,57.71 38.84,57.71 39.34,58.21 39.34,74.4 42.6,77.66 47.95,77.66 48.38,77.23 51.02,77.23 51.25,77.47 58.44,77.47 60,79.03 71.69,79.03 72.9,80.25 81.1,80.25 90.39,89.53 111.33,89.53 113.44,91.65 114.72,91.65 116.89,93.81 116.89,101.51 117.75,102.37 117.75,103.13 117.29,103.6 117.29,104.75 117.47,104.92 117.47,106.36 118.29,107.19 118.29,108.3 117.56,109.02 117.56,109.78 118.1,110.32 118.1,111.14 118.75,111.78 118.75,115.75 118.5,116 118.27,116 118.15,115.88 v2(118.15,115.76)
  BOTTOM w0.076: v2(118.15,115.76) 118.39,115.99 118.55,115.99 118.62,115.92 118.62,115.24 118.67,115.19 118.67,113.74 118.52,113.59 118.52,113.12 118.73,112.91 118.92,112.91 118.98,112.86 UC1.B23
  BOTTOM w0.104: CN65.2 26.34,48.61 26.34,49.47 26.14,49.67 25.92,49.67 25.71,49.88 v2(25.71,50.02)
PCIE_PTX_DRX_N10: length 156
  IN2 w0.089: v2(117.67,117.6) 117.51,117.43 117.2,117.43 116.94,117.17 116.94,115.44 115.02,113.52 115.02,110.47 115.11,110.39 115.11,109.42 115.05,109.37 115.05,109.08 115.04,109.07 115.04,109.04
  IN2 w0.119: 115.04,109.04 115.04,106.52 114.32,105.8 114.32,100.56 113.38,99.62 113.38,94.97 111.47,93.06 99.11,93.06 98.46,93.71 90.06,93.71 77.93,81.58 72.19,81.58 71.03,80.42 59.35,80.42 58.01,79.08 48.15,79.08 47.1,80.13 42.46,80.13 39.94,77.61 39.94,77.4 38.04,75.5 38.04,64.69 37.65,64.31 37.65,61.65 33.52,57.51 27.3,57.51 22.79,53.01 22.79,49.52 23.11,49.21 23.49,49.21 v2(23.66,49.04)
  BOTTOM w0.076: UC1.D23 119.18,111.77 119.26,111.93 119.26,112.31 119.3,112.35 arc(119.37,112.45) 119.4,112.58 119.4,112.88 119.33,112.95 119.33,113.02 119.4,113.09 119.4,113.57 119.26,113.71 119.26,116.26 118.12,117.41 117.87,117.41 v2(117.67,117.6)
  BOTTOM w0.104: v2(23.66,49.04) 23.66,49.38 23.55,49.49 23.4,49.49 23.27,49.35 23.27,48.6 CN67.2
PCIE_PTX_DRX_N11: length 179
  IN4 w0.094: v2(20.45,49.97) 20.21,49.97 20.16,50.03 20.16,50.79 20.76,51.4 20.76,53.7 27.34,60.29 27.34,65.94 31.81,70.4 31.81,70.88 33.87,72.95 33.87,78.9 34.19,79.22 34.19,83.4 36,85.21 36,86.57 35.74,86.83 35.74,87.27 36,87.54 36.47,87.54 39.15,90.21 39.15,91.22 38.83,91.54 38.83,93.47 38.27,94.02 38.27,98.16 39.15,99.04 39.15,100.06 39.94,100.86 39.94,106.75 39.38,107.31 39.38,107.69 38.92,108.15 38.92,110.98 38.36,111.54 38.36,119.41 40.71,121.75 40.71,122.19 41.58,123.07 44.61,123.07 49.58,128.04 64.85,128.04 65.22,127.67 72.87,127.67 74.77,125.77 79.83,125.77 80.19,125.41 81.13,125.41 83.58,127.86 86.34,127.86 88.02,129.53 96.7,129.53 98.67,127.57 102.21,127.57 111.64,118.15 113.82,118.15 115.78,116.19 115.78,115.28 116.19,114.88 117.14,114.88 117.38,114.63 118.01,114.63 118.06,114.57 v2(118.06,114.39)
  BOTTOM w0.076: UC1.D24 118.42,111.94 118.69,112.22 118.69,112.51 118.3,112.91 118.3,113.62 117.68,114.24 117.68,114.51 117.77,114.6 117.95,114.6 118.06,114.49 v2(118.06,114.39)
  BOTTOM w0.104: v2(20.45,49.97) 20.21,49.74 20.21,49.27 20.57,48.91 20.57,48.64 CN69.2
PCIE_PTX_DRX_N12: length 184.3
  IN4 w0.094: v2(116.44,116.34) 116.44,116.08 116.58,115.94 116.86,115.94 116.95,116.03 116.95,117.12 115.2,118.87 111.79,118.87 110.84,119.82 110.84,121.37 101.73,130.48 87.32,130.48 86.64,129.8 83.98,129.8 80.6,126.43 74.99,126.43 72.72,128.69 49.23,128.69 45.3,124.76 42.18,124.76 40.28,122.86 39.48,122.86 37.71,121.09 37.71,111.35 38.28,110.77 38.28,107.9 38.79,107.4 38.79,107.01 39.25,106.54 39.25,101.69 37.63,100.07 37.63,93.65 38.21,93.07 38.21,91.9 37.73,91.42 37.34,91.42 36.43,90.52 36.43,89.21 35.08,87.86 35.08,86.96 34.67,86.55 33.92,86.55 33.09,85.72 33.09,83.45 33.61,82.93 33.61,79.56 32.12,78.08 32.12,75.04 32.27,74.9 32.27,73.25 31.88,72.86 30.96,72.86 30.51,72.42 30.51,71.05 26.62,67.16 26.62,60.58 20.05,54.01 20.05,51.65 18.39,49.99 17.52,49.99 17.31,49.77 v2(17.31,49.43)
  BOTTOM w0.076: UC1.A25 117.85,113.25 117.78,113.17 117.65,113.17 117.57,113.25 117.57,113.81 117.19,114.19 117.19,115.77 116.96,115.99 116.74,115.99 116.44,116.29 v2(116.44,116.34)
  BOTTOM w0.104: v2(17.31,49.43) 17.31,49.54 17.13,49.71 16.77,49.71 16.7,49.65 16.7,49.4 16.98,49.12 16.98,48.4 17.09,48.3 CN71.2
PCIE_PTX_DRX_P1: length 203.8
  TOP w0.104: v2(269.03,66.14) 269.24,65.93 269.73,65.93 CR11.1
  IN1 w0.094: v2(123.56,116.48) 123.78,116.26 124.21,116.26 124.65,115.82 124.65,115.18 125.43,114.41 130.89,114.41 131.85,115.37 138.32,115.37 140.38,117.43 143.6,117.43 147.91,113.13 153.11,113.13 154.56,111.67 155.64,111.67 156.75,110.57 157.84,110.57 160.85,107.56 161.71,107.56 162.71,106.56 162.71,104.79 165.36,102.15 165.36,92.36 166.6,91.13 166.6,88.48 168.66,86.43 168.66,83.76 175.8,76.61 175.8,75.45 185.38,65.87 227.28,65.87 230.92,69.51 230.92,71.01 231.44,71.53 232.36,71.53 234.24,69.65 244.07,69.65 246.3,71.88 249.38,71.88 250.54,73.04 254.42,73.04 255.83,74.45 257.97,74.45 258.65,75.12 260.25,75.12 261.77,76.64 264.63,76.64 266.12,75.16 268.38,75.16 270.66,72.88 270.66,68.81 268.62,66.77 268.62,65.99 268.7,65.9 268.79,65.9 269.03,66.14 v2(269.03,66.14)
  BOTTOM w0.076: UC1.A17 122.81,113.12 122.88,113.04 122.99,113.04 123.12,113.16 123.12,113.59 123,113.71 123,116.09 123.17,116.27 123.35,116.27 v2(123.56,116.48)
PCIE_PTX_DRX_P3: length 150.5
  IN4 w0.094: v2(123.38,118.41) 123.33,118.41 123.16,118.24 123.16,117.96 124.65,116.47 124.65,115.37 125.51,114.52 126.9,114.52 127.88,115.49 127.88,116.52 129.06,117.7 129.88,117.7 130.85,118.67 134.68,118.67 135.59,117.76 143.41,117.76 148.04,113.14 150.26,113.14 153.28,110.12 156.82,110.12 158.92,108.01 162.19,108.01 163.57,106.63 163.57,105.68 167.32,101.93 167.32,93.32 169.46,91.18 169.46,90.62 170.4,89.68 170.4,87.76 171.7,86.46 171.7,83.65 185.81,69.53 226.8,69.53 227.77,70.5 227.77,71.52 228.21,71.96 228.79,71.96 228.99,72.15 v2(228.99,72.31)
  BOTTOM w0.076: UC1.C17 122.88,111.94 123.01,111.94 123.13,112.06 123.13,112.18 122.98,112.32 122.68,112.32 122.59,112.42 122.54,112.58 122.54,112.77 122.57,112.87 122.57,113.13 122.55,113.18 122.55,113.58 122.67,113.7 122.67,116.59 123.21,117.13 123.21,117.58 123.22,117.59 123.22,117.61
  BOTTOM w0.104: CZ12.1 229.61,71.99 229.19,71.99 228.99,72.2 v2(228.99,72.31) ; v2(123.38,118.41) 123.22,118.26 123.22,117.61
PCIE_PTX_DRX_P4: length 212.3
  TOP w0.104: v2(238.74,125.4) 239.06,125.72 239.06,125.98 239.24,126.16 240.02,126.16 CL5.1
  IN1 w0.094: v2(121.36,116.13) 121.36,115.94 121.46,115.85 121.68,115.85 121.89,116.06 121.89,117.08 122.67,117.86 126.18,117.86 127.42,116.63 129.66,116.63 129.81,116.78 137.91,116.78 139.96,118.83 144.12,118.83 145.48,117.47 150.98,117.47 155.03,113.41 157.57,113.41 158.69,112.29 160.62,112.29 166.95,105.96 166.95,92.49 167.85,91.6 167.85,88.91 169.86,86.9 169.86,84.26 185.65,68.47 226.8,68.47 228.35,70.02 228.35,72.53 226.86,74.02 226.86,77.33 227.91,78.38 227.91,79.49 231.04,82.62 232.13,82.62 232.65,83.14 232.65,94.61 233.23,95.2 233.23,98.98 233.93,99.68 233.93,113.69 234.07,113.84 234.07,121.91 235.6,123.44 238.82,123.44 239.21,123.84 239.21,125.34 239.15,125.4 v2(238.74,125.4)
  BOTTOM w0.076: UC1.A19 121.36,113.41 121.36,114.49 121.92,115.04 121.92,115.42 121.68,115.66 121.43,115.66 121.36,115.73 v2(121.36,116.13)
PCIE_PTX_DRX_P5: length 157.2
  IN1 w0.094: v2(119.63,124.45) 119.63,124.31 119.35,124.03 118.86,124.03 113.34,129.56 110.08,129.56 105.4,134.23 83.59,134.23 82.3,132.95 82.3,131.78 79.34,128.81 76.41,128.81 70.34,134.88 52.1,134.88 48.03,130.81 48.03,129.93 45.6,127.5 37.63,127.5 34.28,124.15 34.28,114.02 33.12,112.86 32.68,112.86 31.78,111.95 31.78,111.57 30.43,110.23 30.43,108.95 31.87,107.52 31.87,107.01 32.27,106.61 32.27,105.67 32.09,105.49 32.09,104.09 32.45,103.73 32.45,101.25 32.81,100.89 32.81,95.02 31.51,93.72 28.2,93.72 25.83,91.35 25.83,90.95 v2(25.63,90.75)
  BOTTOM w0.076: UC1.D19 121.67,111.82 121.78,111.99 121.79,112.3 121.88,112.47 121.88,112.85 121.87,112.89 121.87,113.15 121.96,113.33 121.91,113.62 121.77,113.76 121.77,114.41 122.27,114.91 122.27,116.78 121.83,117.23 121.83,117.58 121.84,117.59 121.84,117.61
  BOTTOM w0.104: CT125.1 25.89,91.23 25.89,90.84 25.81,90.75 v2(25.63,90.75) ; 121.84,117.61 121.84,121.09 120.31,122.62 120.31,123.98 120.06,124.23 119.85,124.23 v2(119.63,124.45)
PCIE_PTX_DRX_P6: length 149.7
  IN1 w0.094: v2(28.53,90.91) 28.25,91.19 28.25,91.88 28.7,92.33 31.23,92.33 34.19,95.29 34.19,100.8 33.21,101.78 33.21,104.03 33.55,104.36 33.55,105.47 33.33,105.69 33.33,106.76 33.69,107.12 33.69,108.7 33.41,108.99 33.41,110.6 33.59,110.78 33.59,112.07 35.09,113.56 35.09,123.79 37.99,126.69 45.94,126.69 48.44,129.19 58.82,129.19 62.51,132.88 71.2,132.88 76.03,128.05 79.66,128.05 83.19,131.58 83.19,132.67 83.97,133.45 104.93,133.45 109.68,128.71 113.1,128.71 118.96,122.85 118.96,121.85 119.17,121.64 119.58,121.64 119.68,121.54 v2(119.68,121.25)
  BOTTOM w0.076: 121.01,117.61 121.01,117.59 121.02,117.58 121.02,117.31 120.83,117.13 120.83,113.01 121.02,112.82 121.02,112.7 120.98,112.67 120.68,112.67 120.58,112.57 120.58,112.4 120.71,112.27 120.82,112.27 UC1.C20
  BOTTOM w0.104: 121.01,117.61 121.01,120.72 120.08,121.64 119.78,121.64 119.6,121.46 119.6,121.33 v2(119.68,121.25) ; v2(28.53,90.91) 28.41,90.91 28.25,91.07 28.25,91.28 CT123.1
PCIE_PTX_DRX_P7: length 144.3
  IN1 w0.094: v2(118.51,120.71) 118.51,121.04 118.32,121.23 117.72,121.23 117.4,121.55 117.4,123.09 112.43,128.06 109.08,128.06 104.42,132.72 84.11,132.72 83.81,132.42 83.81,131.37 79.87,127.43 75.62,127.43 70.87,132.18 62.67,132.18 58.73,128.25 48.36,128.25 46.14,126.04 38.33,126.04 35.74,123.45 35.74,113.23 34.41,111.89 34.41,108 34.7,107.71 34.7,105.65 34.91,105.44 34.91,94.72 33.94,93.76 33.94,92.83 33.36,92.26 32.61,92.26 31.77,91.42 30.8,91.42 30.72,91.35 30.72,91.14 v2(30.99,90.88)
  BOTTOM w0.076: 119.48,117.61 119.48,117.59 119.49,117.58 119.49,117.21 120.44,116.26 120.44,113.65 120.25,113.46 120.25,113.39 UC1.A21
  BOTTOM w0.104: 119.48,117.61 119.48,120.21 118.96,120.72 118.96,121.16 118.86,121.26 118.24,121.26 118.17,121.2 118.17,121.05 v2(118.51,120.71) ; CT4.1 30.68,91.29 30.68,91.19 v2(30.99,90.88)
PCIE_PTX_DRX_P8: length 139.3
  IN1 w0.094: v2(118.34,120.01) 118.11,119.78 117.44,119.78 116.92,120.29 116.92,122.64 111.9,127.66 108.82,127.66 105.24,131.24 84.24,131.24 80.03,127.03 75.09,127.03 72.34,129.78 66.78,129.78 64.82,127.82 48.49,127.82 46.25,125.57 38.66,125.57 36.16,123.08 36.16,112.73 35.34,111.9 35.34,109.79 35.94,109.2 35.94,108.72 35.12,107.91 35.12,106.13 35.38,105.87 35.38,94.55 34.44,93.61 34.44,92.66 33.53,91.75 32.96,91.75 32.67,91.46 32.67,91.08 v2(32.36,90.77)
  BOTTOM w0.076: 119.04,117.61 119.04,117.59 119.03,117.58 119.03,117.17 120.23,115.97 120.23,113.68 120.07,113.52 120.07,113.21 120.09,113.15 120.1,113.14 120.1,112.86 120.06,112.75 120.06,112.58 120.13,112.38 120.18,112.33 120.37,112.33 120.51,112.19 120.51,112.08 120.44,112.01 120.33,112.01 UC1.C21
  BOTTOM w0.104: 119.04,117.61 119.04,119.44 118.74,119.75 118.57,119.75 118.34,119.97 v2(118.34,120.01) ; CT2.1 32.73,91.29 32.73,91.14 v2(32.36,90.77)
PCIE_PTX_DRX_P9: length 151.1
  IN2 w0.119: v2(118.21,116.42) 118.42,116.21 118.59,116.21 118.96,115.84 118.96,111.7 118.31,111.05 118.31,110.23 117.77,109.7 117.77,109.11 118.5,108.38 118.5,107.11 117.67,106.28 117.67,104.83 117.5,104.66 117.5,103.68 117.96,103.22 117.96,102.29 117.09,101.42 117.09,93.73 114.81,91.44 113.53,91.44 111.41,89.32 90.47,89.32 81.19,80.04 72.99,80.04 71.77,78.82 60.09,78.82 58.52,77.26 51.34,77.26 51.1,77.02 48.3,77.02 47.87,77.45 42.69,77.45 39.55,74.31 39.55,58.12 38.92,57.5 38,57.5 36.2,55.7 33.53,55.7 26.98,49.15 25.8,49.15 v2(25.65,49.01)
  BOTTOM w0.076: v2(118.21,116.42) 118.21,116.34 118.4,116.15 118.62,116.15 118.83,115.94 v4(118.83,115.53) 118.83,113.67 118.69,113.52 118.69,113.18 118.79,113.08 118.9,113.08 118.98,113.15 UC1.A23
  BOTTOM w0.104: CN66.2 26.14,48.61 26.14,49.39 26.06,49.48 25.75,49.48 25.65,49.38 v2(25.65,49.01)
PCIE_PTX_DRX_P10: length 156
  IN2 w0.089: 115.25,109.04 115.25,109.07 115.23,109.08 115.23,109.3 115.28,109.35 115.28,110.46 115.19,110.55 115.19,113.45 117.12,115.37 117.12,117.1 117.28,117.26 117.46,117.26 117.67,117.04 v2(117.67,116.84)
  IN2 w0.119: 115.25,109.04 115.25,106.43 114.53,105.72 114.53,100.48 113.59,99.53 113.59,94.89 111.56,92.86 99.02,92.86 98.38,93.5 90.15,93.5 78.02,81.37 72.28,81.37 71.12,80.21 59.44,80.21 58.1,78.88 48.06,78.88 47.01,79.92 42.55,79.92 40.15,77.53 40.15,77.31 38.24,75.41 38.24,64.61 37.86,64.22 37.86,61.56 33.6,57.3 27.38,57.3 23,52.92 23,49.61 23.19,49.42 23.47,49.42 23.64,49.59 v2(23.64,49.97)
  BOTTOM w0.076: UC1.C23 118.86,112.13 118.86,112.3 118.92,112.36 119.08,112.36 119.19,112.47 arc(119.22,112.52) 119.23,112.58 119.23,112.81 119.17,112.88 119.17,113.09 119.23,113.16 119.23,113.5 119.09,113.64 119.09,116.2 118.05,117.24 117.53,117.24 117.38,117.1 117.38,116.99 117.54,116.84 v2(117.67,116.84)
  BOTTOM w0.104: v2(23.64,49.97) 23.64,49.83 23.49,49.68 23.32,49.68 23.07,49.43 23.07,48.54 CN68.2
PCIE_PTX_DRX_P11: length 179
  IN4 w0.094: v2(19.75,49.99) 19.98,50.22 19.98,50.87 20.58,51.47 20.58,53.78 27.16,60.36 27.16,66.02 31.62,70.48 31.62,70.95 33.69,73.02 33.69,78.98 34.01,79.29 34.01,83.47 35.82,85.29 35.82,86.49 35.55,86.76 35.55,87.35 35.93,87.72 36.4,87.72 38.96,90.29 38.96,91.15 38.64,91.47 38.64,93.4 38.09,93.95 38.09,98.24 38.96,99.11 38.96,100.14 39.76,100.93 39.76,106.67 39.19,107.24 39.19,107.62 38.74,108.07 38.74,110.9 38.18,111.46 38.18,119.48 40.52,121.83 40.52,122.27 41.5,123.25 44.53,123.25 49.51,128.22 64.93,128.22 65.3,127.85 72.94,127.85 74.85,125.95 79.91,125.95 80.26,125.6 81.06,125.6 83.5,128.04 86.27,128.04 87.94,129.72 96.78,129.72 98.74,127.75 102.29,127.75 111.71,118.33 113.9,118.33 115.96,116.27 115.96,115.36 116.26,115.06 117.21,115.06 117.46,114.81 117.81,114.81 v2(118.06,115.06)
  BOTTOM w0.076: UC1.C24 118.42,112.29 118.34,112.22 118.21,112.22 118.13,112.29 118.13,112.47 118.27,112.61 118.27,112.7 118.13,112.84 118.13,113.55 117.51,114.18 117.51,114.58 117.7,114.77 117.88,114.77 118.06,114.95 v2(118.06,115.06)
  BOTTOM w0.104: CN70.2 20.37,48.64 20.37,48.83 20.02,49.19 20.02,49.72 v2(19.75,49.99)
PCIE_PTX_DRX_P12: length 184.3
  IN4 w0.094: v2(116.46,115.55) 116.66,115.76 116.94,115.76 117.13,115.95 117.13,117.2 115.28,119.05 111.87,119.05 111.03,119.9 111.03,121.44 101.8,130.67 87.24,130.67 86.56,129.99 83.9,129.99 80.52,126.61 75.06,126.61 72.8,128.88 49.16,128.88 45.22,124.94 42.11,124.94 40.21,123.04 39.4,123.04 37.53,121.17 37.53,111.27 38.1,110.7 38.1,107.83 38.6,107.32 38.6,106.93 39.07,106.47 39.07,101.76 37.45,100.14 37.45,93.57 38.03,92.99 38.03,91.98 37.65,91.6 37.26,91.6 36.25,90.59 36.25,89.28 34.9,87.93 34.9,87.03 34.6,86.73 33.85,86.73 32.91,85.79 32.91,83.37 33.42,82.85 33.42,79.63 31.94,78.15 31.94,74.97 32.09,74.82 32.09,73.33 31.8,73.05 30.88,73.05 30.33,72.49 30.33,71.13 26.43,67.23 26.43,60.65 19.87,54.09 19.87,51.72 18.31,50.17 17.21,50.17 v2(17.17,50.21)
  BOTTOM w0.076: UC1.B25 117.85,112.73 117.4,113.18 117.4,113.74 117.02,114.12 117.02,115.7 116.89,115.83 116.73,115.83 v2(116.46,115.55)
  BOTTOM w0.104: CN72.2 16.79,48.61 16.79,49.04 16.51,49.32 16.51,49.73 16.69,49.91 16.87,49.91 v2(17.17,50.21)
PCIE_RCOMPN: length 3.2
  TOP w0.127: v1(129.96,108.08) 129.29,108.75 v2(129.29,109.68)
  TOP w0.381: RC45.1 129.38,109.58 v2(129.29,109.68)
  BOTTOM w0.254: v2(129.29,109.68) 129.49,109.68 UC1.F5
PCIE_RCOMPP: length 3.3
  TOP w0.127: v2(129.3,110.28) 129.3,110.76 v1(129.56,111.02)
  TOP w0.356: v2(129.3,110.28) 130.19,110.28 130.49,109.98 130.49,109.96 RC45.2
  BOTTOM w0.254: UC1.E5 129.44,110.28 v2(129.3,110.28)
PCIE_WAKE#: length 482
  TOP w0.127: RE275.2 RE274.1 259.93,76.86 v2(259.74,76.67) ; v2(238.94,63.65) 239.39,64.11 239.64,64.11 240.23,64.7 240.23,66.18 239.86,66.55 239.53,66.55 239.28,66.8 239.28,67.42 241.12,69.25 247.89,69.25 v2(248.11,69.03)
  IN1 w0.084: v2(32.68,73.26) 32.68,70.21 23.7,61.22 23.7,56.06 19.11,51.47 13.7,51.47 11.39,49.16 11.39,45.03 13.99,42.43 15.45,42.43 15.7,42.18 JNGFF3.54
  IN2 w0.122: v2(259.74,76.67) 258.56,76.67 257.59,77.63 252.02,77.63 251.27,76.88 250.03,76.88 249.07,77.85 244.79,77.85 244.42,78.22 241.65,78.22 241.07,77.64 238.73,77.64 238.19,77.11 236.61,77.11 v2(234.52,75.01) 233.79,75.01 233.33,74.55 229.45,74.55 227.8,72.9 227.8,71.47 226.49,70.16 225.89,70.16 225.59,69.86 221.88,69.86 220.95,68.92 207.97,68.92 206.64,70.25 188.36,70.25 186.72,71.89 182.68,71.89 173.25,81.32 173.25,83.33 171.23,85.34 171.23,87.09 170.46,87.86 170.46,88.94 169.22,90.17 169.22,92.3 167.61,93.92 167.61,106.93 163.72,110.82 163.72,117.01 164.19,117.48 164.19,120.55 162.65,122.09 162.65,123.55 161.5,124.7 161.5,127.08 159.6,128.98 159.6,130.95 158.8,131.75 156.7,131.75 156.37,132.08 154.32,132.08 153.17,130.93 148.23,130.93 144.21,134.95 127.06,134.95 126.19,134.07 123.8,134.07 123.15,133.42 121.81,133.42 121.15,134.07 115.88,134.07 114.4,132.6 109.69,132.6 109.54,132.75 85.38,132.75 84.27,131.65 83.6,131.65 79.89,127.94 75.98,127.94 75.33,128.59 69.03,128.59 67.88,127.43 61.67,127.43 61.54,127.31 47.46,127.31 46.05,125.89 40.79,125.89 40.44,125.54 37,125.54 35.49,124.03 31.65,124.03 29.44,121.82 29.44,112.69 30.49,111.64 v2(31.27,111.64) 31.28,111.64 31.69,112.05 36.18,112.05 37.98,110.26 37.98,106.43 37.32,105.77 37.32,101.3 36.69,100.68 36.69,92.48 36.41,92.2 36.41,89.24 37.02,88.63 37.02,81.99 37.85,81.16 37.85,79.45 37.57,79.17 36.66,79.17 35.17,77.68 35.17,76.28 32.68,73.8 v2(32.68,73.26)
  IN4 w0.084: v2(259.74,76.67) 256.4,76.67 255.94,76.21 255.94,75.97 255.28,75.3 253.57,75.3 252.95,74.68 252.33,74.68 250.03,72.38 250.03,70.19 248.87,69.03 v2(248.11,69.03)
  BOTTOM w0.076: 31.27,105.53 31.27,105.37 31.09,105.19 31.09,104.77 30.93,104.61 UT1.W1
  BOTTOM w0.127: JNGFF1.70 240.2,63.4 239.85,63.05 239.13,63.05 238.94,63.25 v2(238.94,63.65) ; JNGFF2.46 237.08,98.5 235.36,96.77 235.36,96.32 234.76,95.72 234.76,94.34 233.35,92.93 233.35,91.2 232.49,90.33 v1(232.49,89.9) 232.49,89.7 232.93,89.25 232.93,85.35 233.11,85.17 233.11,82.78 233.34,82.54 235.63,82.54 235.76,82.41 235.76,81.11 234.35,79.7 234.35,75.18 v2(234.52,75.01) 234.97,74.55 234.97,70.64 234.55,70.22 234.55,67.55 234.14,67.15 JNGFF1.55 ; 31.27,105.53 31.27,106.95 30.99,107.23 30.99,107.82 31.46,108.29 31.46,111.45 v2(31.27,111.64)
PCIE_WAKE#_R: length 28.8
  TOP w0.127: RE275.1 v1(262.33,79.08) 262.93,79.69 v2(263.07,79.69) ; UE1.N13 256.73,93.46 258.09,94.81 v2(258.09,95.45) 258.41,95.77 RE35.1
  BOTTOM w0.127: v2(258.09,95.45) 258.63,95.99 259.86,95.99 260.4,96.53 261.19,96.53 262.66,95.06 262.66,85.64 263.29,85.01 264.03,85.01 264.21,84.83 264.21,80.96 263.07,79.82 v2(263.07,79.69)
PD1_GPIO0: length 3.4
  BOTTOM w0.076: UT5.B2 33.77,78.72 33.77,78.32 34.65,77.44 34.69,77.44
  BOTTOM w0.127: RT69.1 35.58,76.54 34.69,77.44
PD1_GPIO2: length 5.4
  TOP w0.127: v2(32.38,84.97) 32.38,84.82 RT71.1 34.4,83.46 v1(34.77,83.83)
  BOTTOM w0.076: 32.27,84.63 32.27,83.22 UT5.D10
  BOTTOM w0.127: v2(32.38,84.97) 32.38,84.97 32.27,84.86 32.27,84.63
PD1_GPIO5: length 3.7
  TOP w0.127: v1(31.95,85.34) 31.57,84.96 v2(31.57,84.92) 32.21,84.28 RT74.1
  BOTTOM w0.076: UT5.E10 31.77,83.22 31.77,84.63
  BOTTOM w0.127: v2(31.57,84.92) 31.77,84.72 31.77,84.63
PD1_GPIO6: length 11.6
  TOP w0.127: v2(34.38,87.27) 34.38,87.55 v1(34.05,87.88)
  IN1 w0.084: v2(30.77,87.58) 30.77,87.83 31.3,88.36 33.28,88.36 34.37,87.27 v2(34.38,87.27)
  BOTTOM w0.076: UT5.G10 30.77,83.22 30.77,83.95 30.01,84.7 30.01,84.97
  BOTTOM w0.127: v2(34.38,87.27) 34.2,87.45 RT75.1 ; v2(30.77,87.58) 30.27,87.58 30.01,87.32 30.01,84.97
PD1_GPIO7: length 3.5
  TOP w0.127: v1(30.45,82.1) 30.61,81.95 31.76,81.95 RT339.1 32.5,81.21 v2(32.99,81.21)
  BOTTOM w0.076: UT5.D7 32.78,81.21 v2(32.99,81.21)
PD1_GPIO8: length 3.5
  TOP w0.127: RT76.1 28.28,79.5 v1(28.28,80.31) 28.57,80.61 RT377.1 30.02,80.61 v2(30.05,80.63)
  BOTTOM w0.076: UT5.H6 30.18,80.63 v2(30.05,80.63)
PD#: length 9.6
  TOP w0.127: UA1.47 260.79,62.14 261.02,62.36 261.02,63.16 261.36,63.51 261.36,64.11 v1(261.72,64.46) 262.34,65.09 262.34,66.05 CA31.1 262.66,66.8 262.99,67.13 RA18.1 262.99,68.12 DA8.2 262.53,68.58 RA48.2 RA50.2
PECI_EC: length 235.8
  TOP w0.127: v2(254.28,97.37) 254.28,96.98 253.97,96.67 RE60.2
  IN2 w0.122: v2(102.54,123.22) 102.82,123.5 118.87,123.5 119.31,123.06 122.3,123.06 v2(123.4,124.16)
  IN3 w0.122: v2(123.4,124.16) 124.44,125.19 128.9,125.19 131.36,122.73 149.79,122.73 152.97,119.55 152.97,101.67 155.98,98.66 160.37,98.66 167.53,91.5 167.53,87.77 187.53,67.78 226.15,67.78 234.63,76.26 234.63,88.99 238.42,92.77 238.42,102.21 240.38,104.18 245.87,104.18 246.47,103.58 253.16,103.58 254.93,101.81 254.93,98.02 v2(254.28,97.37)
  BOTTOM w0.076: UC1.A54 101.74,113.42 101.74,114.64 101.22,115.16 101.22,115.87 101.37,116.03 101.37,117.11 101.18,117.3 101.18,118.82 101.53,119.17
  BOTTOM w0.127: v2(102.54,123.22) 102.54,122.19 101.97,121.62 v1(101.97,120.17) 101.97,119.61 101.53,119.17
PECI_EC_R: length 2.5
  TOP w0.127: RE60.1 253.64,94.83 253.52,94.7 253.52,93.83 UE1.K13
PGOOD_3V: length 56.9
  TOP w0.254: v2(152.17,76.94) v1(151.75,77.35) 151.63,77.47 148.01,77.47 147.79,77.26 147.79,76.77 147.75,76.73 147.75,76.45 147.25,75.94 v2(146.85,75.94)
  IN4 w0.203: v2(146.85,75.94) 147.23,75.56 147.23,70.99 150.54,67.68 157.78,67.68 158.85,66.61 158.85,59.4 159.49,58.76 167.34,58.76 168.21,59.63 173.81,59.63 174.99,58.44 v2(178.82,58.44)
  BOTTOM w0.254: PU100.9 152.42,75.9 152.17,76.15 v2(152.17,76.94) ; PR107.2 179.31,57.67 PR119.1 179.29,57.97 v2(178.82,58.44)
PGOOD_5V: length 2.6
  BOTTOM w0.254: PR120.1 181.09,56.77 PR113.2 182.28,56.77 182.96,56.09 PU102.9
PLTRST_LAN#: length 204.5
  TOP w0.127: v2(160,119.45) v1(159.22,118.67) 158.02,117.47 158.02,116.07 157.2,115.26 157.2,112.21 156.4,111.41 156.4,107.78 v2(156.44,107.73) ; v2(243.56,129.35) 243.67,129.46 243.91,129.46 244.08,129.29 UL1.36
  IN1 w0.084: v2(156.44,107.73) 157.48,107.73 158.29,106.92 158.29,106.39 158.91,105.77 159.96,105.77 164.18,101.55 164.18,91.82 165.44,90.57 165.44,87.96 167.47,85.93 167.47,83.21 174.51,76.17 174.51,73.98 184.57,63.92 227.06,63.92 227.49,64.36 229.2,64.36 v2(229.69,63.87)
  IN4 w0.084: v2(229.69,63.87) 232.39,63.87 233.12,64.59 235.48,64.59 238.03,67.15 238.03,67.79 239.01,68.76 239.95,68.76 241.68,70.5 241.68,74.97 241.43,75.23 241.43,78.39 240.29,79.53 240.29,80.3 239.73,80.87 239.73,83.15 239.36,83.52 236.51,83.52 235.86,84.17 235.86,88.87 239.18,92.19 239.18,92.82 240.42,94.06 240.42,96.48 244.73,100.79 244.73,104.88 240.04,109.56 240.04,113.12 238.81,114.35 238.81,116.83 239.61,117.63 239.61,122.09 240.41,122.9 240.41,127.57 241.31,128.47 242.68,128.47 v2(243.56,129.35)
  BOTTOM w0.127: RC62.2 v2(160,119.45)
PLTRST_TPM#: length 14.1
  TOP w0.127: v2(161.05,106.62) 161.05,114.22 v1(160.6,114.67) 158.45,116.82 v2(158.45,116.96)
  BOTTOM w0.127: v2(158.45,116.96) 158.85,117.36 RC325.2 RC60.2 ; v2(161.05,106.62) 160.83,106.84 UZ12.17
PM_LANPHY_ENABLE: length 241.7
  TOP w0.127: RL7.1 242.01,118.84 242.55,118.3 242.55,117.7 v1(240.74,115.89) 239.93,115.08 v2(239.93,114.79)
  IN2 w0.122: v2(141.82,77.44) 142.62,77.44 143.07,76.99 143.07,76.18 144.51,74.74 144.51,73.4 150.44,67.47 157.25,67.47 160.47,64.25 165.01,64.25 165.17,64.09 170.25,64.09 172.35,62 178.84,62 179.23,61.61 183.89,61.61 184.4,61.1 201.73,61.1 204.8,58.03 204.8,57.8 205.25,57.35 208.76,57.35 208.95,57.54 216.41,57.54 216.42,57.55 216.42,57.55 216.85,57.98 222.1,57.98 222.33,57.75 228.11,57.75 228.84,58.49 232.45,58.49 233.2,57.74 235.21,57.74 236.06,58.58 240.03,58.58 240.31,58.86 242.64,58.86 243.78,60 243.78,61.27 245.79,63.28 245.79,64.2 248.39,66.8 248.92,66.8 249.45,67.33 251.42,67.33 252.94,68.85 254.7,68.85 255.08,68.47 255.77,68.47 256.91,67.33 259.44,67.33 260.49,68.38 260.58,68.38 261.99,69.79 261.99,71.15 265.86,75.02 265.86,78.45 266.59,79.18 266.59,82.42 265.72,83.29 265.34,83.29 265,83.63 265,86.3 264.66,86.64 264.66,87.74 263.79,88.6 263.79,92.02 262.91,92.9 262.91,94.61 264.81,96.51 264.81,97.81 262.81,99.81 262.81,101.71 262.15,102.37 261.9,102.37 259.05,105.22 256.32,105.22 254.93,106.61 245.98,106.61 244.69,107.9 244.69,108.39 239.93,113.15 v2(239.93,114.79)
  BOTTOM w0.076: UC1.AW17 122.53,92.5 122.28,91.67 122.28,91.58 122.23,91.42 122.23,91.28 122.29,91.06 122.29,90.94 122.24,90.83 122.24,90.46 122.44,90.27 122.44,88.7 123.87,87.26 123.87,87.16
  BOTTOM w0.127: 123.87,87.16 123.87,85.71 126.64,82.94 126.64,80.69 130.08,77.25 139.97,77.25 140.42,76.8 140.95,76.8 141.59,77.44 v2(141.82,77.44)
PME#: length 2.8
  TOP w0.127: v2(125.66,93.44) 125.27,93.84 125.27,95.07 125.08,95.26 T115.1
  BOTTOM w0.076: v2(125.66,93.44) 125.66,93.5 125.97,93.8 UC1.AU11
POA_WAKE#: length 43.3
  TOP w0.127: v2(246.25,76.49) 246.21,76.45 RE324.1 ; UE1.E4 v2(249.48,85.86) ; RZ364.1 232.94,58.57 v2(233.32,58.2) 233.32,57.86 v1(233.69,57.49)
  IN4 w0.084: v2(249.48,85.86) 249.08,85.46 249.08,84 247.69,82.6 247.69,81.24 248.06,80.86 248.06,78.84 246.67,77.44 246.67,76.91 v2(246.25,76.49) 246.25,76.03 247.19,75.09 247.19,70.11 247.02,69.94 247.02,67.35 243.21,63.54 243.21,60.18 241.23,58.2 v2(233.32,58.2)
POA_WAKE#_R: length 2.8
  TOP w0.127: RZ364.2 232.03,59.83 v2(232.26,60.06) 232.5,60.06 v1(232.74,60.3)
  BOTTOM w0.127: v2(232.26,60.06) 231.95,59.75 JUSH1.4
POWER_SW#_MB: length 132.8
  TOP w0.127: v2(239.48,83.91) 239.93,83.46 239.93,82.05 v3(240,81.98) 240.54,81.44 242.5,81.44 242.85,81.1 242.85,80.06 CE10.1 RE33.2 ; JAPS1.11 v2(259.56,109.36) ; SW3.2 292.19,126.02 v2(292.19,123.96) 292.19,122.78 SW3.4
  IN1 w0.084: v2(239.48,83.91) 238.68,83.91 238.11,84.48 238.11,87.94 238.7,88.53 238.7,93.1 240.54,94.94 240.54,111.98 238.71,113.8 v2(237.74,113.8) ; v2(292.19,123.96) 290.98,122.76 289.65,122.76 289.25,123.15 289.25,124.55 285.9,127.9 258.96,127.9 253.05,121.98 253.05,117.26 259.56,110.75 v2(259.56,109.36)
  BOTTOM w0.127: v2(259.56,109.36) 259.13,109.79 257.7,109.79 257.09,109.18 254.47,109.18 253.83,108.55 251.47,108.55 250.91,109.1 244.5,109.1 242.94,110.66 242.94,111.42 240.55,113.8 v2(237.74,113.8)
POWER_SW_IN#: length 15.4
  TOP w0.127: CE12.1 RE31.2 RE33.1 242.66,77.72 v2(242.53,77.6) 242.35,77.77 v1(242.35,78.13) ; UE1.D5 v2(248.68,86.66)
  IN1 w0.084: v2(248.68,86.66) 248.28,86.26 248.28,84.58 242.53,78.83 v2(242.53,77.6)
PROCHOT#: length 411.5
  TOP w0.127: RE288.2 252.07,96.67 251.8,96.94 v2(251.8,97.27) ; v2(242.72,94.74) 242.21,94.23 v1(241,94.23) 240.35,94.23 239.09,92.97 236.8,92.97 236.05,93.72 235.26,93.72 228.64,87.1 228.07,87.1 227.42,86.45 v2(227.42,84.97) ; PR926.1 v2(50.56,55.01) ; v2(137.83,88.49) 139.19,88.49 140.04,87.64 142.43,87.64 142.68,87.88 142.76,87.9 145.14,87.9 147.95,90.7 151.37,90.7 151.69,91.02 154.38,91.02 154.69,90.7 158.21,90.7 158.69,90.22 163.25,90.22 167.51,85.96 167.51,81.43 166.8,80.72 166.35,80.72 166.05,80.42 166.05,80.05 166.36,79.74 v2(166.93,79.74)
  IN1 w0.084: v2(88.23,120.37) 87.14,120.37 86.38,119.61 80.1,119.61 79.59,120.12 71.24,120.12 71.1,120.26 71.1,120.29 70.05,121.34 62.76,121.34 62.58,121.52 60.63,121.52 60.45,121.34 52.61,121.34 50.31,119.04 48.28,119.04 43.12,113.88 43.12,111.66 42.69,111.23 42.69,109.36 43.12,108.93 43.12,108.16 42.44,107.48 42.44,102.24 43.38,101.31 43.38,99.78 40.83,97.24 40.36,97.24 39.88,96.76 39.88,94.54 40.99,93.44 40.99,93.05 40.79,92.85 40.79,92.14 41.54,91.39 42.63,91.39 43.9,92.66 v2(44,92.66) ; v2(137.83,88.49) 139.22,87.1 139.22,86.43 140.6,85.04 141.31,85.04 143.84,82.51 143.84,80.2 143.26,79.63 143.26,76.42 141.88,75.04 84.41,75.04 80.03,79.42 v2(73.14,79.42) 55.48,79.42 54.4,80.5 52.14,80.5 47.9,84.74 v2(47.2,84.74) ; v2(214.28,71.56) 215.62,71.56 216.9,72.85 221.9,72.85 224.41,75.36 224.41,80.85 226.97,83.41 226.97,84.53 v2(227.42,84.97) ; v2(72.92,71.96) 72.92,67.85 70.91,65.84 70.91,63.3 71.77,62.44 71.77,57.84 71.41,57.48 69.72,57.48 69.35,57.84 65.86,57.84 65.58,58.13 62.91,58.13 62.51,57.74 62.51,56.65 60.11,54.25 54.21,54.25 52.97,55.48 51.03,55.48 v2(50.56,55.01)
  IN2 w0.122: v2(242.72,94.74) 243.16,94.74 244.37,95.95 247.15,95.95 249.06,97.86 251.21,97.86 v2(251.8,97.27)
  IN4 w0.084: v2(72.92,71.96) 72.92,74.88 72.46,75.33 72.46,78.15 73.14,78.83 v2(73.14,79.42)
  BOTTOM w0.127: v2(166.93,79.74) 166.93,80.39 167.64,81.11 172.5,81.11 188.86,64.75 208.08,64.75 214.28,70.95 v2(214.28,71.56) ; RC83.1 CC310.1 RC84.1 v2(88.23,120.37) ; PC605.2 PR678.1 45.08,93.48 44.26,92.66 v2(44,92.66) 43.92,92.57 43.92,90.9 44.77,90.05 44.77,88.83 47.2,86.4 v2(47.2,84.74)
PROCHOT#_ISL9538: length 16.4
  TOP w0.127: PR926.2 v2(51.47,55.08) v1(51.47,54.42) 51.54,54.35 52.67,54.35 53.62,55.31 53.62,55.61 54.04,56.04 PU901.23
  IN2 w0.122: v2(51.47,55.08) 51.95,54.6 58.1,54.6 58.85,53.85 v2(58.85,51.42)
  BOTTOM w0.127: v2(58.85,51.42) 58.95,51.32 PQ1216.1
PROCHOT#_R: length 12.3
  BOTTOM w0.076: UC1.C65 95.37,112.32 95.28,112.58 95.28,112.75 95.34,112.94 95.34,113.09 95.28,113.21 95.28,113.47 95.4,113.58 95.4,114.29 94.74,114.95 94.74,115.78
  BOTTOM w0.127: 94.74,115.78 93.9,116.62 92.68,116.62 92.49,116.43 90.36,116.43 v1(89.05,117.74) 88.23,118.57 RC84.2
PROCHOT#_R1: length 2.3
  TOP w0.127: UE1.H13 252.28,95.72 RE288.1
PS_ID: length 314.7
  TOP w0.127: UE1.J8 v2(253.48,89.86) ; v2(40.14,118.79) 40.2,118.73 v1(42.44,118.73) 43.17,118.73 43.71,119.27 43.71,120.08 43.2,120.59 PR5.2 PR4.1
  IN2 w0.122: v2(253.48,89.86) 254.22,89.13 256.01,89.13 256.85,88.28 256.85,86.59 257.52,85.92 257.52,85.42 260.7,82.24 260.7,79.92 262.38,78.24 262.38,76.91 260.53,75.07 258.72,75.07 256.85,76.94 252.91,76.94 252.18,76.21 249.33,76.21 248.38,75.27 245.73,75.27 244.25,76.75 241.83,76.75 241.14,76.06 237.84,76.06 235.86,74.09 235.86,72.94 234.91,71.99 233.75,71.99 233.48,72.26 230.58,72.26 227.58,69.26 226.29,69.26 225.7,68.67 222.58,68.67 221.9,67.99 207.53,67.99 206.17,69.36 187.99,69.36 186.35,71 182.21,71 178.39,74.82 177.41,74.82 176.95,75.28 176.95,75.81 172.07,80.69 172.07,82.86 170.08,84.85 170.08,86.52 168.18,88.42 168.18,89.57 167.49,90.25 167.49,92.33 166.4,93.42 166.4,106.33 162.59,110.15 162.59,117.43 162.27,117.75 162.27,120.64 159.2,123.7 159.2,128.23 156.59,130.84 155.24,130.84 154.52,130.12 147.84,130.12 145.19,132.78 143.04,132.78 141.88,133.93 136.42,133.93 134.97,132.48 128.62,132.48 128.06,133.05 125.91,133.05 124.63,131.76 116.07,131.76 115.4,131.09 86.05,131.09 85.56,130.61 83.87,130.61 80.19,126.93 75.19,126.93 74.75,127.37 69.21,127.37 68.25,126.41 62.34,126.41 60.77,124.84 50.19,124.84 48.96,126.07 47.52,126.07 46.28,124.84 41.63,124.84 39.74,122.95 39.37,122.95 39.01,122.59 39.01,119.92 v2(40.14,118.79)
PWM1_IA: length 22.9
  TOP w0.203: v2(51.46,92.51) 51.2,92.77 PU602.12
  IN3 w0.254: v2(51.46,92.51) 51.81,92.51 53.69,94.39 53.69,99.54 54.43,100.28 55.65,100.28 56.4,101.03 60.78,101.03 61.94,102.18 63.37,102.18 v2(63.5,102.31)
  BOTTOM w0.127: v1(52.77,92.9) 52.38,92.51 v2(51.46,92.51)
  BOTTOM w0.254: v2(63.5,102.31) 62.95,102.31 62.71,102.55 PR687.1
PWM2_IA: length 4
  TOP w0.203: v2(51.66,93.06) 51.55,93.17 PU602.13
  BOTTOM w0.254: v2(51.66,93.06) 52,93.06 52.44,93.49 v1(52.44,94.23) 52.44,94.93 PR692.1
PWM_FAN1: length 59.4
  TOP w0.127: UE1.L10 v2(255.08,91.46) ; v2(238.03,121.11) 237.69,121.11 237.17,120.59 237.17,118.99 237.56,118.6 v1(237.56,117.1) 237.56,116.08 239.31,114.33 253.14,114.33 254.57,112.9 v2(254.57,112.45)
  IN2 w0.122: v2(238.03,121.11) 238,121.11 236.4,122.72 236.4,125.58 236.93,126.1 v2(237.51,126.1)
  IN4 w0.084: v2(254.57,112.45) 254.57,111.72 254.13,111.28 254.13,106.14 251.22,103.24 251.22,96.79 252.15,95.87 253.11,95.87 254.7,94.27 254.7,92.89 254.71,92.89 254.71,91.83 v2(255.08,91.46)
  BOTTOM w0.127: v2(238.03,121.11) 237.73,121.41 JFAN1.2 ; RE48.2 237.46,126.15 v2(237.51,126.1)
PWM_GT: length 6.5
  TOP w0.203: PU602.22 49.53,97.11 49.92,97.5 50.19,97.5 v1(50.53,97.84) 50.83,98.13 50.83,98.45 51.35,98.97 51.94,98.97 52.95,99.98 52.95,100.46 53.4,100.91 PR664.1
PWM_SA: length 2.5
  BOTTOM w0.127: PR606.2 v1(58.63,115.52)
  BOTTOM w0.254: PR606.2 58.88,114.55 59.06,114.73 59.44,114.73 59.61,114.56 PU614.3
PWM_VSA: length 31.6
  TOP w0.203: PU602.30 46.33,97.52 46.02,97.83 45.89,97.83 v2(45.86,97.86)
  IN1 w0.254: v2(53.78,115.89) 49.41,115.89 47,113.48 47,108.62 48.49,107.13 48.49,103.71 48.13,103.35 47.55,103.35 46.8,102.6 46.8,100.11 45.69,99 45.69,98.27 45.86,98.1 v2(45.86,97.86)
  BOTTOM w0.254: PR606.1 55.12,114.55 v2(53.78,115.89)
REM_DIODE1_N: length 208.6
  TOP w0.127: UE1.A8 246.41,89.18 245.01,89.18 244.86,89.33 244.35,89.33 CE24.1 243.7,89.26 238.87,89.26 237.55,87.95 237.55,87.4 236.94,86.78 234.8,86.78 233.01,84.99 233.01,84.29 232.99,84.26 232.14,84.26 v2(231.98,84.43) ; v2(118.33,101.03) 118.34,101.05 CE35.1 118.66,100.63 118.05,100.63 117.64,101.03 116.04,101.03 QE3.3
  IN4 w0.127: v2(118.33,101.03) 117.93,101.44 117.75,101.44 115.96,99.64 114.95,99.64 114.55,100.05 113.77,100.05 113.45,99.73 113.45,99.03 113.88,98.61 113.88,94.76 115.26,93.37 120.08,93.37 121.78,91.68 125.77,91.68 129.23,88.22 132.79,88.22 139.29,81.71 139.29,78.5 138.94,78.15 138.94,76.91 142.34,73.5 142.34,70.31 144.72,67.93 144.72,66.01 144.25,65.54 144.25,65.07 144.68,64.65 144.68,59.76 145.05,59.38 145.47,59.38 146.63,58.22 146.63,57.33 148.85,55.1 159.54,55.1 160.06,54.58 174.3,54.58 174.82,55.1 178.8,55.1 179.93,53.97 181.89,53.97 183.4,52.46 185.81,52.46 187.44,50.83 209.31,50.83 210.23,51.75 212.88,51.75 213.41,51.22 219.5,51.22 219.78,51.49 219.78,51.84 v2(219.61,52.01)
  BOTTOM w0.127: v2(219.61,52.01) 219.74,52.14 219.74,53.41 219.85,53.52 219.85,57.16 219.63,57.38 219.63,68.48 221.09,69.94 221.09,72.22 226.82,77.95 226.82,79.2 228.22,80.59 229.03,80.59 230.82,82.38 230.82,83.7 231.36,84.25 231.79,84.25 v2(231.98,84.43)
REM_DIODE1_P: length 209.6
  TOP w0.127: QE3.2 116.68,101.69 QE3.1 118.81,101.69 CE35.2 118.81,102.23 v2(118.47,102.23) ; v2(231.98,83.84) 232.14,84.01 233.09,84.01 233.27,84.18 233.27,84.89 234.91,86.53 237.04,86.53 237.81,87.3 237.81,87.84 238.98,89.01 243.75,89.01 CE24.2 244.42,89.08 244.76,89.08 244.91,88.93 246.41,88.93 UE1.A7
  IN4 w0.127: v2(118.47,102.23) 117.93,101.69 117.65,101.69 115.85,99.9 115.06,99.9 114.65,100.3 113.67,100.3 113.2,99.84 113.2,98.93 113.63,98.5 113.63,94.65 115.16,93.12 119.98,93.12 121.68,91.42 125.66,91.42 129.12,87.96 132.68,87.96 139.03,81.61 139.03,78.61 138.68,78.26 138.68,76.8 142.09,73.39 142.09,70.21 144.47,67.83 144.47,66.12 144,65.65 144,64.96 144.42,64.54 144.42,59.65 144.95,59.13 145.36,59.13 146.37,58.11 146.37,57.22 148.75,54.85 159.43,54.85 159.95,54.33 174.4,54.33 174.92,54.85 178.69,54.85 179.83,53.72 181.78,53.72 183.29,52.21 185.7,52.21 187.34,50.57 209.41,50.57 210.34,51.5 212.77,51.5 213.31,50.96 219.61,50.96 220.03,51.39 220.03,51.85 v2(220.19,52.01)
  BOTTOM w0.127: v2(220.19,52.01) 220,52.2 220,53.31 220.1,53.42 220.1,57.27 219.89,57.48 219.89,68.37 221.34,69.83 221.34,72.11 227.08,77.85 227.08,79.09 228.32,80.34 229.13,80.34 231.07,82.28 231.07,83.6 231.47,83.99 231.83,83.99 v2(231.98,83.84)
REM_DIODE2_N: length 151.4
  TOP w0.127: v2(237.82,78.73) 237.68,78.87 CE37.2 237.01,78.75 235.38,78.75 234.98,79.15 234.5,79.15 QE5.3 ; UE1.A10 246.41,90.78 243.4,90.78 CE26.1 242.75,90.73 241.77,90.73 241.44,90.4 238.66,90.4 237.93,89.67 237.82,89.67 v2(237.66,89.84)
  IN1 w0.127: v2(237.66,89.84) 237.5,89.67 236.11,89.67 235.09,88.65 235.09,80.03 236.22,78.9 237.65,78.9 v2(237.82,78.73)
  IN4 w0.127: v2(227.06,51.51) 226.89,51.33 226.89,50.16 226.21,49.49 186.62,49.49 185.1,51.01 183.24,51.01 181.41,52.83 178.49,52.83 177.59,53.73 175.66,53.73 174.99,53.06 159.18,53.06 158.38,53.87 155.57,53.87 155.3,53.6 155.3,53.47 v2(155.45,53.33)
  BOTTOM w0.127: v2(237.82,78.73) 237.69,78.86 237.17,78.86 236.91,78.6 236.91,70.8 237.63,70.08 237.63,65.59 236.93,64.89 236.93,63.17 237.21,62.89 237.21,61.26 237.72,60.75 237.72,59.86 234.59,56.72 234.59,55.59 233.25,54.25 233.25,52.85 232.36,51.96 227.05,51.96 226.89,51.81 226.89,51.68 v2(227.06,51.51) ; v2(155.45,53.33) 155.28,53.49 155.28,53.74 152.68,56.34 152.21,56.34 151.81,56.74 151.81,57.01 151.46,57.36 CE46.2 150.47,57.36 QE7.2 149.86,57.98 149.86,59.23 QE7.1
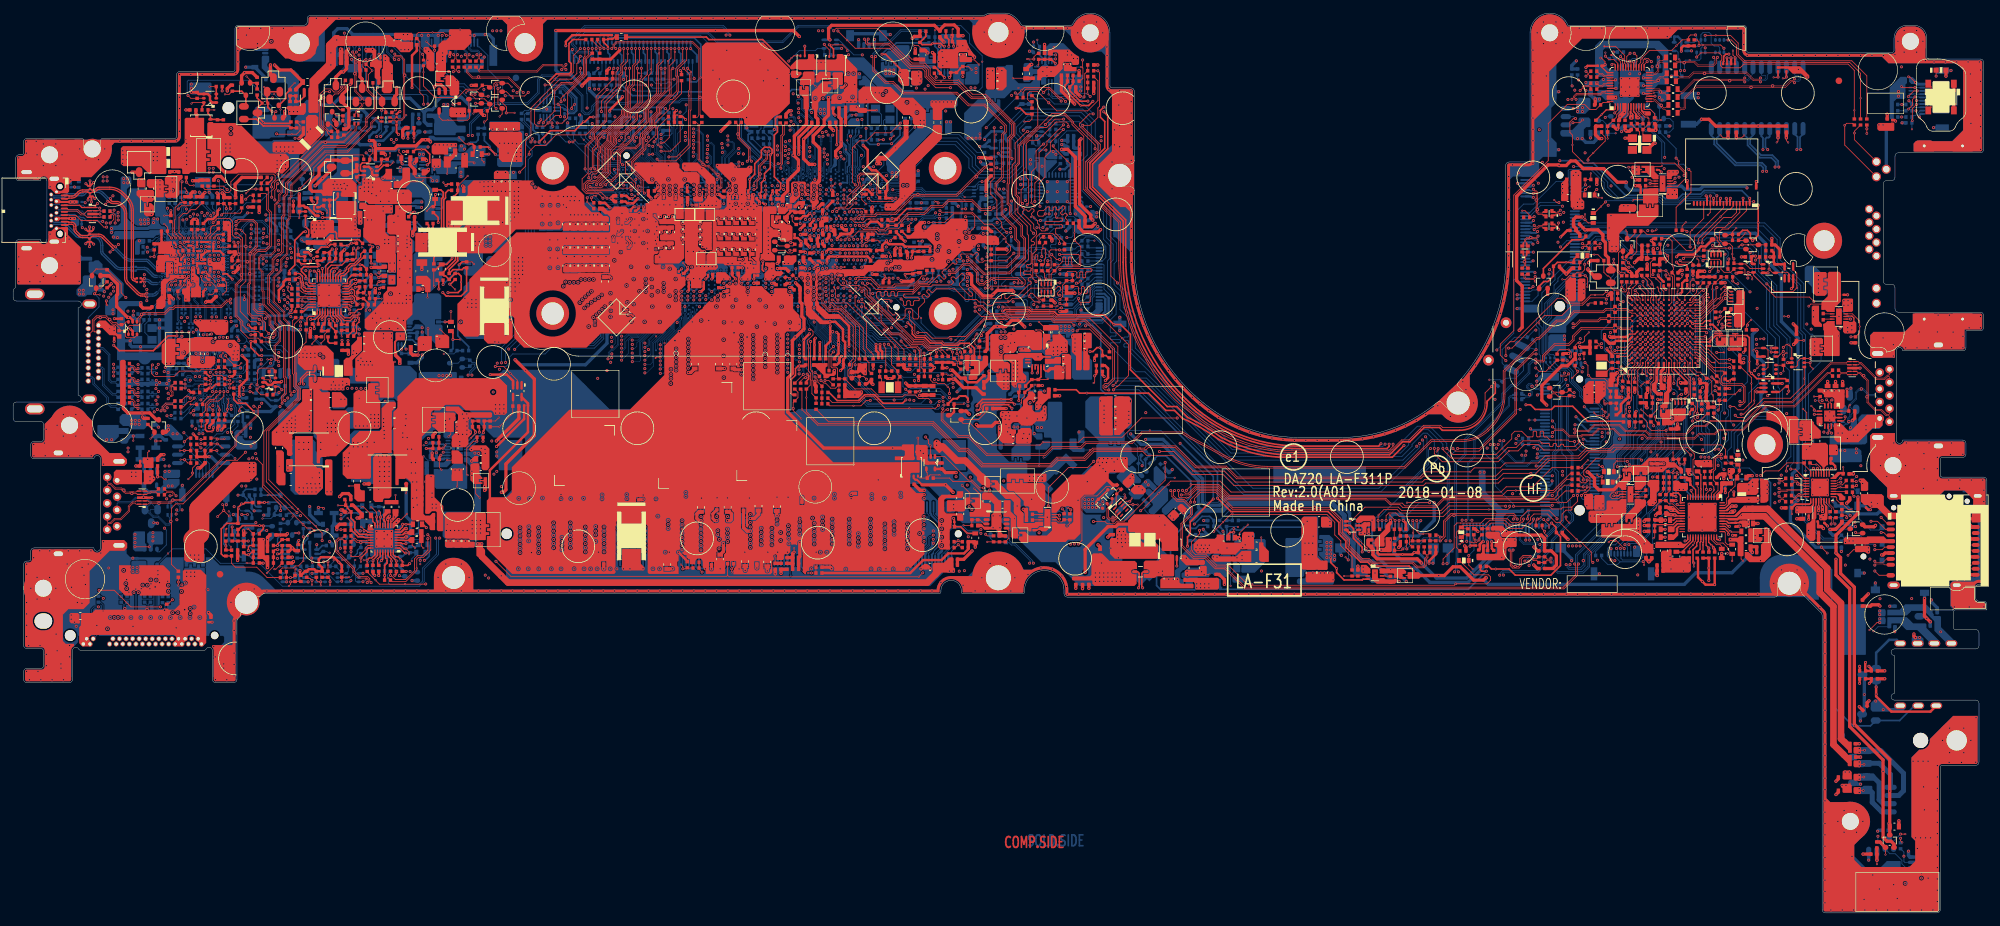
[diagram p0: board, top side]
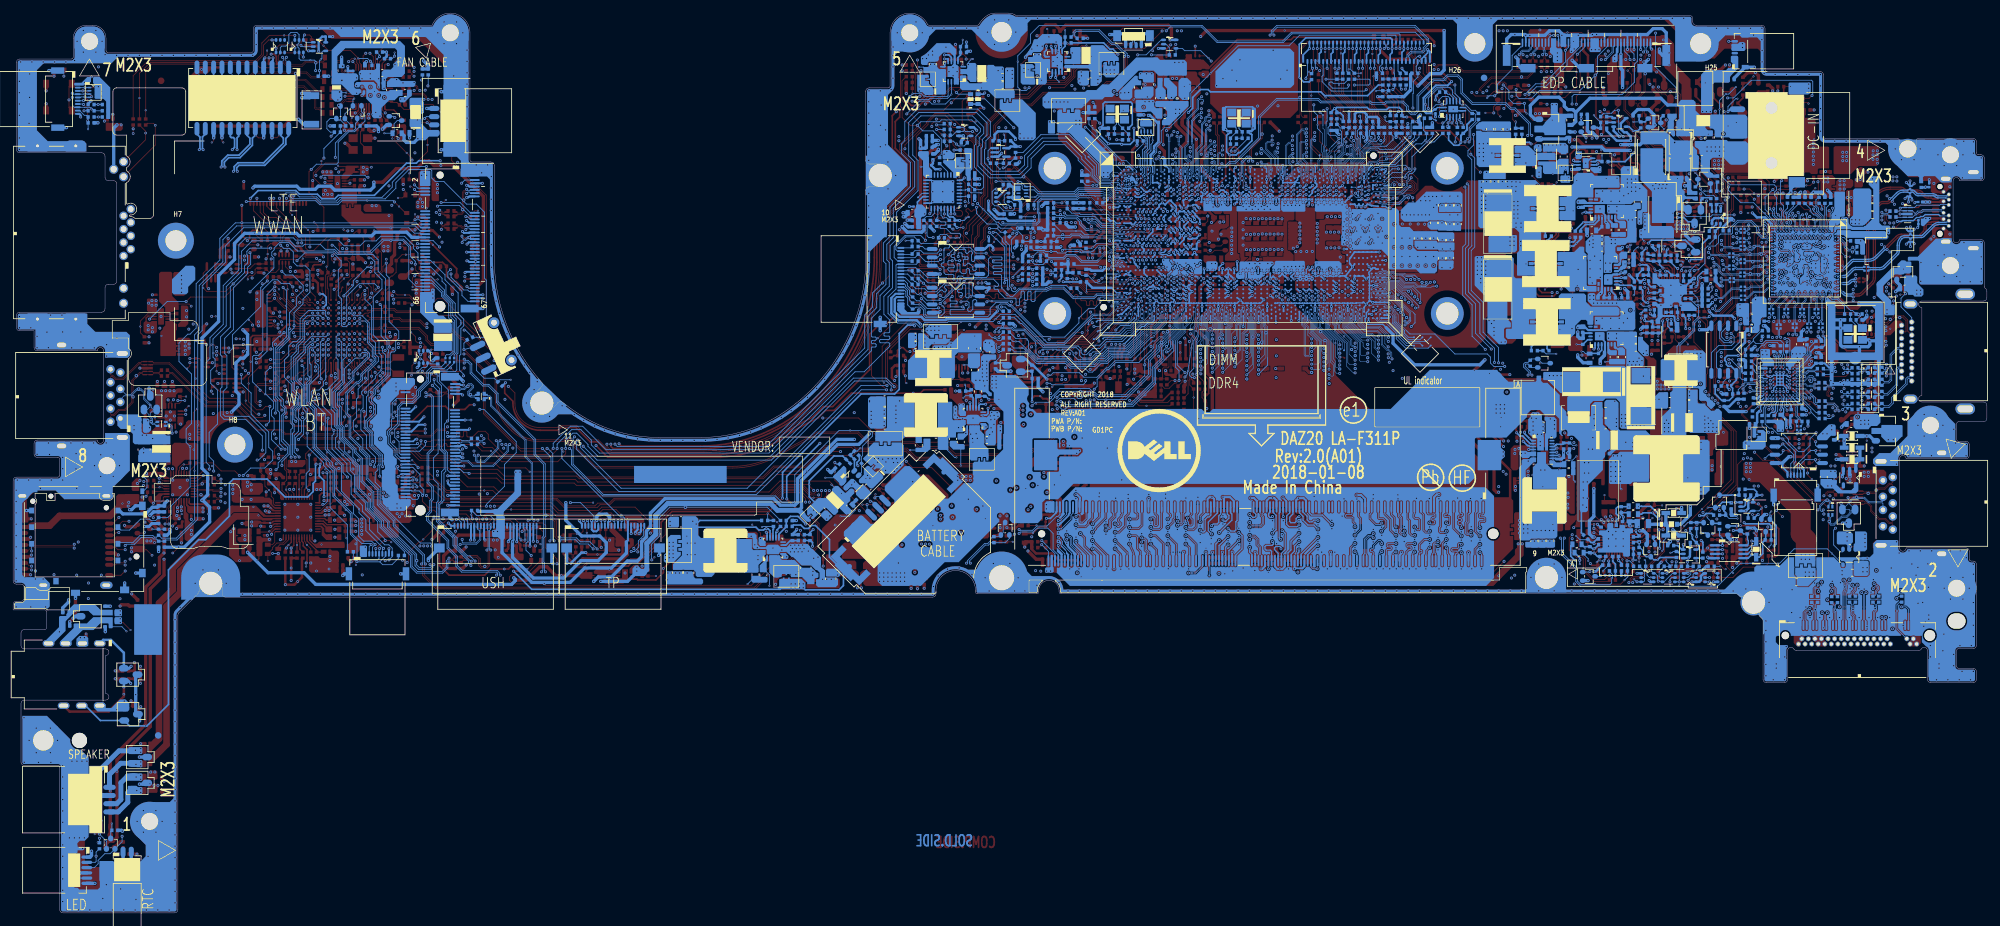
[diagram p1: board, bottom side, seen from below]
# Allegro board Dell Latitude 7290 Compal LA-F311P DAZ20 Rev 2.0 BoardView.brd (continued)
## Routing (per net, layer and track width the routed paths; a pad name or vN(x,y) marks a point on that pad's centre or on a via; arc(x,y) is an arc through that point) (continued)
REM_DIODE2_P: length 150.2
  TOP w0.127: QE5.2 234.72,79.4 235.09,79.4 235.1,79.39 QE5.1 236.74,79.39 CE37.1 237.59,79.32 v2(237.82,79.32) ; UE1.A9 246.41,90.53 243.46,90.53 CE26.2 242.79,90.48 241.88,90.48 241.54,90.15 238.76,90.15 238.03,89.42 237.82,89.42 v2(237.66,89.25)
  IN1 w0.127: v2(237.66,89.25) 237.49,89.42 236.22,89.42 235.34,88.54 235.34,80.13 236.32,79.15 237.65,79.15 v2(237.82,79.32)
  IN4 w0.127: v2(226.48,51.5) 226.63,51.34 226.63,50.27 226.11,49.74 186.72,49.74 185.21,51.26 183.34,51.26 181.52,53.08 178.6,53.08 177.7,53.99 175.56,53.99 174.89,53.31 159.29,53.31 158.48,54.12 155.46,54.12 155.05,53.71 155.05,53.51 v2(154.86,53.33)
  BOTTOM w0.127: QE7.3 148.92,57.1 149.57,56.45 CE46.1 151.74,56.45 152.1,56.09 152.57,56.09 155.03,53.63 155.03,53.49 v2(154.86,53.33) ; v2(226.48,51.5) 226.64,51.66 226.64,51.91 226.94,52.21 232.26,52.21 233,52.95 233,54.36 234.33,55.7 234.33,56.83 237.47,59.96 237.47,60.65 236.96,61.16 236.96,62.78 236.67,63.07 236.67,64.99 237.38,65.7 237.38,69.97 236.66,70.69 236.66,78.71 237.06,79.11 237.61,79.11 v2(237.82,79.32)
REM_DIODE4_N: length 206
  TOP w0.127: UE1.A11 246.26,91.86 245.95,92.16 244.37,92.16 CE27.1 243.74,92.16 242.6,92.16 242.22,91.78 237.76,91.78 236.36,90.38 235.1,90.38 232.46,87.74 232.1,87.74 227.02,82.66 227.02,79.09 arc(226.55,76.43) 225.07,74.18 224.66,73.78 arc(224.63,73.74) 224.59,73.7 arc(222.8,72.54) 220.71,72.14 216.02,72.14 211.96,68.08 191.13,68.08 arc(187.68,68.53) 184.45,69.84 arc(181.99,71.19) 179.51,72.51 178.21,73.33 171.9,73.33 170.4,71.82 163.34,71.82 162.62,71.1 158.26,71.1 157.15,69.99 148.41,69.99 145.64,72.77 144.08,72.77 141.65,75.2 141.65,76.28 142.12,76.75 v2(142.38,76.75)
  IN1 w0.127: v2(69.31,82) 69.47,81.84 69.47,81.08 70.15,80.4 80.22,80.4 84.68,75.95 141.58,75.95 v2(142.38,76.75)
  BOTTOM w0.127: QE6.3 69.38,83.17 CE39.1 69.9,83.69 70.23,83.69 70.32,83.6 70.32,83.32 69.51,82.51 69.51,82.19 v2(69.31,82)
REM_DIODE4_P: length 208.9
  TOP w0.127: v2(141.63,76.88) 141.63,76.62 141.4,76.39 141.4,75.1 143.98,72.52 145.53,72.52 148.31,69.74 157.26,69.74 158.36,70.85 162.73,70.85 163.45,71.57 170.5,71.57 172.01,73.08 178.14,73.08 178.76,72.68 178.76,72.68 179.39,72.29 arc(181.87,70.97) 184.33,69.62 arc(187.62,68.28) 191.13,67.83 212.07,67.83 216.12,71.88 220.71,71.88 arc(222.9,72.31) 224.77,73.52 224.77,73.52 225.25,74 arc(226.79,76.34) 227.28,79.1 227.28,82.56 232.21,87.49 232.56,87.49 235.21,90.13 236.46,90.13 237.86,91.53 242.33,91.53 242.71,91.91 243.71,91.91 CE27.2 244.4,91.91 245.85,91.91 246.15,91.6 246.41,91.6 246.56,91.45 247.09,91.45 UE1.B10
  IN1 w0.127: v2(69.9,82) 69.72,81.83 69.72,81.19 70.26,80.66 80.33,80.66 84.78,76.2 141.48,76.2 141.73,76.45 141.73,76.78 v2(141.63,76.88)
  BOTTOM w0.127: v2(69.9,82) 69.76,82.14 69.76,82.41 70.57,83.22 70.57,83.7 70.33,83.95 69.9,83.95 CE39.2 69.38,84.47 QE6.2 67.78,83.82 QE6.1
RES_BIAS: length 4
  TOP w0.127: UL1.12 248.48,122.61 248.59,122.49 249.47,122.49 250.09,121.88 RL13.1 250.44,120.89 v1(251.05,120.89)
RESET_IN#: length 5.6
  TOP w0.127: UE1.C1 248.28,83.53 247.52,82.76 v1(247.52,81.85) 247.52,79.11 RE362.2
RESET_OUT: length 21.7
  TOP w0.127: v2(237.23,84.77) 237.39,84.93 237.39,85.5 v1(237,85.89) 235.63,85.89 235.23,85.48 RE548.2 ; UE1.G4 v2(251.08,85.86)
  IN2 w0.122: v2(237.23,84.77) 237.95,85.49 237.95,87.62 238.65,88.32 241.2,88.32 242.05,87.47 242.65,87.47 242.82,87.3 246.49,87.3 247.53,86.26 250.68,86.26 v2(251.08,85.86)
RESET_OUT#_R: length 3.7
  BOTTOM w0.127: RC128.2 RC129.2 89.38,127.16 CC33.1 89.71,128.36 JXDP1.47
RING2: length 41.4
  IN4 w1.016: 254.02,60.65 254.02,57.86 253.83,57.67 253.83,56.34 254.6,55.57 256.94,55.57 259.61,52.91 264.23,52.91 268.13,56.81 273.06,56.81 283.51,46.36
  vias: v1(252.86,61.81) v2(252.58,61.35) v2(253.16,61.35) v2(284.38,46.05) v2(284.38,45.48)
RING2_R:
  vias: v3(293.65,42.86)
RJ45_MDIN0: length 28
  IN4 w0.241: v2(271.75,116.39) 271.88,116.51 271.88,116.99 272.26,117.37 273.72,117.37 280.39,110.7 280.39,101.47 281.3,100.56 282.57,100.56 282.77,100.76 JLOM1.2
  BOTTOM w0.267: TL1.14 271.42,118.76 271.86,118.32 271.86,116.49 v2(271.75,116.39)
RJ45_MDIN1: length 32.1
  IN1 w0.241: v2(268.43,113.73) 268.57,113.87 268.57,114.21 268.96,114.6 275.64,114.6 279.79,110.45 279.79,105.45 281.09,104.15 282.47,104.15 282.92,104.6 282.92,105.14 JLOM1.6
  BOTTOM w0.267: TL1.20 263.8,118.59 264.25,118.15 264.25,117.05 266.13,115.16 267.85,115.16 268.53,114.48 268.53,113.83 v2(268.43,113.73)
RJ45_MDIN2: length 32.4
  IN4 w0.241: v2(266.58,116.39) 266.58,117.52 268.15,119.09 273.79,119.09 281.58,111.29 281.58,104.71 281.89,104.4 282.92,104.4 283.06,104.26 JLOM1.5
  BOTTOM w0.267: v2(266.58,116.39) 266.58,118.18 266.34,118.43 TL1.18
RJ45_MDIN3: length 36.7
  IN1 w0.241: v2(266.55,113.07) 266.67,113.2 266.67,114.42 268.11,115.85 276.11,115.85 280.96,110.99 280.96,107.38 281.66,106.68 282.62,106.68 282.77,106.83 JLOM1.8
  BOTTOM w0.267: v2(266.55,113.07) 266.65,113.17 266.65,113.63 266.28,113.99 262.36,113.99 259.15,117.2 259.15,118.1 258.72,118.53 TL1.24
RJ45_MDIP0: length 27.9
  IN4 w0.241: JLOM1.1 281.14,100.18 280.01,101.31 280.01,110.54 273.56,116.99 272.42,116.99 272.26,116.83 272.26,116.46 v2(272.34,116.39)
  BOTTOM w0.267: 272.69,119.57 272.69,118.76 272.24,118.3 272.24,116.49 v2(272.34,116.39)
RJ45_MDIP1: length 32.1
  IN1 w0.241: JLOM1.3 282.48,102.22 279.41,105.29 279.41,110.29 275.48,114.22 269.12,114.22 268.95,114.05 268.95,113.87 269.01,113.8 v2(269.01,113.73)
  BOTTOM w0.267: TL1.19 265.07,118.58 264.63,118.13 264.63,117.21 266.29,115.54 268.01,115.54 268.91,114.64 268.91,113.83 v2(269.01,113.73)
RJ45_MDIP2: length 32.4
  IN4 w0.241: v2(267.31,116.39) 266.97,116.73 266.97,117.36 268.31,118.71 273.63,118.71 281.2,111.14 281.2,104.55 281.73,104.02 282.76,104.02 283.13,103.66 283.13,103.41 282.95,103.24 JLOM1.4
  BOTTOM w0.267: v2(267.31,116.39) 266.97,116.73 266.97,118.04 267.14,118.22 267.46,118.22 267.61,118.37 TL1.17
RJ45_MDIP3: length 36.6
  IN1 w0.241: JLOM1.7 281.5,106.3 280.58,107.22 280.58,110.84 275.95,115.47 268.26,115.47 267.05,114.26 267.05,113.15 v2(267.13,113.07)
  BOTTOM w0.267: TL1.23 259.99,118.6 259.54,118.15 259.54,117.36 262.52,114.37 266.44,114.37 267.03,113.78 267.03,113.17 v2(267.13,113.07)
RTCRST_ON: length 17.8
  TOP w0.127: v1(246.72,98.5) 246.11,99.11 v2(246.11,99.13) 245.65,99.59 245.39,99.59 245.16,99.82 RE93.1 245.25,100.07 QE12.2 244.82,100.91 244.59,100.69 244.59,97.93 244.91,97.61 245.45,97.61 245.83,97.23 RE565.2 ; UE1.F11 v2(250.28,92.26)
  IN4 w0.084: v2(246.11,99.13) 246.55,98.69 247.06,98.69 248.95,96.81 248.95,95.64 249.63,94.95 249.63,93.61 250.28,92.96 v2(250.28,92.26)
RTCRST_ON_R: length 9.3
  TOP w0.254: QE17.2 232.48,95.56 233.2,96.28 233.83,96.28 234.68,97.12 CE65.1 235.27,99.2 v1(236.59,99.2) RE543.1 237.77,99.66 DE2.2
RTD3_CIO_PWR_EN: length 190.2
  TOP w0.127: v2(125.65,134.48) v1(127.03,133.1) 128.29,131.84 133.51,131.84 136.62,128.73 138.53,128.73 138.92,128.34 138.92,127.47 140.56,125.83 v2(142.8,125.83) ; v2(25.15,107.31) 25.67,107.83 27,107.83 27.08,107.91 RT25.1 RT372.1
  IN2 w0.122: v2(142.8,125.83) 143.23,125.4 144.21,125.4 145.3,124.32 145.3,120.09 142.64,117.44 140.96,117.44 138.73,115.21 138.73,112.41 139.06,112.08 139.06,111.85 140.94,109.97 141.16,109.97 142.52,108.61 142.52,102.3 141.25,101.03 v2(140.85,101.03) ; v2(125.65,134.48) 125.21,134.92 124.33,134.92 123.15,133.74 121.83,133.74 121.06,134.51 108.21,134.51 106.68,132.99 84.25,132.99 83.49,132.23 83.49,131.86 79.79,128.16 76.09,128.16 75.44,128.81 62.73,128.81 61.48,127.56 47.39,127.56 46.23,126.4 40.89,126.4 40.38,125.89 36.95,125.89 35.3,124.25 31.56,124.25 28.16,120.85 28.16,113.3 28.05,113.19 28.05,111.22 27.34,110.5 25.55,110.5 24.63,109.57 24.63,107.83 v2(25.15,107.31)
  BOTTOM w0.076: 135.54,101.54 135.33,101.75 134.03,101.75 133.4,101.12 132.93,101.12 132.64,101.41 132.28,101.41 132.19,101.44 132.13,101.47 131.7,101.47 131.44,101.21 UC1.AC2
  BOTTOM w0.127: v2(140.85,101.03) 140.69,101.19 138.05,101.19 137.74,100.89 136.19,100.89 135.54,101.54 ; v2(25.15,107.31) 25.15,107.78 RT392.2
RTD3_CIO_PWR_EN_R: length 5.5
  BOTTOM w0.076: 24.98,106.32 24.91,106.25 24.91,104.69 24.95,104.65 UT1.F1
  BOTTOM w0.127: 24.98,106.32 25.64,106.97 25.64,107.46 26.04,107.87 26.04,108.74 25.67,109.12 RT392.1
RTD3_USB_PWR_EN: length 3.1
  TOP w0.127: v1(23.04,105.04) 23.52,104.56 RT26.1 23.52,103.52 v2(24.13,102.9)
  BOTTOM w0.127: UT1.D4 v2(24.13,102.9)
RUN_ON: length 342.8
  TOP w0.127: v2(182.9,58.18) 182.92,58.18 v1(184.33,59.58) 185.49,60.75 200.16,60.75 201.35,59.56 201.35,57.64 202.27,56.72 202.27,55.99 203.99,54.28 RZ345.1 ; v2(264.33,97.66) UE5.4 265.13,97.24 268.47,93.9 273.67,93.9 v2(274.34,93.23) ; UZ3.5 159.3,60.74 v2(159.41,60.63) ; UZ4.3 v2(279.91,90.54) ; v2(261.38,99.71) 261.4,99.69 261.4,99.22 RE280.2 RE292.1 ; v2(157.71,62.06) 157.71,64.84 160.77,67.9 163.68,67.9 v2(164.64,68.85) ; PR402.1 v2(144.68,127.53)
  IN1 w0.084: v2(242.97,73.16) 242.97,73.6 241.04,75.53 241.04,81.24 240.25,82.03 240.25,84 239.79,84.47 v2(238.67,84.47) 239.54,85.33 239.54,92.97 241.19,94.62 241.19,105.74 242.26,106.81 242.26,107.15 v2(243.01,107.9) ; v2(144.68,127.53) 144.31,127.9 141.66,127.9 140.8,127.04 140.24,127.04 138.33,128.95 130.38,128.95 128.48,130.85 v2(127.28,130.85)
  IN2 w0.122: v2(157.71,62.06) 157.97,62.06 v2(159.41,60.63) 159.8,60.63 160.13,60.3 165.46,60.3 166.41,61.25 169.32,61.25 169.82,60.74 170.12,60.74 171.16,59.7 172.43,59.7 172.56,59.57 173.9,59.57 174.99,58.48 177.94,58.48 178.64,59.18 179.26,59.18 179.68,58.77 180.11,58.77 180.46,59.12 181.96,59.12 v2(182.9,58.18) ; v2(243.01,107.9) 243.92,107.9 246.51,105.31 255.59,105.31 256.13,104.77 258.68,104.77 261.06,102.38 261.06,101.15 261.45,100.76 261.45,99.77 v2(261.38,99.71) 261.38,99.63 263.35,97.66 v2(264.33,97.66) ; v2(144.68,127.53) 144.68,127.47 145.61,126.54 146.87,126.54 147.69,125.71 154.26,125.71 158.98,120.99 158.98,119.66 159.67,118.97 160.23,118.97 160.87,118.34 160.87,117.25 161.25,116.87 161.25,108.7 163.11,106.84 163.11,104.89 165,103 165,92.9 166.15,91.74 166.15,89.7 166.84,89.01 166.84,87.83 168.74,85.93 168.74,84.29 170.69,82.34 170.69,79.95 172.56,78.09 v2(172.56,76.28) 173.87,76.28 177.46,72.69 178.56,72.69 181.59,69.66 185.79,69.66 187.44,68.02 205.46,68.02 206.93,66.55 224.42,66.55 225.1,67.23 226.5,67.23 227.17,67.9 228.51,67.9 228.52,67.91 228.84,67.91 229.59,68.66 230.7,68.66 230.83,68.78 232.54,68.78 234.4,70.65 235.46,70.65 235.73,70.91 239.54,70.91 241.2,72.57 241.2,73.1 241.96,73.85 242.29,73.85 v2(242.97,73.16)
  IN4 w0.084: v2(164.64,68.85) 164.64,69.2 165.15,69.71 171.13,69.71 173.29,71.87 173.29,75.55 v2(172.56,76.28)
  BOTTOM w0.127: v2(238.67,84.47) 238.47,84.47 238.21,84.21 QE2.2 ; UZ35.2 125.07,132.47 124.56,131.96 RZ320.1 127.25,130.82 v2(127.28,130.85) ; v2(274.34,93.23) 277.23,93.23 v2(279.91,90.54)
RUN_ON#: length 42.4
  TOP w0.127: v2(238.61,85.1) 238.66,85.1 238.89,85.33 RE68.1 v1(239.32,84.46)
  IN1 w0.084: v2(238.61,85.1) 238.71,85.1 239.16,85.55 239.16,92.98 241.01,94.82 241.01,108.53 242.85,110.37 242.85,121.2 242.76,121.28 v2(242.56,121.28)
  BOTTOM w0.127: QZ4.2 242.74,121.46 v2(242.56,121.28) ; QE2.5 238.21,85.47 238.58,85.1 v2(238.61,85.1) 238.66,85.1 238.86,85.31 QE2.6
RUN_ON_EC: length 30.7
  TOP w0.127: UE1.E8 v2(249.48,89.86) ; v1(264.95,96.61) 264.95,96.94 264.68,97.2 264.09,97.2 263.84,97.46 263.84,98.11 263.64,98.31 UE5.2 262.29,98.31 RE292.2 261.66,97.67 260.67,97.67 260.18,98.16 RPE10.4 260.18,99.43 259.95,99.66 257.66,99.66 v2(257.45,99.45)
  BOTTOM w0.127: v2(257.45,99.45) 256.26,100.65 251.94,100.65 250.73,99.44 250.73,98.51 251.16,98.08 251.16,94.12 250.68,93.64 250.68,89.61 250.47,89.39 249.95,89.39 v2(249.48,89.86)
RUNPWROK: length 270.3
  TOP w0.127: v2(83.4,121.42) 83.4,121.47 ; 83.4,121.47 83.27,121.6 82.65,121.6 v2(81.5,120.45) 81.03,119.98 79.8,119.98 79.45,120.33 79.45,122.57 83.49,126.62 85.23,126.62 86.42,127.81 v1(86.42,128.18) v2(86.42,128.79) ; 83.4,121.47 83.4,122.93 v2(83.02,123.31) ; UE1.G3 v2(251.08,85.06)
  IN1 w0.084: v2(242.09,73.23) 242.09,73.76 240.48,75.36 240.48,80.79 239.55,81.73 239.55,81.99 v2(239.04,82.5)
  IN2 w0.122: v2(251.08,85.06) 250.68,85.46 250.09,85.46 249.88,85.25 249.88,84.88 249.66,84.66 249.31,84.66 248.54,83.88 244.26,83.88 243.5,83.12 243.5,81.9 243.03,81.43 240.11,81.43 v2(239.04,82.5) ; v2(86.42,128.79) 87.34,127.87 89.36,127.87 89.81,128.33 101.09,128.33 101.46,127.97 102.63,127.97 103.82,129.15 115.6,129.15 116.78,130.33 124.12,130.33 124.34,130.11 139.03,130.11 141.05,128.09 143.09,128.09 144.89,126.29 146.73,126.29 147.53,125.49 154.1,125.49 158.68,120.9 158.68,119.64 159.58,118.75 160.14,118.75 160.64,118.25 160.64,117.16 161.02,116.78 161.02,108.61 162.89,106.75 162.89,104.8 164.73,102.95 164.73,92.84 165.92,91.65 165.92,89.61 166.61,88.92 166.61,87.74 168.52,85.83 168.52,84.2 170.46,82.25 170.46,79.86 172.16,78.16 172.16,75.98 172.29,75.86 173.98,75.86 177.57,72.27 178.56,72.27 181.4,69.43 185.7,69.43 187.34,67.79 205.37,67.79 206.84,66.33 224.52,66.33 225.2,67.01 226.59,67.01 227.16,67.58 227.18,67.58 227.27,67.68 228.6,67.68 228.61,67.69 228.93,67.69 229.68,68.44 230.8,68.44 230.92,68.56 232.44,68.56 232.44,68.56 232.63,68.56 234.49,70.42 235.56,70.42 235.82,70.69 239.63,70.69 241.42,72.48 241.42,73 241.65,73.23 v2(242.09,73.23)
  BOTTOM w0.127: UC8.1 83.21,122.3 83.4,122.12 v2(83.4,121.42) ; RE67.1 237.05,83.7 237.18,83.83 QE2.3 237.56,83.42 237.82,83.16 238.38,83.16 v2(239.04,82.5) ; UC8.13 82.3,123.41 82.41,123.31 v2(83.02,123.31) 83.09,123.24 83.92,123.24 84.9,122.26 85.3,122.26 85.52,122.47 85.52,124.15 83.8,125.86 81.8,125.86 81.42,125.48 81.42,124.8 80.8,124.19 UC8.10 ; UC8.4 81.3,120.65 v2(81.5,120.45)
SA_LGATE: length 4.9
  IN4 w0.762: 63.12,115.53 64.9,115.53 65.53,116.16 67.79,116.16
  vias: v2(61.92,115.67) v2(62.49,115.67) v2(68.3,116.94) v2(68.75,116.46)
SA_SNUB: length 1.8
  TOP w0.127: PR627.2 v1(66.13,112.71)
SA_SW: length 8.6
  TOP w0.127: PR627.1 70.09,114.5 v3(70.24,114.35)
  IN4 w0.508: v2(68.81,115.68) 68.81,114.79 67.26,113.24 63.4,113.24 v2(63.27,113.37)
SA_UGATE: length 7.9
  IN4 w0.762: 60.02,113.14 60.71,112.45 67.63,112.45
  vias: v1(58.93,113.07) v2(58.98,113.64) v2(68.22,112.94) v2(68.23,112.32)
SATAGP0: length 15.9
  BOTTOM w0.076: 134.84,109.99 134.83,109.99 134.62,109.99 134.42,109.79 133.63,109.79 132.76,108.93 132.32,108.93 132.16,108.87 131.99,108.87 131.83,108.92 131.66,108.92 UC1.H2
  BOTTOM w0.127: 134.84,109.99 138.33,109.99 138.85,109.46 144.65,109.46 v1(144.96,109.15) 145.96,109.15 146.05,109.24 RPC4.1
SATALED#: length 389.8
  TOP w0.127: QZ2.4 v1(272.88,81.48) 272.88,80.57 270.78,78.47 266.69,78.47 263.77,75.55 262.68,75.55 v2(262.36,75.87) ; v2(40.31,111.19) 40.12,111 40.12,110.43 39.86,110.17 v2(39.86,108.71) ; RN100.2 24.13,53.14 24.13,61.72 24.78,62.37 25.88,62.37 32.52,69.01 34.16,69.01 v2(35.39,70.24)
  IN2 w0.122: v2(134.01,110.27) 134.01,111.4 133.48,111.92 133.48,113.54 134.78,114.83 134.78,115.03 134.78,115.03 134.78,116.7 136.18,118.09 136.18,121.61 135.61,122.18 135.61,124.42 133.67,126.36 130.64,126.36 129.66,127.34 125.04,127.34 124.52,126.82 117.44,126.82 116.24,125.61 98.27,125.61 97.28,124.62 93.45,124.62 93.06,125 91.82,125 91.21,124.4 82.88,124.4 81.82,123.33 74.26,123.33 72.65,124.95 72.08,124.95 71.98,124.85 71.19,124.85 70.75,125.3 69.28,125.3 68.28,124.3 62.28,124.3 59.31,121.32 55.96,121.32 53.65,123.63 47.24,123.63 46.65,123.04 41.15,123.04 40.71,122.6 40.71,120.86 42.34,119.24 43.61,119.24 45.11,117.74 45.11,115.22 41.12,111.23 40.36,111.23 v2(40.31,111.19) ; v2(262.36,75.87) 262.17,75.87 259.99,73.7 258.42,73.7 258.03,74.09 253.13,74.09 252.9,74.32 251.05,74.32 249.82,73.09 244.54,73.09 242.62,71.18 241.14,71.18 239.93,69.97 236.12,69.97 235.86,69.7 234.85,69.7 232.41,67.26 232.02,67.26 231.67,67.26 231.46,67.47 229.74,67.47 229.23,66.96 228.91,66.96 228.9,66.96 227.58,66.96 227.21,66.59 227.2,66.59 226.89,66.28 225.49,66.28 224.81,65.61 206.54,65.61 205.07,67.07 187.04,67.07 185.46,68.66 181.49,68.66 179.3,70.84 177.47,70.84 173.54,74.77 171.71,74.77 170.92,75.56 170.92,77.71 169.61,79.02 169.61,81.96 167.7,83.88 167.7,85.51 165.74,87.46 165.74,88.65 164.89,89.51 164.89,90.99 162.83,93.05 162,93.05 160.91,94.14 160.91,94.79 160.34,95.36 155.13,95.36 150.06,100.44 150.06,104.57 149.53,105.11 149.53,105.6 150.69,106.76 150.69,108.37 151.51,109.2 151.51,110.99 v2(150.96,111.54) ; v2(35.39,70.24) 35.15,70.48 35.15,74.97 35.85,75.66 35.85,77.41 36.93,78.5 37.85,78.5 38.55,79.2 38.55,86.44 38.3,86.69 38.3,88.74 38.06,88.97 38.06,96.96 37.36,97.67 37.36,100.02 38.53,101.19 38.84,101.19 39.41,101.76 39.41,108.26 v2(39.86,108.71)
  BOTTOM w0.076: UC1.H1 132.15,109.21 132.78,109.21 133.84,110.27 v2(134.01,110.27)
  BOTTOM w0.127: v2(134.01,110.27) 138.42,110.27 138.98,109.71 144.61,109.71 145.14,110.24 RPC4.3 146.75,110.24 146.97,110.46 146.97,110.96 147.11,111.09 148.08,111.09 148.56,111.57 150.93,111.57 v2(150.96,111.54)
SBIOS_TX: length 239.7
  TOP w0.127: v2(167.64,79.76) 168.15,80.27 168.27,80.27 169.92,81.92 169.92,86.67 v1(168.96,87.62) 165.67,90.91 158.98,90.91 158.5,91.39 154.97,91.39 154.66,91.7 151.4,91.7 151.09,91.39 148.91,91.39 147.66,92.64 146.9,92.64 v2(146.56,92.97) ; v2(227.82,86.12) 228.36,86.12 233.35,91.11 235.97,91.11 237.53,92.67 239.12,92.67 240.23,93.79 242.52,93.79 v2(242.73,93.57)
  IN1 w0.084: v2(289.9,122.31) 291.23,122.31 292.63,123.71 292.63,125.17 287.87,129.93 257.94,129.93 249.57,121.57 249.57,119.11 249.78,118.91 249.78,115.53 248.38,114.13 246.89,114.13 246.17,113.42 246.17,110.43 246.58,110.02 246.58,106.32 245.27,105.01 245.27,96.54 244.16,95.43 244.16,94.4 243.33,93.57 v2(242.73,93.57) ; v2(133.03,101.53) 133.87,100.7 136.57,100.7 140.42,96.85 141.44,96.85 141.97,96.32 141.97,96.21 142.42,95.76 143.87,95.76 146.56,93.08 v2(146.56,92.97) ; v2(227.82,86.12) 227.23,86.12 226.02,84.91 226.02,83.79 223.57,81.34 223.57,76.27 221.06,73.75 216.34,73.75 v2(215.18,72.59)
  BOTTOM w0.076: v2(133.03,101.53) 132.99,101.57 132.31,101.57 132.26,101.59 UC1.AB2
  BOTTOM w0.127: v2(167.64,79.76) 171.5,79.76 187.45,63.8 210.77,63.8 215.4,68.43 215.4,72.38 v2(215.18,72.59) ; RE306.1 v2(289.9,122.31)
SD/MMCCD#: length 27.2
  TOP w0.127: UR1.30 274.67,67.39 v2(274.27,67.79) ; v2(283.63,52.13) 284.28,51.47 JSD1.9
  IN1 w0.084: v2(274.27,67.79) 274.88,67.18 274.88,63.4 279.83,58.44 280.89,58.44 282.8,56.54 285.48,56.54 285.7,56.32 285.7,54.21 v2(283.63,52.13)
SD/MMCCLK: length 3.8
  TOP w0.127: v1(280.08,61.61) 279.98,61.51 279.59,61.51 278.68,62.41 RR5.1 278.39,62.41 277.82,62.97 277.82,63.31 277.66,63.47 UR1.17
SD/MMCCLK_R: length 11.7
  TOP w0.127: RR5.2 278.61,60.64 CR21.1 279.28,60.63 279.35,60.56 v2(279.35,60.26) ; JSD1.5 285.12,55.77 284.73,55.38 v2(283.63,55.38)
  IN4 w0.084: v2(279.35,60.26) 279.35,58.72 281.77,56.29 282.67,56.29 283.58,55.38 v2(283.63,55.38)
SD/MMCCMD: length 2
  TOP w0.127: RR6.1 279.18,64.27 UR1.19
SD/MMCCMD_R: length 12.2
  TOP w0.127: v2(280.46,63.53) 280.22,63.76 RR6.2 ; JSD1.3 285.42,57.57 284.99,58 v2(284.6,58)
  IN4 w0.084: v2(280.46,63.53) 280.46,61.56 282.13,59.88 282.13,59.69 281.41,58.97 281.41,58.78 281.6,58.59 281.79,58.59 282.51,59.31 282.7,59.31 284.05,57.96 284.56,57.96 v2(284.6,58)
SD/MMCDAT0/RCLK+: length 2.1
  TOP w0.089: RR10.1 277.28,61.6 277.28,61.78 276.67,62.39 UR1.16
SD/MMCDAT0/RCLK+_R: length 14
  TOP w0.089: JSD1.7 285.39,53.97 284.84,53.42 283.82,53.42 v2(283.63,53.62) ; v2(277.56,59.3) 277.3,59.55 277.3,60.17 277.39,60.26 RR10.2
  IN1 w0.084: v2(277.56,59.3) 277.53,59.27 277.53,57.32 281.47,53.37 283.38,53.37 v2(283.63,53.62)
SD/MMCDAT1/RCLK-: length 2.1
  TOP w0.089: RR9.1 277.06,61.41 277.06,61.69 276.27,62.47 UR1.15
SD/MMCDAT1/RCLK-_R: length 14
  TOP w0.089: JSD1.8 285.08,53.07 284.96,53.2 283.79,53.2 v2(283.63,53.03) ; RR9.2 277.08,60 277.08,59.41 v2(276.97,59.3)
  IN1 w0.084: v2(276.97,59.3) 277.19,59.08 277.19,57.18 281.33,53.03 v2(283.63,53.03)
SD/MMCDAT2: length 2.4
  TOP w0.127: UR1.21 277.74,65.07 277.94,65.26 278.69,65.26 279.27,65.84 RR8.1
SD/MMCDAT2_R: length 13.1
  TOP w0.127: RR8.2 280.33,65.78 v2(280.79,65.78) ; v2(284.59,60.3) 285.51,59.37 JSD1.1
  IN4 w0.084: v2(280.79,65.78) 280.92,65.78 281.81,64.89 282.1,64.89 282.82,65.61 283.01,65.61 283.2,65.42 283.2,65.23 282.48,64.51 282.48,64.32 282.87,63.93 283.06,63.93 283.38,64.24 283.57,64.24 283.76,64.05 283.76,63.86 283.44,63.55 283.44,63.36 283.81,62.99 283.81,61.08 v2(284.59,60.3)
SD/MMCDAT3: length 2.2
  TOP w0.127: RR7.1 279.14,64.84 278.47,64.84 v1(278.4,64.91) 278.03,64.91 277.79,64.67 UR1.20
SD/MMCDAT3_R: length 11.9
  TOP w0.127: JSD1.2 285.27,58.47 284.04,59.71 v2(283.04,59.71) ; v2(280.84,65.17) 280.7,65.02 RR7.2
  IN4 w0.084: v2(283.04,59.71) 283.04,59.99 281.87,61.16 281.87,61.93 281.73,62.07 281.16,62.07 281.02,62.2 281.02,62.47 281.16,62.61 281.73,62.61 281.87,62.74 281.87,64.15 v2(280.84,65.17)
SD_GPIO: length 2.9
  TOP w0.127: UR1.28 275.47,67.41 275.37,67.5 275.37,67.89 274.89,68.38 v1(274.7,68.38) 274,68.38 RR3.2
SD_RCOMP: length 2
  TOP w0.203: v2(129.3,102.71) 129.3,102.25 v1(129.25,102.2)
  TOP w0.381: RC96.1 129.3,103.46 v2(129.3,102.71)
  BOTTOM w0.254: v2(129.3,102.71) 129.3,102.4 UC1.AB7
SD_UHS2_D0N: length 33.6
  TOP w0.089: JSD1.19 298.47,55.19 297.87,55.79 291.55,55.79 v2(291.39,55.63) ; UR1.25 276.67,67.39 v2(277.01,67.73)
  IN1 w0.084: v2(277.01,67.73) 276.91,67.73 276.81,67.82 276.81,68.05 276.98,68.21 280,68.21 282.19,66.02 282.19,59.1 283.25,58.04 284.07,58.04 284.47,58.44 286.04,58.44 288.68,55.8 291.33,55.8 291.39,55.75 v2(291.39,55.63)
SD_UHS2_D0P: length 33.7
  TOP w0.089: JSD1.18 298.03,56.1 297.94,56.02 291.58,56.02 v2(291.39,56.21) ; UR1.26 276.27,67.58 v2(276.41,67.73)
  IN1 w0.084: v2(291.39,56.21) 291.32,56.14 288.82,56.14 286.18,58.78 284.33,58.78 283.93,58.38 283.39,58.38 282.53,59.24 282.53,66.16 280.14,68.55 276.84,68.55 276.47,68.19 276.47,67.79 v2(276.41,67.73)
SD_UHS2_D1N: length 32.2
  TOP w0.089: v2(278.44,66.27) 278.29,66.27 277.89,65.87 UR1.23 ; v2(297.89,52.87) 297.96,52.94 298.27,52.94 298.7,53.37 JSD1.21
  IN1 w0.084: v2(297.89,52.87) 297.83,52.81 297.64,52.81 297.47,52.97 290.31,52.97 285.89,57.39 283,57.39 281.44,58.96 281.44,61.43 279.46,63.41 278.84,63.41 278.66,63.59 278.66,63.99 278.81,64.14 279.42,64.14 279.76,64.49 279.76,65.54 279.12,66.19 278.52,66.19 v2(278.44,66.27)
SD_UHS2_D1P: length 32.1
  TOP w0.089: JSD1.22 298.07,52.46 v2(297.89,52.28) ; v2(278.44,65.67) 278,65.67 277.8,65.47 UR1.22
  IN1 w0.084: v2(278.44,65.67) 278.44,65.74 278.55,65.85 278.98,65.85 279.43,65.4 279.43,64.63 279.28,64.48 278.67,64.48 278.32,64.13 278.32,63.45 278.7,63.07 279.32,63.07 281.1,61.29 281.1,58.82 282.86,57.05 285.75,57.05 290.17,52.63 297.33,52.63 297.5,52.47 297.79,52.47 297.89,52.37 v2(297.89,52.28)
SDWP: length 14
  TOP w0.127: UR1.29 275.07,67.61 v2(274.89,67.79) ; v2(280.63,59.59) 279.87,58.83 QR1.1
  IN1 w0.084: v2(280.63,59.59) 280.63,60.59 278.85,62.37 276.92,62.37 275.66,63.62 275.66,67.02 v2(274.89,67.79)
SIM_DET: length 90
  TOP w0.127: v2(270.15,67.37) 270.15,67.92 v1(270.41,68.17)
  IN4 w0.084: v2(270.15,67.37) 270.15,68.01 270.74,68.59 279.89,68.59 280.86,67.63 v2(280.86,66.53)
  BOTTOM w0.127: v2(270.15,67.37) 270.15,68.89 270.83,69.58 270.83,73.27 269.57,74.53 269.57,79.72 270.6,80.74 270.6,82.71 269.93,83.37 269.93,84.42 270.25,84.74 270.25,87.5 268.24,89.51 268.24,95.49 265.89,97.84 265.89,100.9 264.31,102.47 258.48,102.47 257.67,101.67 256.58,101.67 256.29,101.95 253.91,101.95 253.14,101.19 251.73,101.19 251.16,100.62 246.13,100.62 244.24,102.51 241.34,102.51 240.42,101.59 240.42,96.65 239.28,95.5 JNGFF2.58 ; v2(280.86,66.53) 280.31,65.98 280.31,64.86 280.87,64.29 JSIM1.2
SIO_EXT_SCI#: length 26.5
  TOP w0.127: v2(128.36,96.08) 128.85,96.57 v1(130.12,96.57) 130.64,96.57 131.89,95.32 134.19,95.32 134.47,95.6 137.35,95.6 137.96,96.21 138.81,96.21 v2(139.26,96.66)
  IN3 w0.122: v2(148.39,103.64) 148.39,103.48 147.22,102.31 146.2,102.31 143.79,99.9 142.5,99.9 v2(139.26,96.66)
  BOTTOM w0.076: v2(128.36,96.08) 128.52,96.08 UC1.AN7
  BOTTOM w0.127: v2(148.39,103.64) 148.9,103.13 RC561.2 ; RC237.1 139.31,96.71 v2(139.26,96.66)
SIO_EXT_SMI#: length 11.5
  BOTTOM w0.102: 131.1,114.7 129.57,113.17 UC1.A6
  BOTTOM w0.127: RC346.1 136.8,120.24 v1(136.16,119.6) 135.56,119 135.56,118.48 131.79,114.7 131.1,114.7
SIO_EXT_WAKE#: length 189.7
  TOP w0.127: UE1.M12 255.69,92.66 256.13,93.1 v2(257.05,93.1)
  IN2 w0.122: v2(142.57,100.85) 142.65,100.77 145.82,100.77 146.38,100.21 147.65,100.21 147.92,100.48 148.48,100.48 151.2,97.76 151.2,93.04 152.05,92.19 153.76,92.19 156.26,94.69 159.95,94.69 160.24,94.4 160.24,93.67 162.38,91.53 162.58,91.53 164.1,90 164.1,89.35 165.07,88.37 165.07,87.18 167.03,85.23 167.03,83.6 168.93,81.69 168.93,78.74 169.44,78.23 169.44,74.64 170.04,74.05 173.32,74.05 177.19,70.17 178.85,70.17 181.05,67.98 185.19,67.98 186.77,66.4 204.68,66.4 206.23,64.86 225.02,64.86 225.77,65.61 227.2,65.61 227.72,66.13 231.59,66.13 232.22,66.13 235.13,69.03 236.13,69.03 236.4,69.3 240.21,69.3 241.4,70.49 242.89,70.49 243.27,70.88 243.28,70.88 243.49,71.09 244.48,71.09 245.09,71.69 248.53,71.69 249.48,72.64 250,72.64 250.54,73.18 252.31,73.18 252.78,73.64 257.84,73.64 258.23,73.24 260.3,73.24 262.18,75.12 263.17,75.12 263.86,75.81 263.86,80.16 263.2,80.83 263.2,82.83 262.21,83.81 262.21,86.35 261.07,87.49 259.8,87.49 258.9,88.39 258.9,88.65 259.19,88.94 259.19,90.96 v2(257.05,93.1)
  BOTTOM w0.076: 135.54,100.5 135.54,100.49 134.76,100.49 134.39,100.86 133.81,100.86 133.72,100.95 132.87,100.95 132.63,101.18 UC1.AC1
  BOTTOM w0.127: 135.54,100.5 136.39,100.5 136.55,100.66 138.01,100.66 v1(138.2,100.85) 140.13,100.85 140.36,100.62 141.54,100.62 141.77,100.85 v2(142.57,100.85) 143.44,100.85 143.59,101 145.16,101 RC283.1
SIO_PWRBTN#: length 317.3
  TOP w0.127: v2(78.62,115.69) 78.62,116.11 79.54,117.02 81.09,117.02 82.7,118.63 87.3,118.63 88.82,120.15 88.82,124.52 v1(90.39,126.09) 91.35,127.05 RC241.1 CC269.1 91.35,128.63 v2(91.51,128.79) ; UE1.K11 v2(254.28,92.26)
  IN1 w0.084: v2(128.29,83.58) 123.32,78.6 118.14,78.6 117.05,77.5 85.52,77.5 80.33,82.69 75.59,82.69 v2(74.4,83.88)
  IN2 w0.122: v2(254.28,92.26) 254.06,92.26 253.66,92.66 253.28,92.66 253.09,92.85 253.09,93.51 253.21,93.64 254.18,93.64 254.4,93.86 258.47,93.86 259.72,92.62 261.18,92.62 262.13,91.67 262.13,87.48 262.92,86.68 262.92,84.07 263.87,83.12 263.87,82.19 264.54,81.52 264.54,74.66 260.27,70.39 260.14,70.39 259.82,70.08 259.82,69.36 258.56,68.1 257.2,68.1 256.13,69.17 255.33,69.17 254.91,69.59 251.37,69.59 250.35,68.57 248.83,68.57 247.73,67.47 247.73,67.09 245.12,64.48 245.12,63.56 243.11,61.55 243.11,60.28 242.36,59.53 240.03,59.53 239.76,59.26 235.79,59.26 235.31,58.78 234.07,58.78 233.69,59.16 217.07,59.16 216.21,58.3 208.19,58.3 207.74,58.75 205.04,58.75 202.01,61.77 184.67,61.77 184.17,62.28 182.02,62.28 181.14,63.15 178.9,63.15 178.42,62.67 172.62,62.67 170.53,64.76 165.44,64.76 165.29,64.92 160.74,64.92 157.52,68.15 150.71,68.15 145.18,73.68 145.18,75.01 144.02,76.18 144.02,77.2 v2(142.65,78.57)
  BOTTOM w0.076: 126.54,86.6 125.57,87.56 125.39,87.56 123.6,89.36 123.6,91.07 UC1.BA15
  BOTTOM w0.127: v2(78.62,115.69) 78.03,115.09 78.03,101.53 78.56,101 78.56,94.92 76.75,93.11 76.75,88.55 74.4,86.2 v2(74.4,83.88) ; v2(142.65,78.57) 142.6,78.57 141.21,79.96 136.71,79.96 136.08,79.33 135.83,79.33 135.51,79 131.24,79 128.29,81.95 v2(128.29,83.58) 128.29,84.26 126.54,86.01 126.54,86.6 ; JXDP1.41 v2(91.51,128.79)
SIO_SLP_A#: length 224.5
  TOP w0.127: v2(256.74,102.16) 256.74,102.78 v1(260.14,106.17) 261.21,107.25 261.55,107.25 262.06,107.76 JAPS1.6 ; UE1.M11 255.92,91.43 257.1,91.43 259.45,93.77 259.45,95.25 v2(259.56,95.36)
  IN1 w0.084: v2(259.56,95.36) 260.42,96.22 260.42,102.31 259.74,102.98 257.12,102.98 256.74,102.6 v2(256.74,102.16)
  IN2 w0.076: v2(122.9,95.92) 123.35,95.46 123.35,95.16 123.26,95.07 123.26,93.86 123.53,93.6 123.84,93.6 125.41,92.03
  IN2 w0.122: v2(259.28,70.7) 258.88,71.1 256.58,71.1 256.28,71.39 253.98,71.39 253.29,70.71 250.91,70.71 249.88,69.69 249.26,69.69 249.05,69.9 246.3,69.9 244.98,68.57 244.98,68.06 243.86,66.93 243.86,66.39 242.56,65.08 240.46,65.08 239.95,64.57 236.06,64.57 234.75,63.26 229.99,63.26 229.81,63.08 226.51,63.08 225.89,62.46 217.6,62.46 216.86,61.72 215.45,61.72 214.95,62.22 205.38,62.22 203.47,64.12 185.8,64.12 184.08,65.84 180.18,65.84 179.01,67.02 174.77,67.02 172.04,69.75 159.87,69.75 158.58,71.04 151.15,71.04 149.15,73.03 149.15,80.07 146.64,82.58 146.64,85.88 145.45,87.07 143.78,87.07 143.54,86.84 142.6,86.84 136.79,86.84 131.83,81.88 129.53,81.88 129.29,82.12 129.29,83.45 126.63,86.1 126.63,90.8 125.41,92.03
  BOTTOM w0.102: UC1.AN16 123.35,96.35 v2(122.9,95.92)
  BOTTOM w0.127: v2(259.56,95.36) 259.03,94.84 259.03,87.84 260.76,86.12 260.76,78.56 260.38,78.18 260.38,76.59 260.12,76.33 260.12,71.54 v2(259.28,70.7)
SIO_SLP_LAN#: length 219.8
  TOP w0.127: v2(253.2,112.02) 252.77,111.6 UZ2.5 ; UE1.H9 v2(252.68,90.66) ; v2(143.03,81.99) 142.35,81.99 142.17,82.17 RC344.1 141.57,81.74 141.62,81.68 RC68.1
  IN2 w0.122: v2(143.03,81.99) 142.68,81.64 142.68,80.03 144.55,78.16 144.55,76.28 145.7,75.13 145.7,73.8 150.89,68.6 157.7,68.6 160.91,65.39 165.45,65.39 165.63,65.21 170.71,65.21 172.81,63.12 178.23,63.12 178.72,63.6 181.33,63.6 182.21,62.72 184.35,62.72 184.86,62.22 202.2,62.22 205.22,59.2 207.92,59.2 208.37,58.75 215.42,58.75 216.49,59.82 218.44,59.82 218.98,60.36 226.93,60.36 227.27,60.7 235.27,60.7 236.26,59.71 239.27,59.71 239.56,60 242.2,60 242.66,60.46 242.66,61.74 244.67,63.74 244.67,64.75 247.28,67.36 247.28,67.66 248.64,69.02 250.16,69.02 251.18,70.04 253.62,70.04 254.18,70.6 255.44,70.6 256.92,69.12 257.38,69.12 v2(257.73,69.48)
  IN4 w0.084: v2(253.2,112.02) 253.85,111.37 253.85,106.13 251.04,103.31 251.04,95.27 253.08,93.23 253.08,91.05 v2(252.68,90.66)
  BOTTOM w0.076: 126.76,87.21 126.07,87.89 125.53,87.89 125.21,88.21 125.21,88.26 v4(124.85,88.62) 123.98,89.5 123.98,90.37 124.13,90.53 124.13,91.97 UC1.AW15
  BOTTOM w0.127: v2(252.68,90.66) 253.09,91.06 253.09,91.72 253.22,91.85 255.72,91.85 256.98,90.59 256.98,87.64 257.47,87.15 258.03,87.15 258.71,86.47 258.71,84.98 259.36,84.34 259.36,81.64 258.32,80.61 258.32,79.34 257.41,78.43 257.41,77.55 258.15,76.81 258.15,74.73 257.88,74.46 257.88,73.38 258.14,73.12 258.14,69.89 v2(257.73,69.48) ; 126.76,87.21 127.1,87.21 130.12,84.19 132.83,84.19 133.91,83.1 134.15,83.1 135.58,81.67 137.56,81.67 138.26,82.37 142.24,82.37 142.62,81.99 v2(143.03,81.99)
SIO_SLP_S0#: length 300
  TOP w0.127: v2(140.63,127.42) 140.63,127.63 140.35,127.91 PR425.1 ; JAPS1.15 257.56,105.9 v1(255.8,104.13) 255.49,103.82 v2(255.49,101.55) ; v2(210.24,71.47) 210.24,71.16 209.52,70.45 195.45,70.45 arc(190.13,71.05) 185.09,72.83 arc(180.35,75.78) 176.33,79.64 arc(175.04,81.21) 173.81,82.81 arc(172.35,85.21) 171.12,87.72 arc(171.08,87.82) 171.03,87.92 arc(170.69,88.78) 170.37,89.64 arc(169.14,94.39) 168.71,99.27 168.71,105.34 163.68,110.37 163.68,114.39 165.63,116.34 165.63,117.19 162.95,119.87 v2(162.95,120.09) 164.06,120.09 165.26,121.29 165.26,122.74 165.5,122.98 165.5,128.15 v2(165.25,128.41) PR426.1
  IN1 w0.084: v2(129.37,130.83) 129.37,130.52 130.61,129.28 138.37,129.28 140.24,127.42 v2(140.63,127.42) 141.8,128.59 145.31,128.59 146.72,130 148.09,130 149.02,130.92 156.4,130.92 158.65,133.17 160.49,133.17 v2(165.25,128.41)
  IN2 w0.122: v2(140.63,127.42) 140.63,126.97 142.66,124.95 143.99,124.95 144.85,124.09 144.85,120.28 142.45,117.88 140.77,117.88 138.28,115.39 138.28,112.18 138.61,111.86 138.61,111.67 140.75,109.53 140.97,109.53 142.04,108.45 142.04,103.46 140,101.42 140,101.41 138.96,100.37 138.96,98.25 137.82,97.1 137.82,95.77 136.07,94.02 129.14,94.02 128.7,94.46 126.07,94.46 v2(125.7,94.09) ; v2(210.24,71.47) 211.18,71.47 212.05,72.34 212.98,72.34 214.56,73.92 222.91,73.92 224.62,75.64 224.62,78.75 225.26,79.38 232.34,79.38 233.21,80.26 233.21,86.68 238.46,91.92 240.48,91.92 242.02,93.47 242.02,94.71 242.7,95.38 243.2,95.38 244.2,96.38 246.91,96.38 248.86,98.33 249.22,98.33 249.45,98.56 254.21,98.56 255.23,99.58 255.23,101.29 v2(255.49,101.55)
  BOTTOM w0.127: RZ362.2 155.07,111.1 154.59,110.62 154.51,110.62 154.21,110.33 RZ112.1 153.23,110.28 152.88,110.62 152.88,112.35 154.24,113.7 154.24,117.02 154.03,117.23 154.03,118.42 153.34,119.11 153.34,119.6 154.66,120.91 159.28,120.91 159.56,120.64 162.4,120.64 v2(162.95,120.09) 162.11,119.24 160.53,119.24 159.3,118.01 159.3,115.67 159.55,115.42 RZ363.1 ; v2(129.37,130.83) 128.08,130.83 125.79,133.12 UZ35.1
  BOTTOM w0.254: UC1.AT11 126.07,94.45 125.71,94.09 v2(125.7,94.09)
SIO_SLP_S3#: length 423.3
  TOP w0.127: UE3.2 264.63,98.25 263.91,98.96 UE5.1 262.28,98.96 RE280.1 v2(262.16,99.73) 261.92,99.97 v1(261.92,100.45) 261.92,101.64 261.52,102.04 QE11.2 260.55,102.04 259.94,102.65 259.94,103.83 260.39,104.28 261.29,104.28 264.06,107.05 JAPS1.2 ; UE1.K9 v2(254.28,90.66)
  IN1 w0.084: v2(138.93,125.61) 138.72,125.4 133.47,125.4 129.04,129.83 127.51,129.83 125.58,131.75 125.58,132.83 123.91,134.5 v2(123.34,134.5)
  IN2 w0.076: v2(123.81,95.34) 123.45,94.98 123.45,93.97 123.66,93.77 123.94,93.77 125.21,92.5 125.73,92.5
  IN2 w0.122: v2(23.52,107.45) 23.52,107.57 24.4,108.45 24.4,109.67 25.46,110.73 27.25,110.73 27.83,111.31 27.83,120.99 31.32,124.47 35.1,124.47 36.96,126.33 40.33,126.33 40.66,126.66 45.97,126.66 47.13,127.81 61.37,127.81 62.6,129.04 75.54,129.04 76.15,128.43 79.73,128.43 83.12,131.82 83.12,132.18 84.16,133.21 106.52,133.21 108.08,134.77 121.83,134.77 122.53,134.07 122.91,134.07 v2(123.34,134.5) ; 125.73,92.5 125.96,92.5 130.56,87.9 143.11,87.9 143.34,88.13 146.03,88.13 146.93,87.23 147.93,87.23 148.72,86.44 148.72,83.91 149.6,83.04 149.6,73.23 151.35,71.48 158.81,71.48 160.03,70.26 172.18,70.26 174.17,68.27 178.39,68.27 180.37,66.29 184.27,66.29 185.96,64.6 186.33,64.6 203.63,64.6 205.56,62.67 215.14,62.67 215.63,62.17 216.67,62.17 217.41,62.91 225.6,62.91 226.22,63.53 228.68,63.53 229.49,64.34 230.85,64.34 234.97,64.34 236.22,65.59 241.31,65.59 241.37,65.53 242.37,65.53 243.04,66.2 243.04,67.58 244.6,69.14 245.13,69.14 245.64,69.64 245.64,69.64 246.11,70.12 249.14,70.12 249.35,69.91 249.79,69.91 250.82,70.94 253.2,70.94 253.88,71.62 256.37,71.62 256.67,71.32 260.88,71.32 264.31,74.76 264.31,81.38 263.65,82.05 263.65,83.02 262.69,83.98 262.69,86.58 261.9,87.37 261.9,91.57 261.09,92.39 259.03,92.39 v2(258.06,93.36) ; v2(123.81,95.34) 124.02,95.54 125.13,95.54 125.36,95.78 126.03,95.78 126.16,95.65 128.62,95.65 128.83,95.86 128.83,96.16 129.21,96.54 130.22,96.54 131.48,95.29 136.19,95.29 137.06,96.15 137.06,97.48 138.21,98.64 138.21,101.5 138.97,102.26 138.97,103.12 140.36,104.51 140.36,105.64 139.86,106.15 139.86,108.05 137.71,110.19 137.71,111.48 136.78,112.4 136.78,115.31 139.61,118.13 139.61,118.13 140.26,118.78 142.08,118.78 143.53,120.22 143.53,122.69 143.05,123.16 139.57,123.16 138.93,123.8 v2(138.93,125.61)
  IN4 w0.084: v2(262.16,99.73) 262.16,99.38 259.7,96.91 259,96.91 257.09,95.01 257.09,94.33 v2(258.06,93.36) 258.06,92.86 255.45,90.26 254.68,90.26 v2(254.28,90.66)
  BOTTOM w0.076: UT1.D2 24.27,104.17 24.27,105.44 23.89,105.83 23.89,106.06
  BOTTOM w0.102: v2(123.81,95.34) 124.23,95.75 UC1.AP15
  BOTTOM w0.127: 23.89,106.06 23.89,106.62 23.52,106.99 v2(23.52,107.45)
SIO_SLP_S4#: length 500
  TOP w0.127: v2(50.04,125.93) 50.04,125.72 49.49,125.17 48.88,125.17 48.41,125.64 47.52,125.64 46.71,124.83 46.71,120.01 47.36,119.35 47.36,118.67 40.44,111.75 40.23,111.75 39.8,111.31 39.8,110.52 39.39,110.11 v2(39.39,109.13) ; v2(123.59,132.43) 123.59,132.36 124.34,131.61 UZ21.4 ; PR513.1 148.41,57.49 v2(148.17,57.73) ; v2(258.15,94.32) 257.99,94.32 257.44,93.77 257.44,92.94 257.39,92.89 257.39,92.89 257.16,92.66 UE1.N12 ; UZ34.2 v1(139.79,71.26) 139.46,71.59 139.46,72.11 139.02,72.54 v2(139.02,72.57) ; JAPS1.5 262.56,106.79 261.79,106.02 260.57,106.02 257.32,102.77 v2(257.32,102.15)
  TOP w0.254: v2(71.03,73.3) 71.03,74 PR208.1
  IN1 w0.084: v2(143.66,66.51) 143.64,66.51 142.29,67.85 78.71,67.85 73.95,72.62 71.31,72.62 71.03,72.89 v2(71.03,73.3) 70.98,73.35 70.98,75.35 69.7,76.64 52.21,76.64 51.75,76.18 47.39,76.18 46.66,76.92 41.91,76.92 40.95,75.96 40.24,75.96 39.58,76.62 39.58,78.69 38.74,79.52 38.74,82.36 39.21,82.83 v2(39.21,83.82) ; v2(258.15,94.32) 258.15,94.5 258.75,95.1 258.75,97.32 258.93,97.5 258.93,99.32 257.32,100.93 v2(257.32,102.15)
  IN2 w0.122: v2(148.17,57.73) 148.17,58.49 147.14,59.52 145.46,59.52 144.07,60.92 144.07,64.58 143.66,64.98 v2(143.66,66.51) 139,71.17 139,72.54 v2(139.02,72.57) ; v2(50.04,125.93) 50.91,125.06 54.08,125.06 55.37,126.35 61.94,126.35 62.23,126.64 68.13,126.64 69.09,127.6 74.88,127.6 75.32,127.15 80.1,127.15 83.82,130.87 85.51,130.87 85.96,131.32 115.09,131.32 116.36,132.59 123.43,132.59 v2(123.59,132.43) ; v2(39.21,83.82) 38.89,84.14 38.89,85.74 40.17,87.02 40.17,89.77 38.29,91.65 38.29,97.06 37.58,97.76 37.58,99.92 38.63,100.97 38.93,100.97 39.64,101.67 39.64,107.63 40.35,108.34 40.35,108.99 40.21,109.13 v2(39.39,109.13) ; v2(141.68,78.61) 141.79,78.61 142.26,78.14 142.72,78.14 143.67,77.2 143.67,76.21 144.96,74.92 144.96,73.59 150.62,67.93 157.43,67.93 160.65,64.7 165.19,64.7 165.35,64.54 170.44,64.54 172.53,62.45 179.03,62.45 179.42,62.05 184.08,62.05 184.58,61.55 201.91,61.55 204.94,58.52 207.64,58.52 208.13,58.04 216.27,58.04 216.66,58.42 216.66,58.43 217.17,58.94 233.6,58.94 233.98,58.56 235.4,58.56 235.88,59.04 239.86,59.04 240.13,59.3 242.46,59.3 243.33,60.18 243.33,61.46 245.34,63.46 245.34,64.38 248.03,67.07 248.03,67.45 248.92,68.35 250.44,68.35 251.46,69.37 254.82,69.37 255.24,68.95 256.04,68.95 257.11,67.88 258.7,67.88 259.67,68.85 260.41,68.85 260.73,69.16 260.73,70.52 264.77,74.56 264.77,81.64 264.09,82.31 264.09,85.83 262.35,87.57 262.35,91.76 261.27,92.84 260.01,92.84 258.43,94.42 258.26,94.42 v2(258.15,94.32)
  IN4 w0.084: v2(139.02,72.57) 139,72.57 134.23,77.34 v2(134.23,78.2)
  BOTTOM w0.076: 125.18,87.13 125.18,87.28 123.27,89.19 123.27,91.63 UC1.BA16
  BOTTOM w0.127: v2(141.68,78.61) 141.23,79.05 139.06,79.05 138.45,78.45 137.97,78.45 137.55,78.87 136.02,78.87 135.42,78.27 134.29,78.27 v2(134.23,78.2) 134.16,78.27 131.15,78.27 127.47,81.95 127.47,84.25 126.01,85.71 126.01,86.31 125.18,87.13
SIO_SLP_S5#: length 215.3
  TOP w0.127: v2(257.9,89.55) 257.74,89.39 257.26,89.39 257.2,89.46 UE1.N8 ; JAPS1.4 263.06,106.81 v1(261.5,105.25) 260.78,104.53 259.57,104.53 259.23,104.19 259.23,103.45 259.61,103.06 259.61,102.5 259.94,102.18 v2(259.94,101.8)
  IN2 w0.122: v2(141.68,78.01) 141.86,78.01 142.09,77.78 142.63,77.78 143.45,76.97 143.45,76.12 144.74,74.83 144.74,73.5 150.53,67.7 157.34,67.7 160.56,64.47 165.1,64.47 165.26,64.32 170.34,64.32 172.44,62.22 178.93,62.22 179.33,61.83 183.98,61.83 184.49,61.33 201.82,61.33 204.87,58.28 207.34,58.28 207.85,57.76 216.32,57.76 217.27,58.71 233.5,58.71 233.88,58.33 235.49,58.33 235.97,58.81 239.95,58.81 240.22,59.08 242.55,59.08 243.56,60.09 243.56,61.37 245.56,63.37 245.56,64.29 248.3,67.02 248.83,67.02 249.75,67.95 250.36,67.95 251.55,69.14 254.73,69.14 255.15,68.72 255.95,68.72 257.02,67.66 258.79,67.66 259.37,68.24 v2(259.76,68.24)
  BOTTOM w0.076: 124.93,87.07 124.93,87.28 123.11,89.1 123.11,91.23 122.94,91.39 122.94,91.82 123.24,92.12 UC1.AY16
  BOTTOM w0.127: 124.93,87.07 124.93,87.01 125.75,86.18 125.75,84.59 127.15,83.2 127.15,80.94 130.38,77.72 138.36,77.72 139.1,78.46 141.24,78.46 v2(141.68,78.01) ; v2(259.76,68.24) 259.76,68.8 258.65,69.91 258.65,71.28 259.56,72.19 259.56,75.81 259.12,76.25 259.12,77.02 259.54,77.44 259.54,78.27 260.17,78.91 260.17,85.89 258.55,87.52 258.55,88.55 257.9,89.2 v2(257.9,89.55) 257.9,91.51 256.54,92.87 256.54,93.58 255.48,94.64 255.48,97.97 256.16,98.65 257.44,98.65 258.01,99.22 258.01,100.79 258.55,101.33 259.46,101.33 v2(259.94,101.8)
SIO_SLP_SUS#: length 225.8
  TOP w0.127: RC441.1 155.28,124.6 156.11,123.77 156.11,120.06 153.09,117.05 153.09,114.34 152.64,113.89 152.64,109.43 153.07,109 153.07,106.77 155.03,104.8 155.03,104.07 v2(155.47,103.63) ; RE349.1 263.25,83.2 264.83,81.62 v1(264.83,80.72) 264.83,77.93 263.61,76.72 262.74,76.72 262.23,77.23 v2(261.58,77.23) ; v2(161.62,89.62) 161.25,90 158.6,90 158.12,90.48 154.48,90.48 154.17,90.79 151.78,90.79 151.47,90.47 148.04,90.47 144.84,87.28 144.23,87.28 143.82,86.87 141.88,86.87 141.54,87.2 139.86,87.2 139.01,88.05 137.64,88.05 137.37,88.31 137.37,89.69 136.54,90.52 v2(136.54,91.61)
  IN1 w0.084: v2(155.47,103.63) 157.44,101.66 159.76,101.66 160.94,100.49 160.94,90.9 161.49,90.35 161.49,89.75 v2(161.62,89.62)
  IN2 w0.122: v2(161.62,89.62) 162.09,89.16 162.45,89.16 162.93,88.67 163.51,88.67 164.17,88.01 164.17,86.82 166.06,84.93 166.06,83.3 168.03,81.33 168.03,78.37 168.55,77.86 168.55,73.53 169.65,72.42 171.17,72.42 171.64,72.89 173.16,72.89 176.77,69.28 178.36,69.28 180.55,67.08 184.74,67.08 186.32,65.51 203.99,65.51 205.61,63.89 225.31,63.89 226.14,64.72 227.59,64.72 228.11,65.24 231.22,65.24 234.6,65.24 235.08,65.72 235.08,67.72 235.42,68.06 236.43,68.06 236.77,68.4 241.31,68.4 242.08,69.18 243.56,69.18 244.2,69.82 244.84,69.82 245.82,70.79 249.02,70.79 249.62,71.39 252.63,71.39 253.3,72.07 256.56,72.07 256.85,71.77 260.61,71.77 262.13,73.29 v2(262.13,74.39)
  IN4 w0.084: v2(123.82,96.1) 124.12,96.1 125.37,94.84 126.92,94.84 127.31,94.46 127.68,94.46 127.96,94.17 127.96,92.74 129.44,91.26 136.19,91.26 v2(136.54,91.61)
  BOTTOM w0.102: v2(123.82,96.1) 123.96,96.1 UC1.AN15
  BOTTOM w0.127: v2(262.13,74.39) 261.63,74.9 261.63,77.18 v2(261.58,77.23)
SIO_SLP_SUS#_R: length 8
  TOP w0.127: RE561.1 262.16,83.17 RE349.2 261.53,83.81 v1(260.89,83.81) 259.88,83.81 258.25,85.44 257.82,85.44 257,86.26 UE1.N4
SIO_SLP_WLAN#: length 230
  TOP w0.127: v2(219.36,70.83) 219.78,70.41 223.34,70.41 229.05,76.13 229.05,82.66 231.62,85.22 v2(232.02,85.22) ; UE1.D9 v2(248.68,90.66)
  IN1 w0.084: v2(248.68,90.66) UE1.D9 249.66,90.26 249.87,90.48 249.87,92.53 249.38,93.02 249.38,95.41 249.24,95.56 249.24,96.76 248.38,97.62 248.38,103.38 v2(249.04,104.04) 249.04,104.48 250.32,105.76 250.32,113.85 251.61,115.14 v2(251.61,115.2)
  IN2 w0.122: v2(218.28,56.74) 218.28,57.36 217.89,57.75 216.94,57.75 216.44,57.25 211.03,57.25 210.2,56.42 209.61,56.42 208.91,57.12 205.16,57.12 204.58,57.7 204.58,57.94 201.64,60.88 184.3,60.88 184.06,61.13 179.61,61.13 179.01,60.52 177.78,60.52 177.39,60.91 176.46,60.91 176.45,60.92 176.13,60.92 176.12,60.91 173.12,60.91 170.16,63.87 165.07,63.87 164.95,63.99 160.41,63.99 157.16,67.24 150.35,67.24 144.29,73.31 144.29,73.63 141.17,76.74 141.17,77.01 141.43,77.27 141.43,77.64 v2(141.09,77.98) ; v2(249.04,104.04) 248.8,104.28 244.31,104.28 241.74,106.85 238.05,106.85 237.01,105.8 234.28,105.8 233.56,105.09 233.56,102.06 230.48,98.97 230.48,86.77 v2(232.02,85.22)
  BOTTOM w0.076: UC1.BB17 122.78,90.58 122.78,88.87 124.36,87.29 124.36,87.13
  BOTTOM w0.127: 124.36,87.13 124.36,86.31 124.67,85.99 125.25,85.99 125.5,85.74 125.5,84.47 126.87,83.09 126.87,80.87 130.25,77.49 140.34,77.49 140.83,77.98 v2(141.09,77.98) ; v2(218.28,56.74) 218.49,56.94 218.49,70.07 219.25,70.83 v2(219.36,70.83) ; v2(251.61,115.2) 251.61,117.39 249.66,119.34 248.79,119.34 248.54,119.59 248.54,120.38 248.28,120.64 QZ15.1
SLEEVE: length 44.9
  TOP w0.127: v1(282.81,43.13) 283.96,44.27 v2(284.38,44.27)
  IN4 w1.016: 283.36,44.66 272.49,55.54 268.71,55.54 264.81,51.64 259.04,51.64 256.37,54.3 254.02,54.3 252.56,55.76 252.56,58.43 252.75,58.62 252.75,59.89
  vias: v2(252.58,60.69) v2(253.16,60.67) v2(284.38,44.84)
SLEEVE_R: length 2.7
  BOTTOM w0.127: 285.84,43.64 284.12,43.64 v1(283.42,42.94)
SLP_WLAN#_GATE: length 26
  TOP w0.127: v2(255.28,113.37) 255.62,113.03 255.62,109.85 253.36,107.59 v1(253.36,105.22) RE552.1
  BOTTOM w0.127: QZ15.2 247.63,122.15 247.1,121.62 247.1,120.74 RZ518.2 247.84,119.97 248.69,119.11 249.56,119.11 251.18,117.5 251.18,114.4 251.41,114.16 254.49,114.16 v2(255.28,113.37)
SLP_WLAN#_M: length 5.2
  BOTTOM w0.127: RZ71.1 250.16,121.06 DZ9.3 250.16,121.83 QZ15.3 248.93,123.99 v1(248.75,124.18)
SM_RCOMP0: length 12.6
  TOP w0.381: v2(121.31,88.3) 120.48,87.48 v1(120.48,85.53) 120.48,84.73 RC5.1
  IN2 w0.305: v2(121.31,88.3) 121.23,88.3 120.29,89.25 120.29,93.26 121.76,94.74 v2(121.98,94.74)
  BOTTOM w0.254: v2(121.98,94.74) 122.41,95.08 UC1.AR18
SM_RCOMP1: length 11.7
  TOP w0.381: v2(122.22,87.64) 122.07,87.49 v1(122.07,86.6) 122.07,84.54 RC6.1
  IN2 w0.305: v2(121.98,94.1) 121.75,94.1 120.84,93.2 120.84,92.65 120.84,91.03 121.23,90.64 121.23,89.78 122.45,88.56 122.45,87.87 v2(122.22,87.64)
  BOTTOM w0.254: v2(121.98,94.1) 122.41,94.43 UC1.AT18
SM_RCOMP2: length 10.9
  TOP w0.381: RC7.1 v1(122.9,85.46) 122.9,86.98 v2(122.9,86.99)
  IN2 w0.305: v2(121.97,93.47) 121.76,93.47 121.45,93.16 121.45,91.97 122.55,90.87 122.55,89.81 123.42,88.94 123.42,87.5 v2(122.9,86.99)
  BOTTOM w0.254: UC1.AU18 122.24,93.66 v2(121.97,93.47)
SML0_SMBCLK: length 245.1
  TOP w0.127: UL1.28 247.28,129.71 247.38,129.82 247.38,130.67 v2(246.98,131.07)
  IN1 w0.084: v2(236.05,66.75) 235.81,66.75 235.66,66.9 235.44,66.9 235.22,66.67 235.22,65.29 230.56,60.63 226.77,60.63 226.05,61.35 219.82,61.35 219.36,60.89 215.4,60.89 214.58,61.71 179.24,61.71 178.86,62.09 175.14,62.09 171.82,65.41 170.99,65.41 170.6,65.03 167.29,65.03 166.75,65.56 163.49,65.56 161.22,67.83 150.54,67.83 147.87,70.5 147.87,77.77 147.06,78.58 147.06,87.2 146.21,88.05 146.21,89.93 147.96,91.68 147.96,93.4 149.57,95.01 149.57,95.26 149.02,95.81 149.02,101.48 147.92,102.58 147.64,102.58 146.03,104.18 144.64,104.18 143.96,103.5 142.17,103.5 141.72,103.04 140.96,103.04 140.79,102.88 v2(140.79,102.84)
  IN4 w0.084: v2(236.05,66.75) 236.21,66.9 236.39,66.9 238.71,69.23 239.76,69.23 241.22,70.69 241.22,73.89 240.86,74.26 240.86,76.86 239.09,78.63 239.09,79.03 238.17,79.94 236.31,79.94 235.3,80.94 235.3,89.1 238.68,92.47 238.68,93.03 239.91,94.27 239.91,96.72 243.14,99.95 243.14,105.6 236.83,111.91 236.83,122.97 236.37,123.43 236.37,124.7 236.83,125.16 236.83,126.83 239.92,129.92 245.37,129.92 246,130.55 246.38,130.55 246.9,131.07 v2(246.98,131.07)
  BOTTOM w0.076: 136.85,102.93 136.83,102.93 136.81,102.96 135.69,102.96 135.58,102.84 132.88,102.84 132.76,102.72 132.32,102.72 131.96,102.88 130.99,102.88 130.78,103.08 130.78,103.34 130.2,103.92 128.33,103.92 128.11,104.15 128.11,104.29 127.96,104.43 127.96,105.1 UC1.R9
  BOTTOM w0.127: 136.85,102.93 137.89,102.93 138.21,103.26 139.4,103.26 139.65,103 140.63,103 v2(140.79,102.84) 140.97,103.02 141.49,103.02 141.69,102.82 CC318.1 142.56,102.39 RC19.1 RC347.1
SML0_SMBDATA: length 238
  TOP w0.127: v2(246.34,131.07) 245.83,130.57 245.83,129.68 246.08,129.43 UL1.31
  IN1 w0.084: v2(236.05,67.33) 235.88,67.33 235.66,67.11 235.35,67.11 235.01,66.76 235.01,65.38 230.47,60.84 226.86,60.84 226.14,61.56 219.73,61.56 219.28,61.11 215.49,61.11 214.67,61.92 179.33,61.92 178.95,62.3 175.23,62.3 171.91,65.62 170.9,65.62 170.51,65.24 167.38,65.24 166.84,65.77 163.58,65.77 161.31,68.04 150.63,68.04 148.08,70.59 148.08,77.86 147.27,78.67 147.27,87.28 146.42,88.14 146.42,89.84 148.17,91.59 148.17,93.31 149.78,94.92 149.78,95.34 149.23,95.89 149.23,101.56 148.01,102.79 147.72,102.79 146.12,104.39 144.55,104.39 143.87,103.71 142.09,103.71 141.63,103.26 140.96,103.26 v2(140.79,103.42)
  IN4 w0.084: v2(246.34,131.07) 246.34,130.81 246.29,130.77 245.91,130.77 245.28,130.14 239.83,130.14 236.62,126.92 236.62,125.25 236.16,124.79 236.16,123.34 236.62,122.88 236.62,111.83 242.93,105.51 242.93,100.04 239.7,96.81 239.7,94.36 238.47,93.12 238.47,92.56 235.09,89.18 235.09,80.85 236.22,79.73 238.06,79.73 238.88,78.91 238.88,78.54 240.65,76.77 240.65,74.17 241.01,73.81 241.01,70.78 239.67,69.44 238.63,69.44 236.34,67.16 236.22,67.16 v2(236.05,67.33)
  BOTTOM w0.076: 136.85,103.19 136.83,103.19 136.81,103.16 135.61,103.16 135.49,103.04 132.8,103.04 132.67,102.92 132.28,102.92 132.04,103.03 UC1.W2
  BOTTOM w0.127: 136.85,103.19 137.78,103.19 138.11,103.51 139.5,103.51 139.76,103.26 140.62,103.26 v2(140.79,103.42) 140.95,103.26 RC20.1 RC348.1
SML1_SMBCLK: length 212.1
  TOP w0.127: v2(176.36,64.4) 176.53,64.23 176.53,63.52 177.27,62.78 178.32,62.78 179.39,61.7 179.39,60.83 177.92,59.36 177.92,55.92 179.78,54.05 181.56,54.05 183.13,52.48 184.54,52.48 187.61,49.41 236.27,49.41 238.32,51.46 238.32,53.04 v2(238.48,53.2) ; UE1.D8 v2(248.68,89.86)
  IN1 w0.084: v2(141.14,105.91) 141.3,106.07 143.49,106.07 144.12,106.7 146.18,106.7 149.28,103.59 149.28,103.34 150.01,102.6 150.01,100.3 150.72,99.59 150.72,94 149.11,92.39 149.11,91.25 148.77,90.91 148.77,86.13 148.11,85.46 148.11,79.14 148.88,78.37 148.88,71.26 151.31,68.83 161.76,68.83 163.99,66.6 169.48,66.6 169.99,67.12 172.46,67.12 174.72,64.86 176.32,64.86 176.53,64.65 176.53,64.57 v2(176.36,64.4)
  BOTTOM w0.076: 136.85,104.05 136.83,104.05 136.81,104.08 135.61,104.08 135.21,103.67 133.15,103.67 133.05,103.57 132.75,103.57 132.19,103.4 131.94,103.4 131.85,103.44 131.66,103.44 131.65,103.44 131.57,103.4 131.34,103.4 UC1.W3
  BOTTOM w0.127: v2(248.68,89.86) 248.29,90.25 247.07,90.25 246.71,89.88 246.71,86.93 245.99,86.21 245.99,84.82 245.69,84.53 245.69,84.19 247.73,82.15 247.73,81.38 248.15,80.96 248.4,80.96 250.01,79.35 250.01,76.05 249.51,75.56 249.51,72.53 247.95,70.98 247.95,70.52 246.91,69.47 246.91,66.14 245.21,64.44 245.21,62.24 242.79,59.81 242.79,59 238.29,54.51 238.29,53.39 v2(238.48,53.2) ; v2(141.14,105.91) 141.2,105.86 CC319.1 ; v2(141.14,105.91) 141.01,106.04 140.65,106.04 140.46,105.85 138.71,105.85 138.23,105.37 138.23,105.02 137.26,104.05 136.85,104.05 ; v2(141.14,105.91) 141.3,106.07 142.05,106.07 RC15.1
SML1_SMBDATA: length 213.5
  TOP w0.127: v2(237.89,53.2) 238.06,53.03 238.06,51.56 236.16,49.66 187.72,49.66 184.65,52.74 183.23,52.74 181.67,54.3 179.89,54.3 178.17,56.02 178.17,59.25 179.64,60.72 179.64,61.81 178.42,63.03 177.38,63.03 176.77,63.64 176.77,64.23 v2(176.94,64.4) ; UE1.E11 v2(249.48,92.26)
  IN1 w0.084: v2(176.94,64.4) 176.74,64.6 176.74,64.74 176.41,65.07 174.81,65.07 172.55,67.33 169.9,67.33 169.39,66.81 164.08,66.81 161.85,69.04 151.39,69.04 149.09,71.34 149.09,78.46 148.32,79.23 148.32,85.38 148.98,86.04 148.98,90.83 149.32,91.16 149.32,92.3 150.93,93.91 150.93,99.68 150.22,100.39 150.22,102.69 149.49,103.42 149.49,103.68 146.26,106.91 144.03,106.91 143.4,106.28 141.36,106.28 v2(141.14,106.49)
  BOTTOM w0.076: UC1.V3 131.23,103.57 131.53,103.57 131.63,103.62 131.83,103.62 131.99,103.57 132.16,103.57 132.29,103.61 132.75,103.74 132.97,103.74 133.1,103.88 135.12,103.88 135.53,104.28 136.81,104.28 136.83,104.31 136.85,104.31
  BOTTOM w0.127: RC17.1 142.1,106.7 141.72,106.32 141.31,106.32 v2(141.14,106.49) 141.11,106.49 140.92,106.3 140.55,106.3 140.35,106.1 138.6,106.1 137.97,105.47 137.97,105.13 137.15,104.31 136.85,104.31 ; v2(237.89,53.2) 238.03,53.34 238.03,54.61 242.53,59.11 242.53,59.91 244.96,62.34 244.96,64.55 246.66,66.24 246.66,69.58 247.7,70.62 247.7,71.08 249.26,72.64 249.26,75.66 249.75,76.16 249.75,79.25 248.29,80.71 248.05,80.71 247.48,81.28 247.48,82.04 245.44,84.09 245.44,84.63 245.73,84.93 245.73,86.31 246.45,87.03 246.45,89.99 247.52,91.06 248.85,91.06 249.09,91.3 249.09,91.86 v2(249.48,92.26)
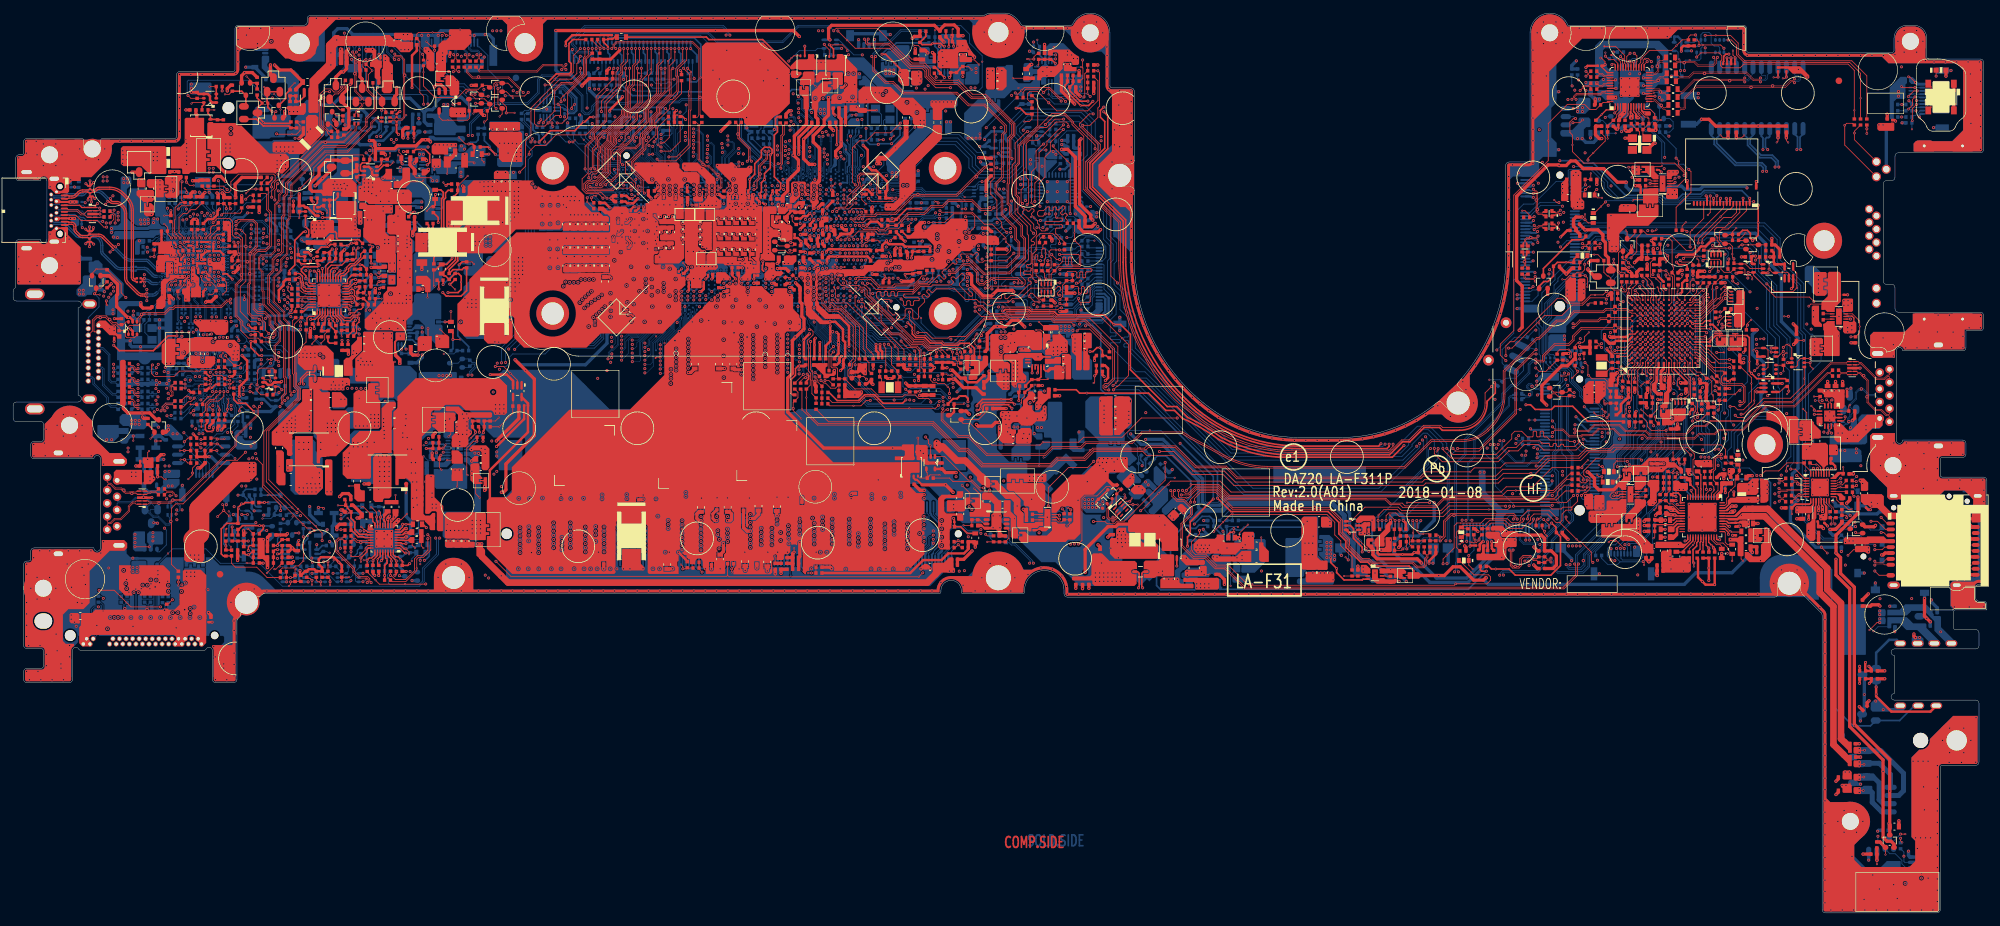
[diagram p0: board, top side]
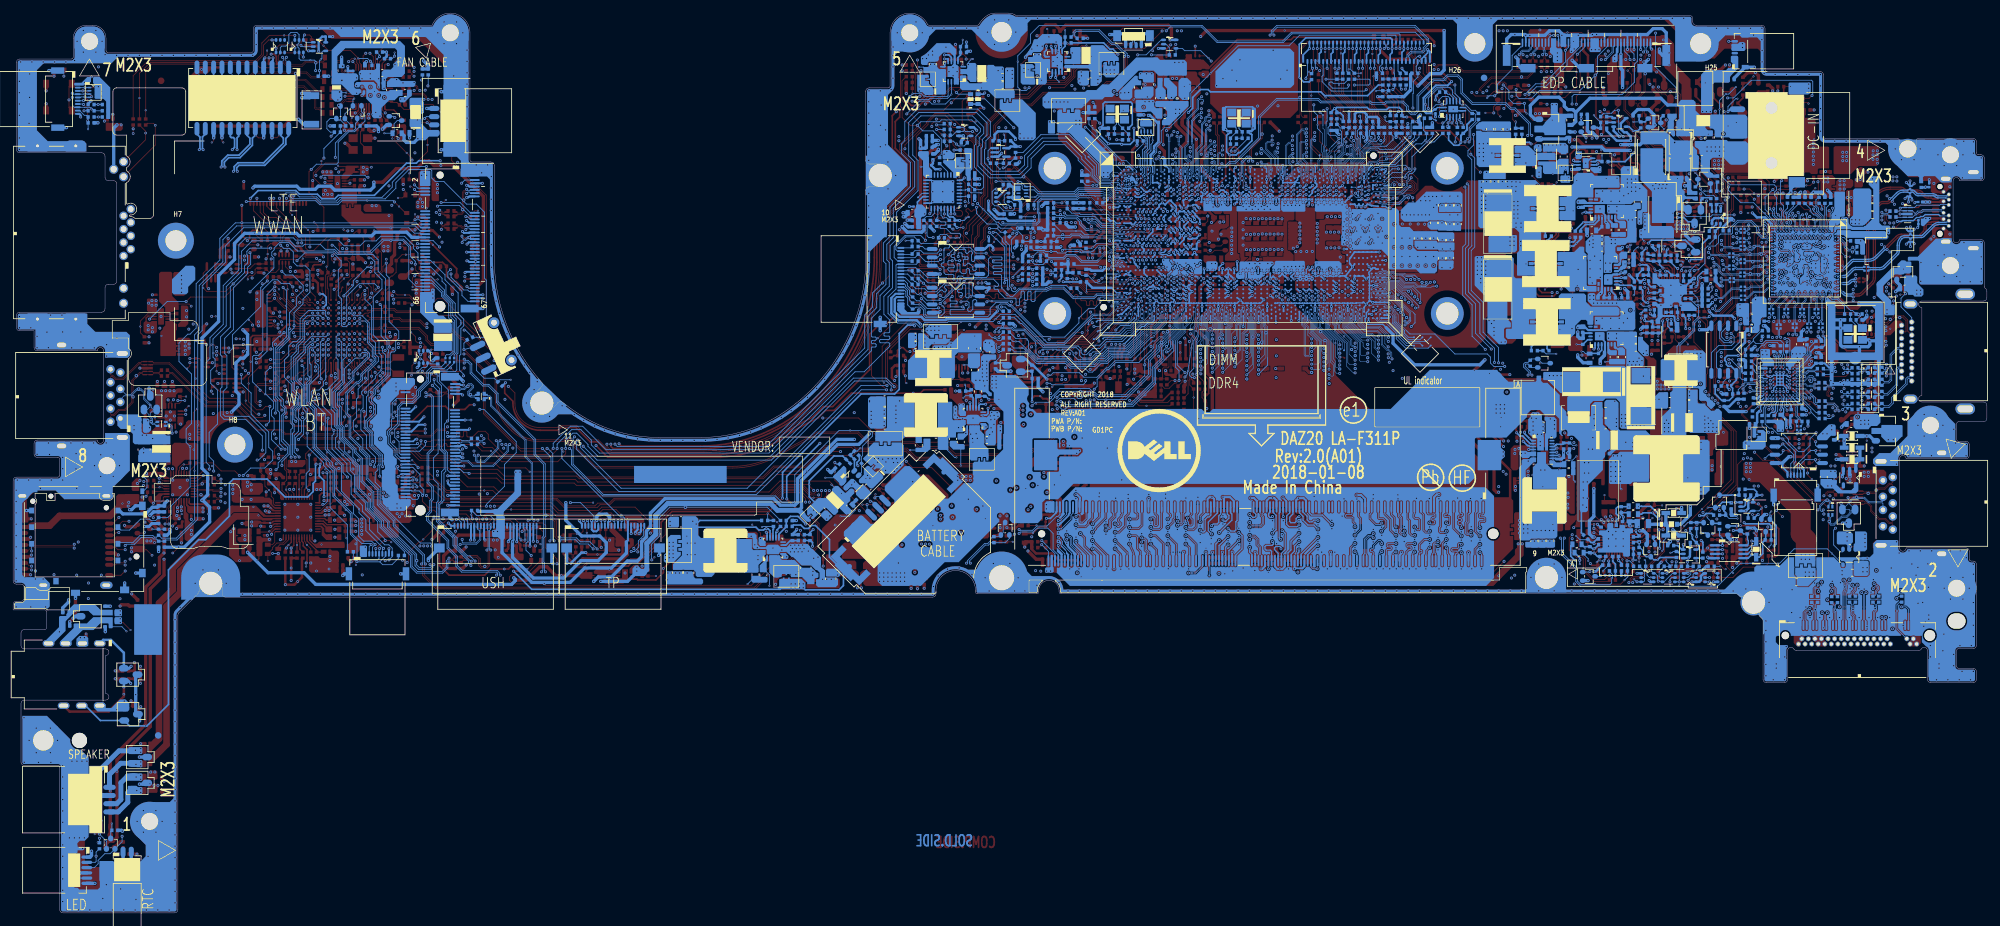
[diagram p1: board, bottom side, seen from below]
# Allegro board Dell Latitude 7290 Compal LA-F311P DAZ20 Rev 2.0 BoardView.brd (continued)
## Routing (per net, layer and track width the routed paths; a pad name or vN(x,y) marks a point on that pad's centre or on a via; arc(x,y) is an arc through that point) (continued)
SNB_+1VALWP: length 1
  BOTTOM w0.127: 154.87,83.56 v1(155.88,83.56)
SNK0_CONFIG1: length 2.8
  TOP w0.127: v2(28.03,102.9) 27.87,103.06 27.87,103.99 RT129.1 RT337.1
  BOTTOM w0.127: UT1.N4 v2(28.03,102.9)
SNU_DDR: length 1.5
  TOP w0.127: PR202.2 v1(66.12,69.04)
SNUB_1.8VALW: length 4.6
  BOTTOM w0.127: v1(174.64,60.48) 173.33,60.48 172.43,61.38 172.43,61.82 PR502.2
  BOTTOM w0.508: PC506.1 172.83,62.39 PR502.2
SNUB_1V_PRIM: length 3.1
  TOP w0.127: PR409.2 v1(152.3,127.26)
  TOP w0.508: PC419.1 PR409.2
SNUB_1VS_VCCIO: length 2.2
  TOP w0.127: PC401.1 136.9,130.17 v1(136.47,130.61)
  TOP w0.508: PC401.1 138.01,130.17 138.06,130.12 PR405.2
SNUB_CHG1:
  vias: v1(40.54,68.09)
SNUB_CHG2: length 1.3
  TOP w0.127: PC941.1 v1(51.15,65.1)
SPKR: length 148.7
  TOP w0.127: RA12.2 253.49,66.74 v2(253.49,67.12) ; RC183.1 v2(140.68,85.51) 140.43,85.75 139.42,85.75 138.52,86.65 136.9,86.65 135.15,88.4 133.89,88.4 133.4,88.9 133.4,89.08 132.23,90.25 132.23,91.25 131.06,92.42 131.06,92.53 130.73,92.86 v2(130.36,92.86) ; v2(236.58,60.36) 236.58,59.97 v1(237.09,59.46)
  IN1 w0.084: v2(253.49,67.12) 253.06,66.69 251.42,66.69 250.16,65.42 247.16,65.42 242.99,61.25 240.25,61.25 238.9,59.9 237.04,59.9 v2(236.58,60.36)
  IN2 w0.122: v2(140.68,85.51) 141.35,84.83 142.26,84.83 147.7,79.39 147.7,72.43 150.63,69.5 158.06,69.5 161.46,66.1 165.69,66.1 166.13,65.66 171.89,65.66 172.68,64.88 173.8,64.88 174.07,65.15 178.83,65.15 179.58,64.39 183.32,64.39 185.04,62.67 202.46,62.67 204.39,60.75 214.29,60.75 214.77,60.27 218.25,60.27 218.91,60.92 226.53,60.92 226.76,61.15 235.8,61.15 236.58,60.36 v2(236.58,60.36)
  BOTTOM w0.076: UC1.AW5 130.14,93.09 v2(130.36,92.86)
SPKR_R: length 2.9
  TOP w0.127: CA27.1 252.3,64.27 CA72.1 RA51.1 RA12.1
SRTCRST#: length 20.2
  TOP w0.076: 124.55,93.08 124.39,93.23 124.39,94.52 124.32,94.6 124.32,96.91 124.13,97.1 123.58,97.1 v1(123.39,96.91) 123.16,96.68 v2(122.91,96.68)
  TOP w0.127: 124.55,93.08 124.83,93.08 125.38,92.53 126.17,92.53 129.51,89.18 129.51,85.98 129.82,85.67 CC24.1 130.39,83.91 130.39,82.64 RC56.1
  BOTTOM w0.102: v2(122.91,96.68) 122.63,96.4 UC1.AN18
SS_1V_PRIM: length 22
  TOP w0.254: v2(164.5,123.75) 163.87,123.12 v1(162.64,123.12) 160.25,125.5 160.25,126.21 160.62,126.58 PC420.1 PR428.1
  IN1 w0.254: v2(164.5,123.75) 165.34,124.59 165.34,125.09 163.93,126.49 160.49,126.49 159.83,127.15 159.83,130.07 159.07,130.83 v2(158.82,130.83)
  BOTTOM w0.254: PU402.7 157.75,130.44 158.15,130.83 v2(158.82,130.83)
SS_1VS_VCCIO: length 7
  TOP w0.254: PR427.1 139.07,133.65 PC410.1 138.5,132.39 139.87,132.39 v1(140.06,132.58) 141.31,132.58 141.74,132.15 v2(141.88,132.15)
  BOTTOM w0.254: PU401.7 v2(141.88,132.15)
SUSACK#: length 168.8
  TOP w0.127: RC443.1 147.23,87.72 v2(147.55,88.04) 147.55,88.3 v1(147.84,88.59) ; UE1.K12 v2(254.3,93.08)
  IN2 w0.122: v2(254.3,93.08) 254.77,93.55 257.16,93.55 258.62,92.09 261.05,92.09 261.66,91.48 261.66,87.25 262.47,86.45 262.47,83.88 263.42,82.93 263.42,81.95 264.09,81.29 264.09,74.85 260.78,71.54 256.76,71.54 256.46,71.84 253.39,71.84 252.72,71.17 249.71,71.17 249.11,70.57 245.92,70.57 244.95,69.59 244.4,69.59 242.58,67.77 242.58,66.37 242.22,66.01 241.69,66.01 240.87,66.83 236.83,66.83 234.79,64.79 231.04,64.79 228.36,64.79 227.84,64.27 226.33,64.27 225.43,63.37 205.5,63.37 203.82,65.05 186.14,65.05 184.33,66.86 180.46,66.86 178.27,69.05 176.68,69.05 175.96,69.77 173.33,69.77 172.39,70.71 160.29,70.71 159.08,71.93 151.75,71.93 150.89,72.79 150.89,74.87 150.11,75.65 150.11,83.16 149.2,84.07 149.2,86.9 148.07,88.04 v2(147.55,88.04)
SUSACK#_R: length 30.7
  TOP w0.127: RC550.1 147.26,84.78 147.26,86.26 RC443.2 146.97,86.29 146.52,86.75 146.52,87.94 v2(146.85,88.27)
  IN1 w0.084: v2(133.82,89.23) 133.45,89.61 129.06,89.61 126.14,92.53 126.14,94.84 v2(125.66,95.32)
  IN2 w0.122: v2(133.82,89.23) 134.14,88.91 136.93,88.91 137.18,89.16 138.41,89.16 139.23,88.35 142.87,88.35 143.1,88.57 143.11,88.58 146.54,88.58 v2(146.85,88.27)
  BOTTOM w0.102: UC1.AP11 v2(125.66,95.32)
SUSCLK: length 298.4
  TOP w0.127: RZ56.2 234.44,67.89 231.52,64.96 227.46,64.96 226.67,64.17 185.56,64.17 183.89,65.84 176.36,65.84 v1(174.49,63.97) 171.84,61.33 v2(171.78,61.33) ; v2(124.99,86.37) 124.29,85.67 124.29,82.7 RC48.1
  IN1 w0.084: v2(137.31,81.16) 136.87,81.16 136.1,81.93 136.1,83.32 133.88,85.55 126.96,85.55 126.13,86.37 v2(124.99,86.37) ; v2(13.74,47.97) 20.84,47.97 22.98,50.1 22.98,50.8 23.31,51.13 24.55,51.13 24.78,50.9 32.06,50.9 33.33,52.16 39.58,52.16 40.04,52.62 42.85,52.62 45.02,54.8 47.96,54.8 48.86,53.9 48.86,53.58 49.39,53.04 58.97,53.04 59.31,53.38 59.9,53.38 62.48,55.96 62.65,55.96 63.75,57.06 63.75,57.2 64.12,57.57 65.48,57.57 65.71,57.34 69.15,57.34 69.51,56.98 71.62,56.98 72.27,57.63 72.27,62.7 71.42,63.56 71.42,65.64 73.61,67.83 77.14,67.83 77.62,67.35 141.35,67.35 142.77,65.92 143.94,65.92 144.46,66.44 v2(145.83,66.44) 145.86,66.44 145.91,66.39 145.91,64.41 147.87,62.45 157.43,62.45 157.59,62.61 160.62,62.61 162.66,60.56 165.86,60.56 v2(166.14,60.29)
  IN4 w0.084: v2(145.83,66.44) 145.92,66.54 145.92,68.71 143.83,70.8 143.83,73.99 143.11,74.71 143.11,79.39 142.73,79.77 142.73,80.29 v2(143.19,80.76)
  IN4 w0.135: v2(166.14,60.29) 166.77,60.91 171.37,60.91 v2(171.78,61.33)
  BOTTOM w0.076: 124.56,87.32 122.94,88.94 122.94,90.87 122.67,91.13 UC1.BA17
  BOTTOM w0.127: v2(143.19,80.76) 142.68,80.76 142.46,80.53 137.69,80.53 137.31,80.91 v2(137.31,81.16) ; v2(124.99,86.37) 124.67,86.69 124.67,87.21 124.56,87.32 ; RN99.2 13.41,48.3 v2(13.74,47.97)
SUSCLK_R: length 6.7
  BOTTOM w0.127: JNGFF3.68 13.71,43.31 v1(13.71,46.03) 13.71,46.97 13.29,47.38 RN99.1
SW_+1VALWP:
  vias: v1(160.37,86.91) v2(153.36,85.85) v2(153.92,86.01) v2(157.81,86.86) v2(157.86,86.28) v2(158.49,86.25) v2(158.47,85.68) v2(158.49,85.11) v2(159.1,86.32) v2(159.13,85.7) v2(159.15,85.14) v2(159.71,86.23) v2(159.76,85.61) v2(160.36,86.23) v2(160.42,85.61)
SW_USB20_N9: length 3.5
  TOP w0.104: UI3.11 277.01,73.91 276.76,73.66 276.76,73.44 277.05,73.15 v2(277.05,73.15)
  BOTTOM w0.104: v2(277.05,73.15) 276.66,73.54 276.66,74.16 276.97,74.46 277.14,74.46 277.34,74.26 LI7.1
SW_USB20_P9: length 3.5
  TOP w0.104: v2(276.46,73.15) 276.47,73.15 276.57,73.26 276.57,73.79 276.51,73.86 UI3.10
  BOTTOM w0.104: v2(276.46,73.15) 276.46,74.24 276.89,74.66 277.11,74.66 277.32,74.86 LI7.4
SYS_PWROK: length 219.9
  TOP w0.127: v2(225.26,80.29) 224.26,79.28 224.26,77.75 arc(223.16,75.11) 220.53,74.02 217.79,74.02 217.46,74.34 214.88,74.34 212.66,72.12 211.54,72.12 209.62,70.19 195.42,70.19 arc(187.33,71.58) 180.17,75.6 178.5,76.95 arc(175.52,79.88) 173.13,83.32 172.26,84.87 arc(169.42,91.92) 168.45,99.46 168.45,105.27 163.42,110.3 163.42,114.51 165.26,116.35 165.26,117.2 162.48,119.98 162.48,120.35 163.96,121.83 v2(164.55,121.83) ; v2(231.97,83.09) 232.5,82.56 233.5,82.56 v3(234.03,83.09) RE548.1 RE56.1
  IN2 w0.122: v2(225.26,80.29) 229.3,80.29 231.97,82.96 v2(231.97,83.09) ; v2(137.36,119.81) 137.56,120.01 137.56,121.23 137.18,121.62 137.18,124.19 134.09,127.28 131.05,127.28 129.33,129 125.37,129 124.73,128.36 121.87,128.36 121.64,128.59 116.48,128.59 114.52,126.63 99.16,126.63 98.83,126.96 95.59,126.96 95.24,126.6 93.27,126.6 93.14,126.48 90.08,126.48 v2(89.2,125.59)
  IN4 w0.084: v2(148.25,119.73) 142.09,119.73 141.89,119.53 137.64,119.53 v2(137.36,119.81)
  BOTTOM w0.076: 131.85,113.22 131.62,112.99 130.02,112.99 129.57,112.54 UC1.B6
  BOTTOM w0.127: v2(148.25,119.73) 152.66,124.13 157.85,124.13 158.64,123.34 160.71,123.34 161.15,123.78 162.62,123.78 164.55,121.85 v2(164.55,121.83) ; RC129.1 89.37,125.76 v2(89.2,125.59) ; 131.85,113.22 132.66,114.03 132.66,115.25 137.22,119.81 v2(137.36,119.81)
SYS_RESET#: length 217.7
  TOP w0.127: v2(157.25,120.22) 158.69,121.65 160.19,121.65 161.32,120.52 161.32,120.2 163.11,118.41 163.11,110.29 167.24,106.16 167.24,97.1 168.24,96.1 v2(168.24,96.05) ; v1(258.19,106.42) 258.56,106.8 JAPS1.13 v2(258.56,109.33)
  IN1 w0.084: v2(209.01,71.48) 209.54,72 210.09,72 210.54,72.44 212.84,72.44 214.36,73.97 220.97,73.97 223.35,76.34 223.35,81.44 225.79,83.89 225.79,85.58 v2(226.05,85.84)
  IN2 w0.122: v2(157.25,120.22) 156.97,120.51 150.49,120.51 150.01,120.02 150.01,116.74 149.56,116.3 149.56,113.91 v2(149.86,113.61)
  BOTTOM w0.076: 135.31,112.75 135.31,112.45 134.68,111.83 133.65,111.83 133.43,112.05 133.43,112.57 133.13,112.87 132.4,112.87 132.06,112.52 131.64,112.52 131.5,112.38 131.17,112.38 130.89,112.66 UC1.B5
  BOTTOM w0.127: v2(168.24,96.05) 169.76,94.54 169.76,92.38 170.97,91.17 170.97,86.13 185.96,71.14 208.67,71.14 v2(209.01,71.48) ; v2(258.56,109.33) 258.13,108.9 254.52,108.9 253.88,108.27 251.31,108.27 250.7,108.88 244.02,108.88 242.39,110.5 242.39,111.36 240.39,113.36 237.08,113.36 236.92,113.2 236.92,112.06 236.38,111.52 235.06,111.52 231.63,108.08 230.12,108.08 228.88,106.85 228.88,96.77 228.61,96.5 228.61,88.41 v2(226.05,85.84) ; v2(149.86,113.61) 149.61,113.61 RC224.2 148.14,115.09 CC302.1 RC291.1 146.84,115.95 144.12,118.67 139.78,118.67 135.31,114.19 135.31,112.75
SYS_RESET#_R: length 3.3
  BOTTOM w0.127: v1(150.38,113.43) 150.9,113.95 RC290.2 RC224.1 149.83,114.85 UC12.4
SYSTEM_ID: length 13.6
  TOP w0.127: UE1.J10 v2(253.48,91.46) ; v2(253.96,99.48) 254.21,99.24 255.7,99.24 255.93,99.01 CE47.1 RE300.1 256.82,99.52 v1(256.56,99.77)
  IN1 w0.084: v2(253.96,99.48) 254.05,99.4 254.05,98.74 253.54,98.23 253.54,96.35 253.26,96.07 253.26,93.56 253.06,93.36 253.06,91.88 v2(253.48,91.46)
TACH_FAN1: length 62.1
  TOP w0.127: v2(237.63,120.5) 238.69,120.5 v3(239.11,120.91) ; UE1.E3 v2(249.48,85.06)
  IN1 w0.084: v2(238.76,87.56) 238.76,88.12 238.92,88.29 238.92,93 240.75,94.83 240.75,113.11 237.18,116.68 237.18,119.4 237.63,119.85 v2(237.63,120.5)
  IN2 w0.122: v2(249.48,85.06) 249.36,85.06 248.89,84.59 246.84,84.59 246.58,84.85 246.58,85.38 245.14,86.83 242.96,86.83 242.41,86.28 242.41,85.96 242.26,85.81 240.5,85.81 v2(238.76,87.56) ; v2(237.63,120.5) 237.55,120.5 236.04,122 236.04,125.73 237.32,127.01 v2(238.49,127.01)
  BOTTOM w0.127: RE51.2 238.35,127.15 v2(238.49,127.01) ; v2(237.63,120.5) 237.3,120.16 JFAN1.3
TBT_CIO_PLUG_EVENT#: length 175
  TOP w0.127: v2(31.77,106.44) 32.03,106.69 v1(33.81,106.69) 34.57,106.69 34.82,106.94 RT371.1
  IN2 w0.122: v2(40.37,112.62) 40.71,112.28 41.81,112.28 44.88,115.35 44.88,117.64 43.53,118.98 42.21,118.98 40.46,120.74 40.46,122.69 41.07,123.3 46.42,123.3 46.99,123.87 53.75,123.87 54.27,123.35 54.27,123.33 56.05,121.55 59.21,121.55 61.94,124.28 61.94,124.32 62.14,124.52 68.12,124.52 69.16,125.57 70.84,125.57 71.23,125.17 71.3,125.11 71.89,125.11 71.96,125.17 72.75,125.17 74.36,123.56 81.72,123.56 82.87,124.72 91.18,124.72 91.72,125.26 93.22,125.26 93.62,124.85 97.1,124.85 98.09,125.84 116.11,125.84 117.31,127.04 120.38,127.04 120.98,127.65 126.36,127.65 126.46,127.56 129.82,127.56 130.78,126.59 133.75,126.59 136.18,124.17 v2(136.18,123.61) 136.4,123.38 136.4,118 135.01,116.61 135.01,111.54 134.68,111.21 134.68,110.49 135.15,110.02 135.15,105.65 135.71,105.09 136.67,105.09 136.88,104.89 136.88,103.86 136.38,103.36 132.99,103.36 132.73,103.1 126.45,103.1 126.13,102.79 v2(126.13,102.63)
  BOTTOM w0.076: UT1.W2 31.15,104.14 31.15,104.57 31.27,104.68 31.27,105.07 31.52,105.32 31.52,105.53 ; v2(126.13,102.63) UC1.AB12
  BOTTOM w0.127: RT391.1 135.91,123.34 v2(136.18,123.61) ; v2(40.37,112.62) 40.37,112.29 39.1,111.02 32.4,111.02 32.06,110.68 32.06,110.21 32.32,109.94 32.32,109.37 32.06,109.11 32.06,106.72 v2(31.77,106.44) 31.52,106.18 31.52,105.53
TBT_DP_RBIAS: length 7
  TOP w0.127: RT35.1 33.81,102.1 v2(33.63,102.28)
  IN2 w0.122: v2(33.63,102.28) 32.66,102.28 31.61,101.23 30.34,101.23 29.53,102.05 29.13,102.05 v2(28.68,101.6)
  BOTTOM w0.127: UT1.N6 v2(28.68,101.6)
TBT_FORCE_PWR: length 156.1
  TOP w0.127: v2(25.74,111.48) 25.68,111.42 25.68,108.65 26.03,108.3 ; 26.03,108.3 25.46,108.3 24.66,107.49 24.66,105.73 24.58,105.65 24.58,103.75 v1(24.77,103.57) v2(25.44,102.9) ; 26.03,108.3 RT27.1
  IN1 w0.084: v2(132.52,124.78) 132.52,125.25 128.7,129.07 126.36,129.07 123.09,132.34 123.09,134.12 v2(122.71,134.5)
  IN2 w0.122: v2(25.74,111.48) 25.74,111.62 27.52,113.4 27.52,121.06 31.19,124.73 34.9,124.73 36.83,126.66 40.26,126.66 40.56,126.96 45.79,126.96 46.9,128.07 61.27,128.07 62.5,129.3 75.67,129.3 76.31,128.65 79.64,128.65 82.9,131.91 82.9,132.27 84.12,133.49 106.42,133.49 107.93,135 122.21,135 v2(122.71,134.5) ; v2(132.52,124.78) 133.89,124.78 134.66,124.01 134.66,121.41 134.5,121.25 134.5,120.03 134.25,119.79 131.47,119.79 130.61,118.93 130.61,116.88 v2(129.25,115.52)
  BOTTOM w0.112: v2(129.25,115.52) 128.93,115.2 128.93,113.8 128.6,113.47 128.6,112.96 UC1.B7
  BOTTOM w0.127: UT1.H4 v2(25.44,102.9)
TBT_I2C_SCL: length 52.7
  IN1 w0.084: v2(30.58,106.7) 30.58,106.36 31.22,105.72 31.22,104.11 31.95,103.38 31.95,100.78 32.23,100.51 32.23,95.49 31.7,94.97 30.98,94.97 30.61,95.35 30.61,95.97 30.18,96.4 28.94,96.4 27.61,95.07 27.06,95.07 24.53,92.54 24.53,87.84 24.86,87.51 25.94,87.51 26.22,87.79 27.57,87.79 28.32,87.04 29.46,87.04 30.79,85.71 30.79,84.44 31.47,83.76 32.71,83.76 34.2,82.27 34.2,79.55 32.9,78.26 32.9,77.61 33.14,77.38 v2(33.22,77.38)
  BOTTOM w0.076: 33.16,77.44 33.02,77.58 33.02,77.89 32.77,78.14 32.77,78.72 UT5.D2 ; 30.03,105.13 30.23,104.93 30.23,104.15 UT1.U2
  BOTTOM w0.127: 30.03,105.13 30.03,105.38 30.53,105.88 30.53,106.66 v2(30.58,106.7) 30.52,106.7 29.49,107.74 RT19.1 ; 33.16,77.44 v2(33.22,77.38)
TBT_I2C_SDA: length 53.6
  IN1 w0.084: v2(30.11,106.33) 30.31,106.33 31.01,105.63 31.01,104.03 31.74,103.29 31.74,100.69 32.02,100.42 32.02,95.58 31.62,95.18 31.07,95.18 30.82,95.43 30.82,96.06 30.27,96.61 28.85,96.61 27.53,95.29 26.97,95.29 24.32,92.63 24.32,87.76 24.77,87.3 26.03,87.3 26.31,87.58 27.48,87.58 28.24,86.83 29.38,86.83 30.58,85.62 30.58,84.35 31.39,83.55 32.62,83.55 33.99,82.19 33.99,79.64 32.69,78.34 32.69,77.32 v2(33.22,76.8)
  BOTTOM w0.076: UT5.D1 32.52,78 32.79,77.73 32.79,77.44 ; 29.83,105.05 30.03,104.85 30.03,104.77 29.96,104.7 29.88,104.7 29.78,104.6 29.78,104.27 29.84,104.2 29.95,104.2 30.01,104.27 UT1.U1
  BOTTOM w0.127: 32.79,77.44 32.79,77.23 v2(33.22,76.8) ; RT18.1 30.11,106.7 v2(30.11,106.33) 30.28,106.17 30.28,105.99 29.77,105.49 29.77,105.1 29.83,105.05
TBT_JTAG_TCK: length 3.8
  TOP w0.127: v2(29.33,102.9) 30.07,103.64 30.07,104.44 v1(30.15,104.52) 30.41,104.79 30.81,104.79 31.26,105.23 RT6.1
  BOTTOM w0.127: UT1.T4 v2(29.33,102.9)
TBT_JTAG_TDI: length 1.3
  TOP w0.127: RT8.1 31.62,102.56 v2(31.29,102.9)
  BOTTOM w0.127: v2(31.29,102.9) 31.61,103.22 UT1.Y4
TBT_JTAG_TDO: length 2.1
  TOP w0.127: v2(30.63,102.9) 30.63,102.98 v1(31.01,103.35) 31.11,103.45 RT5.1
  BOTTOM w0.127: UT1.W4 v2(30.63,102.9)
TBT_JTAG_TMS: length 2.4
  TOP w0.127: RT7.1 29.98,103.07 v2(29.98,102.9)
  BOTTOM w0.127: UT1.V4 v2(29.98,102.9)
TBT_PCIE_RBIAS: length 5.5
  TOP w0.127: v2(28.68,97.05) 28.7,97.03 28.7,96.53 29.06,96.17 30.2,96.17 30.9,95.47 RT34.1 30.34,94.31 v1(29.83,94.31)
  BOTTOM w0.112: UT1.N16 v2(28.68,97.05)
TBT_PWR_EN: length 11.4
  BOTTOM w0.076: UC1.D7 129.33,110.93 130.11,110.93 130.29,110.75 131.23,110.75 131.42,110.94 131.42,111.12 132.29,111.99 132.3,111.99 132.72,111.99 133.07,111.64 134.77,111.64 135.67,112.53
  BOTTOM w0.127: 135.67,112.53 135.67,114.09 T269.1
TBT_RBIAS: length 2.3
  TOP w0.127: RT39.2 26.77,100.97 25.49,102.25 v2(25.43,102.25)
  BOTTOM w0.127: UT1.H6 v2(25.43,102.25)
TBT_RESET_N_EC: length 408.9
  TOP w0.127: RT11.1 24.32,105.13 24.32,103.36 v2(24.78,102.9) ; RE506.1 259.82,90.71 v2(260.08,90.98) ; v2(235.21,60.09) 235.21,60.17 234.05,61.32 230.71,61.32 229.68,60.29 229.68,59.8 229.38,59.5 228.27,59.5 227.66,60.11 224.28,60.11 223.62,59.44 220.53,59.44 220.53,59.45 219.97,59.45 219.54,59.02 219.54,55.65 v1(218.4,54.51) 217.85,53.96 v2(217.85,53.24)
  IN1 w0.084: v2(27.81,73.82) 27.56,73.82 26.94,73.19 26.94,64.76 23.51,61.33 23.51,57.49 19.4,53.38 17.88,53.38 16.84,52.34 v2(16.84,52.22) ; v2(71.93,51.5) 72.64,51.5 73.86,50.28 126.87,50.28 129.94,53.35 141.12,53.35 142.47,54.7 146.28,54.7 148.02,56.44 160.44,56.44 160.68,56.68 161.36,56.68 161.69,56.35 v2(161.69,56.25)
  IN2 w0.122: v2(161.69,56.25) 162.82,55.12 178.61,55.12 179.87,53.86 181.73,53.86 182.78,52.81 183.19,52.81 183.84,52.16 187.02,52.16 187.49,51.69 196.89,51.69 197.95,52.75 201.65,52.75 203.14,51.26 206.33,51.26 207.3,52.22 208.98,52.22 209.78,53.02 214.15,53.02 214.43,52.74 217.36,52.74 v2(217.85,53.24) ; v2(27.81,73.82) 29.95,75.96 30.59,75.96 31,76.37 31,76.86 34.08,79.94 34.08,81.93 34.47,82.32 34.7,82.32 35.4,83.02 35.4,85.42 v2(34.99,85.83)
  IN4 w0.084: v2(16.84,52.22) 14.32,49.7 14.32,44.73 15.1,43.95 19.04,43.95 20.79,45.71 22.91,45.71 24.66,47.45 24.66,50.53 24.99,50.86 29.98,50.86 31.07,51.95 37.01,51.95 39.17,49.79 61.06,49.79 65.51,54.24 68.5,54.24 71.25,51.5 v2(71.93,51.5) ; v2(260.08,90.98) 257.62,90.98 256.09,89.46 247.61,89.46 246.61,88.45 246.61,84.85 246.91,84.54 246.91,83.12 246.55,82.76 246.55,78.9 245.31,77.66 245.31,74.44 246.04,73.71 246.04,69.99 244.83,68.78 244.83,67.68 244.4,67.24 244.4,65.4 242.78,63.79 242.78,60.35 241.89,59.46 235.91,59.46 235.28,60.09 v2(235.21,60.09) ; v2(24.78,102.9) 24.87,102.9 26.37,104.4 28.04,104.4 29.35,105.7 31.29,105.7 31.6,106.02 32.97,106.02 33.56,105.42 33.56,104.39 32.65,103.48 32.65,101.44 32.97,101.11 32.97,94.86 31.64,93.53 27.72,93.53 26.18,91.99 25.41,91.99 24.59,91.17 24.59,90.21 23.96,89.58 23.96,86.16 24.81,85.32 24.81,75.83 26.82,73.82 v2(27.81,73.82)
  BOTTOM w0.127: RT110.2 31.92,86.96 33.55,86.96 33.93,86.57 34.25,86.57 v2(34.99,85.83) ; UT1.F4 v2(24.78,102.9)
TBT_RESET_N_EC_R: length 7.9
  TOP w0.127: UE1.L8 v2(255.08,89.86) ; RE95.1 260.3,91.63 v2(260.08,91.63) RE506.2
  IN4 w0.084: v2(260.08,91.63) 257.09,91.63 255.32,89.86 v2(255.08,89.86)
TBT_ROM_CLK: length 30.2
  TOP w0.127: v2(37.48,89.83) 37.35,89.83 37.03,90.15 36.16,90.15 34.61,91.7 34.61,95.47 35.45,96.31 35.45,103.39 v1(34.8,104.04) 34.58,104.25 v2(33.96,104.25)
  BOTTOM w0.076: 33.7,104.12 33.48,103.9 33.48,103.65 33.06,103.24 32.54,103.24 32.31,103.01 UT1.AB4
  BOTTOM w0.127: v2(33.96,104.25) 33.83,104.25 33.7,104.12 ; UT2.6 40.7,82.7 41.18,83.18 41.18,85.39 40.65,85.92 38.8,85.92 37.63,87.1 37.63,89.68 v2(37.48,89.83)
TBT_ROM_CS#: length 24.9
  TOP w0.127: RT2.1 38.03,89.38 38.03,90.02 37.56,90.5 v2(37.49,90.5) 37.28,90.7 v1(36.51,90.7) 36.47,90.7 35.75,91.42 35.75,95.9 35.96,96.11 35.96,100.64 36.99,101.67 36.99,105.03 36.52,105.5 34.62,105.5 v2(33.96,104.84)
  BOTTOM w0.076: 33.58,104.69 33.53,104.63 33.53,104.43 33.27,104.18 33.27,103.8 32.94,103.46 UT1.AC3
  BOTTOM w0.127: UT2.1 38.16,90.02 37.68,90.5 v2(37.49,90.5) ; 33.58,104.69 33.73,104.84 v2(33.96,104.84)
TBT_ROM_DI: length 34.7
  TOP w0.127: v2(38.96,88.36) 38.46,88.86 38.46,89.96 38.01,90.41 38.01,90.77 v1(37.82,90.97) 37.73,91.06 36.43,91.06 35.98,91.51 35.98,95.8 36.19,96.01 36.19,100.55 37.22,101.57 37.22,105.12 36.61,105.73 34.27,105.73 v2(33.96,105.42)
  BOTTOM w0.076: 33.38,104.92 33.3,104.84 33.3,104.48 33.09,104.28 33.09,103.85 32.93,103.7 32.54,103.7 UT1.AB3
  BOTTOM w0.127: UT2.5 41.97,85.4 40.85,86.52 38.92,86.52 38.51,86.93 38.51,87.91 v2(38.96,88.36) ; v2(33.96,105.42) 33.88,105.42 33.38,104.92
TBT_ROM_DO: length 25.5
  TOP w0.127: v2(33.96,103.64) 34.22,103.64 34.94,102.93 34.94,96.59 34.1,95.75 34.1,91.06 34.99,90.17 34.99,89.57 v1(35.55,89.02) 35.91,88.66 37.31,88.66 RT3.1 38.26,87.71 v2(38.98,87.71)
  BOTTOM w0.076: UT1.AC4 33.24,103 33.7,103.46
  BOTTOM w0.127: v2(33.96,103.64) 33.88,103.64 33.7,103.46 ; v2(38.98,87.71) 39.4,87.28 39.87,87.28 40.41,87.82 40.41,88.54 UT2.2
TBT_ROM_HOLD#: length 2.4
  BOTTOM w0.127: UT2.7 39.43,81.69 40.19,80.93 40.19,80.63 RT1.1
TBT_ROM_WP#: length 31.4
  TOP w0.127: v2(39.01,87.07) 37.88,87.07 RT4.1 37.31,87.64 35.86,87.64 34.7,88.81 34.7,90.1 33.83,90.97 33.83,95.81 34.71,96.68 34.71,102.64 34.35,103 v1(34,103) 33.79,103 33.42,103.37 33.42,105.45 33,105.87 31.09,105.87 v2(30.47,105.25)
  BOTTOM w0.076: UT1.V1 v2(30.47,105.25)
  BOTTOM w0.127: UT2.3 40.7,87.62 40.03,86.95 39.13,86.95 v2(39.01,87.07)
TBT_RSENSE: length 1.9
  TOP w0.127: v2(25.43,101.62) 25.86,101.19 RT39.1
  BOTTOM w0.127: v2(25.43,101.62) 26.1,101.62 UT1.J6
TBT_SRC_CFG1: length 10.3
  TOP w0.127: v2(32.6,110.29) 32.07,110.83 RT338.1 RT30.1
  BOTTOM w0.076: UT1.AA1 31.85,104.66 32.19,105 32.19,105.3 32.41,105.53
  BOTTOM w0.127: v2(32.6,110.29) v1(33.79,109.1) 33.79,107.27 33.13,106.6 33.13,106.24 32.41,105.53
TBT_TMU_CLK_OUT: length 4.8
  BOTTOM w0.076: UT1.V2 30.7,104.16 30.7,104.66 30.91,104.87 30.91,105.53
  BOTTOM w0.127: RT28.1 30.38,107.46 31.01,106.82 31.01,106.27 30.91,106.17 30.91,105.53
TBTA_AUXN: length 42.5
  IN4 w0.094: v2(28.33,73.07) 28.33,72.8 28.11,72.58 24.07,72.58 22.96,73.69 22.96,74.14 20.97,76.13 20.97,79.09 20.58,79.48 20.58,84.31 23,86.73 23,91.21 26.28,94.5 31.01,94.5 31.92,95.42 31.92,98.38 31.7,98.61 31.18,98.61 30.85,98.28 30.85,97.92 v2(30.63,97.69)
  BOTTOM w0.102: UT1.W15 30.96,98.02 v2(30.63,97.69)
  BOTTOM w0.114: CT81.1 28.47,73.51 28.47,73.21 v2(28.33,73.07)
TBTA_AUXN_C: length 5.6
  BOTTOM w0.076: UT5.J2 29.77,78.72 29.77,78.22 28.89,77.35 28.89,77.16 28.85,77.12 28.85,77.1
  BOTTOM w0.114: CT81.2 28.17,74.39 RT95.1 28.48,75.25 28.48,75.46 28.85,75.83 28.85,77.1
TBTA_AUXP: length 42.8
  IN4 w0.094: v2(28.91,73.07) 28.2,72.36 23.98,72.36 22.73,73.6 22.73,74.05 20.74,76.04 20.74,79 20.36,79.39 20.36,84.4 22.77,86.82 22.77,91.31 26.19,94.73 30.91,94.73 31.7,95.51 31.7,98.29 31.6,98.38 31.27,98.38 31.08,98.19 31.08,97.9 v2(31.29,97.69)
  BOTTOM w0.102: UT1.Y15 31.35,98.02 31.29,97.96 v2(31.29,97.69)
  BOTTOM w0.114: CT80.1 28.72,73.43 28.72,73.26 v2(28.91,73.07)
TBTA_AUXP_C: length 5
  BOTTOM w0.076: 29.1,77.1 29.1,77.12 29.06,77.16 29.06,77.28 29.93,78.15 29.93,78.4 30.01,78.47 UT5.J1
  BOTTOM w0.114: 29.1,77.1 29.1,75.73 28.73,75.35 28.73,75.25 RT96.1 29.03,74.33 CT80.2
TBTA_BOT_N: length 40.5
  IN1 w0.094: v2(18.33,91.76) 18.14,91.94 18.14,92.12 17.81,92.45 17.2,92.45 16.8,92.05 16.8,86.94 18.03,85.71 21.21,85.71 21.47,85.97 23.44,85.97 23.82,85.59 24.21,85.59 26.98,82.82 27.52,82.82 28.01,82.33 28.01,82.04 v2(27.76,81.78)
  IN2 w0.102: v2(18.33,91.76) 18.11,91.97 18.11,92.35 17.78,92.68 17.78,105.7 16.68,106.81 16.02,106.81 v2(16,106.83)
  BOTTOM w0.076: 27.96,81.58 27.98,81.58 28.16,81.4 28.61,81.4 28.68,81.47 UT5.L7
  BOTTOM w0.112: 27.96,81.58 v2(27.76,81.78)
  BOTTOM w0.114: RT122.2 15.09,106.67 15.84,106.67 v2(16,106.83)
TBTA_BOT_N_R: length 7.8
  BOTTOM w0.114: JUSBC1.B7 6.88,107.27 9.75,107.27 10.01,107.02 10.54,107.02 10.89,106.67 10.96,106.67 11.35,107.06 DT40.8 11.97,107.06 11.98,107.06 12.51,107.06 DT40.2 13.32,107.06 13.38,107.01 RT122.1
TBTA_BOT_P: length 40.5
  IN1 w0.094: v2(17.49,91.76) 17.64,91.6 17.8,91.6 17.92,91.72 17.92,92.02 17.71,92.23 17.3,92.23 17.03,91.96 17.03,87.03 18.12,85.94 21.12,85.94 21.37,86.19 23.53,86.19 23.91,85.81 24.31,85.81 27.08,83.04 27.62,83.04 28.24,82.42 28.24,81.94 v2(28.4,81.77)
  IN2 w0.102: v2(16,106.24) 16.37,106.61 16.6,106.61 17.59,105.62 17.59,92.6 17.92,92.27 17.92,91.7 17.82,91.6 17.64,91.6 v2(17.49,91.76)
  BOTTOM w0.076: v2(28.4,81.77) 28.4,81.86 28.48,81.94 28.66,81.94 28.88,81.72 29.12,81.72 29.37,81.47 UT5.K7
  BOTTOM w0.114: RT123.2 15.07,106.43 15.81,106.43 v2(16,106.24)
TBTA_BOT_P_R: length 7.8
  BOTTOM w0.114: RT123.1 13.79,106.06 DT40.4 DT40.7 11.33,106.06 10.97,106.43 10.79,106.43 10.44,106.77 9.9,106.77 9.65,107.03 6.88,107.03 JUSBC1.B6
TBTA_CC1: length 47.1
  TOP w0.203: JUSBC1.A5 10.13,107.9 10.46,107.57 DT39.1 DT39.9 12.51,107.82 v2(12.84,108.15) ; v2(14.21,93.32) 14.21,92.76 v1(14.29,92.68)
  IN1 w0.305: v2(23.18,83.19) 22.88,83.49 22.88,83.92 22.53,84.28 22.02,84.28 21.84,84.1 16.27,84.1 14.34,86.03 14.34,90.68 14.05,90.96 14.05,93.16 v2(14.21,93.32)
  IN2 w0.305: v2(12.84,108.15) 12.21,107.52 12.21,105.8 12.94,105.07 12.94,93.92 13.55,93.32 v2(14.21,93.32)
  BOTTOM w0.152: 28.01,82.78 28.14,82.78 28.39,82.53 28.5,82.53 28.51,82.53 28.97,82.53 UT5.L9
  BOTTOM w0.305: v2(23.18,83.19) 23.22,83.16 24.05,83.16 24.7,83.81 CT86.1 RT104.2 26.74,83.12 27.67,83.12 28.01,82.78
TBTA_CC2: length 46.9
  TOP w0.254: v2(15.33,86.56) 16.16,85.72 21.36,85.72 v1(21.79,86.15) 23.62,87.98 v2(24.95,87.98)
  IN1 w0.254: v2(15.33,86.56) 14.72,87.17 14.72,90.84 14.44,91.12 14.44,92.85 14.69,93.1 14.69,93.75 v2(14.57,93.88)
  IN2 w0.305: v2(14.57,93.88) 14.37,94.07 14.37,95.51 13.65,96.24 v2(13.65,105.43)
  BOTTOM w0.127: 7.14,106.27 5.88,106.27 JUSBC1.B5
  BOTTOM w0.203: v2(24.95,87.98) 24.69,87.72 24.69,86.56 24.99,86.26 CT85.1 ; RT105.2 26.16,86.26 26.8,85.61 26.8,85.03 27.35,84.49 27.35,84.36 28.74,82.97 UT5.L10 ; 7.14,106.27 7.35,106.49 9.39,106.49 9.69,106.19 10.1,106.19 10.26,106.03 10.72,106.03 11.18,105.56 DT40.6 DT40.5 12.86,105.56 12.99,105.43
  BOTTOM w0.254: v2(13.65,105.43) 12.99,105.43 ; CT85.1 RT105.2
TBTA_DBG_CTL1: length 5.8
  TOP w0.127: v2(32.1,79.49) 32.1,78.83 31.32,78.04 30.11,78.04 29.54,77.47 29.54,75.98 RT106.1
  BOTTOM w0.076: v2(32.1,79.49) 32.02,79.57 UT5.E4
TBTA_DBG_CTL2: length 1.3
  TOP w0.127: RT107.1 33.6,80.05 v2(32.99,80.05)
  BOTTOM w0.076: UT5.D5 32.95,80.05 v2(32.99,80.05)
TBTA_DEBUG1: length 4.7
  BOTTOM w0.076: UT5.L2 28.95,78.9 28.44,78.9 27.96,78.42 27.96,78.24 27.71,77.99
  BOTTOM w0.127: RT92.2 26,76.27 27.71,77.99
TBTA_DEBUG2: length 5.8
  BOTTOM w0.076: 27.96,77.86 28.22,78.12 28.22,78.4 28.55,78.72 29.27,78.72 UT5.K2
  BOTTOM w0.127: 27.96,77.86 26.82,76.72 26.82,76.4 25.81,75.39 RT93.2
TBTA_DEBUG3: length 4.3
  TOP w0.127: v2(26.98,78.5) 26.73,78.75 v1(26.46,78.75) 26.26,78.75 RT89.2
  BOTTOM w0.076: 27.96,79.26 28.7,79.26 28.84,79.4 28.95,79.4 UT5.L3
  BOTTOM w0.127: v2(26.98,78.5) 27.73,79.26 27.96,79.26
TBTA_DEBUG4: length 6.1
  TOP w0.127: v1(25.59,76.05) 25.56,76.07 RT90.2 25.94,77.16 26.73,77.95 27.06,77.95 27.58,78.47 v2(27.58,78.5)
  BOTTOM w0.076: UT5.K3 29.27,79.22 28.92,79.22 28.77,79.08 28.37,79.08 28.13,78.84 27.92,78.84 27.84,78.75
  BOTTOM w0.127: 27.84,78.75 v2(27.58,78.5)
TBTA_HPD: length 51.1
  TOP w0.127: v2(21.22,83.55) 21.11,83.44 21.11,82.22 21.54,81.79 24.52,81.79 25.34,82.61 v1(27.94,82.61) 28.4,82.61 28.62,82.83 30.9,82.83 RT73.1 ; RT23.1 27.38,104.02 v2(27.38,102.9)
  IN4 w0.084: v2(21.22,83.55) 21.22,84.02 23.59,86.4 23.59,90.95 25.02,92.37 25.72,92.37 27.25,93.9 31.39,93.9 32.52,95.04 32.52,101.04 32.28,101.28 32.28,103.63 33.19,104.55 33.19,105.27 32.81,105.65 31.76,105.65 30.57,104.47 28.79,104.47 27.38,103.06 v2(27.38,102.9)
  BOTTOM w0.127: UT1.M4 v2(27.38,102.9)
TBTA_HPD_R: length 1.6
  TOP w0.127: v2(33.02,82.5) 32.3,83.22 RT73.2
  BOTTOM w0.102: UT5.C10 v2(33.02,82.5)
TBTA_I2C_INT: length 73
  TOP w0.127: RT16.1 27.78,107.22 27.08,107.22 v1(26.87,107.01) 26.49,106.63 25.89,106.63 25.28,106.02 25.28,103.71 v2(26.08,102.9)
  IN4 w0.084: v2(26.08,102.9) 26.08,102.91 27.39,104.21 28.12,104.21 28.6,104.7 30.55,104.7 31.68,105.83 32.89,105.83 33.38,105.35 33.38,104.47 32.46,103.56 32.46,101.36 32.78,101.04 32.78,94.94 31.57,93.72 27.65,93.72 26.1,92.17 25.24,92.17 23.78,90.71 23.78,86.09 24.62,85.24 24.62,74.61 v2(26.01,73.22)
  BOTTOM w0.076: 33.64,77.44 33.64,77.52 33.02,78.14 UT5.C1
  BOTTOM w0.127: 33.64,77.44 33.64,77.06 33.77,76.93 33.77,74.53 33.16,73.91 32.76,73.91 31.89,73.04 31.03,73.04 30.2,72.21 30.2,71.82 28.71,70.33 27.89,70.33 26.95,71.28 26.95,72.28 v2(26.01,73.22) ; UT1.J4 v2(26.08,102.9)
TBTA_LSRX: length 42.4
  TOP w0.114: v2(23.12,76.55) 22.95,76.72 22.95,77.11 23.33,77.48 24.33,77.48 RT90.1
  IN2 w0.102: v2(20.43,101.51) 20.15,101.23 19.93,101.23 18.44,99.74 18.44,92.96 18.93,92.47 18.93,91.12 17.23,89.42 17.23,85.68 18.35,84.56 18.35,76.68 18.92,76.11 20.55,76.11 20.88,75.78 22.53,75.78 22.91,76.16 22.91,76.35 v2(23.12,76.55)
  BOTTOM w0.114: v2(23.12,76.55) 22.93,76.74 22.93,77.07 23.34,77.48 24.33,77.48 RT88.1 ; RT21.1 19.8,101.42 20.02,101.2 20.19,101.2 20.43,101.44 v2(20.43,101.51) 20.75,101.18 21.06,101.18 21.5,101.62 21.5,102.13 22.26,102.88 22.53,102.88 UT1.A4
TBTA_LSRX_R: length 5.6
  BOTTOM w0.076: UT5.K4 29.5,79.97 29.25,79.72 28.79,79.72 28.71,79.81 27.68,79.81 26.91,79.04 26.91,78.99 26.9,78.97
  BOTTOM w0.114: RT88.2 25.92,77.52 26.12,77.52 26.37,77.78 26.37,78.45 26.9,78.97
TBTA_LSTX: length 42
  TOP w0.114: RT89.1 24.33,77.73 23.22,77.73 22.7,77.21 22.7,76.72 v2(22.53,76.55)
  IN2 w0.102: v2(20.47,100.77) 20.2,101.04 20.01,101.04 18.63,99.66 18.63,93.04 19.12,92.55 19.12,91.04 17.42,89.34 17.42,85.76 18.54,84.64 18.54,76.76 19,76.3 20.63,76.3 20.96,75.97 22.45,75.97 22.72,76.24 22.72,76.37 v2(22.53,76.55)
  BOTTOM w0.114: UT1.A5 22.56,102.64 22.36,102.64 21.74,102.02 21.74,101.52 21.16,100.94 20.65,100.94 v2(20.47,100.77) 20.28,100.96 20.08,100.96 RT22.1 ; v2(22.53,76.55) 22.69,76.71 22.69,77.18 23.24,77.73 24.33,77.73 RT87.1
TBTA_LSTX_R: length 4.9
  BOTTOM w0.076: 26.72,79.15 26.74,79.16 26.8,79.16 27.61,79.97 UT5.L4
  BOTTOM w0.114: RT87.2 25.85,77.76 26.01,77.76 26.13,77.88 26.13,78.55 26.72,79.15
TBTA_MRESET: length 2.6
  BOTTOM w0.076: UT5.E11 32.02,84.63
  BOTTOM w0.127: RT86.1 32.07,85.57 31.96,85.46 31.96,84.86 32.02,84.8 32.02,84.63
TBTA_RESET_N_EC_R: length 2.4
  BOTTOM w0.076: UT5.F11 31.52,84.39 31.31,84.61
  BOTTOM w0.127: RT110.1 31.45,85.37 31.14,85.07 31.14,84.78 31.31,84.61
TBTA_ROM_CLK_PD: length 17.2
  TOP w0.127: v2(28.61,71.54) 28.64,71.51 RT54.2 ; v2(36.09,79.47) 36.36,79.47 v1(36.6,79.23)
  IN2 w0.122: v2(28.61,71.54) 28.77,71.54 29.64,72.41 29.64,73.25 29.18,73.71 29.18,74.22 30.12,75.17 32.81,75.17 33.76,76.12 33.76,78.64 34.59,79.47 v2(36.09,79.47)
  BOTTOM w0.127: v2(36.09,79.47) UT5.A3
TBTA_ROM_CLK_PD_R: length 9
  TOP w0.127: v1(31.9,70.86) 31.25,71.51 v2(31.09,71.51) RT54.1
  BOTTOM w0.127: JDB1.2 29.88,68.51 29.42,68.96 29.42,69.85 v2(31.09,71.51) 31.47,71.13 32.29,71.13
TBTA_ROM_CS#_PD: length 21.9
  TOP w0.127: v1(26.69,66.14) 27.32,66.78 v2(27.32,67.07) 27.32,67.82 27.98,68.48 RT57.2
  IN2 w0.122: v2(27.32,67.07) 27.32,67.89 29.89,70.46 29.89,73.31 29.4,73.81 29.4,74.13 30.22,74.95 32.9,74.95 33.98,76.02 33.98,77.13 35.05,78.2 v2(35.05,79.06)
  BOTTOM w0.076: UT5.B3 33.77,79.22 34.89,79.22 v2(35.05,79.06)
TBTA_ROM_CS#_PD_R: length 8.6
  TOP w0.127: RT51.1 RT57.1 26.63,68.59 v2(26.11,69.11) v1(25.51,69.11)
  BOTTOM w0.127: JDB1.5 28.38,67.49 28.56,67.67 28.56,68.25 27.7,69.11 v2(26.11,69.11) 26.11,68.82 25.88,68.59 UT6.1
TBTA_ROM_DI_PD: length 17.3
  TOP w0.127: RT55.2 29,72.18 v2(28.61,72.18) ; v1(36.32,80.67) 36.08,80.43 v2(36.08,80.13)
  IN2 w0.122: v2(36.08,80.13) 35.66,79.71 34.49,79.71 32.19,77.41 32.19,76.06 31.65,75.51 30.13,75.51 28.95,74.33 28.95,73.62 29.4,73.17 29.4,72.74 28.84,72.18 v2(28.61,72.18)
  BOTTOM w0.076: UT5.B4 33.77,79.72 35.11,79.72 35.13,79.71
  BOTTOM w0.127: 35.13,79.71 35.66,79.71 v2(36.08,80.13)
TBTA_ROM_DI_PD_R: length 9.8
  TOP w0.127: v1(32.21,72.31) 32.15,72.25 v2(31.09,72.25) 30.94,72.4 RT55.1
  BOTTOM w0.127: UT6.5 31.23,72.4 31.09,72.26 v2(31.09,72.25) 29.17,70.33 29.17,68.78 29.38,68.57 JDB1.3
TBTA_ROM_DO_PD: length 16.2
  TOP w0.127: RT56.2 28.07,71.45 v2(28.61,70.91) ; v2(35.08,80.1) v1(35.08,79.57)
  IN2 w0.122: v2(35.08,80.1) 34.57,80.1 31.97,77.5 31.97,76.15 31.56,75.74 30.04,75.74 28.54,74.23 28.54,73.9 27.88,73.23 27.88,71.65 v2(28.61,70.91)
  BOTTOM w0.102: UT5.A4 34.32,79.97 34.41,80.06
  BOTTOM w0.127: v2(35.08,80.1) 35.03,80.1 34.99,80.06 34.41,80.06
TBTA_ROM_DO_PD_R: length 9.5
  TOP w0.127: v1(25.4,70.5) v2(26.07,70.5) RT52.1 RT56.1
  BOTTOM w0.127: UT6.2 25.87,69.86 26.07,70.06 v2(26.07,70.5) 26.85,70.5 28.88,68.47 JDB1.4
TBTA_ROM_HOLD#_PD: length 4.3
  TOP w0.127: v2(31.03,70.5) RT50.1
  BOTTOM w0.127: v2(31.03,70.5) 31.09,70.44 31.09,70.15 31.38,69.86 UT6.7 33.23,69.86 v3(33.81,69.29)
TBTA_ROM_WP#_PD: length 2.9
  TOP w0.127: RT53.1 26.64,72.4 v2(26.08,71.84)
  BOTTOM w0.127: 25.04,71.13 25.91,71.13 26.08,71.31 v2(26.08,71.84)
TBTA_ROSC: length 4
  TOP w0.127: v1(29.92,77.13) 29.98,77.13 v2(30.44,76.66) RT100.1
  BOTTOM w0.076: UT5.G2 30.77,78.72 30.77,77.8 30.86,77.71 30.86,77.44
  BOTTOM w0.127: 30.86,77.44 30.86,77.19 30.44,76.77 v2(30.44,76.66)
TBTA_RX1N: length 31.3
  TOP w0.203: v2(20.37,93.91) arc(20.21,94.02) 20.03,94.05 19.72,94.05 arc(19.6,94.06) 19.48,94.07 arc(19.44,94.08) 19.41,94.09 arc(19.14,94.2) 18.91,94.37 17.37,95.91 arc(17.09,96.33) 16.99,96.82 16.99,106.68 arc(16.89,107.18) 16.6,107.61 16.19,108.02 arc(16.02,108.13) 15.83,108.17 15.19,108.17 arc(14.94,108.22) 14.74,108.36 14.67,108.42 arc(14.55,108.49) v2(14.41,108.5)
  BOTTOM w0.076: UT1.A21 22.75,95.18 arc(22.87,95.11) 22.84,94.97 arc(22.81,94.95) 22.78,94.95 22.45,94.95 arc(22.42,94.94) 22.38,94.92 22.09,94.62 22.09,94.53 22.07,94.51
  BOTTOM w0.203: 22.07,94.51 21.83,94.28 arc(21.58,94.11) 21.29,94.05 20.7,94.05 arc(20.52,94.02) v2(20.37,93.91) ; JUSBC1.B10 5.94,108.89 arc(6.09,108.99) 6.28,109.03 7.48,109.03 arc(7.72,109.08) 7.92,109.21 8,109.29 arc(8.06,109.33) 8.14,109.35 10.5,109.35 arc(10.69,109.39) 10.86,109.5 11.21,109.85 arc(11.27,109.89) 11.33,109.9 11.53,109.9 arc(11.66,109.85) 11.71,109.73 11.71,109.7 DT14.1 arc(11.9,109.85) 12.14,109.9 12.74,109.9 arc(13.17,109.82) 13.54,109.57 14.24,108.88 arc(14.36,108.71) v2(14.41,108.5)
TBTA_RX1P: length 31.3
  TOP w0.203: v2(14.83,108.92) arc(14.81,108.77) 14.88,108.64 14.95,108.57 arc(15.06,108.5) 15.19,108.47 15.83,108.47 arc(16.14,108.41) 16.4,108.24 16.82,107.82 arc(17.17,107.3) 17.29,106.68 17.29,96.82 arc(17.37,96.45) 17.58,96.13 19.12,94.59 arc(19.29,94.46) 19.48,94.39 arc(19.6,94.36) 19.72,94.36 20.03,94.36 arc(20.21,94.39) v2(20.37,94.5)
  BOTTOM w0.076: 21.85,94.73 21.87,94.75 21.96,94.75 22.24,95.03 arc(22.29,95.1) 22.33,95.17 arc(22.36,95.26) 22.42,95.33 arc(22.49,95.39) 22.59,95.4 22.69,95.4 arc(22.87,95.37) 23.03,95.26 UT1.B21
  BOTTOM w0.203: JUSBC1.B11 5.96,109.39 arc(6.02,109.35) 6.1,109.33 7.48,109.33 arc(7.6,109.36) 7.7,109.43 7.78,109.51 arc(7.95,109.62) 8.14,109.66 10.5,109.66 arc(10.58,109.67) 10.64,109.71 11,110.07 arc(11.15,110.17) 11.33,110.21 11.53,110.21 arc(11.66,110.26) 11.71,110.38 DT13.1 arc(11.9,110.26) 12.14,110.21 12.74,110.21 arc(13.29,110.1) 13.76,109.79 14.48,109.06 arc(14.64,108.96) v2(14.83,108.92) ; 21.85,94.73 21.62,94.49 arc(21.47,94.39) 21.29,94.36 20.7,94.36 arc(20.52,94.39) v2(20.37,94.5)
TBTA_RX2N: length 18.9
  TOP w0.203: JUSBC1.A10 8.3,105.4 arc(8.36,105.39) 8.41,105.35 arc(8.45,105.33) 8.48,105.31 arc(8.5,105.31) 8.52,105.31 8.92,105.31 arc(9.37,105.12) 9.56,104.68 9.56,104.27 arc(9.59,104.09) 9.7,103.93 10.2,103.42 arc(10.36,103.32) 10.54,103.29 11.31,103.29 arc(11.43,103.31) 11.53,103.37 DT9.1 13.03,103.49 arc(13.44,103.41) 13.79,103.18 13.84,103.13 15.14,101.83 arc(15.36,101.66) v2(15.61,101.56)
  BOTTOM w0.076: UT1.B15 22.99,98.06 arc(22.87,98.15) 22.73,98.17 22.56,98.17 arc(22.48,98.16) 22.41,98.11 22.4,98.1 arc(22.34,98.06) 22.26,98.04 22.09,98.04 arc(22.06,98.05) 22.03,98.07 21.82,98.28 21.82,98.37 21.79,98.39
  BOTTOM w0.203: 21.79,98.39 20.68,99.51 arc(20.52,99.62) 20.32,99.66 18.04,99.66 arc(17.47,99.77) 16.98,100.09 15.68,101.4 arc(15.63,101.47) v2(15.61,101.56)
TBTA_RX2P: length 18.9
  TOP w0.203: v2(15.2,101.14) 15.21,101.24 arc(15.2,101.35) 15.14,101.44 15.06,101.5 arc(14.99,101.55) 14.93,101.61 13.62,102.91 13.58,102.96 arc(13.33,103.13) 13.03,103.19 12.18,103.19 arc(12.02,103.15) 11.89,103.06 11.68,102.85 arc(11.65,102.82) DT10.1 11.53,102.89 arc(11.43,102.96) 11.32,102.98 10.54,102.98 arc(10.24,103.04) 9.99,103.21 9.48,103.72 arc(9.31,103.97) 9.25,104.27 9.25,104.68 arc(9.16,104.91) 8.92,105.01 8.49,105.01 arc(8.42,104.99) 8.36,104.95 arc(8.3,104.91) 8.23,104.9 JUSBC1.A11
  BOTTOM w0.076: 21.58,98.18 21.6,98.16 21.69,98.16 21.9,97.94 arc(21.99,97.88) 22.09,97.86 22.31,97.86 arc(22.34,97.86) 22.37,97.84 22.41,97.8 arc(22.49,97.74) 22.59,97.72 22.61,97.72 arc(22.66,97.73) 22.71,97.76 arc(22.75,97.87) UT1.A15
  BOTTOM w0.203: v2(15.2,101.14) 15.36,101.14 arc(15.49,101.12) 15.6,101.05 16.76,99.88 arc(17.35,99.49) 18.04,99.35 20.32,99.35 arc(20.4,99.33) 20.47,99.29 21.58,98.18
TBTA_SBU1: length 40.3
  TOP w0.127: JUSBC1.A8 8.52,106.4 8.58,106.34 9.6,106.34 10.37,105.57 DT39.5 DT39.6 12.83,105.57 13.83,104.57 v2(14.24,104.57)
  IN1 w0.084: v2(23.03,82.54) 23.03,82.11 22.76,81.84 18.11,81.84 14.01,85.93 14.01,90.58 13.76,90.84 13.76,93.46 14.17,93.88 14.17,94.12 14.43,94.37 v2(14.88,94.37)
  IN2 w0.122: v2(14.88,94.37) 14.81,94.45 14.81,95.52 14.24,96.09 v2(14.24,104.57)
  BOTTOM w0.127: v2(23.03,82.54) 23.29,82.8 24.72,82.8 RT108.2
TBTA_SBU1_R: length 4.1
  BOTTOM w0.076: UT5.K8 29.27,82.22 28.89,82.22 28.78,82.33 28.21,82.33 28.1,82.43 27.93,82.43
  BOTTOM w0.127: 27.93,82.43 27.55,82.43 27.23,82.75 26.06,82.75 RT108.1
TBTA_SBU2: length 43.3
  IN1 w0.084: v2(13.79,94.05) 13.57,93.84 13.57,90.76 13.83,90.51 13.83,85.85 18.03,81.65 22.85,81.65 v2(23.6,82.4)
  IN2 w0.122: v2(13.79,94.05) 13.26,94.59 13.26,105.39 12.78,105.86 12.78,107.04 v2(13.19,107.46)
  BOTTOM w0.127: RT109.2 23.9,82.1 v2(23.6,82.4) ; v2(13.19,107.46) 13.08,107.56 DT40.1 DT40.9 11.01,107.56 10.66,107.91 7.19,107.91 7.07,108.02 5.87,108.02 JUSBC1.B8
TBTA_SBU2_R: length 3.6
  BOTTOM w0.076: UT5.L8 28.88,81.97 28.71,82.14 28.14,82.14 28.1,82.18 27.93,82.18
  BOTTOM w0.127: 27.93,82.18 27.45,82.18 27.11,82.52 26.25,82.52 RT109.1
TBTA_TOP_N: length 41.4
  TOP w0.114: RT121.1 14.76,106.36 14.91,106.51 15.14,106.51 15.3,106.34 15.3,105.71 v2(14.79,105.19)
  IN1 w0.094: v2(15.3,95.4) 15.43,95.27 15.71,95.27 15.99,94.99 15.99,91.72 16.19,91.52 16.19,86.15 17.24,85.1 21.52,85.1 21.64,85.21 23.1,85.21 23.72,84.6 24.35,84.6 26.99,81.95 v2(26.99,81.24)
  IN2 w0.102: v2(14.79,105.19) 15,105.19 15.2,104.99 15.2,104.7 16.6,103.3 16.6,96.04 15.7,95.13 15.56,95.13 v2(15.3,95.4)
  BOTTOM w0.076: UT5.L6 28.98,81.02 28.84,81.02 28.82,81.04 27.75,81.04 27.08,81.71 27.04,81.71 27.01,81.68 26.99,81.68
  BOTTOM w0.114: 26.99,81.68 26.67,81.68 26.6,81.61 26.6,80.97 26.68,80.89 26.92,80.89 26.99,80.96 v2(26.99,81.24)
TBTA_TOP_N_R: length 6.5
  TOP w0.114: JUSBC1.A7 8.25,106.9 8.35,107 9.74,107 10.32,106.43 10.9,106.43 11.27,106.07 DT39.4 DT39.7 13.22,106.07 13.27,106.12 RT121.2
TBTA_TOP_P: length 41.4
  TOP w0.114: RT120.1 15.01,106.76 15.24,106.76 15.55,106.44 v2(15.55,105.19)
  IN1 w0.094: v2(26.21,81.29) 26.47,81.29 26.77,81.59 26.77,81.86 24.26,84.37 23.63,84.37 23.01,84.99 21.73,84.99 21.62,84.87 17.15,84.87 15.96,86.06 15.96,91.42 15.76,91.63 15.76,94.9 15.62,95.04 15.53,95.04 v2(15.3,94.81)
  IN2 w0.102: v2(15.55,105.19) 15.39,105.03 15.39,104.78 16.79,103.38 16.79,95.96 15.78,94.94 15.43,94.94 v2(15.3,94.81)
  BOTTOM w0.076: UT5.K6 29.27,81.22 28.84,81.22 28.82,81.2 27.81,81.2 27.15,81.87 27.07,81.87 27.01,81.92 26.99,81.92
  BOTTOM w0.114: v2(26.21,81.29) 26.35,81.44 26.35,81.71 26.57,81.92 26.99,81.92
TBTA_TOP_P_R: length 6.5
  TOP w0.114: RT120.2 13.3,107.01 13.24,107.07 DT39.8 DT39.2 11.3,107.07 10.9,106.67 10.42,106.67 9.84,107.25 8.38,107.25 8.23,107.4 JUSBC1.A6
TBTA_TX1N: length 4.1
  TOP w0.203: v2(19.98,96.17) arc(19.9,96.29) 19.76,96.34 19.66,96.34 arc(19.53,96.3) CT96.1
  BOTTOM w0.076: 21.9,95.81 21.93,95.81 22,95.88 22.73,95.88 arc(22.87,95.91) 22.99,95.99 UT1.B19
  BOTTOM w0.203: v2(19.98,96.17) 20.12,96.31 20.31,96.31 arc(20.5,96.28) 20.66,96.17 20.82,96.01 arc(21.04,95.86) 21.3,95.81 21.9,95.81
TBTA_TX1N_C: length 23.9
  TOP w0.203: JUSBC1.A3 8.29,108.9 arc(8.35,108.91) 8.39,108.94 arc(8.45,108.98) 8.53,109 8.94,109 arc(9.33,109.07) 9.66,109.3 10.09,109.72 arc(10.32,109.88) 10.59,109.93 11.33,109.93 arc(11.34,109.93) 11.34,109.93 arc(11.47,109.9) 11.58,109.83 DT6.1 11.78,109.77 arc(11.93,109.87) 12.11,109.91 arc(12.12,109.91) 12.13,109.91 12.13,109.91 arc(12.45,109.97) 12.72,110.15 12.79,110.22 arc(12.94,110.32) 13.1,110.35 14.71,110.35 arc(15.74,110.14) 16.6,109.56 17.23,108.94 arc(17.81,108.07) 18.01,107.04 18.01,96.92 arc(18.05,96.73) 18.16,96.56 18.25,96.47 arc(18.27,96.46) 18.28,96.45 arc(18.42,96.37) 18.57,96.34 arc(18.73,96.3) CT96.2
TBTA_TX1P: length 4.2
  TOP w0.203: CT95.1 arc(19.54,96.68) 19.67,96.65 19.77,96.65 arc(19.89,96.68) v2(19.98,96.76)
  BOTTOM w0.076: UT1.A19 22.71,96.1 arc(22.77,96.13) 22.79,96.19 22.79,96.27 arc(22.78,96.3) 22.77,96.32 arc(22.74,96.34) 22.72,96.34 22.45,96.34 arc(22.41,96.34) 22.37,96.31 22.35,96.29 arc(22.33,96.25) 22.33,96.21 arc(22.32,96.16) 22.29,96.11 22.28,96.1 arc(22.23,96.07) 22.18,96.06 22.07,96.06 21.99,96.06 21.93,96.12 21.9,96.12
  BOTTOM w0.203: v2(19.98,96.76) 20.12,96.62 20.31,96.62 arc(20.62,96.56) 20.88,96.38 21.03,96.23 arc(21.16,96.15) 21.3,96.12 21.9,96.12
TBTA_TX1P_C: length 23.9
  TOP w0.203: JUSBC1.A2 8.33,109.4 arc(8.39,109.39) 8.45,109.35 arc(8.5,109.31) 8.56,109.3 8.94,109.3 arc(9.22,109.36) 9.45,109.51 9.87,109.94 arc(10.2,110.16) 10.59,110.24 11.45,110.24 arc(11.52,110.25) 11.59,110.29 DT5.1 11.85,110.27 arc(11.92,110.23) 11.99,110.21 12.13,110.21 arc(12.34,110.25) 12.51,110.37 12.58,110.44 arc(12.82,110.6) 13.1,110.65 14.71,110.65 arc(15.85,110.43) 16.82,109.78 17.44,109.16 arc(18.09,108.19) 18.32,107.04 18.32,96.92 arc(18.33,96.84) 18.38,96.78 18.47,96.69 arc(18.52,96.65) 18.58,96.64 18.61,96.64 arc(18.75,96.67) CT95.2
TBTA_TX2N: length 5
  BOTTOM w0.076: 21.9,97.21 21.93,97.21 22,97.14 22.3,97.14 arc(22.36,97.15) 22.42,97.19 arc(22.49,97.24) 22.57,97.25 22.73,97.25 arc(22.87,97.22) 22.99,97.14 UT1.B17
  BOTTOM w0.203: 21.9,97.21 21.69,97.21 arc(21.54,97.23) 21.42,97.32 21.32,97.41 20.56,98.18 arc(20.32,98.34) 20.04,98.41 arc(20.01,98.41) 19.98,98.41 19.01,98.41 arc(18.83,98.44) CT98.1
TBTA_TX2N_C: length 16.2
  BOTTOM w0.203: CT98.2 arc(17.92,98.42) 17.75,98.38 16.33,98.38 arc(16,98.45) 15.72,98.63 13.76,100.6 arc(13.68,100.71) 13.66,100.84 13.66,101.78 arc(13.52,102.45) 13.14,103.02 13.14,103.02 arc(12.85,103.22) 12.51,103.29 11.97,103.29 arc(11.86,103.31) 11.76,103.38 DT18.1 11.61,103.49 11.49,103.38 arc(11.39,103.31) 11.28,103.29 9.95,103.29 arc(9.86,103.3) 9.79,103.35 8.26,104.89 arc(7.81,105.18) 7.28,105.29 6.43,105.29 arc(6.09,105.36) JUSBC1.B3
TBTA_TX2P: length 5
  BOTTOM w0.076: 21.9,96.9 21.93,96.9 22,96.96 22.25,96.96 arc(22.25,96.96) 22.25,96.96 arc(22.31,96.95) 22.36,96.92 22.41,96.87 arc(22.5,96.81) 22.62,96.78 22.64,96.78 arc(22.65,96.79) 22.66,96.79 arc(22.74,96.81) 22.79,96.87 arc(22.78,97) UT1.A17
  BOTTOM w0.203: 21.9,96.9 21.69,96.9 arc(21.42,96.95) 21.2,97.1 20.34,97.96 arc(20.19,98.06) 20.02,98.11 arc(20,98.11) 19.98,98.11 18.99,98.11 arc(18.8,98.06) CT97.1
TBTA_TX2P_C: length 16.2
  BOTTOM w0.203: JUSBC1.B2 5.9,104.85 arc(6.05,104.95) 6.23,104.98 7.28,104.98 arc(7.69,104.9) 8.04,104.67 9.58,103.14 arc(9.75,103.02) 9.94,102.98 11.32,102.98 arc(11.43,102.96) 11.53,102.89 DT17.1 11.76,102.89 arc(11.86,102.96) 11.97,102.98 12.51,102.98 arc(12.73,102.94) 12.93,102.81 12.93,102.81 arc(13.24,102.34) 13.35,101.78 13.35,100.84 arc(13.4,100.59) 13.54,100.38 15.5,98.42 arc(15.88,98.17) 16.33,98.08 17.76,98.08 arc(17.93,98.04) CT97.2
TBTA_USB2_RBIAS: length 3.1
  TOP w0.127: v2(26.08,95.75) 26,95.75 25.09,94.84 RT41.1 25.09,93.9 v1(25.33,93.66)
  BOTTOM w0.112: UT1.H19 v2(26.08,95.75)
TBTA_USB20_N: length 27.7
  IN1 w0.094: v2(23.41,80.71) 23.41,80.51 23.53,80.39 25.01,80.39 26.15,79.25 27.63,79.25 29.17,80.79 29.17,82.81 26.93,85.06 26.93,85.26 25.71,86.48 24.41,86.48 23.5,87.4 23.5,92.99 23.71,93.21 23.71,93.89 24.39,94.57 24.39,95.68 24.31,95.75 v2(24.14,95.75)
  BOTTOM w0.114: v2(23.41,80.71) 23.66,80.46 24.29,80.46 RT403.1 ; UT1.D20 v2(24.14,95.75)
TBTA_USB20_N_R: length 5
  TOP w0.114: v2(26.19,80.64) 25.79,80.64 RT401.2
  BOTTOM w0.076: 26.95,80.47 26.97,80.47 27.01,80.43 27.32,80.43 27.61,80.72 29.27,80.72 UT5.K5
  BOTTOM w0.114: 26.95,80.47 26.36,80.47 v2(26.19,80.64) 25.79,80.64 RT401.2
TBTA_USB20_P: length 27.8
  IN1 w0.094: v2(23.4,80) 23.56,80.17 24.91,80.17 26.06,79.02 27.72,79.02 29.4,80.7 29.4,82.91 27.15,85.15 27.15,85.35 25.8,86.71 24.51,86.71 23.72,87.49 23.72,92.9 23.94,93.12 23.94,93.8 24.61,94.47 24.61,95.58 v2(24.79,95.75)
  BOTTOM w0.114: RT402.1 24.68,80 24.48,80.21 23.6,80.21 v2(23.4,80) ; UT1.E20 v2(24.79,95.75)
TBTA_USB20_P_R: length 4.9
  TOP w0.114: RT400.2 25.68,80.04 v2(26.2,80.04)
  BOTTOM w0.076: UT5.L5 29.07,80.43 29.07,80.28 29.02,80.23 28.77,80.23 28.72,80.27 28.72,80.5 28.66,80.56 27.68,80.56 27.39,80.26 27.01,80.26 26.97,80.22 26.95,80.22
  BOTTOM w0.114: RT400.2 25.68,80.04 v2(26.2,80.04) 26.38,80.22 26.95,80.22
TBTB_HPD: length 5.5
  BOTTOM w0.076: 25.73,106.06 25.5,105.83 25.5,104.8 25.63,104.68 25.63,104.15 25.41,103.93 UT1.G2
  BOTTOM w0.127: 25.73,106.06 26.1,106.43 26.36,106.43 26.86,106.92 26.86,107.33 RT33.1
TBTB_I2C_INT: length 4.4
  BOTTOM w0.076: 24.7,106.37 24.7,105.59 24.72,105.57 24.72,104.15 UT1.E2
  BOTTOM w0.127: RT17.1 24.7,108.17 24.7,106.37
TBTB_LSRX: length 5.1
  TOP w0.127: RT32.1 v2(21.49,100.06) v1(20.89,100.06)
  BOTTOM w0.076: UT1.B5 23.11,102.54 22.88,102.31 22.44,102.31 22.15,102.02 22.15,100.72 v2(21.49,100.06)
TBTB_LSTX: length 2.8
  BOTTOM w0.076: UT1.B4 22.88,103.24 22.29,103.24 22.03,102.98
  BOTTOM w0.127: 22.03,102.98 21.75,102.98 21.24,102.47 RT31.1
TBTB_USB2_RBIAS: length 2.7
  TOP w0.127: v2(24.79,96.4) 24.63,96.25 v1(24.28,96.25) 24.03,96.25 23.62,95.84 23.62,95.17 RT42.1
  BOTTOM w0.112: UT1.F19 v2(24.79,96.4)
TDI_XDP: length 17.5
  TOP w0.127: v2(87.03,131.8) 87.12,131.71 87.12,130.63 86.91,130.42 86.91,127.97 85.33,126.39 83.59,126.39 82.51,125.31 v1(82.51,122.28) 80.77,120.54 v2(80.77,120.48)
  BOTTOM w0.127: v2(87.03,131.8) 87.03,132.69 JXDP1.56 ; RC229.1 80.67,120.37 v2(80.77,120.48) 80.77,120.54 80.8,120.57 UC8.5
TDO_XDP: length 16.8
  TOP w0.127: v2(82.89,120.45) 82.93,120.41 83.65,120.41 84.48,121.24 v1(84.48,121.82) 84.48,124.89 87.36,127.78 87.36,130.22 CC306.1 v2(88.23,131.8)
  BOTTOM w0.127: JXDP1.52 88.23,132.69 v2(88.23,131.8) ; UC8.2 82.3,120.93 82.72,120.52 82.83,120.52 v2(82.89,120.45) RC230.1
TDOCK_BATLOW#: length 5.1
  BOTTOM w0.076: 25.31,106.32 25.12,106.13 25.12,104.71 25.17,104.67 25.17,104.14 UT1.F2
  BOTTOM w0.127: RT20.1 26.31,107.71 26.21,107.71 25.92,107.41 25.92,106.93 25.31,106.32
TEST_EN: length 4.1
  BOTTOM w0.076: UT1.E1 24.49,105.46 24.43,105.52 24.43,106.36
  BOTTOM w0.127: 24.43,106.36 24.43,107.55 RT36.1
TEST_PWRGD: length 9.5
  BOTTOM w0.076: UT1.AB5 32.54,102.78 33.32,102.78 33.74,103.2 34.13,103.2
  BOTTOM w0.127: RT37.1 39.27,104.33 37.99,105.6 35.87,105.6 34.76,104.5 v1(34.76,104.14) 34.76,103.67 34.29,103.2 34.13,103.2
THERMDA: length 0.5
  BOTTOM w0.127: UT1.AC23 UT1.AB23
THERMTRIP1#: length 4.2
  TOP w0.127: RE301.1 247.36,95.88 v1(246.76,95.29) 246.59,95.12 246.59,94.19 247.08,93.69 247.08,93.06 UE1.B12
THERMTRIP2#: length 35.9
  TOP w0.127: v1(262.89,101.56) 263.19,101.86 v2(263.42,101.86) QE4.1 CE36.1 RE69.2 ; UE1.H3 v2(252.68,85.06)
  IN1 w0.084: v2(263.42,101.86) 261.01,104.28 254.84,104.28 253,102.44 253,98.95 253.11,98.84 253.11,96.61 252.73,96.23 252.73,92.87 252.22,92.37 252.22,85.52 v2(252.68,85.06)
TOUCH_SCREEN_DET#: length 197.6
  TOP w0.127: v2(66,133.81) 65.56,134.25 v1(63.9,134.25) 61.75,134.25 61.49,134 RV8.1 61.96,132.84 61.96,125.09 62.55,124.51 v2(62.55,123.31)
  IN1 w0.084: v2(74.09,82.89) 74.71,82.27 80.4,82.27 85.39,77.28 117.09,77.28 118.22,78.41 123.44,78.41 126.89,81.86 131.13,81.86 131.47,81.52 131.47,79.03 131.72,78.78 135.71,78.78 137.46,80.53 137.95,80.53 138.39,80.97 138.39,81.61 138.26,81.74 138.26,87.2 v2(136.04,89.42)
  IN2 w0.122: v2(74.09,82.89) 72.83,82.89 72.49,83.23 61.6,83.23 60.3,81.92 51.38,81.92 44.49,88.82 44.49,91.54 44.9,91.95 44.9,94.74 47.99,97.83 47.99,99.01 46.24,100.76 45.11,100.76 44.46,101.41 44.46,101.84 43.09,103.21 43.09,106.16 45.02,108.1 45.02,110.73 46.72,112.43 46.72,115.18 50.42,118.87 54.49,118.87 54.72,118.64 54.72,118.16 55.19,117.69 56.09,117.69 57.33,116.45 59.04,116.45 60.13,117.54 61.27,117.54 62,118.27 62,119.39 63.78,121.17 63.78,122.08 v2(62.55,123.31)
  BOTTOM w0.076: 135.54,89.42 135.02,89.42 134.38,90.06 130.83,90.06 130.3,90.59 130.3,90.97 130.15,91.12 130.15,91.63 129.76,92.01 UC1.AY5
  BOTTOM w0.127: 135.54,89.42 v2(136.04,89.42) ; v2(66,133.81) 66.32,133.81 66.75,133.37 JEDP1.32
TOUCH_SCREEN_PD#: length 99.7
  IN2 w0.122: v2(63.19,123.34) 64.41,122.12 64.41,121.98 65.54,120.86 76.98,120.86 77.07,120.95 87.1,120.95 87.94,121.79 88.41,121.79 89.47,122.86 98.01,122.86 99.3,124.15 118.68,124.15 119.57,125.04 121.03,125.04 121.24,125.25 125.74,125.25 125.89,125.1 128.22,125.1 129.35,123.98 129.35,122.21 129.71,121.84 129.71,120.67 128.93,119.88 128.93,118.63 v2(129.14,118.42)
  BOTTOM w0.102: 129.69,115.37 129.15,114.83 129.15,113.74 128.89,113.49 UC1.A7
  BOTTOM w0.112: RC272.1 128.54,117.25 129.69,116.1 129.69,115.37
  BOTTOM w0.127: v2(63.19,123.34) 63.19,124.5 62.89,124.8 55.55,124.8 53.69,126.66 53.69,129.42 53.25,129.86 JEDP1.5 ; v2(129.14,118.42) 128.54,117.81 RC272.1
TOUCHPAD_INTR#: length 165
  TOP w0.127: RC414.1 135.72,85.86 v2(132.7,88.88) ; v2(215.8,62.56) v1(212.34,62.56) ; RE318.2 249.93,74.45 v2(249.93,74.28)
  IN2 w0.122: v2(249.52,70.3) 249.47,70.34 246.02,70.34 245.04,69.37 244.49,69.37 242.81,67.68 242.81,66.29 242.28,65.75 241.63,65.75 240.78,66.61 236.92,66.61 234.88,64.56 230.94,64.56 228.45,64.56 227.94,64.05 226.42,64.05 225.5,63.13 216.37,63.13 v2(215.8,62.56) 215.46,62.89 205.66,62.89 203.72,64.83 186.24,64.83 186.05,64.83 184.24,66.64 180.37,66.64 178.18,68.83 176.59,68.83 175.87,69.55 173.24,69.55 173.11,69.68 173.11,69.68 172.3,70.48 160.18,70.48 158.96,71.71 151.44,71.71 149.82,73.33 149.82,83.13 148.98,83.98 148.98,86.64 148.17,87.45 147.02,87.45 146.12,88.35 143.25,88.35 143.02,88.12 139.14,88.12 138.65,88.61 138.64,88.61 138.35,88.91 137.31,88.91 137.06,88.66 132.93,88.66 v2(132.7,88.88)
  IN4 w0.084: v2(249.93,74.28) 249.85,74.28 249.52,73.94 v2(249.52,70.3)
  BOTTOM w0.127: v2(215.8,62.56) 214.27,62.56 212.2,60.49 212.2,59.65 212.05,59.5 JKBTP1.5 ; UC1.BA5 129.58,91.14 129.58,90.52 130.52,89.58 132.01,89.58 v2(132.7,88.88)
TP_LAN_JTAG_TCK: length 4.3
  TOP w0.127: v2(242.58,130.64) 243.1,130.12 243.88,130.12 244.48,129.52 UL1.35
  BOTTOM w0.127: v1(242.58,131.18) v2(242.58,130.64) 242.97,130.25 RL2.1
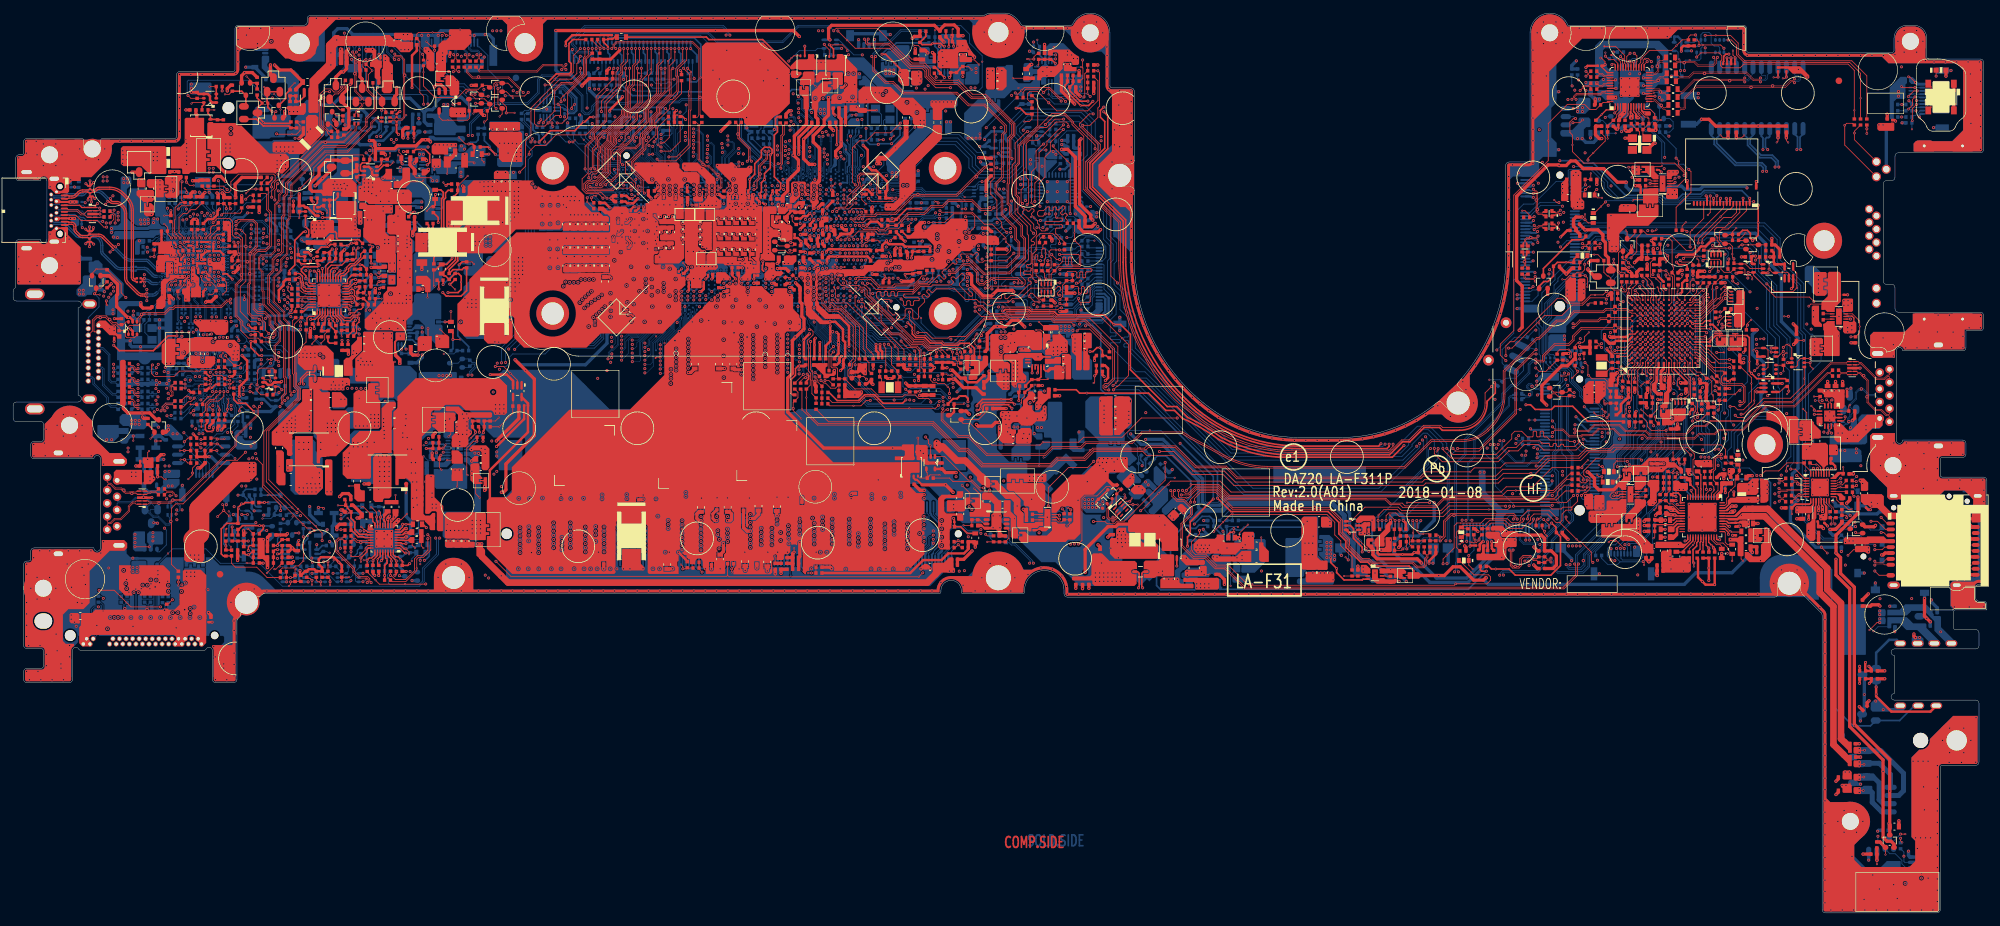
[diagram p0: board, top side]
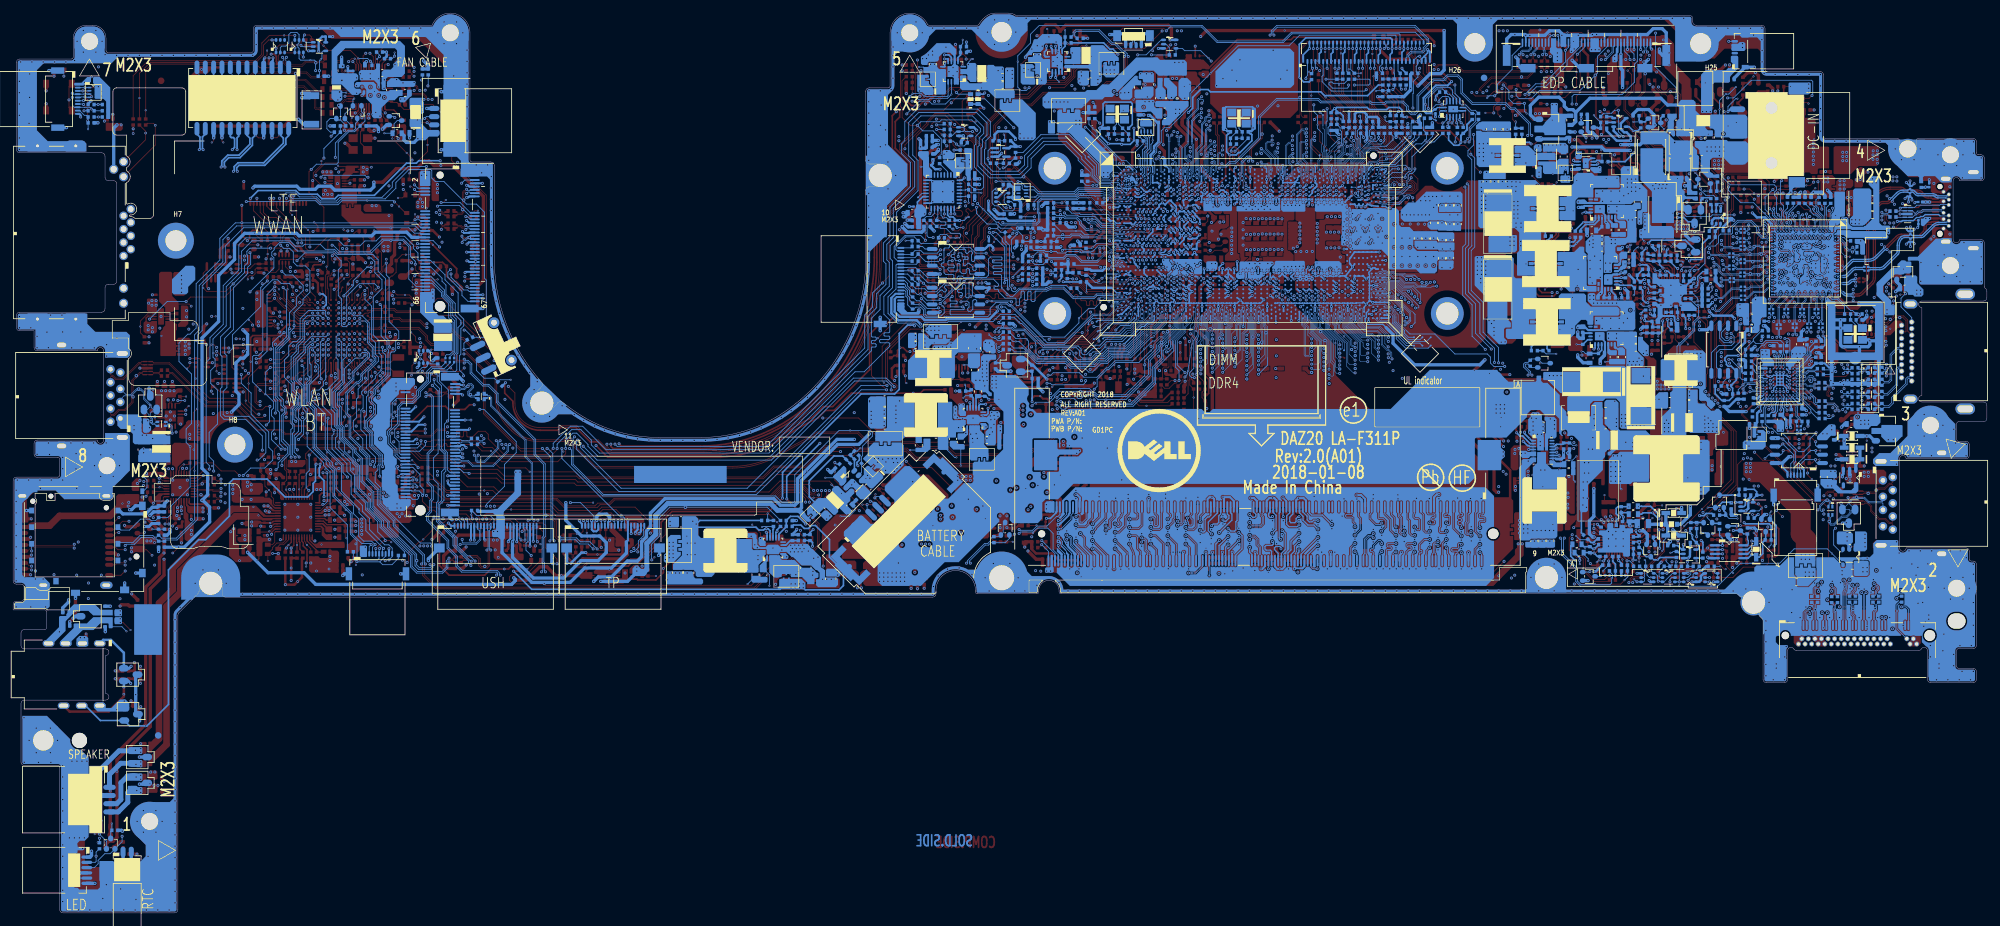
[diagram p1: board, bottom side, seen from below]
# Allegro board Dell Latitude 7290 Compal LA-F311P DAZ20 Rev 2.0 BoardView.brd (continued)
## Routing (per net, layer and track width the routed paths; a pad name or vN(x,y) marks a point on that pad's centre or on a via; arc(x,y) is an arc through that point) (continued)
TP_LAN_JTAG_TDI: length 5.6
  TOP w0.127: T88.1 244.14,132.13 245.51,130.76 245.51,129.55 245.68,129.39 UL1.32
TP_LAN_JTAG_TDO: length 2.7
  TOP w0.127: UL1.34 244.88,129.78 243.85,130.81 T89.1
TP_LAN_JTAG_TMS: length 3.2
  TOP w0.127: UL1.33 245.28,129.41 245.2,129.49 245.2,130.25 v2(244.88,130.57)
  BOTTOM w0.127: RL1.1 244.88,130.81 v2(244.88,130.57) v1(245.25,130.2)
TPM_GPIO0: length 3.6
  BOTTOM w0.127: v1(153.2,109.8) 154.77,109.8 155.13,110.16 RZ112.2 155.55,110.28 155.6,110.22 155.6,110.22 155.61,110.22 UZ12.29
TPM_GPIO4: length 1.5
  BOTTOM w0.127: UZ12.13 162.22,109.72 T283.1
TPM_LPM#: length 2.2
  BOTTOM w0.127: RZ363.2 158.33,113.03 UZ12.3
TPM_PIRQ#: length 37.6
  IN4 w0.084: v2(151.96,104.35) 152.16,104.35 153.31,103.2 155.81,103.2 156.31,103.71 159.14,103.71 159.88,102.97 v2(160.53,102.97)
  BOTTOM w0.127: RC560.1 139.85,95.26 140.24,95.65 142.57,95.65 143.2,95.35 143.34,95.35 143.43,95.26 147.45,95.26 147.99,94.73 148.35,94.73 148.59,94.97 148.59,95.23 148.9,95.55 148.9,101.79 v1(149.43,102.32) 149.57,102.46 RC561.1 150.21,103.78 150.79,104.35 v2(151.96,104.35) ; v2(160.53,102.97) 161.2,102.97 161.47,103.23 161.47,105.13 RZ69.2 161.94,105.81 161.56,106.18 160.82,106.18 160.33,106.67 UZ12.18
TPM_PIRQ#_R: length 11.7
  IN4 w0.084: v2(128.38,95.26) 130.89,95.26 131.71,94.44 137.99,94.44 v2(138.03,94.48)
  BOTTOM w0.076: v2(128.38,95.26) 127.93,95.71 UC1.AP8
  BOTTOM w0.127: v2(138.03,94.48) 138.03,94.52 138.63,95.12 RC560.2
TPM_TYPE: length 16.6
  TOP w0.127: v2(135.28,87.2) 135.28,87.13 v1(135.96,86.45) 136.22,86.19 137.57,86.19 138.01,85.76 138.01,85.75 138.07,85.69 138.07,82.83 RC349.1
  BOTTOM w0.076: UC1.AY7 128.42,91.76 128.42,90.56 128.65,90.33 129.21,90.33 130.45,89.09 131.16,89.09 131.35,88.91
  BOTTOM w0.127: v2(135.28,87.2) 135.28,87.76 134.81,88.23 132.03,88.23 131.35,88.91
TRST#_XDP: length 13.5
  TOP w0.127: v2(83.47,123.68) 83.47,124.21 v1(83.8,124.54) 87.13,127.88 87.13,130.32 87.63,130.81 v2(87.63,131.8)
  BOTTOM w0.127: v2(87.63,131.8) 87.63,132.69 JXDP1.54 ; UC8.12 81.8,124.21 82.09,124.5 82.93,124.5 83.47,123.95 v2(83.47,123.68)
TYPEC_CON_SEL1: length 23.4
  TOP w0.127: v2(140.92,108.27) 140.73,108.46 v1(140.38,108.46)
  IN1 w0.084: v2(140.92,108.27) 140.38,108.8 137.9,108.8 135.67,106.57 132.43,106.57 130.8,104.94 130.8,104.85 130.41,104.46 127.46,104.46 127.09,104.82 v2(126.82,104.82)
  BOTTOM w0.076: v2(126.82,104.82) 126.93,104.82 127.44,104.32 127.44,104.06 127.75,103.76 129.82,103.76 130.4,103.17 UC1.W4
  BOTTOM w0.127: v2(140.92,108.27) RC556.1 RC555.1
TYPEC_CON_SEL2: length 20.3
  TOP w0.127: v2(145.03,103.78) 145.15,103.78 v1(145.6,104.23)
  IN4 w0.084: v2(145.03,103.78) 144.92,103.67 142.53,103.67 139.85,101 136.01,101 135.78,100.77 134.35,100.77 134.04,101.08 131.76,101.08 131.13,101.71 v2(129.96,101.71)
  BOTTOM w0.076: v2(129.96,101.71) 130.11,101.56 130.83,101.56 UC1.AB3
  BOTTOM w0.127: v2(145.03,103.78) 145.03,104.04 RC553.1 145.39,104.39 RC554.1
TYPEC_ID: length 8.5
  TOP w0.127: UE1.F2 250.28,84.25 250.28,83.45 249.96,83.13 249.96,81.23 249.5,80.77 249.5,78.84 CE62.1 RE343.1 249.72,76.9 v1(249.61,76.79)
UART_MISO: length 4.7
  TOP w0.127: RT82.1 31.32,75.16 RT83.1 31.42,76.12 v2(31.42,76.69) 31.42,77.04 v1(31.19,77.27)
  BOTTOM w0.076: UT5.F2 31.27,78.72 31.27,78.06 31.47,77.86 31.47,77.44
  BOTTOM w0.127: 31.47,77.44 31.47,76.74 v2(31.42,76.69)
UART_MOSI: length 5.8
  TOP w0.127: RT81.1 32.23,75.16 RT83.2 32.64,76.43 v2(32.64,76.8) 32.64,77.49 32.78,77.63 v1(32.78,78.31)
  BOTTOM w0.076: 32.58,77.44 32.58,77.64 32.27,77.95 32.27,78.72 UT5.E2
  BOTTOM w0.127: v2(32.64,76.8) 32.64,77.02 32.58,77.08 32.58,77.44
UG1_ISL9538: length 9
  IN1 w1.016: 49.22,64.35 50.23,64.35 52.64,61.94 56.18,61.94 56.89,61.22
  vias: v1(48.31,65.76) v2(47.83,64.21) v2(48.42,64.2) v2(57.07,59.98) v2(57.35,60.49)
UG2_ISL9538: length 9.5
  TOP w0.127: v2(59.88,64.68) v1(59.88,63.98)
  TOP w0.508: PQ904.1 v2(59.88,64.68)
  BOTTOM w0.508: v2(59.88,64.68) 59.88,60.45 60.55,59.78 60.55,57.8 60.07,57.31 v2(59.84,57.31)
UIM_CLK: length 90.3
  BOTTOM w0.127: JSIM1.C3 284.52,56.49 282.43,56.49 281.39,57.53 279.4,57.53 279.16,57.29 278.84,57.29 CZ38.1 278.08,57.14 275.85,57.14 273.07,59.91 v1(273.07,67.42) 273.07,88.14 272.35,88.86 272.35,95.67 268.74,99.28 268.74,102.66 266.66,104.75 239.44,104.75 238.69,104 JNGFF2.24
UIM_DATA: length 104.3
  IN4 w0.084: v2(297.88,55.18) 288.33,55.18 287.5,56.02 v2(283.63,56.02)
  BOTTOM w0.127: v2(283.63,56.02) 283.44,56.21 282.23,56.21 281.18,57.26 279.54,57.26 279.29,57.01 278.87,57.01 CZ39.1 RZ335.2 277.46,56.86 275.73,56.86 272.58,60.01 v1(272.58,74.43) 272.58,88.12 271.89,88.8 271.89,95.65 268.37,99.17 268.37,101.69 265.59,104.47 240.41,104.47 239.58,103.64 238.66,103.64 238.51,103.5 JNGFF2.26 ; v2(297.88,55.18) 297.88,55.19 JSIM1.C7
UIM_RESET: length 89.4
  BOTTOM w0.127: JSIM1.C2 284.29,58.37 282.96,58.37 281.29,60.04 279.9,60.04 279.69,59.83 278.99,59.83 CZ40.1 277.16,60.29 276.63,60.82 276.63,62.06 273.73,64.96 v3(273.73,71.12) 274.34,71.72 274.34,73.8 273.52,74.61 273.52,82.17 275.44,84.08 275.44,86.9 274.09,88.25 273.74,88.25 272.81,89.17 272.81,95.94 269.21,99.55 269.21,102.86 266.85,105.21 239.28,105.21 238.57,104.5 JNGFF2.22
UPD1_SMBCLK: length 273.7
  TOP w0.127: RE303.1 241.38,86.48 241.74,86.48 v2(242,86.22) ; RT58.1 39.91,79.32 39.91,80.21 QT1.1 40.44,80.26 v2(40.94,79.77) ; v2(247.88,85.06) UE1.C3
  IN1 w0.084: v2(242,86.22) 242.19,86.4 242.48,86.4 242.86,86.78 245.08,86.78 246.42,85.43 247.51,85.43 v2(247.88,85.06) ; v2(236.61,53.11) 236.8,53.3 236.8,53.64 236.6,53.83 236.22,53.83 234.12,51.73 228.46,51.73 226.81,53.37 219.42,53.37 218.24,52.19 210.37,52.19 209.21,51.03 187.65,51.03 185.68,52.99 185.68,56.14 184.92,56.9 173.88,56.9 169.67,61.11 162.88,61.11 160.84,63.14 157.26,63.14 157.1,62.98 148.02,62.98 146.44,64.56 146.44,66.62 144.95,68.11 79.51,68.11 70.8,76.82 51.91,76.82 51.63,76.54 47.53,76.54 46.94,77.13 41.7,77.13 40.85,76.28 40.26,76.28 40.01,76.53 40.01,78.14 41.18,79.31 41.18,79.52 v2(40.94,79.77)
  BOTTOM w0.127: v2(236.61,53.11) 236.76,52.96 236.76,52.65 237.03,52.38 238.93,52.38 239.48,52.93 239.48,54.57 243.67,58.77 243.67,59.57 246.01,61.91 246.01,64.07 247.71,65.77 247.71,69.19 248.72,70.2 248.72,70.66 250.53,72.48 250.53,73.98 250.96,74.41 250.96,77.03 251.27,77.35 251.27,79.2 249.04,81.44 249.04,82.46 246.67,84.82 246.67,85.23 246.91,85.46 247.5,85.46 247.88,85.07 v2(247.88,85.06)
UPD1_SMBCLK_Q: length 38.2
  TOP w0.127: RT58.2 37.74,79 37.15,79.6 v2(37.15,79.88) 37.21,79.88 37.59,80.26 QT1.6
  IN2 w0.122: v2(37.15,79.88) 37.15,79.88 35.88,81.15 35.88,86.55 34.62,87.81 33.65,87.81 32.82,86.98 31.74,86.98 31.13,86.36 29.95,86.36 29.37,86.93 27.8,86.93 26.71,85.85 26.71,84.86 25.68,83.82 25.68,82.38 24.46,81.16 24.46,77.03 23.88,76.46 23.88,75.99 24.01,75.86 v2(24.06,75.86)
  BOTTOM w0.076: UT5.B5 33.77,80.22 34.21,80.22 34.42,80.43 34.91,80.43 35.04,80.56 35.33,80.56
  BOTTOM w0.127: 35.33,80.56 36.53,80.56 37.15,79.93 v2(37.15,79.88) 37,79.72 RT67.1 ; RT92.1 24.23,75.86 v2(24.06,75.86)
UPD1_SMBDAT: length 274.5
  TOP w0.127: RE302.1 241.54,86.74 241.94,86.74 v2(242,86.8) ; UE1.B4 v2(247.08,85.86) ; RT59.1 39,81.81 39.18,81.63 39.18,81.12 v2(39.2,81.1) 39.16,81.1 38.97,81.29 38.33,81.29 QT1.4
  IN1 w0.084: v2(39.2,81.1) 39.21,81.08 39.73,81.08 40.51,80.3 40.95,80.3 41.39,79.86 41.39,79.22 40.22,78.05 40.22,76.62 40.34,76.49 40.76,76.49 41.61,77.35 47.03,77.35 47.62,76.75 51.54,76.75 51.82,77.03 70.89,77.03 79.6,68.32 145.04,68.32 146.66,66.7 146.66,64.64 148.1,63.2 157.01,63.2 157.17,63.35 160.93,63.35 162.97,61.32 169.76,61.32 173.96,57.11 185.01,57.11 185.89,56.23 185.89,53.08 187.73,51.24 209.12,51.24 210.28,52.4 218.15,52.4 219.33,53.58 226.9,53.58 228.54,51.94 234.03,51.94 236.14,54.04 236.69,54.04 237.01,53.73 237.01,53.3 v2(237.19,53.11) ; v2(247.08,85.86) 246.87,85.64 246.51,85.64 245.17,86.99 242.77,86.99 242.4,86.62 242.19,86.62 v2(242,86.8)
  BOTTOM w0.127: v2(247.08,85.86) 246.93,85.86 246.4,85.33 246.4,84.73 248.79,82.35 248.79,81.33 251.02,79.1 251.02,77.45 250.71,77.14 250.71,74.52 250.28,74.09 250.28,72.58 248.46,70.77 248.46,70.31 247.45,69.3 247.45,65.88 245.76,64.18 245.76,62.01 243.42,59.67 243.42,58.87 239.22,54.68 v4(239.22,53.71) 239.22,53.07 238.79,52.64 237.13,52.64 237.01,52.76 237.01,52.93 v2(237.19,53.11)
UPD1_SMBDAT_Q: length 42.5
  TOP w0.127: QT1.3 39.91,81.61 RT59.2 39.91,82.74 39.58,83.07 37.59,83.07 37.21,82.69 v1(37.21,82.33) 37.21,80.57 v2(37.15,80.51)
  IN2 w0.122: v2(37.15,80.51) 36.87,80.51 36.13,81.26 36.13,86.66 34.73,88.06 33.55,88.06 32.72,87.23 31.64,87.23 31.02,86.61 30.05,86.61 29.48,87.18 27.7,87.18 26.47,85.95 26.47,84.96 25.43,83.92 25.43,82.49 24.21,81.27 24.21,77.14 23.63,76.56 23.63,76.01 v2(23.44,75.81)
  BOTTOM w0.076: 35.33,80.82 35,80.82 34.83,80.65 34.33,80.65 34.16,80.47 UT5.A5
  BOTTOM w0.127: 35.33,80.82 36.9,80.82 37.15,80.57 v2(37.15,80.51) 37.89,79.78 RT66.1 ; v2(23.44,75.81) 23.44,75.73 23.79,75.39 RT93.1
UPD1_SMBINT#: length 350.1
  TOP w0.127: RE91.1 249.79,97.75 249.79,97.35 v2(249.82,97.32) ; v2(39.32,84.4) v1(38.75,84.4) ; UE1.F10 v2(250.28,91.46)
  IN1 w0.084: v2(246.25,77.07) 247.47,78.29 247.47,82.28 249.08,83.89 249.08,88.57 249.53,89.01 250.16,89.01 250.68,89.53 UE1.F10 v2(250.28,91.46) 250.69,91.87 250.69,92.75 249.82,93.62 249.82,94.79 250.12,95.08 250.12,96.8 249.79,97.12 249.79,97.29 v2(249.82,97.32)
  IN2 w0.122: v2(246.25,77.07) 245,77.07 244.08,77.99 241.83,77.99 240.61,76.76 236.93,76.76 234.76,74.59 233.7,74.59 233.42,74.32 229.68,74.32 228.03,72.67 228.03,71.34 226.62,69.93 225.99,69.93 225.69,69.63 221.98,69.63 221.02,68.67 207.89,68.67 206.54,70.03 188.27,70.03 186.63,71.67 182.52,71.67 173.02,81.17 173.02,83.24 171.01,85.25 171.01,87 170.23,87.77 170.23,88.85 169,90.08 169,92.21 167.38,93.83 167.38,106.75 163.49,110.64 163.49,117.1 163.97,117.57 163.97,120.46 162.42,122 162.42,123.46 161.28,124.61 161.28,126.99 159.35,128.92 159.35,130.89 158.75,131.48 156.59,131.48 156.25,131.82 154.44,131.82 153.32,130.7 147.9,130.7 145.37,133.22 143.22,133.22 141.75,134.69 127.29,134.69 126.42,133.82 123.87,133.82 123.16,133.11 115.46,133.11 114.7,132.34 109.5,132.34 109.31,132.53 85.47,132.53 84.36,131.42 83.7,131.42 79.99,127.71 75.85,127.71 75.21,128.36 69.15,128.36 67.97,127.18 61.77,127.18 61.65,127.05 47.54,127.05 46.1,125.61 41.45,125.61 39.57,123.73 35.92,123.73 31.12,118.92 31.12,113.91 32.32,112.71 36.16,112.71 39.33,109.54 39.78,109.54 39.96,109.35 40.3,109.35 41.01,108.64 41.01,107.55 39.86,106.4 39.86,101.58 39.12,100.83 39.12,91.14 40.39,89.86 40.39,86.89 39.32,85.82 v2(39.32,84.4)
  BOTTOM w0.127: v2(39.32,84.4) 39.05,84.4 37.61,82.95 37.61,81.62 37.31,81.33 RT60.1
UPD1_SMBINT#_R: length 3.5
  BOTTOM w0.076: UT5.B6 33.77,81.22 34.17,81.22 34.38,81.43 34.9,81.43 35.01,81.33
  BOTTOM w0.127: 35.01,81.33 RT60.2 RT68.1
UPD2_SMBCLK: length 14.6
  TOP w0.127: RPE12.3 261.31,89.93 261.19,89.81 260.97,89.81 260.75,89.59 260.5,89.59 v2(260.33,89.76) ; v2(248.68,88.33) 249.01,88.66 UE1.D7
  IN4 w0.084: v2(248.68,88.33) 249.25,88.9 256.39,88.9 257.67,90.19 259.03,90.19 259.63,89.59 260.16,89.59 v2(260.33,89.76)
UPD2_SMBDAT: length 13.8
  TOP w0.127: UE1.E7 v2(249.48,88.26) ; RPE12.4 261.33,89.43 261.21,89.55 261.07,89.55 260.85,89.33 260.49,89.33 v2(260.33,89.18)
  IN4 w0.084: v2(260.33,89.18) 260.13,89.38 259.54,89.38 258.95,89.98 257.76,89.98 256.48,88.69 249.92,88.69 v2(249.48,88.26)
UPD2_SMBINT#: length 13.5
  TOP w0.127: RE92.1 250.19,75.08 v2(250.19,75.63) ; UE1.F5 v2(250.28,86.66)
  IN1 w0.084: v2(250.19,75.63) 251.05,76.49 251.05,80.34 250.68,80.71 250.68,86.26 v2(250.28,86.66)
USB2_ID: length 20.2
  TOP w0.127: v1(133.39,100.72) 133.65,100.45 v2(133.65,100.05)
  IN2 w0.122: v2(133.65,100.05) 133.68,100.08 135.13,100.08 136.7,101.64 136.7,102.37 138.39,104.06 138.39,106.57 136.19,108.77 v2(136.19,110.94)
  BOTTOM w0.076: 136.85,110.94 v2(136.19,110.94) ; v2(133.65,100.05) 133.37,99.77 132.4,99.77 132.32,99.69 arc(132.26,99.63) 132.17,99.6 132.05,99.6 131.93,99.48 131.57,99.48 131.29,99.2 UC1.AG3
  BOTTOM w0.127: RC337.1 137.25,110.94 136.85,110.94
USB2_VBUSSENSE: length 19.9
  IN2 w0.122: v2(130.99,100.05) 131.62,100.69 135.43,100.69 136.47,101.73 136.47,102.46 138.16,104.15 138.16,106.48 135.91,108.73 135.91,110.53 135.61,110.83 v2(135.61,110.94)
  BOTTOM w0.076: v2(135.61,110.94) 136.23,111.57 136.85,111.57 ; UC1.AG4 130.99,99.72 v2(130.99,100.05)
  BOTTOM w0.127: 136.85,111.57 RC338.1
USB3_PRX_DTX_N2: length 174.1
  TOP w0.104: RI28.1 234.44,105.14 LI16.4 234.88,104.96 235.03,104.81 235.34,104.81 235.44,104.91 v2(235.44,105.2)
  IN4 w0.094: v2(128.4,108.24) 128.61,108.46 129.15,108.46 130.15,109.46 147.18,109.46 148.01,108.63 150.6,108.63 153.43,105.79 155.55,105.79 155.94,106.18 156.76,106.18 157.14,105.79 158.75,105.79 159.35,105.19 160.82,105.19 165.6,100.4 165.6,90.58 170.19,85.99 170.19,83.22 185.43,67.98 228.68,67.98 229.34,68.63 232.28,68.63 235.38,71.73 235.38,74.97 231.15,79.21 231.15,89.23 232.46,90.54 232.46,94.72 236.6,98.86 236.6,104.31 235.9,105.01 235.64,105.01 v2(235.44,105.2)
  BOTTOM w0.076: UC1.J6 128.58,107.99 128.4,108.18 v2(128.4,108.24)
USB3_PRX_DTX_N3: length 156.1
  TOP w0.104: v2(37.54,77.2) 37.38,77.04 37.38,75.92 34.27,72.81 34,72.54 34,71.26 25.59,62.85 24.47,62.85 24.09,62.47 v4(22.22,62.47) 20.7,62.47 20.55,62.32 DI1.1 DI1.9 18.74,62.32 18.59,62.47 18.26,62.47 17.73,61.95 17.73,61.24 16.43,59.94 15.48,59.94 14.9,59.35 14.44,59.35 14.33,59.25 JUSB2.5
  IN1 w0.094: v2(37.54,77.2) 37.48,77.14 37.25,77.14 37.06,77.33 37.06,78.31 36.68,78.69 36.68,86.12 37.75,87.19 37.75,88.14 38.68,89.07 40.47,89.07 41.85,87.69 48.56,87.69 49.85,86.4 51.79,86.4 53.7,84.49 56.44,84.49 56.74,84.18 66.84,84.18 67.49,84.83 70.46,84.83 74.54,88.9 74.54,98.7 80.24,104.4 89.44,104.4 89.83,104.78 89.83,105.28 90.31,105.77 91.18,105.77 92.49,107.08 96.89,107.08 97.27,106.7 115.07,106.7 115.8,105.97 118.08,105.97 118.38,105.68 119.02,105.68 119.43,106.09 119.43,107.76 120.01,108.34 124.66,108.34 125.32,107.68 125.88,107.68 126.16,107.96 126.16,108.31 126.25,108.39 126.39,108.39 v2(126.55,108.23)
  BOTTOM w0.102: UC1.J10 v2(126.55,108.23)
USB3_PRX_DTX_N6: length 200.6
  TOP w0.104: v2(237.91,73.78) 238.09,73.59 239.97,73.59 240.84,74.46 244.77,74.46 245.68,73.56 248.78,73.56 249.29,73.05 254.77,73.05 256.06,74.34 257.8,74.34 258.56,75.1 263.94,75.1 266.8,77.97 270.96,77.97 276.89,83.89 279.28,83.89 279.46,84.07 DI4.1 DI4.9 281.09,84.07 281.24,83.92 281.56,83.92 283.93,81.54 285.08,81.54 285.53,82 285.76,82 285.87,82.1 JUSB1.5
  IN4 w0.076: 130.49,108.46 130.47,108.46 130.46,108.45 130.23,108.45 129.61,107.83 126.35,107.83 126.18,108 126.18,109.78 126.25,109.85 126.68,109.85 126.75,109.78 126.75,109.67 v2(126.55,109.47)
  IN4 w0.094: v2(237.91,73.78) 237.66,73.53 236.46,73.53 236.03,73.09 236.03,71.57 232.18,67.73 229.14,67.73 228.08,66.67 190.5,66.67 189.74,67.43 184.4,67.43 176.52,75.31 176.52,76.23 169.69,83.05 169.69,85.85 165.1,90.45 165.1,100.16 160.56,104.7 159.14,104.7 158.7,105.14 152.64,105.14 149.58,108.2 147.59,108.2 146.75,109.03 135.59,109.03 135.01,108.46 130.49,108.46
  BOTTOM w0.076: v2(126.55,109.47) 126.5,109.51 126.23,109.51 126.1,109.38 UC1.G11
USB3_PRX_DTX_P2: length 174.1
  TOP w0.104: v2(235.46,104.23) 235.46,104.5 235.34,104.62 235.04,104.62 234.88,104.46 LI16.1 234.44,104.29 RI27.1
  IN4 w0.094: v2(235.46,104.23) 235.46,104.69 235.59,104.83 235.82,104.83 236.41,104.23 236.41,98.93 232.28,94.8 232.28,90.62 230.97,89.31 230.97,79.13 235.2,74.9 235.2,71.81 232.21,68.81 229.26,68.81 228.61,68.16 185.51,68.16 170.38,83.29 170.38,86.06 165.79,90.65 165.79,100.48 160.89,105.37 159.43,105.37 158.82,105.98 157.22,105.98 156.83,106.36 155.86,106.36 155.47,105.98 153.51,105.98 150.67,108.81 148.09,108.81 147.26,109.64 130.08,109.64 129.07,108.64 128.47,108.64 128.36,108.75 v2(128.36,108.91)
  BOTTOM w0.076: v2(128.36,108.91) 128.64,108.64 UC1.H6
USB3_PRX_DTX_P3: length 156.2
  TOP w0.104: v2(36.66,77.25) 36.83,77.25 37.19,76.9 37.19,76 33.81,72.62 33.81,71.34 25.51,63.04 24.39,63.04 24.01,62.66 22.55,62.66 22.51,62.7 21.93,62.7 21.89,62.66 20.7,62.66 20.54,62.82 DI1.2 DI1.8 18.74,62.82 18.59,62.67 18.18,62.67 17.54,62.03 17.54,61.32 16.35,60.13 15.4,60.13 14.82,59.55 14.44,59.55 14.33,59.65 JUSB2.6
  IN1 w0.094: v2(36.66,77.25) 36.88,77.46 36.88,78.23 36.49,78.62 36.49,86.2 37.56,87.27 37.56,88.21 38.61,89.26 40.54,89.26 41.93,87.87 48.64,87.87 49.93,86.58 51.87,86.58 53.78,84.67 56.51,84.67 56.82,84.36 66.77,84.36 67.41,85.01 70.38,85.01 74.35,88.98 74.35,98.78 80.16,104.58 89.37,104.58 89.64,104.86 89.64,105.36 90.24,105.95 91.1,105.95 92.41,107.26 96.97,107.26 97.34,106.88 115.15,106.88 115.87,106.16 118.16,106.16 118.45,105.87 118.95,105.87 119.25,106.17 119.25,107.83 119.94,108.52 124.74,108.52 125.4,107.86 125.8,107.86 125.98,108.04 125.98,108.39 126.17,108.58 126.39,108.58 126.55,108.74 v2(126.55,108.88)
  BOTTOM w0.102: UC1.H10 v2(126.55,108.88)
USB3_PRX_DTX_P6: length 200.6
  TOP w0.104: JUSB1.6 285.87,81.7 285.76,81.8 285.61,81.8 285.16,81.35 283.85,81.35 281.48,83.72 281.24,83.72 281.09,83.57 DI4.8 DI4.2 279.48,83.57 279.35,83.7 276.97,83.7 271.04,77.77 266.88,77.77 264.02,74.91 258.64,74.91 257.88,74.15 256.14,74.15 254.85,72.86 249.21,72.86 248.7,73.37 245.6,73.37 244.69,74.27 240.92,74.27 240.05,73.4 238.11,73.4 v2(237.91,73.19)
  IN4 w0.076: v2(126.59,110.24) 126.36,110.01 126.18,110.01 126.01,109.84 126.01,107.93 126.28,107.66 129.68,107.66 130.3,108.28 130.46,108.28 130.47,108.27 130.49,108.27
  IN4 w0.094: v2(237.91,73.19) 237.75,73.35 236.54,73.35 236.21,73.02 236.21,71.49 232.26,67.54 229.21,67.54 228.15,66.48 190.42,66.48 189.66,67.24 184.32,67.24 176.33,75.23 176.33,76.16 169.51,82.98 169.51,85.78 164.92,90.37 164.92,100.08 160.49,104.51 159.06,104.51 158.62,104.96 152.56,104.96 149.5,108.02 147.51,108.02 146.68,108.85 135.66,108.85 135.09,108.27 130.49,108.27
  BOTTOM w0.076: UC1.F11 126.29,109.94 v2(126.59,110.24)
USB3_PRX_L_DTX_N2: length 3.6
  TOP w0.104: RI28.2 233.53,105.12 LI16.3 233.1,104.96 232.94,104.81 232.44,104.81 232.23,104.6 231.98,104.6 v2(231.74,104.84)
  BOTTOM w0.104: v2(231.74,104.84) 231.52,104.63 231.26,104.63 231.13,104.75 JNGFF2.21
USB3_PRX_L_DTX_P2: length 3.7
  TOP w0.104: RI27.2 233.53,104.3 LI16.2 233.09,104.46 232.94,104.62 232.52,104.62 232.31,104.41 231.94,104.41 v2(231.74,104.21)
  BOTTOM w0.104: v2(231.74,104.21) 231.51,104.43 231.26,104.43 231.07,104.25 JNGFF2.23
USB3_PTX_C_DRX_N2: length 2.7
  TOP w0.104: CI29.1 230.23,98.65 v4(230.23,99.29) 230.23,100.07 230.08,100.21 LI17.1 229.91,100.77 RI30.1
USB3_PTX_C_DRX_N3: length 9.5
  TOP w0.104: JUSB2.8 14.33,65.2 14.46,65.33 14.8,65.33 15.53,64.6 16.45,64.6 16.5,64.56 16.5,64.51 16.91,64.09 16.96,64.09 17.08,63.97 v4(18.09,63.97) 18.74,63.97 18.89,63.82 DI1.7 DI1.4 20.36,63.82 20.52,63.97 20.93,63.97 21.07,64.11 21.79,64.11 CI5.1
USB3_PTX_C_DRX_N6: length 13.5
  TOP w0.104: JUSB1.8 285.87,76.1 285.76,76 285.43,76 284.64,76.78 283.74,76.78 282.62,77.9 282.62,78.36 282.66,78.4 282.66,78.98 282.62,79.01 282.62,81.22 v4(281.93,81.91) 281.43,82.42 281.03,82.42 280.88,82.57 DI4.7 DI4.4 279.5,82.57 279.34,82.4 278.45,82.4 CI13.1
USB3_PTX_C_DRX_P2: length 2.8
  TOP w0.104: CI30.1 230.42,98.69 230.42,98.95 230.46,98.98 230.46,99.58 230.42,99.62 230.42,100.05 230.58,100.22 LI17.4 230.76,100.77 RI29.1
USB3_PTX_C_DRX_P3: length 9.5
  TOP w0.104: JUSB2.9 14.33,65.69 14.5,65.52 14.88,65.52 15.61,64.79 16.53,64.79 v4(16.86,64.46) 17.16,64.17 17.76,64.17 17.8,64.2 18.38,64.2 18.42,64.17 18.7,64.17 18.85,64.32 DI1.6 DI1.5 20.35,64.32 20.51,64.17 20.85,64.17 20.99,64.31 21.79,64.31 CI4.1
USB3_PTX_C_DRX_P6: length 13.5
  TOP w0.104: JUSB1.9 285.87,75.7 285.76,75.8 285.35,75.8 284.56,76.59 283.66,76.59 282.43,77.82 v4(282.43,78.69) 282.43,81.14 282.03,81.54 281.98,81.54 281.56,81.95 281.56,82 281.35,82.22 281.04,82.22 280.89,82.07 DI4.6 DI4.5 279.47,82.07 279.33,82.21 278.45,82.21 CI16.1
USB3_PTX_DRX_N2: length 169
  TOP w0.104: v2(231.91,96.34) 231.69,96.56 230.42,96.56 230.16,96.82 230.16,97.14 CI29.2
  IN4 w0.094: v2(126.55,114.97) 126.55,115.32 126.86,115.62 126.86,116.77 129.17,119.08 135.19,119.08 136.02,118.26 143.89,118.26 144.32,118.69 150.14,118.69 153.62,115.21 153.62,114.23 155.22,112.63 155.22,111.7 155.59,111.33 156.76,111.33 159.23,108.86 164.33,108.86 168.72,104.47 168.72,92.6 170.01,91.31 170.01,90.67 170.9,89.78 170.9,87.92 172.22,86.6 172.22,83.76 186.03,69.95 220.31,69.95 226.16,75.8 229.78,75.8 231.26,77.29 231.26,77.91 230.33,78.84 230.33,95.82 231.13,96.63 231.72,96.63 231.91,96.44 v2(231.91,96.34)
  BOTTOM w0.076: v2(126.55,114.97) 126.26,114.97 125.96,114.66 125.96,113.08 125.74,112.86 125.48,112.86 UC1.B13
USB3_PTX_DRX_N3: length 194.6
  TOP w0.104: CI5.2 23.4,64.11 24.18,64.11 24.35,63.94 24.35,63.71 24.24,63.6 v2(23.91,63.6)
  IN4 w0.094: v2(23.91,63.6) 24.1,63.8 24.1,64.38 25.61,65.89 25.61,67.32 29.52,71.23 29.52,73.45 28.11,74.86 27.31,74.86 25.31,76.86 25.31,86.08 24.36,87.04 24.36,89.42 25.04,90.1 25.04,91.05 25.53,91.54 26.65,91.54 27.45,92.34 33.17,92.34 33.76,92.93 33.76,94.49 33.94,94.66 33.94,100.97 33.04,101.87 33.04,102.69 33.54,103.18 34.13,103.18 34.37,103.42 34.37,106.66 34.53,106.83 34.53,107.57 33.23,108.88 33.23,111.02 34.49,112.29 34.49,124.02 39.33,128.86 40.65,128.86 41.66,129.87 44.45,129.87 49.76,135.18 71.52,135.18 76.79,129.92 79.34,129.92 84.36,134.93 115.09,134.93 124.85,125.17 124.85,122.34 124.43,121.91 124.43,119.22 124.66,119 124.66,118.81 v2(124.86,118.6)
  BOTTOM w0.076: UC1.B15 124.09,112.82 124.19,112.82 124.35,112.98 124.35,113.59 124.65,113.88 124.65,117.58 124.66,117.59 124.66,117.61
  BOTTOM w0.104: 124.66,117.61 124.66,118.4 v2(124.86,118.6)
USB3_PTX_DRX_N6: length 196.4
  TOP w0.104: v2(234.51,74.12) 234.86,73.77 236.14,73.77 237.15,72.76 238.84,72.76 239.03,72.95 240.56,72.95 241.47,73.86 243.92,73.86 244.84,72.95 248.53,72.95 249.03,72.45 256.11,72.45 256.77,73.11 259.18,73.11 259.79,73.71 263.41,73.71 267.04,77.34 271.33,77.34 276.41,82.42 276.86,82.42 CI13.2
  IN4 w0.094: v2(234.51,74.12) 234.61,74.02 234.61,73.85 234.39,73.62 232.69,73.62 227.87,68.8 185.7,68.8 171.02,83.48 171.02,86.26 169.73,87.55 169.73,88.9 166.57,92.06 166.57,101.81 162.35,106.03 160.69,106.03 159.47,107.25 158.19,107.25 156.16,109.27 153.18,109.27 151.34,111.12 150.45,111.12 149.27,112.3 147.89,112.3 143.64,116.55 129.33,116.55 128.55,115.77 128.55,115.19 126.95,113.59 123.79,113.59 123.43,113.96 123.43,114.34 123.56,114.47 124,114.47 124.06,114.41 v2(124.06,114.19)
  BOTTOM w0.076: v2(124.06,114.19) 123.85,114.39 123.71,114.39 123.66,114.35 123.66,112.15 123.37,111.85 UC1.D16
USB3_PTX_DRX_P2: length 169
  TOP w0.104: v2(231.88,97.02) 231.88,96.9 231.74,96.76 230.5,96.76 230.36,96.9 230.36,97.27 230.49,97.41 CI30.2
  IN4 w0.094: v2(231.88,97.02) 231.67,96.81 231.06,96.81 230.15,95.9 230.15,78.77 231.08,77.83 231.08,77.37 229.7,75.99 226.09,75.99 220.24,70.13 186.11,70.13 172.4,83.84 172.4,86.67 171.09,87.99 171.09,89.85 170.19,90.75 170.19,91.39 168.91,92.67 168.91,104.54 164.4,109.05 159.31,109.05 156.84,111.52 155.67,111.52 155.41,111.77 155.41,112.7 153.8,114.3 153.8,115.29 150.22,118.87 144.24,118.87 143.81,118.44 136.09,118.44 135.27,119.26 129.09,119.26 126.67,116.84 126.67,115.69 126.36,115.38 v2(126.14,115.38)
  BOTTOM w0.076: v2(126.14,115.38) 126.14,115.08 125.79,114.73 125.79,113.15 125.67,113.02 125.4,113.02 125.29,113.14 UC1.A13
USB3_PTX_DRX_P3: length 194.6
  TOP w0.104: v2(24.83,63.61) 24.54,63.89 24.54,64.02 24.26,64.31 23.4,64.31 CI4.2
  IN4 w0.094: v2(24.83,63.61) 24.42,63.61 24.29,63.73 24.29,64.3 25.79,65.81 25.79,67.25 29.7,71.15 29.7,73.52 28.19,75.04 27.39,75.04 25.5,76.93 25.5,86.16 24.54,87.11 24.54,89.35 25.22,90.02 25.22,90.97 25.6,91.35 26.72,91.35 27.53,92.16 33.25,92.16 33.94,92.85 33.94,94.41 34.12,94.59 34.12,101.05 33.22,101.95 33.22,102.61 33.61,103 34.2,103 34.55,103.35 34.55,106.59 34.72,106.75 34.72,107.64 33.41,108.95 33.41,110.95 34.67,112.21 34.67,123.94 39.41,128.68 40.72,128.68 41.73,129.69 44.53,129.69 49.84,135 71.45,135 76.72,129.73 79.42,129.73 84.43,134.75 115.02,134.75 124.67,125.1 124.67,122.41 124.25,121.99 124.25,119.15 124.47,118.92 124.47,118.71 124.38,118.62 v2(124.16,118.62)
  BOTTOM w0.076: 124.47,117.61 124.47,117.59 124.48,117.58 124.48,113.95 124.19,113.66 124.19,113.05 124.13,112.99 124,112.99 123.93,113.05 UC1.A15
  BOTTOM w0.104: 124.47,117.61 124.47,118.31 v2(124.16,118.62)
USB3_PTX_DRX_P6: length 196.4
  TOP w0.104: v2(234.51,73.24) 234.86,73.58 236.06,73.58 237.07,72.57 238.92,72.57 239.11,72.76 240.64,72.76 241.55,73.67 243.84,73.67 244.76,72.75 248.45,72.75 248.95,72.25 256.19,72.25 256.85,72.91 259.26,72.91 259.87,73.52 263.49,73.52 267.12,77.15 271.41,77.15 276.49,82.23 276.82,82.23 CI16.2
  IN4 w0.094: v2(234.51,73.24) 234.31,73.44 232.77,73.44 227.94,68.62 185.62,68.62 170.84,83.4 170.84,86.18 169.54,87.47 169.54,88.82 166.39,91.98 166.39,101.74 162.27,105.85 160.61,105.85 159.39,107.07 158.11,107.07 156.09,109.09 153.1,109.09 151.26,110.93 150.37,110.93 149.19,112.11 147.82,112.11 143.57,116.37 129.41,116.37 128.73,115.69 128.73,115.11 127.03,113.41 123.72,113.41 123.24,113.88 123.24,114.41 123.49,114.66 123.81,114.66 v2(124.03,114.88)
  BOTTOM w0.076: v2(124.03,114.88) 124.03,114.78 123.81,114.56 123.64,114.56 123.5,114.41 123.5,112.75 123.43,112.68 123.23,112.68 123.14,112.58 123.14,112.46 123.26,112.34 UC1.C16
USB3_PTX_L_DRX_N2: length 5.9
  TOP w0.104: RI30.2 229.93,101.69 LI17.2 230.08,102.18 230.23,102.33 230.23,102.62 230.6,102.99 v4(231.2,102.99) 232.12,102.99 v2(232.32,103.19)
  BOTTOM w0.104: v2(232.32,103.19) 232.32,102.96 232.09,102.73 231.84,102.73 231.47,103.1 231.2,103.1 231.04,103.25 JNGFF2.27
USB3_PTX_L_DRX_P2: length 5.9
  TOP w0.104: v2(232.28,102.22) 232.29,102.23 232.29,102.61 232.11,102.8 231.53,102.8 231.49,102.76 230.9,102.76 230.87,102.8 230.68,102.8 230.43,102.54 230.43,102.33 230.58,102.18 LI17.3 230.74,101.69 RI29.2
  BOTTOM w0.104: JNGFF2.29 231.05,102.75 231.2,102.9 231.39,102.9 231.76,102.54 232.14,102.54 232.28,102.4 v2(232.28,102.22)
USB20_N1: length 135.5
  TOP w0.104: v2(23.62,79.23) 23.95,78.91 24.09,78.91 24.18,79 24.18,79.35 23.91,79.62 23.91,80.28 24.12,80.49 24.27,80.49 24.33,80.49 RT401.1
  IN1 w0.076: v2(128.04,101.73) 127.77,101.99 127.77,102.09 127.6,102.27 126.99,102.27 126.97,102.25 125.73,102.25 125.29,101.81 125.29,101.29 125.28,101.29 125.28,101.27
  IN1 w0.094: 125.28,101.27 125.28,100.84 124.73,100.29 117.69,100.29 116.81,99.4 116.81,97.18 116.96,97.02 116.96,94.71 115.74,93.48 114.51,93.48 112.97,91.93 101.35,91.93 98.79,89.38 90.37,89.38 88.02,87.03 75.67,87.03 74.2,85.56 73.58,85.56 71.74,83.72 68.42,83.72 67.2,82.5 60.53,82.5 60.29,82.26 52.27,82.26 47.94,86.6 37.74,86.6 37.08,85.94 37.08,81.83 37.57,81.35 37.57,78.88 38.41,78.03 38.41,76.84 36.8,75.23 31.99,75.23 31.19,76.02 28.94,76.02 27.27,77.7 25.8,77.7 24.5,79.01 23.85,79.01 v2(23.62,79.23)
  BOTTOM w0.089: UC1.AB9 128.04,101.83 v2(128.04,101.73)
USB20_N2: length 139.5
  IN1 w0.094: v2(129.99,100.62) 129.8,100.42 129.8,100.27 129.52,99.99 125.34,99.99 124.86,99.52 119.43,99.52 119.17,99.25 119.17,98.72 117.7,97.26 117.7,93.96 114.57,90.83 108.06,90.83 105.67,88.45 90.94,88.45 87.27,84.78 73.96,84.78 72.11,82.93 68.86,82.93 67.19,81.26 52.19,81.26 47.62,85.83 40.16,85.83 38.6,84.28 38.6,83.06 38.35,82.81 38.35,79.35 39.18,78.51 39.18,76.53 38.03,75.37 38.03,71.97 35.65,69.59 34.1,69.59 26.93,62.43 25.74,62.43 25.35,62.03 25.35,61.63 25.53,61.45 v2(25.74,61.45)
  BOTTOM w0.076: v2(129.99,100.62) 129.69,100.92 UC1.AD6
  BOTTOM w0.104: v2(25.74,61.45) 25.51,61.68 25.51,62.08 24.64,62.95 v4(24.33,62.95) 24.01,62.95 23.71,62.65 23.71,62.42 23.54,62.25 LI3.1
USB20_N2_R: length 14.7
  BOTTOM w0.104: LI3.2 23.54,60.56 23.8,60.3 23.8,59.41 23.7,59.31 23.34,59.31 22.14,60.51 21.38,60.51 20.86,61.03 20.86,61.4 20.97,61.5 DI2.3 21.13,62.38 21.13,62.59 20.34,63.38 v4(19.86,63.38) 18.64,63.38 17.97,62.71 15.95,62.71 15.83,62.83 JUSB2.2
USB20_N4: length 182.1
  TOP w0.104: RI48.1 234.44,106.18 LI8.1 234.89,106.37 235.06,106.53 235.24,106.53 235.43,106.72 235.48,106.72 v2(235.72,106.49)
  IN4 w0.094: v2(128.11,100.61) 127.87,100.84 127.87,100.96 127.95,101.03 130.99,101.03 131.52,100.5 133.78,100.5 134.15,100.14 135.96,100.14 136.18,100.36 140.07,100.36 140.25,100.17 140.98,100.17 141.62,100.81 141.62,100.92 143.57,102.88 144.38,102.88 144.9,102.35 149.07,102.35 149.69,101.72 152.19,101.72 154.18,99.73 154.18,92.39 155.49,91.09 163.31,91.09 168.86,85.54 168.86,82.69 175.66,75.89 175.66,74.93 184.04,66.56 189.16,66.56 189.85,65.88 231.48,65.88 237.17,71.57 237.17,72.03 237.48,72.34 238.25,72.34 238.74,72.82 238.74,74.59 238.22,75.11 237.31,75.11 233.09,79.33 233.09,94.45 237.33,98.69 237.33,105.14 236.55,105.92 235.1,105.92 234.71,106.31 234.71,106.79 234.88,106.96 235.24,106.96 v2(235.72,106.49)
  BOTTOM w0.089: v2(128.11,100.61) 128.11,100.69 UC1.AD9
USB20_N4_L: length 6.8
  TOP w0.104: RI48.2 233.53,106.22 LI8.2 233.14,106.37 232.99,106.52 232.32,106.52 232.04,106.8 232.04,106.9 232,106.93 232,107.52 232.04,107.55 v4(232.04,108.7) 232.04,109.83 231.96,109.92 231.82,109.92 v2(231.61,109.71)
  BOTTOM w0.104: v2(231.61,109.71) 231.39,109.92 231.18,109.92 231.01,109.75 JNGFF2.9
USB20_N5: length 186.9
  TOP w0.104: v2(42.36,78.96) 42.36,79.17 42.11,79.42 42.11,81.81 41.94,81.99 41.94,89.78 41.2,90.52 41.2,91.55 39.61,93.14 39.61,96.9 40.75,98.04 40.75,99.66 41.66,100.56 41.66,105.59 42.01,105.94 42.01,108.99 42.29,109.28 42.29,111.01 47.48,116.19 50.91,116.19 54.48,119.76 54.48,120.5 55.26,121.28 LZ1.1
  IN1 w0.094: v2(134.82,96.77) 134.6,96.55 134.6,96.26 138.17,92.7 138.17,89.87 145.01,83.03 145.01,78.89 144.44,78.32 144.44,75.95 142.36,73.87 83.39,73.87 79.22,78.05 51.07,78.05 50.74,77.72 48.34,77.72 47.78,78.29 43.31,78.29 42.64,78.96 v2(42.36,78.96)
  BOTTOM w0.076: v2(134.82,96.77) 134.73,96.77 134.44,97.07 134.44,97.22 134.13,97.52 132.41,97.52 132.28,97.66 132.28,97.73 UC1.AJ1
USB20_N5_R: length 16.7
  TOP w0.104: LZ1.2 57.59,121.28 57.8,121.06 58.13,121.06 DV8.1 58.71,121.06 59.18,121.06 59.47,121.35 59.47,127.41 59.43,127.44 59.43,128.03 59.47,128.06 59.47,130.06 58.99,130.53 57.99,130.53 57.91,130.45 57.91,130.24 58.03,130.12 v2(58.13,130.12)
  BOTTOM w0.104: v2(58.13,130.12) 57.93,130.31 57.8,130.31 56.91,131.2 56.91,132.08 56.75,132.24 JEDP1.12
USB20_N7: length 145.8
  IN1 w0.094: v2(132.99,98.17) 133.18,98.35 133.18,98.51 133.43,98.76 133.89,98.76 134.19,99.06 135.37,99.06 137.94,96.49 137.94,96.47 139.73,94.67 143.41,94.67 145.22,92.86 145.22,87.65 146.19,86.68 146.19,76.46 146.33,76.32 146.33,69.8 150.75,65.38 162.08,65.38 162.38,65.08 166.51,65.08 167.11,64.48 170.98,64.48 174.09,61.38 176.73,61.38 177.66,60.45 178.87,60.45 179.06,60.64 179.62,61.19 214.33,61.19 215.22,60.31 219.59,60.31 220.05,60.77 221.71,60.77 222.01,60.47 222.01,60.1 v2(222.24,59.87)
  BOTTOM w0.076: v2(132.99,98.17) 133.25,98.17 133.39,98.31 133.39,98.47 133.31,98.55 132.51,98.55 132.29,98.76 132.13,98.81 132.03,98.81 131.8,98.72 131.74,98.67 131.74,98.51 131.83,98.42 131.98,98.42 UC1.AH1
  BOTTOM w0.104: RI50.1 228.93,78.32 LI9.1 228.53,78.5 228.38,78.65 228.15,78.65 227.98,78.48 227.98,77.29 222.73,72.05 222.73,69.52 221.77,68.55 221.77,60.01 221.9,59.87 v2(222.24,59.87)
USB20_N7_L: length 6.6
  BOTTOM w0.104: RI50.2 229.84,78.34 LI9.2 230.23,78.5 230.38,78.65 230.97,78.65 231.06,78.74 231.2,78.74 231.4,78.94 231.4,79.08 231.43,79.12 231.43,79.48 230.76,80.15 230.76,80.32 230.94,80.5 231.2,80.5 v4(231.41,80.29) 231.91,79.8 232.48,79.8 232.63,79.65 JNGFF1.5
USB20_N8: length 190.9
  TOP w0.104: v2(40.46,84.06) 40.27,84.25 39.94,84.25 39.75,84.44 39.75,86.47 40.53,87.25 40.53,89.17 39.76,89.94 39.76,91.04 38.05,92.75 38.05,94.67 37.88,94.83 37.88,97.7 37.35,98.23 37.35,99.94 37.76,100.35 39.19,100.35 39.83,100.98 39.83,108.05 40.46,108.68 40.46,109.55 40.81,109.91 40.81,111.51 46.97,117.66 47.24,117.66 47.28,117.7 47.86,117.7 47.9,117.66 50.34,117.66 52.08,119.41 52.08,120.06 52,120.14 LV27.3
  IN1 w0.094: v2(40.46,84.06) 40.73,84.32 40.89,84.32 41.14,84.07 41.14,81.84 43.11,79.88 47.39,79.88 48.52,78.74 79.68,78.74 83.97,74.46 142.12,74.46 143.85,76.19 143.85,78.55 144.42,79.12 144.42,82.77 137.47,89.71 137.47,92.34 134.69,95.12 132.28,95.12 129.86,97.54 128.08,97.54 127.62,98 127.62,98.66 127.87,98.91 127.87,99.39 v2(128.05,99.57)
  BOTTOM w0.089: UC1.AF8 128.25,100 128.05,99.8 v2(128.05,99.57)
USB20_N8_R: length 13.7
  TOP w0.104: v2(51.72,131.27) 51.82,131.17 51.82,130.73 52.05,130.5 52.05,130.08 52.01,130.05 52.01,129.46 52.05,129.43 v4(52.05,127.96) 52.05,125.26 53.11,124.2 53.11,124.04 52.98,123.91 52.44,123.91 DV4.2 52.41,123.48 52.97,123.48 53.09,123.36 53.09,123.14 52.2,122.25 52.2,121.96 52,121.76 LV27.4
  BOTTOM w0.104: v2(51.72,131.27) 51.9,131.46 51.9,131.9 51.75,132.05 JEDP1.2
USB20_N9: length 202.6
  TOP w0.104: UI3.2 277.01,77.61 276.84,77.78 276.84,78.12 276.93,78.22 v2(277.09,78.22)
  IN4 w0.094: v2(277.09,78.22) 276.86,77.98 276.86,77.79 276.59,77.52 275.27,77.52 274.51,78.29 269.25,78.29 267.42,80.12 265.25,80.12 263.88,78.75 263.05,78.75 262.19,77.88 262.19,76.5 260.63,74.94 258.72,74.94 257.4,73.63 254.53,73.63 251.43,70.52 251.43,69.19 249.16,66.93 249.16,65.27 245.69,61.79 245.69,60.78 240.24,55.34 236.56,55.34 234.87,57.03 233.63,57.03 232.23,58.43 229.14,58.43 223.87,63.71 187.74,63.71 187.17,64.28 182.4,64.28 180.77,65.91 174.17,65.91 173.83,66.24 171.39,66.24 170.7,65.54 168.1,65.54 167.83,65.81 165.22,65.81 161.08,69.95 151.43,69.95 149.41,71.97 149.41,79.55 150.01,80.15 150.01,83.46 150.95,84.39 150.95,86.75 153.07,88.87 153.07,91.18 150.66,93.59 150.66,99.21 149.37,100.49 146.6,100.49 145.82,101.27 144.88,101.27 143.78,100.17 141.99,100.17 140.79,98.98 136.66,98.98 136.44,99.19 134.6,99.19 134.28,98.87 133.73,98.87 133.51,99.08 v2(133.23,99.08)
  BOTTOM w0.076: UC1.AG1 132.41,99.11 132.64,98.88 132.76,98.88 132.85,98.97 132.85,99.14 132.73,99.25 132.73,99.25 132.73,99.35 132.82,99.44 133.28,99.44 133.37,99.35 133.37,99.23 v2(133.23,99.08)
USB20_N9_R: length 11.9
  BOTTOM w0.104: JUSB1.2 284.36,78.28 283.8,78.85 282.7,78.85 281.88,79.66 281.2,79.66 280.84,79.3 280.84,78.34 279.87,77.38 279.87,77.13 280.24,76.76 DI5.2 280,75.99 280,75.68 279.68,75.36 v4(279.68,74.92) 279.68,74.66 279.48,74.46 279.08,74.46 278.87,74.26 LI7.2
USB20_N10: length 142.8
  IN1 w0.094: v2(129.25,99.53) 129.11,99.53 129.03,99.45 129.03,99.16 129.13,99.06 130.8,99.06 132.09,97.77 134.72,97.77 136.6,95.88 136.6,95.34 138.93,93.01 138.93,90.17 142.73,86.37 144.62,86.37 145.6,85.4 145.6,78.65 145.06,78.11 145.06,70.21 150.49,64.78 161.76,64.78 162.05,64.5 166.24,64.5 166.87,63.88 170.52,63.88 174.86,59.54 178.83,59.54 179.73,60.44 194.89,60.44 196.69,58.64 201.53,58.64 202.27,59.39 207.04,59.39 207.33,59.09 222.32,59.09 222.96,59.73 228.14,59.73 229.18,58.69 229.18,57.46 230.32,56.32 231.11,56.32 231.24,56.45 232.31,56.45 232.47,56.61 232.47,56.76 v2(232.29,56.94)
  BOTTOM w0.076: v2(129.25,99.53) 129.25,99.52 129.04,99.31 UC1.AH7
  BOTTOM w0.104: JUSH1.8 229.95,58.5 229.84,58.4 229.71,58.4 229.64,58.33 229.64,56.95 230.18,56.42 232.16,56.42 232.29,56.54 v2(232.29,56.94)
USB20_P1: length 135.6
  TOP w0.104: v2(23.63,78.4) 23.94,78.72 24.17,78.72 24.37,78.92 24.37,79.43 24.1,79.7 24.1,80.2 24.2,80.3 24.33,80.3 RT400.1
  IN1 w0.076: 125.47,101.27 125.47,101.29 125.46,101.29 125.46,101.74 125.8,102.08 127.04,102.08 127.06,102.1 127.53,102.1 127.61,102.02 127.61,101.93 v2(127.4,101.73)
  IN1 w0.094: 125.47,101.27 125.47,100.77 124.81,100.1 117.77,100.1 116.99,99.32 116.99,97.25 117.15,97.1 117.15,94.63 115.81,93.3 114.59,93.3 113.04,91.75 101.43,91.75 98.87,89.19 90.45,89.19 88.1,86.84 75.74,86.84 74.28,85.38 73.65,85.38 71.81,83.54 68.5,83.54 67.28,82.31 60.6,82.31 60.37,82.08 52.2,82.08 47.86,86.42 37.82,86.42 37.27,85.86 37.27,81.91 37.75,81.42 37.75,78.95 38.6,78.11 38.6,76.77 36.87,75.04 31.91,75.04 31.12,75.84 28.87,75.84 27.19,77.52 25.73,77.52 24.42,78.82 23.7,78.82 23.63,78.75 v2(23.63,78.4)
  BOTTOM w0.089: UC1.AB10 127.08,102.04 v2(127.4,101.73)
USB20_P2: length 139.5
  IN1 w0.094: v2(129.28,100.61) 129.51,100.61 129.61,100.51 129.61,100.35 129.44,100.18 125.26,100.18 124.79,99.7 119.36,99.7 118.98,99.32 118.98,98.8 117.52,97.34 117.52,94.04 114.49,91.01 107.98,91.01 105.6,88.63 90.86,88.63 87.19,84.96 73.88,84.96 72.03,83.11 68.78,83.11 67.12,81.44 52.27,81.44 47.7,86.01 40.09,86.01 38.42,84.35 38.42,83.14 38.16,82.88 38.16,79.27 39,78.43 39,76.6 37.85,75.45 37.85,72.05 35.57,69.78 34.02,69.78 26.86,62.61 25.67,62.61 25.16,62.11 25.16,61.68 v2(24.93,61.44)
  BOTTOM w0.076: UC1.AD7 129.28,100.82 v2(129.28,100.61)
  BOTTOM w0.104: LI3.4 24.14,62.17 23.9,62.4 23.9,62.57 24.06,62.72 24.6,62.72 25.32,62 25.32,61.31 25.23,61.22 25.06,61.22 24.93,61.35 v2(24.93,61.44)
USB20_P2_R: length 14.7
  BOTTOM w0.104: LI3.3 24.14,60.55 24.03,60.44 v4(24.03,59.7) 24.03,59.36 23.78,59.11 23.26,59.11 22.06,60.31 21.3,60.31 20.67,60.95 20.67,61.34 20.51,61.5 DI2.2 20.94,62.36 20.94,62.51 20.29,63.15 19.57,63.15 19.53,63.19 18.72,63.19 18.05,62.52 15.95,62.52 15.83,62.41 JUSB2.3
USB20_P4: length 182.2
  TOP w0.104: RI47.1 234.44,107.05 LI8.4 234.87,106.87 235.01,106.73 235.16,106.73 235.35,106.91 235.48,106.91 v2(235.71,107.15)
  IN4 w0.094: v2(235.71,107.15) 234.81,107.15 234.53,106.87 234.53,106.24 235.03,105.74 236.47,105.74 237.15,105.07 237.15,98.77 232.9,94.53 232.9,79.25 237.23,74.93 238.14,74.93 238.55,74.51 238.55,72.9 238.17,72.52 237.4,72.52 236.99,72.11 236.99,71.65 231.4,66.06 189.92,66.06 189.24,66.74 184.11,66.74 175.85,75.01 175.85,75.96 169.04,82.77 169.04,85.61 163.38,91.27 155.56,91.27 154.37,92.47 154.37,99.8 152.27,101.9 149.77,101.9 149.14,102.53 144.98,102.53 144.45,103.06 143.5,103.06 141.44,101 141.44,100.89 140.91,100.36 140.33,100.36 140.15,100.54 136.11,100.54 135.89,100.32 134.22,100.32 133.85,100.69 131.59,100.69 131.07,101.21 127.87,101.21 127.67,101.01 127.67,100.88 v2(127.4,100.61)
  BOTTOM w0.089: UC1.AD10 127.4,100.75 v2(127.4,100.61)
USB20_P4_L: length 6.8
  TOP w0.104: RI47.2 233.53,107.01 LI8.3 233.12,106.87 232.97,106.71 232.4,106.71 232.23,106.88 v4(232.23,107.22) 232.23,108.37 232.27,108.41 232.27,108.99 232.23,109.03 232.23,109.91 232.04,110.11 231.84,110.11 v2(231.61,110.34)
  BOTTOM w0.104: JNGFF2.7 231.05,110.25 231.18,110.12 231.39,110.12 231.61,110.33 v2(231.61,110.34)
USB20_P5: length 186.9
  TOP w0.104: LZ1.4 55.82,120.68 55.76,120.74 55.76,120.98 55.65,121.09 55.34,121.09 54.67,120.42 54.67,119.68 50.99,116 47.56,116 42.49,110.93 42.49,109.2 42.2,108.91 42.2,105.86 41.85,105.51 41.85,100.48 40.94,99.58 40.94,97.96 39.8,96.82 39.8,93.22 41.4,91.63 41.4,90.6 42.13,89.86 42.13,82.07 42.3,81.89 42.3,79.5 42.44,79.36 42.69,79.36 v2(42.83,79.51)
  IN1 w0.094: v2(134.06,96.78) 134.34,96.78 134.42,96.71 134.42,96.19 137.99,92.62 137.99,89.79 144.82,82.96 144.82,78.96 144.25,78.39 144.25,76.02 142.28,74.06 83.47,74.06 79.29,78.23 50.99,78.23 50.67,77.91 48.42,77.91 47.85,78.47 43.38,78.47 42.73,79.13 42.73,79.4 v2(42.83,79.51)
  BOTTOM w0.076: v2(134.06,96.78) 134.06,96.79 134.27,97 134.27,97.15 134.06,97.36 132.35,97.36 131.83,97.87 UC1.AJ2
USB20_P5_R: length 16.7
  TOP w0.104: LZ1.3 57.58,120.68 57.77,120.87 58.19,120.87 DV7.1 58.65,120.87 59.26,120.87 59.66,121.27 v4(59.66,127.73) 59.66,130.14 59.07,130.73 58.25,130.73 58.14,130.83 v2(58.14,130.95)
  BOTTOM w0.104: JEDP1.13 57.25,132.24 57.1,132.09 57.1,131.28 57.88,130.51 58.01,130.51 58.14,130.64 v2(58.14,130.95)
USB20_P7: length 145.8
  IN1 w0.094: v2(221.35,59.87) 221.72,59.87 221.83,59.98 221.83,60.4 221.64,60.59 220.13,60.59 219.66,60.13 215.14,60.13 214.26,61.01 179.69,61.01 178.95,60.27 177.58,60.27 176.66,61.19 174.01,61.19 170.91,64.3 167.04,64.3 166.44,64.9 162.31,64.9 162.01,65.2 150.68,65.2 146.15,69.73 146.15,76.25 146.01,76.39 146.01,86.61 145.04,87.58 145.04,92.78 143.34,94.49 139.66,94.49 137.76,96.39 137.76,96.41 135.29,98.88 134.27,98.88 133.96,98.58 133.5,98.58 133.36,98.43 133.36,98.27 133.44,98.19 v2(133.81,98.19)
  BOTTOM w0.076: UC1.AH2 131.57,98.67 131.57,98.74 131.7,98.87 132.01,98.97 132.16,98.97 132.37,98.91 132.57,98.71 133.38,98.71 133.56,98.54 133.56,98.32 133.68,98.19 v2(133.81,98.19)
  BOTTOM w0.104: v2(221.35,59.87) 221.58,60.09 221.58,68.63 222.54,69.6 222.54,72.13 227.78,77.37 227.78,78.56 228.07,78.84 228.33,78.84 228.48,79 LI9.4 228.93,79.17 RI49.1
USB20_P7_L: length 6.5
  BOTTOM w0.104: RI49.2 229.84,79.15 LI9.3 230.23,79 230.38,78.85 230.84,78.85 v4(231.03,79.04) 231.24,79.25 231.24,79.4 230.57,80.07 230.57,80.4 230.86,80.69 231.33,80.69 231.78,80.25 231.78,80.19 231.99,79.99 232.48,79.99 232.64,80.15 JNGFF1.3
USB20_P8: length 190.8
  TOP w0.104: v2(40.46,84.83) 40.46,84.59 40.32,84.44 40.02,84.44 39.94,84.52 39.94,86.39 40.72,87.17 40.72,89.25 39.96,90.02 39.96,91.12 38.24,92.83 38.24,94.75 38.08,94.91 38.08,97.78 37.55,98.31 37.55,99.86 37.84,100.16 39.27,100.16 40.02,100.9 40.02,107.97 40.65,108.6 40.65,109.47 41.01,109.83 41.01,111.43 47.05,117.47 v4(47.57,117.47) 50.42,117.47 52.27,119.33 52.27,119.91 52.6,120.24 LV27.2
  IN1 w0.094: v2(40.46,84.83) 40.79,84.51 40.96,84.51 41.32,84.15 41.32,81.92 43.18,80.06 47.46,80.06 48.6,78.93 79.76,78.93 84.04,74.64 142.05,74.64 143.67,76.26 143.67,78.63 144.24,79.2 144.24,82.69 137.29,89.64 137.29,92.27 134.62,94.94 132.2,94.94 129.79,97.35 128.01,97.35 127.44,97.92 127.44,98.73 127.69,98.98 127.69,99.41 127.53,99.57 v2(127.26,99.57)
  BOTTOM w0.089: UC1.AF9 127.7,100 v2(127.26,99.57)
USB20_P8_R: length 13.7
  TOP w0.104: LV27.1 52.6,121.73 52.39,121.94 52.39,122.17 53.28,123.06 53.28,123.33 53.43,123.48 53.94,123.48 DV4.3 53.91,123.91 53.39,123.91 53.3,124 53.3,124.28 52.24,125.34 52.24,127.64 52.28,127.67 52.28,128.25 52.24,128.29 v4(52.24,129.75) 52.24,130.58 52.02,130.81 52.02,130.99 v2(52.3,131.27)
  BOTTOM w0.104: JEDP1.3 52.25,132.04 52.1,131.89 52.1,131.48 v2(52.3,131.27)
USB20_P9: length 202.6
  TOP w0.104: v2(276.28,78.24) 276.65,77.87 276.65,77.7 276.51,77.56 UI3.3
  IN4 w0.094: v2(133.71,99.47) 133.59,99.35 133.59,99.26 133.8,99.05 134.2,99.05 134.52,99.37 136.52,99.37 136.73,99.16 140.72,99.16 141.92,100.36 143.7,100.36 144.8,101.45 145.89,101.45 146.68,100.67 149.45,100.67 150.84,99.28 150.84,93.67 153.26,91.25 153.26,88.8 151.13,86.67 151.13,84.31 150.19,83.38 150.19,80.07 149.59,79.47 149.59,72.04 151.5,70.13 161.16,70.13 165.3,65.99 167.91,65.99 168.18,65.73 170.62,65.73 171.32,66.42 173.91,66.42 174.24,66.09 180.85,66.09 182.47,64.47 187.24,64.47 187.82,63.89 223.94,63.89 229.21,58.62 232.3,58.62 233.71,57.21 234.94,57.21 236.64,55.52 240.17,55.52 245.5,60.85 245.5,61.87 248.98,65.35 248.98,67 251.25,69.27 251.25,70.6 254.46,73.81 257.33,73.81 258.64,75.12 260.55,75.12 262,76.57 262,77.95 262.98,78.93 263.8,78.93 265.17,80.3 267.5,80.3 269.33,78.47 274.58,78.47 275.34,77.71 276.51,77.71 276.67,77.87 276.67,78.24 276.58,78.34 276.38,78.34 v2(276.28,78.24)
  BOTTOM w0.076: UC1.AG2 132.01,99.2 132.26,99.45 132.59,99.45 132.75,99.6 133.35,99.6 133.48,99.47 v2(133.71,99.47)
USB20_P9_R: length 12
  BOTTOM w0.104: LI7.3 278.93,74.86 279.13,74.66 279.4,74.66 279.45,74.7 279.45,75.4 279.81,75.76 279.81,76.2 279.48,76.52 279.07,76.52 DI5.3 279.32,76.76 279.68,77.11 279.68,77.46 280.64,78.42 280.64,79.38 281.16,79.89 v4(281.57,79.89) 281.92,79.89 282.78,79.04 283.51,79.04 JUSB1.3
USB20_P10: length 142.8
  IN1 w0.094: v2(128.66,99.56) 128.84,99.38 128.84,99.09 129.06,98.87 130.73,98.87 132.02,97.58 134.65,97.58 136.42,95.81 136.42,95.26 138.75,92.93 138.75,90.09 142.65,86.19 144.55,86.19 145.42,85.32 145.42,78.73 144.88,78.19 144.88,70.14 150.42,64.6 161.69,64.6 161.97,64.32 166.17,64.32 166.79,63.69 170.45,63.69 174.78,59.36 178.91,59.36 179.8,60.26 194.81,60.26 196.61,58.46 201.6,58.46 202.35,59.2 206.96,59.2 207.25,58.91 222.4,58.91 223.03,59.55 228.07,59.55 229,58.62 229,57.39 230.24,56.14 231.19,56.14 231.31,56.27 232.51,56.27 v2(232.6,56.17)
  BOTTOM w0.076: UC1.AH8 128.38,99.28 v2(128.66,99.56)
  BOTTOM w0.104: JUSH1.9 229.45,56.87 230.1,56.22 232.55,56.22 v2(232.6,56.17)
USB_OC0#: length 259.6
  TOP w0.127: v2(279.11,75.64) 279.11,75.28 278.84,75.02 UI3.13
  IN2 w0.122: v2(270.2,76.13) 270.2,69.64 268.77,68.21 261.47,68.21 261.07,67.81 261.07,67.26 260.79,66.98 260.36,66.98 260.04,66.66 256.63,66.66 255.77,67.52 252.73,67.52 251.85,66.63 250.63,66.63 249.77,65.77 249.23,65.77 244.45,61 244.45,59.72 242.92,58.19 240.59,58.19 240.31,57.91 236.33,57.91 235.49,57.07 232.92,57.07 232.18,57.82 230.73,57.82 228.98,56.07 226.47,56.07 226.19,55.8 222.85,55.8 222.06,56.59 222.06,56.87 221.41,57.52 220.78,57.52 219.06,55.8 216.04,55.8 215.29,56.55 211.27,56.55 210.48,55.75 210.11,55.75 210.11,55.75 208.31,55.75 207.17,54.62 204.98,54.62 204.52,55.08 204.52,55.44 201.5,58.46 199.37,58.46 199.29,58.54 196.22,58.54 195.01,59.75 182.17,59.75 181.85,59.44 180.99,59.44 180.67,59.75 179.85,59.75 179.5,59.4 178.55,59.4 177.85,58.71 175.08,58.71 174,59.79 172.65,59.79 172.5,59.95 171.29,59.95 170.27,60.97 169.91,60.97 169.41,61.47 166.32,61.47 165.37,60.52 160.72,60.52 160.27,60.97 160.27,62.44 158.89,63.82 150.85,63.82 150.8,63.87 150.32,63.87 148.19,66 148.19,66.88 142.39,72.68 142.39,73.4 139.19,76.6 139.19,78.3 139.31,78.41 139.31,79.97 139.44,80.1 139.44,80.42 v2(140.36,81.34) ; v2(152.35,93.18) 151.99,93.54 151.99,98.12 149.76,100.36 149.76,104.56 149.3,105.01 149.3,105.69 150.46,106.85 150.46,108.47 151.29,109.29 151.29,110.54 150.52,111.31 150.52,112.41 150.94,112.84 150.94,119.32 v2(150.52,119.75)
  IN4 w0.084: v2(148.59,93.18) 148.19,92.77 148.19,91.83 144.71,88.36 144.71,84.57 144.25,84.11 141.65,84.11 140.94,83.39 140.94,82.55 140.36,81.98 v2(140.36,81.34) ; v2(270.2,76.13) 271.02,75.32 275.23,75.32 276.06,74.5 277.96,74.5 v2(279.11,75.64) ; v2(150.52,119.75) 148.74,121.53 135.14,121.53 134.58,120.97 134.58,120.28 134.33,120.03 129.76,120.03 129.51,119.78 129.03,119.78 127.69,118.43 v2(127.56,118.43)
  BOTTOM w0.102: 128.1,114.66 128.09,114.65 128.09,113.96 127.76,113.63 UC1.A9
  BOTTOM w0.127: RPC3.3 127.85,118.73 v2(127.56,118.43) 127.6,118.39 127.6,116.47 128.1,115.97 128.1,114.66 ; v2(152.35,93.18) 152.23,93.3 v1(151.59,93.3) 148.71,93.3 v2(148.59,93.18)
USB_OC1#: length 220.6
  IN1 w0.084: v2(23.06,58.66) 23.06,59.05 19.36,62.75 19.36,71.1 13.64,76.82 13.64,90.43 13.39,90.69 13.39,94.94 14.74,96.29 14.77,96.29 14.91,96.43 15.39,96.43 17.88,93.94 17.88,93.51 19.13,92.27 21.67,92.27 22.93,93.53 22.93,94.22 23.1,94.38 23.1,102.96 24.97,104.83 24.97,106.22 25.87,107.13 25.87,107.59 26.34,108.06 26.34,108.76 26.94,109.37 26.94,110.56 27.86,111.48 30.19,111.48 30.97,112.26 30.97,125.83 31.64,126.5 35.41,126.5 37.72,128.81 44.31,128.81 51.05,135.54 71.17,135.54 74.71,132 74.71,131.37 76.67,129.41 79.12,129.41 81.54,131.83 81.54,134.11 82.4,134.97 84.4,134.97 84.55,134.82 105.68,134.82 110.08,130.43 114.24,130.43 121.44,123.22 125.7,123.22 126.73,122.19 128.85,122.19 129.31,121.73 v2(129.31,120.99)
  BOTTOM w0.102: 128.37,114.64 128.37,113.91 128.09,113.63 128.09,112.55 127.76,112.22 UC1.C9
  BOTTOM w0.127: 128.37,114.64 128.37,116.04 127.89,116.53 127.89,117.37 127.91,117.39 127.91,117.64 127.89,117.66 127.89,118.15 128.35,118.62 RPC3.2 128.35,119.53 128.52,119.7 129.28,119.7 129.44,119.85 129.44,120.86 v2(129.31,120.99) ; v2(23.06,58.66) 23.34,58.38 23.34,56.09 22.3,55.05 22.01,55.05 21.92,55.14 UI1.3
USB_OC2#: length 9.1
  BOTTOM w0.076: UC1.D9 127.76,111.61 128.19,112.03 128.42,112.03 128.67,112.28 128.67,112.42
  BOTTOM w0.127: RPC3.1 128.85,118.81 128.1,118.06 128.1,117.75 128.12,117.73 128.12,117.3 128.1,117.28 128.1,116.89 v1(128.25,116.73) 128.65,116.34 128.65,113.88 128.34,113.57 128.34,112.76 128.67,112.44 128.67,112.42
USB_OC3#: length 7.3
  BOTTOM w0.102: 127.87,114.04 127.45,113.62 127.45,112.98 UC1.B9
  BOTTOM w0.127: 127.87,114.04 127.87,115.7 127.35,116.21 127.35,117.17 127.08,117.44 v1(127.08,117.8) 127.08,118.66 127.35,118.93 RPC3.4
USB_POWERSHARE_EN#: length 31.7
  TOP w0.127: UI3.6 v2(274.41,76.02) ; UE1.J3 v2(253.48,85.06) ; v2(254.09,78.43) 254.21,78.31 RPE11.2
  IN1 w0.084: v2(253.48,85.06) 253.48,82.5 254.41,81.58 254.41,80.39 253.79,79.76 253.79,78.78 254.09,78.48 v2(254.09,78.43) 254.53,77.99 254.98,77.99 255.36,78.37 259.81,78.37 260.36,78.92 262.12,78.92 262.29,79.09 264.46,79.09 265.96,77.58 271.21,77.58 272.39,76.4 274.03,76.4 v2(274.41,76.02)
USB_POWERSHARE_VBUS_EN: length 30.9
  TOP w0.127: UI3.5 274.55,76.52 v2(274.41,76.66) 274.41,76.85 v1(273.96,77.29) ; UE1.J2 253.52,84.22 253.52,83.08 255.33,81.27 255.33,79.06 v2(254.71,78.43) RPE11.1
  IN1 w0.084: v2(254.71,78.43) 254.9,78.62 259.62,78.62 260.1,79.1 262.04,79.1 262.21,79.27 264.54,79.27 266,77.81 271.36,77.81 272.52,76.66 v2(274.41,76.66)
USB_PWR_EN1#: length 274.8
  TOP w0.127: RPE11.3 253.71,78.18 253.64,78.24 253.64,78.79 253.91,79.07 v2(254.18,79.07) ; UE1.K3 v2(254.28,85.06)
  IN1 w0.084: v2(254.18,79.07) 254.18,79.83 254.59,80.24 254.59,81.65 253.77,82.48 253.77,84.53 254.28,85.04 v2(254.28,85.06)
  IN2 w0.122: v2(64.98,57.15) 65.42,57.59 69.28,57.59 69.73,57.14 71.63,57.14 75.65,53.11 102.9,53.11 104.01,54.23 140.26,54.23 141.79,55.38 144.7,55.38 146.02,56.7 159.4,56.7 161.44,54.67 176.75,54.67 178,53.41 181.53,53.41 182.58,52.36 183.01,52.36 183.65,51.72 186.83,51.72 187.74,50.81 208.21,50.81 209.97,52.56 213.92,52.56 214.24,52.24 218.53,52.24 219.25,52.97 222.5,52.97 222.86,53.33 225.51,53.33 225.6,53.25 225.6,53.25 225.69,53.16 225.69,53.16 226.21,52.64 229.73,52.64 229.9,52.47 234.36,52.47 237.56,55.67 v2(237.56,55.95)
  IN4 w0.084: v2(237.56,55.95) 239.6,57.99 241.34,57.99 244.59,61.25 244.59,62.24 245.41,63.07 245.41,64.86 247.51,66.96 247.51,69.72 248.97,71.18 248.97,75.58 249.91,76.52 251.59,76.52 254.14,79.07 v2(254.18,79.07)
  BOTTOM w0.127: v2(64.98,57.15) 64.82,56.99 64.82,54.64 62.63,52.45 62.63,50.54 61.91,49.82 41.02,49.82 37.53,53.31 31.56,53.31 29.36,55.51 24.31,55.51 v1(23.6,54.8) 21.92,53.12 UI1.4
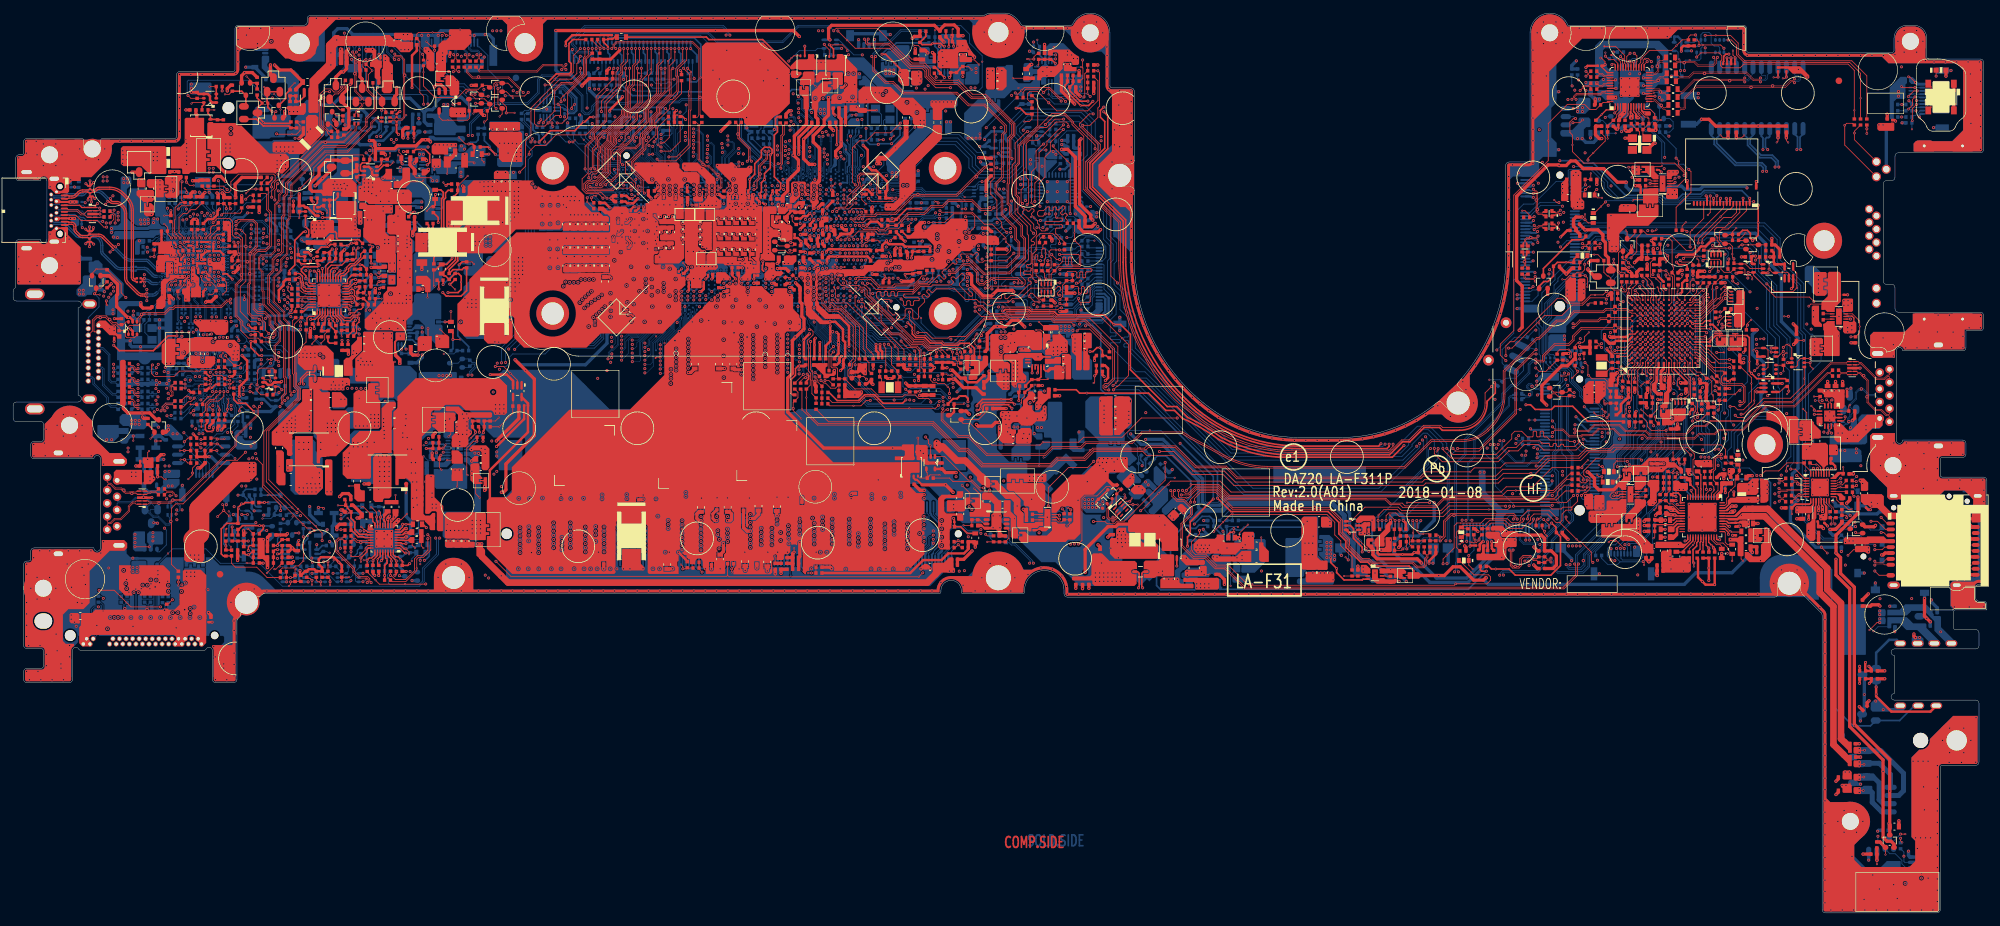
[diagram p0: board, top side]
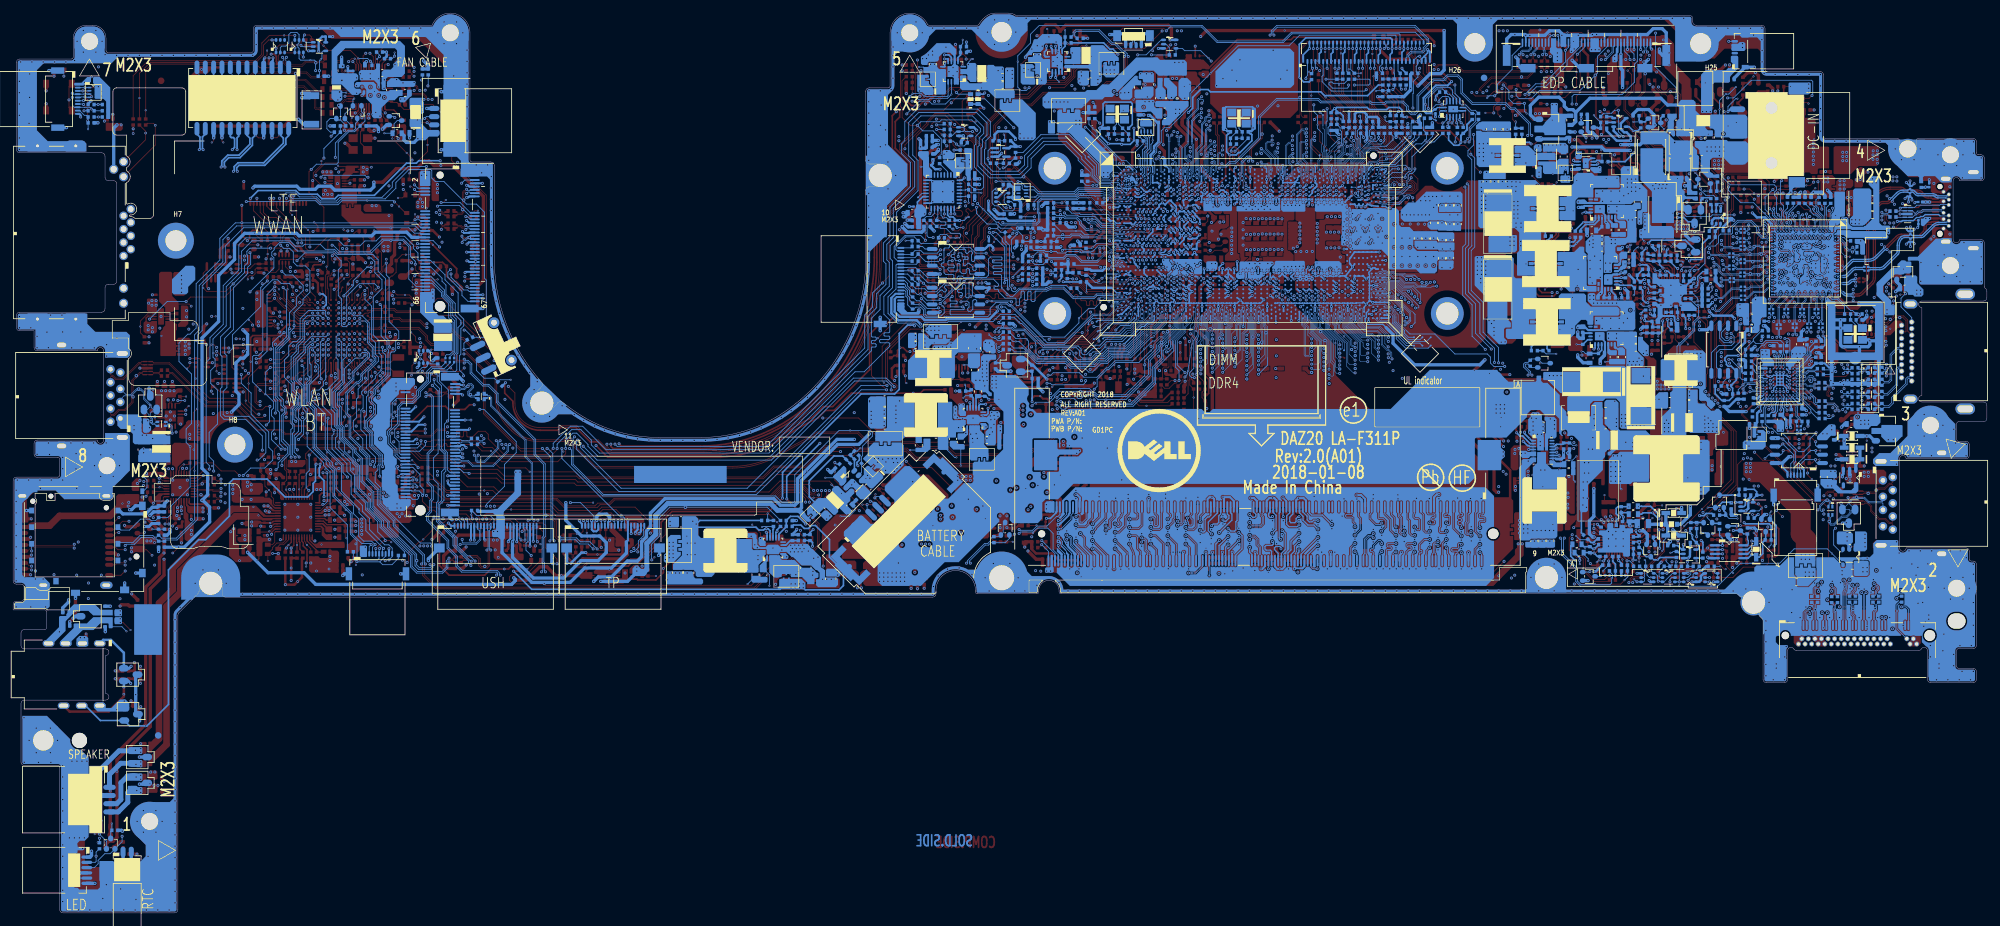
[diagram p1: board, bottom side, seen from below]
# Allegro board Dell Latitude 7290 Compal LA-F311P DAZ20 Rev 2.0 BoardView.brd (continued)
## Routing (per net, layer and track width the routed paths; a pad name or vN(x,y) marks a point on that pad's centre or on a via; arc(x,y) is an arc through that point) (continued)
USB_PWR_EN2#: length 10.8
  TOP w0.127: v2(251.08,86.66) UE1.G5 ; v2(252.68,78.26) 253.02,78.26 253.21,78.07 RPE11.4
  IN1 w0.084: v2(251.08,86.66) 251.1,86.66 251.47,86.28 251.47,85.72 252.61,84.58 252.61,79.69 252.37,79.45 252.37,78.56 v2(252.68,78.26)
USBCOMP: length 3.7
  TOP w0.127: v2(129.35,101.72) 129.88,102.25 130.09,102.25 130.42,102.58 RC44.1 131.74,102.58 v1(132.01,102.3)
  BOTTOM w0.102: UC1.AB6 129.69,102.05 v2(129.35,101.72)
USH_DET#: length 64.2
  TOP w0.127: v2(248.18,94.19) 248.21,94.19 248.28,94.12 UE1.C13 ; DZ7.2 220.92,59.08 224.18,59.08 224.97,59.87 227.27,59.87 v1(227.99,59.15) 229.34,59.15 229.77,59.57 229.93,59.57 230.1,59.74 v2(230.1,60.06) ; DZ7.2 220.85,58.57 RZ87.1 ; DZ7.2 219.92,58.08 219.92,55.69 RE526.2
  IN4 w0.084: v2(248.18,94.19) 245.42,91.43 245.42,85.43 243.94,83.96 243.94,81.77 244.37,81.34 244.37,74.38 245.34,73.42 245.34,70.29 243.53,68.48 243.53,65.54 240.9,62.91 238.15,62.91 236.84,61.6 231.64,61.6 v2(230.1,60.06)
USH_DET#_R: length 5.1
  TOP w0.127: v1(220.33,56.22) 220.44,56.22 220.8,56.59 v2(220.83,56.59) 220.63,56.78 DZ7.1 221,57.66 RZ87.2
  BOTTOM w0.127: v2(220.83,56.59) 220.83,56.71 220.92,56.8 220.92,59 JUSH1.26
USH_EXPANDER_SMBCLK: length 61.5
  TOP w0.127: UE1.B3 v2(247.08,85.06) ; v2(228.51,55.33) 228.33,55.14 228.33,53.04 228.54,52.83 v4(228.84,52.83) 229.33,52.83 229.54,53.04 229.54,54 230.03,54.49 231.2,54.49 231.7,53.98 232.12,53.98 CZ62.1 RZ8.2 233.36,54.29 233.71,53.94 234.13,53.94 v2(234.29,54.1)
  BOTTOM w0.127: v2(234.29,54.1) 234.71,53.68 234.71,52.7 235.36,52.05 239.11,52.05 239.93,52.86 239.93,54.62 244.25,58.94 244.25,59.78 246.24,61.78 246.24,63.07 247.94,64.77 247.94,68.2 248.57,68.83 248.57,69.15 248.95,69.52 248.95,70.57 250.76,72.38 250.76,73.89 251.25,74.38 251.25,76.77 251.61,77.13 251.61,79.45 250.23,80.83 250.23,82.95 248.59,84.59 247.55,84.59 v2(247.08,85.06) ; JUSH1.11 228.45,58.43 228.34,58.33 228.34,55.5 v2(228.51,55.33)
USH_EXPANDER_SMBDAT: length 62.2
  TOP w0.127: v2(249.48,86.66) UE1.E5 ; v2(227.93,55.33) 228.09,55.17 228.09,52.94 228.45,52.58 229.42,52.58 229.78,52.94 229.78,53.9 230.13,54.25 231.11,54.25 231.62,53.74 232.12,53.74 CZ63.1 RZ9.2 233.6,53.7 234.1,53.7 v2(234.29,53.51)
  BOTTOM w0.127: v2(227.93,55.33) 228.1,55.5 228.1,58.34 227.95,58.5 JUSH1.12 ; v2(234.29,53.51) 234.47,53.34 234.47,52.61 235.26,51.81 239.22,51.81 240.17,52.76 240.17,54.48 244.57,58.88 244.57,59.74 246.48,61.65 246.48,62.97 248.18,64.67 248.18,68.11 248.8,68.74 248.8,69.01 250.2,70.4 250.2,71.49 250.99,72.29 250.99,73.79 251.48,74.28 251.48,76.58 251.99,77.09 251.99,79.41 250.46,80.94 250.46,84.32 249.88,84.9 249.88,86.29 249.51,86.66 v2(249.48,86.66)
USH_PWR_STATE#: length 99
  TOP w0.127: v2(253.01,80.74) v1(253.01,81.8) 253.01,82.31 252.68,82.63 252.68,84.28 252.31,84.66 UE1.H2 ; v2(222.72,56.84) 222.72,56.84 222.72,56.85 222.53,57.04 RZ10.2
  IN2 w0.122: v2(222.72,56.84) 222.72,57.36 222.89,57.53 228.2,57.53 228.93,58.27 232.36,58.27 233.11,57.52 235.31,57.52 236.15,58.36 240.13,58.36 240.4,58.63 242.73,58.63 244,59.91 244,61.18 246.01,63.19 246.01,64.1 248.46,66.55 248.99,66.55 249.55,67.11 251.54,67.11 252.41,67.98 255.94,67.98 256.81,67.11 259.54,67.11 260.52,68.1 261,68.1 261.34,68.44 268.68,68.44 269.83,69.59 269.83,75.64 269.26,76.21 269.26,77.68 267.04,79.91 267.04,83.27 266.01,84.3 266.01,86.31 v2(265.63,86.69)
  IN4 w0.084: v2(253.01,80.74) 253.26,80.49 254.18,80.49 256.55,82.86 259.02,82.86 260.97,84.8 262.09,84.8 263.5,83.4 264,83.4 264.91,84.3 264.91,85.96 v2(265.63,86.69)
  BOTTOM w0.127: JUSH1.22 222.95,58.59 222.72,58.36 v2(222.72,56.84)
USH_RST#_R: length 4.8
  TOP w0.127: RZ114.2 223.33,57.2 v2(223.33,56.87) 222.9,56.44 222.15,56.44 v1(222.02,56.58)
  BOTTOM w0.127: v2(223.33,56.87) 223.6,57.14 223.6,58.52 223.45,58.67 JUSH1.21
VCI_IN1#: length 14
  TOP w0.127: RE507.1 237.97,82.99 v2(238.36,82.59) 238.36,82.41 v1(237.49,81.54) ; UE1.B5 247.05,86.62 246.51,86.62 245.63,85.75 v2(244.02,85.75)
  IN2 w0.122: v2(238.36,82.59) 238.36,83.53 240.25,85.42 243.7,85.42 v2(244.02,85.75)
VCI_IN2#: length 16.9
  TOP w0.127: RE508.1 237.97,86.52 238.39,86.94 v2(238.64,86.94) 239.11,86.94 239.41,87.24 239.41,87.87 v1(240.07,88.52) ; UE1.D4 v2(248.68,85.86)
  IN2 w0.122: v2(238.64,86.94) 238.31,87.27 238.31,87.67 238.73,88.08 241.12,88.08 241.99,87.22 242.59,87.22 242.75,87.05 245.29,87.05 246.89,85.46 248.28,85.46 v2(248.68,85.86)
VCT_LAN_R1: length 2.3
  TOP w0.127: RL3.1 245.58,121.23 246.02,121.68 v1(246.02,121.75) 246.02,122.39 246.08,122.44 UL1.6
VGA_IDENTIFY: length 16.8
  TOP w0.127: RE84.1 250.98,101.86 250.98,101.05 250.93,101.01 RE85.1 251.67,100.62 v2(252.08,100.21) 252.2,100.09 252.2,99.59 v1(251.8,99.2) ; UE1.L9 v2(255.08,90.66)
  IN4 w0.084: v2(255.08,90.66) 255.1,90.66 255.54,91.1 255.54,93.7 253.18,96.06 252.23,96.06 251.41,96.87 251.41,98.47 252.08,99.14 v2(252.08,100.21)
VID0_PRIM_CORE: length 4.6
  TOP w0.127: PR408.2 156.25,129.37 v1(156.07,129.2)
  TOP w0.254: PR408.2 PR418.2 PR420.1 158.17,130.15 v2(158.77,129.55)
  BOTTOM w0.254: v2(158.77,129.55) 158.77,129.11 158.85,129.03 PU402.9
VID0_VCCIO: length 4.8
  TOP w0.127: v1(143.17,134.78) 143.06,134.68 PR414.2
  TOP w0.254: v2(143.28,132.15) 143.28,132.65 PR416.1 143.06,132.87 PR414.2
  BOTTOM w0.254: v2(143.28,132.15) 143.28,131.58 143.57,131.29 143.57,130.73 143.39,130.55 PU401.9
VID1_PRIM_CORE: length 16.1
  TOP w0.254: PR419.1 PR411.2 161.48,126.44 PR417.2 160.98,125.36 v1(161.81,124.52) 162.55,123.78 v2(163.74,123.78)
  IN1 w0.254: v2(158.8,130.21) 159.38,129.64 159.38,126.86 162.46,123.78 v2(163.74,123.78)
  BOTTOM w0.254: v2(158.8,130.21) 158.29,130.21 158.25,130.17 PU402.8
VID1_VCCIO: length 3.4
  TOP w0.254: v2(142.56,132.13) 142.56,133.15 PR415.1 PR413.2
  BOTTOM w0.254: v2(142.56,132.13) 142.56,131.88 142.38,131.7 PU401.8
VIDALERT_N: length 79.9
  TOP w0.127: v2(41.85,95.43) 41.85,94.92 PR625.1
  IN1 w0.084: v2(93.8,118.25) 92.69,119.36 87.54,119.36 86.77,118.58 79.71,118.58 79.17,119.12 78.05,119.12 77.54,118.61 71.3,118.61 69.65,120.26 52.94,120.26 50.72,118.04 48.69,118.04 44.12,113.47 44.12,107.68 43.44,107.01 43.44,102.69 44.38,101.76 44.38,99.47 41.54,96.63 41.54,95.79 41.85,95.48 v2(41.85,95.43)
  BOTTOM w0.127: PR604.2 41.85,94.93 v2(41.85,95.43) ; v2(93.8,118.25) 94.04,118.49 94.04,119.3 RC153.2 93.56,120.65 RC152.1
VIDALERT_N_B: length 2.4
  TOP w0.127: PR625.2 43.72,93.97 PU602.36
VIDSCLK: length 87.4
  TOP w0.127: PR618.1 42.27,93.43 41.85,93.85 v2(41.85,93.93)
  IN1 w0.084: v2(41.85,93.93) 41.85,94.77 41.06,95.56 41.06,96.81 43.88,99.63 43.88,101.55 42.94,102.48 42.94,107.24 43.62,107.92 43.62,109.08 43.15,109.55 43.15,111.04 43.62,111.51 43.62,113.67 48.49,118.54 50.52,118.54 52.81,120.84 59.52,120.84 59.64,120.73 69.93,120.73 71.54,119.11 77.24,119.11 77.75,119.62 79.38,119.62 79.89,119.11 86.59,119.11 87.33,119.86 93.35,119.86 v2(94.97,118.24)
  BOTTOM w0.076: 95.41,117.47 95.41,116.66 95.93,116.13 v1(95.93,115.68) 95.93,115.2 96.61,114.52 96.61,113.38 UC1.A63
  BOTTOM w0.127: 95.41,117.47 CC321.1 94.97,118.44 v2(94.97,118.24) ; PR601.2 42.27,93.42 41.85,93.85 v2(41.85,93.93)
VIDSCLK_B: length 2.5
  TOP w0.127: PR618.2 43.69,93.74 44.76,93.74 44.94,93.57 PU602.37
VIDSOUT: length 89
  TOP w0.127: v2(42.1,95.96) 42.46,95.6 PR626.1
  IN1 w0.084: v2(42.1,95.96) 42.14,95.92 42.83,95.92 43.03,96.12 43.03,97.46 44.9,99.33 44.9,101.97 43.94,102.93 43.94,106.8 44.62,107.48 44.62,113.26 48.9,117.54 50.93,117.54 53.19,119.8 69.4,119.8 71.09,118.11 85.06,118.11 85.7,117.48 86.11,117.48 86.24,117.61 86.24,117.83 86.36,117.96 86.57,117.96 86.7,117.83 86.7,117.61 86.83,117.48 87.04,117.48 87.16,117.61 87.16,117.81 87.29,117.93 87.5,117.93 87.63,117.81 87.63,117.61 87.76,117.48 88.72,117.48 88.84,117.6 88.84,118.74 88.96,118.85 89.2,118.85 89.32,118.74 89.32,117.56 89.43,117.45 90.63,117.45 90.75,117.56 90.75,118.74 90.87,118.85 91.11,118.85 91.23,118.74 91.23,117.66 91.35,117.54 91.5,117.54 92.21,118.25 v2(92.67,118.25)
  BOTTOM w0.076: 94.18,117.26 95.4,116.04 95.4,115.12 96.24,114.29 96.24,113.6 96.2,113.56 96.2,112.67 96.41,112.46 96.41,112.22 96.11,111.93 UC1.D64
  BOTTOM w0.112: 94.18,117.26 94.17,117.27
  BOTTOM w0.127: RC157.1 v2(92.67,118.25) 92.67,117.99 93.07,117.59 93.85,117.59 94.17,117.27 ; PR605.2 42.46,95.6 v2(42.1,95.96)
VIDSOUT_B: length 2.5
  TOP w0.127: PR626.2 43.94,94.72 44.09,94.59 44.74,94.39 45.01,94.37 PU602.35
VRALERT#: length 22.5
  TOP w0.127: v2(125.64,96.64) 125.64,96.26 126.26,95.65 126.78,95.65 v1(127.02,95.41) 127.11,95.32 127.72,95.32 128.22,94.83 128.69,94.83 128.99,95.13 129.49,95.13 129.75,94.87 129.75,94.18 137.03,86.9 138.6,86.9 139.52,85.99 140.85,85.99 141.57,85.27 RC73.1
  BOTTOM w0.102: v2(125.64,96.64) 126.06,97.05 UC1.AM11
VSA_SEN+: length 128.2
  TOP w0.127: v2(116.55,114.23) 116.57,114.21 116.84,114.21 116.97,114.34 116.97,118.51 117.22,118.77 117.22,120.1 RC168.2
  TOP w0.203: v2(51.88,101.37) 51.74,101.24 PC650.1 51.71,100.47 PC652.1
  IN4 w0.084: v2(51.88,101.37) 52.11,101.61 52.11,102.15 48.96,105.3 48.96,107.15 46.75,109.36 46.75,115.81 49.21,118.26 51.79,118.26 53.3,119.78 65.33,119.78 66.17,118.93 68.15,118.93 68.99,118.09 69.35,118.09 69.51,118.25 69.51,118.38 v2(69.34,118.55) ; v2(121.09,108.91) 120.65,108.47 119.82,108.47 119.63,108.67 118.06,108.67 117.59,109.14 117.59,109.88 117.99,110.29 117.99,111.72 117.06,112.66 116.74,112.66 116.46,112.94 116.46,113.39 116.55,113.48 v2(116.55,114.23)
  BOTTOM w0.127: v2(116.55,114.23) 116.3,113.99 115.98,113.99 115.4,114.56 114.57,114.56 110.96,118.17 110.96,121.45 108.22,124.18 101.81,124.18 101.4,123.77 93.89,123.77 93.67,123.56 91.79,123.56 91.57,123.77 88.92,123.77 88.16,123.01 88.16,122.51 87.61,121.96 87.21,121.96 86.81,122.36 86.81,124.69 84.34,127.16 82.85,127.16 82.23,127.77 80.54,127.77 79.88,127.11 79.88,125.09 78.32,123.53 73.25,123.53 72.46,122.74 71.86,122.74 69.54,120.42 69.54,118.75 v2(69.34,118.55)
  BOTTOM w0.254: v2(51.88,101.37) 52.53,100.72 52.53,100.54 PC640.2 PR649.2 ; UC1.H20 121.36,108.64 v2(121.09,108.91)
VSA_SEN-: length 130.8
  TOP w0.127: v2(116.97,113.55) 116.97,113.98 117.22,114.23 117.22,118.41 117.47,118.66 117.47,120.18 RC166.1
  TOP w0.203: v2(52.57,101.39) 52.26,101.09 52.26,99.86 51.99,99.59 PC650.2 51.7,99.63 50.94,99.63 PC649.1 50.06,98.76 48.45,98.76 47.93,98.25 PU602.26
  IN4 w0.084: v2(52.57,101.39) 52.38,101.59 52.38,102.27 49.22,105.43 49.22,107.26 47.02,109.47 47.02,115.7 49.32,118 51.89,118 53.41,119.52 65.22,119.52 66.07,118.67 68.04,118.67 68.88,117.83 69.46,117.83 69.77,118.14 69.77,118.35 v2(69.96,118.54) ; v2(120.1,108.92) 118.17,108.92 117.84,109.25 117.84,109.77 118.25,110.18 118.25,111.83 117.16,112.91 116.84,112.91 116.71,113.04 116.71,113.28 116.97,113.54 v2(116.97,113.55)
  BOTTOM w0.127: v2(116.97,113.55) 116.78,113.73 115.87,113.73 115.3,114.31 114.46,114.31 110.7,118.07 110.7,121.34 108.12,123.93 101.91,123.93 101.51,123.52 93.99,123.52 93.78,123.3 91.68,123.3 91.46,123.52 89.03,123.52 88.41,122.9 88.41,122.41 87.71,121.71 87.1,121.71 86.56,122.26 86.56,124.58 84.24,126.9 82.74,126.9 82.13,127.52 80.65,127.52 80.13,127.01 80.13,124.98 78.42,123.27 73.35,123.27 72.57,122.49 71.97,122.49 69.79,120.31 69.79,118.71 v2(69.96,118.54)
  BOTTOM w0.254: v2(120.1,108.92) 120.38,108.64 UC1.H21
VSET_5105: length 6.9
  TOP w0.127: v2(245.29,93.2) 244.86,93.2 CE38.1 RE77.1 ; UE1.C9 v2(247.88,90.66)
  IN2 w0.122: v2(245.29,93.2) 245.83,92.66 247.28,92.66 247.48,92.45 247.48,91.06 v2(247.88,90.66)
WIGIG_32KHZ: length 4.2
  TOP w0.127: v1(239.91,69.02) 239,68.12 v2(239,67.89) RZ56.1
  BOTTOM w0.127: JNGFF1.50 239.51,68.4 v2(239,67.89)
WLAN_COEX1: length 23.4
  TOP w0.127: v2(242.81,75.5) 243.13,75.82 v1(243.13,76)
  BOTTOM w0.127: RZ130.2 234.83,83.89 235.47,83.26 236.99,83.26 237.67,82.58 237.67,81.16 239.26,79.56 239.26,78.98 239.82,78.42 242.29,78.42 242.94,77.77 242.94,75.63 v2(242.81,75.5) 243.05,75.26 243.05,74.05 243.65,73.44 243.65,72.89 243.47,72.72 243.47,71.54 242.52,70.59 242.52,69.76 241.65,68.9 JNGFF1.48
WLAN_COEX2: length 23.7
  TOP w0.127: v2(242.29,75.81) 241.32,75.81 v1(240.83,76.3)
  BOTTOM w0.127: JNGFF1.46 241.72,69.4 242.22,69.9 242.22,70.75 243.23,71.76 243.23,72.81 243.41,72.99 243.41,73.33 242.14,74.6 242.14,75.66 v2(242.29,75.81) 242.12,75.98 242.12,77.23 241.44,77.92 239.92,77.92 238.97,78.87 238.97,79.53 237.43,81.06 237.43,82.38 236.81,83 235.02,83 234.17,83.84 RZ129.2
WLAN_COEX3: length 22.3
  TOP w0.127: v2(236.97,82.2) 236.64,81.87 235.9,81.87 v1(235.84,81.93)
  BOTTOM w0.127: RZ128.2 233.51,83.84 234.58,82.77 236.55,82.77 236.97,82.35 v2(236.97,82.2) 237.12,82.05 237.12,81.02 238.67,79.47 238.67,78.8 239.79,77.68 241.32,77.68 241.89,77.11 241.89,74.41 242.57,73.73 242.57,72.52 241.9,71.84 241.9,70.13 241.67,69.9 JNGFF1.44
WLAN_PWR_EN: length 16.9
  TOP w0.127: v2(253.35,115.09) 253.73,114.71 v1(253.73,114.64) 253.73,114.06 254.97,112.83 254.97,112.18 253.59,110.8 UZ2.3
  BOTTOM w0.127: DZ9.1 250.81,120.88 250.02,120.09 RZ71.2 250.02,120 RZ38.1 250.85,119.06 RZ70.2 253.35,116.54 v2(253.35,115.09)
WLAN_WIGIG60GHZ_DIS#: length 49.7
  TOP w0.127: DZ1.1 243.94,65.69 v2(244.84,66.59) ; UE1.L13 254.68,93.99 255.5,94.8 255.5,96.2 v2(255.93,96.63) 256.49,96.07 RE8.1
  IN2 w0.122: v2(244.79,92.76) 244.79,93.97 246.26,95.44 247.18,95.44 247.56,95.06 249.32,95.06 249.63,95.37 250.81,95.37 251.87,96.42 255.72,96.42 v2(255.93,96.63)
  BOTTOM w0.127: v2(244.84,66.59) 244.84,68.2 244.67,68.38 244.67,69.75 246.14,71.23 246.14,73.19 246.96,74 246.96,75.05 245.78,76.22 245.78,77.33 246.46,78.01 246.46,78.51 245.74,79.23 245.74,79.86 243.6,82.01 243.6,85.4 243.49,85.5 243.49,85.81 243.75,86.06 243.75,87.1 244.63,87.99 244.63,90.74 244.58,90.79 244.58,92.55 v2(244.79,92.76)
WLAN_WIGIG60GHZ_DIS#_R: length 3.1
  TOP w0.127: v1(241.29,66.84) 241.61,66.51 v2(242.05,66.51) 242.05,65.83 DZ1.2
  BOTTOM w0.127: v2(242.05,66.51) 241.66,66.9 JNGFF1.56
WWAN_COEX1: length 14.6
  BOTTOM w0.127: JNGFF2.56 236.88,96 235.44,94.56 235.44,94.05 234.34,92.95 234.34,90.72 233.67,90.05 233.67,85.63 234.19,85.11 234.68,85.11 234.83,84.96 RZ130.1
WWAN_COEX2: length 14.6
  BOTTOM w0.127: JNGFF2.54 237,96.5 235.22,94.72 235.22,94.15 234.01,92.95 234.01,90.87 233.44,90.29 233.44,85.51 234.17,84.78 RZ129.1
WWAN_COEX3: length 15
  BOTTOM w0.127: RZ128.1 233.51,85.09 233.2,85.4 233.2,90.56 233.72,91.08 233.72,92.98 234.99,94.24 234.99,94.98 237.01,97 JNGFF2.52
WWAN_PWR_EN: length 4.5
  TOP w0.127: v1(240.36,112.76) CZ198.1 RZ43.1 239.5,111.06 v2(239.55,111.01)
  BOTTOM w0.127: JNGFF2.6 239.04,110.5 v2(239.55,111.01)
WWAN_RADIO_DIS#: length 28.4
  TOP w0.127: v2(250.3,94.09) 250.3,93.05 250.68,92.67 UE1.F12 ; v1(242.07,109.03) 241.39,109.03 DZ5.1 240.93,109.98 v2(241.26,110.31) ; v2(246.16,98.44) 245.95,98.44 RE10.1
  IN4 w0.084: v2(241.26,110.31) 244.78,110.31 246.57,108.52 246.57,102.87 246.14,102.44 246.14,100.14 245.52,99.52 245.52,99.08 v2(246.16,98.44)
  BOTTOM w0.127: v2(246.16,98.44) 246.81,98.44 248.82,96.43 248.82,95.67 250.3,94.19 v2(250.3,94.09)
WWAN_RADIO_DIS#_R: length 3.5
  TOP w0.127: DZ5.2 239.43,110.2 v2(239.55,110.31) 239.99,110.75 v1(240.21,110.75)
  BOTTOM w0.127: v2(239.55,110.31) 239.24,110 JNGFF2.8
WWAN_WAKE#: length 47.2
  TOP w0.127: RE38.1 256.97,95.53 v2(256.97,95.41) 256.46,94.91 256.46,94.58 255.48,93.6 UE1.M13
  IN2 w0.122: v2(260.81,100.44) 260.59,100.65 260.59,102.09 258.37,104.31 255.94,104.31 255.46,104.8 244.54,104.8 239.9,109.44 237.62,109.44 236.04,107.86 v2(236.04,107.76)
  IN4 w0.084: v2(256.97,95.41) 256.97,97.67 259.09,99.79 260.16,99.79 v2(260.81,100.44)
  BOTTOM w0.127: JNGFF2.15 231.09,106.25 232.7,107.86 235.94,107.86 v2(236.04,107.76)
XCLK_BIASREF: length 16.9
  TOP w0.127: v2(118.69,106.26) 118.69,105.5 119.23,104.96 RC52.1 ; RC324.1 108.32,110.07 v2(109.12,110.87) 108.94,111.05 v1(108.94,111.34)
  IN1 w0.084: v2(109.12,110.87) 109.65,111.4 113.51,111.4 114.12,110.78 114.12,109.27 115.19,108.19 115.19,107.75 115.97,106.97 117.98,106.97 v2(118.69,106.26)
  BOTTOM w0.076: v2(109.12,110.87) 108.85,110.59 UC1.E42
XDP_DBRESET#: length 85.5
  TOP w0.127: v2(125.02,134.5) 125.4,134.88 131.67,134.88 136.96,129.59 138.91,129.59 139.7,128.79 139.7,127.77 140.52,126.96 v1(144.04,126.96) 146.17,124.83 148.16,124.83 152.62,120.37 152.62,118.58 152.01,117.97 152.01,115.18 v2(152.17,115.01) ; CC32.1 89.38,131.1 89.38,131.76 v2(89.43,131.8) 88.17,133.05 RC137.1
  BOTTOM w0.127: UC12.1 151.77,116.61 152.17,116.21 v2(152.17,115.01) 152.17,114.67 RC290.1 ; v2(125.02,134.5) 124.43,135.09 119.65,135.09 117.28,132.72 107.2,132.72 105.86,134.05 89.54,134.05 89.41,133.93 JXDP1.48 89.43,132.69 v2(89.43,131.8)
XDP_JTAGX: length 8.2
  BOTTOM w0.076: 98.07,117.14 98.25,116.96 98.25,115.99 98.99,115.24 98.99,113.47 UC1.A59
  BOTTOM w0.127: RC87.1 CC305.1 97.18,119.44 97.51,119.11 RC328.2 97.51,118.44 v1(97.97,117.98) 98.07,117.88 98.07,117.14
XDP_OBS0: length 1.9
  BOTTOM w0.127: RC239.2 97.51,128.31 JXDP1.21
XDP_OBS0_R: length 23.6
  IN1 w0.084: v2(97.24,126.23) 99.41,124.06 99.85,124.06 99.92,124 99.92,123.82 99.78,123.67 99.78,123.49 99.93,123.34 100.11,123.34 100.25,123.49 100.43,123.49 100.51,123.41 v2(100.51,122.63)
  BOTTOM w0.076: UC1.C55 101.07,112.76 100.94,112.89 100.94,114.72 100.82,114.83 100.82,116.1 100.89,116.16 100.89,116.76 100.67,116.98 100.67,120.09
  BOTTOM w0.127: v2(97.24,126.23) 97.24,125.96 97.45,125.75 99.67,125.75 100.23,126.32 100.23,126.54 100.08,126.69 99.79,126.69 99.59,126.49 97.87,126.49 RC239.1 ; v2(100.51,122.63) 100.51,120.73 100.67,120.57 100.67,120.09
XDP_OBS1: length 3
  BOTTOM w0.127: v1(95.34,128.04) RC240.2 96.91,128.6 JXDP1.23
XDP_OBS1_R: length 24
  IN1 w0.084: v2(96.35,126.23) 96.49,126.23 99.97,122.75 99.97,122.29 100.43,121.83 101.33,121.83 v2(101.61,122.1)
  BOTTOM w0.076: 101.15,120.09 101.15,119.64 100.93,119.42 100.93,117.02 101.05,116.89 101.05,116.09 100.99,116.03 100.99,114.9 101.1,114.79 101.1,113.61 101.34,113.38 101.34,112.51 101.39,112.46 101.39,112.23 101.07,111.92 UC1.D55
  BOTTOM w0.127: RC240.1 94.13,127.13 93.98,126.97 93.98,126.43 94.17,126.23 v2(96.35,126.23) ; 101.15,120.09 v1(101.15,121.64) v2(101.61,122.1)
XDP_OBS2_R: length 3.1
  BOTTOM w0.076: T10.1 101.65,115.05 101.92,114.78 101.92,112.95 UC1.B54
XDP_OBS3_R: length 4.4
  BOTTOM w0.076: UC1.C56 100.51,112.24 100.77,112.51 100.77,114.65 100.61,114.81 T11.1
XDP_PRSNT_PIN1: length 8.6
  IN2 w0.122: v2(100.69,127.13) 100.91,126.9 103.43,126.9 v2(103.75,127.22)
  BOTTOM w0.127: JXDP1.1 103.51,127.67 103.75,127.43 v2(103.75,127.22) ; RC122.1 RC121.1 v2(100.69,127.13)
XDP_TMS: length 16.6
  TOP w0.127: v2(86.41,131.8) 85.33,130.72 85.33,128.16 84.81,127.64 83.07,127.64 v1(82.5,127.06) 81.68,126.25 v2(81.05,126.25)
  BOTTOM w0.127: RC228.1 77.94,122.38 78.55,122.38 79.38,123.2 80.03,123.2 80.3,123.47 UC8.9 80.3,124.22 81.02,124.94 81.02,126.22 v2(81.05,126.25) ; JXDP1.58 v2(86.41,131.8)
XTAL24_IN_U22: length 3.8
  BOTTOM w0.127: RC419.2 RC46.2 115.24,118.17 CC21.1 114.37,119.16 114.37,119.68 YC1.3
XTAL24_IN_U22_CPU: length 9.9
  TOP w0.127: v2(112.86,110.29) 113.08,110.29 113.34,110.55 113.34,111.53 113.8,112 v4(113.8,112.67) 113.8,113.84 114.93,114.96 114.93,115.94 v2(115.14,116.15)
  BOTTOM w0.127: v2(115.14,116.15) 115.14,116.42 RC419.1 ; v2(112.86,110.29) 112.82,110.25 111.73,110.25 111.47,110.51 UC1.E37
XTAL24_IN_U42: length 4.5
  BOTTOM w0.127: YC3.3 132.76,120.95 132.59,120.79 132.59,120.26 132.92,119.94 CC334.1 RC417.2 RC415.2
XTAL24_IN_U42_CPU: length 11.5
  TOP w0.127: v2(133.64,118.02) 133.69,118.02 v1(134.17,118.5)
  IN2 w0.122: v2(130.62,111.13) 130.04,111.71 130.04,112.07 130.35,112.38 130.35,112.38 130.48,112.51 130.78,112.51 130.88,112.61 130.88,112.87 130.75,113.01 130.48,113.01 130.35,113.14 130.35,114.73 v2(133.64,118.02)
  BOTTOM w0.076: v2(130.62,111.13) 130.71,111.04 UC1.E3
  BOTTOM w0.127: RC417.1 133.83,118.21 v2(133.64,118.02)
XTAL24_OUT_U22: length 5.5
  BOTTOM w0.127: YC1.1 113.94,120.94 113.94,119.59 CC22.1 113.45,118.13 RC420.2 RC46.1
XTAL24_OUT_U22_CPU: length 9.5
  TOP w0.127: v2(112.86,110.88) 112.86,111.39 113.57,112.1 113.57,113.93 114.7,115.06 114.7,116.01 v2(114.55,116.15)
  BOTTOM w0.127: v2(114.55,116.15) 114.51,116.15 RC420.1 ; UC1.E35 112.57,110.59 v2(112.86,110.88)
XTAL24_OUT_U42: length 5.8
  BOTTOM w0.127: YC3.1 132.3,121.74 132.3,120.27 CC335.1 130.78,118.76 RC415.1 RC418.2
XTAL24_OUT_U42_CPU: length 9.5
  TOP w0.127: v2(132.58,117.9) v1(131.96,117.9)
  IN2 w0.122: v2(132.58,117.9) 132.58,117.27 130.11,114.8 130.11,112.55 v2(129.43,111.87)
  BOTTOM w0.076: v2(129.43,111.87) 129.29,112.01 UC1.C7
  BOTTOM w0.127: RC418.1 132.55,117.87 v2(132.58,117.9)
XTAL_25_IN: length 5.8
  BOTTOM w0.076: UT1.D22 24,94.72 23.8,94.53 23.8,94.07 23.49,93.76
  BOTTOM w0.127: 23.49,93.76 22.67,93.76 20.77,91.86 20.46,91.86 RT394.1
XTAL_25_IN_R: length 3
  BOTTOM w0.127: YT1.1 19.92,90.13 CT21.1 19.84,90.43 19.3,90.97 19.26,91.01 19.26,91.01 19.01,91.26 RT394.2
XTAL_25_OUT: length 4.4
  BOTTOM w0.127: RT40.1 21.68,92.45 22.74,93.51 23.56,93.51 24.03,93.98 UT1.D23
XTAL_25_OUT_R: length 4.7
  BOTTOM w0.127: RT40.2 CT20.1 20.07,89.73 20.07,88.48 YT1.3
XTALI: length 6.3
  TOP w0.127: UL1.10 247.68,122.3 248.63,121.35 248.98,121.35 v1(249.08,121.25) 249.21,121.12 RL11.2 248.32,119.45 CL14.1 248.3,118.74 YL1.1
XTALO: length 3.9
  TOP w0.127: RL34.2 RL11.1 248.3,121.11 247.75,121.65 v1(247.75,121.73) 247.75,121.8 247.28,122.27 UL1.9
XTALO_R: length 5
  TOP w0.127: YL1.3 247.78,117.41 247.78,119.11 CL13.1 247.36,119.45 246.81,120 246.52,120.29 RL34.1
Z2805: length 3.5
  TOP w0.127: v2(261.26,118.2) 260.5,118.2 v1(260.12,118.58)
  TOP w0.508: v2(261.26,118.2) RL18.1
  BOTTOM w0.508: TL1.22 v2(261.26,118.2)
Z2806: length 3
  TOP w0.127: v2(268.88,118.2) 268.88,117.69 v1(268.68,117.49)
  TOP w0.508: v2(268.88,118.2) RL16.1
  BOTTOM w0.508: TL1.16 v2(268.88,118.2)
Z2807: length 3.6
  TOP w0.127: v2(262.53,118.18) 263.33,118.18 v1(263.7,118.55)
  TOP w0.508: RL17.1 v2(262.53,118.18)
  BOTTOM w0.508: TL1.21 v2(262.53,118.18)
Z2808: length 3.1
  TOP w0.127: v1(270.43,117.47) 270.15,117.75 v2(270.15,118.18)
  TOP w0.508: RL15.1 v2(270.15,118.18)
  BOTTOM w0.508: TL1.15 v2(270.15,118.18)
N04748: length 5.7
  TOP w0.203: v2(59.84,56.3) 59.25,56.3 59.12,56.44 PU901.3
  BOTTOM w0.127: v1(62.57,57.48) 62,56.91 60.85,56.91 PR929.1
  BOTTOM w0.254: PC939.1 59.37,57.03 59.84,56.56 v2(59.84,56.3) 60.02,56.48 60.3,56.48 PR929.1
N16399089: length 8.9
  BOTTOM w0.127: PD901.1 48.91,57.09 49.25,56.75 49.25,55.42 v1(49.46,55.21)
  BOTTOM w0.508: PR916.2 51.52,59.32 51.43,59.32 51.37,59.26 PD903.1 ; PD903.1 48.63,58.97 48.63,57.83 PD901.1 ; PD903.1 PD904.1
N16400770: length 40.9
  TOP w0.203: v2(43.62,80.66) 43.78,80.82 43.78,81.47 44.78,82.47 45.85,82.47 46,82.62 PR901.3
  IN4 w0.203: v2(49.95,60.72) 50.4,60.27 50.4,59.9 50.14,59.64 43.57,59.64 39.35,63.86 39.35,70.69 38.8,71.25 38.8,74.73 43.74,79.67 43.74,80.54 v2(43.62,80.66)
  BOTTOM w0.254: v2(49.95,60.72) 51.22,61.99 52.6,61.99 52.63,62.01 PR910.1
N16404606: length 3.2
  BOTTOM w0.127: PR950.1 45.58,59.52 v1(46.13,58.97)
  BOTTOM w0.254: PD905.3 43.17,59.52 PR939.2 PR950.1
N16775301: length 4
  TOP w0.127: v2(65.49,70.88) 65.87,71.26 v1(65.87,71.41)
  TOP w0.254: PR206.1 PR204.2 PC208.2 65.43,70.81 v2(65.49,70.88)
  BOTTOM w0.254: v2(65.49,70.88) 65.62,70.88 65.84,70.66 PU200.16
N16775385: length 8.7
  TOP w0.127: v1(69.24,66.75) 69.11,66.88 69.11,70.89 70.14,71.91 v2(70.64,71.91)
  TOP w0.254: PC218.1 70.67,71.94 v2(70.64,71.91)
  BOTTOM w0.254: v2(70.64,71.91) 69.99,71.26 69.79,71.26 69.64,71.11 PU200.3
N16775517: length 2.5
  BOTTOM w0.127: v1(62.52,69.63) 63.12,69.04 64.03,69.04 64.25,68.82 64.25,68.4
N16776853: length 3.6
  TOP w0.127: PC207.1 64.93,67.9 v1(65.27,67.57)
  TOP w0.254: v2(65.17,69.79) 64.93,69.55 PC207.1
  BOTTOM w0.254: v2(65.17,69.79) 65.2,69.76 PU200.14
N16783014:
  vias: v1(156.56,77.52) v2(155.95,77.48) v2(155.95,76.9)
N16783095: length 1.9
  BOTTOM w0.127: v1(155.69,80.54) 155.59,80.43 PR108.1
  BOTTOM w0.254: PC113.2 154.95,79.57 PR108.1
N16783134: length 2
  BOTTOM w0.127: PR117.1 v1(185.75,60.91)
  BOTTOM w0.254: PC127.2 PR117.1
N16783223: length 3.4
  TOP w0.127: v1(188.11,59.2) 186.84,57.93 v2(186.84,57.1)
  TOP w0.508: v2(186.84,57.1) 186.71,57.22 PC119.1
N16784595: length 2.9
  BOTTOM w0.127: PR100.2 v1(156.33,68.21)
N16784799: length 1.5
  BOTTOM w0.127: v1(188.81,50.14) 188.07,50.87 PC114.1
N17185092: length 3.8
  BOTTOM w0.127: PR1214.2 41.38,102.87 v1(42.23,102.02)
  BOTTOM w0.254: PR1214.2 PR1218.2 40.93,104.4 40.91,104.4 40.59,104.72 PQ1204.6
N17188126: length 2.2
  TOP w0.127: v2(38.29,62.6) v1(38.86,62.6)
  TOP w0.254: PR1211.2 38.25,62.56 v2(38.29,62.6)
  BOTTOM w0.254: PU1200.1 v2(38.29,62.6)
N17188417: length 2.4
  BOTTOM w0.254: PU1200.2 37.02,61.95 36.79,62.18 36.79,63.65 PR1215.2
N17275961: length 4.8
  TOP w0.127: PU602.39 44.88,92.77 44.28,92.17 43.9,92.17 43.51,92.55 PR612.2 43.05,92.22 PR614.2 42.81,91.69 42.51,91.39 v1(42.01,91.39)
N17275988: length 2
  TOP w0.203: PR616.2 43.95,91.7 44.26,91.7 44.93,92.37 PU602.40
N17335638: length 4.7
  TOP w0.127: PU503.3 147.92,59.31 147.29,59.94 PR515.2 PC515.2 146.06,59.93 PR516.1 144.83,59.07 v1(144.79,59.11)
N17340170: length 3.9
  BOTTOM w0.254: PQ1205.1 v1(38.78,63.7) 37.76,63.7 PR1215.1 PR1226.2
N17370862: length 4.6
  TOP w0.508: v2(46.02,110.87) v1(47.14,111.99) 48.51,113.36 PQ5.1
  BOTTOM w0.508: v2(46.02,110.87) 46.02,110.88 PC4.2
N17370885: length 2.8
  TOP w0.508: PQ5.2 51.59,112.77 51.93,113.12 PR15.1 PR10.2
N17370921: length 2.4
  TOP w0.127: PR15.2 52.35,111.71 v1(52.79,111.26)
  TOP w0.254: PR15.2 52.62,112.48 PQ1.6
N17370927: length 2.5
  BOTTOM w0.127: v1(44.42,112.84) 44.03,112.44 PQ7.1
  BOTTOM w0.254: PR16.2 44.03,111.09 PQ7.1
N17370961: length 9.5
  TOP w0.254: PR3.1 42.1,120.39 38.29,120.39 v1(38.17,120.52) 37.23,121.45 PQ2.1 37.23,122.76 PL3.1 37.17,124.26 PR6.2
N17370983: length 8.6
  TOP w0.254: PQ2.3 37.06,121.04 38.11,119.99 v1(39.42,119.99) 42.02,119.99 PR3.2 PR5.1
N17370995: length 3.2
  TOP w0.127: v1(35.55,127.56) 36.11,127 PQ3.2
  TOP w0.254: PQ3.2 37.1,126.56 PR8.2 PR6.1
N17370999: length 5.5
  TOP w0.127: PR7.2 32.9,124.81 v1(32.27,124.81)
  TOP w0.254: PQ2.2 35.46,123.28 PQ3.1 34.82,125.3 PR7.2
N17371043: length 2.4
  BOTTOM w0.127: v1(49.2,119.53) 49.68,120.01 PQ6.1
  BOTTOM w0.254: PQ6.1 49.68,121.18 PR18.2
N17371184: length 2.7
  BOTTOM w0.254: PU1.4 54.51,119.88 v1(53.91,119.28) 53.88,119.26 53.17,119.26 PR23.1
N17371207: length 3.5
  BOTTOM w0.127: PR22.1 59.88,121.58 v1(59.88,121.64)
  BOTTOM w0.254: PQ8.1 59.33,119.76 59.21,119.64 PR27.1 PR22.1
N17372066: length 3.6
  TOP w0.127: PR19.2 57.42,115.36 v1(57.42,115.86)
  TOP w0.254: PR19.2 56.97,114.91 PR17.2 56.11,114.18 55.71,113.78 PQ1.3
N17372074: length 5.7
  TOP w0.127: PR25.1 54.33,115.42 54.73,115.81 54.73,116.68 v1(54.45,116.96)
  TOP w0.254: PR25.1 54.33,114.64 54.04,114.36 53.2,114.36 52.92,114.07 52.92,113.24 53.03,113.13 PQ1.5
N17372833: length 6.2
  TOP w0.127: PR1201.2 40.03,52.41 v1(39.8,52.41)
  TOP w0.203: PC1206.1 40.58,54.74 v2(40.28,54.74) ; PC1206.1 40.98,55.14 PR1203.1 ; PC1206.1 PR1219.1 PR1201.2
  BOTTOM w0.203: PU1201.3 v2(40.28,54.74)
N17479322: length 10.9
  TOP w0.254: PR1252.1 50.13,101.75 v1(51.05,101.75) 51.43,102.12 v2(51.57,102.12) 52.29,102.12 PR1251.2
  BOTTOM w0.254: v2(51.57,102.12) 51.12,102.58 45.92,102.58 44.37,101.02 PQ1215.2
N17494434: length 11.6
  TOP w0.127: v1(35.58,53.35) PR1239.2
  TOP w0.203: PR1238.1 35.44,54.62 v2(35.84,54.62) 35.96,54.62 36.47,55.13 PC1211.1 PR1246.1 PR1239.2
  BOTTOM w0.254: PU1201.5 36.37,54.09 v2(35.84,54.62) 35.51,54.62 PD1205.1 34.69,54.25 34.15,54.79 34.15,56.51 PR1255.2 33.7,56.96 PQ1212.1
N17509431: length 7.6
  TOP w0.203: PU901.29 56.72,54.12 v1(56.96,53.88)
  TOP w0.254: v1(56.96,53.88) 56.96,53.34 56.6,52.98 v2(56.6,51.45) 56.6,50.76 PR935.1
  BOTTOM w0.254: v2(56.6,51.45) 56.59,51.46 PR947.1 56.59,53.19 57.01,53.6 PC947.1
N17509921: length 2.4
  BOTTOM w0.127: PD905.2 42.59,60.24 v1(42.59,60.44)
  BOTTOM w0.254: PR941.2 41.74,59.4 PD905.2
N17509924: length 7.6
  TOP w0.127: v2(43.52,57.92) v1(42.98,57.92)
  IN1 w0.254: v2(46.25,56.14) 44.47,57.92 v2(43.52,57.92)
  BOTTOM w0.254: v2(46.25,56.14) 46.25,56.14 PU903.1 46.48,55.4 47.1,56.01 PR961.1 ; v2(43.52,57.92) 42.82,57.92 PD905.1
N17522701: length 2.2
  BOTTOM w0.127: PR942.2 47.79,55.1 47.98,54.91 v1(48.22,54.91)
  BOTTOM w0.254: PR942.2 47.12,55.1 46.76,54.75 PU903.2
N17670003: length 4.2
  TOP w0.203: PR936.1 57.62,53.11 v2(57.62,53.67) 57.62,53.96 57.12,54.46 PU901.30
  BOTTOM w0.127: v1(58.46,52.09) 58.46,52.18 PR948.1
  BOTTOM w0.254: v2(57.62,53.67) 57.62,53.05 PR948.1
N17739728: length 4.2
  BOTTOM w0.127: PR1224.1 39.27,60.13 v1(38,60.13)
  BOTTOM w0.254: PQ1205.3 40.08,61.31 39.79,61.02 PR1224.1 PR1221.2
N17747591: length 3.4
  TOP w0.127: v2(61.06,118.19) v1(61.06,117.57)
  TOP w0.254: v2(61.06,118.19) PR26.2 PR28.1
  BOTTOM w0.254: v2(61.06,118.19) 61.81,118.93 PQ8.3
N17765266: length 3.8
  TOP w0.203: PR933.2 v2(54.82,53.68) 54.82,53.8 55.52,54.49 PU901.26
  BOTTOM w0.127: v2(54.82,53.68) 54.42,53.68 53.82,53.08 PR951.2
N17768164: length 3.6
  BOTTOM w0.127: PQ1210.5 51.4,51.13 51.78,51.51 51.78,52.21 51.98,52.41 PR1245.2 51.98,53.67 v1(52.12,53.81)
N17769037: length 5.6
  TOP w0.127: v1(46.86,49.95) v2(46.86,50.48) 46.46,50.48 46.19,50.75 PR1230.1
  BOTTOM w0.127: PQ1211.4 v2(46.86,50.48) ; v2(46.86,50.48) PQ1207.6 ; v2(46.86,50.48) 46.86,52.43 PR1258.2
N17769560: length 3.5
  TOP w0.127: PR1233.1 PR1242.2 48.28,50.86 v2(48.28,50.49) v1(48.28,49.95)
  BOTTOM w0.127: v2(48.28,50.49) 48.28,50.87 48.03,51.13 PQ1211.5
N17769738: length 4.4
  BOTTOM w0.127: v1(48.84,53.77) 48.84,53.57 48.3,53.03 PR1257.2 PR1235.1 49.93,52 49.93,51.32 49.74,51.13 PQ1211.2
N17770477: length 4.1
  TOP w0.127: v1(45.53,50.04) v2(45.53,50.71) 45.24,51 44.91,51 PR1232.1
  BOTTOM w0.127: PQ1207.2 44.63,51.13 44.75,51.26 ; PQ1207.3 44.62,51.78 44.75,51.65 44.75,51.26 ; 44.75,51.26 44.88,51.13 45.11,51.13 v2(45.53,50.71)
N17771093: length 3.4
  BOTTOM w0.127: PQ1207.5 45.58,51.13 45.11,51.6 45.11,52.03 44.88,52.26 44.3,52.26 43.83,52.73 PR1241.2
N17771333: length 12.1
  TOP w0.127: PR1234.1 PR1261.2 42.88,50.48 v2(42.27,50.48) 42.27,50.1 v1(42.01,49.84)
  IN2 w0.122: v2(42.27,50.48) 42.82,49.92 48.44,49.92 48.74,50.23 v2(48.74,51.78)
  BOTTOM w0.127: PQ1211.1 v2(48.74,51.78) ; PQ1208.6 v2(42.27,50.48)
N17771663: length 3.1
  BOTTOM w0.127: v1(40.61,52.84) PR1259.1 41.54,51.94 41.38,51.78 PQ1208.3 PQ1208.2
N17772624: length 4
  TOP w0.127: v1(43.05,52.44) 42.95,52.33 PR1261.1 42.62,51.13 v2(42.25,51.13) PR1260.2 PR1244.2
  BOTTOM w0.127: PQ1208.5 v2(42.25,51.13)
N17801240: length 4.5
  TOP w0.127: v1(30.65,122.44) PR1229.1
  TOP w0.254: PR1229.1 29.69,121.92 30.06,121.55 PQ1206.4 31.07,121 PC1210.1 PR1228.2
N17802718: length 2.5
  TOP w0.127: PR1212.1 44.32,102.3 v1(43.93,102.69)
  BOTTOM w0.254: v2(47.71,101.99) 47.43,101.71 PQ1215.1
N17804163: length 9.4
  TOP w0.254: PR1207.2 48.21,107.85 PR1213.1 48.22,107.33 48.29,107.26 48.29,106.16 48.16,106.03 v2(47.14,106.03) ; PR1207.2 PC1203.2 ; PR1207.2 49.03,108.71 49.47,109.15 PQ1202.4
  BOTTOM w0.254: v2(47.14,106.03) 46.18,106.03 45.53,105.38 44.78,105.38 PQ1203.1
N17890941: length 3
  BOTTOM w0.127: v1(34.38,61.63) 34.71,61.3 PU1200.4
  BOTTOM w0.254: PR1216.2 36.37,60.87 35.94,61.3 PU1200.4
N17892124: length 3.3
  TOP w0.254: PR1252.2 48.36,101.93 v1(48.05,101.62) 47.97,101.53 46.96,101.53 46.32,100.9 PQ1214.6
N18265642: length 64.7
  TOP w0.127: v2(34.83,60.74) v3(35.71,60.74)
  TOP w0.254: PR1262.1 46.35,108.95 46.35,108.27 45.82,107.74 45.82,107.25 46.13,106.94 PQ1201.2 46.82,106.94 v2(47.14,106.63)
  IN2 w0.122: v2(34.83,60.74) 36.42,62.33 36.42,65.67 34.54,67.55 34.54,75.02 35.39,75.87 35.39,77.59 36.75,78.95 37.67,78.95 38.08,79.36 38.08,81.32 37.25,82.15 37.25,87.29 37.25,87.29 37.25,88.72 36.64,89.33 36.64,92.11 36.91,92.39 36.91,100.59 37.54,101.21 37.54,105.56 38.42,106.44 v2(38.5,106.44)
  BOTTOM w0.127: v2(38.5,106.44) 41.81,106.44 42.07,106.17 45.78,106.17 46.23,106.63 v2(47.14,106.63)
  BOTTOM w0.254: v2(34.83,60.74) 34.92,60.74 PR1216.1
N18265900: length 1.9
  TOP w0.127: v1(43.6,105.95) PR1220.2
  TOP w0.254: PR1220.2 PQ1201.5
N18266224: length 8.2
  TOP w0.203: PC1213.1 v2(35.83,56.7) ; PC1213.1 PR1238.2 ; PC1213.1 PR1240.2 PR1243.1
  BOTTOM w0.127: v1(35.52,57.96) 35.14,57.58 PD1205.2
  BOTTOM w0.203: PU1201.7 36.47,55.39 35.84,56.02 35.46,56.02 35.14,56.34 PD1205.2 35.77,56.65 v2(35.83,56.7)
N18266545: length 103
  TOP w0.127: PQ1209.5 28.04,124.22 PC1214.1 27.07,124.2 v2(26.64,124.64)
  TOP w0.203: v2(33.37,58.85) 33.36,58.84 PR1243.2
  IN2 w0.122: v2(33.37,58.85) 33.65,58.85 36.67,61.87 36.67,65.77 34.79,67.65 34.79,74.92 35.62,75.75 35.62,77.5 36.84,78.72 37.76,78.72 38.32,79.28 38.32,86.35 37.6,87.07 37.6,88.69 36.86,89.43 36.86,91.89 37.14,92.17 37.14,100.27 38.28,101.41 38.75,101.41 39.19,101.85 39.19,107.2 38.74,107.64 38.74,109.81 36.08,112.47 32.23,112.47 30.86,113.84 30.86,119.05 36.08,124.27 v2(39.5,124.27)
  BOTTOM w0.127: v2(39.5,124.27) 38.57,124.27 35.88,126.96 26.7,126.96 26.53,126.79 26.53,124.75 v2(26.64,124.64)
N18267253: length 8.1
  TOP w0.203: PR1248.1 v2(32.41,55.95) PR1250.1 32.42,55.32 PR1249.1
  BOTTOM w0.127: PQ1212.2 33.05,61.02 v1(32.85,61.22)
  BOTTOM w0.254: PQ1212.2 32.12,59.09 32.12,56.25 v2(32.41,55.95)
N18268286: length 4
  BOTTOM w0.127: v1(42.52,61.8) PQ1205.2
  BOTTOM w0.254: PR1225.1 39.06,62.62 40.29,62.62 41.12,61.8 PQ1205.2
N18277029: length 4
  TOP w0.254: PR404.2 140.53,128.9 141.07,128.36 141.07,128.33 141.26,128.14 PR425.2 141.26,128.01 v2(141.88,127.39)
  BOTTOM w0.127: v1(141.35,126.74) 141.88,127.26 v2(141.88,127.39)
  BOTTOM w0.254: PU401.14 v2(141.88,127.39)
N18277134: length 12.9
  TOP w0.127: v2(163.14,124.41) 163.26,124.54 163.26,127.96 PR426.2 PR410.2
  BOTTOM w0.127: v2(163.14,124.41) 162.73,124.01 161.22,124.01 161.02,124.21 158.36,124.21 v1(157.75,124.81) PU402.14
N18278782: length 1.1
  TOP w0.127: PC930.1 v1(58.25,63.71)
N18278920: length 3.3
  TOP w0.127: PR920.2 51.84,57.11 52.12,57.11 52.47,56.76 53.83,56.76 53.9,56.84 PU901.21
N18278998: length 3.3
  TOP w0.127: PU901.22 53.9,56.44 53.83,56.51 v4(52.97,56.51) 52.36,56.51 52.01,56.86 51.74,56.86 PR922.2
N18288083: length 1.1
  BOTTOM w0.254: PR946.1 43.27,54.1 PU903.4
N18288371: length 1.7
  BOTTOM w0.254: PR1218.1 42.29,104.15 41.91,104.53 41.69,104.53 41.24,104.99 PQ1204.5
N18288510: length 2
  BOTTOM w0.127: v1(40.23,108.19) 40.99,108.19 PR1223.1
  BOTTOM w0.254: PQ1204.2 41.24,107.95 PR1223.1
N18290420: length 3.6
  BOTTOM w0.127: v1(156.03,133.13) 156.03,132.54 156.37,132.19 PR423.1
  BOTTOM w0.254: PR423.1 PR424.1 156.37,130.81 156.75,130.43 PU402.5
N18325201: length 2.4
  TOP w0.254: CL16.1 v2(261.11,130.38)
  BOTTOM w0.254: v2(261.11,130.38) 261.11,130.02 261.26,129.87 TL1.3
N18325205: length 3.7
  TOP w0.127: v2(262.34,130.38) 262.34,130.49 262.01,130.82 v1(262.01,131.49)
  TOP w0.254: CL17.1 262.32,130.35 v2(262.34,130.38)
  BOTTOM w0.254: TL1.4 262.53,130.19 v2(262.34,130.38)
N18325209: length 3
  TOP w0.127: v2(268.88,127.46) 268.83,127.4 v1(268.21,127.4)
  TOP w0.254: v2(268.88,127.46) CL20.1
  BOTTOM w0.254: TL1.9 v2(268.88,127.46)
N18325213: length 3
  TOP w0.127: v2(270.15,127.46) 269.95,127.25 v1(269.62,127.25)
  TOP w0.254: v2(270.15,127.46) CL21.1
  BOTTOM w0.254: TL1.10 v2(270.15,127.46)
N18490882: length 2.4
  TOP w0.127: v1(279.83,77.46) 279.67,77.29 RI14.2 279.65,76.52 UI3.16
N18548164: length 3.1
  TOP w0.127: v1(57.95,114.47) 57.49,114.01 PR19.1
  TOP w0.254: PQ1.2 55.56,113.13 56.44,114.01 PR19.1
N18557857: length 1.2
  BOTTOM w0.254: PU1.1 57.09,121.42 PR21.2
N18557860: length 1.1
  BOTTOM w0.254: PU1.2 PR22.2
N18557997: length 3.5
  BOTTOM w0.127: PR23.2 v1(53.86,120.61)
  BOTTOM w0.254: PQ6.2 52.09,120.61 PR23.2 52.98,120.86 PR30.1
N18558082: length 2.2
  BOTTOM w0.127: PR20.1 42.97,110.06 v1(43.03,110.12)
  BOTTOM w0.254: PR20.1 42.07,111.17 PQ7.2
N18559343: length 1.3
  BOTTOM w0.254: PR29.1 61.81,121.74 v2(61.81,121.13) PQ8.2
N18617445: length 3.5
  TOP w0.127: v1(153.5,77.67) 153.63,77.8 153.63,78.32 154.13,78.81 PC307.2
  TOP w0.254: PC307.2 154.55,79.8 154.69,79.8 155.19,80.3 PR308.1
N18762046: length 0.9
  TOP w0.127: RA17.2 CA33.1
N18762152: length 1.4
  TOP w0.127: UZ5.10 248.59,63.43 CZ127.1
N18762172: length 1.4
  TOP w0.127: CZ126.1 248.51,64.23 UZ5.12
N18762349: length 4
  TOP w0.203: CA51.1 253.44,55.01 RA44.1 254.47,55.27 255.93,56.73 UA1.27
N18762353: length 4.1
  TOP w0.203: CA53.1 257.13,66.82 257.13,64.58 v1(257.12,64.58) 257.13,64.57 UA1.7
N18762355: length 3.3
  TOP w0.152: CA52.1 263.19,58.08 261.77,58.08 v1(261.67,58.18) 261.59,58.18 260.83,58.94 UA1.39
N18762401: length 6.5
  TOP w0.127: RA53.1 250.1,57.31 v1(249.91,57.12)
  TOP w0.203: RA53.1 RA54.1 250.23,59.19 252.88,59.19 253.42,59.74 UA1.20
N18762411: length 5.3
  TOP w0.127: v1(261.9,53.67) CA29.1 261.2,55.45 261.2,55.7 260.5,56.4 259.61,56.4 259.13,56.89 UA1.35
N18762416: length 3.2
  TOP w0.127: CA29.2 261.2,56.14 260.84,56.5 260.84,58.01 260.72,58.14 UA1.37
N18762426: length 2.7
  TOP w0.127: UA1.28 256.33,56.72 256.12,56.51 256.12,56.3 v1(255.94,56.11) 255.36,55.54 CA35.1
N18762428: length 2.8
  TOP w0.127: UA1.34 258.73,56.9 259.48,56.14 260.06,56.14 260.31,55.89 CA49.1
N18762438: length 1.9
  TOP w0.203: CA25.1 253,59.89 253.24,60.14 UA1.19
N18988038: length 2.4
  BOTTOM w0.127: v1(62.52,86.68) PR681.2
  BOTTOM w0.254: PU612.17 60.82,87.4 61.54,86.68 PR681.2
N18988103: length 3.5
  TOP w0.127: PR661.1 v3(66.7,91.7)
  TOP w0.254: PR661.1 v2(65.8,90.12)
  BOTTOM w0.254: PL612.3 v2(65.8,90.12)
N18988180: length 1.3
  BOTTOM w0.127: PR665.1 v1(58.16,84.03)
N18988214: length 21.3
  TOP w0.127: v1(55.14,98.96) 54.68,98.96 v2(54.53,99.11)
  TOP w0.254: PR662.2 54.53,99.94 v2(54.53,99.11)
  IN1 w0.254: v2(54.53,99.11) 55.15,99.11 56.31,97.95 56.31,95.87 57.11,95.07 60.29,95.07 61.17,94.18 61.17,91.16 60.01,89.99 60.01,87.64 59.19,86.82 v2(59.19,85.96)
  BOTTOM w0.254: PU612.2 v2(59.19,85.96)
N18988216: length 23.3
  TOP w0.127: v2(54.79,101.57) 54.48,101.88 v1(54.19,101.88)
  TOP w0.254: v2(54.79,101.57) 54.45,101.24 PR664.2
  IN1 w0.254: v2(59.87,85.97) 59.87,87 60.37,87.5 60.37,89.8 61.56,90.99 61.56,94.37 60.48,95.45 57.36,95.45 56.67,96.15 56.67,98.1 55.03,99.74 55.03,101.33 v2(54.79,101.57)
  BOTTOM w0.254: v2(59.87,85.97) 59.69,86.15 PU612.1
N18989066: length 4.2
  BOTTOM w0.127: v1(53.81,94.18) 53.71,94.28 PR692.2
  BOTTOM w0.254: PU613.1 56.07,95.82 55.94,95.69 54.11,95.69 PR692.2
N18989073: length 2.1
  TOP w0.127: v2(55.73,96.25) 55.47,96 v1(55.47,95.78)
  TOP w0.254: v2(55.73,96.25) 55.76,96.29 PR671.2
  BOTTOM w0.254: PU613.2 55.8,96.32 v2(55.73,96.25)
N18989156: length 2
  BOTTOM w0.127: PC671.2 54.37,101.1 v1(54.37,101.86)
N18989160: length 1.6
  BOTTOM w0.127: v1(53.11,101.48) 53.29,101.48 53.83,100.94 PC671.1
N18989202: length 1.6
  BOTTOM w0.254: PU613.17 57.19,94.77 56.59,94.17 PR689.2
N18989973: length 4.3
  BOTTOM w0.254: PU610.1 59.64,105.68 59.98,105.33 v1(61.46,105.33) 62.71,104.09 PR687.2
N18989995: length 1.1
  TOP w0.508: PR663.1 56.96,112.64 v2(56.34,112.02)
  vias: v1(57.99,111.98)
N18989999: length 4.1
  BOTTOM w0.254: PU610.2 59.14,105.62 59.78,104.98 61.14,104.98 61.88,104.24 PR659.2
N18990122: length 2.6
  TOP w0.254: v2(61.12,106.86) 60.91,106.86 60.26,106.21 PR686.2
  BOTTOM w0.127: v2(61.12,106.86) 61.44,106.86 v1(61.64,106.65)
  BOTTOM w0.305: PU610.17 61.06,106.8 v2(61.12,106.86)
N20151644: length 38.3
  TOP w0.203: v2(44.23,80.64) 44.08,80.78 44.08,81.35 44.83,82.09 45.83,82.09 46,81.93 PR901.2
  IN4 w0.203: v2(49.95,60.08) 49.84,59.97 43.72,59.97 39.7,64 39.7,70.78 39.1,71.38 39.1,74.6 44.12,79.62 44.12,80.53 v2(44.23,80.64)
  BOTTOM w0.254: PR909.1 52.59,60.81 52.4,61 v3(50.93,61) 50.01,60.08 v2(49.95,60.08)
N27076067: length 2.5
  BOTTOM w0.127: PC944.1 54.75,51.77 54.7,51.72 54.7,51.25 v1(55.22,50.73)
  BOTTOM w0.254: PC944.1 PR934.2
N27077001: length 121.5
  TOP w0.254: v2(171.45,49.57) 171.55,49.67 171.55,51.78 171.3,52.03 PR917.2
  IN2 w0.254: v2(62.66,53.76) 62.99,53.43 64.64,53.43 65.53,54.32 68.44,54.32 70.36,52.4 70.36,51.34 71.75,49.95 139.07,49.95 142.55,52.67 146.84,52.67 148.63,54.46 157.99,54.46 162.45,50 164.05,50 164.58,49.46 171.02,49.46 171.12,49.57 v2(171.45,49.57)
  BOTTOM w0.254: 63.14,56.21 63.4,55.95 63.4,54.39 62.77,53.76 v2(62.66,53.76)
N28424999: length 7.5
  BOTTOM w0.076: UC1.AW71 91.67,92.33 90.82,92.33 90.38,91.9 90.38,91.6 90.03,91.25 90.03,90.88
  BOTTOM w0.127: T113.1 88.12,87.77 88.73,88.38 88.73,88.8 90.03,90.09 90.03,90.88
N28425002: length 9.8
  BOTTOM w0.076: UC1.AW70 92.21,92.17 90.91,92.17 90.6,91.86 90.6,91.48 90.3,91.17
  BOTTOM w0.127: T114.1 86.37,87.4 88.14,87.4 88.97,88.24 88.97,88.71 90.3,90.03 90.3,91.17
N28489601: length 8.6
  BOTTOM w0.127: v1(224.9,81.29) 226.54,81.29 RC222.1 227.4,81.53 228.94,81.53 230.11,82.71 230.11,83.7 230.11,84 230.01,84.16 SW1.2
N28769860: length 3.4
  BOTTOM w0.127: PR422.1 v1(140.44,134.59)
  BOTTOM w0.254: PU401.5 140.88,131.7 140.44,132.14 PR421.2 PR422.1
N28810563: length 1.6
  TOP w0.127: CZ110.1 249.44,111.77 249.61,111.6 UZ2.10
N28811129: length 1.3
  TOP w0.127: CZ114.1 155.34,60.74 UZ3.10
N28856399: length 9.5
  BOTTOM w0.076: 90.23,89.3 91.25,90.32 92.4,90.32 92.58,90.5 92.58,91.15 UC1.BA70
  BOTTOM w0.127: T16.1 86.38,86.88 88.43,86.88 89.47,87.92 89.47,88.54 90.23,89.3
N28856402: length 11.6
  BOTTOM w0.076: UC1.BA68 92.73,91.65 92.22,91.65 92.05,91.48 91.48,91.48 91.4,91.4 90.89,91.4 90.51,91.02
  BOTTOM w0.127: 90.51,91.02 90.51,89.9 89.23,88.62 89.23,88.1 88.26,87.13 85.37,87.13 T17.1
N28857231: length 11.4
  BOTTOM w0.076: UC1.BB68 93.33,90.69 92.63,89.99 91.55,89.99 91.13,89.56
  BOTTOM w0.127: T12.1 85.11,86.12 88.56,86.12 89.98,87.54 89.98,88.42 91.13,89.56
N28857234: length 7.9
  BOTTOM w0.076: 90.43,89.18 91.4,90.15 92.56,90.15 92.9,90.49 UC1.BB69
  BOTTOM w0.127: T13.1 88.47,86.5 89.71,87.74 89.71,88.47 90.43,89.18
N28857237: length 1.2
  TOP w0.127: v2(125.52,98.44) 125.52,98.52 125.18,98.85 T14.1
  BOTTOM w0.102: v2(125.52,98.44) 125.52,98.38 UC1.AK13
N28857240: length 1.2
  TOP w0.127: T15.1 126.67,98.46 126.15,98.46 v2(126.13,98.44)
  BOTTOM w0.102: UC1.AK12 125.78,98.1 126.12,98.44 v2(126.13,98.44)
N28861827: length 9.3
  BOTTOM w0.076: UC1.C64 96.11,112.52 96.02,112.61 96.02,114.2 95.2,115.02 95.2,115.96 93.92,117.24 92.68,117.24
  BOTTOM w0.127: 92.68,117.24 92.25,117.24 91.78,117.71 v1(91.78,117.96) RC120.1
N28938912: length 2.1
  TOP w0.127: v1(159.1,92.52) CC8.1 156.99,92.52 RC29.2
N28938914: length 1.3
  TOP w0.127: CC7.1 156.76,103.09 156.36,102.69 RC28.2
N29708559: length 7.8
  BOTTOM w0.076: UC1.AY4 130.83,91.5 130.83,91.18 131,91 132.09,91 132.52,90.57
  BOTTOM w0.102: 132.52,90.57 135.14,90.57 135.23,90.66
  BOTTOM w0.127: T126.1 136.88,89.99 136.2,90.66 135.23,90.66
N29708561: length 4.6
  BOTTOM w0.127: T127.1 135.44,90.35 131.64,90.35 UC1.BB3
N29708639: length 6.4
  BOTTOM w0.127: UC1.BB5 130.76,89.81 133.87,89.81 134.9,88.78 135.36,88.78 T130.1
N31877076: length 3.2
  TOP w0.127: LV1.1 62.52,130.8 v2(62.39,130.92)
  BOTTOM w0.127: JEDP1.21 61.25,132.07 v2(62.39,130.92)
N32590572: length 1.4
  TOP w0.127: CZ117.1 275.87,90.54 UZ4.12
N32592963: length 1.4
  TOP w0.127: CZ118.1 275.81,91.34 UZ4.10
N32594166: length 1.6
  TOP w0.127: CZ109.1 248.78,110.8 UZ2.12
N32817808: length 1.3
  TOP w0.127: CZ113.1 155.34,59.94 UZ3.12
N32818355: length 3.7
  TOP w0.127: v1(160.56,59.05) 161,59.48 RZ65.2 RZ64.2 159.79,59.62 159.23,59.62 158.92,59.94 UZ3.3
N32819772: length 1.3
  TOP w0.127: UZ8.6 209.08,51.39 209.13,51.33 CZ121.1
N33612393: length 2
  TOP w0.127: RD18.1 v1(116.1,54.38)
  TOP w0.508: CD31.2 RD18.1
N35551576: length 2.8
  TOP w0.127: v1(29.92,125.99) PR1236.1
  TOP w0.254: PR1236.1 30.95,125.98 PQ1209.3 PQ1209.2
N35551581: length 3.2
  TOP w0.127: v1(27.17,123.4) 27.33,123.57 PQ1209.6
  TOP w0.254: PR1229.2 28.78,122.97 29.05,123.24 PQ1209.6
N35551592: length 5.8
  TOP w0.127: PR1237.2 35.83,58.56 v1(35.71,58.56)
  TOP w0.203: PR1237.2 PC1212.1 PR1247.1 36.03,56.02 35.84,55.83 v2(35.84,55.26)
  BOTTOM w0.203: PU1201.6 36.42,54.74 35.9,55.26 v2(35.84,55.26)
N35551655: length 5.6
  TOP w0.127: v1(38.66,51.83) 39.66,52.83 PC1205.1
  TOP w0.203: v2(40.29,55.39) 39.92,55.39 PR1208.2 PR1217.1 PC1205.1
  BOTTOM w0.203: PU1201.2 v2(40.29,55.39)
N35551713: length 3.4
  TOP w0.254: PR1212.2 45.04,103.39 45.04,104.14 v1(44.54,104.63) PQ1201.6
N35551785: length 3.2
  BOTTOM w0.254: PQ1203.2 43.57,108.72 PR1202.2 43.25,109.05 42.18,109.05 PR1209.1
N35551806: length 1.1
  BOTTOM w0.254: PQ1204.3 41.89,107.84 PR1209.2
N35551822: length 2.3
  TOP w0.127: v1(47.84,106.69) 47.84,107.14 47.31,107.67 PR1213.2
  TOP w0.254: PR1213.2 46.96,107.83 46.72,107.59 PQ1201.3
N36307052: length 14.2
  BOTTOM w0.076: UT5.F10 31.27,83.22 31.27,84.23 30.84,84.66 30.84,84.97
  BOTTOM w0.127: 30.84,84.97 30.84,85.1 30.98,85.24 30.98,86.84 31.39,87.26 33.68,87.26 34.13,86.82 35.19,86.82 35.58,87.21 ; RT98.1 34.31,88.78 35.58,87.51 35.58,87.21 ; 35.58,87.21 36.78,86.01 RT99.2 RT97.2
N36307117: length 3.6
  TOP w0.127: v2(30.94,79.49) 30.14,78.69 29.7,78.69 v1(29.64,78.62) 28.87,77.85 RT85.1
  BOTTOM w0.076: UT5.G4 31.02,79.57 v2(30.94,79.49)
N36307119: length 5.6
  TOP w0.127: v2(31.52,79.49) 31.52,79.23 30.94,78.65 v1(30.94,78.6) 30.63,78.29 29.98,78.29 29.31,77.62 29.31,76.62 RT84.1
  BOTTOM w0.076: UT5.F4 v2(31.52,79.49)
N36307669: length 3
  BOTTOM w0.076: UT5.F1 31.72,78.27 31.72,77.52 31.8,77.44
  BOTTOM w0.127: RT63.1 32.13,76.12 32.13,76.24 31.87,76.5 31.87,77.38 31.8,77.44
N36307918: length 5.9
  BOTTOM w0.076: 27.36,84.88 27.71,84.54 27.71,84.35 28.83,83.22 29.27,83.22 UT5.K10
  BOTTOM w0.127: 27.36,84.88 27.07,85.18 27.07,86.18 27.06,86.18 26.95,86.29 26.95,86.31 26.38,86.88 26.34,86.92 26.34,86.92 26.08,87.17 RT105.1
N36307920: length 4.4
  BOTTOM w0.076: 26.95,84.44 27.07,84.31 27.07,84.24 28.59,82.73 29.27,82.73 UT5.K9
  BOTTOM w0.127: RT104.1 26.67,84.72 26.95,84.44
N36307926: length 4
  BOTTOM w0.076: UT5.L11 28.86,83.47 27.96,84.37 27.96,84.61 27.6,84.97
  BOTTOM w0.127: 27.6,84.97 27.3,85.27 27.3,86.51 RT103.1
N36626863: length 4.2
  TOP w0.127: v2(22.01,66.48) 22.63,66.48 22.98,66.13 v1(23.25,66.13)
  TOP w0.381: RT111.2 CT90.1 v2(22.01,66.48)
  BOTTOM w0.381: v2(22.01,66.48) 22.01,66.8 21.87,66.94 UT7.3
N36736352: length 0.9
  TOP w0.127: T220.1 27.04,77.54 RT85.2
N36736355: length 1
  TOP w0.127: T219.1 28.66,74.12 RT84.2
N36827741: length 5.1
  TOP w0.127: v1(141.16,66.74) 141.11,66.79 139.7,66.79 139.56,66.65 139.27,66.36 ; UZ34.4 139.14,67.23 139.27,67.1 139.27,66.36 ; 139.27,66.36 RZ120.2 138.14,66.3 UZ26.4
N38312012: length 1.4
  TOP w0.127: v2(30.05,81.21) 29.55,81.21 CT87.1
  BOTTOM w0.076: UT5.H7 30.26,81.21 v2(30.05,81.21)
N38327809: length 2.1
  TOP w0.127: v1(33.55,81) 33.18,80.63 v2(32.99,80.63) 32.27,80.63 RT101.1
  BOTTOM w0.076: v2(32.99,80.63) 32.86,80.63 UT5.D6
N38749366: length 4.4
  TOP w0.127: RV5.2 42.19,125.84 v1(42.9,126.55)
  TOP w0.254: QV2.1 41.55,124.21 41.55,124.86 RV5.2
N38749387: length 2.7
  TOP w0.127: RV6.1 50.25,120.81 RV400.1 49.23,121.54 QV7.1
N38749389: length 6.9
  TOP w0.127: RV400.2 49.82,122.45 QV8.2 49.02,124.88 49.54,124.88 50.43,125.77 50.43,126.76 CV635.1
N39469798: length 5.6
  TOP w0.254: v2(63.1,114.06) 63.48,114.43 63.48,115.69 62.75,116.41 v1(62.23,116.41) 61.32,116.41 PR679.1
  BOTTOM w0.254: PU614.7 v2(63.1,114.06)
N39469818: length 0.9
  BOTTOM w0.203: PR630.2 PC631.1
N39469863: length 4.1
  TOP w0.203: PU602.28 47.13,98.23 v2(47.1,98.26)
  BOTTOM w0.203: v2(47.1,98.26) 47.2,98.26 48.11,99.17 PC632.1 48.12,99.38 PR636.1
N39469972: length 3.5
  TOP w0.127: PU602.38 v1(44.51,93.17) 44.17,93.17 v2(44.01,93.32)
  BOTTOM w0.127: v2(44.01,93.32) 44.11,93.42 44.11,93.78 44.91,94.58 PR678.2
N39469996: length 3.1
  TOP w0.127: v1(58.76,116.34) 58.76,116.03 59.14,115.65 PC611.2
  TOP w0.254: v2(59.27,114.22) 59.14,114.36 PC611.2
  BOTTOM w0.254: PU614.2 59.44,114.06 v2(59.27,114.22)
N39470129: length 1
  BOTTOM w0.254: PR646.2 51.42,100.29 PC640.1
N39470145: length 2.5
  BOTTOM w0.127: v1(49.02,101.69) 49.13,101.69 PC601.1
  BOTTOM w0.203: PC601.1 49.93,101.58 49.93,100.35 PR652.2
N39470173: length 1.9
  BOTTOM w0.127: PC632.2 46.44,99.39 v1(46.27,99.21)
  BOTTOM w0.203: PC632.2 PR641.1
N39470189: length 2
  BOTTOM w0.127: PH604.1 v1(71.79,120.68)
  BOTTOM w0.254: PR642.2 PH604.1
N39470446: length 5.4
  TOP w0.203: PR602.1 43.26,96.86 v2(43.59,96.86) 43.74,96.71 43.74,96.2 43.88,96.06 43.88,95.3 44.33,94.85 v1(44.41,94.85) 44.49,94.77 PU602.34
  BOTTOM w0.203: v2(43.59,96.86) 42.99,96.86 PC603.1
N39470448: length 7.7
  TOP w0.203: PR603.1 43.69,97.48 44.08,97.09 44.08,96.29 44.2,96.17 44.2,95.59 v2(44.32,95.47) 44.62,95.17 PU602.33
  BOTTOM w0.203: PC604.1 43.28,97.8 44.05,97.03 v1(44.05,96.29) 44.05,95.74 v2(44.32,95.47)
N39470528: length 2
  TOP w0.203: PU602.32 45.06,95.57 44.63,96 v2(44.63,96.02)
  BOTTOM w0.203: PR608.1 45.06,95.57 44.63,96 v2(44.63,96.02)
N39470532: length 4.9
  TOP w0.203: PU602.31 45.27,95.97 45.09,96.15 45.09,97.73 v2(45.27,97.91)
  BOTTOM w0.127: v1(43.93,98.82) 44.36,98.82 v2(45.27,97.91)
  BOTTOM w0.203: v2(45.27,97.91) PR611.1
N40478997: length 2.8
  TOP w0.127: QV4.2 21.54,72.92 v1(20.93,72.31)
  TOP w0.254: QV4.2 21.54,73.48 RV18.2
N41228182: length 4
  TOP w0.127: v1(229.91,107.07) 230.34,107.07 231.05,106.36 RZ326.1 231.62,106.06 v2(231.74,106.17)
  BOTTOM w0.127: JNGFF2.17 231.06,105.75 231.48,106.17 v2(231.74,106.17)
N41307615: length 1.9
  BOTTOM w0.127: RZ334.1 CZ38.2 v1(279.5,58.51)
N44311288: length 3.3
  TOP w0.127: RE90.2 261.47,103.45 261.35,103.34 QE11.3 ; RE90.2 RE70.1 ; RE90.2 261.95,103.85 v1(262.52,104.42)
N44311298: length 2.7
  TOP w0.127: v1(263.92,103.66) 263.92,103.62 RE70.2 262.91,102.51 QE4.2
N44321726: length 11.9
  TOP w0.127: v1(248.03,76.76) 249.01,75.78 RE318.1 250.54,76.81 v2(250.54,77.71) ; v2(251.62,82.26) 251.86,82.5 251.86,84.28 UE1.G2
  IN4 w0.084: v2(251.62,82.26) 251.1,81.74 251.1,78.27 v2(250.54,77.71)
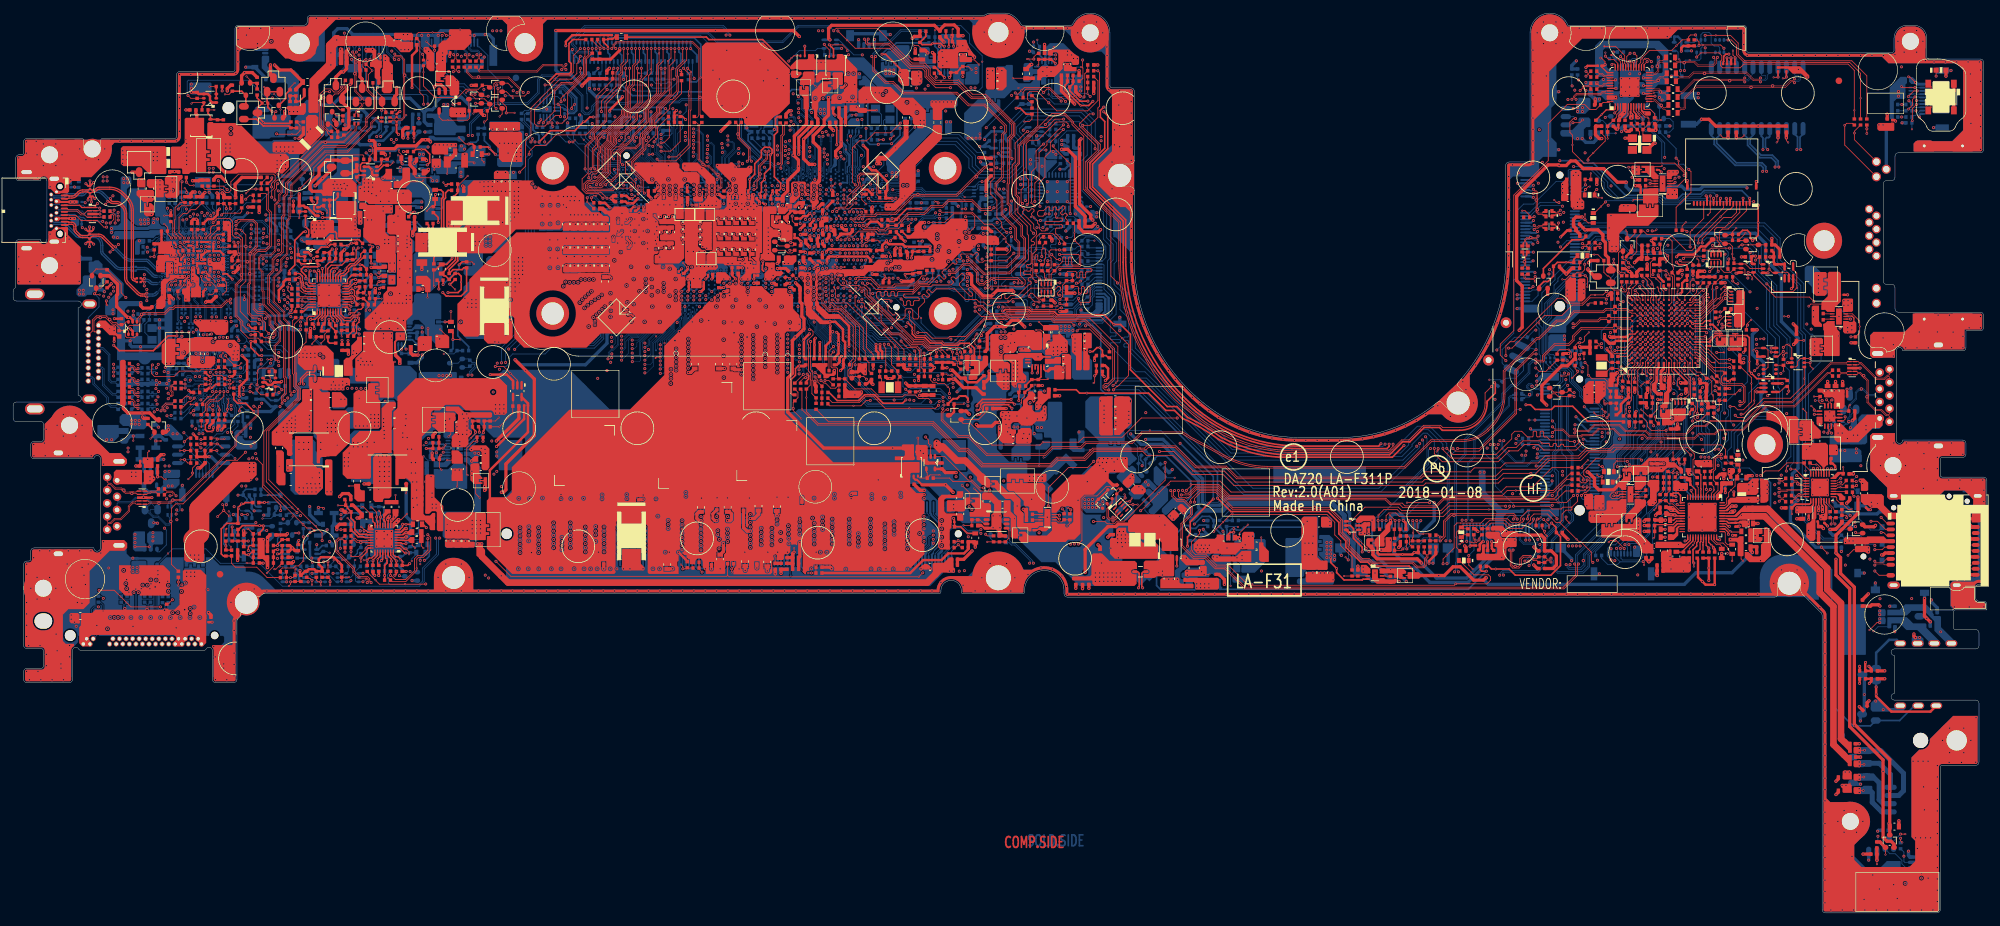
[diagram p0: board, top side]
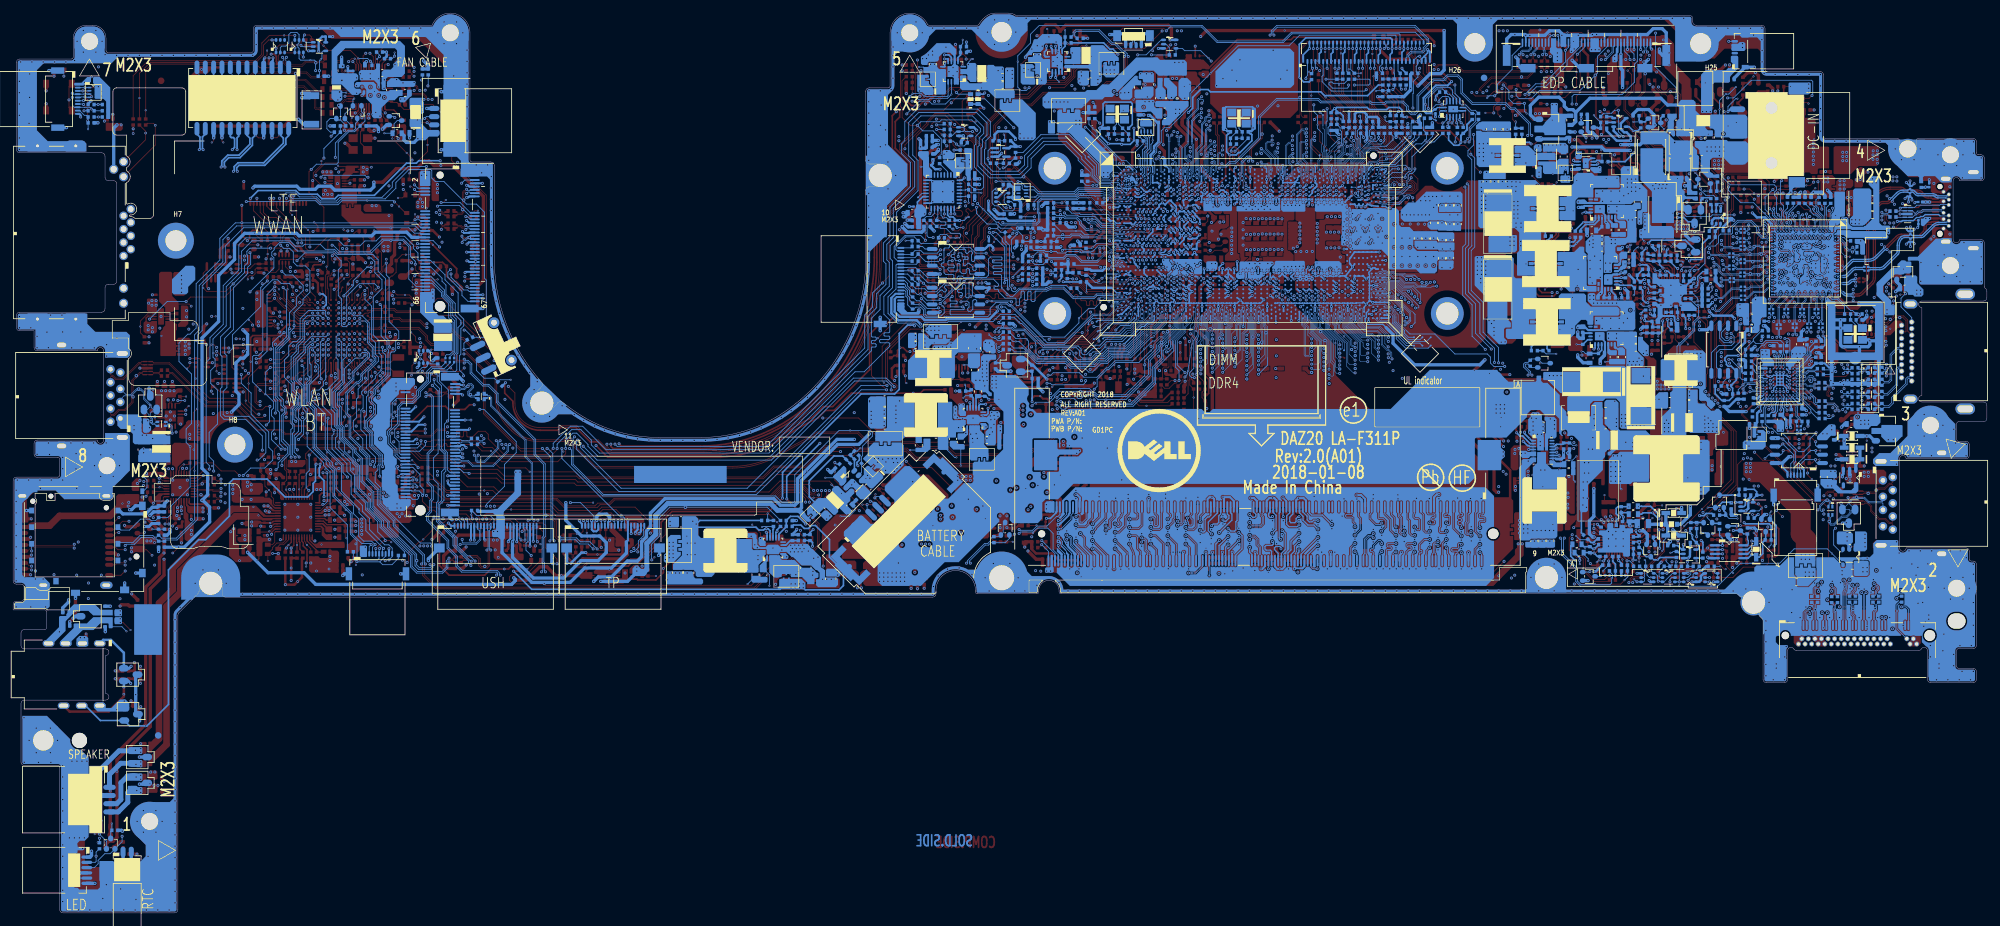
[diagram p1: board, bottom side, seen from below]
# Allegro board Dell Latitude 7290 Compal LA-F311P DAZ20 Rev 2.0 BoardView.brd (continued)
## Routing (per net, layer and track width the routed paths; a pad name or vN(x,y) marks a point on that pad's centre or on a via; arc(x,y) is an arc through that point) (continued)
N44321953: length 1.8
  TOP w0.127: v1(247.16,73.95) 247.1,74 CE57.1 RE350.2
N44725169: length 3.6
  TOP w0.127: UZ8.3 204.89,51.39 CZ197.1 RZ345.2 v1(202.78,51.37)
N44905504: length 2.3
  BOTTOM w0.127: T50.1 118.47,51.47 JDIMM1.162
N44907662: length 3
  TOP w0.127: T51.1 v2(119.85,59.64)
  BOTTOM w0.127: JDIMM1.165 119.23,61.07 119.85,60.45 v2(119.85,59.64)
N45108671: length 2
  TOP w0.127: T225.1 230.95,95.25 231.31,95.25 v2(231.56,95.5)
  BOTTOM w0.127: JNGFF2.59 231.31,95.25 v2(231.56,95.5)
N45160305: length 11.2
  TOP w0.127: v1(248.48,53.06) 248.48,53.42 v2(248.33,53.57)
  BOTTOM w0.127: JESPI.8 243.95,54.41 244.83,53.53 ; RE560.1 242,54.07 242.97,53.1 244.4,53.1 244.83,53.53 ; 244.83,53.53 248.3,53.53 v2(248.33,53.57) 248.87,54.1 RE375.1
N45555545: length 2.4
  BOTTOM w0.127: v1(285.66,13.64) RZ25.1 285.84,12.41 QZ3.1
N46398406: length 4.4
  TOP w0.127: v1(239.84,95.45) 239.84,96.84 v2(239.52,97.15) 239.46,97.22 RZ132.2
  BOTTOM w0.127: v2(239.52,97.15) 239.17,97.5 JNGFF2.50
N46646690: length 1.3
  BOTTOM w0.127: RZ63.1 160.04,104.68 CZ56.1
N46814682: length 16.2
  TOP w0.254: v2(45.88,89.09) 45.88,89.49 PR610.1
  IN2 w0.254: v2(55.83,94.48) 54.63,94.48 52.26,92.11 52.26,91.69 49.66,89.09 v2(45.88,89.09)
  BOTTOM w0.254: PH601.2 55.62,94.27 v2(55.83,94.48) ; PR631.2 45.9,90.74 v1(45.9,89.75) 45.9,89.11 v2(45.88,89.09)
N46814700: length 1.9
  TOP w0.127: v1(50.07,87.89) 49.99,87.98 49.99,88.8 PC627.1
  TOP w0.254: PR632.2 50.04,88.85 PC627.1
N46814728: length 12.8
  TOP w0.127: v2(66.51,95.88) v1(67.33,95.06)
  TOP w0.254: PR628.2 66.63,95.88 v2(66.51,95.88)
  IN2 w0.254: v2(66.51,95.88) 66.93,95.88 68.63,97.59 68.63,99.15 67.73,100.05 67.73,102.6 67.27,103.07 v2(67.27,103.98)
  BOTTOM w0.254: PH602.1 v2(67.27,103.98)
N46814746: length 3.2
  TOP w0.203: 50.06,89.74 50.04,89.74 PC627.2 50.03,90.3 49.13,91.2 PU602.8
  TOP w0.254: PR638.2 50.06,89.74
N46814769: length 2
  TOP w0.254: PR621.1 47.96,87.12 48.2,86.88 PC617.2
N46815156: length 3.1
  TOP w0.203: PR620.2 44.76,89.94 44.76,90.68 45.05,90.97 45.89,90.97 46.33,91.41 PU602.1
N46815164: length 2.2
  TOP w0.127: PC621.2 46.17,87.47 45.55,86.85 v1(45.55,86.69)
  TOP w0.254: PC621.2 PR623.1
N46815166: length 6.7
  TOP w0.127: v1(46.9,86.84) 47.47,87.41 47.47,88.26 PR621.2
  TOP w0.203: PU602.5 47.93,91.14 47.53,90.73 47.53,89.98 PR622.2
  TOP w0.254: PR622.2 47.04,89.49 47.04,89.29 46.99,89.24 PR623.2 47.96,88.75 PR621.2
N46815186: length 3.5
  TOP w0.203: v2(47.07,90.49) 47.07,90.71 47.53,91.17 PU602.4
  BOTTOM w0.203: PC616.2 47.13,92.22 PR617.2 47.07,91.52 v2(47.07,90.49)
N46815188: length 0.8
  BOTTOM w0.203: PC614.2 48.88,91.58 PR617.1
N46815204: length 2.2
  TOP w0.203: PR610.2 46.49,90.55 47.13,91.2 PU602.3
N46815214: length 3.7
  TOP w0.203: PU602.2 46.73,91.23 46,90.5 v2(45.33,90.5)
  BOTTOM w0.203: PR613.2 44.56,91.12 45.39,91.12 PC613.2 45.39,90.56 v2(45.33,90.5)
N46816449: length 1.9
  TOP w0.127: PC647.2 v1(56.15,93.66)
  TOP w0.254: PR650.2 55.17,92.89 PC647.2
N46816463: length 1.5
  BOTTOM w0.254: PR639.1 51.17,95.46 51.54,95.83 PC629.2
N46816511: length 4.5
  TOP w0.203: PR635.1 53.29,92.34 52.98,92.03 52.55,92.03 v1(52.25,91.74) 52.01,91.49 51.41,91.49 v2(51.28,91.36)
  BOTTOM w0.254: PR647.2 50.66,91.08 PH603.2 50.99,91.08 v2(51.28,91.36)
N46816791: length 3.2
  TOP w0.203: PU602.20 50.88,95.97 50.93,96.02 50.93,96.58 51.36,97.01
  TOP w0.254: 51.36,97.01 51.62,97.27 PC630.1 52.06,97.29 PR640.1
N46816817: length 0.9
  TOP w0.254: PC630.2 52.92,98.19 PR644.1
N46816821: length 3.1
  BOTTOM w0.127: v1(65.6,85.24) 67.14,85.24 67.62,85.72 PR657.2
  BOTTOM w0.254: PH605.1 PR657.2
N46816907: length 0.9
  TOP w0.254: PR645.1 PC639.2
N47939817: length 22.2
  TOP w0.127: RC436.2 101.82,124.95 100.03,123.16 100.03,122.62 v1(98.42,121.01) 97.92,120.51 97.92,118.66 96.4,117.14 96.4,116.47 94.43,114.5 94.43,113.29 95.99,111.73 95.99,109.94 v2(96.18,109.75)
  BOTTOM w0.127: v2(96.18,109.75) 95.78,109.35 UC1.G65 UC1.F65
N47967122: length 1.2
  TOP w0.127: RC437.2 103.44,107.94 v2(103.42,107.92)
  BOTTOM w0.254: UC1.K52 103.24,108.1 v2(103.42,107.92)
N47967641: length 2.9
  TOP w0.127: v2(102.76,98.46) 102.67,98.46 v1(102.05,99.09)
  TOP w0.381: RC438.1 102.76,98.11 v2(102.76,98.46)
  BOTTOM w0.254: UC1.AK52 103.17,97.99 102.76,98.4 v2(102.76,98.46)
N47969720: length 3.8
  TOP w0.127: v1(144.91,77.68) 144.81,77.58 RC433.2
  TOP w0.381: QC6.1 142.84,75.88 143.34,76.39 RC433.2
N47969722: length 10.6
  TOP w0.305: v2(145.46,77.95) 145.46,78.45 145.1,78.81 v1(144.22,78.81) 143.82,78.41 143.19,78.41 142.43,77.65 RC433.1
  BOTTOM w0.254: QC7.2 146.35,82.52 146.26,82.61 RC432.2 145.45,82.56 CC340.1 145.45,78.46 145.46,78.45 v2(145.46,77.95)
N47973654: length 3.2
  TOP w0.127: RE94.1 247.08,103.58 246.31,102.81 QE12.1 245.9,103.87 v1(245.7,104.06)
N47976312: length 2.4
  BOTTOM w0.127: v1(155.13,108.29) RZ62.1 155.56,109.3 155.64,109.22 UZ12.27
N48430893: length 14.2
  TOP w0.127: RE565.1 245.83,94.88 245.64,94.69 245.2,94.69 244.92,94.97 243.84,94.97 243.41,95.4 QE15.2 243.41,96.77 243.06,97.12 242.9,97.12 242.35,97.67 RE541.2 241.44,100.37 v1(240.87,100.37) 239.98,100.37 DE2.1 238.81,99.2 RE543.2 238.66,99.17 CE64.1
N48430899: length 9.7
  TOP w0.254: QE17.1 233.13,98.24 v1(236.77,101.88) 237.51,102.63 239.16,102.63 239.6,103.06 RE546.2
N48704005: length 3.5
  TOP w0.127: v1(71.77,114.43) 71.4,114.79 PR624.1
  TOP w0.254: v2(72.48,115.71) PR624.1
  BOTTOM w0.254: v2(72.48,115.71) 72.27,115.5 PL614.3
N49436611: length 5.3
  TOP w0.127: RZ380.2 56.78,122.39 56.2,122.97 QZ1.2 56.2,124.43 54.81,125.82 CZ200.1
N119328643: length 5
  TOP w0.203: PR931.2 53.94,53.77 v2(53.92,53.78) 54.25,54.11 54.63,54.11 55.12,54.6 PU901.25
  BOTTOM w0.127: v2(53.92,53.78) v1(53.41,53.78)
  BOTTOM w0.254: PR930.1 PC938.1 53.85,53.86 v2(53.92,53.78)
N132000604: length 1.3
  TOP w0.127: v1(62.51,55.64) 62.19,55.95 PC934.1
N132005053: length 122.7
  TOP w0.254: PR917.3 172.21,52.03 171.96,51.78 171.96,49.69 v2(172.08,49.57)
  IN2 w0.254: v2(172.08,49.57) 172.08,49.74 171.71,50.11 170.91,50.11 170.61,49.82 164.74,49.82 164.2,50.35 162.63,50.35 158.18,54.81 148.41,54.81 146.64,53.05 142.44,53.05 138.96,50.33 71.91,50.33 70.74,51.5 70.74,52.55 68.59,54.7 65.33,54.7 64.44,53.81 63.35,53.81 62.91,54.24 62.25,54.24 62.03,54.01 v2(62.03,53.76)
  BOTTOM w0.127: v2(62.03,53.76) v1(62.03,53.17)
  BOTTOM w0.254: PR938.2 62.03,54.14 v2(62.03,53.76)
N4977333418: length 2.2
  TOP w0.203: PR932.1 55.52,53.17 v1(55.52,53.88) 55.52,53.97 55.92,54.37 PU901.27

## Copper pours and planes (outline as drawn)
2.5VSP on TOP (solid shape): 147.99,62.49 148.7,62.49 148.99,62.19 148.99,61.42 148.83,61.25 148.83,60.48 148.73,60.38 145.84,60.38 145.73,60.49 145.73,61.07 145.83,61.18 145.87,61.18 146.17,61.13 146.4,61.33 146.49,61.43 146.49,61.77 146,62.26 146,62.26 146,62.55 146.56,62.55 146.56,63.08 146,63.08 146,63.31 147.17,63.31
3V_SN on BOTTOM (solid shape): 162.01,71.23 162.33,70.92 163.22,70.92 163.22,70.28 161.44,70.28 161,70.72 161,72.31 162.01,72.31
3V_VIN on TOP (solid shape): 155.19,73.66 155.19,71.8 154.91,71.52 152.95,71.52 152.77,71.7 152.77,72.94 153.06,73.22 153.06,73.66 153.11,73.71 153.35,73.71 153.57,73.94 154.91,73.94
3V_VIN on BOTTOM (solid shape): 153.7,74.34 153.79,74.36 154.98,74.36 155.03,74.31 155.03,69.26 154.73,68.97 153.81,68.97 153.8,68.97 153.8,69.51 153.79,69.52 153.25,69.52 153.24,69.51 153.24,68.98 153.23,68.97 153.01,68.97 153,68.98 153,69.5 152.99,69.51 152.46,69.51 152.45,69.5 152.45,68.98 152.44,68.97 152.12,68.97 152.09,69 152.09,70.75 152.1,70.75 152.74,71.38 152.74,72.94 153.43,73.63 153.43,74.29 153.49,74.36 153.59,74.36
5V_SN on TOP (solid shape): 190.46,56.02 191.29,55.19 191.29,53.54 190.08,53.54 189.83,53.8 189.83,56.46 190.46,56.46
5V_VIN on TOP (solid shape): 181.85,52.76 181.85,51.52 181.69,51.36 179.23,51.36 179.22,51.35 178.58,51.35 178.5,51.43 178.5,52.14 178.7,52.34 180.61,52.34 180.85,52.58 180.85,52.84 180.94,52.93 181.69,52.93
5V_VIN on BOTTOM (solid shape): 184.17,54.53 184.3,54.55 184.31,54.56 185.44,54.56 185.51,54.49 185.51,51.92 184.71,51.12 184.08,51.12 184,51.19 183.62,51.19 183.62,51.67 182.21,51.67 182.21,51.19 181.46,51.19 181.46,51.19 180.51,51.19 179.73,50.41 179.73,50.15 179.7,50.12 178.72,50.12 178.6,50.24 178.6,50.91 178.45,51.06 178.14,51.06 178,51.2 178,51.76 178.13,51.89 178.28,51.89 179.03,52.64 180.48,52.64 181.67,53.83 183.56,53.83 183.77,54.04 183.77,54.34 183.98,54.56 184.03,54.56
+0.6V_DDR_VTT on TOP (solid shape): 71.59,56.4 71.59,54.9 71.73,54.76 71.73,54.42 71.6,54.29 70.76,54.29 70.57,54.48 70.57,56.4 70.7,56.53 71.46,56.53
+0.6V_DDR_VTT on TOP (solid shape): 143.28,54.05 143.28,52.67 143.51,52.44 143.51,52 143.38,51.88 141.48,51.88 140.79,51.19 140.23,51.19 140,51.42 140,51.85 140.1,51.95 140.1,53.22 140.3,53.41 141.82,53.41 142.58,54.18 143.15,54.18
+0.6V_DDR_VTT on TOP (solid shape): 72.22,66.38 72.22,64.42 72,64.21 71.69,64.21 71.59,64.3 71.59,65.16 71.66,65.23 71.66,65.81 71.65,65.82 71.1,65.82 71.1,66 71.1,66 71.66,66 71.66,66.01 71.66,66.24 71.66,66.24 71.66,66.41 71.68,66.43 72.17,66.43
+0.6V_DDR_VTT on BOTTOM (solid shape): 142.64,54.54 142.64,52.84 142.8,52.69 143.33,52.69 143.48,52.54 143.48,51.98 143.38,51.88 142.31,51.88 142.17,52.02 142.17,52.69 142.31,52.84 142.31,54.54 142.37,54.6 142.59,54.6
+0.6V_DDR_VTT on IN4 (solid shape): 72.77,56.37 72.31,55.92 70.69,55.92 70.53,56.07 70.53,56.91 70.71,57.08 71.58,57.08 71.78,57.29 71.78,57.54 72.77,57.54
+0.6V_DDR_VTT on IN4: 72.53,65.34 71.33,65.34 70.99,65 70.99,62.17 71.31,61.85 72.41,61.85 73.03,62.47 73.03,64.84
+0.6VSP on TOP (solid shape): 71.04,68.41 71.04,66.82 71.45,66.41 71.5,66.41 71.51,66.41 71.51,66.15 71.5,66.15 71,66.15 71,66.16 70.95,66.16 70.94,66.15 70.94,65.68 70.95,65.67 71.5,65.67 71.51,65.66 71.51,65.43 71.49,65.41 70.22,65.41 69.66,65.98 69.66,68.32 69.84,68.51 69.86,68.51 69.97,68.52 70.07,68.56 70.89,68.56
+0.6VSP on BOTTOM (solid shape): 71.22,70.32 71.22,69.84 70.74,69.35 69.81,69.35 69.53,69.63 68.73,69.63 68.67,69.69 68.67,70.27 68.73,70.33 69.45,70.33 69.49,70.29 69.98,70.29 70.15,70.47 71.07,70.47
+0.6VSP on IN1: 71.11,70.45 69.63,70.45 69.34,70.16 69.34,66.85 69.69,66.5 70.75,66.5 71.55,67.3 71.55,70.02
+0.9V_LAN on TOP (solid shape): 244.4,124.57 244.4,124.06 244.34,124.01 242.8,124.01 242.77,124.04 242.77,124.6 242.82,124.65 244.32,124.65
+0.9V_LAN on TOP (solid shape): 248.18,123.43 248.18,122.48 248.42,122.24 249.36,122.24 249.51,122.09 249.51,121.66 249.4,121.55 248.71,121.55 248.69,121.55 247.98,122.27 247.98,123.43 248.03,123.48 248.13,123.48
+0.9V_LAN on TOP (solid shape): 246.99,123.43 246.99,122.26 247.09,122.16 247.09,122.14 247.45,121.78 247.45,121.68 247.48,121.65 247.55,121.53 247.67,121.46 247.88,121.26 247.88,121.14 247.72,120.99 247.27,120.99 247.09,121.17 247.09,121.8 246.76,122.13 246.76,123.43 246.81,123.48 246.94,123.48
+0.9V_LAN on BOTTOM (solid shape): 252.18,131.58 252.18,126.38 252.12,126.31 250.66,126.31 249.07,124.72 248.12,124.72 247.8,125.04 247.67,125.04 247.67,125.49 247.86,125.68 248.5,125.68 248.75,125.93 248.75,126.66 248.47,126.93 248.28,126.93 248.12,127.1 248.12,127.71 248.44,128.03 251.1,128.03 251.29,128.22 251.29,130.63 250.09,131.84 242.53,131.84 242.21,131.52 242.21,130 242.78,129.42 242.78,128.98 243.17,128.6 244.18,128.6 244.56,128.22 244.56,125.61 244.44,125.49 243.99,125.49 243.93,125.55 243.93,127.14 243.61,127.46 241.51,127.46 241.01,127.96 241.01,132.22 241.77,132.98 250.79,132.98
+0.9V_LAN on IN2: 247.55,120.98 247.36,121.17 247.36,122.12 245.64,123.84 243.43,123.84 243.04,124.23 243.04,127.33 242.28,128.09 242.28,129.44 242.42,129.58 242.97,129.58 243.1,129.45 243.1,129.02 243.27,128.85 247.74,128.85 248.63,127.96 248.63,127.26 247.86,126.5 247.86,126.34 247.81,126.25 247.71,126.25 247.21,125.81 247.87,125.79 247.95,125.85 248.04,125.82 248.88,124.98 248.88,121.36 248.5,120.98
+0.9V_TBT_CIO on BOTTOM (solid shape): 29.11,101.36 29.24,101.28 29.41,101.27 29.43,101.24 29.45,101.18 29.48,101.13 29.51,101.1 29.56,101.07 29.56,100.85 29.5,100.79 29.47,100.76 29.31,100.59 29.31,99.44 29.07,99.2 28.73,99.2 28.59,99.35 28.54,99.47 28.48,99.52 28.45,99.55 28.45,99.75 28.48,99.78 28.59,99.97 28.48,100.17 28.48,100.28 28.91,100.7 28.94,100.74 29.02,100.95 28.94,101.16 28.9,101.22 28.88,101.27 28.88,101.32 28.96,101.41 29.06,101.41
+0.9V_TBT_DP on TOP (solid shape): 32.29,99.93 32.29,97.92 32.21,97.83 31.75,97.83 31.52,98.05 30.4,98.05 30.4,98.49 30.25,98.64 29.87,98.64 29.64,98.87 29.64,99.76 29.77,99.88 30.12,99.88 30.25,99.76 30.25,99.43 30.4,99.27 31.44,99.27 31.65,99.48 31.65,99.95 31.72,100.02 32.21,100.02
+0.9V_TBT_DP on BOTTOM (solid shape): 28.17,101.79 28.2,101.76 28.29,101.67 28.29,101.5 28.28,101.49 28.17,101.41 28.13,101.28 28.13,101.26 28.04,101.17 26.96,101.17 26.7,101.43 26.7,101.75 26.93,101.98 26.96,102.01 27.01,102.07 27.1,102.07 27.25,101.91 27.52,101.91 27.71,102.11 27.86,102.11
+0.9V_TBT_DP on BOTTOM (solid shape): 29.7,100.12 29.94,99.96 30.22,100.04 30.26,100.06 30.29,100.04 30.32,100.01 30.33,99.98 30.32,99.94 30.2,99.64 30.33,99.34 30.42,99.25 30.31,99.12 30.3,99 30.31,98.87 30.39,98.78 30.45,98.72 30.42,98.6 30.38,98.56 30.24,98.56 30.07,98.73 29.91,98.73 29.87,98.77 29.87,98.78 29.82,98.84 29.76,98.88 29.76,98.88 29.44,99.2 29.44,100.02 29.56,100.15 29.69,100.15
+0.9V_TBT_DP on IN2: 27.11,102.02 29.32,102.02 30.19,101.15 30.19,98.96 29.98,98.75 27.43,98.75 27.01,99.16 27.01,101.92
+0.9V_TBT_LVR_OUT on TOP (solid shape): 24.42,97.28 25.5,97.28 25.59,97.27 25.67,97.28 26.25,97.28 26.31,97.22 26.31,96.99 26.01,96.68 25,96.68 24.69,96.74 24.46,96.54 24.43,96.51 24.39,96.51 24.22,96.52 24.08,96.44 23.95,96.44 23.86,96.35 23.8,96.35 23.32,95.87 23.32,93.6 23.2,93.48 23.2,92.5 22.79,92.08 21.9,92.08 21.8,92.17 21.8,93.42 22.5,94.12 22.5,96.25 22.95,96.7 23.66,96.7 23.76,96.8 23.77,96.8 23.77,96.81 23.81,96.81 23.81,96.88 23.85,96.92 23.85,97.28 23.89,97.32 24.38,97.32
+0.9V_TBT_LVR_OUT on BOTTOM (solid shape): 26.36,100.35 26.36,100.21 26.48,100.09 26.6,100 26.74,99.97 26.76,99.97 26.85,99.88 26.9,99.82 26.96,99.77 26.96,99.58 26.83,99.45 26.6,99.45 26.41,99.55 26.22,99.45 25.95,99.45 25.9,99.5 25.84,99.54 25.78,99.55 25.63,99.71 25.63,99.96 25.84,100.18 25.84,100.34 26.02,100.51 26.2,100.51
+0.9V_TBT_LVR_OUT on IN2: 26,100.56 25.89,100.45 25.89,100.11 25.87,100.1 25.87,100.05 25.72,99.9 25.32,99.9 25.16,99.75 25.16,96.93 25.34,96.75 26.18,96.75 26.36,96.93 26.36,97.61 25.89,98.08 25.85,98.11 25.8,98.17 25.79,98.19 25.75,98.37 25.8,98.55 25.8,98.83 25.76,99.11 25.94,99.33 25.94,99.34 26,99.39 26.84,99.39 26.97,99.52 26.97,99.85 26.86,99.95 26.51,99.95 26.36,100.1 26.36,100.46 26.33,100.48 26.31,100.48 26.23,100.56
+0.9V_TBT_PCIE on TOP (solid shape): 27.7,98.46 27.69,98.44 27.68,98.31 27.72,98.19 27.72,98.18 27.72,97.45 28.32,96.84 28.32,95.65 28.45,95.51 28.5,95.48 28.62,95.36 28.62,93.9 28.58,93.86 27.12,93.86 27.11,93.88 27.11,95.3 27.17,95.37 27.6,95.37 27.79,95.56 27.79,95.94 27.6,96.13 27.29,96.13 27.11,96.31 27.11,98.48 27.21,98.58 27.58,98.58
+0.9V_TBT_PCIE on BOTTOM (solid shape): 27.85,98.75 27.88,98.7 27.87,98.64 27.7,98.34 27.89,98.06 27.91,98.04 27.91,97.36 28.43,96.84 28.48,96.78 28.48,96.01 28.45,95.98 28.4,95.93 28.34,95.93 28.11,96.17 28.08,96.17 27.95,96.17 27.81,96.32 27.62,96.32 27.46,96.16 27.32,96.16 27.23,96.06 27.16,96.02 27.1,95.96 27,95.96 26.96,95.99 26.96,96.16 27.07,96.4 26.96,96.64 26.96,96.81 27.05,96.94 27.06,97.09 27.13,97.16 27.2,97.2 27.26,97.26 27.28,97.44 27.16,97.58 27.12,97.65 27.15,97.74 27.21,97.8 27.21,97.86 27.29,98.02 27.21,98.19 27.21,98.51 27.28,98.6 27.29,98.71 27.31,98.79 27.39,98.82 27.79,98.82
+0.9V_TBT_SVR on TOP (solid shape): 23.77,100.28 23.77,100.02 23.86,99.93 25.21,99.93 25.27,99.88 25.27,99.28 25.34,99.28 25.34,99.24 25.43,99.15 25.67,99.15 25.74,99.08 25.73,99.05 25.73,98.98 25.74,98.91 25.74,98.62 25.12,98.62 25.12,97.99 25.16,97.99 25.16,97.49 25.14,97.48 24.63,97.48 24.53,97.58 24.53,99.2 24.38,99.35 24.14,99.36 24.07,99.35 23.35,99.35 23.29,99.35 23.26,99.32 23.18,99.32 23.18,99.24 23.12,99.18 23.12,97.67 21.95,97.67 21.77,97.86 21.77,99.41 21.97,99.6 21.97,100.16 22.15,100.34 23.71,100.34
+0.9V_TBT_SVR on BOTTOM (solid shape): 20.38,110.21 20.38,109.27 20.32,109.08 20.38,108.88 20.38,106.38 20.88,105.88 20.88,105.19 20.46,104.77 18.84,104.77 18.84,104.88 18.65,104.88 17.6,105.93 17.6,110.2 17.88,110.48 20.12,110.48
+0.9V_TBT_SVR on BOTTOM (solid shape): 27.85,100.72 27.85,100.28 27.77,100.2 27.74,100.2 27.61,100.18 27.5,100.08 27.28,100.08 27.11,100.25 26.97,100.25 26.93,100.19 26.82,100.07 26.8,100.07 26.74,100.07 26.67,100.08 26.62,100.1 26.47,100.26 26.47,100.41 26.28,100.59 26.28,100.69 26.38,100.79 27.79,100.79
+0.9V_TBT_SVR on BOTTOM (solid shape): 25.18,100.09 25.22,100.05 25.31,99.96 25.31,97.8 25.11,97.6 25.09,97.6 25,97.57 24.92,97.51 24.91,97.48 24.66,97.48 24.61,97.55 24.56,97.58 24.56,97.78 24.7,97.92 24.7,98.13 24.48,98.35 24.48,98.47 24.44,98.5 24.4,98.57 24.34,98.63 24.34,98.74 24.47,99.03 24.29,99.29 24.29,99.58 24.46,99.75 24.48,99.75 24.59,99.78 24.66,99.87 24.68,99.9 24.69,99.94 24.72,99.97 24.75,99.97 24.91,99.99 25.04,100.09
+0.9V_TBT_SVR on IN3: 23.65,99.88 25.7,99.88 26.57,100.75 29.2,100.75 29.65,100.3 29.65,98.83 28.86,98.04 28.86,95.13 27.56,93.83 23.93,93.83 21.66,96.09 21.66,97.24 19.1,99.8 19.1,105.78 19.45,106.13 21.66,106.13 21.66,106.11 22.2,105.56 22.2,101.33
+1.0V_AMPHYPLL on BOTTOM (solid shape): 128.87,125.55 129.69,125.55 129.88,125.36 129.88,124.44 129.6,124.16 127.41,124.16 126.96,124.61 126.96,125.89 127.09,126.02 128.39,126.02
+1.0V_APLL on TOP (solid shape): 124.74,104.66 124.93,104.47 125.25,104.47 125.44,104.28 125.44,103.2 124.93,103.2 124.93,103.58 124.61,103.9 124.48,103.9 124.36,104.02 124.36,104.91 124.74,104.91
+1.0V_APLL on IN2: 124.36,103.9 124.28,103.97 124.29,104 124.3,104.17 124.23,104.32 124.23,105.44 124.29,105.53 124.39,105.52 124.93,105.78 124.39,106.04 124.29,106.03 124.23,106.12 124.23,106.41 124.28,106.59 124.23,106.77 124.23,107.12 125.06,107.95 125.56,107.95 125.61,107.94 125.78,107.95 125.96,108.13 125.96,108.75 125.96,108.75 125.98,108.87 125.96,108.98 125.96,108.99 125.96,109.38 125.96,109.39 125.98,109.5 125.96,109.61 125.96,109.62 125.96,110.15 125.97,110.16 125.97,111.23 126.5,111.76 127.34,111.76 127.42,111.68 127.42,110.61 128.07,109.96 128.07,109.56 128.07,109.5 128.07,109.06 128.06,109.05 128.03,108.91 128.06,108.78 128.07,108.77 128.07,108.32 128.07,108.05 127.02,107.01 127.02,105.55 126.58,105.1 126.49,105.1 126.48,105.11 126.34,105.14 126.19,105.11 126.18,105.1 125.86,105.1 125.85,105.11 125.7,105.14 125.56,105.11 125.55,105.1 125.22,105.1 125.21,105.11 124.81,105.02 124.8,104.62 124.8,104.02 124.67,103.9
+1.0V_APLLEBB on TOP (solid shape): 128.99,122.76 129.96,122.76 130.1,122.62 130.1,122.11 129.98,121.99 128.76,121.99 128.52,122.23 127.5,122.23 127.43,122.3 127.43,123.09 127.51,123.18 128.57,123.18
+1.0V_APLLEBB on IN2: 121.83,105.36 122.22,105.36 122.42,105.56 122.42,105.99 122.89,106.46 122.91,106.46 123.71,107.25 123.71,107.55 124.48,108.33 124.48,112.11 124.74,112.37 124.74,114.47 124.51,114.7 124.16,114.7 123.8,114.33 123.8,108.71 121.75,106.66 121.75,105.44
+1.0V_CLK2 on TOP (solid shape): outline of 240 points within 121.44,107.19 123.01,111.85
+1.0V_CLK2 on BOTTOM (solid shape): 125.38,127.2 125.38,126.17 124.89,125.68 124.89,124.45 124.89,124.44 124.89,124.27 124.69,124.08 123.91,124.08 123.75,124.24 123.74,124.25 123.65,124.41 123.5,124.5 123.48,124.51 123.38,124.61 123.38,125.95 124.51,127.08 124.51,127.27 124.58,127.34 125.24,127.34
+1.0V_CLK3 on IN2: 120.65,107.22 120.55,107.33 120.55,107.83 120.39,107.99 120.39,108.77 120.4,108.78 120.43,108.92 120.4,109.06 120.39,109.07 120.39,109.28 120.56,109.57 120.39,109.85 120.39,110 120.5,110.24 120.41,110.47 120.39,110.49 120.39,110.59 120.41,110.61 120.5,110.84 120.39,111.07 120.39,111.42 120.56,111.58 120.56,111.68 121.18,112.3 121.46,112.3 121.49,112.28 121.49,112.1 121.66,111.92 121.66,110.91 121.65,110.81 121.66,110.72 121.66,110.27 121.65,110.18 121.66,110.09 121.66,109.61 121.65,109.52 121.66,109.42 121.66,109.15 121.59,108.93 121.66,108.72 121.66,108.49 121.03,107.86 121.03,107.35 120.9,107.22
+1.0V_CLK4 on BOTTOM (solid shape): 123.16,126.88 123.16,124.55 122.57,123.96 121.69,123.96 121.48,124.18 121.48,125.09 121.23,125.33 121.23,126.72 121.84,127.33 122.72,127.33
+1.0V_CLK4 on IN3: 122.01,125.3 122.67,125.3 123.01,124.96 123.01,106.75 120.86,104.6 119.9,104.6 119.3,105.2 119.3,122.6
+1.0V_CLK5 on BOTTOM (solid shape): 126.37,127.28 126.37,125.9 126.66,125.6 126.66,124.41 126.32,124.07 125.19,124.07 125.09,124.18 125.09,125.46 125.59,125.97 125.59,127.3 125.62,127.33 126.32,127.33
+1.0V_CLK5 on IN2: 121.26,106.44 121.18,106.51 121.18,107.71 122.2,108.72 122.2,108.76 122.2,108.77 122.25,108.93 122.2,109.1 122.2,109.11 122.2,109.27 122.31,109.52 122.2,109.77 122.2,109.93 122.31,110.18 122.2,110.43 122.2,110.56 122.31,110.81 122.2,111.07 122.2,111.24 123.26,112.3 123.39,112.3 123.42,112.33 123.62,112.33 123.65,112.3 123.65,108.91 123.64,108.9 123.64,108.85 122.71,107.91 121.94,107.91 121.61,107.58 121.61,106.54 121.51,106.44
+1.0V_MPHYAON on TOP (solid shape): outline of 93 points within 132.74,107.07 141.5,120.15
+1.0V_MPHYAON on IN4 (solid shape): outline of 420 points within 122.4,106.03 133.86,107.84
+1.0V_MPHYGT on TOP (solid shape): 123.49,106.21 124.13,106.21 124.25,106.09 124.25,105.48 124.06,105.29 123.66,105.29 123.52,105.16 123.52,104.61 123.45,104.53 122.87,104.53 122.78,104.62 122.78,105.37 123.03,105.62 123.03,105.81 123.03,105.82 123.03,105.96 123.28,106.21 123.48,106.21
+1.0V_MPHYGT on TOP (solid shape): outline of 202 points within 128.76,119.64 139.05,126.02
+1.0V_MPHYGT on BOTTOM (solid shape): 135.04,114.55 135.04,112.42 134.62,112 133.83,112 133.65,112.18 133.65,112.64 133.12,113.17 133.12,114.69 133.18,114.76 134.83,114.76
+1.0V_MPHYGT on BOTTOM (solid shape): 132.17,125.28 132.17,124.84 132.17,124.78 132.17,124.71 132.17,124.35 131.8,123.98 130.57,123.98 130.19,124.37 130.19,125.58 129.75,126.02 129.75,126.19 128.83,126.19 128.83,126.87 128.9,126.93 129.15,126.93 129.37,127.15 129.37,127.56 129.49,127.67 129.78,127.67
+1.0V_MPHYGT on BOTTOM (solid shape): 138.96,122 138.97,121.99 139.68,121.99 139.68,122.51 140.16,122.51 140.16,122 140.17,121.99 140.88,121.99 140.88,122.51 141.37,122.51 141.63,122.25 141.63,119.07 141.5,118.95 139.86,118.95 139.77,118.86 139.7,118.86 139.03,118.19 137.96,118.19 137.83,118.32 137.83,121.17 138.08,121.42 138.08,122.32 138.27,122.51 138.96,122.51
+1.0V_MPHYGT on IN1: outline of 102 points within 122.69,105.17 136.36,113.29
+1.0V_PRIM on TOP (solid shape): 143.72,123.77 143.72,123.2 143.28,122.76 141.95,122.76 141.5,122.31 141.5,121.04 141.37,120.91 140.23,120.91 140.1,121.04 140.1,122.69 139.75,123.05 139.75,123.73 139.91,123.88 143.62,123.88
+1.0V_PRIM on TOP (solid shape): outline of 246 points within 118.48,123.38 128.61,130.96
+1.0V_PRIM on BOTTOM (solid shape): 161.27,89.59 161.27,89.57 161.37,89.37 161.57,89.27 161.59,89.26 161.71,89.14 161.71,88.64 160.97,87.89 160.97,87.74 160.91,87.69 160.4,87.69 160.38,87.7 160.38,88.23 160.37,88.25 159.65,88.25 159.64,88.23 159.64,87.7 159.62,87.69 159.19,87.69 159.17,87.7 159.17,88.22 159.15,88.24 158.45,88.24 158.44,88.23 158.44,87.7 158.43,87.69 157.76,87.69 157.71,87.75 157.71,89.63 157.88,89.8 161.06,89.8
+1.0V_PRIM on BOTTOM (solid shape): 129.69,123.84 129.69,122.31 129.5,122.12 128.02,122.12 127.94,122.2 127.38,122.2 126.71,121.53 126.71,121.34 126.44,121.08 125.75,121.08 125.62,121.22 125.62,122.64 125.69,122.71 126.6,122.71 126.76,122.87 128.1,122.87 128.11,122.81 128.12,122.76 128.14,122.71 128.16,122.66 128.2,122.62 128.24,122.59 128.28,122.56 128.33,122.53 128.38,122.52 128.43,122.51 128.49,122.51 128.54,122.52 128.59,122.53 128.64,122.56 128.68,122.59 128.72,122.62 128.75,122.66 128.78,122.71 128.8,122.76 128.81,122.81 128.82,122.87 128.81,122.92 128.8,122.97 128.78,123.02 128.75,123.07 128.72,123.11 128.68,123.14 128.64,123.17 128.59,123.2 128.54,123.21 128.49,123.22 128.43,123.22 128.38,123.21 128.33,123.2 128.28,123.17 128.24,123.14 128.2,123.11 128.16,123.07 128.14,123.02 128.12,122.97 128.11,122.92 128.1,122.87 126.76,122.87 126.81,122.92 126.81,122.98 126.84,123.01 126.84,123.69 126.81,123.72 126.81,123.8 126.99,123.98 129.55,123.98
+1.0V_PRIM on BOTTOM (solid shape): 133.71,126.34 134.79,126.34 135.66,125.47 137.11,125.47 137.39,125.2 142.97,125.2 143.88,124.29 143.88,123.09 143.45,122.66 140.78,122.66 140.76,122.63 140.75,122.63 140.75,122.14 140.72,122.12 140.3,122.12 140.3,122.12 140.3,122.63 140.27,122.63 140.27,122.66 139.56,122.66 139.55,122.65 139.55,122.13 139.53,122.12 139.1,122.12 139.1,122.12 139.1,122.63 139.09,122.63 139.06,122.67 138.33,122.67 138.3,122.69 137.91,122.69 136.59,124.02 134.77,124.02 134.39,124.4 133.25,124.4 132.88,124.77 132.88,124.8 132.9,124.88 132.98,124.91 133.18,125.55 132.61,125.19 132.6,125.15 132.56,125.13 132.51,125.13 129.23,128.42 126.95,128.42 126.21,127.67 122,127.67 121.88,127.79 121.88,129.69 122.27,130.09 125.99,130.09 126.36,130.46 129.59,130.46
+1.0V_PRIM on VCC: 152.4,87.64 152.3,87.75 152.3,91.56 150.52,93.33 150.52,117.97 148.97,119.52 142.16,119.52 132.99,110.35 132.99,108.62 134.01,107.6 134.01,95.75 131.98,93.72 131.98,92.32 130.47,90.82 121.29,90.82 121.05,91.05 121.05,101.81 121.56,102.32 121.56,103.34 122.32,104.1 122.32,106 125.25,108.92 125.25,109.89 125.37,110.01 125.37,116.11 128.27,119.01 131.45,119.01 136.4,123.96 157.53,123.96 157.76,123.73 157.76,96.68 161.82,92.62 161.82,88 161.46,87.64
+1.0V_PRIM_CORE on BOTTOM (solid shape): 150.41,123.93 150.41,122.62 147.56,119.76 147.56,118.02 147.35,117.81 145.26,117.81 144.89,118.19 144.89,121.97 146.98,124.07 148.53,124.07 148.53,123.51 149.08,123.51 149.08,124.07 149.33,124.07 149.33,123.51 149.88,123.51 149.88,124.07 150.27,124.07
+1.0V_PRIM_CORE on IN1: outline of 165 points within 120.1,98.82 147.35,105.4
+1.0V_PRIM_CORE on IN2: 148.39,112.56 147.72,111.9 147.72,104.31 147.7,104.29 147.5,103.97 147.7,103.65 147.72,103.64 147.72,101.33 147.31,100.91 146.63,100.91 146.41,101.14 146.38,101.24 146.45,101.31 146.62,101.9 146.02,101.74 145.95,101.67 145.85,101.7 145.12,102.43 145.12,102.66 144.96,102.83 144.96,104.61 144.99,104.69 145.06,104.72 145.43,105.02 145.16,105.42 145.12,105.43 145.12,109.42 145.36,109.66 145.36,115.35 145.12,115.6 145.12,117.23 145.16,117.27 145.16,118.52 145.4,118.76 147.49,118.76 148.39,117.86
+1.0V_PRIM_COREP on TOP (solid shape): 151.37,128.47 151.37,126.02 150.76,125.41 150,125.41 149.74,125.67 149.74,128.77 149.92,128.95 150.88,128.95
+1.0V_PRIM_COREP on BOTTOM (solid shape): 152.28,129.22 152.28,127.38 153.15,126.52 155,126.52 155,126.52 155.5,127.03 155.5,127.62 155.58,127.69 156.37,127.69 156.45,127.62 156.45,125.77 156.11,125.43 152.24,125.43 151.03,124.22 149.75,124.22 149.74,124.21 149.74,123.67 149.74,123.67 149.49,123.67 149.49,124.21 149.48,124.22 148.94,124.22 148.94,124.22 148.94,123.67 148.69,123.67 148.69,123.68 148.69,124.21 148.68,124.22 148.21,124.22 148.1,124.33 148.1,125.32 148.33,125.55 149.58,125.55 149.74,125.71 149.74,128.01 149.75,128.01 149.75,128.86 149.97,129.08 151.12,129.08 151.34,129.31 152.2,129.31
+1.0V_SRAM on TOP (solid shape): 132.17,114.56 132.36,114.37 132.36,114.12 132.23,113.99 131.47,113.99 131.34,114.12 131.34,114.44 131.41,114.5 131.41,115.26 132.17,115.26
+1.0V_SRAM on IN4: 131.6,114.48 132.35,114.48 132.49,114.34 132.49,113.28 132.19,112.98 131.39,112.98 131.27,113.1 131.27,114.15
+1.0V_SRAM on IN4: 119.43,100.57 119.18,100.82 119.18,107.83 119.29,107.94 120.51,107.94 120.9,108.34 121.08,108.33 121.4,108.42 121.62,108.67 121.71,108.67 121.73,108.66 121.93,108.6 122.12,108.67 122.76,108.67 122.98,108.59 123.19,108.67 123.56,108.67 123.95,109.07 123.95,110.58 124.03,110.65 124.03,111.14 124.38,111.49 124.52,111.49 124.61,111.48 124.7,111.49 124.94,111.49 125.22,111.77 125.26,111.77 125.49,112.01 127.02,112.01 127.25,111.77 127.25,110.75 126.97,110.47 126.02,110.47 125.29,109.74 125.29,108.17 124.95,107.83 122.35,107.83 122.34,107.85 122.21,107.72 122.18,107.74 121.78,107.69 121.73,107.29 121.75,107.26 121.47,106.98 121.45,106.99 121.15,106.9 121.06,106.6 121.06,106.57 120.93,106.44 120.93,106.16 120.89,106.08 120.8,106.06 120.38,105.68 120.91,105.48 120.94,105.51 121.59,104.86 121.59,103.85 121.33,103.58 121.31,103.58 121.15,103.49 121.07,103.33 121.06,103.32 121,103.26 121,100.67 120.9,100.57
+1.0V_VCCST on TOP (solid shape): outline of 94 points within 121.66,122.47 124.7,126.81
+1.0V_VCCST on IN2: 121.67,114.52 122.14,114.52 122.38,114.28 122.38,113.96 120.16,111.74 120.16,108 120.35,107.81 120.35,107.27 120.24,107.16 119.97,107.16 119.45,107.68 119.45,112.3
+1.0V_VCCST_C on TOP (solid shape): 126.43,128.04 126.43,127.88 126.41,127.86 126.41,126.38 126.3,126.26 125.92,126.26 125.81,126.16 125.81,126.01 125.36,125.55 124.89,125.55 124.85,125.59 124.85,128.03 124.98,128.16 126.31,128.16
+1.0V_VCCSTG on TOP (solid shape): 121.23,125.95 121.23,122.59 121.15,122.52 120.48,122.52 120.41,122.59 120.41,124.29 119.77,124.93 119.77,126.01 119.83,126.07 120.17,126.07 120.19,126.06 120.19,125.52 120.19,125.52 120.64,125.52 120.65,125.53 120.65,126.07 120.66,126.08 121.1,126.08
+1.0V_VCCSTG_C on TOP (solid shape): 122.11,128.14 122.11,126.65 121.69,126.22 120.53,126.22 120.52,126.21 120.52,125.67 120.51,125.66 120.33,125.66 120.32,125.67 120.32,126.21 120.31,126.22 119.92,126.22 119.89,126.26 119.89,127.18 120.29,127.59 120.29,128.08 120.5,128.29 121.97,128.29
+1.0V_VCCSTG_R on TOP (solid shape): outline of 257 points within 118.34,108.29 121.31,111.52
+1.0VS_VCCIO on TOP (solid shape): 109.37,96.85 109.37,96.59 109.24,96.47 108.04,96.47 107.85,96.28 107.85,96.02 107.79,95.97 107.2,95.97 107.08,96.08 107.08,97.59 107.2,97.71 108.51,97.71
+1.0VS_VCCIO on TOP (solid shape): 116.05,99.1 116.05,98.03 116.23,97.85 116.86,97.85 116.94,97.93 117.04,97.93 117.4,97.57 116.9,97.08 116.27,97.08 115.63,96.44 114.49,96.44 114.44,96.49 114.44,97.5 115.03,98.09 115.03,98.41 114.85,98.6 114.59,98.6 114.55,98.63 114.55,99.13 114.6,99.18 115.96,99.18
+1.0VS_VCCIO on BOTTOM (solid shape): 132.7,129.75 132.7,129.21 132.7,129.2 133.24,129.2 133.25,129.21 133.25,129.75 133.25,129.75 133.5,129.75 133.5,129.75 133.5,129.2 134.05,129.2 134.05,129.2 134.05,129.75 134.05,129.75 134.45,129.75 134.62,129.57 134.62,127.79 134.22,127.39 132.89,127.39 132.2,128.08 132.2,129.61 132.35,129.76 132.69,129.76
+1.0VS_VCCIO on IN1 (solid shape): outline of 355 points within 107.92,96.36 116.09,99.03
+1.0VS_VCCIO on VCC: 115.83,90.82 112.78,93.86 111.13,93.86 109.48,95.51 108,95.51 107.72,95.8 107.72,96.51 107.59,96.64 107.59,97.62 107.65,97.67 114.38,97.67 115.14,98.44 118.31,98.44 118.51,98.64 118.51,106.38 118.77,106.64 118.77,110.9 118.9,111.03 118.9,112.43 119.91,113.44 119.91,117.13 120.29,117.51 120.29,129.57 120.53,129.8 134.67,129.8 136.04,128.43 136.04,124.32 131.24,119.52 128.06,119.52 124.86,116.32 124.86,110.01 124.99,109.89 124.99,109.03 122.07,106.11 122.07,104.2 121.31,103.44 121.31,102.43 120.8,101.92 120.8,91.05 120.57,90.82
+1.2V_DDR_B+ on TOP (solid shape): 67.4,76.08 67.4,75.13 67.14,74.88 67.14,73.42 67.08,73.35 64.8,73.35 64.17,73.99 64.04,73.99 63.83,74.2 63.83,74.52 63.83,74.52 64.38,74.52 64.38,74.52 64.38,75.06 64.38,75.06 63.84,75.06 63.84,75.07 63.84,75.31 63.85,75.32 64.33,75.32 64.38,75.32 64.38,75.32 64.38,75.86 64.37,75.86 63.84,75.86 63.83,75.87 63.83,76.2 63.93,76.29 67.19,76.29
+1.2V_DDR_B+ on BOTTOM (solid shape): 67.33,75.51 67.33,75.13 67.21,75 67.21,73.16 67.33,73.04 67.33,70.52 66.86,70.52 66.86,72.24 66.76,72.34 65.81,72.34 65.56,72.59 65.56,75.26 65.94,75.64 67.21,75.64
+1.2V_DDRP on TOP (solid shape): 72.03,60.88 72.03,60.06 72.03,60.06 72.03,59.28 72.1,59.28 72.13,59.26 72.54,59.26 72.54,58.81 72.03,58.81 72.03,58.78 72.03,58.78 72.03,58.08 72.03,58.08 72.03,58.06 72.54,58.06 72.54,57.61 72.03,57.61 72.03,57.58 72.03,57.58 72.03,56.93 71.94,56.84 69.62,56.84 69.37,57.1 65.94,57.1 65.75,57.29 65.75,60.78 66.06,61.1 71.82,61.1
+1.2V_DDRP on BOTTOM (solid shape): 71.27,57.16 70.89,56.78 69.7,56.78 69.39,57.08 65.76,57.08 65.43,57.41 65.43,60.97 65.66,61.2 69.98,61.2 70.25,61.48 71.27,61.48
+1.2V_DDRP on BOTTOM (solid shape): 69.73,69.19 70.67,69.19 70.89,68.97 70.89,68.32 71.26,67.96 71.26,66.69 71.27,66.67 71.27,66.11 70.25,66.11 70.25,67.51 69.04,68.73 68.74,68.73 68.67,68.8 68.67,69.39 68.72,69.43 69.49,69.43
+1.2V_LDO on TOP (solid shape): 274.39,63.21 274.39,62.11 274.19,61.91 274.19,61.2 273.91,60.92 271.63,60.92 271.5,61.05 271.5,61.81 271.71,62.02 273.84,62.02 274.15,62.34 274.15,63.21 274.23,63.28 274.31,63.28
+1.2V_LDO on TOP (solid shape): 275.97,63.21 275.97,62.44 276.2,62.22 276.2,62.22 276.43,61.99 276.43,60.08 276.2,59.85 275.33,59.85 275.16,60.03 275.16,60.54 275.46,60.84 275.64,60.84 275.87,60.84 276.02,60.99 276.02,61.22 276.02,62.06 275.77,62.32 275.77,63.21 275.82,63.26 275.92,63.26
+1.2V_LDO on IN1 (solid shape): 274.61,61.43 274.6,61.41 274.74,60.98 275.18,60.85 275.24,60.87 275.31,60.87 275.33,60.85 275.63,60.72 275.96,60.81 275.99,60.84 276.21,60.61 276.21,60.43 275.37,59.58 274.77,59.58 273.8,60.56 271.98,60.56 271.37,61.17 271.37,61.92 271.54,62.09 273.95,62.09
+1.2V_MEM on TOP (solid shape): 91.04,65.76 83.04,65.76 83.04,73.76 91.04,73.76
+1.2V_MEM on TOP (solid shape): 108.92,65.32 98.92,65.32 98.92,80.32 108.92,80.32
+1.2V_MEM on TOP (solid shape): 118.83,66.48 110.83,66.48 110.83,74.48 118.83,74.48
+1.2V_MEM on TOP (solid shape): outline of 11355 points within 72.16,51.62 139.03,97.74
+1.8V_PRIM on TOP (solid shape): 206.78,52.46 206.78,51.83 206.72,51.76 205.57,51.76 205.57,51.77 205.55,51.77 205.31,52.01 205.31,52.96 205.42,53.07 206.17,53.07
+1.8V_PRIM on TOP (solid shape): 262.15,87.25 262.59,87.25 262.59,87.78 263.89,87.78 264.13,87.54 264.13,86.5 264.01,86.37 261.72,86.37 261.48,86.61 261.48,87.69 261.57,87.78 262.15,87.78
+1.8V_PRIM on BOTTOM (solid shape): 206.35,52.52 206.35,51.72 206,51.37 204.46,51.37 204.17,51.66 204.17,52.32 204.32,52.47 205.01,52.47 205.52,52.98 205.9,52.98
+1.8V_PRIM on BOTTOM (solid shape): 180.61,60.56 180.61,60.43 179.83,59.65 179.3,59.65 179.13,59.81 179.13,59.93 179.43,60.22 179.43,60.22 179.31,60.35 179.31,60.35 179.04,60.62 179.04,60.62 179.16,60.74 179.17,60.74 179.56,60.35 179.57,60.35 180.04,60.83 180.04,60.83 180.34,60.83
+1.8V_RUN on TOP (solid shape): 214.4,51.7 214.4,51.17 214.17,50.94 212.49,50.94 212.43,51 212.43,51.95 214.15,51.95
+1.8V_RUN_AUDIO on TOP (solid shape): 263.61,57.4 263.61,55.22 263.64,55.2 263.64,54.49 263.54,54.39 262.85,54.39 262.73,54.52 262.73,56.41 262.53,56.6 261.42,56.6 261.34,56.68 261.34,57.14 261.42,57.21 262.76,57.21 262.96,57.41 263.6,57.41
+1.8V_RUN_CARD on TOP (solid shape): 298.5,59.14 299.46,59.14 299.53,59.08 299.53,58.6 299.46,58.53 297.41,58.53 297.41,59.47 297.46,59.52 298.12,59.52
+1.8V_RUN_CARD on TOP (solid shape): 275.56,63.23 275.56,62.34 275.89,62.01 275.89,61.05 275.82,60.97 275.51,60.97 275.44,61.05 275.44,62.11 275.36,62.19 275.36,63.23 275.41,63.28 275.51,63.28
+1.8V_RUN_CARD on TOP (solid shape): 283.61,63.85 284.68,63.85 285.01,63.53 285.01,62.29 285.01,62.29 285.01,62.09 284.67,61.75 283.18,61.75 283.06,61.82 282.93,61.83 282.91,61.83 282.56,62.18 282.01,62.18 281.46,62.73 281.46,63.75 281.57,63.86 283.59,63.86
+1.8V_RUN_CARD on IN2: 275.46,61.94 275.46,61.06 275.55,60.97 276.25,60.97 276.44,61.16 276.44,62.06 275.59,62.06
+1.8V_RUN_CARD on IN2: 281.64,61.26 281.64,62.2 282.22,62.79 283.34,62.79 283.59,62.53 283.59,62.18 283.06,61.65 282.53,61.65 282.14,61.26
+1.8V_RUN_UZ8 on TOP (solid shape): 212.24,52.08 212.24,51.73 211.68,51.73 211.68,51.19 212.24,51.19 212.24,50.94 211.22,50.94 211.03,51.13 210.46,51.13 210.4,51.19 210.4,51.64 210.27,51.76 208.24,51.76 208.18,51.83 208.18,52.46 208.24,52.53 211.8,52.53
+1.8VALWP on TOP (solid shape): 178.94,61.52 178.94,61.36 178.43,60.85 178.13,60.85 177.42,61.56 177.42,61.98 177.77,62.33 178.13,62.33
+1.8VALWP on BOTTOM (solid shape): 179.73,61.61 179.73,60.72 179.6,60.59 179.55,60.59 179.2,60.95 179.14,60.95 178.84,60.64 178.84,60.59 179.2,60.23 179.2,60.21 179.04,60.06 178.81,60.06 177.13,61.73 176.77,61.73 175.73,60.69 175.44,60.69 175,61.13 175,61.63 176.63,63.26 178.08,63.26
+1VALWP on TOP (solid shape): 162.82,88.31 162.82,86.51 162.82,86.51 162.82,82.87 162.67,82.72 162.02,82.72 161.92,82.82 161.92,84.91 161.3,85.54 161.3,86.19 161.29,86.2 161.29,87.57 161.17,87.7 161.17,88.07 161.47,88.37 162.75,88.37
+1VALWP on BOTTOM (solid shape): 162.81,88.31 162.81,86.47 162.83,86.45 162.83,85.78 164.38,84.23 164.38,81.41 164.26,81.29 161.62,81.29 161.28,81.63 161.28,84.46 161.09,84.64 161.09,86.36 160.75,86.7 158.55,86.7 157.89,87.36 157.89,87.54 157.9,87.56 158.57,87.56 158.58,87.57 158.58,88.09 158.59,88.1 159.02,88.1 159.04,88.09 159.04,87.57 159.06,87.55 159.77,87.55 159.78,87.57 159.78,88.09 159.79,88.1 160.23,88.1 160.24,88.09 160.24,87.56 160.25,87.54 161.09,87.54 161.93,88.39 162.73,88.39
+1VALWP_B+ on TOP (solid shape): outline of 228 points within 148.86,82.43 156.75,88.88
+1VALWP_B+ on BOTTOM (solid shape): 152.92,87.08 152.92,85.98 152.45,85.51 151.86,85.51 151.64,85.29 151.2,85.29 151.01,85.48 151.01,85.92 151.1,86.01 151.1,86.5 151.19,86.69 151.11,86.9 151.08,86.93 151.58,87.44 152.57,87.44
+1VS_VCCIOP on TOP (solid shape): 136.5,128.35 136.5,126.25 136.34,126.1 135.58,126.1 134.84,126.83 134.84,128.31 135.21,128.68 136.17,128.68
+1VS_VCCIOP on BOTTOM (solid shape): 136.57,132.16 136.57,129.61 136.59,129.61 136.91,129.29 140.44,129.29 140.56,129.17 140.56,128.9 140.43,128.77 136.93,128.77 136.92,128.77 136.57,128.42 136.57,126.16 136.52,126.1 135.55,126.1 134.84,126.82 134.84,129.69 134.62,129.9 133.9,129.9 133.9,129.89 133.9,129.35 133.9,129.35 133.65,129.35 133.65,129.35 133.65,129.9 133.64,129.9 133.11,129.9 133.1,129.89 133.1,129.35 133.1,129.35 132.85,129.35 132.85,129.9 132.85,129.9 132.3,129.9 132.24,129.96 132.24,130.4 132.45,130.61 132.46,130.61 132.61,130.7 132.69,130.84 132.7,130.85 133.32,131.48 133.77,131.48 134.6,132.31 136.42,132.31
+2.5V_MEM on TOP (solid shape): 145.82,63.31 145.82,62.32 145.79,62.29 145.76,62.29 145.66,62.31 145.56,62.29 145.44,62.29 145.07,61.92 145.07,61.42 144.87,61.22 142.3,61.22 142.26,61.26 142.26,62.82 142.37,62.93 144.68,62.93 145.09,63.33 145.79,63.33
+2.5V_MEM on BOTTOM (solid shape): 143.53,62.47 143.53,61.22 143.33,61.02 142.16,61.02 142.06,61.12 142.06,62.7 142.14,62.77 143.23,62.77
+2.5V_VIN on TOP (solid shape): 151.98,62.81 151.98,61.22 152.8,60.4 152.8,58.71 153.09,58.42 153.09,57.13 153.06,57.1 152.23,57.1 151.98,57.35 151.98,60.15 151.73,60.4 151.03,60.4 150.9,60.53 150.9,62.81 151.03,62.94 151.85,62.94
+3.3V_1.8V_ESPI on TOP (solid shape): 145.73,84.99 145.73,83.74 145.63,83.64 145.63,82.62 145.31,82.62 144.95,82.98 144.95,85.01 145.05,85.1 145.62,85.1
+3.3V_1.8V_PGPPA on TOP (solid shape): 146.65,85.01 146.65,84.36 146.87,84.14 147.58,84.14 147.7,84.26 147.7,84.86 147.81,84.97 148.42,84.97 148.55,84.84 148.55,83.53 146.93,81.9 146.93,81.51 146.71,81.29 145.69,81.29 145.57,81.42 145.57,81.93 145.82,82.18 145.82,82.88 146.39,82.88 146.39,83.39 145.82,83.39 145.82,83.64 145.86,83.68 145.86,84.99 146.02,85.15 146.51,85.15
+3.3V_ALW on TOP (solid shape): 20.17,111.92 20.17,110.68 20.12,110.63 19.07,110.63 18.88,110.82 18.88,111.86 19.07,112.05 20.04,112.05
+3.3V_ALW on TOP (solid shape): 280.31,93.55 280.31,91.83 280.12,91.64 278.85,91.64 278.79,91.7 278.79,92.4 278.67,92.53 278.67,93.49 278.85,93.67 280.19,93.67
+3.3V_ALW on TOP (solid shape): 259.77,87.25 260.21,87.25 260.21,87.77 261.09,87.77 261.24,87.62 261.24,86.61 261.05,86.42 259.63,86.42 259.38,86.66 259.38,87.68 259.47,87.77 259.77,87.77
+3.3V_ALW on TOP (solid shape): 159.73,83.38 160.13,83.38 160.18,83.33 160.18,81.5 160.01,81.33 158.66,81.33 158.57,81.42 158.57,83.33 158.74,83.5 159.61,83.5
+3.3V_ALW on TOP (solid shape): 253.64,110.37 253.64,109.04 253.45,108.85 251.99,108.85 251.8,109.04 251.8,109.74 251.93,109.87 251.93,110.44 251.99,110.5 253.52,110.5
+3.3V_ALW on TOP (solid shape): 253.77,113.17 253.77,112.79 253.39,112.41 252.88,112.41 252.69,112.22 252.69,111.96 252.63,111.9 251.99,111.9 251.93,111.96 251.93,113.1 252.12,113.29 253.64,113.29
+3.3V_ALW on TOP (solid shape): 69.04,122.69 69.04,121.42 68.91,121.3 66.7,121.3 66.44,121.55 66.44,122.57 66.69,122.81 68.92,122.81
+3.3V_ALW on TOP (solid shape): 263.85,94.69 263.85,93.13 263.85,93.12 263.85,89.65 263.46,89.27 262.36,89.27 262.18,89.44 262.18,92.7 262.53,93.05 262.53,94.77 262.72,94.96 263.59,94.96
+3.3V_ALW on TOP (solid shape): 227.67,58.24 229,58.24 229.18,58.06 229.18,57.58 228.9,57.3 226.91,57.3 226.64,57.58 226.64,58.01 226.63,58.01 226.63,58.04 226.38,58.29 225.23,58.29 225.11,58.42 225.11,58.78 225.22,58.89 225.22,58.91 225.36,59.06 226.86,59.06
+3.3V_ALW on TOP (solid shape): 207.54,60.35 207.54,58.24 207.47,58.17 207.02,58.17 206.96,58.24 206.96,59.53 206.77,59.72 205.65,59.72 205.44,59.51 204.68,59.51 204.56,59.64 204.56,59.98 205.19,60.61 207.29,60.61
+3.3V_ALW on TOP (solid shape): 254.84,76.85 254.84,76.32 254.82,76.3 254.82,75.48 254.28,74.94 253.26,74.94 252.68,74.36 251.31,74.36 251.2,74.46 251.2,75.42 251.16,75.47 252.37,75.47 252.37,75.42 252.38,75.37 252.4,75.31 252.42,75.27 252.45,75.22 252.49,75.18 252.53,75.15 252.57,75.12 252.62,75.1 252.67,75.09 252.73,75.09 252.78,75.09 252.83,75.1 252.88,75.12 252.93,75.15 252.97,75.18 253.01,75.22 253.04,75.27 253.06,75.31 253.08,75.37 253.08,75.42 253.08,75.47 253.08,75.52 253.06,75.58 253.04,75.62 253.01,75.67 252.97,75.71 252.93,75.74 252.88,75.77 252.83,75.79 252.78,75.8 252.73,75.8 252.67,75.8 252.62,75.79 252.57,75.77 252.53,75.74 252.49,75.71 252.45,75.67 252.42,75.62 252.4,75.58 252.38,75.52 252.37,75.47 251.16,75.47 250.87,75.75 250.87,76.72 250.95,76.8 251.2,76.8 251.2,76.24 251.71,76.24 251.71,76.8 252.91,76.8 253.03,76.92 254.76,76.92
+3.3V_ALW on TOP (solid shape): 169.82,69.35 169.82,67.75 169.22,67.15 167.1,67.15 166.92,66.98 166.92,66.08 166.51,65.67 164.61,63.77 163.2,63.77 162.65,63.21 162.65,57.86 161.69,56.91 160.7,56.91 160.35,56.55 153.54,56.55 153.25,56.84 153.25,56.92 153.25,57.39 153.77,57.39 153.77,57.82 153.25,57.82 153.25,58.11 153.25,58.11 154.2,58.11 154.77,57.54 157.48,57.54 157.73,57.8 157.76,57.8 158.27,58.3 158.27,59.07 158.2,59.13 158.2,59.57 158.27,59.64 158.91,59.64 159.21,59.35 160.24,59.35 160.33,59.29 160.32,59.19 160.49,58.78 160.84,59.04 160.84,59.06 161.13,59.35 161.21,59.35 161.5,59.64 161.5,59.76 161.51,59.76 161.51,60.13 161.5,60.13 161.5,61.61 161.19,61.92 160.94,61.92 160.9,61.96 160.86,61.96 160.85,61.98 160.62,62.05 160.42,61.92 160,61.92 159.99,61.93 159.66,61.91 159.49,61.64 159.48,61.62 158.9,61.03 158.27,61.03 158.2,61.1 158.2,63.8 161.25,66.84 163.18,66.84 164.97,68.64 164.97,68.73 164.97,68.73 164.99,68.85 164.97,68.97 164.97,68.98 164.97,69.05 165.42,69.5 169.67,69.5
+3.3V_ALW on BOTTOM (solid shape): 224.31,67.45 224.31,66 223.29,66 223.29,67.45 223.42,67.57 224.18,67.57
+3.3V_ALW on BOTTOM (solid shape): 288.53,127.34 288.53,126.55 288.3,126.32 288.3,124.27 288.15,124.13 286.95,124.13 286.53,123.71 286.53,121.13 286.45,121.05 285.98,121.05 285.9,121.13 285.9,125.86 287.53,127.49 288.38,127.49
+3.3V_ALW on BOTTOM (solid shape): 227.61,61.42 227.61,60.97 227.1,60.46 227.1,58.56 227.24,58.42 227.57,58.42 227.73,58.25 227.73,57.44 227.6,57.3 226.85,57.3 226.45,56.91 225.98,56.91 225.78,57.11 225.78,60.41 225.96,60.59 225.96,61.45 225.98,61.48 226.02,61.48 226.15,61.61 227.42,61.61
+3.3V_ALW on BOTTOM (solid shape): 155.65,116.58 155.75,116.58 155.78,116.55 155.78,115.77 155.63,115.61 155.63,114.81 155.65,114.79 156.18,114.79 156.19,114.77 156.19,114.61 156.18,114.59 155.64,114.59 155.63,114.58 155.63,114.49 155.63,114.48 155.63,113.27 155.63,113.26 155.63,112.51 155.44,112.32 155.44,112.13 155.44,112.08 155.44,112.03 155.44,111.71 155.38,111.65 154.87,111.65 154.8,111.72 154.8,113.16 154.56,113.4 154.56,116.45 154.72,116.61 155.62,116.61
+3.3V_ALW on BOTTOM (solid shape): 166.86,71.21 167.62,71.21 167.62,71.74 168.06,71.74 168.06,71.21 168.82,71.21 168.82,71.74 169.58,71.74 170.41,70.92 170.41,70.11 171.17,69.35 171.17,69.35 171.21,69.31 171.21,69.23 170.78,68.79 170.71,68.79 170.02,68.11 170.01,68.11 169.61,68.5 169.28,68.17 169.28,68.16 169.67,67.77 169.67,67.77 169.48,67.58 169.42,67.58 169.22,67.78 168.71,67.78 167.89,66.97 166.33,66.97 165.01,68.28 165.01,71.33 165.43,71.74 166.86,71.74
+3.3V_ALW on IN2: 38.18,119.94 39.75,118.36 43.77,118.36 44.01,118.13 44.01,117.84 43.53,117.36 40.84,117.36 40.84,117.37 38.81,117.37 37.64,118.54 32.97,118.54 32.8,118.72 32.8,119.8 32.94,119.94
+3.3V_ALW on IN3: 154.71,115.58 155.85,115.58 156.7,114.73 161.1,114.73 165,118.63 165.76,118.63 166.01,118.37 166.01,117.23 161.69,112.91 155.73,112.91 154.33,114.31 154.33,115.2
+3.3V_ALW on IN3: 105.2,85.46 167.86,85.46 172.74,80.58 172.74,68.17 171.44,66.87 165.04,66.87 158.32,73.59 70.51,73.59 66.64,69.71 62.58,69.71 61.66,70.63 61.66,77.29 65.67,81.29 70.77,81.29 72.66,79.41 99.15,79.41
+3.3V_ALW on VCC: 60.45,69.73 59.33,70.86 59.33,97.31 62.63,100.62 62.63,106.08 65.3,108.74 65.3,112.38 64.9,112.79 56.43,112.79 52.22,108.57 52.22,100.07 51.46,99.3 51.46,97.27 50.32,96.13 50.32,83.22 48.64,81.54 37.98,81.54 37.36,82.16 37.36,83.73 38.23,84.59 40.52,84.59 44.98,89.06 44.98,94.9 48.54,98.46 48.54,112.77 45.72,115.58 39.25,115.58 39.14,115.69 39.14,116.36 46.92,124.14 70.48,124.14 70.64,123.98 70.64,113.93 69.9,113.93 68.48,112.51 68.48,101.59 68.37,101.48 68.12,101.48 65.43,98.8 65.43,84.11 71.91,77.63 71.91,75.98 74.7,73.18 74.7,69.84 74.59,69.73
+3.3V_ALW on VCC: outline of 133 points within 144.04,65.03 299.18,136.18
+3.3V_ALW on IN4: 33.32,118.49 31.29,118.49 30.34,117.55 30.34,115.29 27.64,112.58 21.51,112.58 20.18,111.26 19.02,111.26 18.86,111.42 18.86,111.96 21.2,114.3 25.73,114.3 25.96,114.07 26.91,114.07 28.43,115.59 28.43,118.83 29.9,120.3 33.1,120.3 33.48,119.92 33.48,118.65
+3.3V_ALW_DSW on TOP (solid shape): outline of 115 points within 122.15,90.57 126.36,98.49
+3.3V_ALW_PCH on TOP (solid shape): 141.94,71.15 141.94,70.89 141.18,70.13 141.04,70.13 140.2,70.98 140.2,71.84 140.5,72.15 140.93,72.15
+3.3V_ALW_PCH on TOP (solid shape): 148.87,65.99 148.87,64.9 148.82,64.85 148.31,64.85 147.93,65.24 147.62,65.24 147.22,65.64 147.22,65.64 146.86,66 146.86,66.45 147.41,66.99 147.87,66.99
+3.3V_ALW_PCH on TOP (solid shape): outline of 937 points within 122.67,97.02 150.2,105.89
+3.3V_ALW_PCH on BOTTOM (solid shape): 128.98,120.99 128.98,120.94 128.99,120.9 128.99,119.96 128.93,119.9 127.28,119.9 127.15,120.03 127.15,120.66 127.66,121.17 128.8,121.17
+3.3V_ALW_PCH on IN1: 137.64,80.33 138.06,80.33 138.81,81.08 138.81,82.74 139.77,83.7 142.35,83.7 143.02,83.03 143.02,82.51 142.72,82.22 142.72,82.17 142.67,81.99 142.72,81.8 142.72,80.99 142.26,80.53 140.69,80.53 138.1,77.94 135.9,77.94 135.79,78.05 135.79,78.47
+3.3V_ALW_PCH on IN3: 120.3,103.73 121.45,103.73 121.72,103.46 121.72,102.89 120.49,101.67 120.49,99.35 119.9,98.75 119.51,98.75 119.22,99.04 119.22,102.65
+3.3V_ALW_PCH on VCC: 141.99,82.05 141.76,82.29 141.76,84.11 141.99,84.34 144.91,84.34 146.33,85.76 146.33,87.87 145.06,89.14 145.06,99.3 143.41,100.95 143.41,105.44 143.77,105.8 150.01,105.8 150.01,93.12 151.79,91.35 151.79,86.98 151.28,86.48 151.28,84.19 149.14,82.05
+3.3V_ALW_PCH on IN4: 140.84,71.14 140.58,71.14 139.52,72.2 139.54,72.23 139.52,72.6 139.17,72.75 139.15,72.75 135.72,76.17 135.72,78.31 136.14,78.73 136.6,78.73 136.61,78.73 136.69,78.73 137.06,78.37 137.06,77.15 140.96,73.24 140.96,71.27
+3.3V_ALW_PCH on IN4: 121.91,96.14 121.9,96.14 121.35,96.14 121.08,96.27 120.81,96.14 120.62,96.14 120.45,96.32 120.45,96.66 120.45,96.67 120.48,96.81 120.45,96.95 120.45,96.96 120.45,97.52 119.59,98.37 119.59,98.97 119.78,99.16 120.25,99.16 120.33,99.12 120.35,99.05 120.68,98.69 121.01,99.05 121.04,99.12 121.11,99.16 121.59,99.16 121.66,99.13 121.7,99.06 121.86,98.79 122.18,98.78 122.28,98.78 122.32,98.69 122.32,98.61 122.27,98.53 122.17,98.53 121.96,98.56 121.76,98.45 121.69,98.42 121.61,98.45 121.35,98.57 121.1,98.43 121.02,98.39 120.94,98.42 120.38,98.16 120.98,97.99 121.05,98.03 121.13,98 121.37,97.91 121.61,98.02 121.69,98.05 121.76,98.02 121.99,97.91 122.23,97.99 122.3,98.02 122.37,97.99 122.52,97.84 122.87,97.84 123.16,97.55 123.16,97.11 123.11,97.03 123.02,97.02 122.6,96.89 122.66,96.46 122.71,96.42 122.76,96.39 122.78,96.31 122.73,96.24 122.68,96.21 122.6,96.14
+3.3V_ALW_PCH_UZ3 on TOP (solid shape): 151.03,64.72 151.03,64.34 150.84,64.15 150.2,64.15 149.49,64.86 149.08,64.86 149.02,64.92 149.02,65.2 149.55,65.2 149.55,65.63 149.02,65.63 149.02,65.93 149.08,65.99 149.75,65.99
+3.3V_ALW_PCH_UZ3 on TOP (solid shape): 156.93,59.57 156.93,59.07 156.87,59 156.36,59 156.04,58.68 155.22,58.68 155.12,58.58 155.12,58.2 155.09,58.18 154.71,58.18 154.46,58.43 153.44,58.43 152.93,58.94 152.93,59.51 153.76,59.51 153.82,59.45 155.6,59.45 155.79,59.64 156.87,59.64
+3.3V_ALW_UE1 on TOP (solid shape): 252.67,81.88 252.67,80.87 252.65,80.74 252.67,80.62 252.67,79.63 252.49,79.45 252.49,79.45 252.3,79.26 252.3,77.67 252.06,77.43 252.06,77.04 251.97,76.95 250.98,76.95 250.95,76.97 250.95,77.33 251.48,77.86 251.48,79.21 251.96,79.68 251.96,81.35 252.02,81.41 252.02,81.81 251.99,81.84 251.99,82.1 252.12,82.23 252.32,82.23
+3.3V_ALW_UZ12 on BOTTOM (solid shape): 157.48,114.78 158.94,114.78 159.01,114.71 159.01,114.4 157.48,112.87 157.48,112.13 157.4,112.05 157.02,112.05 155.75,113.32 155.75,114.43 155.79,114.46 156.29,114.46 156.32,114.49 156.32,114.9 156.3,114.92 155.79,114.92 155.76,114.95 155.76,115.21 155.79,115.23 157.03,115.23
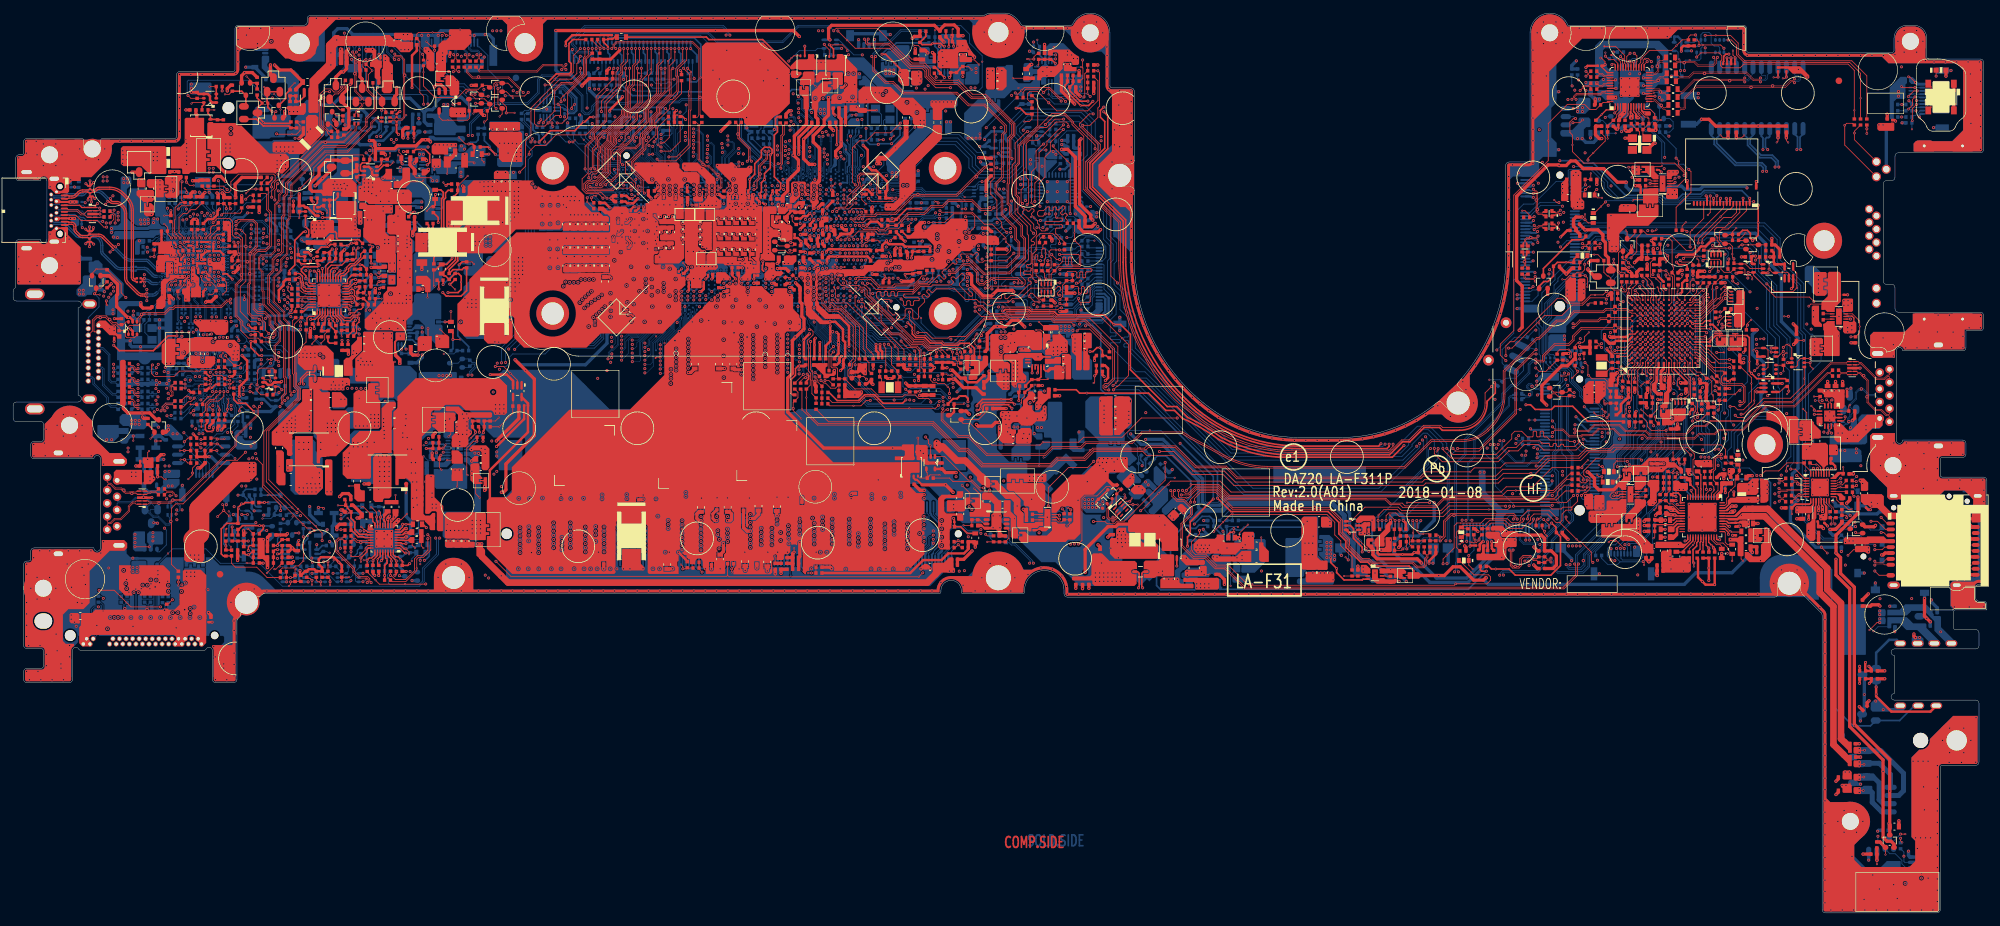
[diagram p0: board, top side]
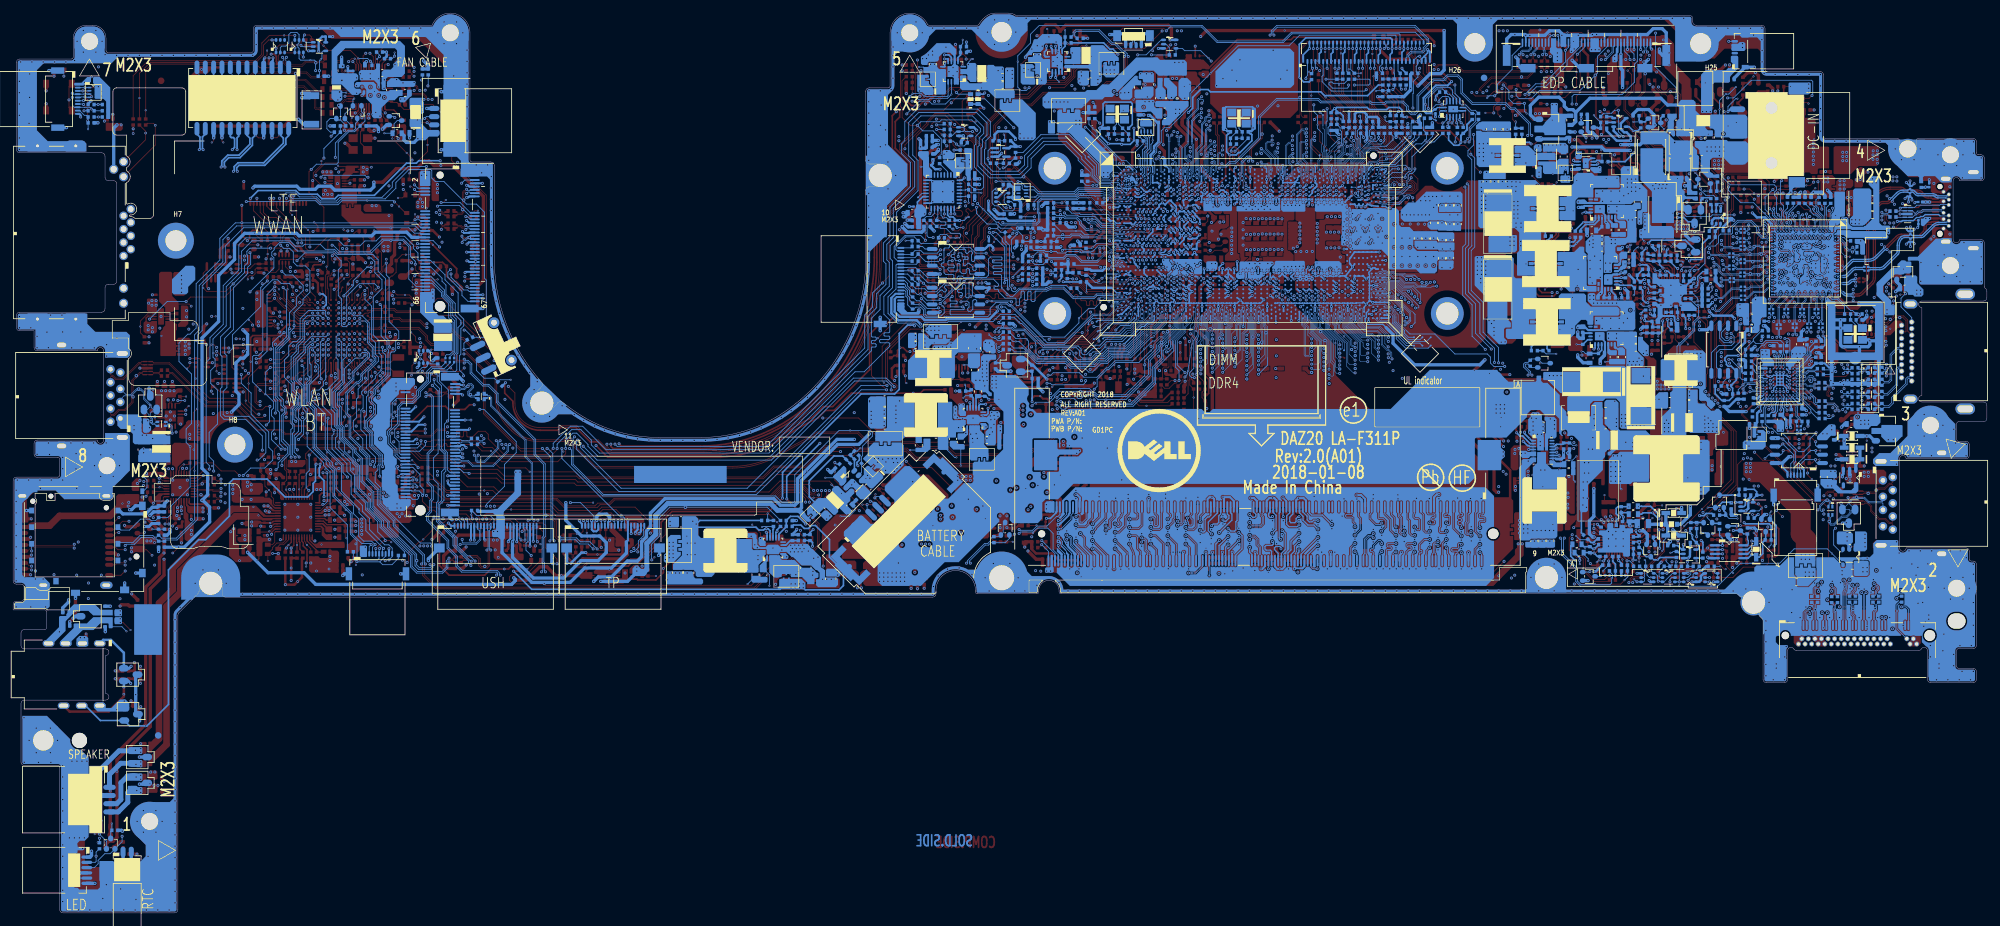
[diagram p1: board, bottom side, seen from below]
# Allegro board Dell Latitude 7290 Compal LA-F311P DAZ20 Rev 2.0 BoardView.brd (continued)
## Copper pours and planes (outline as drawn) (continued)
+3.3V_ALWP on TOP (solid shape): 167.47,73.86 167.55,73.79 167.55,72.89 167.46,72.8 165.72,72.8 165.45,73.06 165.45,74.17 165.44,74.18 165.44,78.5 165.7,78.75 167.47,78.75
+3.3V_ALWP on BOTTOM (solid shape): 167.58,74 168.03,73.55 169.11,73.55 169.36,73.3 169.36,71.91 169.36,71.9 168.67,71.9 168.67,71.9 168.66,71.35 168.22,71.35 168.22,71.89 168.22,71.9 167.48,71.9 167.46,71.89 167.46,71.35 167.03,71.35 167.01,71.36 167.01,71.9 167,71.91 165.47,71.91 163.35,74.04 163.35,78.01 164.09,78.76 167.58,78.76
+3.3V_CAM on TOP (solid shape): 57.35,130.39 57.35,129.82 57.87,129.3 57.87,126.46 57.78,126.38 57.78,125.32 57.45,124.99 56.48,124.99 56.16,125.31 56.16,128.6 56.32,128.76 56.32,130.81 56.42,130.91 56.83,130.91
+3.3V_CAM on BOTTOM (solid shape): 56.39,133.31 56.39,131.98 56.54,131.83 56.54,131.82 56.54,131.2 56.54,131.13 56.55,131.12 56.55,131.06 57.08,130.52 57.08,129.8 56.97,129.69 56.45,129.69 56.25,129.89 56.25,131.06 56.11,131.2 56.11,133.31 56.16,133.36 56.34,133.36
+3.3V_EC_PLL on TOP (solid shape): 250.87,83.96 250.87,83.02 250.59,82.74 250.59,80.91 250.38,80.69 250.38,79.82 250.27,79.72 249.71,79.72 249.7,79.73 249.7,80.65 250.19,81.14 250.19,82.97 250.52,83.3 250.52,83.93 250.62,84.03 250.8,84.03
+3.3V_HDD_M2 on TOP (solid shape): outline of 880 points within 10.06,40.63 29.42,52.33
+3.3V_HDD_M2 on BOTTOM (solid shape): 27.27,52.65 27.29,52.65 27.29,52.64 28,52.64 28,52.65 28.02,52.65 28.02,53.17 28.47,53.17 28.47,52.65 28.49,52.65 28.49,52.64 29.15,52.64 29.21,52.59 29.21,51.55 28.98,51.32 28.98,50.05 28.73,49.79 27.24,49.79 26.55,50.49 26.5,50.55 26.43,50.6 26.07,50.97 26.07,52.54 26.17,52.64 26.8,52.64 26.8,52.65 26.82,52.65 26.82,53.17 27.27,53.17
+3.3V_LAN on TOP (solid shape): 247.89,113.9 247.89,112.62 247.81,112.53 246.66,112.53 246.53,112.66 246.53,113.84 246.64,113.95 247.85,113.95
+3.3V_LAN on TOP (solid shape): 286.59,120.41 286.59,119.35 286.5,119.25 284.27,119.25 284,119.52 284,120.22 284.23,120.45 286.05,120.45 286.1,120.51 286.49,120.51
+3.3V_LAN on BOTTOM (solid shape): 240.69,125.48 240.69,124.6 240.99,124.6 241.18,124.41 241.77,124.41 241.9,124.28 241.9,123.77 241.7,123.58 241.07,123.58 240.23,124.43 240.11,124.43 239.99,124.55 239.99,125.51 240.01,125.53 240.63,125.53
+3.3V_LAN on IN2 (solid shape): 285.15,121.14 285.15,120.07 284.99,119.91 284.14,119.91 284.01,120.04 284.01,121.11 284.1,121.19 285.09,121.19
+3.3V_LAN on IN2: 241.77,113.49 241.77,118.37 240.88,119.26 240.88,122.88 240.12,123.65 240.12,131.77 241.07,132.73 253.2,132.73 254.4,131.52 254.4,129.08 254.28,128.95 253.19,128.95 253.1,129.04 253.1,130.03 251.61,131.52 244.44,131.52 243.86,130.95 243.61,130.95 243.36,131.2 242.4,131.2 241.9,130.69 241.9,126.62 242.39,126.12 242.39,124.42 243.51,123.3 243.51,120.76 243.67,120.6 243.67,114.95 244.31,114.31 247.42,114.31 247.61,114.12 247.61,112.66 247.48,112.53 242.72,112.53
+3.3V_LAN_OUT on TOP (solid shape): 245.77,123.45 245.77,121.88 244.98,121.09 244.98,120.69 244.85,120.56 244.37,120.56 244.35,120.58 244.35,121.07 244.54,121.26 244.54,121.66 245.16,122.29 245.16,123.43 245.21,123.48 245.74,123.48
+3.3V_LAN_OUT on BOTTOM (solid shape): outline of 231 points within 241.39,121.17 248.63,126.69
+3.3V_LAN_OUT on IN2: 246.02,119.52 245.71,119.84 245.01,119.84 244.31,120.53 244.31,121.79 244.36,121.95 244.34,122.11 244.33,122.14 244.5,122.31 245.51,122.31 245.64,122.18 245.64,121.3 246.21,120.72 248.82,120.72 249.2,121.11 249.2,124.98 248.12,126.06 248.12,126.25 248.82,126.95 248.82,128.18 247.8,129.2 246.84,129.2 246.62,129.41 246.62,129.79 246.63,129.86 246.62,129.93 246.62,130.27 246.78,130.44 247.67,130.44 250.4,127.72 250.4,124.99 250.4,124.98 250.4,120.28 249.64,119.52
+3.3V_LAN_UZ2 on TOP (solid shape): 250.07,113.77 250.07,113.06 250.69,112.44 250.69,111.93 250.61,111.85 249.86,111.85 248.86,112.85 248.05,112.85 248.05,113.1 248.63,113.1 248.63,113.61 248.05,113.61 248.05,113.9 248.1,113.94 249.9,113.94
+3.3V_MMI_AUX on TOP (solid shape): 276.5,71.33 276.5,68.31 276.43,68.24 276.27,68.24 275.97,67.93 275.97,66.51 275.92,66.46 275.82,66.46 275.77,66.51 275.77,67.42 275.65,67.53 275.65,67.99 274.56,69.09 272.68,69.09 272.52,69.25 272.52,71.38 272.81,71.68 274.28,71.68 274.28,71.64 275.17,71.64 275.17,71.69 276.15,71.69
+3.3V_MMI_IN on TOP (solid shape): 274.37,74.8 274.37,74.55 275.41,73.51 275.41,72.45 275.33,72.38 274.38,72.38 273.97,71.97 272.34,71.97 272.11,72.2 272.11,72.7 272.64,72.7 272.64,73.21 272.11,73.21 272.11,73.5 272.64,73.5 272.64,74.01 272.11,74.01 272.11,74.87 272.37,75.12 274.04,75.12
+3.3V_MMI_IN on TOP (solid shape): 274.78,63.21 274.78,62.16 274.72,62.11 274.72,60.17 274.59,60.03 274.59,56.99 274.32,56.73 273.76,56.73 273.18,57.3 273.18,59.23 273.47,59.52 273.67,59.52 273.99,59.84 273.99,60.78 274.36,61.14 274.36,61.9 274.53,62.08 274.53,62.36 274.57,62.39 274.57,63.21 274.62,63.27 274.71,63.27
+3.3V_MMI_IN on IN2: 270.28,59.98 270.28,64.6 272.18,66.5 272.18,73.03 272.4,73.25 273.83,73.25 274.26,72.81 274.26,72.15 274.13,72.02 273.57,72.02 273.39,71.84 273.39,66.81 273.38,66.8 273.38,65.36 271.49,63.47 271.49,61.94 271.42,61.72 271.5,61.51 271.53,61.44 271.5,61.38 271.53,60.89 272.02,60.89 272.09,60.91 272.16,60.88 273.74,59.3 273.74,57.53 273.62,57.41 272.85,57.41
+3.3V_RUN on TOP (solid shape): 37.11,68.53 37.11,66.76 36.02,65.67 33.11,65.67 32.85,65.92 32.85,68.21 33.42,68.78 36.85,68.78
+3.3V_RUN on TOP (solid shape): 29.11,57.03 29.11,53.76 28.85,53.51 26.38,53.51 26.06,53.83 26.06,57.03 26.79,57.76 28.38,57.76
+3.3V_RUN on TOP (solid shape): 157.44,66.92 157.44,65.92 157.19,65.67 153.95,65.67 153.95,66.19 153.24,66.19 153.24,65.67 152.75,65.67 152.75,66.19 152.04,66.19 152.04,65.67 151.48,65.67 151.36,65.8 151.36,66.79 151.56,66.99 157.36,66.99
+3.3V_RUN on TOP (solid shape): 207.26,57.05 207.26,56.62 206.7,56.62 206.7,56.18 207.26,56.18 207.26,55.77 207.45,55.59 207.45,54.96 207.38,54.9 206.97,54.9 206.91,54.96 206.91,55.31 206.36,55.85 206.14,56.07 206.14,56.95 206.35,57.15 207.16,57.15
+3.3V_RUN on TOP (solid shape): 245.51,66.56 246.02,66.56 246.02,67.13 246.34,67.13 246.47,67 246.47,66.05 245.77,65.35 245.77,64.59 245.71,64.53 245.07,64.53 244.44,65.16 244.44,65.43 245.26,66.25 245.26,67.13 245.51,67.13
+3.3V_RUN on TOP (solid shape): 270,75.76 271.65,75.76 271.98,75.42 271.98,73.88 272.5,73.88 272.51,73.86 272.51,73.63 271.98,73.63 271.98,73.08 272.51,73.08 272.51,72.83 271.98,72.83 271.98,71.72 271.84,71.58 270.65,71.58 270.65,71.62 270.56,72.23 270.38,72.81 269.09,74.45 267.12,75.15 267.1,75.17 267.1,76.36 267.28,76.54 269.21,76.54
+3.3V_RUN on TOP (solid shape): outline of 81 points within 23.09,109.03 25.84,112.52
+3.3V_RUN on BOTTOM (solid shape): 247.88,55.9 247.88,54.43 247.7,54.25 246.91,54.25 246.78,54.38 246.78,55.85 246.96,56.03 247.75,56.03
+3.3V_RUN on BOTTOM (solid shape): 29.22,54.69 29.22,52.85 29.16,52.78 28.6,52.78 28.6,53.3 27.89,53.3 27.89,52.78 27.4,52.78 27.4,53.3 26.69,53.3 26.69,52.78 26.12,52.78 26.12,54.56 26.38,54.81 29.11,54.81
+3.3V_RUN on BOTTOM (solid shape): 149.34,111.21 149.34,110.68 149.25,110.58 148.63,110.58 148.49,110.44 148.49,109.48 148.68,109.29 149.12,109.29 149.12,108.91 148.68,108.91 148.3,108.53 147.66,108.53 147.47,108.34 147.47,107.71 146.96,107.71 146.96,108.47 147.22,108.72 147.22,109.29 147.28,109.36 147.92,109.36 148.04,109.48 148.04,109.93 147.85,110.12 147.28,110.12 147.22,110.18 147.22,110.82 147.28,110.88 148.36,110.88 148.8,111.33 149.22,111.33
+3.3V_RUN on IN1: 24.87,114.46 30.52,114.46 31,113.98 31,112.84 29.91,111.75 26.6,111.75 26.55,111.8 25.99,111.8 25.13,110.95 23.68,110.95 23.36,111.27 23.36,112.96
+3.3V_RUN on IN2: 157.02,66.69 157.02,65.9 156.89,65.77 154.41,65.77 154.2,65.97 154.05,65.97 154,66.03 154,66.74 154.71,66.74 154.79,66.81 156.89,66.81
+3.3V_RUN on IN2: 140.56,82.76 137.11,82.76 136.98,82.64 136.5,82.64 136.37,82.76 136.37,83.12 136.78,83.53 140.56,83.53
+3.3V_RUN on IN3: 38.76,61.03 40.2,59.59 41.39,59.59 42.82,61.03 56.02,61.03 56.82,61.83 58.54,61.83 60.86,64.15 60.86,65.83 64.01,68.98 67.31,68.98 70.85,72.53 74.4,72.53 74.73,72.19 74.73,70.45 71.59,67.31 71.59,64.9 71.73,64.75 77.07,64.75 81.22,68.9 156.61,68.9 161.68,63.83 161.68,61.99 158.47,58.78 84.46,58.78 82.75,57.07 63.81,57.07 61.7,54.96 29.83,54.96 29.83,54.96 28.18,53.3 26,53.3 25.98,53.32 24.03,53.32 22.04,55.31 22.04,60.31 22.76,61.03
+3.3V_RUN on VCC: 34.19,66.94 34.19,70.09 24.92,79.36 24.92,85.97 24.28,86.6 24.28,92.7 23.52,93.46 23.52,106.2 29.36,112.05 29.36,114.46 31.52,116.62 31.52,117.76 41.02,127.26 64.77,127.26 65.03,127.01 73.17,127.01 73.42,127.26 82.19,127.26 82.19,124.58 81.39,123.77 76.4,123.77 75.52,124.65 46.71,124.65 38.63,116.58 38.63,112.35 40.79,110.19 40.79,103.54 41.57,102.75 48.03,102.75 48.03,98.67 44.47,95.11 44.47,89.27 40.3,85.1 38.02,85.1 36.85,83.94 36.85,81.95 38,80.8 38,78.65 40.41,76.23 40.41,66.94
+3.3V_RUN on VCC: 144.15,61.22 144.04,61.33 144.04,65.01 143.41,65.65 143.41,70.6 129.44,84.57 129.44,90.31 130.69,90.31 132.48,92.11 132.48,93.5 134.52,95.54 134.52,107.81 133.5,108.83 133.5,110.14 142.37,119.01 148.76,119.01 150.01,117.76 150.01,106.31 143.56,106.31 142.9,105.65 142.9,100.74 144.55,99.09 144.55,88.93 145.82,87.66 145.82,85.97 144.7,84.85 141.78,84.85 141.25,84.32 141.25,82.07 141.78,81.54 143.98,81.54 144.3,81.23 144.3,78.65 151.43,71.51 155.62,71.51 161.97,65.16 166.16,65.16 166.42,64.91 188.13,64.91 188.51,64.53 232.41,64.53 242.95,75.07 257.81,75.07 258.45,75.7 260.48,75.7 262,77.23 268.4,77.23 268.63,76.99 268.63,74.05 265.6,74.05 263.06,71.51 246.43,71.51 242.59,67.68 242.59,65.78 239.69,62.88 237.28,62.88 235.63,61.22
+3.3V_RUN_AUDIO on TOP (solid shape): 262.28,67.7 262.28,67.13 261.9,66.75 261.9,66.18 261.39,66.18 261.39,66.62 261.2,66.81 261.2,67.7 261.33,67.83 262.15,67.83
+3.3V_RUN_AUDIO on TOP (solid shape): outline of 118 points within 245.16,66.76 254.4,69.42
+3.3V_RUN_AUDIO on IN1: 255.56,69.46 255.57,69.45 256.61,68.41 258.47,68.41 258.98,68.92 261.29,68.92 261.75,68.46 261.75,67.04 261.45,66.75 255.69,66.75 255.62,66.78 255.59,66.84 255.23,67.17 254.88,66.84 254.84,66.78 254.77,66.75 253.86,66.75 253.77,66.8 253.78,66.91 253.73,67.38 253.26,67.39 253.2,67.37 253.13,67.39 252.71,67.41 252.57,67.01 252.55,66.92 252.47,66.87 251.86,66.87 251.79,66.8 250.05,66.8 249.93,66.81 249.83,66.8 249.83,66.8 249.42,66.8 248.9,67.32 248.88,67.32 248.69,67.51 248.69,67.98 248.92,68.21 250.06,68.21 251.76,69.92 254.02,69.92 254.06,69.88 254.07,69.92 254.51,69.92 254.52,69.91 255.1,69.91
+3.3V_RUN_AUDIO_DVDD on TOP (solid shape): 262.04,65.76 262.04,65.25 261.95,65.16 260.69,65.16 260.5,64.97 260.5,64.15 260.04,63.69 260.04,63.16 259.83,62.94 259.48,62.94 259.42,63 259.42,63.79 260.06,64.43 260.06,65.73 260.15,65.82 261.97,65.82
+3.3V_RUN_AUDIO_UZ5 on TOP (solid shape): 248.82,66.43 248.82,65.25 248.72,65.25 247.99,64.53 247.1,64.53 247.04,64.59 247.04,66.43 247.19,66.58 248.66,66.58
+3.3V_RUN_CARD on TOP (solid shape): 285.42,56.98 286.56,56.98 286.71,56.83 286.71,56.5 286.59,56.37 282.83,56.37 282.66,56.21 279,56.21 278.89,56.32 278.89,57.06 279.12,57.29 282.34,57.29 282.47,57.41 284.99,57.41
+3.3V_RUN_CARD on IN2: 278.79,56.34 278.79,57.35 280.38,57.35 280.57,57.16 280.57,56.78 280.12,56.34
+3.3V_RUN_CARD on IN2: 275.17,62.18 274.15,62.18 274.04,62.06 274.04,60.3 274.18,60.16 274.94,60.16 275.05,60.26 275.05,60.91 275.3,61.16 275.3,62.05
+3.3V_RUN_UZ3 on TOP (solid shape): 152.62,65.54 152.64,65.54 152.64,65.54 153.35,65.54 153.35,65.54 153.37,65.54 153.37,66.06 153.82,66.06 153.82,65.54 153.84,65.54 153.84,65.54 156.85,65.54 157.25,65.14 157.25,62.18 156.93,61.86 156.93,61.1 156.87,61.03 156.23,61.03 155.98,61.29 154.9,61.29 154.84,61.35 154.84,61.8 154.65,61.99 154.2,61.99 153.95,62.24 153.95,62.81 152.49,64.27 151.76,64.27 151.36,64.68 151.36,65.41 151.49,65.54 152.15,65.54 152.15,65.54 152.17,65.54 152.17,66.06 152.62,66.06
+3.3V_TBT on TOP (solid shape): 22.96,111.57 22.96,110.94 22.99,110.91 23.49,110.91 23.53,110.88 23.53,110.67 23.5,110.64 22.98,110.64 22.96,110.63 22.96,110.12 22.98,110.1 23.51,110.1 23.52,110.1 23.52,109.85 23.5,109.84 22.97,109.84 22.96,109.83 22.96,109.18 22.88,109.1 21.87,109.1 21.61,109.36 21.61,110.25 21.36,110.5 20.72,110.5 20.34,110.88 20.34,111.64 20.6,111.9 22.63,111.9
+3.3V_TBT on BOTTOM (solid shape): 22.86,104.03 22.86,103.82 23.01,103.67 23.06,103.67 23.09,103.64 23.12,103.64 23.24,103.52 23.24,103.37 23.2,103.34 23.11,103.34 23.08,103.37 22.99,103.37 22.96,103.4 22.2,103.4 22.14,103.34 21.82,103.34 21.41,102.93 20.41,102.93 20.41,102.93 18.76,102.93 18.53,102.7 15.29,102.7 15.01,102.98 15.01,103.2 15.37,103.56 15.37,103.81 15.52,103.97 20.67,103.97 20.81,104.11 22.78,104.11
+3.3V_TBT on IN4 (solid shape): 23.25,111.55 23.25,110.48 22.78,110 20.65,110 18.46,107.81 18.46,103.46 17.73,102.73 15.29,102.73 15.04,102.99 15.04,103.13 16.64,104.74 16.64,107.62 21.04,112.02 22.78,112.02
+3.3V_TBT on IN3: 31.98,98.72 29.68,101.02 26.84,101.02 25.8,99.98 24.11,99.98 22.41,101.68 22.41,107.2 21.54,108.07 21.54,109.48 21.49,109.54 21.49,111.77 21.58,111.87 35.56,111.87 38.26,109.18 38.25,109.17 38.25,106.57 37.93,106.25 37.31,106.25 36.44,107.11 35.46,107.11 35.19,106.84 35.19,105.27 38.63,101.83 38.63,85.95 38.11,85.42 37.02,85.42 36.33,86.11 36.33,89.88 31.98,94.23
+3.3V_TBT_LC on TOP (solid shape): 33.2,105.22 33.2,102.3 32.69,102.3 32.66,102.32 32.66,103.82 32.43,104.05 31.98,104.05 31.98,105.52 32.89,105.52
+3.3V_TBT_S0 on BOTTOM (solid shape): 35.84,93.48 35.84,90.03 35.79,90.03 35.49,89.61 35.93,89.33 36.02,89.31 36.06,89.23 36.06,88.49 35.96,88.4 34.96,88.4 34.63,88.74 34.63,89.61 34.44,89.8 34.44,90.56 34.19,90.82 33.68,90.82 33.55,90.94 33.55,93.61 33.93,93.99 35.33,93.99
+3.3V_TBT_S0 on IN2: 29.23,98.58 31.87,98.58 35.43,95.02 35.43,93.35 35.25,93.17 34.23,93.17 33.02,94.38 28.92,94.38 28.08,95.22 28.08,97.43
+3.3V_TBT_SX on TOP (solid shape): 21.49,110.02 21.49,109.31 21.61,109.18 21.61,108.88 21.16,108.42 20.7,108.42 20.65,108.37 20.59,108.37 20.59,108.28 20.57,108.27 20.57,107.86 20.52,107.81 20.37,107.81 20.36,107.82 20.36,108.37 20.27,108.37 20.24,108.39 19.84,108.39 18.79,109.44 18.79,109.99 19.05,110.25 21.26,110.25
+3.3V_TBT_SX on IN4: 20.69,109.83 23.84,109.83 26.42,112.41 32.26,112.41 32.74,111.93 32.74,110.75 32.7,110.67 32.63,110.65 32.24,110.29 32.63,109.94 32.7,109.91 32.74,109.83 32.74,109.79 30.08,107.13 28.91,107.13 28.9,107.13 28.75,107.17 28.6,107.13 28.59,107.13 26.8,107.13 26.78,107.11 26.72,107.16 26.73,107.2 26.2,107.62 26.4,106.97 26.49,106.91 26.47,106.8 25.29,105.62 25.29,104.52 23.73,102.97 23.73,102.67 24.25,102.16 24.6,102.16 25.04,101.72 25.04,101.17 24.67,100.8 22.84,100.8 22.69,100.94 22.34,100.94 21.54,101.74 21.54,104.85 21.59,104.85 22.32,105.58 22.32,106.52 21.22,107.61 20.68,107.61 20.19,108.1 20.19,109.33
+3.3V_TBTA_FLASH on IN3: 37.75,82.34 37.75,76.45 30.22,68.91 26.97,68.91 25.8,70.08 25.8,84.1 31.58,89.88 34.46,89.88 35.9,88.44 35.9,84.19
+3.3V_TP on TOP (solid shape): 210.1,60 210.1,59.3 209.84,59.04 209.84,58.22 208.91,57.29 208.91,55.93 208.84,55.85 207.48,55.85 207.41,55.92 207.41,56.91 209.04,58.53 209.04,59.09 209.42,59.47 209.49,59.53 209.61,59.66 209.62,59.84 209.62,60.05 209.68,60.11 209.99,60.11
+3.3V_TSP on TOP (solid shape): 51.33,131.84 51.33,131.58 51.14,131.39 51.14,130.97 51.07,130.76 51.14,130.55 51.14,129.23 50.59,129.23 50.5,129.32 50.5,131.51 50.95,131.96 51.2,131.96
+3.3V_VDD_PIC on TOP (solid shape): 20.22,107.68 20.7,107.68 20.7,108.21 20.72,108.24 21.03,108.24 21.46,107.81 21.46,106.46 21.21,106.21 20.27,106.21 19.94,106.54 19.94,108.21 19.96,108.24 20.22,108.24
+3.3V_VDD_PIC on BOTTOM (solid shape): 25.35,66.11 25.35,65.32 24.74,64.71 23.44,64.71 22.68,63.96 19.96,63.96 19.58,64.34 19.58,65.54 19.71,65.67 20.15,65.67 20.28,65.54 20.28,64.84 20.66,64.46 22.06,64.46 22.88,65.29 22.88,65.99 23.45,65.99 23.64,66.18 25.28,66.18
+3.3V_VDD_PIC on BOTTOM (solid shape): 34.97,73.55 34.97,73.23 34.94,73.2 34.45,73.2 34.44,73.19 34.43,73.19 34.43,73.18 34.41,73.16 34.41,72.77 34.97,72.75 34.99,72.74 34.99,72.35 35.01,72.35 35.3,72.06 36.89,72.06 37.2,71.75 37.2,70.9 36.95,70.64 34.15,70.64 33.68,71.11 33.68,73.29 34.04,73.65 34.87,73.65
+3.3V_VDD_PIC on IN3: 23.1,93.46 31.75,93.46 32.68,92.53 32.68,90.77 31.96,90.05 31.32,90.05 25.28,84.01 25.28,69.15 26.42,68.01 29.76,68.01 36.15,74.4 37.47,74.4 37.74,74.14 37.74,65.06 33.86,61.18 22.23,61.18 20.56,62.86 20.56,91.43 19.25,92.73 19.25,96.78 18.07,97.97 18.07,106.03 19.44,107.4 21.18,107.4 21.39,107.2 21.39,106.44 21.21,106.26 19.37,106.26 19.05,105.93 19.05,99.41 21.23,97.22 21.23,95.33
+3.3V_VDD_PIC_PDA on BOTTOM (solid shape): 35.52,74.24 35.71,74.05 35.71,72.57 35.61,72.46 35.14,72.46 35.13,72.48 35.13,73.81 34.95,73.99 34.95,74.81 35.52,74.81
+3.3V_WLAN on TOP (solid shape): 242.44,63.6 242.44,61.56 242.37,61.48 240.97,61.48 240.87,61.58 240.87,63.56 241.03,63.72 242.33,63.72
+3.3V_WLAN on TOP (solid shape): 242.64,80.92 242.64,78.93 241.78,78.07 241.78,77.84 241.64,77.7 241.15,77.7 241.01,77.84 241.01,81.07 241.04,81.1 242.47,81.1
+3.3V_WLAN on TOP (solid shape): 248.74,108.03 248.74,107.51 248.74,107.51 249.24,107.51 249.24,108.03 249.51,108.03 249.54,108.03 249.54,107.51 249.54,107.51 250.04,107.51 250.04,108.03 250.59,108.03 250.68,107.94 250.68,106.33 249.11,104.76 247.33,104.76 247.31,104.78 247.3,104.76 245.88,104.76 244.7,103.58 244.7,101.06 244.4,100.77 244.4,100.75 244.37,100.72 243.23,100.72 243.04,100.91 243.04,102.51 242.8,102.76 242.8,106.51 242.92,106.63 247.23,106.63 247.67,107.07 247.67,107.96 247.75,108.03 248.71,108.03
+3.3V_WLAN on BOTTOM (solid shape): outline of 277 points within 239.47,61.29 246.34,81.58
+3.3V_WLAN on IN3 (solid shape): 244.59,101.71 244.59,100.34 243.14,98.89 241.03,98.89 240.68,99.25 240.68,99.78 242.84,101.94 244.36,101.94
+3.3V_WLAN on IN3: 241.53,85.85 241.01,85.33 241.01,81.46 241.16,81.3 242.7,81.3 243.1,80.9 243.1,79.21 242.07,78.18 236.99,78.18 235.85,79.32 235.85,86.28 238.05,88.48 241.11,88.48 241.53,88.06
+3.3V_WLAN_UZ2 on TOP (solid shape): 250.65,110.45 250.65,108.33 250.48,108.16 249.94,108.16 249.91,108.16 249.91,107.64 249.66,107.64 249.66,108.16 249.64,108.16 249.14,108.16 249.11,108.16 249.11,107.64 248.86,107.64 248.86,108.16 248.84,108.16 248.37,108.16 248.31,108.22 248.31,110.25 248.5,110.44 249.13,110.44 249.2,110.5 250.6,110.5
+3.3V_WWAN on TOP (solid shape): 237.41,96.81 238.1,96.81 238.1,93.44 237.89,93.23 236.86,93.23 236.48,93.61 236.48,96.4 236.61,96.4 237.23,97.03 237.41,97.03
+3.3V_WWAN on TOP (solid shape): 238.95,112.91 238.95,108.92 239.36,108.5 239.36,107.44 239.16,107.24 237.72,107.24 237.29,107.67 237.29,113.03 237.53,113.27 238.59,113.27
+3.3V_WWAN on TOP (solid shape): 276.31,97.55 276.31,96.85 275.8,96.85 275.8,96.14 276.31,96.14 276.31,95.65 275.8,95.65 275.8,94.94 276.31,94.94 276.31,94.37 276.31,94.37 276.02,94.08 274.67,94.08 274.28,94.48 274.28,97.5 274.5,97.72 276.14,97.72
+3.3V_WWAN on BOTTOM (solid shape): 238.73,112.96 238.73,110.93 238.63,110.83 237.23,110.83 237.13,110.93 237.13,113.04 237.26,113.17 238.53,113.17
+3.3V_WWAN on BOTTOM (solid shape): 276.5,96.59 276.5,94.58 276.25,94.32 274.33,94.32 274.03,94.63 274.03,95.45 272.95,96.53 272.95,98.37 273.26,98.69 274.41,98.69
+3.3V_WWAN on BOTTOM (solid shape): 237.01,95.11 237.01,94.77 237.13,94.65 238.62,94.65 238.71,94.56 238.71,91.57 236.62,89.48 236.62,88.53 236.56,88.47 233.89,88.47 233.89,89.83 235.14,91.07 235.86,91.07 236.73,91.93 236.73,92.92 236.48,93.17 236.48,95.1 236.57,95.19 236.93,95.19
+3.3V_WWAN on IN1: 237.23,113.14 238.64,113.14 239.46,112.32 239.46,107.62 238.2,106.37 238.2,94.4 237.33,93.53 236.36,93.53 235.56,94.33 235.56,111.47
+3.3V_WWAN on IN3: 237.9,109.98 263.19,109.98 275.96,97.21 275.96,93.93 275.29,93.26 272.08,93.26 260.31,105.03 238.77,105.03 237,106.81 237,109.08
+3.3V_WWAN_UZ4 on TOP (solid shape): 278.47,97.48 278.47,93.23 277.52,92.28 277.52,91.7 277.46,91.64 276.38,91.64 276.06,91.96 275.49,91.96 275.49,92.78 275.49,92.79 275.49,93.08 276.45,94.04 276.45,95.05 276.44,95.05 276.44,95.07 275.92,95.07 275.92,95.52 276.44,95.52 276.44,95.54 276.45,95.54 276.45,96.25 276.44,96.25 276.44,96.27 275.92,96.27 275.92,96.72 276.44,96.72 276.44,96.74 276.45,96.74 276.45,97.55 276.65,97.76 278.2,97.76
+5V_ALW on TOP (solid shape): 275.66,75.56 275.66,74.56 275.41,74.31 274.99,74.31 274.75,74.54 274.75,75.58 274.83,75.65 275.58,75.65
+5V_ALW on TOP (solid shape): 279.74,90.12 280.19,90.12 280.31,90.24 280.57,90.24 280.82,89.99 280.82,88.66 280.5,88.34 279.04,88.34 278.79,88.59 278.79,90.18 278.85,90.24 279.61,90.24
+5V_ALW on TOP (solid shape): 275.88,79.83 278.94,79.83 279.03,79.74 279.03,77.21 278.73,76.91 278.68,76.86 277.45,76.86 277.38,76.94 277.38,77.71 277.46,77.78 277.46,78.37 277.2,78.62 275.99,78.62 275.89,78.73 275.89,78.99 275.55,79.33 274.98,79.33 274.9,79.42 274.9,79.9 274.96,79.97 275.74,79.97
+5V_ALW on TOP (solid shape): 24.73,87.43 24.73,86.76 24.76,86.73 25.25,86.73 25.26,86.73 25.26,86.3 25.25,86.28 24.74,86.28 24.74,86.27 24.73,86.25 24.73,85.54 24.74,85.53 25.26,85.53 25.26,85.1 25.25,85.08 24.74,85.08 24.74,85.05 24.73,85.03 24.73,83.72 24.49,83.48 23.39,83.48 23.24,83.54 23.08,83.53 23.05,83.52 22.63,83.94 22.63,86.63 23.55,87.55 24.61,87.55
+5V_ALW on BOTTOM (solid shape): 20.31,53.56 20.31,51.56 20.1,51.36 18.26,51.36 17.99,51.62 17.99,53.53 18.18,53.71 20.16,53.71
+5V_ALW on BOTTOM (solid shape): 147.21,129.24 147.21,126.6 146.91,126.29 145.06,126.29 144.98,126.37 144.98,127.16 145.14,127.31 145.14,128.29 145.69,128.29 145.7,128.3 145.7,128.77 145.68,128.78 145.14,128.78 145.14,129.16 145.41,129.43 147.02,129.43
+5V_ALW on BOTTOM (solid shape): 162.96,127.77 162.96,125.27 162.82,125.13 162.18,125.13 161.76,124.71 160.6,124.71 160.48,124.83 160.48,125.74 161.16,126.42 161.16,126.86 161.16,126.87 161.72,126.87 161.72,126.87 161.72,127.36 161.17,127.36 161.16,127.36 161.16,127.64 161.34,127.82 162.92,127.82
+5V_ALW on BOTTOM (solid shape): 201.15,57 201.15,54.97 201.57,54.56 201.57,53.62 201.37,53.43 200.09,53.43 198.97,54.54 198.97,55.05 198.98,55.06 199.52,55.06 199.52,55.06 199.52,55.8 199.52,55.8 198.98,55.8 198.97,55.81 198.97,56.25 198.98,56.26 199.51,56.26 199.52,56.26 199.52,57 199.51,57.01 198.98,57.01 198.97,57.02 198.97,57.52 199.08,57.63 200.52,57.63
+5V_ALW on IN2: 76.22,129.42 74.32,131.33 73.56,131.33 72.41,132.47 72.41,135.01 73.05,135.65 87.4,135.65 87.78,135.27 87.78,134.61 87.45,134.27 84.22,134.27 83.82,133.87 79.38,129.42
+5V_ALW on IN3: 18.37,47.52 16.58,49.31 16.58,52.88 17.88,54.18 22.97,54.18 24.13,53.03 28.27,53.03 29.86,54.62 61.71,54.62 63.61,56.51 84.17,56.51 85.58,57.92 91.84,57.92 92.07,57.7 92.44,57.7 92.44,57.73 92.64,57.92 200.33,57.92 202.09,56.16 202.09,53.05 201.47,52.42 160.49,52.42 159.03,53.89 147.54,53.89 145.15,51.5 143.93,51.5 142.9,51.72 141.87,51.5 141.41,51.5 140.27,50.36 72.03,50.36 68.61,53.78 65.2,53.78 62.14,50.72 30.5,50.72 27.31,47.52
+5V_ALW on IN3: 43.08,79.09 43.97,79.09 44.13,78.93 44.13,77.48 40.92,74.26 40.92,62.08 40.44,61.6 40.44,61.21 40.75,60.91 41.21,60.91 41.49,60.63 41.49,59.98 41.28,59.77 40.38,59.77 39.15,60.99 39.15,74.43 42.85,78.13 42.85,78.86
+5V_ALW on VCC: outline of 141 points within 14.37,49.17 282.62,135.83
+5V_ALW_PDA on TOP (solid shape): outline of 221 points within 24.87,84.14 34.53,87.81
+5V_ALW_PDA on BOTTOM (solid shape): 34.5,85.87 34.5,84.29 34.28,84.07 34.16,83.8 34.3,83.55 34.35,83.47 34.32,83.39 34.28,83.35 32.51,83.35 32.44,83.42 32.44,84.21 33.04,84.82 33.04,85.86 33.17,85.99 34.37,85.99
+5V_ALWP on TOP (solid shape): 198.71,60.22 198.71,54.24 199.22,53.73 200.15,53.73 200.28,53.6 200.28,52.44 200.18,52.33 196.48,52.33 196.26,52.56 196.26,60.11 196.58,60.42 198.5,60.42
+5V_ALWP on BOTTOM (solid shape): 198.83,60.29 198.83,56.88 198.85,56.86 199.36,56.86 199.37,56.85 199.37,56.41 199.36,56.41 198.83,56.41 198.82,56.4 198.82,55.66 198.83,55.66 199.36,55.66 199.37,55.65 199.37,55.22 199.36,55.21 199.03,55.21 199.03,55.21 198.82,55.21 198.82,55.2 198.82,54.5 200.18,53.15 200.18,52.33 197.08,52.33 196.72,51.97 196.72,51.44 196.5,51.22 194.29,51.22 193.83,51.68 193.83,52.71 193.83,52.72 193.83,57.02 193.98,57.18 195.91,57.18 196.33,57.6 196.33,60.1 196.73,60.5 198.61,60.5
+5V_PD_VDD on TOP (solid shape): 21.39,69.35 21.39,67.9 21.33,67.84 20,67.84 19.94,67.89 19.94,68.41 19.73,68.62 19.73,69.34 19.86,69.47 21.27,69.47
+5V_RUN on TOP (solid shape): 275.74,87.48 275.74,86.71 275.22,86.71 275.22,86.2 275.74,86.2 275.74,85.91 275.22,85.91 275.22,85.4 275.74,85.4 275.74,85.04 275.61,84.91 273.96,84.91 273.65,85.23 273.65,87.42 273.93,87.7 275.51,87.7
+5V_RUN on TOP (solid shape): 245.78,63.07 245.78,60.98 244.26,59.46 243.71,59.46 243.71,59.45 243.69,59.45 243.69,58.93 243.44,58.93 243.44,59.45 243.42,59.45 243.42,59.46 242.91,59.46 242.91,59.45 242.89,59.45 242.89,58.93 242.64,58.93 242.64,59.45 242.62,59.45 242.62,59.46 240.36,59.46 239.99,59.83 239.99,61.1 240.24,61.35 242.54,61.35 242.75,61.55 242.75,62.71 242.75,62.71 242.92,62.88 244.72,62.88 244.97,63.13 245.72,63.13
+5V_RUN on BOTTOM (solid shape): 15.61,92.68 15.61,91.28 15.45,91.12 14.2,91.12 14.02,91.29 14.02,92.63 14.14,92.75 15.54,92.75
+5V_RUN on BOTTOM (solid shape): 13.62,98.91 13.62,97.48 13.49,97.35 12.72,97.35 12.59,97.49 11.74,97.49 11.51,97.72 11.51,99.18 11.65,99.32 12.27,99.32 12.45,99.5 13.03,99.5
+5V_RUN on BOTTOM (solid shape): 240.31,121.02 240.31,119.96 240.16,119.82 239.65,119.82 239.29,119.46 239.29,117.93 239.16,117.8 237.89,117.8 237.32,118.37 235.99,118.37 235.74,118.63 235.74,119.2 235.93,119.39 237.53,119.39 237.95,119.81 237.95,119.81 238.49,120.36 238.49,121.09 238.68,121.28 240.05,121.28
+5V_RUN on IN2 (solid shape): 15.58,92.05 15.58,91.13 15.41,90.97 13.68,90.97 13.65,91 13.65,92.05 13.83,92.24 15.39,92.24
+5V_RUN on IN4 (solid shape): 18.4,71.07 18.4,70.05 17.38,70.05 17.28,70.14 17.28,71 17.41,71.13 18.33,71.13
+5V_RUN on IN4 (solid shape): 22.76,68.65 23.84,68.65 24.03,68.46 24.03,67.89 23.9,67.77 22.25,67.77 21.99,68.02 21.99,68.72 22.12,68.84 22.57,68.84
+5V_RUN on IN2: 240.05,117.61 240.05,117.1 239.93,116.98 239.29,116.98 238.78,117.49 238.21,117.49 238.02,117.68 238.02,118.25 238.15,118.37 239.29,118.37
+5V_RUN on IN2: 25.61,67.45 25.61,66.69 24.98,66.69 23.96,67.7 23.07,67.7 22.88,67.89 22.88,68.53 23.01,68.65 24.41,68.65
+5V_RUN on IN2: 35.71,65.54 35.9,65.35 35.9,64.78 35.65,64.53 33.68,64.53 33.17,65.03 33.17,65.54
+5V_RUN on IN2: 17.11,70.96 17.11,72.05 17.29,72.23 18.23,72.23 18.41,72.05 18.41,70.35 18.02,69.96 17.34,69.96 17.1,70.19 17.1,70.95
+5V_RUN on IN2: 273.45,88.59 273.45,85.48 274.03,84.91 274.79,84.91 275.04,85.16 275.04,87.37 275.06,87.39 275.06,88.96 273.79,90.23 272.82,90.23 272.54,89.95 272.54,89.51
+5V_RUN on IN3: 75.86,68.51 80.13,72.78 157.4,72.78 164.74,65.43 170.52,65.43 172.72,63.23 230.92,63.23 245.42,77.73 256.62,77.73 269.39,90.5 275.3,90.5 276.81,88.98 276.81,86.39 261.92,71.49 246.95,71.49 243.13,67.67 243.13,59.82 241.61,58.3 172.74,58.3 168.28,62.76 163.62,62.76 156.37,70.01 81.57,70.01 76.74,65.19 72.95,65.19 72.73,65.41 72.73,67.5 73.73,68.51
+5V_RUN on VCC: 45.72,56.4 37.72,64.4 34.67,64.4 34.19,64.89 34.19,66.43 40.41,66.43 40.41,65.44 46.65,59.19 52.81,59.19 53.24,59.62 53.24,68.99 55.73,71.48 58.5,71.48 58.82,71.15 58.82,70.65 60.24,69.23 74.59,69.23 74.7,69.12 74.7,65.78 74.47,65.54 58.72,65.54 56.41,63.24 56.41,57.52 55.29,56.4
+5V_RUN_AUDIO on TOP (solid shape): 265.9,64.08 265.56,63.75 263.14,63.75 262.65,64.23 262.65,65.35 262.88,65.57 264.29,65.57 264.95,66.23 265.89,66.23 265.9,66.24
+5V_RUN_AUDIO on TOP (solid shape): 248.05,60.04 248.05,57.79 249.57,56.27 249.83,56.27 249.9,56.21 249.9,54.81 248.32,54.81 247.91,55.22 247.91,55.78 246.98,56.72 245.13,56.72 244.63,57.22 242.07,57.22 241.95,57.35 241.95,59.19 242.07,59.32 242.51,59.32 242.51,58.8 243.02,58.8 243.02,59.32 243.31,59.32 243.31,58.8 243.82,58.8 243.82,59.32 246.72,59.32 246.85,59.45 246.85,59.9 247.23,60.28 247.81,60.28
+5V_RUN_AUDIO on IN3: 264.58,63.91 263.27,63.91 262.16,65.02 250.34,65.02 248.46,63.14 248.46,57.55 247.82,56.91 247.18,56.27 244.63,56.27 243.61,57.29 243.61,67.32 247.04,70.75 263.04,70.75 266.09,67.7 266.09,65.42
+5V_RUN_AUDIO_UZ5 on TOP (solid shape): 248.06,63.06 248.63,63.06 248.75,62.93 248.75,62.11 246.72,60.08 246.72,59.51 246.47,59.51 246.47,60.08 245.96,60.08 245.96,59.51 245.71,59.51 245.6,59.61 245.6,60.62 247.04,62.05 247.04,63.07 247.1,63.13 247.98,63.13
+5V_RUN_PVDD_L on TOP (solid shape): 266.04,63.36 266.04,62.8 265.78,62.55 261.8,62.55 260.88,61.63 259.99,61.63 259.94,61.68 259.94,61.78 259.99,61.83 260.78,61.83 261.21,62.27 261.21,62.9 261.63,63.32 262.4,63.32 262.57,63.49 265.91,63.49
+5V_RUN_PVDD_L on TOP (solid shape): 261.34,59.62 262.86,59.62 263.07,59.83 264.51,59.83 264.59,59.75 264.59,58.91 264.49,58.81 263.5,58.81 263.37,58.94 263.37,59.24 263.27,59.35 262.66,59.35 262.61,59.29 262.23,59.29 262.2,59.32 261.26,59.32 260.96,59.62 259.97,59.62 259.92,59.68 259.92,59.78 259.97,59.83 261.14,59.83
+5V_RUN_PVDD_L on IN2: 265.94,63.31 264.39,63.31 263.45,62.37 263.45,59.02 263.7,58.76 264.77,58.76 265,58.99 265,61.43 266.11,62.55 266.11,63.13
+5V_RUN_UZ4 on TOP (solid shape): 277.52,90.18 277.52,89.61 277.9,89.23 277.9,88.97 278.28,88.59 278.28,85.01 278.17,84.9 275.99,84.9 275.88,85.01 275.88,85.51 275.87,85.51 275.87,85.53 275.36,85.53 275.36,85.53 275.36,85.78 275.87,85.78 275.87,85.8 275.88,85.8 275.88,86.31 275.87,86.31 275.87,86.33 275.36,86.33 275.36,86.57 275.36,86.58 275.87,86.58 275.87,86.6 275.88,86.6 275.88,88.77 275.76,88.89 275.76,89.78 275.88,89.89 276.02,89.89 276.38,90.24 277.46,90.24
+5V_USB_CHG_PWR on TOP (solid shape): 284.96,75.58 284.96,75.12 284.82,74.98 284.82,74.37 284.38,73.92 283.3,73.92 281.14,71.77 277.9,71.77 277.46,72.21 277.46,73.54 277.39,73.61 277.39,74.59 277.47,74.66 278.43,74.66 279.55,73.54 280,73.54 282.41,75.96 284.58,75.96
+5V_USB_CHG_PWR on BOTTOM (solid shape): 284.96,75.63 284.96,75.14 284.82,75 284.82,74.31 284.31,73.8 283.23,73.8 282.47,73.04 282.47,71.77 282.15,71.45 277.33,71.45 277.33,72.78 277.96,73.42 278.92,73.42 279.3,73.04 280.82,73.04 281.01,73.23 281.01,73.24 281.14,73.37 281.14,75.51 281.63,76.01 284.58,76.01
+DV33_18 on TOP (solid shape): 278.93,63.57 278.93,62.89 278.92,62.88 278.31,62.88 278.18,63 278.18,63.46 277.91,63.74 277.89,63.76 276.91,63.76 276.84,63.83 276.84,63.93 276.91,63.99 278.51,63.99
+VBUS_DC_SS on TOP (solid shape): 52.33,108.4 52.33,104.54 52.62,104.25 52.86,104.25 52.97,104.14 52.97,103.14 52.87,103.03 49.53,103.03 49.53,105.52 49.24,105.81 49.24,108.51 49.27,108.55 52.19,108.55
+VBUS_DC_SS on BOTTOM (solid shape): 52.34,106.7 52.34,104.54 52.62,104.26 52.86,104.26 52.97,104.15 52.97,103.02 52.79,102.84 47.71,102.84 47.67,102.88 47.67,104.11 47.72,104.24 47.72,104.39 47.71,104.41 48.04,104.74 51.07,104.74 51.27,104.95 51.27,106.44 51.58,106.75 52.29,106.75
+VCC_CORE on TOP (solid shape): outline of 527 points within 67.28,100.56 90.75,111.69
+VCC_CORE on TOP (solid shape): outline of 963 points within 105.5,96.41 114.09,114.46
+VCC_CORE on BOTTOM (solid shape): 87.06,108.33 87.64,108.33 87.64,108.33 88.13,108.33 89.3,107.16 89.3,105.93 88.77,105.39 87.92,105.39 87.89,105.39 87.84,105.4 87.8,105.39 87.77,105.39 86.79,105.39 86.76,105.4 86.7,105.42 86.63,105.42 86.57,105.42 86.54,105.41 85.53,105.41 85.5,105.42 85.44,105.42 85.39,105.42 85.33,105.41 85.28,105.39 85.22,105.36 85,105.59 83.09,105.59 83.06,105.59 83.02,105.59 82.97,105.59 82.94,105.59 82.75,105.59 82.58,105.42 80.24,105.42 80.22,105.41 79.97,105.41 79.87,105.51 79.87,107.95 80.03,107.95 80.03,106.75 83.59,106.75 83.59,107.89 83.2,108.28 80.36,108.28 80.03,107.95 79.87,107.95 79.87,109.64 80.22,109.99 85.4,109.99
+VCC_CORE on BOTTOM (solid shape): 77.49,111.69 77.49,104.72 77.18,104.4 71.89,104.4 71.26,103.78 71.26,100.95 71.58,100.62 71.58,97.22 71.53,97.16 68.91,97.16 68.64,97.43 68.64,98.4 68.83,98.6 69.95,98.6 69.96,98.61 69.96,99.4 69.95,99.41 68.08,99.41 67.91,99.58 67.91,106.52 68.34,106.94 69.67,106.94 69.67,107.77 68.25,107.77 67.89,108.13 67.89,110.83 68.13,110.83 68.13,110.78 68.14,110.73 68.16,110.68 68.19,110.63 68.22,110.59 68.26,110.55 68.3,110.52 68.35,110.5 68.4,110.49 68.46,110.48 68.51,110.48 68.56,110.49 68.61,110.5 68.66,110.52 68.7,110.55 68.74,110.59 68.78,110.63 68.8,110.68 68.82,110.73 68.84,110.78 68.84,110.83 68.84,110.89 68.82,110.94 68.8,110.99 68.78,111.03 68.74,111.08 68.7,111.11 68.66,111.14 68.61,111.17 68.56,111.18 68.51,111.19 68.46,111.19 68.4,111.18 68.35,111.17 68.3,111.14 68.26,111.11 68.22,111.08 68.19,111.03 68.16,110.99 68.14,110.94 68.13,110.89 68.13,110.83 67.89,110.83 67.89,110.87 68.77,111.75 77.43,111.75
+VCC_CORE on BOTTOM (solid shape): outline of 391 points within 108.69,96.46 114.41,99.33
+VCC_CORE on BOTTOM (solid shape): outline of 559 points within 107.64,106.95 114.86,109.81
+VCC_CORE on IN1: 114.76,106.25 114.93,106.08 114.93,101.04 114.64,100.75 106.63,100.75 106.44,100.94 106.44,106.06 106.62,106.25
+VCC_CORE on IN2: outline of 94 points within 68.32,87.39 114.9,120.6
+VCC_CORE on IN3: outline of 110 points within 68.49,81.93 114.9,122.18
+VCC_CORE on VCC: 107.65,97.93 107.59,97.98 107.59,99.25 106.96,99.89 106.96,110.68 107.08,110.8 107.08,111.62 105.67,113.04 94.66,113.04 93.37,111.75 93.37,110.35 88.82,105.8 80.31,105.8 79.67,105.17 76.37,105.17 72.69,101.48 69.09,101.48 68.98,101.59 68.98,112.3 70.11,113.42 76.58,113.42 80.77,117.61 82.73,117.61 87.23,122.11 112.26,122.11 114.55,119.82 114.55,114 114.68,113.88 114.68,111.62 114.27,111.21 114.27,110.02 114.42,109.87 114.86,109.87 114.96,109.76 114.96,98.62 114.27,97.93
+VCC_CORE on IN4: outline of 268 points within 69.37,96.34 114.91,117.16
+VCC_GT on TOP (solid shape): outline of 4456 points within 67.68,86.18 105.1,114.44
+VCC_GT on BOTTOM (solid shape): 78.04,99.97 78.04,95.69 76.48,94.12 73.45,94.12 72.52,93.18 72.52,90.31 72.38,90.18 72.38,89.16 72.47,89.08 73.14,89.08 73.28,88.94 73.28,87.77 73.01,87.51 69.1,87.51 68.54,88.06 68.54,89.62 68.64,89.71 69.78,89.71 69.79,89.72 69.79,90.51 69.77,90.52 68.86,90.52 68.61,90.77 68.61,95.48 69.91,96.78 71.8,96.78 72.07,97.05 72.07,99.79 72.45,100.17 77.84,100.17
+VCC_GT on BOTTOM (solid shape): outline of 1838 points within 81.14,97.51 102.39,108.96
+VCC_GT on IN1: outline of 83 points within 74.94,92.47 100.4,106.68
+VCC_GT on IN4: 89.11,96.83 89.11,96.91 88.1,97.93 80.61,97.93 75.96,93.29 75.96,92.15 73.58,89.77 69.55,89.77 68.84,90.48 68.84,93.61 71.02,95.79 71.02,98.17 71,98.19 71,99.06 76.54,104.6 89.24,104.6 89.75,105.11 89.87,105.13 89.93,105.03 90.53,104.75 90.26,105.36 90.16,105.42 90.18,105.53 93.11,108.47 102.13,108.47 102.22,108.38 102.22,107.78 100.75,106.3 100.75,98.33 99.25,96.83
+VCC_GT_+VCC_CORE on TOP (solid shape): outline of 380 points within 101.77,95.23 107.92,114.43
+VCC_GT_+VCC_CORE on BOTTOM (solid shape): outline of 312 points within 102.64,106.92 107.53,108.99
+VCC_GT_+VCC_CORE on BOTTOM (solid shape): outline of 582 points within 102.56,96.37 108.9,99.42
+VCC_GT_+VCC_CORE on IN4 (solid shape): outline of 581 points within 101.24,95.75 107.29,108.19
+VCC_GT_+VCC_CORE on IN1: 101.7,106.3 105.46,106.3 106.16,105.6 106.16,100.1 107.42,98.84 107.42,97.23 106.08,95.88 101.21,95.88 101.01,96.09 101.01,105.61
+VCC_GTUS on BOTTOM (solid shape): outline of 464 points within 98.32,96.96 102.97,99.38
+VCC_SA on TOP (solid shape): 77.55,118.85 77.55,114.52 77.53,114.5 74.51,114.5 74,115.01 74,116.53 72.51,118.03 72.51,118.95 72.67,119.11 77.29,119.11
+VCC_SA on TOP (solid shape): 119.31,99.34 118.75,98.79 117.31,98.79 117.18,98.92 117.18,99.2 117.41,99.43 117.41,100.07 117.58,100.24 119.31,100.24
+VCC_SA on TOP (solid shape): 116.86,108.06 116.86,107.79 117.06,107.59 117.13,107.59 117.23,107.58 117.32,107.59 117.46,107.59 117.6,107.73 117.6,108.05 117.72,108.18 118.61,108.18 118.69,108.1 118.69,107.44 118.64,107.39 118.21,107.39 118.09,107.26 118.09,107.06 117.57,106.54 116.75,106.54 116.47,106.82 116.47,107.6 116.31,107.76 116.31,108.05 116.54,108.28 116.63,108.28
+VCC_SA on TOP (solid shape): 115.97,106.4 115.97,105.62 115.96,105.62 115.96,105.48 115.96,105.48 115.94,105.37 115.96,105.27 115.96,105.26 115.96,105.17 116.11,105.03 116.52,105.03 116.62,105.13 116.62,105.5 116.73,105.61 117.2,105.61 117.22,105.6 117.84,104.99 117.84,104.98 117.97,104.98 117.98,104.98 118.13,104.94 118.27,104.98 118.28,104.98 118.36,104.98 118.75,104.59 118.75,102.6 118.66,102.5 118.62,102.52 118.36,102.54 118.17,102.36 118.15,102.33 117.02,102.33 116.8,102.55 116.8,103 117.02,103.22 117.02,103.79 116.98,103.82 116.98,104 116.62,104.37 115.83,104.37 115.76,104.52 115.61,104.6 115.6,104.6 115.43,104.76 115.43,106.35 115.54,106.45 115.92,106.45
+VCC_SA on BOTTOM (solid shape): 77.81,119.22 77.81,115.41 77.74,115.34 77.74,114.11 77.36,113.72 73.99,113.72 73.74,113.98 73.74,115.11 75.05,115.11 75.05,115.91 73.74,115.91 73.74,116.87 72.48,118.14 72.48,118.95 72.63,119.11 76.91,119.11 77.09,119.28 77.75,119.28
+VCC_SA on BOTTOM (solid shape): 118.94,99.2 118.94,98.35 118.91,98.28 118.91,98.21 118.63,98.19 118.54,97.92 118.11,97.92 117.87,98.25 117.62,97.92 117.53,97.92 117.26,98.2 117.26,98.48 117.18,98.56 117.18,99.13 117.4,99.35 118.78,99.35
+VCC_SA on BOTTOM (solid shape): outline of 337 points within 114.92,107 119.38,109.81
+VCC_SA on IN3: 115.28,99.04 115.28,119.75 112.33,122.69 87.02,122.69 82.57,118.25 80.54,118.25 76.31,114.06 67.27,114.06 65.78,115.54 65.78,116.64 66,116.86 66,117.34 65.95,117.34 65.78,117.51 65.78,122.25 67.81,124.28 71.33,124.28 77.06,130.01 116.09,130.01 119.11,127 119.11,99.07 118.96,98.92 118.35,98.92 118.25,98.82 115.5,98.82 ; 1 cut-out
+VCC_SA on VCC: 115.27,98.69 115.21,98.74 115.21,109.87 114.96,110.12 114.53,110.12 114.53,110.12 114.53,111.11 114.93,111.52 114.93,113.88 115.06,114 115.06,120.03 112.47,122.62 87.02,122.62 82.52,118.12 80.56,118.12 76.37,113.93 71.14,113.93 71.14,123.98 71.3,124.14 75.31,124.14 76.19,123.26 81.6,123.26 82.7,124.37 82.7,127.41 83.95,128.66 86.74,128.66 87.89,129.8 119.55,129.8 119.78,129.57 119.78,117.72 119.4,117.34 119.4,113.65 118.39,112.64 118.39,111.03 118.51,110.9 118.51,106.74 118.26,106.49 118.26,98.74 118.21,98.69
+VCC_SFR_OC on TOP (solid shape): 137.25,71.36 137.25,69.63 137.36,69.52 137.36,69.17 137.22,69.04 134.33,69.04 134.33,69.54 134.39,69.61 135.66,69.61 135.85,69.8 135.85,70.41 135.71,70.54 135.48,70.54 135.39,70.64 135.39,71.29 135.54,71.45 137.16,71.45
+VCC_SFR_OC on IN3: 118.95,98.49 120.16,98.49 120.4,98.24 120.4,95.8 120.09,95.48 118.84,95.48 118.58,95.73 118.58,98.12
+VDDA_AVDD1 on TOP (solid shape): 254.4,56.3 254.86,56.3 254.91,56.35 254.99,56.35 255.01,56.32 255.01,56.14 254.51,55.64 250.28,55.64 250.21,55.7 250.21,56.45 250.37,56.6 254.1,56.6
+VSS_PLL on TOP (solid shape): 251.66,83.93 251.66,82.81 251.29,82.45 251.29,82.39 251.29,82.38 251.27,82.26 251.29,82.13 251.29,82.12 251.29,81.81 251.29,81.8 251.27,81.67 251.29,81.55 251.29,81.54 251.29,80.85 251.42,80.72 251.71,80.72 251.76,80.67 251.76,79.75 251.73,79.72 250.93,79.72 250.82,79.82 250.82,82.69 251.31,83.17 251.31,83.93 251.41,84.03 251.56,84.03
GND on TOP (solid shape): 58.2,95.91 58.11,95.82 57.17,95.82 57.17,97.19 57.22,97.25 58.2,97.25
GND on TOP (solid shape): 10.12,45.48 10.12,44.14 8.85,44.14 8.6,44.4 8.6,45.54 8.79,45.73 9.87,45.73
GND on TOP (solid shape): 90.77,104.98 90.77,104.02 83.78,104.02 83.72,104.09 83.72,104.98 84.03,105.29 90.45,105.29
GND on TOP (solid shape): 236.94,108.72 236.75,108.53 235.86,108.53 235.86,111.26 236.43,111.83 236.43,112.09 236.94,112.09
GND on TOP (solid shape): 247.29,107.83 247.29,107.14 247.04,106.88 244.63,106.88 244.63,107.77 244.94,108.09 247.04,108.09
GND on TOP (solid shape): 50.89,78.42 50.89,77.46 50.5,77.08 48.68,77.08 48.57,77.19 48.57,79.33 48.65,79.41 49.9,79.41
GND on TOP (solid shape): 75.53,112.91 75.53,111.96 75.46,111.9 73.3,111.9 73.24,111.96 73.24,112.91 73.49,113.17 75.27,113.17
GND on TOP (solid shape): 77.24,120.54 77.24,119.4 77.11,119.28 72.9,119.28 72.57,119.61 72.57,120.5 72.67,120.6 77.18,120.6
GND on TOP (solid shape): 90.83,101.48 90.83,100.53 90.77,100.47 83.84,100.47 83.78,100.53 83.78,101.48 84.03,101.74 90.57,101.74
GND on TOP (solid shape): 138.5,128.17 138.5,126.58 138.12,126.2 137.01,126.2 136.81,126.4 136.81,128.28 136.95,128.42 138.26,128.42
GND on TOP (solid shape): 154.63,61.71 154.63,59.62 154.13,59.62 154.13,61 153.69,61.43 153.69,61.66 153.82,61.78 154.56,61.78
GND on TOP (solid shape): 172.57,64.64 172.57,64.2 172.18,63.81 170.79,63.81 170.28,64.32 170.28,64.6 170.92,65.24 171.96,65.24
GND on TOP (solid shape): 177.63,60.77 177.63,60.52 176.89,59.77 176.54,59.77 175.86,60.45 175.86,60.6 176.69,61.43 176.98,61.43
GND on TOP (solid shape): 200.94,59.69 200.94,58.91 200.79,58.76 199.44,58.76 199.25,58.95 199.25,60.26 199.41,60.42 200.22,60.42
GND on TOP (solid shape): 201.29,51.73 201.29,50.56 201.1,50.37 197.12,50.37 196.92,50.57 196.92,51.81 197.1,51.99 201.03,51.99
GND on TOP (solid shape): 239.55,96.61 239.55,93.74 239.04,93.23 238.46,93.23 238.37,93.32 238.37,96.5 238.61,96.74 239.41,96.74
GND on TOP (solid shape): 258.85,68.97 258.85,67.96 256.63,67.96 256.18,68.4 256.18,69.04 257.44,69.04 257.5,69.1 258.72,69.1
GND on TOP (solid shape): 267.42,65.86 267.42,62.88 267.1,62.56 266.22,62.56 266.22,64.65 266.15,64.72 266.15,66.18 267.1,66.18
GND on TOP (solid shape): 278,71.21 278,69.91 277.87,69.78 276.73,69.78 276.64,69.87 276.64,71.35 276.73,71.44 277.77,71.44
GND on TOP (solid shape): 53.22,106.98 53.22,105.08 53.1,104.95 52.61,104.95 52.49,105.07 52.49,107.03 53.17,107.03
GND on TOP (solid shape): 76.1,90.43 76.1,87.7 75.18,86.79 72.33,86.79 71.73,87.39 71.73,90.06 72.29,90.63 75.91,90.63
GND on TOP (solid shape): 44.98,117.1 44.98,116.6 44.09,115.71 42.06,115.71 41.81,115.96 39.65,115.96 39.52,116.09 39.52,117.36 39.77,117.61 44.47,117.61
GND on TOP (solid shape): 68.48,108.54 68.48,104.93 67.96,104.4 66.15,104.4 65.93,104.62 65.93,108.51 66.07,108.65 68.37,108.65
GND on TOP (solid shape): 119.66,128.26 119.98,128.26 120.1,128.13 120.1,127.87 119.53,127.3 118.71,127.3 118.52,127.5 118.52,128.32 118.64,128.45 119.47,128.45
GND on TOP (solid shape): 130.07,82.05 129.98,81.96 129.6,81.96 129.14,82.42 128.69,82.42 128.57,82.54 128.57,83.16 128.67,83.26 128.67,83.77 130.07,83.77
GND on TOP (solid shape): 170.38,78.37 170.38,74.66 168.59,72.87 167.82,72.87 167.73,72.95 167.73,74.04 167.73,74.05 167.73,78.43 168.04,78.75 170,78.75
GND on TOP (solid shape): 240.82,80.15 240.8,80.13 240.8,77.75 240.68,77.63 239.5,77.63 239.2,77.93 239.2,80.25 240.05,81.1 240.82,81.1
GND on TOP (solid shape): 21.39,67.45 21.39,66.66 21.65,66.39 21.65,66.03 20.98,65.35 19.9,65.35 19.9,67.42 19.98,67.5 21.33,67.5
GND on TOP (solid shape): 60.95,133.97 60.95,133.12 60.87,133.04 59.4,133.04 59.18,133.26 58.18,133.26 58.01,133.42 58.01,134.08 58.14,134.21 60.7,134.21
GND on TOP (solid shape): 67.64,117.28 67.64,116.85 67.51,116.72 66.44,116.72 66.27,116.55 66.27,115.66 63.98,115.66 63.78,115.86 63.78,116.97 64.22,117.41 67.51,117.41
GND on TOP (solid shape): 95.59,53.29 96.16,52.72 96.16,52.33 96.04,52.21 92.92,52.21 92.73,52.4 92.73,53.03 92.8,53.1 92.8,55.45 95.59,55.45
GND on TOP (solid shape): 126.96,80.02 127.21,79.77 127.23,79.77 127.33,79.67 129.35,79.67 129.47,79.54 129.47,79.13 128.84,78.5 126.45,78.5 126.45,80.72 126.96,80.72
GND on TOP (solid shape): 207.86,51.19 208.05,51 208.94,51 209.07,50.87 210.78,50.87 210.78,50.43 210.53,50.18 207.73,50.18 207.03,50.87 207.03,52.33 207.86,52.33
GND on TOP (solid shape): 50.32,131.77 50.32,129.36 50.25,129.3 49.74,129.3 49.62,129.42 49.62,131.77 49.81,131.96 50.13,131.96
GND on TOP (solid shape): 63.78,103.39 63.78,102.88 63.65,102.75 63.33,102.75 63.14,102.56 63.14,100.85 63.08,100.79 61.3,100.79 61.3,103.71 63.46,103.71
GND on TOP (solid shape): 149.57,128.79 149.57,125.68 149.42,125.53 148.46,125.53 148.23,125.76 148.23,128.79 148.36,128.92 149.44,128.92
GND on TOP (solid shape): 254.08,65.55 255.07,65.55 255.15,65.47 255.15,64.58 254.9,64.32 253.03,64.32 252.91,64.45 252.91,65.84 253,65.92 253.71,65.92
GND on TOP (solid shape): 275.14,92.54 275.14,90.21 275.59,89.76 275.59,89.43 275.52,89.36 274.47,89.36 274.02,89.81 274.02,92.43 274.19,92.61 275.07,92.61
GND on TOP (solid shape): 282.63,65.61 282.63,64.48 282.52,64.37 281.55,64.37 281.5,64.42 281.5,65.49 281.18,65.82 281.18,66.13 281.31,66.26 281.98,66.26
GND on TOP (solid shape): 69.68,56.59 70.25,56.59 70.32,56.53 70.32,55.83 70.19,55.7 66,55.7 65.78,55.92 65.78,56.81 65.89,56.91 69.37,56.91
GND on TOP (solid shape): 273.65,127.71 273.65,127.33 273.52,127.2 273.2,127.2 272.44,127.96 271.11,127.96 270.34,128.73 268.69,128.73 268.69,129.04 268.76,129.11 272.25,129.11
GND on TOP (solid shape): 124.55,128.13 124.55,127.13 124.43,127.02 123.05,127.02 122.66,126.62 122.35,126.62 122.28,126.69 122.28,127.7 122.83,128.26 124.42,128.26
GND on TOP (solid shape): 38.33,57.01 38.33,54.65 38.45,54.52 39.01,54.52 39.01,52.54 38.89,52.41 38.61,52.41 38.5,52.51 38.5,53.48 38.02,53.96 37.29,53.96 37.26,53.99 37.26,57.19 38.15,57.19
GND on TOP (solid shape): 139.34,71.13 139.34,69.04 139.53,68.84 139.53,68.34 139.03,68.34 138.33,69.04 137.82,69.04 137.82,69.04 137.74,69.04 137.63,69.16 137.63,69.67 137.5,69.8 137.5,71.26 137.6,71.35 139.12,71.35
GND on TOP (solid shape): 24.38,99.09 24.38,97.59 24.26,97.47 23.81,97.47 23.72,97.38 23.72,96.98 23.63,96.89 23.37,96.89 23.29,96.96 23.29,99.11 23.41,99.22 24.24,99.22
GND on TOP (solid shape): 64.21,66.66 64.21,63.38 65.54,62.05 65.54,58.33 65.4,58.19 64.77,58.19 64.54,58.41 64.54,61.08 64.38,61.24 63.8,61.24 63.4,60.84 62.89,60.84 62.79,60.95 62.79,66.63 63.01,66.86 64.01,66.86
GND on TOP (solid shape): 72.57,70.78 72.57,67.89 72.31,67.63 72.31,67.59 72.2,67.48 71.61,67.48 71.35,67.74 71.35,70.26 71.11,70.5 70.15,70.5 69.98,70.34 69.73,70.34 69.48,70.59 69.48,70.8 69.98,71.3 72.04,71.3
GND on TOP (solid shape): 158.01,58.81 157.38,58.18 156.67,58.18 156.51,58.33 156.13,58.33 155.98,58.18 155.32,58.18 155.32,58.53 156.08,58.53 156.41,58.86 156.97,58.86 157.12,59.02 157.12,60.77 158.01,60.77
GND on TOP (solid shape): 179.32,53.88 179.41,53.79 181.44,53.79 181.57,53.66 181.57,53.2 181.42,53.06 180.65,53.06 180.65,53.06 180.58,52.99 178.71,52.99 177.89,53.81 177.89,54.41 178.08,54.6 178.6,54.6
GND on TOP (solid shape): 210.06,57.21 210.06,56.75 210.05,56.75 210.05,55.16 209.9,55.01 208.34,55.01 208.2,55.15 208.2,55.56 208.3,55.66 208.89,55.66 209.08,55.85 209.08,57.21 209.17,57.3 209.97,57.3
GND on TOP (solid shape): 161.19,84.93 161.19,81.46 161.08,81.35 160.39,81.35 160.33,81.41 160.33,83.49 160.28,83.55 159.88,83.55 159.77,83.65 159.77,85.13 159.89,85.24 160.88,85.24
GND on TOP (solid shape): 250.79,65.99 250.79,64.46 250.4,64.08 250.4,62.53 249.91,62.04 249.2,62.04 249.01,62.23 249.01,62.81 249.39,63.19 249.39,64.78 249.01,65.16 249.01,65.73 249.32,66.05 250.72,66.05
GND on TOP (solid shape): 267.8,58.24 267.8,54.49 266.79,53.48 264.5,53.48 263.8,54.18 263.8,54.99 263.85,55.04 264.39,55.04 265.07,54.37 266.09,54.37 266.28,54.56 266.28,56.14 266.72,56.59 266.72,58.68 266.85,58.81 267.23,58.81
GND on TOP (solid shape): 63.88,131.39 63.89,131.38 63.96,131.28 64.06,131.21 64.07,131.2 64.16,131.11 64.16,128.46 64.03,128.33 63.5,128.33 62.94,128.89 62.94,130.88 62.51,131.31 62.51,131.87 62.69,132.05 63.23,132.05
GND on TOP (solid shape): 32.15,90.48 32.3,90.42 32.45,90.42 32.48,90.43 32.79,90.12 32.79,88.62 32.3,88.13 30.91,88.13 30.43,88.62 28.46,88.62 28.32,88.76 28.32,89.16 27.49,89.99 27.49,90.4 27.57,90.48
GND on TOP (solid shape): 45.55,79.79 45.55,73.86 45.55,73.86 45.55,73.56 45.25,73.26 42.92,73.26 42.53,72.87 42.53,69.85 42.37,69.69 41.88,69.69 41.71,69.86 41.71,70.55 41,71.26 39.58,71.26 39.39,71.45 39.39,73.36 44.04,78 44.04,79.76 44.15,79.88 45.46,79.88
GND on TOP (solid shape): 177.7,50.94 177.7,50.39 177.89,50.2 179.73,50.2 179.83,50.1 179.83,49.52 179.8,49.48 174.84,49.48 174.77,49.56 174.77,50.81 175.09,51.14 177.51,51.14
GND on TOP (solid shape): 240.73,63.72 240.73,61.56 240.67,61.5 239.74,61.5 239.69,61.55 239.69,61.57 239.57,61.91 239.34,62.19 239.34,63.76 239.5,63.92 240.54,63.92
GND on TOP (solid shape): 244.64,82.46 244.64,82.28 244.08,81.72 244.08,81.1 243.84,80.86 243.84,80.25 243.77,80.19 243.09,80.19 243.04,80.23 243.04,81.16 243.04,81.17 243.04,81.39 243.22,81.57 243.22,82.28 243.36,82.42 244,82.42 244.21,82.62 244.47,82.62
GND on TOP (solid shape): 118.31,128.69 118.34,128.66 118.34,123.43 116.67,121.75 116.46,121.75 116.46,121.63 116.29,121.63 116.22,121.55 116.08,121.55 114.63,120.1 111.75,120.1 111.37,120.48 111.37,120.95 111.13,121.19 106.16,121.19 104.93,122.42 104.93,132.12 105.53,132.72 114.27,132.72
GND on TOP (solid shape): 53.16,87.8 53.16,85.75 51.7,84.29 51.7,82.01 51.62,81.93 50.41,81.93 50.35,81.99 50.35,84.24 50.76,84.66 51.17,84.66 51.53,85.01 51.53,86.52 52.38,87.38 52.38,87.76 52.47,87.85 53.12,87.85
GND on TOP (solid shape): 24.19,102.35 24.19,101.87 24.39,101.67 24.39,101.37 24.56,101.2 24.71,101.2 24.76,101.15 24.76,100.65 25.01,100.4 25.01,100.18 24.9,100.07 24,100.07 23.9,100.16 23.9,100.39 23.8,100.49 22.15,100.49 22.12,100.52 22.12,101.99 22.53,102.4 24.15,102.4
GND on TOP (solid shape): 124.04,83.39 123.79,83.13 123.79,82.31 123.86,82.24 124.68,82.24 124.8,82.36 124.8,82.75 124.99,82.94 125.25,82.94 125.36,82.83 125.36,82.14 125.08,81.86 124.48,81.86 124.17,81.54 123.53,81.54 123.47,81.61 123.47,81.99 122.2,83.26 121.75,83.26 121.69,83.32 121.69,83.77 121.75,83.83 124.04,83.83
GND on TOP (solid shape): 164.32,88.31 164.32,86.18 164.24,86.1 163.86,86.1 163.77,86 163.77,85.79 163.71,85.59 163.77,85.4 163.77,85.21 164.02,84.96 164.02,82.91 163.84,82.74 163.1,82.74 163.02,82.81 163.02,88.25 163.26,88.48 164.15,88.48
GND on TOP (solid shape): 282.92,55.76 282.92,54.94 282.76,54.78 282.45,54.78 282.34,54.89 282.21,54.97 282.16,54.99 281.89,55.04 281.63,54.99 280.73,54.99 280.59,55.13 280.59,55.81 280.77,55.99 282.69,55.99
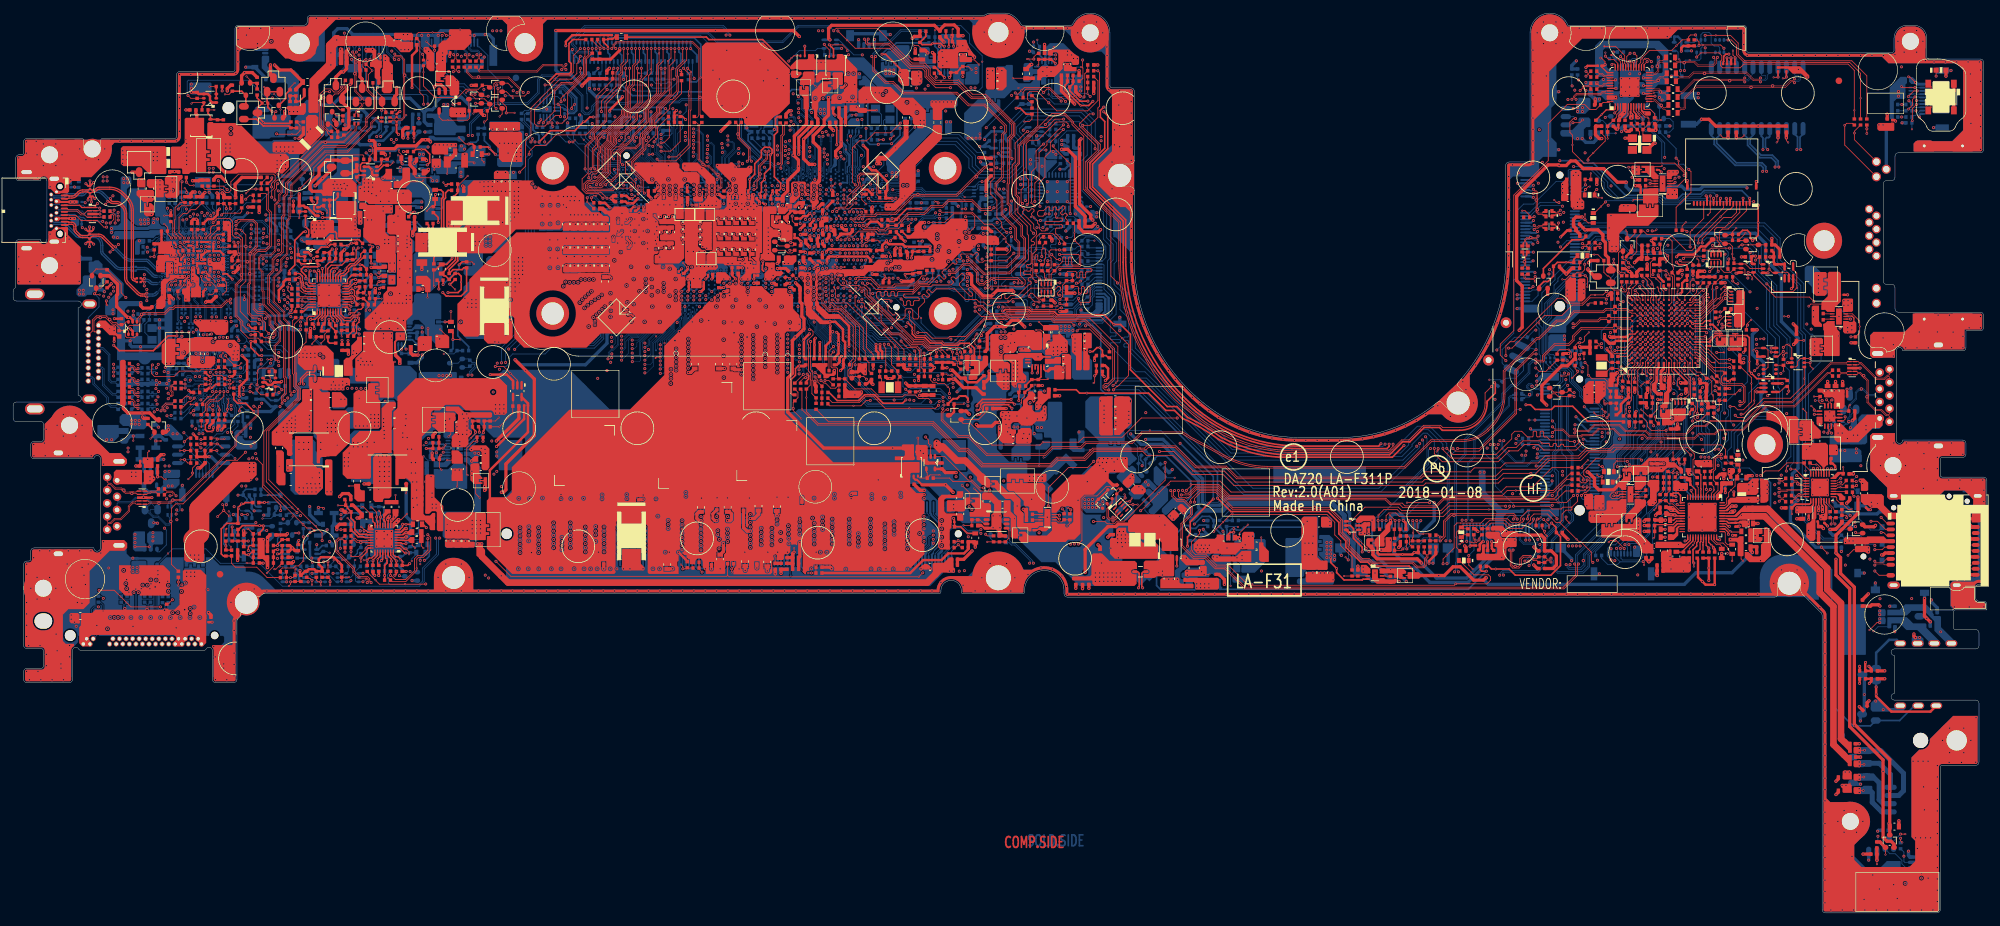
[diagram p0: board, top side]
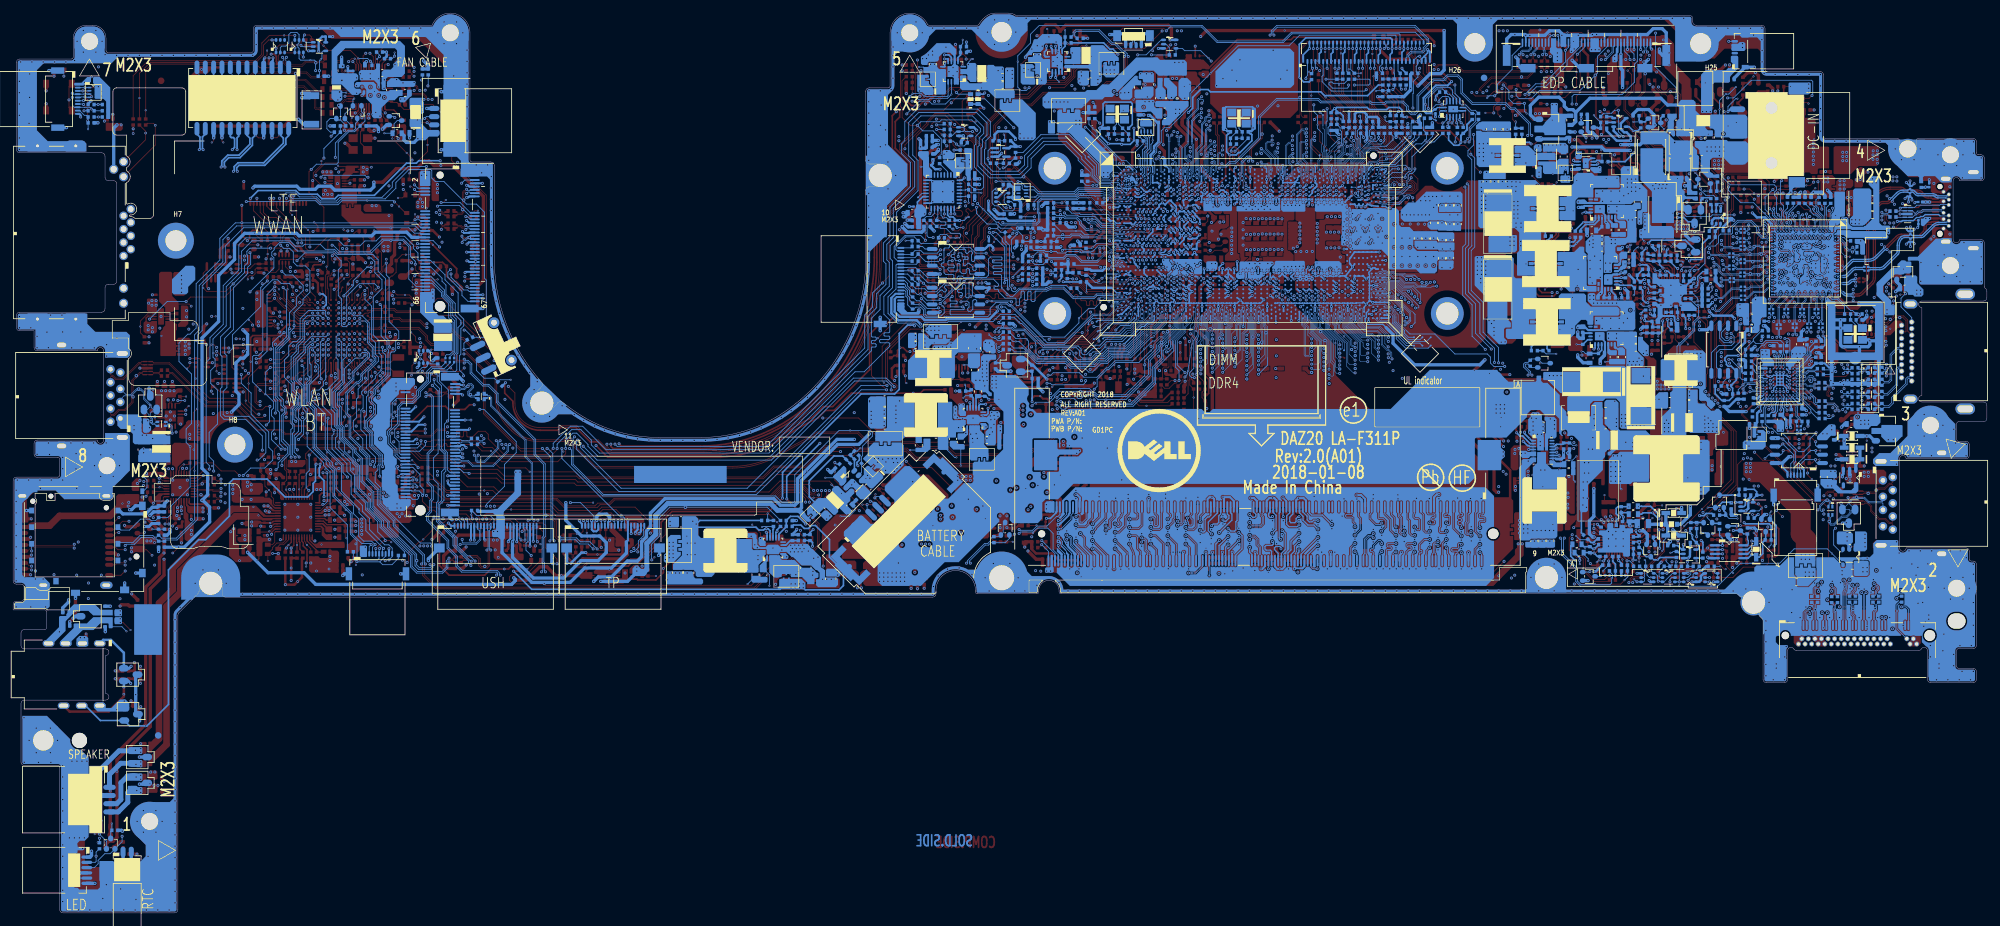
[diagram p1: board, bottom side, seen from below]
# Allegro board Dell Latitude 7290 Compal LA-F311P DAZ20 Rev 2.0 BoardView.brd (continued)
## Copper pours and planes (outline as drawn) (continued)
GND on TOP (solid shape): 59.72,88.5 59.72,87.34 59.67,87.3 58.57,87.3 58.35,87.08 58.35,85.77 58.51,85.61 58.51,85.16 59.17,84.49 59.17,83.65 59.09,83.57 58.72,83.57 58.63,83.66 58.63,84.28 58.01,84.9 58.01,87.12 58.26,87.37 58.26,88.42 58.37,88.52 59.7,88.52
GND on TOP (solid shape): 206.78,59.5 206.78,59.07 206.63,58.92 206.28,58.92 206.18,58.81 206.18,57.78 205.94,57.55 205.05,57.55 204.96,57.63 204.96,57.97 205.07,58.08 205.19,58.08 205.3,58.1 205.39,58.16 205.46,58.16 205.57,58.27 205.57,58.67 205.37,58.87 204.56,58.87 204.5,58.93 204.5,59.2 204.56,59.26 205.44,59.26 205.76,59.57 206.71,59.57
GND on TOP (solid shape): 57.69,77.95 58.07,77.95 58.29,77.73 58.29,77.11 57.68,76.5 57.68,70.14 57.63,70.09 55.05,70.09 54.51,69.54 54.51,66.37 54.32,66.18 50.89,66.18 50.2,66.87 50.2,70.18 51.6,71.58 51.6,72.31 52.76,73.47 55.8,73.47 56.13,73.81 56.13,76.95 57.13,77.95 57.48,77.95
GND on TOP (solid shape): 189.05,57.99 189.05,56.46 189.06,56.46 189.06,55.51 189,55.45 187.03,55.45 186.21,54.62 184.05,54.62 183.89,54.77 181.86,54.77 181.84,54.8 180.41,54.8 179.82,55.39 179.82,56.28 180.6,57.06 183.08,57.06 183.35,57.33 183.35,57.64 183.38,57.67 184.35,57.67 184.5,57.52 184.5,56.68 184.72,56.46 187.01,56.46 187.22,56.68 187.22,57.64 187.25,57.67 187.25,57.86 187.5,58.11 188.92,58.11
GND on TOP (solid shape): 55.33,131.54 55.33,130.38 55.73,129.98 56.13,129.98 56.18,129.92 56.18,128.94 55.9,128.66 55.9,127.15 55.85,127.1 55.34,127.1 55.07,127.36 55.07,128.02 55.08,128.03 55.08,128.79 54.88,128.99 54.44,128.99 54.37,129.07 54.37,129.68 54.46,129.77 54.53,129.78 54.75,130 54.75,130.99 54.57,131.16 53.73,131.16 53.55,131.34 53.55,131.84 53.62,131.9 54.98,131.9
GND on TOP (solid shape): 55.97,112.07 55.96,112.05 56.07,111.75 56.37,111.64 56.4,111.64 56.47,111.57 57.46,111.57 57.68,111.35 57.68,110.5 57.87,110.31 60.27,110.31 60.75,109.83 60.75,108.27 60.56,108.08 54.21,108.08 53.78,108.52 52.83,108.52 52.6,108.74 52.6,109.38 52.6,110.76 52.73,110.88 53.11,110.88 53.19,110.96 53.19,111.94 53.37,112.13 55.91,112.13
GND on TOP (solid shape): 68.76,76.34 72.81,76.34 72.97,76.18 72.97,75.69 72.79,75.5 69.76,75.5 69.37,75.11 69.37,73.86 69.62,73.61 69.7,73.61 69.89,73.43 69.89,73.02 69.37,72.5 69.37,71.45 68.92,71 66.95,71 66.83,71.13 66.83,72.65 67.4,73.23 67.4,74.81 67.78,75.19 67.78,75.95 67.25,76.48 66.01,76.48 65.89,76.59 65.89,77.15 65.95,77.21 67.89,77.21
GND on TOP (solid shape): 156.76,85.34 156.76,85.09 156.91,84.94 158.1,84.94 158.15,84.89 158.15,84.74 158.06,84.65 157,84.65 156.55,84.2 155.64,84.2 155.19,84.65 154.05,84.65 153.84,84.44 153.84,82.37 154.35,81.86 154.35,81.05 154.07,80.77 153.04,80.77 152.91,80.65 152.91,80.17 152.87,80.13 152.47,80.13 152.09,80.51 152.09,83.76 151.61,84.23 151.11,84.23 150.9,84.44 150.9,84.98 151.11,85.19 152.97,85.19 153.17,85.39 156.71,85.39
GND on TOP (solid shape): 226.51,57.95 226.51,57.52 226.87,57.16 228.88,57.16 229.08,56.96 229.08,55.92 228.94,55.78 227.76,55.78 227.49,55.52 227.49,54.15 227.1,53.75 223.09,53.75 222.93,53.91 222.93,54.67 223.06,54.8 223.58,54.8 223.77,54.99 223.77,56.08 223.89,56.2 224.29,56.2 224.34,56.15 224.34,55.78 224.22,55.65 224.22,54.89 224.35,54.75 225.96,54.75 226.09,54.88 226.09,55.65 225.96,55.78 225.76,55.78 225.72,55.82 225.72,56.8 225.47,57.04 224.69,57.04 224.32,57.41 224.32,57.92 224.53,58.14 226.32,58.14
GND on TOP (solid shape): 145.23,133.11 145.78,131.75 146.69,130.62 146.71,130.6 146.71,130.31 146.65,130.25 146.54,130.25 146.52,130.27 146.37,130.27 146.2,130.44 146.2,130.45 146.05,130.61 146.03,130.61 145.95,130.69 145.55,130.69 145.46,130.78 145.46,131.16 145.36,131.27 144.17,131.27 143.98,131.07 143.98,128.79 141.12,128.79 140.87,129.04 140.87,131.27 141.31,131.71 143.34,131.71 143.72,132.09 143.72,133.11
GND on TOP (solid shape): 84.3,98.94 84.34,98.94 84.43,98.92 85.36,98.92 85.45,98.94 85.48,98.94 85.51,98.94 85.54,98.94 85.63,98.92 90.66,98.92 90.83,98.75 90.83,97.74 90.77,97.67 83.84,97.67 83.83,97.71 83.81,97.75 83.81,98.62 84.11,98.92 84.24,98.94 84.28,98.94
GND on TOP (solid shape): 26.98,96.51 26.98,96.25 27.01,96.23 27.01,96.13 27.16,95.98 27.29,95.98 27.29,95.98 27.51,95.98 27.6,95.89 27.6,95.67 27.46,95.53 27.16,95.53 27.13,95.51 27.07,95.51 26.99,95.42 26.99,95.36 26.98,95.36 26.98,93.82 26.99,93.82 26.99,93.31 26.87,93.19 26.14,93.19 26.03,93.29 26.03,94.16 25.74,94.45 25.74,95.08 25.89,95.23 26.26,95.23 26.42,95.39 26.42,95.64 26.42,95.64 26.44,95.75 26.42,95.86 26.42,95.86 26.42,95.95 26.5,96.02 26.5,96.45 26.67,96.63 26.86,96.63
GND on TOP (solid shape): 150.18,62.94 150.42,62.94 150.54,62.81 150.54,58.02 150.82,57.75 151.43,57.75 151.43,57.24 149.99,57.24 149.99,58.2 149.76,58.43 147.98,58.43 147.65,58.76 147.64,58.76 147.63,58.77 147.6,58.77 147.59,58.78 147.44,58.81 147.29,58.78 147.28,58.77 146.73,58.77 146.7,58.81 146.7,59.34 146.73,59.37 147.5,59.37 147.77,59.1 147.8,59.06 147.84,59.03 147.98,58.89 148.92,58.89 149.06,59.03 149.06,60.76 149.45,61.15 149.45,62.3 148.78,62.98 147.7,62.98 147.57,63.1 147.57,63.88 147.82,64.12 148.99,64.12
GND on TOP (solid shape): 106.45,105.39 106.45,101.14 106.36,101.04 105.65,101.04 105.35,101.34 104.96,101.34 104.82,101.48 104.82,101.84 104.75,101.91 104.6,101.91 104.46,102.05 104.46,102.32 104.55,102.41 104.74,102.41 104.76,102.43 104.9,102.43 105.01,102.55 105.01,102.68 105.02,102.69 105.02,102.98 105.01,103.04 104.9,103.15 104.85,103.15 104.84,103.16 104.56,103.16 104.44,103.28 104.44,103.5 104.58,103.64 104.91,103.64 105.01,103.74 105.01,104.22 104.89,104.35 104.85,104.35 104.81,104.38 104.54,104.38 104.45,104.47 104.45,104.71 104.52,104.78 104.74,104.78 104.79,104.82 104.79,104.82 105.01,105.03 105.01,105.04 105.02,105.06 105.02,105.29 105.15,105.42 106.43,105.42
GND on TOP (solid shape): 161.19,131.39 161.22,131.39 161.67,131 162.17,130.68 162.28,130.62 162.39,130.5 162.39,129.49 162.2,129.3 161.44,129.3 161.38,129.36 161.38,129.55 161.12,129.8 160.17,129.8 159.92,129.55 159.92,128.72 158.65,127.46 156.87,127.46 156.63,127.21 156.63,127.02 156.56,126.95 156.07,126.95 156.03,127 156.03,128.52 156.61,129.11 158.84,129.11 159.22,129.49 159.22,131.01 159,131.23 158.51,131.23 158.41,131.12 158.41,130.76 158.35,130.71 157.72,130.71 157.62,130.81 157.62,131.45 157.82,131.65 160.93,131.65
GND on TOP (solid shape): 27.63,85.01 27.85,84.92 28.08,85 28.1,85.01 28.2,85.01 28.22,85 28.34,84.92 28.47,84.9 28.49,84.9 28.55,84.84 28.55,84.78 28.55,84.77 28.53,84.64 28.55,84.52 28.55,84.51 28.55,84.27 28.51,84 28.66,83.78 28.68,83.76 28.7,83.76 28.85,83.72 29.01,83.76 29.02,83.76 29.11,83.76 29.24,83.9 29.24,84.78 29.35,84.89 30.68,84.89 30.79,84.78 30.79,83.76 30.1,83.06 27.02,83.06 26.44,83.64 26.44,84.44 27.01,85.01
GND on TOP (solid shape): 299.7,91.39 299.91,91.31 299.99,91.1 299.99,89.25 299.91,89.04 299.7,88.96 297.31,88.96 297.31,86.2 297.22,85.99 297.01,85.91 288.08,85.91 288.06,85.94 287.28,86.4 286.69,85.7 286.69,84.66 283.23,84.66 282.92,84.97 282.92,88.09 283.42,88.59 288.17,88.59 289.4,89.82 289.4,91.33 289.46,91.39
GND on TOP (solid shape): 12.1,74.99 12.1,72.71 14.69,70.11 16.39,70.11 17.35,69.16 17.35,68.55 16.94,68.15 13.5,68.15 13.5,69.25 12.9,69.95 12.13,69.45 3.18,69.45 2.98,69.54 2.89,69.75 2.89,71.4 2.98,71.61 3.18,71.7 4.3,71.7 4.66,71.84 4.8,72.2 4.8,74.55 6.78,76.53 10.55,76.53
GND on TOP (solid shape): 114.52,107.75 114.62,107.74 114.69,107.75 116.14,107.75 116.32,107.56 116.32,106.7 116.18,106.56 115.38,106.56 115.33,106.51 115.33,104.68 115.77,104.25 116,104.25 116,104.24 116.42,104.24 116.92,103.74 116.92,103.27 116.67,103.02 115.77,103.02 115.49,102.75 115.49,102.41 115.49,102.34 115.49,102.27 115.49,101.11 115.49,101.04 115.49,100.86 115.62,100.72 115.67,100.68 116.08,100.26 116.08,99.51 116,99.43 114.52,99.43 114.51,99.45 114.22,99.63 113.93,99.46 113.89,99.44 113.85,99.45 113.81,99.49 113.81,99.86 113.87,99.92 113.87,100.43 113.92,100.48 114.08,100.48 114.16,100.56 114.17,100.56 114.17,100.57 114.2,100.59 114.2,107.54 114.42,107.76 114.51,107.76
GND on TOP (solid shape): 34.12,44.72 33.48,49.52 38.25,48.65 38.17,48.65 38.06,48.63 37.96,48.56 37.74,48.34
GND on TOP (solid shape): 155.73,79.1 155.73,78.04 155.33,77.64 154.57,78 155.28,77.55 155.28,76.74 155.68,76.34 156.38,76.34 156.82,76.78 156.82,77.19 156.99,77.36 157.28,77.36 157.44,77.21 157.44,75.26 157.12,74.94 155.85,74.94 155.22,74.31 153.63,74.31 153.12,74.81 152.3,74.81 151.99,74.51 151.99,73.91 152.19,73.72 152.71,73.72 152.78,73.64 152.78,73.14 152.57,72.93 152.57,71.92 152.24,71.59 150.79,71.59 150.01,72.37 150.01,74.19 150.16,74.34 150.57,74.34 150.64,74.42 150.64,75.32 150.33,75.64 150.33,76.29 150.56,76.52 153.05,76.52 153.84,77.31 153.84,78.1 154.63,78.89 154.63,79.41 154.73,79.5 155.33,79.5
GND on TOP (solid shape): 146.1,51.07 150.14,55.1 154.1,51 154.1,50.32 153.95,49.77 153.9,49.2 153.9,48.95 153.87,48.88 153.8,48.85 146.1,48.85
GND on TOP (solid shape): outline of 101 points within 53.56,88.69 60.83,107.91
GND on TOP (solid shape): outline of 123 points within 0.6,95.81 10.32,104.66
GND on TOP (solid shape): 10.3,111.6 7.84,111.6 7.8,111.61 7.76,111.63 7.59,112.61 6.71,113.06 5.84,113.06 5.2,112.85 4.8,112.31 4.31,112.24 3.99,111.86 3.98,111.83 3.09,111.83 3.02,111.86 2.99,111.94 3.63,113.18 2.55,114.06 1.25,114.06 0.94,114.01 0.65,113.88 0.62,113.92 0.6,113.97 0.6,115.1 0.69,115.31 0.9,115.4 1.3,115.4 1.66,115.54 1.8,115.9 1.8,117.6 1.89,117.81 2.1,117.9 10.3,117.9
GND on TOP (solid shape): outline of 137 points within 97.72,99.02 102.26,106.41
GND on TOP (solid shape): 286.69,72.1 287.28,71.4 288.06,71.86 288.08,71.89 297.01,71.89 297.22,71.81 297.31,71.6 297.31,69.95 297.22,69.74 297.01,69.66 293.9,69.66 293.54,69.51 293.39,69.15 293.39,66.75 293.54,66.39 293.9,66.24 300.2,66.24 300.41,66.16 300.49,65.95 300.49,50.63 300.41,50.42 300.2,50.34 299.5,50.34 299,50.13 298.79,49.63 298.79,48.03 299,47.53 299.5,47.32 300.2,47.32 300.41,47.24 300.49,47.03 300.49,46.41 295.9,46.41 295.79,46.39 295.69,46.36 295.17,46.87 295.17,50.18 295.49,50.49 298.73,50.49 299.09,50.71 299.5,50.79 300.04,50.79 300.04,59.32 299.79,59.57 298.41,59.57 298.41,61.42 298.6,61.61 298.6,63.07 297.27,64.4 294.22,64.4 292.89,63.07 285.84,63.07 285.52,63.38 285.52,64.84 282.92,67.45 282.92,72.78 283.3,73.16 286.69,73.16
GND on TOP (solid shape): outline of 217 points within 140.92,55.41 144.75,64.27
GND on TOP (solid shape): outline of 261 points within 1.81,35.31 17.38,56.86
GND on TOP (solid shape): outline of 532 points within 16.13,48.38 23.9,53.01
GND on TOP (solid shape): outline of 719 points within 30.32,0.21 299.29,54.15
GND on TOP (solid shape): outline of 1281 points within 0.61,71.84 299.99,136.99
GND on BOTTOM (solid shape): 83.46,107.83 83.46,106.88 80.16,106.88 80.16,107.9 80.41,108.15 83.15,108.15
GND on BOTTOM (solid shape): 236.57,88.1 236.57,85.71 233.91,85.71 233.88,85.74 233.88,87.92 234.19,88.23 236.45,88.23
GND on BOTTOM (solid shape): 64.99,133.99 64.99,132.23 64.82,132.05 64.2,132.05 64.07,132.18 64.07,133.98 64.23,134.14 64.85,134.14
GND on BOTTOM (solid shape): 76.73,112.98 76.73,111.96 76.67,111.9 73.37,111.9 73.3,111.96 73.3,112.91 73.56,113.17 76.54,113.17
GND on BOTTOM (solid shape): 83.53,99.39 83.53,98.25 83.34,98.05 81.56,98.05 81.24,98.37 81.24,99.39 81.3,99.45 83.46,99.45
GND on BOTTOM (solid shape): 117.54,128.31 117.54,125.9 117.44,125.8 106.07,125.8 105.53,126.33 105.53,131.18 106.17,131.82 114.03,131.82
GND on BOTTOM (solid shape): 138.54,128.28 138.54,126.55 138.17,126.18 137.04,126.18 136.8,126.42 136.8,128.32 136.91,128.43 138.38,128.43
GND on BOTTOM (solid shape): 177.64,60.84 177.64,60.53 176.87,59.76 176.58,59.76 175.89,60.45 175.89,60.59 176.66,61.36 177.12,61.36
GND on BOTTOM (solid shape): 281.58,70.43 281.58,68.78 281.52,68.72 276.88,68.72 276.82,68.78 276.82,70.43 277.2,70.81 281.2,70.81
GND on BOTTOM (solid shape): 164.37,88.25 164.37,86.25 164.25,86.13 163.37,86.13 162.99,86.5 162.99,88.24 163.2,88.45 164.16,88.45
GND on BOTTOM (solid shape): 8.51,38.64 8.51,36.4 8.41,36.3 7.22,36.3 7.07,36.45 7.07,38.49 7.27,38.69 8.46,38.69
GND on BOTTOM (solid shape): 11.62,45.37 11.62,43.2 11.51,43.08 9.72,43.08 8.6,44.21 8.6,45.54 8.72,45.67 11.33,45.67
GND on BOTTOM (solid shape): 25.44,67.47 25.44,66.52 25.22,66.3 22.95,66.3 22.88,66.37 22.88,67.38 23.07,67.57 25.33,67.57
GND on BOTTOM (solid shape): 30.19,126.5 30.19,124.85 30.12,124.79 27.2,124.79 26.82,125.17 26.82,126.5 26.95,126.63 30.06,126.63
GND on BOTTOM (solid shape): 32.31,38.49 32.31,36.46 32.15,36.31 30.96,36.31 30.86,36.41 30.86,38.64 30.91,38.7 32.1,38.7
GND on BOTTOM (solid shape): 33.55,74.69 32.35,74.69 32.03,74.37 32.03,73.48 31.9,73.35 31.01,73.35 30.88,73.48 30.88,74.88 31.2,75.19 33.55,75.19
GND on BOTTOM (solid shape): 63.46,134.06 63.46,131.9 63.56,131.81 63.56,131.23 63.43,131.1 63.13,131.1 62.12,132.11 62.12,134.07 62.18,134.12 63.4,134.12
GND on BOTTOM (solid shape): 75.91,103.13 75.91,100.72 71.88,100.72 71.58,101.03 71.58,103.25 71.69,103.37 75.67,103.37
GND on BOTTOM (solid shape): 77.56,67.52 74.06,67.52 73.98,67.61 73.98,69.03 73.46,69.56 73.46,70.37 74.09,71 74.09,72.07 77.56,72.07
GND on BOTTOM (solid shape): 111.96,122.78 112.02,122.72 112.02,119.5 111.93,119.42 111.44,119.42 111.35,119.51 111.35,122.65 111.48,122.78 111.89,122.78
GND on BOTTOM (solid shape): 142.96,120.86 143.05,120.78 143.05,118.88 143.03,118.86 142.05,118.86 141.97,118.94 141.97,120.79 142.04,120.86 142.85,120.86
GND on BOTTOM (solid shape): 163.22,73.46 163.22,71.68 162.33,71.68 162.27,71.74 162.27,72.88 162.14,73.01 162.14,73.39 162.33,73.58 163.09,73.58
GND on BOTTOM (solid shape): 243.71,126.73 243.71,125.97 243.69,125.94 239.67,125.94 239.42,126.2 239.42,126.73 239.55,126.86 241.63,126.86 242.06,127.29 243.15,127.29
GND on BOTTOM (solid shape): 170.46,78.4 170.46,74.26 170.05,73.85 168.12,73.85 167.73,74.24 167.73,78.56 167.92,78.75 170.1,78.75
GND on BOTTOM (solid shape): 200.95,60.09 200.95,58.89 200.83,58.77 199.42,58.77 199.27,58.92 199.26,58.92 199.26,60.32 199.34,60.41 200.63,60.41
GND on BOTTOM (solid shape): 280.94,75.33 280.94,73.42 280.76,73.24 280.03,73.24 279.68,73.59 279.68,74.15 279.95,74.43 279.95,75.21 280.12,75.39 280.88,75.39
GND on BOTTOM (solid shape): 50.91,78.42 50.91,77.35 50.44,76.87 48.77,76.87 48.56,77.09 48.56,79.29 48.66,79.4 49.93,79.4
GND on BOTTOM (solid shape): 53.15,87.81 53.15,85.74 52.29,84.89 51.67,84.89 51.51,85.05 51.51,86.49 52.38,87.37 52.38,87.77 52.46,87.84 53.12,87.84
GND on BOTTOM (solid shape): 67.64,117.23 67.64,116.17 67.54,116.06 65.33,116.06 65.15,115.89 63.78,115.89 63.78,116.98 64.22,117.42 67.45,117.42
GND on BOTTOM (solid shape): 85.24,105.17 85.24,104.66 84.8,104.21 83.72,104.21 83.53,104.02 80.16,104.02 80.1,104.09 80.1,105.1 80.29,105.29 82.64,105.29 82.8,105.46 84.95,105.46
GND on BOTTOM (solid shape): 159.1,116.15 159.1,115.02 158.99,114.92 157.56,114.92 157.25,115.23 157.25,115.87 157.3,115.92 157.58,115.92 157.98,116.32 158.92,116.32
GND on BOTTOM (solid shape): 116.55,122.8 116.55,119.39 116.39,119.23 115.86,119.23 115.75,119.34 115.75,119.57 115.79,119.62 115.87,119.62 115.87,119.69 115.89,119.72 115.89,122.82 115.98,122.91 116.44,122.91
GND on BOTTOM (solid shape): 69.68,56.59 70.25,56.59 70.32,56.53 70.32,55.83 70.19,55.7 65.92,55.7 65.78,55.84 65.78,56.81 65.89,56.91 69.37,56.91
GND on BOTTOM (solid shape): 149.59,128.73 149.59,125.8 149.49,125.7 148.48,125.7 148.19,125.99 148.19,128.08 148.19,128.08 148.19,128.79 148.31,128.91 149.41,128.91
GND on BOTTOM (solid shape): 67.6,82.37 67.6,81.33 67.5,81.23 66.92,81.23 66.88,81.19 66.88,81.19 64.93,79.24 62.18,79.24 61.77,79.65 61.77,82.25 62,82.49 67.48,82.49
GND on BOTTOM (solid shape): 129.21,128.02 129.21,127.19 129.18,127.16 128.68,127.16 128.58,127.05 128.58,126.78 128.41,126.61 127.02,126.61 126.9,126.73 126.9,127.97 127.1,128.16 129.06,128.16
GND on BOTTOM (solid shape): 25.87,72.67 25.87,72.27 25.68,72.08 24.41,72.08 23.73,72.76 23.07,72.76 23.02,72.81 23.02,74.27 23.24,74.5 24.04,74.5
GND on BOTTOM (solid shape): 87.21,102.43 87.21,101.65 86.7,101.14 83.63,101.14 83.48,100.99 81.24,100.99 81.11,101.12 81.11,102.18 81.16,102.23 83.68,102.23 83.96,102.5 87.13,102.5
GND on BOTTOM (solid shape): 21.73,52.59 21.92,52.54 22.1,52.59 22.19,52.59 22.31,52.46 22.31,51.7 21.94,51.33 20.85,51.33 20.79,51.39 20.79,52.46 20.92,52.59
GND on BOTTOM (solid shape): 22.86,57.95 22.86,56.36 22.69,56.18 21.44,56.18 21.26,56.01 21.26,55.29 21.09,55.12 20.79,55.12 20.66,55.24 20.66,56.27 20.41,56.53 20.41,57.8 20.79,58.18 22.63,58.18
GND on BOTTOM (solid shape): 57.12,97.4 58.15,97.4 58.32,97.24 58.32,95.82 58.3,95.81 57.09,95.81 57.02,95.88 57.02,97 56.8,97.22 56.23,97.22 56.19,97.26 56.19,97.47 56.25,97.53 56.99,97.53
GND on BOTTOM (solid shape): 77.07,120.57 77.32,120.57 77.84,120.06 77.84,119.52 77.78,119.46 77.29,119.46 77.29,119.46 77,119.46 76.8,119.25 72.76,119.25 72.5,119.51 72.5,120.53 72.65,120.69 76.96,120.69
GND on BOTTOM (solid shape): 167.92,65.06 167.92,64.4 166.46,62.94 166.46,61.26 166.19,61 163.47,61 162.69,61.78 162.69,63.71 162.08,64.32 162.08,66.11 164.1,68.13 164.84,68.13
GND on BOTTOM (solid shape): 201.22,51.88 201.22,50.25 201.03,50.07 195.82,50.07 195.58,50.31 195.58,50.77 195.81,51 196.75,51 197.06,51.32 197.06,51.89 197.25,52.08 201.01,52.08
GND on BOTTOM (solid shape): 20.14,102.7 20.14,102.14 19.97,101.98 19.45,101.98 19.45,101.97 19.31,101.83 19.31,100.5 19.2,100.39 18.59,100.39 18.57,100.42 18.57,102.39 18.95,102.77 20.07,102.77
GND on BOTTOM (solid shape): 58.25,77.97 58.25,74.57 57.19,73.51 57.19,70.75 56.99,70.55 51.48,70.55 51.24,70.79 51.24,72.85 51.96,73.57 55.87,73.57 56.11,73.81 56.11,77.79 56.56,78.24 57.97,78.24
GND on BOTTOM (solid shape): 16.09,74.33 16.09,73.95 17.56,73.95 17.6,73.91 17.6,73.07 17.56,73.04 16.18,73.04 16.1,72.96 16.1,72.62 15.25,71.77 13.8,71.77 12.95,72.62 12.95,74.34 13,74.39 14.27,74.39 14.28,74.4 16.02,74.4
GND on BOTTOM (solid shape): 37.92,132.54 38.79,132.54 38.92,132.41 38.92,131.55 38.79,131.42 38.77,131.42 38.73,131.43 38.7,131.43 38.11,131.43 38.08,131.43 38.04,131.42 36.97,131.42 36.78,131.62 36.78,132.55 37,132.78 37.68,132.78
GND on BOTTOM (solid shape): 76.1,93.6 76.1,88.47 74.32,86.69 73.3,86.69 73.11,86.88 73.11,87.26 73.56,87.7 73.56,89.04 73.34,89.26 72.59,89.26 72.52,89.32 72.52,90 73.05,90.53 73.05,93.1 73.72,93.77 75.92,93.77
GND on BOTTOM (solid shape): 166.01,92.97 166.01,91.86 165.38,91.22 162.71,91.22 162.46,91.48 162.46,92.06 162.56,92.16 162.86,92.16 162.96,92.06 162.96,91.78 163.12,91.63 164.46,91.63 164.9,92.06 164.9,92.97 165,93.08 165.91,93.08
GND on BOTTOM (solid shape): 150.78,74.38 150.78,70.81 150.59,70.62 150.29,70.62 150.14,70.78 150.14,73.1 150.02,73.22 150.02,74.37 150.09,74.44 150.12,74.44 150.28,74.43 150.43,74.49 150.66,74.49
GND on BOTTOM (solid shape): 69.51,76.05 69.51,75.67 69.89,75.29 69.89,73.18 69.18,72.46 68.67,72.46 68.49,72.29 68.49,70.52 67.51,70.52 67.51,73.17 67.4,73.29 67.4,74.75 67.78,75.13 67.78,75.83 68.28,76.34 69.22,76.34
GND on BOTTOM (solid shape): 174.2,65.03 174.2,64.65 173.96,64.41 173.67,64.41 173.2,64.88 172.72,64.88 172.29,64.45 172.29,63.77 171.58,63.05 170.77,63.05 169.95,63.88 169.95,64.1 171.09,65.24 171.73,65.24 172.67,66.18 173.05,66.18
GND on BOTTOM (solid shape): 245.39,128.79 245.64,128.53 247.72,128.53 248.03,128.23 248.03,127.85 247.91,127.73 247.91,127.08 247.78,126.95 245.71,126.95 245.2,126.44 245.2,125.8 245.13,125.74 244.88,125.74 244.82,125.8 244.82,129.42 244.88,129.49 245.39,129.49
GND on BOTTOM (solid shape): 59.74,107.85 59.74,106.75 59.7,106.71 58.64,106.71 58.3,106.38 58.3,105.25 58.06,105.01 58.06,104.39 58,104.33 57.5,104.33 57.47,104.36 57.47,105.07 57.98,105.58 57.98,106.42 58.22,106.66 58.22,107.9 59.7,107.9
GND on BOTTOM (solid shape): 145.17,72.09 145.17,67.52 145.14,67.5 143.7,67.5 143.66,67.5 143.63,67.5 141.63,67.5 141.62,67.51 141.62,69.49 141.25,69.86 138.52,69.86 138.01,70.37 138.01,70.58 138.12,70.7 141.48,70.7 141.62,70.84 141.62,72.09 141.65,72.11 145.15,72.11
GND on BOTTOM (solid shape): 45.55,79.64 45.55,73.92 45.55,73.92 45.55,73.58 45.16,73.19 40.98,73.19 40.37,73.79 40.37,76.4 40.85,76.88 41.21,76.88 41.53,76.56 42.01,76.56 42.88,77.42 42.88,77.65 42.9,77.68 43.91,77.68 44.07,77.84 44.07,79.77 45.43,79.77
GND on BOTTOM (solid shape): 24.64,93.79 24.64,92.87 24.26,92.48 24.26,84.27 15.83,84.27 15.83,92.94 16.19,93.3 19.58,93.3 19.73,93.15 19.73,92.71 19.53,92.51 17.5,92.51 17.05,92.06 17.05,88.83 17.06,88.82 17.06,85.47 23.06,85.47 23.06,93.19 23.19,93.33 23.7,93.33 24.21,93.84 24.59,93.84
GND on BOTTOM (solid shape): 61.15,102.4 61.15,100.87 60.79,100.52 60.79,95.96 60.67,95.83 59.48,95.83 59.48,96.72 58.99,96.72 58.8,96.54 58.8,94.89 59.52,94.18 59.52,93.54 59.5,93.53 59,93.53 59,93.53 59,93.96 58.47,94.49 58.47,100.61 58.41,100.67 58.41,103.25 58.55,103.39 60.16,103.39
GND on BOTTOM (solid shape): 240.32,124.1 240.32,122.64 239.52,121.84 238.3,121.84 238.12,122.03 238.12,123.69 238.16,123.7 238.43,123.89 238.43,124.21 238.41,124.24 238.46,124.29 240.12,124.29
GND on BOTTOM (solid shape): 153.25,84.81 153.25,83.2 153.93,82.53 154.6,82.53 154.74,82.39 154.74,81.08 154.24,80.57 154.24,79.95 154.03,79.73 153.49,79.73 153.14,79.39 152.37,79.39 152.07,79.69 152.07,84.02 151.74,84.35 151.34,84.35 151.33,84.34 151.04,84.34 150.93,84.46 150.93,85.07 151.02,85.16 152.91,85.16
GND on BOTTOM (solid shape): 66.44,123.39 66.44,121.42 67.41,120.46 67.41,120.33 67.69,120.05 68.86,120.05 68.95,119.95 68.95,119.07 68.88,119 67.59,119 67.4,118.82 67.42,118.8 67.42,118.65 67.35,118.58 64.28,118.58 64.18,118.69 64.18,120.96 63.9,121.23 63.02,121.23 63.02,121.87 65.11,121.87 65.37,122.12 65.37,123.39 65.49,123.52 66.32,123.52
GND on BOTTOM (solid shape): 59.72,88.5 59.72,87.34 59.67,87.3 58.57,87.3 58.35,87.08 58.35,85.77 58.51,85.61 58.51,85.16 59.17,84.49 59.17,83.65 59.09,83.57 58.72,83.57 58.63,83.66 58.63,84.28 58.01,84.9 58.01,87.11 58.23,87.32 58.23,87.33 58.27,87.36 58.27,88.42 58.37,88.52 59.7,88.52
GND on BOTTOM (solid shape): 38.18,92.76 38.18,91.16 37.9,90.88 37.29,90.88 37.18,90.77 37.18,90.68 37.18,90.67 37.13,90.5 37.18,90.33 37.18,90.32 37.18,90.02 37.13,89.89 37.13,89.75 37.14,89.73 36.98,89.57 36.31,89.57 36.22,89.66 36.22,92.85 36.35,92.98 37.96,92.98
GND on BOTTOM (solid shape): 42.86,117.68 44.49,117.68 44.5,117.66 44.5,116.9 44.22,116.62 44.12,116.62 43.78,116.28 43.78,115.71 43.58,115.52 43.58,113.1 42.57,112.09 40.79,112.09 40.79,112.6 41.74,112.6 42.19,113.04 42.19,114.76 41.81,115.14 40.11,115.14 39.08,114.11 37.35,114.11 37.34,114.12 36.85,114.12 36.41,114.56 36.41,117.35 36.73,117.66 39.44,117.66 39.65,117.87 42.67,117.87
GND on BOTTOM (solid shape): 123.4,123.8 123.48,123.81 126.54,123.81 126.71,123.64 126.72,123.62 126.72,123.06 126.52,122.87 125.52,122.87 124.88,122.22 124.88,121.75 124.88,121.74 124.86,121.64 124.88,121.54 124.88,121.49 124.91,121.46 124.97,121.39 125.03,121.34 125.12,121.25 125.21,121.25 125.68,120.79 125.68,120.21 125.56,120.09 124.54,120.09 121.6,123.03 121.6,123.7 121.71,123.81 123.32,123.81
GND on BOTTOM (solid shape): 55.79,113.46 55.79,110.49 55.98,110.29 59.66,110.29 59.71,110.23 59.71,109.08 59.72,109.07 58.91,109.07 58.86,109.02 58.86,108.61 59.07,108.4 60.86,108.4 61.25,108.79 62.32,108.79 62.51,108.6 62.51,108.21 62.38,108.08 54.21,108.08 53.78,108.52 52.71,108.52 52.6,108.41 52.6,107.31 52.78,107.13 53.05,107.13 53.23,106.95 53.23,105.08 53.11,104.96 52.6,104.96 52.49,105.06 52.49,106.73 52.35,106.87 51.82,106.87 51.71,106.98 51.71,110.22 53.08,111.59 53.08,113.38 53.56,113.86 55.38,113.86
GND on BOTTOM (solid shape): 113.7,56.33 113.74,56.41 113.84,56.42 113.91,56.4 113.99,56.4 114.01,56.4 114.92,55.49 114.95,55.39 114.88,55.32 114.66,55.1 114.71,54.8 114.72,54.79 114.72,54.7 114.69,54.65 114.63,54.66 113.7,55.6
GND on BOTTOM (solid shape): 57.85,59.3 57.85,58.52 58.04,58.33 58.98,58.33 59.1,58.2 59.1,57.69 59.03,57.62 58.78,57.62 58.55,57.38 58.55,55.71 58.67,55.59 59.23,55.59 59.28,55.53 59.28,55.03 59.2,54.94 55.54,54.94 55.42,54.82 55.42,54.47 55.27,54.32 54.52,54.32 54.36,54.48 54.36,57.73 54.21,57.88 53.98,57.88 53.91,57.96 53.91,58.58 53.96,58.63 54.34,58.63 54.44,58.62 54.54,58.63 55.03,58.63 55.12,58.72 55.12,59.05 55.24,59.18 55.88,59.18 55.97,59.09 55.97,58.77 56.07,58.66 56.84,58.66 56.91,58.73 56.91,59.31 57.08,59.48 57.66,59.48
GND on BOTTOM (solid shape): 6.88,102.82 7.77,102.82 9.01,101.58 9.01,101.56 9.04,101.56 10.55,100.05 11.92,100.05 12.04,99.93 12.04,99.51 11.99,99.45 10.45,99.45 10.3,99.31 10.3,96.03 10.08,95.81 0.75,95.81 0.61,95.95 0.61,102.18 0.69,102.38 0.9,102.47 3.97,102.47 3.99,102.44 4.77,101.98 5.36,102.67 5.36,102.88 6.82,102.88
GND on BOTTOM (solid shape): 161.11,131.52 161.15,131.48 161.18,131.44 161.36,131.26 161.59,131.06 161.87,130.86 162.17,130.68 162.28,130.62 162.39,130.5 162.39,129.49 162.2,129.3 161.44,129.3 161.38,129.36 161.38,129.55 161.12,129.8 159.92,129.8 159.66,130.06 159.66,130.5 158.99,131.17 158.92,131.17 158.82,131.18 158.73,131.17 157.94,131.17 157.44,130.67 157.44,129.46 157.79,129.11 158.33,129.11 158.33,127.46 157.57,127.46 157.38,127.26 157.38,126.38 157.31,126.31 156.68,126.31 156.61,126.38 156.61,127.26 156.68,127.33 156.68,129.11 156.85,129.28 156.89,129.29 156.99,129.29 157.08,129.39 157.08,130.93 157.01,131 157.01,131.7 157.94,132.63 160,132.63
GND on BOTTOM (solid shape): 47.5,129.8 43.59,129.8 43.59,129.81 40.89,132.11 42.72,135.15 44.33,135.15 44.44,135.16 44.54,135.19 44.65,135.24 44.74,135.3 47.5,135.3
GND on BOTTOM (solid shape): 157.47,77.19 157.47,76.07 157.48,76.06 157.48,75.47 157.28,75.27 156.74,75.27 156.69,75.32 155.54,75.32 155.41,75.19 155.41,74.62 155.28,74.5 153.62,74.5 153.5,74.61 153.5,74.69 153.33,74.86 152.41,74.86 152.09,74.55 152.09,73.85 152.58,73.36 152.58,71.54 152.3,71.27 151.19,71.27 150.98,71.48 150.98,71.48 150.98,75.06 150.33,75.7 150.33,76.21 150.64,76.51 151.45,76.51 151.5,76.56 151.75,76.56 151.86,76.44 151.86,76.07 152.36,75.58 153.31,75.58 153.69,75.95 155.22,75.95 155.6,75.58 156.54,75.58 156.86,75.9 156.86,77.2 157.04,77.37 157.29,77.37
GND on BOTTOM (solid shape): 271.6,54.65 274.07,53.62 275.1,51.15 275.1,47.75 273.43,47.75 273.04,48.15 266.11,48.15 266.1,51.15 267.13,53.62 269.6,54.65
GND on BOTTOM (solid shape): 299.7,91.39 299.91,91.31 299.99,91.1 299.99,89.25 299.91,89.04 299.7,88.96 297.31,88.96 297.31,86.2 297.22,85.99 297.01,85.91 288.08,85.91 288.06,85.94 287.28,86.4 286.69,85.7 286.69,84.66 283.23,84.66 282.92,84.97 282.92,88.09 283.42,88.59 288.17,88.59 289.4,89.82 289.4,91.34 289.46,91.39
GND on BOTTOM (solid shape): 12.1,74.99 12.1,72.71 14.69,70.11 16.39,70.11 17.35,69.16 17.35,68.55 16.94,68.15 13.5,68.15 13.5,69.25 12.9,69.95 12.13,69.45 3.18,69.45 2.98,69.54 2.89,69.75 2.89,71.4 2.98,71.61 3.18,71.7 4.3,71.7 4.66,71.84 4.8,72.2 4.8,74.55 6.78,76.53 10.55,76.53
GND on BOTTOM (solid shape): 189.2,57.82 189.2,57.32 189.08,57.2 188.1,57.2 188.04,57.14 188.04,55.75 187.74,55.45 187.03,55.45 186.97,55.51 186.02,55.51 185.89,55.38 185.89,54.81 185.76,54.68 184.1,54.68 183.98,54.8 183.98,54.87 183.81,55.05 182.89,55.05 182.08,54.24 181.84,54.24 180.57,52.97 179.13,52.97 178.43,52.27 178.22,52.27 177.84,51.89 177.84,51.03 178,50.87 178.3,50.87 178.37,50.79 178.37,49.98 178.06,49.67 175.37,49.67 175.03,50.01 175.03,50.91 175.27,51.15 176.89,51.15 177,51.26 177,52.27 177.04,52.27 177.3,52.53 177.31,52.53 177.59,52.7 177.62,53.02 177.62,53.03 177.62,54.21 178.96,55.55 178.97,55.55 179.17,55.65 179.27,55.84 179.27,55.86 179.68,56.27 182.33,56.27 182.84,55.76 183.79,55.76 184.17,56.14 185.7,56.14 186.08,55.76 186.92,55.76 187.31,56.15 187.31,56.91 187.44,57.04 187.44,57.6 187.75,57.92 189.1,57.92
GND on BOTTOM (solid shape): outline of 82 points within 53.56,88.68 62.56,94.5
GND on BOTTOM (solid shape): 33.29,51.03 35.76,52.05 38.24,51.03 40.61,48.65 38.17,48.65 38.06,48.63 37.96,48.56 37.74,48.34 34.64,45.26 34.6,45.21 34.56,45.16 34.19,44.79 34.12,44.69 34.1,44.58 34.1,42.44 31.87,44.66 30.85,47.14 31.87,49.61
GND on BOTTOM (solid shape): 146.1,51.07 150.14,55.1 154.1,51 154.1,50.32 153.95,49.77 153.9,49.2 153.9,48.95 153.87,48.88 153.8,48.85 146.1,48.85
GND on BOTTOM (solid shape): 144.68,133.23 145.11,133.23 145.23,133.11 145.23,133.09 145.78,131.75 146.69,130.62 146.71,130.6 146.71,130.31 146.65,130.25 146.33,130.25 146.2,130.38 146.2,130.57 145.95,130.82 145.5,130.82 145.5,131.01 145.25,131.27 144.17,131.27 143.72,131.71 143.72,132.27 143.42,132.57 142.14,132.57 142.1,132.53 141.68,132.53 141.53,132.38 141.53,132.24 141.52,132.15 141.53,132.07 141.53,131.04 141.66,130.92 141.7,130.86 141.76,130.81 141.92,130.66 142.48,130.66 142.48,130.65 142.48,128.96 142.48,128.95 141.61,128.95 141.52,128.85 141.52,127.88 141.43,127.8 141.33,127.8 141.25,127.88 141.25,128.67 141.19,128.73 141.06,128.73 141.01,128.68 141.01,127.88 140.93,127.8 140.82,127.8 140.75,127.87 140.75,128.94 140.77,128.96 140.77,130.64 140.91,130.78 140.92,130.79 141.06,130.86 141.13,130.99 141.13,131.01 141.2,131.08 141.2,131.67 141.13,131.73 141.13,131.8 140.88,132.05 140.88,133.48 141.41,134 143.91,134
GND on BOTTOM (solid shape): outline of 93 points within 44.23,88.46 50.99,97.53
GND on BOTTOM (solid shape): 125.05,99.76 125.13,99.74 125.22,99.76 125.23,99.76 125.54,99.76 125.67,99.63 125.67,99.16 125.65,99.15 125.55,99.04 125.53,98.9 125.51,98.83 125.45,98.79 125.26,98.67 125.19,98.46 125.19,98.4 125.2,98.34 125.21,98.31 125.15,98.25 125.13,98.25 124.92,98.13 124.9,97.9 124.72,97.71 124.53,97.9 124.53,97.91 124.45,98.01 124.33,98.07 124.27,98.12 124.26,98.2 124.21,98.49 123.95,98.62 123.93,98.62 123.89,98.66 123.89,98.71 123.92,98.75 123.95,98.75 124.19,98.83 124.31,99.06 124.31,99.08 124.52,99.29 124.52,99.38 124.52,99.39 124.54,99.5 124.51,99.61 124.52,99.71 124.6,99.76 125.04,99.76
GND on BOTTOM (solid shape): 130.36,112.45 130.43,112.42 130.46,112.35 130.64,112.09 130.93,112.21 131.01,112.26 131.09,112.23 131.1,112.22 131.33,112.22 131.43,112.13 131.43,111.87 131.39,111.86 131.21,111.72 131.21,111.49 131.23,111.46 131.15,111.38 131.09,111.38 131.01,111.43 131.01,111.54 130.81,111.92 130.56,111.57 130.56,111.49 130.5,111.43 130.49,111.43 130.45,111.43 130.43,111.46 130.14,111.61 129.94,111.36 129.94,111.34 129.73,111.14 129.45,111.14 129.37,111.21 129.37,111.49 129.39,111.53 129.43,111.54 129.68,111.65 129.76,111.92 129.76,111.94 130.24,112.43 130.29,112.45
GND on BOTTOM (solid shape): 286.69,72.1 287.28,71.4 288.06,71.86 288.08,71.89 297.01,71.89 297.22,71.81 297.31,71.6 297.31,69.95 297.22,69.74 297.01,69.66 293.9,69.66 293.54,69.51 293.39,69.15 293.39,66.75 293.54,66.39 293.9,66.24 300.2,66.24 300.41,66.16 300.49,65.95 300.49,50.63 300.41,50.42 300.2,50.34 299.5,50.34 299,50.13 298.79,49.63 298.79,48.03 299,47.53 299.5,47.32 300.2,47.32 300.41,47.24 300.49,47.03 300.49,46.41 295.9,46.41 295.86,46.4 295.43,46.4 295.12,46.71 295.12,50.29 296,51.17 298.94,51.17 299.3,51.52 299.3,62.49 297.39,64.4 294.22,64.4 292.89,63.07 285.84,63.07 285.52,63.38 285.52,64.84 282.92,67.45 282.92,72.78 283.3,73.16 286.69,73.16
GND on BOTTOM (solid shape): outline of 114 points within 119.55,97.09 124.41,99.76
GND on BOTTOM (solid shape): outline of 92 points within 25.62,100.22 31.33,102.72
GND on BOTTOM (solid shape): outline of 136 points within 30.32,0.21 299.29,53.99
GND on BOTTOM (solid shape): outline of 1181 points within 0.61,71.84 299.99,136.99
GND on BOTTOM (solid shape): outline of 2295 points within 1.8,35.31 35.44,56.86
GND on BOTTOM (solid shape): outline of 2539 points within 14.73,94.58 32.46,112.33
GND on BOTTOM (solid shape): outline of 9359 points within 75.08,49.86 141.69,64.91
GND on GND1 (solid shape): 222.11,80.05 222.18,75.51 217.67,76.02 216.5,77.44 217.13,77.95 217.41,77.96 217.66,77.82 218.88,76.54 221.36,76.48 221.42,78.96 220.19,80.24 220.06,80.49 220.09,80.78 220.65,81.41 220.72,81.51
GND on IN1 (solid shape): 59.74,107.85 59.74,106.75 59.7,106.71 58.24,106.71 58.21,106.74 58.21,107.87 58.24,107.9 59.7,107.9
GND on IN1 (solid shape): 60.65,100.27 60.65,96.5 60.65,96.5 60.65,96.15 60.41,95.91 58.6,95.91 58.48,96.03 58.48,99.94 58.95,100.4 60.52,100.4
GND on IN1 (solid shape): 60.72,94.21 60.72,93.32 59.66,92.26 59.66,88.71 59.64,88.69 57.93,88.69 57.78,88.84 55.22,88.84 54.49,89.56 54.49,91.48 56.31,93.29 57.83,93.29 58.16,93.62 58.16,94.18 58.73,94.75 60.18,94.75
GND on IN1 (solid shape): 299.7,91.39 299.91,91.31 299.99,91.1 299.99,89.25 299.91,89.04 299.7,88.96 297.31,88.96 297.31,86.2 297.22,85.99 297.01,85.91 288.08,85.91 288.06,85.94 287.28,86.4 286.69,85.7 286.69,84.66 283.23,84.66 282.92,84.97 282.92,88.09 283.42,88.59 288.95,88.59 289.46,89.1 289.46,91.39
GND on IN1 (solid shape): 12.1,74.99 12.1,72.71 14.69,70.11 16.39,70.11 17.35,69.16 17.35,68.55 16.94,68.15 13.5,68.15 13.5,69.25 12.9,69.95 12.13,69.45 3.18,69.45 2.98,69.54 2.89,69.75 2.89,71.4 2.98,71.61 3.18,71.7 4.3,71.7 4.66,71.84 4.8,72.2 4.8,74.55 6.78,76.53 10.55,76.53
GND on IN1 (solid shape): 286.69,72.1 287.28,71.4 288.06,71.86 288.08,71.89 297.01,71.89 297.22,71.81 297.31,71.6 297.31,69.95 297.22,69.74 297.01,69.66 293.9,69.66 293.54,69.51 293.39,69.15 293.39,66.75 293.54,66.39 293.9,66.24 300.2,66.24 300.41,66.16 300.49,65.95 300.49,50.63 300.41,50.42 300.2,50.34 299.5,50.34 299,50.13 298.79,49.63 298.79,48.03 299,47.53 299.5,47.32 300.2,47.32 300.41,47.24 300.49,47.03 300.49,46.41 295.9,46.41 295.79,46.39 295.69,46.36 295.17,46.87 295.17,50.18 295.49,50.49 298.22,50.49 298.85,51.13 298.85,60.59 298.41,61.03 298.41,61.42 298.6,61.61 298.6,63.07 297.27,64.4 294.22,64.4 294.16,64.34 288.38,64.34 287.11,63.07 285.84,63.07 285.58,63.32 285.58,63.83 285.84,64.08 285.84,65.67 282.92,68.59 282.92,72.78 283.3,73.16 286.69,73.16
GND on IN1 (solid shape): outline of 258 points within 1.81,35.31 17.4,56.84
GND on IN1 (solid shape): outline of 1131 points within 30.25,0.21 299.29,53.58
GND on IN1 (solid shape): outline of 224 points within 0.61,71.84 299.99,136.99
GND on GND2 (solid shape): 222.11,80.05 222.18,75.51 217.67,76.02 216.5,77.44 217.13,77.95 217.41,77.96 217.66,77.82 218.88,76.54 221.36,76.48 221.42,78.96 220.19,80.24 220.06,80.49 220.09,80.78 220.65,81.41 220.72,81.51
GND on IN2 (solid shape): 60.65,100.13 60.65,96.5 60.06,95.91 58.6,95.91 58.48,96.03 58.48,99.94 58.86,100.32 60.46,100.32
GND on IN2 (solid shape): 59.74,107.85 59.74,106.75 59.7,106.71 58.22,106.71 58.21,106.72 58.21,107.87 58.24,107.9 59.7,107.9
GND on IN2 (solid shape): 60.65,100.12 60.65,96.5 60.65,96.5 60.65,96.15 60.41,95.91 58.6,95.91 58.48,96.03 58.48,99.94 58.86,100.32 60.46,100.32
GND on IN2 (solid shape): 60.72,94.37 60.72,88.88 60.53,88.69 57.93,88.69 57.78,88.84 55.23,88.84 54.49,89.58 54.49,91.47 56.3,93.29 57.84,93.29 58.16,93.61 58.16,94.16 58.74,94.74 60.34,94.74
GND on IN2 (solid shape): 7.71,101.99 7.71,101.93 10.32,99.31 10.32,96.05 10.09,95.82 0.72,95.82 0.61,95.93 0.61,102.18 0.69,102.38 0.9,102.47 3.97,102.47 3.99,102.44 4.77,101.98 5.36,102.67 5.36,102.88 6.82,102.88
GND on IN2 (solid shape): 299.7,91.39 299.91,91.31 299.99,91.1 299.99,89.25 299.91,89.04 299.7,88.96 297.31,88.96 297.31,86.2 297.22,85.99 297.01,85.91 288.08,85.91 288.06,85.94 287.28,86.4 286.69,85.7 286.69,84.66 283.23,84.66 282.92,84.97 282.92,88.09 283.42,88.59 288.95,88.59 289.46,89.1 289.46,91.39
GND on IN2 (solid shape): 12.1,74.99 12.1,72.71 14.69,70.11 16.39,70.11 17.35,69.16 17.35,68.55 16.94,68.15 13.5,68.15 13.5,69.25 12.9,69.95 12.13,69.45 3.18,69.45 2.98,69.54 2.89,69.75 2.89,71.4 2.98,71.61 3.18,71.7 4.3,71.7 4.66,71.84 4.8,72.2 4.8,74.55 6.78,76.53 10.55,76.53
GND on IN2 (solid shape): outline of 413 points within 282.92,46.36 300.49,73.16
GND on IN2 (solid shape): outline of 1170 points within 1.8,0.21 299.29,56.86
GND on IN2 (solid shape): outline of 220 points within 0.61,71.84 299.99,136.99
GND on IN3 (solid shape): 59.74,107.85 59.74,106.75 59.7,106.71 58.25,106.71 58.21,106.75 58.21,107.87 58.24,107.9 59.7,107.9
GND on IN3 (solid shape): 60.65,100.13 60.65,96.5 60.65,96.5 60.65,96.15 60.41,95.91 58.6,95.91 58.48,96.03 58.48,99.94 58.86,100.32 60.46,100.32
GND on IN3 (solid shape): 55.71,91.5 55.71,91.16 55.93,90.95 59.52,90.95 59.68,90.79 59.68,89.81 59.57,89.71 58.84,89.71 58.79,89.66 58.79,89.04 58.6,88.85 54.89,88.85 54.51,89.23 54.51,91.16 55.01,91.66 55.56,91.66
GND on IN3 (solid shape): 7.71,101.99 7.71,101.93 10.32,99.31 10.32,96.03 10.11,95.82 0.75,95.82 0.61,95.96 0.61,102.18 0.69,102.38 0.9,102.47 3.97,102.47 3.99,102.44 4.77,101.98 5.36,102.67 5.36,102.88 6.82,102.88
GND on IN3 (solid shape): 299.7,91.39 299.91,91.31 299.99,91.1 299.99,89.25 299.91,89.04 299.7,88.96 297.31,88.96 297.31,86.2 297.22,85.99 297.01,85.91 288.08,85.91 288.06,85.94 287.28,86.4 286.69,85.7 286.69,84.66 283.23,84.66 282.92,84.97 282.92,88.09 283.42,88.59 288.95,88.59 289.46,89.1 289.46,91.39
GND on IN3 (solid shape): 12.1,74.99 12.1,72.71 14.69,70.11 16.39,70.11 17.35,69.16 17.35,68.55 16.94,68.15 13.5,68.15 13.5,69.25 12.9,69.95 12.13,69.45 3.18,69.45 2.98,69.54 2.89,69.75 2.89,71.4 2.98,71.61 3.18,71.7 4.3,71.7 4.66,71.84 4.8,72.2 4.8,74.55 6.78,76.53 10.55,76.53
GND on IN3 (solid shape): outline of 261 points within 1.81,35.31 17.36,56.79
GND on IN3 (solid shape): outline of 418 points within 282.92,46.36 300.49,73.16
GND on IN3 (solid shape): outline of 803 points within 28.98,0.21 299.29,53.57
GND on IN3 (solid shape): outline of 227 points within 0.61,71.84 299.99,136.99
GND on IN4 (solid shape): 59.74,107.85 59.74,106.75 59.7,106.71 58.21,106.71 58.21,107.88 58.23,107.9 59.7,107.9
GND on IN4 (solid shape): 60.71,100.06 60.71,92.99 59.68,91.96 59.68,89.76 58.76,88.83 55.1,88.83 54.52,89.41 54.52,91.53 56.53,93.54 57.36,93.54 58.04,94.22 58.04,95.43 58.48,95.87 58.48,99.92 58.88,100.31 60.46,100.31
GND on IN4 (solid shape): 299.7,91.39 299.91,91.31 299.99,91.1 299.99,89.25 299.91,89.04 299.7,88.96 297.31,88.96 297.31,86.2 297.22,85.99 297.01,85.91 288.08,85.91 288.06,85.94 287.28,86.4 286.69,85.7 286.69,84.66 283.23,84.66 282.92,84.97 282.92,88.09 283.42,88.59 288.95,88.59 289.46,89.1 289.46,91.39
GND on IN4 (solid shape): 12.1,74.99 12.1,72.71 14.69,70.11 16.39,70.11 17.35,69.16 17.35,68.55 16.94,68.15 13.5,68.15 13.5,69.25 12.9,69.95 12.13,69.45 3.18,69.45 2.98,69.54 2.89,69.75 2.89,71.4 2.98,71.61 3.18,71.7 4.3,71.7 4.66,71.84 4.8,72.2 4.8,74.55 6.78,76.53 10.55,76.53
GND on IN4 (solid shape): outline of 258 points within 1.81,35.31 17.4,56.84
GND on IN4 (solid shape): 5.25,111.35 5.31,111.44 5.41,111.43 5.61,111.32 5.84,111.28 6.58,111.28 6.64,111.25 6.68,111.19 6.51,110.83 6.59,110.43 6.56,110.39 6.51,110.37 6.28,110.24 6.17,110 6.12,109.92 6.02,109.92 5.45,109.8 5.51,109.23 5.55,109.15 5.37,108.75 5.55,108.35 5.51,108.27 5.45,107.7 6.02,107.58 6.12,107.58 6.17,107.5 6.22,107.35 6.31,107.23 6.35,107.15 6.31,107.07 6.22,106.95 6.17,106.8 6.11,106.72 6.02,106.72 5.45,106.6 5.51,106.03 5.55,105.95 5.37,105.55 5.55,105.15 5.51,105.07 5.45,104.5 6.02,104.38 6.11,104.38 6.17,104.3 6.26,104.08 6.45,103.94 6.46,103.94 6.51,103.9 6.44,103.83 5.48,103.83 5.23,104.09 5.23,110.22 5.25,110.24
GND on IN4 (solid shape): outline of 374 points within 282.92,46.36 300.49,73.16
GND on IN4 (solid shape): outline of 1131 points within 30.25,0.21 299.29,53.58
GND on IN4 (solid shape): outline of 2924 points within 0.61,71.84 299.99,136.99
GND on GND3 (solid shape): 222.29,79.89 222.08,75.42 217.65,76.05 216.37,77.38 217.13,77.95 217.41,77.96 217.66,77.82 218.88,76.54 221.36,76.48 221.42,78.96 220.19,80.24 220.06,80.49 220.09,80.78 220.6,81.38 220.75,81.54
GND on BOTTOM: 50.83,79.74 50.7,79.86 50.7,80.21 50.74,80.25 51.14,80.25 51.26,80.37 51.26,81.15 50.7,81.71 50.7,82.96 50.87,83.13 54.16,83.13 54.21,83.08 54.21,79.94 54.01,79.74
GND on GND1: outline of 347 points within 0.2,0.2 300.5,137 ; 2 cut-outs
GND on IN1: 13.86,96.95 13.85,96.95 12.45,95.54 9.9,95.54 9.62,95.82 0.71,95.82 0.61,95.92 0.61,102.18 0.69,102.38 0.9,102.47 3.97,102.47 3.99,102.44 4.77,101.98 5.36,102.67 5.36,102.88 6.26,102.88 6.26,110.4 7.45,111.59 8.28,111.59 9.89,113.2 16.8,113.2 18.21,111.78 18.22,111.77 18.29,111.66 18.41,111.58 18.42,111.58 19.23,110.77 19.23,105 21.61,102.62 21.61,100.88 22.53,99.96 22.53,97.79 22.68,97.64 22.68,94.02 21.64,92.98 19.56,92.98 16.57,95.97 16.48,95.97 15.5,96.95 15.47,96.95 15.45,96.97 13.89,96.97
GND on IN1: 52.61,109.48 52.61,107.06 53.01,106.67 54.85,106.67 54.92,106.74 54.92,107.85 55.18,108.11 60.38,108.11 60.38,110.02 56.75,113.65 54.82,113.65 54.82,113.65 54.63,113.65 53.15,112.17 53.15,110.02
GND on GND2: outline of 347 points within 0.2,0.2 300.5,137 ; 1 cut-out
GND on IN2: 52.61,107.06 53.01,106.67 54.84,106.67 54.93,106.75 54.93,107.85 55.18,108.11 60.37,108.11 60.38,108.12 60.38,110.02 56.75,113.65 54.15,113.65 52.61,112.1
GND on IN3: 58.05,112.35 57.76,112.35 56.46,113.65 54.16,113.65 52.61,112.1 52.61,107.06 53.01,106.67 54.87,106.67 54.92,106.72 54.92,107.86 55.17,108.11 60.38,108.11 60.38,110.02
GND on VCC: 293.51,70.5 293.58,70.43 292.86,69.96 292.58,69.15 292.58,66.75 292.97,65.82 293.9,65.43 299.68,65.43 299.68,51.15 299.5,51.15 298.43,50.7 297.98,49.63 297.98,48.03 298.04,47.61 298.22,47.22 295.9,47.22 295.7,47.2 295.5,47.16 295.4,47.25 294.9,47.25 294.64,47.51 284.1,47.51 280.04,51.57 280.06,51.59 280.06,51.98 282.34,54.26 282.34,64.8 282.6,65.06 282.6,87.79 283.4,88.59 288.17,88.59 289.39,89.82 289.39,90.58 297.47,90.58 297.47,90.16 297.87,89.77 296.5,89.77 296.5,86.72 288.53,86.72 286.86,87.12 285.88,85.7 285.88,72.1 286.86,70.68 288.53,71.08 293.87,71.08 293.51,70.72
GND on VCC: 259.91,53.78 259.79,53.89 259.79,55.72 258.66,56.85 258.66,57.85 258.44,58.06 258.35,58.06 258.29,58.13 255.1,58.13 255.1,62.62 259.51,62.62 260.12,62.01 260.12,59.69 259.88,59.69 259.63,59.44 259.63,58.43 259.82,58.24 260.72,58.24 260.77,58.18 260.77,56.71 261.13,56.35 262.34,56.35 262.43,56.26 262.43,53.94 262.26,53.78
GND on VCC: 276.62,1.02 276.62,45.39 276.5,45.97 276.17,46.47 273.37,49.27 273.37,50.25 273.3,50.86 273.09,51.45 279.68,44.86 279.68,33.31 283,29.98 298.24,29.98 298.37,29.86 298.48,29.86 298.48,23.52 293.9,23.52 292.97,23.13 292.58,22.2 292.58,1.02
GND on VCC: outline of 84 points within 1.02,36.12 36.91,107.83
GND on VCC: 76.08,53.22 75.21,54.09 75.21,73.4 72.41,76.19 72.41,77.84 65.94,84.32 65.94,98.58 68.33,100.98 72.9,100.98 76.58,104.66 79.89,104.66 80.52,105.29 89.03,105.29 93.88,110.14 93.88,111.54 94.87,112.53 105.46,112.53 106.58,111.41 106.58,110.8 106.7,110.68 106.7,99.78 107.34,99.15 107.34,96.64 107.21,96.51 107.21,95.59 107.79,95.01 109.27,95.01 110.92,93.36 112.57,93.36 115.62,90.31 128.93,90.31 128.93,84.36 142.9,70.39 142.9,65.44 143.53,64.8 143.53,57.39 143.03,56.89 143.03,55.49 142.16,54.62 105.2,54.62 103.8,53.22
GND on IN4: 110.49,95.23 112.32,95.23 115,92.55 119.98,92.55 121.33,91.19 125.29,91.19 129.12,87.37 132.32,87.37 135.62,84.07 135.62,79.81 135.28,79.47 132.4,79.47 123.9,87.98 119.16,87.98 118.34,88.79 112.96,88.79 112.12,89.63 112.12,91.23 109.98,93.37 109.98,94.72
GND on IN4: 52.61,107.06 53.01,106.67 54.87,106.67 54.92,106.71 54.92,107.86 55.17,108.11 60.38,108.11 60.38,109.74 60.13,109.98 58.96,109.98 57.03,111.91 57.03,111.98 57.03,111.98 57.03,113.07 56.44,113.66 54.17,113.66 52.61,112.09
GND on IN4: 91.17,96.06 99.02,96.06 99.98,95.1 99.98,88.31 99.09,87.41 93.64,87.41 91.97,89.08 91.97,91.8 90.5,93.28 90.5,95.39
GND on GND3: outline of 400 points within 0.2,0.2 300.5,137 ; 1 cut-out
GNDA on TOP (solid shape): 266.53,58.43 266.53,57.8 265.96,57.8 265.96,57.29 266.53,57.29 266.53,56.84 266.22,56.53 264.37,56.53 264.37,58.62 266.34,58.62
GNDA on TOP (solid shape): 252.68,55.36 252.68,54.27 252.83,54.12 253.94,54.12 254.19,54.37 255.61,54.37 255.61,52.15 255.34,51.88 251.12,51.88 251.1,51.89 251.1,53.5 251.05,53.55 251.05,55 251.31,55.26 252.12,55.26 252.27,55.41 252.63,55.41
GNDA on BOTTOM (solid shape): 291.06,41.79 291.06,40.78 290.9,40.63 289.41,40.63 289.25,40.78 289.25,41.92 289.56,42.23 290.63,42.23
GNDA on BOTTOM (solid shape): 285.72,31.25 286.54,31.25 286.61,31.33 286.61,31.79 286.89,32.07 288.14,32.07 288.39,31.81 288.39,31.25 287.83,30.69 283.26,30.69 283.01,30.95 283.01,31.99 283.56,32.55 284.43,32.55
GNDA on GND1, GND2: 283.19,30.43 280.19,33.43 280.19,45.78 281.47,47.06 294.46,47.06 295.43,46.09 295.41,46 295.4,45.9 295.4,43.5 295.54,43.14 295.9,43 299,43 299.21,42.91 299.3,42.7 299.3,40.75 299.21,40.54 299,40.45 286.6,40.45 285.9,39.85 286.4,39.08 286.4,33.62 285.9,32.85 286.6,32.25 299,32.25 299.21,32.16 299.3,31.95 299.3,30.43
GNDA on GND1, GND2: 251.4,49.35 251.11,49.65 251.11,56.43 249.83,57.7 249.83,61.4 251.1,62.67 251.1,63.05 251.17,63.12 254.21,63.12 254.72,62.61 254.72,57.73 258.41,57.73 258.41,56.99 258.34,56.92 258.34,56.76 259.48,55.62 259.48,53.78 259.85,53.41 262.42,53.41 262.79,53.78 262.79,56.41 262.48,56.72 261.28,56.72 261.14,56.86 261.14,58.26 261.02,58.37 260.95,58.37 260.82,58.49 260.81,58.49 259.93,58.49 259.93,59.38 260.9,59.38 261.14,59.15 261.14,59.11 261.25,59 261.69,59 262.14,58.56 262.17,58.56 266.2,58.56 269.33,55.43 269.33,53.43 265.25,49.35
GNDA on VCC: 283.21,30.49 280.19,33.52 280.19,45.07 271.91,53.35 269.53,53.35 269.47,53.41 269.31,53.41 265.25,49.35 251.4,49.35 251.11,49.65 251.11,56.43 249.83,57.7 249.83,61.4 251.1,62.68 251.1,63.05 251.16,63.12 254.22,63.12 254.72,62.62 254.72,57.96 254.93,57.75 258.29,57.75 258.35,57.8 258.41,57.74 258.41,56.74 259.54,55.61 259.54,53.79 259.8,53.53 262.37,53.53 262.68,53.84 262.68,56.37 262.44,56.61 261.24,56.61 261.03,56.82 261.03,58.29 260.82,58.49 259.93,58.49 259.88,58.54 259.88,59.34 259.98,59.44 260.84,59.44 261.17,59.12 261.69,59.12 261.69,59.03 262.17,58.56 266.2,58.56 267.41,57.35 267.56,57.35 267.63,57.41 273.48,57.41 283.89,47 294.43,47 294.54,46.9 294.54,46.51 294.67,46.38 294.61,46.14 294.58,45.9 294.58,43.5 294.97,42.57 295.9,42.18 298.48,42.18 298.48,41.27 286.6,41.27 285.18,40.29 285.58,38.62 285.58,34.08 285.18,32.41 286.6,31.43 298.48,31.43 298.48,30.87 298.37,30.87 297.99,30.49
GNDA on GND3: 283.19,30.43 280.19,33.43 280.19,44.92 271.57,53.54 269.44,53.54 265.25,49.35 251.4,49.35 251.11,49.65 251.11,56.43 249.83,57.7 249.83,61.4 251.1,62.67 251.1,63.05 251.17,63.12 254.21,63.12 254.72,62.61 254.72,57.73 258.41,57.73 258.41,56.99 258.34,56.92 258.34,56.76 259.48,55.62 259.48,53.78 259.85,53.41 262.42,53.41 262.79,53.78 262.79,56.41 262.48,56.72 261.28,56.72 261.14,56.86 261.14,58.26 261.02,58.37 260.95,58.37 260.82,58.49 260.81,58.49 259.93,58.49 259.93,59.38 260.9,59.38 261.14,59.15 261.14,59.11 261.25,59 261.69,59 262.14,58.56 262.17,58.56 266.2,58.56 267.41,57.35 267.56,57.35 267.63,57.41 273.25,57.41 283.66,47 294.52,47 295.43,46.09 295.41,46 295.4,45.9 295.4,43.5 295.54,43.14 295.9,43 299,43 299.21,42.91 299.3,42.7 299.3,40.75 299.21,40.54 299,40.45 286.6,40.45 285.9,39.85 286.4,39.08 286.4,33.62 285.9,32.85 286.6,32.25 299,32.25 299.21,32.16 299.3,31.95 299.3,30.43
VCCSA_B+ on TOP (solid shape): 65.17,113.78 65.02,113.63 63.93,113.63 63.78,113.78 63.78,115.02 65.17,115.02
VCCSA_B+ on BOTTOM (solid shape): 65.64,114.54 68.35,114.54 68.35,114.01 67.73,114.01 67.64,113.92 67.64,112.91 67.38,112.66 64.49,112.66 64.49,113.22 63.96,113.22 63.96,112.66 63.73,112.66 63.73,114.96 63.78,115.01 65.17,115.01
VIN_1.8VALW on TOP (solid shape): 170.82,66.73 170.82,65.65 170,64.83 169.64,64.83 169.04,65.43 169.04,65.82 170.27,67.05 170.5,67.05
VIN_1.8VALW on BOTTOM (solid shape): 170.02,67.89 170.3,68.17 170.61,68.17 171.1,67.68 171.1,66.81 171.85,66.06 171.85,65.7 171.64,65.5 170.9,65.5 170.13,64.73 169.72,64.73 168.13,66.32 168.13,66.65 168.74,67.26 169.36,67.26 169.86,67.76 169.86,67.79 169.49,68.16 169.49,68.17 169.61,68.29 169.62,68.29
VIN_1V_PRIM on TOP (solid shape): 161.22,129.49 161.22,129.17 161.41,128.98 161.93,128.98 161.93,128.96 161.98,128.91 161.98,128.4 161.92,128.34 160.2,128.34 160.08,128.47 160.08,129.49 160.2,129.61 161.09,129.61
VIN_1V_PRIM on BOTTOM (solid shape): 161.19,129.49 161.19,129.11 161.31,128.98 161.95,128.98 162.01,128.92 162.01,128.22 161.89,128.09 161.15,128.09 161.08,128.02 161.08,128.02 161.01,127.95 161.01,127.21 161.01,127.2 161.57,127.2 161.57,127.2 161.57,127.02 161.01,127.02 161.01,127.02 161.01,126.48 160.35,125.82 160.35,124.93 160.2,124.78 158.75,124.78 158.58,124.94 158.58,128.53 158.71,128.66 159.6,128.66 159.92,128.98 159.92,129.49 160.04,129.61 161.06,129.61
VIN_1VS_VCCIO on TOP (solid shape): 145.25,131.01 145.25,130.69 145.25,130.69 145.25,130.63 145.4,130.48 145.99,130.48 146.07,130.4 146.07,129.82 145.99,129.74 144.29,129.74 144.17,129.86 144.17,130.95 144.3,131.07 145.18,131.07
VIN_1VS_VCCIO on BOTTOM (solid shape): 145.31,130.95 145.31,130.63 145.44,130.5 146.01,130.5 146.07,130.44 146.07,129.74 145.95,129.61 145.22,129.61 144.99,129.38 144.99,128.65 145.01,128.63 145.54,128.63 145.54,128.63 145.54,128.45 145.54,128.44 145,128.44 144.99,128.43 144.99,127.93 144.94,127.84 144.84,127.84 144.33,127.58 144.74,127.17 144.82,127.15 144.85,127.07 144.85,126.35 144.81,126.31 143.49,126.31 143.21,126.59 143.21,127.92 142.71,128.42 142.71,130.06 142.71,130.09 142.8,130.19 143.72,130.19 144.04,130.5 144.04,130.95 144.17,131.07 145.18,131.07
+AC_IN on TOP (solid shape): 48.89,105.5 48.89,103.8 48.77,103.67 48.18,103.67 47.47,102.96 45.46,102.96 45.44,102.98 45.44,103.44 45.3,103.58 45.3,105.04 45.31,105.05 45.31,105.34 45.62,105.65 48.74,105.65
+AC_IN on TOP (solid shape): outline of 226 points within 29.57,112.72 42.02,120.6
+AC_IN on IN2: 36.23,114.56 34.31,114.56 33.3,115.58 32.28,115.58 32.09,115.77 32.09,117.68 32.41,117.99 37.55,117.99 39.9,115.64 41.62,115.64 41.81,115.45 41.81,113.42 41.62,113.23 37.56,113.23
+AC_IN on VCC: 41.79,103.26 41.3,103.75 41.3,110.4 39.14,112.56 39.14,114.97 39.25,115.07 45.51,115.07 48.03,112.55 48.03,103.26
+BL_PWR_SRC on TOP (solid shape): 47.59,128.09 47.59,127.39 46.51,126.31 46.51,122.12 46.38,121.99 45.11,121.99 44.98,122.12 44.98,125.74 45.14,125.9 45.14,127.11 46.51,128.47 47.2,128.47
